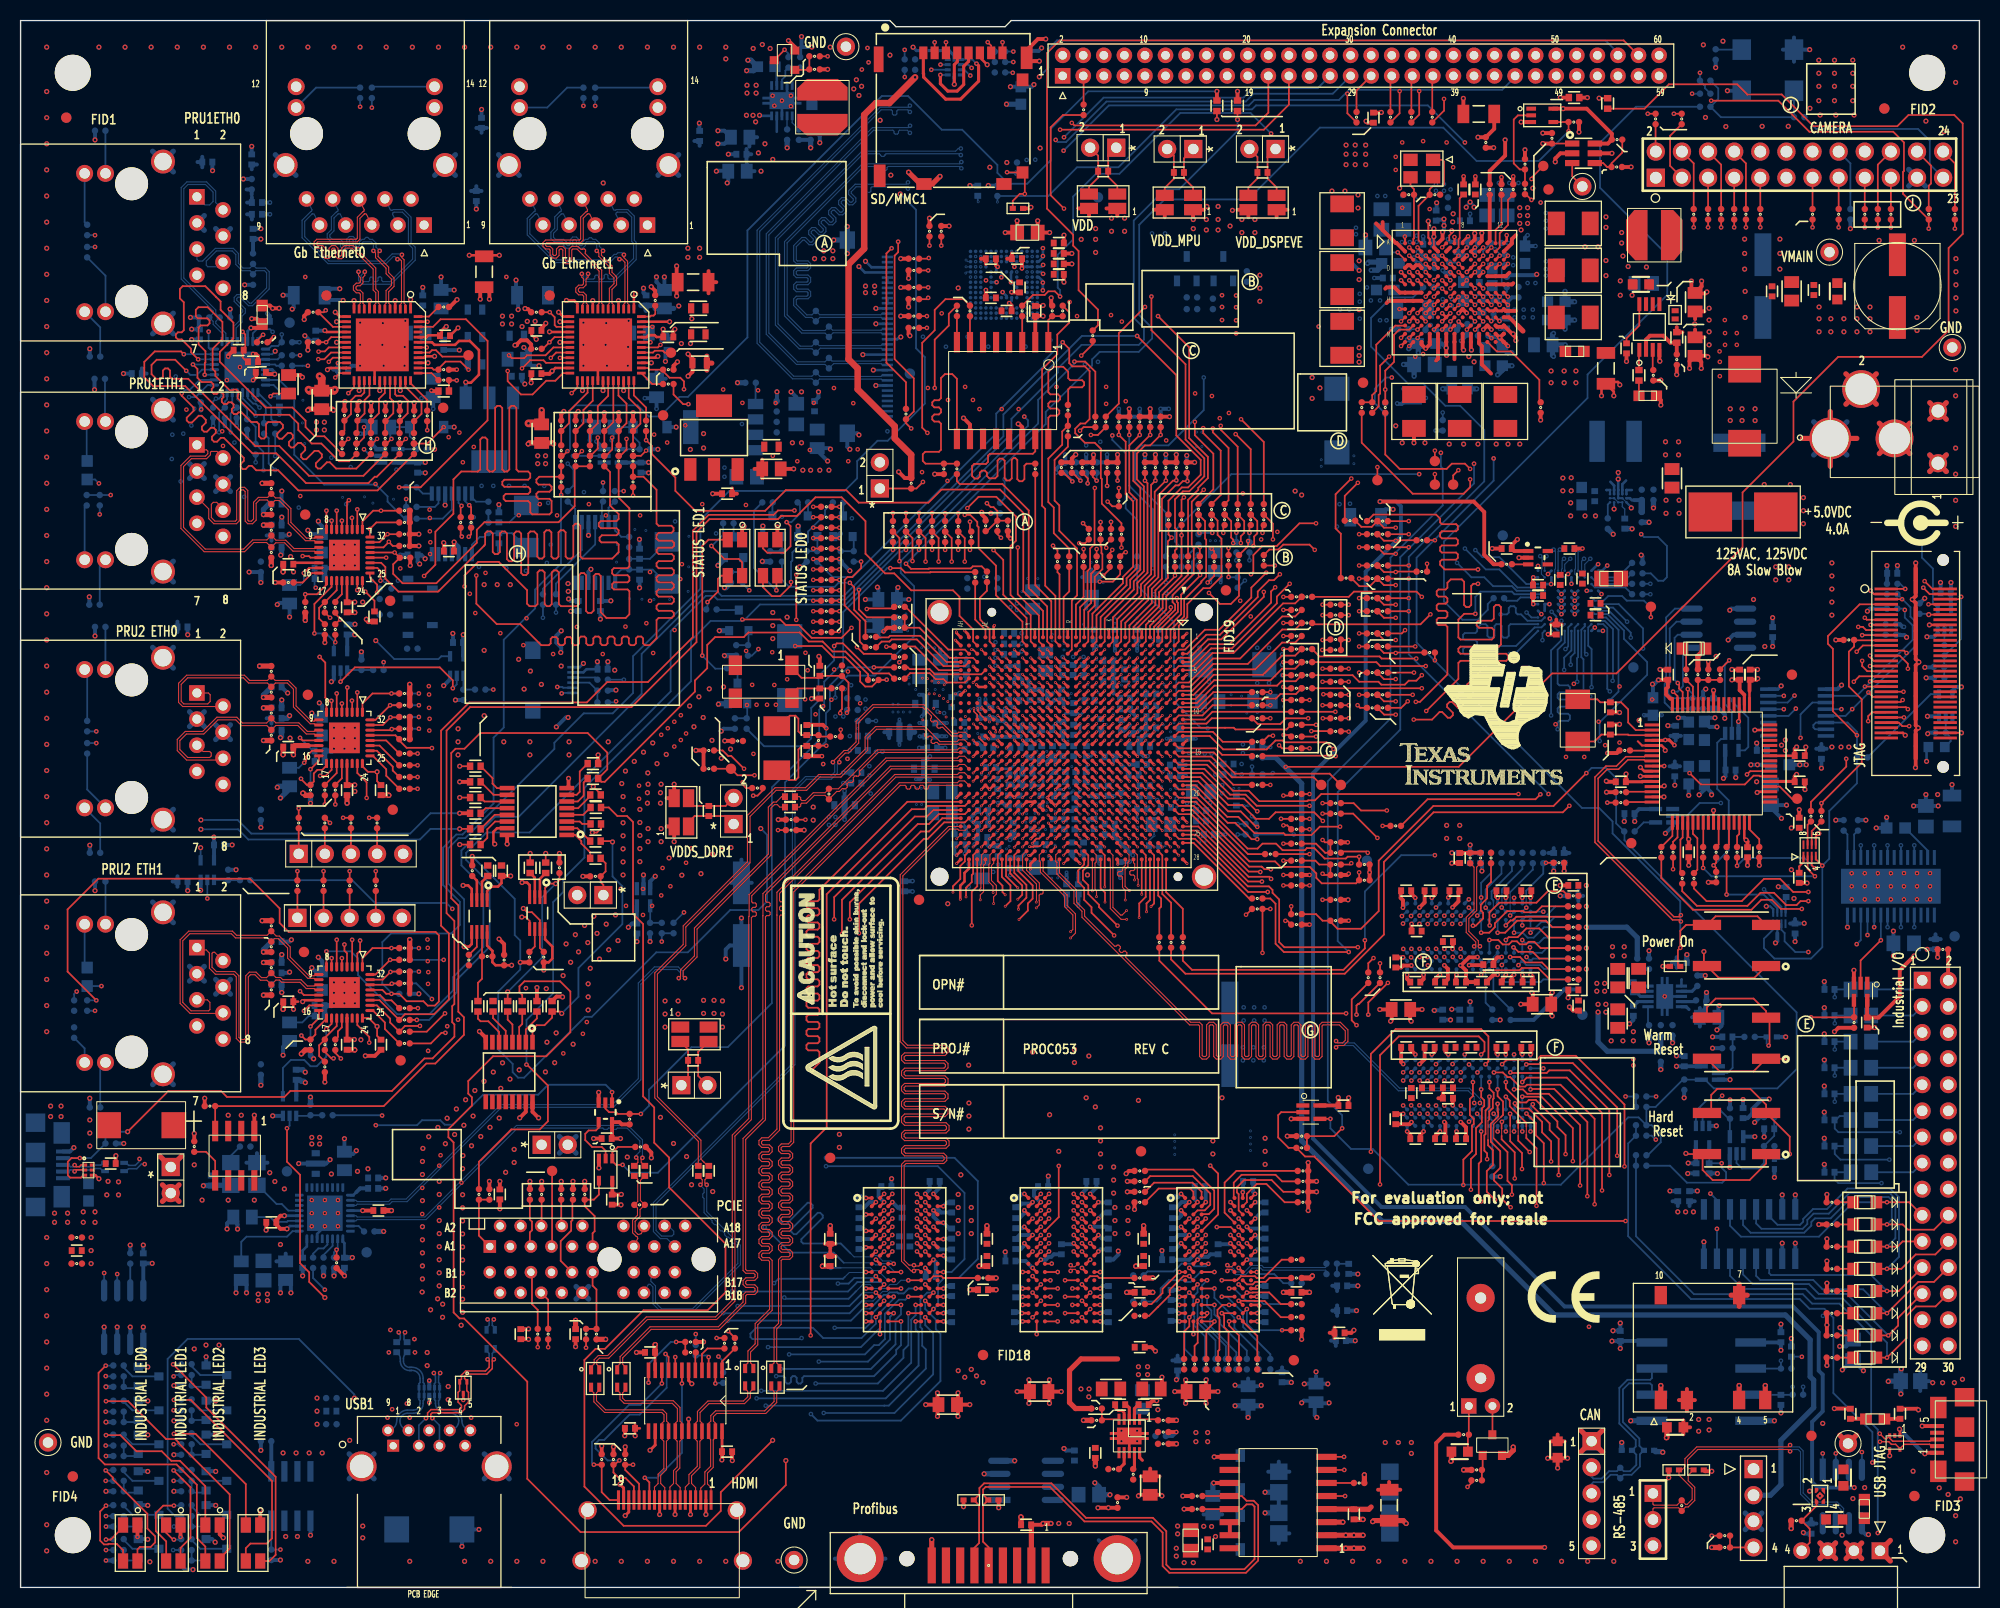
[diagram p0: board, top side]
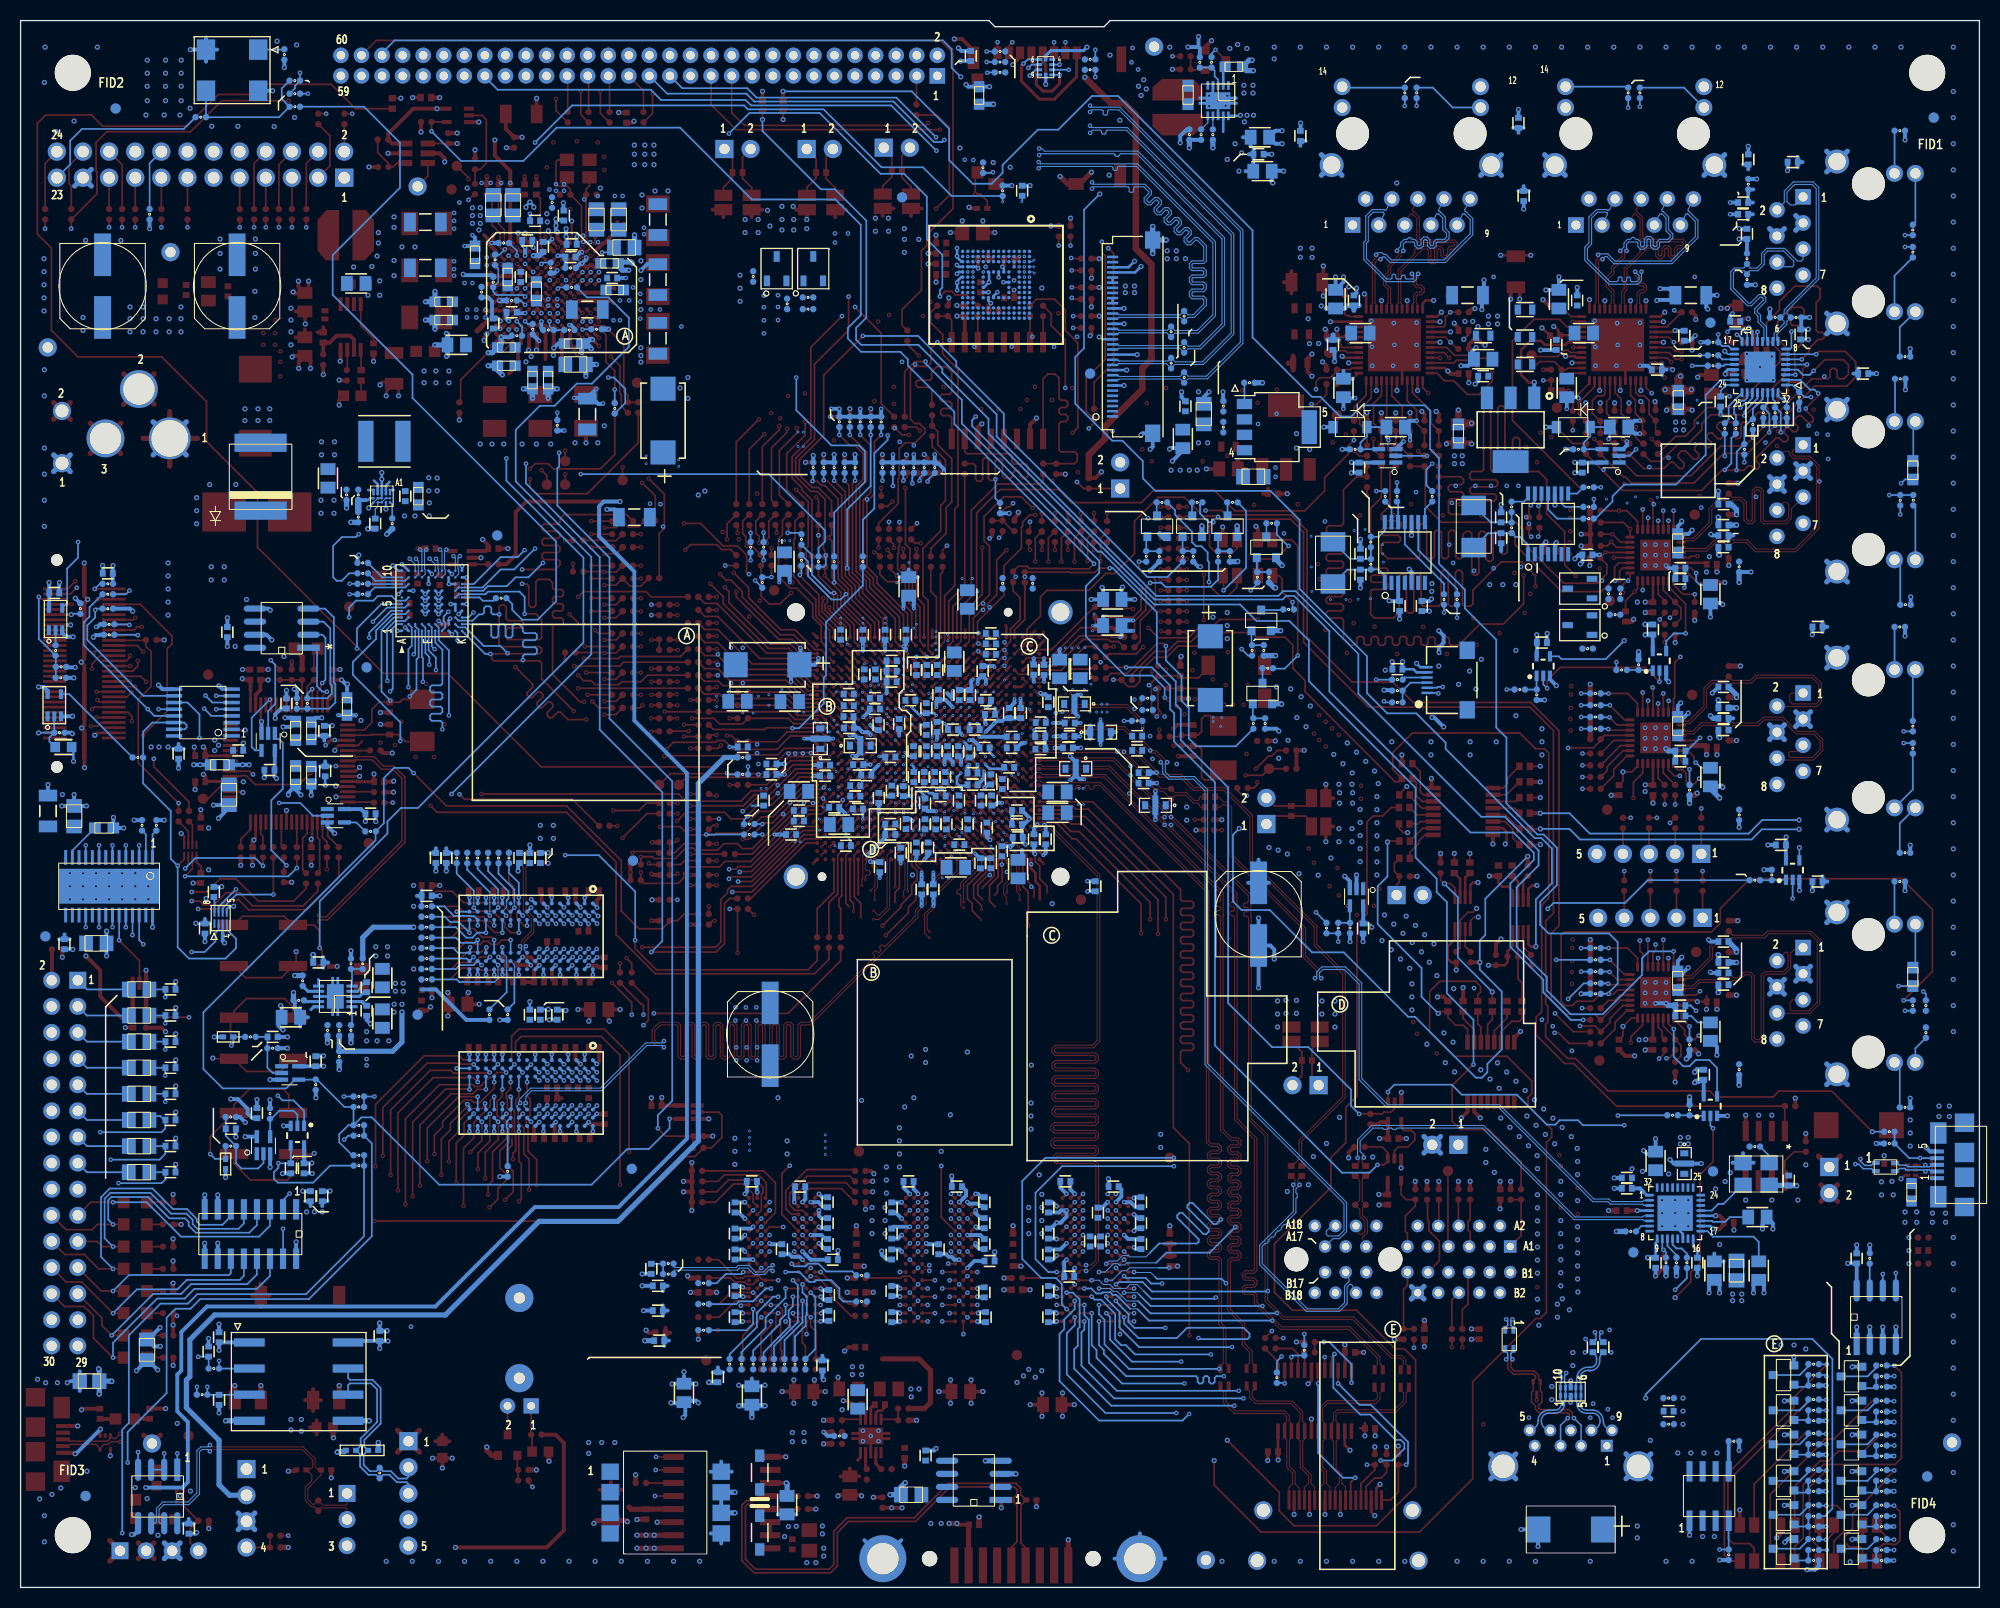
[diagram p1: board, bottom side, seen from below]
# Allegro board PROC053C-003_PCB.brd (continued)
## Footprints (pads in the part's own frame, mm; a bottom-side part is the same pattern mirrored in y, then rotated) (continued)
BGA153N50P14X14_1150X1300X140
  round 0.35 smd: A1(-3.25,3.25) A2(-2.75,3.25) A3(-2.25,3.25) A4(-1.75,3.25) A5(-1.25,3.25) A6(-0.75,3.25) A7(-0.25,3.25) A8(0.25,3.25) A9(0.75,3.25) A10(1.25,3.25) A11(1.75,3.25) A12(2.25,3.25) A13(2.75,3.25) A14(3.25,3.25) B1(-3.25,2.75) B2(-2.75,2.75) B3(-2.25,2.75) B4(-1.75,2.75) B5(-1.25,2.75) B6(-0.75,2.75) B7(-0.25,2.75) B8(0.25,2.75) B9(0.75,2.75) B10(1.25,2.75) B11(1.75,2.75) B12(2.25,2.75) B13(2.75,2.75) B14(3.25,2.75) C1(-3.25,2.25) C2(-2.75,2.25) C3(-2.25,2.25) C4(-1.75,2.25) C5(-1.25,2.25) C6(-0.75,2.25) C7(-0.25,2.25) C8(0.25,2.25) C9(0.75,2.25) C10(1.25,2.25) C11(1.75,2.25) C12(2.25,2.25) C13(2.75,2.25) C14(3.25,2.25) D1(-3.25,1.75) D2(-2.75,1.75) D3(-2.25,1.75) D4(-1.75,1.75) D12(2.25,1.75) D13(2.75,1.75) D14(3.25,1.75) E1(-3.25,1.25) E2(-2.75,1.25) E3(-2.25,1.25) E5(-1.25,1.25) E6(-0.75,1.25) E7(-0.25,1.25) E8(0.25,1.25) E9(0.75,1.25) E10(1.25,1.25) E12(2.25,1.25) E13(2.75,1.25) E14(3.25,1.25) F1(-3.25,0.75) F2(-2.75,0.75) F3(-2.25,0.75) F5(-1.25,0.75) F10(1.25,0.75) F12(2.25,0.75) F13(2.75,0.75) F14(3.25,0.75) G1(-3.25,0.25) G2(-2.75,0.25) G3(-2.25,0.25) G5(-1.25,0.25) G10(1.25,0.25) G12(2.25,0.25) G13(2.75,0.25) G14(3.25,0.25) H1(-3.25,-0.25) H2(-2.75,-0.25) H3(-2.25,-0.25) H5(-1.25,-0.25) H10(1.25,-0.25) H12(2.25,-0.25) H13(2.75,-0.25) H14(3.25,-0.25) J1(-3.25,-0.75) J2(-2.75,-0.75) J3(-2.25,-0.75) J5(-1.25,-0.75) J10(1.25,-0.75) J12(2.25,-0.75) J13(2.75,-0.75) J14(3.25,-0.75) K1(-3.25,-1.25) K2(-2.75,-1.25) K3(-2.25,-1.25) K5(-1.25,-1.25) K6(-0.75,-1.25) K7(-0.25,-1.25) K8(0.25,-1.25) K9(0.75,-1.25) K10(1.25,-1.25) K12(2.25,-1.25) K13(2.75,-1.25) K14(3.25,-1.25) L1(-3.25,-1.75) L2(-2.75,-1.75) L3(-2.25,-1.75) L12(2.25,-1.75) L13(2.75,-1.75) L14(3.25,-1.75) M1(-3.25,-2.25) M2(-2.75,-2.25) M3(-2.25,-2.25) M4(-1.75,-2.25) M5(-1.25,-2.25) M6(-0.75,-2.25) M7(-0.25,-2.25) M8(0.25,-2.25) M9(0.75,-2.25) M10(1.25,-2.25) M11(1.75,-2.25) M12(2.25,-2.25) M13(2.75,-2.25) M14(3.25,-2.25) N1(-3.25,-2.75) N2(-2.75,-2.75) N3(-2.25,-2.75) N4(-1.75,-2.75) N5(-1.25,-2.75) N6(-0.75,-2.75) N7(-0.25,-2.75) N8(0.25,-2.75) N9(0.75,-2.75) N10(1.25,-2.75) N11(1.75,-2.75) N12(2.25,-2.75) N13(2.75,-2.75) N14(3.25,-2.75) P1(-3.25,-3.25) P2(-2.75,-3.25) P3(-2.25,-3.25) P4(-1.75,-3.25) P5(-1.25,-3.25) P6(-0.75,-3.25) P7(-0.25,-3.25) P8(0.25,-3.25) P9(0.75,-3.25) P10(1.25,-3.25) P11(1.75,-3.25) P12(2.25,-3.25) P13(2.75,-3.25) P14(3.25,-3.25)
CC0402
  rect 0.58x0.66 smd: 1(-0.49,0) 2(0.49,0)
CC0603
  rect 0.95x1 smd: 1(-0.8,0) 2(0.8,0)
CC0805
  rect 1.15x1.45 smd: 1(-0.9,0) 2(0.9,0)
CC1206
  rect 1.15x1.8 smd: 1(-1.5,0) 2(1.5,0)
CN_10018783-11000TLF
  round 2.35 hole 2.35 unplated: (11.65,-1.25) (20.8,-1.25)
  rect 1.228x1.228 hole 0.72: A1(0,0)
  round 1.228 hole 0.72: A2(1,2) A3(2,0) A4(3,2) A5(4,0) A6(5,2) A7(6,0) A8(7,2) A9(8,0) A10(9,2) A11(10,0) A12(13,2) A13(14,0) A14(15,2) A15(16,0) A16(17,2) A17(18,0) A18(19,2) B1(0,-2.5) B2(1,-4.5) B3(2,-2.5) B4(3,-4.5) B5(4,-2.5) B6(5,-4.5) B7(6,-2.5) B8(7,-4.5) B9(8,-2.5) B10(9,-4.5) B11(10,-2.5) B12(13,-4.5) B13(14,-2.5) B14(15,-4.5) B15(16,-2.5) B16(17,-4.5) B17(18,-2.5) B18(19,-4.5)
CN_LPAF3102NL
  rect 1.168x1.168 hole 0.711: 1(0,0)
  round 1.168 hole 0.711: 2(2.5,0) 3(4.5,0) 4(7,0) 5(7.5,1.5) 6(5.5,1.5) 7(3.5,1.5) 8(1.5,1.5) 9(-0.5,1.5)
  round 2.921 hole 2.286: S1(-3.07,-2) S2(10.07,-2)
CNQSH030DA
  round 1.143 hole 1.143 unplated: (-10.065,2.67) (10.065,2.67)
  rect 0.279x2.286 smd: 1(-7.25,-2.865) 2(-7.25,2.865) 3(-6.75,-2.865) 4(-6.75,2.865) 5(-6.25,-2.865) 6(-6.25,2.865) 7(-5.75,-2.865) 8(-5.75,2.865) 9(-5.25,-2.865) 10(-5.25,2.865) 11(-4.75,-2.865) 12(-4.75,2.865) 13(-4.25,-2.865) 14(-4.25,2.865) 15(-3.75,-2.865) 16(-3.75,2.865) 17(-3.25,-2.865) 18(-3.25,2.865) 19(-2.75,-2.865) 20(-2.75,2.865) 21(-2.25,-2.865) 22(-2.25,2.865) 23(-1.75,-2.865) 24(-1.75,2.865) 25(-1.25,-2.865) 26(-1.25,2.865) 27(-0.75,-2.865) 28(-0.75,2.865) 29(-0.25,-2.865) 30(-0.25,2.865) 31(0.25,-2.865) 32(0.25,2.865) 33(0.75,-2.865) 34(0.75,2.865) 35(1.25,-2.865) 36(1.25,2.865) 37(1.75,-2.865) 38(1.75,2.865) 39(2.25,-2.865) 40(2.25,2.865) 41(2.75,-2.865) 42(2.75,2.865) 43(3.25,-2.865) 44(3.25,2.865) 45(3.75,-2.865) 46(3.75,2.865) 47(4.25,-2.865) 48(4.25,2.865) 49(4.75,-2.865) 50(4.75,2.865) 51(5.25,-2.865) 52(5.25,2.865) 53(5.75,-2.865) 54(5.75,2.865) 55(6.25,-2.865) 56(6.25,2.865) 57(6.75,-2.865) 58(6.75,2.865) 59(7.25,-2.865) 60(7.25,2.865)
  rect 2.54x0.432 smd: 61(-8.065,0) 64(8.065,0)
  rect 4.699x0.432 smd: 62(-3.175,0) 63(3.175,0)
CNRJ45-1X1WLED
  round 3.2 hole 3.2 unplated: (-1.27,-6.35) (10.16,-6.35)
  rect 1.525x1.525 hole 0.89: 1(0,0)
  round 1.525 hole 0.89: 2(1.27,2.54) 3(2.54,0) 4(3.81,2.54) 5(5.08,0) 6(6.35,2.54) 7(7.62,0) 8(8.89,2.54)
  round 1.655 hole 1.02: 9(11.17,-8.89) 10(11.17,-10.92) 11(-2.28,-8.89) 12(-2.28,-10.92)
  round 2.337 hole 1.702: SHLD1(-3.43,-3.3) SHLD2(12.32,-3.3)
CNRJ45-1X1WLED-598M
  round 3.2 hole 3.2 unplated: (0,-8.89) (11.43,-8.89)
  rect 1.525x1.525 hole 0.89: 1(0,0)
  round 1.525 hole 0.89: 2(1.27,-2.54) 3(2.54,0) 4(3.81,-2.54) 5(5.08,0) 6(6.35,-2.54) 7(7.62,0) 8(8.89,-2.54) 9(10.16,0) 10(11.43,-2.54)
  round 1.655 hole 1.02: 11(12.44,-11.43) 12(12.44,-13.46) 13(-1.01,-11.43) 14(-1.01,-13.46)
  round 2.337 hole 1.702: SHLD1(-2.035,-5.84) SHLD2(13.465,-5.84)
CNXF2M-3215-1A
  rect 0.254x1.092 smd: 1(-7.75,1.95) 2(-7.25,1.95) 3(-6.75,1.95) 4(-6.25,1.95) 5(-5.75,1.95) 6(-5.25,1.95) 7(-4.75,1.95) 8(-4.25,1.95) 9(-3.75,1.95) 10(-3.25,1.95) 11(-2.75,1.95) 12(-2.25,1.95) 13(-1.75,1.95) 14(-1.25,1.95) 15(-0.75,1.95) 16(-0.25,1.95) 17(0.25,1.95) 18(0.75,1.95) 19(1.25,1.95) 20(1.75,1.95) 21(2.25,1.95) 22(2.75,1.95) 23(3.25,1.95) 24(3.75,1.95) 25(4.25,1.95) 26(4.75,1.95) 27(5.25,1.95) 28(5.75,1.95) 29(6.25,1.95) 30(6.75,1.95) 31(7.25,1.95) 32(7.75,1.95)
  rect 1.7x1.5 smd: MNT1(-9.4,-1.95) MNT2(9.4,-1.95)
CONN_OSTTC02
  round 1.778 hole 1.27: 1(0,0) 2(5.08,0)
CT7343-31
  rect 2.35x2.45 smd: 1(-3.1,0) 2(3.1,0)
DA2304
  rect 1.7x1.6 smd: 1(-5.4,3) 2(-5.4,1) 3(-5.4,-1) 4(-5.4,-3) 5(5.4,-3) 6(5.4,-1) 7(5.4,1) 8(5.4,3)
DFN1006D-2
  rect 0.5x0.7 smd: 1(-0.4,0) 2(0.4,0)
DIO_SOD-123
  rect 1.22x0.91 smd: 1(-1.64,0) 2(1.64,0)
DRCPSO_10PIN
  rect 0.305x1.092 smd: 1(-1,-1.625) 2(-0.5,-1.625) 3(0,-1.625) 4(0.5,-1.625) 5(1,-1.625) 6(1,1.625) 7(0.5,1.625) 8(0,1.625) 9(-0.5,1.625) 10(-1,1.625)
  custom 0.412x0.412 smd: 11(0,0)
FB0603
  rect 0.61x0.991 smd: 1(-0.7,0) 2(0.7,0)
FILT-DLW21S
  rect 0.9x0.4 smd: 1(-0.85,-0.4) 2(0.85,-0.4) 3(0.85,0.4) 4(-0.85,0.4)
FILT-NFM21PC
  rect 0.6x0.8 smd: 1(-1,0) 3(1,0)
  rect 0.6x1.9 smd: 2(0,0)
FUSE-0154
  rect 4.242x3.81 smd: 1(-3.188,0) 2(3.188,0)
HDR1X4-330M
  rect 1.778x1.778 hole 1.143: 1(0,0)
  round 1.778 hole 1.143: 2(0,-2.54) 3(0,-5.08) 4(0,-7.62)
HDR2X12
  rect 1.785x1.785 hole 1.15: 1(0,0)
  round 1.785 hole 1.15: 2(2.54,0) 3(0,-2.54) 4(2.54,-2.54) 5(0,-5.08) 6(2.54,-5.08) 7(0,-7.62) 8(2.54,-7.62) 9(0,-10.16) 10(2.54,-10.16) 11(0,-12.7) 12(2.54,-12.7) 13(0,-15.24) 14(2.54,-15.24) 15(0,-17.78) 16(2.54,-17.78) 17(0,-20.32) 18(2.54,-20.32) 19(0,-22.86) 20(2.54,-22.86) 21(0,-25.4) 22(2.54,-25.4) 23(0,-27.94) 24(2.54,-27.94)
HDR2X15-344M
  rect 1.655x1.655 hole 1.02: 1(0,0)
  round 1.655 hole 1.02: 2(0,2.54) 3(2.54,0) 4(2.54,2.54) 5(5.08,0) 6(5.08,2.54) 7(7.62,0) 8(7.62,2.54) 9(10.16,0) 10(10.16,2.54) 11(12.7,0) 12(12.7,2.54) 13(15.24,0) 14(15.24,2.54) 15(17.78,0) 16(17.78,2.54) 17(20.32,0) 18(20.32,2.54) 19(22.86,0) 20(22.86,2.54) 21(25.4,0) 22(25.4,2.54) 23(27.94,0) 24(27.94,2.54) 25(30.48,0) 26(30.48,2.54) 27(33.02,0) 28(33.02,2.54) 29(35.56,0) 30(35.56,2.54)
HDR2X30-2MM-177M
  rect 1.524x1.524 hole 0.838: 1(0,0)
  round 1.524 hole 0.838: 2(0,2) 3(2,0) 4(2,2) 5(4,0) 6(4,2) 7(6,0) 8(6,2) 9(8,0) 10(8,2) 11(10,0) 12(10,2) 13(12,0) 14(12,2) 15(14,0) 16(14,2) 17(16,0) 18(16,2) 19(18,0) 20(18,2) 21(20,0) 22(20,2) 23(22,0) 24(22,2) 25(24,0) 26(24,2) 27(26,0) 28(26,2) 29(28,0) 30(28,2) 31(30,0) 32(30,2) 33(32,0) 34(32,2) 35(34,0) 36(34,2) 37(36,0) 38(36,2) 39(38,0) 40(38,2) 41(40,0) 42(40,2) 43(42,0) 44(42,2) 45(44,0) 46(44,2) 47(46,0) 48(46,2) 49(48,0) 50(48,2) 51(50,0) 52(50,2) 53(52,0) 54(52,2) 55(54,0) 56(54,2) 57(56,0) 58(56,2) 59(58,0) 60(58,2)
HDR4X1RA-108M
  rect 1.651x1.651 hole 1.016: 1(0,0)
  round 1.651 hole 1.016: 2(0,-2.54) 3(0,-5.08) 4(0,-7.62)
HEADER_2X1
  rect 1.778x1.778 hole 1.016: 1(0,0)
  round 1.778 hole 1.016: 2(0,2.54)
HEADER_3X1
  rect 1.651x1.651 hole 1.016: 1(0,0)
  round 1.651 hole 1.016: 2(2.54,0) 3(5.08,0)
HEADER_5X1
  rect 1.778x1.778 hole 1.016: 1(0,0)
  round 1.778 hole 1.016: 2(2.54,0) 3(5.08,0) 4(7.62,0) 5(10.16,0)
IND_IHLP1616AB
  rect 1.65x2.3 smd: 1(-1.65,0) 2(1.65,0)
IND_SRN5040
  rect 1.5x4 smd: 1(-1.8,0) 2(1.8,0)
LED-SM1210
  rect 1.5x1 smd: 1(-1.75,0.7) 2(-1.75,-0.7) 3(1.75,0.7) 4(1.75,-0.7)
LQFP64PIN
  rect 1.5x0.3 smd: 1(-5.7,3.75) 2(-5.7,3.25) 3(-5.7,2.75) 4(-5.7,2.25) 5(-5.7,1.75) 6(-5.7,1.25) 7(-5.7,0.75) 8(-5.7,0.25) 9(-5.7,-0.25) 10(-5.7,-0.75) 11(-5.7,-1.25) 12(-5.7,-1.75) 13(-5.7,-2.25) 14(-5.7,-2.75) 15(-5.7,-3.25) 16(-5.7,-3.75) 33(5.7,-3.75) 34(5.7,-3.25) 35(5.7,-2.75) 36(5.7,-2.25) 37(5.7,-1.75) 38(5.7,-1.25) 39(5.7,-0.75) 40(5.7,-0.25) 41(5.7,0.25) 42(5.7,0.75) 43(5.7,1.25) 44(5.7,1.75) 45(5.7,2.25) 46(5.7,2.75) 47(5.7,3.25) 48(5.7,3.75)
  rect 0.3x1.5 smd: 17(-3.75,-5.7) 18(-3.25,-5.7) 19(-2.75,-5.7) 20(-2.25,-5.7) 21(-1.75,-5.7) 22(-1.25,-5.7) 23(-0.75,-5.7) 24(-0.25,-5.7) 25(0.25,-5.7) 26(0.75,-5.7) 27(1.25,-5.7) 28(1.75,-5.7) 29(2.25,-5.7) 30(2.75,-5.7) 31(3.25,-5.7) 32(3.75,-5.7) 49(3.75,5.7) 50(3.25,5.7) 51(2.75,5.7) 52(2.25,5.7) 53(1.75,5.7) 54(1.25,5.7) 55(0.75,5.7) 56(0.25,5.7) 57(-0.25,5.7) 58(-0.75,5.7) 59(-1.25,5.7) 60(-1.75,5.7) 61(-2.25,5.7) 62(-2.75,5.7) 63(-3.25,5.7) 64(-3.75,5.7)
MC-306
  rect 1.3x1.9 smd: 1(-2.75,-1.6) 2(2.75,-1.6) 3(2.75,1.6) 4(-2.75,1.6)
MOLEX_5031821852
  rect 0.8x1.24 smd: 1(-2.9,5.605) 2(-1.8,5.605) 3(-0.7,5.605) 4(0.4,5.605) 5(1.5,5.605) 6(2.6,5.605) 7(3.7,5.605) 8(4.8,5.605)
  rect 1.16x1.2 smd: DT(6.75,-6.025)
  rect 0.95x2.5 smd: G1(-7.245,4.975)
  rect 1.15x2.2 smd: G2(-7.145,-6.355) G5(7.145,5.125)
  rect 1.5x1.15 smd: G3(-2.84,-7.15) G4(4.94,-7.15)
  rect 1.16x1.25 smd: SW(6.75,2.975)
MSOP3X3-8-43M
  rect 1.35x0.4 smd: 1(-2.225,0.975) 2(-2.225,0.325) 3(-2.225,-0.325) 4(-2.225,-0.975) 5(2.225,-0.975) 6(2.225,-0.325) 7(2.225,0.325) 8(2.225,0.975)
NORCOMP_DB9F_SMD
  round 1.499 hole 1.499 unplated: (-7.95,-0.66) (7.95,-0.66)
  rect 0.8x3.5 smd: 1(-5.537,0) 2(-2.769,0) 3(0,0) 4(2.769,0) 5(5.537,0) 6(-4.153,0) 7(-1.384,0) 8(1.384,0) 9(4.153,0)
  round 4.572 hole 3.048: 10(-12.497,-0.66) 11(12.497,-0.66)
OMRON_XF2M-0615-1A
  rect 0.25x1.1 smd: 1(-1.25,1.84) 2(-0.75,1.84) 3(-0.25,1.84) 4(0.25,1.84) 5(0.75,1.84) 6(1.25,1.84)
  rect 1.7x1.5 smd: G1(-2.9,-2.059) G2(2.9,-2.059)
OSC7X5-71M
  rect 1.8x2 smd: 1(-2.54,-2) 2(2.54,-2) 3(2.54,2) 4(-2.54,2)
PICO_304-100
  rect 1.5x1.5 hole 0.762: 1(0,0)
  round 1.5 hole 0.762: 2(-2.3,0)
  round 2.75 hole 1.092: M1(-1.15,-2.7) M2(-1.15,-10.5)
PW_24PIN_TSSOP
  rect 0.356x1.524 smd: 1(-3.575,-2.96) 2(-2.925,-2.96) 3(-2.275,-2.96) 4(-1.625,-2.96) 5(-0.975,-2.96) 6(-0.325,-2.96) 7(0.325,-2.96) 8(0.975,-2.96) 9(1.625,-2.96) 10(2.275,-2.96) 11(2.925,-2.96) 12(3.575,-2.96) 13(3.575,2.96) 14(2.925,2.96) 15(2.275,2.96) 16(1.625,2.96) 17(0.975,2.96) 18(0.325,2.96) 19(-0.325,2.96) 20(-0.975,2.96) 21(-1.625,2.96) 22(-2.275,2.96) 23(-2.925,2.96) 24(-3.575,2.96)
QFN5X5-32-39M
  custom 0.075x0.075 smd: 1(-2.475,1.75) 2(-2.475,1.25) 3(-2.475,0.75) 4(-2.475,0.25) 5(-2.475,-0.25) 6(-2.475,-0.75) 7(-2.475,-1.25) 8(-2.475,-1.75) 9(-1.75,-2.475) 10(-1.25,-2.475) 11(-0.75,-2.475) 12(-0.25,-2.475) 13(0.25,-2.475) 14(0.75,-2.475) 15(1.25,-2.475) 16(1.75,-2.475) 17(2.475,-1.75) 18(2.475,-1.25) 19(2.475,-0.75) 20(2.475,-0.25) 21(2.475,0.25) 22(2.475,0.75) 23(2.475,1.25) 24(2.475,1.75) 25(1.75,2.475) 26(1.25,2.475) 27(0.75,2.475) 28(0.25,2.475) 29(-0.25,2.475) 30(-0.75,2.475) 31(-1.25,2.475) 32(-1.75,2.475)
  rect 3x3 smd: TPAD(0,0)
QFN5X5-32TI-39M
  custom 0.07x0.07 smd: 1(-2.475,1.75) 2(-2.475,1.25) 3(-2.475,0.75) 4(-2.475,0.25) 5(-2.475,-0.25) 6(-2.475,-0.75) 7(-2.475,-1.25) 8(-2.475,-1.75) 9(-1.75,-2.475) 10(-1.25,-2.475) 11(-0.75,-2.475) 12(-0.25,-2.475) 13(0.25,-2.475) 14(0.75,-2.475) 15(1.25,-2.475) 16(1.75,-2.475) 17(2.475,-1.75) 18(2.475,-1.25) 19(2.475,-0.75) 20(2.475,-0.25) 21(2.475,0.25) 22(2.475,0.75) 23(2.475,1.25) 24(2.475,1.75) 25(1.75,2.475) 26(1.25,2.475) 27(0.75,2.475) 28(0.25,2.475) 29(-0.25,2.475) 30(-0.75,2.475) 31(-1.25,2.475) 32(-1.75,2.475)
  rect 3.45x3.45 smd: TPAD(0,0)
QFN7X7-48
  rect 0.85x0.28 smd: 1(-3.475,2.75) 2(-3.475,2.25) 3(-3.475,1.75) 4(-3.475,1.25) 5(-3.475,0.75) 6(-3.475,0.25) 7(-3.475,-0.25) 8(-3.475,-0.75) 9(-3.475,-1.25) 10(-3.475,-1.75) 11(-3.475,-2.25) 12(-3.475,-2.75) 25(3.475,-2.75) 26(3.475,-2.25) 27(3.475,-1.75) 28(3.475,-1.25) 29(3.475,-0.75) 30(3.475,-0.25) 31(3.475,0.25) 32(3.475,0.75) 33(3.475,1.25) 34(3.475,1.75) 35(3.475,2.25) 36(3.475,2.75)
  rect 0.28x0.85 smd: 13(-2.75,-3.475) 14(-2.25,-3.475) 15(-1.75,-3.475) 16(-1.25,-3.475) 17(-0.75,-3.475) 18(-0.25,-3.475) 19(0.25,-3.475) 20(0.75,-3.475) 21(1.25,-3.475) 22(1.75,-3.475) 23(2.25,-3.475) 24(2.75,-3.475) 37(2.75,3.475) 38(2.25,3.475) 39(1.75,3.475) 40(1.25,3.475) 41(0.75,3.475) 42(0.25,3.475) 43(-0.25,3.475) 44(-0.75,3.475) 45(-1.25,3.475) 46(-1.75,3.475) 47(-2.25,3.475) 48(-2.75,3.475)
  rect 5.15x5.15 smd: 49(0,0)
RAPC712
  round 4.064 hole 3.556: 1(0,0)
  round 3.683 hole 3.048: 2(-2.997,-4.801) 3(-6.248,0)
RC0402
  rect 0.63x0.73 smd: 1(-0.51,0) 2(0.51,0)
SC70-5-43M
  rect 0.95x0.4 smd: 1(-1.075,0.65) 2(-1.075,0) 3(-1.075,-0.65) 4(1.075,-0.65) 5(1.075,0.65)
SCK-SG-BGA-6334
  round 1.75 hole 1.75 unplated: (-12.863,12.863) (12.863,-12.863)
  round 0.85 hole 0.85 unplated: (-12.863,-7.783) (12.863,10.323)
  round 2.385 hole 1.75: MCH2(12.863,12.863) MCH4(-12.863,-12.863)
SK1545
  rect 1.778x5.08 smd: 1(-3.302,0) 2(3.302,0)
SM-7351-CAP-0402
  round 0.635 smd: 1(-0.508,0) 2(0.508,0)
SM-7351-CAP-0603
  rect 1.092x1.041 smd: 1(-0.85,0) 2(0.85,0)
SM-7351-CAP-0805
  rect 1.346x1.524 smd: 1(-1,0) 2(1,0)
SM-7351-CAP-2917
  rect 2.413x2.54 smd: 1(3.175,0) 2(-3.175,0)
SM-7351-CAP-SMDCAN
  rect 4.15x1.65 smd: 1(3.05,0) 2(-3.05,0)
SM-7351-IND-0603
  rect 1.143x1.092 smd: 1(-0.9,0) 2(0.9,0)
SM-7351-IND-0805
  rect 1.397x1.549 smd: 1(-0.95,0) 2(0.95,0)
SM-7351-RES-0402
  round 0.635 smd: 1(-0.508,0) 2(0.508,0)
SM-7351-RES-0603
  rect 1.143x1.092 smd: 1(-0.9,0) 2(0.9,0)
SM-SO-SC70-5
  rect 0.406x1.016 smd: 1(-0.65,-0.95) 2(0,-0.95) 3(0.65,-0.95) 4(0.65,0.95) 5(-0.65,0.95)
SM_LED_0805
  rect 1.15x1.194 smd: 1(1.125,0) 2(-1.125,0)
SM_OSC_ABM3
  rect 1.9x2.4 smd: 1(-2.05,0) 2(2.05,0)
SM_RES_LVK12
  rect 1.75x1.1 smd: 1(-1.375,0.7) 2(1.375,0.7) 3(-1.375,-0.7) 4(1.375,-0.7)
SMCJ26CA
  rect 2.6x3.2 smd: 1(-3.6,0) 2(3.6,0)
SMD15X11-6-374M
  rect 1.2x1.8 smd: 1(-5.08,-5.1) 2(-2.54,-5.1) 4(2.54,-5.1) 5(5.08,-5.1) 7(2.54,5.1) 10(-5.08,5.1)
SMD_HDMIA_RA
  rect 0.3x1.9 smd: 1(4.75,4.925) 2(4.25,4.925) 3(3.75,4.925) 4(3.25,4.925) 5(2.75,4.925) 6(2.25,4.925) 7(1.75,4.925) 8(1.25,4.925) 9(0.75,4.925) 10(0.25,4.925) 11(-0.25,4.925) 12(-0.75,4.925) 13(-1.25,4.925) 14(-1.75,4.925) 15(-2.25,4.925) 16(-2.75,4.925) 17(-3.25,4.925) 18(-3.75,4.925) 19(-4.25,4.925)
  round 1.778 hole 1.27: MTG1(-7.25,3.925) MTG2(7.25,3.925) MTG3(-7.85,-0.975) MTG4(7.85,-0.975)
SMDSC70-5
  rect 0.406x1.016 smd: 1(-0.65,-0.95) 2(0,-0.95) 3(0.65,-0.95) 4(0.65,0.95) 5(-0.65,0.95)
SO9X6-8-191M
  rect 0.813x2.997 smd: 1(-3.81,-4.8) 2(-1.27,-4.8) 3(1.27,-4.8) 4(3.81,-4.8) 5(3.81,4.8) 6(1.27,4.8) 7(-1.27,4.8) 8(-3.81,4.8)
SOD-123
  rect 0.914x1.219 smd: 1(1.651,0) 2(-1.651,0)
SOIC_8
  rect 0.61x2.184 smd: 1(-1.905,-2.603)
  oval 0.61x2.184 smd: 2(-0.635,-2.603) 3(0.635,-2.603) 4(1.905,-2.603) 5(1.905,2.603) 6(0.635,2.603) 7(-0.635,2.603) 8(-1.905,2.603)
SOIC_16PIN_DW
  rect 0.6x2 smd: 1(-4.445,-4.7) 2(-3.175,-4.7) 3(-1.905,-4.7) 4(-0.635,-4.7) 5(0.635,-4.7) 6(1.905,-4.7) 7(3.175,-4.7) 8(4.445,-4.7) 9(4.445,4.7) 10(3.175,4.7) 11(1.905,4.7) 12(0.635,4.7) 13(-0.635,4.7) 14(-1.905,4.7) 15(-3.175,4.7) 16(-4.445,4.7)
SON2X1-8-16M
  rect 0.85x0.2 smd: 1(-0.55,0.6) 2(-0.55,0.2) 3(-0.55,-0.2) 4(-0.55,-0.6) 5(0.55,-0.6) 6(0.55,-0.2) 7(0.55,0.2) 8(0.55,0.6)
SOP50P310X90-8
  rect 1.346x0.305 smd: 1(-1.55,0.75) 2(-1.55,0.25) 3(-1.55,-0.25) 4(-1.55,-0.75) 5(1.55,-0.75) 6(1.55,-0.25) 7(1.55,0.25) 8(1.55,0.75)
SOP65P640X120-16N
  rect 1.45x0.45 smd: 1(-2.9,2.275) 2(-2.9,1.625) 3(-2.9,0.975) 4(-2.9,0.325) 5(-2.9,-0.325) 6(-2.9,-0.975) 7(-2.9,-1.625) 8(-2.9,-2.275) 9(2.9,-2.275) 10(2.9,-1.625) 11(2.9,-0.975) 12(2.9,-0.325) 13(2.9,0.325) 14(2.9,0.975) 15(2.9,1.625) 16(2.9,2.275)
SOT1X1-3-20M
  rect 0.55x0.3 smd: 1(-0.575,0.35) 2(-0.575,-0.35) 3(0.575,0)
SOT23-3
  rect 0.787x0.889 smd: D(0,1.003) G(-0.94,-1.003) S(0.94,-1.003)
SOT23-3-44M
  rect 0.6x1.05 smd: 1(-0.95,-1.185) 2(0.95,-1.185) 3(0,1.185)
SOT223
  rect 1.194x2.21 smd: 1(-2.3,-3.1) 2(0,-3.1) 3(2.3,-3.1)
  rect 3.505x2.21 smd: 4(0,3.1)
SOT-23-6
  rect 1.4x0.6 smd: 1(-1.1,0.95) 2(-1.1,0) 3(-1.1,-0.95) 4(1.1,-0.95) 5(1.1,0) 6(1.1,0.95)
SOT-223-5
  rect 1.5x1 smd: 1(-3.15,2.25) 2(-3.15,0.75) 3(-3.15,-0.75) 4(-3.15,-2.25)
  rect 1.5x3.3 smd: 5(3.15,0)
SW_B3SL-1022P
  rect 2.75x1 smd: 1(-2.875,2) 2(2.875,2) 3(-2.875,-2) 4(2.875,-2)
TH_TP_5002
  round 1.778 hole 1.016: 1(0,0)
TP_SMD1MMCIRCLE
  round 1.016 smd: 1(0,0)
TPD1E10B06-2L
  rect 0.6x0.5 smd: 1(-0.5,0) 2(0.5,0)
TSSOP5X4-14-47M
  rect 1.4x0.4 smd: 1(-2.95,1.95) 2(-2.95,1.3) 3(-2.95,0.65) 4(-2.95,0) 5(-2.95,-0.65) 6(-2.95,-1.3) 7(-2.95,-1.95) 8(2.95,-1.95) 9(2.95,-1.3) 10(2.95,-0.65) 11(2.95,0) 12(2.95,0.65) 13(2.95,1.3) 14(2.95,1.95)
U_5_DCK
  rect 0.432x1.27 smd: 1(0.65,0.775) 2(0,0.775) 3(-0.65,0.775) 4(-0.65,-0.884) 5(0.65,-0.884)
U_5_DRL
  rect 0.3x0.45 smd: 1(-0.5,-0.675) 2(0,-0.675) 3(0.5,-0.675) 4(0.5,0.675) 5(-0.5,0.675)
U_6_DRY
  rect 0.305x0.508 smd: 1(-0.5,-0.379) 2(0,-0.379) 3(0.5,-0.379) 4(0.5,0.379) 5(0,0.379) 6(-0.5,0.379)
U_8_D
  rect 0.6x2 smd: 1(-1.905,-2.4) 2(-0.635,-2.4) 3(0.635,-2.4) 4(1.905,-2.4) 5(1.905,2.4) 6(0.635,2.4) 7(-0.635,2.4) 8(-1.905,2.4)
U_10_DRC
  rect 0.28x0.85 smd: 1(-1,-1.475) 2(-0.5,-1.475) 3(0,-1.475) 4(0.5,-1.475) 5(1,-1.475) 6(1,1.475) 7(0.5,1.475) 8(0,1.475) 9(-0.5,1.475) 10(-1,1.475)
  custom 0.412x0.412 smd: PAD(0,0)
U_10_RSE
  rect 0.3x0.58 smd: 1(-0.75,-0.635) 2(-0.25,-0.635) 3(0.25,-0.635) 4(0.75,-0.635) 6(0.75,0.635) 7(0.25,0.635) 8(-0.25,0.635) 9(-0.75,0.635)
  rect 0.63x0.35 smd: 5(0.86,0) 10(-0.86,0)
U_16_D
  rect 0.6x2 smd: 1(-4.445,-2.4) 2(-3.175,-2.4) 3(-1.905,-2.4) 4(-0.635,-2.4) 5(0.635,-2.4) 6(1.905,-2.4) 7(3.175,-2.4) 8(4.445,-2.4) 9(4.445,2.4) 10(3.175,2.4) 11(1.905,2.4) 12(0.635,2.4) 13(-0.635,2.4) 14(-1.905,2.4) 15(-3.175,2.4) 16(-4.445,2.4)
U_16_DW
  rect 0.6x2 smd: 1(-4.445,-4.7) 2(-3.175,-4.7) 3(-1.905,-4.7) 4(-0.635,-4.7) 5(0.635,-4.7) 6(1.905,-4.7) 7(3.175,-4.7) 8(4.445,-4.7) 9(4.445,4.7) 10(3.175,4.7) 11(1.905,4.7) 12(0.635,4.7) 13(-0.635,4.7) 14(-1.905,4.7) 15(-3.175,4.7) 16(-4.445,4.7)
U_16_PW
  rect 0.35x1.6 smd: 1(-2.275,-2.8) 2(-1.625,-2.8) 3(-0.975,-2.8) 4(-0.325,-2.8) 5(0.325,-2.8) 6(0.975,-2.8) 7(1.625,-2.8) 8(2.275,-2.8) 9(2.275,2.8) 10(1.625,2.8) 11(0.975,2.8) 12(0.325,2.8) 13(-0.325,2.8) 14(-0.975,2.8) 15(-1.625,2.8) 16(-2.275,2.8)
U_20_DSBGA
  round 0.254 smd: A1(0.6,-0.8) A2(0.2,-0.8) A3(-0.2,-0.8) A4(-0.6,-0.8) B1(0.6,-0.4) B2(0.2,-0.4) B3(-0.2,-0.4) B4(-0.6,-0.4) C1(0.6,0) C2(0.2,0) C3(-0.2,0) C4(-0.6,0) D1(0.6,0.4) D2(0.2,0.4) D3(-0.2,0.4) D4(-0.6,0.4) E1(0.6,0.8) E2(0.2,0.8) E3(-0.2,0.8) E4(-0.6,0.8)
U_28_PWP
  rect 0.3x1.45 smd: 1(-4.225,-2.8) 2(-3.575,-2.8) 3(-2.925,-2.8) 4(-2.275,-2.8) 5(-1.625,-2.8) 6(-0.975,-2.8) 7(-0.325,-2.8) 8(0.325,-2.8) 9(0.975,-2.8) 10(1.625,-2.8) 11(2.275,-2.8) 12(2.925,-2.8) 13(3.575,-2.8) 14(4.225,-2.8) 15(4.225,2.8) 16(3.575,2.8) 17(2.925,2.8) 18(2.275,2.8) 19(1.625,2.8) 20(0.975,2.8) 21(0.325,2.8) 22(-0.325,2.8) 23(-0.975,2.8) 24(-1.625,2.8) 25(-2.275,2.8) 26(-2.925,2.8) 27(-3.575,2.8) 28(-4.225,2.8)
  rect 9.7x3.4 smd: TH_PD(0,0)
unnamed#2
  round 1.016 smd: 1(0,0)
unnamed#3
  round 3.505 hole 3.505 unplated: (0,0)
USON2X1-10-22M
  rect 0.55x0.3 smd: 1(-0.385,1) 2(-0.385,0.5) 4(-0.385,-0.5) 5(-0.385,-1) 6(0.385,-1) 7(0.385,-0.5) 9(0.385,0.5) 10(0.385,1)
  rect 0.55x0.4 smd: 3(-0.385,0) 8(0.385,0)
VLCF5020T
  custom 0.525x0.525 smd: 1(-1.7,0) 2(1.7,0)
X2SON1X1-4-16M
  custom 0.088x0.088 smd: 1(-0.455,0.325) 2(-0.525,-0.325) 3(0.525,-0.325) 4(0.525,0.325)
  rect 0.58x0.58 smd rot 45: TPAD(0,0)
XTAL3225-39M
  rect 1.4x1.2 smd: 1(-1.1,-0.85) 2(1.1,-0.85) 3(1.1,0.85) 4(-1.1,0.85)
XTAL_ABM7
  rect 1.9x2.6 smd: 1(-2.15,0) 2(2.15,0)
ZX62-AB-5PA
  rect 1.9x1.9 smd: (-1.2,-2.675) (1.2,-2.675)
  rect 0.4x1.35 smd: 1(-1.3,0) 2(-0.65,0) 3(0,0) 4(0.65,0) 5(1.3,0)
  rect 2.1x1.6 smd: S1(-3.1,-0.125) S2(3.1,-0.125)
  rect 1.8x1.9 smd: S3(-4.1,-2.675) S4(4.1,-2.675)

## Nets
AGND_GBETH0: C166.2 C167.2 J10.SHLD1 J10.SHLD2
AGND_GBETH1: C187.2 C188.2 J12.SHLD1 J12.SHLD2
AGND_PROFI: J14.10 J14.11 R573.2(P2)
AGNDFRAME_PRU1ETH0: C106.2 J3.SHLD1 J3.SHLD2
AGNDFRAME_PRU1ETH1: C121.2 J5.SHLD1 J5.SHLD2
AGNDFRAME_PRU2ETH0: C131.2 J6.SHLD1 J6.SHLD2
AGNDFRAME_PRU2ETH1: C146.2 J8.SHLD1 J8.SHLD2
DGND: C1_1.2 C2_1.2 C3.2 C4.2 C5.2 C6.2 C7.2 C8.2 C9.2 C10.2 C11.2 C12.2 C13.2 C14.2 C15.2 C16.2 C17.2 C20.2 C21.2 C22.2 C23.2 C24.2(NEG) C25.1 C26.1 C27.1 C28.2 C29.2 C30.2 C31.2 C32.2 C33.2 C34.2 C35.2 C36.2 C37.2 C38.2 C39.2 C40.2 C41.2 C42.2 C43.2 C45.2 C46.2 C48.2 C49.2 C50.2 C51.2 C52.2 C53.2 C54.2 C55.2 C56.2 C57.2 C58.2 C59.2 C60.2 C61.2 C62.2 C63.2 C64.2 C65.2 C66.2 C67.2 C68.2 C69.2 C70.2 C71.2 C72.2 C73.2 C74.2 C75.2 C76.2 C77.2 C78.2 C79.2 C81.2 C82.2 C83.2 C84.2 C86.2 C88.2 C90.2 C91.2 C92.2 C93.2 C94.2 C95.2 C96.2 C97.2 C98.2 C99.2 C100.2 C101.2 C102.2 C103.2 C104.2 C105.2 C106.1 C107.2 C108.2 C109.2 C110.2 C111.2 C112.2 C113.2 C114.2 C115.2 C116.2 C117.2 C118.2 C119.2 C120.2 C121.1 C122.2 C123.2 C124.2 C125.2 C126.2 C127.2 C128.2 C129.2 C130.2 C131.1 C132.2 C133.2 C134.2 C135.2 C136.2 C137.2 C138.2 C139.2 C140.2 C141.2 C142.2 C143.2 C144.2 C145.2 C146.1 C147.2 C148.2 C149.2 C150.2 C151.2 C152.2 C153.2 C154.2 C155.2 C156.2 C157.2 C158.2 C159.2 C160.2 C161.2 C162.2 C163.2 C164.2 C165.2 C166.1 C167.1 C168.2 C169.2 C170.2 C171.2 C172.1 C173.1 C174.2 C175.2 C176.2 C177.2 C178.2 C179.2 C180.2 C181.2 C182.2 C183.2 C184.2 C185.2 C186.2 C187.1 C188.1 C189.2 C190.2 C191.2 C192.2 C193.1 C194.1 C195.2 C196.2 C197.2 C198.2 C199.2 C200.2 C201.2 C202.2 C203.2 C204.2 C205.2 C206.2 C207.2 C208.2 C209.2 C210.2 C211.2 C212.2 C213.2 C214.2 C215.2 C216.2 C217.2 C218.2 C219.2 C220.2 C221.2 C222.2 C223.2 C224.2 C225.2 C226.2 C227.2 C228.1 C229.2 C230.1 C231.1 C232.2 C233.2 C234.1 C235.2 C236.2 C237.1 C238.2 C239.2 C240.1 C241.2 C242.1 C243.2 C244.2 C245.2 C246.2 C247.2 C248.2 C249.2 C251.2 C253.2 C254.2 C255.2 C256.2 C257.2 C258.2 C261.2 C262.2 C263.2 C264.2 C265.2 C266.2 C267.2 C268.2 C269.2 C270.2 C271.2 C272.2 C273.2 C274.2 C275.2 C276.2 C277.2 C278.2 C279.2 C280.2 C281.2 C282.2 C283.2 C284.2 C285.2 C286.2 C287.2 C288.2 C289.2 C290.2 C291.2 C292.2 C293.2 C294.2 C295.2 C296.2 C297.2 C298.2 C299.2 C300.2 C301.2 C302.2 C303.2 C304.2 C305.2 C306.2 C307.2 C308.2 C309.2 C310.2 C311.2 C313.2 C315.2 C316.2 C317.2 C318.2 C319.2 C320.2 C321.2 C322.2 C324.2 C326.2 C327.2 C328.2 C329.2 C330.2 C331.2 C332.2 C333.2 C334.2 C335.2 C336.2 C337.2 C338.2 C339.2 C340.2 C341.2 C342.2 C343.2 C344.2 C345.2 C346.2 C347.2 C348.2 C349.2 C350.2 C351.2 C352.2 C353.2 C354.2 C355.2 C356.2 C357.2 C358.2 C359.2 C360.2 C361.2 C362.2 C363.2 C364.2 C365.2 C367.2 C368.2 C369.2 C370.2 C371.2 C372.2 C373.2 C374.2 C375.2 C376.2 C377.2 C378.2 C379.2 C380.2 C381.2 C382.2 C383.2 C384.2 C385.2 C386.2 C387.2 C388.2 C389.2 C390.2 C391.2 C392.2 C393.2 C394.2 C395.2 C396.2 C399.2 C400.2 C401.2 C402.2 C403.2 C404.2 C405.2 C406.2 C407.2 C408.2 C409.2 C410.2 C411.2(NEG) C412.2(NEG) C413.2 C414.2 C415.2 C416.2 C417.2 C418.2 C419.2 C420.2 C421.2 C422.2 C423.2 C424.2 C425.2 C426.2 C427.2 C428.2 C429.2 C432.2 C435.2 C440.2(NEG) C441.2(NEG) C442.2 C443.2 C444.2 C445.2 C446.2 C447.2 C448.2 C449.2 C450.2 C451.2 C452.2 C453.2 C458.2 C459.2 C460.2 C461.2 C462.2 C463.2 C464.2 C465.2 C466.1 C467.1 C468.2 C469.2 C470.2 C471.2 C472.2 C473.2 C474.2 C475.2 C476.2 C479.2 C480.2 C481.2 C482.2 C483.2 C484.2 C485.2 C486.2 C487.2 C488.2 C489.2 C490.2 C491.2 C492.2 C493.2 C494.2 C495.2 C496.2 C497.2 C498.2 C499.2 C500.2 C501.2 C502.2 C504.2 C505.2 C506.2 C507.2 C508.2 C509.2 C510.2 C511.2 C512.2 C513.2 C514.2 C515.2 C516.2 C517.2 C518.2 C519.2 C520.2 C522.2 C523.2 C524.2 C525.2 C527.2 C528.2 C530.2 C531.2 C532.2 C533.2 C534.2 C535.2 C536.2 C537.2 C540.2 C541.2 C542.2 C543.2 C544.2 C545.2 C546.2 C547.2 C548.2 C550.2 C551.2 C552.2 C553.2 C556.2 C557.1 C558.1 C559.1 C560.1 C562.2 C563.2 C564.2 C565.2 C566.2 C567.2 C568.2 C569.2 C570.2 C571.2 C572.2 C573.2 C574.2 C575.2 C576.2 C577.2 C578.2 C579.2 C580.2 D2.2 FB12.2 J1.2 J1.3 J1_1.1 J2.2 J3.8 J4.5 J5.8 J6.8 J7.5 J8.8 J9.11 J9.12 J9.21 J10.1 J10.12 J10.13 J12.1 J12.12 J12.13 J15.6(VSS) J15.G1 J15.G2 J15.G3 J15.G4 J15.G5 J15.SW J16.7 J16.10 J16.13 J16.16 J16.19 J16.22 J16.MNT1 J16.MNT2 J17.6 J17.G1 J17.G2 J18.16(GND#16) J18.57(GND#57) J18.61(GND#61) J18.62(GND#62) J18.63(GND#63) J18.64(GND#64) J19.5(GND) J21.22 J21.39 J21.40 J21.59 J21.60 J22.A4 J22.A12 J22.A15 J22.A18 J22.B4 J22.B7 J22.B13 J22.B16 J22.B17 J22.B18 J23.4(GND) J23.7(GND_DRAIN) J24.2(DAT2_S) J24.5(DAT1_S) J24.8(DAT0_S) J24.11(CLK_S) J24.17(DDC/CEC GND) J24.MTG1 J24.MTG2 J24.MTG3 J24.MTG4 J37.17 J37.29 J37.30 J39.3 J44.2 J45.5(GND) J46.1 J51.2 L3.2(GND) L21.2(GND) L24.2(GND) L25.2(GND) L26.2(GND) L34.2(GND) L35.2(GND) Q1.S(SOURCE) Q2.S(SOURCE) Q3.S(SOURCE) Q4.S(SOURCE) Q5.S(SOURCE) Q6.S(SOURCE) Q9.S(SOURCE) Q10.S(SOURCE) Q11.S(SOURCE) Q12.S(SOURCE) Q13.S(SOURCE) Q14.S(SOURCE) Q15.S(SOURCE) Q16.S(SOURCE) Q20.S(SOURCE) Q21.S(SOURCE) Q22.S(SOURCE) Q23.S(SOURCE) Q24.S(SOURCE) Q25.S(SOURCE) R2_1.2 R13.2(P2) R16.2(P2) R32.2 R33.2 R34.2 R35.2 R37.2 R38.2 R39.2 R40.2 R41.1(P1) R42.1(P1) R44.1(P1) R48.1 R89.2(P2) R103.1(P1) R104.1(P1) R108.1(P1) R109.1(P1) R110.1(P1) R111.1(P1) R116.1(P1) R147.1(P1) R155.1(P1) R156.1(P1) R157.1(P1) R158.1(P1) R172.2(P2) R186.1(P1) R187.1(P1) R191.1(P1) R192.1(P1) R193.1(P1) R194.1(P1) R228.1(P1) R235.1(P1) R236.1(P1) R237.1(P1) R238.1(P1) R245.1(P1) R246.1(P1) R251.1(P1) R252.1(P1) R255.1(P1) R256.1(P1) R298.2 R304.1(P1) R317.1(P1) R319.1(P1) R321.1(P1) R341.2 R348.1(P1) R361.1(P1) R363.1(P1) R380.1(P1) R381.1(P1) R382.1(P1) R414.1(P1) R415.1 R417.1 R425.2 R427.1(P1) R430.2 R431.2 R432.2 R433.1(P1) R453.1 R454.1 R455.1 R456.1 R457.1 R458.1 R459.1 R460.1 R461.1 R462.1 R463.1 R464.1 R465.1 R466.1 R467.1 R468.1 R479.2(P2) R484.1(P1) R489.1(P1) R494.1 R515.1(P1) R539.1 R542.1 R547.2(P2) R550.2(P2) R553.2 R561.1 R569.2(P2) R570.2 R571.2 R579.1(P1) R587.2(P2) R591.1(P1) R592.1(P1) R595.1(P1) R597.1(P1) R599.1(P1) R643.2(P2) R648.1(P1) R680.1 R695.1(P1) R697.1(P1) R700.1(P1) R704.1(P1) R706.1(P1) R709.1(P1) R754.1(P1) R755.1(P1) R785.1 R791.2 R793.1(P1) R798.1 R810.2 R812.2(P2) R813.2(P2) R912.1 R913.1 R923.2(P2) R924.2(P2) R925.2(P2) R927.1(P1) R928.1(P1) R934.2(P2) R955.1 SCKT1.MCH2 SCKT1.MCH4 SW1.1 SW1.2 SW2.1 SW2.2 SW3.1 SW3.2 TP1_1.1 TP8.1 TP9.1 TP10.1 TP11.1 U1.A1(VSS#A1) U1.A2(VSS#A2) U1.A6(VSS#A6) U1.A14(VSS#A14) U1.A23(VSS#A23) U1.A28(VSS#A28) U1.AA8(VSS#AA8) U1.AA9(VSS#AA9) U1.AA10(VSS#AA10) U1.AA11(VSSA_USB#AA11) U1.AA14(VSS#AA14) U1.AA15(VSS#AA15) U1.AA20(VSS#AA20) U1.AB11(VSSA_USB#AB11) U1.AB14(VSS#AB14) U1.AB20(VSS#AB20) U1.AC14(VSSA_OSC1) U1.AD1(VSS#AD1) U1.AD10(VSSA_USB3) U1.AD13(VSSA_PCIE#AD13) U1.AD19(VSSA_HDMI#AD19) U1.AD24(VSS#AD24) U1.AE10(VSSA_SATA) U1.AE13(VSSA_PCIE#AE13) U1.AE19(VSSA_HDMI#AE19) U1.AG1(VSS#AG1) U1.AH1(VSS#AH1) U1.AH2(VSS#AH2) U1.AH8(VSS#AH8) U1.AH20(VSS#AH20) U1.AH28(VSS#AH28) U1.B1(VSS#B1) U1.D13(VSS#D13) U1.D19(VSS#D19) U1.E13(VSS#E13) U1.E19(VSS#E19) U1.F1(VSS#F1) U1.F7(VSS#F7) U1.G7(VSS#G7) U1.G8(VSS#G8) U1.G9(VSS#G9) U1.H12(VSS#H12) U1.J12(VSS#J12) U1.J15(VSS#J15) U1.J28(VSS#J28) U1.K1(VSS#K1) U1.K4(VSS#K4) U1.K5(VSS#K5) U1.K15(VSS#K15) U1.K24(VSS#K24) U1.K25(VSS#K25) U1.L13(VSS#L13) U1.L14(VSS#L14) U1.M19(VSS#M19) U1.N14(VSS#N14) U1.N15(VSS#N15) U1.N19(VSS#N19) U1.N24(VSS#N24) U1.N25(VSS#N25) U1.P28(VSS#P28) U1.R1(VSS#R1) U1.R12(VSS#R12) U1.R13(VSS#R13) U1.R15(VSS#R15) U1.R21(VSS#R21) U1.T10(VSS#T10) U1.T11(VSS#T11) U1.T12(VSS#T12) U1.T14(VSS#T14) U1.T15(VSS#T15) U1.T17(VSS#T17) U1.T18(VSS#T18) U1.T21(VSS#T21) U1.U14(VSSA_VIDEO) U1.U15(VSS#U15) U1.U17(VSS#U17) U1.U20(VSS#U20) U1.U21(VSS#U21) U1.V15(VSS#V15) U1.V17(VSS#V17) U1.W1(VSS#W1) U1.W15(VSS#W15) U1.W24(VSS#W24) U1.W25(VSS#W25) U1.W28(VSS#W28) U1_1.2(GND) U1_1.TPAD U2.3(GND) U3.A1(PKG_GND_A1) U3.A4(REFGND1) U3.A7(GNDANA#A7) U3.A13(PKG_GND#A13) U3.B2(GPADC_IN0) U3.B8(SYNCDCDC) U3.B10(PKG_GND#B10) U3.B11(PKG_GND#B11) U3.C2(GPADC_IN1) U3.C3(GPADC_IN2) U3.C12(SMPS12_FBK_GND) U3.D4(SMPS7_GND#D4) U3.D5(SMPS7_GND#D5) U3.D6(PKG_GND#D6) U3.D7(PKG_GND#D7) U3.D10(SMPS1_GND#D10) U3.E4(SMPS7_GND#E4) U3.E7(GNDANA#E7) U3.E8(PKG_GND#E8) U3.E9(SMPS1_GND#E9) U3.E10(SMPS1_GND#E10) U3.F4(SMPS4_GND#F4) U3.F5(GNDANA#F5) U3.F6(PKG_GND#F6) U3.F7(PKG_GND#F7) U3.F9(SMPS2_GND#F9) U3.F10(SMPS2_GND#F10) U3.G4(SMPS4_GND#G4) U3.G5(SMPS4_GND#G5) U3.G7(PKG_GND#G7) U3.G10(SMPS2_GND#G10) U3.H4(SMPS5_GND#H4) U3.H5(SMPS5_GND#H5) U3.H6(PKG_GND#H6) U3.H7(PKG_GND#H7) U3.H10(SMPS3_GND#H10) U3.J4(SMPS5_GND#J4) U3.J6(PKG_GND#J6) U3.J9(SMPS3_GND#J9) U3.J10(SMPS3_GND#J10) U3.K3(SMPS45_FDBK_GND) U3.L5(SMPS6_GND#L5) U3.L6(SMPS6_GND#L6) U3.L7(SMPS9_GND#L7) U3.L8(SMPS9_GND#L8) U3.L9(SMPS8_GND#L9) U3.L10(SMPS8_GND#L10) U3.M1(PKG_GND#M1) U3.M2(PKG_GND#M2) U3.M12(GNDDIG) U3.M13(GNDANA#M13) U3.N1(PKG_GND#N1) U3.N2(VIO_GND) U3.N13(PKG_GND#N13) U4.10(VSS) U5.A9(VSS1) U5.B1(VSSQ#B1) U5.B3(VSS2) U5.B9(VSSQ#B9) U5.D1(VSSQ#D1) U5.D8(VSSQ#D8) U5.E1(VSS3) U5.E2(VSSQ#E2) U5.E8(VSSQ#E8) U5.F9(VSSQ#F9) U5.G1(VSSQ#G1) U5.G8(VSS4) U5.G9(VSSQ#G9) U5.J2(VSS5) U5.J8(VSS6) U5.M1(VSS7) U5.M9(VSS8) U5.P1(VSS9) U5.P9(VSS10) U5.T1(VSS11) U5.T9(VSS12) U6.A9(VSS1) U6.B1(VSSQ#B1) U6.B3(VSS2) U6.B9(VSSQ#B9) U6.C7(UDQS) U6.D1(VSSQ#D1) U6.D3(UDM) U6.D8(VSSQ#D8) U6.E1(VSS3) U6.E2(VSSQ#E2) U6.E8(VSSQ#E8) U6.F9(VSSQ#F9) U6.G1(VSSQ#G1) U6.G8(VSS4) U6.G9(VSSQ#G9) U6.J2(VSS5) U6.J8(VSS6) U6.M1(VSS7) U6.M9(VSS8) U6.P1(VSS9) U6.P9(VSS10) U6.T1(VSS11) U6.T9(VSS12) U7.A9(VSS1) U7.B1(VSSQ#B1) U7.B3(VSS2) U7.B9(VSSQ#B9) U7.D1(VSSQ#D1) U7.D8(VSSQ#D8) U7.E1(VSS3) U7.E2(VSSQ#E2) U7.E8(VSSQ#E8) U7.F9(VSSQ#F9) U7.G1(VSSQ#G1) U7.G8(VSS4) U7.G9(VSSQ#G9) U7.J2(VSS5) U7.J8(VSS6) U7.M1(VSS7) U7.M9(VSS8) U7.P1(VSS9) U7.P9(VSS10) U7.T1(VSS11) U7.T9(VSS12) U8.4(PGND) U8.8(GND) U8.11(PWRPD) U9.TPAD U13.TPAD U15.TPAD U17.TPAD U18.M1 U18.M2 U19.3(GND) U21.13(VSS_PS) U21.29(VSS) U21.49(P_GND) U22.3(GND) U23.5(GND1) U23.10(GND2) U24.13(VSS_PS) U24.29(VSS) U24.49(P_GND) U25.5(GND1) U25.10(GND2) U26.3(GND) U28.3(GND) U30.5(GND) U32.4(GND) U32.8(PGND) U32.PAD(TPAD) U33.1(A0) U33.2(A1) U33.3(A2) U33.4(VSS) U34.3(GND) U35.3(GND) U36.4(GND) U37.1(GND.1) U37.5(GND.2) U37.10(AGND) U37.11(GND.3) U37.13(TEST) U37.15(GND.4) U37.25(GND.5) U37.35(GND.6) U37.47(GND.7) U37.51(GND.8) U38.5(VSS) U38.7(NC1) U39.3(GND) U40.1(VIN-) U41.4(GND1) U43.A6(VSS1) U43.C4(VSSQ1) U43.E7(VSS2) U43.G5(VSS3) U43.H10(VSS4) U43.J5(VSS5) U43.K8(VSS6) U43.N2(VSSQ2) U43.N5(VSSQ3) U43.P4(VSSQ4) U43.P6(VSSQ5) U44.3(GND) U45.14(GND#14) U45.22(GND#22) U45.TPAD(PWRPAD) U46.6(GND#6) U46.14(GND#14) U46.19(GND#19) U47.3(GND) U48.2 U49.2 U50.2 U62.B4(SYNC) U62.C1(PGND#C1) U62.C2(PGND#C2) U62.C3(GND#C3) U62.D3(GND#D3) U62.E4(GND#E4) U63.8(GND#8) U63.9(GND#9) U64.3(GND) U65.5(GND) U66.1(GND) U68.3(GND) U69.3(GND) U70.3(GND) U71.3(GND) U72.28(GND) U72.TH_PD(THRM) U73.7(A2) U73.8(G\) U73.9(A0) U73.10(A1) U73.16(GND) U74.3(GND1) U75.5(GND) U76.2(GND) U77.5(GND) U78.3(GND) U79.4(GND) U82.2 U83.2 U84.2 U85.3(GND) U86.5(GND) U89.A1(VSS#A1) U89.A10(VSS#A10) U89.B7(VSS#B7) U89.D4(VSS#D4) U89.D5(VSS#D5) U89.D6(VSS#D6) U89.D7(VSS#D7) U89.E4(VSS#E4) U89.E5(VSS#E5) U89.E6(VSS#E6) U89.E7(VSS#E7) U89.E9(VSS#E9) U89.F4(VSS#F4) U89.F5(VSS#F5) U89.F6(VSS#F6) U89.F7(VSS#F7) U89.G4(VSS#G4) U89.G5(VSS#G5) U89.G6(VSS#G6) U89.G7(VSS#G7) U89.H2(VSS#H2) U89.H9(VSS#H9) U89.J4(VSS#J4) U89.J5(VSS#J5) U89.J8(CS) U89.K10(VSS#K10) U90.A9(VSS1) U90.B1(VSSQ#B1) U90.B3(VSS2) U90.B9(VSSQ#B9) U90.D1(VSSQ#D1) U90.D8(VSSQ#D8) U90.E1(VSS3) U90.E2(VSSQ#E2) U90.E8(VSSQ#E8) U90.F9(VSSQ#F9) U90.G1(VSSQ#G1) U90.G8(VSS4) U90.G9(VSSQ#G9) U90.J2(VSS5) U90.J8(VSS6) U90.M1(VSS7) U90.M9(VSS8) U90.P1(VSS9) U90.P9(VSS10) U90.T1(VSS11) U90.T9(VSS12) U91.A9(VSS1) U91.B1(VSSQ#B1) U91.B3(VSS2) U91.B9(VSSQ#B9) U91.D1(VSSQ#D1) U91.D8(VSSQ#D8) U91.E1(VSS3) U91.E2(VSSQ#E2) U91.E8(VSSQ#E8) U91.F9(VSSQ#F9) U91.G1(VSSQ#G1) U91.G8(VSS4) U91.G9(VSSQ#G9) U91.J2(VSS5) U91.J8(VSS6) U91.M1(VSS7) U91.M9(VSS8) U91.P1(VSS9) U91.P9(VSS10) U91.T1(VSS11) U91.T9(VSS12) U92.4(PGND) U92.8(GND) U92.11(PWRPD) U93.4(GND) U94.1(GND) U95.3(GND#3) U95.8(GND#8) U96.3(GND) U97.3(GND) U98.3(GND) U99.8(GND) U99.15(O\E\) U101.8(GND) U102.4(GND) U103.4(GND) U104.2(GND) X1.2(GND) Y7.2(GND)
GND_CAN1: C250.2 C252.2 J38.4 U40.4(VOUT-#4) U40.5(VOUT-#5) U41.5(GND2) U87.2 U88.2
GND_OSC0: C1.2 C2.2 R13.1(P1) U1.AF15(VSSA_OSC0)
GNDPROFI: C323.2(NEG) C325.2(NEG) C430.2 C431.2 C433.2 C434.2 J14.5 L2.6 L2.7 R573.1(P1) R578.1(P1) U52.3(GND) U52.4(E\N\) U74.9(GND2#9) U74.11(GND2#11) U74.14(GND2#14) U74.15(GND2#15) U80.2 U81.2
GNDUSB1: C557.2 C558.2 J23.S1 J23.S2 R812.1(P1)
GNDUSB2: C559.2 C560.2 J45.S1 J45.S2 J45.S3 J45.S4 R813.1(P1)
GNDUSBJ: FB12.1 J19.S1 J19.S2 J19.S3 J19.S4
V1_2D: C480.1 C481.1 C484.1 FB19.1 U76.5(OUT) U89.A7(VDDC#A7) U89.B1(VDDC#B1) U89.K4(VDDC#K4)
V1_2D_EN: R451.1(P1) U76.3(EN)
V1_8D: C1_1.1 C169.1 C190.1 C368.1 C372.1 C373.1 C374.1 C375.1 C376.1 C377.1 C378.1 C379.1 C405.1 C406.1 D24.3(ANODE) D25.3(ANODE) Q26.3(COLLECTOR) Q27.3(COLLECTOR) R1_1.2(P2) R451.2(P2) R658.1(P1) R897.1 R901.1 R933.1(P1) U1.AA7(VDDS_MLBP#AA7) U1.AA18(VDDS18V_DDR1#AA18) U1.AA19(VDDS18V_DDR1#AA19) U1.G18(VDDS18V#G18) U1.H17(VDDS18V#H17) U1.J21(VDDS18V_DDR2#J21) U1.J22(VDDS18V_DDR2#J22) U1.M8(VDDS18V#M8) U1.M9(VDDS18V#M9) U1.N8(VDDS18V#N8) U1.N21(VDDS18V_DDR2#N21) U1.P8(VDDS18V#P8) U1.P20(VDDS18V_DDR2#P20) U1.P21(VDDS18V_DDR2#P21) U1.R8(VDDS18V#R8) U1.T8(VDDS18V#T8) U1.V21(VDDS18V#V21) U1.V22(VDDS18V#V22) U1.W17(VDDS18V#W17) U1.W18(VDDS18V#W18) U1.W21(VDDS18V_DDR1#W21) U1.Y7(VDDS_MLBP#Y7) U1.Y21(VDDS18V_DDR1#Y21) U1_1.1(OUT) U23.3(VDD) U25.3(VDD)
V1_8D_OUT: J1_1.2 R1_1.1(P1)
V1_8FTDI: C227.1 C232.1 C235.1 C238.1 C241.1 U37.12(VCORE.1) U37.37(VCORE.2) U37.49(VREGOUT) U37.64(VCORE.3)
V1_8PHY_HDMI: C566.1 C567.1 C568.1 L35.3(OUT) U1.Y17(VDDA_HDMI)
V1_8PHY_LDO3: C392.1 L25.1(IN) L34.1(IN) U3.K11(LDO3_OUT)
V1_8PHY_LDO4: L26.1(IN) L35.1(IN) R854.1(P1)
V1_8PHY_PCIE: C393.1 C394.1 C447.1 L26.3(OUT) U1.AA16(VDDA_PCIE1) U1.AA17(VDDA_PCIE0) U1.W14(VDDA_PCIE)
V1_8PHY_SATA: C563.1 C564.1 C565.1 L34.3(OUT) U1.V13(VDDA_SATA)
V1_8PHY_USB: C390.1 C391.1 C446.1 L25.3(OUT) U1.AA13(VDDA_USB1) U1.AB12(VDDA_USB2) U1.W12(VDDA_USB3)
V1_8PLL: C382.1 L21.1(IN) L24.1(IN) U1.AD16(VDDA_OSC#AD16) U1.AE16(VDDA_OSC#AE16) U3.B5(LDOLN_OUT)
V1_8PLLA: C380.1 C381.1 C442.1 L21.3(OUT) U1.M14(VDDA_ABE_PER) U1.N16(VDDA_MPU) U1.R14(VDDA_GPU) U1.R17(VDDA_IVA)
V1_8PLLB: C388.1 C389.1 C445.1 L24.3(OUT) U1.N11(VDDA_DEBUG) U1.N12(VDDA_DSP_EVE) U1.P14(VDDA_VIDEO) U1.P15(VDDA_GMAC_CORE) U1.P16(VDDA_DDR)
V3_3ACDCM: C320.1 C321.1 C322.1 C324.1 L3.3(OUT) U45.1(VDD2_OUT1) U45.4(VDD1_OUT0)
V3_3APCIE: C307.1 C308.1 C309.1 C310.1 C326.1 FB13.1 R546.2 R548.2 R549.2 U45.9(VDD#9) U45.16(VDD#16) U45.18(VDD#18) U45.20(VDD#20) Y7.4(VCC)
V3_3AUX_PCIE: C556.1 J22.B10 J49.2 R654.2
V3_3D: C2_1.1 C3.1 C28.1 C88.1 C104.1 C105.1 C107.1 C113.1 C119.1 C120.1 C122.1 C127.1 C130.1 C132.1 C133.1 C139.1 C143.1 C144.1 C145.1 C151.1 C170.1 C191.1 C209.1 C210.1 C211.1 C212.1 C214.1 C219.1 C220.1 C221.1 C248.1 C249.1 C251.1 C255.1 C256.1 C257.1 C258.1 C261.1 C262.1 C263.1 C264.1 C319.1 C350.1 C360.1 C361.1 C362.1 C363.1 C364.1 C365.1 C367.1 C384.1 C385.1 C386.1 C408.1 C409.1 C410.1 C420.1 C426.1 C428.1 C432.1 C435.1 C444.1 C449.1 C450.1 C451.1 C469.1 C470.1 C479.1 C532.1 C569.1 C571.1 D16.1(A) D17.1(A) D18.1(A) D19.1(A) D22.1(A) D23.1(A) FB1.1 FB5.1 FB13.2 J1_1.3 J15.4(VDD) J17.5 J21.1 J22.A9 J22.A10 J22.B8 J46.3 J49.1 L2.2 L2.3 L3.1(IN) Q26.2(EMMITTER) R2.2 R8.2(P2) R10.2 R18.2 R22.2 R56.2(P2) R67.2(P2) R76.2(P2) R77.2(P2) R78.2(P2) R97.1(P1) R99.1(P1) R100.1(P1) R101.1(P1) R102.1(P1) R107.2 R120.2(P2) R121.2(P2) R122.2(P2) R131.2(P2) R134.2(P2) R141.1(P1) R143.1(P1) R144.1(P1) R145.1(P1) R146.1(P1) R149.2 R152.2(P2) R153.2 R159.2(P2) R160.2(P2) R161.2(P2) R180.1(P1) R182.1(P1) R183.1(P1) R184.1(P1) R185.1(P1) R190.2 R200.2(P2) R201.2(P2) R202.2(P2) R203.2(P2) R214.2(P2) R222.1(P1) R224.1(P1) R225.1(P1) R226.1(P1) R227.1(P1) R232.2(P2) R233.2 R259.2 R278.2(P2) R322.2(P2) R366.2 R383.2(P2) R384.2(P2) R410.2(P2) R412.2 R417.2 R419.2(P2) R420.1 R421.2 R422.2(P2) R423.2(P2) R434.2(P2) R435.2(P2) R436.2(P2) R437.2(P2) R438.2(P2) R439.2(P2) R440.2(P2) R441.2(P2) R442.2(P2) R443.2(P2) R444.2(P2) R445.2(P2) R446.2(P2) R447.2(P2) R448.2(P2) R449.2(P2) R450.2(P2) R472.2(P2) R498.2 R505.2(P2) R506.2(P2) R507.2(P2) R508.2(P2) R509.2(P2) R510.2(P2) R511.2(P2) R512.2(P2) R513.2(P2) R543.1 R544.1 R545.2 R551.2 R556.2(P2) R559.2(P2) R563.2(P2) R637.1 R649.2 R678.2(P2) R679.2(P2) R730.2(P2) R731.2(P2) R741.2 R742.1(P1) R782.2(P2) R783.2(P2) R790.2 R799.2 R800.2 R804.2 R805.2 R808.2 R811.1 R814.1 R894.2 R896.2 R902.2 R914.2 R917.2 R938.2 R939.2 R941.2 R943.2 R945.2 R948.2 R954.1 R956.2(P2) R958.2(P2) U1.AB6(VDDSHV7#AB6) U1.AB7(VDDSHV7#AB7) U1.AD5(VDDSHV6#AD5) U1.AD7(VDDSHV6#AD7) U1.AE7(VDDSHV6#AE7) U1.AF5(VDDSHV6#AF5) U1.B6(VDDSHV2#B6) U1.B23(VDDSHV3#B23) U1.C24(VDDSHV4) U1.D10(VDDSHV2#D10) U1.D16(VDDSHV3#D16) U1.D22(VDDSHV3#D22) U1.E3(VDDSHV1#E3) U1.E5(VDDSHV1#E5) U1.E10(VDDSHV2#E10) U1.E16(VDDSHV3#E16) U1.E22(VDDSHV3#E22) U1.G4(VDDSHV1#G4) U1.G5(VDDSHV1#G5) U1.G15(VDDSHV3#G15) U1.H8(VDDSHV1#H8) U1.H9(VDDSHV1#H9) U1.H10(VDDSHV2#H10) U1.H11(VDDSHV2#H11) U1.H15(VDDSHV3#H15) U1.H16(VDDSHV3#H16) U1.H18(VDDSHV3#H18) U1.H19(VDDSHV3#H19) U1.J8(VDDSHV11#J8) U1.K8(VDDSHV11#K8) U1.N4(VDDSHV10#N4) U1.N5(VDDSHV10#N5) U1.P10(VDDSHV10#P10) U1.R7(VDDSHV10#R7) U1.R10(VDDSHV10#R10) U1.T4(VDDSHV10#T4) U1.T5(VDDSHV10#T5) U1.U10(VDDSHV9#U10) U1.V12(VDDSHV5) U1.W4(VDDSHV9#W4) U1.W5(VDDSHV9#W5) U1_1.4(IN) U2.5(VCC) U3.D9(VIO_IN) U3.J8(SMPS9_FBK) U4.2(VCC) U4.14(VIO/RFU) U8.10(VIN) U9.21(VDD33_IO) U13.21(VDD33_IO) U15.21(VDD33_IO) U17.21(VDD33_IO) U19.5(VCC) U23.6(VDDOUT1) U23.7(VDDOUT2) U25.6(VDDOUT1) U25.7(VDDOUT2) U30.10(VCC) U33.8(VCC) U39.2(A) U39.5(VCC) U40.2(VIN+) U41.1(VCC1) U43.C6(VCCQ1) U43.E6(VCC1) U43.F5(VCC2) U43.J10(VCC3) U43.K9(VCC4) U43.M4(VCCQ2) U43.N4(VCCQ3) U43.P3(VCCQ4) U43.P5(VCCQ5) U44.5(VCC) U46.24(VCCA) U47.5(VCC) U63.16(VCCB) U65.8(VCCB) U68.5(VCC) U69.5(VCC) U70.5(VCC) U71.5(VCC) U73.1(VCC) U74.4(VCC1) U75.1(VCCA) U75.3(A2) U77.8(VCC) U78.5(VCC) U85.5(VCC) U89.B10(VDDIO#B10) U89.H1(VDDIO#H1) U89.K5(VDDIO#K5) U89.K9(VDDIO#K9) U92.10(VIN) U97.5(VCC) U98.5(VCC) U99.16(VCC) U101.15(2G\) U101.16(VCC) U102.8(VCC) U103.8(VCC) X1.4(VCC)
V3_3D_PROFIA: L2.4 U74.1(D1)
V3_3D_PROFIB: L2.1 U74.2(D2)
V3_3D_PRU1ETH0JCK: C102.1 C103.1 J3.3 J3.4 R77.1(P1)
V3_3D_PRU1ETH1JCK: C116.1 C117.1 J5.3 J5.4 R121.1(P1)
V3_3D_PRU2ETH0JCK: C128.1 C129.1 J6.3 J6.4 R160.1(P1)
V3_3D_PRU2ETH1JCK: C140.1 C141.1 J8.3 J8.4 R202.1(P1)
V3_3FTDI: C224.1 C228.2 C229.1 C230.2 C233.1 C236.1 C239.1 C242.2 C245.1 C425.1 C443.1 C448.1 FB10.2 FB11.2 R472.1(P1) R485.2 R496.2 U34.5(VCC) U35.5(VCC) U37.20(VCCIO.1) U37.31(VCCIO.2) U37.42(VCCIO.3) U37.50(VREGIN) U37.56(VCCIO.4) U38.6(NC2) U38.8(VCC) U63.1(VCCA) U63.2(1DIR) U63.3(2DIR) U65.1(VCCA) U75.8(VCCB)
V3_3USB: C399.1 C400.1 C401.1 U1.AA12(VDDA33V_USB1) U1.Y12(VDDA33V_USB2) U3.B9(LDOUSB_OUT)
V3_7LCD: C222.1 C315.1 C472.1 J16.3 J16.4 J16.5 R681.1 U86.3(VOUT)
V5_0D: C208.1 C418.1 C419.1 C427.1 C476.1 J21.2 J37.27 J37.28 R386.1(P1) R388.1(P1) R389.1(P1) R390.1(P1) R391.1(P1) R392.1(P1) R395.1(P1) R396.1(P1) R424.2(P2) R560.2(P2) R562.2(P2) U46.11(VCC5V) U62.E1(VOUT#E1) U62.E2(VOUT#E2) U66.2(IN#2) U66.3(IN#3) U94.2(IN#2) U94.3(IN#3)
V5_0D_EN: R419.1(P1) U62.A4(EN)
V5_0DFB: R424.1(P1) R427.2(P2) U62.E3(FB)
V5_0HDMICONN: C429.1 J24.18(+5V) U46.13(5V_OUT)
V5_0VOP: C195.1 C205.1 C207.1 U28.5(VCC) U72.15(5VOP)
V12_0D: C196.1 C303.1 C304.1 C461.1 C462.1 D20.1(CATHODE) J22.A2 J22.A3 J22.B1 J22.B2 J22.B3 J37.2 J37.4 J37.6 J37.8 J37.10 J37.12 J37.14 J37.16 R379.1 R647.2
VDD_CORE: C339.1 C340.1 C341.1 C342.1 C343.1 C344.1 C345.1 C387.1 C473.1 C572.1 C573.1 C574.1 C575.1 C576.1 C577.1 R640.2(I2) R931.1(P1) U1.H13(VDD#H13) U1.H14(VDD#H14) U1.J17(VDD#J17) U1.J18(VDD#J18) U1.L7(VDD#L7) U1.L8(VDD#L8) U1.N10(VDD#N10) U1.N13(VDD#N13) U1.P11(VDD#P11) U1.P12(VDD#P12) U1.P13(VDD#P13) U1.R11(VDD#R11) U1.R16(VDD#R16) U1.R19(VDD#R19) U1.T13(VDD#T13) U1.T16(VDD#T16) U1.T19(VDD#T19) U1.U8(VDD#U8) U1.U9(VDD#U9) U1.U13(VDD#U13) U1.U16(VDD#U16) U1.V8(VDD#V8) U1.V16(VDD#V16) U3.B1(SMPS7_FDBK)
VDD_DSPEVE: C353.1 C354.1 C355.1 C356.1 C357.1 C358.1 C359.1 C414.1 C422.1 C423.1 C475.1 R642.2(I2) U1.J13(VDD_DSPEVE#J13) U1.K10(VDD_DSPEVE#K10) U1.K11(VDD_DSPEVE#K11) U1.K12(VDD_DSPEVE#K12) U1.K13(VDD_DSPEVE#K13) U1.L10(VDD_DSPEVE#L10) U1.L11(VDD_DSPEVE#L11) U1.L12(VDD_DSPEVE#L12) U1.M10(VDD_DSPEVE#M10) U1.M11(VDD_DSPEVE#M11) U1.M12(VDD_DSPEVE#M12) U1.M13(VDD_DSPEVE#M13) U3.K2(SMPS45_FDBK)
VDD_GPU: C266.1 C267.1 C268.1 C327.1 C328.1 C329.1 C330.1 C331.1 C396.1 L17.2 U1.U11(VDD_GPU#U11) U1.U12(VDD_GPU#U12) U1.V10(VDD_GPU#V10) U1.V11(VDD_GPU#V11) U1.V14(VDD_GPU#V14) U1.W10(VDD_GPU#W10) U1.W11(VDD_GPU#W11) U1.W13(VDD_GPU#W13) U3.K6(SMPS6_FBK)
VDD_IVA: C270.1 C346.1 C347.1 C348.1 C349.1 C351.1 C413.1 L19.2 U1.U18(VDD_IVA#U18) U1.U19(VDD_IVA#U19) U1.V18(VDD_IVA#V18) U1.V19(VDD_IVA#V19) U3.L11(SMPS8_FDBK)
VDD_MPU: C332.1 C333.1 C334.1 C335.1 C336.1 C337.1 C338.1 C352.1 C369.1 C370.1 C371.1 C395.1 C474.1 R641.2(I2) U1.K17(VDD_MPU#K17) U1.K18(VDD_MPU#K18) U1.L15(VDD_MPU#L15) U1.L16(VDD_MPU#L16) U1.L17(VDD_MPU#L17) U1.L18(VDD_MPU#L18) U1.L19(VDD_MPU#L19) U1.M15(VDD_MPU#M15) U1.M16(VDD_MPU#M16) U1.M17(VDD_MPU#M17) U1.M18(VDD_MPU#M18) U1.N17(VDD_MPU#N17) U1.N18(VDD_MPU#N18) U1.P17(VDD_MPU#P17) U1.P18(VDD_MPU#P18) U1.R18(VDD_MPU#R18) U3.B13(SMPS12_FBK)
VDD_RTC: C402.1 R930.1(P1) U3.A5(LDO9_OUT)
VDDR2_VREF: C503.2 C504.1 C505.1 C521.2 C522.1 C523.1 C524.1 C531.1 U1.N22(DDR2_VREF) U90.H1(VREFDQ) U90.M8(VREFCA) U91.H1(VREFDQ) U91.M8(VREFCA) U92.6(REFOUT)
VDDR2_VTT: C525.1 C526.1 C527.1 C528.1 C530.1 C534.1 C535.1 C536.1 C537.1 C538.1 C539.1 R756.1(P1) R757.1(P1) R758.1(P1) R759.1(P1) R760.1(P1) R761.1(P1) R762.1(P1) R763.1(P1) R764.1(P1) R765.1(P1) R766.1(P1) R767.1(P1) R768.1(P1) R769.1(P1) R770.1(P1) R771.1(P1) R772.1(P1) R773.1(P1) R774.1(P1) R775.1(P1) R776.1(P1) R777.1(P1) R778.1(P1) R779.1(P1) R784.2(P2) R807.1(P1) U92.3(VO)
VDDR_VREF: C44.2 C45.1 C46.1 C47.2 C53.1 C54.1 C80.2 C81.1 C82.1 C83.1 C99.1 U1.Y18(DDR1_VREF) U5.H1(VREFDQ) U5.M8(VREFCA) U6.H1(VREFDQ) U6.M8(VREFCA) U7.H1(VREFDQ) U7.M8(VREFCA) U8.6(REFOUT)
VDDR_VTT: C87.1 C89.1 C93.1 C94.1 C95.1 C96.1 C97.1 C98.1 C100.1 C313.1 C314.1 R49.1(P1) R50.1(P1) R51.1(P1) R52.1(P1) R53.1(P1) R54.1(P1) R55.1(P1) R57.1(P1) R58.1(P1) R59.1(P1) R60.1(P1) R61.1(P1) R62.1(P1) R63.1(P1) R64.1(P1) R65.1(P1) R66.1(P1) R68.1(P1) R69.2(P2) R70.1(P1) R71.1(P1) R72.1(P1) R73.1(P1) R74.1(P1) R75.1(P1) R806.1(P1) U8.3(VO)
VDDS_DDR: C29.1 C30.1 C31.1 C32.1 C33.1 C34.1 C35.1 C36.1 C37.1 C38.1 C39.1 C40.1 C41.1 C42.1 C43.1 C44.1 C47.1 C48.1 C49.1 C50.1 C51.1 C52.1 C55.1 C56.1 C57.1 C58.1 C59.1 C60.1 C61.1 C62.1 C63.1 C64.1 C65.1 C66.1 C67.1 C68.1 C69.1 C70.1 C71.1 C72.1 C73.1 C74.1 C75.1 C76.1 C77.1 C78.1 C79.1 C80.1 C84.1 C85.2 C87.2 C89.2 C90.1 C91.1 C92.1 C314.2 C488.1 C489.1 C490.1 C491.1 C492.1 C493.1 C494.1 C495.1 C496.1 C497.1 C498.1 C499.1 C500.1 C501.1 C502.1 C503.1 C506.1 C507.1 C508.1 C509.1 C510.1 C511.1 C512.1 C513.1 C514.1 C515.1 C516.1 C517.1 C518.1 C519.1 C520.1 C521.1 C526.2 C529.2 C538.2 C539.2 C540.1 C541.1 C542.1 C543.1 R45.2 R639.1(I1) R656.1(P1) R786.2 R801.1(I1) U3.K13(SMPS3_FDBK) U5.A1(VDDQ#A1) U5.A8(VDDQ#A8) U5.B2(VDD#B2) U5.C1(VDDQ#C1) U5.C9(VDDQ#C9) U5.D2(VDDQ#D2) U5.D9(VDD#D9) U5.E9(VDDQ#E9) U5.F1(VDDQ#F1) U5.G7(VDD#G7) U5.H2(VDDQ#H2) U5.H9(VDDQ#H9) U5.K2(VDD#K2) U5.K8(VDD#K8) U5.N1(VDD#N1) U5.N9(VDD#N9) U5.R1(VDD#R1) U5.R9(VDD#R9) U6.A1(VDDQ#A1) U6.A8(VDDQ#A8) U6.B2(VDD#B2) U6.B7(\\U\D\Q\S\) U6.C1(VDDQ#C1) U6.C9(VDDQ#C9) U6.D2(VDDQ#D2) U6.D9(VDD#D9) U6.E9(VDDQ#E9) U6.F1(VDDQ#F1) U6.G7(VDD#G7) U6.H2(VDDQ#H2) U6.H9(VDDQ#H9) U6.K2(VDD#K2) U6.K8(VDD#K8) U6.N1(VDD#N1) U6.N9(VDD#N9) U6.R1(VDD#R1) U6.R9(VDD#R9) U7.A1(VDDQ#A1) U7.A8(VDDQ#A8) U7.B2(VDD#B2) U7.C1(VDDQ#C1) U7.C9(VDDQ#C9) U7.D2(VDDQ#D2) U7.D9(VDD#D9) U7.E9(VDDQ#E9) U7.F1(VDDQ#F1) U7.G7(VDD#G7) U7.H2(VDDQ#H2) U7.H9(VDDQ#H9) U7.K2(VDD#K2) U7.K8(VDD#K8) U7.N1(VDD#N1) U7.N9(VDD#N9) U7.R1(VDD#R1) U7.R9(VDD#R9) U8.2(VLDOIN) U90.A1(VDDQ#A1) U90.A8(VDDQ#A8) U90.B2(VDD#B2) U90.C1(VDDQ#C1) U90.C9(VDDQ#C9) U90.D2(VDDQ#D2) U90.D9(VDD#D9) U90.E9(VDDQ#E9) U90.F1(VDDQ#F1) U90.G7(VDD#G7) U90.H2(VDDQ#H2) U90.H9(VDDQ#H9) U90.K2(VDD#K2) U90.K8(VDD#K8) U90.N1(VDD#N1) U90.N9(VDD#N9) U90.R1(VDD#R1) U90.R9(VDD#R9) U91.A1(VDDQ#A1) U91.A8(VDDQ#A8) U91.B2(VDD#B2) U91.C1(VDDQ#C1) U91.C9(VDDQ#C9) U91.D2(VDDQ#D2) U91.D9(VDD#D9) U91.E9(VDDQ#E9) U91.F1(VDDQ#F1) U91.G7(VDD#G7) U91.H2(VDDQ#H2) U91.H9(VDDQ#H9) U91.K2(VDD#K2) U91.K8(VDD#K8) U91.N1(VDD#N1) U91.N9(VDD#N9) U91.R1(VDD#R1) U91.R9(VDD#R9) U92.2(VLDOIN)
AM57XX_CLKOUT3: R300.2(P2) R905.2(P2) R967.2 U1.C23(XREF_CLK3/CLKOUT3)
AM57XX_GPIO6_14: R685.2(P2) U1.E21(GPIO6_14)
AM57XX_GPIO6_15: R661.2(P2) U1.F20(GPIO6_15)
AM57XX_GPIO6_16: R666.2(P2) U1.F21(GPIO6_16)
AM57XX_GPIO_IND_LDN: R371.2(P2) R800.1 U1.AF4(VIN1A_D15/GPIO)
AM57XX_GPIO_RS485: R584.2(P2) U1.AA3(MCASP5_ACLKX/PR2_PRU1_R30_1)
AM57XX_GPMC_AD0: R434.1(P1) R453.2 R861.2(P2) U1.M6(GPMC_AD0/GPIO)
AM57XX_GPMC_AD1: R435.1(P1) R454.2 R862.2(P2) U1.M2(GPMC_AD1/GPIO)
AM57XX_GPMC_AD2: R436.1(P1) R455.2 R863.2(P2) U1.L5(GPMC_AD2/GPIO)
AM57XX_GPMC_AD3: R437.1(P1) R456.2 R864.2(P2) U1.M1(GPMC_AD3/GPIO)
AM57XX_GPMC_AD4: J21.51 R438.1(P1) R457.2 U1.L6(GPMC_AD4/GPIO)
AM57XX_GPMC_AD5: J21.53 R439.1(P1) R458.2 U1.L4(GPMC_AD5/GPIO)
AM57XX_GPMC_AD6: J21.55 R440.1(P1) R459.2 U1.L3(GPMC_AD6/GPIO)
AM57XX_GPMC_AD7: J21.57 R441.1(P1) R460.2 U1.L2(GPMC_AD7/GPIO)
AM57XX_GPMC_AD8: J21.32 R442.1(P1) R461.2 U1.L1(GPMC_AD8)
AM57XX_GPMC_AD9: J21.34 R443.1(P1) R462.2 U1.K2(GPMC_AD9)
AM57XX_GPMC_AD10: J21.36 R444.1(P1) R463.2 U1.J1(GPMC_AD10)
AM57XX_GPMC_AD11: J21.38 R445.1(P1) R464.2 U1.J2(GPMC_AD11)
AM57XX_GPMC_AD12: J21.42 R446.1(P1) R465.2 U1.H1(GPMC_AD12)
AM57XX_GPMC_AD13: J21.44 R447.1(P1) R466.2 U1.J3(GPMC_AD13)
AM57XX_GPMC_AD14: J21.46 R448.1(P1) R467.2 U1.H2(GPMC_AD14)
AM57XX_GPMC_AD15: J21.48 R449.1(P1) R468.2 U1.H3(GPMC_AD15)
AM57XX_HDMI_CLK+: L29.4 U1.AH16(HDMI1_CLOCKY)
AM57XX_HDMI_CLK-: L29.1 U1.AG16(HDMI1_CLOCKX)
AM57XX_HDMI_TX0+: L30.4 U1.AH17(HDMI1_DATA0Y)
AM57XX_HDMI_TX0-: L30.1 U1.AG17(HDMI1_DATA0X)
AM57XX_HDMI_TX1+: L31.4 U1.AH18(HDMI1_DATA1Y)
AM57XX_HDMI_TX1-: L31.1 U1.AG18(HDMI1_DATA1X)
AM57XX_HDMI_TX2+: L32.4 U1.AH19(HDMI1_DATA2Y)
AM57XX_HDMI_TX2-: L32.1 U1.AG19(HDMI1_DATA2X)
AM57XX_I2C1_SCL: R384.1(P1) R385.2(P2) R393.2(P2) U1.C20(I2C1_SCL)
AM57XX_I2C1_SDA: R383.1(P1) R387.2(P2) R394.2(P2) U1.C21(I2C1_SDA)
AM57XX_INDETHER_LED0_GRN: R247.1(P1) R803.2(P2)
AM57XX_INDETHER_LED0_RED: R976.1 U1.B26(XREF_CLK2)
AM57XX_INDETHER_LED0_YEL: R253.1(P1) R965.2 U1.D15(MCASP2_AXR4)
AM57XX_INDETHER_LED1_GRN: R248.1(P1) U1.B17(MCASP2_AXR6)
AM57XX_INDETHER_LED1_RED: R243.2(P2) R966.2 U1.B16(MCASP2_AXR5)
AM57XX_INDETHER_LED1_YEL: R968.1 U1.A17(MCASP2_AXR7)
AM57XX_INDETHER_LED2_GRN: R590.1(P1) U1.F16(SPI1_D1)
AM57XX_INDETHER_LED2_RED: R600.2(P2) U1.B25(SPI1_D0)
AM57XX_INDETHER_LED2_YEL: R594.1(P1) U1.A24(SPI1_CS0)
AM57XX_INDETHER_LED3_GRN: R593.1(P1) U1.AF6(VIN1A_D13)
AM57XX_INDETHER_LED3_RED: R514.2(P2) U1.A22(SPI1_CS1)
AM57XX_INDETHER_LED3_YEL: R598.1(P1) U1.AF3(VIN1A_D14)
AM57XX_LCD_DE: R634.2(P2) U1.B10(VOUT1_DE)
AM57XX_LCD_HSYNC: R636.2(P2) U1.C11(VOUT1_HSYNC)
AM57XX_LCD_PCLK: R565.2(P2) U1.D11(VOUT1_CLK)
AM57XX_LCD_VSYNC: R635.2(P2) U1.E11(VOUT1_VSYNC)
AM57XX_MCASP1_AXR4: R673.2(P2) U1.E12(MCASP1_AXR4)
AM57XX_MCASP1_AXR5: R674.2(P2) U1.F13(MCASP1_AXR5)
AM57XX_MCASP1_AXR6: R675.2(P2) U1.C12(MCASP1_AXR6)
AM57XX_MCASP1_AXR7: R676.2(P2) U1.D12(MCASP1_AXR7)
AM57XX_MMC1_CLK: R405.2(P2) U1.W6(MMC1_CLK)
AM57XX_MMC1_CMD: R404.2(P2) U1.Y6(MMC1_CMD)
AM57XX_MMC1_DAT0: R406.2(P2) U1.AA6(MMC1_DAT0)
AM57XX_MMC1_DAT1: R407.2(P2) U1.Y4(MMC1_DAT1)
AM57XX_MMC1_DAT2: R402.2(P2) U1.AA5(MMC1_DAT2)
AM57XX_MMC1_DAT3: R403.2(P2) U1.Y3(MMC1_DAT3)
AM57XX_MMC1_SDCD: R409.2(P2) U1.W7(MMC1_SDCD)
AM57XX_MMC1_SDWP: J44.1 R644.1 U1.Y9(MMC1_SDWP)
AM57XX_OSC0_IN: C2.1 R4.2(P2) U1.AE15(XI_OSC0) Y1.2
AM57XX_OSC0_OUT: R5.1(P1) U1.AD15(XO_OSC0)
AM57XX_PCIE_PERN0: J22.A17 U1.AG13(PCIE_RXN0)
AM57XX_PCIE_PERP0: J22.A16 U1.AH13(PCIE_RXP0)
AM57XX_PCIE_PETN0: C477.1 U1.AG14(PCIE_TXN0)
AM57XX_PCIE_PETP0: C478.1 U1.AH14(PCIE_TXP0)
AM57XX_PCIE_REF_CLKN: C438.2 R581.1(P1) U1.AH15(LJCB_CLKN)
AM57XX_PCIE_REF_CLKP: C439.2 R581.2(P2) U1.AG15(LJCB_CLKP)
AM57XX_PORZN: R6.1(P1) U1.F22(PORZ)
AM57XX_PR1_UART0_RXD: J21.47 R575.2(P2) U1.F2(VIN2A_D0/PR1_UART0_RXD)
AM57XX_PR1_UART0_TXD: J21.45 R199.2(P2) R574.2(P2) U1.F3(VIN2A_D1/PR1_UART0_TXD)
AM57XX_PR2_PROFI_TXEN: J21.49 U1.U3(RMII50MHZCLK/PR2_GPIO)
AM57XX_PRU1ETH0_MRCLK: R83.2(P2) U1.Y1(UART3_TXD/PR1_MII0_MR0CLK)
AM57XX_PRU1ETH0_RXDV: R86.2(P2) U1.V2(UART3_RXD/PR1_MII0_RXDV)
AM57XX_PRU1ETH1_MRCLK: R129.2(P2) R332.2 U1.C3(VIN2A_D14/RGMII1_TXD3)
AM57XX_PRU1ETH1_TXCLK: R123.2(P2) R746.2(P2) U1.C1(VIN2A_D6/PR1_MII_MT1_CLK)
AM57XX_PRU1ETH1_TXD0: R125.2(P2) R326.2 U1.C2(VIN2A_D13/RGMII1_TXCTL)
AM57XX_PRU1ETH1_TXD1: R126.2(P2) R325.2 U1.D5(VIN2A_D12/RGMII1_TXC)
AM57XX_PRU1ETH1_TXD2: R127.2(P2) U1.E6(VIN2A_D9/PR1_MII1_TXD2)
AM57XX_PRU1ETH1_TXD3: R128.2(P2) R747.2(P2) U1.F5(VIN2A_D8/PR1_MII1_TXD3)
AM57XX_PRU1ETH1_TXEN: R124.2(P2) U1.E4(VIN2A_D7/PR1_MII1_TXEN)
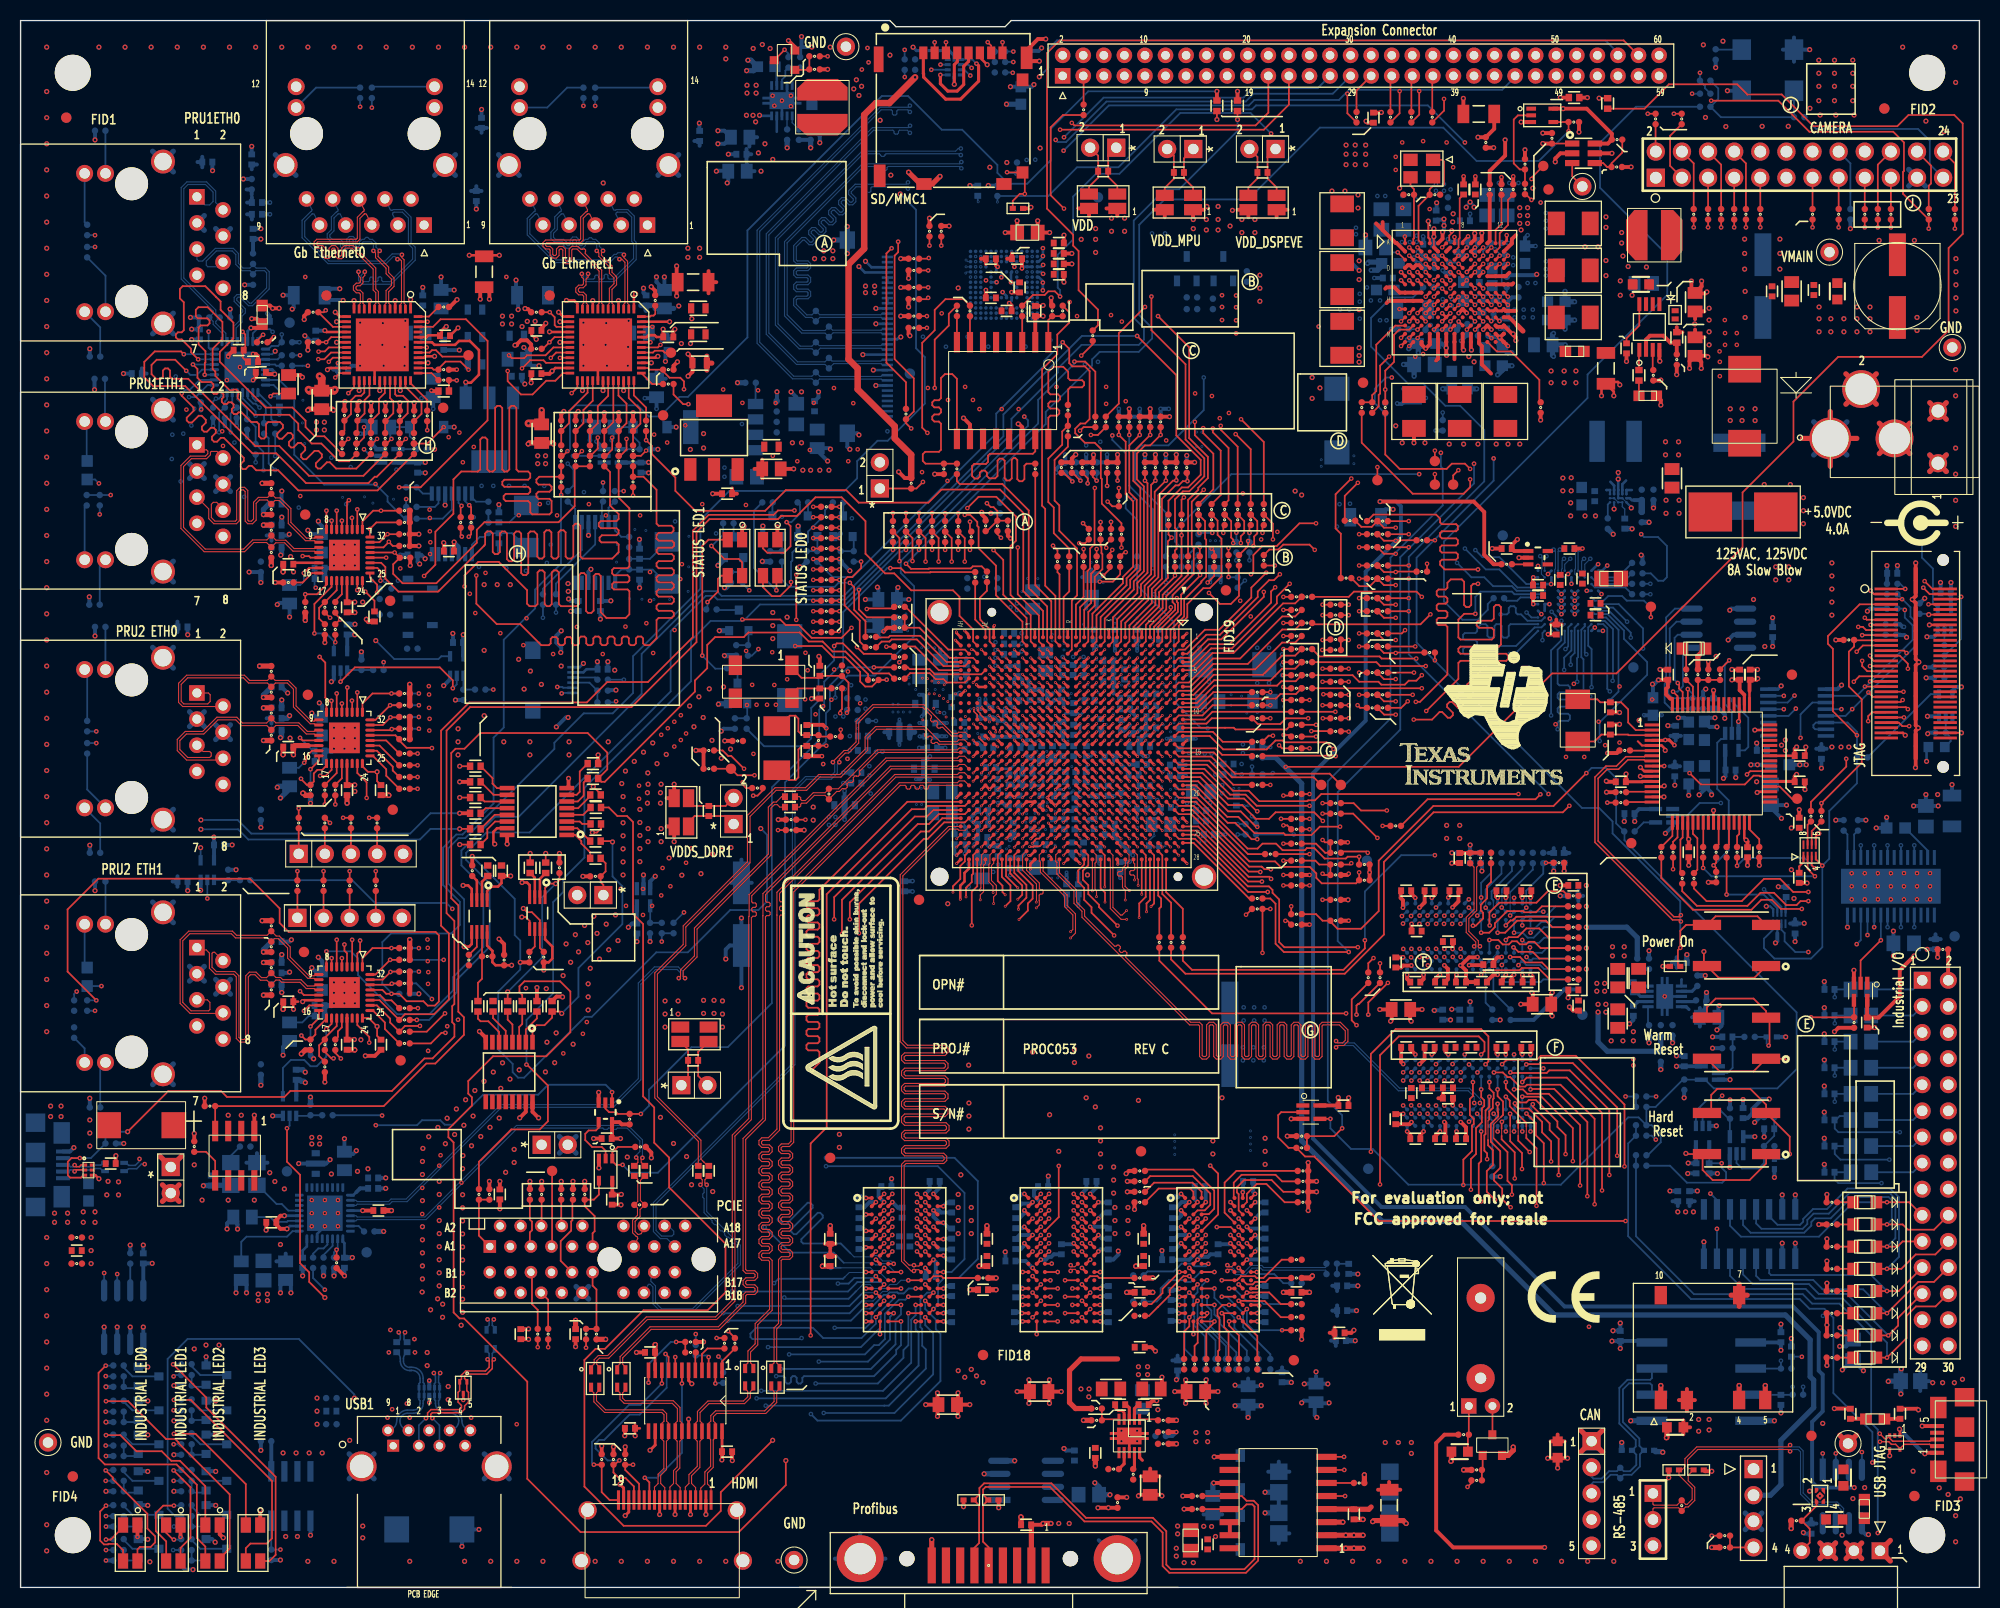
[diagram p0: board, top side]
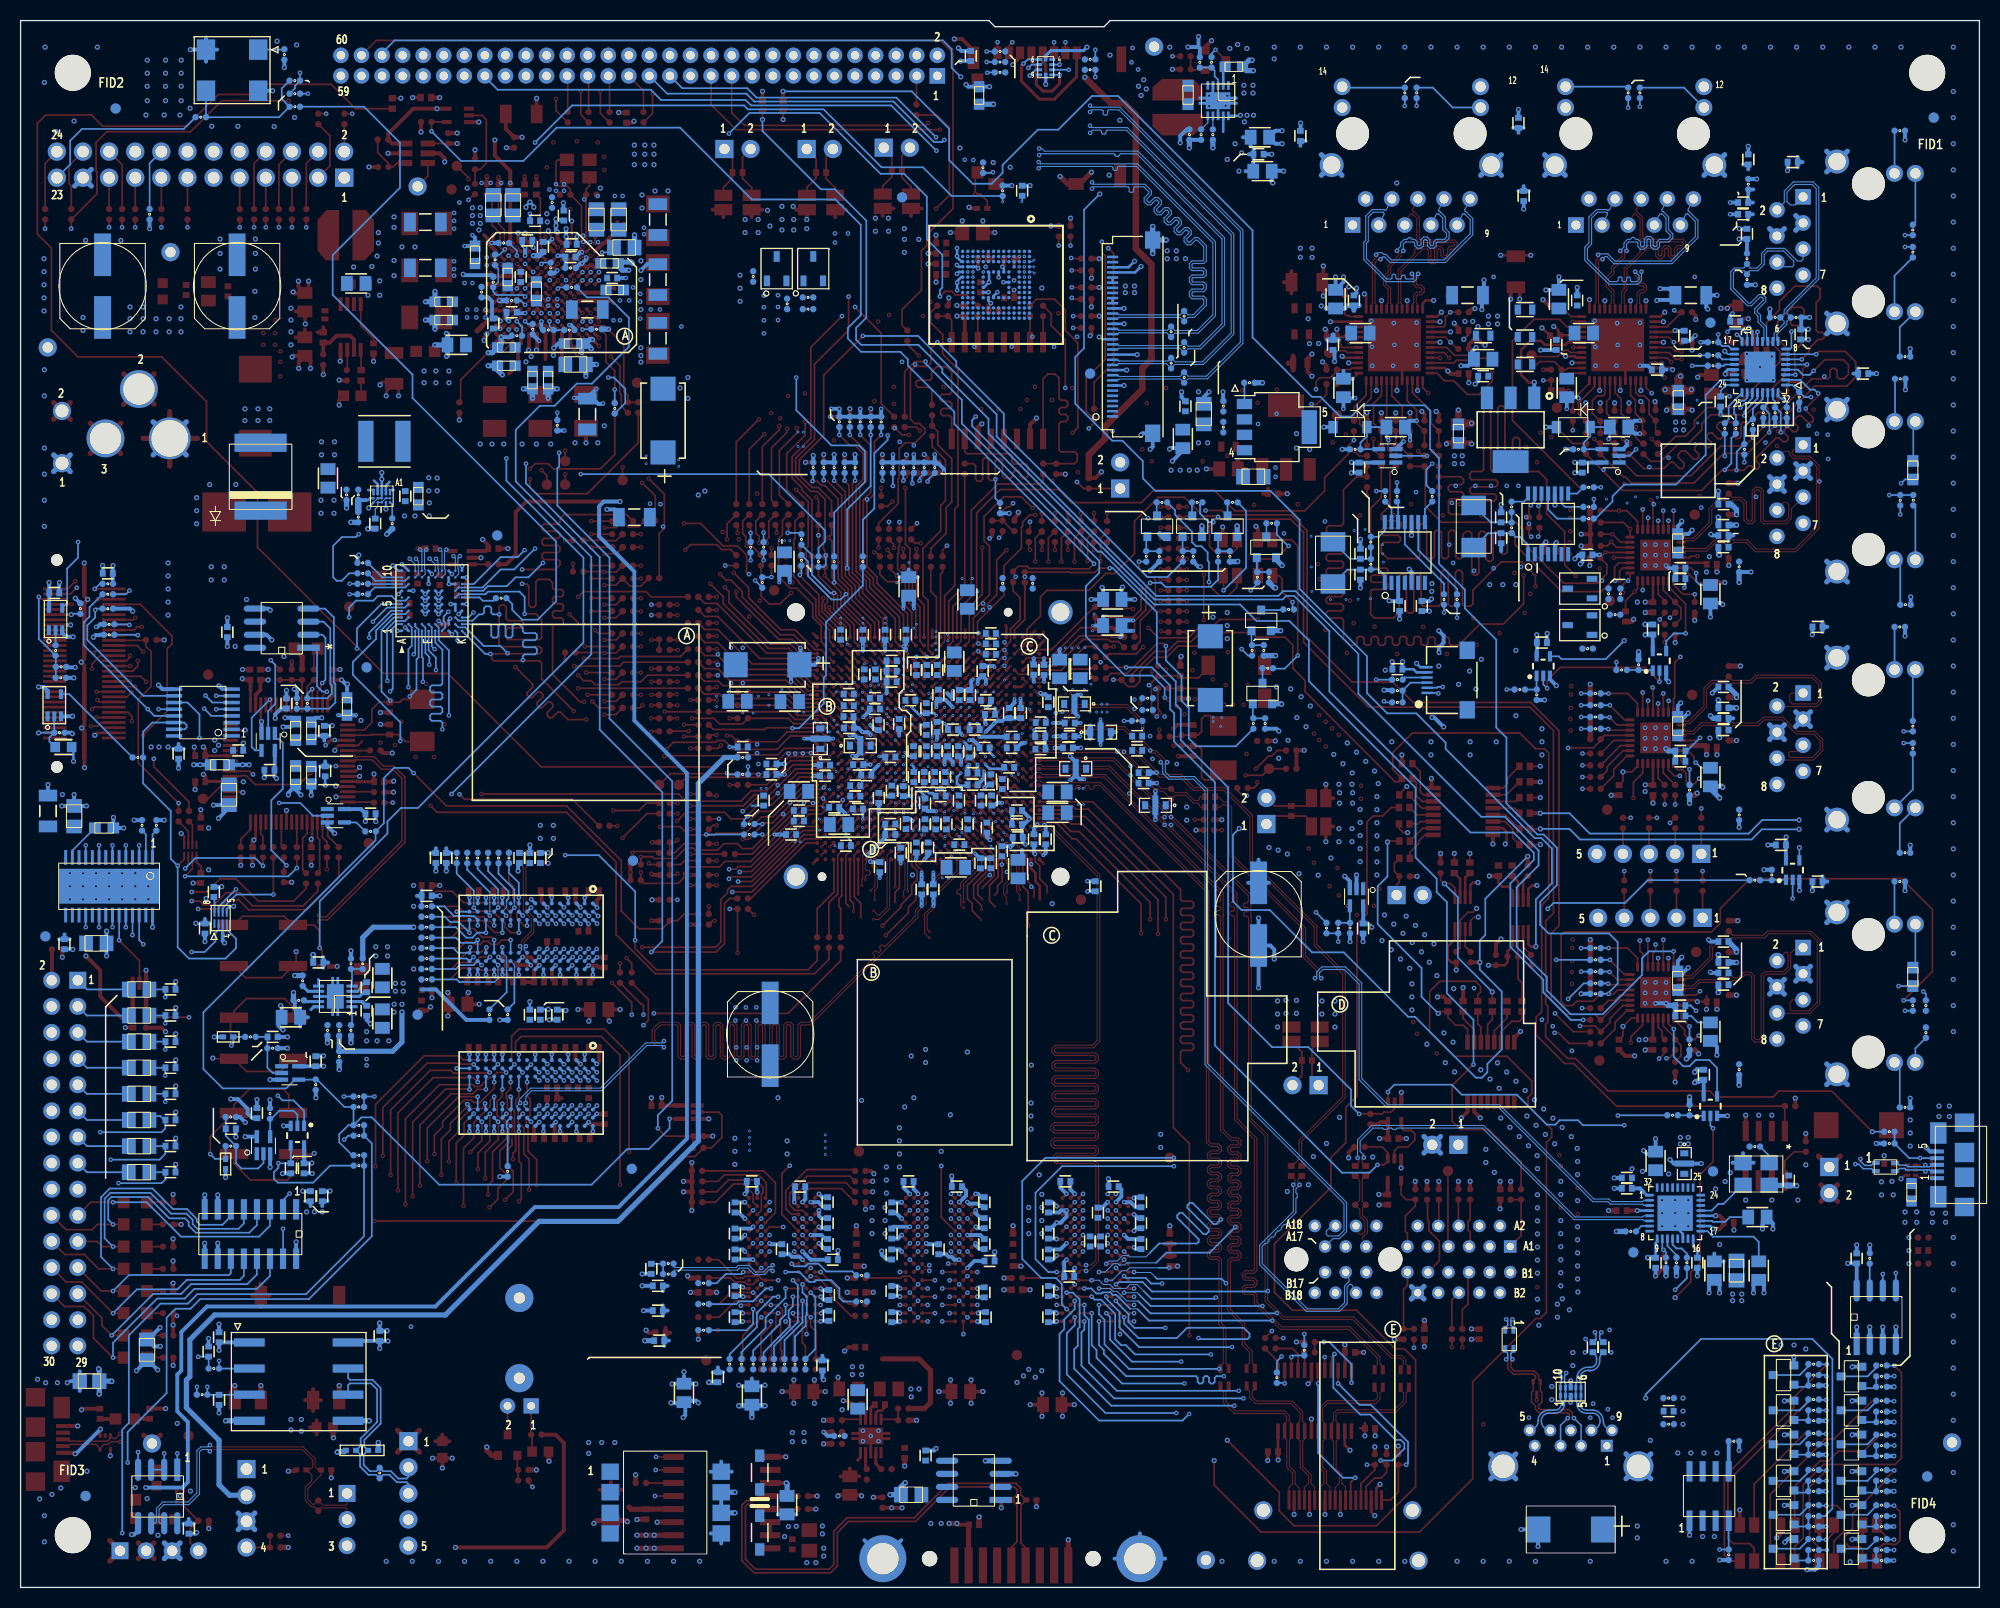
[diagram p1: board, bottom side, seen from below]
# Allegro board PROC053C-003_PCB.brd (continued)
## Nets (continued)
AM57XX_PRU1ETH_MDCLK: R96.2(P2) R140.2(P2) R748.2(P2) U1.D3(VIN2A_D10/PR1_MDIO_MDCLK)
AM57XX_PRU1ETH_MDDATA: R98.2(P2) R142.2(P2) U1.F6(VIN2A_D11/PR1_MDIO_DATA)
AM57XX_PRU2ETH0_COL: R953.1 U1.F15(MCASP3_FSX/PR2_MII0_COL)
AM57XX_PRU2ETH0_CRS: R177.2(P2) R952.1 U1.B18(MCASP3_ACLKX/PR2_MII0_CRS)
AM57XX_PRU2ETH0_MRCLK: R165.2(P2) U1.A13(MCASP1_AXR13/PR2_MII_MR0_CLK)
AM57XX_PRU2ETH0_RXD0: R171.2(P2) U1.C15(MCASP2_AXR2/PR2_MII0_RXD0)
AM57XX_PRU2ETH0_RXD1: R173.2(P2) U1.A18(MCASP2_FSX/PR2_MII0_RXD1)
AM57XX_PRU2ETH0_RXD2: R174.2(P2) U1.A19(MCASP2_ACLKX/PR2_MII0_RXD2)
AM57XX_PRU2ETH0_RXD3: R175.2(P2) U1.F14(MCASP1_AXR15/PR2_MII0_RXD3)
AM57XX_PRU2ETH0_RXDV: R166.2(P2) R197.2(P2) U1.G14(MCASP1_AXR14/PR2_MII0_RXDV)
AM57XX_PRU2ETH0_RXER: R170.2(P2) U1.G12(MCASP1_AXR0/PR2_MII0_RXER)
AM57XX_PRU2ETH0_RXLINK: R188.2(P2) U1.A16(MCASP2_AXR3/PR2_MII0_RXLINK)
AM57XX_PRU2ETH0_TXCLK: R162.2(P2) U1.F12(MCASP1_AXR1/PR2_MII_MT0_CLK)
AM57XX_PRU2ETH0_TXD0: R163.2(P2) U1.E14(MCASP1_AXR12/PR2_MII0_TXD0)
AM57XX_PRU2ETH0_TXD1: R164.2(P2) U1.A12(MCASP1_AXR11/PR2_MII0_TXD1)
AM57XX_PRU2ETH0_TXD2: R168.2(P2) U1.B13(MCASP1_AXR10/PR2_MII0_TXD2)
AM57XX_PRU2ETH0_TXD3: R169.2(P2) U1.A11(MCASP1_AXR9/PR2_MII0_TXD3)
AM57XX_PRU2ETH0_TXEN: R167.2(P2) R196.2(P2) U1.B12(MCASP1_AXR8/PR2_MII0_TXEN)
AM57XX_PRU2ETH1_COL: R220.2(P2) R950.1 U1.D18(XREF_CLK0/PR2_MII1_COL)
AM57XX_PRU2ETH1_CRS: R219.2(P2) R951.1 U1.E17(XREF_CLK1/PR2_MII1_CRS)
AM57XX_PRU2ETH1_MRCLK: R209.2(P2) U1.AC9(MMC3_DAT2/PR2_MII_MR1_CLK)
AM57XX_PRU2ETH1_RXD0: R213.2(P2) U1.AB5(MMC3_DAT7/PR2_MII1_RXD0)
AM57XX_PRU2ETH1_RXD1: R215.2(P2) U1.AB8(MMC3_DAT6/PR2_MII1_RXD1)
AM57XX_PRU2ETH1_RXD2: R216.2(P2) U1.AD6(MMC3_DAT5/PR2_MII1_RXD2)
AM57XX_PRU2ETH1_RXD3: R217.2(P2) U1.AC8(MMC3_DAT4/PR2_MII1_RXD3)
AM57XX_PRU2ETH1_RXDV: R211.2(P2) U1.AC3(MMC3_DAT3/PR2_MII1_RXDV)
AM57XX_PRU2ETH1_RXER: R212.2(P2) U1.B19(MCASP3_AXR0/PR2_MII1_RXER)
AM57XX_PRU2ETH1_TXCLK: R204.2(P2) U1.AC5(GPIO6_10/PR2_MII_MT1_CLK)
AM57XX_PRU2ETH1_TXD0: R206.2(P2) U1.AC6(MMC3_DAT1/PR2_MII1_TXD0)
AM57XX_PRU2ETH1_TXD1: R208.2(P2) U1.AC7(MMC3_DAT0/PR2_MII1_TXD1)
AM57XX_PRU2ETH1_TXD2: R210.2(P2) U1.AC4(MMC3_CMD/PR2_MII1_TXD2)
AM57XX_PRU2ETH1_TXD3: R207.2(P2) U1.AD4(MMC3_CLK/PR2_MII1_TXD3)
AM57XX_PRU2ETH1_TXEN: R205.2(P2) U1.AB4(GPIO6_11/PR2_MII1_TXEN)
AM57XX_PRU2ETH_MDCLK: R179.2(P2) R221.2(P2) U1.C14(MCASP1_ACLKX/PR2_MDIO_MDCLK)
AM57XX_PRU2ETH_MDDATA: R181.2(P2) R223.2(P2) U1.D14(MCASP1_FSX/PR2_MDIO_DATA)
AM57XX_RGMII0_RD0: R81.2(P2) R289.2 U1.W2(RGMII0_RXD0)
AM57XX_RGMII0_RD1: R84.2(P2) R290.2 U1.Y2(RGMII0_RXD1)
AM57XX_RGMII0_RD2: R80.2(P2) R291.2 U1.V3(RGMII0_RXD2)
AM57XX_RGMII0_RD3: R85.2(P2) R292.2 U1.V4(RGMII0_RXD3)
AM57XX_RGMII0_RXCLK: R79.2(P2) R288.2 U1.U5(RGMII0_RXC)
AM57XX_RGMII0_RXCTL: R82.2(P2) R285.2 U1.V5(RGMII0_RXCTL)
AM57XX_RGMII0_TD0: R88.2(P2) R282.2 U1.U6(RGMII0_TXD0)
AM57XX_RGMII0_TD1: R90.2(P2) R287.2 U1.V6(RGMII0_TXD1)
AM57XX_RGMII0_TD2: R87.2(P2) R283.2 U1.U7(RGMII0_TXD2)
AM57XX_RGMII0_TD3: R94.2(P2) R284.2 U1.V7(RGMII0_TXD3)
AM57XX_RGMII0_TXCLK: R92.2(P2) R281.2 U1.W9(RGMII0_TXC)
AM57XX_RGMII0_TXCTL: R91.2(P2) R286.2 U1.V9(RGMII0_TXCTL)
AM57XX_RGMII1_RD0: R139.2(P2) R333.2 U1.A4(VIN2A_D23/RGMII1_RXD0)
AM57XX_RGMII1_RD1: R148.2(P2) R334.2 U1.B5(VIN2A_D22/RGMII1_RXD1)
AM57XX_RGMII1_RD2: R150.2(P2) R335.2 U1.B4(VIN2A_D21/RGMII1_RXD2)
AM57XX_RGMII1_RD3: R132.2(P2) R336.2 U1.B3(VIN2A_D20/RGMII1_RXD3)
AM57XX_RGMII1_RXCLK: R135.2(P2) R328.2 U1.C5(VIN2A_D18/RGMII1_RXC)
AM57XX_RGMII1_RXCTL: R133.2(P2) R329.2 U1.A3(VIN2A_D19/RGMII1_RXCTL)
AM57XX_RGMII1_TD0: R136.2(P2) R330.2 U1.D6(VIN2A_D17/RGMII1_TXD0)
AM57XX_RGMII1_TD1: R137.2(P2) R331.2 U1.B2(VIN2A_D16/RGMII1_TXD1)
AM57XX_RGMII1_TD2: R130.2(P2) R327.2 U1.C4(VIN2A_D15/RGMII1_TXD2)
AM57XX_RSTOUTN: R36.2(P2) R922.2(P2) U1.F23(RSTOUTN) U47.2(A)
AM57XX_RTCK: R426.2 U1.E18(RTCK)
AM57XX_SPI1_CS0: R369.2(P2) U1.D17(MCASP4_AXR1/SPI3_CS0)
AM57XX_SPI1_D1: R377.2(P2) U1.A21(MCASP4_FSX/SPI3_D1)
AM57XX_SPI1_SCLK: R367.2(P2) U1.C18(MCASP4_ACLKX/SPI3_SCLK)
AM57XX_SPI2_SCLK: R684.1(P1) U1.A26(SPI2_SCLK)
AM57XX_STATUSLED0_GRN: R701.1(P1) R736.2(P2)
AM57XX_STATUSLED0_RED: R698.2(P2) R735.2(P2)
AM57XX_STATUSLED0_YEL: R694.1(P1) R737.2(P2)
AM57XX_STATUSLED1_GRN: R710.1(P1) R739.2(P2)
AM57XX_STATUSLED1_RED: R707.2(P2) R738.2(P2)
AM57XX_STATUSLED1_YEL: R703.1(P1) R740.2(P2)
AM57XX_UART2_RXD: R583.2(P2) U1.D28(UART2_RXD)
AM57XX_UART2_TXD: R582.2(P2) U1.D26(UART2_TXD)
AM57XX_UART3_RXD: R487.1(P1) U1.D27(UART2_CTSN/UART3_RXD)
AM57XX_UART3_TXD: R486.1(P1) U1.C28(UART2_RTSN/UART3_TXD)
AM57XX_VIN2A_CLK0: R669.1(P1) U1.E1(VIN2A_CLK0)
AM57XX_VIN2A_DE0: R119.2(P2) R670.1(P1) U1.G2(VIN2A_DE0)
AM57XX_VIN2A_FLD0: R671.1(P1) U1.H7(VIN2A_FLD0)
AM57XX_VIN2A_HSYNC0: R118.2(P2) R672.1(P1) U1.G1(VIN2A_HSYNC0)
AM57XX_VIN2A_VSYNC0: R198.2(P2) R735.1(P1) U1.G6(VIN2A_VSYNC0)
AM57XX_VOUT1_D0: R605.2(P2) U1.F11(VOUT1_D0)
AM57XX_VOUT1_D1: R606.2(P2) U1.G10(VOUT1_D1)
AM57XX_VOUT1_D2: R607.2(P2) R711.2(P2) U1.F10(VOUT1_D2)
AM57XX_VOUT1_D3: R608.2(P2) R714.2(P2) U1.G11(VOUT1_D3)
AM57XX_VOUT1_D4: R609.2(P2) R715.2(P2) U1.E9(VOUT1_D4)
AM57XX_VOUT1_D5: R610.2(P2) R716.2(P2) R910.2(P2) U1.F9(VOUT1_D5)
AM57XX_VOUT1_D6: R612.2(P2) R717.2(P2) R911.2(P2) U1.F8(VOUT1_D6)
AM57XX_VOUT1_D7: R611.2(P2) R718.2(P2) R908.2(P2) U1.E7(VOUT1_D7)
AM57XX_VOUT1_D8: R613.2(P2) R909.2(P2) U1.E8(VOUT1_D8)
AM57XX_VOUT1_D9: R614.2(P2) U1.D9(VOUT1_D9)
AM57XX_VOUT1_D10: R616.2(P2) R712.2(P2) U1.D7(VOUT1_D10)
AM57XX_VOUT1_D11: R615.2(P2) R719.2(P2) U1.D8(VOUT1_D11)
AM57XX_VOUT1_D12: R617.2(P2) R720.2(P2) U1.A5(VOUT1_D12)
AM57XX_VOUT1_D13: R619.2(P2) R721.2(P2) R906.2(P2) U1.C6(VOUT1_D13)
AM57XX_VOUT1_D14: R620.2(P2) R722.2(P2) R907.2(P2) U1.C8(VOUT1_D14)
AM57XX_VOUT1_D15: R618.2(P2) R723.2(P2) U1.C7(VOUT1_D15)
AM57XX_VOUT1_D16: R621.2(P2) U1.B7(VOUT1_D16)
AM57XX_VOUT1_D17: R622.2(P2) U1.B8(VOUT1_D17)
AM57XX_VOUT1_D18: R624.2(P2) R713.2(P2) U1.A7(VOUT1_D18)
AM57XX_VOUT1_D19: R623.2(P2) R724.2(P2) U1.A8(VOUT1_D19)
AM57XX_VOUT1_D20: R625.2(P2) R725.2(P2) U1.C9(VOUT1_D20)
AM57XX_VOUT1_D21: R627.2(P2) R726.2(P2) U1.A9(VOUT1_D21)
AM57XX_VOUT1_D22: R628.2(P2) R727.2(P2) U1.B9(VOUT1_D22)
AM57XX_VOUT1_D23: R626.2(P2) R728.2(P2) U1.A10(VOUT1_D23)
AM57XX_VOUT1_FLD: R564.1(P1) U1.B11(VOUT1_FLD)
AM574X_DCAN1_RX: C253.1 R502.1 U1.G19(DCAN1_RX)
AM574X_DCAN1_TX: R504.1 U1.G20(DCAN1_TX)
AM574X_HAPTICS_TRIG: R114.1(P1) U1.A25(SPI1_SCLK)
AM574X_HDMI_CEC: R683.2(P2) R805.1 U1.B20(SPI1_CS3/HDMI_CEC)
AM574X_HDMI_DDC_SCL: R358.2(P2) R556.1(P1) R795.2(P2) U1.C25(I2C2_SDA/HDMI1_DDC_SCL)
AM574X_HDMI_DDC_SDA: R356.2(P2) R563.1(P1) R796.2(P2) U1.F17(I2C2_SCL/HDMI1_DDC_SDA)
AM574X_HDMI_HPD: R682.2(P2) R804.1 U1.B21(SPI1_CS2/HDMI_HPD)
AM574X_QSPI_CLK: R24.2(P2) U1.R2(GPMC_A18/QSPI1_SCLK)
AM574X_QSPI_CSN: R30.2(P2) U1.P2(GPMC_CS2/QSPI1_CS0)
AM574X_QSPI_D0: R25.2(P2) U1.U1(GPMC_A16/QSPI1_D0)
AM574X_QSPI_D1: R26.2(P2) U1.P3(GPMC_A17/QSPI1_D1)
AM574X_QSPI_D2: R27.2(P2) U1.U2(GPMC_A15/QSPI_D2)
AM574X_QSPI_D3: R28.2(P2) U1.T2(GPMC_A14/QSPI_D3)
AM574X_QSPI_RTCLK: R23.2(P2) U1.R3(GPMC_A13/QSPI_RTCLK)
AM574X_USB1_3_0_STDA_SSTX+: C555.1 U1.AD11(USB_TXP0)
AM574X_USB1_3_0_STDA_SSTX-: C554.1 U1.AC11(USB_TXN0)
AM574X_USB1_DM: L11.1 U1.AC12(USB1_DM)
AM574X_USB1_DP: L11.2 U1.AD12(USB1_DP)
AM574X_USB1_DRVVBUS: R557.2(P2) R979.1 U1.AB10(USB1_DRVVBUS)
AM574X_USB2_DM: L33.2 U1.AF11(USB2_DM)
AM574X_USB2_DP: L33.1 U1.AE11(USB2_DP)
AM574X_USB2_DRVVBUS: R787.2(P2) R972.1 U1.AC10(USB2_DRVVBUS)
AM574X_VIN4B_DATA0: R260.2(P2) U1.R6(GPMC_A0/VIN4B_D0)
AM574X_VIN4B_DATA1: R261.2(P2) U1.T9(GPMC_A1/VIN4B_D1)
AM574X_VIN4B_DATA2: R263.2(P2) U1.T6(GPMC_A2/VIN4B_D2)
AM574X_VIN4B_DATA3: R267.2(P2) U1.T7(GPMC_A3/VIN4B_D3)
AM574X_VIN4B_DATA4: R269.2(P2) U1.P6(GPMC_A4/VIN4B_D4)
AM574X_VIN4B_DATA5: R271.2(P2) U1.R9(GPMC_A5/VIN4B_D5)
AM574X_VIN4B_DATA6: R262.1(P1) U1.R5(GPMC_A6/VIN4B_D6)
AM574X_VIN4B_DATA7: R264.1(P1) U1.P5(GPMC_A7/VIN4B_D7)
AM574X_VIN4B_DE: R273.2(P2) U1.P9(GPMC_A11/VIN4B_DE1)
AM574X_VIN4B_FLD: R274.1(P1) U1.P4(GPMC_A12/VIN4B_FLD1)
AM574X_VIN4B_HSYNC: R258.1(P1) U1.N7(GPMC_A8/VIN4B_HSYNC1)
AM574X_VIN4B_PCLK: R265.2(P2) U1.N9(GPMC_A10/VIN4B_CLK1)
AM574X_VIN4B_VSYNC: R257.1(P1) U1.R4(GPMC_A9/VIN4B_VSYNC1)
BKLT_EN: Q9.G(GATE) R412.1 R416.1(P1)
BKLT_L: L1.1 U32.1(L)
BKLT_SW: L1.2 U32.10(SW)
BUFFER_OE_S20: R945.1 R961.2 U103.7(2O\E\)
BUFFER_OE_T16: R939.1 R959.2 U102.1(1O\E\)
BUFFER_OE_T16_2: R941.1 R974.1 U102.7(2O\E\)
CAM1_DATA0: J9.3 R260.1(P1)
CAM1_DATA1: J9.5 R261.1(P1)
CAM1_DATA2: J9.7 R263.1(P1)
CAM1_DATA3: J9.13 R267.1(P1)
CAM1_DATA4: J9.15 R269.1(P1)
CAM1_DATA5: J9.17 R271.1(P1)
CAM1_DATA6: J9.6 R262.2(P2)
CAM1_DATA7: J9.8 R264.2(P2)
CAM1_FIELD: J9.20 R274.2(P2)
CAM1_GIO0: J9.16 R259.1
CAM1_HSYNC: J9.4 R258.2(P2)
CAM1_PCLK: J9.9 R265.1(P1)
CAM1_VSYNC: J9.2 R257.2(P2)
CAM1_WEN: J9.19 R273.1(P1)
CAM_ENN: J9.18 R685.1(P1)
CAN1_H: J38.2 R503.2(P2) U41.7(CANH) U88.1
CAN1_L: J38.3 R503.1(P1) U41.6(CANL) U87.1
CAN1_RXDF: J21.41 R502.2 U41.2(RXD)
CAN1_TXDF: C254.1 J21.43 R504.2 U41.3(TXD)
DDR2_A0: R761.2(P2) U1.R25(DDR2_A0) U90.N3(A0) U91.N3(A0)
DDR2_A1: R763.2(P2) U1.R26(DDR2_A1) U90.P7(A1) U91.P7(A1)
DDR2_A2: R762.2(P2) U1.R28(DDR2_A2) U90.P3(A2) U91.P3(A2)
DDR2_A3: R765.2(P2) U1.R27(DDR2_A3) U90.N2(A3) U91.N2(A3)
DDR2_A4: R764.2(P2) U1.P23(DDR2_A4) U90.P8(A4) U91.P8(A4)
DDR2_A5: R766.2(P2) U1.P22(DDR2_A5) U90.P2(A5) U91.P2(A5)
DDR2_A6: R768.2(P2) U1.P25(DDR2_A6) U90.R8(A6) U91.R8(A6)
DDR2_A7: R767.2(P2) U1.N20(DDR2_A7) U90.R2(A7) U91.R2(A7)
DDR2_A8: R770.2(P2) U1.P27(DDR2_A8) U90.T8(A8) U91.T8(A8)
DDR2_A9: R769.2(P2) U1.N27(DDR2_A9) U90.R3(A9) U91.R3(A9)
DDR2_A10: R771.2(P2) U1.N23(DDR2_A10) U90.L7(A10_AP) U91.L7(A10_AP)
DDR2_A11: R773.2(P2) U1.P26(DDR2_A11) U90.R7(A11) U91.R7(A11)
DDR2_A12: R772.2(P2) U1.N28(DDR2_A12) U90.N7(A12/\B\C\) U91.N7(A12/\B\C\)
DDR2_A13: R775.2(P2) U1.T22(DDR2_A13) U90.T3(A13) U91.T3(A13)
DDR2_A14: R774.2(P2) U1.R22(DDR2_A14) U90.T7(A14) U91.T7(A14)
DDR2_A15: R807.2(P2) U1.U22(DDR2_A15) U90.M7(NC5) U91.M7(NC5)
DDR2_BA0: R777.2(P2) U1.U23(DDR2_BA0) U90.M2(BA0) U91.M2(BA0)
DDR2_BA1: R776.2(P2) U1.U27(DDR2_BA1) U90.N8(BA1) U91.N8(BA1)
DDR2_BA2: R779.2(P2) U1.U26(DDR2_BA2) U90.M3(BA2) U91.M3(BA2)
DDR2_CASN: R759.2(P2) U1.U28(DDR2_CASN) U90.K3(\\C\A\S\) U91.K3(\\C\A\S\)
DDR2_CKE: R756.2(P2) U1.U24(DDR2_CKE) U90.K9(CKE) U91.K9(CKE)
DDR2_CLK: R780.2(P2) U1.T28(DDR2_CK) U90.J7(CK) U91.J7(CK)
DDR2_CLKN: R781.2(P2) U1.T27(DDR2_CKN) U90.K7(\\C\K\) U91.K7(\\C\K\)
DDR2_CS0N: R757.2(P2) U1.P24(DDR2_CSN0) U90.L2(\\C\S\) U91.L2(\\C\S\)
DDR2_D0: U1.E26(DDR2_D0) U90.E3(DQ0)
DDR2_D1: U1.G25(DDR2_D1) U90.F2(DQ2)
DDR2_D2: U1.F25(DDR2_D2) U90.G2(DQ6)
DDR2_D3: U1.F24(DDR2_D3) U90.H3(DQ4)
DDR2_D4: U1.F26(DDR2_D4) U90.F7(DQ1)
DDR2_D5: U1.F27(DDR2_D5) U90.H8(DQ5)
DDR2_D6: U1.E27(DDR2_D6) U90.F8(DQ3)
DDR2_D7: U1.E28(DDR2_D7) U90.H7(DQ7)
DDR2_D8: U1.H23(DDR2_D8) U90.D7(DQ8)
DDR2_D9: U1.H25(DDR2_D9) U90.A2(DQ13)
DDR2_D10: U1.H24(DDR2_D10) U90.C3(DQ9)
DDR2_D11: U1.H26(DDR2_D11) U90.A3(DQ15)
DDR2_D12: U1.G26(DDR2_D12) U90.C2(DQ11)
DDR2_D13: U1.J25(DDR2_D13) U90.B8(DQ14)
DDR2_D14: U1.J26(DDR2_D14) U90.A7(DQ12)
DDR2_D15: U1.J24(DDR2_D15) U90.C8(DQ10)
DDR2_D16: U1.L22(DDR2_D16) U91.E3(DQ0)
DDR2_D17: U1.K20(DDR2_D17) U91.H8(DQ5)
DDR2_D18: U1.K21(DDR2_D18) U91.H3(DQ4)
DDR2_D19: U1.L23(DDR2_D19) U91.F7(DQ1)
DDR2_D20: U1.L24(DDR2_D20) U91.F8(DQ3)
DDR2_D21: U1.J23(DDR2_D21) U91.F2(DQ2)
DDR2_D22: U1.K22(DDR2_D22) U91.G2(DQ6)
DDR2_D23: U1.J20(DDR2_D23) U91.H7(DQ7)
DDR2_D24: U1.L27(DDR2_D24) U91.D7(DQ8)
DDR2_D25: U1.L26(DDR2_D25) U91.A3(DQ15)
DDR2_D26: U1.L25(DDR2_D26) U91.C2(DQ11)
DDR2_D27: U1.L28(DDR2_D27) U91.A7(DQ12)
DDR2_D28: U1.M23(DDR2_D28) U91.C8(DQ10)
DDR2_D29: U1.M24(DDR2_D29) U91.A2(DQ13)
DDR2_D30: U1.M25(DDR2_D30) U91.C3(DQ9)
DDR2_D31: U1.M26(DDR2_D31) U91.B8(DQ14)
DDR2_DQM0: U1.F28(DDR2_DQM0) U90.E7(LDM)
DDR2_DQM1: U1.G24(DDR2_DQM1) U90.D3(UDM)
DDR2_DQM2: U1.K23(DDR2_DQM2) U91.E7(LDM)
DDR2_DQM3: U1.M22(DDR2_DQM3) U91.D3(UDM)
DDR2_DQS0: U1.G28(DDR2_DQS0) U90.F3(LDQS)
DDR2_DQS1: U1.H27(DDR2_DQS1) U90.C7(UDQS)
DDR2_DQS2: U1.K27(DDR2_DQS2) U91.F3(LDQS)
DDR2_DQS3: U1.M28(DDR2_DQS3) U91.C7(UDQS)
DDR2_DQSN0: U1.G27(DDR2_DQS0N) U90.G3(\\L\D\Q\S\)
DDR2_DQSN1: U1.H28(DDR2_DQS1N) U90.B7(\\U\D\Q\S\)
DDR2_DQSN2: U1.K28(DDR2_DQS2N) U91.G3(\\L\D\Q\S\)
DDR2_DQSN3: U1.M27(DDR2_DQS3N) U91.B7(\\U\D\Q\S\)
DDR2_ODT: R778.2(P2) U1.R23(DDR2_ODT0) U90.K1(ODT) U91.K1(ODT)
DDR2_RASN: R758.2(P2) U1.T23(DDR2_RASN) U90.J3(\\R\A\S\) U91.J3(\\R\A\S\)
DDR2_RESETN: R913.2 U1.R24(DDR2_RST) U90.T2(\\R\E\S\E\T\) U91.T2(\\R\E\S\E\T\)
DDR2_WEN: R760.2(P2) U1.U25(DDR2_WEN) U90.L3(\\W\E\) U91.L3(\\W\E\)
DDR_A0: R54.2(P2) U1.AD20(DDR1_A0) U5.N3(A0) U6.N3(A0) U7.N3(A0)
DDR_A1: R57.2(P2) U1.AC19(DDR1_A1) U5.P7(A1) U6.P7(A1) U7.P7(A1)
DDR_A2: R55.2(P2) U1.AC20(DDR1_A2) U5.P3(A2) U6.P3(A2) U7.P3(A2)
DDR_A3: R58.2(P2) U1.AB19(DDR1_A3) U5.N2(A3) U6.N2(A3) U7.N2(A3)
DDR_A4: R59.2(P2) U1.AF21(DDR1_A4) U5.P8(A4) U6.P8(A4) U7.P8(A4)
DDR_A5: R60.2(P2) U1.AH22(DDR1_A5) U5.P2(A5) U6.P2(A5) U7.P2(A5)
DDR_A6: R61.2(P2) U1.AG23(DDR1_A6) U5.R8(A6) U6.R8(A6) U7.R8(A6)
DDR_A7: R62.2(P2) U1.AE21(DDR1_A7) U5.R2(A7) U6.R2(A7) U7.R2(A7)
DDR_A8: R63.2(P2) U1.AF22(DDR1_A8) U5.T8(A8) U6.T8(A8) U7.T8(A8)
DDR_A9: R64.2(P2) U1.AE22(DDR1_A9) U5.R3(A9) U6.R3(A9) U7.R3(A9)
DDR_A10: R66.2(P2) U1.AD21(DDR1_A10) U5.L7(A10_AP) U6.L7(A10_AP) U7.L7(A10_AP)
DDR_A11: R65.2(P2) U1.AD22(DDR1_A11) U5.R7(A11) U6.R7(A11) U7.R7(A11)
DDR_A12: R68.2(P2) U1.AC21(DDR1_A12) U5.N7(A12/\B\C\) U6.N7(A12/\B\C\) U7.N7(A12/\B\C\)
DDR_A13: R70.2(P2) U1.AF18(DDR1_A13) U5.T3(A13) U6.T3(A13) U7.T3(A13)
DDR_A14: R71.2(P2) U1.AE17(DDR1_A14) U5.T7(A14) U6.T7(A14) U7.T7(A14)
DDR_A15: R806.2(P2) U1.AD18(DDR1_A15) U5.M7(NC5) U6.M7(NC5) U7.M7(NC5)
DDR_BA0: R72.2(P2) U1.AF17(DDR1_BA0) U5.M2(BA0) U6.M2(BA0) U7.M2(BA0)
DDR_BA1: R73.2(P2) U1.AE18(DDR1_BA1) U5.N8(BA1) U6.N8(BA1) U7.N8(BA1)
DDR_BA2: R74.2(P2) U1.AB18(DDR1_BA2) U5.M3(BA2) U6.M3(BA2) U7.M3(BA2)
DDR_CASN: R52.2(P2) U1.AC18(DDR1_CASN) U5.K3(\\C\A\S\) U6.K3(\\C\A\S\) U7.K3(\\C\A\S\)
DDR_CKE: R49.2(P2) U1.AG22(DDR1_CKE) U5.K9(CKE) U6.K9(CKE) U7.K9(CKE)
DDR_CLK: R46.2(P2) U1.AG24(DDR1_CK) U5.J7(CK) U6.J7(CK) U7.J7(CK)
DDR_CLKN: R47.2(P2) U1.AH24(DDR1_CKN) U5.K7(\\C\K\) U6.K7(\\C\K\) U7.K7(\\C\K\)
DDR_CS0N: R50.2(P2) U1.AH23(DDR1_CSN0) U5.L2(\\C\S\) U6.L2(\\C\S\) U7.L2(\\C\S\)
DDR_D0: U1.AF25(DDR1_D0) U5.E3(DQ0)
DDR_D1: U1.AF26(DDR1_D1) U5.F7(DQ1)
DDR_D2: U1.AG26(DDR1_D2) U5.F8(DQ3)
DDR_D3: U1.AH26(DDR1_D3) U5.H8(DQ5)
DDR_D4: U1.AF24(DDR1_D4) U5.F2(DQ2)
DDR_D5: U1.AE24(DDR1_D5) U5.G2(DQ6)
DDR_D6: U1.AF23(DDR1_D6) U5.H3(DQ4)
DDR_D7: U1.AE23(DDR1_D7) U5.H7(DQ7)
DDR_D8: U1.AC23(DDR1_D8) U5.D7(DQ8)
DDR_D9: U1.AF27(DDR1_D9) U5.C3(DQ9)
DDR_D10: U1.AG27(DDR1_D10) U5.A3(DQ15)
DDR_D11: U1.AF28(DDR1_D11) U5.A7(DQ12)
DDR_D12: U1.AE26(DDR1_D12) U5.A2(DQ13)
DDR_D13: U1.AC25(DDR1_D13) U5.C8(DQ10)
DDR_D14: U1.AC24(DDR1_D14) U5.B8(DQ14)
DDR_D15: U1.AD25(DDR1_D15) U5.C2(DQ11)
DDR_D16: U1.V20(DDR1_D16) U7.E3(DQ0)
DDR_D17: U1.W20(DDR1_D17) U7.H8(DQ5)
DDR_D18: U1.AB28(DDR1_D18) U7.H3(DQ4)
DDR_D19: U1.AC28(DDR1_D19) U7.G2(DQ6)
DDR_D20: U1.AC27(DDR1_D20) U7.F2(DQ2)
DDR_D21: U1.Y19(DDR1_D21) U7.F7(DQ1)
DDR_D22: U1.AB27(DDR1_D22) U7.H7(DQ7)
DDR_D23: U1.Y20(DDR1_D23) U7.F8(DQ3)
DDR_D24: U1.AA23(DDR1_D24) U7.D7(DQ8)
DDR_D25: U1.Y22(DDR1_D25) U7.C3(DQ9)
DDR_D26: U1.Y23(DDR1_D26) U7.B8(DQ14)
DDR_D27: U1.AA24(DDR1_D27) U7.A2(DQ13)
DDR_D28: U1.Y24(DDR1_D28) U7.C2(DQ11)
DDR_D29: U1.AA26(DDR1_D29) U7.A7(DQ12)
DDR_D30: U1.AA25(DDR1_D30) U7.C8(DQ10)
DDR_D31: U1.AA28(DDR1_D31) U7.A3(DQ15)
DDR_DQM0: U1.AD23(DDR1_DQM0) U5.E7(LDM)
DDR_DQM1: U1.AB23(DDR1_DQM1) U5.D3(UDM)
DDR_DQM2: U1.AC26(DDR1_DQM2) U7.E7(LDM)
DDR_DQM3: U1.AA27(DDR1_DQM3) U7.D3(UDM)
DDR_DQS0: U1.AH25(DDR1_DQS0) U5.F3(LDQS)
DDR_DQS1: U1.AE27(DDR1_DQS1) U5.C7(UDQS)
DDR_DQS2: U1.AD27(DDR1_DQS2) U7.F3(LDQS)
DDR_DQS3: U1.Y28(DDR1_DQS3) U7.C7(UDQS)
DDR_DQSN0: U1.AG25(DDR1_DQS0N) U5.G3(\\L\D\Q\S\)
DDR_DQSN1: U1.AE28(DDR1_DQS1N) U5.B7(\\U\D\Q\S\)
DDR_DQSN2: U1.AD28(DDR1_DQS2N) U7.G3(\\L\D\Q\S\)
DDR_DQSN3: U1.Y27(DDR1_DQS3N) U7.B7(\\U\D\Q\S\)
DDR_ODT: R75.2(P2) U1.AE20(DDR1_ODT0) U5.K1(ODT) U6.K1(ODT) U7.K1(ODT)
DDR_RASN: R51.2(P2) U1.AF20(DDR1_RASN) U5.J3(\\R\A\S\) U6.J3(\\R\A\S\) U7.J3(\\R\A\S\)
DDR_RESETN: R912.2 U1.AG21(DDR1_RST) U5.T2(\\R\E\S\E\T\) U6.T2(\\R\E\S\E\T\) U7.T2(\\R\E\S\E\T\)
DDR_WEN: R53.2(P2) U1.AH21(DDR1_WEN) U5.L3(\\W\E\) U6.L3(\\W\E\) U7.L3(\\W\E\)
DDRECC_D0: U1.W22(DDR1_ECC_D0) U6.E3(DQ0)
DDRECC_D1: U1.V23(DDR1_ECC_D1) U6.F7(DQ1)
DDRECC_D2: U1.W19(DDR1_ECC_D2) U6.H8(DQ5)
DDRECC_D3: U1.W23(DDR1_ECC_D3) U6.F8(DQ3)
DDRECC_D4: U1.Y25(DDR1_ECC_D4) U6.F2(DQ2)
DDRECC_D5: U1.V24(DDR1_ECC_D5) U6.H7(DQ7)
DDRECC_D6: U1.V25(DDR1_ECC_D6) U6.H3(DQ4)
DDRECC_D7: U1.Y26(DDR1_ECC_D7) U6.G2(DQ6)
DDRECC_DQM: U1.V26(DDR1_ECC_DQM) U6.E7(LDM)
DDRECC_DQS: U1.V27(DDR1_ECC_DQS) U6.F3(LDQS)
DDRECC_DQSN: U1.V28(DDR1_ECC_DQSN) U6.G3(\\L\D\Q\S\)
DECODER_1A: R965.1 U101.2(1A)
DECODER_1B: R966.1 U101.3(1B)
DECODER_1G: R938.1 R970.1 U101.1(1G\)
DRAIN0: D5.1(CATHODE) J37.19 U73.3(DRAIN0)
DRAIN1: D6.1(CATHODE) J37.20 U73.4(DRAIN1)
DRAIN2: D7.1(CATHODE) J37.21 U73.5(DRAIN2)
DRAIN3: D8.1(CATHODE) J37.22 U73.6(DRAIN3)
DRAIN4: D9.1(CATHODE) J37.23 U73.11(DRAIN4)
DRAIN5: D10.1(CATHODE) J37.24 U73.12(DRAIN5)
DRAIN6: D11.1(CATHODE) J37.25 U73.13(DRAIN6)
DRAIN7: D12.1(CATHODE) J37.26 U73.14(DRAIN7)
EECS: U37.63(EECS) U38.1(CS)
EEDATA: R495.1(P1) U37.61(EEDATA) U38.3(DI)
EESK: U37.62(EESK) U38.2(CLK)
EMMC_RSTN: R564.2(P2) R741.1 U43.K5(RST_N)
EMU2: J18.13(TR_CLK0) R711.1(P1)
EMU3: J18.17(TRD0.0) R712.1(P1)
EMU4: J18.23(TRD0.3) R713.1(P1)
EMU5: J18.25(TRD0.4) R714.1(P1)
EMU6: J18.27(TRD0.5) R715.1(P1)
EMU7: J18.29(TRD0.6) R716.1(P1)
EMU8: J18.31(TRD0.7) R717.1(P1)
EMU9: J18.33(TRD0.8) R718.1(P1)
EMU10: J18.35(TRD0.9) R719.1(P1)
EMU11: J18.37(TRD3.0) R720.1(P1)
EMU12: J18.39(TRD3.1) R721.1(P1)
EMU13: J18.41(TRD3.2) R722.1(P1)
EMU14: J18.43(TRD3.3) R723.1(P1)
EMU15: J18.45(TRD3.4) R724.1(P1)
EMU16: J18.47(TRD3.5) R725.1(P1)
EMU17: J18.49(TRD3.6) R726.1(P1)
EMU18: J18.51(TRD3.7) R727.1(P1)
EMU19: J18.53(TRD3.8) R728.1(P1)
EMU_RSTN: C223.1 J18.6(RESETN) R429.2(P2) R450.1(P1)
EMU_USB_DM: J19.2(DM) U36.5(IO2) U37.7(DM)
EMU_USB_DP: J19.3(DP) U36.3(IO1) U37.8(DP)
ETH0_LDO_O: Q7.1(G) U21.43(LDO_O)
ETH0_MDC: R294.1(P1) U21.36(MDC)
ETH0_MDIO: R295.1(P1) U21.37(MDIO)
ETH0_RXCLK: R288.1 R317.2(P2) U21.35(RX_CLK)
ETH0_RXD0: R289.1 R299.2 U21.32(RXD0)
ETH0_RXD1: R290.1 R301.2 U21.31(RXD1)
ETH0_RXD2: R291.1 R306.2 U21.28(RXD2)
ETH0_RXD3: R292.1 R309.2 U21.27(RXD3)
ETH0_RXDV: R285.1 R304.2(P2) U21.33(RX_DV)
ETH0_TXCLK: R281.1 U21.24(GTX_CLK)
ETH0_TXD0: R282.1 U21.19(TXD0)
ETH0_TXD1: R287.1 U21.20(TXD1)
ETH0_TXD2: R283.1 U21.21(TXD2)
ETH0_TXD3: R284.1 U21.22(TXD3)
ETH0_TXEN: R286.1 U21.25(TX_EN)
ETH0GB_25MHZCLK: R315.2 U21.46(XI)
ETH1_LDO_O: Q8.1(G) U24.43(LDO_O)
ETH1_MDC: R338.1(P1) U24.36(MDC)
ETH1_MDIO: R339.1(P1) U24.37(MDIO)
ETH1_RESETN: C189.1 D4.2(ANODE) R324.1(P1) U24.42(RESET_N) U26.4(Y)
ETH1_RXCLK: R328.1 R361.2(P2) U24.35(RX_CLK)
ETH1_RXD0: R333.1 R343.2 U24.32(RXD0)
ETH1_RXD1: R334.1 R345.2 U24.31(RXD1)
ETH1_RXD2: R335.1 R352.2 U24.28(RXD2)
ETH1_RXD3: R336.1 R353.2 U24.27(RXD3)
ETH1_RXDV: R329.1 R348.2(P2) U24.33(RX_DV)
ETH1_TXCLK: R325.1 U24.24(GTX_CLK)
ETH1_TXD0: R330.1 U24.19(TXD0)
ETH1_TXD1: R331.1 U24.20(TXD1)
ETH1_TXD2: R327.1 U24.21(TXD2)
ETH1_TXD3: R332.1 U24.22(TXD3)
ETH1_TXEN: R326.1 U24.25(TX_EN)
ETH1GB_25MHZCLK: R359.2 U24.46(XI)
ETH_MDIO_CLK: R95.2(P2) R294.2(P2) R338.2(P2) U1.V1(MDIO_MCLK)
ETH_MDIO_DATA: R105.2(P2) R279.1 R295.2(P2) R339.2(P2) U1.U4(MDIO_D)
ETHER0_D0N: J10.10 U21.3(TXRXM_A)
ETHER0_D0P: J10.9 U21.2(TXRXP_A)
ETHER0_D1N: J10.8 U21.6(TXRXM_B)
ETHER0_D1P: J10.7 U21.5(TXRXP_B)
ETHER0_D2N: J10.6 U21.8(TXRXM_C)
ETHER0_D2P: J10.5 U21.7(TXRXP_C)
ETHER0_D3N: J10.4 U21.11(TXRXM_D)
ETHER0_D3P: J10.3 U21.10(TXRXP_D)
ETHER1_D0N: J12.10 U24.3(TXRXM_A)
ETHER1_D0P: J12.9 U24.2(TXRXP_A)
ETHER1_D1N: J12.8 U24.6(TXRXM_B)
ETHER1_D1P: J12.7 U24.5(TXRXP_B)
ETHER1_D2N: J12.6 U24.8(TXRXM_C)
ETHER1_D2P: J12.5 U24.7(TXRXP_C)
ETHER1_D3N: J12.4 U24.11(TXRXM_D)
ETHER1_D3P: J12.3 U24.10(TXRXP_D)
F_ADBUS0: R474.2(P2) U37.16(ADBUS0)
F_ADBUS1: R475.2(P2) U37.17(ADBUS1)
F_ADBUS2: R480.2(P2) U37.18(ADBUS2)
F_ADBUS3: R481.2(P2) U37.19(ADBUS3)
F_ADBUS4: R476.2(P2) U37.21(ADBUS4)
F_ADBUS5: R478.2(P2) U37.26(ACBUS0)
F_ADBUS6: R477.2(P2) U37.23(ADBUS6)
F_ADBUS7: R483.2(P2) U37.30(ACBUS4)
FT_SRESET: R478.1(P1) R484.2(P2) U34.1(A)
FT_SRESETB: R473.2(P2) U35.4(Y)
FT_SRESETN: U34.4(Y) U35.2(A)
FT_VBUS: R492.1(P1) U34.2(B)
FTDI_REF: R479.1(P1) U37.6(REF)
FTDI_VPHY: C231.2 C234.2 FB10.1 U37.4(VPHY)
FTDI_VPLL: C237.2 C240.2 FB11.1 U37.9(VPLL)
GB_ETH0_INTN: R297.1(P1) R662.1(P1) U21.38(INT_N / PME_N2)
GB_ETH1_INTN: R342.1(P1) R663.1(P1) U24.38(INT_N / PME_N2)
GBETH0_RESETN: C168.1 D3.2(ANODE) R280.1(P1) U21.42(RESET_N) U22.4(Y)
GPIO_AM574X_USB2_ID: R788.2(P2) U1.AF2(VIN1A_D12/GPIO)
GPIO_PCIE_RSTDRVN: R659.1(P1) R955.2 U44.1(O\E\)
GPIO_PCIE_SWRSTN: R660.1(P1) R954.2 U85.2(B)
GPIO_PRU1_ETH0_RESETN: R112.2(P2) R673.1(P1)
GPIO_PRU1_ETH1_RESETN: R154.2(P2) R674.1(P1)
GPIO_PRU2_ETH0_RESETN: R195.2(P2) R675.1(P1)
GPIO_PRU2_ETH1_RESETN: R234.2(P2) R676.1(P1)
GPIO_TOUCH_RESETN: R661.1(P1) R792.2(P2)
GPIO_USB2_VBUS_DET: R809.1(P1) R811.2 U96.4(Y)
GPIO_VPP_PWR_EN: R638.2(P2) U1.AE3(VIN1A_D17)
GPMC_CLK: J21.58 R689.1(P1)
GPMC_CS0: J21.4 R686.1(P1)
GPMC_CS3: J21.6 R688.1(P1)
HAPTICS_N: Q16.D(DRAIN) U18.2(N-)
HAPTICS_P: C316.1 R113.1 U18.1(P+)
HDMI_CEC: R683.1(P1) U46.1(CEC_A)
HDMI_CLK+: J24.10(CLK+) L29.3 U46.16(TMDS_CK+)
HDMI_CLK-: J24.12(CLK-) L29.2 U46.15(TMDS_CK-)
HDMI_CT_HPD: R558.2(P2) R559.1(P1) U46.12(CT_HPD)
HDMI_DDC_SCL: R795.1(P1) U46.2(SCL_A)
HDMI_DDC_SDA: R796.1(P1) U46.3(SDA_A)
HDMI_HPLG: R682.1(P1) U46.4(HPD_A)
HDMI_LSOE: R558.1(P1) U46.5(LS_OE)
HDMI_TX0+: J24.7(DAT0+) L30.3 U46.18(TMDS_D0+)
HDMI_TX0-: J24.9(DAT0-) L30.2 U46.17(TMDS_D0-)
HDMI_TX1+: J24.4(DAT1+) L31.3 U46.21(TMDS_D1+)
HDMI_TX1-: J24.6(DAT1-) L31.2 U46.20(TMDS_D1-)
HDMI_TX2+: J24.1(DAT2+) L32.3 U46.23(TMDS_D2+)
HDMI_TX2-: J24.3(DAT2-) L32.2 U46.22(TMDS_D2-)
HDMICONN_CEC: J24.13(CEC) U46.7(CEC_B)
HDMICONN_HPLG: J24.19(HPLG) R561.2 U46.10(HPD_B)
HDMICONN_I2CSCL: J24.15(SCL) R560.1(P1) U46.8(SCL_B)
HDMICONN_I2CSDA: J24.16(SDA) R562.1(P1) U46.9(SDA_B)
HDQ: J21.50 R300.1(P1)
IND_I2C_SCL: J17.2 J21.27 R14.2(P2) R275.1(P1) R314.2(P2) R393.1(P1) R567.2(P2) R652.2(P2) U33.6(SCL)
IND_I2C_SDA: J17.1 J21.29 R15.2(P2) R277.1(P1) R312.2(P2) R394.1(P1) R585.2(P2) R653.2(P2) U33.5(SDA)
INDETHER_LED0_RED: R241.2(P2) R975.1
INDETHER_LED1_YEL: R254.1(P1) R969.1
INDUS_INPUT0: J37.1 R368.2
INDUS_INPUT1: J37.3 R370.2
INDUS_INPUT2: J37.5 R372.2
INDUS_INPUT3: J37.7 R374.2
INDUS_INPUT4: J37.9 R373.2
INDUS_INPUT5: J37.11 R375.2
INDUS_INPUT6: J37.13 R376.2
INDUS_INPUT7: J37.15 R378.2
INDUS_INPUTCLK: R367.1(P1) U72.25(CLK)
INDUS_INPUTCSN: R369.1(P1) U72.24(C\E\)
INDUS_INPUTLDN: R371.1(P1) U72.26(L\D\)
INDUS_INPUTSO: U28.2(A) U72.23(SOP)
JTAG_EMU0: J18.19(TRD0.1) R422.1(P1) R554.1(P1) U1.G21(EMU0)
JTAG_EMU1: J18.21(TRD0.2) R423.1(P1) R555.1(P1) U1.D24(EMU1)
JTAG_TCK: R3.2 U1.E20(TCK) U63.13(1B1)
JTAG_TDI: J18.5(TDI) U1.D23(TDI) U63.12(1B2)
JTAG_TDO: J18.4(TDO) U1.F19(TDO) U75.2(A1)
JTAG_TMS: J18.2(TMS) U1.F18(TMS) U63.11(2B1)
JTAG_TRSTN: J18.8(TRSTPD) R433.2(P2) U1.D20(TRSTN) U63.10(2B2)
JTAGPOD_PRES: R677.1(P1) U19.4(Y)
LCD_B0: R605.1(P1) U89.J3(PD0)
LCD_B1: R606.1(P1) U89.K3(PD1)
LCD_B2: R607.1(P1) U89.J2(PD2)
LCD_B3: R608.1(P1) U89.K2(PD3)
LCD_B4: R609.1(P1) U89.J1(PD4)
LCD_B5: R610.1(P1) U89.K1(PD5)
LCD_B6: R612.1(P1) U89.G2(PD6)
LCD_B7: R611.1(P1) U89.G1(PD7)
LCD_BACKLIGHT: R416.2(P2) U1.D1(VIN2A_D2/ECAP1_IN_PWM1)
LCD_CLKN: J16.20 R632.1(P1) U89.F10(MIPI_CN)
LCD_CLKP: J16.21 R632.2(P2) U89.F9(MIPI_CP)
LCD_DEN: R634.1(P1) U89.J7(DE)
LCD_G0: R613.1(P1) U89.F2(PD8)
LCD_G1: R614.1(P1) U89.F1(PD9)
LCD_G2: R616.1(P1) U89.E2(PD10)
LCD_G3: R615.1(P1) U89.E1(PD11)
LCD_G4: R617.1(P1) U89.D2(PD12)
LCD_G5: R619.1(P1) U89.D1(PD13)
LCD_G6: R620.1(P1) U89.C2(PD14)
LCD_G7: R618.1(P1) U89.C1(PD15)
LCD_HS: R636.1(P1) U89.K8(HSYNC)
LCD_MIPI0N: J16.17 R630.2(P2) U89.J10(MIPI_D0N)
LCD_MIPI0P: J16.18 R630.1(P1) U89.J9(MIPI_D0P)
LCD_MIPI1N: J16.14 R631.2(P2) U89.G10(MIPI_D1N)
LCD_MIPI1P: J16.15 R631.1(P1) U89.G9(MIPI_D1P)
LCD_MIPI2N: J16.11 R633.1(P1) U89.D10(MIPI_D2N)
LCD_MIPI2P: J16.12 R633.2(P2) U89.D9(MIPI_D2P)
LCD_MIPI3N: J16.8 R687.1(P1) U89.C10(MIPI_D3N)
LCD_MIPI3P: J16.9 R687.2(P2) U89.C9(MIPI_D3P)
LCD_PCLK: R565.1(P1) U89.J6(PCLK)
LCD_R0: R621.1(P1) U89.B2(PD16)
LCD_R1: R622.1(P1) U89.A2(PD17)
LCD_R2: R624.1(P1) U89.B3(PD18)
LCD_R3: R623.1(P1) U89.A3(PD19)
LCD_R4: R625.1(P1) U89.B4(PD20)
LCD_R5: R627.1(P1) U89.A4(PD21)
LCD_R6: R628.1(P1) U89.B5(PD22)
LCD_R7: R626.1(P1) U89.A5(PD23)
LCD_VS: R635.1(P1) U89.K7(VSYNC)
MMC2_CLK: U1.J7(GPMC_A23/MMC2_CLK) U43.M6(CLK)
MMC2_CMD: R513.1(P1) U1.H6(GPMC_CS1/MMC2_CMD) U43.M5(CMD)
MMC2_DAT0: R505.1(P1) U1.J4(GPMC_A24/MMC2_DAT0) U43.A3(DAT0)
MMC2_DAT1: R506.1(P1) U1.J6(GPMC_A25/MMC2_DAT1) U43.A4(DAT1)
MMC2_DAT2: R507.1(P1) U1.H4(GPMC_A26/MMC2_DAT2) U43.A5(DAT2)
MMC2_DAT3: R508.1(P1) U1.H5(GPMC_A27/MMC2_DAT3) U43.B2(DAT3)
MMC2_DAT4: R509.1(P1) U1.K7(GPMC_A19/MMC2_DAT4) U43.B3(DAT4)
MMC2_DAT5: R510.1(P1) U1.M7(GPMC_A20/MMC2_DAT5) U43.B4(DAT5)
MMC2_DAT6: R511.1(P1) U1.J5(GPMC_A21/MMC2_DAT6) U43.B5(DAT6)
MMC2_DAT7: R512.1(P1) U1.K6(GPMC_A22/MMC2_DAT7) U43.B6(DAT7)
MMC_CD: J15.DT R408.1(P1) R409.1(P1) U84.1
MMC_CLK: J15.5(CLK) R405.1(P1) U30.1(IO1)
MMC_CMD: J15.3(CMD) R398.1 R404.1(P1) U30.7(IO5)
MMC_D0: J15.7(DAT0) R399.1 R406.1(P1) U30.2(IO2)
MMC_D1: J15.8(DAT1) R400.1 R407.1(P1) U30.3(IO3)
MMC_D2: J15.1(DATA2) R401.1 R402.1(P1) U30.6(IO4)
MMC_D3: J15.2(CD/DAT3) R397.1 R403.1(P1) U30.8(IO6)
OSC0_OUT: C1.1 R4.1(P1) R5.2(P2) Y1.1
PCI_CONN_REFN: C436.1 U45.5(OUT0N)
PCI_CONN_REFP: C437.1 U45.6(OUT0P)
PCIE_CRDPRESENT: R650.1(P1) R664.1(P1)
PCIE_PERSTN: J22.A11 R545.1 U44.4(Y)
PCIE_REFCLKN: C436.2 J22.A14 R580.2(P2)
PCIE_REFCLKP: C437.2 J22.A13 R580.1(P1)
PCIE_RESETN: R568.2(P2) R919.1(P1) R920.1(P1) U85.1(A)
PCIE_SMB_CLK: J22.B5 R652.1(P1)
PCIE_SMB_DATA: J22.B6 R653.1(P1)
PCIE_TCK: J22.A5 R542.2
PCIE_TDI: J22.A6 R543.2
PCIE_TDO: J22.A7 TP20.1
PCIE_TMS: J22.A8 R544.2
PCIE_TRSTN: J22.B9 R539.2
PCIE_WAKEN: R655.1(P1) R665.1(P1)
PCIECONN_PETN0: C477.2 J22.B15
PCIECONN_PETP0: C478.2 J22.B14
PHY0_LED_ACTN: R293.1 R321.2(P2) U21.17(LED1 / PME_N1)
PHY0_LED_LINKN: R296.1 R319.2(P2) U21.15(LED2)
PHY1_LED_ACTN: R337.1 R364.2 U24.17(LED1 / PME_N1)
PHY1_LED_LINKN: R340.1 R363.2(P2) U24.15(LED2)
PHY_RESETN: R915.1(P1) R921.1(P1) U22.2(A) U26.2(A) U68.2(B) U69.2(B) U70.2(B) U71.2(B)
PMIC_EN: R645.1 R928.2(P2) R929.1(P1) U3.E5(NSLEEP)
PMIC_INT: R666.1(P1) U3.K1(INT)
PMIC_RESET_IN: R794.1(P1) R981.1 U3.K9(RESET_IN) U104.1(R\E\S\E\T\)
PMIC_RESET_OUTN: R9.1(P1) R814.2 U3.G6(RESET_OUT)
PORZN: C213.1 R6.2(P2) R499.1(P1) R920.2(P2) R921.2(P2) R926.1(P1) U98.4(Y)
PR1_EDC_LATCH0: R743.2(P2) U1.E2(VIN2A_D3)
PR1_EDC_SYNC0: R744.2(P2) U1.D2(VIN2A_D4)
PR1_EDIO_DATA_OUT1: J4.4 R119.1(P1)
PR1_EDIO_DATA_OUT3: J4.3 R118.1(P1)
PR1_EDIO_DATA_OUT4: J7.3 R198.1(P1)
PR1_EDIO_DATA_OUT6: J7.4 R199.1(P1)
PR2_EDC_LATCH0: J21.13 R748.1(P1) R910.1(P1)
PR2_EDC_LATCH1: J21.15 R749.1(P1) R911.1(P1)
PR2_EDC_SYNC0: J21.17 R750.1(P1) R908.1(P1) U103.5(2A)
PR2_EDC_SYNC1: J21.19 R751.1(P1) R909.1(P1)
PR2_MII0_RXDV: J7.2 R197.1(P1)
PR2_MII0_TXEN: J7.1 R196.1(P1)
PR2_MII1_RXDV: J4.2 R117.1(P1)
PR2_MII1_TXEN: J4.1 R115.1(P1)
PR2_UART0_RXD: J21.54 R906.1(P1) R942.1 R947.2 R952.2
PR2_UART0_TXD: J21.56 R907.1(P1) R940.1 R953.2
PROFIBUS_A: J14.3 R577.1(P1) U74.12(A) U81.1
PROFIBUS_B: J14.8 R578.2(P2) U74.13(B) U80.1
PRU1ETH0_25MHZCLK: R310.2 U9.23(XI)
PRU1ETH0_COL: R95.1(P1) R104.2(P2) R105.1(P1) R106.2(P2) U9.29(COL)
PRU1ETH0_CRS: R94.1(P1) U9.27(CRS)
PRU1ETH0_INTN: R669.2(P2) U9.8(PWRDNN/INTN)
PRU1ETH0_LINKLED: R76.1(P1) R93.2(P2) U9.17(LED_LINK)
PRU1ETH0_MDC: R96.1(P1) U9.20(MDC)
PRU1ETH0_MDIO: R98.1(P1) U9.19(MDIO)
PRU1ETH0_RESETN: U9.18(RESET_N) U68.4(Y)
PRU1ETH0_RXCLK: R83.1(P1) U9.25(RX_CLK)
PRU1ETH0_RXD0: R88.1(P1) R111.2(P2) U9.30(RXD_0)
PRU1ETH0_RXD1: R90.1(P1) R110.2(P2) U9.31(RXD_1)
PRU1ETH0_RXD2: R91.1(P1) R109.2(P2) U9.32(RXD_2)
PRU1ETH0_RXD3: R92.1(P1) R108.2(P2) U9.1(RXD_3)
PRU1ETH0_RXDV: R86.1(P1) U9.26(RX_DV)
PRU1ETH0_RXERR: R87.1(P1) U9.28(RX_ERR)
PRU1ETH0_TXCLK: R79.1(P1) U9.2(TX_CLK)
PRU1ETH0_TXD0: R81.1(P1) U9.4(TXD_0)
PRU1ETH0_TXD1: R84.1(P1) U9.5(TXD_1)
PRU1ETH0_TXD2: R85.1(P1) U9.6(TXD_2)
PRU1ETH0_TXD3: R82.1(P1) U9.7(TXD_3)
PRU1ETH0_TXEN: R80.1(P1) U9.3(TX_EN)
PRU1ETH1_25MHZCLK: R313.2 U13.23(XI)
PRU1ETH1_COL: R148.1(P1) R150.1(P1) R151.2(P2) R152.1(P1) R956.1(P1) U13.29(COL)
PRU1ETH1_CRS: R139.1(P1) U13.27(CRS)
PRU1ETH1_INTN: R670.2(P2) U13.8(PWRDNN/INTN)
PRU1ETH1_LINKLED: R131.1(P1) R138.2(P2) U13.17(LED_LINK)
PRU1ETH1_MDC: R140.1(P1) U13.20(MDC)
PRU1ETH1_MDIO: R120.1(P1) R142.1(P1) U13.19(MDIO)
PRU1ETH1_RESETN: U13.18(RESET_N) U69.4(Y)
PRU1ETH1_RXCLK: R129.1(P1) R750.2(P2) U13.25(RX_CLK)
PRU1ETH1_RXD0: R133.1(P1) R158.2(P2) U13.30(RXD_0)
PRU1ETH1_RXD1: R135.1(P1) R157.2(P2) R752.2(P2) U13.31(RXD_1)
PRU1ETH1_RXD2: R136.1(P1) R156.2(P2) U13.32(RXD_2)
PRU1ETH1_RXD3: R137.1(P1) R155.2(P2) R751.2(P2) U13.1(RXD_3)
PRU1ETH1_RXDV: R130.1(P1) U13.26(RX_DV)
PRU1ETH1_RXERR: R132.1(P1) R753.2(P2) U13.28(RX_ERR)
PRU1ETH1_TXCLK: R123.1(P1) U13.2(TX_CLK)
PRU1ETH1_TXD0: R125.1(P1) U13.4(TXD_0)
PRU1ETH1_TXD1: R126.1(P1) R749.2(P2) U13.5(TXD_1)
PRU1ETH1_TXD2: R127.1(P1) U13.6(TXD_2)
PRU1ETH1_TXD3: R128.1(P1) U13.7(TXD_3)
PRU1ETH1_TXEN: R124.1(P1) U13.3(TX_EN)
PRU1ETHER0_RDN: J3.2 R99.2(P2) U9.9(RD-)
PRU1ETHER0_RDP: J3.1 R100.2(P2) U9.10(RD+)
PRU1ETHER0_TDN: J3.6 R101.2(P2) U9.11(TD-)
PRU1ETHER0_TDP: J3.5 R102.2(P2) U9.12(TD+)
PRU1ETHER1_RDN: J5.6 R143.2(P2) U13.9(RD-)
PRU1ETHER1_RDP: J5.5 R144.2(P2) U13.10(RD+)
PRU1ETHER1_TDN: J5.2 R145.2(P2) U13.11(TD-)
PRU1ETHER1_TDP: J5.1 R146.2(P2) U13.12(TD+)
PRU2ETH0_25MHZCLK: R354.2 U15.23(XI)
PRU2ETH0_COL: R187.2(P2) R188.1(P1) R189.2(P2) U15.29(COL)
PRU2ETH0_CRS: R177.1(P1) U15.27(CRS)
PRU2ETH0_INTN: R671.2(P2) U15.8(PWRDNN/INTN)
PRU2ETH0_LINKLED: R159.1(P1) R176.2(P2) U15.17(LED_LINK)
PRU2ETH0_MDC: R179.1(P1) U15.20(MDC)
PRU2ETH0_MDIO: R181.1(P1) U15.19(MDIO)
PRU2ETH0_RESETN: U15.18(RESET_N) U70.4(Y)
PRU2ETH0_RXCLK: R165.1(P1) U15.25(RX_CLK)
PRU2ETH0_RXD0: R171.1(P1) R194.2(P2) U15.30(RXD_0)
PRU2ETH0_RXD1: R173.1(P1) R193.2(P2) U15.31(RXD_1)
PRU2ETH0_RXD2: R174.1(P1) R192.2(P2) U15.32(RXD_2)
PRU2ETH0_RXD3: R175.1(P1) R191.2(P2) U15.1(RXD_3)
PRU2ETH0_RXDV: R166.1(P1) U15.26(RX_DV)
PRU2ETH0_RXERR: R170.1(P1) U15.28(RX_ERR)
PRU2ETH0_TXCLK: R162.1(P1) U15.2(TX_CLK)
PRU2ETH0_TXD0: R163.1(P1) U15.4(TXD_0)
PRU2ETH0_TXD1: R164.1(P1) U15.5(TXD_1)
PRU2ETH0_TXD2: R168.1(P1) U15.6(TXD_2)
PRU2ETH0_TXD3: R169.1(P1) U15.7(TXD_3)
PRU2ETH0_TXEN: R167.1(P1) U15.3(TX_EN)
PRU2ETH1_25MHZCLK: R357.2 U17.23(XI)
PRU2ETH1_COL: J21.18 R220.1(P1) R231.1(P1) R232.1(P1) R950.2 U17.29(COL)
PRU2ETH1_CRS: J21.20 R219.1(P1) R951.2 U17.27(CRS)
PRU2ETH1_INTN: R672.2(P2) U17.8(PWRDNN/INTN)
PRU2ETH1_LINKLED: R200.1(P1) R218.2(P2) U17.17(LED_LINK)
PRU2ETH1_MDC: R221.1(P1) U17.20(MDC)
PRU2ETH1_MDIO: R201.1(P1) R223.1(P1) U17.19(MDIO)
PRU2ETH1_RESETN: U17.18(RESET_N) U71.4(Y)
PRU2ETH1_RXCLK: R209.1(P1) U17.25(RX_CLK)
PRU2ETH1_RXD0: R213.1(P1) R238.2(P2) U17.30(RXD_0)
PRU2ETH1_RXD1: R215.1(P1) R237.2(P2) U17.31(RXD_1)
PRU2ETH1_RXD2: R216.1(P1) R236.2(P2) U17.32(RXD_2)
PRU2ETH1_RXD3: R217.1(P1) R235.2(P2) U17.1(RXD_3)
PRU2ETH1_RXDV: R117.2(P2) R211.1(P1) U17.26(RX_DV)
PRU2ETH1_RXERR: R212.1(P1) U17.28(RX_ERR)
PRU2ETH1_TXCLK: R204.1(P1) U17.2(TX_CLK)
PRU2ETH1_TXD0: R206.1(P1) U17.4(TXD_0)
PRU2ETH1_TXD1: R208.1(P1) U17.5(TXD_1)
PRU2ETH1_TXD2: R210.1(P1) U17.6(TXD_2)
PRU2ETH1_TXD3: R207.1(P1) U17.7(TXD_3)
PRU2ETH1_TXEN: R115.2(P2) R205.1(P1) U17.3(TX_EN)
PRU2ETHER0_RDN: J6.2 R182.2(P2) U15.9(RD-)
PRU2ETHER0_RDP: J6.1 R183.2(P2) U15.10(RD+)
PRU2ETHER0_TDN: J6.6 R184.2(P2) U15.11(TD-)
PRU2ETHER0_TDP: J6.5 R185.2(P2) U15.12(TD+)
PRU2ETHER1_RDN: J8.6 R224.2(P2) U17.9(RD-)
PRU2ETHER1_RDP: J8.5 R225.2(P2) U17.10(RD+)
PRU2ETHER1_TDN: J8.2 R226.2(P2) U17.11(TD-)
PRU2ETHER1_TDP: J8.1 R227.2(P2) U17.12(TD+)
PTP_PPS_OE: J51.1 R948.1 R973.1
QSPI_CLK: R23.1(P1) R24.1(P1) R31.2(P2)
RS485_A: J39.1 R729.2(P2) U77.6(A) U82.1
RS485_B: J39.2 R729.1(P1) U77.7(B) U83.1
RSTOUTTOPMIC: R36.1(P1) R793.2(P2) U3.E6(NRESWARM)
RTCK: J18.7(RTCK) R426.1
SERDES_REF_CLKN: C438.1 U45.2(OUT1N)
SERDES_REF_CLKP: C439.1 U45.3(OUT1P)
SPI2_CS0N: J21.30 U1.B24(SPI2_CS0)
SPI2_DIN: J21.26 U1.G17(SPI2_D0)
SPI2_DOUT: J21.28 U1.B22(SPI2_D1)
SPI2_SCLK: J21.24 R684.2(P2)
SPIMEM_CLK: R31.1(P1) U4.16(SCK)
SPIMEM_CSN: R30.1(P1) U4.7(C\S\)
SPIMEM_D0: R25.1(P1) U4.15(SI/IO0)
SPIMEM_D1: R26.1(P1) U4.8(SO/IO1)
SPIMEM_D2: R22.1 R27.1(P1) U4.9(W\P\/IO2)
SPIMEM_D3: R28.1(P1) R799.1 U4.1(H\O\L\D\/IO3)
SRCCLK: R276.1 R586.2(P2)
SYS_RESETN: J21.25 R29.2(P2) R566.2(P2) R918.1(P1) R922.1(P1)
SYS_WARMRESETN: C570.1 R2.1 R7.2(P2) R473.1(P1) R915.2(P2) R918.2(P2) R919.2(P2) U47.4(Y) U78.4(Y) U97.4(Y)
TCK: J18.3(TCK) R3.1
TIMER15: J21.7 R935.1
TIMER16: R967.1 U102.2(1A)
TIMER16_2: R977.1 U102.5(2A)
TOUCH_INT: R418.2(P2) R802.2(P2)
TSC_INT: J17.4 R418.1(P1)
TSC_RESETN: J17.3 R420.2 R792.1(P1)
UARTX_RXD: R487.2(P2) U37.38(BDBUS0)
UARTX_TXD: R486.2(P2) U37.39(BDBUS1)
USB1_3_0_STDA_SSRX+: J23.6(STDA_SSRX+) U1.AE12(USB_RXP0) U95.2(D1-)
USB1_3_0_STDA_SSRX-: J23.5(STDA_SSRX-) U1.AF12(USB_RXN0) U95.1(D1+)
USB1_3_0_STDA_SSTX+: C555.2 J23.9(STDA_SSTX+) U95.5(D2-)
USB1_3_0_STDA_SSTX-: C554.2 J23.8(STDA_SSTX-) U95.4(D2+)
USB1_CONN_DM: J23.2(DM) L11.4 U64.2(D-)
USB1_CONN_DP: J23.3(DP) L11.3 U64.1(D+)
USB1_OVRCURN: R551.1 U66.5(O\C\)
USB1_VBUS_EN: R553.1 R557.1(P1) R978.1 U66.4(EN)
USB2_CONN_DM: J45.2(DM) L33.3 U93.2(D-)
USB2_CONN_DP: J45.3(DP) L33.4 U93.1(D+)
USB2_ID: J45.4(ID) R788.1(P1) R808.1 U93.3(ID)
USB2_OVRCURN: R790.1 U94.5(O\C\)
USB2_VBUS_EN: R787.1(P1) R791.1 R971.1 U94.4(EN)
USBJTAG_ENN: R677.2(P2) U63.14(2O\E\) U63.15(1O\E\) U65.4(O\E\) U75.4(O\E\)
VADD33_PRU1ETH0: C112.1 R97.2(P2) U9.14(AVDD33)
VADD33_PRU1ETH1: C118.1 R141.2(P2) U13.14(AVDD33)
VADD33_PRU2ETH0: C137.1 R180.2(P2) U15.14(AVDD33)
VADD33_PRU2ETH1: C142.1 R222.2(P2) U17.14(AVDD33)
VAM574X_DDR1: C6.1 C7.1 C8.1 C9.1 C10.1 C11.1 C12.1 C114.1 C115.1 C441.1(POS) R639.2(I2) U1.AA21(VDDS_DDR1#AA21) U1.AA22(VDDS_DDR1#AA22) U1.AB21(VDDS_DDR1#AB21) U1.AB22(VDDS_DDR1#AB22) U1.AB24(VDDS_DDR1#AB24) U1.AB25(VDDS_DDR1#AB25) U1.AC22(VDDS_DDR1#AC22) U1.AD26(VDDS_DDR1#AD26) U1.AG20(VDDS_DDR1#AG20) U1.AG28(VDDS_DDR1#AG28) U1.AH27(VDDS_DDR1#AH27) U1.W16(VDDS_DDR1#W16) U1.W27(VDDS_DDR1#W27)
VAM574X_DDR2: C13.1 C14.1 C15.1 C16.1 C17.1 C440.1(POS) C550.1 C551.1 C552.1 C553.1 R801.2(I2) U1.E24(VDDS_DDR2#E24) U1.G22(VDDS_DDR2#G22) U1.G23(VDDS_DDR2#G23) U1.H20(VDDS_DDR2#H20) U1.H21(VDDS_DDR2#H21) U1.H22(VDDS_DDR2#H22) U1.J27(VDDS_DDR2#J27) U1.L20(VDDS_DDR2#L20) U1.L21(VDDS_DDR2#L21) U1.M20(VDDS_DDR2#M20) U1.M21(VDDS_DDR2#M21) U1.T24(VDDS_DDR2#T24) U1.T25(VDDS_DDR2#T25)
VANA_OUT: C302.1 U3.C8(LDOVANA_OUT)
VCAN1: C250.1 C252.1 J38.1 U40.7(VOUT+) U41.8(VCC2)
VETH0_AVDDH: C153.1 C154.1 C157.1 FB1.2 Q7.3(S) U21.1(AVDDH#1) U21.12(AVDDH#12) U21.47(AVDDH#47)
VETH0_AVDDL: C161.1 C162.1 FB4.2 U21.4(AVDDL#4) U21.9(AVDDL#9)
VETH0_AVDDL_PLL: C163.1 C164.1 C165.1 FB2.2 U21.44(AVDDL_PLL)
VETH0_AVDDL_PMOS: C158.1 FB2.1 FB3.1 FB4.1 Q7.2(D1) Q7.4(D2)
VETH0_DVDDH: C155.1 C156.1 C171.1 D3.1(CATHODE) R278.1(P1) R279.2 R280.2(P2) R297.2(P2) R299.1 R301.1 R306.1 R309.1 U21.16(DVDDH#16) U21.34(DVDDH#34) U21.40(DVDDH#40) U22.5(VCC)
VETH0_DVDDL: C159.1 C160.1 FB3.2 U21.14(DVDDL#14) U21.18(DVDDL#18) U21.23(DVDDL#23) U21.26(DVDDL#26) U21.30(DVDDL#30) U21.39(DVDDL#39)
VETH1_AVDDH: C176.1 C177.1 C178.1 FB5.2 Q8.3(S) U24.1(AVDDH#1) U24.12(AVDDH#12) U24.47(AVDDH#47)
VETH1_AVDDL: C182.1 C183.1 FB8.2 U24.4(AVDDL#4) U24.9(AVDDL#9)
VETH1_AVDDL_PLL: C184.1 C185.1 C186.1 FB6.2 U24.44(AVDDL_PLL)
VETH1_AVDDL_PMOS: C179.1 FB6.1 FB7.1 FB8.1 Q8.2(D1) Q8.4(D2)
VETH1_DVDDH: C174.1 C175.1 C192.1 D4.1(CATHODE) R322.1(P1) R324.2(P2) R342.2(P2) R343.1 R345.1 R352.1 R353.1 R364.1 U24.16(DVDDH#16) U24.34(DVDDH#34) U24.40(DVDDH#40) U26.5(VCC)
VETH1_DVDDL: C180.1 C181.1 FB7.2 U24.14(DVDDL#14) U24.18(DVDDL#18) U24.23(DVDDL#23) U24.26(DVDDL#26) U24.30(DVDDL#30) U24.39(DVDDL#39)
VLDO1_OUT: C383.1 R657.2(P2) U3.C6(LDO1_OUT)
VLDO2_OUT: C318.1 R658.2(P2) U3.B6(LDO2_OUT)
VLED+: C215.1 C216.1 C218.1 J16.29 J16.30 U32.9(OUT)
VLED-: J16.23 J16.24 J16.25 J16.26 J16.27 J16.28 R415.2 U32.5(FB)
VMAIN: C20.1 C21.1 C22.1 C23.1 C24.1(POS) C152.1 C217.1 C272.1 C273.1 C274.1 C275.1 C281.1 C282.1 C283.1 C284.1 C285.1 C317.1 C407.1 C411.1(POS) C412.1(POS) C415.1 C416.1 C452.1 C453.1 C458.1 C459.1 C464.1 C465.1 C466.2 C467.2 C468.1 C471.1 C579.1 D2.1 F1.2 J9.1 L28.1 R19.2(P2) R20.2(P2) R113.2 R411.2(P2) R982.1(P1) TP1.1 U3.A6(LDO12_IN) U3.A9(LDOUSB_IN2) U3.A10(LDO7_LDOUSB_IN) U3.C4(LDO9_IN) U3.C5(LDOLN_IN) U3.C7(VCC1) U3.D11(SMPS1_IN_1) U3.D12(SMPS1_IN_2) U3.D13(SMPS1_IN_3) U3.E1(SMPS7_IN_B1_1) U3.E2(SMPS7_IN_B1_2) U3.E3(SMPS7_IN_B1_3) U3.F1(SMPS4_IN1) U3.F2(SMPS4_IN2) U3.F3(SMPS4_IN3) U3.G11(SMPS2_IN_1) U3.G12(SMPS2_IN_2) U3.G13(SMPS2_IN_3) U3.H11(SMPS3_IN1) U3.H12(SMPS3_IN2) U3.H13(SMPS3_IN3) U3.J1(SMPS5_IN1) U3.J2(SMPS5_IN2) U3.J3(SMPS5_IN3) U3.L12(LDO34_IN) U3.L13(LDO34_IN1) U3.M4(LDO58_IN#M4) U3.M6(SMPS6_IN#M6) U3.M8(SMPS9_IN#M8) U3.M9(SMPS8_IN#M9) U3.N3(LDO6_IN) U3.N4(LDO58_IN#N4) U3.N6(SMPS6_IN#N6) U3.N8(SMPS9_IN#N8) U3.N9(SMPS8_IN#N9) U32.2(VIN) U62.A1(VIN#A1) U62.A2(VIN#A2) U76.1(IN) U79.6(IN) U79.7(FREQ) U86.4(VIN) U96.5(VCC) U104.6(VDD)
VPP_CONN: J46.2 R797.1(P1)
VPP_EN: J1_1.4 R2_1.1 U1_1.3(EN)
VPROFI: C323.1(POS) C325.1(POS) C430.1 C431.1 J14.6 R577.2(P2) U52.7(OUT#7) U52.8(OUT#8) U74.16(VCC2)
VPROFI_SRC: C433.1 C434.1 D14.1(K) D15.1(K) U52.5(IN#5) U52.6(IN#6)
VPROFI_TRANSA: D15.2(A) L2.8
VPROFI_TRANSB: D14.2(A) L2.5
VPWRIN_JCK: D1.2(ANODE) J1.1 J2.1 U104.5(SENSE)
VPWRIN_PREFUSE: D1.1(CATHODE) F1.1
VRTC_OUT: C301.1 R17.2(P2) R645.2 R794.2(P2) R932.1(P1) R981.2 R983.2 U3.A8(LDOVRTC_OUT)
VSDMMC: C483.1 C485.1 C486.1 C487.1 Q27.2(EMMITTER) R397.2 R398.2 R399.2 R400.2 R401.2 R408.2(P2) R644.2 R657.1(P1) R898.2 R900.2 U1.W8(VDDSHV8#W8) U1.Y8(VDDSHV8#Y8)
VSMPS1_2: C276.1 C277.1 L12.2 L13.2 R641.1(I1)
VSMPS1_SW: L12.1 U3.E11(SMPS1_SW_1) U3.E12(SMPS1_SW_2) U3.E13(SMPS1_SW_3)
VSMPS2_SW: L13.1 U3.F11(SMPS2_SW1) U3.F12(SMPS2_SW2) U3.F13(SMPS2_SW3)
VSMPS3: C278.1 L14.2 R656.2(P2)
VSMPS3_SW: L14.1 U3.J11(SMPS3_SW1) U3.J12(SMPS3_SW2) U3.J13(SMPS3_SW3)
VSMPS4_5: C279.1 C280.1 L15.2 L16.2 R642.1(I1)
VSMPS4_SW: L15.1 U3.G1(SMPS4_SW1) U3.G2(SMPS4_SW2) U3.G3(SMPS4_SW3)
VSMPS5_SW: L16.1 U3.H1(SMPS5_SW1) U3.H2(SMPS5_SW2) U3.H3(SMPS5_SW3)
VSMPS6_SW: L17.1 U3.M5(SMPS6_SW#M5) U3.N5(SMPS6_SW#N5)
VSMPS7: C269.1 L18.2 R640.1(I1)
VSMPS7_SW: L18.1 U3.D1(SMPS7_SW1) U3.D2(SMPS7_SW2) U3.D3(SMPS7_SW3)
VSMPS8_SW: L19.1 U3.M10(SMPS8_SW#M10) U3.N10(SMPS8_SW#N10)
VSMPS9: C271.1 L20.2 R742.2(P2)
VSMPS9_SW: L20.1 U3.M7(SMPS9_SW#M7) U3.N7(SMPS9_SW#N7)
VUSB_FTDI: C226.1 D13.2(ANODE) FB9.2 R491.2(P2)
VUSB_JTAG: C225.1 FB9.1 J19.1(VBUS) U36.1(VCC)
VUSB_VBUS1: C311.1 J23.1(VBUS) U66.6(OUT#6) U66.7(OUT#7) U66.8(OUT#8)
VUSB_VBUS2: C546.1 C547.1 J45.1(VBUS) J50.2 R21.2(P2) U93.6(VBUS) U94.6(OUT#6) U94.7(OUT#7) U94.8(OUT#8)
XTIN: C243.1 U37.2(XTIN) Y5.1
XTOUT: C244.1 U37.3(XTOUT) Y5.2
N10692191: R11.2(P2) SW2.3 SW2.4 U48.1
N10692247: C5.1 R11.1(P1) R914.1 U97.2(A)
N11217419: C85.1 R46.1(P1) R47.1(P1)
N11219802: R67.1(P1) U8.7(EN)
N11219922: R56.1(P1) U8.9(PGOOD)
N11219986: C101.1 R69.1(P1) U8.5(VOSNS)
N11220684: C86.1 R45.1 R48.2 U8.1(REFIN)
N12123192: J10.11 R293.2
N12123204: J10.14 R296.2
N12138943: R298.1 U21.48(ISET)
N12139138: TP16.1 U21.41(CLK125_NDO)
N12220066: C108.1 C109.1 C110.1 C111.1 U9.13(PFBIN1) U9.15(PFBOUT) U9.24(PFBIN2)
N12225140: J5.11 R122.1(P1)
N12225158: C123.1 C124.1 C125.1 C126.1 U13.13(PFBIN1) U13.15(PFBOUT) U13.24(PFBIN2)
N12225278: J5.10 R151.1(P1)
N12226470: J5.9 R134.1(P1)
N12226568: R153.1 R154.1(P1) U69.1(A)
N12957779: R482.2(P2) U37.28(ACBUS2)
N12957783: R482.1(P1) U75.6(B2)
N12957791: R489.2(P2) U37.32(ACBUS5)
N12957851: R491.1(P1) R492.2(P2) R494.2 U37.59(BCBUS7)
N12958009: R485.1 U37.14(RESET#)
N12958129: D13.1(CATHODE) R493.2
N12958219: R495.2(P2) R496.1 U38.4(DO)
N12958339: TP18.1 U37.36(SUSPEND#)
N12958347: R493.1 U37.60(PWREN#)
N12958879: R474.1(P1) U63.4(1A1)
N12958935: R476.1(P1) U63.7(2A2)
N12958939: R481.1(P1) U63.6(2A1)
N12958943: R480.1(P1) U75.7(B1)
N12958955: R475.1(P1) U63.5(1A2)
N15911835: R147.2(P2) U13.16(RBIAS)
N16251668: R385.1(P1) U73.15(SCL)
N16251678: R387.1(P1) U73.2(SDA)
N16700927: J5.12 R138.1(P1)
N16818719: R107.1 R112.1(P1) U68.1(A)
N16819128: R103.2(P2) U9.16(RBIAS)
N16839102: C206.1 R379.2 U72.14(VCC)
N16839202: R382.2(P2) U72.13(RLIM)
N16839209: R381.2(P2) U72.2(DB1)
N16839216: R380.2(P2) U72.1(DB0)
N16844891: D6.2(ANODE) R388.2(P2)
N16844892: D11.2(ANODE) R395.2(P2)
N16844893: D12.2(ANODE) R396.2(P2)
N16844894: D9.2(ANODE) R391.2(P2)
N16844899: D10.2(ANODE) R392.2(P2)
N16844909: D5.2(ANODE) R386.2(P2)
N16844924: D8.2(ANODE) R390.2(P2)
N16844930: D7.2(ANODE) R389.2(P2)
N17007255: R366.1 R377.1(P1) U28.4(Y)
N17074741: J3.9 R106.1(P1)
N17120040: J21.3 R743.1(P1)
N17120055: J21.5 R744.1(P1)
N17120061: J21.9 R746.1(P1)
N17120072: J21.11 R747.1(P1)
N17120087: J21.21 R752.1(P1)
N17120090: J21.23 R753.1(P1)
N17144335: R29.1(P1) U4.3(R\E\S\E\T\)
N17156111: C172.2 R305.2(P2) U23.1(XIN/CLK) Y3.2
N17156113: C173.2 R305.1(P1) R308.2(P2) Y3.1
N17156222: R308.1(P1) U23.14(XOUT)
N17156522: R310.1 U23.11(Y1)
N17156525: R313.1 U23.9(Y2)
N17156528: R315.1 U23.8(Y3)
N17156983: R314.1(P1) U23.12(S2/SCL)
N17156986: R312.1(P1) U23.13(S1/SDA)
N17569906: J12.11 R337.2
N17569909: J12.14 R340.2
N17569918: R341.1 U24.48(ISET)
N17569921: TP17.1 U24.41(CLK125_NDO)
N17570093: C193.2 R349.2(P2) U25.1(XIN/CLK) Y4.2
N17570094: C194.2 R349.1(P1) R351.2(P2) Y4.1
N17570107: R351.1(P1) U25.14(XOUT)
N17570112: R354.1 U25.11(Y1)
N17570113: R357.1 U25.9(Y2)
N17570114: R359.1 U25.8(Y3)
N17570122: R358.1(P1) U25.12(S2/SCL)
N17570123: R356.1(P1) U25.13(S1/SDA)
N17594977: C134.1 C135.1 C136.1 C138.1 U15.13(PFBIN1) U15.15(PFBOUT) U15.24(PFBIN2)
N17595032: R190.1 R195.1(P1) U70.1(A)
N17595048: R186.2(P2) U15.16(RBIAS)
N17595072: J6.9 R189.1(P1)
N17595076: J6.11 R161.1(P1)
N17595078: J6.12 R176.1(P1)
N17596821: J8.11 R203.1(P1)
N17596823: C147.1 C148.1 C149.1 C150.1 U17.13(PFBIN1) U17.15(PFBOUT) U17.24(PFBIN2)
N17596838: J8.10 R957.1(P1)
N17596847: R230.2(P2) U1.C17(MCASP3_AXR1/PR2_MII1_RXLINK)
N17596886: J8.9 R214.1(P1)
N17596899: R233.1 R234.1(P1) U71.1(A)
N17596976: R228.2(P2) U17.16(RBIAS)
N17596979: J8.12 R218.1(P1)
N17597002: R230.1(P1) R231.2(P2) R957.2(P2) R958.1(P1)
N17731118: Q1.G(GATE) R241.1(P1) R245.2(P2)
N17731139: Q5.G(GATE) R253.2(P2) R255.2(P2)
N17732522: R410.1(P1) U32.6(EN)
N17732526: R413.2(P2) R414.2(P2) U32.3(SS)
N17732536: Q9.D(DRAIN) R413.1(P1)
N17732560: R411.1(P1) U32.7(FSW)
N17745676: J9.22 R275.2(P2)
N17745678: J9.24 R277.2(P2)
N17745710: J9.23 R903.1
N17863265: J3.11 R78.1(P1)
N17863276: J3.12 R93.1(P1)
N18733248: R497.1(P1) U1.AD14(RTC_OSC_XO)
N18733249: C247.1 R497.2(P2) Y6.4
N18733252: C246.1 R927.2(P2) U1.AE14(RTC_OSC_XI) Y6.1
N18733262: R499.2(P2) U1.AF14(RTC_ISO)
N18733263: R498.1 R500.1(P1) U39.4(Y)
N18733273: R500.2(P2) R926.2(P2) U1.AB17(RTC_PORZ)
N18733274: R929.2(P2) U1.Y11(ON_OFF)
N18733276: R923.1(P1) TP19.1 U1.AD17(WAKEUP0)
N18868530: R14.1(P1) R572.2(P2) U3.L1(I2C1_SCL_SCK)
N18868533: R15.1(P1) R588.2(P2) U3.L2(I2C1_SDA_SDI)
N18913166: TP7.1 U3.J5(ENABLE1)
N18913202: R17.1(P1) R934.1(P1) U3.K7(BOOT1)
N18913205: R16.1(P1) U3.L3(BOOT0)
N18913322: R18.1 R983.1 U3.G9(GPIO_7)
N18913403: C26.2 U3.A3(OSC16MIN) Y2.1
N18913412: C25.2 U3.A2(OSC16MOUT) Y2.3
N18913758: C27.2 U3.B7(VBG)
N18914093: C578.1 U3.C1(OSC16MCAP)
N18914190: TP2.1 U3.M11(CLK32KGO)
N18914214: TP3.1 U3.J7(POWERGOOD)
N18914339: SW3.3 SW3.4 U3.G8(PWRON) U50.1
N18914524: TP6.1 U3.C11(RPWRON)
N18915671: R19.1(P1) U3.B3(VCC_SENSE)
N18915723: R20.1(P1) U3.A11(VCC_SENSE2)
N18915943: R21.1(P1) U3.D8(VBUS)
N19120663: R41.2(P2) U5.L8(ZQ)
N19139994: R32.1 U6.D7(DQ8)
N19139997: R33.1 U6.C3(DQ9)
N19140025: R34.1 U6.C8(DQ10)
N19140027: R35.1 U6.C2(DQ11)
N19140065: R37.1 U6.A7(DQ12)
N19140067: R38.1 U6.A2(DQ13)
N19140105: R39.1 U6.B8(DQ14)
N19140107: R40.1 U6.A3(DQ15)
N19258097: R546.1 U45.7(OE)
N19258128: U45.21(XIN) Y7.3(CLK)
N19258198: R547.1(P1) Y7.1(OE)
N19258383: R548.1 U45.11(OS0)
N19258403: R549.1 R550.1(P1) U45.10(OS1)
N19258622: C305.1 U45.17(REG_CAP2)
N19258627: C306.1 U45.19(REG_CAP1)
N19290398: R421.1 U33.7(WP)
N19388440: R566.1(P1) U89.B9(RESXN)
N19415733: R568.1(P1) U45.12(RSTN)
N19425975: R7.1(P1) U1.E23(RESETN)
N19426030: R8.1(P1) U1.D21(NMI_DSP)
N19426454: R569.1(P1) U1.AC15(XI_OSC1)
N19438966: R582.1(P1) U1.AB9(MCASP5_FSX/PR2_PRU1_R31_2) U77.4(D)
N19438972: R583.1(P1) U77.1(R)
N19438984: R584.1(P1) U77.2(R\E\) U77.3(DE)
N19634423: R579.2(P2) U74.6(R\E\)
N19634430: R574.1(P1) U74.8(D)
N19634431: R575.1(P1) U74.5(R)
N19634433: R576.1(P1) U74.7(DE)
N19700674: J18.1(VREF_DBG) R730.1(P1)
N19700725: J18.12(VREF_TR) R731.1(P1)
N19707292: J18.15(TGT_DETECT) R587.1(P1)
N19708748: R429.1(P1) U78.2(A)
N19795587: R425.1 U3.B12(GPIO_0)
N19795594: R428.1(P1) U3.C13(GPIO_1)
N19795604: R430.1 U3.A12(GPIO_2)
N19795606: R431.1 U3.H9(GPIO_3)
N19795618: R570.1 U3.C10(GPIO_5)
N19795620: R571.1 U3.N11(GPIO_6)
N19795629: R432.1 U3.K10(GPIO_4)
N19796448: R572.1(P1) U3.M3(I2C2_SCL_SCE)
N19796451: R588.1(P1) U3.H8(I2C2_SDA_SDO)
N19923823: C286.1 U1.J10(CAP_VDDRAM_DSPEVE1)
N19923824: C287.1 U1.J9(CAP_VDDRAM_DSPEVE2)
N19923825: C288.1 U1.J16(CAP_VBBLDO_MPU)
N19923831: C292.1 U1.K19(CAP_VDDRAM_MPU2)
N19923832: C291.1 U1.K16(CAP_VDDRAM_MPU1)
N19923833: C290.1 U1.K9(CAP_VBBLDO_DSPEVE)
N19923834: C289.1 U1.J19(CAP_VDDRAM_CORE2)
N19923844: C293.1 U1.L9(CAP_VDDRAM_CORE1)
N19923845: C294.1 U1.P19(CAP_VDDRAM_CORE4)
N19923846: C295.1 U1.R20(CAP_VBBLDO_IVA)
N19923850: C299.1 U1.Y15(CAP_VDDRAM_CORE3)
N19923851: C298.1 U1.Y14(CAP_VBBLDO_GPU)
N19923852: C297.1 U1.Y13(CAP_VDDRAM_GPU)
N19923853: C296.1 U1.T20(CAP_VDDRAM_IVA)
N19923865: C300.1 U1.Y16(CAP_VDDRAM_CORE5)
N20127658: C403.1 R930.2(P2) R931.2(P2) U1.AB15(VDD_RTC)
N20128389: C404.1 R932.2(P2) R933.2(P2) U1.AB13(VDDA_RTC)
N20144297: R637.2 U89.A9(MSEL)
N20190363: C454.2 J40.2 R639.4(SENS2)
N20190375: C454.1 J40.1 R639.3(SENS1)
N20190748: C455.2 J41.1 R640.3(SENS1)
N20190772: C455.1 J41.2 R640.4(SENS2)
N20190931: C456.2 J42.1 R641.3(SENS1)
N20190955: C456.1 J42.2 R641.4(SENS2)
N20191205: C457.2 J43.1 R642.3(SENS1)
N20191229: C457.1 J43.2 R642.4(SENS2)
N20202943: TP21.1 U3.F8(REGEN1)
N20204523: R643.1(P1) U1.AC17(WAKEUP1)
N20275163: C460.1 U79.8(SS)
N20287248: R647.1 R648.2(P2) U79.2(FB)
N20287275: R646.2 U79.1(COMP)
N20287568: C463.1 R646.1
N20287584: D20.2(ANODE) L28.2 U79.5(SW)
N20301491: J22.A1 R649.1 R650.2(P2)
N20338433: J22.B11 R654.1 R655.2(P2)
N20537306: U44.2(A) U85.4(Y)
N20594970: R678.1(P1) U86.1(VEN)
N20595300: R679.1(P1) U79.3(EN)
N20619479: R680.2 R681.2 U86.2(ADJ)
N20631200: Q16.G(GATE) R114.2(P2) R116.2(P2)
N20664562: L22.1 U62.B1(L1#B1) U62.B2(L1#B2)
N20664572: C417.1 U62.A3(VINA) U62.B3(VINA1) U62.C4(P\S\) U62.D4(VSEL)
N20665027: L22.2 U62.D1(L2#D1) U62.D2(L2#D2)
N20706534: R554.2(P2) U65.7(B1)
N20706536: R555.2(P2) U65.6(B2)
N20706626: R477.1(P1) U65.2(A1)
N20706635: R483.1(P1) U65.3(A2)
N20721609: Q3.G(GATE) R247.2(P2) R251.2(P2)
N20721766: Q3.D(DRAIN) R242.1(P1)
N20721850: Q1.D(DRAIN) R239.1(P1)
N20722196: D16.3(G) R242.2(P2)
N20722199: Q5.D(DRAIN) R249.1(P1)
N20722204: D16.4(B) R249.2(P2)
N20722213: D16.2(R) R239.2(P2)
N20722605: Q2.G(GATE) R243.1(P1) R246.2(P2)
N20722618: Q6.G(GATE) R254.2(P2) R256.2(P2)
N20722739: Q4.G(GATE) R248.2(P2) R252.2(P2)
N20722773: Q4.D(DRAIN) R244.1(P1)
N20722790: Q2.D(DRAIN) R240.1(P1)
N20722809: D17.3(G) R244.2(P2)
N20722811: Q6.D(DRAIN) R250.1(P1)
N20722815: D17.4(B) R250.2(P2)
N20722821: D17.2(R) R240.2(P2)
N20723137: Q11.G(GATE) R599.2(P2) R600.1(P1)
N20723150: Q10.G(GATE) R594.2(P2) R595.2(P2)
N20723271: Q15.G(GATE) R590.2(P2) R591.2(P2)
N20723305: Q15.D(DRAIN) R589.1(P1)
N20723322: Q11.D(DRAIN) R596.1(P1)
N20723341: D18.3(G) R589.2(P2)
N20723343: Q10.D(DRAIN) R601.1(P1)
N20723347: D18.4(B) R601.2(P2)
N20723353: D18.2(R) R596.2(P2)
N20723697: Q13.G(GATE) R514.1(P1) R597.2(P2)
N20723710: Q12.G(GATE) R515.2(P2) R598.2(P2)
N20723831: Q14.G(GATE) R592.2(P2) R593.2(P2)
N20723865: Q14.D(DRAIN) R603.1(P1)
N20723882: Q13.D(DRAIN) R604.1(P1)
N20723901: D19.3(G) R603.2(P2)
N20723903: Q12.D(DRAIN) R602.1(P1)
N20723907: D19.4(B) R602.2(P2)
N20723913: D19.2(R) R604.2(P2)
N20729664: Q20.D(DRAIN) R699.1(P1)
N20729666: D22.4(B) R699.2(P2)
N20729672: D22.2(R) R696.2(P2)
N20729903: Q21.G(GATE) R697.2(P2) R698.1(P1)
N20729915: Q20.G(GATE) R694.2(P2) R695.2(P2)
N20730029: Q22.G(GATE) R700.2(P2) R701.2(P2)
N20730054: Q22.D(DRAIN) R693.1(P1)
N20730079: Q21.D(DRAIN) R696.1(P1)
N20730095: D22.3(G) R693.2(P2)
N20730773: Q23.D(DRAIN) R708.1(P1)
N20730775: D23.4(B) R708.2(P2)
N20730781: D23.2(R) R705.2(P2)
N20730789: Q24.G(GATE) R706.2(P2) R707.1(P1)
N20730805: Q23.G(GATE) R703.2(P2) R704.2(P2)
N20730910: Q25.G(GATE) R709.2(P2) R710.2(P2)
N20730936: Q25.D(DRAIN) R702.1(P1)
N20730961: Q24.D(DRAIN) R705.1(P1)
N20730985: D23.3(G) R702.2(P2)
N20825141: R690.2(P2) U1.N1(GPMC_ADVN_ALE)
N20825143: R691.2(P2) U1.M5(GPMC_OEN_REN)
N20825145: R692.2(P2) U1.M3(GPMC_WEN)
N20825147: R732.2(P2) U1.N6(GPMC_BEN0)
N20825149: R733.2(P2) U1.M4(GPMC_BEN1)
N20825151: R734.2(P2) U1.N2(GPMC_WAIT0)
N20962931: C421.1 J18.58(GND#58) R149.1 U19.2(A)
N21013400: R662.2(P2) U1.B14(MCASP1_ACLKR)
N21013403: R663.2(P2) U1.J14(MCASP1_FSR)
N21013406: R664.2(P2) U1.G13(MCASP1_AXR2)
N21013409: R665.2(P2) U1.J11(MCASP1_AXR3)
N21036279: J21.8 R690.1(P1)
N21036281: J21.10 R691.1(P1)
N21036293: J21.12 R692.1(P1)
N21036295: J21.14 R732.1(P1)
N21036304: J21.16 R733.1(P1)
N21036390: R686.2(P2) U1.T1(GPMC_CS0)
N21036392: R688.2(P2) U1.P1(GPMC_CS3/GPIO)
N21036394: R689.2(P2) U1.P7(GPMC_CLK)
N21036619: J21.52 R734.1(P1)
N21099488: C265.1 U43.C2(VDDIM)
N21180149: TP22.1 U1.B15(MCASP2_AXR0)
N21180152: TP23.1 U1.A15(MCASP2_AXR1)
N21306186: TP24.1 U89.B6(GPIO1)
N21306311: R567.1(P1) U89.A8(I2C_SCL)
N21306314: R585.1(P1) U89.B8(I2C_SDA)
N21306347: C424.1 C482.1 FB19.2 U89.E10(VDD_MIPI#E10) U89.H10(VDD_MIPI#H10)
N21307911: R586.1(P1) U89.K6(REFCLK)
N21519094: R754.2(P2) U90.L8(ZQ)
N21519152: R755.2(P2) U91.L8(ZQ)
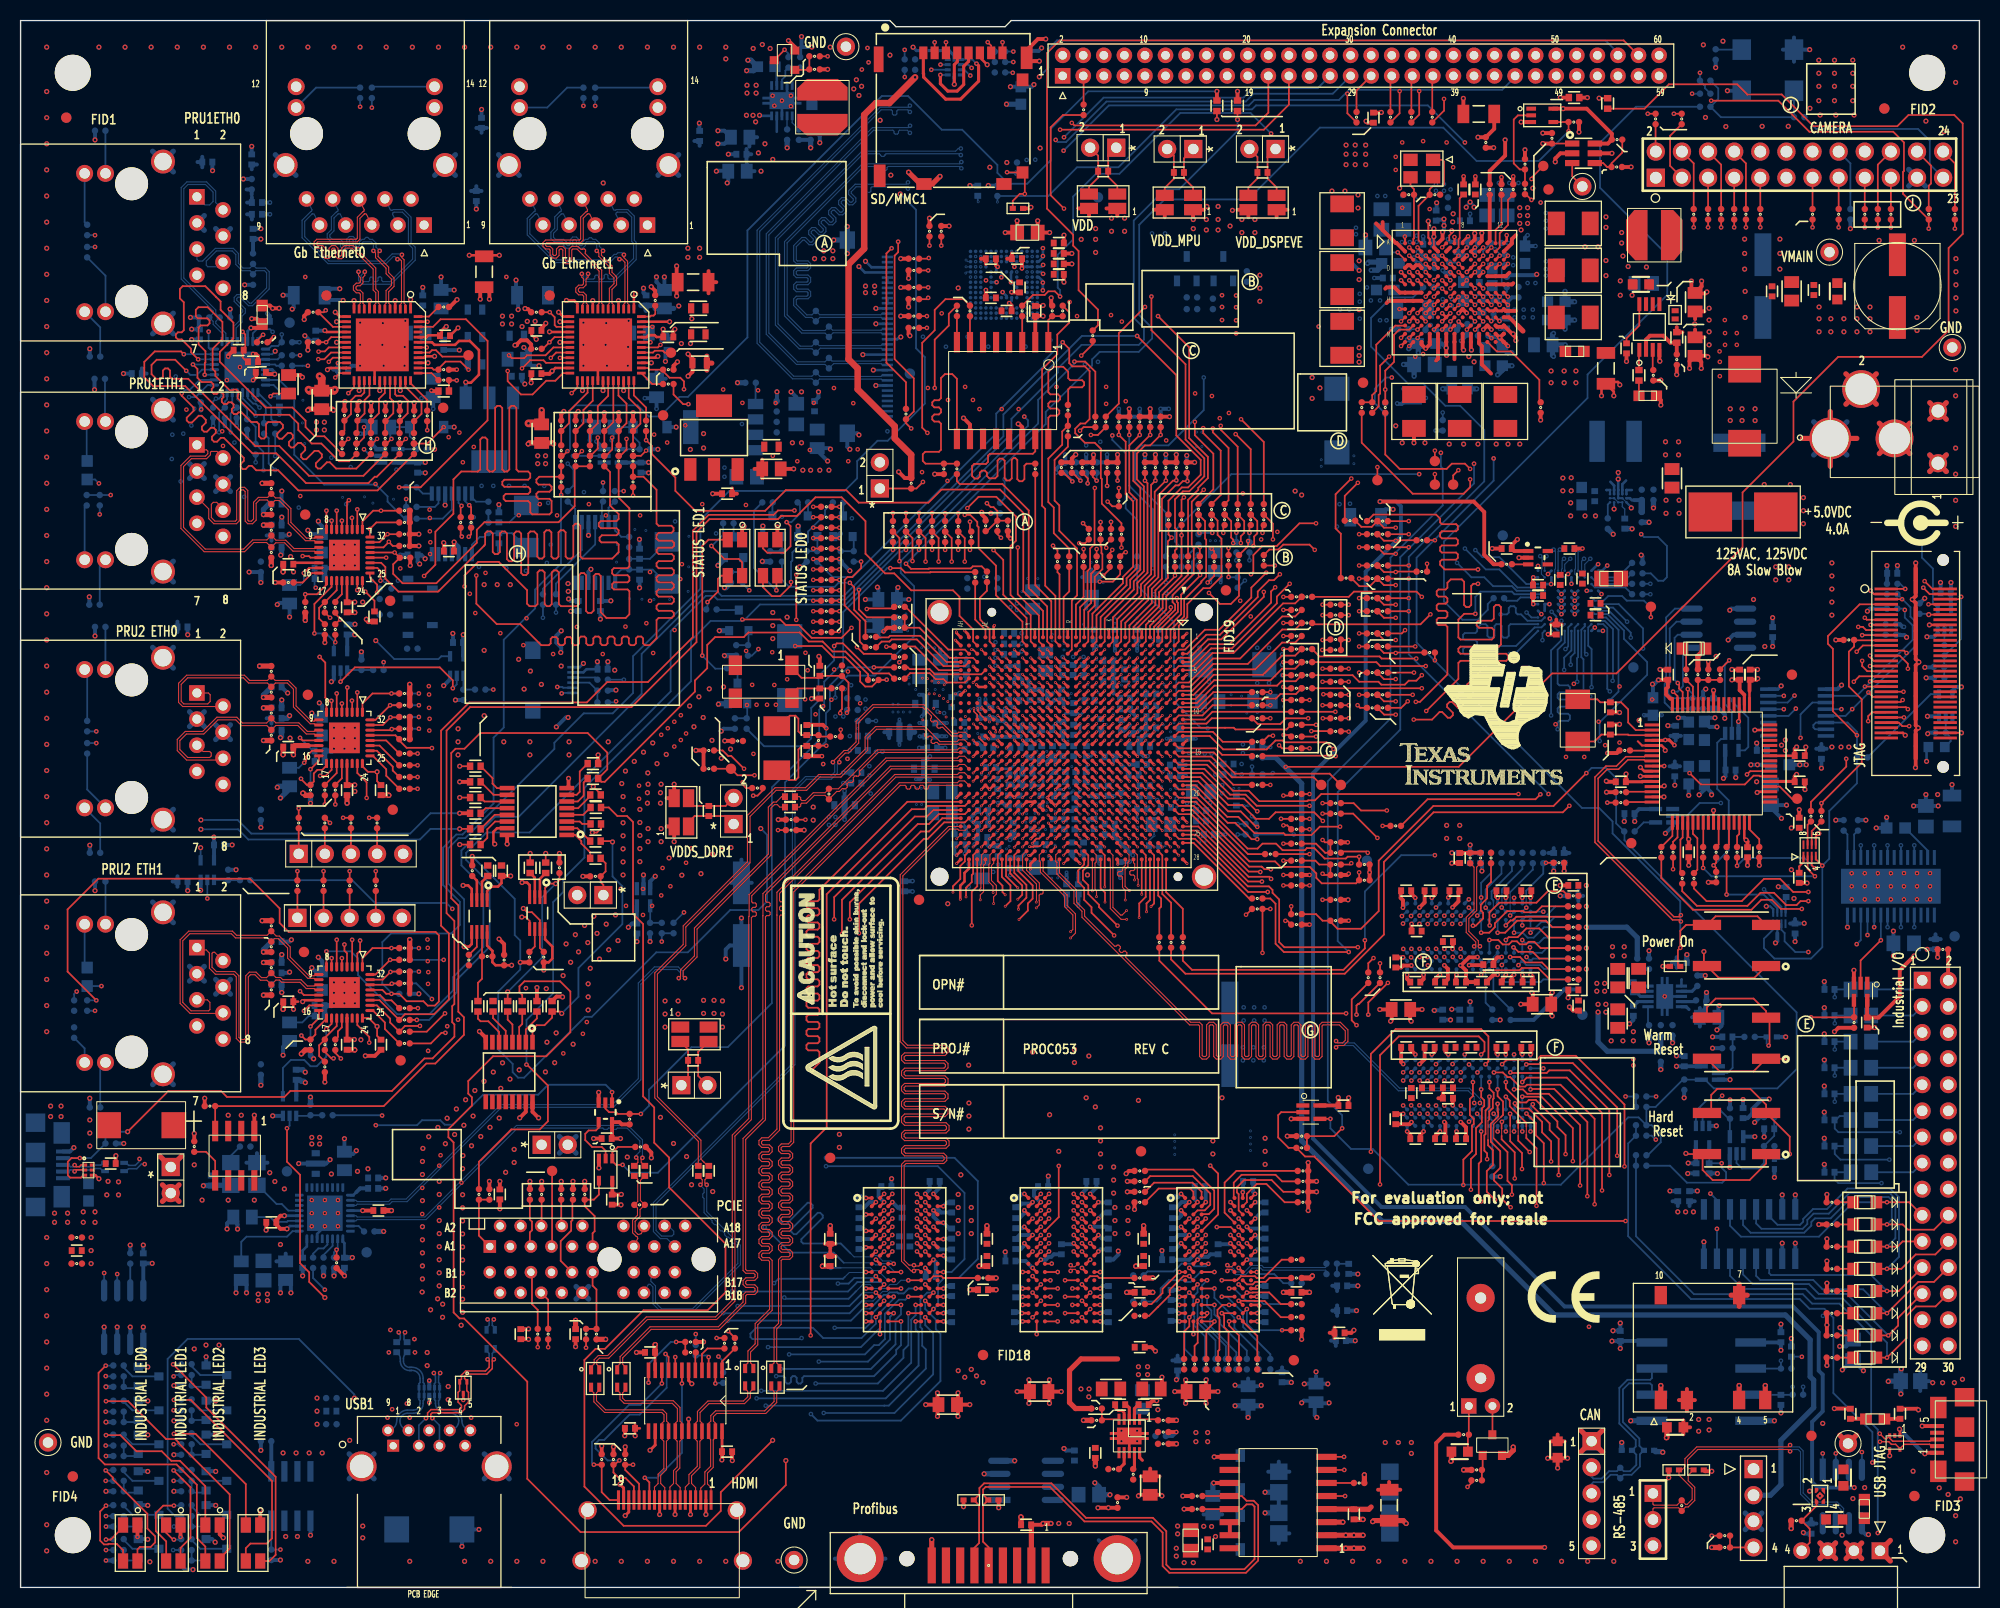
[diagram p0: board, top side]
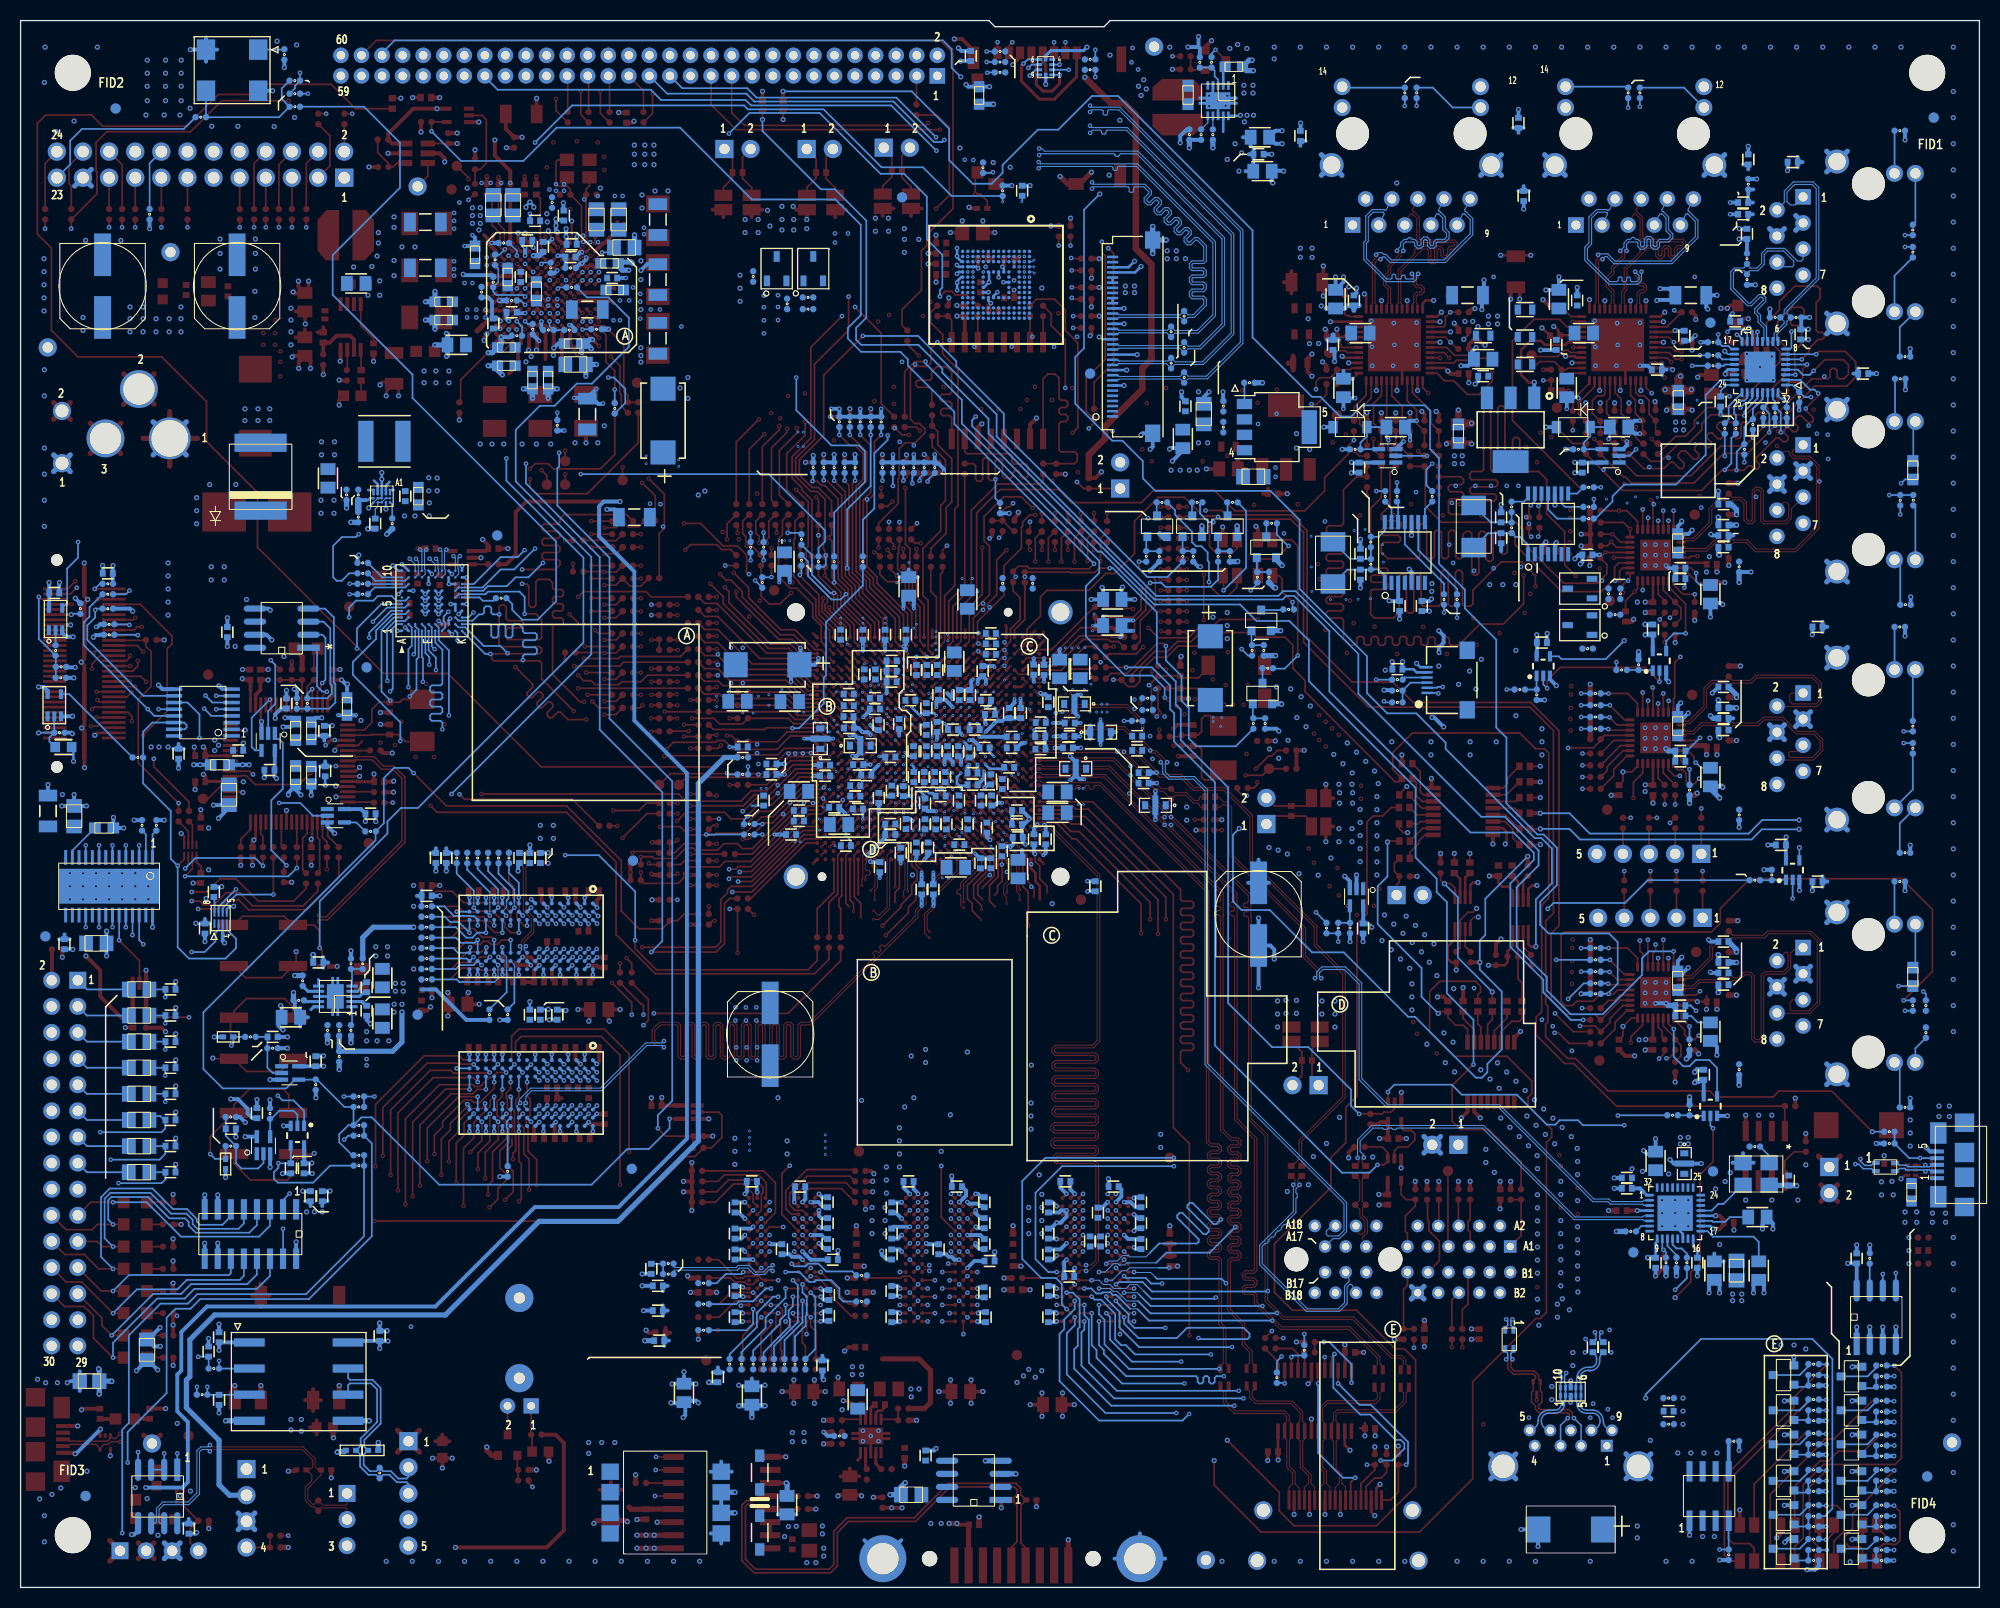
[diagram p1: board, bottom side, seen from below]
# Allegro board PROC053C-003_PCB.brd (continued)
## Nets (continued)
N21552786: C544.1 R785.2 R786.1 U92.1(REFIN)
N21553219: C529.1 R780.1(P1) R781.1(P1)
N21553307: R783.1(P1) U92.7(EN)
N21553371: R782.1(P1) U92.9(PGOOD)
N21553379: C533.1 R784.1(P1) U92.5(VOSNS)
N21605448: C545.1 J50.1
N21620210: C197.1 R368.1 U72.3(IP0)
N21620213: C198.1 R370.1 U72.5(IP1)
N21620216: C199.1 R372.1 U72.7(IP2)
N21620219: C200.1 R374.1 U72.9(IP3)
N21620222: C201.1 R373.1 U72.11(IP4)
N21620225: C202.1 R375.1 U72.18(IP5)
N21620228: C203.1 R376.1 U72.20(IP6)
N21620231: C204.1 R378.1 U72.22(IP7)
N21685968: C548.1 R797.2(P2) U1.K14(RSVK14)
N21685998: J46.4 R638.1(P1) R798.2
N21823186: C549.2 J47.2 R801.4(SENS2)
N21823194: C549.1 J47.1 R801.3(SENS1)
N21877717: R659.2(P2) U1.AE5(VIN1A_D18)
N21877759: R660.2(P2) U1.AE1(VIN1A_D19)
N21905162: R802.1(P1) U1.AG3(VIN1A_D10)
N21905296: R803.1(P1) U1.AH5(VIN1A_D5)
N22373548: R809.2(P2) U1.AD2(VIN1A_D22)
N22373612: R428.2(P2) R810.1 U96.2(A)
N22427447: R739.1(P1) U1.C26(UART1_TXD/GPIO)
N22427459: R740.1(P1) U1.B27(UART1_RXD/GPIO)
N22641301: D24.2(CATHODE) Q26.1(BASE) R894.1 R895.1
N22641309: D24.1(REF) R895.2 R896.1 R897.2
N22641383: D25.2(CATHODE) Q27.1(BASE) R898.1 R899.1
N22641391: D25.1(REF) R899.2 R900.1 R901.2
N22642197: R276.2 R903.2 R905.1(P1) X1.3(OUT)
N22644059: C562.1 R854.2(P2) U3.K12(LDO4_OUT)
N22691021: R576.2(P2) U1.F4(VIN2A_D5/PR1_PRU1_R30_2)
N22729003: J21.31 R861.1(P1)
N22729012: J21.33 R862.1(P1)
N22729021: J21.35 R863.1(P1)
N22729030: J21.37 R864.1(P1)
N22729576: R738.1(P1) U1.AG6(VIN1A_D6)
N22730116: R737.1(P1) U1.AG4(VIN1A_D8)
N22730128: R736.1(P1) U1.AH4(VIN1A_D7)
N22734288: R917.1 U2.4(Y) U98.2(B)
N22734327: C4.1 R10.1 R916.1(P1) U2.2(A)
N22734777: R916.2(P2) SW1.3 SW1.4 U49.1
N22735118: R9.2(P2) U98.1(A)
N22762383: R925.1(P1) U1.AC16(WAKEUP3)
N22762388: R924.1(P1) U1.AB16(WAKEUP2)
N24440306: R902.1 X1.1(EN)
N24733277: R974.2 U99.14(4B1)
N24733350: R975.2 U99.13(4B2)
N24733388: R976.2 U99.12(4A)
N24733458: R977.2 U99.11(3B1)
N24733465: R978.2 U99.10(3B2)
N24733472: R979.2 U99.9(3A)
N24733813: R935.2 U99.5(2B1)
N24736796: R940.2 U102.3(2Y)
N24737086: R942.2 U102.6(1Y)
N24737397: R943.1 R980.1 U103.1(1O\E\)
N24737443: R947.1 U103.3(2Y)
N24737493: R946.2 U103.6(1Y)
N24756266: J3.10 R89.1(P1)
N24757165: J6.10 R172.1(P1)
N24911250: R44.2(P2) U7.L8(ZQ)
N24924145: R42.2(P2) U6.L8(ZQ)
N25402841: R959.1 U101.4(1Y0)
N25402875: R960.1 U101.5(1Y1)
N25402909: R961.1 U101.6(1Y2)
N25403534: R964.1 U103.2(1A)
N25403747: R968.2 U99.4(1A)
N25403773: R969.2 U99.3(1B2)
N25403799: R970.2 U99.2(1B1)
N25403922: R971.2 U99.6(2B2)
N25403942: R972.2 U99.7(2A)
N25404009: R973.2 U99.1(S)
N25485278: C580.1 R982.2(P2) U104.4(CT)
N25485584: TP25.1 U104.3(M\R\)

Pads without a net: J3 7; J5 7; J6 7; J8 7; J9 10 14; J10 2; J12 2; J14 1 2 4 7 9; J16 1 2 6 31 32; J18 9 10 11 14 18 20 22 24 26 28 30 32 34 36 38 40 42 44 46 48 50 52 54 55 56 59 60; J19 4; J22 B12; J24 14; J37 18; J38 5; NOREF#29 1; NOREF#79 1; NOREF#93 1; NOREF#163 1; NOREF#174 1; NOREF#214 1; NOREF#256 1; NOREF#288 1; NOREF#376 1; NOREF#412 1; NOREF#463 1; NOREF#473 1; NOREF#523 1; NOREF#529 1; NOREF#558 1; NOREF#598 1; NOREF#599 1; NOREF#639 1; NOREF#648 1; NOREF#707 1; NOREF#812 1; NOREF#842 1; NOREF#870 1; NOREF#873 1; NOREF#902 1; NOREF#906 1; NOREF#907 1; NOREF#908 1; NOREF#909 1; NOREF#910 1; NOREF#911 1; NOREF#912 1; NOREF#913 1; NOREF#914 1; NOREF#915 1; NOREF#916 1; NOREF#917 1; NOREF#918 1; NOREF#919 1; NOREF#920 1; R946 1; R960 2; R964 2; R980 2; U1 A20 A27 AA1 AA2 AA4 AB1 AB2 AB3 AC1 AC2 AC13 AD3 AD8 AD9 AE2 AE6 AE8 AE9 AF1 AF8 AF9 AG2 AG5 AG7 AG8 AG9 AG10 AG11 AG12 AH3 AH6 AH7 AH9 AH10 AH11 AH12 B28 C27 E15 E25 G16 Y5 Y10; U2 1; U3 B4 C9 K4 K5 K8 L4 N12; U4 4 5 6 11 12 13; U5 J1 J9 L1 L9; U6 J1 J9 L1 L9; U7 J1 J9 L1 L9; U9 22; U13 22; U15 22; U17 22; U19 1; U21 45; U22 1; U23 2 4; U24 45; U25 2 4; U26 1; U28 1; U30 4 9; U35 1; U36 2; U37 22 24 27 29 33 34 40 41 43 44 45 46 48 52 53 54 55 57 58; U39 1; U40 10; U43 A1 A2 A7 A8 A9 A10 A11 A12 A13 A14 B1 B7 B8 B9 B10 B11 B12 B13 B14 C1 C3 C5 C7 C8 C9 C10 C11 C12 C13 C14 D1 D2 D3 D4 D12 D13 D14 E1 E2 E3 E5 E8 E9 E10 E12 E13 E14 F1 F2 F3 F10 F12 F13 F14 G1 G2 G3 G10 G12 G13 G14 H1 H2 H3 H5 H12 H13 H14 J1 J2 J3 J12 J13 J14 K1 K2 K3 K6 K7 K10 K12 K13 K14 L1 L2 L3 L12 L13 L14 M1 M2 M3 M7 M8 M9 M10 M11 M12 M13 M14 N1 N3 N6 N7 N8 N9 N10 N11 N12 N13 N14 P1 P2 P7 P8 P9 P10 P11 P12 P13 P14; U45 8 13 15 23 24 25 26 27 28 29 30 31 32; U47 1; U52 1 2; U72 4 6 8 10 12 16 17 19 21 27; U74 10; U76 4; U78 1; U89 A6; U90 J1 J9 L1 L9; U91 J1 J9 L1 L9; U93 5; U95 6 7 9 10; U96 1; U97 1; U101 7 9 10 11 12 13 14; Y2 2 4; Y6 2 3

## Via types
v1: diameter 0.508, hole 0.254, TOP to BOTTOM, 1677 vias
v2: diameter 0.457, hole 0.203, TOP to BOTTOM, 1102 vias
v3: diameter 0.279, hole 0.127, TOP to L2_GND1, 620 vias
v4: diameter 0.279, hole 0.127, L2_GND1 to L3_SIG1, 621 vias
v5: diameter 0.457, hole 0.203, L3_SIG1 to L10_SIG4, 918 vias
v6: diameter 0.457, hole 0.203, TOP to L2_GND1, 642 vias
v7: diameter 0.457, hole 0.203, L2_GND1 to L3_SIG1, 643 vias
v8: diameter 0.457, hole 0.203, L10_SIG4 to L11_GND4, 421 vias
v9: diameter 0.457, hole 0.203, L11_GND4 to BOTTOM, 423 vias
v10: diameter 0.279, hole 0.127, L10_SIG4 to L11_GND4, 389 vias
v11: diameter 0.279, hole 0.127, L11_GND4 to BOTTOM, 389 vias

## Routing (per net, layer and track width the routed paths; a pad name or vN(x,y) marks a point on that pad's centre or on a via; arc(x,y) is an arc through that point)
AGND_GBETH0: length 11
  BOTTOM w0.381: C167.2 44.32,136.29 ; C167.2 44.83,135.83 ; C167.2 43.81,135.83 ; 22.48,137.93 C166.2 22.99,138.4
  BOTTOM w0.508: J10.SHLD2 26.78,137.35 ; J10.SHLD2 24.77,137.35 ; J10.SHLD2 24.77,139.35 ; J10.SHLD1 42.28,137.35 ; J10.SHLD1 42.28,139.35 ; J10.SHLD1 40.28,137.35
AGND_GBETH1: length 11
  BOTTOM w0.381: 66.04,140.22 C188.2 65.53,140.69 ; C187.2 45.34,141.96 ; C187.2 44.32,141.96 ; C187.2 44.83,141.49
  BOTTOM w0.508: 61.99,137.35 J12.SHLD1 ; J12.SHLD1 64,139.35 ; J12.SHLD1 64,137.35 ; J12.SHLD2 48.5,137.35 ; J12.SHLD2 46.49,139.35 ; J12.SHLD2 46.49,137.35
AGND_PROFI: length 14.4
  TOP w0.381: R573.2 v1(105.79,7.75) v1(104.77,7.75)
  BOTTOM w0.381: J14.11 81.65,5.26 ; J14.11 79.19,2.8 ; J14.11 84.12,2.8 ; 108.44,4.59 J14.10 104.85,4.59
AGNDFRAME_PRU1ETH0: length 10
  BOTTOM w0.381: 17.2,138.64 C106.2 ; C106.2 17.67,139.15 ; C106.2 17.67,138.13
  BOTTOM w0.508: J3.SHLD1 14.85,137.68 ; J3.SHLD1 12.85,139.69 ; J3.SHLD1 14.85,139.69 ; J3.SHLD2 14.85,123.94 ; J3.SHLD2 14.85,121.93 ; J3.SHLD2 12.85,121.93
AGNDFRAME_PRU1ETH1: length 10
  BOTTOM w0.381: 11.79,117.56 C121.2 ; C121.2 11.79,118.57 ; C121.2 12.26,118.06
  BOTTOM w0.508: J5.SHLD2 14.85,97.8 ; J5.SHLD2 12.85,97.8 ; J5.SHLD2 14.85,99.81 ; 12.85,115.56 J5.SHLD1 ; J5.SHLD1 14.85,115.56 ; J5.SHLD1 14.85,113.55
AGNDFRAME_PRU2ETH0: length 10
  BOTTOM w0.381: C131.2 15.26,93.93 ; C131.2 14.79,93.43 ; C131.2 15.26,92.92
  BOTTOM w0.508: 12.85,73.67 J6.SHLD2 ; J6.SHLD2 14.85,75.68 ; J6.SHLD2 14.85,73.67 ; J6.SHLD1 14.85,91.43 ; J6.SHLD1 14.85,89.42 ; J6.SHLD1 12.85,91.43
AGNDFRAME_PRU2ETH1: length 10
  BOTTOM w0.381: C146.2 15.26,69.17 ; C146.2 14.79,68.66 ; C146.2 15.26,68.15
  BOTTOM w0.508: J8.SHLD2 14.85,48.91 ; J8.SHLD2 14.85,50.91 ; J8.SHLD2 12.85,48.91 ; J8.SHLD1 14.85,64.66 ; J8.SHLD1 14.85,66.66 ; J8.SHLD1 12.85,66.66
DGND: length 2714.4
  TOP w0.127: v1(155.5,85.09) 155.48,85.11 ; v1(155.5,83.95) 155.48,83.93 ; v1(76.92,86.44) 76.94,86.46
  TOP w0.173: v1(171.81,51.49) 171.74,51.42 SW2.1 168.52,50.19 165.23,50.19 SW2.2 ; SW1.1 169.75,41.23 168.15,39.62 164.56,39.62 163.58,40.6 163.58,41.72 SW1.2 162.02,42.15 v1(161.95,42.21) ; v1(163.7,61.85) 163.7,60.74 SW3.2 165.13,59.31 168.62,59.31 SW3.1
  TOP w0.203: 157.28,82.3 157.69,81.89 U37.5 ; U3.A4 137.05,131.14 136.91,131.28 136.91,132.77 136.9,132.78 v1(136.9,132.89) ; v1(174.88,73.33) 174.59,73.05 U65.5 ; U3.A1 134.65,131.14 134.62,131.17 v7(134.62,131.4) ; U3.A7 v7(139.45,131.34)
  TOP w0.254: U7.M9 v2(104.98,29.08) ; U3.G10 v7(142.24,125.54) ; v4(94.24,83.21) 94.33,83.12 94.33,83.08 94.55,82.87 94.58,82.87 U1.AD13 ; U7.M1 v2(97.45,29.08) ; U6.P9 120.38,27.48 v2(120.45,27.41) ; U7.E1 97.62,35.08 v2(97.61,35.08) ; U7.P1 v2(97.45,27.48) ; U1.R15 v4(101.44,80.82) ; U1.AA20 v4(96.64,76.82) 96.63,76.82 U1.AB20 v4(95.84,76.82) ; U99.15 46.34,73.84 45.98,73.49 45.98,72.43 v1(46.11,72.31) ; U1.A14 v4(113.43,82.41) ; v1(48.77,68.57) 49.25,68.57 49.51,68.31 U102.4 ; U24.13 52.75,123.61 v1(52.32,124.03) ; U1.B1 v4(112.23,92.98) ; U6.M1 v2(112.69,29.08) ; U3.N2 v7(135.05,120.74) ; U6.D3 v2(115.26,35.88) ; U1.T17 v4(100.64,79.22) ; U37.47 v1(168.66,83.39) ; U5.D1 v2(83.18,35.88) ; U3.D6 v7(138.25,128.73) ; U1.G8 v4(108.63,87.21) ; U6.E1 v2(112.86,35.08) ; U1.T18 v4(100.64,78.42) ; v1(157.53,79.76) 157.9,79.39 U37.10 ; U3.M2 v7(135.05,121.54) ; v2(35.18,120.86) 34.43,120.11 U21.29 ; U1.K4 v4(106.23,90.41) ; U1.U14 v4(99.84,82.41) ; U1.W25 v4(98.24,72.82) ; U1.A6 v4(113.43,88.81) ; U3.G5 v7(137.45,125.54) ; v7(144.53,131.53) 144.53,131.02 U3.A13 ; U1.AH28 v4(91.04,70.42) ; U1.T14 v4(100.64,82.41) ; U1.N24 v4(103.83,73.62) ; U3.E8 v7(139.85,127.93) ; U1.V17 v11(99.04,79.22) ; U1.AH1 91.01,92.84 v4(91.01,92.94) ; U37.11 v1(157.53,78.89) ; U1.AA9 v4(96.64,86.41) ; U5.J2 v2(83.18,31.88) ; U6.G9 v2(119.26,33.48) ; v1(153.75,115.91) 153.75,116.64 C278.2 ; U6.G8 v2(118.46,33.48) ; U5.G9 v2(88.78,33.48) ; U1.K24 v4(106.23,73.62) ; U3.H10 v7(142.24,124.74) ; U1.W1 v4(98.64,93.15) ; U1.U20 v4(99.84,76.82) U1.U21 v4(100.64,76.02) U1.T21 ; U1.G7 v4(108.63,88.01) ; U7.J8 v2(104.02,31.88) ; U6.A9 v2(120.06,38.28) ; U3.H6 v7(138.25,124.74) ; v1(50.15,121.4) 49.68,121.87 C174.2 ; U37.5 159.59,81.89 159.94,81.54 v1(159.94,81.41) ; v1(43.64,129.57) 44.99,129.57 C158.2 45.18,129.57 v1(46.56,129.57) ; U7.G8 v2(103.22,33.48) ; U6.J2 v2(114.46,31.88) ; U7.E8 v2(103.22,35.08) ; J15.6 93.47,149.08 93.47,148.64 v1(94.01,148.11) ; U7.T1 v2(97.45,25.88) ; U1.J28 106.71,70.74 v4(106.71,70.34) ; U3.G4 v7(136.65,125.54) ; U3.B11 v7(143.04,130.33) ; C165.2 42.53,122.51 v1(42.55,122.51) ; U36.4 v1(181.77,12.81) ; U3.D4 v7(136.65,128.73) ; U1.R1 v4(101.83,93.15) ; v4(105.79,93.17) 105.83,93.13 U1.K1 ; U3.G7 v7(139.05,125.54) ; U6.B1 v2(113.66,37.48) ; v4(91.89,87.22) 91.84,87.22 U1.AH8 ; U1.E19 v4(110.23,77.62) ; 106.43,17.78 106.43,17.53 106.76,17.2 107.11,17.2 107.32,16.98 U8.4 ; U3.D10 v7(142.24,128.73) ; U1.J12 v4(107.03,84.01) ; U1.T12 v4(100.64,84.01) ; U6.D8 v2(118.46,35.88) ; U3.F4 v7(136.65,127.13) ; v1(43.03,68.28) 43.53,68.28 43.87,67.94 U103.4 ; U5.F9 v2(89.74,33.88) ; U3.J4 v7(136.65,123.94) ; U1.AE10 93.49,85.56 v4(93.48,85.56) ; U6.P1 v2(112.69,27.48) ; U6.F9 v2(120.06,34.28) ; U3.C12 v7(143.84,129.53) ; v1(183.29,82.89) 183.05,83.12 J18.57 ; U7.P9 v2(104.98,27.48) ; U7.G9 v2(104.02,33.48) ; U3.E4 v7(136.65,127.93) ; U1.D19 v4(111.03,77.62) ; U1.AG1 92.24,92.49 92.15,92.58 92.15,92.71 92.04,92.82 92.04,92.83 v4(91.82,93.05) ; C278.2 154.94,116.31 v1(154.94,115.91) ; C278.2 154.35,117.25 155.35,117.25 155.52,117.07 v1(155.52,116.97) ; U5.G8 v2(87.98,33.48) ; U6.T1 v2(112.69,25.88) ; U1.H12 v4(107.83,84.01) ; v1(7.62,39.75) 7.28,40.09 U93.4 ; U3.H7 v7(139.84,125.53) ; v1(167.07,84.22) 167.14,84.29 U37.51 ; U3.L7 v7(139.05,122.34) ; U3.L6 v7(138.25,122.34) ; U1.U15 v4(99.84,80.82) ; U1.L14 v4(105.43,82.41) ; U1.D13 v4(111.03,83.21) ; v1(168.88,77.32) 168.95,77.39 U37.35 ; U1.A1 v4(113.43,92.81) ; U3.D7 v7(139.05,128.73) ; U3.E10 v7(142.24,127.93) ; U1.V15 v4(99.04,80.82) ; U1.AA10 v4(96.64,85.61) ; U6.M9 120.14,29.08 v2(120.27,29.21) ; U6.T9 v2(120.27,25.88) ; U6.B9 v2(120.06,37.48) ; U1.U17 v11(99.84,79.22) ; U1.N15 v4(103.83,80.82) ; U1.N19 v11(103.83,77.62) ; U3.J10 v7(142.24,123.94) ; U1.T15 v4(100.64,80.82) ; U1.R13 v4(101.44,83.21) ; U7.A9 v2(104.02,38.28) ; v1(159.84,77.96) 159.78,77.89 U37.13 ; U5.B9 v2(89.74,37.08) ; U5.M9 v2(89.74,29.08) ; U1.AA8 v4(96.64,87.21) ; U3.E9 v7(141.44,127.93) ; U6.B3 v2(115.26,37.48) ; v4(94.16,82.51) 94.08,82.59 94.06,82.59 U1.AE13 ; U64.3 v7(43.05,18.24) ; U1.AD24 v4(94.24,73.62) ; U7.B9 v2(104.82,37.48) ; U3.L8 v2(139.85,123.13) ; U1.AH20 v4(91.04,76.82) ; U7.G1 v2(97.62,33.48) ; v4(94.7,93.58) 94.7,93.55 94.64,93.49 U1.AD1 ; U3.E7 v7(139.05,127.93) ; U1.T10 v4(100.64,85.61) ; U3.H4 v7(136.65,124.74) ; U5.P1 v2(82.21,27.48) ; U5.D8 v2(87.98,35.88) ; U1.K5 v4(106.23,89.61) ; U6.E8 v2(118.46,35.08) ; U1.AA14 v4(96.64,82.41) ; U3.H5 v7(137.45,124.74) ; U3.C3 v7(135.85,129.53) ; U1.F1 v4(109.04,93.15) ; U5.J8 v2(88.78,31.88) ; v1(173.61,81.74) 173.61,81 C233.2 ; U5.E2 v2(83.98,35.08) ; U5.B3 v2(84.78,37.48) ; U1.A2 v4(113.43,92.01) ; U1.K25 v4(106.23,72.82) ; U1.AD19 v4(94.24,77.62) 94.23,77.62 U1.AE19 v4(93.44,77.62) ; U3.B10 v7(142.24,130.33) ; U7.D8 v2(103.22,35.88) ; U1.AC14 v4(95.04,82.41) ; U6.D1 v2(113.66,35.88) ; U7.E2 v2(99.22,35.08) ; U7.J2 v2(99.22,31.88) ; U1.A23 v4(113.43,74.42) ; U1.A28 v4(113.43,70.42) ; v4(98.2,69.87) 98.2,70.38 U1.W28 ; U3.F6 v7(138.25,127.13) ; U5.T1 v2(82.21,25.88) ; U5.E1 v2(82.21,34.68) ; U1.F7 v4(109.43,88.01) ; U24.29 56.15,120.11 v2(56.9,120.86) ; U37.15 v1(159.82,76.89) ; U6.E2 v2(114.46,35.08) ; U21.13 31.03,123.61 v1(30.61,124.03) ; U5.G1 v2(82.21,33.08) ; U1.P28 v4(103.03,70.42) ; U3.F10 v2(142.24,126.34) ; U7.F9 v2(104.82,34.28) ; U3.D5 v7(137.45,128.73) ; U1.N14 v4(103.83,82.41) ; U1.L13 v4(105.43,83.21) ; U1.W24 v4(98.24,73.62) ; U1.R12 v4(101.44,84.01) ; U1.T11 v4(100.64,84.81) ; U1.N25 v4(103.83,72.82) ; J18.16 v1(185.63,93.62) ; U37.25 v1(164.64,75.57) ; U3.C2 v7(135.05,129.53) ; U1.AA15 v4(96.64,80.82) ; U5.P9 v2(89.74,27.48) ; U1.W15 v4(98.24,80.82) ; U3.F5 v7(137.45,126.34) ; U3.L10 v7(141.45,122.34) ; U7.D1 v2(98.42,35.88) ; U7.B3 v2(100.02,37.48) ; v2(107.82,14.73) U8.8 ; U1.K15 v4(106.23,80.82) ; U6.C7 v2(117.66,36.68) ; U5.B1 v2(83.18,37.48) ; U1.AB11 v4(95.84,84.81) ; U3.B8 v2(140.64,130.33) ; U1.G9 v4(108.63,86.41) ; U3.L9 v7(140.65,122.34) ; U1.AD10 v4(94.24,85.61) ; U1.E13 v4(110.23,83.21) ; U5.T9 v2(89.74,25.88) ; U3.M1 v7(134.25,121.54) ; U3.B2 v7(135.05,130.33) ; U3.J6 v7(139.04,124.73) ; U7.B1 v2(98.42,37.48) ; U3.F9 v2(141.44,126.34) ; U1.AB14 v4(95.86,81.64) ; U3.F7 v7(139.05,126.34) ; U5.M1 v2(82.21,29.08) ; U6.J8 v2(119.26,31.88) ; U3.K3 v7(136.64,123.14) ; U1.M19 v4(104.63,77.62) ; U1.J15 v11(107.03,80.82) ; U6.G1 v2(112.86,33.48) ; U1.AH2 v4(90.91,92.14) ; U3.J9 v2(141.44,123.94) ; U1.R21 v4(101.44,76.02) ; U1.AA11 v4(96.64,84.81) ; U5.E8 v2(87.98,35.08) ; U5.A9 v2(88.78,38.28) ; U3.N1 v7(134.25,120.74) ; U7.T9 v2(104.98,25.88) ; U3.L5 v7(137.45,122.34)
  TOP w0.279: v1(58.8,6.99) 59.15,7.33 J24.17 ; J24.11 v1(62.15,7.09) ; U46.14 61.72,13.85 v1(61.21,13.34) ; J24.5 v1(65.15,7.09) ; J24.2 v1(66.65,7.09) ; v1(65.28,19.81) 64.97,20.12 U46.6 ; J24.8 v1(63.65,7.09) ; U46.19 v1(64.97,16.37)
  TOP w0.381: R361.1 v1(59.56,114.25) ; v7(140.34,137.24) C27.1 ; v1(41.15,101.61) 41.17,101.6 C169.2 ; v1(163.48,127.06) 163.48,126.54 C462.2 ; v1(159.51,115) 159.51,115.48 C463.2 ; v1(156.18,119.25) C460.2 ; v1(108.71,8.91) 108.81,9.01 C88.2 110.9,9.01 v1(111,8.91) ; C580.2 v1(156.62,138.16) ; 95.94,129.24 C350.2 96.41,129.75 ; v7(141.48,137.24) C301.2 ; U83.2 163.82,11.3 v1(164.47,11.3) ; v1(99.44,124.69) 99.4,124.65 C28.2 ; v1(161.06,117.96) 161.07,117.97 R648.1 ; v1(99.69,150.6) 98.94,150.6 97.84,149.5 J15.G5 98.17,148.45 v1(99.08,148.45) ; C105.2 22.88,117.7 v2(22.61,117.43) ; R157.1 v1(38.73,102.44) ; R157.1 R156.1 ; R157.1 R158.1 v1(38.73,101.3) ; C461.2 162.31,119.25 v1(162.31,118.57) ; C461.2 163.98,119.79 v1(164.08,119.69) ; C461.2 163.45,119.19 v1(163.45,118.57) ; v1(61.34,41.78) 61.34,42.3 R955.1 ; U104.2 149.75,139.49 149.25,138.99 v1(149.25,138.66) ; C502.2 135.07,45.06 135.26,45.24 v2(135.26,45.26) ; v1(159.42,119.27) 159.42,119.32 159.38,119.36 U79.4 ; C513.2 146.92,67.18 146.84,67.11 v2(146.84,67.08) ; v2(143.66,67.08) 143.61,67.08 143.49,67.21 143.49,67.73 C512.2 ; C579.2 v1(140.31,144.83) ; C514.2 134.84,59.19 v2(134.84,59.59) ; R40.2 v1(107.63,38.48) ; v1(111,20.45) 111,19.42 C91.2 ; C425.2 173.72,68.53 v1(173.74,68.51) ; v1(149.73,68.28) C525.2 ; v1(91.17,18.92) 91.17,17.88 C33.2 ; U50.2 v1(159.72,60.41) ; v1(92.31,17.78) C33.2 ; C33.2 91.17,17.68 v1(91.17,16.64) ; C501.2 135.15,44.05 v2(134.84,44.35) ; U96.3 v1(145.93,142.53) ; v1(100.06,20.19) 100.06,19.15 C52.2 ; 76.94,86.46 C247.2 ; R479.2 155.24,81.16 154.36,81.16 154.36,81.15 v1(154.35,81.15) ; v1(168.92,89.29) 168.22,89.29 C232.2 ; C493.2 137.52,52.12 v2(137.24,51.84) ; C90.2 110.09,18.16 v1(110.49,18.16) ; R147.1 v1(24.77,97.74) ; C410.2 149.86,93.66 ; C410.2 149.35,94.13 ; C410.2 148.84,93.66 ; v1(129.16,47.62) 129.14,47.61 C214.2 ; v1(55.73,43.66) C470.2 ; C508.2 139.59,59.54 v2(139.64,59.59) ; C64.2 115.3,18.95 v1(115.3,17.91) ; C64.2 v1(116.44,19.05) ; C64.2 115.3,19.15 v1(115.3,20.19) ; v1(162.49,127.06) 162.49,126.27 C462.2 ; R430.2 v7(144.02,137.16) ; v1(49.4,24.13) 49.38,24.15 C303.2 ; R35.2 v1(107.63,39.5) ; 77.72,89.62 C246.2 77.72,90.47 v1(77.64,90.56) ; R34.2 R39.2 v1(125.22,36.66) ; R34.2 R37.2 ; R34.2 v1(126.03,38.48) ; v1(148.95,55.58) 148.85,55.68 C492.2 148.85,57.77 v1(148.95,57.87) ; v1(27.41,117.71) 27.19,117.92 C110.2 ; v1(23.88,34.75) 23.89,34.77 C308.2 ; v7(24.64,121.62) 24.13,121.11 R103.1 ; v1(167.94,70.24) C229.2 ; R298.2 41.73,124.54 v1(42.44,125.25) ; C511.2 135.24,67.47 v2(135.63,67.08) ; 93.87,128.73 C257.2 93.4,129.24 ; R928.1 96.01,102.29 v2(96.27,102.03) ; C152.2 132.32,143.45 v1(132.33,143.46) ; v2(20.19,119.72) 20.19,119.82 C111.2 ; U85.3 v1(56.22,48.15) ; v1(133.24,55.07) 133.34,55.17 C510.2 v1(132.18,56.22) ; U94.1 v1(22.73,45.93) ; v1(49.06,124.39) 49.15,124.39 49.15,124.33 49.36,124.33 R363.1 ; v1(184.57,17.27) 184.56,17.27 184.45,17.38 C225.2 ; J19.5 v1(184.94,15.7) ; v1(172.97,75.65) C420.2 ; v1(46.61,39.5) C304.2 ; C506.2 134.26,60.3 134.45,60.49 135.24,60.49 v2(135.26,60.5) ; 92.33,111.71 92.33,113.11 v1(91.7,113.74) ; v1(150.63,56.46) 150.98,56.11 C528.2 ; C499.2 139.64,43.69 v2(139.64,44.35) ; v7(143.84,121.54) U3.N13 v7(144.64,120.74) ; v7(143.84,121.54) 144.23,121.94 U3.M13 ; v7(143.84,121.54) U3.M12 ; U99.8 53.29,77.92 v1(53.29,78.69) ; v1(58.76,14.75) 58.77,14.77 C429.2 ; v1(162.23,70.24) C239.2 ; R924.2 v1(73.69,74.68) ; v2(135.64,51.84) 135.24,52.25 C494.2 ; v2(146.84,59.59) 146.87,59.59 147.05,59.41 C517.2 ; v1(101.47,126.95) 101.45,126.97 C264.2 ; v1(126.03,39.5) R37.2 ; R37.2 R32.2 v1(125.22,41.32) ; v1(33.53,51.71) 34.46,51.71 C147.2 ; C462.2 162.9,125.86 163.84,125.86 v1(163.99,126.01) ; C181.2 49.66,118.05 v1(49.66,117.18) ; R810.2 v1(146.3,139.83) ; C263.2 101.45,131.51 v1(101.47,131.53) ; v1(69.22,12.34) 69.2,12.36 C428.2 ; R425.2 v7(145.16,137.24) ; v1(98.92,132.92) C479.2 v1(100.08,131.78) ; R494.1 v7(164.13,90.05) ; C242.1 166.44,89.27 v1(166.42,89.29) ; v2(138.46,45.27) 138.56,45.17 138.56,43.67 C500.2 ; C226.2 177.93,17.4 v1(176.39,17.4) ; R913.1 v1(150.11,69.68) ; R38.2 v1(108.33,36.77) ; v1(65.67,81.42) 66.41,81.42 R925.2 R923.2 ; v1(98.26,134.24) 98.15,134.13 U84.2 ; C196.2 v1(186.44,61.3) ; v1(154.22,78.43) 154.28,78.36 C238.2 ; v2(145.24,59.59) 145.21,59.59 145.02,59.39 C509.2 ; C519.2 142.6,58.96 143.23,59.59 v2(143.64,59.59) ; R321.1 v1(27.94,120.35) ; C52.2 100.06,18.95 v1(100.06,17.91) ; C52.2 v1(101.2,19.05) ; v1(44.63,54.08) 45.24,53.47 U101.8 ; v1(159.44,89.29) 159.45,89.27 C235.2 ; U28.3 v1(178.29,60.03) ; v1(61.33,126.51) 61.34,126.51 61.34,126.49 61.72,126.11 R341.2 ; C469.2 58.38,37.23 v1(58.39,37.21) ; v2(146.84,51.84) 146.92,51.92 C488.2 ; C186.2 63.48,122.23 v1(63.63,122.38) ; v2(139.26,66.15) 139.84,66.72 139.84,67.67 C515.2 ; v1(173.53,77.6) 173.51,77.62 C227.2 ; R304.1 v1(36.88,115.22) ; C523.2 142.21,60.53 v2(140.87,60.53) ; R571.2 v1(147.83,113.54) ; C490.2 143.53,51.96 v2(143.64,51.84) ; v1(53.98,23.42) C556.2 ; C516.2 137.54,67.75 137.54,67.38 v2(137.24,67.08) ; 124.59,25.02 v1(124.59,24.13) ; U82.2 v1(160.28,10.67) ; v1(107.52,40.25) 107.79,40.51 R33.2 ; R484.1 v1(164.13,68.58) ; v1(74.68,150.45) 75.3,149.83 Q9.S ; v1(31.5,30.31) R550.2 ; R489.1 v1(169.09,70.24) ; v1(9.27,41.99) 9.25,41.97 C547.2 ; v1(75.18,108.79) C177.2 ; v1(110.36,22.99) 109.98,23.37 C93.2 ; 155.48,85.11 C243.2 ; R793.1 v1(123.19,43.9) ; R643.2 v1(76.2,73.66) ; 138.32,48.06 C496.2 137.88,47.58 ; v1(59.89,22.86) C427.2 ; R542.1 v1(49.53,39.5) ; R791.2 v1(17.91,47.58) ; v2(22.61,119.97) 22.88,119.97 23.1,119.75 C109.2 ; v1(63.81,128.53) 63.81,127.64 63.9,127.54 C179.2 63.9,126.39 63.81,126.29 v1(63.81,125.61) ; v2(135.27,64.54) C518.2 ; v1(67.31,106.38) C176.2 ; R561.1 v1(56.52,13.76) ; v7(151.89,101.05) C484.2 ; v1(27.58,123.32) 27.58,123.68 R319.1 ; R348.1 v1(58.17,114.25) ; R13.2 69.22,82.34 v1(68.48,82.34) ; v2(138.46,60.51) 138.81,60.16 138.81,59.15 C507.2 ; U44.3 v1(56.25,40.8) ; C195.2 v1(180.31,54.46) ; U47.3 v1(123.57,45.58) ; v1(184.3,99.65) J18.61 184.3,96.42 v1(183.97,96.09) 184.3,95.76 J18.62 184.3,90.3 v1(184.61,90) 184.3,89.69 J18.63 184.3,83.85 v1(184.56,83.6) 184.3,83.34 J18.64 184.3,79.76 v1(184.28,79.74) ; 155.48,83.93 C244.2 ; v1(102.23,128.73) C261.2 ; U76.2 v1(145.72,100.16) ; v1(102.23,129.75) C262.2 ; R317.1 v1(38.28,115.22) ; R539.1 v1(53.72,39.5) ; v1(143.11,101.05) C407.2
  TOP w0.508: v1(139.1,12.27) 139.15,12.32 C316.2 ; C82.2 93.24,31.26 v1(93.22,31.24) ; v1(49.37,111.22) 49.47,111.32 C175.2 51.74,111.32 v1(51.84,111.22) ; v1(35.81,77.04) 35.8,77.06 C135.2 ; R237.1 R238.1 37.85,57.74 ; C142.2 25.55,56.25 v1(25.53,56.23) ; v1(145.16,13.65) 145.16,13.34 144.67,12.84 Q16.S ; v1(134.75,6.22) 134.47,6.5 C435.2 131.6,6.5 v1(131.5,6.4) ; v1(104.52,11.81) C99.2 ; v1(160.06,14.56) 160.11,14.61 C249.2 ; 176.92,14.81 TP1_1.1 178.53,14.81 ; v1(30.43,114.5) 30.33,114.6 C156.2 28.04,114.6 v1(27.94,114.5) ; v1(25.53,80.99) 25.55,81.01 C137.2 ; R236.1 R235.1 v1(37.85,63.01) ; v1(37.85,87.84) R191.1 R192.1 ; R48.1 v1(112.41,13.97) ; v1(94.87,28.96) C46.2 ; C120.2 32.48,94.84 v1(32.5,94.82) ; R579.1 v1(130.68,10.95) ; v1(108.46,31.24) 108.48,31.26 C53.2 ; v1(125.63,30.3) 125.43,30.1 124.59,30.1 ; U74.3 v1(128.6,6.35) ; C432.2 130.54,6.62 v1(130.56,6.6) ; 177.51,115.08 J1.2 ; J1.2 180.47,118.04 ; J1.2 180.47,115.08 ; J1.2 177.51,118.04 ; J1.3 183.72,110.28 ; J1.3 180.76,113.24 ; J1.3 180.76,110.28 ; J1.3 183.72,113.24 ; v1(31.75,76.28) C130.2 ; C45.2 78,31.26 v1(77.98,31.24) ; 185.67,113.62 J2.2 ; J2.2 187.28,113.62 ; J2.2 187.28,115.23 ; J2.2 185.67,115.23 ; v1(33.63,94.16) 33.84,93.95 C123.2 ; v1(125.35,28.7) C54.2 ; C101.2 v1(103.37,16.26) ; v1(25.53,98.77) 25.55,98.79 C118.2 ; R187.1 R194.1 R193.1 ; v1(89.41,137.24) 88.67,136.5 J15.G3 87.5,136.5 v1(86.36,137.65) ; 181.83,4.57 J1_1.1 181.83,2.57 ; R2_1.2 v1(172.19,5.73) ; R116.1 v1(140.34,11.43) ; v1(32.5,52.28) 32.48,52.3 C144.2 ; R41.1 v1(94.87,30.1) ; R156.1 R155.1 ; U40.1 v1(159.51,19.64) ; R798.1 v1(164.47,3.89) ; v1(110.11,28.7) C83.2 ; R44.1 v1(110.11,30.1) ; C86.2 v1(112.41,16.26) ; v1(36.07,36.66) C321.2
  L2_GND1 w0.127: 39.43,15.28 J23.7 40.06,15.28
  L2_GND1 w0.381: 40.06,15.28 40.88,16.1 40.88,16.85 v2(39.75,17.98) 38.6,16.83 38.6,16.11 39.43,15.28 ; 4.21,43.18 4.22,43.18
  L2_GND1 w0.508: J9.21 185.24,137.92 ; J9.21 183.62,136.31 ; J9.21 185.24,136.31 ; J9.21 183.62,137.92 ; 51.02,31.27 J22.B7 ; J22.B7 52.24,31.27 ; J22.B7 52.24,30.05 ; J22.B7 51.02,30.05 ; J22.A4 49.24,35.77 ; J22.A4 48.02,35.77 ; J22.A4 48.02,34.55 ; J22.A4 49.24,34.55 ; J4.5 38.02,72.15 ; J4.5 36.41,70.54 ; J4.5 36.41,72.15 ; J4.5 38.02,70.54 ; 61.02,32.55 J22.A15 ; J22.A15 62.24,32.55 ; J22.A15 61.02,33.77 ; J22.A15 62.24,33.77 ; J39.3 159.51,4.82 ; J39.3 157.99,3.3 ; J39.3 157.99,4.82 ; J39.3 159.51,3.3 ; J5.8 20.41,102.95 ; J5.8 18.97,102.95 ; J5.8 18.97,101.52 ; J5.8 20.41,101.52 ; TP11.1 3.47,14.9 ; TP11.1 3.47,13.29 ; TP11.1 1.86,14.9 ; TP11.1 1.86,13.29 ; 38.53,133.23 J10.1 ; J10.1 39.96,131.79 ; J10.1 38.53,131.79 ; J10.1 39.96,133.23 ; 170.92,136.31 J9.11 ; J9.11 170.92,137.92 ; J9.11 172.54,136.31 ; J9.11 172.54,137.92 ; J23.4 43.83,13.19 ; J23.4 42.65,14.37 ; J23.4 42.65,13.19 ; J21.22 122.06,149.74 ; J21.22 120.63,149.74 ; J21.22 122.06,148.3 ; J21.22 120.63,148.3 ; J22.A18 65.24,35.77 ; J22.A18 64.02,35.77 ; J22.A18 64.02,34.55 ; J22.A18 65.24,34.55 ; 63.02,30.05 J22.B17 ; J22.B17 64.24,30.05 ; J22.B17 64.24,31.27 ; J22.B17 63.02,31.27 ; TP10.1 76.03,1.86 ; TP10.1 74.42,3.47 ; TP10.1 76.03,3.47 ; TP10.1 74.42,1.86 ; 18.97,125.65 19.69,126.36 ; 19.69,126.36 20.41,125.65 ; 19.69,126.36 20.41,127.08 ; 19.69,126.36 18.97,127.08 ; 68.84,8.31 J24.MTG2 ; J24.MTG2 68.84,6.69 ; J24.MTG2 70.45,6.69 ; J24.MTG2 70.45,8.31 ; 36.28,64.32 J7.5 ; J7.5 36.28,65.93 ; J7.5 37.89,65.93 ; J7.5 37.89,64.32 ; 186.72,22.73 J37.30 ; J37.30 188.24,22.73 ; J37.30 188.24,24.26 ; J37.30 186.72,24.26 ; 177.72,12.93 TP1_1.1 ; TP1_1.1 176.65,14 ; TP1_1.1 178.79,14 ; TP1_1.1 177.72,15.07 ; TP9.1 188.66,119.8 ; TP9.1 187.05,121.41 ; TP9.1 188.66,121.41 ; TP9.1 187.05,119.8 ; 48.02,28.05 J22.B4 ; J22.B4 49.24,29.27 ; J22.B4 49.24,28.05 ; J22.B4 48.02,29.27 ; 62.02,28.05 J22.B16 ; J22.B16 63.24,29.27 ; J22.B16 63.24,28.05 ; J22.B16 62.02,29.27 ; J12.13 62.73,143.18 ; J12.13 61.21,144.7 ; J12.13 62.73,144.7 ; J1.3 183.72,113.24 ; J1.3 180.76,110.28 ; J1.3 183.72,110.28 ; J1.3 180.76,113.24 ; J1.2 180.47,118.04 ; J1.2 177.51,118.04 ; J1.2 180.47,115.08 ; J1.2 177.51,115.08 ; 79.46,149.05 TP8.1 ; TP8.1 81.07,150.67 ; TP8.1 81.07,149.05 ; TP8.1 79.46,150.67 ; J10.12 27.57,146.73 ; J10.12 27.57,145.21 ; J10.12 26.04,145.21 ; J10.12 26.04,146.73 ; 39.74,14.52 J23.7 40.5,15.61 ; J22.B18 65.24,28.05 ; J22.B18 64.02,28.05 ; J22.B18 65.24,29.27 ; J22.B18 64.02,29.27 ; J21.40 140.06,149.74 ; J21.40 138.63,148.3 ; J21.40 138.63,149.74 ; J21.40 140.06,148.3 ; J8.8 20.41,54.06 ; J8.8 18.97,52.63 ; J8.8 18.97,54.06 ; J8.8 20.41,52.63 ; 184.18,37.97 J37.17 ; J37.17 185.7,39.5 ; J37.17 185.7,37.97 ; J37.17 184.18,39.5 ; J6.8 20.41,78.82 ; J6.8 18.97,77.39 ; J6.8 18.97,78.82 ; J6.8 20.41,77.39 ; 47.76,145.21 J12.12 ; J12.12 47.76,146.73 ; J12.12 49.28,146.73 ; J12.12 49.28,145.21 ; 113.95,67.98 SCKT1.MCH2 ; SCKT1.MCH2 113.95,70.27 ; SCKT1.MCH2 116.24,67.98 ; SCKT1.MCH2 116.24,70.27 ; 184.18,22.73 J37.29 ; J37.29 185.7,22.73 ; J37.29 184.18,24.26 ; J37.29 185.7,24.26 ; J21.60 160.06,148.3 ; J21.60 158.63,149.74 ; J21.60 158.63,148.3 ; J21.60 160.06,149.74 ; 53.33,66.54 J51.2 ; J51.2 53.33,68.15 ; J51.2 54.94,68.15 ; J51.2 54.94,66.54 ; J10.13 41.01,143.18 ; J10.13 39.49,144.7 ; J10.13 41.01,144.7 ; J46.1 169.33,12.32 ; J46.1 169.33,10.71 ; J46.1 167.72,10.71 ; J46.1 167.72,12.32 ; J24.MTG1 55.95,8.31 ; J24.MTG1 54.34,6.69 ; J24.MTG1 55.95,6.69 ; J24.MTG1 54.34,8.31 ; J24.MTG3 55.35,1.79 ; J24.MTG3 53.74,3.41 ; J24.MTG3 53.74,1.79 ; J24.MTG3 55.35,3.41 ; 69.44,3.41 J24.MTG4 ; J24.MTG4 71.05,1.79 ; J24.MTG4 71.05,3.41 ; J24.MTG4 69.44,1.79 ; J9.12 172.54,140.46 ; J9.12 170.92,140.46 ; J9.12 170.92,138.85 ; J9.12 172.54,138.85 ; 140.84,29.3 U18.M2 ; U18.M2 140.84,27 ; U18.M2 143.14,27 ; U18.M2 143.14,29.3 ; 158.63,146.3 J21.59 ; J21.59 160.06,147.74 ; J21.59 160.06,146.3 ; J21.59 158.63,147.74 ; J12.1 61.68,133.23 ; J12.1 60.24,131.79 ; J12.1 60.24,133.23 ; J12.1 61.68,131.79 ; 58.02,34.55 J22.A12 ; J22.A12 59.24,34.55 ; J22.A12 59.24,35.77 ; J22.A12 58.02,35.77 ; 88.23,93.71 SCKT1.MCH4 ; SCKT1.MCH4 88.23,96 ; SCKT1.MCH4 90.52,96 ; SCKT1.MCH4 90.52,93.71 ; 138.63,146.3 J21.39 ; J21.39 140.06,147.74 ; J21.39 138.63,147.74 ; J21.39 140.06,146.3 ; 140.84,21.5 U18.M1 ; U18.M1 143.14,19.2 ; U18.M1 143.14,21.5 ; U18.M1 140.84,19.2 ; J44.2 84.37,108.62 ; J44.2 82.76,108.62 ; J44.2 84.37,110.23 ; J44.2 82.76,110.23 ; 185.67,115.23 J2.2 ; J2.2 187.28,115.23 ; J2.2 185.67,113.62 ; J2.2 187.28,113.62 ; J22.B13 60.24,31.27 ; J22.B13 60.24,30.05 ; J22.B13 59.02,30.05 ; 180.07,2.81 J1_1.1 ; J1_1.1 181.59,4.33 ; J1_1.1 180.07,4.33 ; J1_1.1 181.59,2.81
  L3_SIG1 w0.203: v4(94.24,73.62) v5(93.84,73.37)
  L3_SIG1 w0.254: v5(111.43,83.46) v4(111.03,83.21) ; v4(98.2,69.87) v5(97.84,70.17) ; v4(109.04,93.15) v5(109.04,93.62) ; v7(90.14,107.62) 88.52,107.62 v7(87.67,108.48) 86.85,108.48 84.25,111.08 82.11,111.08 81.72,110.7 v7(81.41,110.7) v1(80.64,110.7) 78.78,110.7 v1(78.76,110.71) 78.67,110.63 v7(76.76,110.63) 73.72,110.63 v7(73.15,110.06) 72.47,110.06 68.13,105.72 66.69,105.72 66.34,105.36 v7(66.29,105.36) v7(55.27,105.36) v7(50.5,105.36) 49.64,105.36 v7(44.07,110.93) v7(42.68,112.32) ; v4(93.44,77.62) v5(93.04,77.37) ; v5(104.23,82.66) 104.23,82.66 v4(103.83,82.41) ; v4(100.64,78.42) v5(100.24,78.17) ; v11(99.04,79.22) v5(98.64,78.97) ; v4(113.43,74.42) 113.68,74.17 v5(113.84,74.17) ; v11(103.83,77.62) v5(104.23,77.37) ; v4(95.04,82.41) 94.92,82.41 v5(94.51,82.83) 94.24,83.1 v4(94.24,83.21) ; v4(101.44,80.82) v5(101.04,80.57) ; v4(103.83,80.82) v5(104.23,80.57) ; v4(100.64,80.82) v5(100.24,80.57) ; v4(99.84,76.82) 100.14,76.51 100.23,76.51 100.23,76.52 100.24,76.54 v5(100.24,76.56) ; v4(96.64,84.81) 96.24,85.06 v5(96.24,85.06) ; v4(96.64,76.82) v5(96.24,76.57) ; v4(95.84,76.82) v5(95.44,76.57) ; v4(98.64,93.15) v5(98.64,93.62) ; v4(103.83,73.62) 104.19,73.26 v5(104.2,73.26) ; v5(99.44,82.66) v4(99.84,82.41) ; 83.46,109.54 v7(80.49,109.54) 78.5,109.54 v1(78.49,109.56) 78.47,109.54 v7(75.54,109.54) 74.79,109.54 v7(70.54,105.28) 69.44,105.28 68.43,104.27 v7(60.25,104.27) v7(56.92,104.27) v7(52.17,104.27) 48.47,104.27 v7(48.45,104.29) 46.82,105.92 46.53,105.92 v7(43.01,109.44) 41.63,110.81 v7(41.63,111.88) ; v4(101.44,84.01) v5(101.04,84.26) ; v5(96.24,86.66) 96.24,86.66 v4(96.64,86.41) ; v5(113.83,92.26) v4(113.43,92.01) ; v4(101.44,76.02) 101.68,75.77 v5(101.85,75.77) ; v4(98.24,80.82) v5(97.84,80.57) ; v4(94.24,85.61) v5(93.84,85.93) ; v4(99.84,80.82) v5(99.44,80.57) ; v5(100.24,84.26) 100.24,84.26 v4(100.64,84.01) ; v4(101.44,83.21) v5(101.04,83.46) ; v5(107.43,84.26) v4(107.03,84.01) ; v4(110.23,77.62) v5(110.63,77.37) ; v4(111.03,77.62) v5(111.43,77.37) ; v4(94.24,77.62) v5(93.84,77.37) ; v4(95.84,84.81) v5(95.44,85.06) ; v4(93.48,85.56) 93.48,85.64 93.26,85.86 v5(93.26,85.97) ; v4(113.43,70.42) v5(112.96,70.42) ; v5(100.24,82.66) 100.24,82.66 v4(100.64,82.41) ; v5(112.63,93.23) v4(112.23,92.98) ; v4(101.83,93.15) v5(101.83,93.62) ; v4(99.04,80.82) v5(98.64,80.57) ; v4(91.01,92.94) 90.61,93.19 v5(90.51,93.19) ; v4(107.83,84.01) 108.23,84.26 v5(108.23,84.26) ; v4(100.64,84.81) 100.24,85.06 v5(100.24,85.06) ; v4(98.24,73.62) v5(97.84,73.37) ; v5(105.83,82.66) v4(105.43,82.41) ; v5(109.03,86.66) v4(108.63,86.41) ; v4(100.64,85.61) 100.24,85.86 v5(100.24,85.86) ; v5(101.02,75.72) 100.99,75.75 100.9,75.75 v4(100.64,76.02) ; v4(104.63,77.62) v5(105.03,77.37) ; v4(96.64,80.82) v5(96.24,80.57) ; v5(91.03,69.95) 91.04,69.95 v4(91.04,70.42) ; v11(107.03,80.82) v5(107.43,80.57) ; v4(106.23,80.82) v5(106.63,80.57) ; v5(105.87,83.52) 105.87,83.5 105.83,83.46 v4(105.43,83.21) ; v5(99.44,78.97) v11(99.84,79.22) v4(100.64,79.22) ; v5(94.24,93.4) 94.53,93.4 v4(94.7,93.58) ; v4(96.64,85.61) 96.24,85.86 v5(96.24,85.86) ; v5(109.03,88.26) v4(108.63,88.01) ; v5(113.83,82.66) v4(113.43,82.41) ; v5(113.83,89.06) v4(113.43,88.81) ; v5(96.24,87.46) 96.24,87.46 v4(96.64,87.21) ; v4(91.04,76.82) v5(90.64,76.57) ; v4(98.24,72.82) v5(97.84,72.57) ; v5(91.42,93.29) v4(91.82,93.05) ; v5(113.83,93.06) v4(113.43,92.81) ; v5(109.83,88.26) v4(109.43,88.01) ; v4(94.16,82.51) 94.14,82.51 93.96,82.7 93.95,82.7 v5(93.77,82.88) ; v5(104.2,72.46) 104.19,72.46 v4(103.83,72.82) ; v5(110.63,83.46) v4(110.23,83.21) ; v5(109.03,87.46) v4(108.63,87.21) ; v5(90.51,92.39) v4(90.91,92.14)
  L3_SIG1 w0.381: v5(36.93,99.7) v7(36.93,99.12) ; J44.2 83.46,109.54
  L3_SIG1 w0.508: J37.30 188.24,24.26 ; J37.30 188.24,22.73 ; J37.30 186.72,22.73 ; J37.30 186.72,24.26 ; J37.17 185.7,39.5 ; J37.17 184.18,37.97 ; J37.17 185.7,37.97 ; J37.17 184.18,39.5 ; 180.07,2.81 J1_1.1 ; J1_1.1 180.07,4.33 ; J1_1.1 181.59,4.33 ; J1_1.1 181.59,2.81 ; 18.97,54.06 J8.8 ; J8.8 20.41,52.63 ; J8.8 20.41,54.06 ; J8.8 18.97,52.63 ; 47.76,145.21 J12.12 ; J12.12 49.28,145.21 ; J12.12 47.76,146.73 ; J12.12 49.28,146.73 ; J7.5 37.89,64.32 ; J7.5 37.89,65.93 ; J7.5 36.28,64.32 ; J7.5 36.28,65.93 ; 18.97,77.39 J6.8 ; J6.8 18.97,78.82 ; J6.8 20.41,77.39 ; J6.8 20.41,78.82 ; J37.29 185.7,22.73 ; J37.29 184.18,24.26 ; J37.29 185.7,24.26 ; J37.29 184.18,22.73 ; J10.1 39.96,131.79 ; J10.1 39.96,133.23 ; J10.1 38.53,131.79 ; J10.1 38.53,133.23 ; TP8.1 81.07,149.05 ; TP8.1 81.07,150.67 ; TP8.1 79.46,150.67 ; TP8.1 79.46,149.05 ; J10.12 27.57,145.21 ; J10.12 27.57,146.73 ; J10.12 26.04,145.21 ; J10.12 26.04,146.73 ; 177.72,12.93 TP1_1.1 176.65,14 ; J4.5 38.02,72.15 ; J4.5 36.41,70.54 ; J4.5 36.41,72.15 ; J4.5 38.02,70.54 ; 61.21,144.7 J12.13 ; J12.13 62.73,143.18 ; J12.13 62.73,144.7 ; J9.11 172.54,136.31 ; J9.11 170.92,137.92 ; J9.11 172.54,137.92 ; J9.11 170.92,136.31 ; J10.13 41.01,144.7 ; J10.13 41.01,143.18 ; J10.13 39.49,144.7 ; 170.92,140.46 J9.12 ; J9.12 172.54,138.85 ; J9.12 170.92,138.85 ; J9.12 172.54,140.46
  L4_SIG2 w0.508: 64.02,29.27 J22.B18 ; J22.B18 64.02,28.05 ; J22.B18 65.24,29.27 ; J22.B18 65.24,28.05 ; 62.02,28.05 J22.B16 ; J22.B16 63.24,28.05 ; J22.B16 63.24,29.27 ; J22.B16 62.02,29.27 ; J12.1 61.68,133.23 ; J12.1 60.24,133.23 ; J12.1 60.24,131.79 ; J12.1 61.68,131.79 ; 18.97,101.52 J5.8 ; J5.8 20.41,102.95 ; J5.8 18.97,102.95 ; J5.8 20.41,101.52 ; 185.67,115.23 J2.2 ; J2.2 187.28,115.23 ; J2.2 185.67,113.62 ; J2.2 187.28,113.62 ; J22.B13 60.24,30.05 ; J22.B13 59.02,30.05 ; J22.B13 60.24,31.27 ; J12.13 62.73,144.7 ; J12.13 62.73,143.18 ; J12.13 61.21,144.7 ; 51.02,31.27 J22.B7 ; J22.B7 52.24,31.27 ; J22.B7 52.24,30.05 ; J22.B7 51.02,30.05 ; 64.02,35.77 J22.A18 ; J22.A18 65.24,35.77 ; J22.A18 64.02,34.55 ; J22.A18 65.24,34.55 ; 39.49,144.7 J10.13 ; J10.13 41.01,144.7 ; J10.13 41.01,143.18 ; J1.3 183.72,110.28 ; J1.3 183.72,113.24 ; J1.3 180.76,110.28 ; J1.3 180.76,113.24 ; 47.76,146.73 J12.12 ; J12.12 49.28,145.21 ; J12.12 47.76,145.21 ; J12.12 49.28,146.73 ; 61.02,32.55 J22.A15 ; J22.A15 62.24,32.55 ; J22.A15 62.24,33.77 ; J22.A15 61.02,33.77 ; 58.02,34.55 J22.A12 ; J22.A12 59.24,34.55 ; J22.A12 59.24,35.77 ; J22.A12 58.02,35.77 ; 48.02,35.77 J22.A4 ; J22.A4 48.02,34.55 ; J22.A4 49.24,35.77 ; J22.A4 49.24,34.55 ; 18.97,127.08 19.69,126.36 ; 19.69,126.36 18.97,125.65 ; 19.69,126.36 20.41,127.08 ; 19.69,126.36 20.41,125.65 ; TP8.1 81.07,150.67 ; TP8.1 79.46,150.67 ; TP8.1 79.46,149.05 ; TP8.1 81.07,149.05 ; J10.12 27.57,145.21 ; J10.12 26.04,145.21 ; J10.12 27.57,146.73 ; J10.12 26.04,146.73 ; J10.1 39.96,133.23 ; J10.1 38.53,131.79 ; J10.1 38.53,133.23 ; J10.1 39.96,131.79 ; 63.02,31.27 J22.B17 ; J22.B17 63.02,30.05 ; J22.B17 64.24,30.05 ; J22.B17 64.24,31.27 ; J1.2 180.47,115.08 ; J1.2 177.51,115.08 ; J1.2 180.47,118.04 ; 48.02,28.05 J22.B4 ; J22.B4 49.24,28.05 ; J22.B4 48.02,29.27 ; J22.B4 49.24,29.27
  L5_GND2 w0.508: 177.51,115.08 J1.2 ; J1.2 180.47,115.08 ; J1.2 177.51,118.04 ; J1.2 180.47,118.04 ; J9.12 172.54,140.46 ; J9.12 170.92,140.46 ; J9.12 172.54,138.85 ; J9.12 170.92,138.85 ; TP9.1 188.66,119.8 ; TP9.1 187.05,121.41 ; TP9.1 188.66,121.41 ; TP9.1 187.05,119.8 ; TP1_1.1 177.72,15.07 ; TP1_1.1 176.65,14 ; TP1_1.1 177.72,12.93 ; TP1_1.1 178.79,14 ; J21.39 140.06,146.3 ; J21.39 138.63,146.3 ; J21.39 140.06,147.74 ; J21.39 138.63,147.74 ; J24.MTG4 71.05,3.41 ; J24.MTG4 69.44,3.41 ; J24.MTG4 69.44,1.79 ; J24.MTG4 71.05,1.79 ; 186.72,22.73 J37.30 ; J37.30 186.72,24.26 ; J37.30 188.24,24.26 ; J37.30 188.24,22.73 ; J7.5 37.89,64.32 ; J7.5 36.28,64.32 ; J7.5 37.89,65.93 ; J7.5 36.28,65.93 ; 58.02,35.77 J22.A12 ; J22.A12 58.02,34.55 ; J22.A12 59.24,34.55 ; J22.A12 59.24,35.77 ; 48.02,29.27 J22.B4 ; J22.B4 49.24,28.05 ; J22.B4 49.24,29.27 ; J22.B4 48.02,28.05 ; 157.99,4.82 J39.3 ; J39.3 159.51,4.82 ; J39.3 157.99,3.3 ; J39.3 159.51,3.3 ; J21.40 140.06,149.74 ; J21.40 140.06,148.3 ; J21.40 138.63,149.74 ; J21.40 138.63,148.3 ; 61.02,32.55 J22.A15 ; J22.A15 61.02,33.77 ; J22.A15 62.24,32.55 ; J22.A15 62.24,33.77 ; 79.46,149.05 TP8.1 ; TP8.1 81.07,150.67 ; TP8.1 79.46,150.67 ; TP8.1 81.07,149.05 ; 140.84,19.2 U18.M1 ; U18.M1 143.14,21.5 ; U18.M1 143.14,19.2 ; U18.M1 140.84,21.5 ; J22.A18 65.24,34.55 ; J22.A18 64.02,34.55 ; J22.A18 64.02,35.77 ; J22.A18 65.24,35.77 ; J10.13 41.01,144.7 ; J10.13 39.49,144.7 ; J10.13 41.01,143.18 ; J22.B16 63.24,28.05 ; J22.B16 62.02,28.05 ; J22.B16 63.24,29.27 ; J22.B16 62.02,29.27 ; 36.41,70.54 J4.5 ; J4.5 36.41,72.15 ; J4.5 38.02,72.15 ; J4.5 38.02,70.54 ; TP11.1 3.47,13.29 ; TP11.1 3.47,14.9 ; TP11.1 1.86,13.29 ; TP11.1 1.86,14.9 ; 140.84,29.3 U18.M2 ; U18.M2 143.14,29.3 ; U18.M2 143.14,27 ; U18.M2 140.84,27 ; 59.02,30.05 J22.B13 ; J22.B13 60.24,30.05 ; J22.B13 60.24,31.27 ; 54.34,8.31 J24.MTG1 ; J24.MTG1 55.95,6.69 ; J24.MTG1 55.95,8.31 ; J24.MTG1 54.34,6.69 ; J9.11 172.54,136.31 ; J9.11 170.92,137.92 ; J9.11 172.54,137.92 ; J9.11 170.92,136.31 ; 48.02,35.77 J22.A4 ; J22.A4 49.24,34.55 ; J22.A4 48.02,34.55 ; J22.A4 49.24,35.77 ; J24.MTG3 55.35,3.41 ; J24.MTG3 53.74,1.79 ; J24.MTG3 53.74,3.41 ; J24.MTG3 55.35,1.79 ; J22.B18 65.24,29.27 ; J22.B18 64.02,29.27 ; J22.B18 65.24,28.05 ; J22.B18 64.02,28.05 ; 39.74,14.52 J23.7 38.97,15.28 ; 180.07,2.81 J1_1.1 ; J1_1.1 181.59,2.81 ; J1_1.1 181.59,4.33 ; J1_1.1 180.07,4.33 ; J1.3 183.72,110.28 ; J1.3 183.72,113.24 ; J1.3 180.76,113.24 ; J1.3 180.76,110.28 ; 18.97,101.52 J5.8 ; J5.8 18.97,102.95 ; J5.8 20.41,102.95 ; J5.8 20.41,101.52 ; 19.69,126.36 20.41,127.08 ; 19.69,126.36 18.97,125.65 ; 19.69,126.36 20.41,125.65 ; 19.69,126.36 18.97,127.08 ; 53.33,66.54 J51.2 ; J51.2 54.94,66.54 ; J51.2 53.33,68.15 ; J51.2 54.94,68.15 ; J12.13 62.73,143.18 ; J12.13 61.21,144.7 ; J12.13 62.73,144.7 ; J12.1 61.68,133.23 ; J12.1 61.68,131.79 ; J12.1 60.24,131.79 ; J12.1 60.24,133.23 ; J24.MTG2 70.45,8.31 ; J24.MTG2 68.84,6.69 ; J24.MTG2 68.84,8.31 ; J24.MTG2 70.45,6.69 ; 51.02,31.27 J22.B7 ; J22.B7 51.02,30.05 ; J22.B7 52.24,31.27 ; J22.B7 52.24,30.05 ; J12.12 49.28,146.73 ; J12.12 47.76,145.21 ; J12.12 49.28,145.21 ; J12.12 47.76,146.73 ; 185.67,115.23 J2.2 ; J2.2 187.28,115.23 ; J2.2 185.67,113.62 ; J2.2 187.28,113.62 ; 63.02,30.05 J22.B17 ; J22.B17 64.24,31.27 ; J22.B17 63.02,31.27 ; J22.B17 64.24,30.05 ; J10.1 39.96,133.23 ; J10.1 38.53,133.23 ; J10.1 39.96,131.79 ; J10.1 38.53,131.79 ; J37.17 185.7,39.5 ; J37.17 185.7,37.97 ; J37.17 184.18,39.5 ; J37.17 184.18,37.97 ; 18.97,78.82 J6.8 ; J6.8 20.41,77.39 ; J6.8 20.41,78.82 ; J6.8 18.97,77.39 ; J44.2 84.37,110.23 ; J44.2 82.76,108.62 ; J44.2 82.76,110.23 ; J44.2 84.37,108.62 ; 74.42,1.86 TP10.1 ; TP10.1 74.42,3.47 ; TP10.1 76.03,1.86 ; TP10.1 76.03,3.47 ; J21.60 160.06,148.3 ; J21.60 158.63,149.74 ; J21.60 158.63,148.3 ; J21.60 160.06,149.74 ; SCKT1.MCH2 116.24,67.98 ; SCKT1.MCH2 116.24,70.27 ; SCKT1.MCH2 113.95,70.27 ; SCKT1.MCH2 113.95,67.98 ; 158.63,147.74 J21.59 ; J21.59 160.06,146.3 ; J21.59 158.63,146.3 ; J21.59 160.06,147.74 ; J23.4 43.83,13.19 ; J23.4 42.65,14.37 ; J23.4 42.65,13.19 ; 167.72,12.32 J46.1 ; J46.1 169.33,12.32 ; J46.1 167.72,10.71 ; J46.1 169.33,10.71 ; J10.12 27.57,146.73 ; J10.12 27.57,145.21 ; J10.12 26.04,146.73 ; J10.12 26.04,145.21 ; 88.23,96 SCKT1.MCH4 ; SCKT1.MCH4 90.52,96 ; SCKT1.MCH4 90.52,93.71 ; 184.18,22.73 J37.29 ; J37.29 184.18,24.26 ; J37.29 185.7,22.73 ; J37.29 185.7,24.26 ; J8.8 20.41,54.06 ; J8.8 18.97,52.63 ; J8.8 20.41,52.63 ; J8.8 18.97,54.06 ; J9.21 185.24,137.92 ; J9.21 183.62,137.92 ; J9.21 185.24,136.31 ; J9.21 183.62,136.31 ; J21.22 122.06,148.3 ; J21.22 120.63,149.74 ; J21.22 120.63,148.3 ; J21.22 122.06,149.74
  L6_PWR1 w0.508: 26.04,145.21 J10.12 ; J10.12 27.57,145.21 ; J10.12 26.04,146.73 ; J10.12 27.57,146.73 ; 18.97,125.65 19.69,126.36 ; 19.69,126.36 18.97,127.08 ; 19.69,126.36 20.41,127.08 ; 19.69,126.36 20.41,125.65 ; 47.76,146.73 J12.12 ; J12.12 49.28,146.73 ; J12.12 47.76,145.21 ; J12.12 49.28,145.21 ; 36.28,64.32 J7.5 ; J7.5 37.89,64.32 ; J7.5 36.28,65.93 ; J7.5 37.89,65.93 ; J12.1 61.68,131.79 ; J12.1 60.24,133.23 ; J12.1 61.68,133.23 ; J12.1 60.24,131.79 ; J4.5 38.02,72.15 ; J4.5 36.41,70.54 ; J4.5 36.41,72.15 ; J4.5 38.02,70.54 ; 18.97,78.82 J6.8 ; J6.8 20.41,78.82 ; J6.8 18.97,77.39 ; J6.8 20.41,77.39 ; 61.21,144.7 J12.13 ; J12.13 62.73,144.7 ; J12.13 62.73,143.18 ; J10.1 39.96,131.79 ; J10.1 38.53,131.79 ; J10.1 39.96,133.23 ; J10.1 38.53,133.23 ; 18.97,102.95 J5.8 ; J5.8 18.97,101.52 ; J5.8 20.41,102.95 ; J5.8 20.41,101.52 ; J10.13 41.01,143.18 ; J10.13 41.01,144.7 ; J10.13 39.49,144.7 ; 90.52,96 SCKT1.MCH4 88.23,96 ; J8.8 20.41,54.06 ; J8.8 18.97,54.06 ; J8.8 20.41,52.63 ; J8.8 18.97,52.63 ; 82.76,110.23 J44.2 ; J44.2 84.37,108.62 ; J44.2 82.76,108.62 ; J44.2 84.37,110.23
  L8_GND3 w0.508: J21.39 140.06,146.3 ; J21.39 138.63,146.3 ; J21.39 140.06,147.74 ; J21.39 138.63,147.74 ; J8.8 20.41,54.06 ; J8.8 18.97,54.06 ; J8.8 18.97,52.63 ; J8.8 20.41,52.63 ; 18.97,77.39 J6.8 ; J6.8 18.97,78.82 ; J6.8 20.41,78.82 ; J6.8 20.41,77.39 ; 47.76,145.21 J12.12 ; J12.12 49.28,145.21 ; J12.12 49.28,146.73 ; J12.12 47.76,146.73 ; TP10.1 76.03,3.47 ; TP10.1 76.03,1.86 ; TP10.1 74.42,1.86 ; TP10.1 74.42,3.47 ; 68.84,6.69 J24.MTG2 ; J24.MTG2 70.45,6.69 ; J24.MTG2 68.84,8.31 ; J24.MTG2 70.45,8.31 ; 177.51,115.08 J1.2 ; J1.2 177.51,118.04 ; J1.2 180.47,118.04 ; J1.2 180.47,115.08 ; J21.59 160.06,147.74 ; J21.59 158.63,146.3 ; J21.59 160.06,146.3 ; J21.59 158.63,147.74 ; J21.22 122.06,149.74 ; J21.22 120.63,149.74 ; J21.22 122.06,148.3 ; J21.22 120.63,148.3 ; TP9.1 188.66,121.41 ; TP9.1 187.05,119.8 ; TP9.1 187.05,121.41 ; TP9.1 188.66,119.8 ; 157.99,3.3 J39.3 ; J39.3 159.51,4.82 ; J39.3 159.51,3.3 ; J39.3 157.99,4.82 ; 59.02,30.05 J22.B13 ; J22.B13 60.24,30.05 ; J22.B13 60.24,31.27 ; J5.8 20.41,102.95 ; J5.8 18.97,102.95 ; J5.8 20.41,101.52 ; J5.8 18.97,101.52 ; 170.92,140.46 J9.12 ; J9.12 172.54,140.46 ; J9.12 170.92,138.85 ; J9.12 172.54,138.85 ; J22.B4 49.24,28.05 ; J22.B4 48.02,28.05 ; J22.B4 48.02,29.27 ; J22.B4 49.24,29.27 ; 42.65,13.19 J23.4 ; J23.4 43.83,13.19 ; J23.4 42.65,14.37 ; 39.74,14.52 J23.7 38.97,15.28 ; 69.44,1.79 J24.MTG4 ; J24.MTG4 71.05,1.79 ; J24.MTG4 71.05,3.41 ; J24.MTG4 69.44,3.41 ; J21.60 160.06,149.74 ; J21.60 160.06,148.3 ; J21.60 158.63,148.3 ; J21.60 158.63,149.74 ; J4.5 38.02,70.54 ; J4.5 36.41,70.54 ; J4.5 38.02,72.15 ; J4.5 36.41,72.15 ; 36.28,64.32 J7.5 ; J7.5 36.28,65.93 ; J7.5 37.89,64.32 ; J7.5 37.89,65.93 ; J24.MTG1 55.95,8.31 ; J24.MTG1 54.34,8.31 ; J24.MTG1 55.95,6.69 ; J24.MTG1 54.34,6.69 ; 64.02,35.77 J22.A18 ; J22.A18 64.02,34.55 ; J22.A18 65.24,34.55 ; J22.A18 65.24,35.77 ; J37.30 188.24,24.26 ; J37.30 188.24,22.73 ; J37.30 186.72,24.26 ; J37.30 186.72,22.73 ; 185.67,115.23 J2.2 ; J2.2 185.67,113.62 ; J2.2 187.28,115.23 ; J2.2 187.28,113.62 ; 140.84,29.3 U18.M2 ; U18.M2 143.14,29.3 ; U18.M2 143.14,27 ; U18.M2 140.84,27 ; 18.97,125.65 19.69,126.36 ; 19.69,126.36 18.97,127.08 ; 19.69,126.36 20.41,127.08 ; 19.69,126.36 20.41,125.65 ; 138.63,148.3 J21.40 ; J21.40 138.63,149.74 ; J21.40 140.06,148.3 ; J21.40 140.06,149.74 ; J1.3 183.72,113.24 ; J1.3 180.76,110.28 ; J1.3 183.72,110.28 ; J1.3 180.76,113.24 ; J12.1 61.68,131.79 ; J12.1 60.24,133.23 ; J12.1 61.68,133.23 ; J12.1 60.24,131.79 ; J1_1.1 181.59,2.81 ; J1_1.1 180.07,4.33 ; J1_1.1 181.59,4.33 ; J1_1.1 180.07,2.81 ; J10.12 27.57,145.21 ; J10.12 26.04,145.21 ; J10.12 27.57,146.73 ; J10.12 26.04,146.73 ; 140.84,21.5 U18.M1 ; U18.M1 143.14,21.5 ; U18.M1 140.84,19.2 ; U18.M1 143.14,19.2 ; J24.MTG3 55.35,3.41 ; J24.MTG3 53.74,1.79 ; J24.MTG3 55.35,1.79 ; J24.MTG3 53.74,3.41 ; 184.18,24.26 J37.29 ; J37.29 185.7,22.73 ; J37.29 185.7,24.26 ; J37.29 184.18,22.73 ; J46.1 169.33,10.71 ; J46.1 167.72,12.32 ; J46.1 169.33,12.32 ; J46.1 167.72,10.71 ; J9.21 185.24,137.92 ; J9.21 183.62,136.31 ; J9.21 185.24,136.31 ; J9.21 183.62,137.92 ; 61.02,32.55 J22.A15 ; J22.A15 61.02,33.77 ; J22.A15 62.24,33.77 ; J22.A15 62.24,32.55 ; J37.17 185.7,39.5 ; J37.17 184.18,37.97 ; J37.17 184.18,39.5 ; J37.17 185.7,37.97 ; 53.33,66.54 J51.2 ; J51.2 54.94,66.54 ; J51.2 54.94,68.15 ; J51.2 53.33,68.15 ; J22.A12 59.24,34.55 ; J22.A12 58.02,34.55 ; J22.A12 58.02,35.77 ; J22.A12 59.24,35.77 ; 38.53,133.23 J10.1 ; J10.1 39.96,133.23 ; J10.1 39.96,131.79 ; J10.1 38.53,131.79 ; J22.B16 63.24,28.05 ; J22.B16 62.02,29.27 ; J22.B16 62.02,28.05 ; J22.B16 63.24,29.27 ; 51.02,31.27 J22.B7 ; J22.B7 51.02,30.05 ; J22.B7 52.24,31.27 ; J22.B7 52.24,30.05 ; J12.13 62.73,143.18 ; J12.13 62.73,144.7 ; J12.13 61.21,144.7 ; J22.B17 64.24,31.27 ; J22.B17 63.02,31.27 ; J22.B17 63.02,30.05 ; J22.B17 64.24,30.05 ; 113.95,67.98 SCKT1.MCH2 ; SCKT1.MCH2 113.95,70.27 ; SCKT1.MCH2 116.24,70.27 ; SCKT1.MCH2 116.24,67.98 ; TP1_1.1 178.79,14 ; TP1_1.1 176.65,14 ; TP1_1.1 177.72,15.07 ; TP1_1.1 177.72,12.93 ; 1.86,13.29 TP11.1 ; TP11.1 3.47,13.29 ; TP11.1 1.86,14.9 ; TP11.1 3.47,14.9 ; 64.02,28.05 J22.B18 ; J22.B18 64.02,29.27 ; J22.B18 65.24,29.27 ; J22.B18 65.24,28.05 ; J10.13 41.01,144.7 ; J10.13 41.01,143.18 ; J10.13 39.49,144.7 ; 48.02,35.77 J22.A4 ; J22.A4 49.24,34.55 ; J22.A4 48.02,34.55 ; J22.A4 49.24,35.77 ; 79.46,149.05 TP8.1 ; TP8.1 81.07,150.67 ; TP8.1 81.07,149.05 ; TP8.1 79.46,150.67 ; 170.92,137.92 J9.11 ; J9.11 172.54,136.31 ; J9.11 170.92,136.31 ; J9.11 172.54,137.92
  L9_SIG3 w0.508: 58.02,35.77 J22.A12 ; J22.A12 58.02,34.55 ; J22.A12 59.24,35.77 ; J22.A12 59.24,34.55 ; 26.04,145.21 J10.12 ; J10.12 26.04,146.73 ; J10.12 27.57,146.73 ; J10.12 27.57,145.21 ; 18.97,78.82 J6.8 ; J6.8 18.97,77.39 ; J6.8 20.41,77.39 ; J6.8 20.41,78.82 ; 47.76,146.73 J12.12 ; J12.12 49.28,145.21 ; J12.12 49.28,146.73 ; J12.12 47.76,145.21 ; J7.5 37.89,65.93 ; J7.5 37.89,64.32 ; J7.5 36.28,65.93 ; J7.5 36.28,64.32 ; TP10.1 76.03,1.86 ; TP10.1 74.42,3.47 ; TP10.1 76.03,3.47 ; TP10.1 74.42,1.86 ; J24.MTG4 71.05,3.41 ; J24.MTG4 69.44,3.41 ; J24.MTG4 71.05,1.79 ; J24.MTG4 69.44,1.79 ; 54.34,6.69 J24.MTG1 ; J24.MTG1 55.95,6.69 ; J24.MTG1 55.95,8.31 ; J24.MTG1 54.34,8.31 ; J4.5 38.02,72.15 ; J4.5 36.41,72.15 ; J4.5 36.41,70.54 ; J4.5 38.02,70.54 ; 18.97,54.06 J8.8 ; J8.8 18.97,52.63 ; J8.8 20.41,54.06 ; J8.8 20.41,52.63 ; J24.MTG2 70.45,6.69 ; J24.MTG2 70.45,8.31 ; J24.MTG2 68.84,6.69 ; J24.MTG2 68.84,8.31 ; U18.M2 143.14,27 ; U18.M2 140.84,27 ; U18.M2 143.14,29.3 ; U18.M2 140.84,29.3 ; 1.86,14.9 TP11.1 ; TP11.1 3.47,13.29 ; TP11.1 3.47,14.9 ; TP11.1 1.86,13.29 ; 140.84,21.5 U18.M1 ; U18.M1 143.14,21.5 ; U18.M1 140.84,19.2 ; U18.M1 143.14,19.2 ; 177.72,12.93 TP1_1.1 ; TP1_1.1 176.65,14 ; TP1_1.1 177.72,15.07 ; 159.51,4.82 J39.3 157.99,4.82 ; J10.1 39.96,131.79 ; J10.1 38.53,131.79 ; J10.1 39.96,133.23 ; J10.1 38.53,133.23 ; 59.02,30.05 J22.B13 ; J22.B13 60.24,31.27 ; J22.B13 60.24,30.05 ; 51.02,31.27 J22.B7 ; J22.B7 52.24,30.05 ; J22.B7 52.24,31.27 ; J22.B7 51.02,30.05 ; J22.B17 64.24,30.05 ; J22.B17 63.02,31.27 ; J22.B17 63.02,30.05 ; J22.B17 64.24,31.27 ; 167.72,12.32 J46.1 ; J46.1 169.33,10.71 ; J46.1 169.33,12.32 ; J46.1 167.72,10.71 ; 38.97,15.28 J23.7 39.74,14.52 ; 62.02,29.27 J22.B16 ; J22.B16 62.02,28.05 ; J22.B16 63.24,29.27 ; J22.B16 63.24,28.05 ; J22.A4 49.24,35.77 ; J22.A4 49.24,34.55 ; J22.A4 48.02,35.77 ; J22.A4 48.02,34.55 ; J10.13 41.01,144.7 ; J10.13 41.01,143.18 ; J10.13 39.49,144.7 ; 42.65,14.37 J23.4 ; J23.4 42.65,13.19 ; J23.4 43.83,13.19 ; J22.A15 62.24,32.55 ; J22.A15 62.24,33.77 ; J22.A15 61.02,33.77 ; J22.A15 61.02,32.55 ; J22.B4 49.24,28.05 ; J22.B4 49.24,29.27 ; J22.B4 48.02,29.27 ; J22.B4 48.02,28.05 ; J24.MTG3 55.35,3.41 ; J24.MTG3 53.74,3.41 ; J24.MTG3 53.74,1.79 ; J24.MTG3 55.35,1.79 ; 53.33,68.15 J51.2 ; J51.2 53.33,66.54 ; J51.2 54.94,68.15 ; 64.02,28.05 J22.B18 ; J22.B18 64.02,29.27 ; J22.B18 65.24,29.27 ; J22.B18 65.24,28.05 ; J12.1 61.68,133.23 ; J12.1 60.24,131.79 ; J12.1 61.68,131.79 ; J12.1 60.24,133.23 ; 18.97,101.52 J5.8 ; J5.8 20.41,102.95 ; J5.8 20.41,101.52 ; J5.8 18.97,102.95 ; J12.13 62.73,144.7 ; J12.13 61.21,144.7 ; J12.13 62.73,143.18 ; 64.02,34.55 J22.A18 ; J22.A18 65.24,34.55 ; J22.A18 64.02,35.77 ; J22.A18 65.24,35.77
  L10_SIG4 w0.254: v5(110.63,77.37) 110.63,77.33 v11(111,76.97) ; v11(98.84,81.34) 98.64,81.14 v5(98.64,80.57) ; v11(111.03,83.22) v5(110.63,83.46) ; v5(99.44,80.57) 99.44,80.96 v11(99.8,81.32) ; v5(101.85,75.77) 101.6,75.52 v11(101.45,75.52) ; v11(96.65,80.8) 96.47,80.61 96.35,80.54 v5(96.24,80.57) ; v5(113.83,82.66) 114.19,82.66 v11(114.3,82.55) ; v5(101.02,75.72) 100.76,75.47 100.65,75.47 100.64,75.45 v11(100.63,75.45) ; v11(100.84,81.32) 100.24,80.72 v5(100.24,80.57) ; v11(93.84,86.41) v5(93.84,85.93) ; v5(100.24,76.56) 100,76.32 v11(99.84,76.32) ; v11(105.05,82.88) 105.21,82.85 105.8,83.21 v5(105.87,83.52) ; v11(110.23,88.02) v5(109.83,88.26) ; v5(104.23,80.57) 104.23,80.97 v11(104.5,81.23) ; v5(100.24,84.26) 100.39,84.26 v11(100.64,84.02) ; v11(109.43,88.02) v5(109.03,88.26) ; v11(107.87,83.9) 107.85,84 v5(107.43,84.26) ; v11(107.03,80.82) v5(107.43,80.57) ; v5(106.63,80.57) 106.61,80.46 106.43,80.35 106.41,80.29 106.32,80.23 v11(106.3,80.14) ; v11(101.85,82.3) 101.85,82.27 101.96,82.27 101.96,82.55 101.85,82.65 101.85,82.68 v11(101.84,82.68) ; v11(101.99,77.78) 102.3,77.47 v11(102.36,77.47) ; v11(95.85,87.08) v5(96.24,87.46) ; v11(99.84,82.42) v5(99.44,82.66) ; 101.1,80.57 v11(101.85,81.32) ; v11(100.64,84.82) v5(100.24,85.06) ; v11(100.64,85.62) v5(100.24,85.86) ; v11(111.83,83.22) v5(111.43,83.46) ; v5(97.84,80.57) 97.84,80.9 v11(97.7,81.03) ; v11(99.84,79.22) v5(99.44,78.97) ; v11(111.83,77.62) v5(111.43,77.37) ; v11(107.88,84.62) v5(108.23,84.26) ; v11(99.04,79.22) v5(98.64,78.97) ; v11(105.43,82.42) v5(105.83,82.66) ; v11(95.04,76.32) v5(95.44,76.57) ; v11(103.83,77.62) v5(104.23,77.37) ; v5(93.26,85.97) v11(93.26,86.46) ; v11(100.64,82.42) v5(100.24,82.66) ; v11(96.64,85.62) v5(96.24,85.86)
  L10_SIG4 w0.381: v9(87.4,81.66) v5(88.14,81.66) ; v9(36.93,100.44) v5(36.93,99.7) ; v9(86.74,67.69) v5(86.16,67.69) ; v5(101.04,80.57) 101.1,80.57 ; v9(103.63,110.19) v9(103.63,111.08)
  L10_SIG4 w0.508: J37.17 185.7,39.5 ; J37.17 184.18,37.97 ; J37.17 185.7,37.97 ; J37.17 184.18,39.5 ; J44.2 84.37,110.23 ; J44.2 84.37,108.62 ; J44.2 82.76,110.23 ; J44.2 82.76,108.62 ; 51.02,31.27 J22.B7 ; J22.B7 52.24,31.27 ; J22.B7 51.02,30.05 ; J22.B7 52.24,30.05 ; J22.A18 65.24,35.77 ; J22.A18 64.02,35.77 ; J22.A18 65.24,34.55 ; J22.A18 64.02,34.55 ; J46.1 169.33,12.32 ; J46.1 167.72,10.71 ; J46.1 167.72,12.32 ; J46.1 169.33,10.71 ; J10.1 39.96,133.23 ; J10.1 39.96,131.79 ; J10.1 38.53,133.23 ; J10.1 38.53,131.79 ; TP11.1 3.47,13.29 ; TP11.1 1.86,14.9 ; TP11.1 1.86,13.29 ; TP11.1 3.47,14.9 ; J37.29 185.7,22.73 ; J37.29 184.18,22.73 ; J37.29 184.18,24.26 ; J37.29 185.7,24.26 ; J22.B17 64.24,31.27 ; J22.B17 64.24,30.05 ; J22.B17 63.02,31.27 ; J22.B17 63.02,30.05 ; 187.05,119.8 TP9.1 ; TP9.1 187.05,121.41 ; TP9.1 188.66,121.41 ; TP9.1 188.66,119.8 ; 64.02,29.27 J22.B18 ; J22.B18 65.24,28.05 ; J22.B18 65.24,29.27 ; J22.B18 64.02,28.05 ; J24.MTG3 55.35,1.79 ; J24.MTG3 55.35,3.41 ; J24.MTG3 53.74,3.41 ; J24.MTG3 53.74,1.79 ; 180.76,110.28 J1.3 ; J1.3 183.72,110.28 ; J1.3 180.76,113.24 ; J1.3 183.72,113.24 ; 26.04,145.21 J10.12 ; J10.12 27.57,146.73 ; J10.12 26.04,146.73 ; J10.12 27.57,145.21 ; J2.2 187.28,113.62 ; J2.2 185.67,115.23 ; J2.2 185.67,113.62 ; J2.2 187.28,115.23 ; J22.A4 49.24,34.55 ; J22.A4 49.24,35.77 ; J22.A4 48.02,35.77 ; J22.A4 48.02,34.55 ; J10.13 41.01,143.18 ; J10.13 41.01,144.7 ; J10.13 39.49,144.7 ; 60.24,131.79 J12.1 ; J12.1 60.24,133.23 ; J12.1 61.68,133.23 ; J12.1 61.68,131.79 ; J1_1.1 181.59,4.33 ; J1_1.1 180.07,4.33 ; J1_1.1 181.59,2.81 ; J1_1.1 180.07,2.81 ; J22.B16 63.24,28.05 ; J22.B16 62.02,29.27 ; J22.B16 62.02,28.05 ; J22.B16 63.24,29.27 ; 18.97,127.08 19.69,126.36 20.41,127.08 ; 177.51,118.04 J1.2 ; J1.2 177.51,115.08 ; J1.2 180.47,115.08 ; J1.2 180.47,118.04 ; J22.B13 60.24,31.27 ; J22.B13 60.24,30.05 ; J22.B13 59.02,30.05 ; 48.02,29.27 J22.B4 ; J22.B4 48.02,28.05 ; J22.B4 49.24,29.27 ; J22.B4 49.24,28.05 ; J37.30 188.24,22.73 ; J37.30 186.72,22.73 ; J37.30 186.72,24.26 ; J37.30 188.24,24.26 ; TP1_1.1 177.72,15.07 ; TP1_1.1 178.79,14 ; TP1_1.1 177.72,12.93 ; 18.97,54.06 J8.8 18.97,52.63 ; J22.A12 59.24,35.77 ; J22.A12 59.24,34.55 ; J22.A12 58.02,35.77 ; J22.A12 58.02,34.55 ; 18.97,78.82 J6.8 ; J6.8 20.41,78.82 ; J6.8 18.97,77.39 ; J6.8 20.41,77.39 ; 69.44,1.79 J24.MTG4 ; J24.MTG4 71.05,3.41 ; J24.MTG4 71.05,1.79 ; J24.MTG4 69.44,3.41 ; J39.3 159.51,4.82 ; J39.3 159.51,3.3 ; J39.3 157.99,4.82 ; J39.3 157.99,3.3 ; J22.A15 62.24,33.77 ; J22.A15 61.02,33.77 ; J22.A15 62.24,32.55 ; J22.A15 61.02,32.55 ; 54.34,6.69 J24.MTG1 ; J24.MTG1 54.34,8.31 ; J24.MTG1 55.95,6.69 ; TP10.1 76.03,3.47 ; TP10.1 74.42,3.47 ; TP10.1 76.03,1.86 ; TP10.1 74.42,1.86 ; J12.13 62.73,143.18 ; J12.13 61.21,144.7 ; J12.13 62.73,144.7 ; 70.45,6.69 J24.MTG2 68.84,6.69 ; 47.76,145.21 J12.12 ; J12.12 49.28,145.21 ; J12.12 47.76,146.73 ; J12.12 49.28,146.73
  L11_GND4 w0.508: 138.63,148.3 J21.40 ; J21.40 138.63,149.74 ; J21.40 140.06,148.3 ; J21.40 140.06,149.74 ; 170.92,138.85 J9.12 ; J9.12 170.92,140.46 ; J9.12 172.54,140.46 ; J9.12 172.54,138.85 ; J10.12 27.57,145.21 ; J10.12 27.57,146.73 ; J10.12 26.04,146.73 ; J10.12 26.04,145.21 ; 38.53,133.23 J10.1 ; J10.1 39.96,131.79 ; J10.1 39.96,133.23 ; J10.1 38.53,131.79 ; 177.51,118.04 J1.2 ; J1.2 180.47,115.08 ; J1.2 180.47,118.04 ; J1.2 177.51,115.08 ; J5.8 20.41,102.95 ; J5.8 20.41,101.52 ; J5.8 18.97,101.52 ; J5.8 18.97,102.95 ; 68.84,8.31 J24.MTG2 ; J24.MTG2 70.45,8.31 ; J24.MTG2 70.45,6.69 ; J24.MTG2 68.84,6.69 ; J22.B4 49.24,28.05 ; J22.B4 49.24,29.27 ; J22.B4 48.02,28.05 ; J22.B4 48.02,29.27 ; J37.29 185.7,24.26 ; J37.29 185.7,22.73 ; J37.29 184.18,24.26 ; J37.29 184.18,22.73 ; J44.2 84.37,108.62 ; J44.2 82.76,110.23 ; J44.2 82.76,108.62 ; J44.2 84.37,110.23 ; 19.69,126.36 20.41,127.08 ; 19.69,126.36 18.97,127.08 ; 19.69,126.36 18.97,125.65 ; 19.69,126.36 20.41,125.65 ; 63.02,30.05 J22.B17 ; J22.B17 63.02,31.27 ; J22.B17 64.24,31.27 ; J22.B17 64.24,30.05 ; J8.8 20.41,54.06 ; J8.8 18.97,54.06 ; J8.8 20.41,52.63 ; J8.8 18.97,52.63 ; U18.M1 143.14,19.2 ; U18.M1 140.84,19.2 ; U18.M1 140.84,21.5 ; U18.M1 143.14,21.5 ; 157.99,4.82 J39.3 ; J39.3 159.51,3.3 ; J39.3 157.99,3.3 ; J39.3 159.51,4.82 ; 53.33,68.15 J51.2 ; J51.2 53.33,66.54 ; J51.2 54.94,68.15 ; J51.2 54.94,66.54 ; 180.07,4.33 J1_1.1 ; J1_1.1 181.59,2.81 ; J1_1.1 180.07,2.81 ; J1_1.1 181.59,4.33 ; J22.A18 65.24,34.55 ; J22.A18 65.24,35.77 ; J22.A18 64.02,34.55 ; J22.A18 64.02,35.77 ; J6.8 20.41,78.82 ; J6.8 20.41,77.39 ; J6.8 18.97,78.82 ; J6.8 18.97,77.39 ; 120.63,149.74 J21.22 ; J21.22 122.06,149.74 ; J21.22 122.06,148.3 ; J21.22 120.63,148.3 ; 88.23,96 SCKT1.MCH4 ; SCKT1.MCH4 88.23,93.71 ; SCKT1.MCH4 90.52,96 ; SCKT1.MCH4 90.52,93.71 ; J22.A15 62.24,32.55 ; J22.A15 61.02,32.55 ; J22.A15 62.24,33.77 ; J22.A15 61.02,33.77 ; 42.65,14.37 J23.4 ; J23.4 42.65,13.19 ; J23.4 43.83,13.19 ; TP11.1 3.47,14.9 ; TP11.1 1.86,14.9 ; TP11.1 3.47,13.29 ; TP11.1 1.86,13.29 ; J37.17 185.7,39.5 ; J37.17 184.18,37.97 ; J37.17 185.7,37.97 ; J37.17 184.18,39.5 ; 183.62,136.31 J9.21 ; J9.21 185.24,136.31 ; J9.21 183.62,137.92 ; J9.21 185.24,137.92 ; 59.02,30.05 J22.B13 ; J22.B13 60.24,31.27 ; J22.B13 60.24,30.05 ; J22.A12 59.24,35.77 ; J22.A12 58.02,34.55 ; J22.A12 58.02,35.77 ; J22.A12 59.24,34.55 ; 185.67,115.23 J2.2 ; J2.2 187.28,113.62 ; J2.2 187.28,115.23 ; J2.2 185.67,113.62 ; 140.84,29.3 U18.M2 ; U18.M2 140.84,27 ; U18.M2 143.14,27 ; U18.M2 143.14,29.3 ; 69.44,1.79 J24.MTG4 ; J24.MTG4 71.05,3.41 ; J24.MTG4 71.05,1.79 ; J24.MTG4 69.44,3.41 ; J12.12 49.28,146.73 ; J12.12 49.28,145.21 ; J12.12 47.76,145.21 ; J12.12 47.76,146.73 ; TP8.1 81.07,149.05 ; TP8.1 79.46,150.67 ; TP8.1 81.07,150.67 ; TP8.1 79.46,149.05 ; 158.63,146.3 J21.59 ; J21.59 158.63,147.74 ; J21.59 160.06,147.74 ; J21.59 160.06,146.3 ; 167.72,10.71 J46.1 ; J46.1 169.33,10.71 ; J46.1 167.72,12.32 ; J46.1 169.33,12.32 ; 54.34,6.69 J24.MTG1 ; J24.MTG1 54.34,8.31 ; J24.MTG1 55.95,6.69 ; J24.MTG1 55.95,8.31 ; J22.A4 49.24,35.77 ; J22.A4 49.24,34.55 ; J22.A4 48.02,35.77 ; J22.A4 48.02,34.55 ; 180.76,110.28 J1.3 ; J1.3 183.72,113.24 ; J1.3 180.76,113.24 ; J1.3 183.72,110.28 ; J4.5 38.02,70.54 ; J4.5 38.02,72.15 ; J4.5 36.41,72.15 ; J4.5 36.41,70.54 ; 51.02,31.27 J22.B7 ; J22.B7 51.02,30.05 ; J22.B7 52.24,31.27 ; J22.B7 52.24,30.05 ; J37.30 188.24,22.73 ; J37.30 186.72,24.26 ; J37.30 186.72,22.73 ; J37.30 188.24,24.26 ; 39.74,14.52 J23.7 38.97,15.28 ; 62.02,28.05 J22.B16 ; J22.B16 62.02,29.27 ; J22.B16 63.24,28.05 ; J22.B16 63.24,29.27 ; J12.13 62.73,143.18 ; J12.13 61.21,144.7 ; J12.13 62.73,144.7 ; 113.95,67.98 SCKT1.MCH2 ; SCKT1.MCH2 116.24,67.98 ; SCKT1.MCH2 113.95,70.27 ; SCKT1.MCH2 116.24,70.27 ; J22.B18 65.24,29.27 ; J22.B18 64.02,28.05 ; J22.B18 65.24,28.05 ; J22.B18 64.02,29.27 ; J21.39 140.06,147.74 ; J21.39 140.06,146.3 ; J21.39 138.63,147.74 ; J21.39 138.63,146.3 ; J7.5 37.89,65.93 ; J7.5 36.28,65.93 ; J7.5 36.28,64.32 ; J7.5 37.89,64.32 ; 74.42,3.47 TP10.1 ; TP10.1 76.03,3.47 ; TP10.1 76.03,1.86 ; TP10.1 74.42,1.86 ; 39.49,144.7 J10.13 ; J10.13 41.01,143.18 ; J10.13 41.01,144.7 ; 176.65,14 TP1_1.1 ; TP1_1.1 177.72,15.07 ; TP1_1.1 178.79,14 ; TP1_1.1 177.72,12.93 ; J21.60 160.06,149.74 ; J21.60 158.63,148.3 ; J21.60 160.06,148.3 ; J21.60 158.63,149.74 ; 53.74,3.41 J24.MTG3 ; J24.MTG3 55.35,3.41 ; J24.MTG3 55.35,1.79 ; J24.MTG3 53.74,1.79 ; 60.24,133.23 J12.1 ; J12.1 61.68,131.79 ; J12.1 61.68,133.23 ; J12.1 60.24,131.79 ; TP9.1 188.66,119.8 ; TP9.1 187.05,121.41 ; TP9.1 188.66,121.41 ; TP9.1 187.05,119.8 ; J9.11 172.54,137.92 ; J9.11 172.54,136.31 ; J9.11 170.92,137.92 ; J9.11 170.92,136.31
  BOTTOM w0.102: U62.D3 U62.E4
  BOTTOM w0.173: C292.2 118.98,76.05 v11(119,76.03) v11(119.39,76.03) ; v11(109.04,79.57) 108.74,79.28 C291.2
  BOTTOM w0.203: U62.C2 U62.C3 U62.D3 ; U62.E4 156.64,105.07 v1(156.64,105) ; U62.B4 v1(154.97,104.89) ; U75.5 170.44,65.96 170.15,66.25 v1(169.77,66.25)
  BOTTOM w0.254: v2(135.27,64.54) 135.27,64.56 U91.B3 ; v1(155.37,108.44) v1(155.37,107.8) U62.C1 U62.C2 ; U91.J8 140.87,60.55 v2(140.87,60.53) ; C564.2 100.31,83.69 100.62,84 100.64,84 100.66,84.02 ; U32.8 v2(74.04,144.61) ; U90.E1 v2(137.65,50.89) ; U90.G8 v2(139.25,46.08) ; U91.G8 139.32,61.25 139.32,61.29 v2(139.28,61.33) ; U90.A9 v2(134.84,44.35) ; v2(135.26,45.26) 135.27,45.26 U90.B9 ; 100.66,84.02 100.69,84.02 100.69,84.05 100.83,84.19 C380.2 ; 100.66,84.02 v11(100.64,84.02) ; U90.M1 v2(143.64,51.84) ; U91.E2 v2(137.66,65.34) ; J16.22 v1(83.18,124.4) ; U89.G4 149.52,94.99 v2(149.85,94.67) U89.F4 ; U43.J5 96.32,127.89 v2(96.32,126.95) 96.82,126.45 U43.K8 ; U89.H9 148.87,97.62 v2(148.84,97.59) U89.J8 ; C537.2 157.04,58.86 157.4,58.5 157.4,58.31 157.72,57.99 U92.4 ; U91.D1 v2(137.24,67.08) ; U91.T9 v2(146.84,59.59) ; U91.E1 v2(137.65,66.13) ; U89.H2 148.87,94.08 v2(148.72,94.23) ; v11(106.3,80.14) 106.3,80.67 C338.2 106.45,80.82 v11(107.03,80.82) ; U90.P9 v2(145.24,44.35) ; v2(29.59,35.13) 28.84,34.38 U45.14 ; v2(136.8,61.32) 136.85,61.32 U91.D8 ; U91.G9 v2(139.64,59.59) ; U91.M9 v2(143.64,59.59) ; U89.F7 150.17,96.94 v2(149.85,96.62) U89.G7 ; C421.2 185.36,81.57 v1(185.36,80.35) ; U90.J2 v2(140.86,50.87) ; U91.P1 v2(145.24,67.08) ; v1(54.74,89.87) 54.37,89.51 J17.6 ; v2(159.89,57.49) U92.8 ; v2(135.26,60.5) 135.27,60.5 U91.B9 ; U89.E4 v2(151.15,94.67) U89.D4 ; v2(135.63,67.08) 135.63,66.99 135.64,66.97 U91.B1 ; U90.D1 v2(137.24,51.84) ; U91.F9 v2(138.46,60.51) ; U90.T1 v2(146.84,51.84) ; v1(160.87,78.02) C240.1 ; v2(143.66,67.08) 143.64,67.06 U91.M1 ; U89.E7 v2(151.15,96.62) 151.47,96.94 U89.D7 ; U91.E8 v2(137.65,61.32) ; J16.19 v1(83.18,122.9) ; v2(99.44,128.63) 99.26,128.45 U43.P4 ; v2(140.86,45.3) U90.J8 ; U90.D8 137.22,45.69 v2(136.83,46.08) ; U90.B1 v2(135.64,51.84) ; v11(104.5,81.23) 104.11,80.85 C388.2 ; C566.2 98.5,77.98 99.19,77.98 99.44,78.24 99.44,78.81 v11(99.04,79.22) ; U89.J4 U89.J5 v2(148.68,95.64) ; U32.4 74.54,145.46 v2(74.91,145.09) ; U43.G5 v2(95.38,127.43) ; C318.2 140.95,133.59 v9(140.97,133.61) ; C339.2 101.8,77.26 102.15,77.26 v11(102.36,77.47) ; C394.2 96.26,81.25 v11(95.83,80.82) ; v1(140.97,56.98) C504.2 ; U89.K10 v2(147.57,99.35) ; v1(85.6,121.62) 85.47,121.62 85.26,121.4 J16.16 ; v2(154.31,99.4) 153.8,98.89 U89.A10 ; U90.P1 v2(145.24,51.84) ; U89.E6 v2(151.15,95.97) 151.47,96.29 U89.D6 ; U89.E9 v2(150.82,97.62) ; U91.P9 v2(145.24,59.59) ; U43.H10 95.88,125.61 v2(95.5,125.98) ; U72.28 v1(177.66,64.22) ; v1(82.93,118.4) J16.10 ; U89.B7 v2(152.31,96.94) ; v9(121.54,81.74) C548.2 ; U91.A9 v2(134.84,59.59) ; U90.E8 v2(137.66,46.07) ; U89.E5 v2(151.15,95.32) U89.D5 ; U89.G5 149.52,95.64 v2(149.85,95.32) U89.F5 ; J16.7 v1(83.18,116.9) ; U91.G1 v2(139.26,66.15) ; U91.J2 v2(140.85,66.12) ; U90.F9 v2(138.46,45.27) ; v1(81.91,119.9) J16.13 ; U43.P6 99.02,127.45 99.42,127.05 v2(99.42,126.92) v2(99.42,126.16) ; U90.M9 v2(143.64,44.35) ; U43.E7 v2(94.92,126.95) ; U90.B3 v2(135.26,49.3) ; U90.G9 v2(139.64,44.35) ; U89.F6 150.17,96.29 v2(149.85,95.97) U89.G6 ; U89.A1 v2(153.88,93.04) ; U90.T9 v2(146.84,44.35) ; U90.E2 v2(137.66,50.1) ; U90.G1 v2(139.26,50.91) ; U91.T1 v2(146.84,67.08)
  BOTTOM w0.305: U63.8 170.9,87.37 v1(171.22,87.69) ; U30.5 90.8,148.97 90.3,149.48 87.12,149.48 86.87,149.73 86.87,149.81 v1(86.79,149.81)
  BOTTOM w0.381: v1(20.95,28.66) 20.95,29.41 C305.2 21.97,29.41 v1(21.97,28.66) ; v1(18.97,18.14) 18.95,18.17 Q12.S ; U34.3 v1(167.07,84.22) ; 98.18,87.29 C267.2 ; 98.18,87.29 C327.2 ; 98.18,87.29 98.04,87.43 98.04,88.17 v11(97.9,88.31) ; C185.2 62.71,120.22 v1(62.71,119.24) ; v1(175.41,56.39) 175.43,56.37 C198.2 ; v1(68.72,136.61) 68.82,136.71 C215.2 68.78,137.8 67.71,137.8 v1(67.67,137.75) ; v1(31.37,125.18) 31.32,125.22 30.03,125.22 C157.2 30.2,126.32 v1(31.04,126.32) ; U71.3 v1(24.52,45.87) ; U73.9 v1(172.59,33.48) ; v1(68.14,83.29) 68.37,83.52 R706.1 ; C213.2 165,40.28 v1(165.02,40.26) ; v9(147.32,130.47) C281.2 146.3,131.27 v9(146.56,131.53) ; v11(92.8,82.14) 93.13,82.14 C447.2 ; C361.2 83.43,92.55 v11(83.57,92.41) ; C361.2 82.92,93.05 v11(82.3,93.05) ; C361.2 82.92,94.06 v11(82.3,94.06) ; C331.2 96.13,86 96.51,85.62 v11(96.64,85.62) ; v2(33.02,118.83) 32.24,118.83 C160.2 ; v1(48.18,127.16) 48.18,125.78 C178.2 48.39,125.58 v1(48.39,124.29) ; v11(157.86,84.87) 157.91,84.82 157.93,84.83 C241.2 159.59,84.83 v11(159.63,84.87) ; v1(84.71,39.75) 84.69,39.73 C30.2 ; v1(165.21,56.6) 165.11,56.5 C532.2 165.41,55.15 165.41,54.61 165.03,54.23 v1(164.97,54.23) ; C95.2 125.86,17.9 125.86,16.74 v1(126.06,16.54) ; C95.2 126.1,17.91 127.2,17.91 v1(127.25,17.96) ; C95.2 125.85,18.16 124.79,18.16 v1(124.59,17.96) ; C48.2 104.85,37.45 v2(104.82,37.48) ; U38.7 166.58,92.66 v1(166.07,92.16) ; R587.2 182.78,93.68 183.03,93.43 v9(183.16,93.43) ; U73.16 v1(163.7,33.61) ; v11(93.26,86.46) 93.26,85.57 C391.2 ; v1(42.04,92.79) 42.06,92.77 C113.2 ; C133.2 25.39,87.58 v1(25.98,87) ; C441.2 v1(70.1,65.11) ; C441.2 68.96,62.44 68.58,62.05 v1(68.58,61.12) ; C441.2 v1(70.1,58.33) ; U66.1 v1(28.19,5.08) ; R466.1 R455.1 R458.1 ; R466.1 v9(105.66,110.19) ; R466.1 R468.1 ; C399.2 140.73,130.43 v2(140.64,130.33) ; v5(88.14,81.66) v9(87.4,81.66) ; R414.1 75.82,149.7 75.95,149.82 ; v1(5.18,42.78) 4.81,42.4 J45.5 ; v1(175.41,46.23) 175.43,46.21 C202.2 ; R454.1 R461.1 R460.1 v9(110.87,114.64) v9(111.66,114.64) ; R454.1 R457.1 R456.1 v9(106.81,114.64) ; R454.1 v9(108.84,114.64) ; v1(44.83,143.76) 44.83,142.94 C187.1 ; v2(82.21,34.68) 81.95,34.94 C29.2 ; v1(171.2,16.97) C254.2 ; C74.2 112.41,36.98 112.91,37.48 v2(113.66,37.48) ; v1(22.48,140.16) C166.1 ; v11(117.2,73.23) v11(116.71,73.23) C289.2 ; R465.1 R464.1 v1(111.38,110.19) ; C192.2 61.06,108.43 v1(61.07,108.41) ; v1(20.08,34.86) 20.08,35.41 C306.2 21.07,35.64 21.07,35.32 21.1,35.29 v1(21.1,34.86) ; R381.1 v1(179.45,74.63) ; R433.1 179.86,95.2 v1(179.6,94.95) ; v9(80.14,74.68) L35.2 v9(80.14,77.47) ; v1(53.5,94.95) 53.52,94.97 C191.2 ; v1(41.15,101.61) 41.29,101.47 U23.5 ; v2(120.06,38.28) 119.87,38.47 C63.2 ; R754.1 v1(143.89,39.96) ; C67.2 97.48,34.94 v2(97.61,35.08) ; v11(101.45,75.52) 102.29,75.52 C294.2 ; v2(30.48,99.4) 30.23,99.14 C124.2 ; 9.02,9.35 v1(8.31,9.35) ; U25.5 55.23,98.79 v1(55.46,99.03) ; v1(25.27,28.66) 25.27,29.41 C307.2 26.29,29.41 v1(26.29,28.66) ; C319.2 186.73,97.73 v1(186.72,97.74) ; U33.4 v1(8.13,25.32) ; v1(56.39,94.19) C190.2 ; v1(77.72,140.52) 77.72,141.18 77.09,141.81 R417.1 ; v1(177.09,87.76) 176.7,87.37 U63.9 ; C330.2 v11(90.97,90.38) ; 9.02,2.62 v2(8.31,2.62) ; C572.2 86.72,67.71 v9(86.74,67.69) ; v1(92.33,136.35) 92.35,136.33 C265.2 ; C395.2 104.14,99.02 ; C395.2 103.24,98.26 ; C395.2 105.04,98.26 ; 87.88,78.99 88.33,78.55 v11(88.46,78.55) ; 87.88,78.99 L26.2 87.88,80.29 v9(88.43,80.84) ; 87.88,78.99 87.5,78.61 v11(87.07,78.61) ; v1(170.94,68.15) 170.96,68.13 C448.2 ; v1(12.37,11.28) 12.34,11.31 Q3.S ; v1(175.41,41.15) 175.43,41.13 C204.2 ; v11(113.33,78.94) C364.2 ; U95.8 v2(39.75,20.12) ; v1(42.93,3.99) C311.2 v1(44.58,5.64) ; v11(106.38,76.96) 105.81,76.96 C337.2 ; v1(156.46,54.82) 156.84,55.2 156.84,55.58 ; U73.10 v1(171.32,33.48) ; v9(24.26,133.56) C103.2 ; R463.1 R462.1 v1(109.35,110.19) ; v1(30.1,41.61) 29.72,41.23 L3.2 v1(27.05,41.23) ; Q13.S 18.95,14.86 v1(18.97,14.84) ; 49.2,119.5 C154.2 ; 49.2,119.5 49.2,119.33 49.7,118.83 v1(50.42,118.83) ; 49.2,119.5 49.35,119.66 49.35,120.19 v1(48.94,120.6) ; R592.1 v1(14.91,19.64) ; 46.51,104.59 46.52,104.59 v1(46.52,105.32) ; v1(66.01,142.42) 66.01,141.69 C188.1 ; v2(97.62,33.48) 97.62,33.27 97.26,32.91 C59.2 ; C209.2 160.42,38.54 v1(160.4,38.56) ; R104.1 v9(22.03,111.84) ; v2(97.45,29.08) 97.34,29.19 C57.2 ; C72.2 112.64,25.93 v2(112.69,25.88) ; v2(89.74,33.88) 89.79,33.93 C38.2 ; U19.3 v1(185.45,84.73) ; C69.2 99.93,39.99 v1(99.95,40) ; v9(143.87,122.43) 143.88,122.45 C562.2 ; 106.93,69.55 v11(106.93,68.99) ; v1(18.67,137.8) 18.65,137.82 C106.1 ; Q2.S 18.62,4.7 v1(18.92,4.4) ; U49.2 v1(170.56,39.88) ; R755.1 v1(143.89,55.2) ; v1(137.49,56.12) 137.41,56.12 137.41,56.13 138.24,56.13 C505.2 ; 75.95,149.82 v1(76.96,149.82) ; 75.95,149.82 v1(75.95,150.84) ; C11.2 92.41,74.87 v9(92.41,74.73) 92.91,74.22 C8.2 93.11,73.03 C7.2 93.03,72.51 v9(92.79,72.27) ; U69.3 30.47,88.33 v1(30.23,88.09) ; C443.2 168.85,82.1 v1(168.83,82.12) ; C76.2 120.09,37.45 v2(120.06,37.48) ; v2(97.45,25.88) 97.38,25.8 C51.2 ; v1(175.41,48.77) 175.43,48.75 C201.2 ; v1(40.89,127.46) C161.2 42.15,126.2 v1(42.16,126.19) ; v9(24,123.91) 24.24,123.67 C112.2 ; X1.2 v1(173.99,149.57) ; X1.2 171.39,149.57 ; X1.2 172.47,148.4 ; X1.2 172.47,150.75 ; v11(87.38,86.82) 87.76,86.82 88.01,86.57 L25.2 88.01,85.09 v11(87.63,84.71) ; v1(52.1,83.7) 53.02,84.62 v1(53.25,84.62) ; v1(27.43,30.31) C309.2 ; v11(107.87,83.9) 107.36,83.39 C353.2 ; v1(67.82,140.42) 68.44,140.42 C218.2 68.44,141.69 v1(67.82,141.69) ; C360.2 113.31,79.99 v11(113.33,80.02) ; 21.96,41.31 Y7.2 ; Y7.2 24.02,41.31 ; Y7.2 22.99,42.24 ; v1(99.08,148.45) 99.06,148.47 C211.2 ; C140.2 26.09,59.77 v1(26.16,59.85) ; v1(173.38,5.34) 173.48,5.23 C449.2 ; U2.3 v1(166.23,40.86) ; v2(89.74,25.88) 89.82,25.8 C35.2 ; v1(26.34,62.99) 26.17,62.82 C145.2 ; Q5.S 12.34,8.01 v1(12.37,7.98) ; C116.2 26.01,102.32 v1(26.12,102.43) ; v1(155.96,74.5) 155.97,74.52 C230.1 ; C50.2 104.63,38.89 v2(104.02,38.28) ; v11(114.3,82.55) L21.2 v11(111.46,82.55) ; U33.1 v1(11.94,25.32) ; R597.1 v1(14.91,12.91) ; v11(103.98,76.96) 103.98,76.96 C335.2 ; R256.1 v9(14.91,5.92) ; U73.7 v1(171.32,38.18) ; C60.2 111.02,32.75 v1(111,32.77) ; v2(89.74,29.08) 89.99,29.32 C37.2 ; v1(12.37,21.44) 12.34,21.47 Q10.S ; v1(60.58,126.37) 60.58,125.92 C183.2 ; 9.02,16.08 v1(8.31,16.08) ; R515.1 v1(14.91,16.21) ; v9(96.22,72.7) 96.53,73.01 C376.2 ; C79.2 112.55,28.94 v2(112.69,29.08) ; v9(143.76,121.62) 142.88,121.62 R432.2 ; v9(133.87,115.16) 133.92,115.11 134.32,115.11 134.83,115.63 C268.2 ; U73.8 v1(172.59,38.18) ; v1(140.97,72.22) C522.2 ; C34.2 89.39,38.89 v2(88.78,38.28) ; U38.5 166.37,95.2 v1(166.22,95.05) ; v1(81.53,112.1) 81.37,112.25 J16.MNT1 80.4,110.94 v1(80.64,110.7) ; v11(102.62,70.79) 102.23,71.17 C17.2 ; v1(171.2,25.61) C251.2 ; v9(38.99,115.67) 39.09,115.77 C159.2 v9(40.13,114.64) ; U33.2 v1(10.67,25.32) ; v1(150.11,69.68) C527.2 ; v1(49.04,117.04) 49.06,117.04 48.75,117.36 C153.2 ; C146.1 16.24,67.79 v1(16.26,67.77) ; C328.2 91.97,90.35 v11(91.95,90.38) ; C392.2 142.17,123.94 v2(141.44,123.94) ; C234.1 160.22,83.81 v1(160.2,83.82) ; U95.3 v2(39.75,17.98) ; 90.85,83.24 C298.2 90.85,82.28 ; v2(139.85,123.13) 139.85,122.48 R934.2 ; C32.2 90.11,37.45 v2(89.74,37.08) ; v1(42.67,120.35) 41.17,120.35 C164.2 ; C200.2 175.43,51.29 v1(175.41,51.31) ; v11(95.04,76.32) 95.51,76.32 95.8,76.03 96.06,76.03 ; v2(120.27,25.88) 120.35,25.8 C70.2 ; v11(87.4,84.08) C299.2 ; v1(41.29,105.27) 41.29,105.28 U23.10 ; v1(25.53,51.77) 25.53,52.58 26.11,53.16 C149.2 ; C78.2 112.29,32.91 v2(112.86,33.48) ; v11(102.87,66.27) v11(102.87,66.76) 102.87,67.39 ; C104.2 16.66,121.38 v1(16.64,121.37) ; v1(52.54,90.93) 52.58,90.98 52.58,91.42 52.1,91.9 52.1,92.57 v1(52.58,93.05) ; v1(161.04,51.7) 161.76,51.7 C569.2 ; C390.2 93.84,86.06 v11(93.84,86.41) ; v1(172.57,62.82) C444.2 ; C56.2 95.78,32.62 v1(95.76,32.64) ; U48.2 v1(171.66,53.55) ; v2(120.06,34.28) 120.41,33.93 C73.2 ; v1(12.37,18.14) 12.34,18.17 Q15.S ; C315.2 77.6,115.76 v1(77.6,116.29) ; C221.2 182.51,99.38 v1(182.52,99.4) ; v1(106.76,32.72) 106.76,32.38 106.28,31.9 C65.2 ; C356.2 107.91,85.29 v11(108.56,84.64) ; C66.2 105.23,29.32 v2(104.98,29.08) ; v1(10.01,118.06) C121.1 ; C62.2 115.72,32.4 115.48,32.16 114.74,32.16 v2(114.46,31.88) ; R246.1 15.62,2.08 15.97,1.73 v1(16.76,1.73) ; C31.2 82.06,36.98 82.56,37.48 v2(83.18,37.48) ; v1(61.84,127.46) 61.84,126.97 C182.2 v1(62.61,127.46) ; R570.2 v9(144.69,130.76) ; C573.2 91.95,73.84 v9(91.62,74.17) ; 46.51,100.81 46.51,100.81 46.51,101.54 ; C231.1 161.81,84.59 v1(161.21,84.59) ; v1(161.78,47.62) 161.78,48.37 161.8,48.39 ; v1(163.07,38.56) 163.05,38.54 C210.2 ; v1(175.41,43.69) 175.43,43.67 C203.2 ; v1(6.73,120.48) 6.73,119.72 ; v1(39.12,126.45) C162.2 ; v1(181.47,74.89) R382.1 v1(180.47,73.87) ; C266.2 89.46,91.22 v11(89.41,91.27) ; v11(85.47,81.94) L34.2 v11(85.47,84.43) ; C206.2 v1(187.83,78.08) ; v2(82.21,33.08) 82.05,32.91 C42.2 ; C393.2 90.82,81.93 91.03,82.14 ; U22.3 34.66,110.71 34.29,111.08 v9(34.29,111.46) ; v9(90.93,74.17) 90.8,74.04 C12.2 ; v1(27.65,121.75) 28.14,121.26 C155.2 ; v11(101.73,66.27) v11(101.73,66.76) 101.73,67.39 ; 9.02,5.92 v2(8.31,5.92) ; C236.2 165.16,85.49 165.74,84.92 v1(165.74,84.54) ; v2(84.78,37.48) 85.32,36.94 C41.2 ; R697.1 75.95,99.27 v1(75.77,99.27) ; C453.2 v9(131.65,127.36) ; v1(159.96,73.34) 160.67,74.05 U35.3 ; C383.2 136.04,129.88 v9(135.89,129.88) ; C107.2 23.35,132.14 v1(23.37,132.16) ; v1(182.13,61.42) C205.2 v1(182.13,63.84) ; C14.2 103.38,70.95 v11(103.45,70.87) ; v1(61.72,69.17) 61.23,68.68 U39.3 ; U26.3 v9(56.01,111.46) ; Q4.S 18.95,11.31 v1(18.97,11.28) ; v1(25.27,2.67) 24.38,2.67 ; v1(83.33,97.29) 83.43,97.19 C483.2 v1(82.16,96.09) ; v1(57.11,90.05) 57.1,90.03 C219.2 ; v1(176.91,23.45) 177.54,23.45 C208.2 178.1,24.11 v1(176.94,25.27) ; v2(88.78,31.88) 89.01,31.65 C39.2 ; C355.2 v11(105.05,82.88) ; C371.2 v9(107.04,75.37) ; v11(95.78,89.51) 95.89,89.62 C406.2 ; 9.02,12.78 v2(8.31,12.78) ; v1(31.5,30.31) C310.2 ; 6.73,71.46 v1(6.73,72.19) ; v9(55.37,111.59) 55.37,112.14 55.87,112.64 C189.2 55.87,113.01 55.4,113.48 v9(54.74,113.48) ; v1(25.4,106.63) 25.38,106.62 C119.2 ; R458.1 R459.1 R453.1 ; R458.1 v9(103.63,110.19) ; C446.2 90.82,86.87 91.19,86.87 v9(91.31,87) ; C94.2 112.52,20.32 v1(112.41,20.21) ; v1(35.51,38.82) C322.2 ; C228.1 166.78,78.79 v1(166.8,78.77) ; v9(109.86,82.89) 109.35,82.89 108.84,82.38 L24.2 108.84,81.23 109.22,80.85 v9(109.6,80.85) ; C404.2 90.78,84.15 v11(90.78,84.45) ; v9(136.66,115.7) 135.45,115.7 C268.2 ; U78.3 186.45,92.83 186.08,92.46 v1(185.39,92.46) ; v9(17.53,114.51) R108.1 ; C49.2 96.87,37.07 97.12,37.07 97.38,37.34 98.28,37.34 v2(98.42,37.48) ; C400.2 v11(95.73,85.49) ; C402.2 137.71,133.97 v1(137.71,134.67) ; v1(32.66,42.48) 32.34,42.16 31.71,42.16 C320.2 v1(31.5,43.64) ; v11(97.7,81.03) 98.02,80.72 C329.2 ; v9(61.85,114.64) C180.2 61.75,115.67 v9(60.71,115.67) ; C207.2 185.44,62.08 v1(185.42,62.06) ; 104.9,70.95 v11(104.9,70.39) ; v1(44.32,134.07) C167.1 ; C223.2 186.01,89.49 v1(185.19,89.49) ; C77.2 112.73,34.94 v2(112.86,35.08) ; C533.2 v1(158.37,61.93) ; R110.1 v9(19.87,112.98) ; v11(87.43,82.78) 87.44,82.77 87.98,82.77 87.99,82.78 ; v1(175.41,58.93) 175.43,58.91 C197.2 ; R380.1 v1(176.53,74.63) ; C472.2 75.44,115.78 v1(74.93,116.29) ; v1(68.83,139.4) C216.2 ; 60.2,98 v1(60.2,97.22) ; R453.1 101.6,109.3 101.23,109.3 100.71,108.78 v9(100.71,108.44) ; R453.1 v9(101.6,110.19) ; U97.3 v1(166.24,49.39) ; C268.2 135.38,115.7 v9(134.49,116.59) ; v1(171.74,76.09) C224.2 170.23,75.82 v1(171.25,74.81) ; U33.3 v1(9.4,25.32) ; C199.2 175.43,53.83 v1(175.41,53.85) ; U70.3 v1(17.51,67.81) ; C61.2 119.28,31.9 v2(119.26,31.88) ; v2(88.78,33.48) 89.38,32.87 C36.2 ; v1(55.23,102.33) U25.10 ; C302.2 139.08,130.87 v9(138.81,131.15) ; v1(11.94,33.3) C220.2 ; v1(24.97,95.6) 25.13,95.76 26.11,95.76 C125.2 v1(26.16,94.39) ; R467.1 v1(113.41,110.1) ; v1(149.73,67.26) C530.2 ; Q1.S 12.34,4.7 v1(12.37,4.68) ; v1(172.21,24.21) C253.2 ; v1(78.76,110.71) 78.66,110.81 C222.2 77.47,110.57 v1(78.49,109.56) ; C382.2 136.42,131.38 v9(136.4,131.4) ; v1(12.37,14.84) 12.34,14.86 Q11.S ; C571.2 162.15,40.28 v1(162.13,40.26) ; R109.1 v9(18.73,112.98) ; v1(16.26,92.66) 16.24,92.68 C131.1 ; v1(73.56,116.29) 73.56,115.42 R680.1 ; v1(35.51,39.83) C324.2 ; 80.77,78.23 v9(80.01,78.23) ; U98.3 v1(164.91,44.89) ; v1(167.51,47.45) C3.2 ; 60.2,101.05 60.2,101.93 v1(60.18,101.94) ; v9(36.93,100.44) C170.2 ; C71.2 115.26,38.9 v2(115.26,37.48) ; Q6.S 18.95,8.01 v1(18.97,7.98) ; C75.2 120.47,29.32 120.36,29.21 v2(120.27,29.21) ; v9(25.17,114.08) C108.2 ; v2(104.98,25.88) 105.06,25.8 C55.2 ; C139.2 v1(20.57,72.22) ; v11(98.2,84.02) C401.2 ; R252.1 v1(14.91,9.35) ; v1(175.13,79.68) C426.2 ; C237.1 v1(162.23,77.04) ; 38.61,108.41 v1(39.36,108.41) ; v2(104.82,34.28) 105.17,33.93 C68.2 ; U77.5 179.07,5.53 179.45,5.14 v1(179.7,5.14) ; C114.2 97.43,79.21 v11(97.43,80.04) ; R111.1 v9(21.02,112.98) ; C58.2 100.48,32.4 100.24,32.16 99.97,32.16 99.69,31.88 v2(99.22,31.88) ; U68.3 41.77,88.33 v1(41.15,87.71) ; C4.2 v1(169.56,43.81) ; v1(18.05,22.43) Q14.S ; v1(59.94,62.82) C248.2 ; 80.77,79.25 v9(80.01,79.25) ; v1(80.64,98.89) R695.1 ; v1(170.39,94.32) C245.2 ; 9.02,19.51 v1(8.31,19.51) ; v2(31.5,56.82) v2(30.48,56.82) ; v9(24.26,134.7) C102.2 ; v9(33.02,113.48) 33.53,113.48 C168.2 33.52,112.22 v9(33.02,112.22) ; v1(164.55,53.55) C5.2
  BOTTOM w0.508: v1(162.05,61.55) 162.03,61.53 C531.2 ; v9(145.03,120.1) 144.61,120.1 C274.2 143.76,120.95 v9(143.76,121.62) ; FB12.2 181.66,20.07 v1(181.64,20.04) ; FB12.2 182.84,21.2 v1(182.91,21.26) ; FB12.2 182.84,18.83 v1(182.85,18.82) ; C127.2 32.49,93.66 v1(32.51,93.68) ; v9(130.99,128.78) 131.11,128.91 132.25,128.91 C284.2 132.37,128.51 131.98,128.12 v9(131.34,128.12) ; Q20.S 79.45,102.21 v11(79.73,102.49) ; C96.2 119.48,17.67 v1(120.65,17.67) ; C96.2 v1(119.38,16.54) ; C96.2 119.28,17.67 v1(118.11,17.67) ; v9(140.72,115.65) C285.2 v9(141.61,116.58) ; v9(149.08,119.74) 148.98,119.84 C317.2 ; J9.21 185.24,136.31 ; J9.21 183.62,137.92 ; J9.21 183.62,136.31 ; v1(25.27,76.79) 25.27,76.79 26.16,77.68 C136.2 25.07,77.92 v1(24.97,77.82) ; C141.2 25.38,57.88 v1(25.4,57.87) ; C128.2 25.91,84.54 v1(26.16,84.79) ; C151.2 27.45,50.35 v1(27.69,50.12) ; U41.4 v1(170.56,16.21) ; Q25.S 68.4,99.98 v1(67.82,99.4) ; v1(75.62,103.23) 75.61,103.22 Q21.S ; v1(25.4,104.09) 25.38,104.08 C122.2 ; R709.1 68.58,97.24 v1(68.45,97.24) ; R785.1 v1(160.66,52.98) ; R431.2 143.92,125.18 v9(143.94,125.19) ; Q23.S v1(67.96,93.06) ; C143.2 25.38,61.53 v1(25.4,61.55) ; C543.2 v1(159.51,50.37) ; C317.2 148.98,121.88 v9(149.08,121.98) ; C317.2 v9(150.22,120.86) ; Q24.S 67.91,85.95 v1(67.87,85.91) ; R16.2 v9(133.31,122.38) ; v9(151.13,125.05) C283.2 v9(150.2,126.07) ; v9(150.2,122.38) C282.2 v9(151.13,123.27) ; v2(30.48,81.58) 30.26,81.36 C138.2 C134.2 ; C132.2 25.38,86.3 v1(25.4,86.31) ; 135.51,120.99 v9(135,120.48) ; 135.51,120.99 C272.2 v9(135.93,120.1) ; 135.51,120.99 135.13,121.37 v9(134.87,121.37) ; C417.2 156.7,102.98 v1(156.72,102.96) ; v1(25.3,100.41) 25.38,100.49 C117.2 ; v9(135.53,117.81) C468.2 v9(134.49,118.95) ; v1(72.14,99.8) 72.16,99.78 R700.1 ; v1(70.74,148.54) 71.03,148.54 C217.2 71.29,147.53 v1(70.61,147.53) ; v1(72.19,103.23) 72.18,103.22 Q22.S ; v1(25.27,82.66) 25.38,82.77 C129.2 ; v9(138.3,116.58) C452.2 v9(139.19,115.65) ; R704.1 v1(68.45,90.63) ; C212.2 v1(95.89,144.27) ; v1(28.19,76.28) R186.1 ; v9(145.03,118.83) C275.2 144.11,118.41 v9(143.64,117.94) ; v1(123.57,19.94) 123.55,19.96 C313.2 ; C544.2 v1(158.37,52.98) ; C126.2 C124.2 ; v1(28.5,51.41) 28.19,51.72 R228.1 ; J16.MNT2 v1(79.08,131.05) ; J16.MNT2 v1(80.4,132.37) ; J16.MNT2 v1(80.4,129.74) ; C578.2 v1(130.79,131.55) ; v1(129.79,24) C98.2 ; C476.2 v1(158.8,105) ; C150.2 C148.2 30.26,56.6 v2(30.48,56.82) ; R427.1 v1(158.37,103.6)
  vias: v1(2.54,149.81) v1(2.54,145.5) v1(2.54,142.96) v1(2.54,140.42) v1(2.54,137.88) v1(2.54,135.34) v1(2.54,132.8) v1(2.54,130.26) v1(2.54,127.72) v1(2.54,125.18) v1(2.54,122.64) v1(2.54,120.1) v1(2.54,117.56) v1(2.54,115.02) v1(2.54,112.48) v1(2.54,109.94) v1(2.54,107.4) v1(2.54,104.86) v1(2.54,102.32) v1(2.54,99.78) v1(2.54,97.24) v1(2.54,94.7) v1(2.54,92.16) v1(2.54,89.62) v1(2.54,87.08) v1(2.54,84.54) v1(2.54,82) v1(2.54,79.46) v1(2.54,76.92) v1(2.54,74.38) v1(2.54,71.84) v1(2.54,69.3) v1(2.54,66.76) v1(2.54,64.22) v1(2.54,61.68) v1(2.54,59.14) v1(2.54,56.6) v1(2.54,54.06) v1(2.54,34.04) v1(2.54,31.5) v1(2.54,28.96) v1(2.54,26.42) v1(2.54,23.88) v1(2.54,21.34) v1(2.54,18.8) v1(2.54,16.26) v1(2.54,11.18) v1(2.54,6.1) v1(2.54,3.56) v1(6.1,36.53) v1(6.1,35.51) v1(6.73,45.47) v1(6.73,44.2) v1(6.73,42.93) v1(6.86,34.04) v1(6.86,32.77) v1(6.86,31.5) v1(7.24,36.53) v1(7.24,35.51) v1(7.62,149.81) v1(10.16,149.81) v1(12.57,2.49) v1(12.7,149.81) v1(15.24,149.81) v1(16.89,41.1) v1(16.89,23.2) v1(17.65,37.67) v1(17.78,149.81) v1(18.03,23.58) v1(19.3,23.58) v1(20.19,37.67) v1(20.32,149.81) v1(22.73,37.67) v1(22.86,149.81) v1(24.23,40.34) v1(24.73,39.48) v1(25.4,149.81) v1(27.94,149.81) v1(27.94,2.54) v1(28.83,18.41) v1(28.83,17.14) v1(28.83,15.88) v1(30.48,149.81) v1(30.48,2.54) v1(32,14.31) v1(33.02,149.81) v1(35.56,149.81) v1(38.1,149.81) v1(39.12,42.7) v1(39.08,41.43) v1(39.08,40.16) v1(39.08,37.62) v1(39.08,35.08) v1(39.08,33.81) v1(39.08,32.54) v1(39.08,31.27) v1(39.08,30) v1(39.05,28.73) v1(39.54,22.85) v1(39.54,21.58) v1(39.69,43.84) v1(39.88,27) v1(40.59,44.74) v1(40.56,28.07) v1(40.64,149.81) v1(40.71,39.49) v1(40.71,38.22) v1(40.71,35.68) v1(40.71,34.41) v1(40.71,33.14) v1(40.71,31.87) v1(40.71,30.6) v1(40.71,29.33) v1(41.05,27.55) v1(41.04,26.28) v1(41.31,43.16) v1(41.48,45.64) v1(41.59,19.54) v1(41.59,18.27) v1(42.21,44.05) v1(42.38,46.53) v1(42.55,83.52) v1(42.55,82.25) v1(42.55,80.98) v1(42.85,25.5) v1(43.02,42) v1(42.99,40.73) v1(42.99,38.19) v1(42.99,36.92) v1(42.99,35.65) v1(42.99,34.38) v1(42.99,33.11) v1(42.99,31.84) v1(42.99,30.57) v1(42.99,28.03) v1(42.99,26.76) v1(43.11,44.95) v1(43.18,149.81) v1(43.18,2.54) v1(43.28,47.43) v1(43.86,42.96) v1(44.01,45.85) v1(44.18,48.33) v1(44.76,43.85) v1(45.09,91.14) v1(45.09,84.79) v1(45.08,49.23) v1(45.72,149.81) v1(45.65,44.75) v1(45.72,2.54) v1(45.97,50.13) v1(46.55,45.65) v1(46.7,48.54) v1(46.87,51.02) v1(46.99,82.25) v1(47.17,40.38) v1(47.6,49.44) v1(48,42.61) v1(48,41.34) v1(48.26,149.81) v1(48.26,2.54) v1(48.44,90.27) v1(48.5,50.34) v1(48.97,87.38) v1(49.58,89.13) v1(49.53,82.25) v1(49.53,80.98) v1(50.65,87.83) v1(50.8,149.81) v1(50.8,2.54) v1(51.13,58.24) v1(51.04,50.14) v1(51.19,53.03) v1(51.94,51.04) v1(52.09,53.93) v1(52.58,89.62) v1(52.76,59.51) v1(53.05,62.59) v1(53.34,149.81) v1(53.34,82.25) v1(53.34,80.98) v1(53.49,60.81) v1(53.74,52.84) v1(53.95,63.49) v1(54.26,61.82) v1(54.85,64.39) v1(55.16,62.72) v1(55.2,58.71) v1(55.2,57.44) v1(55.2,56.17) v1(55.41,60.22) v1(55.75,65.28) v1(55.88,149.81) v1(55.88,2.54) v1(56.06,63.62) v1(56.3,61.12) v1(56.96,64.51) v1(57.15,82.25) v1(57.2,62.03) v1(57.78,89.21) v1(57.86,65.41) v1(58.1,62.91) v1(58.42,149.81) v1(58.42,2.54) v1(58.47,78.19) v1(58.59,76.92) v1(58.59,75.65) v1(58.59,74.38) v1(58.59,73.11) v1(58.59,71.84) v1(58.59,70.57) v1(58.59,69.3) v1(58.83,79.41) v1(59,41.86) v1(59.68,80.34) v1(60.23,75.67) v1(60.23,74.4) v1(60.23,73.13) v1(60.23,71.86) v1(60.23,70.59) v1(60.58,81.24) v1(60.96,149.81) v1(61,79.22) v1(60.96,2.54) v1(61.48,82.14) v1(61.9,80.12) v1(62.23,45.72) v1(62.79,81.02) v1(63.07,70.95) v1(63.5,149.81) v1(63.5,43.18) v1(63.5,2.54) v1(64.31,69.27) v1(64.77,41.91) v1(65.07,85.73) v1(65.25,39.17) v1(65.49,83.71) v1(65.97,86.63) v1(66.04,149.81) v1(66.04,2.54) v1(66.42,112.22) v1(66.42,110.83) v1(66.39,84.61) v1(66.98,87.4) v1(67.24,82.39) v1(67.31,38.51) v1(68.15,80.65) v1(68.36,87.58) v1(68.58,149.81) v1(68.58,148.67) v1(68.58,2.54) v1(69.04,81.55) v1(73.66,2.54) v1(75.95,116.29) v1(77.09,75.9) v1(77.09,74.63) v1(78.74,149.81) v1(79.63,44.07) v1(79.63,42.8) v1(83.59,142.7) v1(84.55,149.04) v1(84.63,137.36) v1(90.17,66.5) v1(91.19,126.39) v1(91.19,38.23) v1(91.19,36.96) v1(91.19,35.69) v1(91.19,34.42) v1(91.44,40.13) v1(92.2,50.8) v1(92.23,47.12) v1(92.23,45.85) v1(92.23,44.58) v1(92.46,36.96) v1(92.46,35.69) v1(92.46,34.42) v1(94.26,138.13) v1(98.42,52.07) v1(99.15,140) v1(100.08,45.97) v1(100.97,42.42) v1(102.49,52.32) v1(102.49,51.05) v1(103.12,19.3) v1(103.63,47.62) v1(103.76,69.3) v1(103.89,51.69) v1(103.91,19.3) v1(103.89,18.54) v1(104.52,46.74) v1(105.03,44.7) v1(105.03,43.43) v1(105.03,42.16) v1(105.03,40.89) v1(106.3,40.89) v1(106.3,39.62) v1(106.3,38.35) v1(106.43,36.96) v1(106.43,35.69) v1(106.43,34.42) v1(107.7,36.96) v1(107.7,35.69) v1(107.7,34.42) v1(108.71,47.37) v1(110.6,17.29) v1(115.95,43.43) v1(115.95,42.16) v1(116.84,47.62) v1(121.03,43.69) v1(121.03,42.42) v1(121.03,41.15) v1(124.46,2.54) v1(125.6,117.68) v1(125.6,115.65) v1(126.36,116.67) v1(127,2.54) v1(129.54,2.54) v1(130.18,124.29) v1(132.08,2.54) v1(134.11,136.1) v1(134.62,2.54) v1(137.16,2.54) v1(139.7,2.54) v1(142.24,2.54) v1(144.78,2.54) v1(147.07,136.1) v1(147.32,2.54) v1(149.86,2.54) v1(150.75,105.49) v1(150.75,104.22) v1(152.15,104.22) v1(152.4,2.54) v1(153.16,104.22) v1(154.69,53.17) v1(154.81,62.31) v1(154.81,61.42) v1(154.94,2.54) v1(155.58,127.08) v1(155.58,125.68) v1(155.83,53.17) v1(155.96,62.31) v1(155.96,61.42) v1(156.72,125.68) v1(156.84,54.06) v1(156.84,53.17) v1(157.4,84.33) v1(159.97,111.43) v1(159.97,110.16) v1(161.24,111.43) v1(161.24,110.16) v1(163.65,150.04) v1(163.86,142.98) v1(165.56,150.39) v1(165.84,142.09) v1(167.67,131.15) v1(167.67,129.75) v1(167.67,128.22) v1(167.71,126.06) v1(167.71,123.52) v1(169.37,142.11) v1(171.09,131.15) v1(171.09,129.75) v1(171.09,128.22) v1(171.91,142.11) v1(174.02,143.87) v1(173.99,9.37) v1(177.14,5.08) v1(180.75,131.02) v1(183.03,149.81) v1(184.05,11.3) v1(184.18,131.02) v1(185.29,142.62) v1(186.44,77.12) v1(187.07,141.61) v1(188.11,149.81) v1(188.18,146.38) v1(188.18,118.44) v1(188.18,115.9) v1(188.18,110.82) v1(188.18,108.28) v1(188.18,105.74) v1(188.18,103.2) v1(188.18,6.98) v1(188.18,4.44) v2(20.07,117.43) v2(21.34,118.7) v2(28.32,37.67) v2(28.32,36.4) v2(28.32,35.13) v2(29.59,37.67) v2(29.59,36.4) v2(30.48,101.43) v2(30.48,100.41) v2(30.48,83.61) v2(30.48,82.6) v2(30.48,58.85) v2(30.48,57.83) v2(30.86,37.67) v2(30.86,36.4) v2(30.86,35.13) v2(31.5,101.43) v2(31.5,100.41) v2(31.5,99.4) v2(31.5,83.61) v2(31.5,82.6) v2(31.5,81.58) v2(31.5,58.85) v2(31.5,57.83) v2(32.51,101.43) v2(32.51,100.41) v2(32.51,99.4) v2(32.51,83.61) v2(32.51,82.6) v2(32.51,81.58) v2(32.51,58.85) v2(32.51,57.83) v2(32.51,56.82) v2(33.02,123.02) v2(33.02,120.86) v2(35.23,122.97) v2(35.31,118.83) v2(35.69,16.51) v2(35.81,22.86) v2(35.97,25.04) v2(36.14,17.33) v2(37.41,123.19) v2(37.36,120.65) v2(37.34,118.83) v2(37.57,17.88) v2(37.85,16.51) v2(38.3,24.16) v2(38.35,22.86) v2(39.63,52.19) v2(41.49,54.58) v2(42.55,55.22) v2(43.81,16.51) v2(49.15,58.29) v2(54.74,123.02) v2(54.74,120.86) v2(54.74,118.83) v2(56.95,122.97) v2(57.02,118.83) v2(59.08,120.65) v2(59.05,118.83) v2(59.13,123.19) v2(73.13,145.09) v2(73.3,144.12) v2(74.91,144.07) v2(78.05,80.09) v2(80.42,80.59) v2(81.82,147.64) v2(82.36,149.74) v2(82.47,148.34) v2(107.06,15.24) v2(107.06,14.22) v2(108.58,15.24) v2(108.58,14.22) v2(126.24,122.64) v2(152.53,25.35) v2(174.99,8.9) v2(178.08,69.47) v2(178.08,68.2) v2(178.08,66.93) v2(179.35,69.47) v2(179.35,68.2) v2(179.35,66.93) v2(180.62,69.47) v2(180.62,68.2) v2(180.62,66.93) v2(181.89,69.47) v2(181.89,68.2) v2(181.89,66.93) v2(183.16,69.47) v2(183.16,68.2) v2(183.16,66.93) v2(184.43,69.47) v2(184.43,68.2) v2(184.43,66.93) v2(185.7,69.47) v2(185.7,68.2) v2(185.7,66.93) v3(87.7,88.44) v3(87.74,84.39) v3(88.21,88.4) v3(88.36,86.91) v3(88.63,88.16) v3(88.8,85.51) v3(88.86,86.92) v3(89.27,88.02) v3(89.36,86.74) v3(89.41,85.11) v3(89.76,86.46) v3(89.83,87.8) v3(90.01,84.66) v3(90.18,86.16) v3(90.57,85.83) v3(90.66,84.55) v3(90.93,86.9) v3(91.88,84.71) v3(94.23,84.18) v3(94.97,83.98) v4(87.7,88.44) v4(87.74,84.39) v4(88.21,88.4) v4(88.36,86.91) v4(88.63,88.16) v4(88.8,85.51) v4(88.86,86.92) v4(89.27,88.02) v4(89.36,86.74) v4(89.41,85.11) v4(89.76,86.46) v4(89.83,87.8) v4(90.01,84.66) v4(90.18,86.16) v4(90.57,85.83) v4(90.66,84.55) v4(90.93,86.9) v4(91.88,84.71) v4(94.23,84.18) v4(94.97,83.98) v4(107.83,76.82) v5(115.32,53.17) v5(116.33,53.17) v5(116.33,52.28) v5(117.47,52.28) v5(117.47,51.26) v5(126.87,36.02) v6(16.13,114.56) v6(17.58,114.58) v6(19.61,112.45) v6(19.69,111.03) v6(27.2,106.15) v6(34.52,107.32) v6(39.07,38.86) v6(39.07,36.32) v6(39.57,63.02) v6(39.6,62.21) v6(39.6,60.91) v6(39.62,58.7) v6(39.7,87.66) v6(39.73,86.85) v6(39.73,85.55) v6(39.65,59.85) v6(39.78,104.83) v6(39.8,104.02) v6(39.8,102.72) v6(39.83,100.51) v6(39.78,84.49) v6(39.75,83.34) v6(39.85,101.66) v6(40.72,41.02) v6(40.72,36.96) v6(40.84,42.04) v6(42.88,39.37) v6(43,29.21) v6(43.69,96.65) v6(44.22,94.77) v6(45.21,98.68) v6(46.66,92.82) v6(48.25,15.87) v6(48.89,91.65) v6(49.2,94.26) v6(51.79,90.78) v6(52.78,51.94) v6(54.1,93.43) v6(54.69,53.85) v6(55.07,54.99) v6(56.62,90.78) v6(58.37,67.95) v6(58.83,93.45) v6(58.88,66.29) v6(60.15,77.98) v6(60.15,76.71) v6(60.53,67.95) v6(60.53,65.41) v6(60.86,93.78) v6(61.21,98.76) v6(61.21,95.97) v6(61.42,66.29) v6(61.52,90.89) v6(61.61,112.13) v6(62.31,82.93) v6(62.31,67.31) v6(62.43,69.98) v6(62.88,111.36) v6(62.94,83.57) v6(63.2,68.2) v6(63.6,93.12) v6(63.58,84.2) v6(63.58,81.79) v6(64.16,98.07) v6(64.21,84.84) v6(64.21,82.42) v6(64.31,99.52) v6(64.64,113.04) v6(64.72,83.06) v6(64.72,70.48) v6(65.23,71.88) v6(68.33,116.52) v6(70.2,115.22) v6(70.56,91.09) v6(70.64,85.83) v6(71.15,87.79) v6(71.58,85.85) v6(71.72,116.44) v6(72.59,85.85) v6(73.1,90.96) v6(73.3,87.77) v6(73.43,115.2) v6(73.46,85.85) v6(74.55,88.33) v6(76.3,86.39) v6(76.33,90.91) v6(76.54,89.2) v6(77.14,115.22) v6(77.31,84.92) v6(78.05,85.71) v6(78.86,86.34) v6(79.1,116.66) v6(79.12,89.28) v6(80.46,89.09) v6(80.98,115.18) v6(81.65,85.99) v6(88.23,116.67) v6(89.58,123.92) v6(90.2,115.5) v6(91.86,116.77) v6(92.62,115.5) v6(93.25,114.61) v6(95.41,114.61) v6(97.06,114.61) v6(100.75,116.77) v6(102.02,125.03) v6(102.74,123.65) v6(105.57,116.77) v6(105.57,115.12) v6(106.05,123.75) v6(107.1,123.12) v6(107.48,115.37) v6(111.41,111.56) v6(114.22,116.13) v6(115.86,115.88) v6(116.62,113.72) v6(117.51,114.23) v6(118.61,95.97) v6(118.87,106.41) v6(119.63,94.44) v6(120.65,101.94) v6(122.22,102.67) v6(133.73,139.15) v6(133.73,137.88) v6(134.37,140.54) v6(134.37,134.19) v6(136.4,140.67) v6(137.03,134.07) v6(138.68,140.54) v6(139.32,138.13) v6(149.28,83.95) v6(150.29,80.78) v6(151.05,87.89) v6(152.07,80.78) v6(153.47,84.21) v6(154.1,81.92) v6(155.5,87.63) v6(155.5,82.17) v6(158.67,86.36) v6(165.23,120.22) v6(165.25,119.21) v6(165.25,117.81) v6(165.74,123.27) v6(165.76,122) v6(165.76,120.86) v6(166.9,122) v6(166.9,120.86) v7(16.13,114.56) v7(17.58,114.58) v7(19.61,112.45) v7(19.69,111.03) v7(27.2,106.15) v7(34.52,107.32) v7(39.07,38.86) v7(39.07,36.32) v7(39.57,63.02) v7(39.6,62.21) v7(39.6,60.91) v7(39.62,58.7) v7(39.7,87.66) v7(39.73,86.85) v7(39.73,85.55) v7(39.65,59.85) v7(39.78,104.83) v7(39.8,104.02) v7(39.8,102.72) v7(39.83,100.51) v7(39.78,84.49) v7(39.75,83.34) v7(39.85,101.66) v7(40.72,41.02) v7(40.72,36.96) v7(40.84,42.04) v7(42.88,39.37) v7(43,29.21) v7(43.69,96.65) v7(44.22,94.77) v7(45.21,98.68) v7(46.66,92.82) v7(48.25,15.87) v7(48.89,91.65) v7(49.2,94.26) v7(51.79,90.78) v7(52.78,51.94) v7(54.1,93.43) v7(54.69,53.85) v7(55.07,54.99) v7(56.62,90.78) v7(58.37,67.95) v7(58.83,93.45) v7(58.88,66.29) v7(60.15,77.98) v7(60.15,76.71) v7(60.53,67.95) v7(60.53,65.41) v7(60.86,93.78) v7(61.21,98.76) v7(61.21,95.97) v7(61.42,66.29) v7(61.52,90.89) v7(61.61,112.13) v7(62.31,82.93) v7(62.31,67.31) v7(62.43,69.98) v7(62.88,111.36) v7(62.94,83.57) v7(63.2,68.2) v7(63.6,93.12) v7(63.58,84.2) v7(63.58,81.79) v7(64.16,98.07) v7(64.21,84.84) v7(64.21,82.42) v7(64.31,99.52) v7(64.64,113.04) v7(64.72,83.06) v7(64.72,70.48) v7(65.23,71.88) v7(68.33,116.52) v7(70.2,115.22) v7(70.56,91.09) v7(70.64,85.83) v7(71.15,87.79) v7(71.58,85.85) v7(71.72,116.44) v7(72.59,85.85) v7(73.1,90.96) v7(73.3,87.77) v7(73.43,115.2) v7(73.46,85.85) v7(74.55,88.33) v7(76.3,86.39) v7(76.33,90.91) v7(76.54,89.2) v7(77.14,115.22) v7(77.31,84.92) v7(78.05,85.71) v7(78.86,86.34) v7(79.1,116.66) v7(79.12,89.28) v7(80.46,89.09) v7(80.98,115.18) v7(81.65,85.99) v7(88.23,116.67) v7(89.58,123.92) v7(90.2,115.5) v7(91.86,116.77) v7(92.62,115.5) v7(93.25,114.61) v7(95.41,114.61) v7(97.06,114.61) v7(100.75,116.77) v7(102.02,125.03) v7(102.74,123.65) v7(105.57,116.77) v7(105.57,115.12) v7(106.05,123.75) v7(107.1,123.12) v7(107.48,115.37) v7(111.41,111.56) v7(114.22,116.13) v7(115.86,115.88) v7(116.62,113.72) v7(117.51,114.23) v7(118.61,95.97) v7(118.87,106.41) v7(119.63,94.44) v7(120.65,101.94) v7(122.22,102.67) v7(133.73,139.15) v7(133.73,137.88) v7(134.37,140.54) v7(134.37,134.19) v7(136.4,140.67) v7(136.65,129.53) v7(137.03,134.07) v7(138.68,140.54) v7(139.32,138.13) v7(149.28,83.95) v7(150.29,80.78) v7(151.05,87.89) v7(152.07,80.78) v7(153.47,84.21) v7(154.1,81.92) v7(155.5,87.63) v7(155.5,82.17) v7(158.67,86.36) v7(165.23,120.22) v7(165.25,119.21) v7(165.25,117.81) v7(165.74,123.27) v7(165.76,122) v7(165.76,120.86) v7(166.9,122) v7(166.9,120.86) v8(14.71,109.76) v8(14.76,112.12) v8(15.09,117.78) v8(15.57,107.57) v8(15.82,112.22) v8(16.61,113.01) v8(16.89,114.66) v8(20.8,111.36) v8(21.74,106.08) v8(27.05,105.03) v8(30.23,109.89) v8(31.67,105.36) v8(32.11,108.97) v8(36.55,108.72) v8(43.81,103.46) v8(44.07,104.09) v8(44.58,99.27) v8(44.83,107.14) v8(45.97,107.14) v8(47.24,99.14) v8(47.5,107.14) v8(49.02,107.14) v8(49.15,98.89) v8(50.93,107.14) v8(51.18,99.65) v8(51.31,105.49) v8(51.56,101.43) v8(54.79,106.53) v8(63.65,103.69) v8(67.64,102.52) v8(68.35,114.15) v8(68.45,108.92) v8(68.45,108.03) v8(70.15,113.16) v8(74.04,104.14) v8(80.64,82.8) v8(80.64,81.41) v8(80.85,103.99) v8(82.17,86.36) v8(82.68,77.22) v8(84.3,112.45) v8(87.76,121.65) v8(89.99,120.68) v8(92.1,121.65) v8(92.21,70.34) v8(92.2,68.15) v8(94.11,120.68) v8(94.59,69.6) v8(95.07,70.31) v8(96.24,69.29) v8(97.35,92.83) v8(97.35,91.81) v8(97.35,91.05) v8(97.74,120.68) v8(100.15,121.32) v8(101.35,90.51) v8(102.36,90.51) v8(103.38,90.51) v8(103.5,118.95) v8(104.77,119.21) v8(105,111.43) v8(105.49,112.76) v8(108.18,105.82) v8(110.54,76.59) v8(115.7,76.33) v8(116.33,75.21) v8(116.87,78.03) v8(116.87,77.24) v8(118.75,80.09) v8(118.75,79.08) v8(118.87,52.53) v8(118.87,51.26) v8(119.89,52.53) v8(119.89,51.26) v8(120.27,91.39) v8(120.27,87.97) v8(120.9,52.53) v8(120.9,51.26) v8(121.41,91.39) v8(121.41,87.97) v8(122.68,90.76) v8(122.68,89.74) v8(122.68,88.73) v8(128.02,103.18) v8(128.27,105.36) v8(128.33,124.3) v8(129.22,124.3) v8(129.29,105.41) v8(129.87,132.25) v8(129.87,131.62) v8(130.24,125.82) v8(130.24,125.06) v8(130.24,123.41) v8(130.94,126.45) v8(131.32,125.18) v8(131.95,135.34) v8(132.21,125.18) v8(132.21,123.25) v8(132.72,135.34) v8(132.84,123.25) v8(134.1,115.73) v8(134.37,135.34) v8(135.38,114.64) v8(135.69,135) v8(142.88,136.61) v8(143.76,136.61) v8(144.78,136.61) v8(145.67,136.61) v8(148.34,133.69) v8(148.34,132.92) v8(148.34,132.16) v8(148.34,128.99) v8(148.34,128.22) v8(148.34,127.59) v8(175.29,26.42) v9(14.71,109.76) v9(14.76,112.12) v9(15.09,117.78) v9(15.57,107.57) v9(15.82,112.22) v9(16.61,113.01) v9(16.89,114.66) v9(20.8,111.36) v9(21.74,106.08) v9(27.05,105.03) v9(30.23,109.89) v9(31.67,105.36) v9(32.11,108.97) v9(36.55,108.72) v9(43.81,103.46) v9(44.07,104.09) v9(44.58,99.27) v9(44.83,107.14) v9(45.97,107.14) v9(47.24,99.14) v9(47.5,107.14) v9(49.02,107.14) v9(49.15,98.89) v9(50.93,107.14) v9(51.18,99.65) v9(51.31,105.49) v9(51.56,101.43) v9(54.79,106.53) v9(63.65,103.69) v9(67.64,102.52) v9(68.35,114.15) v9(68.45,108.92) v9(68.45,108.03) v9(70.15,113.16) v9(74.04,104.14) v9(80.64,82.8) v9(80.64,81.41) v9(80.85,103.99) v9(82.17,86.36) v9(82.68,77.22) v9(84.3,112.45) v9(87.76,121.65) v9(89.99,120.68) v9(92.1,121.65) v9(92.21,70.34) v9(92.2,68.15) v9(94.11,120.68) v9(94.59,69.6) v9(95.07,70.31) v9(96.24,69.29) v9(97.35,92.83) v9(97.35,91.81) v9(97.35,91.05) v9(97.74,120.68) v9(100.15,121.32) v9(101.35,90.51) v9(102.36,90.51) v9(103.38,90.51) v9(103.5,118.95) v9(104.77,119.21) v9(105,111.43) v9(105.49,112.76) v9(108.18,105.82) v9(110.54,76.59) v9(115.7,76.33) v9(116.33,75.21) v9(116.87,78.03) v9(116.87,77.24) v9(118.75,80.09) v9(118.75,79.08) v9(118.87,52.53) v9(118.87,51.26) v9(119.89,52.53) v9(119.89,51.26) v9(120.27,91.39) v9(120.27,87.97) v9(120.9,52.53) v9(120.9,51.26) v9(121.41,91.39) v9(121.41,87.97) v9(122.68,90.76) v9(122.68,89.74) v9(122.68,88.73) v9(128.02,103.18) v9(128.27,105.36) v9(128.33,124.3) v9(129.22,124.3) v9(129.29,105.41) v9(129.87,132.25) v9(129.87,131.62) v9(130.24,125.82) v9(130.24,125.06) v9(130.24,123.41) v9(130.94,126.45) v9(131.32,125.18) v9(131.95,135.34) v9(132.21,125.18) v9(132.21,123.25) v9(132.72,135.34) v9(132.84,123.25) v9(134.37,135.34) v9(135.69,135) v9(142.88,136.61) v9(143.76,136.61) v9(144.78,136.61) v9(145.67,136.61) v9(148.34,133.69) v9(148.34,132.92) v9(148.34,132.16) v9(148.34,128.99) v9(148.34,128.22) v9(148.34,127.59) v9(175.29,26.42) v10(27.41,113.26) v10(27.46,115.47) v10(27.64,111.26) v10(31.32,106.02) v10(33.45,106.08) v10(34.26,105.47) v10(36.27,105.85) v10(57.96,99.73) v10(58.04,101.43) v10(58.04,100.54) v10(59.23,96.17) v10(59.74,102.9) v10(60.43,96.12) v10(60.81,102.8) v10(61.59,96.09) v10(63.12,96.09) v10(64.92,96.88) v10(65,102.24) v10(64.97,99.27) v10(73.68,84.61) v10(73.78,83.74) v10(74.51,84.64) v10(74.52,84.23) v10(81.41,83.57) v10(84.84,85.91) v10(87,91.39) v10(87.12,76.15) v10(87.16,77.73) v10(87.63,91.39) v10(87.59,77.73) v10(87.63,76.15) v10(88.27,91.39) v10(88.9,91.39) v10(91.06,82.17) v10(92.38,127.45) v10(92.38,85.43) v10(93.09,83.06) v10(93.38,128.45) v10(93.47,79.08) v10(94.11,78.99) v10(94.82,88.24) v10(97.38,96.86) v10(97.92,98.13) v10(98.38,129.45) v10(98.38,127.95) v10(98.93,98.13) v10(98.95,73.41) v10(99.06,73.79) v10(99.19,73.06) v10(99.67,73.72) v10(99.69,71.58) v10(99.75,75.56) v10(99.95,71.07) v10(100.33,92.71) v10(100.33,92.08) v10(100.28,68.99) v10(100.6,76.19) v10(100.86,69.02) v10(101.47,92.96) v10(101.47,92.46) v10(101.47,91.82) v10(101.47,91.19) v10(101.81,87) v10(101.98,86.53) v10(102.18,86.95) v10(102.87,73.2) v10(103.12,73.66) v10(103.38,93.68) v10(103.63,93.3) v10(103.68,73.64) v10(104.11,99.69) v10(104.46,84.66) v10(104.65,90.25) v10(104.65,89.62) v10(104.65,88.73) v10(105.18,98.57) v10(105.28,97.72) v10(106.43,94.29) v10(106.43,93.78) v10(107.37,89.84) v10(108.43,89.84) v10(108.58,94.29) v10(108.58,93.78) v10(109.42,76.3) v10(110.05,79.63) v10(110.74,94.29) v10(110.74,93.78) v10(110.97,77.88) v10(111.12,83.9) v10(111.2,87.84) v10(111.2,87.08) v10(111.3,72.14) v10(111.38,84.33) v10(112.24,44.02) v10(112.24,43.38) v10(112.24,42.75) v10(112.24,42.11) v10(112.45,75.9) v10(112.81,74.73) v10(112.81,73.66) v10(114.38,112.37) v10(114.38,110.98) v10(114.88,112.37) v10(114.88,110.98) v10(115.7,101.81) v10(116.2,101.81) v10(116.46,87.33) v10(116.71,101.81) v10(117.73,86.82) v10(117.73,85.81) v10(119.61,44.4) v10(119.61,43.76) v10(119.61,43.13) v10(119.61,42.49) v10(121.54,87.33) v10(122.81,86.7) v10(122.81,85.68) v11(27.41,113.26) v11(27.46,115.47) v11(27.64,111.26) v11(31.32,106.02) v11(33.45,106.08) v11(34.26,105.47) v11(36.27,105.85) v11(57.96,99.73) v11(58.04,101.43) v11(58.04,100.54) v11(59.23,96.17) v11(59.74,102.9) v11(60.43,96.12) v11(60.81,102.8) v11(61.59,96.09) v11(63.12,96.09) v11(64.92,96.88) v11(65,102.24) v11(64.97,99.27) v11(73.68,84.61) v11(73.78,83.74) v11(74.51,84.64) v11(74.52,84.23) v11(81.41,83.57) v11(84.84,85.91) v11(87,91.39) v11(87.12,76.15) v11(87.16,77.73) v11(87.63,91.39) v11(87.59,77.73) v11(87.63,76.15) v11(88.27,91.39) v11(88.9,91.39) v11(91.06,82.17) v11(92.38,127.45) v11(92.38,85.43) v11(93.09,83.06) v11(93.38,128.45) v11(93.47,79.08) v11(94.11,78.99) v11(94.82,88.24) v11(97.38,96.86) v11(97.92,98.13) v11(98.38,129.45) v11(98.38,127.95) v11(98.93,98.13) v11(98.95,73.41) v11(99.06,73.79) v11(99.19,73.06) v11(99.67,73.72) v11(99.69,71.58) v11(99.75,75.56) v11(99.95,71.07) v11(100.33,92.71) v11(100.33,92.08) v11(100.28,68.99) v11(100.6,76.19) v11(100.86,69.02) v11(101.47,92.96) v11(101.47,92.46) v11(101.47,91.82) v11(101.47,91.19) v11(101.81,87) v11(101.98,86.53) v11(102.18,86.95) v11(102.87,73.2) v11(103.12,73.66) v11(103.38,93.68) v11(103.63,93.3) v11(103.68,73.64) v11(104.11,99.69) v11(104.46,84.66) v11(104.65,90.25) v11(104.65,89.62) v11(104.65,88.73) v11(105.18,98.57) v11(105.28,97.72) v11(106.43,94.29) v11(106.43,93.78) v11(107.37,89.84) v11(108.43,89.84) v11(108.58,94.29) v11(108.58,93.78) v11(109.42,76.3) v11(110.05,79.63) v11(110.74,94.29) v11(110.74,93.78) v11(110.97,77.88) v11(111.12,83.9) v11(111.2,87.84) v11(111.2,87.08) v11(111.3,72.14) v11(111.38,84.33) v11(112.24,44.02) v11(112.24,43.38) v11(112.24,42.75) v11(112.24,42.11) v11(112.45,75.9) v11(112.81,74.73) v11(112.81,73.66) v11(114.38,112.37) v11(114.38,110.98) v11(114.88,112.37) v11(114.88,110.98) v11(115.7,101.81) v11(116.2,101.81) v11(116.46,87.33) v11(116.71,101.81) v11(117.73,86.82) v11(117.73,85.81) v11(119.61,44.4) v11(119.61,43.76) v11(119.61,43.13) v11(119.61,42.49) v11(121.54,87.33) v11(122.81,86.7) v11(122.81,85.68)
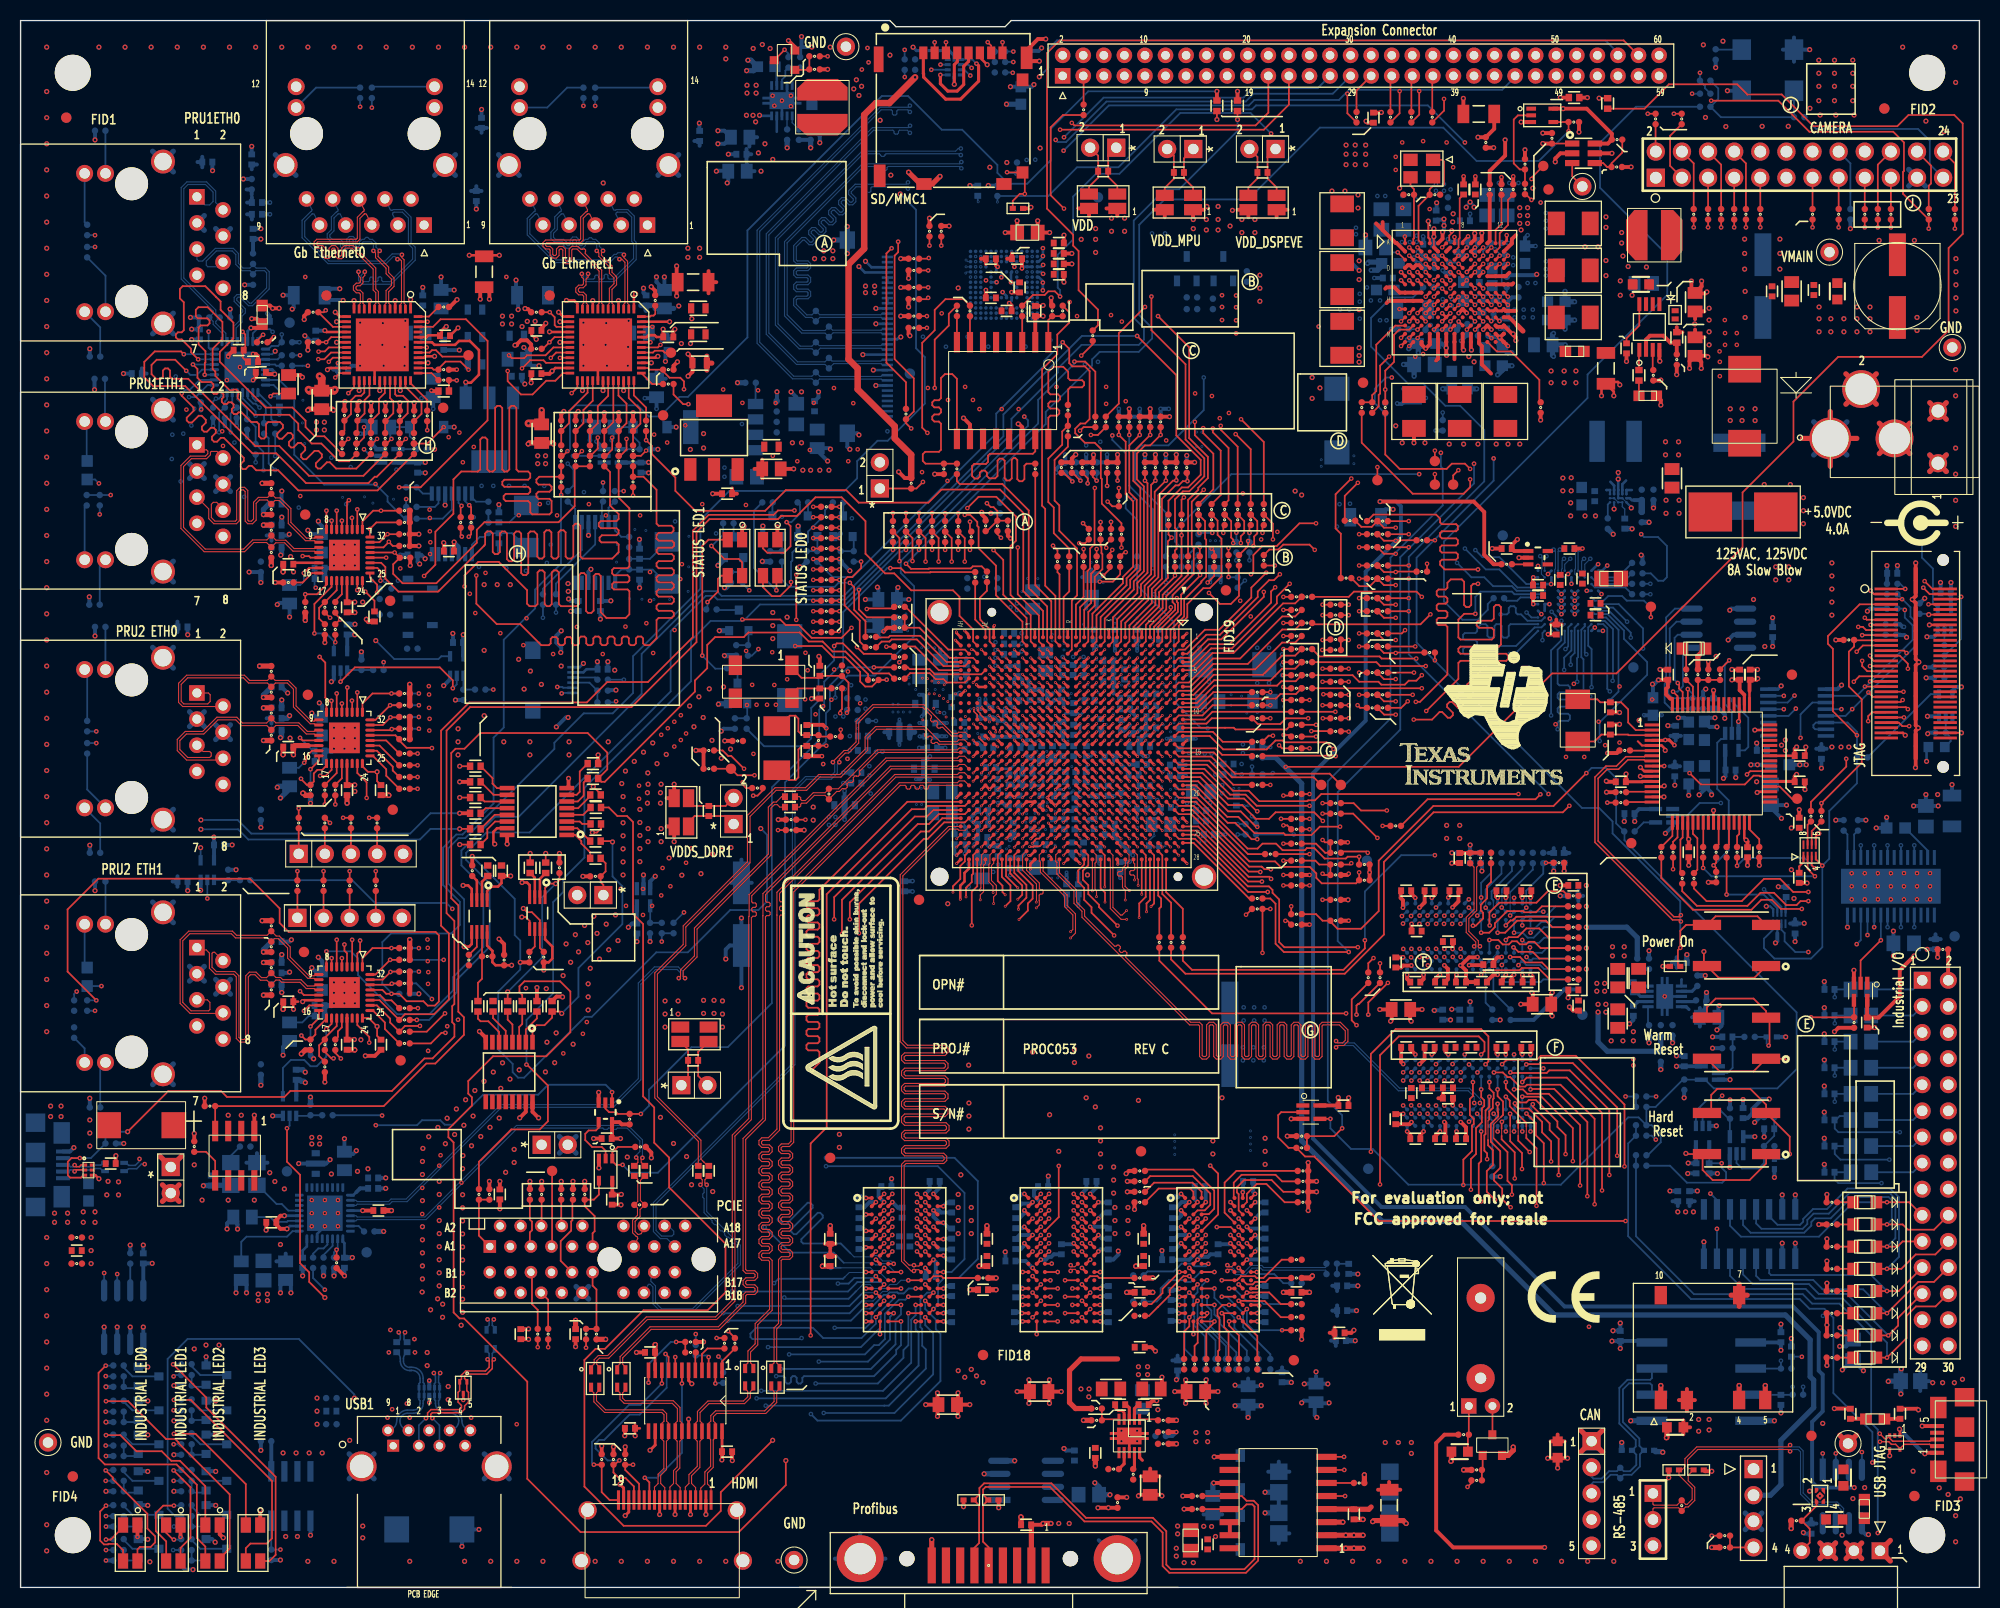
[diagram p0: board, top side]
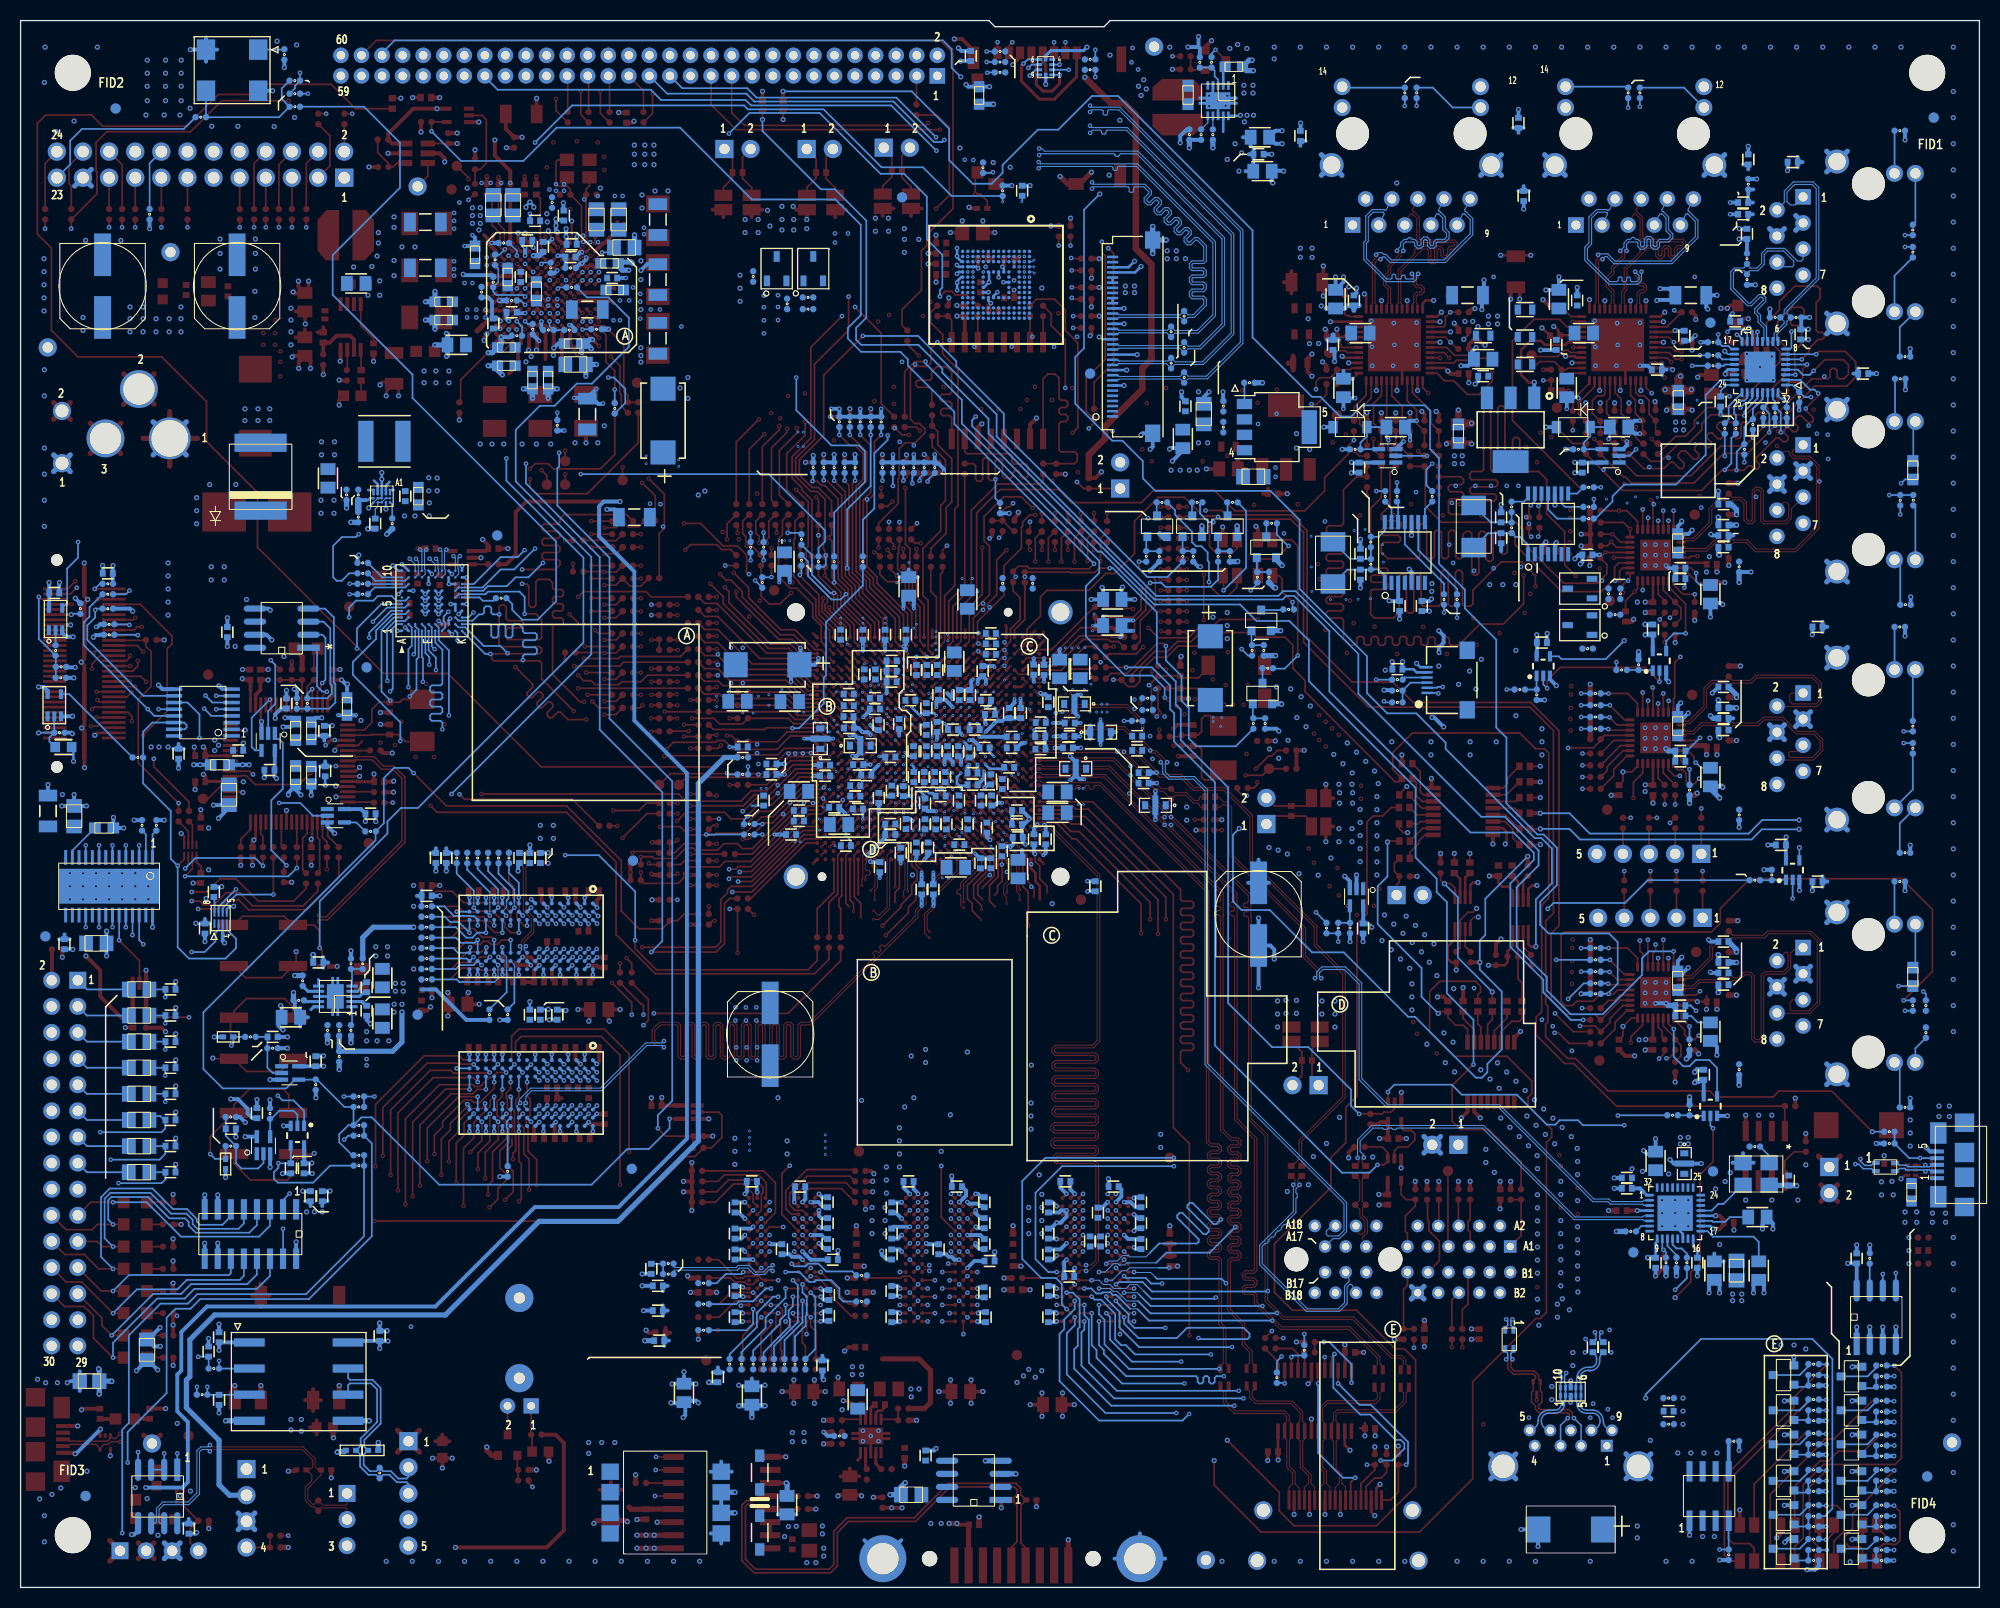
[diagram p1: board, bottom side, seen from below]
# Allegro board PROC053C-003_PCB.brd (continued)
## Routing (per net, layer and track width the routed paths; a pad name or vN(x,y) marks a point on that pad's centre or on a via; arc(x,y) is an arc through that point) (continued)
GND_CAN1: length 15.6
  TOP w0.381: C250.2 149.53,12.57 v1(150.44,12.57) ; C250.2 v1(149.48,11.61) ; C250.2 149.43,12.57 v1(148.51,12.57)
  TOP w0.508: U40.5 v1(169.67,19.64) ; U40.4 v1(167.13,19.64)
  L3_SIG1 w0.508: 151.98,7.41 J38.4 ; J38.4 153.59,5.8 ; J38.4 153.59,7.41 ; J38.4 151.98,5.8
  BOTTOM w0.381: 155.58,25.63 C252.2 155.56,24.97 v1(154.86,24.97)
  BOTTOM w0.508: 155.58,25.63 v1(155.58,25.71) ; U88.2 v1(155.71,14.1) ; U87.2 159,13.21 159.64,13.21 v1(159.7,13.14) ; v1(156.59,16.21) U41.5
GND_OSC0: length 12.4
  TOP w0.254: U1.AF15 v4(92.64,80.82)
  TOP w0.381: C1.2 76.47,83.9 78.02,83.9 v7(78.36,83.57) ; 77.92,80.87 v7(77.93,80.85) 76.47,80.85 C2.2
  L3_SIG1 w0.381: 84.57,80.93 87.24,80.93 87.58,80.59 91.84,80.59 92.06,80.82 v4(92.64,80.82)
  vias: v6(71.27,81.08) v7(71.27,81.08)
GNDPROFI: length 23.1
  TOP w0.381: R578.1 v1(113.16,7.62) ; U74.15 U74.14 ; U81.2 95.12,7.88 95.12,7.87 v1(95.12,7.75) ; R573.1 v1(107.57,8.76) ; U74.11 v1(116.03,10.16) ; U80.2 v1(91.7,7.85) ; U74.9 v1(116.08,12.7)
  TOP w0.508: C430.2 97.3,6.84 v1(97.28,6.86) ; J14.5 v1(88.61,4.64)
  BOTTOM w0.381: C434.2 101.67,13.32 v1(101.47,13.51) ; L2.6 L2.7
  BOTTOM w0.508: U52.3 v1(93.71,11.05) ; C433.2 115.95,10.08 v1(116.03,10.16) ; L2.7 v1(121.03,9.25) ; U52.4 v1(96.67,12.32) ; v1(121.03,7.26) L2.6 ; v1(105.94,9.02) C325.2 104.89,9.77 v1(104.47,10.19)
  vias: v1(112.52,5.97) v1(112.52,5.21) v1(115.06,5.94) v1(115.82,5.92) v1(116.2,4.95)
GNDUSB1: length 13.7
  BOTTOM w0.508: J23.S2 47.52,12.99 ; J23.S2 47.52,10.57 ; J23.S2 45.1,12.99 ; J23.S2 45.1,10.57 ; 31.96,12.99 J23.S1 ; J23.S1 31.96,10.57 ; J23.S1 34.38,10.57 ; J23.S1 34.38,12.99
GNDUSB2:
  vias: v1(2.92,46.82) v1(2.92,45.8) v1(3.3,36.4) v1(3.3,35.51) v1(3.94,46.82) v1(3.94,45.8) v1(4.57,36.4) v1(4.57,35.51)
GNDUSBJ: length 2.8
  BOTTOM w0.381: FB12.1 184.74,21.02 ; FB12.1 184.74,19.11 ; FB12.1 185.62,20.07
  vias: v1(185.95,19.91) v1(186.59,9.68) v1(186.92,19.91) v1(187.45,9.04) v1(188.06,19.91) v1(188.65,8.61) v1(188.85,20.24)
V1_2D: length 1.4
  BOTTOM w0.254: U89.A7 v2(153.75,96.62) ; U89.B1 v2(153.1,93.37) ; U89.K4 v2(147.9,94.67)
V1_2D_EN: length 1.6
  TOP w0.173: U76.3 145.05,99.51 R451.1
V1_8D: length 201.2
  TOP w0.254: U1.M8 v4(104.63,87.21) ; U1.T8 v4(100.64,87.21) ; v4(97.44,76.02) U1.Y21 U1.W21 v4(98.24,76.02) ; U1.J22 v4(107.03,75.22) ; U1.V21 v4(99.04,76.02) U1.V22 ; U1.N8 v4(103.83,87.21) ; U1.N21 v11(103.83,76.02) ; U1.AA18 v4(96.64,78.42) ; U1.R8 v4(101.44,87.21) ; U1.AA7 v4(96.64,88.01) ; U1.Y7 v4(97.44,88.01) ; U1.G18 v4(108.63,78.42) ; U1.W17 v4(98.24,79.22) ; U1.H17 v4(107.83,79.22) ; U1.J21 v4(107.03,76.02) ; U1.P8 v4(103.03,87.21) ; U1.AA19 v4(96.64,77.62) ; U1.W18 v4(98.24,78.42) ; U1.M9 v4(104.63,86.41) ; U1.P20 v4(103.03,76.82) ; U1.P21 v4(103.03,76.02)
  TOP w0.381: C169.1 42.15,101.66 v1(42.16,101.68) ; R451.2 143.26,99.52 142.34,100.44 142.34,104.6 141.32,105.62 v1(132.21,105.62)
  L3_SIG1 w0.254: v4(103.03,76.02) v5(103.43,75.77) ; v4(97.44,76.02) v5(97.04,75.77) ; v4(97.44,88.01) v5(97.04,88.26) ; v5(103.52,76.57) 103.46,76.55 v4(103.03,76.82) ; v4(96.64,77.62) v5(96.24,77.37) ; v4(103.03,87.21) v5(103.43,87.46) ; v4(96.64,78.42) v5(96.24,78.17) ; v4(108.63,78.42) v5(109.03,78.17) ; v11(103.83,76.02) v5(104.23,75.77) ; v4(107.83,79.22) v5(108.23,78.97) ; v4(104.63,87.21) v5(105.03,87.46) ; v4(107.03,75.22) v5(107.43,74.97) ; v4(100.64,87.21) 100.24,87.46 v5(100.24,87.46) ; v4(101.44,87.21) v5(101.04,87.46) ; v4(96.64,88.01) 96.24,88.26 v5(96.24,88.26) ; v5(104.23,87.46) 104.23,87.46 v4(103.83,87.21) ; v4(104.63,86.41) v5(105.03,86.66) ; v4(98.24,79.22) v5(97.84,78.97) ; v4(107.03,76.02) v5(107.43,75.77) ; v4(98.24,78.42) v5(97.84,78.17) ; v4(99.04,76.02) v5(98.64,75.77) ; v5(97.84,75.77) v4(98.24,76.02)
  L4_SIG2 w0.381: v5(107.43,75.77) v5(107.43,74.97)
  L10_SIG4 w0.254: v11(103.11,76.11) 103.12,76.11 103.12,76.07 103.15,75.94 v5(103.43,75.77) ; v11(96.62,87.88) v5(96.24,88.26) ; v5(105.03,87.46) 105.02,87.46 104.66,87.83 v11(104.54,87.83) ; v11(103.83,76.02) v5(104.23,75.77) ; v5(98.64,75.77) 98.65,75.75 v11(98.65,75.3) ; v11(104.78,87.06) v5(105.03,86.66) ; v5(97.04,75.77) 97.04,75.41 v11(97.15,75.3) ; v11(103.83,87.22) v5(104.23,87.46) ; v11(97.76,74.43) v11(97.76,74.81) 97.85,74.89 v11(97.85,75.25) 97.85,75.76 v5(97.84,75.77) ; v11(97.42,87.88) v5(97.04,88.26) ; v11(103.77,87.8) v5(103.43,87.46)
  L10_SIG4 w0.381: v11(103.15,76.86) 103.44,76.57 v5(103.52,76.57) ; v5(97.84,78.97) v5(97.84,78.17) ; v5(96.24,77.37) v5(96.24,78.17)
  BOTTOM w0.381: U23.3 42.59,101.25 v1(42.16,101.68) ; v11(96.62,87.88) 96.62,88.32 C406.1 97.04,88.64 97.42,88.26 v11(97.42,87.88) ; v1(57.4,95.97) 57.39,95.95 C190.1 56.37,95.95 56.53,96.11 U25.3 ; v1(178.32,9.71) 174.76,9.71 174.23,10.25 174.23,16.1 175.26,17.13 175.26,20.7 174.87,21.09 174.87,24.84 172.38,27.33 150.15,27.33 140.48,37 132.35,37 125.69,43.65 125.69,79.2 130.81,84.32 130.81,98.81 134.24,102.23 134.24,105.16 133.78,105.62 v1(132.21,105.62)
  vias: v1(45.09,97.54) v1(46.35,97.54) v1(47.62,97.54) v1(120.52,127.64) v1(120.52,126.36) v1(120.52,125.09) v1(178.19,8.64) v1(179.34,9.71) v5(92.61,97.66) v5(93.62,97.33) v5(136.53,135.72) v5(137.03,136.23) v5(138.05,135.34) v5(138.84,135.13) v5(139.57,135.08) v8(92.84,98.3) v8(93.73,98.3) v8(137.64,136.48) v8(137.64,135.84) v8(138.43,136.48) v8(138.43,135.84) v8(139.07,135.97) v9(92.84,98.3) v9(93.73,98.3) v9(137.64,136.48) v9(137.64,135.84) v9(138.43,136.48) v9(138.43,135.84) v9(139.07,135.97)
V1_8D_OUT: length 4.3
  TOP w0.508: 177.53,2.81 J1_1.2 ; J1_1.2 177.53,4.33 ; J1_1.2 179.05,2.81 ; J1_1.2 179.05,4.33
V1_8FTDI: length 15.7
  TOP w0.203: 160.49,86.45 160.64,86.3 U37.64
  TOP w0.254: 168.14,87.21 U37.49
  TOP w0.305: U37.37 172.49,78.39 172.53,78.35 ; U37.12 157.75,78.39 157.72,78.36 C238.1
  TOP w0.381: C238.1 156.13,78.38 v1(156.13,79.12) ; v1(168.94,88.4) 168.83,88.29 C232.1 168.14,88.23 168.14,87.21 ; 160.49,86.45 160.43,86.45 160.03,86.85 160.03,87.41 160.2,87.57 C235.1 160.18,88.27 v1(159.28,88.27) ; v1(172.72,79.08) 172.53,78.89 C227.1 172.53,78.35
  BOTTOM w0.381: C241.1 158.75,87.81 v1(158.71,87.85) 158.87,87.85 v1(159.28,88.27)
V1_8PHY_HDMI: length 3.1
  TOP w0.254: U1.Y17 v4(97.44,79.22)
  L3_SIG1 w0.254: v4(97.44,79.22) v5(97.04,78.97)
  L10_SIG4 w0.254: v11(96.79,79.37) v5(97.04,78.97)
  BOTTOM w0.381: C566.1 96.79,78.72 v11(96.79,79.37)
  vias: v5(81.15,78.49) v5(81.53,79.38) v8(82.55,79.88) v8(82.55,78.99) v9(82.55,79.88) v9(82.55,78.99)
V1_8PHY_LDO3: length 4.5
  TOP w0.254: U3.K11 143.01,123.17 v2(143.03,123.17)
  L10_SIG4 w0.381: v5(85.09,82.58) 85.1,82.57 v5(85.83,82.57) 85.84,82.58 v5(86.45,82.58)
  BOTTOM w0.381: v2(143.03,123.17) 143.24,123.38 C392.1
  BOTTOM w0.508: L34.1 86.47,83.76 ; L34.1 86.95,83.19 ; L34.1 86.47,82.61
  vias: v5(86.01,84.29) v5(86.89,84.23) v10(84.84,85.15) v10(85.34,85.91) v10(85.34,85.15) v10(85.85,85.15) v10(86.49,85.15) v11(84.84,85.15) v11(85.34,85.91) v11(85.34,85.15) v11(85.85,85.15) v11(86.49,85.15)
V1_8PHY_LDO4:
  vias: v5(78.61,78.61) v5(78.61,77.6) v5(79.38,78.11) v5(87.35,85.78) v5(88.16,85.78) v5(145.03,126.87) v5(145.8,127.38) v8(78.61,74.93) v8(78.61,74.17) v8(79.25,74.93) v8(79.25,74.17) v8(146.56,126.87) v8(147.32,126.87) v9(78.61,74.93) v9(78.61,74.17) v9(79.25,74.93) v9(79.25,74.17) v9(146.56,126.87) v9(147.32,126.87)
V1_8PHY_PCIE: length 6.2
  TOP w0.254: U1.AA17 v4(96.64,79.22) ; U1.AA16 v4(96.64,80.02) ; U1.W14 v4(98.24,82.41)
  L3_SIG1 w0.254: v4(98.24,82.41) v5(97.84,82.66) ; v4(96.64,79.22) v5(96.24,78.97) ; v4(96.64,80.02) v5(96.24,79.77)
  L4_SIG2 w0.381: v5(96.24,78.97) v5(96.24,79.77)
  L10_SIG4 w0.254: v11(98.24,82.42) v5(97.84,82.66) ; v5(96.24,79.77) 96.22,79.77 v11(95.89,80.1)
  BOTTOM w0.381: v11(98.24,82.42) 97.87,82.42 97.24,81.79 C394.1
V1_8PHY_SATA: length 16.4
  TOP w0.254: U1.V13 v4(99.04,83.21)
  L3_SIG1 w0.254: v4(99.04,83.21) v5(98.64,83.46)
  L10_SIG4 w0.254: v11(98.91,82.91) 98.91,83.19 v5(98.64,83.46)
  L10_SIG4 w0.381: v9(83.19,81.28) v9(83.82,81.28) 84.07,81.28 84.84,80.52
  L10_SIG4 w0.508: 92.4,80.41 94.79,80.41 v5(94.82,80.44)
  L10_SIG4 w0.635: 92.4,80.41 91.26,79.27 88.35,79.27 87.54,80.08 86.73,80.08 86.29,80.52 84.84,80.52
  BOTTOM w0.381: 83.99,83.19 L34.3 84.47,82.61 ; C564.1 99.33,83.33 v11(98.91,82.91)
V1_8PHY_USB: length 8.1
  TOP w0.254: U1.W12 v4(98.24,84.01) ; U1.AA13 v4(96.64,83.21) ; U1.AB12 v4(95.84,84.01)
  L3_SIG1 w0.254: v5(96.24,83.46) 96.24,83.46 v4(96.64,83.21) ; v5(97.84,84.33) 97.84,84.26 v4(98.24,84.01) ; v4(95.84,84.01) v5(95.44,84.26)
  L10_SIG4 w0.254: v11(95.84,84.02) v5(95.44,84.26) ; v11(96.64,83.22) v5(96.24,83.46)
  BOTTOM w0.381: v11(96.64,83.22) v11(95.84,84.02) 95.57,84.28 95.02,84.28 94.75,84.55 C390.1 C391.1
  vias: v8(89.18,85.19) v8(89.81,85.04) v9(89.18,85.19) v9(89.81,85.04)
V1_8PLL: length 6
  TOP w0.152: 137.45,130.34 v1(137.45,131.39)
  TOP w0.254: U1.AD16 v4(94.24,80.02) ; U1.AE16 v4(93.44,80.02)
  TOP w0.381: v1(137.45,131.39) v1(137.45,132.15) ; U3.B5 137.45,130.34
  L3_SIG1 w0.254: v4(93.44,80.02) v5(93.04,79.77) ; v4(94.24,80.02) v5(93.84,79.77)
  BOTTOM w0.381: C382.1 137.4,131.32 137.45,131.37 v1(137.45,131.39) v1(137.45,132.15)
  vias: v1(123.95,106.63) v1(124.59,106.25) v5(112.73,81.79) v5(113.61,81.79) v5(114.5,81.79) v5(115.39,81.79) v8(113.64,81.16) v8(114.43,81.13) v8(115.16,81.11) v8(115.82,81.11) v9(113.64,81.16) v9(114.43,81.13) v9(115.16,81.11) v9(115.82,81.11)
V1_8PLLA: length 8
  TOP w0.254: U1.N16 v11(103.83,80.02) ; U1.R14 v4(101.44,82.41) ; U1.M14 v4(104.63,82.41) ; U1.R17 v4(101.44,79.22)
  L3_SIG1 w0.254: v4(101.44,79.22) v5(101.04,78.97) ; v4(101.44,82.41) v5(101.04,82.66) ; v11(103.83,80.02) v5(104.23,79.77)
  L10_SIG4 w0.254: v11(103.83,80.02) v5(104.23,79.77) ; v11(100.1,78.84) 100.1,78.87 100.12,78.87 100.22,78.97 v5(101.04,78.97) ; v11(101.44,82.42) v5(101.04,82.66)
  BOTTOM w0.173: C381.1 100.39,79.31 100.1,79.02 v11(100.1,78.84)
  BOTTOM w0.254: C442.1 103.63,79.81 v11(103.83,80.02) ; 101.37,82.48 v11(101.44,82.42)
  BOTTOM w0.381: C380.1 101.37,82.48
  vias: v5(106.43,81.49) v5(107.31,81.49) v5(108.2,81.49) v5(109.09,81.49) v10(112.17,84.1) v10(112.73,84.11) v10(113.26,84.16) v11(112.17,84.1) v11(112.73,84.11) v11(113.26,84.16)
V1_8PLLB: length 7.7
  TOP w0.254: v4(103.81,83.95) 103.48,83.62 U1.N12 ; U1.P14 v4(103.03,82.41) ; U1.P15 v11(103.03,80.82) ; U1.P16 v11(103.03,80.02) ; U1.N11 103.53,84.42 v4(103.85,84.74)
  L3_SIG1 w0.254: v5(104.21,84.26) 104.2,84.21 103.81,83.97 v4(103.81,83.95) ; v11(103.03,80.02) v5(103.43,79.77) ; v5(103.43,82.66) v4(103.03,82.41) ; v5(104.21,85.06) 104.19,84.95 v4(103.85,84.74) ; v11(103.03,80.82) v5(103.43,80.57)
  L10_SIG4 w0.254: v11(103.03,82.42) v5(103.43,82.66) ; v11(103.84,83.95) 104.15,84.26 v5(104.21,84.26) ; v5(104.21,85.06) 104.2,85 v11(103.81,84.76) ; v11(103.03,80.82) v5(103.43,80.57) ; v11(103.03,80.02) v5(103.43,79.77)
V3_3ACDCM: length 4.3
  TOP w0.381: v1(33.27,36.65) 33.28,36.66 C321.1
  BOTTOM w0.254: 32.65,38.44 32.36,38.15 U45.1 ; U45.4 v1(33.27,36.65)
  BOTTOM w0.381: C322.1 33.02,38.82 32.65,38.44
  vias: v1(30.23,40.21) v1(32.77,40.47) v1(33.78,40.72)
V3_3APCIE: length 16.9
  TOP w0.381: C308.1 24.89,35.51 ; 24.89,35.51 24.89,35.77 25.27,36.15 v1(25.65,36.15) ; 24.89,35.51 24.89,35.26 25.27,34.88 v1(25.91,34.88)
  BOTTOM w0.254: v1(25.91,34.88) 26.18,35.15 U45.18 ; 27.43,32.09 27.43,32.77 27.84,33.17 U45.16 ; C310.1 31.5,33.48 31.34,33.64 U45.9 ; U45.20 v1(25.65,36.15)
  BOTTOM w0.381: 25.78,32.47 C307.1 24.88,31.71
  BOTTOM w0.508: v1(17.78,39.07) 17.8,39.09 C326.1 18.56,39.09 18.58,39.11 Y7.4 ; R548.2 v1(29.46,30.31) ; R546.2 v1(35.31,34.63) ; R549.2 v1(30.48,30.31) ; v1(32.26,32.09) 32.24,32.07 C310.1
  vias: v1(25.27,33.36)
V3_3AUX_PCIE: length 9.8
  TOP w0.508: v1(53.98,25.98) C556.1 ; R654.2 v1(56.9,24.13)
  BOTTOM w0.508: 52.41,42.25 J49.2 ; J49.2 54.02,43.86 ; J49.2 52.41,43.86 ; J49.2 54.02,42.25 ; J22.B10 55.24,28.05 ; J22.B10 55.24,29.27 ; J22.B10 54.02,29.27 ; J22.B10 54.02,28.05
V3_3D: length 368.1
  TOP w0.254: U1.T4 v4(100.64,90.41) ; U1.T5 v4(100.64,89.61) ; U1.J8 106.98,87.16 107.03,87.16 v4(107.04,87.17) ; U1.H8 v4(107.83,87.21) ; U1.W4 v4(98.24,90.41) ; U1.D10 v4(111.03,85.61) ; U1.G4 v4(108.63,90.41) ; U1.H9 v4(107.83,86.41) ; U1.H11 v4(107.83,84.81) ; U1.AB7 v4(95.84,88.01) ; v4(92.95,87.8) 92.96,87.8 93.18,87.58 93.8,87.58 U1.AE7 ; U1.H10 v4(107.83,85.61) ; U1.AB6 v4(95.84,88.81) ; U1.K8 v4(106.23,87.21) ; U1.H16 v4(107.83,80.02) ; U1.C24 v4(111.83,73.62) ; U1.N5 v4(103.83,89.61) ; U1.G15 v4(108.63,80.82) ; v1(47.75,60.51) R943.2 46.19,60.51 45.89,60.82 R945.2 45.89,61.91 45.37,62.42 U103.8 ; U1.AD7 v4(94.24,88.01) ; U1.V12 v4(99.04,84.01) ; U1.B6 v4(112.63,88.81) ; U1.AD5 v4(94.24,89.61) ; U1.N4 v4(103.83,90.41) ; 31.75,78.06 31.75,78.06 U15.21 ; U102.8 51.01,63.04 51.71,62.33 51.71,61.16 51.35,60.8 R941.2 ; U1.R10 v4(101.44,85.61) ; U1.E3 v4(110.23,91.21) ; U1.H15 v4(107.83,80.82) ; U1.H18 v4(107.83,78.42) ; U1.R7 v4(101.44,88.01) ; U1.AF5 v4(92.64,89.61) ; U1.W5 v4(98.24,89.61) ; U1.G5 v4(108.63,89.61) ; U1.H19 v4(107.83,77.62) ; U1.E5 v4(110.23,89.61) ; U1.E16 v4(110.23,80.02) ; U1.D22 v11(111.03,75.22) ; U1.P10 v4(103.03,85.61) ; U1.B23 v4(112.63,74.42) ; v2(140.65,127.94) U3.D9 v2(141.44,128.73) ; U1.E22 v4(110.23,75.22) ; U13.21 31.75,95.84 31.77,95.82 ; U1.D16 v4(111.03,80.02) ; U1.E10 v4(110.23,85.61) ; U1.U10 v4(99.84,85.61)
  TOP w0.279: 68.22,13.23 68.22,13.23 U46.24
  TOP w0.305: 31.75,53.29 31.75,53.3 31.75,53.3 31.75,55.39 U17.21 ; J15.4 91.09,148.4 90.81,148.11 v1(90.81,146.2) ; 109.09,12.37 108.82,12.64 U8.10
  TOP w0.381: v1(52.7,57.43) 52.66,57.47 52.12,57.47 R938.2 ; C408.1 147.08,95.67 v2(147.11,95.64) ; v1(102.62,110.19) 102.23,109.81 R440.2 R434.2 ; U47.5 128.13,46.88 128.16,46.84 C214.1 128.16,47.64 v1(128.14,47.66) ; 132.02,9.5 C435.1 ; C435.1 133.1,10.25 ; C435.1 134.17,9.5 ; 97.41,111.71 97.41,112.85 97.09,113.17 v1(97.02,113.17) ; v1(86.49,121.75) 86.36,121.87 R512.2 ; R510.2 v1(86.36,127.34) ; R545.2 v1(54.86,39.5) ; 161.71,14.9 C249.1 ; C249.1 162.36,15.58 ; C249.1 161.71,16.25 ; D16.1 v7(11.37,4.91) ; R506.2 v1(85.6,126.45) ; R679.2 159.47,117.39 v1(159.51,117.43) ; C410.1 148.58,92.68 v2(148.54,92.72) ; R954.1 58.47,45.04 58.25,45.25 U85.5 57.52,43.7 C470.1 v1(58.34,43.66) ; R507.2 v1(86.36,124.54) ; v7(129.16,69.42) 129.03,69.3 R383.2 ; R22.2 v1(88.9,108.29) ; R559.2 v1(66.42,23.88) ; 108.95,10.81 C88.1 ; C88.1 109.86,11.56 ; C88.1 110.76,10.81 ; 68.22,13.23 C428.1 68.22,12.42 v1(68.2,12.4) ; C105.1 24.04,118.01 v1(24.71,118.01) ; U101.16 49.79,46.27 v1(50.38,45.67) ; v1(104.34,110.16) 104.34,109.5 R436.2 R439.2 ; R412.2 v1(78.49,147.66) ; R800.2 84.28,93.34 v7(83.92,92.99) ; v1(70.36,103.21) 70.17,103.02 D23.1 ; R152.2 v1(37.9,99.4) ; v1(58.42,38.23) 58.4,38.21 C469.1 57.51,38.21 57.55,38.24 U44.5 ; R441.2 v1(111.73,113.87) ; v1(19.71,4.83) 19.37,5.17 D18.1 ; R201.2 v1(29.59,49.15) ; R447.2 R449.2 v1(106.68,110.19) ; C256.1 96.37,124.68 v2(96.14,124.92) ; U99.16 v1(47.32,72.31) ; v1(32.5,95.84) 32.48,95.82 31.77,95.82 ; 161.27,18.22 U40.2 ; U40.2 162.05,19.3 ; U40.2 162.05,17.14 ; U40.2 162.83,18.22 ; C409.1 147.08,98.21 v2(147.11,98.24) ; v1(95.76,131.78) C479.1 v1(96.92,132.92) ; v5(128.4,72.47) v7(129.07,72.47) ; v1(48.54,45.67) 49.14,46.27 U101.15 ; U4.2 C28.1 99.42,123.67 v1(99.44,123.65) ; v1(100.23,125.43) 100.23,124.77 R799.2 ; R941.2 v1(50.88,60.05) ; v1(32.5,78.06) 31.75,78.06 ; R948.2 v1(54.69,69.16) ; v1(110.36,110.19) R444.2 R443.2 ; v1(107.82,114.64) R438.2 R437.2 ; C258.1 96.4,125.96 v2(96.37,125.98) ; R505.2 v1(85.6,129.24) ; D17.1 v7(15.56,4.91) ; v5(128.4,64.85) v7(129.16,64.85) ; v5(124.59,69.3) v7(125.35,69.3) ; v2(140.64,123.96) 140.26,124.34 U3.J8 v2(139.85,123.94) ; 131.19,70.31 v7(131.19,69.55) 131.19,68.79 ; R97.1 24.25,124.68 v1(24.51,124.41) v1(25.15,124.41) ; R511.2 v1(85.6,123.65) ; R811.1 v1(151.56,141.55) ; v1(112.39,110.19) R446.2 R445.2 ; C350.1 97.39,128.3 v2(97.38,128.3) ; R435.2 R442.2 v1(109.86,114.64) ; v2(95.02,128.45) 94.88,128.59 94.88,129.21 C257.1 ; R423.2 v1(176.53,92.16) ; v2(93.88,126.19) 93.87,126.18 C255.1 ; v5(124.59,64.47) v7(125.35,64.47) ; R543.1 v1(50.67,39.5) ; R544.1 v1(52.58,39.5) ; R563.2 v1(129.1,66.88) ; R120.2 v1(29.59,91.9) ; v1(176.4,54.06) 176.78,54.44 R366.2 ; R508.2 v1(90.3,132.42) ; R649.2 v1(45.59,39.5) ; D19.1 v1(23.31,7.54) ; R790.2 v1(16.89,44.15) ; R509.2 v1(88.39,133.18) ; C432.1 129.65,7.62 ; R939.2 v1(52.41,71.39) ; R448.2 v1(114.17,109.43) ; D22.1 v1(73.6,103.14) ; v1(32.46,53.29) 31.75,53.29
  TOP w0.508: J1_1.3 176.51,4.33 ; J1_1.3 174.99,2.81 ; J1_1.3 176.51,2.81 ; J1_1.3 174.99,4.33 ; R131.2 v1(27.69,94.06) ; R144.1 v1(23.62,104.35) ; v1(23.49,64.85) R224.1 ; v1(27.45,77.26) 27.49,77.26 27.7,77.04 R159.2 ; R185.1 v1(23.62,82.38) ; v1(27.3,51.9) 27.69,52.28 R200.2 ; R183.1 v1(23.62,86.57) ; v1(24.38,99.4) 24.38,99.41 R146.1 ; 131.34,7.82 131.12,7.6 C432.1 ; R184.1 v1(23.62,85.55) ; v1(23.49,107.4) R143.1 ; 129.65,7.62 U74.4 ; R226.1 v1(23.62,60.79) ; v1(23.24,89.62) R182.1 ; R225.1 v1(23.62,61.8) ; R145.1 v1(23.62,103.33) ; R227.1 v1(23.62,57.61)
  L3_SIG1 w0.254: v5(108.23,86.66) 108.23,86.66 v4(107.83,86.41) ; v5(98.64,84.26) v4(99.04,84.01) ; v4(110.23,85.61) v5(110.63,85.86) ; v4(110.23,75.22) 110.63,74.97 v5(110.64,74.91) ; v4(110.23,80.02) v5(110.63,79.77) ; v5(97.84,89.86) v4(98.24,89.61) ; v4(107.83,80.02) v5(108.23,79.77) ; v5(100.24,89.86) 100.24,89.86 v4(100.64,89.61) ; v4(107.83,78.42) v5(108.23,78.17) ; v4(107.04,87.17) 107.06,87.17 107.43,87.4 v5(107.43,87.46) ; v4(101.44,88.01) v5(101.04,88.26) ; v4(94.24,89.61) v5(93.84,89.86) ; v5(92.24,89.86) 92.24,89.86 v4(92.64,89.61) ; v4(107.83,87.21) 108.23,87.46 v5(108.23,87.46) ; v5(108.23,85.86) 108.23,85.86 v4(107.83,85.61) ; v4(111.83,73.62) v5(112.23,73.37) ; v11(111.03,75.22) v5(111.43,74.97) ; v5(93.04,88.26) 93.04,87.95 92.96,87.84 92.96,87.82 92.96,87.82 92.96,87.81 v4(92.95,87.8) ; v5(104.23,89.86) 104.23,89.86 v4(103.83,89.61) ; v4(106.23,87.21) v5(106.63,87.46) ; v5(101.04,85.86) v4(101.44,85.61) ; v5(100.24,90.66) 100.24,90.66 v4(100.64,90.41) ; v4(110.23,91.21) v5(110.63,91.46) ; v4(94.24,88.01) v5(93.84,88.26) ; v4(107.83,84.81) 108.23,85.06 v5(108.23,85.06) ; v4(107.83,80.82) v5(108.23,80.57) ; v4(112.63,88.81) v5(113.03,89.06) ; v5(97.84,90.66) v4(98.24,90.41) ; v5(104.23,90.66) 104.23,90.66 v4(103.83,90.41) ; v4(111.03,80.02) v5(111.43,79.77) ; v5(103.43,85.86) v4(103.03,85.61) ; v4(108.63,80.82) v5(109.03,80.57) ; v4(108.63,89.61) v5(109.03,89.86) ; v4(95.84,88.81) v5(95.44,89.06) ; v4(111.03,85.61) v5(111.43,85.86) ; v4(107.83,77.62) v5(108.23,77.37) ; v4(110.23,89.61) v5(110.63,89.86) ; v5(99.44,85.86) v4(99.84,85.61) ; v4(108.63,90.41) v5(109.03,90.66) ; v4(112.63,74.42) v5(113.03,74.17) ; v4(95.84,88.01) v5(95.44,88.26)
  L3_SIG1 w0.381: v7(11.37,4.91) v5(11.37,4.15) ; v5(131.95,69.77) 131.73,69.55 v7(131.19,69.55) ; v5(84.66,92.99) 84.61,92.94 83.97,92.94 v7(83.92,92.99) ; v7(129.16,69.42) v5(128.4,69.42) ; v7(129.07,72.47) v5(128.4,72.47) ; v7(125.35,69.3) v5(124.59,69.3) ; v7(129.16,64.85) v5(128.4,64.85) ; v7(15.56,4.91) v5(15.56,4.15) ; v7(125.35,64.47) v5(124.59,64.47)
  L7_PWR2 w0.381: v5(108.23,79.77) v5(108.23,80.57) ; v5(108.23,77.37) v5(108.23,78.17)
  L7_PWR2 w0.508: J22.A10 55.24,35.77 ; J22.A10 54.02,34.55 ; J22.A10 55.24,34.55 ; J22.A10 54.02,35.77 ; 52.02,29.27 J22.B8 ; J22.B8 53.24,29.27 ; J22.B8 53.24,28.05 ; J22.B8 52.02,28.05 ; J21.1 102.06,146.3 ; J21.1 100.63,147.74 ; J21.1 100.63,146.3 ; J21.1 102.06,147.74 ; J22.A9 54.24,32.55 ; J22.A9 53.02,32.55 ; J22.A9 53.02,33.77 ; J22.A9 54.24,33.77 ; J49.1 51.48,42.25 ; J49.1 49.87,43.86 ; J49.1 49.87,42.25 ; J49.1 51.48,43.86
  L10_SIG4 w0.254: v11(107.84,87.72) 107.69,87.72 v5(107.43,87.46) ; v11(107.82,87.2) 108.03,87.2 108.23,87.41 v5(108.23,87.46) ; v11(108.63,87.06) v5(108.23,86.66) ; v11(111.18,79.37) v5(111.43,79.77) ; v11(111.03,75.22) 111.16,75.14 v5(111.43,74.97) ; v11(110.99,80.12) v5(110.63,79.77) ; v5(106.63,87.46) 106.74,87.46 v11(107.05,87.77) ; v11(99.84,85.62) v5(99.44,85.86) ; v5(110.64,74.91) 110.64,74.96 110.31,75.23 v11(110.31,75.26) ; v11(108.63,86.27) v5(108.23,85.86) ; v11(101.44,85.62) v5(101.04,85.86) ; v11(108.64,85.47) v5(108.23,85.06)
  L10_SIG4 w0.381: v9(137.62,112.52) v5(138.3,112.52) ; v9(27.11,121.11) v5(26.42,121.11)
  BOTTOM w0.173: v2(7.7,104.37) R956.2 ; R958.2 5.21,57.71 v2(5.46,57.96)
  BOTTOM w0.203: U75.3 170.84,63.64
  BOTTOM w0.254: U89.H1 v2(148.54,92.72) ; U43.F5 94.88,128.31 v2(95.02,128.45) ; v2(153.42,99.52) 153.4,99.52 U89.B10 ; v2(96.37,125.98) 96.4,125.95 U43.K9 ; v2(96.14,124.92) 96.38,125.16 U43.J10 ; U89.K9 v2(147.11,98.24) ; U43.N4 U43.M4 97.54,128.45 v2(97.38,128.3) ; U43.P3 99,128.95 99.42,129.37 v2(99.42,129.49) v2(99.42,130.26) ; C219.1 55.04,89.31 54.74,89.01 J17.5 ; U43.P5 99.26,127.95 v2(99.44,127.77) ; U89.K5 v2(147.11,95.64)
  BOTTOM w0.305: v1(90.81,146.2) 90.81,147 U30.10 ; 162.26,56.22 161.99,56.49 U92.10 ; v1(24.71,118.01) 24.71,118.19 24.46,118.45 U9.21
  BOTTOM w0.381: v1(23.37,131.15) 23.35,131.16 C107.1 R102.1 ; R18.2 144.7,127.64 147.37,127.64 v1(147.45,127.72) ; v1(53.29,96.14) 53.49,95.95 54.21,95.95 54.23,95.97 ; 170.84,63.64 170.84,62.87 v1(170.66,62.69) ; R134.2 v1(6.69,96.35) ; v1(28.32,60.28) 28.69,59.91 R222.1 29.34,60.91 v1(28.96,61.3) ; v11(99.84,85.62) 100.55,86.33 C363.1 101.44,86.14 v11(101.44,85.62) ; v1(185.47,83.04) 185.57,83.14 R149.2 ; 163.31,54.55 C532.1 ; C532.1 163.7,55.84 163.7,56.16 163.83,56.29 163.83,56.98 R782.2 ; C532.1 162.56,55.45 ; C532.1 163.31,56.36 ; R421.2 v1(10.67,33.3) ; v1(12.8,31.52) 11.95,31.52 C220.1 U33.8 ; U39.5 59.93,64.61 59.96,64.58 C248.1 59.47,64.58 v1(59.11,64.21) ; R160.2 v1(23.37,73.92) ; v1(171.2,23.07) C251.1 171.18,23.83 U41.1 ; U71.5 26.81,49.36 ; v5(138.3,112.52) v9(137.62,112.52) ; R637.1 157.73,100.28 v1(157.61,100.41) ; v1(39.34,100.06) 38.96,100.44 C170.1 38.62,99.74 v1(38.81,99.55) ; v1(96.27,145.96) C212.1 98.34,145.96 v1(98.55,146.18) ; 161.16,37.1 C209.1 160.65,37.56 ; v1(168.64,45.23) 169.16,45.76 R10.2 ; R161.2 v1(7.24,92.54) ; 174.62,81.57 C426.1 ; C426.1 175.13,82.04 ; C426.1 175.64,81.57 ; v1(16.64,122.38) 16.66,122.36 C104.1 17.42,122.36 17.33,122.45 R99.1 v1(16.52,123.53) ; v1(183.41,92.41) 183.2,92.63 182.83,92.63 182.79,92.66 R422.2 ; 172.09,64.58 C444.1 ; C444.1 172.57,65.02 ; C444.1 173.05,64.58 ; 173.63,6.21 C449.1 ; C449.1 174.14,6.68 ; C449.1 174.65,6.21 ; R917.2 v1(166.24,47.42) ; U69.5 31.76,92.49 31.75,92.5 C127.1 ; 85.23,94.46 C361.1 85.98,93.55 ; U70.5 18.81,70.72 C139.1 18.81,72.96 v1(18.8,72.98) ; U2.5 v1(168.66,43.84) ; R232.2 v1(38.73,57.74) ; v1(162.18,41.27) 162.2,41.26 C571.1 162.96,41.26 162.93,41.29 U98.5 ; R420.1 57.16,87.28 v1(57.9,87.28) ; R808.2 v1(10.03,43.18) ; R77.2 v1(21.67,136.99) ; v1(56.1,90.05) 56.12,90.03 C219.1 ; v11(110.31,75.26) 110.31,75.3 C385.1 110.89,75.36 v11(111.03,75.22) ; U68.5 43.03,90.6 C113.1 43.03,92.65 v1(43.05,92.66) ; U39.2 v1(60.58,69.3) ; R100.1 v1(20.38,124.34) ; v1(161.04,50.69) 161.8,50.69 C569.1 163.45,50.69 U97.5 ; R498.2 v1(61.21,62.82) ; 6.73,46.69 v1(6.73,47.58) ; v1(29.05,86.04) 29.34,85.75 R180.1 28.69,84.67 v1(28.32,85.04) ; U19.5 187.87,87.22 188.24,87.58 v1(188.75,87.58) ; R190.2 v1(20.95,69.8) ; R410.2 R417.2 ; R513.2 v1(94.36,104.48) ; v1(22.23,98.76) R121.2 ; R203.2 v1(7.24,67.77) ; C211.1 99.01,149.45 v1(99.29,149.74) ; X1.4 v1(165.99,145.57) ; R914.2 v1(164.55,52.45) ; R259.2 v1(177.95,132.16) ; 162.31,37.1 C210.1 162.81,37.56 ; R450.2 v1(185.32,88.47) ; v1(181.51,99.4) 181.53,99.38 C221.1 181.53,97.64 R730.2 ; R122.2 v1(7.19,116.49) ; R741.2 v1(94.11,136.35) ; R472.2 v1(173.02,80.01) v1(173.66,80.01) ; v1(28.96,103.71) 28.96,103.59 29.34,103.21 R141.1 28.31,102.45 v1(27.94,102.82) ; v1(185.18,96.21) R731.2 ; C3.1 167.96,45.65 168.41,46.1 168.41,46.55 169.36,47.5 v1(170.05,47.5) ; R107.2 v1(42.29,86.31) ; R78.2 v1(7.24,140.8) ; R902.2 v1(164.85,147.83) ; v5(26.42,121.11) v9(27.11,121.11) ; R551.2 v1(23.37,13.34) ; R101.1 v1(21.79,126.7) ; v1(187.73,97.74) 187.73,96.75 C319.1 187.71,95.3 U78.5
  BOTTOM w0.508: v1(23.62,60.79) C143.1 ; R783.2 v1(163.83,59.52) ; R153.2 v1(33.15,91) ; v1(163.96,57.87) R782.2 ; R419.2 v1(154.88,102.44) ; C145.1 23.62,62.04 v1(23.62,61.8) ; R121.2 v1(23.37,97.74) ; R202.2 v1(23.37,48.85) ; J1_1.3 176.51,4.33 ; J1_1.3 174.99,4.33 ; J1_1.3 176.51,2.81 ; J1_1.3 174.99,2.81 ; v1(32.5,92.66) 32.48,92.68 C127.1 ; C133.1 23.62,86.8 v1(23.62,86.57) ; J46.3 169.33,5.63 ; J46.3 167.72,5.63 ; J46.3 169.33,7.24 ; J46.3 167.72,7.24 ; C119.1 24.13,105.36 23.62,104.86 v1(23.62,104.35) ; C151.1 26.81,49.36 27.19,49.36 27.32,49.23 27.56,49.23 v1(27.69,49.1) ; R417.2 v1(76.83,140.03) ; v1(23.62,85.55) C132.1 ; R233.2 v1(28.19,47.69) ; R678.2 v1(69.72,117.18) ; v1(23.62,103.33) C122.1
  vias: v1(23.11,28.53) v1(23.11,27.89) v1(24,28.53) v1(24,27.89) v1(28.32,43.77) v1(28.32,43.13) v1(28.78,113.34) v1(28.78,112.58) v1(29.08,43.77) v1(29.08,43.13) v1(29.54,113.34) v1(29.54,112.58) v1(32.51,77.42) v1(33.1,53.27) v1(33.27,95.84) v1(48.77,122.64) v1(49.28,123.14) v1(50.04,123.14) v1(50.29,110.06) v1(50.29,109.3) v1(51.05,110.06) v1(51.05,109.3) v1(53.24,97.64) v1(53.26,96.88) v1(75.06,111.33) v1(75.95,111.33) v1(114.3,15.07) v1(114.3,14.18) v1(115.44,15.07) v1(115.44,14.18) v1(132.72,14.1) v1(133.99,14.1) v1(135.26,14.1) v1(135.26,13.04) v1(161.16,36.53) v1(161.93,36.53) v1(162.69,36.53) v1(163.2,16.34) v1(163.2,15.19) v1(164.21,16.34) v1(164.21,15.32) v1(172.21,73.87) v1(173.46,64.6) v1(176.15,99.65) v1(176.15,98.38) v1(176.15,97.11) v1(176.15,95.84) v1(176.15,94.57) v1(176.15,81.74) v1(177.04,81.74) v1(177.8,81.74) v2(93.89,127.13) v2(96.65,128.45) v5(34.04,97.28) v5(35.18,97.28) v5(37.08,97.28) v5(86.73,94.91) v5(87.31,94.34) v5(87.81,93.7) v5(118.87,86.06) v5(119.63,86.06) v5(120.4,86.06) v8(34.16,97.92) v8(35.43,97.92) v8(36.7,97.92) v9(34.16,97.92) v9(35.43,97.92) v9(36.7,97.92) v10(86.11,94.68) v10(86.27,93.55) v10(86.27,93.05) v10(118.75,86.7) v10(119.25,85.04) v10(120.27,85.09) v11(86.11,94.68) v11(86.27,93.55) v11(86.27,93.05) v11(118.75,86.7) v11(119.25,85.04) v11(120.27,85.09)
V3_3D_PROFIA: length 3.6
  TOP w0.508: U74.1 v1(128.87,3.81) v1(129.67,3.81) v1(130.56,3.81)
V3_3D_PROFIB: length 3.6
  TOP w0.508: U74.2 v1(128.87,5.08) v1(129.67,5.08) v1(130.56,5.08)
V3_3D_PRU1ETH0JCK: length 7
  BOTTOM w0.381: 22.5,135.21 C102.1 22.03,134.7 ; 22.5,133.05 C103.1 22.03,133.56 ; 22.48,135.48 R77.1 21.98,135.97
  BOTTOM w0.508: 17.87,133.43 J3.3 17.87,132 ; 20.41,132.16 19.69,131.44 18.97,132.16
V3_3D_PRU1ETH1JCK: length 9.1
  BOTTOM w0.381: 24.4,101.81 C116.1 23.93,102.32
  BOTTOM w0.508: 18.97,108.03 J5.4 ; J5.4 20.41,106.6 ; J5.4 18.97,106.6 ; J5.4 20.41,108.03 ; 16.43,107.87 J5.3 ; J5.3 17.87,109.3 ; J5.3 16.43,109.3 ; J5.3 17.87,107.87
V3_3D_PRU2ETH0JCK: length 9.1
  BOTTOM w0.381: 24.4,84.03 C128.1 23.93,84.54
  BOTTOM w0.508: 18.97,83.9 J6.4 ; J6.4 20.41,82.47 ; J6.4 18.97,82.47 ; J6.4 20.41,83.9 ; J6.3 17.87,85.17 ; J6.3 16.43,83.74 ; J6.3 17.87,83.74 ; J6.3 16.43,85.17
V3_3D_PRU2ETH1JCK: length 8.1
  BOTTOM w0.508: 18.97,59.14 J8.4 ; J8.4 20.41,59.14 ; J8.4 18.97,57.71 ; J8.4 20.41,57.71 ; 16.43,58.98 J8.3 ; J8.3 17.87,58.98 ; J8.3 16.43,60.41 ; J8.3 17.87,60.41
V3_3FTDI: length 32.9
  TOP w0.203: U65.1 173.39,70.55 172.97,70.13 172.97,69.52
  TOP w0.254: U37.31 167.64,72.87 v1(167.81,72.7) ; v1(162.23,72.78) 162.14,72.87 U37.20 ; U37.42 172.52,80.89 C233.1
  TOP w0.305: 164.64,87.13 U37.56 ; 167.64,86.82 U37.50
  TOP w0.381: v1(164.64,87.25) 164.64,87.25 164.64,87.13 ; R485.2 v1(154.23,77.35) ; 167.64,86.82 167.18,87.27 C242.2 166.44,88.29 v1(166.42,88.27) ; v1(172.72,81.74) 172.53,81.56 C233.1 ; C229.1 167.94,72.56 v1(167.81,72.7) ; v1(162.23,72.78) C239.1
  BOTTOM w0.203: 171.7,67.14 171.64,67.08 U75.8
  BOTTOM w0.381: v1(163.88,87.38) 163.63,87.13 R496.2 ; U35.5 157.4,75.71 C230.2 156.95,74.52 v1(156.97,74.5) ; v1(164.97,83.7) 164.26,83.7 163.75,84.21 FB10.2 164.12,84.59 v1(164.78,84.59) ; v1(165.61,78.69) 165.8,78.89 C228.2 165.77,79.54 U34.5 ; 170.39,92.41 v1(170.39,91.52) ; v1(164.45,77.09) 164.45,77.28 163.75,77.98 ; FB11.2 163.75,77.98 ; 163.75,77.98 163.75,77.6 v1(163.25,77.09) ; v1(168.28,80.01) v1(168.91,80.01) R472.1 ; v1(164.64,87.25) C236.1
  vias: v1(168.83,78.36) v1(169.63,91.52) v1(171.25,81.92) v1(171.63,82.43) v1(171.63,81.4) v1(172.21,69.8) v1(172.47,67.01)
V3_3USB: length 7.5
  TOP w0.254: v2(141.44,130.33) U3.B9 v2(141.44,129.54) ; U1.Y12 97.79,83.62 v4(97.43,83.97) ; U1.AA12 96.98,83.62 v11(96.62,83.97)
  L3_SIG1 w0.254: v5(97.04,84.24) 97.04,84.22 v4(97.43,83.97) ; v11(96.62,83.97) 96.24,84.21 96.24,84.26 v5(96.24,84.26)
  L10_SIG4 w0.254: v11(97.46,84.02) 97.09,84.25 v5(97.04,84.24) ; v5(96.24,84.26) 96.25,84.2 v11(96.62,83.97)
  BOTTOM w0.381: C399.1 141.71,130.61 v2(141.44,130.33) v2(141.44,129.54) ; C401.1 97.31,83.51 97.31,83.86 v11(97.46,84.02) ; v11(96.62,83.97) 96.62,84 96.71,84.08 C400.1
  vias: v5(82.66,93.53) v5(83.39,93.55) v5(84.3,93.57) v5(85.33,93.57) v5(85.67,91.86)
V5_0D: length 27.2
  TOP w0.279: 61.7,22.88 C427.1 61.7,21.14 U46.11
  TOP w0.381: R560.2 v1(58.8,13.68) ; R562.2 v1(57.66,13.68) ; R390.1 175.67,31.01 v1(175.67,31.75) ; R389.1 175.67,33.17 v1(175.67,33.91) ; v1(175.67,21.59) 175.67,22.33 R396.1 ; R395.1 175.67,24.54 v1(175.67,25.53) 175.67,26.64 R392.1 ; v1(175.67,29.59) 175.67,28.85 R391.1 ; R388.1 v1(174.88,35.31) ; R386.1 175.67,37.49 v1(175.67,38.23)
  TOP w0.508: v1(61.72,23.62) 61.7,23.6 61.7,22.88
  L6_PWR1 w0.508: 186.72,26.8 J37.28 ; J37.28 188.24,26.8 ; J37.28 188.24,25.27 ; J37.28 186.72,25.27 ; J37.27 185.7,26.8 ; J37.27 184.18,26.8 ; J37.27 185.7,25.27 ; J37.27 184.18,25.27
  L9_SIG3 w0.508: J21.2 102.06,148.3 ; J21.2 102.06,149.74 ; J21.2 100.63,149.74 ; J21.2 100.63,148.3
  BOTTOM w0.254: 156.69,106.74 U62.E1 U62.E2
  BOTTOM w0.381: v1(177.17,21.16) 178.12,22.11 C208.1 178.21,22.1 v1(179.22,21.08)
  vias: v1(20.19,45.93) v1(21.46,45.93) v1(25.78,4.95) v1(26.92,4.95) v1(160.02,105.75) v1(160.02,104.48) v1(161.29,105.75) v1(161.29,104.48) v1(170.69,99.27) v1(170.69,98) v1(171.96,99.27) v1(171.96,98) v1(174.88,148.54) v1(174.88,147.27) v1(174.88,146) v1(174.88,144.61) v1(175.01,143.21) v1(176.4,148.54) v1(176.4,147.27) v1(176.4,146) v1(176.4,144.61) v1(176.53,143.21) v1(178.18,148.54) v1(178.18,147.27) v1(178.18,146) v1(178.18,144.61) v1(178.31,143.21)
V5_0D_EN: length 1.6
  BOTTOM w0.173: U62.A4 154.36,105.32 R419.1
V5_0DFB: length 2.7
  BOTTOM w0.254: U62.E3 156.51,105.94 156.7,105.76 156.91,105.76
  BOTTOM w0.381: 156.91,105.76 R424.1
  BOTTOM w0.635: R427.2 R424.1
V5_0HDMICONN: length 3.2
  TOP w0.254: C429.1 60.22,15.47 ; C429.1 59.75,15.98 ; C429.1 59.75,14.97
  TOP w0.279: J24.18 58.65,9.68 v1(58.29,10.03)
  TOP w0.381: 59.75,14.77 v1(59.77,14.75)
V5_0VOP: length 11.7
  TOP w0.381: U28.5 179.58,57.09 C195.1 180.7,55.43 182.75,57.49 182.75,60.03 v1(184.15,61.42)
  BOTTOM w0.381: C207.1 186.23,63.52 ; C207.1 186.74,63.05 ; C207.1 185.72,63.05
V12_0D: length 64.3
  TOP w0.381: J37.2 187.45,59.08 C196.1 ; 162.85,122.34 C461.1 163.75,121.59 ; 161.61,122.09 R647.2 161.07,122.58 ; C303.1 49.38,25.13 v1(49.4,25.15) ; 163.75,124.11 C462.1 162.85,123.35 ; v1(46.61,36.83) C304.1
  L7_PWR2 w0.508: J37.2 188.24,58.29 ; J37.2 186.72,58.29 ; J37.2 186.72,59.82 ; J37.2 188.24,59.82 ; 186.72,43.05 J37.14 ; J37.14 186.72,44.58 ; J37.14 188.24,43.05 ; J37.14 188.24,44.58 ; J22.B1 46.24,31.27 ; J22.B1 45.02,30.05 ; J22.B1 46.24,30.05 ; J22.B1 45.02,31.27 ; 186.72,45.59 J37.12 ; J37.12 188.24,47.12 ; J37.12 186.72,47.12 ; J37.12 188.24,45.59 ; J22.B2 47.24,28.05 ; J22.B2 46.02,29.27 ; J22.B2 47.24,29.27 ; J22.B2 46.02,28.05 ; 47.02,31.27 J22.B3 ; J22.B3 48.24,30.05 ; J22.B3 48.24,31.27 ; J22.B3 47.02,30.05 ; 186.72,52.2 J37.8 ; J37.8 186.72,50.67 ; J37.8 188.24,50.67 ; J37.8 188.24,52.2 ; 47.02,33.77 J22.A3 ; J22.A3 47.02,32.55 ; J22.A3 48.24,33.77 ; J22.A3 48.24,32.55 ; J37.16 188.24,40.51 ; J37.16 186.72,42.04 ; J37.16 188.24,42.04 ; J37.16 186.72,40.51 ; J37.10 188.24,49.66 ; J37.10 188.24,48.13 ; J37.10 186.72,49.66 ; J37.10 186.72,48.13 ; 186.72,57.28 J37.4 ; J37.4 188.24,55.75 ; J37.4 188.24,57.28 ; J37.4 186.72,55.75 ; 46.02,35.77 J22.A2 ; J22.A2 46.02,34.55 ; J22.A2 47.24,35.77 ; J22.A2 47.24,34.55 ; 186.72,53.21 J37.6 ; J37.6 188.24,53.21 ; J37.6 186.72,54.74 ; J37.6 188.24,54.74
  BOTTOM w0.381: v1(185.29,77.12) R379.1 ; R379.1 v1(186.49,76.01) ; R379.1 v1(184.1,76.01)
  vias: v1(162.81,122.89) v1(164.21,124.41) v1(164.21,123.27) v1(164.21,122.13) v1(164.21,120.86) v1(188.21,129.24) v1(188.21,127.97) v1(188.21,126.7) v1(188.21,125.43) v1(188.21,124.16)
VDD_CORE: length 54.7
  TOP w0.254: U1.U8 v4(99.84,87.21) ; U1.N13 v4(103.83,83.21) ; U1.J17 v4(107.03,79.22) ; U1.U16 v11(99.84,80.02) ; U1.L7 v4(105.43,88.01) ; U1.J18 v4(107.03,78.42) ; U1.R19 v11(101.44,77.62) ; U1.P12 v4(103.03,84.01) ; U1.T16 v11(100.64,80.02) ; U1.V8 v4(99.04,87.21) ; U1.N10 v4(103.83,85.61) ; U1.R16 v4(101.44,80.02) ; U1.T13 v4(100.64,83.21) ; U1.P13 v4(103.03,83.21) ; U1.T19 v11(100.64,77.62) ; U1.L8 v4(105.43,87.21) ; U1.R11 v4(101.44,84.81) ; U1.P11 v4(103.03,84.81) ; U1.V16 v11(99.04,80.02) ; U1.H14 v4(107.83,82.41) ; U1.H13 v4(107.83,83.21) ; U1.U9 v4(99.84,86.41) ; U1.U13 v4(99.84,83.21)
  TOP w0.381: 132.46,132.03 133.73,130.76 133.82,130.76 U3.B1 ; 132.46,132.03 131.83,132.67 ; 132.46,132.03 132.46,132.8 ; 102.85,134.13 R640.2 103.91,133.4
  L3_SIG1 w0.203: v11(101.44,77.62) v5(101.04,77.37) ; v11(100.64,77.62) v5(100.24,77.37)
  L3_SIG1 w0.254: v11(99.04,80.02) v5(98.64,79.77) ; v4(99.84,86.41) v5(99.44,86.66) ; v5(100.24,83.46) 100.24,83.46 v4(100.64,83.21) ; v4(103.83,83.21) 104.23,83.46 v5(104.23,83.46) ; v5(101.04,85.06) v4(101.44,84.81) ; v11(99.84,80.02) v5(99.44,79.77) ; v11(100.64,80.02) v5(100.24,79.77) ; v4(103.83,85.61) 104.23,85.86 v5(104.23,85.86) ; v4(101.44,80.02) v5(101.04,79.77) ; v4(99.84,83.21) v5(99.44,83.46) ; v4(105.43,87.21) v5(105.83,87.46) ; v4(99.04,87.21) v5(98.64,87.46) ; v4(99.84,87.21) v5(99.44,87.46) ; v4(105.43,88.01) v5(105.83,88.26) ; v5(108.23,82.66) 108.23,82.66 v4(107.83,82.41) ; v4(107.03,79.22) v5(107.43,78.97) ; v4(107.83,83.21) 108.23,83.46 v5(108.23,83.46) ; v4(103.03,84.01) v5(103.43,84.26) ; v5(103.43,85.06) v4(103.03,84.81) ; v4(107.03,78.42) v5(107.43,78.17) ; v4(103.03,83.21) v5(103.43,83.46)
  L10_SIG4 w0.254: v11(100.64,77.62) v5(100.24,77.37) ; v11(99.84,87.22) v5(99.44,87.46) ; v5(103.43,84.26) 103.08,83.91 v11(103,83.91) ; v11(107.83,82.91) v5(108.23,82.66) ; v11(101.44,84.82) v5(101.04,85.06) ; v11(108.63,83.22) v5(108.23,83.46) ; v11(103.03,83.22) v5(103.43,83.46) ; v11(99.04,80.02) v5(98.64,79.77) ; v11(103.03,84.82) v5(103.43,85.06) ; v11(101.44,77.62) 101.4,77.6 101.19,77.39 101.07,77.39 v5(101.04,77.37) ; v11(103.83,85.62) v5(104.23,85.86) ; v11(100.64,80.02) v5(100.24,79.77) ; v11(99.84,86.42) v5(99.44,86.66) ; v11(99.84,80.02) v5(99.44,79.77)
  L10_SIG4 w0.381: v9(86.74,68.71) v5(86.16,68.71) ; v9(89.92,81.66) v5(89.15,81.66) ; v9(91.85,71.35) v5(91.85,70.76)
  BOTTOM w0.254: C343.1 v11(103,83.91) 103.03,83.87 v11(103.03,83.22) ; v11(103.83,85.62) v11(103.03,84.82) 102.81,85.04 C341.1 101.66,85.04 v11(101.44,84.82) ; C339.1 100.64,77.08 v11(100.64,77.62) v11(101.44,77.62)
  BOTTOM w0.381: 100.38,86.97 99.84,86.42 ; 99.84,86.42 v11(99.84,87.22) ; 99.84,86.42 v11(99.84,86.42) ; v11(107.83,82.91) 107.83,82.94 108.08,83.19 108.6,83.19 v11(108.63,83.22) 109.01,83.6 C342.1 109.44,84.66 C574.1 ; v11(100.64,80.02) 100.64,80.57 C344.1 99.84,80.33 v11(99.84,80.02) ; v11(99.04,80.02) 99.04,80.57 C345.1 ; v9(89.92,81.66) C576.1 ; C572.1 86.72,68.69 v9(86.74,68.71) ; C573.1 91.95,71.45 v9(91.85,71.35)
  vias: v1(73.15,94.82) v1(73.15,93.55) v1(73.15,92.28) v1(74.55,94.37) v1(103.15,131.12) v1(104.55,132.16) v1(104.55,131.12) v1(104.55,129.85) v1(128.91,140.29) v1(128.91,139.4) v1(128.91,138.38) v1(129.79,140.29) v1(129.79,139.4) v1(129.79,138.38) v1(130.81,140.29) v1(130.81,139.4) v1(130.81,138.38) v5(79.25,84.07) v5(80.01,84.07) v5(112.14,77.22) v5(112.75,77.25) v5(113.46,77.24) v8(79.25,84.71) v8(80.01,84.71) v8(112.39,77.81) v8(112.45,76.73) v8(113.44,76.3) v8(114.3,76.33) v9(79.25,84.71) v9(80.01,84.71) v9(112.39,77.81) v9(112.45,76.73) v9(113.44,76.3) v9(114.3,76.33)
VDD_DSPEVE: length 26.2
  TOP w0.254: v4(105.44,83.95) 105.37,83.95 105.37,83.93 105.05,83.62 U1.L12 ; U1.K11 v4(106.23,84.81) ; U1.L10 v4(105.43,85.61) ; U1.M11 v4(104.63,84.81) ; v2(135.05,123.14) U3.K2 v2(135.84,123.14) ; U1.K10 v4(106.23,85.61) ; U1.M13 v4(104.63,83.21) ; U1.K13 v4(106.23,83.21) ; U1.K12 v4(106.23,84.01) ; U1.M12 v4(104.63,84.01) ; U1.M10 v4(104.63,85.61) ; U1.L11 v4(105.43,84.81) ; U1.J13 v4(107.03,83.21)
  TOP w0.381: 119.4,133.27 R642.2 118.35,134
  L3_SIG1 w0.254: v5(105.03,83.46) v4(104.63,83.21) ; v4(106.23,84.81) 106.67,85.09 v5(106.77,85.06) ; v4(105.44,83.95) 105.71,84.23 v5(105.71,84.4) ; v5(105.83,85.86) v4(105.43,85.61) ; v5(105.83,85.06) v4(105.43,84.81) ; v5(106.63,84.26) v4(106.23,84.01) ; v5(105.03,85.86) v4(104.63,85.61) ; v5(105.03,84.26) v4(104.63,84.01) ; v4(107.03,83.21) v5(107.43,83.46) ; v5(106.63,85.86) v4(106.23,85.61) ; v5(106.63,83.46) v4(106.23,83.21) ; v5(105.03,85.06) v4(104.63,84.81)
  L10_SIG4 w0.254: v11(126.49,109.05) v5(127.3,109.05) ; v11(104.63,85.62) v5(105.03,85.86) ; v11(126.49,109.68) 126.87,109.68 v5(127,109.81) ; v11(129.67,109.3) v5(129.03,109.3) ; v11(106.23,83.22) v5(106.63,83.46) ; v5(105.03,84.26) 104.65,83.88 v11(104.5,83.88) 104.5,83.88 ; v11(129.67,110.06) v5(129.03,110.06) ; v11(106.23,84.02) v5(106.63,84.26)
  BOTTOM w0.381: C422.1 C423.1 C358.1 106.28,86.97 106.3,86.95 ; v11(116.71,97.74) 116.71,98.37 C354.1 115.7,98.37 v11(115.7,97.74)
  vias: v1(117.62,132.42) v1(117.86,133.94) v1(118.77,133.05) v1(118.77,131.78) v1(120.04,133.05) v1(120.04,131.78) v5(113.41,86.06) v5(114.17,86.06) v5(114.94,86.06) v5(115.44,98.63) v5(116.03,105.59) v5(116.03,104.83) v5(116.03,98.63) v5(116.2,97.87) v5(116.79,105.59) v5(116.79,104.83) v5(116.79,104.07) v5(117.55,104.83) v10(105.41,85.45) v10(105.59,83.95) v10(106.12,84.66) v10(106.22,85.48) v10(106.3,84.96) v10(113.66,86.82) v10(114.34,85.14) v10(114.97,85.16) v11(105.41,85.45) v11(105.59,83.95) v11(106.12,84.66) v11(106.22,85.48) v11(106.3,84.96) v11(113.66,86.82) v11(114.34,85.14) v11(114.97,85.16)
VDD_GPU: length 17
  TOP w0.254: U3.K6 v2(138.25,123.14) ; U3.K6 v2(139.04,123.93) ; U3.K6 v2(138.25,123.93) ; U1.U12 v4(99.84,84.01) ; U1.V10 v4(99.04,85.61) ; U1.U11 v4(99.84,84.81) ; U1.W10 v4(98.24,85.61) ; U1.W11 v4(98.24,84.81) ; U1.V11 v4(99.04,84.81) ; U1.W13 v4(98.24,83.21) ; U1.V14 v4(99.04,82.41)
  TOP w0.381: L17.2 v1(135.51,111.33)
  L3_SIG1 w0.254: v5(98.64,85.06) v4(99.04,84.81) ; v5(99.44,85.06) v4(99.84,84.81) ; v5(98.64,85.86) v4(99.04,85.61) ; v5(97.84,85.86) v4(98.24,85.61) ; v5(99.09,81.81) 99.04,81.86 v4(99.04,82.41) ; v5(97.84,83.46) v4(98.24,83.21) ; v5(97.84,85.06) v4(98.24,84.81) ; v5(99.44,84.26) v4(99.84,84.01)
  L10_SIG4 w0.254: v11(99.04,84.82) v5(98.64,85.06) ; v11(98.76,82.25) 99.09,81.91 v5(99.09,81.81) ; v11(99.84,84.82) v5(99.44,85.06) ; v11(98.24,84.82) v5(97.84,85.06) ; v11(99.04,85.62) v5(98.64,85.86) ; v5(99.44,84.26) 99.8,84.04 99.81,84.04 99.85,84 v11(99.84,84) ; v11(98.24,85.62) v5(97.84,85.86)
  BOTTOM w0.254: v11(98.76,82.25) 98.27,81.76 C329.1
  BOTTOM w0.381: C328.1 91.97,88.12 v11(91.95,88.09) ; C330.1 v11(90.97,88.09)
  vias: v1(133.73,112.98) v1(134.37,111.33) v1(136.58,111.33) v5(89.04,88.45) v5(89.61,88.35) v5(90.17,88.34) v5(90.42,87.76) v5(90.86,87.41) v10(86.41,88.5) v10(86.41,87.87) v10(87.05,87.33) v10(88.19,87.33) v10(88.95,87.33) v10(89.71,87.33) v11(86.41,88.5) v11(86.41,87.87) v11(87.05,87.33) v11(88.19,87.33) v11(88.95,87.33) v11(89.71,87.33)
VDD_IVA: length 8.4
  TOP w0.254: U1.V18 v4(99.04,78.42) ; U1.V19 v11(99.04,77.62) ; U1.U18 v4(99.84,78.42) ; U1.U19 v11(99.84,77.62)
  TOP w0.381: v2(142.25,122.34) U3.L11 v2(143.04,122.34)
  L3_SIG1 w0.203: v11(99.84,77.62) v5(99.44,77.37) ; v11(99.04,77.62) v5(98.64,77.37)
  L3_SIG1 w0.254: v4(99.04,78.42) v5(98.64,78.17) ; v4(99.84,78.42) v5(99.44,78.17)
  L10_SIG4 w0.254: v5(99.44,78.17) 99.86,78.43 99.86,78.43 v11(99.85,78.43) ; v11(99.84,77.62) v5(99.44,77.37) ; v11(99.04,77.62) v5(98.64,77.37)
  BOTTOM w0.381: v1(133.48,104.86) 132.75,104.86 132.31,104.42 C270.1
  vias: v1(143.51,111.21) v1(144.65,111.21) v1(145.8,111.21)
VDD_MPU: length 41.7
  TOP w0.254: U1.M16 v11(104.63,80.02) ; U1.M17 v11(104.63,79.22) ; U1.L16 v11(105.43,80.02) ; v4(102.84,79.22) 102.84,79.41 U1.P17 ; U1.M18 v4(104.63,78.42) ; U1.N17 v4(103.83,79.22) ; U1.M15 v11(104.63,80.82) ; U1.L17 v11(105.43,79.22) ; U1.P18 v4(103.03,78.42) ; U1.R18 v4(101.44,78.42) ; U1.L15 v4(105.43,80.82) ; U1.N18 v4(103.83,78.42) ; U1.L19 v4(105.43,77.62) ; U1.L18 v4(105.43,78.42) ; U1.K18 v4(106.23,78.42) ; U1.K17 v11(106.23,79.22)
  TOP w0.381: 111.27,133.27 R641.2 110.22,134 ; U3.B13 145.03,130.73 145.03,131.15 145.42,131.53
  L3_SIG1 w0.254: v4(103.03,78.42) v5(103.43,78.17) ; v11(104.63,80.02) v5(105.03,79.77) ; v4(105.43,78.42) v5(105.83,78.17) ; v4(104.63,78.42) v5(105.03,78.17) ; v4(103.83,78.42) v5(104.23,78.17) ; v4(102.84,79.22) 102.97,79.25 v5(103.43,78.97) ; v4(105.43,77.62) v5(105.83,77.37) ; v4(101.44,78.42) v5(101.04,78.17) ; v11(105.43,80.02) v5(105.83,79.77) ; v4(106.23,78.42) v5(106.63,78.17) ; v11(104.63,80.82) v5(105.03,80.57) ; v4(105.43,80.82) v5(105.83,80.57) ; v11(105.43,79.22) v5(105.83,78.97) ; v4(103.83,79.22) v5(104.23,78.97) ; v11(106.23,79.22) v5(106.63,78.97) ; v11(104.63,79.22) v5(105.03,78.97)
  L10_SIG4 w0.254: v11(104.63,80.82) v5(105.03,80.57) ; v11(105.43,79.22) v5(105.83,78.97) ; v11(105.43,80.02) v5(105.83,79.77) ; v5(105.83,78.17) 105.81,78.27 105.42,78.51 v11(105.42,78.52) ; v5(106.63,78.17) 106.33,78.36 106.3,78.49 106.3,78.49 v11(106.29,78.49) ; v11(104.63,80.02) v5(105.03,79.77) ; v5(104.23,78.97) v11(104.63,79.22) v5(105.03,78.97) ; v5(104.23,78.17) 104.28,78.17 v11(104.6,78.49) 104.65,78.49 104.92,78.21 104.92,78.17 v5(105.03,78.17) ; v11(106.23,79.22) v5(106.63,78.97)
  L10_SIG4 w0.381: v9(114.66,91.39) 114.66,91.5 v5(115.06,91.9) ; v9(112.9,90.38) 113.16,90.38 v5(113.44,90.66) ; v11(104.65,95.2) v5(104.65,94.44) ; v9(115.57,88.09) v5(116.46,88.09) ; v9(116.2,80.09) v5(115.57,80.09) ; v9(116.2,79.08) v5(115.57,79.08) ; v11(103.63,95.2) v5(103.63,94.47)
  BOTTOM w0.381: v9(115.57,88.09) 115.57,89.41 115.23,89.74 C474.1 114.66,89.74 ; 114.66,89.74 v9(114.66,91.39) ; 114.66,89.74 113.25,89.74 112.9,90.09 v9(112.9,90.38) ; v11(104.65,95.2) 104.65,95.96 C395.1 103.63,95.96 v11(103.63,95.2) ; v9(116.2,80.09) C370.1 ; 116.97,79.08 v9(116.2,79.08)
  vias: v1(145.8,134.19) v1(145.8,133.43) v1(145.8,132.67) v1(145.92,132.03) v1(146.56,134.19) v1(146.56,133.43) v1(146.56,132.67) v2(116.84,125.68) v2(116.84,124.54) v2(116.84,123.27) v2(118.21,125.66) v2(118.21,124.52) v2(118.21,123.25) v2(118.21,121.98) v5(97.26,94.62) v5(97.26,94.06) v5(97.26,93.5) v8(96.27,95.33) v8(96.9,95.71) v8(96.9,95.08) v9(96.27,95.33) v9(96.9,95.71) v9(96.9,95.08) v10(102.23,79.84) v11(102.23,79.84)
VDD_RTC: length 3.4
  TOP w0.381: v1(138.29,131.83) 138.29,131.18 U3.A5
  BOTTOM w0.381: C402.1 137.76,133.03 138.37,133.03 v1(138.43,133.1) v1(138.43,132.46) 138.43,131.97 v1(138.29,131.83)
  vias: v5(79.91,86.44) v5(80.67,86.44) v8(80.14,87.38) v8(80.77,87.76) v9(80.14,87.38) v9(80.77,87.76)
VDDR2_VREF: length 8.8
  TOP w0.173: U1.N22 v4(103.83,75.22)
  TOP w0.381: v2(144.04,61.32) 144,61.29 143.62,61.29 143.24,60.9 C523.1
  L3_SIG1 w0.254: v4(103.83,75.22) 104.19,74.86 v5(104.2,74.86)
  L10_SIG4 w0.254: v5(104.2,74.86) 103.8,74.6 103.76,74.57 v11(103.76,74.55)
  BOTTOM w0.254: U91.M8 v2(144.04,61.32) ; U90.H1 v2(140.44,51.84) ; U92.6 161.52,59.11 161.54,59.14 ; U91.H1 v2(140.84,66.93) ; U90.M8 v2(143.26,46.07)
  BOTTOM w0.381: v1(139.07,55.2) 139.05,55.22 C505.1 ; C531.1 161.05,61.3 ; C531.1 160.59,60.79 ; C531.1 161.05,60.28 ; C524.1 103.94,74.74 103.77,74.57 103.77,74.56 v11(103.76,74.55)
  vias: v1(138.68,74.12) v1(138.68,72.85) v1(139.95,74.12) v1(139.95,72.85)
VDDR2_VTT: length 20.3
  BOTTOM w0.305: U92.3 157.53,57.49 157.14,57.87 156.84,57.87
  BOTTOM w0.381: 150.62,71.44 C527.1 150.11,71.91 ; R807.1 147.15,55.2 150.11,58.17 151.51,58.17 ; 148.59,71.44 C526.1 149.1,71.91 ; C530.1 151.96,67.26 ; C530.1 151.49,67.77 ; C530.1 151.49,66.76
  BOTTOM w0.508: R784.2 157.23,63.2 156.21,64.22 v1(152.27,64.22)
  vias: v1(152.27,68.28) v1(152.27,66.25) v1(152.27,62.18) v1(152.27,60.15) v1(153.29,58.76) v1(153.29,57.99) v1(154.05,58.76) v1(154.05,57.99)
VDDR_VREF: length 11
  TOP w0.254: U5.M8 v2(87.98,29.48) ; U5.H1 v2(83.18,32.68) ; U6.M8 v2(118.46,29.48) ; U1.Y18 v4(97.44,78.42) ; U7.H1 v2(98.42,32.68) ; U7.M8 v2(103.22,29.48) ; U6.H1 v2(113.66,32.68)
  TOP w0.381: 78.74,32.95 C44.2 ; C44.2 78.23,33.42 ; C44.2 79.25,33.42 ; 78.23,32.24 C45.1 ; C45.1 79.25,32.24 ; C45.1 78.74,32.71
  TOP w0.508: v1(107.57,28.7) C83.1 ; v1(92.33,28.96) C46.1 ; v1(122.81,28.7) C54.1
  L3_SIG1 w0.254: v4(97.44,78.42) v5(97.04,78.17)
  L10_SIG4 w0.254: v5(97.04,78.17) 97.03,78.17 96.77,77.91 96.77,77.79 v11(96.76,77.79)
  BOTTOM w0.381: v11(96.76,77.79) 96.44,78.1 C81.1
  vias: v1(91.19,21.08) v1(91.82,20.45) v1(92.46,21.21) v1(92.96,20.57) v1(93.6,19.94)
VDDR_VTT: length 25.8
  TOP w0.305: U8.3 107.82,17.48 107.52,17.78 107.44,17.78
  TOP w0.381: 127.31,24.77 C89.1 ; C89.1 127.78,25.27 ; C89.1 127.78,24.26
  TOP w0.508: R69.2 102.6,17.4 102.01,17.98 102.01,21.11 103.13,22.23 106.68,22.23
  BOTTOM w0.381: 127.57,29.34 C87.1 128.03,28.83 ; 127.57,26.92 C314.1 ; C314.1 128.03,27.43 ; C314.1 128.03,26.42 ; 112.01,22.08 C94.1 ; C94.1 113.03,22.08 ; C94.1 112.52,22.55 ; 127.91,23.49 C98.1 ; C98.1 127.44,24 ; C98.1 127.91,24.51 ; C96.1 119.38,20.32 ; C96.1 118.48,19.57 ; C96.1 120.28,19.57 ; 125.08,19.82 C95.1 ; C95.1 125.98,20.58 ; C95.1 126.89,19.82 ; C313.1 123.19,20.94 ; C313.1 122.17,20.94 ; C313.1 122.68,21.41
  vias: v1(118.11,19.67) v1(120.65,19.67) v1(124.84,19.8) v1(125.98,20.98) v1(127.13,19.8)
VDDS_DDR: length 183.3
  TOP w0.254: U7.B2 v2(99.22,37.48) ; U7.A1 v2(97.62,38.28) ; U5.K2 v2(83.98,31.08) ; U5.D9 v2(89.74,35.48) ; U7.K2 v2(98.42,31.08) ; U5.G7 v2(87.18,33.48) ; v2(97.38,26.68) U7.R1 ; U7.N9 v2(104.98,28.28) ; U5.N1 v2(82.21,28.28) ; U5.R1 v2(82.21,26.68) ; U6.C9 v2(119.26,36.68) ; U7.D2 v2(99.22,35.88) ; U5.F1 v2(83.18,34.28) ; U7.N1 v2(97.45,28.28) ; U5.H2 v2(83.98,32.68) ; U6.N1 v2(112.69,28.28) ; U7.F1 v2(98.42,34.28) ; U6.C1 v2(112.86,36.68) ; U7.A8 v2(103.22,38.28) ; U6.R9 v2(120.27,26.68) ; U6.A8 v2(118.86,38.44) ; U7.E9 v2(104.02,35.08) ; U6.E9 v2(119.26,35.08) ; U6.B7 v2(117.66,37.48) ; U6.N9 v2(120.22,28.28) ; U6.B2 v2(114.46,37.48) ; U6.G7 v2(117.66,33.48) ; U6.H9 v2(120.06,32.68) ; U5.C9 v2(88.78,36.68) ; U7.G7 v2(102.42,33.48) ; U7.H2 v2(99.22,32.68) ; U5.C1 v2(82.21,36.28) ; U7.D9 v2(104.82,35.88) ; U5.A1 v2(82.21,37.88) ; U6.K8 v2(118.46,31.08) ; U5.A8 v2(87.98,38.28) ; U6.K2 v2(113.66,31.08) ; U5.K8 v2(87.98,31.08) ; U5.D2 v2(83.98,35.88) ; U5.N9 v2(89.74,28.28) ; U6.D2 v2(114.46,35.88) ; U7.R9 v2(104.98,26.68) ; U6.D9 v2(120.06,35.88) ; U5.E9 v2(88.78,35.08) ; U6.H2 v2(114.46,32.68) ; U6.F1 v2(113.66,34.28) ; U6.A1 v2(112.86,38.28) ; U5.B2 v2(83.98,37.48) ; U7.H9 v2(104.82,32.68) ; U5.R9 v2(89.74,26.68) ; U7.C1 v2(97.62,36.68) ; v2(112.64,26.66) 112.65,26.68 U6.R1 ; U7.K8 v2(103.22,31.08) ; U5.H9 v2(89.74,32.28) ; U7.C9 v2(104.02,36.68)
  TOP w0.305: C90.1 108.71,17.78 108.32,17.39 U8.2
  TOP w0.381: C514.1 136.15,58.88 136.44,59.18 v2(136.44,59.59) ; C52.1 98.06,18.95 v1(98.06,17.91) ; C52.1 v1(96.92,19.05) ; C52.1 98.06,19.15 v1(98.06,20.19) ; C502.1 134.42,46.04 v2(134.46,46.07) ; C491.1 138.58,52.11 v2(138.84,51.84) ; C493.1 136.54,51.39 136.06,50.9 v2(136.04,50.9) ; C520.1 139.28,62.8 139.28,62.12 v2(139.27,62.1) ; C33.1 89.17,17.88 v1(89.17,18.92) ; C33.1 v1(88.03,17.78) ; C33.1 89.17,17.68 v1(89.17,16.64) ; C89.2 129.41,24.77 v1(129.67,25.02) ; v1(136.29,56.22) C510.1 135.14,55.17 v1(135.24,55.07) ; 62.83,74.02 R639.1 63.56,72.96 ; C507.1 137.56,59.15 138,59.59 v2(138.04,59.59) ; C529.2 139.21,70.46 v1(139.19,70.44) ; C500.1 137.56,43.88 138.03,44.35 v2(138.04,44.35) ; C512.1 144.51,67.15 v2(144.44,67.08) ; v1(150.5,57.36) 150.51,57.38 C539.2 ; R45.2 v2(112.39,15.11) ; C496.1 139.28,47.56 v2(139.28,46.89) ; v2(140.06,45.26) 140.07,45.26 140.57,44.76 C499.1 ; C494.1 134.26,51.11 v2(134.46,50.91) ; C501.1 136.13,44.04 v2(136.44,44.35) ; v2(134.44,66.12) 134.44,66.84 134.21,67.07 134.21,67.73 C511.1 ; C488.1 145.94,51.94 v2(146.04,51.84) ; C513.1 145.94,67.18 v2(146.04,67.08) ; 140.07,60.5 140.08,60.5 140.87,61.29 141.65,61.29 v2(141.68,61.32) ; 140.07,60.5 140.57,60 C508.1 C519.1 ; 140.07,60.5 v2(140.03,60.5) ; C517.1 146.07,59.56 v2(146.04,59.59) ; C64.1 113.3,19.15 v1(113.3,20.19) ; C64.1 v1(112.24,19.05) ; C64.1 113.3,18.95 v1(113.3,17.91) ; v2(134.44,61.29) 134.43,61.28 C506.1 ; U3.K13 144.77,123.54 145.54,122.76 ; v2(138.84,67.11) 138.96,67.22 C515.1 ; v1(146.96,57.87) 147.06,57.77 C492.1 v1(145.9,56.72) ; C516.1 136.54,66.63 136.06,66.14 v2(136.04,66.14) ; v2(144.44,51.84) 144.44,52.47 C490.1 ; v2(144.44,59.59) 144.44,59.53 144.14,59.22 144.14,58.98 C509.1
  TOP w0.508: v1(78.74,35.18) C44.1 ; v1(93.98,35.18) C80.1 ; v1(109.22,35.18) C47.1 ; 146.1,122.2 145.54,122.76
  L3_SIG1 w0.381: v1(109.6,20.7) 108.97,20.07 108.97,17.1 110.95,15.11 v2(112.39,15.11)
  BOTTOM w0.254: v2(140.03,60.5) 140.07,60.5 U91.H9 ; C503.1 139.92,56.24 v1(139.18,56.24) ; v2(141.68,50.09) 141.68,50.13 U90.K2 ; v2(136.04,50.9) 136.06,50.9 U90.C1 ; U91.N1 v2(144.44,67.08) ; U91.C9 v2(136.44,59.59) ; U91.A8 134.48,61.29 v2(134.44,61.29) ; U90.H9 140.07,45.26 v2(140.06,45.26) ; U91.E9 v2(138.04,59.59) ; U91.D9 v2(136.86,60.51) ; v2(136.83,65.35) 136.87,65.35 U91.D2 ; U90.A1 v2(134.46,50.91) ; U91.K8 142.04,60.95 v2(141.68,61.32) ; U90.B2 v2(135.26,50.1) ; U90.D9 v2(136.86,45.27) ; U91.C1 136.06,66.14 v2(136.04,66.14) ; U91.N9 v2(144.44,59.59) ; U91.K2 v2(141.66,65.35) ; U91.R1 v2(146.04,67.08) ; U91.B2 v2(135.22,65.31) ; U91.F1 v2(138.84,67.11) ; U91.G7 v2(139.27,62.1) ; U90.C9 v2(136.44,44.35) ; U90.D2 v2(136.86,50.1) ; U90.K8 v2(141.66,46.07) ; U90.A8 v2(134.46,46.07) ; U91.H2 v2(140.05,65.33) ; U90.R1 v2(146.04,51.84) ; U90.E9 v2(138.04,44.35) ; U90.N9 v2(144.44,44.35) ; U90.F1 v2(138.84,51.84) ; v2(134.44,66.12) U91.A1 ; v2(139.28,46.89) 139.28,46.85 U90.G7 ; U90.N1 v2(144.44,51.84) ; U91.R9 v2(146.04,59.59) ; U90.H2 v2(140.06,50.11) ; U90.R9 v2(146.04,44.35)
  BOTTOM w0.305: 156.84,56.6 156.93,56.6 157.23,56.9 157.23,56.98 U92.2
  BOTTOM w0.381: v2(102.42,33.48) 102.33,33.38 C58.1 ; 111.38,14.73 112.01,14.73 v2(112.39,15.11) ; C71.1 114.19,37.74 v2(114.46,37.48) ; v2(99.22,37.48) 99.18,37.48 98.55,38.1 98.55,38.59 C69.1 ; v2(120.06,35.88) 120.65,36.47 C76.1 ; v2(97.45,28.28) 97.39,28.21 C57.1 ; v2(114.46,32.68) 113.66,31.88 C60.1 ; C72.1 112.39,26.91 v2(112.64,26.66) ; C79.1 112.37,27.96 v2(112.69,28.28) ; C56.1 97.75,31.75 v2(98.42,31.08) ; C35.1 89.85,26.78 v2(89.74,26.68) ; v1(130.05,30.48) 130.03,30.5 C85.2 ; C38.1 90.31,34.91 v2(89.74,35.48) 89.36,35.48 88.78,36.06 v2(88.78,36.68) 89.31,36.68 89.52,36.47 C32.1 ; C77.1 112.63,35.92 112.86,36.15 v2(112.86,36.68) ; v1(142.11,69.68) 142.11,70.33 C538.2 ; C50.1 103.65,38.75 103.22,38.32 v2(103.22,38.28) ; v2(119.26,35.08) 119.43,34.91 C73.1 ; C65.1 105.02,32.87 v2(104.82,32.68) ; v2(97.62,36.68) 97.62,36.41 97.14,35.92 C67.1 ; C61.1 120.26,32.87 v2(120.06,32.68) ; C30.1 83.45,38.72 83.45,38.01 v2(83.98,37.48) ; C31.1 82.14,37.95 v2(82.21,37.88) ; v2(87.98,31.08) 88.03,31.03 C39.1 ; C49.1 97.07,37.95 97.4,38.28 v2(97.62,38.28) ; C51.1 97.28,26.78 v2(97.38,26.68) ; v2(89.74,32.28) 90.13,31.9 C36.1 ; C62.1 117.57,33.38 v2(117.66,33.48) ; C75.1 120.29,28.34 v2(120.22,28.28) ; v2(98.42,34.28) 97.16,34.28 C59.1 ; v2(118.86,38.44) 118.89,38.47 C63.1 ; v2(83.18,34.28) 82.79,33.89 C42.1 ; v1(139.19,71.46) 139.94,71.46 C521.1 ; v1(129.92,26.92) C314.2 ; v2(104.98,26.68) 105.09,26.78 C55.1 ; v2(104.98,28.28) 105.05,28.34 C66.1 ; v2(113.66,34.28) 112.62,34.28 112.24,33.89 C78.1 ; v2(89.74,28.28) 89.81,28.34 C37.1 ; v2(82.21,36.28) 81.86,35.92 C29.1 ; C74.1 112.54,37.95 v2(112.86,38.28) ; v2(104.02,35.08) 105.62,35.08 C68.1 ; C70.1 120.37,26.78 v2(120.27,26.68) ; v2(104.82,35.88) 105.41,36.47 C48.1 ; v1(149.1,69.68) C526.2 ; v2(87.98,38.28) 88.41,38.71 C34.1 ; v1(130.05,29.34) C87.2
  BOTTOM w0.508: R786.2 C543.1 154.31,52.15 153.41,53.05 v1(153.41,55.96)
  vias: v1(61.02,73.81) v1(61.02,72.54) v1(62.29,73.81) v1(62.29,72.54) v1(62.68,57.04) v1(62.68,55.77) v1(62.68,54.5) v1(63.56,72.54) v1(63.95,57.04) v1(63.95,55.77) v1(108.71,21.46) v1(108.71,20.7) v1(109.6,21.46) v1(148.84,118.32) v1(148.84,117.18) v1(150.11,118.32) v1(150.11,117.18) v1(151.26,118.32) v1(151.26,117.18) v1(153.41,56.72) v1(154.17,56.72) v1(154.17,55.96)
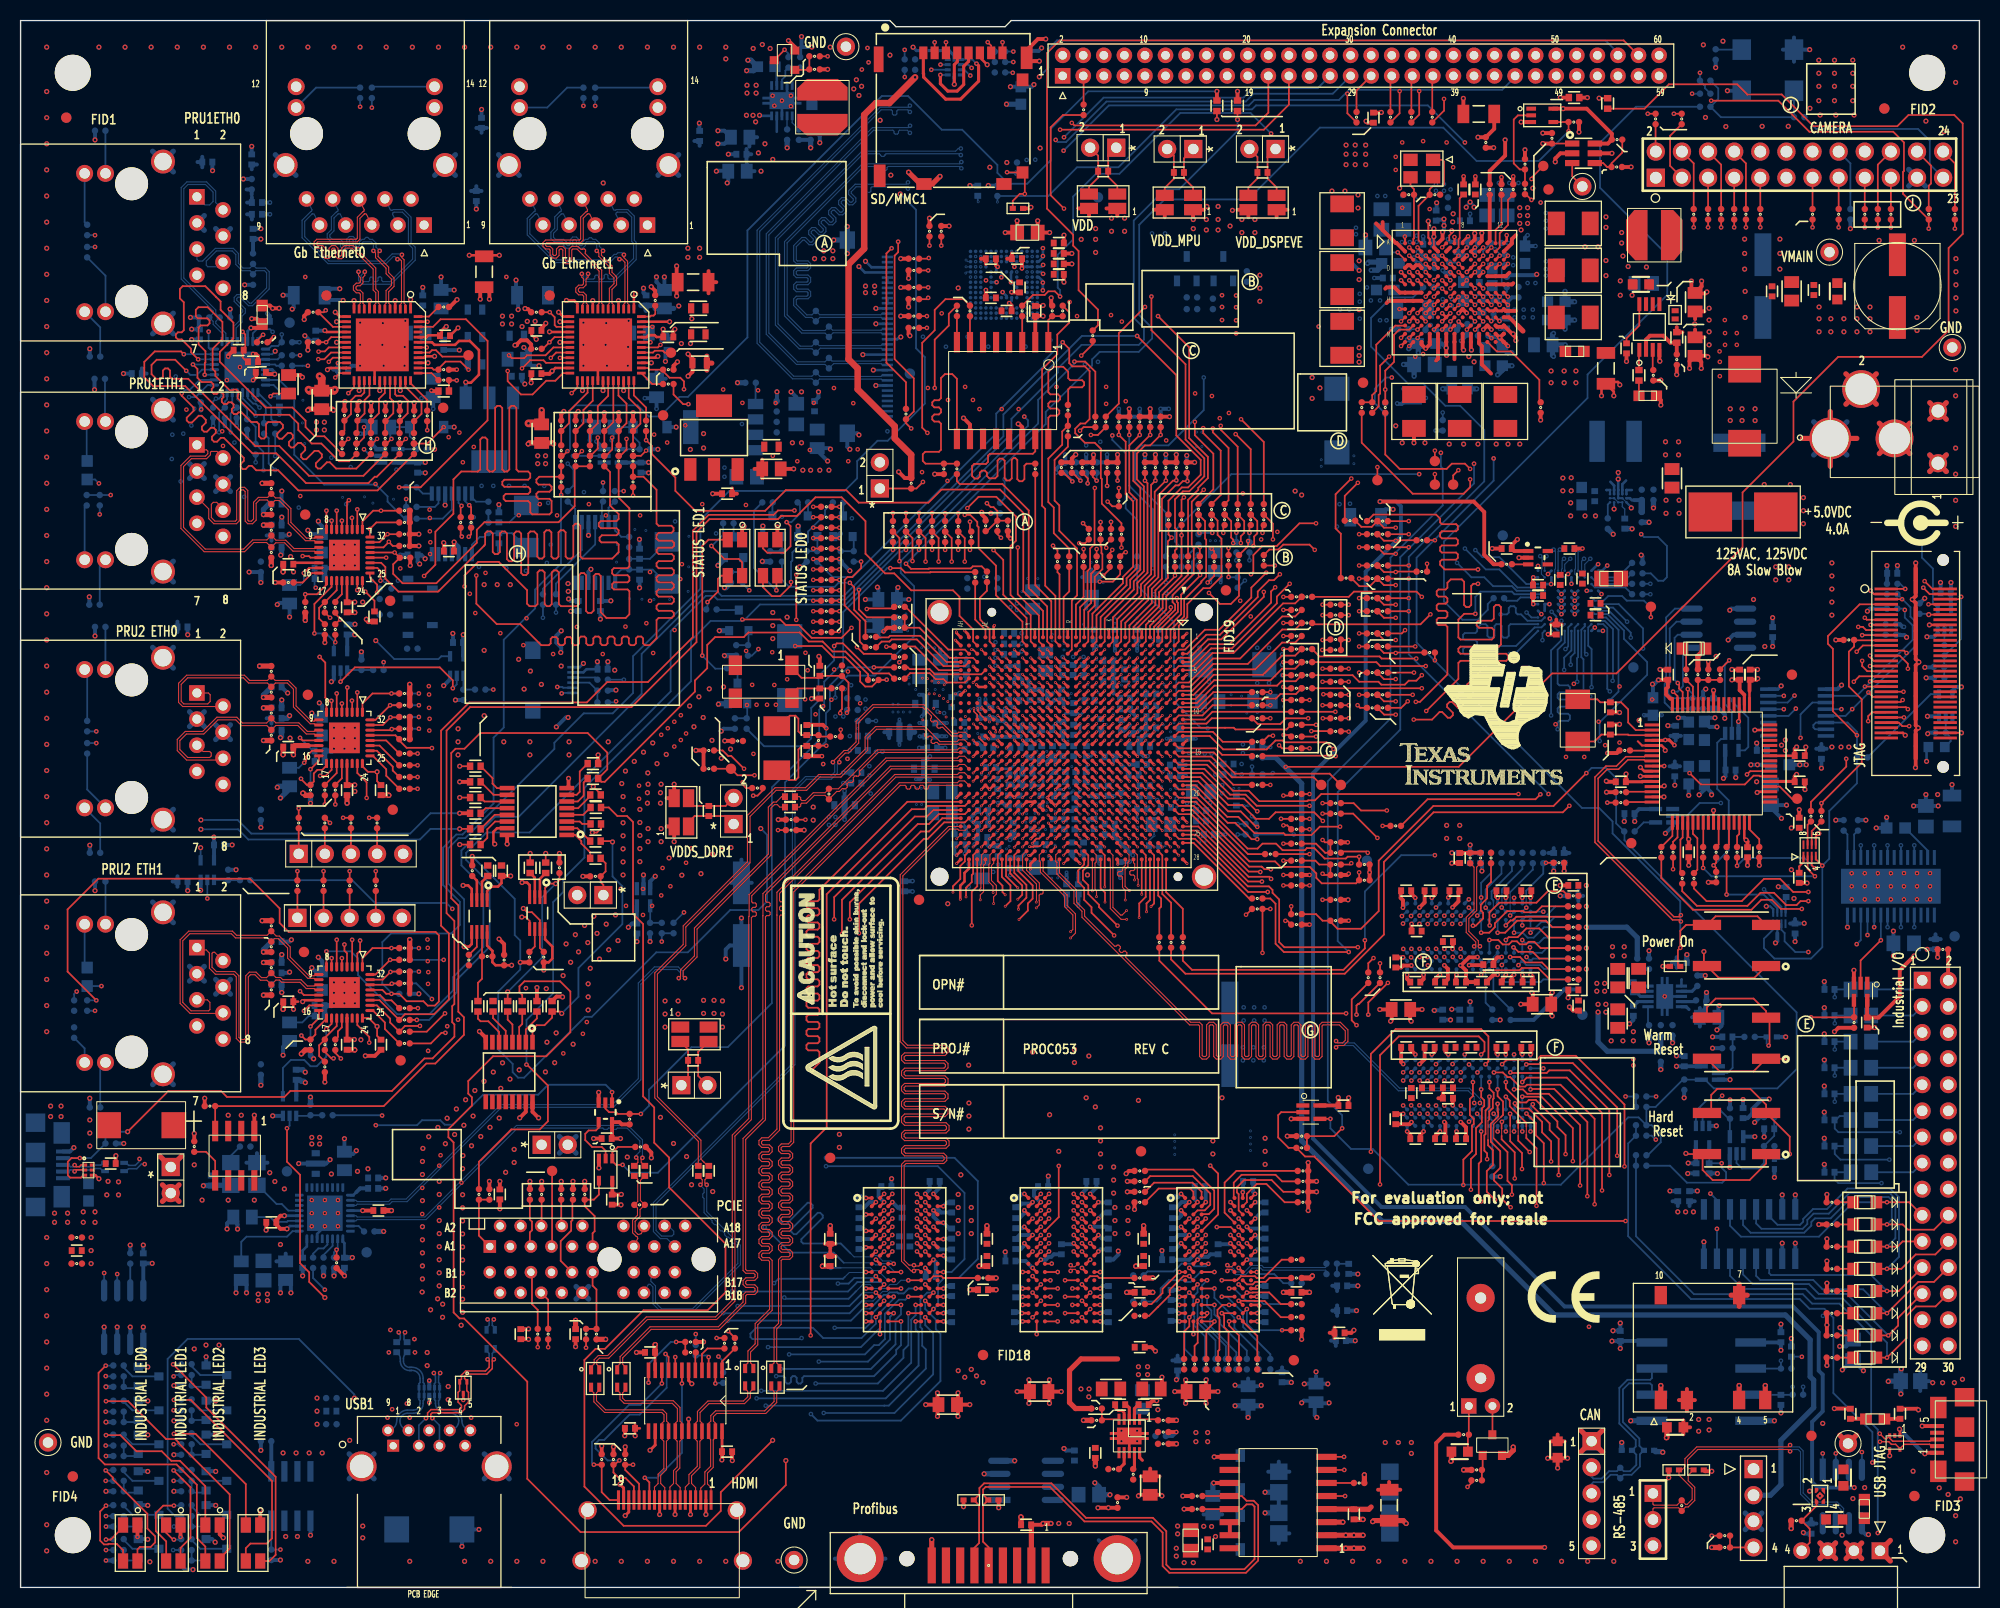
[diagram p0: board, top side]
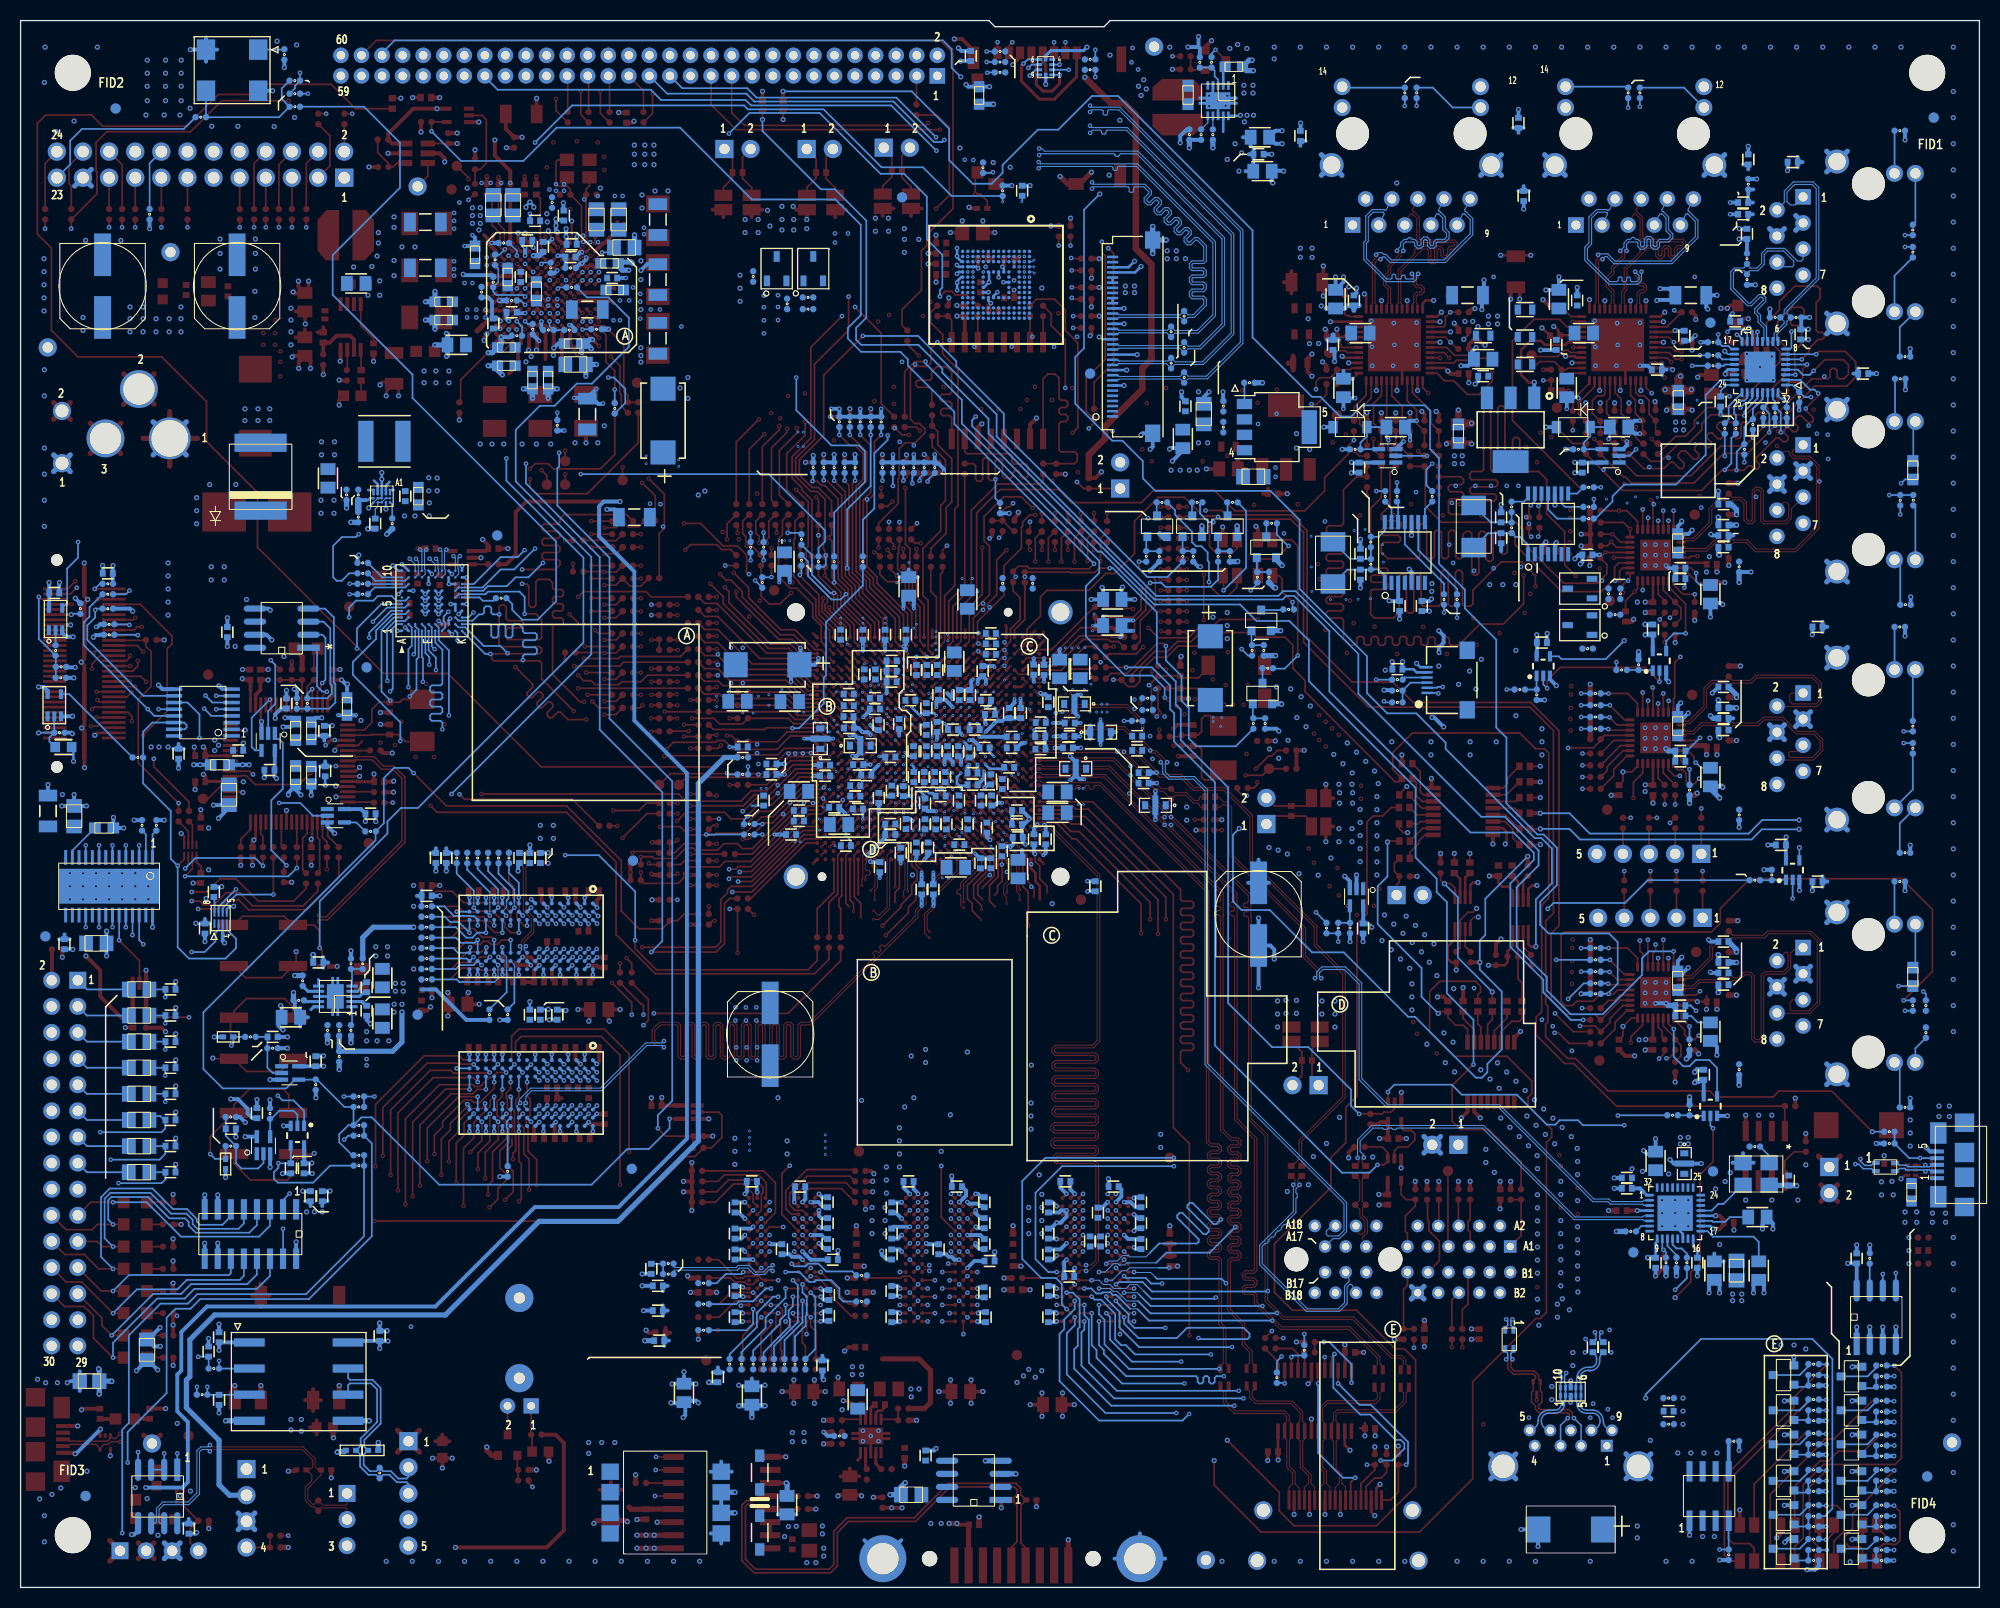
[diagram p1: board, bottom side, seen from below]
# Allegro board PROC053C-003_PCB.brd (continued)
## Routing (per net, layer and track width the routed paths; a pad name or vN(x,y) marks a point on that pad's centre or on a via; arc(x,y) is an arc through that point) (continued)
AM57XX_PRU1ETH_MDDATA: length 232.9
  TOP w0.173: U1.F6 v4(109.43,88.81) ; v2(30.1,94.32) R142.2
  L3_SIG1 w0.109: v2(30.1,94.32) 28.73,94.32 27.89,93.48 25.03,93.48 24.96,93.55 24.95,93.55 15.49,103 15.49,113.24 17.19,114.93 17.19,118.25 17.99,119.05 17.99,120.49 17.44,121.05 17.44,125.81 19.19,127.56 22.66,127.56 25.63,130.54 43.15,130.54 43.16,130.54 46.62,130.54 50.17,134.09 51.66,134.09 51.67,134.08 62.38,134.08 63.45,135.15 76.86,135.15 79.91,138.2 92.33,138.2 93.47,137.06 103.28,137.06 106.73,133.61 106.73,131.27 112.75,125.25 112.75,123.27 124.03,111.99 124.03,108 127.25,104.77 v5(127.25,102.7) ; v5(109.83,89.06) 109.43,88.82 v4(109.43,88.81)
  L9_SIG3 w0.114: v2(30.1,94.32) 30.1,98.3 29.46,98.93 29.46,102.44 26.69,105.21 26.69,107.12 25.91,107.9 25.91,118.57 v2(27.18,119.84)
  L10_SIG4 w0.109: v5(127.25,102.7) 126.64,102.09 126.29,102.09 125.07,100.87 125.07,99.45 122.63,97.01 121.29,97.01 114.15,89.87 112.12,89.87 111.31,89.06 v5(109.83,89.06)
  BOTTOM w0.173: R98.2 v2(27.18,119.84)
AM57XX_PRU2ETH0_COL: length 161.1
  TOP w0.173: v7(123.04,79.81) 139.86,79.81 148.95,88.9 155.19,88.9 167.46,101.17 167.46,106.5 172.42,111.46 172.42,115.34 176.76,119.68 184.91,119.68 187.5,122.28 187.5,130.28 188.87,131.65 188.87,142.39 188.05,143.22 183.6,143.22 182.51,142.13 174.36,142.13 171.27,145.21 167.92,145.21 166.93,146.2 160.3,146.2 157.93,143.83 R953.1 ; U1.F15 v4(109.43,80.82)
  L3_SIG1 w0.109: v7(123.04,79.81) 121.79,79.81 120.55,81.05 119.69,81.05 119.58,81.16 112.21,81.16 112.04,81.32 110.82,81.32 110.81,81.31 110.28,81.31 109.79,80.82 v4(109.43,80.82)
AM57XX_PRU2ETH0_CRS: length 437.3
  TOP w0.173: U1.B18 112.23,78.81 112.63,78.42 114.51,78.42 117.44,75.48 118.65,75.48 120.14,74 120.25,74 v7(120.27,73.98) ; R177.2 v2(38.61,79.96)
  TOP w0.381: R952.1 v1(149.74,144.91)
  L3_SIG1 w0.109: v7(120.27,73.98) v5(119.68,73.98)
  L4_SIG2 w0.114: v5(119.68,73.98) 122.89,77.18 129.77,77.18 130.49,77.9 149.33,77.9 160.16,67.08 161.38,67.08 168.61,59.86 168.61,46.99 167.23,45.61 167.23,35.74 158.34,26.85 155,26.85 144.21,16.05 139,16.05 132.82,9.87 117.52,9.87 116.71,9.06 114.83,9.06 113.61,10.28 105.48,10.28 104.85,9.65 98.63,9.65 98.04,10.24 95.77,10.24 94.45,11.56 68.79,11.56 68.46,11.89 64.03,11.89 63.54,12.38 58.88,12.38 58.42,11.91 56.76,11.91 56.06,11.21 55.18,11.21 50.46,6.49 28.97,6.49 23.9,11.56 23.9,25.04 26.8,27.94 26.8,38.47 26.54,38.74 26.54,43.97 34.53,51.96 34.53,53.32 33.94,53.91 33.94,63.4 33.2,64.14 33.2,65.96 32.78,66.38 26.61,66.38 25.12,67.87 25.12,72.36 29.01,76.25 29.01,77.17 31.81,79.96 v2(38.61,79.96)
  L9_SIG3 w0.114: v1(149.74,144.91) 148.65,143.81 148.65,142.31 150.24,140.72 150.24,138.51 148.87,137.13 147.3,137.13 143.38,133.22 143.38,132.26 144.37,131.27 144.37,125.25 145.59,124.03 146.96,124.03 149.48,121.51 149.48,112.83 140.49,103.84 140.49,101.09 132.56,93.17 132.56,90.27 121.59,79.3 121.59,75.88 v5(119.68,73.98)
AM57XX_PRU2ETH0_MRCLK: length 313.1
  TOP w0.173: U1.A13 115.65,82.81 116.95,81.51 121.18,81.51 122.05,82.38 122.73,82.38 122.91,82.2 127.02,82.2 v7(127.69,81.54) ; R165.2 v2(38.61,77.68)
  L3_SIG1 w0.109: v7(127.69,81.54) v5(127.27,81.12)
  L10_SIG4 w0.109: v5(127.27,81.12) 128.52,82.38 128.52,84.09 128.34,84.28 124.91,84.28 124.71,84.08 124.71,80.12 123.11,78.52 123.11,73.16 122.4,72.45 122.4,70.95 123.5,69.85 125.2,69.85 126.85,68.2 128.98,68.2 129.26,68.48 131.47,68.48 131.55,68.56 148.42,68.56 148.95,69.09 152.98,69.09 156.79,65.28 156.79,56.72 153.54,53.47 153.54,41.08 154.28,40.34 154.28,38.23 150.85,34.8 148.95,34.8 148.84,34.91 148.84,35.73 148.74,35.84 148.52,35.84 148.41,35.73 148.41,34.86 148.3,34.75 148.08,34.75 147.97,34.86 147.97,35.73 147.86,35.84 147.64,35.84 147.53,35.73 147.53,34.86 147.42,34.75 147.21,34.75 147.1,34.86 147.1,35.73 146.99,35.84 146.77,35.84 146.66,35.73 146.66,34.86 146.55,34.75 146.33,34.75 146.22,34.86 146.22,35.73 146.11,35.84 145.9,35.84 145.79,35.73 145.79,34.86 145.68,34.75 145.46,34.75 145.35,34.86 145.35,35.73 145.24,35.84 145.02,35.84 144.91,35.73 144.91,34.86 144.8,34.75 144.58,34.75 144.48,34.86 144.48,35.73 144.37,35.84 144.15,35.84 144.04,35.73 144.04,34.86 143.93,34.75 143.71,34.75 143.6,34.86 143.6,35.73 143.49,35.84 143.27,35.84 143.17,35.73 143.17,34.86 143.06,34.75 142.84,34.75 142.73,34.86 142.73,35.73 142.62,35.84 142.4,35.84 142.29,35.73 142.29,34.86 142.18,34.75 141.96,34.75 141.85,34.86 141.85,35.73 141.75,35.84 141.53,35.84 141.42,35.73 141.42,34.86 141.31,34.75 140.08,34.75 130.91,25.58 125.3,25.58 117.15,17.43 111.69,17.43 111.02,16.76 105.63,16.76 104.6,15.73 92.2,15.73 91.69,15.21 71.33,15.21 67.95,18.6 64.92,18.6 62.2,21.32 54.68,21.32 50.39,25.61 47.51,25.61 45.99,27.13 45.7,27.13 42.27,30.56 42.27,32.33 40.72,33.88 40.23,33.88 39.67,34.44 38.94,34.44 38.07,35.31 38.07,42.27 29.08,51.26 29.08,60.32 27.94,61.47 27.94,62.69 26.87,63.75 26.49,63.75 25.43,64.82 25.43,67.16 28.42,70.15 32.74,70.15 33.43,70.84 33.43,72.57 38.54,77.68 v2(38.61,77.68)
AM57XX_PRU2ETH0_RXD0: length 314.4
  TOP w0.173: U1.C15 v4(111.83,80.82)
  L3_SIG1 w0.109: v4(111.83,80.82) 111.96,80.69 116.88,80.69 117.53,80.04 120.62,80.04 121.28,79.38 126.92,79.38 v5(127.13,79.58)
  L10_SIG4 w0.109: v2(38.73,83.52) 39.34,82.91 39.34,80.85 39.04,80.55 37.02,80.55 35.03,78.55 35.03,76.78 31.11,72.86 26.15,72.86 24.97,71.68 24.97,69.09 23.6,67.72 23.6,66.12 24.05,65.66 24.05,64.39 24.05,62.92 24.47,62.5 24.47,51.22 26.82,48.87 26.82,47.48 31.22,43.08 33.15,43.08 36.7,39.53 36.7,32.66 38.8,30.57 39.89,30.57 40.61,29.84 41.12,29.84 42.21,28.75 42.21,25.38 43.69,23.9 47.22,23.9 48,23.11 51.04,23.11 54.44,19.72 58.9,19.72 63.35,15.27 68.63,15.27 70.59,13.31 92.12,13.31 93.19,14.38 105.9,14.38 106.54,13.74 109.66,13.74 110.36,13.04 115.32,13.04 116.46,14.18 119.73,14.18 121.67,16.12 121.67,18.76 125.06,22.15 131.16,22.15 139.85,30.84 142.23,30.84 142.34,30.94 142.34,31.72 142.45,31.83 142.66,31.83 142.77,31.72 142.77,30.92 142.88,30.82 143.1,30.82 143.21,30.92 143.21,31.72 143.32,31.83 143.54,31.83 143.65,31.72 143.65,30.92 143.76,30.82 143.97,30.82 144.08,30.92 144.08,31.72 144.19,31.83 144.41,31.83 144.52,31.72 144.52,30.92 144.63,30.82 144.85,30.82 144.96,30.92 144.96,31.72 145.07,31.83 145.29,31.83 145.39,31.72 145.39,30.92 145.5,30.82 145.72,30.82 145.83,30.92 145.83,31.72 145.94,31.83 146.16,31.83 146.27,31.72 146.27,30.92 146.38,30.82 146.6,30.82 146.71,30.92 146.71,31.72 146.81,31.83 147.03,31.83 147.14,31.72 147.14,30.92 147.25,30.82 147.47,30.82 147.58,30.92 147.58,31.72 147.69,31.83 147.91,31.83 148.02,31.72 148.02,30.92 148.13,30.82 148.34,30.82 148.45,30.92 148.45,31.72 148.56,31.83 148.78,31.83 148.89,31.72 148.89,31.02 149,30.91 149.86,30.91 156.44,37.5 156.44,46.99 156.97,47.52 156.97,50.29 157.89,51.2 157.89,66.27 153.01,71.15 147.29,71.15 146.53,70.39 141.78,70.39 141.33,69.93 133.48,69.93 132.72,70.69 127.41,70.69 126.92,71.18 126.91,71.18 126.8,71.29 126.8,77.35 127.56,78.11 127.56,79.15 v5(127.13,79.58)
  BOTTOM w0.173: R171.2 v2(38.73,83.52)
AM57XX_PRU2ETH0_RXD1: length 314.8
  TOP w0.173: U1.A18 114.73,78.81 117.45,76.1 118.8,76.1 120.14,74.76 121.41,74.76 122.05,75.39 125.81,75.39 v7(126.64,74.55)
  L3_SIG1 w0.109: v7(126.64,74.55) 126.42,74.55 v5(126.06,74.2)
  L10_SIG4 w0.109: v5(126.06,74.2) 126.06,73.77 125.68,73.38 125.68,71.59 125.54,71.45 125.23,71.45 125.09,71.31 125.09,71.11 125.23,70.97 125.54,70.97 125.68,70.83 125.68,70.47 125.94,70.21 126.34,70.21 127.64,68.92 128.57,68.92 129.84,70.19 132.28,70.19 133.3,69.17 146.48,69.17 148.03,70.72 152.93,70.72 157.51,66.15 157.51,53.14 155.32,50.96 155.32,47.24 155.8,46.76 155.8,37.65 150.62,32.47 150.3,32.47 150.19,32.58 150.19,33.24 150.08,33.35 149.86,33.35 149.75,33.24 149.75,32.58 149.64,32.47 149.42,32.47 149.31,32.58 149.31,33.24 149.2,33.35 148.99,33.35 148.88,33.24 148.88,32.58 148.77,32.47 148.55,32.47 148.44,32.58 148.44,33.24 148.33,33.35 148.11,33.35 148,33.24 148,32.58 147.89,32.47 147.67,32.47 147.57,32.58 147.57,33.24 147.46,33.35 147.24,33.35 147.13,33.24 147.13,32.58 147.02,32.47 146.8,32.47 146.69,32.58 146.69,33.24 146.58,33.35 146.36,33.35 146.25,33.24 146.25,32.58 146.15,32.47 145.93,32.47 145.82,32.58 145.82,33.24 145.71,33.35 145.49,33.35 145.38,33.24 145.38,32.58 145.27,32.47 145.05,32.47 144.94,32.58 144.94,33.24 144.83,33.35 144.62,33.35 144.51,33.24 144.51,32.58 144.4,32.47 144.18,32.47 144.07,32.58 144.07,33.24 143.96,33.35 143.74,33.35 143.63,33.24 143.63,32.58 143.52,32.47 143.31,32.47 143.2,32.58 143.2,33.24 143.09,33.35 142.87,33.35 142.76,33.24 142.76,32.58 142.65,32.47 142.43,32.47 142.32,32.58 142.32,33.24 142.21,33.35 142,33.35 141.89,33.24 141.89,32.58 141.78,32.47 141.56,32.47 141.45,32.58 141.45,33.24 141.34,33.35 141.12,33.35 141.01,33.24 141.01,32.58 140.62,32.18 140.13,32.18 130.63,22.68 125.06,22.68 121.3,18.92 121.3,16.28 120.71,15.7 114.18,15.7 113.16,16.72 112.17,16.72 111.23,15.78 106.33,15.78 105.28,14.73 93.04,14.73 91.95,13.65 70.76,13.65 68.61,15.8 64.39,15.8 59.92,20.27 54.55,20.27 51.37,23.45 48.29,23.45 47.49,24.26 44.96,24.26 43.89,25.32 43.89,27.81 41.4,30.3 41.4,30.71 40.72,31.39 39.73,31.39 39.17,31.95 38.63,31.95 37.26,33.32 37.26,40.54 32.49,45.32 29.77,45.32 27.2,47.88 27.2,49.02 24.82,51.41 24.82,62.69 24.39,63.11 24.39,67.98 25.35,68.94 25.35,71.45 26.43,72.53 32.62,72.53 37.64,77.55 37.64,78.49 38.53,79.38 39.07,79.38 40.56,80.88 40.56,82.83 v2(38.73,84.66)
  BOTTOM w0.173: R173.2 v2(38.73,84.66)
AM57XX_PRU2ETH0_RXD2: length 314.6
  TOP w0.173: U1.A19 114.29,78.02 117.35,74.95 118.43,74.95 120.02,73.36 122.82,73.36 123,73.18 125.54,73.18 126.35,74 v7(128.32,74)
  L3_SIG1 w0.109: v7(128.32,74) v5(129.03,74)
  L10_SIG4 w0.109: v2(38.73,85.81) 38.3,85.37 35.23,85.37 34.49,84.63 34.49,79.81 33.43,78.74 33.43,76.3 30.67,73.54 25.67,73.54 23.97,71.84 23.97,69.46 22.46,67.95 22.46,62.99 23.14,62.31 23.14,51.53 26.09,48.59 26.09,45.95 27.81,44.23 27.81,42.55 29.52,40.85 31.39,40.85 33.68,38.56 33.68,37.44 35.77,35.36 35.77,31.04 38.81,27.99 39.57,27.99 40.46,27.1 40.46,26.11 47.02,19.56 53.16,19.56 53.95,18.78 58.47,18.78 62.94,14.31 68.5,14.31 70.57,12.24 73.13,12.24 73.81,11.56 75.64,11.56 76.63,12.55 92.88,12.55 93.37,13.04 105.87,13.04 106.15,12.75 108.36,12.75 109.35,11.77 119.08,11.77 126.65,19.33 131.39,19.33 138.1,26.04 142.85,26.04 145.31,28.5 148.95,28.5 149.41,28.04 149.62,28.04 149.75,28.17 149.75,28.32 149.27,28.8 149.27,28.95 149.42,29.11 149.58,29.11 150.06,28.63 150.21,28.63 150.37,28.78 150.37,28.94 149.89,29.42 149.89,29.57 150.04,29.73 150.2,29.73 150.68,29.25 150.83,29.25 150.99,29.4 150.99,29.56 150.51,30.04 150.51,30.19 150.66,30.35 150.81,30.35 151.3,29.87 151.45,29.87 151.6,30.02 151.6,30.17 151.12,30.65 151.12,30.81 151.28,30.96 151.43,30.96 151.91,30.48 152.07,30.48 152.22,30.64 152.22,30.79 151.74,31.27 151.74,31.43 151.9,31.58 152.05,31.58 152.53,31.1 152.69,31.1 152.84,31.26 152.84,31.41 152.36,31.89 152.36,32.05 152.51,32.2 152.67,32.2 153.15,31.72 153.3,31.72 153.46,31.87 153.46,32.03 152.98,32.51 152.98,32.66 153.13,32.82 153.29,32.82 153.77,32.34 153.92,32.34 154.08,32.49 154.08,32.65 153.6,33.13 153.6,33.28 153.75,33.44 153.91,33.44 154.39,32.96 154.54,32.96 154.7,33.11 154.7,33.27 154.21,33.75 154.21,33.9 154.37,34.05 154.52,34.05 155,33.57 155.16,33.57 155.31,33.73 155.31,33.88 154.83,34.36 154.83,34.52 154.99,34.67 155.14,34.67 155.62,34.19 155.78,34.19 155.93,34.35 155.93,34.5 155.45,34.98 155.45,35.14 157.18,36.86 157.18,45.97 158.15,46.95 158.15,50.13 159.23,51.21 159.23,65.89 152.83,72.29 142.19,72.29 141.48,71.58 140.59,71.58 140.23,71.94 132.66,71.94 131.5,73.11 129.92,73.11 v5(129.03,74)
  BOTTOM w0.173: R174.2 v2(38.73,85.81)
AM57XX_PRU2ETH0_RXD3: length 313.3
  TOP w0.173: U1.F14 v4(109.43,82.41)
  L3_SIG1 w0.109: v5(129.29,79.08) 128.24,79.08 127.59,79.73 127.59,79.86 127.28,80.17 125.03,80.17 124.41,80.78 121.79,80.78 120.45,82.12 119.75,82.12 119.42,82.45 117.3,82.45 116.7,83.05 113.22,83.05 112.27,82.1 109.75,82.1 v4(109.43,82.41)
  L10_SIG4 w0.109: v2(38.73,86.95) 38.17,86.39 35.56,86.39 34.04,84.86 34.04,79.83 33.05,78.84 33.05,76.92 31.61,75.49 31.24,75.49 30.84,75.08 30.84,74.19 30.53,73.89 25.35,73.89 23.63,72.17 23.63,69.6 22.12,68.09 22.12,64.42 22.12,64.15 22.12,64.14 22.12,62.79 22.8,62.11 22.8,51.39 25.73,48.46 25.73,45.6 27.13,44.2 27.13,42.55 30.1,39.57 31.5,39.57 32.69,38.38 32.69,36.52 35.02,34.2 35.02,31.07 47.04,19.05 53.19,19.05 53.87,18.37 57.12,18.37 62.25,13.25 69.03,13.25 70.41,11.86 72.82,11.86 73.58,11.1 86.08,11.1 86.54,11.56 102.13,11.56 103.25,12.68 105.61,12.68 106.1,12.2 108.23,12.2 109.09,11.33 119.26,11.33 124.92,17 124.92,17.01 125.59,17.67 125.6,17.67 126.72,18.79 131.66,18.79 138.35,25.48 143.52,25.48 145.26,27.23 150.08,27.23 150.65,27.8 150.65,27.95 150.44,28.16 150.44,28.32 150.59,28.47 150.75,28.47 150.96,28.26 151.11,28.26 151.27,28.41 151.27,28.57 151.06,28.78 151.06,28.94 151.21,29.09 151.36,29.09 151.58,28.88 151.73,28.88 151.89,29.03 151.89,29.19 151.67,29.4 151.67,29.56 151.83,29.71 151.98,29.71 152.2,29.5 152.35,29.5 152.51,29.65 152.51,29.81 152.29,30.02 152.29,30.17 157.53,35.41 157.53,45.52 161.54,49.53 161.54,59.62 160.02,61.14 160.02,65.89 153.19,72.73 140.82,72.73 140.47,72.37 132.82,72.37 129.32,75.87 129.32,79.05 v5(129.29,79.08)
  BOTTOM w0.173: R175.2 v2(38.73,86.95)
AM57XX_PRU2ETH0_RXDV: length 315.5
  TOP w0.173: R197.2 v2(29.46,69.67) ; R166.2 v2(38.61,78.82) ; U1.G14 v4(108.63,82.41)
  L3_SIG1 w0.109: v5(124.23,80.35) 121.75,80.35 120.68,81.41 119.92,81.41 119.81,81.51 117.22,81.51 117.08,81.37 112.57,81.37 112.24,81.7 109.72,81.7 109,82.41 v4(108.63,82.41)
  L10_SIG4 w0.109: v2(38.61,78.82) 39.04,78.39 39.04,76.74 35.79,73.48 35.79,69.7 35.14,69.05 31.1,69.05 30.48,69.67 v2(29.46,69.67) 28.17,68.37 28.17,63.75 29.26,62.66 29.26,61.68 29.69,61.24 29.69,55.94 31.7,53.93 31.7,51.01 38.46,44.25 38.46,36.93 40.46,34.92 41.33,34.92 42.57,33.68 43.1,33.68 43.59,33.2 43.59,29.88 45.88,27.58 46.08,27.58 47.57,26.09 50.53,26.09 54.82,21.8 64.23,21.8 66.85,19.18 67.87,19.18 71.45,15.6 91.26,15.6 92.46,16.79 104.24,16.79 106.32,18.88 111.22,18.88 111.58,18.52 117.63,18.52 125.27,26.16 130.35,26.16 140.58,36.39 144.84,36.39 145.14,36.69 145.14,39.37 145.25,39.48 145.46,39.48 145.57,39.37 145.57,36.69 145.68,36.58 145.9,36.58 146.01,36.69 146.01,39.37 146.12,39.48 146.34,39.48 146.45,39.37 146.45,36.69 146.56,36.58 146.78,36.58 146.88,36.69 146.88,39.37 146.99,39.48 147.21,39.48 147.32,39.37 147.32,36.69 147.43,36.58 147.65,36.58 147.76,36.69 147.76,39.37 147.87,39.48 148.09,39.48 148.2,39.37 148.2,36.69 148.3,36.58 148.52,36.58 148.63,36.69 148.63,39.37 148.74,39.48 148.96,39.48 149.07,39.37 149.07,36.69 149.18,36.58 149.4,36.58 149.51,36.69 149.51,39.37 149.62,39.48 149.83,39.48 149.94,39.37 149.94,38.01 150.43,37.52 151.67,37.52 153.14,38.99 153.14,53.9 156.44,57.21 156.44,64.37 153.52,67.29 150.9,67.29 150.37,67.82 149.16,67.82 148.78,68.2 131.72,68.2 131.65,68.13 129.44,68.13 129.16,67.85 126.54,67.85 125.63,68.76 124.08,68.76 122.03,70.82 122.03,78.14 v5(124.23,80.35)
AM57XX_PRU2ETH0_RXER: length 314.9
  TOP w0.173: R170.2 v2(38.61,81.11) ; U1.G12 v4(108.63,84.01)
  L3_SIG1 w0.109: v4(108.63,84.01) 108.63,84.02 109.03,84.26 v5(109.03,84.26)
  L10_SIG4 w0.109: v5(109.03,84.26) 110.02,84.26 110.41,84.66 113.5,84.66 114.09,84.08 123.04,84.08 123.61,84.65 129.86,84.65 130.2,84.31 130.2,83.77 129.39,82.96 129.39,80.57 128.6,79.79 128.6,75.67 127.61,74.68 127.61,74.02 129.21,72.42 131.55,72.42 133.65,70.31 137.69,70.31 138.33,70.95 142.01,70.95 142.88,71.81 152.83,71.81 158.88,65.77 158.88,51.64 157.57,50.33 157.57,47.23 156.82,46.48 156.82,37.29 149.58,30.05 147.81,30.05 147.7,29.94 147.7,29.19 147.59,29.08 147.37,29.08 147.26,29.19 147.26,29.94 147.15,30.05 146.93,30.05 146.83,29.94 146.83,29.19 146.72,29.08 146.5,29.08 146.39,29.19 146.39,29.94 146.28,30.05 146.06,30.05 145.95,29.94 145.95,29.19 145.84,29.08 145.62,29.08 145.51,29.19 145.51,29.94 145.41,30.05 145.19,30.05 145.08,29.94 145.08,29.19 144.97,29.08 144.75,29.08 144.64,29.19 144.64,29.94 144.51,30.07 140.97,30.07 131.19,20.3 126.28,20.3 124.4,18.42 124.4,18.42 124.13,18.15 124.13,18.14 122.01,16.03 122.01,15.98 118.18,12.15 109.6,12.15 108.53,13.21 106.32,13.21 105.54,14 93.5,14 92.47,12.97 70.37,12.97 68.61,14.74 63.17,14.74 58.65,19.26 54.34,19.26 50.86,22.73 47.67,22.73 46.86,23.55 43.57,23.55 41.83,25.28 41.83,27.51 40.08,29.26 39.12,29.26 38.29,30.09 38.29,30.49 36.17,32.62 36.17,35.63 34.87,36.92 34.87,40.43 33.95,41.35 32.22,41.35 26.47,47.1 26.47,48.75 24.33,50.89 24.13,51.08 24.13,62.15 22.79,63.49 22.79,67.52 24.43,69.16 24.43,71.75 25.88,73.2 30.81,73.2 33.76,76.16 33.76,77.81 34.82,78.87 34.86,78.87 35.18,79.19 35.18,79.98 36.3,81.11 v2(38.61,81.11)
AM57XX_PRU2ETH0_RXLINK: length 7.7
  TOP w0.173: U1.A16 115.6,80.42 117.94,78.07 119.75,78.07 R188.2
AM57XX_PRU2ETH0_TXCLK: length 15.6
  TOP w0.173: U1.F12 v4(109.43,84.01) ; v7(122.83,82.91) 123.42,82.91 R162.2
  L3_SIG1 w0.099: 111.96,83.72 111.71,83.72 111.59,83.84 111.28,83.84 111.16,83.72 110.91,83.72 110.79,83.84 110.48,83.84 110.36,83.72 110.11,83.72 109.82,84.01 v4(109.43,84.01)
  L3_SIG1 w0.109: v7(122.83,82.91) 122.31,83.44 120.27,83.44 119.9,83.81 117.21,83.81 117.13,83.89 112.81,83.89 112.64,83.72 111.96,83.72
AM57XX_PRU2ETH0_TXD0: length 15.3
  TOP w0.173: v7(122.39,81.91) 122.68,81.62 R163.2 ; U1.E14 v4(110.23,82.41)
  L3_SIG1 w0.109: v7(122.39,81.91) 121.92,82.38 121.61,82.38 120.9,83.08 120.15,83.08 119.76,83.47 117.22,83.47 117.01,83.68 112.89,83.68 112.13,82.92 111.62,82.92 111.41,82.71 110.53,82.71 v4(110.23,82.41)
AM57XX_PRU2ETH0_TXD1: length 10.8
  TOP w0.173: U1.A12 117.13,83.62 117.13,83.62 117.98,83.62 118.15,83.45 123.12,83.45 R164.2
AM57XX_PRU2ETH0_TXD2: length 8.1
  TOP w0.173: U1.B13 112.64,83.22 115.95,83.22 116.91,82.25 R168.2
AM57XX_PRU2ETH0_TXD3: length 10.8
  TOP w0.173: R169.2 115.91,85.17 115.15,84.42 U1.A11
AM57XX_PRU2ETH0_TXEN: length 280.9
  TOP w0.173: U1.B12 112.63,84.01 115.32,84.01 115.84,84.54 R167.2 120.32,83.98 122.51,83.98 123.06,84.54 v7(125.22,84.54) ; R196.2 v2(26.92,69.67)
  L3_SIG1 w0.109: v5(129.72,84.1) 129.69,84.08 126.47,84.08 126.01,84.54 v7(125.22,84.54)
  L10_SIG4 w0.109: v5(129.72,84.1) 129.72,84.05 128.99,83.33 128.99,80.69 128.52,80.21 127.12,80.21 126.62,79.71 126.62,78.9 125.09,77.38 125.09,72.99 124.66,72.56 124.66,70.97 127.08,68.56 128.73,68.56 129.9,69.73 131.27,69.73 132.13,68.87 147.2,68.87 148.64,70.31 152.86,70.31 157.15,66.02 157.15,56.51 155.24,54.6 155.24,52.43 154,51.19 154,41.28 154.71,40.57 154.71,37.67 151.16,34.12 140.87,34.12 130.08,23.32 125.23,23.32 118.98,17.07 111.86,17.07 110.99,16.21 106.15,16.21 105.21,15.27 92.71,15.27 92.27,14.83 70.08,14.83 67.28,17.63 65.23,17.63 62.08,20.78 54.61,20.78 51.61,23.79 51.6,23.79 50.72,24.66 45.2,24.66 44.5,25.36 44.5,27.85 41.83,30.51 41.83,31.62 40.94,32.51 40.28,32.51 39.69,33.11 39.1,33.11 37.64,34.57 37.64,41.08 33.72,45 33.72,45.71 29.54,49.89 29.16,49.89 28.02,51.03 28.02,53.85 27.48,54.38 27.48,55.07 28.24,55.83 28.24,58.42 27.64,59.03 27.64,60.93 25.01,63.56 25.01,67.75 v2(26.92,69.67)
AM57XX_PRU2ETH1_COL: length 147.2
  TOP w0.173: U1.D18 v4(111.03,78.42) ; v2(122.58,74.76) R220.2 ; R950.1 v1(116.35,142.77)
  L3_SIG1 w0.109: v4(111.03,78.42) 111.38,78.42 111.91,77.88 113.84,77.88 114.17,77.55 116.08,77.55 116.22,77.69 119.44,77.69 122.18,74.96 122.38,74.96 v2(122.58,74.76)
  L9_SIG3 w0.114: v1(116.35,142.77) 116.35,139.63 117.86,138.13 123.72,138.13 126.7,141.1 139.36,141.1 142.15,143.88 146.62,143.88 149.1,141.4 149.1,139.42 143,133.32 143,132 143.99,131 143.99,125.09 145.35,123.74 146.84,123.74 148.26,122.32 148.26,115.72 148.56,115.42 148.56,112.37 140.18,103.99 140.18,101.55 132.18,93.55 132.18,91.19 129.29,88.29 127.15,88.29 118.54,79.68 118.54,73.89 119.08,73.36 120.6,73.36 122,74.76 v2(122.58,74.76)
AM57XX_PRU2ETH1_CRS: length 432.5
  TOP w0.173: R219.2 v2(38.53,55.2) ; R951.1 v1(118.35,142.77) ; U1.E17 v4(110.23,79.22)
  L3_SIG1 w0.099: 112.04,78.71 110.74,78.71 v4(110.23,79.22)
  L3_SIG1 w0.109: 112.04,78.71 113.75,78.71 114.37,78.08 115.87,78.08 116.05,78.26 119.73,78.26 121.97,76.03 123.96,76.03 124.18,75.82 v5(124.26,75.82)
  L4_SIG2 w0.114: v5(124.26,75.82) 124.51,76.06 130.97,76.06 131.88,76.97 144.76,76.97 146.27,75.46 149.29,75.46 164.95,59.81 164.95,57.2 163.74,55.99 163.74,49.06 163.06,48.37 163.06,39.52 163.74,38.84 163.74,36.29 156.58,29.13 150.95,29.13 145.9,24.08 139.95,24.08 129.01,13.14 117.66,13.14 116.42,11.89 106.41,11.89 105.1,13.2 102.17,13.2 101.96,12.99 100.61,12.99 99.75,13.84 70.61,13.84 69.93,14.53 60.4,14.53 60.06,14.19 57.43,14.19 57.17,14.45 56.44,14.45 49.35,7.37 30.83,7.37 26.16,12.04 26.16,22.86 32.13,28.83 32.13,30.4 31.45,31.08 31.45,42.7 32.09,43.34 32.09,48.26 37.92,54.1 37.92,54.59 v2(38.53,55.2)
  BOTTOM w0.173: v1(118.35,142.77) 118.35,141.66 112.67,135.99 111.3,135.99 108.25,132.94 108.25,123.49 109.25,122.5 109.25,121.36 108.74,120.86 103.18,120.86 100.86,118.54 100.86,118.16 96.37,113.67 96.37,112.23 80.23,96.09 67.76,96.09 67.41,96.44 66.65,96.44 63.22,93.01 63.22,87.15 49.5,73.43 45.31,73.43 43.33,71.45 43.33,70.76 45.62,68.48 45.62,62.31 42.42,59.11 42.42,57.89 39.73,55.2 v2(38.53,55.2)
AM57XX_PRU2ETH1_MRCLK: length 120.5
  TOP w0.173: U1.AC9 v4(95.04,86.41) ; v2(41.31,53.95) 40.93,53.95 39.9,52.91 R209.2
  L3_SIG1 w0.109: v5(94.64,86.66) 95.03,86.42 v4(95.04,86.41)
  L10_SIG4 w0.109: v2(41.31,53.95) 42.36,53.95 43.08,54.66 45.11,54.66 46.15,53.62 46.84,53.62 47.1,53.88 47.1,57.19 47.26,57.35 47.48,57.35 47.64,57.19 47.64,53.78 47.8,53.62 48.03,53.62 48.19,53.78 48.19,57.19 48.35,57.35 48.57,57.35 48.73,57.19 48.73,53.78 48.89,53.62 49.12,53.62 49.28,53.78 49.28,57.19 49.44,57.35 49.67,57.35 49.83,57.19 49.83,53.78 49.99,53.62 50.21,53.62 50.37,53.78 50.37,57.19 50.53,57.35 50.76,57.35 50.92,57.19 50.92,53.78 51.08,53.62 51.31,53.62 51.47,53.78 51.47,57.19 51.63,57.35 51.85,57.35 52.01,57.19 52.01,54.97 53.21,53.77 54.41,53.77 54.57,53.93 54.57,55.11 54.73,55.27 54.96,55.27 55.12,55.11 55.12,53.93 55.33,53.72 57.48,53.72 60.78,57.02 60.78,58.14 63.78,61.14 64.82,61.14 77.72,74.04 77.72,78.23 77.55,78.41 77.55,85.62 80.19,88.27 83.57,88.27 84.22,88.92 85.18,88.92 85.43,89.16 93.55,89.16 94.26,88.45 94.26,87.04 v5(94.64,86.66)
AM57XX_PRU2ETH1_RXD0: length 121.2
  TOP w0.173: U1.AB5 v4(95.84,89.61)
  L3_SIG1 w0.102: 95.33,91.62 95.33,90.5 95.84,90 v4(95.84,89.61)
  L3_SIG1 w0.109: 95.33,91.62 93.73,93.22 93.73,93.86 93.22,94.37 93.22,95.78 v5(92.79,96.21)
  L10_SIG4 w0.109: v5(92.79,96.21) 92.3,95.72 92.3,92.34 90.54,90.58 85.43,90.58 84.46,89.61 83.92,89.61 83.25,88.94 78.57,88.94 76.15,86.52 76.15,75.79 75.69,75.33 75.69,73.15 64.77,62.23 61.09,62.23 60.63,62.69 60.63,63.83 58.55,65.91 54.53,65.91 54.05,65.43 52.02,65.43 51.87,65.58 51.87,67.08 51.74,67.21 51.46,67.21 51.33,67.08 51.33,65.51 51.17,65.35 50.95,65.35 50.79,65.51 50.79,67.16 50.66,67.28 50.44,67.28 50.31,67.16 50.31,65.51 50.15,65.35 49.93,65.35 49.77,65.51 49.77,66.72 49.35,67.13 48.54,67.13 48.13,66.72 48.13,65.67 47.97,65.51 47.74,65.51 47.58,65.67 47.58,67.94 47.42,68.1 47.2,68.1 47.04,67.94 47.04,65.59 46.88,65.43 46.65,65.43 46.49,65.59 46.49,67.94 46.33,68.1 45.97,68.1 45.72,67.84 45.72,65.3 43.79,63.37 43.79,61.09 42.28,59.58 42.28,58.68 42.14,58.54 41.77,58.54 41.63,58.4 41.63,58.2 41.77,58.06 42.14,58.06 42.28,57.92 42.28,57.72 42.14,57.58 41.77,57.58 41.63,57.44 41.63,57.24 41.77,57.1 42.14,57.1 42.28,56.96 42.28,56.2 41.48,55.4 40.87,55.4 39.42,56.85 39.42,57.26 39.53,57.37 39.87,57.37 v2(40,57.23)
  BOTTOM w0.173: v2(40,57.23) 38.48,58.76 R213.2
AM57XX_PRU2ETH1_RXD1: length 120.8
  TOP w0.173: U1.AB8 v4(95.84,87.21)
  L3_SIG1 w0.109: v5(95.44,87.46) 95.83,87.22 v4(95.84,87.21)
  L10_SIG4 w0.109: v2(38.73,59.9) 38.25,59.42 38.25,57.46 40.65,55.06 41.62,55.06 42.72,56.16 42.72,57.33 45.75,60.35 45.75,63.86 46.02,64.14 46.65,64.14 47.04,63.75 47.04,61.48 47.2,61.32 47.42,61.32 47.58,61.48 47.58,64.51 47.74,64.67 47.97,64.67 48.13,64.51 48.13,61.48 48.29,61.32 48.52,61.32 48.68,61.48 48.68,64.51 48.84,64.67 49.06,64.67 49.22,64.51 49.22,61.48 49.38,61.32 49.61,61.32 49.77,61.48 49.77,64.51 49.93,64.67 50.16,64.67 50.32,64.51 50.32,61.4 50.48,61.24 50.7,61.24 50.86,61.4 50.86,64.51 51.02,64.67 51.25,64.67 51.41,64.51 51.41,61.78 51.57,61.62 51.79,61.62 51.95,61.78 51.95,64.2 52.62,64.87 55.24,64.87 55.7,64.41 56.01,64.41 56.95,63.47 58.62,63.47 60.32,61.77 64.98,61.77 76.78,73.58 76.78,74.19 76.5,74.47 76.5,85.2 79.91,88.6 83.43,88.6 84.08,89.25 84.99,89.25 85.24,89.51 91.54,89.51 91.64,89.41 93.65,89.41 94.51,88.55 94.51,88.09 94.69,87.91 94.99,87.91 v5(95.44,87.46)
  BOTTOM w0.173: R215.2 v2(38.73,59.9)
AM57XX_PRU2ETH1_RXD2: length 120.1
  TOP w0.173: U1.AD6 v4(94.24,88.81)
  L3_SIG1 w0.109: v5(84.77,91.13) 89.4,91.13 89.93,90.6 90.84,90.6 92.63,88.81 v4(94.24,88.81)
  L10_SIG4 w0.109: v2(41.15,61.04) 41.5,61.4 41.5,63.14 44.32,65.96 44.32,68.55 44.86,69.09 44.86,71.83 47.98,74.96 51.18,74.96 51.34,75.12 51.34,76.4 51.5,76.56 51.72,76.56 51.88,76.4 51.88,75.12 52.04,74.96 52.33,74.96 52.49,75.12 52.49,76.4 52.65,76.56 52.93,76.56 53.16,76.33 53.16,74.63 57.76,70.03 58.85,70.03 60.19,68.69 62.1,68.69 62.76,68.02 62.76,66.73 62.92,66.57 63.15,66.57 63.31,66.73 63.31,68.53 63.47,68.69 63.7,68.69 63.86,68.53 63.86,66.73 64.02,66.57 64.24,66.57 64.4,66.73 64.4,68.53 64.56,68.69 64.79,68.69 64.95,68.53 64.95,66.73 65.11,66.57 65.34,66.57 65.5,66.73 65.5,68.53 65.66,68.69 65.88,68.69 66.04,68.53 66.04,66.73 66.2,66.57 66.43,66.57 66.59,66.73 66.59,68.53 66.75,68.69 66.97,68.69 67.13,68.53 67.13,66.73 67.29,66.57 67.52,66.57 73.86,72.92 73.86,73.99 74.3,74.42 74.3,76.07 74.55,76.32 74.55,83.24 74.88,83.57 74.88,89.2 77.85,92.18 79.89,92.18 80.05,92.02 80.05,90.97 80.21,90.8 80.44,90.8 80.6,90.97 80.6,92.02 80.76,92.18 80.99,92.18 81.15,92.02 81.15,90.97 81.31,90.8 81.53,90.8 81.69,90.97 81.69,92.02 81.85,92.18 82.08,92.18 82.24,92.02 82.24,90.97 82.4,90.8 82.62,90.8 82.78,90.97 82.78,91.79 82.94,91.95 83.84,91.95 84.66,91.13 v5(84.77,91.13)
  BOTTOM w0.173: R216.2 v2(41.15,61.04)
AM57XX_PRU2ETH1_RXD3: length 119.6
  TOP w0.173: U1.AC8 v4(95.04,87.21)
  L3_SIG1 w0.109: v4(95.04,87.21) 94.74,87.51 93.08,87.51 93.07,87.51 92.71,87.51 90.53,89.69 89.68,89.69 88.92,90.45 85.25,90.45 85.07,90.27 84.31,90.27 v5(84.12,90.47)
  L10_SIG4 w0.109: v5(84.12,90.47) 83.97,90.32 78.89,90.32 75.44,86.87 75.44,77.59 74.89,77.04 74.89,73.32 67.78,66.21 64.11,66.21 63.97,66.07 63.97,64.23 63.83,64.09 63.63,64.09 63.49,64.23 63.49,66.05 63.35,66.19 63.15,66.19 63.01,66.05 63.01,64.23 62.87,64.09 62.67,64.09 62.53,64.23 62.53,65.66 62.23,65.96 62.23,67.84 61.98,68.1 61.11,68.1 59.52,66.51 59.3,66.51 59.14,66.67 59.14,66.9 60.15,67.91 60.15,68.14 59.99,68.3 59.77,68.3 59,67.53 58.78,67.53 58.68,67.63 58.68,68.32 57.61,69.39 56.84,69.39 54.32,71.91 52.63,71.91 52.47,72.07 52.47,74.19 52.31,74.35 52.09,74.35 51.93,74.19 51.93,72.07 51.77,71.91 51.54,71.91 51.38,72.07 51.38,74.19 51.22,74.35 51,74.35 50.84,74.19 50.84,72.07 50.68,71.91 50.45,71.91 50.29,72.07 50.29,74.19 50.13,74.35 49.9,74.35 49.74,74.19 49.74,72.07 49.58,71.91 49.36,71.91 49.2,72.07 49.2,74.19 49.04,74.35 48.81,74.35 48.65,74.19 48.65,72.6 47.8,71.75 46.58,71.75 46,71.17 46,69.62 44.86,68.48 44.86,65.81 42.02,62.97 42.02,60.75 41.57,60.3 40.62,60.3 v2(38.73,62.18)
  BOTTOM w0.173: R217.2 v2(38.73,62.18)
AM57XX_PRU2ETH1_RXDV: length 121.9
  TOP w0.173: R211.2 39.5,54.06 v2(41.27,55.83) ; U1.AC3 v4(95.04,91.21)
  L3_SIG1 w0.109: v4(95.04,91.21) 95.04,91.53 93.47,93.1 93.47,93.71 92.41,94.77 92.41,96.6 v5(92.48,96.68)
  L10_SIG4 w0.109: v2(41.27,55.83) 41.27,57.69 41.17,57.8 40.69,57.8 40.58,57.91 40.58,58.12 40.69,58.23 41.17,58.23 41.27,58.34 41.27,59.33 42.56,60.62 42.56,62.83 45.31,65.58 45.31,68.15 47.57,70.41 48.03,70.41 48.17,70.27 48.17,69.25 48.33,69.09 48.55,69.09 48.71,69.25 48.71,70.68 48.87,70.84 49.09,70.84 49.25,70.68 49.25,69.25 49.41,69.09 49.64,69.09 49.8,69.25 49.8,70.68 49.96,70.84 50.18,70.84 50.34,70.68 50.34,69.25 50.5,69.09 50.73,69.09 50.89,69.25 50.89,70.68 51.05,70.84 51.28,70.84 51.44,70.68 51.44,69.25 51.6,69.09 51.82,69.09 51.98,69.25 51.98,70.68 52.14,70.84 52.37,70.84 52.53,70.68 52.53,69.25 52.69,69.09 52.92,69.09 53.08,69.25 53.08,70.68 53.24,70.84 53.38,70.84 53.54,70.68 53.54,69.01 53.97,68.58 57.2,68.58 58.19,67.59 58.19,66.88 59.56,65.51 59.92,65.51 60.85,66.44 61.07,66.44 61.23,66.28 61.23,66.05 60.24,65.06 60.24,64.83 60.4,64.67 60.63,64.67 61.36,65.41 61.77,65.41 62,65.17 62,64.08 62.71,63.37 65.43,63.37 75.26,73.2 75.26,75.38 75.79,75.91 75.79,86.67 79.07,89.95 84.32,89.95 85.31,90.94 90.19,90.94 92.02,92.77 92.02,96.22 v5(92.48,96.68)
AM57XX_PRU2ETH1_RXER: length 122.3
  TOP w0.173: U1.B19 112.23,78.01 112.63,77.62 114.15,77.62 117.39,74.37 118.13,74.37 119.72,72.78 v7(120.27,72.78) ; R212.2 v2(38.64,56.34)
  L3_SIG1 w0.109: v5(121.06,72.78) v7(120.27,72.78)
  L9_SIG3 w0.114: v5(62.99,58.42) 62.99,59.06 65.93,62 66.17,62 67.03,61.14 67.27,61.14 67.43,61.31 67.43,61.55 66.58,62.41 66.58,62.64 66.74,62.81 66.98,62.81 67.84,61.95 68.07,61.95 68.24,62.12 68.24,62.36 67.38,63.21 67.38,63.45 67.55,63.62 67.79,63.62 68.65,62.76 68.88,62.76 69.05,62.93 69.05,63.16 68.19,64.02 68.19,64.26 68.36,64.43 68.6,64.43 69.45,63.57 69.69,63.57 69.86,63.74 69.86,63.97 69,64.83 69,65.07 75.46,71.53 77.77,71.53 80.01,73.77 98.48,73.77 99.95,75.25 105.19,75.25 105.42,75.47 105.42,76.7 105.67,76.95 110.22,76.95 111.76,75.41 115.82,75.41 118.46,72.78 v5(121.06,72.78)
  L10_SIG4 w0.109: v5(62.99,58.42) 61.85,57.28 61.85,53.77 60.93,52.86 59.13,52.86 58.53,52.26 41.97,52.26 39.87,54.35 39.87,55.11 v2(38.64,56.34)
AM57XX_PRU2ETH1_TXCLK: length 22.6
  TOP w0.173: U1.AC5 v4(95.04,89.61) ; 78.87,95.97 v7(79.63,95.97)
  L3_SIG1 w0.102: 94.44,91.47 94.54,91.38 94.54,90.96 94.74,90.76 94.74,89.91 v4(95.04,89.61)
  L3_SIG1 w0.109: v7(79.63,95.97) 80.98,95.97 81.59,96.58 82.52,96.58 82.96,96.14 85.72,96.14 86.23,96.65 87.5,96.65 87.83,96.98 91.08,96.98 91.64,96.42 91.64,94.64 92.86,93.42 92.86,93.05 94.44,91.47
AM57XX_PRU2ETH1_TXD0: length 22.9
  TOP w0.173: U1.AC6 v4(95.04,88.81) ; 78.87,94.95 v7(79.63,94.95)
  L3_SIG1 w0.099: 93.94,91.56 93.94,91 94.24,90.71
  L3_SIG1 w0.102: v4(95.04,88.81) 95.04,89.2 94.53,89.71 94.53,90.54 94.36,90.71 94.24,90.71
  L3_SIG1 w0.109: 93.94,91.56 92.46,93.05 92.46,93.26 91.39,94.33 91.39,95.94 90.73,96.6 87.96,96.6 86.97,95.61 86.08,95.61 85.9,95.79 83.29,95.79 83.11,95.61 80.29,95.61 v7(79.63,94.95)
AM57XX_PRU2ETH1_TXD1: length 19.6
  TOP w0.173: U1.AC7 v4(95.04,88.01) ; v7(79.58,93.02) 79.49,93.02 79.39,92.92 78.87,92.92
  L3_SIG1 w0.099: v4(95.04,88.01) 94.74,88.31 94.74,89.05 94.47,89.32 93.84,89.32 93.68,89.48 93.46,89.71 93.46,89.71 93.44,89.72
  L3_SIG1 w0.109: 93.44,89.72 92.61,90.55 91.97,90.55 91.34,91.18 90.18,91.18 89.51,91.84 87.15,91.84 86.29,92.71 85.12,92.71 84.71,92.3 82.85,92.3 82.26,92.9 80.35,92.9 80.23,93.02 v7(79.58,93.02)
AM57XX_PRU2ETH1_TXD2: length 22.5
  TOP w0.173: 78.87,96.98 v7(79.63,96.98) ; U1.AC4 v4(95.04,90.41)
  L3_SIG1 w0.102: v4(95.04,90.41) 95.04,90.8 94.74,91.09 94.74,91.49
  L3_SIG1 w0.109: 94.74,91.49 93.22,93.02 93.22,93.53 91.95,94.8 91.95,96.83 91.34,97.44 86.44,97.44 85.65,96.65 83.26,96.65 82.4,97.52 81.39,97.52 80.85,96.98 v7(79.63,96.98)
AM57XX_PRU2ETH1_TXD3: length 18.3
  TOP w0.173: 78.87,93.93 v7(79.63,93.93) ; U1.AD4 v4(94.24,90.41)
  L3_SIG1 w0.099: 93.73,91.39 93.73,90.92 94.23,90.41
  L3_SIG1 w0.109: 93.73,91.39 92.48,92.64 90.8,92.64 90.64,92.8 88.16,92.8 86.24,94.72 80.49,94.72 79.71,93.93 v7(79.63,93.93) ; v4(94.24,90.41) 94.23,90.41
AM57XX_PRU2ETH1_TXEN: length 23.7
  TOP w0.173: U1.AB4 v4(95.84,90.41) ; 78.87,98 v7(79.63,98)
  L3_SIG1 w0.102: 95.58,91.37 95.54,91.34 95.54,90.71 v4(95.84,90.41)
  L3_SIG1 w0.109: v7(79.63,98) 79.93,98.3 81.41,98.3 81.81,97.9 91.74,97.9 92.53,97.11 92.91,97.11 93.44,96.59 94.3,96.59 95.58,95.31 95.58,91.37
AM57XX_PRU2ETH_MDCLK: length 372.5
  TOP w0.173: U1.C14 v4(111.83,82.41) ; R221.2 30.61,51.99 v2(31.15,51.45) ; R179.2 v2(30.61,76.15)
  L3_SIG1 w0.109: v5(14.06,34.21) 10.29,37.98 10.29,42.67 15.62,48.01 16.89,48.01 22.03,53.14 22.03,68.81 28.85,75.64 30.09,75.64 v2(30.61,76.15) ; v4(111.83,82.41) 112.23,82.41 113.07,83.26 116.8,83.26 117.25,82.81 119.54,82.81 119.89,82.46 120.62,82.46 121.96,81.12 124.55,81.12 125.17,80.51 127.55,80.51 127.84,80.21 131.03,80.21 131.17,80.35 v5(135.64,80.35)
  L4_SIG2 w0.114: v5(14.06,34.21) 14.58,34.72 15.67,34.72 16.97,33.43 16.97,28.79 21.16,24.6 21.16,10.57 26.03,5.69 27.1,5.69 27.58,5.21 27.58,4.8 28.74,3.64 41.74,3.64 42.67,4.57 50.29,4.57 56.05,10.33 56.42,10.33 56.64,10.55 58.51,10.55 58.95,10.1 68.18,10.1 69.12,9.17 92.39,9.17 92.77,8.78 97.42,8.78 98.62,7.57 103.81,7.57 104.44,6.94 111.94,6.94 112.07,7.07 112.98,7.07 113.3,6.75 118.68,6.75 118.98,6.45 127.97,6.45 128.64,7.12 140.77,7.12 152.27,18.62 152.81,18.62 170.02,35.83 170.02,40.48 171.04,41.5 171.04,59.72 162.22,68.54 161.19,68.54 153.42,76.31 153.42,76.79 149.87,80.35 v5(135.64,80.35)
  L9_SIG3 w0.114: v2(30.61,76.15) 30.84,75.93 30.84,64.29 30.15,63.6 30.15,62.46 30.76,61.85 30.76,60.4 30.99,60.17 30.99,52.56 31.15,52.4 v2(31.15,51.45)
AM57XX_PRU2ETH_MDDATA: length 310.1
  TOP w0.173: R181.2 v2(29.59,76.15) ; v2(30.43,51.46) 30.22,51.46 29.59,52.09 R223.2 ; U1.D14 v4(111.03,82.41)
  L3_SIG1 w0.109: v5(135,81.18) 128.85,81.18 128.04,82 127.23,82 126.22,80.98 125.1,80.98 124.67,81.41 122.1,81.41 120.76,82.75 120.01,82.75 119.64,83.11 117.25,83.11 116.89,83.47 112.98,83.47 112.22,82.71 111.71,82.71 111.42,82.41 v4(111.03,82.41)
  L4_SIG2 w0.114: v5(135,81.18) 150.96,81.18 153.09,79.06 153.09,78.83 154.05,77.86 154.75,77.86 157.78,74.84 157.78,73.44 171.7,59.51 171.7,54.74 172.59,53.85 172.59,41.15 170.47,39.02 170.47,34.62 152.82,16.97 151.26,16.97 139.99,5.71 119.21,5.71 118.47,6.46 113.18,6.46 112.86,6.78 112.19,6.78 111.81,6.39 104.57,6.39 103.78,7.19 98.59,7.19 97.29,8.49 92.65,8.49 92.27,8.88 69,8.88 68.97,8.9 68.35,9.52 v5(56.48,9.52)
  L9_SIG3 w0.114: v5(56.48,9.52) 56.34,9.52 45.34,20.52 43.51,20.52 37.43,26.61 37.43,44.47 v2(30.43,51.46) 30.43,55.97 27.71,58.7 27.71,62.69 28.32,63.3 28.32,72.14 29.59,73.41 v2(29.59,76.15)
AM57XX_RGMII0_RD0: length 101.7
  TOP w0.173: v7(36.07,111.71) 35.61,111.26 R289.2 ; v7(92.08,104.98) 93.17,106.08 94.89,106.08 96.8,104.17 96.8,101.8 96.27,101.27 96.27,96.54 98.24,94.58 98.24,92.01 U1.W2
  L3_SIG1 w0.109: v7(36.07,111.71) 36.07,110.15 39.94,106.28 41.58,106.28 42.44,105.41 42.44,104.78 45.5,101.72 50.35,101.72 51.43,100.64 61.43,100.64 61.54,100.75 61.54,101.72 61.65,101.83 61.87,101.83 61.98,101.72 61.98,100.75 62.09,100.64 62.31,100.64 62.42,100.75 62.42,101.72 62.53,101.83 62.75,101.83 62.85,101.72 62.85,100.75 62.96,100.64 63.18,100.64 63.29,100.75 63.29,101.72 63.4,101.83 63.62,101.83 63.73,101.72 63.73,100.75 63.84,100.64 64.06,100.64 64.17,100.75 64.17,101.72 64.27,101.83 64.49,101.83 64.6,101.72 64.6,100.75 64.71,100.64 64.93,100.64 65.04,100.75 65.04,101.72 65.15,101.83 65.37,101.83 65.48,101.72 65.48,100.75 65.59,100.64 65.8,100.64 65.91,100.75 65.91,101.72 66.02,101.83 66.24,101.83 66.35,101.72 66.35,100.75 66.46,100.64 68.08,100.64 68.19,100.75 68.19,101.24 68.3,101.35 68.52,101.35 68.63,101.24 68.63,100.75 68.73,100.64 71.42,100.64 72.95,102.16 72.95,103.2 76.13,106.38 80.42,106.38 82.76,104.04 90.26,104.04 90.55,104.32 90.55,105.24 90.85,105.54 91.52,105.54 v7(92.08,104.98)
AM57XX_RGMII0_RD1: length 101.6
  TOP w0.173: v7(91.82,104.32) 92.35,104.32 93.04,103.63 93.04,103.25 93.17,103.12 93.17,101.07 94.86,99.38 94.86,96.5 97.43,93.93 97.43,92.02 U1.Y2 ; R84.2 34.21,111.26 v7(34.67,111.71)
  L3_SIG1 w0.109: v7(34.67,111.71) 34.67,110.8 39.65,105.82 41.4,105.82 41.88,105.34 41.88,104.69 45.31,101.27 50.02,101.27 51.71,99.57 52.46,99.57 52.56,99.68 52.56,100.07 52.67,100.18 52.89,100.18 53,100.07 53,99.68 53.11,99.57 53.33,99.57 53.44,99.68 53.44,100.07 53.55,100.18 53.77,100.18 53.87,100.07 53.87,99.68 53.98,99.57 54.2,99.57 54.31,99.68 54.31,100.07 54.42,100.18 54.64,100.18 54.75,100.07 54.75,99.68 54.86,99.57 55.08,99.57 55.19,99.68 55.19,100.07 55.29,100.18 55.51,100.18 55.62,100.07 55.62,99.68 55.73,99.57 55.95,99.57 56.06,99.68 56.06,100.07 56.17,100.18 56.39,100.18 56.5,100.07 56.5,99.68 56.61,99.57 56.82,99.57 56.93,99.68 56.93,100.07 57.04,100.18 57.26,100.18 57.37,100.07 57.37,99.68 57.48,99.57 57.7,99.57 57.81,99.68 57.81,100.07 57.92,100.18 58.13,100.18 58.24,100.07 58.24,99.68 58.35,99.57 58.57,99.57 58.68,99.68 58.68,100.07 58.79,100.18 59.01,100.18 59.12,100.07 59.12,99.68 59.23,99.57 59.45,99.57 59.55,99.68 59.55,100.07 59.66,100.18 59.88,100.18 59.99,100.07 59.99,99.68 60.1,99.57 60.32,99.57 60.43,99.68 60.43,100.07 60.54,100.18 60.76,100.18 60.87,100.07 60.87,99.68 60.97,99.57 61.19,99.57 61.3,99.68 61.3,100.07 61.41,100.18 61.63,100.18 61.74,100.07 61.74,99.68 61.85,99.57 62.74,99.57 63.5,98.81 64.92,98.81 65.03,98.92 65.03,99.72 65.14,99.83 65.36,99.83 65.47,99.72 65.47,98.92 65.58,98.81 65.8,98.81 65.91,98.92 65.91,99.72 66.02,99.83 66.23,99.83 66.34,99.72 66.34,98.92 66.45,98.81 66.67,98.81 66.78,98.92 66.78,99.72 66.89,99.83 67.11,99.83 67.22,99.72 67.22,98.92 67.33,98.81 68.54,98.81 68.65,98.92 68.65,99.49 68.76,99.6 68.98,99.6 69.09,99.49 69.09,98.92 69.2,98.81 70.41,98.81 75.79,104.2 75.79,105.21 76.36,105.77 79.98,105.77 82.17,103.59 91.06,103.59 91.79,104.32 v7(91.82,104.32)
AM57XX_RGMII0_RD2: length 101.9
  TOP w0.173: v7(33.4,112.86) 33.4,111.84 32.82,111.26 R291.2 ; U1.V3 v4(99.04,91.21)
  L3_SIG1 w0.109: v7(33.4,112.86) 33.83,113.29 37.94,113.29 39.93,111.3 40.41,111.3 41,110.71 41,109.85 41.27,109.58 41.42,109.58 41.7,109.86 41.86,109.86 42.01,109.71 42.01,109.55 41.73,109.27 41.73,109.12 41.89,108.97 42.04,108.97 42.32,109.24 42.47,109.24 42.63,109.09 42.63,108.94 42.35,108.66 42.35,108.5 42.5,108.35 42.66,108.35 42.94,108.63 43.09,108.63 43.25,108.47 43.25,108.32 42.97,108.04 42.97,107.88 43.12,107.73 43.28,107.73 43.56,108.01 43.71,108.01 43.87,107.85 43.87,107.7 43.59,107.42 43.59,107.27 43.74,107.11 43.89,107.11 44.17,107.39 44.33,107.39 44.48,107.24 44.48,107.08 44.2,106.8 44.2,106.65 44.36,106.49 44.51,106.49 44.79,106.77 44.95,106.77 45.1,106.62 45.1,106.46 44.82,106.18 44.82,106.03 44.98,105.87 45.13,105.87 45.41,106.15 45.57,106.15 45.72,106 45.72,105.84 45.44,105.56 45.44,105.41 46.45,104.4 46.6,104.4 46.87,104.67 47.03,104.67 47.18,104.51 47.18,104.36 46.91,104.09 46.91,103.94 47.19,103.66 68.83,103.66 69.8,104.63 72.09,104.63 73.19,105.73 73.19,105.9 72.67,106.42 72.67,106.58 72.78,106.7 72.95,106.7 73.47,106.18 73.63,106.18 73.75,106.29 73.75,106.46 73.23,106.98 73.23,107.14 73.34,107.26 73.51,107.26 74.03,106.74 74.2,106.74 75.56,108.11 79.54,108.11 79.65,108.22 79.65,108.56 79.76,108.67 79.98,108.67 80.09,108.56 80.09,108.22 80.2,108.11 80.42,108.11 80.53,108.22 80.53,108.56 80.64,108.67 80.85,108.67 80.96,108.56 80.96,108.22 81.07,108.11 81.29,108.11 81.4,108.22 81.4,108.56 81.51,108.67 81.73,108.67 81.84,108.56 81.84,108.22 81.95,108.11 85.07,108.11 86.61,106.56 92.09,106.56 93.74,104.91 95,104.91 97.05,102.85 97.82,102.85 99.39,101.27 99.39,96.6 99.29,96.5 99.29,92.74 98.83,92.28 98.83,91.42 v4(99.04,91.21)
AM57XX_RGMII0_RD3: length 100.8
  TOP w0.173: R85.2 31.42,111.26 v7(31.88,111.71) ; U1.V4 v4(99.04,90.41)
  L3_SIG1 w0.099: v4(99.04,90.41) 99.04,90.75 98.55,91.23 98.55,91.5
  L3_SIG1 w0.109: v7(31.88,111.71) 33.08,111.71 33.21,111.84 33.21,112.23 33.32,112.35 33.49,112.35 33.6,112.23 33.6,111.7 33.72,111.59 34.06,111.59 34.2,111.72 34.2,112.38 34.59,112.78 35.05,112.78 35.17,112.66 35.17,112.22 35.28,112.1 35.45,112.1 35.56,112.22 35.56,112.66 35.71,112.81 37.03,112.81 37.31,112.53 37.47,112.53 37.68,112.74 37.85,112.74 37.96,112.63 37.96,112.46 37.75,112.25 37.75,112.09 37.87,111.97 38.03,111.97 38.24,112.18 38.41,112.18 38.53,112.06 38.53,111.9 38.31,111.69 38.31,111.52 38.43,111.41 38.59,111.41 38.81,111.62 38.97,111.62 39.09,111.5 39.09,111.34 38.87,111.13 38.87,110.96 38.99,110.85 39.15,110.85 39.37,111.06 39.53,111.06 39.65,110.94 39.65,110.78 39.44,110.57 39.44,110.4 40.52,109.32 40.87,109.32 40.99,109.2 40.99,109.04 40.53,108.59 40.53,108.42 40.65,108.31 40.82,108.31 41.27,108.77 41.44,108.77 41.56,108.65 41.56,108.49 41.1,108.03 41.1,107.86 41.21,107.75 41.38,107.75 41.54,107.91 41.54,107.92 41.81,108.18 41.99,108.18 46.96,103.21 50.6,103.21 52.17,101.63 52.74,101.63 52.85,101.74 52.85,102.31 52.96,102.42 53.17,102.42 53.28,102.31 53.28,101.74 53.39,101.63 55.24,101.63 56.72,103.1 69.06,103.1 70.13,104.17 72.44,104.17 75.82,107.55 81.25,107.55 83.03,105.77 84.12,105.77 84.43,106.08 90.25,106.08 90.4,106.23 91.97,106.23 92.86,105.34 92.86,104.37 93.34,103.89 95.38,103.89 96.88,102.39 97.56,102.39 98.93,101.02 98.93,96.7 98.86,96.63 98.86,94.42 99.03,94.24 99.03,92.99 98.55,92.51 98.55,91.5
AM57XX_RGMII0_RXCLK: length 101.7
  TOP w0.173: R79.2 39.55,111.26 v7(41.15,112.86) ; U1.U5 v4(99.84,89.61)
  L3_SIG1 w0.099: v4(99.84,89.61) 99.33,90.12 99.33,91.34 99.11,91.56 99.11,91.7
  L3_SIG1 w0.109: v7(41.15,112.86) 41.65,112.36 41.83,112.36 42.92,111.27 42.92,111.1 42.64,110.83 42.64,110.66 42.76,110.55 42.92,110.55 43.2,110.82 43.37,110.82 43.48,110.71 43.48,110.54 43.2,110.27 43.2,110.1 43.32,109.98 43.49,109.98 43.76,110.26 43.93,110.26 44.04,110.15 44.04,109.98 43.77,109.7 43.77,109.54 43.88,109.42 44.05,109.42 44.32,109.7 44.49,109.7 44.6,109.59 44.6,109.42 44.33,109.14 44.33,108.98 44.44,108.86 44.61,108.86 44.89,109.14 45.05,109.14 45.17,109.02 45.17,108.86 44.89,108.58 44.89,108.42 45,108.3 45.17,108.3 45.45,108.58 45.61,108.58 45.73,108.46 45.73,108.3 45.45,108.02 45.45,107.86 45.56,107.74 45.73,107.74 46.01,108.02 46.17,108.02 46.29,107.9 46.29,107.74 46.01,107.46 46.01,107.3 46.13,107.18 46.29,107.18 46.57,107.46 46.73,107.46 46.85,107.34 46.85,107.18 46.57,106.9 46.57,106.74 46.68,106.63 46.86,106.63 47.13,106.9 47.29,106.9 47.47,106.72 47.47,106.57 47.27,106.36 47.27,106.21 47.42,106.05 47.57,106.05 47.78,106.26 47.93,106.26 48.09,106.1 48.09,105.95 47.88,105.74 47.88,105.59 48.04,105.43 48.19,105.43 48.4,105.64 48.55,105.64 48.71,105.48 48.71,105.33 48.5,105.12 48.5,104.97 48.66,104.82 48.81,104.82 49.02,105.02 49.17,105.02 49.38,104.81 68.09,104.81 69.7,106.43 69.86,106.43 70.31,105.98 70.5,105.98 70.63,106.1 70.63,106.26 70.13,106.76 70.13,106.91 70.28,107.07 70.44,107.07 70.94,106.57 71.09,106.57 71.25,106.72 71.25,106.88 70.75,107.38 70.75,107.53 70.9,107.68 71.05,107.68 71.55,107.18 71.71,107.18 71.86,107.34 71.86,107.49 71.36,107.99 71.36,108.15 71.52,108.3 71.67,108.3 72.17,107.8 72.33,107.8 72.48,107.96 72.48,108.11 71.98,108.61 71.98,108.77 72.14,108.92 72.29,108.92 72.79,108.42 72.95,108.42 74.59,110.06 81.88,110.06 82.37,110.55 84.05,110.55 87.53,107.07 90.82,107.07 91,106.89 92.33,106.89 93.19,106.02 93.95,106.02 94.61,105.36 95.17,105.36 97.23,103.31 98.15,103.31 99.85,101.6 99.85,96.68 99.54,96.37 99.54,92.66 99.11,92.23 99.11,91.7
AM57XX_RGMII0_RXCTL: length 100.3
  TOP w0.173: R82.2 37.01,111.26 v7(37.46,111.71) ; U1.V5 v4(99.04,89.61)
  L3_SIG1 w0.099: v4(99.04,89.61) 98.74,89.91 98.74,90.67 98.09,91.32 98.09,91.48
  L3_SIG1 w0.109: v7(37.46,111.71) 37.46,109.4 40.12,106.74 42.77,106.74 44.47,105.04 44.47,104.88 43.84,104.25 43.84,104.09 43.96,103.97 44.12,103.97 44.72,104.57 44.89,104.57 45,104.46 45,104.29 44.38,103.67 44.38,103.5 44.49,103.38 44.66,103.38 45.26,103.99 45.45,103.99 45.56,103.88 45.56,103.73 44.92,103.08 44.92,102.93 45.03,102.82 45.22,102.82 45.82,103.43 45.98,103.43 46.1,103.31 46.1,103.14 45.57,102.62 45.57,102.46 45.81,102.23 46.41,102.23 46.52,102.34 46.52,102.59 46.63,102.7 46.85,102.7 46.96,102.59 46.96,102.34 47.07,102.23 47.28,102.23 47.39,102.34 47.39,102.59 47.5,102.7 47.72,102.7 47.83,102.59 47.83,102.34 47.94,102.23 48.16,102.23 48.27,102.34 48.27,102.59 48.38,102.7 48.6,102.7 48.7,102.59 48.7,102.34 48.81,102.23 49.03,102.23 49.14,102.34 49.14,102.59 49.25,102.7 49.47,102.7 49.58,102.59 49.58,102.34 49.69,102.23 49.91,102.23 50.01,102.34 50.01,102.59 50.12,102.7 50.34,102.7 50.45,102.59 50.45,102.34 50.56,102.23 50.71,102.23 51.82,101.12 56.23,101.12 56.34,101.23 56.34,101.75 56.45,101.86 56.66,101.86 56.77,101.75 56.77,101.23 56.88,101.12 57.1,101.12 57.21,101.23 57.21,101.75 57.32,101.86 57.54,101.86 57.65,101.75 57.65,101.23 57.76,101.12 57.97,101.12 58.08,101.23 58.08,101.75 58.19,101.86 58.41,101.86 58.52,101.75 58.52,101.23 58.63,101.12 58.85,101.12 58.96,101.23 58.96,101.55 59.07,101.66 59.28,101.66 59.39,101.55 59.39,101.23 59.5,101.12 60.25,101.12 61.52,102.39 70.64,102.39 71.96,103.71 72.72,103.71 75.97,106.96 81.14,106.96 82.82,105.29 84.3,105.29 84.6,105.58 90.33,105.58 90.64,105.9 91.77,105.9 92.51,105.16 92.51,104.15 93.23,103.43 94.87,103.43 95.78,102.52 95.78,101.71 98.48,99.01 98.48,94.52 98.25,94.29 98.25,92.61 98.09,92.46 98.09,91.48
AM57XX_RGMII0_TD0: length 30.3
  TOP w0.173: R88.2 86.74,102.06 v7(86.74,99.82) ; U1.U6 v4(99.84,88.81)
  L3_SIG1 w0.109: v5(99.44,89.06) 99.84,88.82 v4(99.84,88.81) ; v7(86.74,99.82) v5(86.74,99.14)
  L10_SIG4 w0.109: v5(86.74,99.14) 87.2,98.68 88.19,98.68 89.1,99.6 90.25,99.6 90.71,100.06 94.71,100.06 95.25,100.61 98.57,100.61 99.7,99.47 100,99.17 100,93.32 99.11,92.44 99.11,91.5 99.44,91.17 99.44,89.07 v5(99.44,89.06)
AM57XX_RGMII0_TD1: length 21
  TOP w0.173: U1.V6 v4(99.04,88.81) ; v7(91.82,99.78) 91.82,102.06 R287.2
  L3_SIG1 w0.099: 97.84,91.42 97.84,91.29 98.54,90.59 98.54,89.31 v4(99.04,88.81)
  L3_SIG1 w0.109: v5(95.89,99.62) 98.02,97.49 98.02,96.6 98.17,96.45 98.17,94.57 98.02,94.42 98.02,92.84 97.84,92.66 97.84,91.42 ; v7(91.82,99.78) v5(91.82,99.14)
  L10_SIG4 w0.109: v5(91.82,99.14) 92.14,99.46 95.01,99.46 95.17,99.62 v5(95.89,99.62)
AM57XX_RGMII0_TD2: length 30.3
  TOP w0.173: R283.2 88.01,102.06 v7(88.01,99.78) ; U1.U7 v4(99.84,88.01)
  L3_SIG1 w0.109: v7(88.01,99.78) v5(88.01,99.14) ; v5(99.44,88.26) v4(99.84,88.01)
  L10_SIG4 w0.109: v5(88.01,99.14) 88.93,100.06 90.07,100.06 90.38,100.37 94.58,100.37 95.13,100.91 98.69,100.91 100.3,99.29 100.3,93.32 99.69,92.71 99.69,92.16 99.97,91.88 99.97,91.17 99.74,90.93 99.74,89.83 99.89,89.68 99.89,88.71 v5(99.44,88.26)
AM57XX_RGMII0_TD3: length 27.2
  TOP w0.173: v7(89.28,99.78) 89.28,102.06 R284.2 ; U1.V7 v4(99.04,88.01)
  L3_SIG1 w0.109: v7(89.28,99.78) v5(89.28,99.14) ; v5(98.64,88.26) v4(99.04,88.01)
  L10_SIG4 w0.109: v5(89.28,99.14) 89.71,98.71 91.98,98.71 92.38,99.11 96.01,99.11 96.9,100 97.99,100 99.49,98.5 99.49,93.48 98.48,92.46 98.48,91.37 98.78,91.06 98.78,88.41 v5(98.64,88.26)
AM57XX_RGMII0_TXCLK: length 32.8
  TOP w0.173: R281.2 85.47,102.06 v7(85.47,99.82) ; U1.W9 v4(98.24,86.41)
  L3_SIG1 w0.109: v7(85.47,99.82) v5(85.47,99.14) ; v5(97.84,86.66) v4(98.24,86.41)
  L10_SIG4 w0.109: v5(97.84,86.66) 98.22,87.05 98.22,88.93 98.5,89.21 98.5,90.96 98.06,91.4 98.06,92.4 99.06,93.4 99.06,97.57 98.6,98.02 98.6,98.71 97.66,99.65 96.93,99.65 95.7,98.42 94.67,98.42 94.28,98.81 92.71,98.81 92.13,98.22 86.39,98.22 v5(85.47,99.14)
AM57XX_RGMII0_TXCTL: length 28.1
  TOP w0.173: U1.V9 v4(99.04,86.41) ; R91.2 90.55,102.06 v7(90.55,99.78)
  L3_SIG1 w0.109: v5(98.64,86.66) v4(99.04,86.41) ; v7(90.55,99.78) v5(90.55,99.14)
  L10_SIG4 w0.109: v5(90.55,99.14) 91.17,99.76 94.83,99.76 95.38,100.3 98.44,100.3 99.77,98.97 99.77,93.43 98.78,92.44 98.78,91.39 99.03,91.14 99.03,87.06 v5(98.64,86.66)
AM57XX_RGMII1_RD0: length 115.8
  TOP w0.173: R139.2 56.92,110.06 57.53,110.67 v7(57.53,111.84) ; U1.A4 113.88,90.02 115.61,91.75 117.57,91.75 121.61,95.78 121.61,96.88 v7(122.01,97.27)
  L3_SIG1 w0.109: v7(122.01,97.27) 124.49,99.75 124.49,104.07 116.87,111.69 114.2,111.69 113.23,112.65 113.23,113.19 107.7,118.72 102.1,118.72 101.44,119.38 79.43,119.38 78,120.81 76.78,120.81 76.67,120.7 76.67,120.33 76.56,120.22 76.34,120.22 76.23,120.33 76.23,120.7 76.12,120.81 75.9,120.81 75.79,120.7 75.79,120.33 75.68,120.22 75.46,120.22 75.36,120.33 75.36,120.7 75.25,120.81 67.09,120.81 66.52,120.24 66.52,120.05 66.73,119.84 66.73,119.67 66.62,119.56 66.45,119.56 66.24,119.77 66.08,119.77 65.96,119.65 65.96,119.49 66.07,119.38 66.07,119.21 65.96,119.1 65.79,119.1 65.67,119.22 65.52,119.22 64.55,118.24 63.93,118.24 63.09,117.4 60.48,117.4 60.32,117.24 60.32,117.08 60.75,116.64 60.75,116.48 60.63,116.36 60.47,116.36 60.03,116.8 59.87,116.8 59.75,116.68 59.75,116.52 60.19,116.08 60.19,115.92 60.07,115.8 59.91,115.8 59.47,116.24 59.31,116.24 59.19,116.12 59.19,115.96 59.63,115.52 59.63,115.36 59.51,115.24 59.35,115.24 59.12,115.47 56.47,115.47 56.35,115.35 56.35,114.98 56.24,114.86 56.07,114.86 55.96,114.98 55.96,115.35 55.84,115.47 54.96,115.47 54.74,115.25 54.74,112.7 54.98,112.47 56.91,112.47 v7(57.53,111.84)
AM57XX_RGMII1_RD1: length 114.7
  TOP w0.173: U1.B5 112.64,89.62 113.2,89.62 113.2,89.62 114.08,89.62 115.79,91.33 117.8,91.33 122.17,95.71 122.17,96.37 v7(123.42,97.62) ; v7(56.13,111.84) 56.13,110.77 55.43,110.06 R334.2
  L3_SIG1 w0.109: v7(123.42,97.62) 125.4,99.6 125.4,103.79 117.02,112.17 114.73,112.17 113.74,113.16 113.74,113.37 107.9,119.21 105.49,119.21 104.09,120.6 102.03,120.6 101.25,119.82 82.67,119.82 81.97,120.53 81.11,120.53 81,120.42 81,120 80.9,119.89 80.68,119.89 80.57,120 80.57,120.42 80.46,120.53 80.24,120.53 80.13,120.42 80.13,120 80.02,119.89 79.8,119.89 79.69,120 79.69,120.42 79.59,120.53 79.15,120.53 78.34,121.34 67,121.34 64.36,118.7 63.75,118.7 62.92,117.86 59.31,117.86 57.37,115.92 54.12,115.92 53.43,115.23 53.43,112.01 53.6,111.84 v7(56.13,111.84)
AM57XX_RGMII1_RD2: length 114.4
  TOP w0.173: U1.B4 112.63,90.41 113.68,90.41 115.47,92.21 116.77,92.21 120.9,96.35 v7(120.9,96.83) ; v7(54.58,110.52) 54.13,110.06 R335.2
  L3_SIG1 w0.109: v7(54.58,110.52) 55.19,111.13 59,111.13 59.54,111.66 59.54,112.51 60.13,113.1 60.28,113.1 60.55,112.83 60.71,112.83 60.86,112.99 60.86,113.14 60.59,113.41 60.59,113.56 60.75,113.72 60.9,113.72 61.27,113.35 61.43,113.35 61.58,113.5 61.58,113.66 61.21,114.03 61.21,114.18 61.36,114.34 61.52,114.34 61.89,113.97 62.04,113.97 62.2,114.12 62.2,114.27 61.83,114.65 61.83,114.8 61.98,114.95 62.14,114.95 62.51,114.58 62.66,114.58 62.82,114.74 62.82,114.89 62.45,115.26 62.45,115.42 63.11,116.08 64.87,116.08 68.1,119.31 68.76,119.31 68.87,119.2 68.87,118.33 68.98,118.22 69.19,118.22 69.3,118.33 69.3,119.2 69.41,119.31 69.63,119.31 69.74,119.2 69.74,118.33 69.85,118.22 70.07,118.22 70.18,118.33 70.18,119.2 70.29,119.31 75.89,119.31 76,119.2 76,118.33 76.11,118.22 76.33,118.22 76.44,118.33 76.44,119.2 76.55,119.31 76.77,119.31 76.88,119.2 76.88,118.33 76.99,118.22 77.2,118.22 77.31,118.33 77.31,119.2 77.42,119.31 78.07,119.31 78.53,118.86 78.53,118.7 78.09,118.26 78.09,118.11 78.24,117.95 78.4,117.95 78.84,118.39 79,118.39 79.44,117.94 83.12,117.94 83.42,118.24 101.17,118.24 101.6,117.81 106.76,117.81 109.32,115.24 109.32,114.41 109.6,114.13 110.2,114.13 113.96,110.37 116.56,110.37 123.44,103.48 123.44,100.23 120.9,97.69 v7(120.9,96.83)
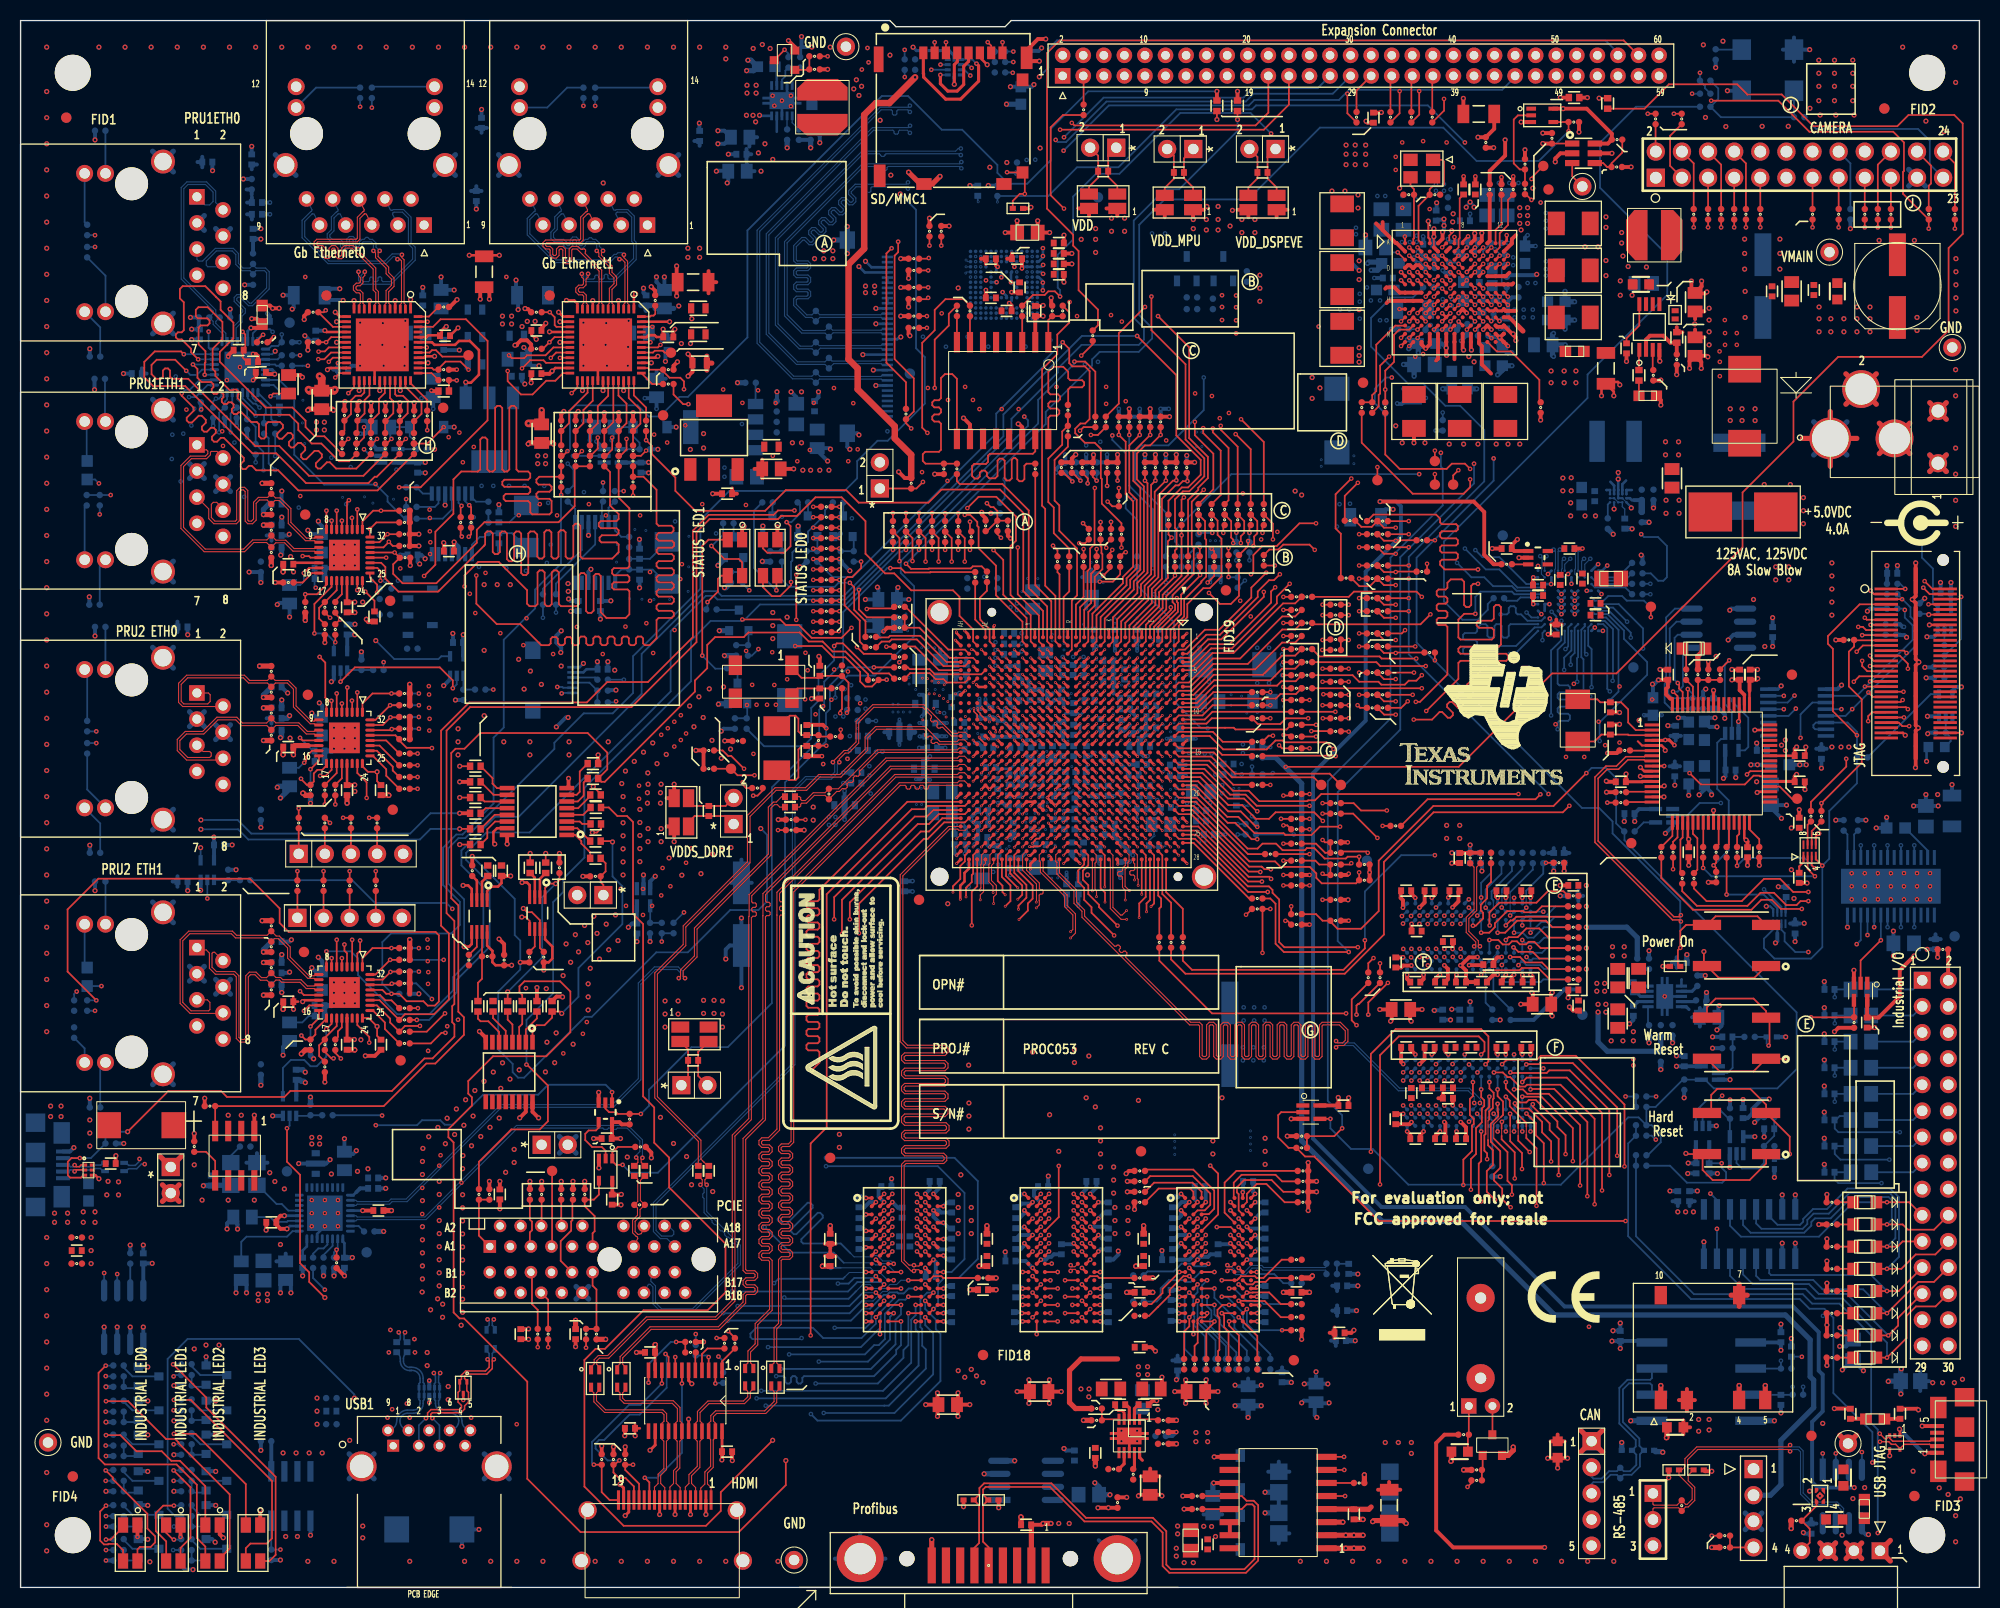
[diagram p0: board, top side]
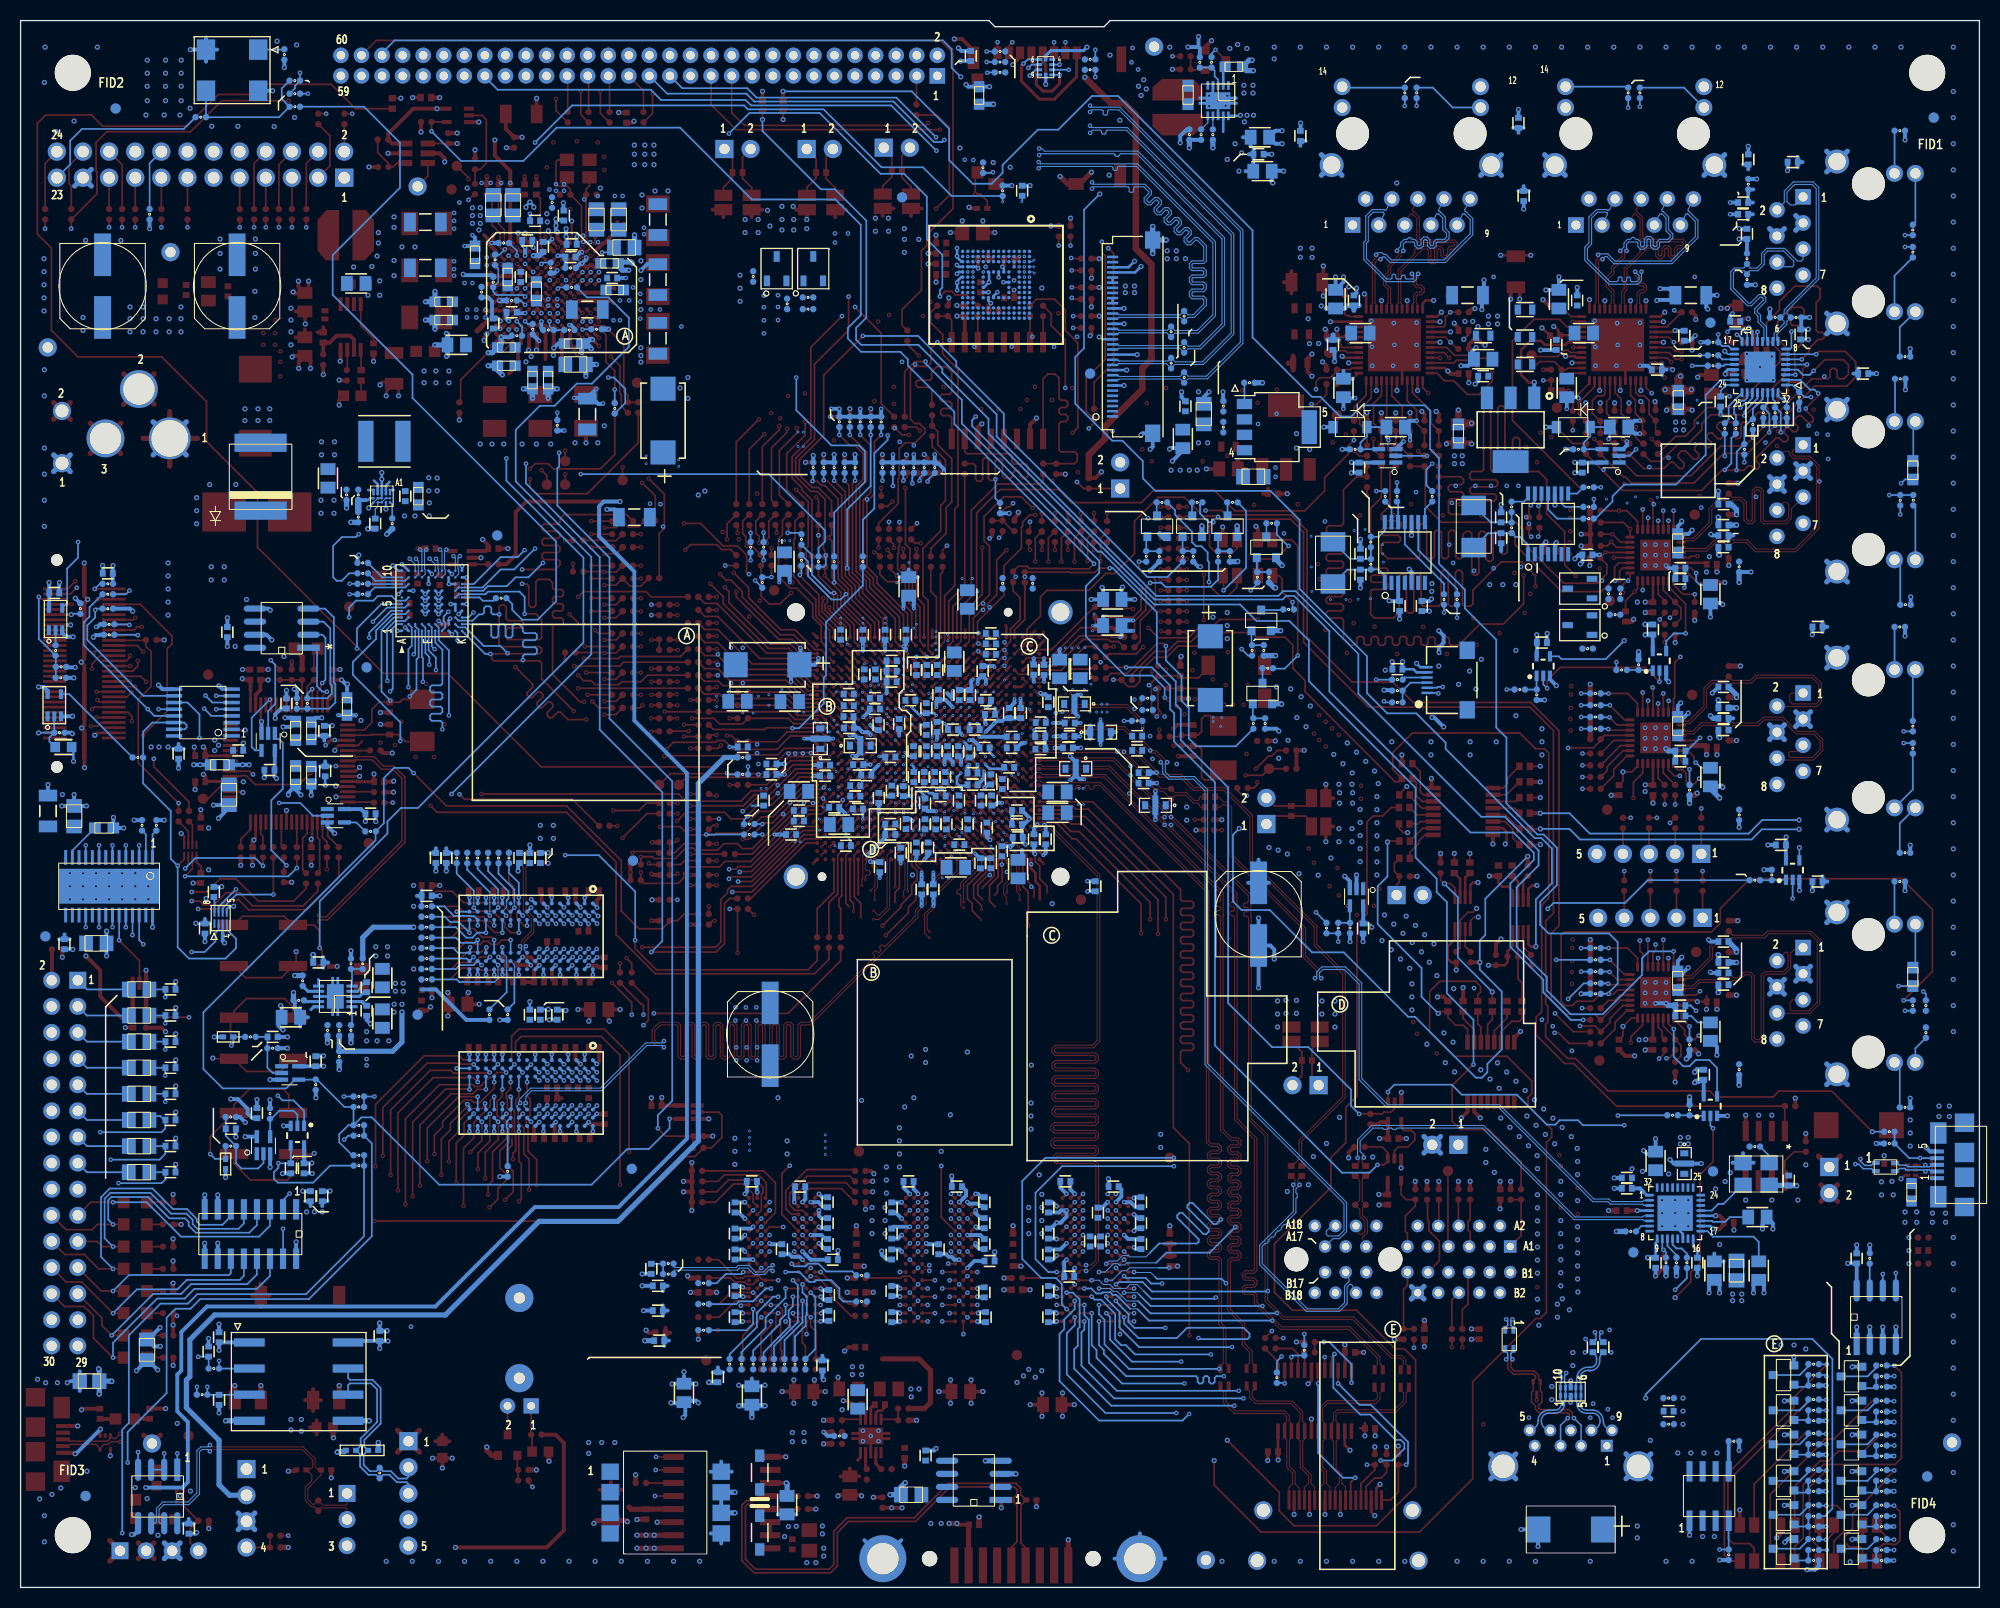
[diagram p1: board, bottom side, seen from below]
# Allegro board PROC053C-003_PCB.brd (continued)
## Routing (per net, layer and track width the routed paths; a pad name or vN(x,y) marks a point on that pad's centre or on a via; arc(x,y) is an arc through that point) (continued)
AM57XX_RGMII1_RD3: length 114.2
  TOP w0.173: v7(53.19,110.52) 52.73,110.06 R336.2 ; U1.B3 112.64,91.22 113.25,91.22 115.18,93.15 116.56,93.15 119.69,96.28 119.69,97.24 v7(121.15,98.7)
  L3_SIG1 w0.109: v7(53.19,110.52) 53.67,110.04 55.56,110.04 55.67,110.15 55.67,110.51 55.78,110.62 56,110.62 56.11,110.51 56.11,110.15 56.21,110.04 56.43,110.04 56.54,110.15 56.54,110.51 56.65,110.62 56.87,110.62 56.98,110.51 56.98,110.15 57.09,110.04 57.31,110.04 57.42,110.15 57.42,110.51 57.53,110.62 57.74,110.62 57.85,110.51 57.85,110.15 57.96,110.04 58.55,110.04 61.26,112.75 61.74,112.75 62.35,113.36 62.51,113.36 62.71,113.16 62.86,113.16 62.97,113.27 62.97,113.43 62.77,113.64 62.77,113.8 64.59,115.63 65.09,115.63 67.22,117.76 70.71,117.76 70.82,117.87 70.82,118.68 70.94,118.8 71.1,118.8 71.21,118.69 71.21,117.82 71.33,117.71 71.49,117.71 71.61,117.82 71.61,118.69 71.73,118.8 71.89,118.8 72.01,118.69 72.01,117.82 72.12,117.71 72.29,117.71 72.4,117.82 72.4,118.69 72.52,118.8 72.68,118.8 72.8,118.69 72.8,117.82 72.92,117.71 73.08,117.71 73.2,117.82 73.2,118.69 73.31,118.8 73.48,118.8 73.59,118.69 73.59,117.82 73.71,117.71 73.87,117.71 73.99,117.82 73.99,118.69 74.1,118.8 74.27,118.8 74.38,118.69 74.38,117.82 74.5,117.71 74.66,117.71 74.78,117.82 74.78,118.69 74.9,118.8 75.06,118.8 75.18,118.69 75.18,117.82 75.5,117.5 83.3,117.5 83.56,117.76 100.99,117.76 101.4,117.35 106.48,117.35 108.58,115.24 108.58,114.51 109.47,113.62 110.09,113.62 113,110.7 113,109.89 113.24,109.65 113.58,109.65 113.82,109.89 116.25,109.89 122.89,103.26 122.89,100.94 121.15,99.2 v7(121.15,98.7)
AM57XX_RGMII1_RXCLK: length 115.4
  TOP w0.173: v7(60.83,110.57) 60.32,110.06 R328.2 ; U1.C5 v4(111.83,89.61)
  L3_SIG1 w0.109: v4(111.83,89.61) 112.14,89.61 112.78,90.25 116.08,90.25 119,93.17 119,94.98 119.2,95.18 119.2,99.06 121.22,101.09 121.22,103.41 115.66,108.97 113.99,108.97 113.65,109.31 112.63,109.31 111.93,110.01 111.93,110.5 111.61,110.83 110.87,110.83 110.34,111.36 110.34,112.27 109.98,112.63 109.04,112.63 108.88,112.79 105.67,116.01 104.52,116.01 104.41,115.9 104.41,114.74 104.3,114.64 104.08,114.64 103.97,114.74 103.97,115.9 103.87,116.01 103.65,116.01 103.54,115.9 103.54,114.74 103.43,114.64 103.21,114.64 103.1,114.74 103.1,115.9 102.99,116.01 102.77,116.01 102.66,115.9 102.66,114.74 102.55,114.64 102.34,114.64 102.23,114.74 102.23,115.9 102.12,116.01 101.9,116.01 101.79,115.9 101.79,114.74 101.68,114.64 101.46,114.64 101.35,114.74 101.35,115.9 101.24,116.01 101.03,116.01 100.92,115.9 100.92,114.74 100.81,114.64 100.59,114.64 100.48,114.74 100.48,115.9 100.37,116.01 100.15,116.01 100.04,115.9 100.04,114.74 99.93,114.64 99.71,114.64 99.61,114.74 99.61,115.9 99.5,116.01 99.28,116.01 99.17,115.9 99.17,114.74 99.06,114.64 98.84,114.64 98.73,114.74 98.73,115.9 98.62,116.01 98.4,116.01 98.29,115.9 98.29,114.74 98.19,114.64 97.97,114.64 97.86,114.74 97.86,115.9 97.75,116.01 80.86,116.01 80.58,115.73 75.61,115.73 75.44,115.55 74.3,115.55 74.12,115.73 68.12,115.73 67.78,115.39 67.78,115.23 68.26,114.75 68.26,114.6 68.11,114.44 67.95,114.44 67.44,114.95 67.26,114.95 67.12,114.81 67.12,114.65 67.64,114.13 67.64,113.98 67.49,113.82 67.33,113.82 66.83,114.33 66.67,114.33 66.52,114.18 66.52,114.02 67.02,113.51 67.02,113.36 66.87,113.2 66.72,113.2 66.23,113.69 66.08,113.69 64.24,111.85 62.11,111.85 v7(60.83,110.57)
AM57XX_RGMII1_RXCTL: length 114.7
  TOP w0.173: v7(122.47,98.54) 121.89,97.97 121.42,97.97 120.32,96.87 120.32,96.34 116.64,92.66 115.32,92.66 113.47,90.81 U1.A3 ; v7(58.93,111.71) 58.93,110.67 58.32,110.06 R133.2
  L3_SIG1 w0.109: v7(122.47,98.54) 123.95,100.03 123.95,103.76 116.83,110.88 114.07,110.88 111.23,113.72 111.23,114.36 107.32,118.27 101.83,118.27 101.15,118.94 79.16,118.94 78.35,119.75 74.66,119.75 74.06,120.35 73.69,120.35 73.59,120.24 73.59,119.9 73.48,119.79 73.26,119.79 73.15,119.9 73.15,120.24 73.04,120.35 72.82,120.35 72.71,120.24 72.71,119.9 72.6,119.79 72.38,119.79 72.27,119.9 72.27,120.24 72.17,120.35 71.95,120.35 71.84,120.24 71.84,119.9 71.73,119.79 71.51,119.79 71.4,119.9 71.4,120.24 71.29,120.35 71.07,120.35 70.96,120.24 70.96,119.9 70.85,119.79 70.64,119.79 70.53,119.9 70.53,120.24 70.42,120.35 70.2,120.35 70.09,120.24 70.09,119.9 69.98,119.79 69.76,119.79 69.65,119.9 69.65,120.24 69.54,120.35 69.33,120.35 69.22,120.24 69.22,119.9 69.11,119.79 68.89,119.79 68.78,119.9 68.78,120.24 68.67,120.35 68.18,120.35 64.82,117 63.31,117 63.15,116.84 62.99,116.84 62.88,116.96 62.69,116.96 62.58,116.85 62.58,116.69 62.71,116.56 62.71,116.4 62.59,116.28 62.42,116.28 61.95,116.75 61.78,116.75 61.67,116.64 61.67,116.47 62.14,116 62.14,115.83 62.03,115.72 61.86,115.72 61.41,116.17 61.25,116.17 61.13,116.05 61.13,115.89 61.58,115.44 61.58,115.27 61.47,115.15 61.3,115.15 60.85,115.61 60.69,115.61 60.57,115.49 60.57,115.33 61.02,114.87 61.02,114.71 60.9,114.59 60.74,114.59 60.26,115.07 60.1,115.07 59.98,114.95 59.98,114.79 60.46,114.31 60.46,114.15 60.08,113.77 57.87,113.77 57.76,113.66 57.76,113.51 57.87,113.4 59.19,113.4 59.31,113.28 59.31,113.12 59.19,113 57.81,113 57.7,112.9 57.7,112.73 57.83,112.61 58.81,112.61 58.93,112.49 v7(58.93,111.71)
AM57XX_RGMII1_TD0: length 23.6
  TOP w0.173: R330.2 121.79,103.46 v7(121.79,101.94) ; U1.D6 v4(111.03,88.81)
  L3_SIG1 w0.109: v4(111.03,88.81) 111.34,89.12 112.04,89.12 112.94,90.02 116.87,90.02 120.4,93.55 120.4,99.62 121.79,101.02 v7(121.79,101.94)
AM57XX_RGMII1_TD1: length 15.4
  TOP w0.173: U1.B2 112.63,92.01 112.63,93.53 113.46,94.36 113.46,95.64 115.02,97.19 115.65,97.19 116.79,98.33 116.79,102 116.41,102.38 116.41,103.76 R137.2
AM57XX_RGMII1_TD2: length 18.6
  TOP w0.173: R327.2 117.73,103.71 117.73,102.11 117.93,101.91 v7(117.93,101.58) ; U1.C4 v4(111.83,90.41)
  L3_SIG1 w0.109: v7(117.93,101.58) 117.93,97.92 117.22,97.21 117.22,93.63 116.26,92.66 114.78,92.66 113.83,91.72 113.14,91.72 v4(111.83,90.41)
AM57XX_RSTOUTN: length 134.7
  TOP w0.173: U47.2 122.6,46.23 122.3,45.93 122.3,43.77 123.32,42.75 R36.2 124.92,41.92 125.81,41.92 132.08,35.64 v7(156.08,35.64) ; U1.F23 v4(109.43,74.42)
  L3_SIG1 w0.109: v7(156.08,35.64) v5(156.84,35.64) 158.07,36.87 158.07,38.97 159.03,39.93 v2(159.03,43.56) ; v4(109.43,74.42) v5(109.83,74.17)
  L4_SIG2 w0.114: v5(156.84,35.64) 156.84,39.27 157.1,39.52 157.1,48.74 158.17,49.81 158.17,51.99 158.88,52.71 158.88,53.92 158.04,54.77 158.04,56.8 154.05,60.78 154.05,63.37 152.4,65.02 151.39,65.02 148.21,68.2 134.2,68.2 131.84,65.84 125.41,65.84 124.42,66.83 121.39,66.83 115.36,72.85 112.06,72.85 110.74,74.17 v5(109.83,74.17)
  BOTTOM w0.173: R922.2 158.62,43.94 159,43.56 v2(159.03,43.56)
AM57XX_RTCK: length 15.9
  TOP w0.173: v7(122.81,74.12) 123.19,74.12 R426.2 ; U1.E18 v4(110.23,78.42)
  L3_SIG1 w0.109: v7(122.81,74.12) 122.5,74.12 120.67,75.95 119.63,75.95 118.18,77.4 116.26,77.4 116.13,77.27 114.07,77.27 113.69,77.65 111.81,77.65 111.39,78.07 110.58,78.07 v4(110.23,78.42)
AM57XX_SPI1_CS0: length 18.2
  TOP w0.173: U1.D17 v4(111.03,79.22) ; R369.2 v7(126.62,76.28)
  L3_SIG1 w0.099: v4(111.03,79.22) 111.33,78.92 111.96,78.92
  L3_SIG1 w0.109: 111.96,78.92 113.84,78.92 114.35,78.41 115.82,78.41 115.96,78.55 119.85,78.55 121.92,76.48 125.78,76.48 125.98,76.28 v7(126.62,76.28)
AM57XX_SPI1_D1: length 10.1
  TOP w0.173: R377.2 119.36,71.33 114.27,76.42 U1.A21
AM57XX_SPI1_SCLK: length 17.6
  TOP w0.173: U1.C18 v4(111.83,78.42) ; R367.2 v7(126.62,75.27)
  L3_SIG1 w0.109: v4(111.83,78.42) 113.66,78.42 114.3,77.78 116,77.78 116.2,77.98 119.61,77.98 122.33,75.27 v7(126.62,75.27)
AM57XX_SPI2_SCLK: length 9
  TOP w0.173: R684.1 119.48,67.01 114.08,72.42 U1.A26
AM57XX_STATUSLED0_GRN: length 14.7
  TOP w0.173: R736.2 82.17,93.98 81.07,95.08 81.07,97.29 v2(80.64,97.71)
  BOTTOM w0.173: R701.1 74.04,98.02 74.74,97.32 79.16,97.32 79.55,97.71 v2(80.64,97.71)
AM57XX_STATUSLED0_RED: length 58.6
  TOP w0.173: R735.2 107.06,103.5 105.16,105.41 105.16,107.8 105.05,107.9 105.05,110.75 104.47,111.33 103.5,111.33 102.56,112.28 102.56,112.7 103.07,113.21 103.53,113.21 103.96,113.64 103.96,118.3 103.5,118.77 102.3,118.77 101.98,119.08 101.98,120.48 v2(101.35,121.11)
  BOTTOM w0.173: R698.2 78.97,98.27 80.92,98.27 94.88,112.23 94.88,114.17 99.51,118.8 99.51,119.28 v2(101.35,121.11)
AM57XX_STATUSLED0_YEL: length 10.8
  TOP w0.173: R737.2 81.61,92 81.61,94.04 80.14,95.52 80.14,98 80.41,98.27 80.87,98.27 81.74,99.14 v2(81.74,99.78)
  BOTTOM w0.173: R694.1 v2(81.74,99.78)
AM57XX_STATUSLED1_GRN: length 304.4
  TOP w0.173: v2(129.92,54.69) 129.45,55.16 129.45,57.19 R739.2
  L4_SIG2 w0.114: v2(156.84,50.78) 154.81,48.75 154.81,43.18 155.79,42.2 155.79,39.99 150.81,35.01 144.67,35.01 143.58,33.92 135.43,33.92 124.56,23.05 110.89,23.05 110.53,23.4 110.19,23.4 109.84,23.05 69.52,23.05 67.19,25.37 62.41,25.37 60.71,23.67 60.71,22.91 46.91,9.12 32.86,9.12 31.03,10.95 31.03,23.2 37.14,29.31 37.14,49.79 38.76,51.41 40.67,51.41 43.12,53.87 43.12,60.24 44.49,61.61 44.49,65.8 42.11,68.17 42.11,77.01 42.49,77.39 50.5,77.39 57.12,84.02 59.04,84.02 66.56,91.54 69.75,91.54 70.6,90.69 71.87,90.69 72.19,91.01 72.19,95.65 v2(70.87,96.98)
  L9_SIG3 w0.114: v2(129.92,54.69) 131.48,53.13 148.88,53.13 151.23,50.78 v2(156.84,50.78)
  BOTTOM w0.173: R710.1 70.23,97.62 v2(70.87,96.98)
AM57XX_STATUSLED1_RED: length 24.6
  TOP w0.173: R738.2 84.45,88.9 82.89,88.9 79.97,91.82 79.38,91.82 v2(79.12,91.57)
  BOTTOM w0.173: R707.2 72.31,81.82 76.12,81.82 76.89,82.59 76.89,85.53 77.6,86.24 77.6,88.65 79.12,90.17 v2(79.12,91.57)
AM57XX_STATUSLED1_YEL: length 297.6
  TOP w0.173: v2(129.92,55.71) 129.92,56.6 130.09,56.77 130.18,56.77 R740.2
  L4_SIG2 w0.114: v2(71.75,91.27) 70.72,92.3 66.86,92.3 58.96,84.4 54.64,84.4 48.01,77.77 42.42,77.77 41.66,77.01 41.66,68.02 43.74,65.94 43.74,61.52 42.71,60.49 42.71,58.2 40.67,56.15 40.67,54.35 36.81,50.49 36.81,29.82 30.73,23.74 30.73,10.83 32.73,8.83 47.23,8.83 59.26,20.85 61.49,20.85 65.22,24.59 65.22,24.82 65.48,25.08 65.94,25.08 68.45,22.57 124.82,22.57 135.73,33.48 143.72,33.48 144.94,34.7 150.92,34.7 156.09,39.87 156.09,42.52 155.12,43.48 155.12,48.25 157.28,50.42 157.28,50.96 156.86,51.39 v2(156.84,51.39)
  L9_SIG3 w0.114: v2(156.84,51.39) 151.77,51.39 149.48,53.67 131.96,53.67 v2(129.92,55.71)
  BOTTOM w0.173: v2(71.75,91.27) 71.12,90.63 R703.1
AM57XX_UART2_RXD: length 7.8
  TOP w0.173: U1.D28 110.64,67.29 110.92,67.01 110.92,66.21 110.74,66.04 R583.2
AM57XX_UART2_TXD: length 13.6
  TOP w0.173: R582.2 119.2,65.44 v7(119.18,65.44) ; U1.D26 v4(111.03,72.02)
  L3_SIG1 w0.099: v4(111.03,72.02) 111.54,71.51 112.76,71.51 112.88,71.39 113.19,71.39 113.31,71.51 114.49,71.51
  L3_SIG1 w0.109: 114.49,71.51 115.24,71.51 117.02,69.73 117.02,67.59 v7(119.18,65.44)
AM57XX_UART3_RXD: length 8.9
  TOP w0.173: R487.1 111.89,66.6 111.03,67.45 111.03,71.22 U1.D27
AM57XX_UART3_TXD: length 8.3
  TOP w0.173: R486.1 113.03,66.01 111.4,67.63 111.4,70.78 U1.C28
AM57XX_VIN2A_CLK0: length 8.4
  TOP w0.173: U1.E1 109.83,93.53 111.42,95.12 111.42,96.4 113.54,98.52 R669.1
AM57XX_VIN2A_DE0: length 158.2
  TOP w0.173: R119.2 v2(33.91,74.86) ; U1.G2 108.24,91.62 108.63,92.01 108.63,93.34 110.72,95.43 110.72,96.79 112.27,98.34 v7(112.27,98.43) R670.1
  L3_SIG1 w0.109: v5(112.52,120.48) 108.31,124.69 108.31,125.15 106.63,126.83 102.87,126.83 100.66,129.04 98.12,129.04 97.36,129.8 86.89,129.8 85.67,128.57 84.58,128.57 83.66,129.5 81.37,129.5 80.44,128.57 v5(76.54,128.57) ; v7(112.27,98.43) v5(112.27,97.69)
  L4_SIG2 w0.114: v5(76.54,128.57) 70.42,122.46 70.42,107.45 62.54,99.57 62.54,89.58 58.35,85.39 48.06,85.39 43.03,80.37 42.49,80.37 40.28,78.16 40.28,76.86 38.28,74.86 v2(33.91,74.86) ; v5(112.27,97.69) 112.09,97.69 111.23,98.55 111.23,102.01 112.95,103.74 112.95,107.79 114.18,109.01 114.34,109.01 114.59,109.26 114.59,114.09 112.52,116.15 v5(112.52,120.48)
AM57XX_VIN2A_FLD0: length 18.7
  TOP w0.173: v4(107.8,88.06) 107.8,87.98 U1.H7
  L3_SIG1 w0.109: v4(107.8,88.06) 107.87,88.11 107.96,88.09 108.23,88.26 v5(108.23,88.26)
  L4_SIG2 w0.114: v5(113.33,98.4) 113.15,98.22 113.15,96.72 112.52,96.09 110.43,96.09 107.82,93.48 107.82,88.67 v5(108.23,88.26)
  L10_SIG4 w0.109: v5(113.33,98.4) 113.08,98.15 111.79,98.15 v9(111.38,97.74)
  BOTTOM w0.173: v9(111.38,97.74) R671.1
AM57XX_VIN2A_HSYNC0: length 158.4
  TOP w0.173: U1.G1 108.23,93.42 110.36,95.55 110.36,96.98 111.58,98.2 111.58,101.75 v7(111.94,102.11) 111.63,102.41 R672.1 ; R118.2 v2(31.37,74.86)
  L3_SIG1 w0.109: v5(74.87,128.54) 75.34,128.07 78.36,128.07 78.46,127.97 81.75,127.97 81.85,128.07 85.58,128.07 86.31,128.8 88.47,128.8 89.03,129.36 97.13,129.36 98.27,128.22 101.07,128.22 102.97,126.32 106.5,126.32 v5(107.26,125.56) ; v7(111.94,102.11) 111.94,102.41 v5(110.06,104.28)
  L4_SIG2 w0.114: v2(31.37,74.86) 31.92,75.41 38.15,75.41 39.87,77.13 39.87,78.31 41.96,80.41 41.96,84.63 43.03,85.7 58.2,85.7 60.76,88.26 60.76,98.73 69.09,107.06 69.09,122.76 v5(74.87,128.54) ; v5(107.26,125.56) 107.26,114.88 107.26,114.87 107.26,114.4 107.26,114.39 107.26,113.77 108.38,112.65 108.38,111.64 108,111.26 108,107.93 110.44,105.49 110.44,104.65 v5(110.06,104.28)
AM57XX_VIN2A_VSYNC0: length 174.5
  TOP w0.173: R735.1 v7(107.06,101.14) ; U1.G6 v4(108.63,88.81) ; R198.2 v2(32,69.67)
  L3_SIG1 w0.099: v5(104.26,93.58) 104.36,93.68 104.47,93.68 105.03,94.24 105.03,95.08 104.66,95.45 104.66,96.13 106.35,97.82
  L3_SIG1 w0.109: v5(104.04,125.53) 103.35,125.53 102.44,126.44 101.26,126.44 100.37,127.34 96.85,127.34 95.22,128.97 94.02,128.97 92.41,127.36 87.99,127.36 87.43,127.92 86.16,127.92 85.83,127.59 v5(77.8,127.59) ; v5(109.03,89.06) 108.64,88.82 v4(108.63,88.81) ; 106.35,97.82 106.35,99.25 106.91,99.81 106.91,100.99 v7(107.06,101.14)
  L4_SIG2 w0.114: v2(32,69.67) 33.02,69.67 33.5,70.15 33.5,72.52 35.41,74.42 38.84,74.42 40.78,76.37 40.78,78.07 41.94,79.22 42.88,79.22 47.86,84.21 52.44,84.21 52.7,83.95 53.31,83.95 54.46,85.09 58.58,85.09 64.62,91.13 64.62,100.94 70.72,107.04 70.72,120.5 v5(77.8,127.59) ; v5(104.26,93.58) 104.26,97.1 105.75,98.58 107.55,98.58 108.41,99.44 108.41,101.14 107.21,102.34 107.21,104.27 106.5,104.98 105.53,104.98 104.31,106.2 102.7,106.2 101.85,107.05 101.85,108.28 103.42,109.86 103.42,117.93 104.31,118.82 104.31,122.57 103.53,123.35 103.53,125.03 v5(104.04,125.53)
  L10_SIG4 w0.109: v5(109.03,89.06) 107.61,89.06 105.92,90.76 105.92,92.03 104.37,93.58 v5(104.26,93.58)
AM57XX_VOUT1_D0: length 25.5
  TOP w0.173: R605.2 v7(126.62,94.57) ; U1.F11 v4(109.43,84.81)
  L3_SIG1 w0.109: v7(126.62,94.57) 125.61,95.58 122.55,95.58 v5(121.79,94.82) ; v4(109.43,84.81) v5(109.83,85.06)
  L10_SIG4 w0.109: v5(121.79,94.82) 121.79,93.93 117.37,89.51 117.37,87.69 116.71,87.03 115.09,87.03 114.78,87.33 113.44,87.33 112.32,86.21 112.32,85.68 111.79,85.15 109.91,85.15 v5(109.83,85.06)
AM57XX_VOUT1_D1: length 27.5
  TOP w0.173: U1.G10 v4(108.63,85.61) ; R606.2 v7(126.62,95.59)
  L3_SIG1 w0.109: v4(108.63,85.61) v5(109.03,85.86) ; v5(121.28,94.44) 121.28,95.46 122.63,96.8 126.21,96.8 126.62,96.4 v7(126.62,95.59)
  L10_SIG4 w0.109: v5(109.03,85.86) 109.45,85.45 111.58,85.45 112.04,85.91 112.04,86.34 113.41,87.71 114.94,87.71 115.01,87.63 116.79,87.63 116.99,87.84 116.99,89.77 121.28,94.06 v5(121.28,94.44)
AM57XX_VOUT1_D2: length 34
  TOP w0.173: v7(133.73,100.54) 132.59,100.54 R607.2 ; U1.F10 v4(109.43,85.61)
  L3_SIG1 w0.109: v7(133.73,100.54) v5(127,100.54) ; v4(109.43,85.61) v5(109.83,85.86)
  L10_SIG4 w0.109: v5(109.83,85.86) 110.26,86.29 111.38,86.29 113.04,87.95 114.64,87.95 120.75,94.06 120.75,94.54 121.68,95.48 123.03,95.48 127,99.45 v5(127,100.54)
AM57XX_VOUT1_D3: length 30.5
  TOP w0.173: v7(133.73,84.89) 132.61,84.89 R608.2 ; U1.G11 v4(108.63,84.81)
  L3_SIG1 w0.109: v7(133.73,84.89) v5(134.47,84.89) ; v4(108.63,84.81) v5(109.03,85.06)
  L10_SIG4 w0.109: v5(134.47,84.89) 134.11,84.53 130.92,84.53 130.24,85.22 123.36,85.22 122.61,84.46 114.14,84.46 113.72,84.89 110.26,84.89 110.01,84.64 109.46,84.64 v5(109.03,85.06)
AM57XX_VOUT1_D4: length 28.6
  TOP w0.173: v7(133.73,88.35) 132.59,88.35 R609.2 ; U1.E9 v4(110.23,86.41)
  L3_SIG1 w0.099: 111.97,86.92 110.74,86.92 v4(110.23,86.41)
  L3_SIG1 w0.109: v7(133.73,88.35) 131.9,90.18 125.98,90.18 125.7,90.45 122.58,90.45 119.64,87.51 118.27,87.51 117.82,87.05 117.54,87.05 117.21,87.05 117.08,86.92 111.97,86.92
AM57XX_VOUT1_D5: length 36.4
  TOP w0.173: R910.2 133.78,101.85 v7(133.73,101.81) 132.59,101.81 R716.2 ; U1.F9 v4(109.43,86.41)
  L3_SIG1 w0.109: v5(128.65,101.3) 129.16,101.81 v7(133.73,101.81) ; v5(109.83,86.66) 109.83,86.67 109.44,86.42 v4(109.43,86.41)
  L10_SIG4 w0.109: v5(109.83,86.66) 111.35,86.66 112.9,88.22 114.4,88.22 120.32,94.14 120.32,94.59 121.59,95.86 122.94,95.86 126.44,99.37 126.44,100.74 126.68,100.98 128.33,100.98 v5(128.65,101.3)
AM57XX_VOUT1_D6: length 37.2
  TOP w0.173: R911.2 130.4,103.16 131.4,103.16 R612.2 132.59,103.08 v7(133.73,103.08) ; U1.F8 v4(109.43,87.21)
  L3_SIG1 w0.109: v4(109.43,87.21) 109.43,87.22 v5(109.83,87.46) ; v5(128.91,102.32) 129.67,103.08 v7(133.73,103.08)
  L10_SIG4 w0.109: v5(128.91,102.32) 127.94,101.35 126.57,101.35 126.03,100.82 126.03,99.45 122.88,96.3 121.54,96.3 119.96,94.72 119.96,94.26 114.3,88.6 112.78,88.6 111.64,87.46 v5(109.83,87.46)
AM57XX_VOUT1_D7: length 33.6
  TOP w0.173: v7(133.73,97.49) 132.59,97.49 R611.2 131.21,97.38 130.2,97.38 R908.2 ; U1.E7 v4(110.23,88.01)
  L3_SIG1 w0.109: v4(110.23,88.01) 110.74,88.52 111.62,88.52 111.62,88.52 114.22,88.52 115.1,89.4 117.3,89.4 117.43,89.54 117.49,89.54 117.88,89.54 122.61,94.26 124.89,94.26 125.4,93.76 127.46,93.76 128.78,95.08 129.46,95.08 129.84,95.46 131.7,95.46 v7(133.73,97.49)
AM57XX_VOUT1_D8: length 24
  TOP w0.173: U1.E8 v4(110.23,87.21) ; v7(129.16,92.16) 128.44,92.16 R613.2 R909.2
  L3_SIG1 w0.109: v7(129.16,92.16) 128.7,92.61 126.19,92.61 125.65,92.08 122.5,92.08 118.95,88.52 117.85,88.52 117.47,88.14 116.97,88.14 116.64,88.47 116.62,88.47 116.62,88.48 115.49,88.48 114.73,87.72 110.74,87.72 v4(110.23,87.21)
AM57XX_VOUT1_D9: length 21.2
  TOP w0.173: R614.2 v7(129.16,89.36) ; U1.D9 v4(111.03,86.41)
  L3_SIG1 w0.099: 112.05,86.71 111.33,86.71 v4(111.03,86.41)
  L3_SIG1 w0.109: 112.05,86.71 117.95,86.71 118.41,87.17 120.02,87.17 122.37,89.52 122.41,89.52 122.43,89.54 125.43,89.54 126.06,88.9 128.7,88.9 v7(129.16,89.36)
AM57XX_VOUT1_D10: length 28.4
  TOP w0.173: R712.2 132.59,95.59 v7(133.73,95.59) ; U1.D7 v4(111.03,88.01)
  L3_SIG1 w0.099: 112.04,88.31 111.71,88.31 111.42,88.01 v4(111.03,88.01)
  L3_SIG1 w0.109: v7(133.73,95.59) 132.13,93.98 128.73,93.98 128.1,93.35 122.48,93.35 118.33,89.2 117.63,89.2 117.57,89.2 117.44,89.06 115.22,89.06 114.46,88.31 112.04,88.31
AM57XX_VOUT1_D11: length 27.7
  TOP w0.173: v7(133.73,92.16) 132.59,92.16 R719.2 ; U1.D8 v4(111.03,87.21)
  L3_SIG1 w0.099: v4(111.03,87.21) 111.33,87.51 111.83,87.51 111.96,87.51
  L3_SIG1 w0.109: 111.96,87.51 111.96,87.51 116.69,87.51 116.91,87.73 117.54,87.73 117.99,88.18 119.09,88.18 122.63,91.72 125.45,91.72 125.48,91.69 127.56,91.69 127.93,91.32 129.08,91.32 129.92,92.16 v7(133.73,92.16)
AM57XX_VOUT1_D12: length 14.5
  TOP w0.173: R720.2 123.95,95.71 122.78,95.71 117.95,90.88 115.93,90.88 114.26,89.21 U1.A5
AM57XX_VOUT1_D13: length 31.3
  TOP w0.173: R721.2 132.59,98.76 v7(133.73,98.76) 133.78,98.81 R906.2 ; U1.C6 v4(111.83,88.81)
  L3_SIG1 w0.109: v4(111.83,88.81) 112.1,88.81 113.01,89.72 117.06,89.72 117.39,90.05 117.63,90.05 122.2,94.62 125.3,94.62 125.81,94.11 127.13,94.11 128.3,95.28 128.3,95.66 129.69,97.06 132.03,97.06 v7(133.73,98.76)
AM57XX_VOUT1_D14: length 29
  TOP w0.173: R722.2 132.59,90.89 v7(133.73,90.89) 133.78,90.93 R907.2 ; U1.C8 v4(111.83,87.21)
  L3_SIG1 w0.109: v4(111.83,87.21) 116.88,87.21 117.06,87.39 117.68,87.39 118.13,87.85 119.49,87.85 122.45,90.81 125.95,90.81 126.19,90.58 133.42,90.58 v7(133.73,90.89)
AM57XX_VOUT1_D15: length 27.1
  TOP w0.173: U1.C7 v4(111.83,88.01) ; R618.2 132.59,94.32 v7(133.73,94.32)
  L3_SIG1 w0.109: v4(111.83,88.01) 114.6,88.01 115.31,88.73 117.58,88.73 117.71,88.86 118.5,88.86 122.63,92.99 128.68,92.99 129.11,93.43 132.84,93.43 v7(133.73,94.32)
AM57XX_VOUT1_D16: length 15.4
  TOP w0.173: U1.B7 112.64,88.02 113.63,88.02 115.97,90.35 118.61,90.35 122.7,94.44 123.95,94.44 124.59,95.08
AM57XX_VOUT1_D17: length 14.7
  TOP w0.173: 124.59,92.54 123.95,91.9 122.68,91.9 120.08,89.3 116.03,89.3 113.94,87.21 112.63,87.21 U1.B8
AM57XX_VOUT1_D18: length 14.1
  TOP w0.173: U1.A7 113.78,87.62 115.98,89.82 119.35,89.82 122.7,93.17 123.95,93.17 R713.2
AM57XX_VOUT1_D19: length 13.4
  TOP w0.173: U1.A8 114.08,86.81 116.03,88.77 120.82,88.77 122.68,90.63 123.95,90.63 R724.2
AM57XX_VOUT1_D20: length 28.7
  TOP w0.173: v7(133.73,86.19) 132.59,86.19 R625.2 ; U1.C9 v4(111.83,86.41)
  L3_SIG1 w0.109: v7(133.73,86.19) 133.73,87.33 131.52,89.54 130.02,89.54 129.03,88.55 125.68,88.55 125.04,89.18 122.51,89.18 120.16,86.83 118.55,86.83 118.01,86.3 115.24,86.3 115.09,86.44 113.25,86.44 113.02,86.21 112.04,86.21 v4(111.83,86.41)
AM57XX_VOUT1_D21: length 12.7
  TOP w0.173: U1.A9 114.4,86.02 116.1,87.71 122.19,87.71 122.62,88.14 124,88.14 R726.2
AM57XX_VOUT1_D22: length 14
  TOP w0.173: U1.B9 112.63,86.41 114.25,86.41 116.07,88.24 121.56,88.24 122.68,89.36 123.95,89.36 R727.2
AM57XX_VOUT1_D23: length 12.5
  TOP w0.173: R728.2 124.03,86.9 122.52,86.9 122.08,86.46 115.96,86.46 114.72,85.21 U1.A10
AM57XX_VOUT1_FLD: length 8.1
  TOP w0.173: R564.1 115.93,85.81 114.94,84.81 112.63,84.81 U1.B11
AM574X_DCAN1_RX: length 127.8
  TOP w0.173: U1.G19 v4(108.63,77.62)
  L3_SIG1 w0.109: v4(108.63,77.62) v5(109.03,77.37)
  L4_SIG2 w0.114: v5(109.03,77.37) 109.42,77.75 116.15,77.75 118.24,79.84 118.24,81 119.85,82.61 122.11,82.61 122.48,82.25 125.62,82.25 129.69,86.32 129.69,86.97 130.39,87.67 133.57,87.67 138.11,83.14 155.58,83.14 160.36,78.35 160.36,77.81 166.59,71.58 168.78,71.58 171.78,68.58 171.78,62.36 174.75,59.39 174.75,36.58 174.12,35.94 174.12,23.32 v2(173.23,22.43)
  BOTTOM w0.173: R502.1 C253.1 173.21,22.45 v2(173.23,22.43)
AM574X_DCAN1_TX: length 128.5
  TOP w0.173: U1.G20 v4(108.63,76.82)
  L3_SIG1 w0.109: v4(108.63,76.82) v5(109.03,76.57)
  L4_SIG2 w0.114: v5(109.03,76.57) 109.42,76.95 111.27,76.95 111.56,76.66 113.63,76.66 113.99,77.01 115.92,77.01 118.62,79.71 118.62,80.97 119.91,82.25 121.5,82.25 121.82,81.94 125.73,81.94 129.98,86.19 129.98,86.44 129.98,86.64 130.61,87.26 133.29,87.26 138.05,82.5 153.8,82.5 157.02,79.28 157.02,78.68 157.32,78.38 157.61,78.38 168.34,67.65 169.1,67.65 171.2,65.55 171.2,62.18 173.23,60.15 173.23,55.24 173.71,54.76 173.71,33.87 172.79,32.95 172.79,19.32 v5(173.36,18.75)
  L10_SIG4 w0.109: v9(173.36,19.51) v5(173.36,18.75)
  BOTTOM w0.173: v5(173.36,18.75) v9(173.36,19.51)
AM574X_HAPTICS_TRIG: length 135.8
  TOP w0.173: v2(140.72,9.78) 141.1,10.16 R114.1 ; v7(130.05,62.27) 122.9,62.27 122.4,62.77 122.4,66.91 121.75,67.56 121.75,67.84 121.4,68.19 119.36,68.19 114.33,73.21 U1.A25
  L3_SIG1 w0.109: v7(130.05,62.27) 130.29,62.03 131.05,62.03 133.6,64.58 133.6,66.25 135.51,68.15 142.88,68.15 145.71,70.99 153.8,70.99 170.69,54.1 170.69,42.39 159.24,30.94 156.27,30.94 144.65,19.33 144.65,13.72 v2(140.72,9.78)
AM574X_HDMI_CEC: length 203.1
  TOP w0.173: v2(68.81,24.93) 69.47,24.27 R683.2 ; U1.B20 112.64,76.81 113.2,76.81 113.2,76.81 114.37,76.81 119.33,71.86 120.29,71.86 120.78,72.34 122.1,72.34 122.73,71.71 124.89,71.71 125.09,71.91 125.81,71.91 126.82,70.9 128.88,70.9 129.06,71.07 v7(130.18,71.07) R805.1
  L3_SIG1 w0.109: v7(130.18,71.07) v5(130.18,71.66)
  L4_SIG2 w0.114: v5(64.01,17.18) 65.3,17.18 65.89,16.59 87.52,16.59 87.99,16.12 102.5,16.12 103.15,16.77 103.79,16.77 104.37,16.19 111.06,16.19 111.64,16.77 115.71,16.77 116.52,15.96 127.16,15.96 141.48,30.28 146.23,30.28 147.72,31.77 155.86,31.77 158.97,34.88 158.97,42.32 159.86,43.21 159.86,48.23 161.95,50.32 161.95,56.85 159,59.79 159,62.78 149.09,72.7 144.51,72.7 142.29,74.93 135.02,74.93 134.35,74.26 132.77,74.26 v5(130.18,71.66)
  L9_SIG3 w0.114: v2(68.81,24.93) 68.81,21.98 v5(64.01,17.18)
AM574X_HDMI_DDC_SCL: length 303.5
  TOP w0.173: v7(123.01,64.84) 123.2,64.84 R556.1 ; v4(111.83,72.82) U1.C25
  L3_SIG1 w0.099: v4(111.83,72.82) 111.88,72.77 113.05,72.77 113.06,72.79
  L3_SIG1 w0.109: v5(132.59,65.23) 132.59,64.06 131.04,62.51 130.45,62.51 130.03,62.93 129.65,62.93 129.41,62.69 125.15,62.69 v7(123.01,64.84) 121.25,64.84 117.7,68.38 117.7,70.29 115.2,72.79 113.06,72.79
  L4_SIG2 w0.114: v2(67.87,22.46) 69.38,20.95 88.05,20.95 89.09,21.99 128.59,21.99 139.26,32.66 144.08,32.66 145.45,34.03 151.19,34.03 156.79,39.63 156.79,48.89 157.87,49.96 157.87,51.2 157.65,51.42 157.65,56.59 153.27,60.97 153.27,62.37 147.66,67.98 134.58,67.98 132.59,65.99 v5(132.59,65.23)
  L9_SIG3 w0.114: v2(56.64,107.47) 56.64,100.84 59.18,98.3 59.18,94.87 60.02,94.03 60.02,86.61 54.71,81.3 54.71,72.62 49.57,67.49 48.66,67.49 44.72,63.55 44.72,62.48 42.26,60.03 42.26,58.06 39.67,55.47 39.67,54.69 37.85,52.86 37.85,27.15 40.59,24.41 46.89,24.41 48.26,25.78 49.53,25.78 50.29,25.02 61.39,25.02 63.32,23.09 67.23,23.09 v2(67.87,22.46)
  BOTTOM w0.173: v2(67.87,22.46) 68.33,22 R795.2 ; R358.2 v2(56.64,107.47)
AM574X_HDMI_DDC_SDA: length 345.7
  TOP w0.173: U1.F17 v4(109.43,79.22) ; R563.1 v2(126.62,66.88)
  L3_SIG1 w0.109: v4(109.43,79.22) v5(109.83,78.97)
  L4_SIG2 w0.114: v2(126.62,66.88) 127.23,66.27 131.5,66.27 134.9,69.68 140.72,69.68 141.92,68.48 148.39,68.48 149.08,67.79 150.01,67.79 150.39,67.41 150.39,66.6 151.64,65.36 153.65,65.36 156.49,62.52 156.49,59.03 158.43,57.09 158.43,55.14 159.18,54.39 159.18,52.52 158.46,51.8 158.46,49.66 157.48,48.68 157.48,35.46 155.69,33.67 145.7,33.67 144.34,32.3 139.67,32.3 127.83,20.46 125.17,20.46 124.67,20.96 110.78,20.96 110.01,20.19 108.5,20.19 107.98,20.71 95.09,20.71 93.81,19.42 92.12,19.42 90.89,20.66 67.56,20.66 65.66,22.56 v2(65.66,24.64) ; v5(109.83,78.97) 110.21,78.59 116.23,78.59 117.84,80.2 117.84,81.01 119.73,82.91 122.43,82.91 122.67,82.66 125.51,82.66 125.75,82.91 125.78,82.91 129.4,86.53 129.4,87.33 130.07,88 134.83,88 v5(136.35,86.48)
  L9_SIG3 w0.114: v2(58.65,106.63) 58.65,99.73 59.64,98.74 59.64,95.43 60.4,94.67 60.4,86.36 55.11,81.07 55.11,72.49 49.73,67.11 48.82,67.11 45.1,63.39 45.1,62.32 42.65,59.87 42.65,57.9 40.06,55.31 40.06,54.53 38.25,52.73 38.25,27.64 41.05,24.84 46.69,24.84 48.41,26.57 49.89,26.57 51.05,25.4 63.3,25.4 64.05,24.64 v2(65.66,24.64) ; v5(136.35,86.48) 136.35,85.37 134.38,83.41 134.38,80.62 126.62,72.85 v2(126.62,66.88)
  BOTTOM w0.173: v2(65.66,24.64) R796.2 ; R356.2 v2(58.65,106.63)
AM574X_HDMI_HPD: length 203.7
  TOP w0.173: v7(130.18,69.55) R804.1 129.87,68.48 126.54,68.48 126.01,69.02 126.01,69.45 125.37,70.08 122.53,70.08 122,70.62 119.49,70.62 114.1,76.02 112.63,76.02 U1.B21 ; R682.2 v2(67.69,24.26)
  L3_SIG1 w0.109: v7(130.18,69.55) v5(130.18,68.94)
  L4_SIG2 w0.114: v5(63.5,18.1) 64.79,18.1 65.96,16.93 88.48,16.93 89.03,17.48 91.31,17.48 92.2,16.59 102.23,16.59 102.71,17.06 104.8,17.06 105.38,16.48 110.94,16.48 111.52,17.06 116.37,17.06 116.57,16.86 118.64,16.86 118.83,17.05 119.93,17.05 120.12,16.86 124.63,16.86 124.92,17.15 127.8,17.15 141.41,30.76 145.96,30.76 147.39,32.18 155.86,32.18 158.67,35 158.67,42.59 159.57,43.48 159.57,48.44 161.65,50.51 161.65,56.54 157.78,60.4 157.78,63.59 149.06,72.31 144.11,72.31 141.78,74.64 136.14,74.64 131.66,70.16 130.86,70.16 130.18,69.47 v5(130.18,68.94)
  L9_SIG3 w0.114: v2(67.69,24.26) 68.38,23.57 68.38,22.1 64.38,18.1 v5(63.5,18.1)
AM574X_QSPI_CLK: length 8
  TOP w0.173: R24.2 101.98,96.88 101.44,96.33 101.44,92.01 U1.R2
AM574X_QSPI_CSN: length 51.6
  TOP w0.173: R30.2 91.69,125.3 89.95,125.3 88.9,124.26 88.9,122.28 87.68,121.06 87.68,112.81 v7(88.19,112.3) ; U1.P2 103.03,92.01 103.03,95.33 103.76,96.05 103.76,98.86 104.01,99.12 104.01,101.05 104.44,101.48 104.44,106.91 v7(104.47,106.94)
  L3_SIG1 w0.109: v7(88.19,112.3) 89.26,112.3 90.4,111.16 95.55,111.16 98.32,108.39 103.4,108.39 104.22,107.57 104.22,107.19 v7(104.47,106.94)
AM574X_QSPI_D0: length 16.5
  TOP w0.173: R25.2 98.68,97.49 100.24,95.93 U1.U1
AM574X_QSPI_D1: length 44
  TOP w0.173: R26.2 90.27,123.88 90.27,122.73 88.9,121.36 v2(88.9,116.67) ; U1.P3 v4(103.03,91.21)
  L3_SIG1 w0.099: 102.9,91.35 102.9,94.1 102.85,94.14 102.85,94.88 103.22,95.25 103.22,97.08 103.89,97.75
  L3_SIG1 w0.109: v4(103.03,91.21) 102.9,91.35 ; 103.89,97.75 103.89,98.88 102.46,100.31 102.46,101.25 102.08,101.63 100.73,101.63 98.27,104.09 97.1,104.09 95.35,105.85 94.77,105.85 93.98,106.63 v5(93.22,106.63)
  L4_SIG2 w0.114: v5(93.22,106.63) 92.59,107.26 92.32,107.26 91.51,108.07 91.51,112.3 89.66,114.15 89.66,115.91 v2(88.9,116.67)
AM574X_QSPI_D2: length 22.9
  TOP w0.173: U1.U2 99.83,92.02 99.83,95.41 98.04,97.21 98.04,104.75 95.48,107.32 91.34,107.32 91.06,107.6 R27.2
AM574X_QSPI_D3: length 35.1
  TOP w0.173: U1.T2 100.64,92.01 100.64,96.44 99.64,97.43 99.64,104.91 99.34,105.21 99.34,118.47 100.82,119.95 100.82,121.85 101.98,123.02 101.98,124.03 R28.2
AM574X_QSPI_RTCLK: length 23
  TOP w0.173: U1.R3 102.23,91.21 102.23,95.98 102.74,96.49 102.74,101.05 101.02,102.77 101.02,105.25 100.56,105.7 100.56,109.66 101.85,110.96 R23.2
AM574X_USB1_3_0_STDA_SSTX+: length 105.2
  TOP w0.15: U1.AD11 v4(94.24,84.81)
  L3_SIG1 w0.109: v4(94.24,84.81) 94.23,84.81 93.67,84.81 arc(92.62,85.02) 91.73,85.61 90.26,87.08 arc(89.45,87.62) 88.5,87.81 87.9,87.81 arc(87.78,87.86) 87.73,87.99 arc(87.68,88.11) 87.55,88.16 87.47,88.16 arc(87.34,88.11) 87.29,87.99 arc(87.24,87.86) 87.12,87.81 83.33,87.81 arc(83.07,87.86) 82.84,88.01 arc(82.5,88.24) 82.09,88.32 77.54,88.32 arc(76.8,88.18) 76.18,87.76 75.99,87.57 arc(75.44,87.2) 74.78,87.07 68.02,87.07 arc(67.32,86.93) 66.72,86.54 59.64,79.45 arc(59.25,78.86) 59.11,78.16 59.11,68.42 arc(58.99,67.86) 58.68,67.39 52.19,60.9 arc(51.78,60.29) 51.64,59.57 51.64,55.7 arc(51.5,55) 51.1,54.4 40.04,43.34 arc(39.71,42.85) 39.59,42.26 39.59,28.79 arc(39.31,27.92) 38.57,27.38 38.39,27.33 arc(37.34,26.55) 36.93,25.31 arc(36.89,25.05) v2(36.78,24.81)
  BOTTOM w0.15: v2(36.78,24.81) 36.87,24.69 arc(36.92,24.6) 36.93,24.51 36.93,24.21 arc(36.83,23.96) C555.1
AM574X_USB1_3_0_STDA_SSTX-: length 105.1
  TOP w0.15: U1.AC11 v4(95.04,84.81)
  L3_SIG1 w0.109: v2(37.39,24.81) arc(37.28,25.05) 37.24,25.31 arc(37.58,26.38) 38.49,27.04 38.67,27.09 arc(39.56,27.74) 39.9,28.79 39.9,42.26 arc(39.99,42.73) 40.25,43.13 51.32,54.19 arc(51.78,54.88) 51.94,55.7 51.94,59.57 arc(52.06,60.17) 52.41,60.69 58.89,67.17 arc(59.28,67.75) 59.41,68.42 59.41,78.16 arc(59.53,78.74) 59.86,79.24 66.94,86.32 arc(67.43,86.65) 68.02,86.77 74.78,86.77 arc(75.55,86.92) 76.2,87.35 76.39,87.54 arc(76.92,87.9) 77.54,88.02 82.09,88.02 arc(82.38,87.96) 82.63,87.8 arc(82.95,87.58) 83.33,87.51 88.5,87.51 arc(89.34,87.34) 90.04,86.87 91.51,85.4 arc(92.5,84.74) 93.67,84.51 94.29,84.51 arc(94.69,84.59) v4(95.04,84.81)
  BOTTOM w0.15: v2(37.39,24.81) arc(37.32,24.67) 37.29,24.52 37.29,24.16 arc(37.38,23.95) C554.1
AM574X_USB1_DM: length 97.1
  TOP w0.15: U1.AC12 95.22,83.4 95.22,83.2 v4(95.22,83.2)
  L3_SIG1 w0.109: v2(45.42,26.07) 45.57,26.23 45.57,26.67 43.76,28.48 43.76,40.08 49.43,45.74 49.43,47.57 56.18,54.33 56.18,60.27 65.38,69.47 65.38,70.64 66.14,71.4 66.14,77.49 71.28,82.63 76.01,82.63 79.28,85.9 81.01,85.9 81.67,85.24 84.58,85.24 84.72,85.1 88.92,85.1 89.97,84.05 91.08,84.05 91.55,83.59 93.62,83.59 93.87,83.84 94.64,83.84 95.22,83.25 v4(95.22,83.2)
  BOTTOM w0.15: L11.1 45.32,25.25 45.57,25.5 45.57,25.92 v2(45.42,26.07)
AM574X_USB1_DP: length 96.5
  TOP w0.15: v4(94.83,83.21) 94.83,83.42 U1.AD12
  L3_SIG1 w0.109: v2(46.02,26.07) 45.87,26.23 45.87,26.8 44.07,28.6 44.07,39.95 49.73,45.62 49.73,47.45 56.49,54.2 56.49,60.15 65.68,69.34 65.68,70.43 66.5,71.25 66.5,77.41 71.4,82.32 76.14,82.32 79.41,85.6 80.88,85.6 81.54,84.94 82.37,84.94 82.5,84.81 82.83,84.81 82.95,84.94 83.28,84.94 83.41,84.81 83.73,84.81 83.86,84.94 84.46,84.94 84.6,84.79 86.28,84.79 86.39,84.68 86.72,84.68 86.83,84.79 87.15,84.79 87.27,84.68 87.59,84.68 87.7,84.79 88.03,84.79 88.14,84.68 88.47,84.68 88.58,84.79 88.8,84.79 89.84,83.75 90.96,83.75 91.42,83.28 93.75,83.28 94,83.53 94.51,83.53 v4(94.83,83.21)
  BOTTOM w0.15: L11.2 46.12,25.25 45.87,25.5 45.87,25.92 v2(46.02,26.07)
AM574X_USB1_DRVVBUS: length 50.8
  TOP w0.102: 85.98,90.51 v2(85.46,89.99)
  TOP w0.173: R979.1 v1(42.7,79.87) ; U1.AB10 v4(95.84,85.61) ; R557.2 85.98,90.51
  L3_SIG1 w0.109: v4(95.84,85.61) v5(95.44,85.86) ; v2(85.46,89.99) 85.46,89.99 85.24,89.77 84.18,89.77 83.37,90.58 78.69,90.58 78.2,91.07 77.35,91.07 76.7,90.41 74.33,90.41 73.36,89.43 63.7,89.43 58.67,84.4 54.38,84.4 49.85,79.87 v1(42.7,79.87)
AM574X_USB2_DM: length 114.1
  TOP w0.15: v4(92.71,85.49) 92.71,85.2 93.04,84.88 U1.AF11
  L3_SIG1 w0.109: v2(12.07,41.17) 12.07,41.49 13.51,42.93 17.82,42.93 18.86,43.96 24.14,43.96 26.49,46.31 31.83,46.31 36.09,50.57 40.34,50.57 46.53,56.77 46.53,60.02 52.81,66.29 52.81,68.02 56.46,71.68 56.46,78.83 66.23,88.6 73.73,88.6 74.85,89.71 78.11,89.71 78.33,89.94 83.19,89.94 84.24,88.88 87.56,88.88 87.73,89.05 90.01,89.05 91.29,87.77 91.29,86.94 92.71,85.51 v4(92.71,85.49)
  BOTTOM w0.15: v2(12.07,41.17) 11.74,41.17 11.3,40.73 10.5,40.73 10.27,40.49 L33.2
AM574X_USB2_DP: length 114.7
  TOP w0.15: v4(93.1,85.49) 93.1,85.25 93.34,85.01 93.34,84.91 U1.AE11
  L3_SIG1 w0.109: v4(93.1,85.49) 93.1,85.56 91.59,87.07 91.59,87.9 90.13,89.35 87.6,89.35 87.43,89.19 84.35,89.19 83.29,90.24 78.21,90.24 77.98,90.02 74.72,90.02 73.61,88.9 66.11,88.9 56.16,78.95 56.16,71.8 52.5,68.15 52.5,66.42 46.23,60.15 46.23,56.9 40.21,50.88 35.97,50.88 31.71,46.62 26.36,46.62 24.01,44.27 18.73,44.27 17.7,43.23 13.39,43.23 11.83,41.68 v2(11.56,41.68)
  BOTTOM w0.15: L33.1 10.27,41.29 10.51,41.05 11.16,41.05 11.56,41.46 v2(11.56,41.68)
AM574X_USB2_DRVVBUS: length 48.8
  TOP w0.173: v2(84.23,88.29) 84.2,88.27 R787.2 82.8,87.63 82.14,87.63 81.65,88.12 81.65,89.04 80.22,90.47 79.03,90.47 77.94,91.56 v7(75.33,91.56) ; U1.AC10 v4(95.04,85.61)
  TOP w0.381: R972.1 v1(56.17,80.98)
  L3_SIG1 w0.109: v4(95.04,85.61) 95.03,85.61 v5(94.64,85.86) ; v7(75.33,91.56) v5(74.7,91.56)
  L4_SIG2 w0.114: v5(74.7,91.56) 72.62,89.48 65.91,89.48 57.41,80.98 v1(56.17,80.98)
  L10_SIG4 w0.109: v5(94.64,85.86) 94.23,86.27 94.23,86.51 93.8,86.95 92.16,86.95 91.6,86.39 86.13,86.39 v2(84.23,88.29)
AM574X_VIN4B_DATA0: length 110.1
  TOP w0.173: U1.R6 v4(101.44,88.81) ; R260.2 v2(160.78,143.34)
  L3_SIG1 w0.099: 101.94,91.48 101.94,89.32 v4(101.44,88.81)
  L3_SIG1 w0.109: v5(101.65,95.18) 100.91,94.44 100.91,92.82 101.94,91.79 101.94,91.48
  L4_SIG2 w0.114: v2(160.78,143.34) 159.46,142.02 155.96,142.02 155.65,141.71 155.65,138.73 155.48,138.56 154.14,138.56 153.97,138.39 153.97,138.16 154.14,137.99 155.48,137.99 155.65,137.82 155.65,137.58 155.48,137.42 154.14,137.42 153.97,137.25 153.97,137.01 154.14,136.84 155.48,136.84 155.65,136.68 155.65,136.14 153.16,133.65 v5(153.16,131.4)
  L10_SIG4 w0.109: v5(153.16,131.4) 154.74,129.82 154.74,120.12 153.92,119.3 153.92,117.18 145.38,108.63 145.08,108.63 142.24,105.8 133.22,105.8 131.85,104.42 126.36,104.42 123.62,101.68 123.62,99.43 122.16,97.97 120.7,97.97 119.48,96.75 119.48,96.75 118.91,96.19 116.5,96.19 116.25,96.44 113.63,96.44 112.46,95.27 105.11,95.27 104.83,95.55 102.02,95.55 v5(101.65,95.18)
AM574X_VIN4B_DATA1: length 113.4
  TOP w0.173: U1.T9 v4(100.64,86.41) ; R261.2 v2(164.11,132.29)
  L3_SIG1 w0.109: v4(100.64,86.41) 100.24,86.66 v5(100.24,86.66)
  L4_SIG2 w0.114: v5(149.1,126.7) 149.73,126.7 152.27,129.24 153.42,129.24 154.31,130.13 156.64,130.13 156.88,130.37 156.88,131.18 157,131.3 157.23,131.3 157.34,131.18 157.34,130.37 157.45,130.26 157.68,130.26 157.8,130.37 157.8,131.18 157.91,131.3 158.14,131.3 158.25,131.18 158.25,130.37 158.37,130.26 158.6,130.26 158.71,130.37 158.71,131.18 158.83,131.3 159.05,131.3 159.17,131.18 159.17,130.37 159.28,130.26 159.51,130.26 159.63,130.37 159.63,131.18 159.74,131.3 159.97,131.3 160.08,131.18 160.08,130.37 160.2,130.26 160.43,130.26 160.54,130.37 160.54,131.18 160.65,131.3 160.88,131.3 161,131.18 161,130.37 161.11,130.26 161.34,130.26 161.45,130.37 161.45,131.18 161.57,131.3 161.8,131.3 161.91,131.18 161.91,130.37 162.03,130.26 162.25,130.26 162.37,130.37 162.37,131.18 162.48,131.3 162.71,131.3 162.83,131.18 162.83,130.37 162.94,130.26 163.86,130.26 164.11,130.51 v2(164.11,132.29)
  L10_SIG4 w0.109: v5(100.24,86.66) 100.63,87.06 100.63,100.59 102.18,102.14 112.42,102.14 112.65,101.91 113.08,101.91 114.22,103.05 114.22,106.38 120.83,112.99 131.01,112.99 133.83,110.17 137.07,110.17 148.41,121.51 148.41,126.01 v5(149.1,126.7)
AM574X_VIN4B_DATA2: length 113.5
  TOP w0.173: U1.T6 v4(100.64,88.81) ; R263.2 v2(166.65,132.29)
  L3_SIG1 w0.099: 100.93,91.24 100.93,89.11 v4(100.64,88.81)
  L3_SIG1 w0.109: v5(101.6,98.76) 100.74,97.9 100.74,96.7 100,95.97 100,92.38 100.93,91.46 100.93,91.24
  L4_SIG2 w0.114: v2(166.65,132.29) 166.65,129.06 165.25,127.67 164.86,127.67 164.75,127.78 164.75,128.24 164.63,128.35 164.4,128.35 164.29,128.24 164.29,127.78 164.17,127.67 163.95,127.67 163.83,127.78 163.83,128.24 163.72,128.35 163.49,128.35 163.37,128.24 163.37,127.78 163.26,127.67 163.03,127.67 162.92,127.78 162.92,128.24 162.8,128.35 162.57,128.35 162.46,128.24 162.46,127.78 162.35,127.67 161.71,127.67 161.6,127.55 161.6,126.99 161.49,126.88 161.26,126.88 161.14,126.99 161.14,127.55 161.03,127.67 160.8,127.67 160.69,127.55 160.69,126.99 160.57,126.88 160.34,126.88 160.23,126.99 160.23,127.55 160.11,127.67 159.89,127.67 159.77,127.55 159.77,126.99 159.66,126.88 159.43,126.88 159.31,126.99 159.31,127.55 159.2,127.67 158.97,127.67 158.86,127.55 158.86,126.99 158.74,126.88 158.51,126.88 158.4,126.99 158.4,127.55 158.28,127.67 158.06,127.67 157.94,127.55 157.94,126.99 157.83,126.88 157.6,126.88 157.48,126.99 157.48,127.55 157.37,127.67 157.14,127.67 157.03,127.55 157.03,126.99 156.91,126.88 156.68,126.88 156.57,126.99 156.57,127.55 156.46,127.67 155.24,127.67 154.36,126.78 153.16,126.78 152.81,126.42 151.92,126.42 v5(151.38,126.96)
  L10_SIG4 w0.109: v5(101.6,98.76) 101.6,99.6 103.12,101.12 111.97,101.12 112.2,100.89 113.56,100.89 115.71,103.04 118.46,103.04 119.48,104.07 119.48,106 125.46,111.98 130.52,111.98 133.35,109.15 139.17,109.15 141.1,111.07 141.1,111.68 148.56,119.15 149.21,119.15 151.62,121.56 151.62,123.8 150.62,124.79 150.62,125.48 151.38,126.23 v5(151.38,126.96)
AM574X_VIN4B_DATA3: length 113.4
  TOP w0.173: R267.2 v2(174.27,132.29) ; U1.T7 v4(100.64,88.01)
  L3_SIG1 w0.099: 101.14,91.4 101.14,88.91 100.64,88.4 v4(100.64,88.01)
  L3_SIG1 w0.109: 101.14,91.4 101.14,91.57 100.23,92.49 100.23,95.79 101.14,96.7 101.14,97.54 v5(101.6,98)
  L4_SIG2 w0.114: v2(174.27,132.29) 173.36,131.37 173.36,127.84 171.39,125.88 171.23,125.88 170.69,126.42 170.53,126.42 170.37,126.25 170.37,126.09 170.91,125.56 170.91,125.39 170.74,125.23 170.58,125.23 170.05,125.77 169.88,125.77 169.72,125.61 169.72,125.45 170.26,124.91 170.26,124.75 169.75,124.24 165.99,124.24 165.61,123.86 152.83,123.86 v5(152.02,124.67)
  L10_SIG4 w0.109: v5(101.6,98) 102.03,98.43 102.03,99.55 103.2,100.72 108.94,100.72 109.57,100.08 111.87,100.08 112.07,99.87 112.56,99.87 113.15,100.46 113.61,100.46 114.45,101.3 116.84,101.3 117.68,102.14 118.4,102.14 119.89,103.63 119.89,105.92 125.6,111.64 130.25,111.64 133.07,108.81 140.06,108.81 142.39,111.14 142.39,112.1 148,117.7 148.95,117.7 149.36,118.11 149.36,118.69 151.92,121.26 151.92,122.89 152.02,122.99 v5(152.02,124.67)
AM574X_VIN4B_DATA4: length 112.2
  TOP w0.173: U1.P6 v4(103.03,88.81) ; R269.2 v2(176.81,132.29)
  L3_SIG1 w0.099: v4(103.03,88.81) 102.15,89.7 102.15,91.54
  L3_SIG1 w0.109: 102.15,91.54 102.15,91.94 101.14,92.94 101.14,94.12 102.13,95.11 102.13,98.91 v5(102.49,99.27)
  L4_SIG2 w0.114: v2(176.81,132.29) 176.02,132.29 174.24,130.51 174.24,126.98 169.98,122.71 163.65,122.71 163.04,122.1 152.97,122.1 v5(152.36,122.71)
  L10_SIG4 w0.109: v5(102.49,99.27) 108.43,99.27 109.05,98.65 110.64,98.65 111.15,99.17 112.42,99.17 113.03,99.78 113.41,99.78 114.58,100.94 116.97,100.94 117.8,101.78 119.34,101.78 120.42,102.87 120.42,105.98 125.74,111.3 130.08,111.3 133.53,107.85 140.52,107.85 142.85,110.18 142.85,111.61 146.51,115.27 149.1,115.27 150.7,116.87 150.7,119.55 152.36,121.21 v5(152.36,122.71)
AM574X_VIN4B_DATA5: length 115.4
  TOP w0.173: R271.2 v2(179.35,132.29) ; U1.R9 v4(101.44,86.41)
  L3_SIG1 w0.109: v4(101.44,86.41) v5(101.04,86.66)
  L4_SIG2 w0.114: v2(179.35,132.29) 179.35,131.2 169.67,121.52 151.5,121.52 v5(149.89,123.13)
  L10_SIG4 w0.109: v5(101.04,86.66) 101.42,87.05 101.42,89.1 100.96,89.56 100.96,91.45 101,91.49 101,100.66 102.14,101.8 112.27,101.8 112.5,101.57 113.22,101.57 114.58,102.92 114.58,106.29 120.94,112.65 130.84,112.65 133.66,109.83 138.48,109.83 139.5,110.85 139.5,112.07 148.67,121.24 149.05,121.24 149.58,121.77 149.58,122.82 v5(149.89,123.13)
AM574X_VIN4B_DATA6: length 109.6
  TOP w0.173: U1.R5 v4(101.44,89.61) ; R262.1 v2(165.38,132.29)
  L3_SIG1 w0.099: 101.73,91.43 101.73,89.91 v4(101.44,89.61)
  L3_SIG1 w0.109: 101.73,91.43 101.73,91.65 100.69,92.69 100.69,95.18 v5(101.73,96.22)
  L4_SIG2 w0.114: v5(153.65,127.24) 153.65,128.09 153.9,128.35 155.47,128.35 156.15,129.03 158.17,129.03 158.29,129.14 158.29,129.74 158.4,129.85 158.63,129.85 158.75,129.74 158.75,129.14 158.86,129.03 159.09,129.03 159.2,129.14 159.2,129.74 159.32,129.85 159.55,129.85 159.66,129.74 159.66,129.14 159.77,129.03 160,129.03 160.12,129.14 160.12,129.74 160.23,129.85 160.46,129.85 160.57,129.74 160.57,129.14 160.69,129.03 160.92,129.03 161.03,129.14 161.03,129.74 161.15,129.85 161.37,129.85 161.49,129.74 161.49,129.14 161.6,129.03 161.83,129.03 161.95,129.14 161.95,129.74 162.06,129.85 162.29,129.85 162.4,129.74 162.4,129.14 162.52,129.03 162.75,129.03 162.86,129.14 162.86,129.74 162.97,129.85 163.2,129.85 163.32,129.74 163.32,129.14 163.43,129.03 163.66,129.03 163.77,129.14 163.77,129.74 163.89,129.85 164.12,129.85 164.23,129.74 164.23,129.28 164.49,129.03 165.13,129.03 165.38,129.28 165.38,129.93 165.49,130.04 165.95,130.04 166.07,130.16 166.07,130.39 165.95,130.5 165.49,130.5 165.38,130.62 165.38,130.84 165.49,130.96 165.95,130.96 166.07,131.07 166.07,131.3 165.95,131.42 165.49,131.42 165.38,131.53 v2(165.38,132.29)
  L10_SIG4 w0.109: v5(153.65,127.24) 154.1,126.78 154.1,119.99 153.54,119.43 153.54,117.27 145.24,108.97 144.94,108.97 142.17,106.2 131.73,106.2 130.4,104.88 126.34,104.88 123.22,101.75 123.22,99.5 122.04,98.33 120.57,98.33 118.97,96.72 113.4,96.72 112.17,95.48 105.27,95.48 104.54,96.22 v5(101.73,96.22)
AM574X_VIN4B_DATA7: length 110.5
  TOP w0.173: R264.1 v2(167.79,132.29) ; U1.P5 v4(103.03,89.61)
  L3_SIG1 w0.099: v4(103.03,89.61) 102.37,90.28 102.37,91.56
  L3_SIG1 w0.109: 102.37,91.56 102.37,92.07 101.4,93.05 101.4,94.07 102.49,95.17 102.49,97.96 v5(102.65,98.13)
  L4_SIG2 w0.114: v5(153.22,126.01) 153.6,126.4 157.63,126.4 157.74,126.28 157.74,125.75 157.86,125.63 158.09,125.63 158.2,125.75 158.2,126.28 158.32,126.4 158.54,126.4 158.66,126.28 158.66,125.75 158.77,125.63 159,125.63 159.12,125.75 159.12,126.28 159.23,126.4 159.46,126.4 159.57,126.28 159.57,125.75 159.69,125.63 159.92,125.63 160.03,125.75 160.03,126.28 160.14,126.4 160.37,126.4 160.49,126.28 160.49,125.75 160.6,125.63 160.83,125.63 160.95,125.75 160.95,126.28 161.06,126.4 161.29,126.4 161.4,126.28 161.4,125.75 161.52,125.63 161.75,125.63 161.86,125.75 161.86,126.28 161.97,126.4 162.2,126.4 162.32,126.28 162.32,125.75 162.43,125.63 162.66,125.63 162.77,125.75 162.77,126.28 162.89,126.4 163.58,126.4 164.01,126.83 165.53,126.83 168.45,129.75 168.45,131.63 v2(167.79,132.29)
  L10_SIG4 w0.109: v5(153.22,126.01) 153.22,124.47 152.79,124.04 152.79,120.66 152.13,119.99 152.13,117.3 149.08,114.25 147.71,114.25 145.16,111.71 145.16,110.8 141.88,107.51 133.31,107.51 129.86,110.96 125.88,110.96 120.93,106.01 120.93,102.9 119.46,101.43 117.98,101.43 117.14,100.59 114.71,100.59 113.41,99.29 113.08,99.29 112.6,98.81 111.3,98.81 110.86,98.37 108.77,98.37 108.16,98.98 103.51,98.98 v5(102.65,98.13)
AM574X_VIN4B_DE: length 112.4
  TOP w0.173: U1.P9 v4(103.03,86.41) ; R273.2 v2(181.89,132.29)
  L3_SIG1 w0.109: v4(103.03,86.41) v5(103.43,86.66)
  L9_SIG3 w0.114: v2(181.89,132.29) 180.75,133.43 164.34,133.43 163.32,132.42 163.32,130.7 v5(155.18,122.56)
  L10_SIG4 w0.109: v5(103.43,86.66) 103.05,86.66 102.74,86.97 102.74,88.48 102.95,88.68 102.95,93.67 103.32,94.04 105.33,94.04 106.12,94.82 112.78,94.82 114.41,93.19 116.4,93.19 120.83,97.62 122.29,97.62 124,99.33 124,101.59 126.49,104.07 133.48,104.07 134.47,105.06 141.99,105.06 145.22,108.3 145.52,108.3 152.29,115.06 153.63,115.06 154.31,115.74 154.31,119.07 155.18,119.95 v5(155.18,122.56)
AM574X_VIN4B_FLD: length 108
  TOP w0.173: R274.1 v2(180.62,132.29) ; U1.P4 v4(103.03,90.41)
  L3_SIG1 w0.099: v4(103.03,90.41) 102.65,90.8 102.65,95.02 102.89,95.26 102.89,97.64
  L3_SIG1 w0.109: v5(103.38,98.13) 102.89,97.64
  L9_SIG3 w0.114: v5(152.65,119.08) 164.72,131.15 164.72,132.42 165.35,133.05 179.86,133.05 v2(180.62,132.29)
  L10_SIG4 w0.109: v5(152.65,119.08) 152.65,117.34 144.96,109.65 144.66,109.65 142.19,107.17 133.17,107.17 129.71,110.63 126.02,110.63 121.31,105.91 121.31,102.8 119.58,101.07 118.19,101.07 117.35,100.23 114.86,100.23 113.56,98.94 113.23,98.94 112.75,98.46 111.35,98.46 110.98,98.08 105.48,98.08 105.44,98.13 v5(103.38,98.13)
AM574X_VIN4B_HSYNC: length 110.5
  TOP w0.173: R258.1 v2(162.71,132.29) ; U1.N7 v4(103.83,88.01)
  L3_SIG1 w0.109: v5(104.23,88.26) 104.23,88.26 v4(103.83,88.01)
  L4_SIG2 w0.114: v2(162.71,132.29) 162.71,133.51 162.43,133.79 162.06,133.79 161.95,133.67 161.95,132.53 161.83,132.42 161.6,132.42 161.49,132.53 161.49,133.67 161.37,133.79 161.15,133.79 161.03,133.67 161.03,132.53 160.92,132.42 160.69,132.42 160.57,132.53 160.57,133.67 160.46,133.79 160.23,133.79 160.12,133.67 160.12,132.53 160,132.42 159.77,132.42 159.66,132.53 159.66,133.67 159.55,133.79 159.32,133.79 159.2,133.67 159.2,132.53 159.09,132.42 158.86,132.42 158.74,132.53 158.74,133.67 158.63,133.79 158.4,133.79 158.29,133.67 158.29,132.53 158.17,132.42 157.94,132.42 157.83,132.53 157.83,133.67 157.72,133.79 157.49,133.79 157.37,133.67 157.37,132.53 157.26,132.42 157.03,132.42 156.92,132.53 156.92,133.67 156.8,133.79 156.57,133.79 156.46,133.67 156.46,132.53 156.34,132.42 156.12,132.42 156,132.53 156,133.67 155.89,133.79 155.35,133.79 155.04,133.48 v5(155.04,131.15)
  L10_SIG4 w0.109: v5(104.23,88.26) 104.79,88.26 105.2,88.68 111.86,88.68 112.7,89.51 114.27,89.51 121.41,96.65 122.75,96.65 125.53,99.42 125.53,100.79 126.45,101.71 127.48,101.71 129.41,103.63 133.73,103.63 134.78,104.68 142.08,104.68 145.36,107.96 145.66,107.96 152.21,114.51 154.59,114.51 155.5,115.42 155.5,116.24 154.81,116.92 154.81,119 155.62,119.81 155.62,124.48 155.04,125.05 v5(155.04,131.15)
AM574X_VIN4B_PCLK: length 114.9
  TOP w0.173: U1.N9 v4(103.83,86.41) ; R265.2 v2(169.19,132.29)
  L3_SIG1 w0.109: v5(104.23,86.66) 104.23,86.66 v4(103.83,86.41)
  L4_SIG2 w0.114: v2(169.19,132.29) 169.19,131.53 169.3,131.42 170.37,131.42 170.48,131.3 170.48,131.07 170.37,130.96 169.3,130.96 169.19,130.84 169.19,130.62 169.3,130.5 170.4,130.5 170.51,130.39 170.51,130.16 170.4,130.04 169.3,130.04 169.19,129.93 169.19,129.7 169.3,129.59 169.79,129.59 169.9,129.47 169.9,129.24 169.79,129.13 169.3,129.13 169.19,129.01 169.19,128.55 165.61,124.97 155.04,124.97 154.46,125.56 149.98,125.56 v5(149.73,125.31)
  L10_SIG4 w0.109: v5(149.73,125.31) 149.73,124.37 150.64,123.46 150.64,122.87 150.85,122.66 150.85,122.28 149.05,120.48 148.54,120.48 139.82,111.76 139.82,110.64 138.67,109.49 133.52,109.49 130.69,112.31 125.32,112.31 119.07,106.07 119.07,104.14 118.27,103.33 115.52,103.33 113.42,101.23 112.35,101.23 112.12,101.46 102.98,101.46 101.22,99.69 101.22,93.65 101.87,93 101.87,87.78 102.49,87.16 102.49,86.93 103.13,86.28 103.85,86.28 v5(104.23,86.66)
AM574X_VIN4B_VSYNC: length 113.7
  TOP w0.173: R257.1 v2(158.24,143.34) ; U1.R4 v4(101.44,90.41)
  L3_SIG1 w0.109: v5(101.6,97.21) 101.6,96.65 100.46,95.51 100.46,92.59 101.44,91.61 v4(101.44,90.41)
  L4_SIG2 w0.114: v2(158.24,143.34) 157.89,143.69 154.15,143.69 153.29,142.83 153.29,140.93 153.12,140.76 151.93,140.76 151.77,140.59 151.77,140.35 151.93,140.19 153.12,140.19 153.29,140.02 153.29,139.78 153.12,139.62 151.93,139.62 151.77,139.45 151.77,139.21 151.93,139.04 153.12,139.04 153.29,138.88 153.29,138.64 153.12,138.47 151.93,138.47 151.77,138.3 151.77,138.07 151.93,137.9 153.12,137.9 153.29,137.73 153.29,134.7 152.27,133.68 v5(152.27,132.29)
  L10_SIG4 w0.109: v5(152.27,132.29) 152.27,131.29 152.68,130.89 152.68,127.16 153.72,126.12 153.72,120.83 153.16,120.27 153.16,117.37 145.1,109.31 144.8,109.31 142.33,106.84 131.75,106.84 130.29,108.29 124.16,108.29 121.69,105.82 121.69,102.7 119.7,100.72 118.31,100.72 117.47,99.88 114.99,99.88 113.79,98.68 113.79,98.25 113.44,97.89 113.28,97.89 112.83,97.43 112.83,97.08 111.79,96.04 109.29,96.04 108.92,96.42 108.07,96.42 107.87,96.21 105.87,96.21 104.88,97.21 v5(101.6,97.21)
BKLT_EN: length 2.7
  TOP w0.173: Q9.G 76.66,147.6 R412.1 R416.1
BKLT_L:
  vias: v1(70.64,146.11) v1(70.64,145.34) v1(71.53,146.11) v1(71.53,145.34)
BKLT_SW: length 1.2
  BOTTOM w0.254: v1(71.86,143.18) 71.92,143.13 U32.10
  vias: v1(70.59,143.18) v1(71.23,143.18) v1(71.48,142.55)
BUFFER_OE_S20: length 6.9
  TOP w0.173: R961.2 44.48,58.81 44.87,59.2 R945.1 U103.7
BUFFER_OE_T16: length 16.6
  TOP w0.173: R939.1 52.41,68.79 52.07,68.45 v1(52.04,68.45) 51.43,68.45 51.01,68.03 U102.1 ; R959.2 v1(47.37,57.92)
  BOTTOM w0.173: v1(47.37,57.92) 50.72,61.27 50.72,67.14 v1(52.04,68.45)
BUFFER_OE_T16_2: length 15.7
  TOP w0.173: R974.1 v1(42.7,72.25) ; R941.1 50.51,62.19 U102.7 50.51,64.89 49.72,65.68 49.25,65.68 v1(48.89,66.04)
  L4_SIG2 w0.114: v1(48.89,66.04) 47.83,66.04 42.7,71.16 v1(42.7,72.25)
CAM1_DATA0: length 6.2
  TOP w0.173: R260.1 160.42,141.19 160.42,138.27 J9.3
CAM1_DATA1: length 3
  TOP w0.173: R261.1 J9.5
CAM1_DATA2: length 3
  TOP w0.173: R263.1 J9.7
CAM1_DATA3: length 3
  TOP w0.173: R267.1 J9.13
CAM1_DATA4: length 3
  TOP w0.173: R269.1 J9.15
CAM1_DATA5: length 3
  TOP w0.173: J9.17 R271.1
CAM1_DATA6: length 6.1
  TOP w0.173: J9.6 165.38,138.38 R262.2
CAM1_DATA7: length 6.1
  TOP w0.173: J9.8 167.79,138.51 R264.2
CAM1_FIELD: length 6.1
  TOP w0.173: J9.20 180.62,138.38 R274.2
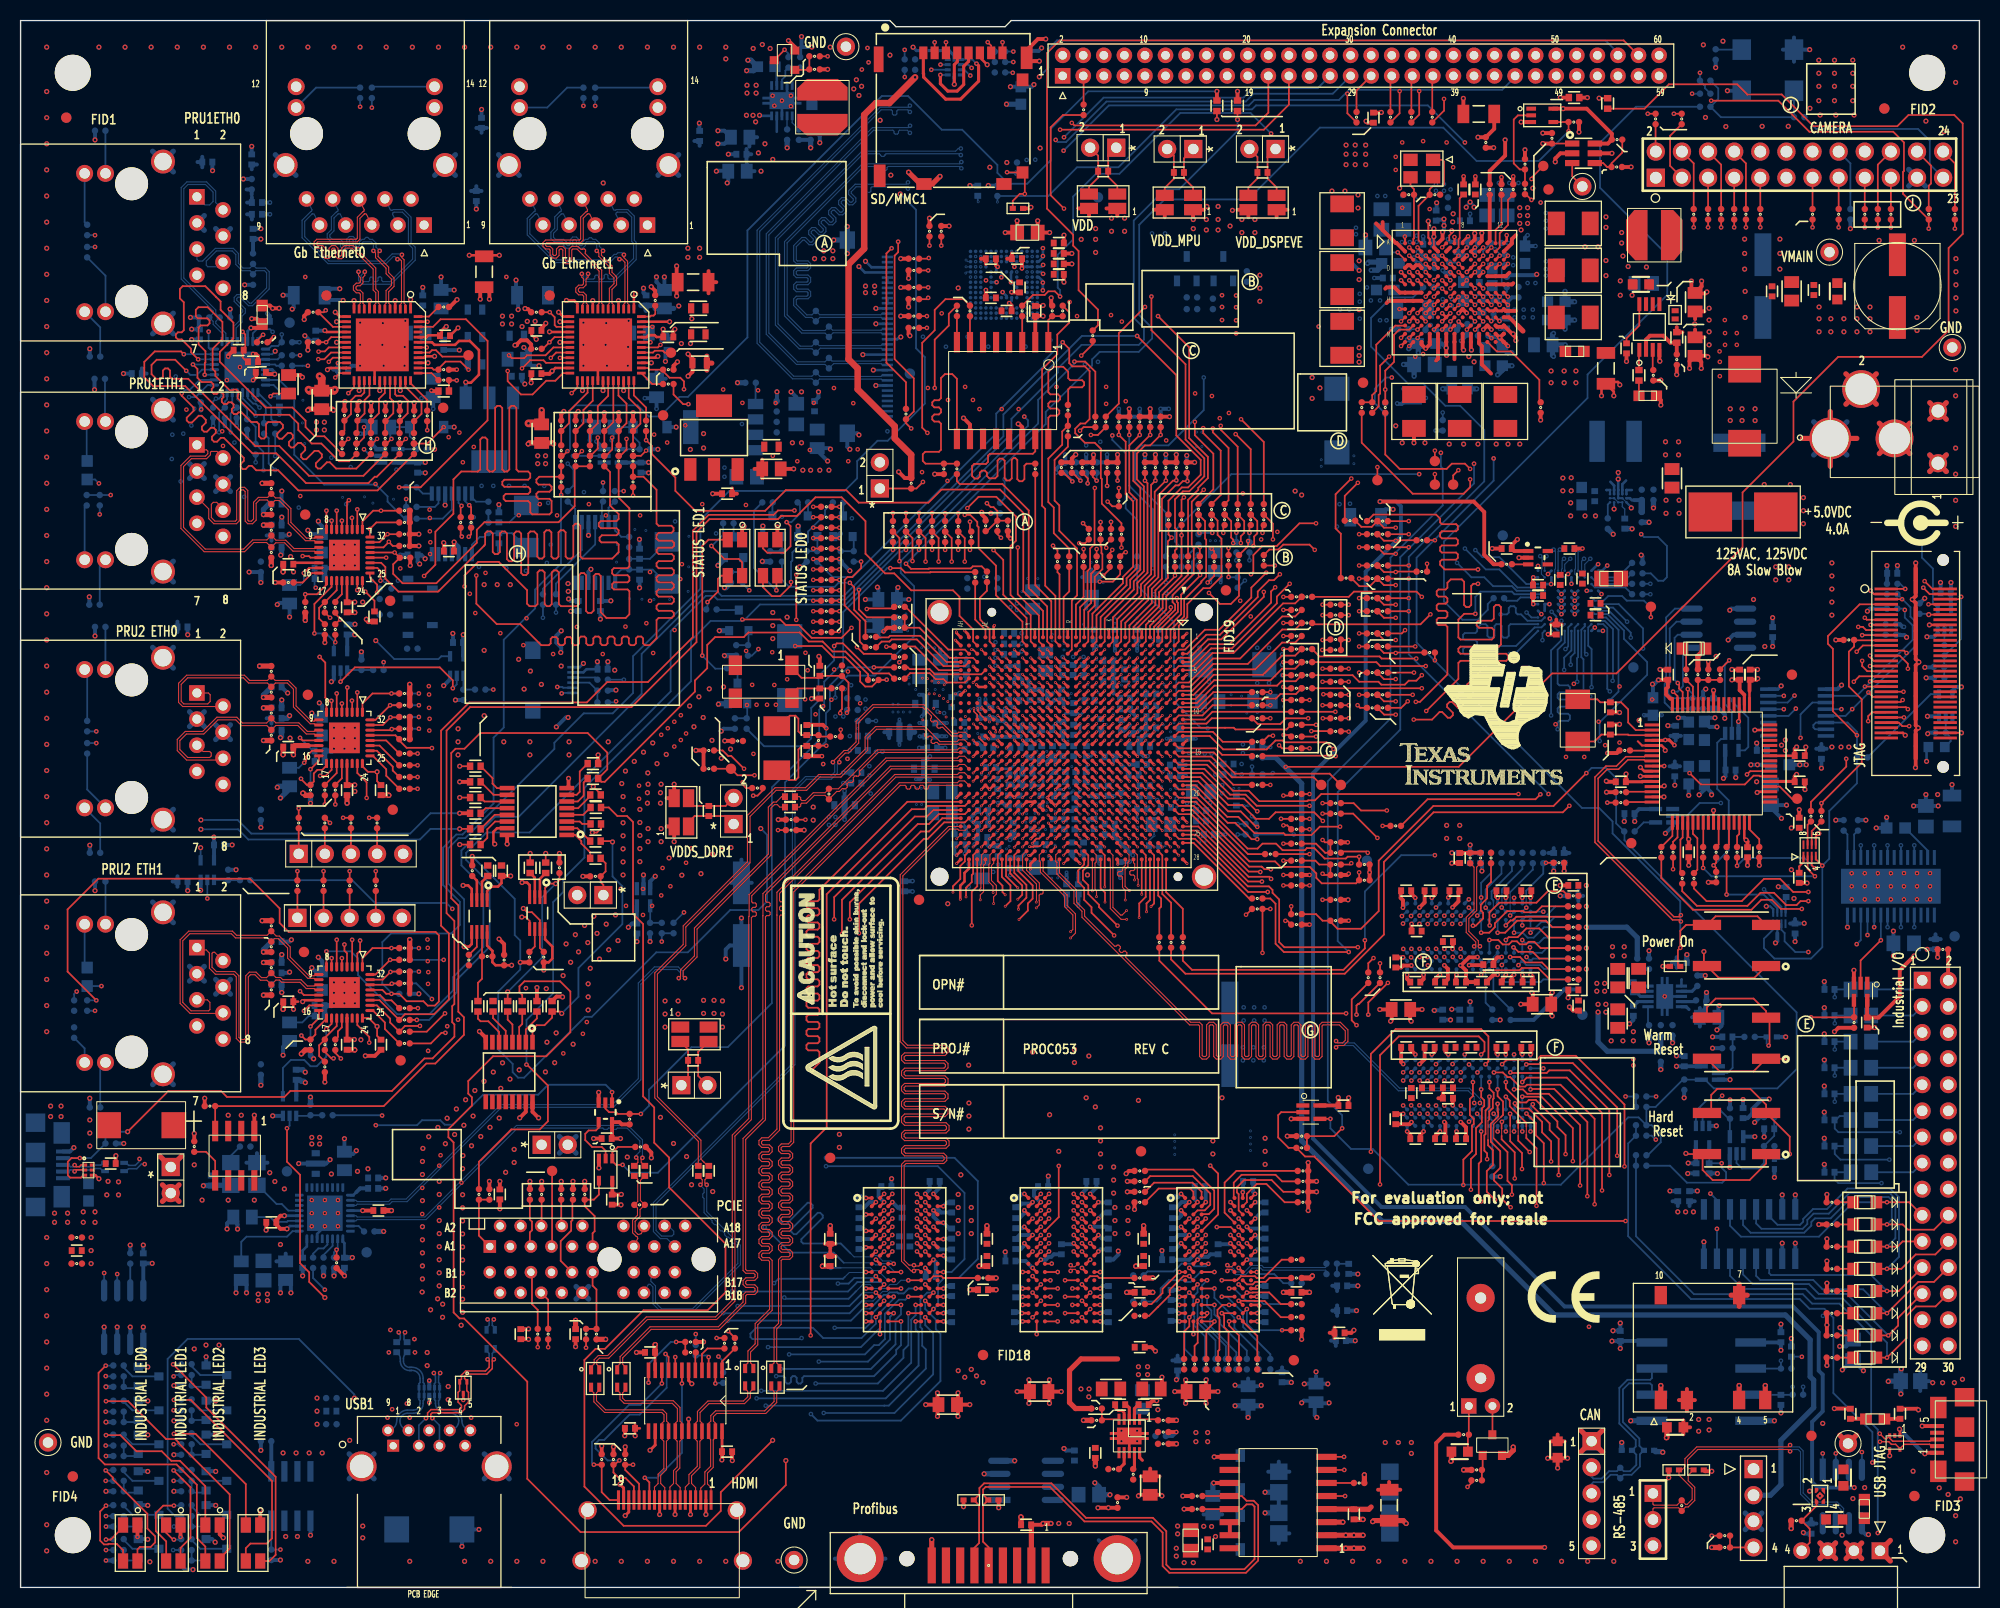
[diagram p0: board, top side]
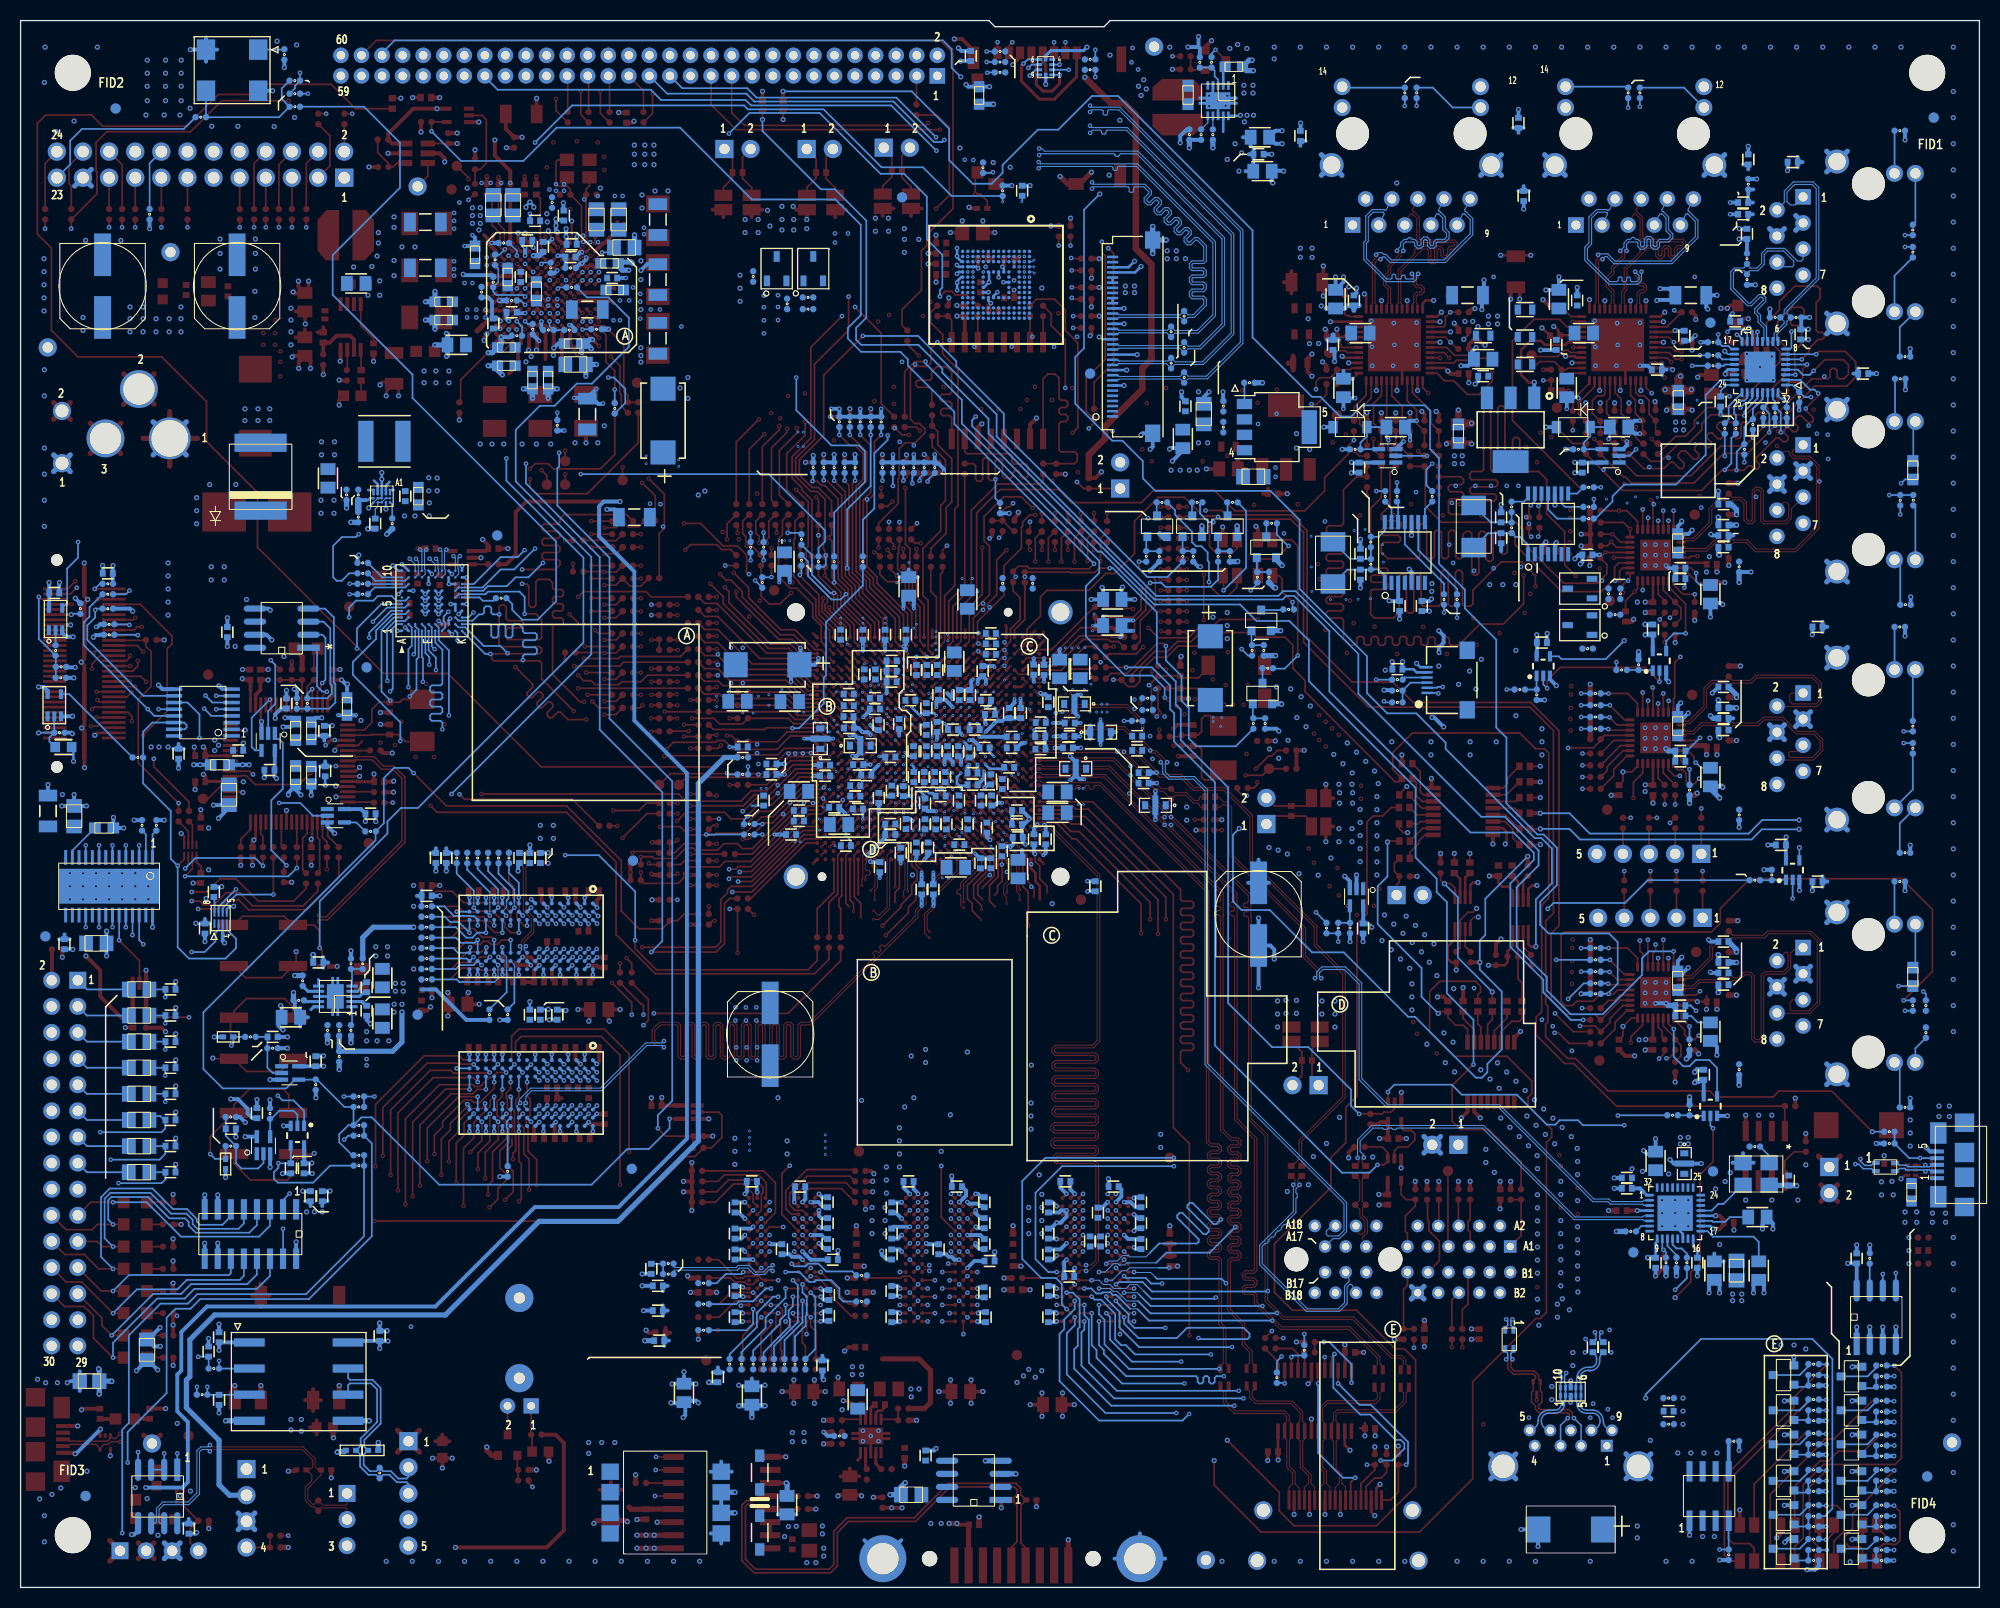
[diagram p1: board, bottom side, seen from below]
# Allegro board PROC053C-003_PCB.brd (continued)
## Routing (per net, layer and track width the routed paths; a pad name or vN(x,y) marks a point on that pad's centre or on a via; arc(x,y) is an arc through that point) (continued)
DDR2_CLK: length 140.7
  TOP w0.108: R780.2 141.35,70.06 141.35,65.94 140.59,65.18 140.59,63.71 141.52,62.78 141.52,62.51 v2(141.36,62.36) ; v2(127.93,52.53) 128.11,52.71 128.68,52.71 129.08,53.11 129.08,54.24 128.35,54.97 126.57,54.97 126.32,54.71 126.32,51.75 126.21,51.64 125.99,51.64 125.88,51.75 125.88,54.71 125.63,54.97 125.2,54.97 124.94,54.71 124.94,51.75 124.84,51.64 124.62,51.64 124.51,51.75 124.51,54.71 124.26,54.97 123.83,54.97 123.57,54.71 123.57,51.75 123.46,51.64 123.25,51.64 123.14,51.75 123.14,54.71 122.88,54.97 122.46,54.97 122.2,54.71 122.2,51.75 122.09,51.64 121.88,51.64 121.77,51.75 121.77,54.71 121.51,54.97 121.09,54.97 120.83,54.71 120.83,51.75 120.72,51.64 120.51,51.64 120.4,51.75 120.4,54.71 120.14,54.97 119.71,54.97 119.46,54.71 119.46,51.75 119.35,51.64 119.13,51.64 119.03,51.75 119.03,54.71 118.77,54.97 118.34,54.97 118.09,54.71 118.09,51.75 117.98,51.64 117.76,51.64 117.65,51.75 117.65,54.71 117.4,54.97 116.97,54.97 116.71,54.71 116.71,51.75 116.61,51.64 116.39,51.64 116.28,51.75 116.28,54.71 116.03,54.97 115.6,54.97 115.34,54.71 115.34,51.75 115.23,51.64 115.02,51.64 114.91,51.75 114.91,54.71 114.65,54.97 113.79,54.97 107.46,61.3 107.46,61.45 107.59,61.58 107.59,61.73 107.44,61.89 107.28,61.89 107.16,61.76 107,61.76 106.85,61.91 106.85,62.07 106.95,62.17 106.95,62.32 106.8,62.47 106.65,62.47 106.54,62.37 106.39,62.37 103.48,65.29 103.48,65.87 102.69,66.65 102.69,67.84 101.04,69.5 U1.T28
  L10_SIG4 w0.083: v2(141.36,47.12) 141.49,47.24 141.49,47.53 140.52,48.49 140.52,49.96 141.29,50.73 141.29,51.72 139.88,53.14 139.88,58.87 141.31,60.31 141.31,60.68 140.96,61.04 140.96,61.58 141.49,62.11 141.49,62.24 v2(141.36,62.36)
  BOTTOM w0.108: U90.J7 141.54,46.79 141.54,46.94 v2(141.36,47.12) 141.36,47.73 140.79,48.31 133.99,48.31 129.59,52.71 128.11,52.71 v2(127.93,52.53) ; v2(141.36,62.36) 141.52,62.21 141.52,62 U91.J7
DDR2_CLKN: length 140.9
  TOP w0.108: v2(141.92,62.36) 141.77,62.51 141.77,62.89 140.84,63.81 140.84,65.07 141.61,65.83 141.61,70.06 R781.2 ; v2(127.93,53.14) 128.11,52.96 128.57,52.96 128.83,53.22 128.83,54.13 128.24,54.72 126.68,54.72 126.57,54.61 126.57,51.65 126.31,51.39 125.89,51.39 125.63,51.65 125.63,54.61 125.52,54.72 125.31,54.72 125.2,54.61 125.2,51.65 124.94,51.39 124.51,51.39 124.26,51.65 124.26,54.61 124.15,54.72 123.93,54.72 123.83,54.61 123.83,51.65 123.57,51.39 123.14,51.39 122.89,51.65 122.89,54.61 122.78,54.72 122.56,54.72 122.45,54.61 122.45,51.65 122.2,51.39 121.77,51.39 121.52,51.65 121.52,54.61 121.41,54.72 121.19,54.72 121.08,54.61 121.08,51.65 120.83,51.39 120.4,51.39 120.14,51.65 120.14,54.61 120.04,54.72 119.82,54.72 119.71,54.61 119.71,51.65 119.46,51.39 119.03,51.39 118.77,51.65 118.77,54.61 118.66,54.72 118.45,54.72 118.34,54.61 118.34,51.65 118.08,51.39 117.66,51.39 117.4,51.65 117.4,54.61 117.29,54.72 117.08,54.72 116.97,54.61 116.97,51.65 116.71,51.39 116.29,51.39 116.03,51.65 116.03,54.61 115.92,54.72 115.7,54.72 115.6,54.61 115.6,51.65 115.34,51.39 114.91,51.39 114.66,51.65 114.66,54.61 114.55,54.72 113.69,54.72 103.22,65.18 103.22,65.76 102.44,66.55 102.44,67.73 100.78,69.39 100.78,70.5 100.67,70.61 100.67,71.25 U1.T27
  L10_SIG4 w0.083: v2(141.92,47.12) 141.79,47.25 141.79,47.65 140.83,48.62 140.83,49.83 141.6,50.6 141.6,51.85 140.18,53.26 140.18,58.75 141.62,60.18 141.62,60.81 141.26,61.17 141.26,61.45 141.79,61.98 141.79,62.23 v2(141.92,62.36)
  BOTTOM w0.108: U91.K7 141.77,62 141.77,62.21 v2(141.92,62.36) ; v2(127.93,53.14) 128.11,52.96 129.7,52.96 134.1,48.56 140.89,48.56 141.99,47.47 141.99,47.18 v2(141.92,47.12) 142.22,46.82 142.22,46.67 U90.K7
DDR2_CS0N: length 125.6
  TOP w0.173: v2(142.47,50.88) 142.75,51.16 142.75,53.6 142.04,54.31 133.73,54.31 131.32,51.9 v7(131.32,42.37) ; U1.P24 v4(103.03,73.62)
  L3_SIG1 w0.109: v2(142.48,66.12) 142.48,64.15 142.67,63.96 142.67,63.35 142.44,63.12 142.44,62.82 142.59,62.67 142.59,61.8 142.44,61.65 142.44,60.9 142.09,60.54 142.09,60.25 142.47,59.87 142.47,58.81 142.36,58.7 142.07,58.7 141.96,58.59 141.96,58.37 142.07,58.26 142.36,58.26 142.47,58.15 142.47,57.94 142.36,57.83 142.07,57.83 141.96,57.72 141.96,57.5 142.07,57.39 142.36,57.39 142.47,57.28 142.47,56.77 141.5,55.81 141.5,53.42 142.47,52.45 v2(142.47,50.88) ; v5(103.4,73.26) 103.05,73.62 v4(103.03,73.62) ; v7(131.32,42.37) v5(130.56,42.37)
  L9_SIG3 w0.114: v5(130.56,42.37) 130.56,43.45 123.34,50.66 115.79,50.66 115.46,50.99 115.46,51.15 115.82,51.51 115.82,51.67 115.67,51.82 115.48,51.82 115.13,51.48 114.97,51.48 114.81,51.64 114.81,51.8 115.28,52.27 115.28,52.44 115.12,52.6 114.96,52.6 114.49,52.12 114.33,52.12 114.16,52.29 114.16,52.45 114.64,52.92 114.64,53.08 114.48,53.24 114.31,53.24 113.84,52.77 113.68,52.77 113.52,52.93 113.52,53.09 113.99,53.57 113.99,53.73 113.83,53.89 113.67,53.89 113.19,53.42 113.03,53.42 112.87,53.58 112.87,53.74 113.34,54.21 113.34,54.38 113.18,54.54 113.02,54.54 112.55,54.06 112.39,54.06 112.22,54.23 112.22,54.39 112.7,54.86 112.7,55.02 112.54,55.18 112.37,55.18 111.9,54.71 111.74,54.71 111.58,54.87 111.58,55.03 112.05,55.51 112.05,55.67 111.89,55.83 111.73,55.83 111.25,55.36 111.09,55.36 110.93,55.52 110.93,55.68 111.4,56.15 111.4,56.32 111.24,56.48 111.08,56.48 110.61,56 110.45,56 110.28,56.17 110.28,56.33 110.76,56.8 110.76,56.96 110.6,57.12 110.43,57.12 109.96,56.65 109.8,56.65 109.64,56.81 109.64,56.97 110.11,57.45 110.11,57.61 109.95,57.77 109.79,57.77 109.31,57.3 109.15,57.3 108.99,57.46 108.99,57.62 109.46,58.09 109.46,58.26 109.3,58.42 109.14,58.42 108.67,57.94 108.51,57.94 108.34,58.11 108.34,58.27 108.82,58.74 108.82,58.9 108.66,59.06 108.49,59.06 108.02,58.59 107.86,58.59 107.7,58.75 107.7,58.91 108.17,59.39 108.17,59.55 108.01,59.71 107.85,59.71 107.37,59.24 107.21,59.24 107.05,59.4 107.05,59.56 107.52,60.03 107.52,60.2 107.36,60.36 107.2,60.36 106.73,59.88 106.57,59.88 106.4,60.05 106.4,60.21 106.88,60.68 106.88,60.84 106.72,61 106.55,61 106.08,60.53 105.92,60.53 105.76,60.69 105.76,60.85 106.23,61.33 106.23,61.49 106.07,61.65 105.91,61.65 105.43,61.18 105.27,61.18 105.11,61.34 105.11,61.5 105.58,61.97 105.58,62.14 105.42,62.3 105.26,62.3 104.79,61.82 104.63,61.82 104.46,61.99 104.46,62.15 104.94,62.62 104.94,62.78 104.78,62.94 104.61,62.94 104.14,62.47 103.98,62.47 103.74,62.71 103.74,66.29 103.74,66.3 103.74,68.69 104.27,69.22 104.27,70.08 103.01,71.33 103.01,72.87 v5(103.4,73.26)
  BOTTOM w0.102: 142.48,66.7 v2(142.48,66.12)
  BOTTOM w0.173: v2(142.48,66.12) 142.48,66.09 U91.L2 ; R757.2 144.02,69.42 142.48,67.89 142.48,66.7 ; v2(142.47,50.88) 142.84,50.51 U90.L2
DDR2_D0: length 50.4
  TOP w0.173: U1.E26 v4(110.23,72.02)
  L3_SIG1 w0.109: v4(110.23,72.02) 110.23,69.22 112.06,67.39 112.72,67.39 121.11,59.01 124.38,59.01 124.64,58.75 124.64,58.6 123.92,57.87 123.92,57.72 124.07,57.57 124.23,57.57 124.95,58.29 125.11,58.29 125.26,58.13 125.26,57.98 124.54,57.26 124.54,57.1 124.69,56.95 124.85,56.95 125.57,57.67 125.72,57.67 125.88,57.51 125.88,57.36 125.16,56.64 125.16,56.48 125.31,56.33 125.47,56.33 126.19,57.05 126.34,57.05 126.5,56.9 126.5,56.74 125.77,56.02 125.77,55.87 125.93,55.71 126.08,55.71 126.81,56.43 126.98,56.43 128.15,55.26 131.48,55.26 131.88,55.66 134.06,55.66 134.44,55.28 134.44,54 137.26,51.18 137.26,49.75 137.66,49.35 v2(137.66,49.3)
  BOTTOM w0.173: U90.E3 v2(137.66,49.3)
DDR2_D1: length 50.5
  TOP w0.173: U1.G25 v4(108.63,72.82)
  L3_SIG1 w0.109: v2(138.46,50.11) 138.07,49.72 138.07,49.1 137.85,48.87 134.16,48.87 133.48,49.56 133.48,49.79 133.37,49.9 132.85,49.9 132.74,50.01 132.74,50.23 132.85,50.34 133.37,50.34 133.48,50.45 133.48,50.66 133.37,50.77 132.85,50.77 132.74,50.88 132.74,51.1 132.85,51.21 133.37,51.21 133.48,51.32 133.48,51.54 133.37,51.65 132.85,51.65 132.74,51.76 132.74,51.97 132.85,52.08 133.37,52.08 133.48,52.19 133.48,52.41 133.37,52.52 132.85,52.52 132.74,52.63 132.74,52.85 132.85,52.96 133.37,52.96 133.48,53.07 133.48,53.5 133.01,53.97 128.71,53.97 127.43,55.25 125.76,55.25 122.48,58.53 120.96,58.53 112.42,67.06 112.09,67.06 109.91,69.24 109.91,71.96 109.52,72.34 109.11,72.34 v4(108.63,72.82)
  BOTTOM w0.173: U90.F2 v2(138.46,50.11)
DDR2_D2: length 50.5
  TOP w0.173: U1.F25 v4(109.43,72.82)
  L3_SIG1 w0.099: v4(109.43,72.82) 109.94,72.31 110.35,72.31 110.53,72.13 110.53,71.52
  L3_SIG1 w0.109: 110.53,71.52 110.53,69.24 112.1,67.67 113.31,67.67 121.49,59.49 124.71,59.49 126.8,57.41 127.49,57.41 127.6,57.3 127.6,56.65 127.7,56.55 127.92,56.55 128.03,56.65 128.03,57.3 128.14,57.41 128.36,57.41 128.47,57.3 128.47,56.65 128.58,56.55 128.8,56.55 128.91,56.65 128.91,57.3 129.01,57.41 129.23,57.41 129.34,57.3 129.34,56.65 129.45,56.55 129.67,56.55 129.78,56.65 129.78,57.3 129.89,57.41 130.11,57.41 130.22,57.3 130.22,56.65 130.33,56.55 130.54,56.55 130.65,56.65 130.65,57.3 130.76,57.41 130.98,57.41 131.09,57.3 131.09,56.65 131.2,56.55 131.42,56.55 131.53,56.65 131.53,57.3 131.64,57.41 133.81,57.41 136.12,55.1 136.12,53.83 138.68,51.26 138.68,50.67 v2(139.26,50.1)
  BOTTOM w0.173: U90.G2 v2(139.26,50.1)
DDR2_D3: length 50.4
  TOP w0.173: U1.F24 v4(109.43,73.62)
  L3_SIG1 w0.099: 110.74,71.56 110.74,72.22 110.44,72.52 110.11,72.52 109.77,72.86 109.77,73.28 v4(109.43,73.62)
  L3_SIG1 w0.109: v2(140.06,49.3) 140.46,49.71 140.46,51.11 136.98,54.59 136.98,56.29 135.41,57.87 131.4,57.87 131.29,57.98 131.29,58.39 131.16,58.52 130.98,58.52 130.85,58.39 130.85,57.98 130.75,57.87 130.53,57.87 130.42,57.98 130.42,58.39 130.31,58.5 130.09,58.5 129.98,58.39 129.98,57.98 129.87,57.87 129.65,57.87 129.54,57.98 129.54,58.39 129.44,58.5 129.22,58.5 129.11,58.39 129.11,57.98 129,57.87 128.78,57.87 128.67,57.98 128.67,58.39 128.56,58.5 128.34,58.5 128.23,58.39 128.23,57.98 128.12,57.87 127.03,57.87 124.94,59.95 121.81,59.95 113.75,68 112.09,68 110.74,69.35 110.74,71.56
  BOTTOM w0.173: U90.H3 v2(140.06,49.3)
DDR2_D4: length 50.4
  TOP w0.173: U1.F26 v4(109.43,72.02)
  L3_SIG1 w0.109: v2(138.46,46.87) 137.88,47.45 133.02,47.45 130.71,49.76 130.71,50.83 130.35,51.19 129.85,51.19 129.75,51.3 129.75,51.81 129.64,51.92 129.42,51.92 129.31,51.81 129.31,51.3 129.2,51.19 126.33,51.19 125.97,51.55 125.97,51.7 126.21,51.95 126.21,52.1 126.06,52.26 125.9,52.26 125.66,52.01 125.5,52.01 124.54,52.98 124.54,54.29 121.82,57.01 120.33,57.01 109.47,67.87 108.66,67.87 107.99,68.54 107.99,69.08 108.2,69.3 108.2,69.45 107.86,69.79 107.86,69.95 108.02,70.1 108.17,70.1 108.51,69.76 108.67,69.76 108.82,69.91 108.82,70.07 108.48,70.41 108.48,70.56 108.64,70.72 108.79,70.72 109.13,70.38 109.29,70.38 109.43,70.53 v4(109.43,72.02)
  BOTTOM w0.173: U90.F7 v2(138.46,46.87)
DDR2_D5: length 50.9
  TOP w0.173: v4(108.79,65.16) 108.79,66.53 109.42,67.16 109.42,70.64 109.43,70.65 109.43,70.98 109.42,70.99 109.42,71.23 U1.F27
  L3_SIG1 w0.109: v4(108.79,65.16) 131.02,42.93 139.14,42.93 140.46,44.25 140.46,45.67 v2(140.06,46.07)
  BOTTOM w0.173: U90.H8 v2(140.06,46.07)
DDR2_D6: length 50.8
  TOP w0.173: v4(109.93,66.22) 110.23,66.53 110.23,71.22 U1.E27
  L3_SIG1 w0.109: v2(138.46,46.07) 138.46,46.01 137.26,44.81 133.91,44.81 131.75,46.97 131.6,46.97 131.21,46.58 131.05,46.58 130.9,46.73 130.9,46.88 131.29,47.28 131.29,47.43 131.13,47.59 130.98,47.59 130.59,47.19 130.43,47.19 130.28,47.35 130.28,47.5 130.67,47.89 130.67,48.05 130.52,48.2 130.36,48.2 129.97,47.81 129.82,47.81 129.66,47.97 129.66,48.12 130.05,48.51 130.05,48.67 129.9,48.82 129.74,48.82 129.35,48.43 129.2,48.43 129.04,48.58 129.04,48.74 129.43,49.13 129.43,49.29 129.28,49.44 129.12,49.44 128.73,49.05 128.58,49.05 128.42,49.2 128.42,49.36 128.82,49.75 128.82,49.9 128.52,50.2 125.64,50.2 109.93,65.9 v4(109.93,66.22)
  BOTTOM w0.173: U90.F8 v2(138.46,46.07)
DDR2_D7: length 50.8
  TOP w0.173: U1.E28 109.83,66.86 109.5,66.53 v4(109.5,65.71)
  L3_SIG1 w0.109: v2(140.06,46.87) 139.65,46.46 139.65,45.12 138.15,43.62 131.27,43.62 130.38,44.5 130.38,44.66 130.67,44.95 130.67,45.1 130.52,45.26 130.36,45.26 130.07,44.97 129.92,44.97 129.77,45.12 129.77,45.28 130.05,45.57 130.05,45.72 129.9,45.87 129.74,45.87 129.46,45.59 129.3,45.59 129.15,45.74 129.15,45.9 129.43,46.18 129.43,46.34 129.28,46.49 129.13,46.49 128.84,46.2 128.68,46.2 109.5,65.38 v4(109.5,65.71)
  BOTTOM w0.173: U90.H7 v2(140.06,46.87)
DDR2_D8: length 48.8
  TOP w0.173: U1.H23 v4(107.83,74.42)
  L3_SIG1 w0.109: v4(107.83,74.42) v5(108.23,74.17)
  L4_SIG2 w0.114: v5(108.23,74.17) 108.63,73.77 109.47,73.77 111.44,71.8 111.44,68.5 113.51,66.43 118.87,66.43 126.85,58.45 132.68,58.45 138.07,53.06 138.07,48.08 v2(136.88,46.89)
  BOTTOM w0.173: v2(136.88,46.89) 136.88,46.85 U90.D7
DDR2_D9: length 48.8
  TOP w0.173: U1.H25 v4(107.83,72.82)
  L3_SIG1 w0.109: v4(107.83,72.82) v5(108.23,72.57)
  L4_SIG2 w0.114: v5(108.23,72.57) 108.64,72.15 108.64,69.24 110.29,67.59 110.29,66.73 112.9,64.11 116.46,64.11 118.55,62.03 118.55,61.87 118.28,61.6 118.28,61.43 118.44,61.27 118.6,61.27 118.87,61.54 119.03,61.54 119.19,61.38 119.19,61.22 118.92,60.95 118.92,60.79 119.08,60.63 119.25,60.63 119.52,60.9 119.68,60.9 119.84,60.73 119.84,60.57 119.57,60.3 119.57,60.14 119.73,59.98 119.89,59.98 120.16,60.25 120.32,60.25 120.49,60.09 120.49,59.93 120.22,59.66 120.22,59.49 120.38,59.33 120.54,59.33 120.81,59.6 120.97,59.6 121.13,59.44 121.13,59.28 120.86,59.01 120.86,58.85 121.02,58.69 121.19,58.69 121.46,58.96 121.62,58.96 121.78,58.79 121.78,58.63 121.51,58.36 121.51,58.2 121.67,58.04 121.83,58.04 122.1,58.31 122.26,58.31 122.43,58.15 122.43,57.99 122.16,57.72 122.16,57.55 122.32,57.39 122.48,57.39 122.75,57.66 122.91,57.66 123.07,57.5 123.07,57.34 122.8,57.07 122.8,56.91 122.96,56.75 123.13,56.75 123.4,57.02 123.56,57.02 123.72,56.85 123.72,56.69 123.45,56.42 123.45,56.26 123.61,56.1 123.77,56.1 124.04,56.37 124.2,56.37 124.37,56.21 124.37,56.05 124.12,55.8 124.12,55.64 124.28,55.48 124.44,55.48 124.69,55.72 124.85,55.72 125.26,55.32 127.77,55.32 129.93,53.16 131.45,53.16 134.46,50.15 v2(134.46,50.1)
  BOTTOM w0.173: U90.A2 v2(134.46,50.1)
DDR2_D10: length 48.8
  TOP w0.173: U1.H24 v4(107.83,73.62)
  L3_SIG1 w0.109: v4(107.83,73.62) v5(108.23,73.37)
  L4_SIG2 w0.114: v5(108.23,73.37) 109.58,72.02 109.58,69.34 110.87,68.05 110.87,67.54 113.11,65.31 117.58,65.31 121.39,61.5 121.55,61.5 121.88,61.83 122.05,61.83 122.21,61.67 122.21,61.51 121.87,61.17 121.87,61.01 122.04,60.85 122.2,60.85 122.53,61.18 122.69,61.18 122.85,61.02 122.85,60.86 122.52,60.53 122.52,60.36 122.68,60.2 122.84,60.2 123.18,60.54 123.34,60.54 123.5,60.37 123.5,60.21 123.17,59.88 123.17,59.72 123.33,59.56 123.49,59.56 123.82,59.89 123.99,59.89 124.15,59.73 124.15,59.57 123.81,59.23 123.81,59.07 123.98,58.91 124.14,58.91 124.47,59.24 124.63,59.24 124.79,59.08 124.79,58.92 124.46,58.59 124.46,58.42 126.04,56.85 129.77,56.85 130.49,56.13 130.49,55.59 131.27,54.82 132,54.82 135.43,51.39 136.17,51.39 136.45,51.11 136.45,49.69 v2(136.06,49.3)
  BOTTOM w0.173: U90.C3 v2(136.06,49.3)
DDR2_D11: length 48.8
  TOP w0.173: U1.H26 v4(107.83,72.02)
  L3_SIG1 w0.109: v4(107.83,72.02) v5(108.23,71.77)
  L4_SIG2 w0.114: v2(134.46,49.3) 134.46,49.35 131.21,52.6 129.6,52.6 127.91,54.28 124.79,54.28 124.21,54.86 124.05,54.86 123.64,54.45 123.48,54.45 123.32,54.62 123.32,54.78 123.73,55.19 123.73,55.35 123.56,55.51 123.4,55.51 122.99,55.1 122.83,55.1 122.67,55.26 122.67,55.42 123.08,55.83 123.08,56 122.92,56.16 122.76,56.16 122.35,55.75 122.18,55.75 122.02,55.91 122.02,56.07 122.43,56.48 122.43,56.64 122.27,56.8 122.11,56.8 121.7,56.39 121.54,56.39 121.38,56.56 121.38,56.72 121.79,57.13 121.79,57.29 121.62,57.45 121.46,57.45 121.05,57.04 120.89,57.04 120.73,57.2 120.73,57.36 121.14,57.77 121.14,57.94 120.98,58.1 120.82,58.1 120.41,57.69 120.24,57.69 120.08,57.85 120.08,58.01 120.49,58.42 120.49,58.58 120.33,58.74 120.17,58.74 119.76,58.33 119.6,58.33 119.44,58.5 119.44,58.66 119.85,59.07 119.85,59.23 115.47,63.61 112.6,63.61 109.93,66.27 109.93,67.21 108.23,68.91 v5(108.23,71.77)
  BOTTOM w0.173: U90.A3 v2(134.46,49.3)
DDR2_D12: length 48.7
  TOP w0.173: U1.G26 v4(108.63,72.02)
  L3_SIG1 w0.109: v4(108.63,72.02) v5(109.03,71.77)
  L4_SIG2 w0.114: v2(136.04,50.09) 132.36,53.77 130.15,53.77 127.84,56.09 126.14,56.09 125.74,56.49 125.58,56.49 125.23,56.14 125.07,56.14 124.91,56.3 124.91,56.46 125.25,56.81 125.25,56.97 125.09,57.13 124.93,57.13 124.58,56.79 124.42,56.79 124.26,56.95 124.26,57.11 124.61,57.46 124.61,57.62 124.45,57.78 124.28,57.78 123.94,57.43 123.78,57.43 123.61,57.59 123.61,57.76 123.96,58.1 123.96,58.26 123.8,58.43 123.64,58.43 123.29,58.08 123.13,58.08 122.97,58.24 122.97,58.4 123.31,58.75 123.31,58.91 123.15,59.07 122.99,59.07 122.64,58.73 122.48,58.73 122.32,58.89 122.32,59.05 122.67,59.4 122.67,59.56 122.51,59.72 122.34,59.72 122,59.37 121.84,59.37 121.67,59.53 121.67,59.7 122.02,60.04 122.02,60.2 121.86,60.37 121.7,60.37 121.35,60.02 121.19,60.02 121.03,60.18 121.03,60.34 121.37,60.69 121.37,60.85 121.21,61.01 121.05,61.01 120.7,60.67 120.54,60.67 120.38,60.83 120.38,60.99 120.73,61.34 120.73,61.5 117.45,64.77 112.98,64.77 110.57,67.19 110.57,67.85 109.03,69.38 v5(109.03,71.77)
  BOTTOM w0.173: U90.C2 v2(136.04,50.09)
DDR2_D13: length 48.8
  TOP w0.173: U1.J25 v4(107.03,72.82)
  L3_SIG1 w0.109: v4(107.03,72.82) v5(107.43,72.57)
  L4_SIG2 w0.114: v2(135.26,46.07) 134.87,46.46 132.59,46.46 129.6,49.45 124.06,49.45 120.82,52.69 120.66,52.69 120.44,52.48 120.27,52.48 120.11,52.64 120.11,52.8 120.33,53.02 120.33,53.18 120.17,53.34 120.01,53.34 119.79,53.12 119.63,53.12 119.47,53.28 119.47,53.45 119.69,53.66 119.69,53.83 119.25,54.26 116.94,54.26 105.99,65.21 105.99,66.61 105.41,67.19 105.41,68.21 106.22,69.02 106.22,71.3 107.43,72.51 v5(107.43,72.57)
  BOTTOM w0.173: U90.B8 v2(135.26,46.07)
DDR2_D14: length 48.7
  TOP w0.173: U1.J26 v4(107.03,72.02)
  L3_SIG1 w0.109: v4(107.03,72.02) v5(107.43,71.77)
  L4_SIG2 w0.114: v2(134.45,46.88) 133.34,46.88 130.08,50.14 124.15,50.14 118.69,55.61 116.26,55.61 111.22,60.64 111.22,60.8 111.48,61.06 111.48,61.22 111.32,61.38 111.16,61.38 110.9,61.12 110.74,61.12 110.58,61.28 110.58,61.45 110.83,61.7 110.83,61.87 110.67,62.03 110.51,62.03 110.25,61.77 110.09,61.77 109.93,61.93 109.93,62.09 110.19,62.35 110.19,62.51 110.03,62.67 109.86,62.67 109.61,62.42 109.45,62.42 109.28,62.58 109.28,62.74 109.54,63 109.54,63.16 109.38,63.32 109.22,63.32 108.96,63.06 108.8,63.06 108.64,63.22 108.64,63.39 108.89,63.64 108.89,63.81 108.73,63.97 108.57,63.97 108.31,63.71 108.15,63.71 106.73,65.13 106.73,67.06 107.09,67.42 107.09,67.84 106.73,68.19 106.73,71.05 107.43,71.75 v5(107.43,71.77)
  BOTTOM w0.173: U90.A7 v2(134.45,46.88)
DDR2_D15: length 48.7
  TOP w0.173: U1.J24 v4(107.03,73.62)
  L3_SIG1 w0.109: v4(107.03,73.62) v5(107.43,73.37)
  L4_SIG2 w0.114: v2(136.06,46.07) 136.11,46.07 136.47,46.44 136.47,47.73 135.74,48.47 134.26,48.47 130.87,51.87 125.3,51.87 117.13,60.04 117.13,60.2 117.35,60.42 117.35,60.58 117.19,60.74 117.03,60.74 116.81,60.52 116.65,60.52 116.49,60.68 116.49,60.85 116.71,61.06 116.71,61.23 116.54,61.39 116.38,61.39 116.16,61.17 116,61.17 115.84,61.33 115.84,61.49 116.06,61.71 116.06,61.87 115.9,62.03 115.74,62.03 115.52,61.82 115.35,61.82 114.17,63 112.37,63 109.48,65.88 109.48,67.08 107.82,68.74 107.82,72.73 107.82,72.73 107.82,72.98 v5(107.43,73.37)
  BOTTOM w0.173: U90.C8 v2(136.06,46.07)
DDR2_D16: length 55.4
  TOP w0.173: U1.L22 v4(105.43,75.22)
  L3_SIG1 w0.109: v5(105.8,74.86) 105.79,74.86 v4(105.43,75.22)
  L9_SIG3 w0.114: v2(137.66,64.55) 137.05,63.94 134.05,63.94 133.94,63.82 133.94,63.49 133.82,63.38 133.6,63.38 133.48,63.49 133.48,63.82 133.37,63.94 133.14,63.94 133.02,63.82 133.02,63.09 132.91,62.97 132.68,62.97 132.57,63.09 132.57,63.82 132.45,63.94 132.22,63.94 132.11,63.82 132.11,63.09 132,62.97 131.77,62.97 131.65,63.09 131.65,63.82 131.54,63.94 131.31,63.94 131.2,63.82 131.2,63.49 131.08,63.38 130.85,63.38 130.74,63.49 130.74,63.82 130.62,63.94 130.4,63.94 130.28,63.82 130.28,63.49 130.17,63.38 129.94,63.38 129.82,63.49 129.82,63.82 129.71,63.94 129.41,63.94 128.93,63.45 117.78,63.45 117.66,63.57 117.66,64.15 117.55,64.27 117.32,64.27 117.21,64.15 117.21,63.57 117.09,63.45 116.86,63.45 116.75,63.57 116.75,64.33 116.64,64.44 116.41,64.44 116.29,64.33 116.29,63.57 116.18,63.45 115.95,63.45 115.84,63.57 115.84,64.33 115.72,64.44 115.49,64.44 115.38,64.33 115.38,63.57 115.26,63.45 115.04,63.45 114.92,63.57 114.92,64.33 114.81,64.44 114.58,64.44 114.46,64.33 114.46,63.57 114.35,63.45 114.12,63.45 114.01,63.57 114.01,64.33 113.89,64.44 113.66,64.44 113.55,64.33 113.55,63.57 113.44,63.45 113.21,63.45 107.01,69.65 107.01,74.2 106.76,74.45 106.27,74.45 105.86,74.86 v5(105.8,74.86)
  BOTTOM w0.173: U91.E3 v2(137.66,64.55)
DDR2_D17: length 55.5
  TOP w0.173: U1.K20 v4(106.23,76.82)
  L3_SIG1 w0.109: v4(106.23,76.82) v5(106.63,76.57)
  L9_SIG3 w0.114: v2(140.04,61.33) 139.22,60.5 139.22,58.12 138.51,57.41 112.77,57.41 105.02,65.16 105.02,66.25 104.6,66.68 104.6,68.23 105.41,69.04 105.41,75.03 105.64,75.26 105.97,75.26 106.22,75.51 106.22,76.16 v5(106.63,76.57)
  BOTTOM w0.173: U91.H8 v2(140.04,61.33)
DDR2_D18: length 55.5
  TOP w0.173: U1.K21 v4(106.23,76.02)
  L3_SIG1 w0.109: v4(106.23,76.02) v5(106.63,75.77)
  L9_SIG3 w0.114: v2(140.03,64.54) 139.65,64.92 139.65,65.48 139.9,65.74 139.9,68.08 139.42,68.56 136.51,68.56 136.4,68.45 136.4,68.09 136.28,67.98 136.06,67.98 135.94,68.09 135.94,68.45 135.83,68.56 135.6,68.56 135.48,68.45 135.48,68.09 135.37,67.98 135.14,67.98 135.03,68.09 135.03,68.45 134.91,68.56 134.68,68.56 134.57,68.45 134.57,68.09 134.45,67.98 134.23,67.98 134.11,68.09 134.11,68.45 134,68.56 133.77,68.56 133.65,68.45 133.65,68.09 133.54,67.98 133.31,67.98 133.2,68.09 133.2,68.45 133.08,68.56 132.46,68.56 129.79,65.89 125.93,65.89 125.12,66.71 124.62,66.71 124.51,66.59 124.51,65.93 124.4,65.82 124.17,65.82 124.05,65.93 124.05,66.59 123.94,66.71 123.71,66.71 123.6,66.59 123.6,65.93 123.48,65.82 123.25,65.82 123.14,65.93 123.14,66.59 123.02,66.71 122.8,66.71 122.68,66.59 122.68,65.93 122.57,65.82 122.34,65.82 122.22,65.93 122.22,66.59 122.11,66.71 112.29,66.71 109.6,69.4 109.6,73.85 109.45,74.01 109.45,75.17 109.26,75.35 107.04,75.35 v5(106.63,75.77)
  BOTTOM w0.173: U91.H3 140.06,64.54 v2(140.03,64.54)
DDR2_D19: length 55.5
  TOP w0.173: U1.L23 v4(105.43,74.42)
  L3_SIG1 w0.109: v5(105.8,74.06) 105.8,74.06 105.44,74.42 v4(105.43,74.42)
  L9_SIG3 w0.114: v5(105.8,74.06) 106.48,73.38 106.48,65.31 112.5,59.29 125.73,59.29 126.32,58.7 127.94,58.7 128.06,58.81 128.06,59.28 128.17,59.39 128.4,59.39 128.52,59.28 128.52,58.81 128.63,58.7 128.86,58.7 128.97,58.81 128.97,59.28 129.09,59.39 129.32,59.39 129.43,59.28 129.43,58.81 129.54,58.7 129.77,58.7 129.89,58.81 129.89,59.28 130,59.39 130.23,59.39 130.34,59.28 130.34,58.81 130.46,58.7 130.69,58.7 130.8,58.81 130.8,59.28 130.92,59.39 131.14,59.39 131.26,59.28 131.26,58.81 131.37,58.7 131.6,58.7 131.72,58.81 131.72,59.28 131.83,59.39 132.06,59.39 132.17,59.28 132.17,58.81 132.29,58.7 132.52,58.7 132.63,58.81 132.63,59.28 132.74,59.39 132.97,59.39 133.09,59.28 133.09,58.81 133.2,58.7 133.43,58.7 133.55,58.81 133.55,59.28 133.66,59.39 133.89,59.39 134,59.28 134,58.81 134.12,58.7 136.57,58.7 137.57,59.69 137.57,60.62 138.05,61.1 138.05,61.7 v2(138.46,62.11)
  BOTTOM w0.173: U91.F7 v2(138.46,62.11)
DDR2_D20: length 55.6
  TOP w0.173: U1.L24 v4(105.43,73.62)
  L3_SIG1 w0.109: v5(105.8,73.26) 105.45,73.62 v4(105.43,73.62)
  L9_SIG3 w0.114: v5(105.8,73.26) 106.2,72.86 106.2,68.94 105.41,68.15 105.41,67.26 105.99,66.68 105.99,65.02 113,58.02 121.36,58.02 121.48,58.13 121.48,58.72 121.59,58.83 121.82,58.83 121.93,58.72 121.93,58.13 122.05,58.02 122.28,58.02 122.39,58.13 122.39,58.72 122.51,58.83 122.73,58.83 122.85,58.72 122.85,58.13 122.96,58.02 123.19,58.02 123.31,58.13 123.31,58.72 123.42,58.83 123.65,58.83 123.76,58.72 123.76,58.13 123.88,58.02 124.11,58.02 124.22,58.13 124.22,58.72 124.33,58.83 124.56,58.83 124.68,58.72 124.68,58.13 124.79,58.02 125.02,58.02 125.13,58.13 125.13,58.72 125.25,58.83 125.48,58.83 125.59,58.72 125.59,58.13 125.71,58.02 137.11,58.02 138.87,59.78 138.87,60.9 v2(138.45,61.32)
  BOTTOM w0.173: U91.F8 v2(138.45,61.32)
DDR2_D21: length 55.5
  TOP w0.173: U1.J23 v4(107.03,74.42)
  L3_SIG1 w0.109: v4(107.03,74.42) 107.04,74.42 107.4,74.06 v5(107.4,74.06)
  L9_SIG3 w0.114: v2(138.46,65.33) 138.46,66.07 137.95,66.57 133.93,66.57 133.45,66.1 133.45,65.31 132.77,64.62 129.26,64.62 128.57,63.94 127.97,63.94 127.85,64.05 127.85,64.74 127.74,64.85 127.51,64.85 127.39,64.74 127.39,64.05 127.28,63.94 127.05,63.94 126.94,64.05 126.94,64.74 126.82,64.85 126.59,64.85 126.48,64.74 126.48,64.05 126.37,63.94 126.14,63.94 126.02,64.05 126.02,64.74 125.91,64.85 125.68,64.85 125.57,64.74 125.57,64.05 125.45,63.94 123.96,63.94 123.84,64.05 123.84,64.71 123.73,64.83 123.5,64.83 123.39,64.71 123.39,64.05 123.27,63.94 123.04,63.94 122.93,64.05 122.93,64.71 122.82,64.83 122.59,64.83 122.47,64.71 122.47,64.05 122.36,63.94 122.13,63.94 122.02,64.05 122.02,64.71 121.9,64.83 121.67,64.83 121.56,64.71 121.56,64.05 121.44,63.94 121.22,63.94 121.1,64.05 121.1,64.71 120.99,64.83 120.76,64.83 120.64,64.71 120.64,64.05 120.53,63.94 120.3,63.94 120.19,64.05 120.19,64.71 120.07,64.83 119.84,64.83 119.73,64.71 119.73,64.05 119.62,63.94 119.39,63.94 119.27,64.05 119.27,64.71 119.16,64.83 118.93,64.83 118.82,64.71 118.82,64.05 118.7,63.94 118.52,63.94 117.55,64.9 112.47,64.9 107.84,69.53 107.84,73.62 v5(107.4,74.06)
  BOTTOM w0.173: U91.F2 138.46,65.34 v2(138.46,65.33)
DDR2_D22: length 55.4
  TOP w0.173: U1.K22 v4(106.23,75.22)
  L3_SIG1 w0.109: v5(106.6,74.86) 106.58,74.86 106.23,75.21 v4(106.23,75.22)
  L9_SIG3 w0.114: v2(139.24,65.35) 138.86,65.74 138.86,66.47 137.77,67.56 133.47,67.56 132.69,66.78 132.69,66.35 131.7,65.36 120.77,65.36 120.66,65.47 120.66,66.13 120.54,66.25 120.31,66.25 120.2,66.13 120.2,65.47 120.08,65.36 119.86,65.36 119.74,65.47 119.74,66.13 119.63,66.25 119.4,66.25 119.28,66.13 119.28,65.47 119.17,65.36 118.94,65.36 118.83,65.47 118.83,66.13 118.71,66.25 118.48,66.25 118.37,66.13 118.37,65.47 118.26,65.36 118.03,65.36 117.91,65.47 117.91,66.13 117.8,66.25 117.57,66.25 117.46,66.13 117.46,65.47 117.34,65.36 117.11,65.36 117,65.47 117,66.13 116.88,66.25 116.66,66.25 116.54,66.13 116.54,65.47 116.43,65.36 116.2,65.36 116.08,65.47 116.08,66.13 115.97,66.25 115.74,66.25 115.63,66.13 115.63,65.47 115.51,65.36 115.28,65.36 115.17,65.47 115.17,66.13 115.06,66.25 114.83,66.25 114.71,66.13 114.71,65.47 114.6,65.36 114.37,65.36 114.26,65.47 114.26,66.13 114.14,66.25 113.91,66.25 113.8,66.13 113.8,65.47 113.68,65.36 113.11,65.36 108.64,69.82 108.64,74.3 108.39,74.55 107.26,74.55 106.96,74.86 v5(106.6,74.86)
  BOTTOM w0.173: v2(139.24,65.35) 139.62,65.73 U91.G2
DDR2_D23: length 55.4
  TOP w0.173: U1.J20 v4(107.03,76.82)
  L3_SIG1 w0.109: v4(107.03,76.82) v5(107.43,76.57)
  L9_SIG3 w0.114: v2(140.05,62.12) 140.05,62.15 140.85,62.95 140.85,65.45 141.27,65.86 141.27,68.03 140.28,69.02 136.17,69.02 136.06,69.13 136.06,69.56 135.94,69.68 135.72,69.68 135.6,69.56 135.6,69.13 135.49,69.02 135.26,69.02 135.14,69.13 135.14,69.56 135.03,69.68 134.8,69.68 134.69,69.56 134.69,69.13 134.57,69.02 134.34,69.02 134.23,69.13 134.23,69.56 134.12,69.68 133.89,69.68 133.77,69.56 133.77,69.13 133.66,69.02 133.43,69.02 133.32,69.13 133.32,69.56 133.2,69.68 132.97,69.68 132.86,69.56 132.86,69.13 132.74,69.02 132.26,69.02 129.59,66.35 126.14,66.35 125.32,67.16 112.88,67.16 110.24,69.8 110.24,75.9 109.99,76.16 107.84,76.16 v5(107.43,76.57)
  BOTTOM w0.173: U91.H7 v2(140.05,62.12)
DDR2_D24: length 49.9
  TOP w0.173: v4(105.43,68.13) 105.43,71.22 U1.L27
  L3_SIG1 w0.109: v4(105.43,68.13) 105.43,68.13 105.79,67.77 v5(105.8,67.77)
  L10_SIG4 w0.109: v2(136.86,62.11) 135.49,63.48 132.36,63.48 130.1,61.22 114.35,61.22 113.71,61.86 113.56,61.86 113.04,61.34 112.88,61.34 112.73,61.5 112.73,61.65 113.25,62.17 113.25,62.32 113.09,62.48 112.94,62.48 112.42,61.96 112.27,61.96 112.11,62.11 112.11,62.27 112.63,62.79 112.63,62.94 112.47,63.1 112.32,63.1 111.8,62.58 111.65,62.58 111.49,62.73 111.49,62.89 112.01,63.4 112.01,63.56 111.86,63.71 111.7,63.71 111.18,63.2 111.03,63.2 110.87,63.35 110.87,63.5 111.39,64.02 111.39,64.18 111.24,64.33 111.08,64.33 110.56,63.81 110.41,63.81 110.26,63.97 110.26,64.12 110.77,64.64 110.77,64.8 110.62,64.95 110.47,64.95 109.95,64.43 109.79,64.43 109.64,64.59 109.64,64.74 110.16,65.26 110.16,65.41 108.56,67.01 106.56,67.01 v5(105.8,67.77)
  BOTTOM w0.173: U91.D7 v2(136.86,62.11)
DDR2_D25: length 49.8
  TOP w0.173: U1.L26 v4(105.43,72.02)
  L3_SIG1 w0.109: v5(105.8,71.66) 105.79,71.66 v4(105.43,72.02)
  L10_SIG4 w0.109: v5(105.8,71.66) 105.8,71.27 113.03,64.04 115.81,64.04 115.92,63.93 115.92,63.59 116.03,63.48 116.25,63.48 116.36,63.59 116.36,63.93 116.47,64.04 116.81,64.04 117.26,63.59 117.26,62.73 117.37,62.62 117.59,62.62 117.7,62.73 117.7,63.19 117.81,63.3 118.03,63.3 118.14,63.19 118.14,62.73 118.25,62.62 118.47,62.62 118.58,62.73 118.58,63.19 118.68,63.3 118.9,63.3 119.01,63.19 119.01,62.73 119.12,62.62 119.34,62.62 119.45,62.73 119.45,63.19 119.56,63.3 119.78,63.3 119.89,63.19 119.89,62.73 120,62.62 120.21,62.62 120.32,62.73 120.32,63.19 120.43,63.3 120.65,63.3 120.76,63.19 120.76,62.73 120.87,62.62 121.09,62.62 121.2,62.73 121.2,63.19 121.31,63.3 121.52,63.3 121.63,63.19 121.63,62.73 121.74,62.62 121.96,62.62 122.07,62.73 122.07,63.19 122.18,63.3 122.4,63.3 122.51,63.19 122.51,62.73 122.62,62.62 122.84,62.62 122.94,62.73 122.94,63.19 123.05,63.3 123.27,63.3 123.38,63.19 123.38,62.73 123.49,62.62 123.71,62.62 123.82,62.73 123.82,63.19 123.93,63.3 124.15,63.3 124.26,63.19 124.26,62.73 124.36,62.62 124.58,62.62 124.69,62.73 124.69,63.19 124.8,63.3 125.02,63.3 125.13,63.19 125.13,62.73 125.24,62.62 125.46,62.62 125.57,62.73 125.57,63.19 125.67,63.3 125.89,63.3 126,63.19 126,62.73 126.11,62.62 126.33,62.62 126.44,62.73 126.44,63.19 126.55,63.3 126.77,63.3 126.88,63.19 126.88,62.73 126.99,62.62 127.2,62.62 127.31,62.73 127.31,63.19 127.42,63.3 127.64,63.3 127.75,63.19 127.75,62.73 127.86,62.62 128.35,62.62 130.05,64.32 133.5,64.32 133.75,64.57 134.44,64.57 v2(134.44,64.57)
  BOTTOM w0.173: v2(134.44,64.57) 134.8,64.93 U91.A3
DDR2_D26: length 49.7
  TOP w0.173: U1.L25 v4(105.43,72.82)
  L3_SIG1 w0.109: v4(105.43,72.82) 105.79,72.46 v5(105.8,72.46)
  L10_SIG4 w0.109: v5(105.8,72.46) 106.64,72.46 106.93,72.17 108.46,72.17 108.64,71.99 108.64,71.23 109.3,70.57 109.3,69.42 113.61,65.11 113.98,65.11 114.09,65.21 114.09,65.68 114.2,65.79 114.42,65.79 114.53,65.68 114.53,65.21 114.64,65.11 114.86,65.11 114.96,65.21 114.96,65.68 115.07,65.79 115.29,65.79 115.4,65.68 115.4,65.21 115.51,65.11 115.73,65.11 115.84,65.21 115.84,65.68 115.95,65.79 116.17,65.79 116.28,65.68 116.28,65.21 116.38,65.11 116.6,65.11 116.71,65.21 116.71,65.68 116.82,65.79 117.04,65.79 117.15,65.68 117.15,65.21 117.26,65.11 117.48,65.11 117.59,65.21 117.59,65.68 117.7,65.79 117.91,65.79 118.02,65.68 118.02,65.21 118.13,65.11 118.35,65.11 118.46,65.21 118.46,65.68 118.57,65.79 118.79,65.79 118.9,65.68 118.9,65.21 119.01,65.11 119.22,65.11 119.33,65.21 119.33,65.68 119.44,65.79 119.66,65.79 119.77,65.68 119.77,65.21 119.88,65.11 120.1,65.11 120.21,65.21 120.21,65.68 120.32,65.79 120.54,65.79 120.64,65.68 120.64,65.21 120.75,65.11 122.07,65.11 122.18,65.21 122.18,65.73 122.29,65.84 122.51,65.84 122.62,65.73 122.62,65.21 122.73,65.11 122.95,65.11 123.06,65.21 123.06,65.73 123.17,65.84 123.38,65.84 123.49,65.73 123.49,65.21 123.6,65.11 123.82,65.11 123.93,65.21 123.93,65.73 124.04,65.84 124.26,65.84 124.37,65.73 124.37,65.21 124.48,65.11 126.9,65.11 127.69,64.32 128.63,64.32 129.54,65.23 131.93,65.23 132.41,65.71 135.69,65.71 v2(136.06,65.34)
  BOTTOM w0.173: U91.C2 v2(136.06,65.34)
DDR2_D27: length 49.9
  TOP w0.173: v4(105.46,66.65) 105.46,67.59 105.04,68.02 U1.L28
  L3_SIG1 w0.109: v5(105.46,66.07) v4(105.46,66.65)
  L10_SIG4 w0.109: v2(134.47,62.1) 133.52,62.1 132.41,60.99 132.41,60.69 130.3,58.58 126.67,58.58 126.56,58.69 126.56,58.93 126.45,59.03 126.23,59.03 126.13,58.93 126.13,58.69 126.02,58.58 125.8,58.58 125.69,58.69 125.69,58.93 125.58,59.03 125.36,59.03 125.25,58.93 125.25,58.69 125.14,58.58 124.92,58.58 124.82,58.69 124.82,58.93 124.71,59.03 124.49,59.03 124.38,58.93 124.38,58.69 124.27,58.58 124.05,58.58 123.94,58.69 123.94,58.93 123.83,59.03 123.61,59.03 123.5,58.93 123.5,58.69 123.4,58.58 123.18,58.58 123.07,58.69 123.07,58.93 122.96,59.03 122.74,59.03 122.63,58.93 122.63,58.69 122.52,58.58 122.3,58.58 122.19,58.69 122.19,58.93 122.08,59.03 121.87,59.03 121.76,58.93 121.76,58.69 121.65,58.58 121.43,58.58 121.32,58.69 121.32,58.93 121.21,59.03 120.99,59.03 120.88,58.93 120.88,58.69 120.77,58.58 120.56,58.58 120.45,58.69 120.45,58.93 120.34,59.03 120.12,59.03 120.01,58.93 120.01,58.69 119.9,58.58 119.68,58.58 119.57,58.69 119.57,58.93 119.46,59.03 119.24,59.03 119.14,58.93 119.14,58.69 119.03,58.58 118.81,58.58 118.7,58.69 118.7,58.93 118.59,59.03 118.37,59.03 118.26,58.93 118.26,58.69 118.15,58.58 117.93,58.58 117.83,58.69 117.83,58.93 117.72,59.03 117.5,59.03 117.39,58.93 117.39,58.69 117.28,58.58 117.06,58.58 116.95,58.69 116.95,58.93 116.84,59.03 116.62,59.03 116.51,58.93 116.51,58.69 116.41,58.58 116.19,58.58 116.08,58.69 116.08,58.93 115.97,59.03 115.75,59.03 115.64,58.93 115.64,58.69 115.53,58.58 115.31,58.58 115.2,58.69 115.2,58.93 115.09,59.03 114.88,59.03 114.77,58.93 114.77,58.69 114.66,58.58 114.44,58.58 114.33,58.69 114.33,58.93 114.22,59.03 114,59.03 113.89,58.93 113.89,58.69 113.78,58.58 111.53,58.58 105.46,64.65 v5(105.46,66.07)
  BOTTOM w0.173: U91.A7 v2(134.47,62.1)
DDR2_D28: length 49.7
  TOP w0.173: U1.M23 v4(104.63,74.42)
  L3_SIG1 w0.109: v5(105,74.06) 105,74.06 104.64,74.42 v4(104.63,74.42)
  L10_SIG4 w0.109: v5(105,74.06) 104.6,73.65 104.6,72.01 104.24,71.66 104.24,69.02 103.45,68.23 103.45,65.05 111.4,57.1 133.23,57.1 136.06,59.94 v2(136.06,61.31)
  BOTTOM w0.173: U91.C8 v2(136.06,61.31)
DDR2_D29: length 49.8
  TOP w0.173: U1.M24 v4(104.63,73.62)
  L3_SIG1 w0.109: v4(104.63,73.62) 104.65,73.62 v5(105,73.26)
  L10_SIG4 w0.109: v5(105,73.26) 105.41,72.85 105.41,72.29 105.64,72.06 105.97,72.06 106.2,71.84 106.2,71.35 107.67,69.88 108,69.88 113.23,64.65 116.92,64.65 117.81,63.76 118.18,63.76 118.29,63.87 118.29,64.54 118.4,64.65 118.62,64.65 118.72,64.54 118.72,63.87 118.83,63.76 119.05,63.76 119.16,63.87 119.16,64.54 119.27,64.65 119.49,64.65 119.6,64.54 119.6,63.87 119.71,63.76 119.93,63.76 120.04,63.87 120.04,64.54 120.14,64.65 120.36,64.65 120.47,64.54 120.47,63.87 120.58,63.76 120.8,63.76 120.91,63.87 120.91,64.54 121.02,64.65 121.24,64.65 121.35,64.54 121.35,63.87 121.46,63.76 121.67,63.76 121.78,63.87 121.78,64.54 121.89,64.65 122.11,64.65 122.22,64.54 122.22,63.87 122.33,63.76 122.55,63.76 122.66,63.87 122.66,64.54 122.77,64.65 122.98,64.65 123.09,64.54 123.09,63.87 123.2,63.76 123.42,63.76 123.53,63.87 123.53,64.54 123.64,64.65 123.86,64.65 123.97,64.54 123.97,63.87 124.08,63.76 125.08,63.76 125.19,63.87 125.19,64.49 125.3,64.6 125.51,64.6 125.62,64.49 125.62,63.87 125.73,63.76 125.95,63.76 126.06,63.87 126.06,64.49 126.17,64.6 126.39,64.6 126.5,64.49 126.5,63.87 126.61,63.76 128.75,63.76 129.77,64.77 133.3,64.77 133.83,65.3 v2(134.34,65.3)
  BOTTOM w0.173: v2(134.34,65.3) 134.76,65.73 U91.A2
DDR2_D30: length 49.7
  TOP w0.173: U1.M25 v4(104.63,72.82)
  L3_SIG1 w0.109: v5(105,72.46) 105,72.46 104.64,72.82 v4(104.63,72.82)
  L10_SIG4 w0.109: v5(105,72.46) 105,72.22 105.41,71.81 105.41,70.95 114.68,61.68 115.5,61.68 115.61,61.79 115.61,62.25 115.72,62.36 115.93,62.36 116.04,62.25 116.04,61.79 116.15,61.68 116.37,61.68 116.48,61.79 116.48,62.25 116.59,62.36 116.81,62.36 116.92,62.25 116.92,61.79 117.03,61.68 117.24,61.68 117.35,61.79 117.35,62.05 117.46,62.16 117.68,62.16 117.79,62.05 117.79,61.79 117.9,61.68 118.12,61.68 118.23,61.79 118.23,62.05 118.34,62.16 118.56,62.16 118.66,62.05 118.66,61.79 118.77,61.68 118.99,61.68 119.1,61.79 119.1,62.05 119.21,62.16 119.43,62.16 119.54,62.05 119.54,61.79 119.65,61.68 119.87,61.68 119.98,61.79 119.98,62.05 120.08,62.16 120.3,62.16 120.41,62.05 120.41,61.79 120.52,61.68 120.74,61.68 120.85,61.79 120.85,62.05 120.96,62.16 121.18,62.16 121.29,62.05 121.29,61.79 121.4,61.68 121.61,61.68 121.72,61.79 121.72,62.05 121.83,62.16 122.05,62.16 122.16,62.05 122.16,61.79 122.27,61.68 122.49,61.68 122.6,61.79 122.6,62.05 122.71,62.16 122.92,62.16 123.03,62.05 123.03,61.79 123.14,61.68 123.36,61.68 123.47,61.79 123.47,62.05 123.58,62.16 123.8,62.16 123.91,62.05 123.91,61.79 124.02,61.68 124.23,61.68 124.34,61.79 124.34,62.05 124.45,62.16 124.67,62.16 124.78,62.05 124.78,61.79 124.89,61.68 125.11,61.68 125.22,61.79 125.22,62.05 125.33,62.16 125.55,62.16 125.65,62.05 125.65,61.79 125.76,61.68 125.98,61.68 126.09,61.79 126.09,62.05 126.2,62.16 126.42,62.16 126.53,62.05 126.53,61.79 126.64,61.68 126.86,61.68 126.97,61.79 126.97,62.05 127.07,62.16 127.29,62.16 127.4,62.05 127.4,61.79 127.51,61.68 128.12,61.68 130.25,63.81 135.33,63.81 136.04,64.53 v2(136.04,64.54)
  BOTTOM w0.173: v2(136.04,64.54) 136.06,64.54 U91.C3
DDR2_D31: length 49.7
  TOP w0.173: U1.M26 v4(104.63,72.02)
  L3_SIG1 w0.109: v5(105,71.66) 104.99,71.66 104.64,72.02 v4(104.63,72.02)
  L10_SIG4 w0.109: v2(135.23,61.29) 131.5,57.56 130.1,57.56 129.99,57.67 129.99,58.01 129.88,58.12 129.66,58.12 129.55,58.01 129.55,57.67 129.44,57.56 129.23,57.56 129.12,57.67 129.12,58.01 129.01,58.12 128.79,58.12 128.68,58.01 128.68,57.67 128.57,57.56 128.35,57.56 128.24,57.67 128.24,58.01 128.13,58.12 127.91,58.12 127.81,58.01 127.81,57.67 127.7,57.56 127.48,57.56 127.37,57.67 127.37,58.01 127.26,58.12 127.04,58.12 126.93,58.01 126.93,57.67 126.82,57.56 126.6,57.56 126.49,57.67 126.49,58.04 126.39,58.15 126.17,58.15 126.06,58.04 126.06,57.67 125.95,57.56 125.73,57.56 125.62,57.67 125.62,58.04 125.51,58.15 125.29,58.15 125.18,58.04 125.18,57.67 125.07,57.56 111.62,57.56 104.01,65.17 104.01,68.1 104.6,68.69 104.6,71.25 v5(105,71.66)
  BOTTOM w0.173: U91.B8 135.28,61.29 v2(135.23,61.29)
DDR2_DQM0: length 50.6
  TOP w0.173: v4(109.04,67.42) U1.F28
  L3_SIG1 w0.109: v4(109.04,67.42) 109.83,66.63 110.06,66.63 120.89,55.8 121.05,55.8 121.64,56.39 121.8,56.39 121.95,56.24 121.95,56.08 121.36,55.49 121.36,55.33 121.51,55.18 121.66,55.18 122.26,55.77 122.41,55.77 122.57,55.62 122.57,55.46 121.97,54.87 121.97,54.71 122.13,54.56 122.28,54.56 122.88,55.15 123.03,55.15 123.19,55 123.19,54.84 122.59,54.25 122.59,54.1 122.75,53.94 122.9,53.94 123.5,54.54 123.65,54.54 123.8,54.38 123.8,54.23 123.21,53.63 123.21,53.48 126.01,50.68 128.7,50.68 129.16,50.22 129.31,50.22 129.51,50.42 129.67,50.42 129.82,50.27 129.82,50.11 129.62,49.91 129.62,49.76 133.71,45.67 137.08,45.67 137.26,45.85 137.26,46.48 v2(137.65,46.88)
  BOTTOM w0.173: U90.E7 v2(137.65,46.88)
DDR2_DQM1: length 48.8
  TOP w0.173: U1.G24 v4(108.63,73.62)
  L3_SIG1 w0.109: v4(108.63,73.62) v5(109.03,73.37)
  L4_SIG2 w0.114: v2(136.83,49.27) 137.26,49.71 137.26,51.21 136.21,52.26 136.21,53.28 131.57,57.92 126.75,57.92 121.92,62.74 121.76,62.74 121.36,62.34 121.2,62.34 121.04,62.5 121.04,62.67 121.44,63.06 121.44,63.22 121.28,63.39 121.11,63.39 120.72,62.99 120.56,62.99 120.39,63.15 120.39,63.31 120.79,63.71 120.79,63.87 120.63,64.03 120.47,64.03 120.07,63.64 119.91,63.64 119.75,63.8 119.75,63.96 120.14,64.36 120.14,64.52 119.98,64.68 119.82,64.68 119.42,64.28 119.26,64.28 119.1,64.44 119.1,64.61 119.5,65 119.5,65.16 118.8,65.87 113.44,65.87 111.12,68.18 111.12,71.27 v5(109.03,73.37)
  BOTTOM w0.173: U90.D3 v2(136.83,49.27)
DDR2_DQM2: length 55.5
  TOP w0.173: U1.K23 v4(106.23,74.42)
  L3_SIG1 w0.109: v4(106.23,74.42) 106.24,74.42 106.6,74.06 v5(106.6,74.06)
  L9_SIG3 w0.114: v5(106.6,74.06) 106.6,73.64 106.8,73.45 106.8,66.96 107.2,66.56 107.2,65.22 111.02,61.41 111.18,61.41 111.43,61.66 111.6,61.66 111.76,61.5 111.76,61.34 111.5,61.08 111.5,60.92 112.01,60.41 122.63,60.41 123.22,59.82 123.49,59.82 123.61,59.94 123.61,60.29 123.72,60.41 123.95,60.41 124.06,60.29 124.06,59.94 124.18,59.82 124.41,59.82 124.52,59.94 124.52,60.29 124.63,60.41 124.86,60.41 124.98,60.29 124.98,59.94 125.09,59.82 125.32,59.82 125.43,59.94 125.43,60.29 125.55,60.41 125.78,60.41 125.89,60.29 125.89,59.94 126.01,59.82 126.23,59.82 126.35,59.94 126.35,60.29 126.46,60.41 126.69,60.41 126.81,60.29 126.81,59.94 126.92,59.82 127.15,59.82 127.26,59.94 127.26,60.29 127.38,60.41 127.61,60.41 127.72,60.29 127.72,59.94 127.83,59.82 128.06,59.82 128.18,59.94 128.18,60.29 128.29,60.41 128.52,60.41 128.63,60.29 128.63,59.94 128.75,59.82 128.98,59.82 129.09,59.94 129.09,60.29 129.21,60.41 129.43,60.41 129.55,60.29 129.55,59.94 129.66,59.82 129.89,59.82 130.01,59.94 130.01,60.29 130.12,60.41 130.35,60.41 130.46,60.29 130.46,59.94 130.58,59.82 130.81,59.82 130.92,59.94 130.92,60.29 131.03,60.41 131.26,60.41 131.38,60.29 131.38,59.94 131.49,59.82 131.72,59.82 131.83,59.94 131.83,60.29 131.95,60.41 132.18,60.41 132.29,60.29 132.29,59.94 132.41,59.82 132.63,59.82 132.75,59.94 132.75,60.29 132.86,60.41 133.09,60.41 133.21,60.29 133.21,59.94 133.32,59.82 134.02,59.82 135.09,60.9 137.05,60.9 137.24,61.08 137.24,61.64 137.66,62.06 v2(137.66,62.11)
  BOTTOM w0.173: U91.E7 v2(137.66,62.11)
DDR2_DQM3: length 49.9
  TOP w0.173: U1.M22 v4(104.63,75.22)
  L3_SIG1 w0.109: v4(104.63,75.22) 104.65,75.22 v5(105,74.86)
  L10_SIG4 w0.109: v5(105,74.86) 105,74.85 105.4,74.45 105.97,74.45 106.22,74.2 106.22,73.57 106.81,72.97 108.49,72.97 109.83,71.63 109.83,69.85 112.83,66.86 113.46,66.86 113.57,66.75 113.57,66.36 113.67,66.25 113.89,66.25 114,66.36 114,66.75 114.11,66.86 114.33,66.86 114.44,66.75 114.44,66.36 114.55,66.25 114.77,66.25 114.88,66.36 114.88,66.75 114.99,66.86 115.2,66.86 115.31,66.75 115.31,66.36 115.42,66.25 115.64,66.25 115.75,66.36 115.75,66.75 115.86,66.86 116.08,66.86 116.19,66.75 116.19,66.36 116.3,66.25 116.51,66.25 116.62,66.36 116.62,66.75 116.73,66.86 116.95,66.86 117.06,66.75 117.06,66.36 117.17,66.25 117.39,66.25 117.5,66.36 117.5,66.75 117.61,66.86 117.82,66.86 117.93,66.75 117.93,66.36 118.04,66.25 118.26,66.25 118.37,66.36 118.37,66.75 118.48,66.86 118.7,66.86 118.81,66.75 118.81,66.36 118.92,66.25 119.14,66.25 119.24,66.36 119.24,66.75 119.35,66.86 119.57,66.86 119.68,66.75 119.68,66.36 119.79,66.25 120.01,66.25 120.12,66.36 120.12,66.75 120.23,66.86 120.45,66.86 120.56,66.75 120.56,66.43 120.66,66.32 120.88,66.32 120.99,66.43 120.99,66.75 121.1,66.86 123.88,66.86 124.97,65.77 131.8,65.77 132.58,66.55 136.89,66.55 137.24,66.2 137.24,64.92 v2(136.84,64.53)
  BOTTOM w0.173: U91.D3 v2(136.84,64.53)
DDR2_DQS0: length 50.7
  TOP w0.108: v4(108.33,68.81) 108.35,68.83 108.35,69.18 108.24,69.29 107.98,69.29 107.87,69.4 107.87,69.61 107.98,69.72 108.24,69.72 108.35,69.83 108.35,70.37 108.23,70.48 U1.G28
  L3_SIG1 w0.083: v4(108.33,68.81) 108.56,68.59 108.95,68.59 109.04,68.67 109.04,69.01 109.12,69.09 109.28,69.09 109.37,69.01 109.37,68.67 109.45,68.59 110.04,68.59 120.7,57.92 122.21,57.92 125.85,54.28 125.85,53.87 125.45,53.47 125.45,53.35 125.57,53.23 125.68,53.23 126.9,54.45 127.29,54.45 127.58,54.17 127.58,53.8 127.08,53.31 127.08,52.48 127.46,52.11 128.3,52.11 128.55,52.36 128.55,52.89 128.93,53.27 131.22,53.27 131.62,52.87 131.62,50.16 133.62,48.16 138.25,48.16 138.71,48.62 138.71,49.06 v2(138.46,49.31)
  BOTTOM w0.108: U90.F3 v2(138.46,49.31)
DDR2_DQS1: length 49.3
  TOP w0.108: U1.H27 107.8,71.25 107.8,70.63 107.69,70.52 107.69,70.13 107.42,69.86 107.42,68.19 v4(107.83,67.77)
  L3_SIG1 w0.083: v4(107.83,67.77) 107.79,67.77 v5(107.48,67.46)
  L4_SIG2 w0.099: v2(136.04,46.89) 135.84,47.09 135.84,47.51 135.33,48.01 133.55,48.01 130.46,51.1 124.49,51.1 118.04,57.55 117.65,57.55 117.26,57.16 117.12,57.16 116.98,57.3 116.98,57.44 117.37,57.83 117.37,58.22 117.05,58.54 116.66,58.54 116.26,58.15 116.12,58.15 115.98,58.29 115.98,58.43 116.38,58.82 116.38,59.22 116.06,59.54 115.67,59.54 115.27,59.14 115.13,59.14 114.99,59.28 114.99,59.42 115.39,59.82 115.39,60.21 115.07,60.53 114.67,60.53 114.28,60.13 114.04,60.13 113.31,60.86 113.31,61 113.57,61.25 113.57,61.65 113.25,61.97 112.86,61.97 112.6,61.71 112.46,61.71 108.87,65.3 108.87,66.85 108.48,67.24 107.69,67.24 v5(107.48,67.46)
  BOTTOM w0.108: U90.C7 v2(136.04,46.89)
DDR2_DQS2: length 56.3
  TOP w0.108: U1.K27 106.23,71.22 106.23,66.14 106.97,65.4 107.13,65.4 v4(107.56,65.83)
  L3_SIG1 w0.083: v4(107.56,65.83) 108.09,65.83 v5(108.1,65.84)
  L9_SIG3 w0.099: v5(108.1,65.84) 108.38,65.56 109.6,65.56 113.83,61.34 114.68,61.34 114.78,61.44 114.78,61.96 115.06,62.23 115.51,62.23 115.79,61.96 115.79,61.44 115.89,61.34 116.08,61.34 116.18,61.44 116.18,61.96 116.46,62.23 116.91,62.23 117.19,61.96 117.19,61.44 117.29,61.34 117.49,61.34 117.58,61.44 117.58,61.96 117.86,62.23 118.31,62.23 118.59,61.96 118.59,61.44 118.69,61.34 118.89,61.34 118.99,61.44 118.99,61.96 119.26,62.23 119.72,62.23 119.99,61.96 119.99,61.44 120.09,61.34 120.29,61.34 120.39,61.44 120.39,61.96 120.67,62.23 121.12,62.23 121.39,61.96 121.39,61.44 121.49,61.34 121.69,61.34 121.79,61.44 121.79,61.96 122.07,62.23 122.52,62.23 122.8,61.96 122.8,61.44 122.9,61.34 123.09,61.34 123.19,61.44 123.19,61.96 123.47,62.23 123.92,62.23 124.2,61.96 124.2,61.44 124.3,61.34 124.5,61.34 124.6,61.44 124.6,61.96 124.87,62.23 125.32,62.23 125.6,61.96 125.6,61.44 125.7,61.34 125.9,61.34 126,61.44 126,61.96 126.27,62.23 126.73,62.23 127,61.96 127,61.44 127.1,61.34 127.3,61.34 127.4,61.44 127.4,61.96 127.68,62.23 128.13,62.23 128.41,61.96 128.41,61.44 128.5,61.34 129.51,61.34 130.45,62.27 133.36,62.27 134.42,63.33 137.95,63.33 138.71,64.09 138.71,64.31 138.48,64.54 v2(138.43,64.54)
  BOTTOM w0.108: U91.F3 138.46,64.54 v2(138.43,64.54)
DDR2_DQS3: length 50
  TOP w0.108: U1.M28 v4(104.23,67.75)
  L3_SIG1 w0.083: v4(104.23,67.75) 104.98,67.75 v5(105,67.72)
  L10_SIG4 w0.083: v2(136.06,62.11) 135.83,62.34 135.83,62.68 135.53,62.97 133.06,62.97 130.15,60.06 126.85,60.06 126.35,60.56 125.93,60.56 125.67,60.3 125.67,60.04 125.59,59.96 125.42,59.96 125.34,60.04 125.34,60.3 125.08,60.56 124.66,60.56 124.4,60.3 124.4,60.04 124.32,59.96 124.15,59.96 124.07,60.04 124.07,60.3 123.81,60.56 123.39,60.56 123.13,60.3 123.13,60.04 123.05,59.96 122.88,59.96 122.8,60.04 122.8,60.3 122.54,60.56 122.12,60.56 121.86,60.3 121.86,60.04 121.78,59.96 121.61,59.96 121.53,60.04 121.53,60.3 121.27,60.56 120.85,60.56 120.59,60.3 120.59,60.04 120.51,59.96 120.34,59.96 120.26,60.04 120.26,60.3 120,60.56 119.58,60.56 119.32,60.3 119.32,60.04 119.24,59.96 119.07,59.96 118.99,60.04 118.99,60.3 118.73,60.56 118.31,60.56 118.05,60.3 118.05,60.04 117.97,59.96 117.8,59.96 117.72,60.04 117.72,60.3 117.46,60.56 117.04,60.56 116.78,60.3 116.78,60.04 116.7,59.96 116.53,59.96 116.45,60.04 116.45,60.3 116.19,60.56 115.77,60.56 115.51,60.3 115.51,60.04 115.43,59.96 115.26,59.96 115.18,60.04 115.18,60.3 114.92,60.56 114.5,60.56 114.24,60.3 114.24,60.04 114.16,59.96 113.99,59.96 113.91,60.04 113.91,60.3 113.65,60.56 113.23,60.56 112.97,60.3 112.97,60.04 112.89,59.96 112.06,59.96 107.37,64.65 107.37,65.36 106.79,65.94 106.79,66.05 106.9,66.17 106.9,66.31 106.79,66.41 106.68,66.41 106.55,66.29 106.44,66.29 v5(105,67.72)
  BOTTOM w0.108: U91.C7 v2(136.06,62.11)
DDR2_DQSN0: length 50.7
  TOP w0.108: v4(108.69,68.28) 108.69,68.88 108.6,68.96 108.6,71.25 U1.G27
  L3_SIG1 w0.083: v4(108.69,68.28) 108.69,68.28 109.91,68.28 120.58,57.62 122.09,57.62 125.55,54.16 125.55,54 125.14,53.59 125.14,53.23 125.44,52.93 125.81,52.93 127.02,54.14 127.17,54.14 127.27,54.04 127.27,53.92 126.78,53.43 126.78,52.35 127.33,51.8 128.42,51.8 128.85,52.23 128.85,52.76 129.06,52.96 131.09,52.96 131.31,52.74 131.31,50.04 133.49,47.85 138.37,47.85 139.01,48.49 139.01,49.06 v2(139.26,49.31)
  BOTTOM w0.108: U90.G3 v2(139.26,49.31)
DDR2_DQSN1: length 49.3
  TOP w0.108: v4(107.43,66.86) 107.43,67.81 107.16,68.08 107.16,69.09 107.05,69.2 106.79,69.2 106.68,69.31 106.68,69.52 106.79,69.63 107.05,69.63 107.16,69.74 107.16,69.96 107.43,70.23 U1.H28
  L3_SIG1 w0.083: v4(107.43,66.86) 107.5,66.86 v5(107.8,66.55)
  L4_SIG2 w0.099: v5(107.8,66.55) 107.8,66.83 107.9,66.93 108.36,66.93 108.56,66.73 108.56,65.18 112.33,61.41 112.73,61.41 112.98,61.66 113.12,61.66 113.26,61.52 113.26,61.38 113.01,61.13 113.01,60.73 113.91,59.83 114.41,59.83 114.8,60.22 114.94,60.22 115.08,60.08 115.08,59.94 114.69,59.55 114.69,59.16 115.01,58.84 115.4,58.84 115.79,59.23 115.93,59.23 116.07,59.09 116.07,58.95 115.68,58.56 115.68,58.16 116,57.84 116.39,57.84 116.79,58.24 116.92,58.24 117.07,58.1 117.07,57.96 116.67,57.56 116.67,57.17 116.99,56.85 117.38,56.85 117.78,57.25 117.92,57.25 124.36,50.8 130.33,50.8 133.43,47.71 135.2,47.71 135.53,47.38 135.53,47.19 v2(135.24,46.89)
  BOTTOM w0.108: U90.B7 v2(135.24,46.89)
DDR2_DQSN2: length 56.2
  TOP w0.108: U1.K28 105.98,70.67 105.98,66.03 107.04,64.98 v4(107.57,64.98)
  L3_SIG1 w0.083: v5(108.07,64.98) v4(107.57,64.98)
  L9_SIG3 w0.099: v5(108.07,64.98) 108.35,65.26 109.47,65.26 113.7,61.03 114.81,61.03 115.09,61.31 115.09,61.83 115.18,61.93 115.38,61.93 115.48,61.83 115.48,61.31 115.76,61.03 116.21,61.03 116.49,61.31 116.49,61.83 116.59,61.93 116.78,61.93 116.88,61.83 116.88,61.31 117.16,61.03 117.61,61.03 117.89,61.31 117.89,61.83 117.99,61.93 118.19,61.93 118.29,61.83 118.29,61.31 118.56,61.03 119.01,61.03 119.29,61.31 119.29,61.83 119.39,61.93 119.59,61.93 119.69,61.83 119.69,61.31 119.97,61.03 120.42,61.03 120.69,61.31 120.69,61.83 120.79,61.93 120.99,61.93 121.09,61.83 121.09,61.31 121.37,61.03 121.82,61.03 122.1,61.31 122.1,61.83 122.19,61.93 122.39,61.93 122.49,61.83 122.49,61.31 122.77,61.03 123.22,61.03 123.5,61.31 123.5,61.83 123.6,61.93 123.8,61.93 123.89,61.83 123.89,61.31 124.17,61.03 124.62,61.03 124.9,61.31 124.9,61.83 125,61.93 125.2,61.93 125.3,61.83 125.3,61.31 125.57,61.03 126.02,61.03 126.3,61.31 126.3,61.83 126.4,61.93 126.6,61.93 126.7,61.83 126.7,61.31 126.98,61.03 127.43,61.03 127.7,61.31 127.7,61.83 127.8,61.93 128,61.93 128.1,61.83 128.1,61.31 128.38,61.03 129.64,61.03 130.58,61.97 133.49,61.97 134.54,63.02 138.07,63.02 139.01,63.96 139.01,64.33 v2(139.23,64.54)
  BOTTOM w0.108: v2(139.23,64.54) 139.26,64.54 U91.G3
DDR2_DQSN3: length 50.1
  TOP w0.108: v4(104.63,67.19) 104.63,67.76 104.49,67.91 104.49,70.44 104.6,70.56 104.6,71.25 U1.M27
  L3_SIG1 w0.083: v5(104.98,66.84) v4(104.63,67.19)
  L10_SIG4 w0.083: v5(104.98,66.84) 105.46,66.84 107.06,65.23 107.06,64.52 111.93,59.65 113.01,59.65 113.28,59.91 113.28,60.17 113.36,60.25 113.52,60.25 113.61,60.17 113.61,59.91 113.87,59.65 114.28,59.65 114.55,59.91 114.55,60.17 114.63,60.25 114.79,60.25 114.88,60.17 114.88,59.91 115.14,59.65 115.55,59.65 115.82,59.91 115.82,60.17 115.9,60.25 116.06,60.25 116.15,60.17 116.15,59.91 116.41,59.65 116.82,59.65 117.09,59.91 117.09,60.17 117.17,60.25 117.33,60.25 117.42,60.17 117.42,59.91 117.68,59.65 118.09,59.65 118.36,59.91 118.36,60.17 118.44,60.25 118.6,60.25 118.69,60.17 118.69,59.91 118.95,59.65 119.36,59.65 119.63,59.91 119.63,60.17 119.71,60.25 119.87,60.25 119.96,60.17 119.96,59.91 120.22,59.65 120.63,59.65 120.9,59.91 120.9,60.17 120.98,60.25 121.14,60.25 121.23,60.17 121.23,59.91 121.49,59.65 121.9,59.65 122.17,59.91 122.17,60.17 122.25,60.25 122.41,60.25 122.5,60.17 122.5,59.91 122.76,59.65 123.17,59.65 123.44,59.91 123.44,60.17 123.52,60.25 123.68,60.25 123.77,60.17 123.77,59.91 124.03,59.65 124.44,59.65 124.71,59.91 124.71,60.17 124.79,60.25 124.95,60.25 125.04,60.17 125.04,59.91 125.3,59.65 125.71,59.65 125.98,59.91 125.98,60.17 126.06,60.25 126.22,60.25 126.72,59.75 130.28,59.75 133.19,62.67 135.41,62.67 135.53,62.55 135.53,62.33 135.31,62.11 v2(135.26,62.11)
  BOTTOM w0.108: v2(135.26,62.11) U91.B7
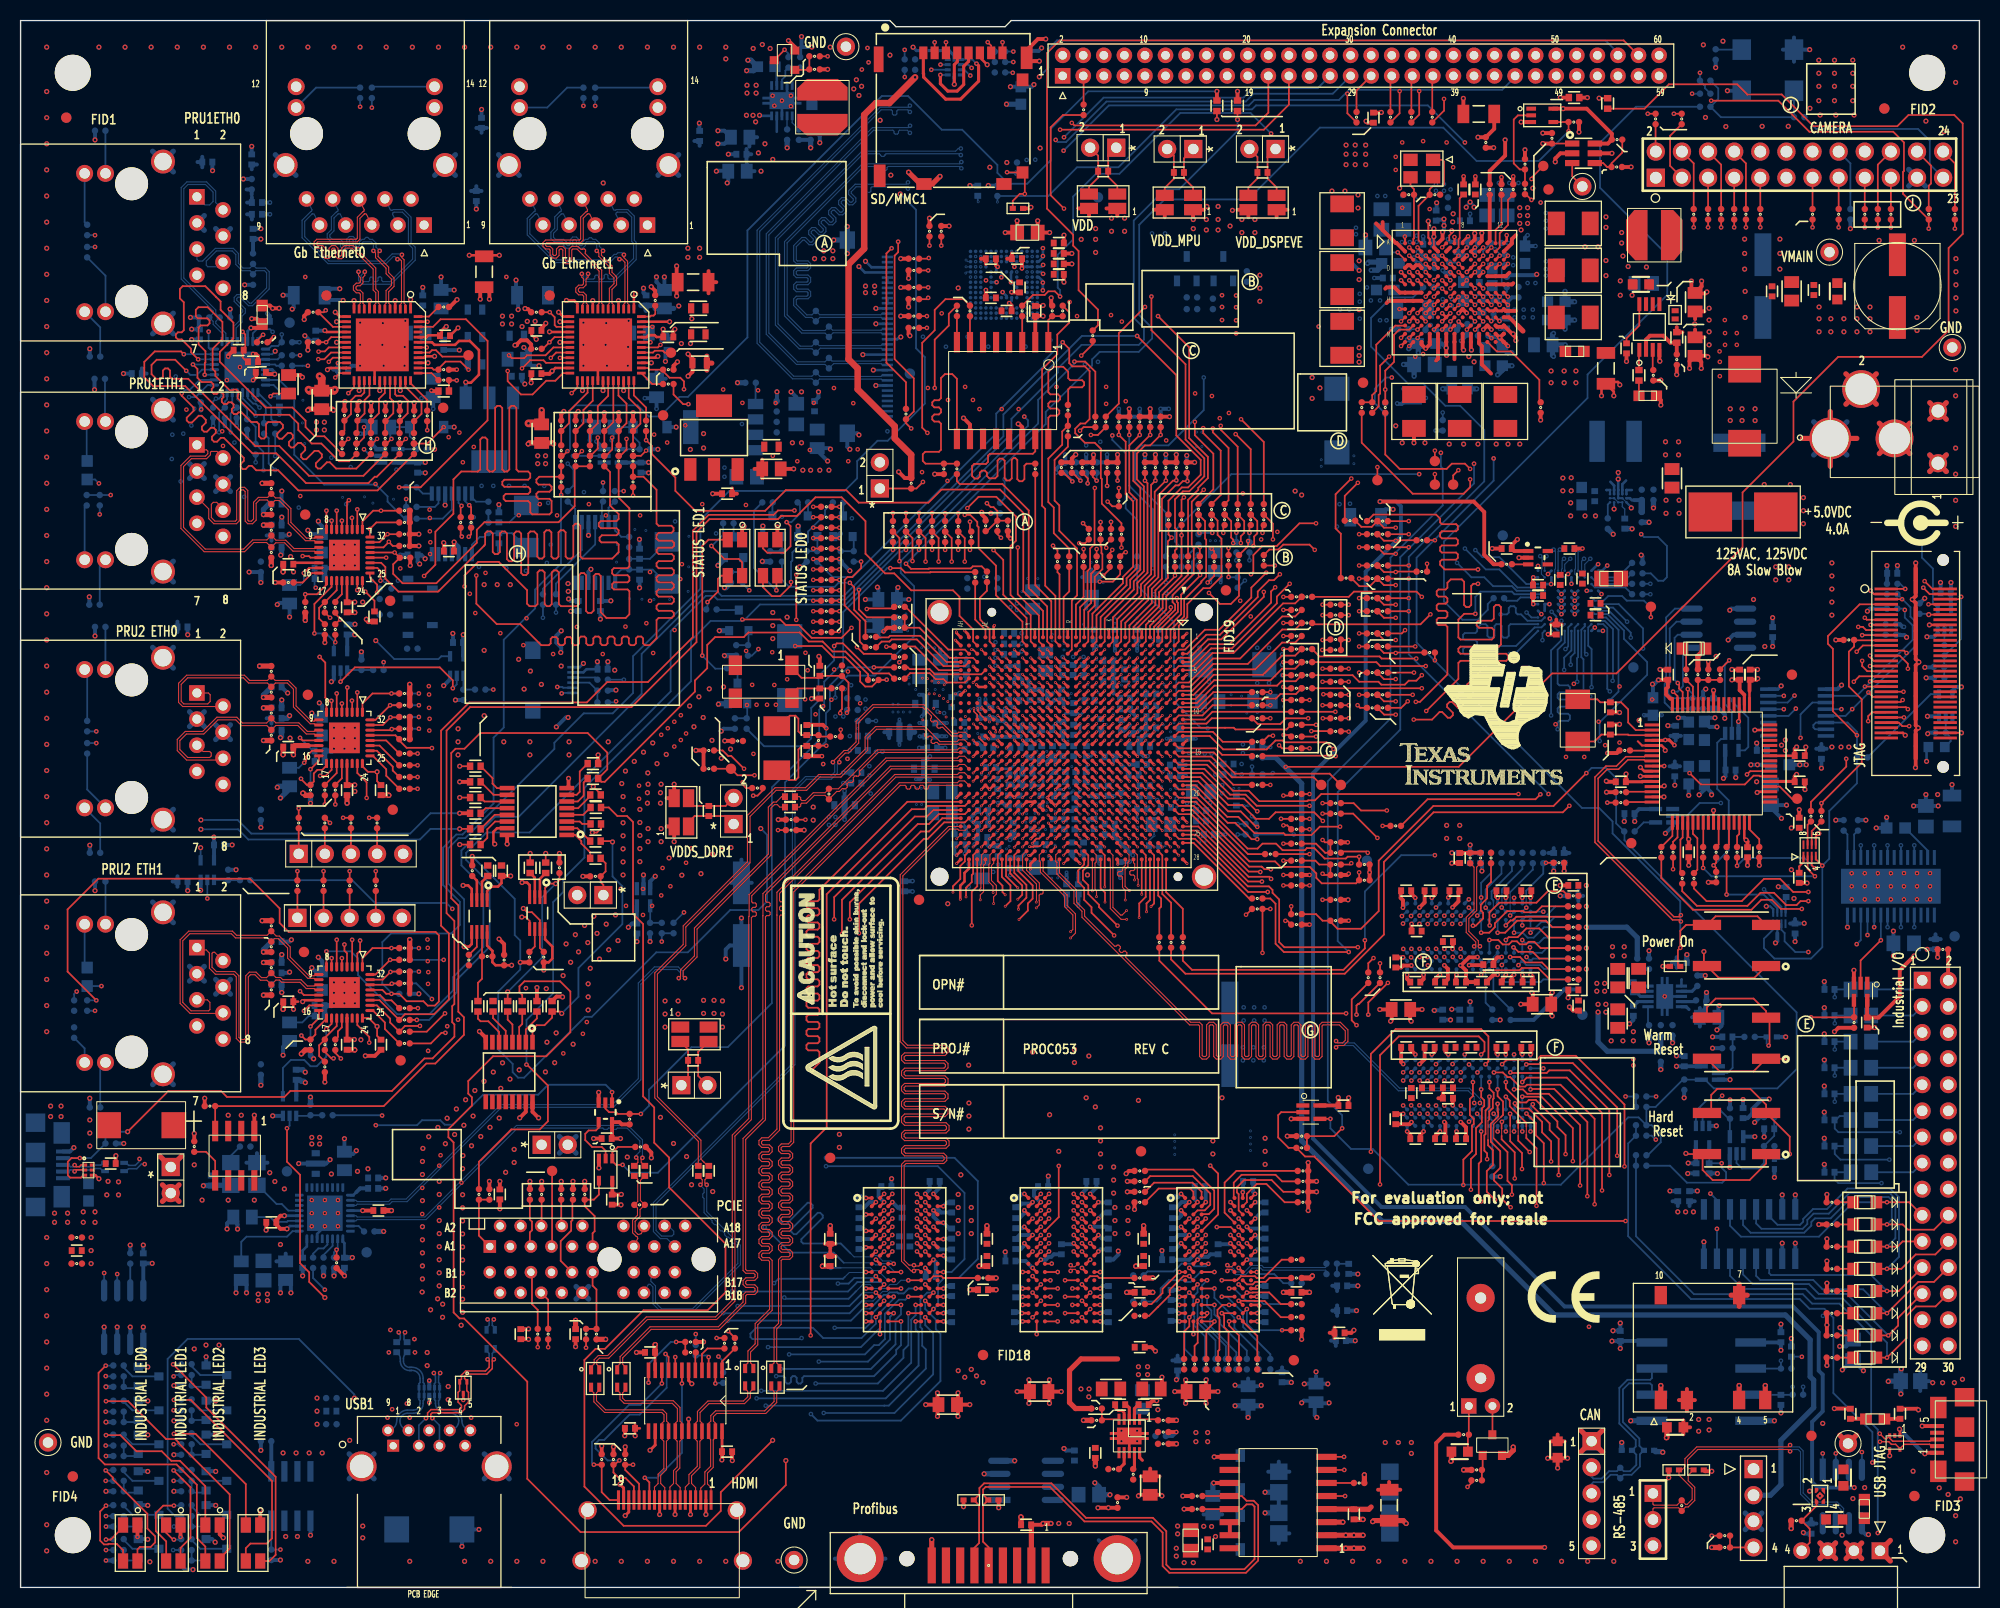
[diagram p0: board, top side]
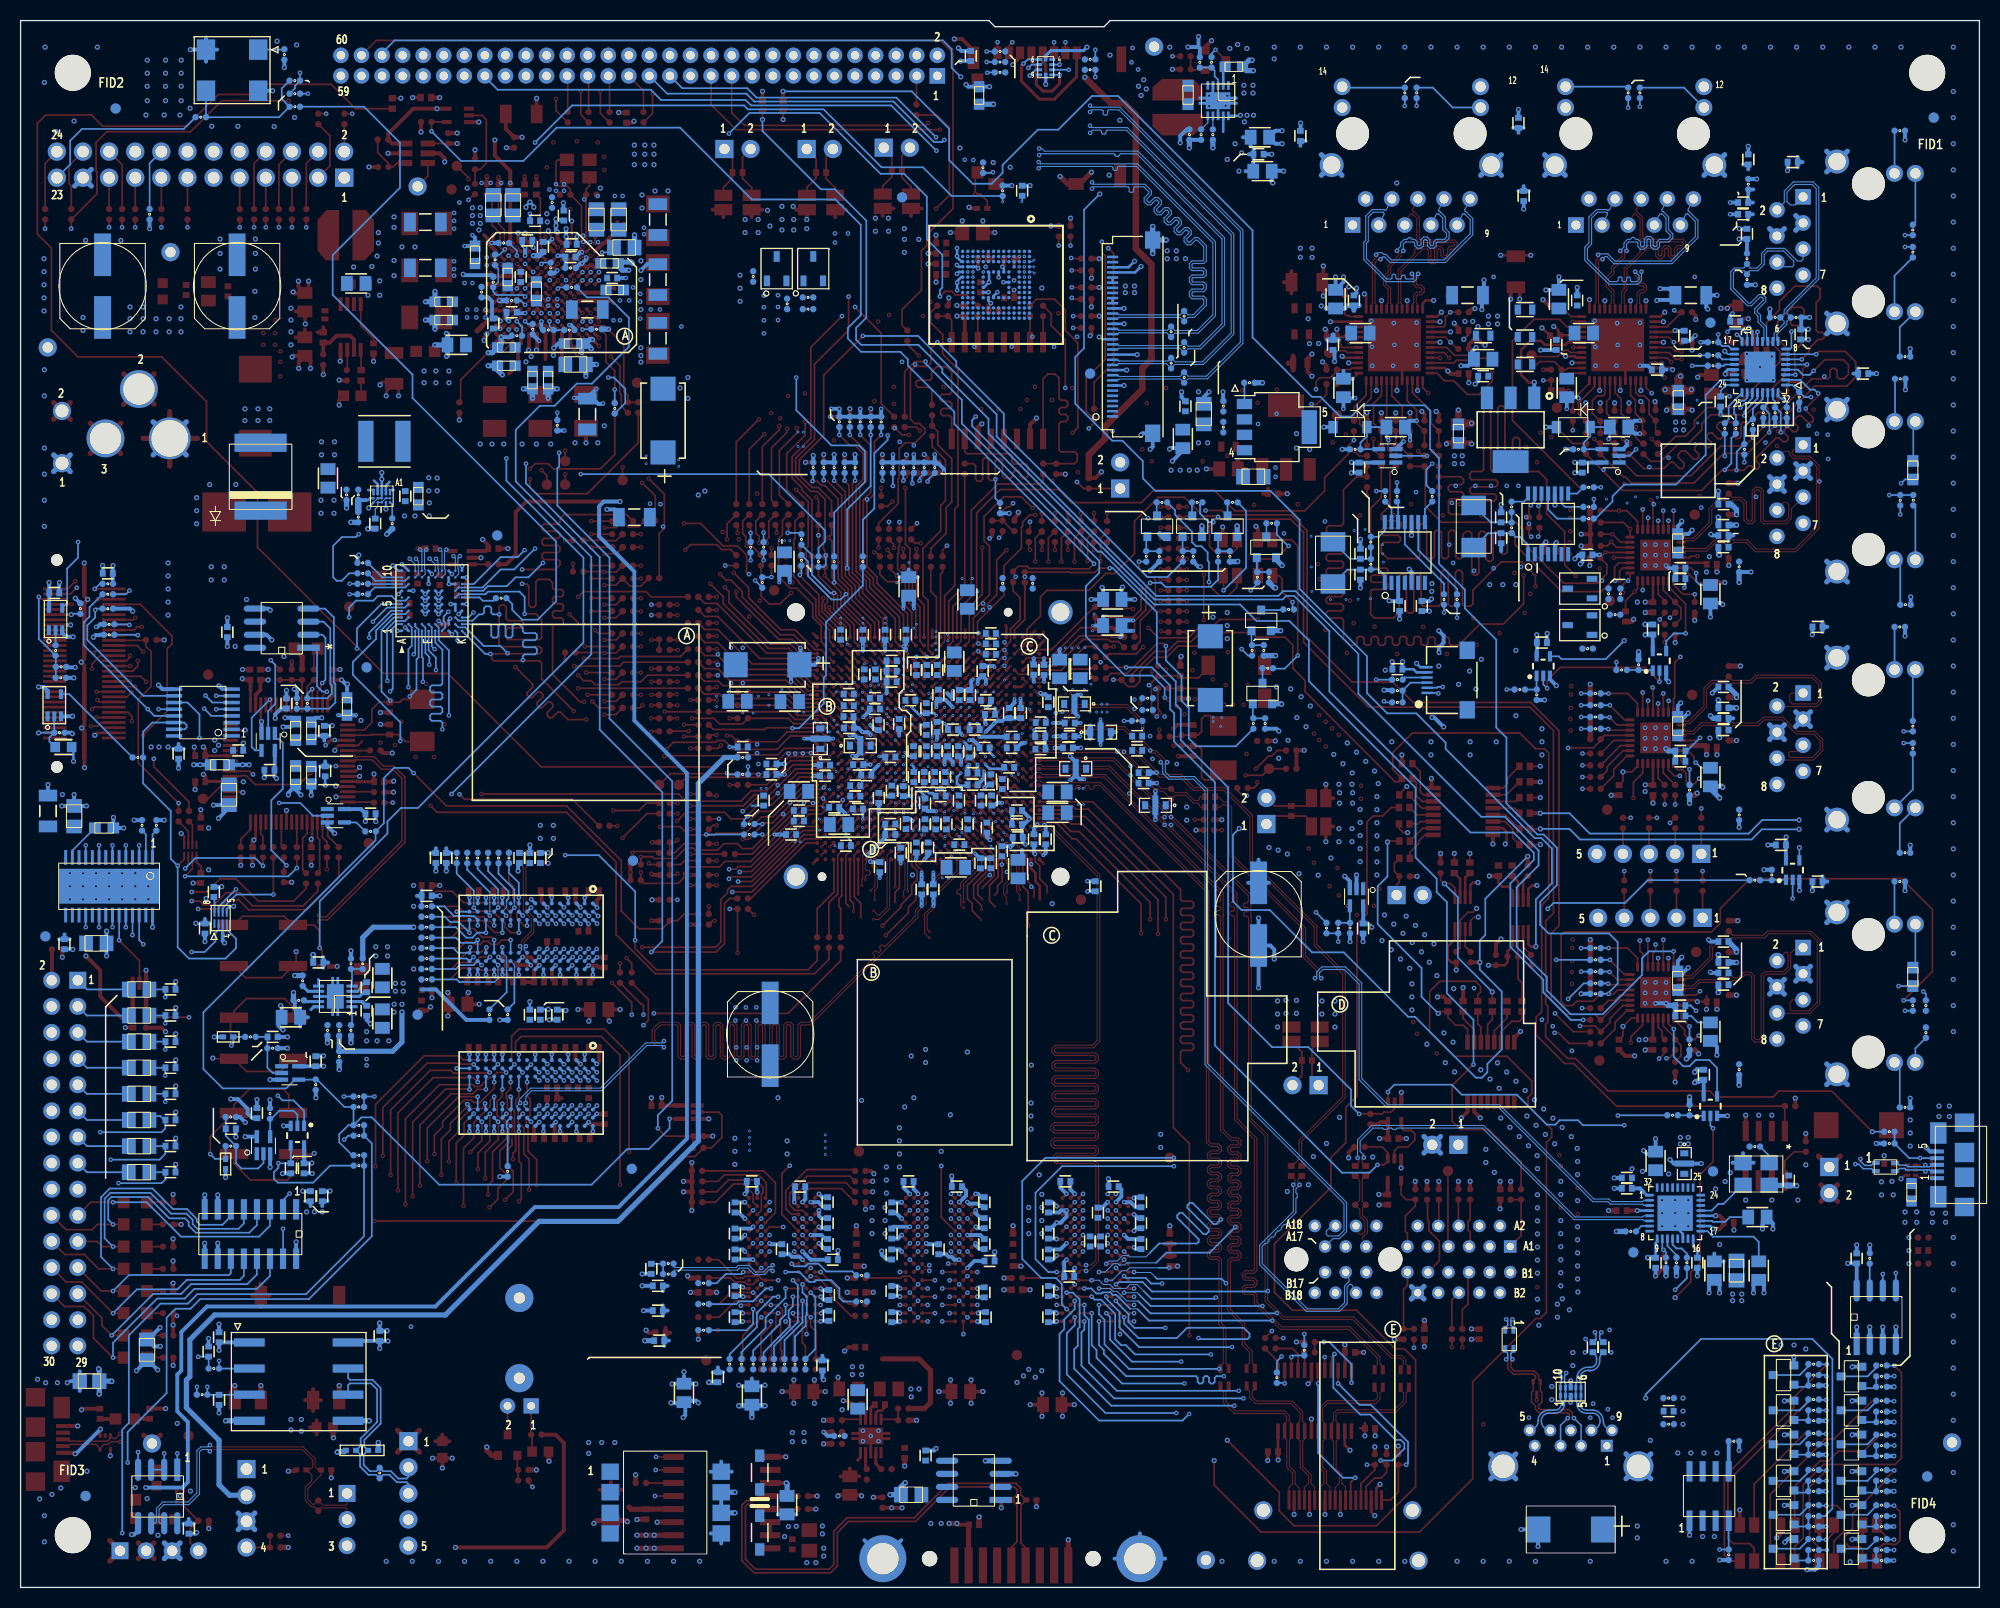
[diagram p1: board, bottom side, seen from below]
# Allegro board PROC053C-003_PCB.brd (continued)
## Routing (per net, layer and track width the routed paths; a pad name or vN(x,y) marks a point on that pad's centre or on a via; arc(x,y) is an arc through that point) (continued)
DDR2_ODT: length 125.7
  TOP w0.173: v7(132.21,39.2) 132.21,51.77 134.04,53.6 141.81,53.6 142.37,53.04 142.37,52.17 v2(142.04,51.84) ; U1.R23 v4(101.44,74.42)
  L3_SIG1 w0.109: v4(101.44,74.42) 101.79,74.06 v5(101.8,74.06) ; v7(132.21,39.2) 132.18,39.17 v5(131.44,39.17) ; v2(142.04,51.84) 142.04,52.2 141.05,53.19 141.05,56.16 141.43,56.55 141.43,57.61 141.32,57.72 141,57.72 140.89,57.83 140.89,58.05 141,58.16 141.32,58.16 141.43,58.27 141.43,58.49 141.32,58.6 141,58.6 140.89,58.71 140.89,58.92 141,59.03 141.32,59.03 141.43,59.14 141.43,60.43 142.09,61.09 142.09,61.75 142.32,61.98 142.32,62.54 142.06,62.79 142.06,63.12 142.44,63.51 142.44,63.84 142.09,64.19 142.09,66.99 142.04,67.04 v2(142.04,67.11)
  L4_SIG2 w0.114: v5(131.44,39.17) 128.93,39.17 125.73,42.37 122.83,42.37 122.15,43.06 120.93,43.06 120.12,43.87 120.12,44.2 119.3,45.01 115.11,45.01 110.16,49.97 110.16,50.42 110.05,50.53 109.51,50.53 109.4,50.65 109.4,50.88 109.51,50.99 110.05,50.99 110.16,51.11 110.16,51.33 110.05,51.45 109.51,51.45 109.4,51.56 109.4,51.79 109.51,51.91 110.05,51.91 110.16,52.02 110.16,52.25 110.05,52.36 109.51,52.36 109.4,52.48 109.4,52.71 109.51,52.82 110.05,52.82 110.16,52.93 110.16,53.16 110.05,53.28 109.51,53.28 109.4,53.39 109.4,53.62 109.51,53.73 110.05,53.73 110.16,53.85 110.16,54.32 109.68,54.79 109.52,54.79 109.09,54.37 108.93,54.37 108.77,54.53 108.77,54.69 109.2,55.12 109.2,55.28 109.04,55.44 108.87,55.44 108.45,55.01 108.29,55.01 108.12,55.18 108.12,55.34 108.55,55.76 108.55,55.93 108.39,56.09 108.23,56.09 107.8,55.66 107.64,55.66 107.48,55.82 107.48,55.98 107.9,56.41 107.9,56.57 107.74,56.73 107.58,56.73 107.15,56.31 106.99,56.31 106.83,56.47 106.83,56.63 107.26,57.06 107.26,57.22 107.1,57.38 106.93,57.38 106.51,56.95 106.35,56.95 106.18,57.12 106.18,57.28 106.61,57.7 106.61,57.87 106.45,58.03 106.29,58.03 105.86,57.6 105.7,57.6 105.54,57.76 105.54,57.92 105.96,58.35 105.96,58.51 105.8,58.67 105.64,58.67 105.21,58.25 105.05,58.25 104.89,58.41 104.89,58.57 105.32,59 105.32,59.16 105.16,59.32 104.99,59.32 104.57,58.89 104.41,58.89 104.24,59.06 104.24,59.22 104.67,59.64 104.67,59.81 104.51,59.97 104.35,59.97 103.92,59.54 103.76,59.54 103.6,59.7 103.6,59.86 104.02,60.29 104.02,60.45 103.86,60.61 103.7,60.61 103.27,60.19 103.11,60.19 102.95,60.35 102.95,60.51 103.38,60.94 103.38,61.1 103.22,61.26 103.05,61.26 102.63,60.83 102.47,60.83 102.3,61 102.3,61.16 102.73,61.58 102.73,61.75 102.57,61.91 102.41,61.91 101.98,61.48 101.82,61.48 101.66,61.64 101.66,61.8 102.08,62.23 102.08,62.39 101.73,62.75 101.73,68.64 102.19,69.1 102.19,73.67 v5(101.8,74.06)
  BOTTOM w0.173: U91.K1 v2(142.04,67.11) 142.04,68.53 143,69.49 R778.2 ; U90.K1 v2(142.04,51.84)
DDR2_RASN: length 126.5
  TOP w0.173: U1.T23 v4(100.64,74.42) ; R758.2 143,68.61 142.62,68.23 142.62,67.02 142.01,66.41 142.01,65.84 142.23,65.62 142.23,65.07 141.52,64.36 v2(141.24,64.36) ; v2(141.24,49.15) 141.24,47.8 140.95,47.51 140.95,45.95 141.33,45.57 141.33,45.09 141.15,44.91 141.15,42.45 140.31,41.61 v7(140.31,39.15)
  L3_SIG1 w0.109: v7(140.31,39.15) v5(139.73,39.15) ; v2(141.24,64.36) 140.89,64.36 138.86,62.33 138.86,58.95 138.73,58.83 138.44,58.83 138.33,58.72 138.33,58.5 138.44,58.39 138.79,58.39 138.9,58.28 138.9,57.42 139.75,56.57 139.75,53.37 141,52.13 141,51.57 141.3,51.26 141.3,50.42 141.24,50.37 v2(141.24,49.15) ; v5(101,74.06) 100.99,74.06 v4(100.64,74.42)
  L9_SIG3 w0.114: v5(101,74.06) 100.61,73.67 100.61,71.54 100.77,71.38 100.77,70.63 100.59,70.44 100.59,58.35 111.83,47.11 115.47,47.11 115.58,47.22 115.58,47.62 115.7,47.73 115.93,47.73 116.04,47.62 116.04,47.22 116.15,47.11 117.33,47.11 117.45,47.22 117.45,47.72 117.56,47.83 117.79,47.83 117.9,47.72 117.9,47.22 118.02,47.11 118.25,47.11 118.36,47.22 118.36,47.72 118.47,47.83 118.7,47.83 118.82,47.72 118.82,47.22 118.93,47.11 119.16,47.11 119.27,47.22 119.27,47.72 119.39,47.83 119.62,47.83 119.73,47.72 119.73,47.22 119.85,47.11 120.07,47.11 120.19,47.22 120.19,47.72 120.3,47.83 120.53,47.83 120.65,47.72 120.65,47.22 120.76,47.11 120.99,47.11 121.1,47.22 121.1,47.72 121.22,47.83 121.45,47.83 121.56,47.72 121.56,47.22 121.67,47.11 121.9,47.11 122.02,47.22 122.02,47.72 122.13,47.83 122.36,47.83 122.47,47.72 122.47,47.22 122.59,47.11 122.77,47.11 124.59,45.29 124.59,42.7 126.01,41.28 126.01,41.12 125.56,40.67 125.56,40.51 125.72,40.35 125.89,40.35 126.33,40.79 126.49,40.79 127.26,40.03 127.26,39.87 126.83,39.43 126.83,39.27 126.99,39.11 127.15,39.11 127.59,39.54 127.75,39.54 127.91,39.38 127.91,39.22 127.47,38.78 127.47,38.62 127.64,38.46 127.8,38.46 128.23,38.9 128.39,38.9 128.88,38.41 129.29,38.41 129.41,38.52 129.41,39.06 129.52,39.17 129.75,39.17 129.86,39.06 129.86,38.52 129.98,38.41 130.21,38.41 130.32,38.52 130.32,39.06 130.44,39.17 130.66,39.17 130.78,39.06 130.78,38.52 130.89,38.41 132.14,38.41 132.25,38.52 132.25,39.06 132.36,39.17 132.59,39.17 132.71,39.06 132.71,38.52 132.82,38.41 133.05,38.41 133.16,38.52 133.16,39.06 133.28,39.17 133.51,39.17 133.62,39.06 133.62,38.52 133.74,38.41 133.96,38.41 134.08,38.52 134.08,39.06 134.19,39.17 134.42,39.17 134.54,39.06 134.54,38.52 134.65,38.41 134.88,38.41 134.99,38.52 134.99,39.06 135.11,39.17 135.34,39.17 135.45,39.06 135.45,38.52 135.57,38.41 135.79,38.41 135.91,38.52 135.91,39.06 136.02,39.17 136.25,39.17 136.37,39.06 136.37,38.52 136.48,38.41 136.71,38.41 136.82,38.52 136.82,39.06 136.94,39.17 137.17,39.17 137.28,39.06 137.28,38.52 137.39,38.41 137.97,38.41 138.71,39.15 v5(139.73,39.15)
  BOTTOM w0.173: U90.J3 v2(141.24,49.15) ; U91.J3 v2(141.24,64.36)
DDR2_RESETN: length 105.9
  TOP w0.173: R913.2 v7(148.34,70.48) ; U1.R24 v4(101.44,73.62)
  L3_SIG1 w0.109: v7(148.34,70.48) 148.34,65.97 v2(148.09,65.73) 149.99,63.83 149.99,52.39 v2(148.09,50.49) 148.09,42.56 146.91,41.38 v5(146.91,40.47) ; v4(101.44,73.62) 101.79,73.26 v5(101.8,73.26)
  L9_SIG3 w0.114: v5(146.91,40.47) 146.5,40.06 145.19,40.06 144.77,40.47 143.68,40.47 143.3,40.1 128.45,40.1 125.61,42.94 125.61,45.88 122.71,48.77 112.8,48.77 101.72,59.86 101.72,69.1 101.3,69.52 101.3,70.82 101.41,70.94 101.41,72.87 v5(101.8,73.26)
  BOTTOM w0.173: U91.T2 v2(148.09,65.73) ; U90.T2 v2(148.09,50.49)
DDR2_WEN: length 129.4
  TOP w0.102: 142.71,43.5 142.71,43.51 142.71,45.4 142.83,45.52
  TOP w0.173: v2(142.87,64.39) 142.84,64.42 142.84,65.65 143.79,66.6 147.42,66.6 148.54,67.72 150.04,67.72 R760.2 ; 142.83,45.52 142.83,46.28 143.18,46.63 143.18,47.48 143.26,47.56 143.26,48.11 142.84,48.53 v2(142.84,49.15) ; U1.U25 v4(99.84,72.82) ; v7(143.38,37.7) 142.59,38.49 142.59,40.5 143.19,41.1 143.19,42.53 142.71,43 142.71,43.5
  L3_SIG1 w0.109: v2(142.87,64.39) 142.9,64.36 142.9,63.48 143.23,63.15 143.23,62.74 142.88,62.38 142.88,60.94 142.98,60.84 142.98,56.55 142.44,56.01 142.44,55.78 142.33,55.67 142.07,55.67 141.96,55.56 141.96,55.34 142.07,55.23 142.33,55.23 142.44,55.12 142.44,54.91 142.33,54.8 142.07,54.8 141.96,54.69 141.96,54.47 142.07,54.36 142.33,54.36 142.44,54.25 142.44,54.03 142.33,53.92 142.07,53.92 141.96,53.81 141.96,53.59 142.07,53.49 142.33,53.49 142.44,53.38 142.44,53.24 142.72,52.96 142.72,51.24 142.94,51.02 142.94,50.77 142.84,50.67 v2(142.84,49.15) ; v7(143.38,37.7) v5(142.72,37.7) ; v4(99.84,72.82) 99.84,72.82 100.2,72.46 v5(100.2,72.46)
  L9_SIG3 w0.114: v5(100.2,72.46) 99.17,71.43 99.17,57.88 111.36,45.69 120.15,45.69 121.92,43.92 121.92,39.1 125.96,35.06 126.48,35.06 126.82,34.71 126.82,34.54 126.94,34.42 127.17,34.42 127.28,34.54 127.28,34.94 127.39,35.06 127.62,35.06 127.74,34.94 127.74,34.54 127.85,34.42 128.08,34.42 128.19,34.54 128.19,34.94 128.31,35.06 128.54,35.06 128.65,34.94 128.65,34.54 128.77,34.42 128.99,34.42 129.11,34.54 129.11,34.94 129.22,35.06 129.45,35.06 129.57,34.94 129.57,34.54 129.68,34.42 129.91,34.42 130.02,34.54 130.02,34.94 130.14,35.06 130.37,35.06 130.48,34.94 130.48,34.54 130.59,34.42 130.82,34.42 130.94,34.54 130.94,34.94 131.05,35.06 131.28,35.06 131.39,34.94 131.39,34.54 131.51,34.42 131.74,34.42 131.85,34.54 131.85,34.94 131.97,35.06 132.19,35.06 132.31,34.94 132.31,34.54 132.42,34.42 132.65,34.42 132.77,34.54 132.77,34.94 132.88,35.06 133.11,35.06 133.22,34.94 133.22,34.54 133.34,34.42 133.57,34.42 133.68,34.54 133.68,34.94 133.79,35.06 134.02,35.06 134.14,34.94 134.14,34.54 134.25,34.42 134.48,34.42 134.59,34.54 134.59,34.94 134.71,35.06 134.94,35.06 135.05,34.94 135.05,34.54 135.17,34.42 135.39,34.42 135.51,34.54 135.51,34.94 135.62,35.06 135.85,35.06 135.97,34.94 135.97,34.54 136.08,34.42 136.31,34.42 136.42,34.54 136.42,34.94 136.54,35.06 136.77,35.06 136.88,34.94 136.88,34.54 136.99,34.42 137.22,34.42 137.34,34.54 137.34,34.94 137.45,35.06 137.68,35.06 137.8,34.94 137.8,34.54 137.91,34.42 138.14,34.42 138.25,34.54 138.25,34.94 138.37,35.06 138.6,35.06 138.71,34.94 138.71,34.54 138.82,34.42 139.05,34.42 139.17,34.54 139.17,34.94 139.28,35.06 140.08,35.06 v5(142.72,37.7)
  BOTTOM w0.173: v2(142.87,64.39) 142.84,64.42 U91.L3 ; U90.L3 v2(142.84,49.15)
DDR_A0: length 146.4
  TOP w0.173: U7.N3 v2(100.15,28.28) ; U1.AD20 v4(94.24,76.82) ; U6.N3 v2(115.39,28.28) ; U5.N3 v2(84.91,28.28)
  L3_SIG1 w0.109: v2(115.39,28.28) 114.23,28.28 113.03,27.08 112.32,27.08 111.84,26.6 108.97,26.6 108.82,26.45 108.57,26.45 108.42,26.6 108.16,26.6 108.01,26.45 107.76,26.45 107.61,26.6 107.35,26.6 107.21,26.45 106.95,26.45 106.8,26.6 105.74,26.6 105.26,27.08 104.72,27.08 104.32,27.49 103.89,27.49 103.83,27.43 103.03,27.43 102.59,27.87 101.4,27.87 100.99,28.28 v2(100.15,28.28) 98.88,28.28 97.69,27.08 97.08,27.08 96.6,26.6 96.15,26.6 96,26.45 95.75,26.45 95.6,26.6 95.34,26.6 95.2,26.45 94.94,26.45 94.79,26.6 94.54,26.6 94.39,26.45 94.13,26.45 93.98,26.6 93.73,26.6 93.58,26.45 93.33,26.45 93.18,26.6 92.92,26.6 92.77,26.45 92.52,26.45 92.37,26.6 92.11,26.6 91.97,26.45 91.71,26.45 91.56,26.6 91.31,26.6 91.12,26.42 90.66,26.42 89.99,27.08 89.48,27.08 89.1,27.46 87.7,27.46 87.27,27.89 86.14,27.89 85.75,28.28 v2(84.91,28.28) ; v4(94.24,76.82) v5(93.84,76.57)
  L10_SIG4 w0.109: v5(93.84,76.57) 92.17,76.57 91.69,77.04 90.35,77.04 89.15,75.85 85.27,75.85 74.41,64.99 74.41,57.24 74.3,57.13 73.72,57.13 73.61,57.02 73.61,56.8 73.72,56.69 74.3,56.69 74.41,56.58 74.41,56.37 74.3,56.26 73.72,56.26 73.61,56.15 73.61,55.93 73.72,55.82 74.3,55.82 74.41,55.71 74.41,55.49 74.3,55.38 73.72,55.38 73.61,55.27 73.61,55.05 73.72,54.95 74.3,54.95 74.41,54.84 74.41,54.62 74.3,54.51 73.72,54.51 73.61,54.4 73.61,54.18 73.72,54.07 74.3,54.07 74.41,53.96 74.41,53.74 74.3,53.63 73.72,53.63 73.61,53.53 73.61,53.31 73.72,53.2 74.3,53.2 74.41,53.09 74.41,52.87 74.3,52.76 73.72,52.76 73.61,52.65 73.61,52.43 73.72,52.32 74.3,52.32 74.41,52.22 74.41,52 74.3,51.89 73.72,51.89 73.61,51.78 73.61,51.56 73.72,51.45 74.3,51.45 74.41,51.34 74.41,51.12 74.3,51.01 73.72,51.01 73.61,50.9 73.61,50.69 73.72,50.58 74.3,50.58 74.41,50.47 74.41,50.25 74.3,50.14 73.72,50.14 73.61,50.03 73.61,49.81 73.72,49.7 74.3,49.7 74.41,49.59 74.41,49.38 74.3,49.27 73.72,49.27 73.61,49.16 73.61,48.94 73.72,48.83 74.3,48.83 74.41,48.72 74.41,48.5 74.3,48.39 73.72,48.39 73.61,48.28 73.61,48.06 73.72,47.96 74.3,47.96 74.41,47.85 74.41,47.63 74.3,47.52 73.72,47.52 73.61,47.41 73.61,47.19 73.72,47.08 74.3,47.08 74.41,46.97 74.41,46.75 74.3,46.64 73.72,46.64 73.61,46.54 73.61,46.32 73.72,46.21 74.3,46.21 74.41,46.1 74.41,45.88 74.3,45.77 73.95,45.77 73.84,45.66 73.84,45.44 73.95,45.33 74.3,45.33 74.41,45.22 74.41,43.01 70.99,39.6 70.99,34.5 71.01,34.48 71.01,34.48 71.49,33.99 71.49,25.03 72.69,23.84 v9(72.69,23.37)
  BOTTOM w0.173: v2(115.39,28.28) 115.39,27.35 115.81,26.94 115.81,26.2 115.68,26.08 115.68,25.42 117.5,23.61 117.5,23.6 118.24,22.86 R54.2 ; v9(72.69,23.37) 81.72,23.37 83.63,25.29 83.63,26.81 84.91,28.08 v2(84.91,28.28)
DDR_A1: length 145.9
  TOP w0.173: U1.AC19 v4(95.04,77.62) ; U6.P7 v2(117.53,27.48) 116.88,27.48 116.4,26.99 116.4,26.42 116.59,26.24 116.59,23.11 116.46,22.99 R57.2 ; U5.P7 v2(87.05,27.48) ; U7.P7 v2(102.29,27.48)
  L3_SIG1 w0.109: v4(95.04,77.62) v5(94.64,77.37)
  L10_SIG4 w0.109: v2(117.53,27.48) 116.67,27.48 116.26,27.89 115.95,27.89 115.44,27.39 114.1,27.39 112.98,26.27 108,26.27 107.87,26.14 107.58,26.14 107.46,26.26 107.14,26.26 107.03,26.14 107.03,26 106.91,25.88 106.74,25.88 106.62,26 106.62,26.14 106.5,26.26 106.1,26.26 105.28,27.08 104.7,27.08 104.3,27.48 v2(102.29,27.48) 101.41,27.48 101.02,27.87 100.69,27.87 100.23,27.41 99.75,27.41 99.15,26.82 98.29,26.82 97.74,26.27 93.61,26.27 93.39,26.05 93.15,26.05 92.94,26.26 92.71,26.26 92.59,26.14 92.59,26 92.48,25.88 92.31,25.88 92.19,26 92.19,26.14 92.07,26.26 91.9,26.26 91.79,26.14 91.79,26 91.67,25.88 91.5,25.88 91.38,26 91.38,26.14 91.26,26.26 90.86,26.26 90.04,27.08 89.53,27.08 89.14,27.48 v2(87.05,27.48) ; v9(72.03,19.13) 71.22,19.94 71.22,23.75 70.61,24.36 70.61,33.63 70.13,34.11 70.13,34.12 70.11,34.13 70.11,34.14 70.08,34.17 70.08,39.47 72.62,42.01 72.62,58.79 72.73,58.9 73.25,58.9 73.36,59 73.36,59.22 73.25,59.33 72.73,59.33 72.62,59.44 72.62,59.66 72.73,59.77 73.25,59.77 73.36,59.88 73.36,60.1 73.25,60.21 72.73,60.21 72.62,60.32 72.62,60.53 72.73,60.64 73.25,60.64 73.36,60.75 73.36,60.97 73.25,61.08 72.73,61.08 72.62,61.19 72.62,61.41 72.73,61.52 73.25,61.52 73.36,61.63 73.36,61.84 73.25,61.95 72.73,61.95 72.62,62.06 72.62,62.28 72.73,62.39 73.25,62.39 73.36,62.5 73.36,62.72 73.25,62.83 72.73,62.83 72.62,62.94 72.62,63.84 85.23,76.45 89.27,76.45 90.27,77.45 92.23,77.45 92.71,76.97 94.24,76.97 v5(94.64,77.37)
  BOTTOM w0.173: v9(72.03,19.13) 83.88,19.13 86.61,21.86 86.61,26.04 87.05,26.48 v2(87.05,27.48)
DDR_A2: length 147.3
  TOP w0.173: U6.P3 v2(116.1,27.48) ; U7.P3 v2(100.86,27.48) ; U1.AC20 v4(95.04,76.82) ; U5.P3 v2(85.62,27.48)
  L3_SIG1 w0.109: v4(95.04,76.82) v5(94.64,76.57) ; v2(116.1,27.48) 114.76,27.48 113.96,26.67 113.49,26.67 113.26,26.45 113.26,25.89 112.85,25.49 104.66,25.49 103.47,26.67 102.16,26.67 101.75,27.08 101.26,27.08 v2(100.86,27.48) 99.52,27.48 98.82,26.78 98.35,26.78 97.99,26.42 97.99,25.87 97.45,25.32 96.79,25.32 96.56,25.55 95.84,25.55 95.61,25.32 89.59,25.32 88.23,26.67 86.89,26.67 86.49,27.08 86.02,27.08 v2(85.62,27.48)
  L10_SIG4 w0.109: v5(94.64,76.57) 94.24,76.17 91.79,76.17 91.56,75.95 90.3,75.95 89.74,75.39 85.45,75.39 75.57,65.51 75.57,55.3 75.56,55.3 75.56,55.22 75.67,55.11 76.14,55.11 76.25,55 76.25,54.79 76.14,54.68 75.67,54.68 75.56,54.57 75.56,54.35 75.67,54.24 76.14,54.24 76.25,54.13 76.25,53.91 76.14,53.8 75.67,53.8 75.56,53.69 75.56,53.47 75.67,53.37 76.17,53.37 76.28,53.26 76.28,53.04 76.17,52.93 75.67,52.93 75.56,52.82 75.56,52.6 75.67,52.49 76.22,52.49 76.33,52.38 76.33,52.16 76.22,52.05 75.67,52.05 75.56,51.95 75.56,51.73 75.67,51.62 76.22,51.62 76.33,51.51 76.33,51.29 76.22,51.18 75.67,51.18 75.56,51.07 75.56,50.85 75.67,50.74 76.22,50.74 76.33,50.63 76.33,50.42 76.22,50.31 75.67,50.31 75.56,50.2 75.56,49.98 75.67,49.87 76.22,49.87 76.33,49.76 76.33,49.54 76.22,49.43 75.67,49.43 75.56,49.32 75.56,49.11 75.67,49 76.22,49 76.33,48.89 76.33,48.67 76.22,48.56 75.67,48.56 75.56,48.45 75.56,48.23 75.67,48.12 76.22,48.12 76.33,48.01 76.33,47.8 76.22,47.69 75.67,47.69 75.56,47.58 75.56,47.36 75.67,47.25 76.22,47.25 76.33,47.14 76.33,46.92 76.22,46.81 75.67,46.81 75.56,46.7 75.56,46.48 75.67,46.38 76.22,46.38 76.33,46.27 76.33,46.05 76.22,45.94 75.67,45.94 75.56,45.83 75.56,45.61 75.67,45.5 76.22,45.5 76.33,45.39 76.33,45.17 76.22,45.06 75.67,45.06 75.56,44.96 75.56,43.33 71.91,39.67 71.91,34.87 72.38,34.39 72.38,25.79 73.94,24.24 v9(73.94,21.25)
  BOTTOM w0.173: v9(73.94,21.25) 82.7,21.25 85.09,23.65 85.09,26.03 85.62,26.57 v2(85.62,27.48) ; v2(116.1,27.48) 116.1,26.54 116.67,25.97 116.67,25.62 119.25,23.04 R55.2
DDR_A3: length 146.1
  TOP w0.173: U6.N2 v2(113.66,28.68) ; U5.N2 v2(83.18,28.68) ; U1.AB19 v4(95.84,77.62) ; U7.N2 v2(98.42,28.68)
  L3_SIG1 w0.109: v2(83.18,28.68) 86.52,28.68 86.92,28.28 88.14,28.28 88.54,27.87 90.1,27.87 90.94,27.03 91.34,27.03 91.55,27.24 91.74,27.24 91.95,27.03 92.15,27.03 92.36,27.24 92.55,27.24 92.74,27.06 92.98,27.06 93.16,27.24 93.36,27.24 93.54,27.06 93.79,27.06 93.97,27.24 94.17,27.24 94.35,27.06 94.59,27.06 94.78,27.24 94.98,27.24 95.18,27.03 96.3,27.03 97.13,27.87 97.61,27.87 v2(98.42,28.68) 101.76,28.68 102.25,28.19 102.99,28.19 103.08,28.28 103.45,28.28 103.86,27.87 105.34,27.87 106.18,27.03 107.39,27.03 107.6,27.24 107.79,27.24 107.98,27.06 108.22,27.06 108.4,27.24 108.6,27.24 108.78,27.06 109.09,27.06 109.24,27.21 109.48,27.21 109.63,27.06 111.56,27.06 112.37,27.87 112.85,27.87 v2(113.66,28.68) ; v4(95.84,77.62) v5(95.44,77.37)
  L10_SIG4 w0.109: v9(69.73,27.37) 69.73,27.42 69.73,27.42 69.73,33.25 69.16,33.82 69.16,39.32 70.73,40.89 70.73,42.26 70.87,42.4 71.83,42.4 72.04,42.61 72.04,43.13 71.93,43.24 70.98,43.24 70.87,43.35 70.87,43.57 70.98,43.68 71.93,43.68 72.04,43.79 72.04,44 71.93,44.11 70.98,44.11 70.87,44.22 70.87,44.44 70.98,44.55 71.93,44.55 72.04,44.66 72.04,44.88 71.93,44.99 70.98,44.99 70.87,45.1 70.87,45.32 70.98,45.42 71.93,45.42 72.04,45.53 72.04,45.75 71.93,45.86 70.98,45.86 70.87,45.97 70.87,46.19 70.98,46.3 71.93,46.3 72.04,46.41 72.04,46.63 71.93,46.73 70.98,46.73 70.87,46.84 70.87,47.06 70.98,47.17 71.93,47.17 72.04,47.28 72.04,47.5 71.93,47.61 70.98,47.61 70.87,47.72 70.87,47.94 70.98,48.05 71.93,48.05 72.04,48.15 72.04,48.37 71.93,48.48 70.98,48.48 70.87,48.59 70.87,48.81 70.98,48.92 71.93,48.92 72.04,49.03 72.04,49.25 71.93,49.36 70.98,49.36 70.87,49.47 70.87,49.68 70.98,49.79 71.93,49.79 72.04,49.9 72.04,50.12 71.93,50.23 70.9,50.23 70.79,50.34 70.79,50.56 70.9,50.67 71.93,50.67 72.04,50.78 72.04,51.07 71.93,51.18 71.48,51.18 71.37,51.29 71.37,51.51 71.48,51.62 71.93,51.62 72.04,51.73 72.04,63.92 85.01,76.89 89.24,76.89 90.1,77.75 95.05,77.75 v5(95.44,77.37)
  BOTTOM w0.102: 81.72,28.48 81.9,28.66 83.17,28.66 v2(83.18,28.68)
  BOTTOM w0.173: R58.2 113.21,23.19 113.21,28.23 v2(113.66,28.68) ; 81.72,28.48 80.61,27.37 v9(69.73,27.37)
DDR_A4: length 145.2
  TOP w0.173: R59.2 122.55,26.29 120.98,27.86 120.05,27.86 120.04,27.88 v2(118.46,27.88) U6.P8 ; U1.AF21 v4(92.64,76.02) ; U7.P8 v2(103.22,27.88) ; U5.P8 v2(87.98,27.88)
  L3_SIG1 w0.099: 92.23,76.02 92.03,75.82
  L3_SIG1 w0.109: v4(92.64,76.02) 92.23,76.02 ; v5(75.13,38.21) 75.13,48.39 74.55,48.98 74.55,52.91 75.95,54.31 75.95,64.65 78.69,67.39 81.53,67.39 89.97,75.82 92.03,75.82
  L10_SIG4 w0.109: v2(118.46,27.88) 116.58,27.88 116.26,28.2 115.9,28.2 115.54,27.84 115.11,27.84 114.68,28.28 114.25,28.28 113.06,27.08 112.22,27.08 111.96,26.82 111.31,26.82 111.15,26.66 110.83,26.66 110.64,26.85 110.08,26.85 109.96,26.73 109.45,26.73 109.35,26.82 106.3,26.82 105.24,27.88 v2(103.22,27.88) 101.36,27.88 101.02,28.22 100.66,28.22 100.3,27.87 99.75,27.87 99.32,27.44 98.11,27.44 97.76,27.08 96.88,27.08 96.78,26.98 96.78,26.75 96.67,26.63 96.21,26.63 96.1,26.74 96.1,27.07 95.99,27.18 95.61,27.18 95.5,27.07 95.5,26.94 95.38,26.82 90.89,26.82 90.45,27.26 90.45,27.62 90.19,27.88 v2(87.98,27.88) ; v5(75.13,38.21) 75.13,29.62 76.86,27.9 76.86,24.06 76.41,23.61 75.6,23.61 75.2,23.22 75.2,19.45 75.06,19.31 73.57,19.31 73.43,19.17 73.43,18.97 73.57,18.83 75.06,18.83 75.2,18.69 75.2,18.49 75.06,18.35 73.36,18.35 73.23,18.22 73.23,18.02 73.37,17.87 74.51,17.87 75.52,16.87 v9(76.86,16.87)
  BOTTOM w0.173: v9(76.86,16.87) 77.5,16.23 85.62,16.23 89.46,20.07 89.46,24.66 89.01,25.12 89.01,26.06 87.98,27.08 v2(87.98,27.88)
DDR_A5: length 146
  TOP w0.173: U7.P2 v2(99.22,27.88) ; U1.AH22 88.78,75.62 88.15,74.98 86.97,74.98 79.12,67.14 v7(79.12,64.98) ; U6.P2 v2(114.46,27.88) ; U5.P2 v2(83.98,27.88)
  L3_SIG1 w0.109: v5(77.42,39.75) 77.42,52.84 78.71,54.13 78.71,64.57 v7(79.12,64.98) ; v2(83.98,27.88) 85.77,27.88 86.33,27.31 86.64,27.31 86.9,27.05 88.24,27.05 88.62,26.67 89.07,26.67 89.48,26.27 89.94,26.27 90.47,25.74 90.89,25.74 91.07,25.92 91.5,25.92 91.65,25.76 92.02,25.76 92.17,25.92 92.62,25.92 92.75,25.79 93.19,25.79 93.34,25.94 93.69,25.94 93.86,25.76 94.35,25.76 94.57,25.98 96.92,25.98 97.21,26.27 97.54,26.27 98.3,27.03 98.61,27.03 98.83,27.25 98.83,27.49 v2(99.22,27.88) 101.01,27.88 101.55,27.34 101.88,27.34 102.14,27.08 103.45,27.08 103.91,26.62 104.36,26.62 104.72,26.27 105.33,26.27 105.64,25.96 106.65,25.96 106.77,25.84 107.2,25.84 107.32,25.96 112.12,25.96 112.42,26.27 112.85,26.27 113.03,26.45 113.03,26.65 113.28,26.9 113.72,26.9 114.07,27.25 114.07,27.49 v2(114.46,27.88)
  L10_SIG4 w0.109: v5(77.42,39.75) 77.47,39.75 79.76,37.46 79.76,32.71 80.23,32.24 80.23,27.16 78.67,25.6 78.67,24.21 78.75,24.13 79.37,24.13 79.5,23.99 79.5,23.8 79.35,23.65 78.77,23.65 78.67,23.55 78.67,23.21 78.77,23.11 80.13,23.11 80.27,22.97 80.27,22.77 80.13,22.63 78.77,22.63 78.67,22.53 78.67,22.25 78.77,22.15 80.13,22.15 80.27,22.01 80.27,21.81 80.13,21.67 78.77,21.67 78.63,21.53 78.63,21.33 78.77,21.19 80.13,21.19 80.27,21.05 80.27,20.85 80.13,20.71 78.77,20.71 78.63,20.57 78.63,20.37 78.77,20.23 80.13,20.23 80.27,20.09 80.27,19.89 80.13,19.75 78.77,19.75 78.63,19.61 78.63,19.41 78.77,19.27 80.12,19.27 80.27,19.12 80.27,18.92 80.14,18.79 78.77,18.79 78.63,18.65 78.63,17.67 78.92,17.38 79.13,17.38 79.27,17.52 79.27,18.22 79.41,18.37 79.61,18.37 79.75,18.23 79.75,17.52 79.89,17.38 80.26,17.38 80.98,18.1 80.98,24.44 80.16,25.25 v9(79.17,25.25)
  BOTTOM w0.173: v2(83.98,27.88) 83.98,27.82 82.75,26.59 82.75,25.83 82.17,25.25 79.2,25.25 79.2,25.25 v9(79.17,25.25) ; v2(114.46,27.88) 114.46,25.78 116.2,24.03 R60.2
DDR_A6: length 146.9
  TOP w0.173: U1.AG23 91.83,74.41 89.83,74.41 88.22,72.81 87.84,72.81 81.53,66.5 v7(81.53,63.63) ; U7.R8 v2(104.02,27.08) ; U5.R8 v2(88.78,27.08) ; U6.R8 v2(119.26,27.08)
  L3_SIG1 w0.109: v7(81.53,63.63) 81.53,62.83 81.64,62.72 82.01,62.72 82.12,62.61 82.12,62.39 82.01,62.28 81.64,62.28 81.53,62.17 81.53,61.95 81.64,61.84 82.01,61.84 82.12,61.73 82.12,61.51 82.01,61.41 81.64,61.41 81.53,61.3 81.53,61.08 81.64,60.97 82.01,60.97 82.12,60.86 82.12,60.64 82.01,60.53 81.64,60.53 81.53,60.42 81.53,51.38 79,48.85 79,48.35 79.11,48.23 79.83,48.23 79.95,48.11 79.95,47.95 79.84,47.83 79.11,47.83 79,47.72 79,47.55 79.11,47.44 79.84,47.44 79.96,47.32 79.96,47.16 79.84,47.04 79.11,47.04 79,46.93 79,46.76 79.11,46.65 79.77,46.65 79.88,46.53 79.88,46.37 79.77,46.25 79.11,46.25 79,46.13 79,45.97 79.11,45.85 79.77,45.85 79.88,45.74 79.88,45.57 79.77,45.46 79.11,45.46 79,45.34 79,45.18 79.11,45.06 79.89,45.06 80.01,44.94 80.01,44.78 79.89,44.66 79.11,44.66 79,44.55 79,43.81 79.38,43.43 79.76,43.43 80.52,42.67 80.52,38.1 80.06,37.65 78.81,37.65 78.33,38.13 78.33,39.28 78.47,39.42 79.96,39.42 80.1,39.57 80.1,39.76 79.96,39.9 78.47,39.9 78.33,40.05 78.33,40.24 78.47,40.38 79.96,40.38 80.1,40.53 80.1,40.72 79.96,40.86 78.47,40.86 78.33,41.01 78.33,41.2 78.47,41.34 79.96,41.34 80.1,41.49 80.1,41.68 79.96,41.82 78.47,41.82 78.33,41.97 v5(78.33,43.13)
  L10_SIG4 w0.109: v5(78.33,43.13) v9(78.33,41.78) ; v2(88.78,27.08) 89.59,26.27 90.07,26.27 90.84,25.5 94.41,25.5 94.53,25.61 94.53,25.69 94.64,25.8 94.8,25.8 94.92,25.68 94.92,25.61 95.04,25.5 95.36,25.5 95.48,25.62 95.48,25.7 95.6,25.81 95.76,25.81 95.88,25.7 95.88,25.62 96,25.5 96.17,25.5 96.29,25.62 96.29,25.7 96.4,25.82 96.57,25.82 96.69,25.7 96.69,25.62 96.82,25.48 97.97,25.48 98.32,25.84 98.73,25.84 99.97,27.08 v2(104.02,27.08) 104.83,26.27 105.31,26.27 106.08,25.5 108.23,25.5 108.39,25.65 108.71,25.65 108.87,25.5 109.19,25.5 109.35,25.65 109.67,25.65 109.83,25.5 110.15,25.5 110.31,25.65 110.63,25.65 110.79,25.5 111.11,25.5 111.27,25.65 111.59,25.65 111.76,25.48 113.21,25.48 113.59,25.86 113.97,25.86 115.18,27.08 v2(119.26,27.08)
  BOTTOM w0.173: v9(78.33,41.78) 90.83,41.78 93.09,39.52 93.09,31.96 91.23,30.1 89.81,30.1 89.23,29.51 89.23,27.53 v2(88.78,27.08) ; v2(119.26,27.08) 119.26,25.65 119.89,25.02 R61.2
DDR_A7: length 143.8
  TOP w0.173: U5.R2 v2(83.18,26.28) ; U1.AE21 v4(93.44,76.02) ; U6.R2 v2(113.66,26.28) 113.66,25.39 113.16,24.89 R62.2 ; U7.R2 v2(98.42,26.28)
  L3_SIG1 w0.099: 91.98,76.15 92.13,76.31 92.76,76.31 93.05,76.02 v4(93.44,76.02)
  L3_SIG1 w0.109: 91.98,76.15 89.66,76.15 81.36,67.85 78.41,67.85 75.44,64.88 75.44,54.44 74.05,53.05 74.05,48.77 74.68,48.14 74.68,47.58 74.57,47.47 74.33,47.47 74.22,47.36 74.22,47.14 74.33,47.03 74.57,47.03 74.68,46.92 74.68,46.57 74.57,46.46 73.64,46.46 73.53,46.35 73.53,46.13 73.64,46.02 74.57,46.02 74.68,45.91 74.68,45.69 74.57,45.58 73.64,45.58 73.53,45.48 73.53,45.26 73.64,45.15 74.57,45.15 74.68,45.04 74.68,44.82 74.57,44.71 73.64,44.71 73.53,44.6 73.53,44.38 73.64,44.27 74.57,44.27 74.68,44.16 74.68,43.95 74.57,43.84 73.64,43.84 73.53,43.73 73.53,43.51 73.64,43.4 74.57,43.4 74.68,43.29 74.68,43.07 74.57,42.96 73.64,42.96 73.53,42.85 73.53,42.64 73.64,42.53 74.57,42.53 74.68,42.42 74.68,42.2 74.57,42.09 73.64,42.09 73.53,41.98 73.53,41.76 73.64,41.65 74.57,41.65 74.68,41.54 v5(74.68,39.75) ; v2(83.18,26.28) 84.01,27.11 85.34,27.11 86.16,26.29 87.34,26.29 88.84,24.79 97.65,24.79 98.42,25.56 v2(98.42,26.28) 99.1,26.28 99.9,27.08 100.61,27.08 101.4,26.29 102.49,26.29 103.88,24.9 112.68,24.9 113.66,25.88 v2(113.66,26.28)
  L10_SIG4 w0.109: v9(75.95,24.26) 76.35,24.65 76.35,25.29 76.24,25.4 75.12,25.4 75.01,25.5 75.01,25.7 75.14,25.83 76.26,25.83 76.35,25.92 76.35,26.18 76.26,26.27 75.12,26.27 75.01,26.38 75.01,26.58 75.14,26.71 76.26,26.71 76.4,26.85 76.4,27.73 74.68,29.46 v5(74.68,39.75)
  BOTTOM w0.173: v9(75.95,24.26) 75.85,24.15 71.18,24.15 70.98,24.35 70.98,24.69 71.55,25.25 77.05,25.25 78.05,24.26 81.79,24.26 83.18,25.65 v2(83.18,26.28)
DDR_A8: length 143.7
  TOP w0.173: U1.AF22 v4(92.64,75.22) ; U7.T8 v2(103.22,26.28) ; R63.2 120.27,24.47 U6.T8 118.86,25.92 118.5,26.28 v2(118.46,26.28) ; U5.T8 v2(87.98,26.28)
  L3_SIG1 w0.109: v4(92.64,75.22) 92.43,75.01 91.06,75.01 82.07,66.02 79.5,66.02 77.37,63.89 77.37,63.44 77.48,63.34 78.15,63.34 78.26,63.23 78.26,63.01 78.15,62.9 77.48,62.9 77.37,62.79 77.37,62.57 77.48,62.46 78.15,62.46 78.26,62.35 78.26,62.13 78.15,62.02 77.48,62.02 77.37,61.92 77.37,61.7 77.48,61.59 78.15,61.59 78.26,61.48 78.26,61.26 78.15,61.15 77.48,61.15 77.37,61.04 77.37,60.82 77.48,60.71 78.15,60.71 78.26,60.6 78.26,60.39 78.15,60.28 77.48,60.28 77.37,60.17 77.37,59.95 77.48,59.84 78.15,59.84 78.26,59.73 78.26,59.51 78.15,59.4 77.48,59.4 77.37,59.29 77.37,59.08 77.48,58.97 78.15,58.97 78.26,58.86 78.26,58.64 78.15,58.53 77.48,58.53 77.37,58.42 77.37,58.2 77.48,58.09 78.15,58.09 78.26,57.98 78.26,57.77 78.15,57.66 77.48,57.66 77.37,57.55 77.37,57.33 77.48,57.22 78.15,57.22 78.26,57.11 78.26,56.89 78.15,56.78 77.48,56.78 77.37,56.67 77.37,56.45 77.48,56.35 78.15,56.35 78.26,56.24 78.26,56.02 78.15,55.91 77.48,55.91 77.37,55.8 77.37,55.58 77.48,55.47 78.15,55.47 78.26,55.36 78.26,55.14 78.15,55.03 77.48,55.03 77.37,54.93 77.37,54.71 77.48,54.6 77.97,54.6 78.08,54.49 78.08,54.27 77.97,54.16 77.48,54.16 77.37,54.05 77.37,53.75 76.5,52.89 v5(76.5,39.75)
  L10_SIG4 w0.109: v5(76.5,39.75) 76.5,37.55 76.76,37.29 76.76,29.86 78.23,28.39 78.23,21.95 78.11,21.82 v9(78.11,16.97) ; v2(87.98,26.28) 90.3,23.96 92.61,23.96 92.75,24.1 92.75,24.18 92.89,24.32 93.09,24.32 93.23,24.18 93.23,24.1 93.37,23.96 97.18,23.96 98.55,25.33 100.9,25.33 101.85,26.28 v2(103.22,26.28) 103.22,25.86 104.79,24.28 112.74,24.28 113.84,25.38 116.19,25.38 117.09,26.28 v2(118.46,26.28)
  BOTTOM w0.173: v9(78.11,16.97) 84.99,16.97 88.75,20.73 88.75,24.74 87.98,25.51 v2(87.98,26.28)
DDR_A9: length 144.2
  TOP w0.173: U5.R3 v2(84.91,26.68) ; U1.AE22 v4(93.44,75.22) ; U7.R3 v2(100.15,26.68) ; R64.2 114.17,23.49 114.48,23.8 114.48,24.81 114.45,24.83 114.45,25.71 114.46,25.71 114.46,26 114.46,26 114.46,26.04 114.69,26.28 115.18,26.28 115.39,26.49 v2(115.39,26.68) U6.R3
  L3_SIG1 w0.099: v4(93.44,75.22) 93.12,75.22 92.82,75.51 92.44,75.51 92.2,75.27
  L3_SIG1 w0.109: v2(84.91,26.68) 85.32,26.27 85.83,26.27 87.86,24.23 97.7,24.23 98.66,25.19 98.95,25.19 99.9,26.14 99.9,26.43 v2(100.15,26.68) 100.51,26.32 101.02,26.32 103.1,24.23 112.94,24.23 114.91,26.2 114.91,26.2 v2(115.39,26.68) ; 92.2,75.27 90.68,75.27 81.89,66.48 79.3,66.48 76.91,64.09 76.91,53.98 76.05,53.12 76.05,37.78 76.79,37.04 76.79,29.68 76.39,29.28 75.45,29.28 75.03,29.7 75.03,30.28 75.17,30.42 75.71,30.42 75.86,30.57 75.86,30.77 75.72,30.9 75.17,30.9 75.03,31.04 75.03,31.35 75.17,31.49 75.82,31.49 75.96,31.63 75.96,31.83 75.82,31.97 75.17,31.97 75.03,32.11 75.03,32.31 75.17,32.45 75.82,32.45 75.96,32.59 75.96,32.79 75.82,32.93 75.17,32.93 75.03,33.07 75.03,33.27 75.17,33.41 75.82,33.41 75.96,33.55 75.96,33.75 75.82,33.89 75.17,33.89 75.03,34.03 75.03,34.23 75.17,34.37 75.82,34.37 75.96,34.51 75.96,34.71 75.82,34.85 75.17,34.85 75.03,34.99 75.03,35.19 75.17,35.33 75.82,35.33 75.96,35.47 75.96,35.67 75.82,35.81 75.17,35.81 75.03,35.95 75.03,36.67 75.34,36.98 v5(76.17,36.98)
  L10_SIG4 w0.109: v9(77.63,21.97) 77.77,22.11 77.77,28.23 76.15,29.85 76.15,36.96 v5(76.17,36.98)
  BOTTOM w0.173: v2(84.91,26.68) 84.55,26.32 84.55,24.11 82.41,21.96 77.64,21.96 v9(77.63,21.97)
DDR_A10: length 146.8
  TOP w0.173: R66.2 122.65,31.88 120.87,30.1 120.21,30.1 120.03,30.28 118.69,30.28 118.69,30.28 118.29,29.88 U6.L7 v2(116.82,29.88) ; U5.L7 v2(86.34,29.88) ; U7.L7 v2(101.58,29.88) ; U1.AD21 v4(94.24,76.02)
  L3_SIG1 w0.099: v4(94.24,76.02) 93.85,76.02 93.35,76.51 92.53,76.51 92.13,76.91 92.13,76.94 91.84,77.22
  L3_SIG1 w0.109: v5(74.22,36.96) 74.45,36.73 74.45,30.34 74.21,30.1 73.64,30.1 73.42,30.31 73.42,32.55 73.28,32.69 72.1,32.69 71.96,32.83 71.96,33.03 72.1,33.17 73.28,33.17 73.42,33.31 73.42,33.51 73.28,33.65 72.1,33.65 71.96,33.79 71.96,33.99 72.1,34.13 73.28,34.13 73.42,34.27 73.42,34.47 73.28,34.61 72.1,34.61 71.96,34.75 71.96,34.95 72.1,35.09 73.28,35.09 73.42,35.23 73.42,35.43 73.28,35.57 72.1,35.57 71.96,35.71 71.96,35.91 72.1,36.05 73.28,36.05 73.42,36.19 73.42,37.39 74.17,38.13 74.17,40.31 73.05,41.43 73.05,47.25 73.61,47.81 73.61,53.32 74.98,54.69 74.98,65.13 78.21,68.36 81.05,68.36 89.92,77.22 91.84,77.22
  L10_SIG4 w0.109: v5(74.22,36.96) 74.22,28.25 v9(74.27,28.2) ; v2(86.34,29.88) 86.91,29.88 87.62,30.58 89.2,30.58 89.55,30.24 93.84,30.24 94.58,29.5 95.15,29.5 95.35,29.7 95.35,30.09 95.46,30.2 95.74,30.2 95.85,30.09 95.85,29.64 95.98,29.51 96.14,29.51 96.43,29.81 98.05,29.81 98.19,29.66 98.77,29.66 99.04,29.93 99.44,29.93 99.8,30.28 101.17,30.28 v2(101.58,29.88) 103.64,29.88 103.97,30.21 107.8,30.21 108.01,30 108.64,30 108.85,30.21 109.28,30.21 109.46,30.03 109.46,29.76 109.6,29.62 110.71,29.62 110.82,29.51 110.82,29.38 110.94,29.26 111.11,29.26 111.23,29.38 111.23,29.57 111.34,29.68 114.06,29.68 114.66,30.28 116.41,30.28 v2(116.82,29.88)
  BOTTOM w0.102: 81.27,28.83 81.9,29.46 82.61,29.46 82.99,29.08 84.16,29.08 84.54,29.46 85.2,29.46 85.62,29.88 v2(86.34,29.88)
  BOTTOM w0.173: 81.27,28.83 80.52,28.08 74.39,28.08 v9(74.27,28.2)
DDR_A11: length 145.3
  TOP w0.173: U1.AD22 v4(94.24,75.22) ; U7.R7 v2(101.58,26.68) ; U6.R7 v2(116.82,26.68) 117.04,26.45 117.04,25.32 117.47,24.89 R65.2 ; U5.R7 v2(86.34,26.68)
  L3_SIG1 w0.099: v4(94.24,75.22) 93.93,75.22 93.43,75.71 92.3,75.71 92.11,75.52
  L3_SIG1 w0.109: 92.11,75.52 90.3,75.52 81.71,66.93 78.99,66.93 76.45,64.39 76.45,54.16 74.99,52.69 74.99,52.18 75.1,52.08 75.43,52.08 75.54,51.97 75.54,51.75 75.43,51.64 75.1,51.64 74.99,51.53 74.99,51.31 75.1,51.2 75.43,51.2 75.54,51.09 75.54,50.87 75.43,50.76 75.1,50.76 74.99,50.66 74.99,49.18 75.59,48.58 v5(75.59,39.75)
  L10_SIG4 w0.109: v9(77.32,19.84) 77.32,18.02 76.99,17.69 76.07,17.69 75.66,18.1 75.66,18.96 75.8,19.1 76.7,19.1 76.84,19.25 76.84,19.44 76.7,19.58 75.8,19.58 75.66,19.73 75.66,19.92 75.8,20.06 76.8,20.06 76.94,20.21 76.94,20.4 76.8,20.55 75.8,20.55 75.66,20.69 75.66,20.88 75.8,21.03 77.3,21.03 77.44,21.16 77.44,21.36 77.29,21.51 75.8,21.51 75.66,21.65 75.66,21.84 75.8,21.99 76.96,21.99 77.1,22.13 77.1,22.32 76.96,22.47 75.8,22.47 75.66,22.61 75.66,22.83 75.96,23.13 77.1,23.13 77.23,23.26 77.23,23.81 77.32,23.9 77.32,28.06 77.28,28.1 75.59,29.79 v5(75.59,39.75) ; v2(116.82,26.68) 116.51,26.37 115.9,26.37 115.16,25.63 113.74,25.63 112.88,24.77 107.53,24.77 107.35,24.95 107.12,24.95 106.94,24.77 106.72,24.77 106.54,24.95 106.31,24.95 106.14,24.77 105.44,24.77 103.53,26.68 v2(101.58,26.68) 100.99,26.68 99.9,25.58 98.45,25.58 97.64,24.77 92.22,24.77 92.1,24.65 92.1,24.53 91.98,24.41 91.81,24.41 91.7,24.53 91.7,24.65 91.58,24.77 91.41,24.77 91.29,24.65 91.29,24.53 91.17,24.41 91.01,24.41 90.89,24.53 90.89,24.65 90.77,24.77 90.15,24.77 88.24,26.68 v2(86.34,26.68)
  BOTTOM w0.173: v9(77.32,19.84) 83.37,19.84 85.86,22.33 85.86,23.09 86.34,23.57 v2(86.34,26.68)
DDR_A12: length 149.1
  TOP w0.173: U7.N7 v2(101.58,28.28) ; U6.N7 v2(116.82,28.28) ; U5.N7 v2(86.34,28.28) ; U1.AC21 v4(95.04,76.02)
  L3_SIG1 w0.109: v4(95.04,76.02) v5(94.64,75.77)
  L10_SIG4 w0.109: v2(116.82,28.28) 116.41,28.68 115.17,28.68 115.06,28.58 114.14,28.58 113.44,27.87 112.29,27.87 111.96,27.53 109.59,27.53 109.35,27.29 109.11,27.29 108.87,27.53 108.63,27.53 108.39,27.29 108.18,27.29 107.94,27.53 107.71,27.53 107.59,27.42 107.59,27.34 107.48,27.23 107.31,27.23 107.19,27.34 107.19,27.42 107.07,27.53 106.55,27.53 105.41,28.68 104.72,28.68 104.32,28.28 v2(101.58,28.28) 101.17,28.68 99.94,28.68 99.56,28.3 98.6,28.3 98.17,27.87 96.93,27.87 96.59,27.53 95.31,27.53 95.07,27.29 94.83,27.29 94.59,27.53 94.35,27.53 94.11,27.29 93.87,27.29 93.63,27.53 93.39,27.53 93.15,27.29 92.94,27.29 92.7,27.53 92.47,27.53 92.35,27.42 92.35,27.34 92.24,27.23 92.07,27.23 91.95,27.34 91.95,27.42 91.83,27.53 91.31,27.53 90.17,28.68 89.53,28.68 89.13,28.28 v2(86.34,28.28) ; v9(74.74,22.67) 74.74,24.27 72.82,26.19 72.82,39.6 77.25,44.03 77.25,45.15 77.38,45.28 78.06,45.28 78.17,45.39 78.17,45.6 78.05,45.71 77.37,45.71 77.25,45.83 77.25,46.05 77.36,46.16 77.94,46.16 78.05,46.27 78.05,46.49 77.94,46.6 77.36,46.6 77.25,46.71 77.25,46.92 77.36,47.03 77.97,47.03 78.08,47.14 78.08,47.36 77.97,47.47 77.36,47.47 77.25,47.58 77.25,47.8 77.36,47.91 77.97,47.91 78.08,48.02 78.08,48.24 77.97,48.34 77.36,48.34 77.25,48.45 77.25,48.67 77.36,48.78 77.97,48.78 78.08,48.89 78.08,49.11 77.97,49.22 77.36,49.22 77.25,49.33 77.25,49.55 77.36,49.66 77.97,49.66 78.08,49.76 78.08,49.98 77.97,50.09 77.36,50.09 77.25,50.2 77.25,50.42 77.36,50.53 77.97,50.53 78.08,50.64 78.08,50.86 77.97,50.97 77.36,50.97 77.25,51.08 77.25,51.29 77.36,51.4 77.97,51.4 78.08,51.51 78.08,51.73 77.97,51.84 77.36,51.84 77.25,51.95 77.25,52.17 77.36,52.28 77.97,52.28 78.08,52.39 78.08,52.6 77.97,52.71 77.36,52.71 77.25,52.82 77.25,53.04 77.36,53.15 77.97,53.15 78.08,53.26 78.08,53.48 77.97,53.59 77.36,53.59 77.25,53.7 77.25,53.92 77.36,54.02 77.97,54.02 78.08,54.13 78.08,54.35 77.97,54.46 77.36,54.46 77.25,54.57 77.25,54.79 77.36,54.9 77.97,54.9 78.08,55.01 78.08,55.23 77.97,55.33 77.36,55.33 77.25,55.44 77.25,55.66 77.36,55.77 77.97,55.77 78.08,55.88 78.08,56.1 77.97,56.21 77.36,56.21 77.09,56.48 77.09,66.22 85.8,74.93 89.92,74.93 90.49,75.5 94.37,75.5 v5(94.64,75.77)
  BOTTOM w0.173: v2(86.34,28.28) 86.05,27.99 85.42,27.99 84.05,26.62 84.05,24.16 83.46,23.57 83.01,23.57 82.11,22.67 v9(74.74,22.67) ; v2(116.82,28.28) 117.32,28.28 118.9,26.7 118.9,25.32 121.54,22.68 R68.2
DDR_A13: length 144.7
  TOP w0.173: R70.2 115.32,24.99 116.1,25.78 v2(116.1,25.88) U6.T3 ; U5.T3 v2(85.62,25.88) ; U7.T3 v2(100.86,25.88) ; U1.AF18 v4(92.64,78.42)
  L3_SIG1 w0.109: v2(85.62,25.88) 85.73,25.88 87.92,23.68 98.67,23.68 99.84,24.85 99.84,25.28 100.43,25.88 v2(100.86,25.88) 100.97,25.88 103.16,23.68 114.07,23.68 116.1,25.72 v2(116.1,25.88) ; v5(71.45,38.23) 70.99,38.69 70.99,53.73 71.65,54.39 71.65,66.25 72.44,67.04 72.59,67.04 72.95,66.68 73.1,66.68 73.26,66.84 73.26,66.99 72.9,67.34 72.9,67.5 73.06,67.65 73.21,67.65 73.57,67.3 73.72,67.3 73.88,67.46 73.88,67.61 73.52,67.96 73.52,68.12 73.68,68.27 73.83,68.27 74.19,67.92 74.34,67.92 74.49,68.07 74.49,68.23 74.14,68.58 74.14,68.74 74.3,68.89 74.45,68.89 74.8,68.54 74.96,68.54 75.11,68.69 75.11,68.85 74.76,69.2 74.76,69.35 74.91,69.51 75.07,69.51 75.42,69.16 75.58,69.16 75.73,69.31 75.73,69.46 75.38,69.82 75.38,69.97 75.53,70.13 75.69,70.13 76.04,69.77 76.19,69.77 76.35,69.93 76.35,70.08 76,70.44 76,70.59 82.73,77.32 86.13,77.32 86.66,77.86 88.21,77.86 88.77,78.42 v4(92.64,78.42)
  L10_SIG4 w0.109: v9(73.48,20.55) 73.48,21.22 73.34,21.36 72.4,21.36 72.25,21.5 72.25,21.7 72.4,21.84 73.19,21.84 73.33,21.98 73.33,22.18 73.19,22.32 72.4,22.32 72.25,22.46 72.25,22.66 72.4,22.8 73.18,22.8 73.43,23.06 73.43,23.93 71.93,25.43 71.93,34.18 71.45,34.66 v5(71.45,38.23)
  BOTTOM w0.173: v2(85.62,25.88) 85.62,23.57 85.15,23.1 85.15,22.71 82.99,20.55 76.19,20.55 76.03,20.39 76.03,19.99 75.87,19.83 75.64,19.83 75.48,19.99 75.48,20.39 75.31,20.55 75.08,20.55 74.92,20.39 74.92,19.99 74.76,19.83 74.53,19.83 74.37,19.99 74.37,20.39 74.21,20.55 v9(73.48,20.55)
DDR_A14: length 143.3
  TOP w0.173: U7.T7 v2(102.29,25.88) ; U1.AE17 v4(93.44,79.22) ; U6.T7 v2(117.53,25.88) 117.53,25.47 118.49,24.51 R71.2 ; U5.T7 v2(87.05,25.88)
  L3_SIG1 w0.099: v4(93.44,79.22) 93.14,78.92 92.51,78.92 92.32,79.11 91.8,79.11
  L3_SIG1 w0.109: v5(69.62,38.21) 69.62,53.83 70.74,54.95 70.74,59.49 70.63,59.6 70.14,59.6 70.03,59.71 70.03,59.93 70.14,60.04 70.63,60.04 70.74,60.15 70.74,60.37 70.63,60.48 70.11,60.48 70,60.58 70,60.8 70.11,60.91 70.63,60.91 70.74,61.02 70.74,61.24 70.63,61.35 70.11,61.35 70,61.46 70,61.68 70.11,61.79 70.63,61.79 70.74,61.9 70.74,66.63 82.45,78.34 85.88,78.34 86.37,78.83 88.07,78.83 88.35,79.11 91.8,79.11
  L10_SIG4 w0.109: v2(87.05,25.88) 89.44,23.49 97.1,23.49 98.7,25.09 99.34,25.09 99.46,24.97 99.46,24.91 99.58,24.79 99.74,24.79 99.86,24.91 99.86,24.97 99.98,25.09 101.5,25.09 v2(102.29,25.88) 104.32,23.84 112.69,23.84 113.97,25.13 116.78,25.13 v2(117.53,25.88) ; v5(69.62,38.21) 69.62,34 69.69,33.93 69.69,33.93 70.17,33.45 70.17,24.54 70.17,23.99 70.78,23.38 70.78,19.18 v9(71.58,18.39)
  BOTTOM w0.173: v9(71.58,18.39) 84.14,18.39 87.33,21.58 87.33,24.81 87.05,25.09 v2(87.05,25.88)
DDR_A15: length 145.9
  TOP w0.173: v2(117.53,29.08) U6.M7 ; U5.M7 v2(87.05,29.08) ; U7.M7 v2(102.29,29.08) ; U1.AD18 v4(94.24,78.42)
  L3_SIG1 w0.109: v5(93.84,78.17) v4(94.24,78.42)
  L10_SIG4 w0.109: v5(93.84,78.17) 89.85,78.17 89.01,77.33 84.83,77.33 70.95,63.45 70.95,56.35 70.23,55.63 70.23,48.14 70.06,47.98 69.11,47.98 69.01,47.87 69.01,47.65 69.11,47.54 70.06,47.54 70.17,47.43 70.17,47.21 70.06,47.1 69.11,47.1 69.01,46.99 69.01,46.77 69.11,46.66 70.06,46.66 70.17,46.56 70.17,46.34 70.06,46.23 69.11,46.23 69.01,46.12 69.01,45.9 69.11,45.79 70.06,45.79 70.17,45.68 70.17,45.46 70.06,45.35 69.11,45.35 69.01,45.25 69.01,45.03 69.11,44.92 70.06,44.92 70.17,44.81 70.17,44.59 70.06,44.48 69.11,44.48 69.01,44.37 69.01,44.15 69.11,44.04 70.06,44.04 70.17,43.93 70.17,43.72 70.06,43.61 69.11,43.61 69.01,43.5 69.01,43.28 69.11,43.17 70.06,43.17 70.17,43.06 70.17,42.84 70.06,42.73 69.11,42.73 69.01,42.62 69.01,42.41 69.11,42.3 70.06,42.3 70.17,42.19 70.17,41.51 68.27,39.6 68.27,33.4 68.77,32.9 v9(68.77,25.94) ; v2(87.05,29.08) 87.05,29.09 87.89,29.93 89.56,29.93 89.64,29.85 90.38,29.85 91.69,28.55 92.55,28.55 93,28.99 94.26,28.99 94.7,28.55 95.67,28.55 96.59,29.46 97.97,29.46 98.04,29.38 98.73,29.38 99.03,29.09 99.4,29.09 99.66,29.35 100.19,29.35 100.56,29.72 101.17,29.72 101.41,29.48 101.89,29.48 v2(102.29,29.08) 103.59,29.08 104.32,29.81 106.46,29.81 107.13,29.14 110.25,29.14 110.62,28.77 111.73,28.77 112.42,29.46 113.92,29.46 114.29,29.09 114.64,29.09 115.01,29.46 115.54,29.46 115.8,29.72 116.42,29.72 117.06,29.08 v2(117.53,29.08)
  BOTTOM w0.102: 82.62,27.11 82.61,27.1 81.9,27.1 81.82,27.02
  BOTTOM w0.173: 82.62,27.11 82.62,27.12 83.95,28.45 84.26,28.45 84.51,28.7 85.26,28.7 85.36,28.6 85.89,28.6 86.37,29.08 v2(87.05,29.08) ; v2(117.53,29.08) 118.02,29.08 119.27,27.82 120.62,27.82 120.88,27.56 R806.2 ; 81.82,27.02 80.76,25.96 68.79,25.96 v9(68.77,25.94)
DDR_BA0: length 147.3
  TOP w0.173: U6.M2 v2(114.46,29.48) ; U7.M2 v2(99.22,29.48) ; U5.M2 v2(83.98,29.48) ; U1.AF17 v4(92.64,79.22)
  L3_SIG1 w0.109: v5(68.71,37.67) 68.71,39.39 68.6,39.5 67.75,39.5 67.64,39.61 67.64,39.81 67.77,39.94 68.6,39.94 68.71,40.04 68.71,40.26 68.6,40.37 67.93,40.37 67.82,40.48 67.82,40.7 67.93,40.81 68.6,40.81 68.71,40.92 68.71,41.14 68.6,41.25 67.93,41.25 67.82,41.36 67.82,41.57 67.93,41.68 68.6,41.68 68.71,41.79 68.71,42.01 68.6,42.12 67.93,42.12 67.82,42.23 67.82,42.45 67.93,42.56 68.6,42.56 68.71,42.67 68.71,42.88 68.6,42.99 67.93,42.99 67.82,43.1 67.82,43.32 67.93,43.43 68.6,43.43 68.71,43.54 68.71,43.76 68.6,43.87 67.93,43.87 67.82,43.98 67.82,44.19 67.93,44.3 68.6,44.3 68.71,44.41 68.71,44.63 68.6,44.74 67.93,44.74 67.82,44.85 67.82,45.07 67.93,45.18 68.6,45.18 68.71,45.29 68.71,45.51 68.6,45.61 67.93,45.61 67.82,45.72 67.82,45.94 67.93,46.05 68.6,46.05 68.71,46.16 68.71,46.38 68.6,46.49 67.93,46.49 67.82,46.6 67.82,46.82 67.93,46.93 68.6,46.93 68.71,47.03 68.71,53.88 69.24,54.41 69.24,62.2 69.13,62.31 68.44,62.31 68.33,62.42 68.33,62.64 68.44,62.75 69.13,62.75 69.24,62.85 69.24,63.07 69.13,63.18 68.44,63.18 68.33,63.29 68.33,63.51 68.44,63.62 69.13,63.62 69.24,63.73 69.24,63.95 69.13,64.06 68.44,64.06 68.33,64.17 68.33,64.38 68.44,64.49 69.13,64.49 69.24,64.6 69.24,64.82 69.13,64.93 68.44,64.93 68.33,65.04 68.33,65.26 68.44,65.37 69.13,65.37 69.24,65.48 69.24,65.85 82.4,79.01 85.81,79.01 86.08,79.28 88.01,79.28 88.25,79.52 92.33,79.52 v4(92.64,79.22) ; v2(114.46,29.48) 114.3,29.32 113.09,29.32 112.93,29.48 112.48,29.48 112.06,29.06 111.49,29.06 110.62,28.19 109.53,28.19 109.25,28.47 108.23,28.47 107.97,28.21 107.46,28.21 107.2,28.47 106.25,28.47 105.25,29.47 104.77,29.47 104.42,29.11 103.89,29.11 103.65,28.88 103.21,28.88 102.63,29.46 102.45,29.46 102.45,29.46 102.13,29.46 101.89,29.22 101.34,29.22 101.08,29.48 100.69,29.48 100.69,29.48 v2(99.22,29.48) 99.16,29.42 97.94,29.42 97.84,29.52 97.31,29.52 96.85,29.06 96.25,29.06 95.66,28.47 93.55,28.47 93.41,28.61 93.41,28.86 93.27,29 93.07,29 92.93,28.86 92.93,28.61 92.79,28.47 91.01,28.47 90.01,29.47 89.59,29.47 89.2,29.09 88.6,29.09 88.41,28.91 87.99,28.91 87.43,29.46 86.87,29.46 86.64,29.24 86.03,29.24 85.79,29.48 83.98,29.48 v2(83.98,29.48)
  L10_SIG4 w0.109: v5(68.71,37.67) 68.71,33.58 69.21,33.08 v9(69.21,28.83)
  BOTTOM w0.173: R72.2 115.19,24.42 114.15,25.46 114.15,26.38 114.04,26.48 114.04,28.29 114.46,28.7 v2(114.46,29.48) ; v2(83.98,29.48) 83.92,29.48 83.7,29.7 81.38,29.7 80.46,28.78 69.25,28.78 v9(69.21,28.83)
DDR_BA1: length 144.6
  TOP w0.173: U6.N8 v2(119.26,28.68) 119.28,28.69 119.48,28.69 119.49,28.68 119.82,28.68 119.84,28.69 121.42,28.69 122.55,27.56 R73.2 ; U1.AE18 v4(93.44,78.42) ; U7.N8 v2(104.02,28.68) ; U5.N8 v2(88.78,28.68)
  L3_SIG1 w0.099: 91.83,78.71 93.14,78.71 v4(93.44,78.42)
  L3_SIG1 w0.109: 91.83,78.71 88.54,78.71 88.15,78.31 86.49,78.31 85.95,77.78 82.55,77.78 71.2,66.43 71.2,54.69 70.54,54.03 v5(70.54,37.01)
  L10_SIG4 w0.109: v2(119.26,28.68) 117.06,28.68 116.24,29.49 115.94,29.49 115.53,29.08 115.11,29.08 114.91,28.88 114.04,28.88 113.83,29.09 113.43,29.09 113.02,28.68 112.24,28.68 111.68,28.12 106.78,28.12 105.43,29.47 104.73,29.47 104.41,29.15 104.41,29.06 v2(104.02,28.68) 101.83,28.68 101.04,29.47 100.69,29.47 100.19,28.97 99.78,28.97 99.47,28.66 99.02,28.66 98.62,29.06 98.16,29.06 97.78,28.68 96.85,28.68 96.22,28.06 91.49,28.06 90.07,29.47 89.49,29.47 89.17,29.15 89.17,29.06 v2(88.78,28.68) ; v9(72.47,17.68) 72.52,17.73 72.52,19.56 71.75,20.32 71.75,23.98 71.05,24.69 71.05,33.81 70.57,34.29 70.57,34.3 70.55,34.32 70.55,34.32 70.54,34.34 v5(70.54,37.01)
  BOTTOM w0.173: v2(88.78,28.68) 88.17,28.68 87.5,28.01 87.5,25.32 87.68,25.14 87.68,23.5 88.04,23.15 88.04,21.29 84.43,17.68 83.99,17.68 83.99,17.68 v9(72.47,17.68)
DDR_BA2: length 149.4
  TOP w0.173: U6.M3 v2(116.1,29.08) ; U1.AB18 v4(95.84,78.42) ; U5.M3 v2(85.62,29.08) ; U7.M3 v2(100.86,29.08)
  L3_SIG1 w0.109: v2(85.62,29.08) 85.69,29.01 86.56,29.01 87.05,28.52 88.24,28.52 88.67,28.1 88.9,28.1 89.48,28.68 90.03,28.68 90.82,27.89 91.1,27.89 91.33,27.66 91.5,27.66 91.74,27.89 91.91,27.89 92.14,27.66 92.31,27.66 92.55,27.89 92.71,27.89 92.92,27.69 93.15,27.69 93.35,27.89 93.52,27.89 93.72,27.69 93.96,27.69 94.16,27.89 94.33,27.89 94.57,27.66 94.73,27.66 94.97,27.89 96.08,27.89 96.87,28.68 97.76,28.68 98.16,29.08 v2(100.86,29.08) 100.98,28.96 101.86,28.96 102.29,28.53 103.58,28.53 104.01,28.1 104.24,28.1 104.83,28.68 105.27,28.68 106.06,27.89 107.15,27.89 107.35,27.69 108.39,27.69 108.59,27.89 109.12,27.89 109.36,27.66 111.09,27.66 112.11,28.68 112.9,28.68 113.3,29.08 v2(116.1,29.08) ; v4(95.84,78.42) v5(95.44,78.17)
  L10_SIG4 w0.109: v9(68.33,26.69) 68.33,32.72 67.83,33.22 67.83,40.3 67.72,40.4 66.94,40.4 66.83,40.51 66.83,40.73 66.94,40.84 67.72,40.84 67.83,40.95 67.83,41.16 67.72,41.27 66.96,41.27 66.85,41.38 66.85,41.6 66.96,41.71 67.71,41.71 67.83,41.82 67.83,42.04 67.72,42.15 66.97,42.15 66.86,42.26 66.86,42.48 66.97,42.59 67.72,42.59 67.83,42.7 67.83,42.92 67.72,43.03 66.97,43.03 66.86,43.14 66.86,43.35 66.97,43.46 67.72,43.46 67.83,43.57 67.83,43.79 67.72,43.9 66.97,43.9 66.86,44.01 66.86,44.23 66.97,44.34 67.72,44.34 67.83,44.45 67.83,44.66 67.72,44.77 66.97,44.77 66.86,44.88 66.86,45.1 66.97,45.21 67.72,45.21 67.83,45.32 67.83,45.54 67.72,45.65 66.97,45.65 66.86,45.76 66.86,45.97 66.97,46.08 67.72,46.08 67.83,46.19 67.83,46.41 67.72,46.52 66.97,46.52 66.86,46.63 66.86,46.85 66.97,46.96 67.72,46.96 67.83,47.07 67.83,47.86 69.55,49.58 69.55,62.71 84.86,78.02 89.07,78.02 89.62,78.57 94.03,78.57 94.43,78.17 v5(95.44,78.17)
  BOTTOM w0.102: v2(85.62,29.08) 84.55,29.08 84.27,28.79 83.84,28.79 82.91,27.86 81.82,27.86
  BOTTOM w0.173: v9(68.33,26.69) 68.36,26.69 68.38,26.66 80.62,26.66 81.82,27.86 ; v2(116.1,29.08) 116.1,28.17 118.04,26.23 118.04,25.24 120.4,22.89 R74.2
DDR_CASN: length 149.1
  TOP w0.173: U6.K3 v2(116.1,30.68) ; U1.AC18 v4(95.04,78.42) ; U5.K3 v2(85.62,30.68) ; U7.K3 v2(100.86,30.68)
  L3_SIG1 w0.099: 92.96,78 93.47,78 93.68,77.79 93.98,77.79 94.01,77.8 94.3,78.09 94.71,78.09 v4(95.04,78.42)
  L3_SIG1 w0.109: v2(85.62,30.68) 85.91,30.38 86.39,30.38 86.69,30.08 88.04,30.08 88.55,30.59 89.26,30.59 89.63,30.21 91.4,30.21 91.52,30.33 91.52,30.64 91.64,30.75 91.81,30.75 91.92,30.64 91.92,30.33 92.04,30.21 93.91,30.21 94.39,30.69 95.55,30.69 95.96,30.28 97.82,30.28 98.22,29.88 98.65,29.88 99.03,30.25 99.77,30.25 100.2,30.68 v2(100.86,30.68) 101.26,30.28 101.73,30.28 101.9,30.1 103.31,30.1 103.79,30.59 104.47,30.59 104.85,30.21 106.33,30.21 106.66,30.54 107.06,30.54 107.39,30.21 109.17,30.21 109.65,30.69 110.79,30.69 111.2,30.28 113.06,30.28 113.46,29.88 113.84,29.88 114.22,30.25 115.01,30.25 115.44,30.68 v2(116.1,30.68) ; 92.96,78 88.9,78 88.3,77.4 86.84,77.4 86.22,76.78 84.21,76.78 83.82,76.39 83.62,76.39 83.13,76.88 82.93,76.88 82.79,76.73 82.79,76.54 83.28,76.05 83.28,75.85 83.14,75.71 82.94,75.71 82.45,76.2 82.25,76.2 82.11,76.06 82.11,75.86 82.6,75.37 82.6,75.17 82.46,75.03 82.26,75.03 81.77,75.52 81.57,75.52 81.43,75.38 81.43,75.18 81.92,74.69 81.92,74.49 81.78,74.35 81.58,74.35 81.09,74.84 80.89,74.84 80.75,74.7 80.75,74.5 81.24,74.01 81.24,73.81 81.1,73.67 80.9,73.67 80.41,74.16 80.21,74.16 80.07,74.02 80.07,73.82 80.56,73.33 80.56,73.13 80.42,72.99 80.22,72.99 79.73,73.48 79.53,73.48 79.39,73.34 79.39,73.14 79.88,72.65 79.88,72.45 79.74,72.31 79.54,72.31 79.05,72.8 78.86,72.8 78.72,72.66 78.72,72.46 79.2,71.97 79.2,71.77 79.06,71.63 78.86,71.63 78.38,72.12 78.18,72.12 78.04,71.98 78.04,71.78 78.52,71.29 78.52,71.09 78.38,70.95 78.18,70.95 77.7,71.44 77.5,71.44 77.36,71.3 77.36,71.1 77.84,70.61 77.84,70.41 72.16,64.73 72.16,64.19 72.27,64.08 72.79,64.08 72.9,63.97 72.9,63.75 72.79,63.64 72.27,63.64 72.16,63.53 72.16,63.32 72.27,63.21 72.79,63.21 72.9,63.1 72.9,62.88 72.79,62.77 72.27,62.77 72.16,62.66 72.16,62.44 72.27,62.33 72.79,62.33 72.9,62.22 72.9,62.01 72.79,61.9 72.27,61.9 72.16,61.79 72.16,61.57 72.27,61.46 72.79,61.46 72.9,61.35 72.9,61.13 72.79,61.02 72.27,61.02 72.16,60.91 72.16,60.7 72.27,60.59 72.79,60.59 72.9,60.48 72.9,60.26 72.79,60.15 72.27,60.15 72.16,60.04 72.16,59.82 72.27,59.71 72.79,59.71 72.9,59.6 72.9,59.38 72.79,59.28 72.27,59.28 72.16,59.17 72.16,58.95 72.27,58.84 72.79,58.84 72.9,58.73 72.9,58.51 72.79,58.4 72.27,58.4 72.16,58.29 72.16,58.07 72.27,57.96 72.79,57.96 72.9,57.86 72.9,57.64 72.79,57.53 72.27,57.53 72.16,57.42 72.16,57.2 72.27,57.09 72.79,57.09 72.9,56.98 72.9,56.76 72.79,56.65 72.27,56.65 72.16,56.54 72.16,56.33 72.27,56.22 72.79,56.22 72.9,56.11 72.9,55.89 72.79,55.78 72.27,55.78 72.16,55.67 72.16,55.45 72.27,55.34 72.56,55.34 72.67,55.23 72.67,55.02 72.56,54.91 72.27,54.91 72.16,54.8 72.16,54.18 71.58,53.6 71.58,38.97 72.36,38.18 v5(72.36,36.98)
  L10_SIG4 w0.109: v5(72.36,36.98) v9(72.36,35.05)
  BOTTOM w0.102: 80.06,31.58 82.93,31.58 83.13,31.37 83.69,31.37 83.82,31.5 84.2,31.5 85.02,30.68 v2(85.62,30.68)
  BOTTOM w0.173: R52.2 110.49,27.81 110.87,28.19 110.87,29.09 111.67,29.89 113.11,29.89 113.28,29.72 113.79,29.72 114.75,30.68 v2(116.1,30.68) ; 80.06,31.58 79.07,32.56 74.85,32.56 v9(72.36,35.05)
DDR_CKE: length 105.2
  TOP w0.173: U1.AG22 91.83,75.21 89.3,75.21 88.34,74.25 87.25,74.25 79.88,66.88 v7(79.88,63.56) ; U5.K9 v2(89.74,30.68) ; U6.K9 v2(120.22,30.68) ; U7.K9 v2(104.98,30.68)
  L3_SIG1 w0.109: v7(79.88,63.56) 79.88,50.85 78.33,49.3 v5(78.33,44.09)
  L10_SIG4 w0.109: v2(89.74,30.68) 95.99,30.68 96.63,30.03 98.12,30.03 98.26,29.89 98.62,29.89 99.4,30.68 100.17,30.68 100.61,31.12 101.04,31.12 101.8,30.36 103.53,30.36 103.87,30.7 104.97,30.7 v2(104.98,30.68) 111.23,30.68 111.84,30.07 113.26,30.07 113.44,29.89 113.86,29.89 114.64,30.68 115.43,30.68 115.85,31.09 116.38,31.09 117.09,30.38 119.93,30.38 v2(120.22,30.68) ; v9(78.33,40.97) 77.55,41.76 77.55,43.31 v5(78.33,44.09)
  BOTTOM w0.173: v2(89.74,30.68) 90.54,30.68 91.8,31.93 91.8,38.38 89.2,40.97 v9(78.33,40.97) ; R49.2 122.81,29.59 121.92,30.48 120.42,30.48 v2(120.22,30.68)
DDR_CLK: length 158.5
  TOP w0.108: v2(102.12,31.34) 102.27,31.19 102.53,31.19 U7.J7 ; U6.J7 117.77,31.19 117.51,31.19 v2(117.36,31.34) ; U1.AG24 91.86,73.64 91.25,73.64 91.14,73.76 90.35,73.76 85.8,69.21 85.8,53.19 86.26,52.73 89.9,52.73 90.2,52.44 90.2,52.03 89.9,51.74 86.07,51.74 85.93,51.59 85.93,51.39 86.07,51.25 89.9,51.25 90.2,50.96 90.2,50.54 89.9,50.25 86.07,50.25 85.93,50.11 85.93,49.91 86.07,49.76 89.9,49.76 90.2,49.47 90.2,49.06 89.9,48.77 86.07,48.77 85.93,48.62 85.93,48.42 86.07,48.28 89.9,48.28 90.2,47.99 90.2,47.57 89.9,47.28 86.07,47.28 85.93,47.14 85.93,46.93 86.07,46.79 89.9,46.79 90.2,46.5 90.2,46.09 89.9,45.79 86.07,45.79 85.93,45.65 85.93,45.34 86.07,45.2 90.01,45.2 90.3,44.91 90.3,44.5 90.01,44.2 86.07,44.2 85.93,44.06 85.93,43.86 86.07,43.71 90.01,43.71 90.3,43.42 90.3,43.01 90.01,42.72 86.07,42.72 85.93,42.57 85.93,42.37 86.07,42.23 89.78,42.23 90.07,41.94 90.07,41.53 89.78,41.23 86.11,41.23 85.93,41.05 85.93,31.83 86.41,31.34 v2(86.88,31.34) 86.97,31.26 87.36,31.26 U5.J7
  L3_SIG1 w0.083: v2(117.36,31.34) 117.18,31.16 117,31.16 115.99,32.17 115.22,32.17 114.84,31.8 114.84,31.71 114.64,31.51 114.3,31.51 113.6,32.21 106.85,32.21 106.54,31.91 104.65,31.91 104.25,31.51 103.86,31.51 103.62,31.75 102.94,31.75 102.4,31.22 102.25,31.22 v2(102.12,31.34) 102,31.22 101.7,31.22 100.75,32.17 99.98,32.17 99.6,31.8 99.6,31.71 99.4,31.51 99.06,31.51 98.36,32.21 91.61,32.21 91.3,31.91 89.41,31.91 89.01,31.51 88.62,31.51 88.38,31.75 87.7,31.75 87.16,31.22 87.01,31.22 v2(86.88,31.34)
  BOTTOM w0.108: v2(117.36,31.34) 117.51,31.19 117.76,31.19 118.27,30.68 119.02,30.68 119.66,31.32 120.7,31.32 120.9,31.12 126.89,31.12 127,31.22 R46.2
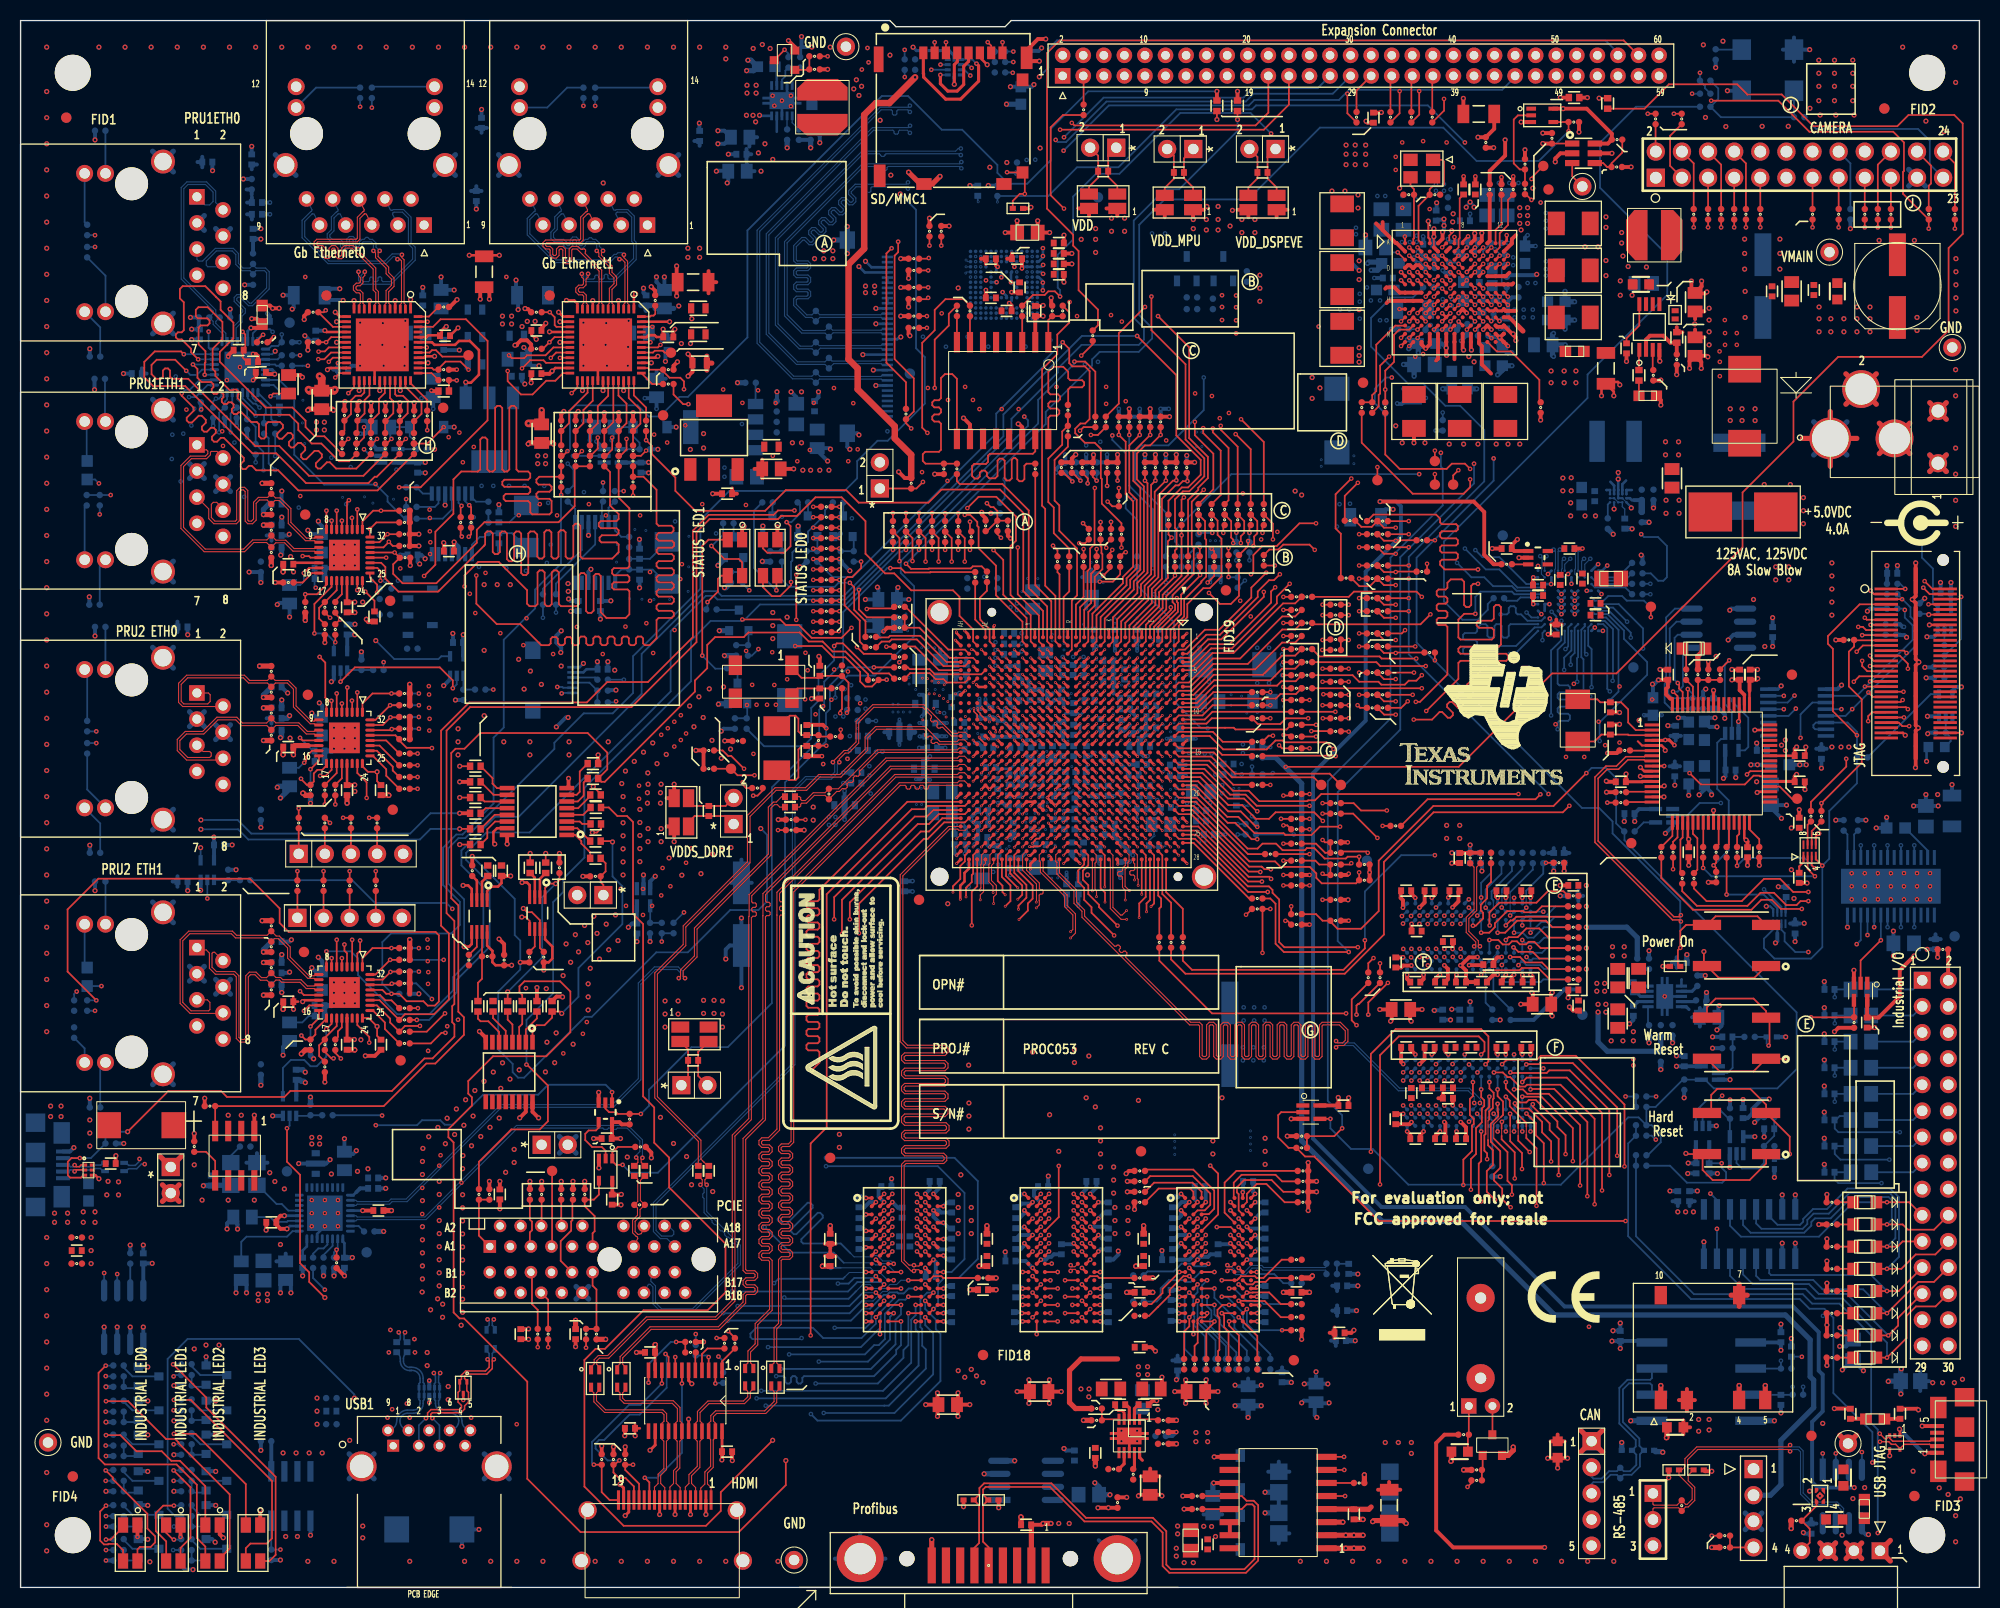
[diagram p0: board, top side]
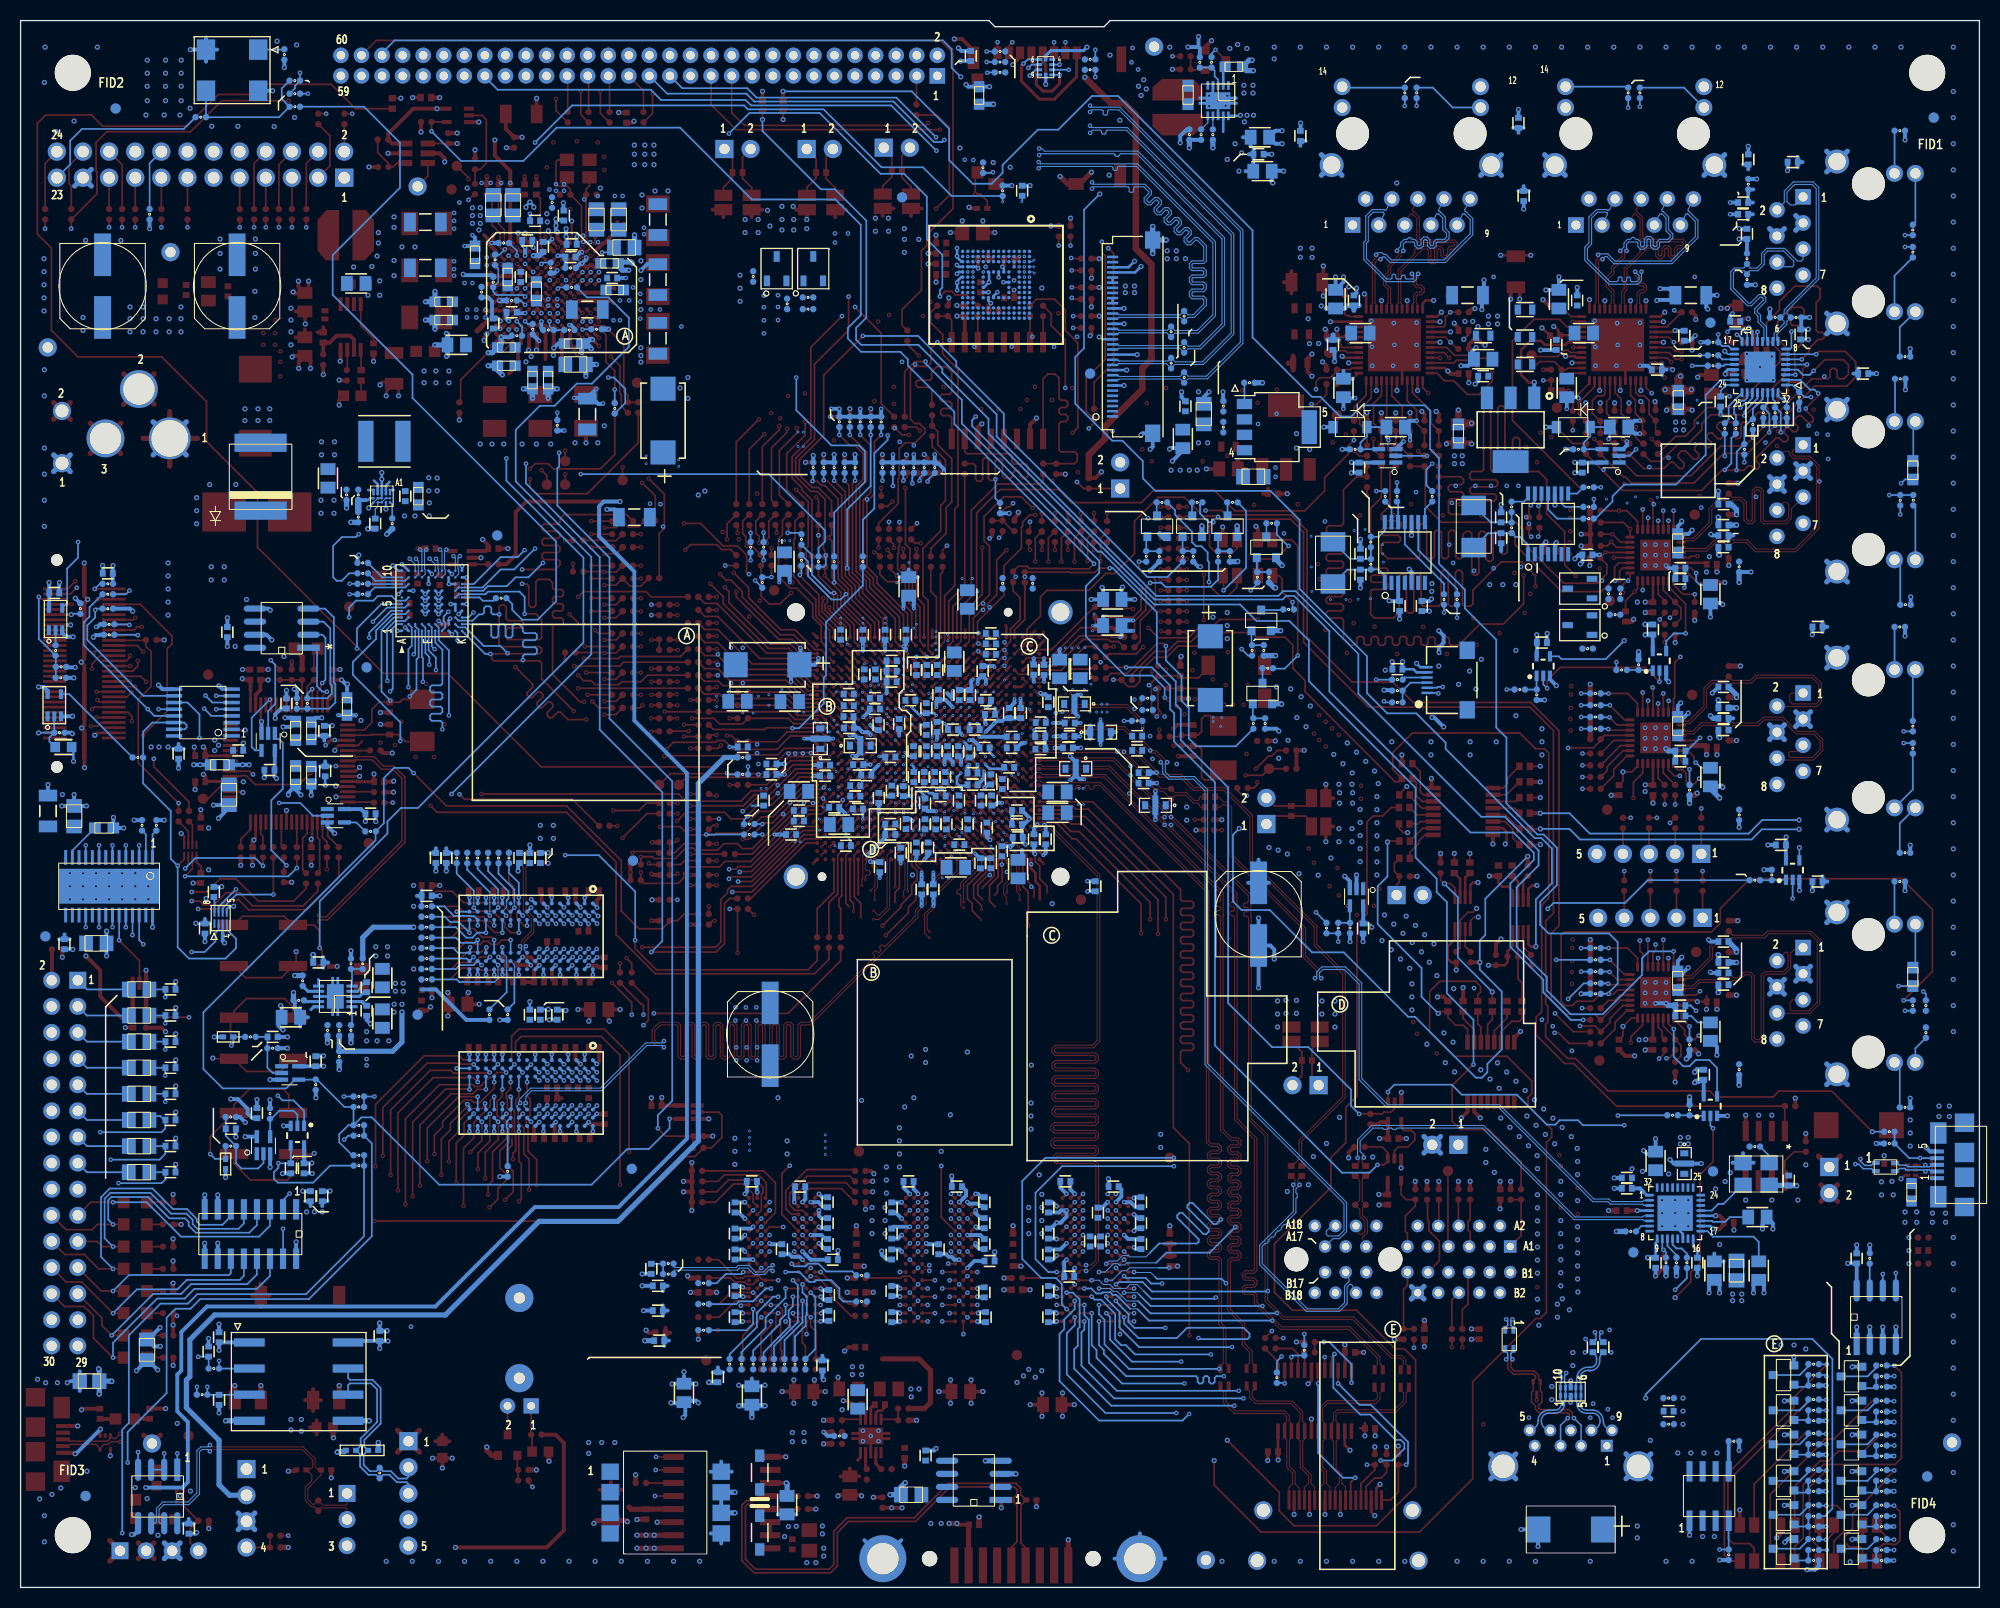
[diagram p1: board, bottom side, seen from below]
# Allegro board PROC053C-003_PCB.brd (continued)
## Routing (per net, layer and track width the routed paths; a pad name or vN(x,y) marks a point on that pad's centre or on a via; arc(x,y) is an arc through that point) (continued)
DDR_CLKN: length 158.4
  TOP w0.108: v2(102.12,30.78) 102.27,30.94 102.56,30.94 U7.K7 ; U1.AH24 90.25,74.02 85.55,69.32 85.55,53.09 86.15,52.48 89.8,52.48 89.94,52.34 89.94,52.14 89.8,51.99 85.97,51.99 85.67,51.7 85.67,51.29 85.97,50.99 89.8,50.99 89.94,50.85 89.94,50.65 89.8,50.51 85.97,50.51 85.67,50.21 85.67,49.8 85.97,49.51 89.8,49.51 89.94,49.37 89.94,49.16 89.8,49.02 85.97,49.02 85.67,48.73 85.67,48.31 85.97,48.02 89.8,48.02 89.94,47.88 89.94,47.68 89.8,47.53 85.97,47.53 85.67,47.24 85.67,46.83 85.97,46.54 89.8,46.54 89.94,46.39 89.94,46.19 89.8,46.05 85.97,46.05 85.67,45.76 85.67,45.24 85.97,44.95 89.9,44.95 90.04,44.8 90.04,44.6 89.9,44.46 85.97,44.46 85.67,44.17 85.67,43.75 85.97,43.46 89.9,43.46 90.04,43.32 90.04,43.12 89.9,42.97 85.97,42.97 85.67,42.68 85.67,42.27 85.97,41.98 89.68,41.98 89.82,41.83 89.82,41.63 89.67,41.49 86.01,41.49 85.67,41.15 85.67,31.72 86.61,30.78 v2(86.88,30.78) 87,30.9 87.35,30.9 U5.K7 ; U6.K7 117.8,30.94 117.51,30.94 v2(117.36,30.78)
  L3_SIG1 w0.083: v2(86.88,30.78) 87.01,30.91 87.29,30.91 87.83,31.45 88.25,31.45 88.5,31.2 89.14,31.2 89.54,31.6 91.43,31.6 91.73,31.9 98.24,31.9 98.94,31.2 99.53,31.2 99.91,31.58 99.91,31.67 100.11,31.87 100.62,31.87 101.57,30.92 101.99,30.92 v2(102.12,30.78) 102.25,30.91 102.53,30.91 103.07,31.45 103.49,31.45 103.74,31.2 104.38,31.2 104.78,31.6 106.67,31.6 106.97,31.9 113.48,31.9 114.18,31.2 114.77,31.2 115.15,31.58 115.15,31.67 115.35,31.87 115.86,31.87 116.94,30.78 v2(117.36,30.78)
  BOTTOM w0.108: R47.2 127,30.75 126.89,30.86 120.8,30.86 120.6,31.06 119.76,31.06 119.13,30.43 118.16,30.43 117.65,30.94 117.51,30.94 v2(117.36,30.78)
DDR_CS0N: length 145.6
  TOP w0.173: U1.AH23 89.64,74.81 88.35,73.53 87.54,73.53 80.64,66.63 v7(80.64,64.98) ; R50.2 109.74,26.42 110.59,27.27 111.76,28.44 111.76,28.95 113.09,30.28 v2(113.66,30.28) U6.L2 ; U5.L2 v2(83.18,30.28) ; U7.L2 v2(98.42,30.28)
  L3_SIG1 w0.109: v5(77.9,37.01) 77.54,37.01 77.29,36.75 77.29,34.48 77.43,34.34 78.99,34.34 79.14,34.2 79.14,34 78.99,33.86 77.43,33.86 77.29,33.72 77.29,33.52 77.43,33.38 78.99,33.38 79.14,33.24 79.14,33.04 78.99,32.9 77.43,32.9 77.29,32.76 77.29,32.56 77.43,32.42 78.93,32.42 79.07,32.28 79.07,32.08 78.93,31.94 77.43,31.94 77.29,31.8 77.29,29.91 77.63,29.57 77.91,29.57 78.02,29.46 78.02,29.1 78.13,28.99 78.35,28.99 78.46,29.1 78.46,29.46 78.57,29.57 78.79,29.57 78.9,29.46 78.9,29.1 79,28.99 79.22,28.99 79.33,29.1 79.33,29.46 79.44,29.57 79.78,29.57 80.41,30.2 80.86,30.2 80.98,30.32 80.98,30.49 80.87,30.6 79.89,30.6 79.78,30.72 79.78,31.01 79.89,31.13 80.87,31.13 80.99,31.25 80.99,31.42 80.87,31.54 79.89,31.54 79.78,31.65 79.78,31.82 79.89,31.94 80.87,31.94 80.99,32.06 80.99,32.22 80.87,32.34 79.89,32.34 79.78,32.46 79.78,32.63 79.89,32.75 80.87,32.75 80.99,32.87 80.99,33.03 80.87,33.15 79.89,33.15 79.78,33.27 79.78,33.44 79.89,33.55 80.87,33.55 80.99,33.67 80.99,33.84 80.87,33.96 79.89,33.96 79.78,34.08 79.78,34.24 79.89,34.36 80.87,34.36 80.99,34.48 80.99,34.65 80.87,34.77 79.89,34.77 79.78,34.88 79.78,35.05 79.89,35.17 80.87,35.17 80.99,35.29 80.99,35.46 80.87,35.57 79.89,35.57 79.36,36.11 79.36,36.46 77.88,37.94 77.88,50.44 78.66,51.23 78.82,51.23 78.98,51.07 79.15,51.07 79.26,51.18 79.26,51.35 79.1,51.51 79.1,51.67 79.38,51.94 79.38,63.71 v7(80.64,64.98)
  L10_SIG4 w0.109: v2(113.66,30.28) 112.12,30.28 110.64,31.75 107.57,31.75 106.93,31.12 103.8,31.12 103.46,31.46 103.38,31.46 103.38,31.46 103.06,31.46 103.06,31.46 102.93,31.46 102.64,31.75 100.57,31.75 100.44,31.88 100.02,31.88 v2(98.42,30.28) 97.26,30.28 95.84,31.7 94.79,31.7 94.65,31.56 94.65,31.41 94.51,31.27 94.31,31.27 94.17,31.42 94.17,31.58 93.99,31.75 92.33,31.75 91.69,31.12 88.56,31.12 88.18,31.5 87.65,31.5 87.42,31.73 85.77,31.73 84.66,30.62 83.52,30.62 v2(83.18,30.28) ; v5(77.9,37.01) 79.5,35.41 79.5,32.52 80.02,32 80.02,30.09 v9(79.48,29.56)
  BOTTOM w0.173: v2(83.18,30.28) 83.01,30.1 81.08,30.1 80.53,29.56 v9(79.48,29.56)
DDR_D0: length 59.5
  TOP w0.173: U1.AF25 v4(92.64,72.82) ; U5.E3 v2(84.78,35.08)
  L3_SIG1 w0.109: v4(92.64,72.82) v5(92.24,72.57)
  L10_SIG4 w0.109: v5(92.24,72.57) 91.8,73 88.29,73 83.57,68.28 83.57,53.28 83.68,53.16 83.99,53.16 84.1,53.05 84.1,52.88 83.99,52.77 83.68,52.77 83.57,52.65 83.57,52.49 83.68,52.37 83.99,52.37 84.1,52.25 84.1,52.09 83.99,51.97 83.68,51.97 83.57,51.86 83.57,51.69 83.68,51.58 83.99,51.58 84.1,51.46 84.1,51.3 83.99,51.18 83.68,51.18 83.57,51.07 83.57,50.9 83.68,50.79 83.99,50.79 84.1,50.67 84.1,50.51 83.99,50.39 83.68,50.39 83.57,50.27 83.57,50.11 83.68,49.99 83.99,49.99 84.1,49.88 84.1,49.71 83.99,49.6 83.68,49.6 83.57,49.48 83.57,49.32 83.68,49.2 83.99,49.2 84.1,49.08 84.1,48.92 83.99,48.8 83.68,48.8 83.57,48.69 83.57,48.52 83.68,48.41 83.99,48.41 84.1,48.29 84.1,48.13 83.99,48.01 83.68,48.01 83.57,47.9 83.57,47.73 83.68,47.62 83.99,47.62 84.1,47.5 84.1,47.34 83.99,47.22 83.68,47.22 83.57,47.1 83.57,46.94 83.68,46.82 83.99,46.82 84.1,46.71 84.1,46.54 83.99,46.43 83.68,46.43 83.57,46.31 83.57,46.15 83.68,46.03 83.96,46.03 84.08,45.91 84.08,45.75 83.96,45.63 83.68,45.63 83.57,45.52 83.57,45.35 83.68,45.24 83.96,45.24 84.08,45.12 84.08,44.96 83.96,44.84 83.68,44.84 83.57,44.73 83.57,44.56 83.68,44.45 83.96,44.45 84.08,44.33 84.08,44.17 83.96,44.05 83.68,44.05 83.57,43.93 83.57,43.77 83.68,43.65 83.96,43.65 84.08,43.54 84.08,43.37 83.96,43.26 83.68,43.26 83.57,43.14 83.57,42.98 83.68,42.86 83.96,42.86 84.08,42.74 84.08,42.58 83.96,42.46 83.68,42.46 83.57,42.35 83.57,42.18 83.68,42.07 83.96,42.07 84.08,41.95 84.08,41.79 83.96,41.67 83.62,41.67 83.5,41.56 83.5,41.39 83.62,41.28 83.91,41.28 84.03,41.16 84.03,40.88 83.91,40.76 83.71,40.76 83.59,40.64 83.59,40.47 83.71,40.36 83.91,40.36 84.03,40.24 84.03,39.88 83.57,39.42 83.57,35.74 83.82,35.48 84.37,35.48 v2(84.78,35.08)
DDR_D1: length 59.8
  TOP w0.173: U1.AF26 v4(92.64,72.02) ; U5.F7 v2(87.18,34.28)
  L3_SIG1 w0.109: v4(92.64,72.02) v5(92.24,71.77)
  L10_SIG4 w0.109: v5(92.24,71.77) 92.63,71.37 92.63,69.6 89.64,66.6 89.64,64.95 89.39,64.71 89.39,52.49 89.51,52.38 90.11,52.38 90.24,52.25 90.24,52.09 90.13,51.98 89.51,51.98 89.39,51.87 89.39,51.7 89.51,51.59 90.17,51.59 90.29,51.47 90.29,51.31 90.17,51.19 89.51,51.19 89.39,51.07 89.39,50.91 89.51,50.79 90.17,50.79 90.29,50.68 90.29,50.51 90.17,50.4 89.51,50.4 89.39,50.28 89.39,50.12 89.51,50 90.17,50 90.29,49.88 90.29,49.72 90.17,49.6 89.51,49.6 89.39,49.49 89.39,49.32 89.51,49.21 90.17,49.21 90.29,49.09 90.29,48.93 90.17,48.81 89.51,48.81 89.39,48.7 89.39,48.53 89.51,48.42 90.17,48.42 90.29,48.3 90.29,48.14 90.17,48.02 89.51,48.02 89.39,47.9 89.39,47.74 89.51,47.62 90.22,47.62 90.34,47.51 90.34,47.34 90.22,47.23 89.51,47.23 89.39,47.11 89.39,46.95 89.51,46.83 90.22,46.83 90.34,46.71 90.34,46.55 90.22,46.43 89.51,46.43 89.39,46.32 89.39,46.15 89.51,46.04 90.22,46.04 90.34,45.92 90.34,45.76 90.22,45.64 89.51,45.64 89.39,45.53 89.39,45.36 89.51,45.25 90.4,45.25 90.52,45.13 90.52,44.97 90.4,44.85 89.51,44.85 89.39,44.73 89.39,44.57 89.51,44.45 90.37,44.45 90.5,44.33 90.5,44.16 90.39,44.06 89.51,44.06 89.39,43.94 89.39,42.78 86.56,39.95 86.56,35.82 86.72,35.66 86.72,34.74 v2(87.18,34.28)
DDR_D2: length 59.5
  TOP w0.173: U5.F8 v2(87.98,34.28) ; U1.AG26 v4(91.84,72.02)
  L3_SIG1 w0.109: v4(91.84,72.02) v5(91.44,71.77)
  L10_SIG4 w0.109: v2(87.98,34.28) 87.59,33.88 87.02,33.88 86.46,34.44 86.46,35.61 86.33,35.74 86.33,40.4 87.91,41.98 87.91,44.06 88.02,44.18 88.74,44.18 88.85,44.3 88.85,44.46 88.74,44.58 88.02,44.58 87.91,44.69 87.91,44.86 88.02,44.97 88.74,44.97 88.85,45.09 88.85,45.25 88.74,45.37 88.02,45.37 87.91,45.48 87.91,45.65 88.02,45.76 88.74,45.76 88.85,45.88 88.85,46.04 88.74,46.16 88.02,46.16 87.91,46.28 87.91,46.44 88.02,46.56 88.74,46.56 88.85,46.67 88.85,46.84 88.74,46.95 88.02,46.95 87.91,47.07 87.91,47.23 88.02,47.35 88.74,47.35 88.85,47.47 88.85,47.63 88.74,47.75 88.02,47.75 87.91,47.86 87.91,48.03 88.02,48.14 88.76,48.14 88.87,48.25 88.87,48.42 88.75,48.54 88.02,48.54 87.91,48.65 87.91,48.82 88.02,48.93 88.78,48.93 88.89,49.05 88.89,49.21 88.77,49.33 88.02,49.33 87.91,49.45 87.91,49.61 88.02,49.73 88.79,49.73 88.89,49.83 88.89,50 88.77,50.12 88.02,50.12 87.91,50.24 87.91,50.4 88.02,50.52 88.79,50.52 88.89,50.62 88.89,50.79 88.77,50.92 88.02,50.92 87.91,51.03 87.91,51.2 88.02,51.31 88.75,51.31 88.88,51.44 88.88,51.6 88.77,51.71 88.02,51.71 87.91,51.82 87.91,65.43 91.44,68.96 v5(91.44,71.77)
DDR_D3: length 59.4
  TOP w0.173: U1.AH26 v4(91.04,72.02) ; U5.H8 v2(87.98,32.68)
  L3_SIG1 w0.109: v4(91.04,72.02) v5(90.64,71.77)
  L10_SIG4 w0.109: v2(87.98,32.68) 87.59,33.07 87.02,33.07 86.79,33.3 86.79,33.48 86.23,34.04 86.23,35.33 86.06,35.51 86.06,40.52 86.23,40.69 86.23,40.98 87.37,42.12 87.37,42.77 87.26,42.89 85.75,42.89 85.64,43.01 85.64,43.17 85.75,43.29 87.26,43.29 87.37,43.4 87.37,43.57 87.26,43.68 85.75,43.68 85.64,43.8 85.64,43.96 85.75,44.08 87.26,44.08 87.37,44.19 87.37,44.36 87.26,44.47 85.75,44.47 85.64,44.59 85.64,44.75 85.75,44.87 87.26,44.87 87.37,44.99 87.37,45.21 87.26,45.33 86.42,45.33 86.3,45.44 86.3,45.61 86.42,45.73 87.26,45.73 87.37,45.84 87.37,53.12 87.26,53.23 86.52,53.23 86.41,53.34 86.41,53.51 86.53,53.63 87.26,53.63 87.37,53.75 87.37,53.91 87.26,54.03 86.42,54.03 86.31,54.14 86.31,54.31 86.42,54.42 87.26,54.42 87.37,54.54 87.37,69.81 89.33,71.77 v5(90.64,71.77)
DDR_D4: length 59.5
  TOP w0.173: U1.AF24 v4(92.64,73.62) ; U5.F2 v2(83.98,34.28)
  L3_SIG1 w0.109: v4(92.64,73.62) v5(92.24,73.37)
  L10_SIG4 w0.109: v5(92.24,73.37) 87.97,73.37 83,68.4 83,55.22 82.89,55.1 82.33,55.1 82.22,54.99 82.22,54.82 82.33,54.71 82.89,54.71 83,54.59 83,54.43 82.89,54.31 82.33,54.31 82.22,54.19 82.22,54.03 82.33,53.91 82.89,53.91 83,53.8 83,53.63 82.89,53.52 82.33,53.52 82.22,53.4 82.22,53.24 82.33,53.12 82.89,53.12 83,53.01 83,52.84 82.89,52.73 82.33,52.73 82.22,52.61 82.22,52.45 82.33,52.33 82.89,52.33 83,52.21 83,52.05 82.89,51.93 82.33,51.93 82.22,51.82 82.22,51.65 82.33,51.54 82.89,51.54 83,51.42 83,51.26 82.89,51.14 82.33,51.14 82.22,51.02 82.22,50.86 82.33,50.74 82.89,50.74 83,50.63 83,50.46 82.89,50.35 82.33,50.35 82.22,50.23 82.22,50.07 82.33,49.95 82.89,49.95 83,49.84 83,49.67 82.89,49.56 82.45,49.56 82.33,49.43 82.33,49.27 82.44,49.16 82.89,49.16 83,49.04 83,48.88 82.89,48.76 82.52,48.76 82.41,48.65 82.41,48.49 82.53,48.37 82.89,48.37 83,48.25 83,48.01 82.87,47.87 82.87,40.54 81.81,39.48 81.81,37.57 82.68,36.7 82.68,35.58 v2(83.98,34.28)
DDR_D5: length 59.5
  TOP w0.173: U1.AE24 v4(93.44,73.62) ; U5.G2 v2(83.98,33.48)
  L3_SIG1 w0.109: v5(93.04,73.37) 93.04,73.39 93.42,73.62 v4(93.44,73.62)
  L10_SIG4 w0.109: v5(93.04,73.37) 92.64,73.77 87.69,73.77 81.39,67.46 81.39,48.31 82.4,47.3 82.4,43.76 82.28,43.64 81.47,43.64 81.35,43.53 81.35,43.36 81.47,43.25 82.29,43.25 82.41,43.13 82.41,42.96 82.3,42.85 81.47,42.85 81.35,42.74 81.35,42.57 81.47,42.46 82.31,42.46 82.42,42.35 82.42,42.18 82.3,42.06 81.47,42.06 81.35,41.94 81.35,41.78 81.47,41.66 82.28,41.66 82.4,41.55 82.4,40.72 82.25,40.57 82.08,40.57 81.65,41 81.5,41 81.38,40.88 81.38,40.71 81.8,40.29 81.8,40.13 81.39,39.72 81.39,35.71 81.91,35.18 82.4,35.18 82.68,34.9 82.68,34.16 83.36,33.48 v2(83.98,33.48)
DDR_D6: length 59.5
  TOP w0.173: U5.H3 v2(84.78,32.68) ; U1.AF23 v4(92.64,74.42)
  L3_SIG1 w0.109: v4(92.64,74.42) v5(92.24,74.17)
  L10_SIG4 w0.109: v2(84.78,32.68) 84.38,33.08 83.04,33.08 81.59,34.53 81.43,34.53 81.24,34.34 81.08,34.34 80.97,34.45 80.97,34.64 81.14,34.81 81.14,34.98 80.9,35.22 80.9,44.49 81.04,44.63 81.8,44.63 81.94,44.77 81.94,44.97 81.8,45.11 81.04,45.11 80.9,45.25 80.9,45.45 81.04,45.59 81.8,45.59 81.94,45.73 81.94,45.93 81.8,46.07 81.04,46.07 80.9,46.21 80.9,46.41 81.04,46.55 81.8,46.55 81.94,46.69 81.94,46.89 81.8,47.03 81.04,47.03 80.9,47.17 80.9,67.86 87.06,74.02 90.02,74.02 90.61,74.6 91.8,74.6 v5(92.24,74.17)
DDR_D7: length 59.6
  TOP w0.173: U5.H7 v2(87.18,32.68) ; U1.AE23 v4(93.44,74.42)
  L3_SIG1 w0.109: v4(93.44,74.42) v5(93.04,74.17)
  L10_SIG4 w0.109: v2(87.18,32.68) 85.74,32.68 85.35,32.29 82.44,32.29 80.39,34.34 80.39,68.33 86.54,74.48 90.1,74.48 90.51,74.88 91.87,74.88 92.13,75.14 92.63,75.14 93.04,74.74 93.04,74.17 v5(93.04,74.17)
DDR_D8: length 52.8
  TOP w0.173: U1.AC23 v4(95.04,74.42) ; U5.D7 v2(87.18,35.88)
  L3_SIG1 w0.099: 90.43,73.11 91.96,73.11 92.08,72.99 92.39,72.99 92.51,73.11 92.76,73.11 92.88,72.99 93.99,72.99 94.11,73.11 94.32,73.11 94.74,73.53 94.74,74.12 v4(95.04,74.42)
  L3_SIG1 w0.109: 90.43,73.11 86.96,69.63 86.96,67.5 85.35,65.89 85.35,51.03 82.9,48.58 82.58,48.58 82.46,48.7 82.3,48.7 82.19,48.59 82.19,48.41 82.3,48.3 82.3,48.14 81.79,47.63 81.79,37.29 82.8,36.28 86.78,36.28 v2(87.18,35.88)
DDR_D9: length 53
  TOP w0.173: U5.C3 v2(84.78,36.68) ; U1.AF27 93.03,71.62 92.63,71.22 92.63,69.42 92.51,69.29 92.51,68.61 91.95,68.05 v4(91.95,67.16)
  L3_SIG1 w0.109: v4(91.95,67.16) 91.95,66.93 88.87,63.85 88.87,60.41 88.76,60.3 88.45,60.3 88.34,60.19 88.34,59.97 88.45,59.86 88.76,59.86 88.87,59.76 88.87,59.54 88.76,59.43 88.45,59.43 88.34,59.32 88.34,59.1 88.45,58.99 88.76,58.99 88.87,58.88 88.87,58.66 88.76,58.55 88.45,58.55 88.34,58.44 88.34,58.23 88.45,58.12 88.76,58.12 88.87,58.01 88.87,57.79 88.76,57.68 88.45,57.68 88.34,57.57 88.34,57.35 88.45,57.24 88.76,57.24 88.87,57.13 88.87,56.92 88.76,56.81 88.45,56.81 88.34,56.7 88.34,56.48 88.45,56.37 88.76,56.37 88.87,56.26 88.87,56.04 88.76,55.93 88.45,55.93 88.34,55.82 88.34,55.61 88.45,55.5 88.76,55.5 88.87,55.39 88.87,55.17 88.76,55.06 88.45,55.06 88.34,54.95 88.34,54.73 88.45,54.62 88.76,54.62 88.87,54.51 88.87,54.29 88.76,54.19 88.45,54.19 88.34,54.08 88.34,53.86 88.45,53.75 88.76,53.75 88.87,53.64 88.87,53.42 88.76,53.31 88.45,53.31 88.34,53.2 88.34,52.98 88.45,52.87 88.76,52.87 88.87,52.77 88.87,52.32 87.93,51.38 87.93,50.23 88.04,50.12 88.64,50.12 88.75,50.01 88.75,49.79 88.64,49.68 88.04,49.68 87.93,49.57 87.93,49.35 88.04,49.24 88.64,49.24 88.75,49.13 88.75,48.92 88.64,48.81 88.04,48.81 87.93,48.7 87.93,48.48 88.04,48.37 88.64,48.37 88.75,48.26 88.75,48.04 88.64,47.93 88.04,47.93 87.93,47.82 87.93,47.61 88.04,47.5 88.64,47.5 88.75,47.39 88.75,47.17 88.64,47.06 88.04,47.06 87.93,46.95 87.93,46.73 88.04,46.62 88.64,46.62 88.75,46.51 88.75,46.29 88.64,46.19 88.04,46.19 87.93,46.08 87.93,42.23 85.36,39.66 85.36,37.26 v2(84.78,36.68)
DDR_D10: length 53
  TOP w0.173: v4(90.68,67.62) 90.68,68.2 91.39,68.91 91.39,70.17 91.83,70.62 91.83,71.21 U1.AG27 ; U5.A3 v2(84.78,38.28)
  L3_SIG1 w0.109: v4(90.68,67.62) 90.14,67.09 89.89,67.09 87.86,65.05 87.86,59.8 87.75,59.69 87.41,59.69 87.3,59.58 87.3,59.36 87.41,59.25 87.75,59.25 87.86,59.15 87.86,58.93 87.75,58.82 87.41,58.82 87.3,58.71 87.3,58.49 87.41,58.38 87.75,58.38 87.86,58.27 87.86,58.05 87.75,57.94 87.41,57.94 87.3,57.84 87.3,57.62 87.41,57.51 87.75,57.51 87.86,57.4 87.86,57.18 87.75,57.07 87.41,57.07 87.3,56.96 87.3,56.74 87.41,56.63 87.75,56.63 87.86,56.52 87.86,56.31 87.75,56.2 87.41,56.2 87.3,56.09 87.3,55.87 87.41,55.76 87.75,55.76 87.86,55.65 87.86,55.43 87.75,55.32 87.41,55.32 87.3,55.21 87.3,55 87.41,54.89 87.75,54.89 87.86,54.78 87.86,54.56 87.75,54.45 87.41,54.45 87.3,54.34 87.3,54.12 87.41,54.01 87.75,54.01 87.86,53.9 87.86,53.68 87.75,53.58 87.41,53.58 87.3,53.47 87.3,53.25 87.41,53.14 87.75,53.14 87.86,53.03 87.86,52.35 87.38,51.88 87.38,43.93 86.6,43.15 86.6,42.99 87.18,42.41 87.18,42.24 87.06,42.13 86.9,42.13 86.2,42.83 86.02,42.83 85.9,42.71 85.9,42.56 86.62,41.85 86.62,41.68 86.5,41.57 86.34,41.57 85.62,42.29 85.45,42.29 85.34,42.17 85.34,42.01 86.06,41.29 86.06,41.12 85.94,41.01 85.78,41.01 85.03,41.75 84.86,41.75 84.74,41.63 84.74,41.48 85.5,40.73 85.5,40.56 85.38,40.45 85.21,40.45 84.64,41.03 84.47,41.03 84.28,40.83 84.28,38.78 v2(84.78,38.28)
DDR_D11: length 53.1
  TOP w0.173: U5.A7 v2(87.18,38.28) ; U1.AF28 93.04,68.2 92.51,67.67 v7(92.51,64.39)
  L3_SIG1 w0.109: v7(92.51,64.39) 92.51,54.33 93.03,53.81 93.03,52.93 92.92,52.82 92.46,52.82 92.35,52.71 92.35,52.49 92.46,52.39 92.92,52.39 93.03,52.28 93.03,50.32 92.91,50.21 92.37,50.21 92.25,50.09 92.25,49.93 92.37,49.81 92.91,49.81 93.03,49.69 93.03,49.53 92.91,49.41 92.37,49.41 92.25,49.3 92.25,49.13 92.37,49.02 92.91,49.02 93.03,48.9 93.03,48.74 92.91,48.62 92.34,48.62 92.23,48.51 92.23,48.34 92.34,48.23 92.91,48.23 93.03,48.11 93.03,44.64 92.15,43.76 92.15,43.6 93.03,42.71 93.03,42.55 92.92,42.43 92.75,42.43 91.87,43.32 91.7,43.32 91.59,43.2 91.59,43.04 92.7,41.92 92.7,41.76 92.59,41.64 92.42,41.64 91.31,42.75 91.14,42.75 91.03,42.64 91.03,42.47 92.09,41.41 92.09,41.26 91.98,41.15 91.79,41.15 90.75,42.19 90.58,42.19 90.46,42.08 90.46,41.91 91.45,40.93 91.45,40.76 91.33,40.65 91.17,40.65 90.18,41.63 90.02,41.63 87.18,38.79 v2(87.18,38.28)
DDR_D12: length 52.7
  TOP w0.173: U5.A2 v2(83.98,38.28) ; U1.AE26 v4(93.44,72.02)
  L3_SIG1 w0.109: v2(83.98,38.28) 83.74,38.51 83.74,42.09 83.86,42.2 84.49,42.2 84.6,42.31 84.6,42.48 84.48,42.6 83.86,42.6 83.74,42.71 83.74,42.88 83.86,42.99 85.56,42.99 85.67,43.1 85.67,43.27 85.55,43.39 83.86,43.39 83.74,43.51 83.74,43.67 83.86,43.79 86.18,43.79 86.3,43.91 86.3,44.07 86.19,44.18 83.9,44.18 83.7,44.39 83.7,44.55 83.9,44.76 86.31,44.76 86.61,45.05 86.61,45.28 86.72,45.4 86.82,45.4 86.94,45.51 86.94,45.68 86.82,45.79 86.72,45.79 86.61,45.91 86.61,46.07 86.72,46.19 86.82,46.19 86.94,46.3 86.94,46.47 86.82,46.58 86.72,46.58 86.61,46.7 86.61,46.87 86.72,46.98 86.82,46.98 86.94,47.1 86.94,47.26 86.82,47.38 86.72,47.38 86.61,47.49 86.61,47.66 86.72,47.77 86.82,47.77 86.94,47.89 86.94,48.05 86.82,48.17 86.72,48.17 86.61,48.29 86.61,48.45 86.72,48.57 86.82,48.57 86.94,48.68 86.94,50.7 86.46,51.18 86.46,64.51 89.5,67.55 90.19,67.55 92.96,70.33 92.96,71.53 93.35,71.91 93.35,71.93 v4(93.44,72.02)
DDR_D13: length 52.7
  TOP w0.173: U1.AC25 v4(95.04,72.82) ; U5.C8 v2(87.98,36.68)
  L3_SIG1 w0.099: 94.17,71.24 94.74,71.81 94.74,72.52 v4(95.04,72.82)
  L3_SIG1 w0.109: v2(87.98,36.68) 88.37,36.28 93.58,36.28 93.96,36.67 93.96,37.56 93.82,37.7 92.51,37.7 92.39,37.82 92.39,37.98 92.51,38.1 93.85,38.1 93.96,38.22 93.96,38.38 93.85,38.5 92.48,38.5 92.37,38.61 92.37,38.78 92.48,38.89 93.85,38.89 93.96,39.01 93.96,39.17 93.85,39.29 92.49,39.29 92.38,39.4 92.38,39.56 92.5,39.68 93.85,39.68 93.96,39.8 93.96,66.48 94.17,66.69 94.17,71.24
DDR_D14: length 52.9
  TOP w0.173: U1.AC24 v4(95.04,73.62) ; U5.B8 v2(87.98,37.48)
  L3_SIG1 w0.099: v4(95.04,73.62) 95.04,73.32 94.53,72.82 94.53,71.9 93.73,71.09
  L3_SIG1 w0.109: v2(87.98,37.48) 89.32,37.48 89.44,37.59 89.44,40.12 89.55,40.24 89.72,40.24 89.83,40.12 89.83,37.59 89.95,37.48 90.11,37.48 90.23,37.59 90.23,40.15 90.35,40.28 90.52,40.28 90.63,40.17 90.63,37.59 90.74,37.48 91.6,37.48 91.95,37.82 91.95,39.88 93.48,41.41 93.48,66.58 93.73,66.82 93.73,71.09
DDR_D15: length 52.6
  TOP w0.173: U5.C2 v2(83.98,36.68) ; U1.AD25 v4(94.24,72.82)
  L3_SIG1 w0.099: 90.19,72.19 90.79,72.19 90.91,72.31 91.16,72.31 91.28,72.19 91.59,72.19 91.71,72.31 91.96,72.31 92.08,72.19 92.4,72.19 92.73,72.52 93.94,72.52 v4(94.24,72.82)
  L3_SIG1 w0.109: 90.19,72.19 87.49,69.48 87.49,67.27 85.95,65.74 85.95,50.9 85.57,50.52 85.57,50.13 85.96,49.74 85.96,49.58 85.84,49.46 85.68,49.46 85.29,49.85 85.13,49.85 85.01,49.73 85.01,49.57 85.48,49.11 85.48,48.94 85.36,48.83 85.2,48.83 84.73,49.29 84.57,49.29 84.45,49.17 84.45,49.01 84.91,48.55 84.91,48.38 84.8,48.26 84.63,48.26 84.17,48.73 84.01,48.73 83.89,48.61 83.89,48.45 84.35,47.98 84.35,47.82 84.24,47.7 84.07,47.7 83.61,48.17 83.45,48.17 83.33,48.05 83.33,47.89 83.82,47.4 83.82,47.25 83.7,47.13 83.53,47.13 83.05,47.61 82.89,47.61 82.63,47.35 82.63,37.26 83.21,36.68 v2(83.98,36.68)
DDR_D16: length 52.1
  TOP w0.173: U1.V20 v4(99.04,76.82) ; v2(100.97,41) 100.97,36.02 U7.E3
  L3_SIG1 w0.109: v4(99.04,76.82) v5(98.64,76.57)
  L10_SIG4 w0.109: v2(100.97,41) 101.86,41.89 101.86,52.32 101.75,52.43 101.43,52.43 101.32,52.54 101.32,52.76 101.43,52.87 101.75,52.87 101.86,52.98 101.86,53.2 101.75,53.31 101.43,53.31 101.32,53.41 101.32,53.63 101.43,53.74 101.75,53.74 101.86,53.85 101.86,54.07 101.75,54.18 101.43,54.18 101.32,54.29 101.32,54.51 101.43,54.62 101.75,54.62 101.86,54.73 101.86,54.94 101.75,55.05 101.43,55.05 101.32,55.16 101.32,55.38 101.43,55.49 101.75,55.49 101.86,55.6 101.86,55.82 101.75,55.93 101.43,55.93 101.32,56.04 101.32,56.25 101.43,56.36 101.75,56.36 101.86,56.47 101.86,56.69 101.75,56.8 101.43,56.8 101.32,56.91 101.32,57.13 101.43,57.24 101.75,57.24 101.86,57.35 101.86,57.57 101.75,57.67 101.43,57.67 101.32,57.78 101.32,58 101.43,58.11 101.75,58.11 101.86,58.22 101.86,58.44 101.75,58.55 101.43,58.55 101.32,58.66 101.32,58.88 101.43,58.98 101.75,58.98 101.86,59.09 101.86,62.17 100.81,63.23 100.81,66.53 98.25,69.09 98.25,76.18 v5(98.64,76.57)
DDR_D17: length 51.8
  TOP w0.173: U1.W20 v4(98.24,76.82) ; U7.H8 v2(103.22,32.68)
  L3_SIG1 w0.109: v4(98.24,76.82) v5(97.84,76.57)
  L10_SIG4 w0.109: v5(97.84,76.57) 98.24,76.97 98.78,76.97 99.06,76.69 99.06,75.03 98.58,74.54 98.58,69.72 101.3,67.01 101.3,63.45 103.02,61.73 103.02,50.61 103.58,50.04 103.58,48.54 103.02,47.98 103.02,41.38 105.28,39.12 105.28,34.08 103.88,32.68 v2(103.22,32.68)
DDR_D18: length 52.1
  TOP w0.173: U7.H3 v2(100.02,32.68) ; U1.AB28 96.24,69.45 97.41,68.28 97.41,67.37 v4(96.98,66.93)
  L3_SIG1 w0.109: v5(96.63,66.59) 96.98,66.93 v4(96.98,66.93)
  L10_SIG4 w0.109: v2(100.02,32.68) 101.08,33.73 101.08,35.02 100.53,35.56 100.53,37.57 100.23,37.88 99.85,37.88 99.62,38.1 99.62,38.44 99.37,38.68 95.68,38.68 94.8,39.57 94.8,40.38 94.91,40.49 95.62,40.49 95.73,40.6 95.73,40.82 95.62,40.93 94.91,40.93 94.8,41.04 94.8,41.26 94.91,41.37 95.57,41.37 95.68,41.48 95.68,41.69 95.57,41.8 94.91,41.8 94.8,41.91 94.8,42.13 94.91,42.24 95.57,42.24 95.68,42.35 95.68,42.57 95.57,42.68 94.91,42.68 94.8,42.79 94.8,43.01 94.91,43.11 95.57,43.11 95.68,43.22 95.68,43.44 95.57,43.55 94.91,43.55 94.8,43.66 94.8,48.32 96.96,50.47 96.96,66.29 96.66,66.59 v5(96.63,66.59)
DDR_D19: length 52.1
  TOP w0.173: U1.AC28 95.43,69.11 96.27,68.28 96.27,66.76 v4(95.76,66.25) ; U7.G2 v2(99.22,33.48)
  L3_SIG1 w0.109: v4(95.76,66.25) 95.76,66.13 v5(95.46,65.83)
  L10_SIG4 w0.109: v2(99.22,33.48) 98.4,33.48 97.94,33.02 97.13,33.02 92.78,37.37 92.78,67.72 94.21,69.14 95.37,69.14 96.1,68.42 96.1,66.48 v5(95.46,65.83)
DDR_D20: length 52
  TOP w0.173: U1.AC27 95.04,71.22 95.04,68.71 95.49,68.25 95.49,67.63 v4(95.76,67.37) ; U7.F2 v2(99.22,34.28)
  L3_SIG1 w0.109: v4(95.76,67.37) 95.5,67.11 v5(95.5,66.96)
  L10_SIG4 w0.109: v2(99.22,34.28) 98.83,33.89 97,33.89 96.72,34.17 96.72,34.42 96.52,34.63 96.27,34.63 95.95,34.94 95.95,35.1 96.21,35.36 96.21,35.52 96.06,35.67 95.91,35.67 95.64,35.41 95.49,35.41 95.33,35.56 95.33,35.71 95.62,36 95.62,36.16 95.47,36.31 95.31,36.31 95.02,36.02 94.87,36.02 94.71,36.18 94.71,36.33 95,36.62 95,36.78 94.85,36.93 94.69,36.93 94.4,36.64 94.25,36.64 94.09,36.8 94.09,36.95 94.38,37.24 94.38,37.4 94.23,37.55 94.08,37.55 93.79,37.26 93.63,37.26 93.26,37.63 93.26,67.68 94.49,68.9 95.09,68.9 95.5,68.49 v5(95.5,66.96)
DDR_D21: length 51.8
  TOP w0.173: U1.Y19 v4(97.44,77.62) ; U7.F7 v2(102.42,34.28)
  L3_SIG1 w0.109: v4(97.44,77.62) v5(97.04,77.37)
  L10_SIG4 w0.109: v2(102.42,34.28) 102.82,34.68 102.82,39.04 101.8,40.06 100.61,40.06 99.53,41.14 99.53,45.03 99.42,45.14 98.94,45.14 98.83,45.25 98.83,45.47 98.94,45.57 99.42,45.57 99.53,45.68 99.53,45.9 99.42,46.01 98.92,46.01 98.81,46.12 98.81,46.34 98.92,46.45 99.42,46.45 99.53,46.56 99.53,46.78 99.42,46.89 98.92,46.89 98.81,46.99 98.81,47.21 98.92,47.32 99.42,47.32 99.53,47.43 99.53,66.08 96.65,68.97 96.65,76.98 v5(97.04,77.37)
DDR_D22: length 52
  TOP w0.173: U7.H7 v2(102.42,32.68) ; v4(96.98,68.05) 95.84,69.19 95.84,71.22 U1.AB27
  L3_SIG1 w0.109: v4(96.98,68.05) v5(96.64,67.71)
  L10_SIG4 w0.109: v2(102.42,32.68) 101.48,33.62 101.48,35.57 101.05,35.99 101.05,38 100.08,38.98 97.45,38.98 96.74,39.68 96.74,44.9 96.63,45.01 95.82,45.01 95.71,45.11 95.71,45.33 95.82,45.44 96.63,45.44 96.74,45.55 96.74,45.77 96.63,45.88 95.84,45.88 95.73,45.99 95.73,46.21 95.84,46.32 96.63,46.32 96.74,46.43 96.74,46.64 96.63,46.75 95.84,46.75 95.73,46.86 95.73,47.08 95.84,47.19 96.63,47.19 96.74,47.3 96.74,47.52 96.63,47.63 95.84,47.63 95.73,47.74 95.73,47.95 95.84,48.06 96.63,48.06 96.74,48.17 96.74,49.62 97.56,50.45 97.56,66.8 96.65,67.71 v5(96.64,67.71)
DDR_D23: length 51.8
  TOP w0.173: U7.F8 v2(103.22,34.28) ; U1.Y20 v4(97.44,76.82)
  L3_SIG1 w0.109: v4(97.44,76.82) v5(97.04,76.57)
  L10_SIG4 w0.109: v2(103.22,34.28) 103.63,34.69 103.63,39.07 102.17,40.53 100.8,40.53 100.38,40.95 100.38,44.75 100.84,45.21 100.84,47.29 100.73,47.4 100.57,47.4 100.46,47.51 100.46,47.73 100.57,47.84 100.73,47.84 100.84,47.95 100.84,48.17 100.73,48.28 100.44,48.28 100.33,48.39 100.33,48.61 100.44,48.71 100.73,48.71 100.84,48.82 100.84,49.04 100.73,49.15 100.44,49.15 100.33,49.26 100.33,49.48 100.44,49.59 100.73,49.59 100.84,49.7 100.84,49.92 100.73,50.03 100.44,50.03 100.33,50.13 100.33,50.35 100.44,50.46 100.73,50.46 100.84,50.57 100.84,50.79 100.73,50.9 100.44,50.9 100.33,51.01 100.33,51.23 100.44,51.34 100.73,51.34 100.84,51.45 100.84,61.88 100.32,62.39 100.32,65.93 97.18,69.07 97.18,72.7 97.43,72.96 97.43,74.91 97.54,75.01 97.54,75.47 97.43,75.57 97.43,76.17 v5(97.04,76.57)
DDR_D24: length 48.4
  TOP w0.173: U1.AA23 v4(96.64,74.42) ; U7.D7 v2(102.42,35.88)
  L3_SIG1 w0.099: 95.98,69.47 95.98,71.91 96.14,72.06 96.14,72.19 96.34,72.39 96.34,72.94 96.51,73.11 96.65,73.11 96.94,73.4 96.94,73.75 96.64,74.06 v4(96.64,74.42)
  L3_SIG1 w0.109: 95.98,69.47 97.59,67.87 97.59,64.68 96.55,63.63 96.55,57.82 97.12,57.24 97.12,43.54 97.6,43.07 97.6,42.9 97.15,42.46 97.15,42.27 97.26,42.16 97.41,42.16 97.88,42.62 98.04,42.62 98.16,42.51 98.16,42.34 97.72,41.91 97.72,41.74 97.84,41.63 98,41.63 98.44,42.06 98.6,42.06 98.72,41.95 98.72,41.78 98.37,41.44 98.37,41.26 98.49,41.15 98.64,41.15 99,41.5 99.16,41.5 100.74,39.93 100.74,36.73 101.59,35.88 v2(102.42,35.88)
DDR_D25: length 48.4
  TOP w0.173: U7.C3 v2(100.02,36.68) ; U1.Y22 v4(97.44,75.22)
  L3_SIG1 w0.099: v4(97.44,75.22) 96.95,74.73 96.54,74.73 96.14,74.33 96.14,73.41 95.83,73.11 95.71,73.11 95.48,72.87 95.48,72.84 95.2,72.57 95.2,72.27 95.44,72.02
  L3_SIG1 w0.109: 95.44,72.02 95.44,68.32 95.11,67.99 95.11,66.39 94.56,65.84 94.56,38.79 94.81,38.55 94.81,38.08 94.45,37.72 94.45,37.56 94.57,37.44 94.73,37.44 95.23,37.94 95.42,37.94 95.52,37.83 95.52,37.67 95.07,37.22 95.07,37.07 95.18,36.96 95.37,36.96 95.65,37.23 95.81,37.23 95.98,37.06 99.63,37.06 v2(100.02,36.68)
DDR_D26: length 48.4
  TOP w0.173: U1.Y23 v4(97.44,74.42) ; U7.B8 v2(103.22,37.48)
  L3_SIG1 w0.099: 97.44,74.03 97.14,73.74 97.14,73.22 96.93,73 96.93,71.84 96.63,71.54 96.63,69.79
  L3_SIG1 w0.109: v2(103.22,37.48) 103.63,37.89 103.63,39.4 103.52,39.51 103,39.51 102.88,39.63 102.88,39.79 103,39.91 103.64,39.91 103.77,40.04 103.77,40.2 103.66,40.31 103.02,40.31 102.91,40.42 102.91,40.58 103.03,40.7 103.6,40.7 103.71,40.82 103.71,40.98 103.6,41.1 103.02,41.1 102.91,41.21 102.91,41.37 103.03,41.5 103.52,41.5 103.64,41.61 103.64,45.1 103.52,45.22 102.99,45.22 102.87,45.34 102.87,45.5 102.99,45.62 103.52,45.62 103.64,45.73 103.64,46.12 102.7,47.06 102.54,47.06 102.44,46.97 102.28,46.97 102.16,47.08 102.16,47.25 102.26,47.34 102.26,47.51 102.14,47.62 101.98,47.62 101.88,47.53 101.72,47.53 101.6,47.64 101.6,47.81 101.69,47.9 101.69,48.07 101.58,48.18 101.41,48.18 101.32,48.09 101.16,48.09 101.04,48.2 101.04,48.37 101.13,48.46 101.13,48.63 100.53,49.23 100.53,54.31 100.18,54.67 100.18,66.65 98.65,68.18 98.24,68.18 96.63,69.79 ; 97.44,74.03 v4(97.44,74.42)
DDR_D27: length 48.4
  TOP w0.173: U7.A2 v2(99.22,38.28) ; U1.AA24 v4(96.64,73.62)
  L3_SIG1 w0.099: v4(96.64,73.62) 96.13,73.11 96.13,72.46 95.94,72.27 95.94,72.23 95.65,71.94
  L3_SIG1 w0.109: v2(99.22,38.28) 98.82,37.87 96.22,37.87 95,39.09 95,39.55 95.11,39.66 95.5,39.66 95.61,39.77 95.61,39.99 95.5,40.09 95.11,40.09 95,40.2 95,40.42 95.11,40.53 95.5,40.53 95.61,40.64 95.61,40.86 95.5,40.97 95.11,40.97 95,41.08 95,41.3 95.11,41.41 95.5,41.41 95.61,41.51 95.61,41.73 95.5,41.84 95.11,41.84 95,41.95 95,42.17 95.11,42.28 95.5,42.28 95.61,42.39 95.61,42.61 95.5,42.72 95.11,42.72 95,42.83 95,43.04 95.11,43.15 95.5,43.15 95.61,43.26 95.61,43.48 95.5,43.59 95.11,43.59 95,43.7 95,43.92 95.11,44.03 95.5,44.03 95.61,44.14 95.61,44.35 95.5,44.46 95.11,44.46 95,44.57 95,44.79 95.11,44.9 95.5,44.9 95.61,45.01 95.61,45.23 95.5,45.34 95.11,45.34 95,45.45 95,64.73 96.2,65.93 96.2,67.95 95.65,68.51 95.65,71.94
DDR_D28: length 48.4
  TOP w0.173: U7.C2 v2(99.22,36.68) ; U1.Y24 v4(97.44,73.62)
  L3_SIG1 w0.099: 96.84,69.97 96.84,71.37 97.14,71.68 97.14,72.94 97.44,73.23 v4(97.44,73.62)
  L3_SIG1 w0.109: 96.84,69.97 98.22,68.58 98.83,68.58 100.62,66.8 100.62,55.04 100.99,54.67 100.99,49.54 104.42,46.11 104.42,36.52 103.38,35.49 99.85,35.49 99.62,35.72 99.62,36.28 v2(99.22,36.68)
DDR_D29: length 48.3
  TOP w0.173: U1.AA26 96.64,72.02 v4(96.64,71.98) ; U7.A7 v2(102.42,38.28)
  L3_SIG1 w0.099: 96.64,71.97 96.42,71.76 96.42,69.69
  L3_SIG1 w0.109: 96.64,71.97 v4(96.64,71.98) ; v2(102.42,38.28) 102.44,38.3 102.44,41.97 102.56,42.09 102.95,42.09 103.05,42.19 103.05,42.36 102.92,42.49 102.56,42.49 102.44,42.6 102.44,42.77 102.56,42.88 103,42.88 103.11,43 103.11,43.16 102.99,43.28 102.53,43.28 102.42,43.39 102.42,43.56 102.53,43.67 102.94,43.67 103.06,43.79 103.06,43.95 102.94,44.07 102.53,44.07 102.42,44.19 102.42,44.51 102.3,44.63 101.33,44.63 101.22,44.74 101.22,44.91 101.33,45.02 102.3,45.02 102.42,45.14 102.42,46.14 102.16,46.4 101.99,46.4 100.88,45.29 100.72,45.29 100.6,45.4 100.6,45.57 101.71,46.68 101.71,46.85 101.39,47.17 101.23,47.17 100.69,46.62 100.52,46.62 100.4,46.74 100.4,46.9 100.95,47.45 100.95,47.61 100.83,47.73 100.67,47.73 100.57,47.63 100.4,47.63 100.29,47.74 100.29,47.91 100.39,48.01 100.39,48.17 100.08,48.49 100.08,54.06 99.73,54.4 99.73,66.66 98.47,67.92 98.19,67.92 96.42,69.69
DDR_D30: length 48.3
  TOP w0.173: U1.AA25 v4(96.64,72.82) ; U7.C8 v2(103.22,36.68)
  L3_SIG1 w0.099: 96.2,69.59 96.2,71.82 96.34,71.96 96.34,72.11 96.64,72.4 v4(96.64,72.82)
  L3_SIG1 w0.109: v2(103.22,36.68) 102.82,36.28 101.8,36.28 100.96,37.11 100.96,40.33 99.92,41.37 99.92,41.61 100.46,42.15 100.46,42.3 100.35,42.42 100.18,42.42 99.64,41.89 99.48,41.89 99.36,42.01 99.36,42.17 99.65,42.46 99.65,42.61 99.54,42.73 99.36,42.73 99.08,42.45 98.92,42.45 98.8,42.57 98.8,42.73 99.12,43.05 99.12,43.21 99,43.33 98.84,43.33 98.52,43.01 98.36,43.01 98.24,43.13 98.24,43.29 98.54,43.59 98.54,43.74 98.42,43.86 98.25,43.86 97.96,43.57 97.8,43.57 97.6,43.77 97.6,44.42 97.72,44.53 98.08,44.53 98.19,44.65 98.19,44.81 98.08,44.93 97.72,44.93 97.6,45.05 97.6,57.65 97,58.25 97,62.84 98.04,63.88 98.04,67.76 96.2,69.59
DDR_D31: length 48.6
  TOP w0.173: v4(97.1,64.97) 97.96,65.83 97.96,66.53 98.42,66.99 98.42,68.28 97.04,69.67 U1.AA28 ; U7.A3 v2(100.02,38.28)
  L3_SIG1 w0.109: v2(100.02,38.28) 100.02,38.9 99.78,39.14 99.61,39.14 99.49,39.02 99.32,39.02 99.21,39.13 99.21,39.3 99.33,39.42 99.33,39.59 99.22,39.7 99.05,39.7 98.4,39.05 98.23,39.05 98.12,39.16 98.12,39.33 99.25,40.46 99.25,40.6 99.1,40.75 98.92,40.75 97.25,39.08 97.08,39.08 96.97,39.2 96.97,39.36 98.18,40.58 98.18,40.74 98.07,40.86 97.9,40.86 96.94,39.9 96.77,39.9 96.65,40.01 96.65,54.28 96.54,54.39 96.2,54.39 96.09,54.5 96.09,54.72 96.2,54.83 96.54,54.83 96.65,54.94 96.65,55.16 96.54,55.26 96.2,55.26 96.09,55.37 96.09,55.59 96.2,55.7 96.54,55.7 96.65,55.81 96.65,56.03 96.54,56.14 96.17,56.14 96.06,56.25 96.06,56.47 96.17,56.57 96.54,56.57 96.65,56.68 96.65,57.05 96.09,57.61 96.09,63.96 v4(97.1,64.97)
DDR_DQM0: length 59.8
  TOP w0.173: U5.E7 v2(87.18,35.08) ; U1.AD23 v4(94.24,74.42)
  L3_SIG1 w0.099: v4(94.24,74.42) v5(93.84,74.17)
  L10_SIG4 w0.109: v2(87.18,35.08) 87.59,35.48 88.13,35.48 88.39,35.74 88.39,40.44 91.71,43.76 91.71,45.7 91.6,45.81 91.05,45.81 90.93,45.94 90.93,46.1 91.04,46.21 91.6,46.21 91.71,46.33 91.71,46.49 91.6,46.61 91.02,46.61 90.91,46.72 90.91,46.88 91.03,47 91.6,47 91.71,47.12 91.71,47.28 91.6,47.4 91.05,47.4 90.94,47.51 90.94,47.67 91.06,47.8 91.6,47.8 91.71,47.91 91.71,48.08 91.6,48.19 90.88,48.19 90.78,48.3 90.78,48.46 90.9,48.59 91.6,48.59 91.71,48.7 91.71,48.87 91.6,48.98 90.86,48.98 90.74,49.1 90.74,49.26 90.86,49.38 91.6,49.38 91.71,49.5 91.71,49.66 91.6,49.78 90.86,49.78 90.74,49.89 90.74,50.06 90.86,50.17 91.6,50.17 91.71,50.29 91.71,50.45 91.6,50.57 90.86,50.57 90.74,50.69 90.74,50.85 90.86,50.97 91.6,50.97 91.71,51.08 91.71,51.25 91.6,51.36 90.86,51.36 90.74,51.48 90.74,51.64 90.86,51.76 91.6,51.76 91.71,51.87 91.71,52.04 91.6,52.15 90.86,52.15 90.74,52.27 90.74,52.43 90.86,52.55 91.6,52.55 91.71,52.67 91.71,52.83 91.6,52.95 90.9,52.95 90.79,53.06 90.79,53.22 90.92,53.34 91.6,53.34 91.71,53.46 91.71,67.01 94.2,69.5 94.2,71.42 94.54,71.75 94.54,73.46 v5(93.84,74.17)
DDR_DQM1: length 52.6
  TOP w0.173: U5.D3 v2(84.78,35.88) ; U1.AB23 v4(95.84,74.42)
  L3_SIG1 w0.099: 90.47,73.79 92.39,73.79 92.51,73.91 92.76,73.91 92.88,73.79 93.19,73.79 93.31,73.91 93.56,73.91 93.68,73.79 93.99,73.79 94.18,73.97 94.31,73.97 94.74,74.41 94.74,74.54 94.91,74.71 95.16,74.71 95.45,74.42 v4(95.84,74.42)
  L3_SIG1 w0.109: v2(84.78,35.88) 84.39,35.49 81.95,35.49 81.28,36.16 81.28,48.95 84.74,52.41 84.74,68.06 90.47,73.79
DDR_DQM2: length 51.9
  TOP w0.173: U7.E7 v2(102.42,35.08) ; U1.AC26 v4(95.04,72.02)
  L3_SIG1 w0.109: v4(95.04,72.02) 95.03,72.02 v5(95.03,71.45)
  L10_SIG4 w0.109: v2(102.42,35.08) 101.88,35.61 101.88,38.75 101.28,39.35 97.99,39.35 97.55,39.79 97.55,40.34 97.66,40.45 98.42,40.45 98.53,40.56 98.53,40.75 98.39,40.89 97.66,40.89 97.55,41 97.55,41.21 97.66,41.32 98.32,41.32 98.42,41.43 98.42,41.65 98.32,41.76 97.66,41.76 97.55,41.87 97.55,42.09 97.66,42.2 98.32,42.2 98.42,42.31 98.42,42.52 98.32,42.63 97.66,42.63 97.55,42.74 97.55,42.96 97.66,43.07 98.32,43.07 98.42,43.18 98.42,43.4 98.32,43.51 97.66,43.51 97.55,43.62 97.55,43.84 97.66,43.94 98.32,43.94 98.42,44.05 98.42,44.27 98.32,44.38 97.66,44.38 97.55,44.49 97.55,49.66 98.98,51.09 98.98,65.99 95.81,69.16 95.81,70.13 95.03,70.91 v5(95.03,71.45)
DDR_DQM3: length 48.7
  TOP w0.173: U1.AA27 96.64,71.22 96.64,69.51 97.82,68.33 97.82,67.09 97.05,66.32 v4(97.05,65.95) ; U7.D3 v2(100.02,35.88)
  L3_SIG1 w0.109: v2(100.02,35.88) 100.46,36.31 100.46,37.6 100.18,37.88 99.86,37.88 99.62,38.12 99.62,38.44 99.39,38.66 96.67,38.66 96.09,39.25 96.09,47.49 95.98,47.6 95.64,47.6 95.53,47.71 95.53,47.92 95.64,48.03 95.98,48.03 96.09,48.14 96.09,48.36 95.98,48.47 95.56,48.47 95.45,48.58 95.45,48.8 95.56,48.91 95.98,48.91 96.09,49.02 96.09,49.23 95.98,49.34 95.56,49.34 95.45,49.45 95.45,49.67 95.56,49.78 95.98,49.78 96.09,49.89 96.09,50.11 95.98,50.22 95.56,50.22 95.45,50.33 95.45,50.54 95.56,50.65 95.98,50.65 96.09,50.76 96.09,50.98 95.98,51.09 95.56,51.09 95.45,51.2 95.45,51.42 95.56,51.53 95.98,51.53 96.09,51.64 96.09,51.86 95.98,51.96 95.59,51.96 95.48,52.07 95.48,52.29 95.59,52.4 95.98,52.4 96.09,52.51 96.09,52.73 95.98,52.84 95.59,52.84 95.48,52.95 95.48,53.17 95.59,53.28 95.98,53.28 96.09,53.38 96.09,53.83 95.55,54.36 95.55,64.46 v4(97.05,65.95)
DDR_DQS0: length 59.6
  TOP w0.108: U5.F3 v2(84.78,34.28) ; U1.AH25 v4(91.04,72.82)
  L3_SIG1 w0.083: v4(91.04,72.82) v5(90.64,72.57)
  L10_SIG4 w0.083: v5(90.64,72.57) 88.79,72.57 85.37,69.14 85.37,68.13 85.29,68.04 84.92,68.04 84.84,67.96 84.84,67.8 84.92,67.71 85.29,67.71 85.37,67.63 85.37,66.37 85.09,66.09 84.63,66.09 84.24,65.71 84.24,64.05 84.5,63.79 85.34,63.79 85.42,63.71 85.42,63.54 85.34,63.46 84.5,63.46 84.24,63.2 84.24,62.78 84.5,62.52 85.34,62.52 85.42,62.44 85.42,62.27 85.34,62.19 84.5,62.19 84.24,61.93 84.24,61.51 84.5,61.25 85.34,61.25 85.42,61.17 85.42,61 85.34,60.92 84.5,60.92 84.24,60.66 84.24,60.24 84.5,59.98 85.34,59.98 85.42,59.9 85.42,59.73 85.34,59.65 84.5,59.65 84.24,59.39 84.24,58.97 84.5,58.71 85.34,58.71 85.42,58.63 85.42,58.46 85.34,58.38 84.5,58.38 84.24,58.12 84.24,57.7 84.5,57.44 85.34,57.44 85.42,57.36 85.42,57.19 85.34,57.11 84.5,57.11 84.24,56.85 84.24,56.43 84.5,56.17 85.34,56.17 85.42,56.09 85.42,55.92 85.34,55.84 84.68,55.84 84.24,55.41 84.24,54.03 84.73,53.55 84.73,41.95 85.32,41.36 85.32,34.16 85.14,33.98 85.03,33.98 84.78,34.24 v2(84.78,34.28)
DDR_DQS1: length 53.1
  TOP w0.108: U1.AE27 93.46,71.24 93.46,70.41 93.4,70.34 93.4,68.05 93.33,67.99 v4(93.33,67.82) ; U5.C7 v2(87.18,36.68)
  L3_SIG1 w0.083: v4(93.33,67.82) 93.33,67.82 92.32,66.81 92.32,66.2 91.34,65.23 91.34,50.38 91.26,50.3 89.72,50.3 89.46,50.04 89.46,49.62 89.72,49.36 91.26,49.36 91.34,49.28 91.34,49.11 91.26,49.03 89.72,49.03 89.46,48.77 89.46,48.35 89.72,48.09 91.26,48.09 91.34,48.01 91.34,47.84 91.26,47.76 89.72,47.76 89.46,47.5 89.46,47.08 89.72,46.82 91.26,46.82 91.34,46.74 91.34,46.57 91.26,46.49 89.72,46.49 89.46,46.23 89.46,45.81 89.72,45.55 91.26,45.55 91.34,45.47 91.34,44.54 85.95,39.14 85.95,37.41 86.43,36.92 86.93,36.92 v2(87.18,36.68)
DDR_DQS2: length 52.1
  TOP w0.108: U1.AD27 94.27,71.25 94.27,70.43 94.17,70.32 94.17,68.63 94.57,68.22 94.57,67.6 v4(94.58,67.59) ; U7.F3 v2(100.02,34.28)
  L3_SIG1 w0.083: v5(94.67,68.1) 94.58,68.02 v4(94.58,67.59)
  L10_SIG4 w0.083: v5(94.67,68.1) 94.67,67.57 94.26,67.16 94.26,67.06 93.89,66.69 93.89,55.61 94.15,55.35 95.12,55.35 95.2,55.27 95.2,55.1 95.12,55.02 94.15,55.02 93.89,54.76 93.89,54.34 94.15,54.08 95.12,54.08 95.2,54 95.2,53.83 95.12,53.75 94.15,53.75 93.89,53.49 93.89,53.07 94.15,52.81 95.12,52.81 95.2,52.73 95.2,52.56 95.12,52.48 94.15,52.48 93.89,52.22 93.89,51.8 94.15,51.54 95.12,51.54 95.2,51.46 95.2,51.29 95.12,51.21 94.15,51.21 93.89,50.95 93.89,38.77 97,35.65 97.61,35.65 98.55,34.71 99.59,34.71 v2(100.02,34.28)
DDR_DQS3: length 48.7
  TOP w0.108: U7.C7 v2(102.42,36.68) ; v4(98.78,66.1) 99.08,66.39 99.08,66.78 99.06,66.79 99.06,67.33 99.17,67.44 99.33,67.44 99.44,67.55 99.44,67.76 99.33,67.87 99.19,67.87 99.08,67.98 99.08,68.51 97.83,69.75 U1.Y28
  L3_SIG1 w0.083: v2(102.42,36.68) 102.17,36.92 101.93,36.92 101.54,37.32 101.54,42.95 100.99,43.49 100.87,43.49 100.52,43.14 100.15,43.14 99.85,43.43 99.85,43.8 100.21,44.16 100.21,44.27 100.09,44.39 99.97,44.39 99.54,43.96 99.17,43.96 98.88,44.26 98.88,44.63 99.31,45.06 99.31,45.17 99.02,45.47 99.02,46.63 98.93,46.71 98.48,46.71 98.22,46.97 98.22,47.39 98.48,47.65 98.93,47.65 99.02,47.73 99.02,47.9 98.93,47.98 98.48,47.98 98.22,48.24 98.22,48.66 98.48,48.92 98.93,48.92 99.02,49 99.02,49.17 98.93,49.25 98.48,49.25 98.22,49.51 98.22,49.93 98.48,50.19 98.93,50.19 99.02,50.27 99.02,50.44 98.93,50.52 98.48,50.52 98.22,50.78 98.22,51.2 98.48,51.46 98.93,51.46 99.02,51.54 99.02,53.68 98.43,54.26 98.43,57.68 97.61,58.5 97.61,59.56 97.87,59.82 98.42,59.82 98.5,59.91 98.5,60.07 98.42,60.15 97.89,60.15 97.63,60.41 97.63,60.83 97.89,61.09 98.42,61.09 98.5,61.18 98.5,61.34 98.42,61.42 97.87,61.42 97.61,61.68 97.61,62.53 98.78,63.71 v4(98.78,66.1)
DDR_DQSN0: length 59.7
  TOP w0.108: U5.G3 v2(84.78,33.48) ; U1.AG25 v4(91.84,72.82)
  L3_SIG1 w0.083: v4(91.84,72.82) v5(91.44,72.57)
  L10_SIG4 w0.083: v2(84.78,33.48) 85.06,33.48 85.62,34.04 85.62,41.49 85.03,42.08 85.03,53.68 84.55,54.16 84.55,55.28 84.8,55.53 85.46,55.53 85.72,55.8 85.72,56.21 85.46,56.47 84.63,56.47 84.55,56.56 84.55,56.72 84.63,56.8 85.46,56.8 85.72,57.07 85.72,57.48 85.46,57.74 84.63,57.74 84.55,57.83 84.55,57.99 84.63,58.07 85.46,58.07 85.72,58.34 85.72,58.75 85.46,59.01 84.63,59.01 84.55,59.1 84.55,59.26 84.63,59.34 85.46,59.34 85.72,59.61 85.72,60.02 85.46,60.28 84.63,60.28 84.55,60.37 84.55,60.53 84.63,60.61 85.46,60.61 85.72,60.88 85.72,61.29 85.46,61.55 84.63,61.55 84.55,61.64 84.55,61.8 84.63,61.88 85.46,61.88 85.72,62.15 85.72,62.56 85.46,62.82 84.63,62.82 84.55,62.91 84.55,63.07 84.63,63.15 85.46,63.15 85.72,63.42 85.72,63.83 85.46,64.09 84.63,64.09 84.55,64.18 84.55,65.58 84.75,65.79 85.21,65.79 85.67,66.25 85.67,69.02 88.92,72.26 90.4,72.26 90.47,72.19 91.06,72.19 v5(91.44,72.57)
DDR_DQSN1: length 52.9
  TOP w0.108: U5.B7 v2(87.18,37.48) ; U1.AE28 93.83,70.42 93.65,70.24 93.65,67.67 93.33,67.35 v4(93.33,66.88)
  L3_SIG1 w0.083: v2(87.18,37.48) 86.93,37.23 86.55,37.23 86.25,37.53 86.25,39.01 91.65,44.41 91.65,45.59 91.39,45.86 89.85,45.86 89.76,45.94 89.76,46.1 89.85,46.19 91.39,46.19 91.65,46.45 91.65,46.86 91.39,47.13 89.85,47.13 89.76,47.21 89.76,47.37 89.85,47.46 91.39,47.46 91.65,47.72 91.65,48.13 91.39,48.4 89.85,48.4 89.76,48.48 89.76,48.64 89.85,48.73 91.39,48.73 91.65,48.99 91.65,49.4 91.39,49.67 89.85,49.67 89.76,49.75 89.76,49.91 89.85,50 91.39,50 91.65,50.26 91.65,65.1 92.01,65.46 92.12,65.46 92.28,65.3 92.4,65.3 92.52,65.42 92.52,65.54 92.36,65.69 92.36,65.81 92.62,66.08 92.62,66.69 93.13,67.2 93.25,67.2 93.33,67.12 v4(93.33,66.88)
DDR_DQSN2: length 52.1
  TOP w0.108: U1.AD28 94.64,70.43 94.42,70.22 94.42,68.75 94.89,68.28 94.89,67.44 94.63,67.18 v4(94.63,66.51) ; U7.G3 v2(100.02,33.48)
  L3_SIG1 w0.083: v4(94.63,66.51) v5(94.63,67)
  L10_SIG4 w0.083: v5(94.63,67) 94.19,66.56 94.19,55.74 94.27,55.65 95.24,55.65 95.5,55.39 95.5,54.97 95.24,54.71 94.27,54.71 94.19,54.63 94.19,54.47 94.27,54.38 95.24,54.38 95.5,54.12 95.5,53.7 95.24,53.44 94.27,53.44 94.19,53.36 94.19,53.2 94.27,53.11 95.24,53.11 95.5,52.85 95.5,52.43 95.24,52.17 94.27,52.17 94.19,52.09 94.19,51.93 94.27,51.84 95.24,51.84 95.5,51.58 95.5,51.16 95.24,50.9 94.27,50.9 94.19,50.82 94.19,38.89 97.12,35.96 97.73,35.96 98.24,35.45 99.37,35.45 100.39,34.43 100.39,33.85 v2(100.02,33.48)
DDR_DQSN3: length 48.8
  TOP w0.108: U7.B7 v2(102.42,37.48) ; v4(98.78,66.65) 98.8,66.67 98.8,68.41 97.45,69.76 97.45,71.23 97.83,71.62 U1.Y27
  L3_SIG1 w0.083: v4(98.78,66.65) 99.11,66.32 99.11,65.97 99.08,65.95 99.08,63.58 97.91,62.41 97.91,61.81 97.99,61.73 98.55,61.73 98.81,61.47 98.81,61.05 98.55,60.79 98.02,60.79 97.94,60.71 97.94,60.54 98.02,60.46 98.55,60.46 98.81,60.2 98.81,59.78 98.55,59.52 97.99,59.52 97.91,59.44 97.91,58.63 98.73,57.81 98.73,54.39 99.32,53.8 99.32,51.42 99.06,51.16 98.61,51.16 98.53,51.07 98.53,50.91 98.61,50.83 99.06,50.83 99.32,50.57 99.32,50.15 99.06,49.89 98.61,49.89 98.53,49.8 98.53,49.64 98.61,49.56 99.06,49.56 99.32,49.3 99.32,48.88 99.06,48.62 98.61,48.62 98.53,48.53 98.53,48.37 98.61,48.29 99.06,48.29 99.32,48.03 99.32,47.61 99.06,47.35 98.61,47.35 98.53,47.26 98.53,47.1 98.61,47.02 99.06,47.02 99.32,46.76 99.32,45.59 99.61,45.3 99.61,44.93 99.18,44.5 99.18,44.38 99.3,44.27 99.42,44.27 99.85,44.7 100.22,44.7 100.51,44.4 100.51,44.03 100.16,43.68 100.16,43.56 100.28,43.44 100.39,43.44 100.75,43.8 101.12,43.8 101.84,43.07 101.84,37.44 102.05,37.23 102.17,37.23 v2(102.42,37.48)
DDR_ODT: length 143.9
  TOP w0.173: R75.2 109.98,27.56 111.05,28.63 111.05,29.04 v2(112.69,30.68) U6.K1 ; U7.K1 v2(97.45,30.68) ; U1.AE20 v4(93.44,76.82) ; U5.K1 v2(82.21,30.68)
  L3_SIG1 w0.099: v4(93.44,76.82) 93.05,76.82 92.16,77.7 91.93,77.7
  L3_SIG1 w0.109: v5(73.28,38.21) 72.06,39.43 72.06,53.14 73.36,54.44 73.36,55.26 73.46,55.37 73.7,55.37 73.81,55.48 73.81,55.69 73.7,55.8 73.46,55.8 73.36,55.91 73.36,56.13 73.46,56.24 73.96,56.24 74.07,56.35 74.07,56.57 73.96,56.68 73.46,56.68 73.36,56.79 73.36,57.01 73.46,57.11 73.96,57.11 74.07,57.22 74.07,57.44 73.96,57.55 73.46,57.55 73.36,57.66 73.36,57.88 73.46,57.99 73.96,57.99 74.07,58.1 74.07,58.32 73.96,58.43 73.46,58.43 73.36,58.53 73.36,58.75 73.46,58.86 73.96,58.86 74.07,58.97 74.07,59.19 73.96,59.3 73.46,59.3 73.36,59.41 73.36,59.63 73.46,59.74 73.96,59.74 74.07,59.84 74.07,60.06 73.96,60.17 73.46,60.17 73.36,60.28 73.36,60.5 73.46,60.61 73.96,60.61 74.07,60.72 74.07,60.94 73.96,61.05 73.46,61.05 73.36,61.16 73.36,61.37 73.46,61.48 73.96,61.48 74.07,61.59 74.07,61.81 73.96,61.92 73.46,61.92 73.36,62.03 73.36,62.25 73.46,62.36 73.96,62.36 74.07,62.47 74.07,62.68 73.96,62.79 73.46,62.79 73.36,62.9 73.36,63.12 73.46,63.23 73.96,63.23 74.07,63.34 74.07,63.56 73.96,63.67 73.46,63.67 73.36,63.78 73.36,64 73.46,64.1 73.96,64.1 74.07,64.21 74.07,64.43 73.96,64.54 73.46,64.54 73.36,64.65 73.36,65.3 78.19,70.14 78.39,70.14 79.02,69.52 79.22,69.52 79.36,69.66 79.36,69.86 78.73,70.48 78.73,70.68 78.87,70.82 79.07,70.82 79.7,70.2 79.9,70.2 80.04,70.34 80.04,70.53 79.41,71.16 79.41,71.36 79.55,71.5 79.75,71.5 80.38,70.87 80.58,70.87 80.72,71.01 80.72,71.21 80.09,71.84 80.09,72.04 80.23,72.18 80.43,72.18 81.06,71.55 81.26,71.55 81.4,71.69 81.4,71.89 80.77,72.52 80.77,72.72 80.91,72.86 81.11,72.86 81.74,72.23 81.94,72.23 82.08,72.37 82.08,72.57 81.45,73.2 81.45,73.4 81.59,73.54 81.79,73.54 82.42,72.91 82.62,72.91 82.76,73.05 82.76,73.25 82.13,73.88 82.13,74.08 82.27,74.22 82.47,74.22 83.1,73.59 83.29,73.59 83.44,73.73 83.44,73.93 82.81,74.56 82.81,74.76 82.95,74.9 83.15,74.9 83.78,74.27 83.97,74.27 84.11,74.41 84.11,74.61 83.49,75.24 83.49,75.44 83.63,75.58 83.83,75.58 84.45,74.95 84.65,74.95 84.79,75.09 84.79,75.29 84.17,75.92 84.17,76.11 84.38,76.33 86.41,76.33 87.02,76.94 88.39,76.94 89.15,77.7 91.93,77.7
  L10_SIG4 w0.109: v2(82.21,30.68) 82.82,30.68 84.05,31.91 85.37,31.91 85.49,32.03 87.6,32.03 87.9,31.73 88.34,31.73 88.68,31.39 91.21,31.39 92.03,32.21 96.65,32.21 96.98,31.88 96.98,31.15 v2(97.45,30.68) 99.06,32.29 101.61,32.29 101.77,32.13 103.18,32.13 103.83,31.49 106.54,31.49 107.27,32.22 111.16,32.22 v2(112.69,30.68) ; v9(73.28,29.59) v5(73.28,38.21)
  BOTTOM w0.102: 80.16,30.2 80.59,30.63 82.17,30.63 v2(82.21,30.68)
  BOTTOM w0.173: 80.16,30.2 79.98,30.02 73.71,30.02 v9(73.28,29.59)
DDR_RASN: length 146.9
  TOP w0.173: U7.J3 100.26,31.48 v2(100.28,31.5) ; U6.J3 v2(115.51,31.48) ; U5.J3 v2(84.91,31.48) ; U1.AF20 v4(92.64,76.82)
  L3_SIG1 w0.109: v4(92.64,76.82) 91.98,77.47 89.36,77.47 88.47,76.59 87.3,76.59 87.04,76.33 87.04,75.99 87.48,75.55 87.48,75.36 87.34,75.21 87.14,75.21 86.54,75.82 86.34,75.82 86.2,75.68 86.2,75.48 86.77,74.9 86.77,74.7 86.63,74.56 86.43,74.56 85.86,75.14 85.66,75.14 85.52,75 85.52,74.8 86.09,74.22 86.09,74.02 85.95,73.88 85.75,73.88 85.18,74.46 84.98,74.46 84.84,74.32 84.84,74.12 85.41,73.54 85.41,73.34 85.27,73.2 85.08,73.2 84.5,73.78 84.3,73.78 84.16,73.64 84.16,73.44 84.74,72.86 84.74,72.66 84.59,72.52 84.4,72.52 83.82,73.1 83.62,73.1 83.48,72.96 83.48,72.76 84.06,72.18 84.06,71.99 83.92,71.84 83.72,71.84 83.14,72.42 82.94,72.42 82.8,72.28 82.8,72.08 83.38,71.5 83.38,71.31 83.24,71.16 83.04,71.16 82.46,71.74 82.26,71.74 82.12,71.6 82.12,71.4 82.7,70.83 82.7,70.63 82.56,70.49 82.36,70.49 81.78,71.06 81.58,71.06 81.44,70.92 81.44,70.72 82.02,70.15 82.02,69.97 81.88,69.83 81.65,69.83 81.1,70.38 80.9,70.38 80.76,70.24 80.76,70.04 81.34,69.47 81.34,69.27 81.2,69.13 81,69.13 80.42,69.7 80.22,69.7 79.54,69.02 77.94,69.02 74.52,65.61 74.52,54.87 72.57,52.91 72.57,52.32 72.68,52.21 73.04,52.21 73.15,52.1 73.15,51.88 73.04,51.77 72.68,51.77 72.57,51.66 72.57,51.45 72.68,51.34 73.04,51.34 73.15,51.23 73.15,51.01 73.04,50.9 72.68,50.9 72.57,50.79 72.57,50.57 72.68,50.46 73.04,50.46 73.15,50.35 73.15,50.13 73.04,50.03 72.68,50.03 72.57,49.92 72.57,49.7 72.68,49.59 73.04,49.59 73.15,49.48 73.15,49.26 73.04,49.15 72.68,49.15 72.57,49.04 72.57,48.82 72.68,48.71 73.04,48.71 73.15,48.61 73.15,48.39 73.04,48.28 72.68,48.28 72.57,48.17 72.57,40.9 v5(73.71,39.76) ; v2(84.91,31.48) 85.45,31.48 86.21,30.71 86.38,30.71 86.72,30.38 87.83,30.38 88.29,30.84 89.18,30.84 89.41,31.07 90.3,31.07 90.43,30.94 90.43,30.74 90.55,30.62 90.72,30.62 90.84,30.74 90.84,30.94 90.95,31.06 92.58,31.06 92.96,30.68 93.64,30.68 94.1,31.14 97.77,31.14 98.22,30.69 99.47,30.69 v2(100.28,31.5) 100.63,31.15 100.99,31.15 101.5,30.64 101.7,30.64 101.96,30.38 103.1,30.38 103.53,30.82 104.39,30.82 104.65,31.07 105.33,31.07 105.66,30.74 106.07,30.74 106.39,31.06 107.82,31.06 108.2,30.68 109,30.68 109.45,31.14 112.94,31.14 113.39,30.69 114.72,30.69 v2(115.51,31.48)
  L10_SIG4 w0.109: v5(73.71,39.76) 73.76,39.71 v9(73.76,35.79)
  BOTTOM w0.102: 80.71,32.51 81.06,32.16 82.63,32.16 82.75,32.28 83.31,32.28 83.85,31.75 84.64,31.75 v2(84.91,31.48)
  BOTTOM w0.173: 80.71,32.51 79.76,33.45 76.1,33.45 75.93,33.62 75.93,33.87 78.01,35.95 78.01,36.19 77.77,36.44 77.52,36.44 75.44,34.36 75.2,34.36 74.95,34.6 74.95,34.85 77.03,36.93 77.03,37.17 76.79,37.41 76.54,37.41 74.46,35.34 74.22,35.34 v9(73.76,35.79) ; R51.2 109.6,30.73 112.15,30.73 112.9,31.49 113.9,31.49 114.15,31.24 115.28,31.24 v2(115.51,31.48)
DDR_RESETN: length 116.6
  TOP w0.173: v7(76.83,24.51) 76.83,43.18 78.39,44.74 78.39,67.43 86.66,75.7 87.89,75.7 88.21,76.02 91.83,76.02 U1.AG21 ; U7.T2 v2(98.82,24.64) ; U5.T2 v2(83.58,24.64) ; U6.T2 v2(114.06,24.64) ; R912.2 v7(122.68,25.02)
  L3_SIG1 w0.109: v2(83.58,24.64) 83.45,24.51 v7(76.83,24.51) ; v2(114.06,24.64) 115.71,26.29 116.46,26.29 117.73,25.02 v7(122.68,25.02)
  L10_SIG4 w0.109: v2(83.58,24.64) 85.81,22.4 96.59,22.4 v2(98.82,24.64) 98.82,24.6 101.02,22.4 111.83,22.4 v2(114.06,24.64)
DDR_WEN: length 150.8
  TOP w0.173: U5.L3 v2(84.91,29.88) ; U7.L3 v2(100.15,29.88) ; U6.L3 v2(115.39,29.88) ; U1.AH21 86.24,76.42 77.69,67.86 77.69,66.92 77.52,66.75 76.6,66.75 76.43,66.57 76.43,66.23 76.6,66.06 77.52,66.06 77.69,65.88 77.69,65.54 77.52,65.37 76.6,65.37 76.43,65.19 76.43,64.85 76.6,64.67 77.52,64.67 77.69,64.5 77.69,64.16 77.52,63.98 76.6,63.98 76.43,63.81 76.43,63.47 76.6,63.29 77.52,63.29 77.69,63.12 77.69,62.77 77.52,62.6 76.6,62.6 76.43,62.43 76.43,62.08 76.6,61.91 77.52,61.91 77.69,61.74 77.69,61.39 77.52,61.22 76.6,61.22 76.43,61.05 76.43,60.7 76.6,60.53 77.52,60.53 77.69,60.36 77.69,60.01 77.52,59.84 76.6,59.84 76.43,59.67 76.43,59.32 76.6,59.15 77.52,59.15 77.69,58.97 77.69,58.63 77.52,58.46 76.6,58.46 76.43,58.28 76.43,57.94 76.6,57.77 77.52,57.77 77.69,57.59 77.69,57.25 77.52,57.07 76.6,57.07 76.43,56.9 76.43,56.56 76.6,56.38 77.52,56.38 77.69,56.21 77.69,55.87 77.52,55.69 76.6,55.69 76.43,55.52 76.43,55.17 76.6,55 77.52,55 77.69,54.83 77.69,54.48 77.52,54.31 76.6,54.31 76.43,54.14 76.43,53.79 76.6,53.62 77.52,53.62 77.69,53.45 77.69,53.1 77.52,52.93 76.6,52.93 76.43,52.76 76.43,52.41 76.6,52.24 77.52,52.24 77.69,52.07 77.69,51.05 v7(76.96,50.32)
  L3_SIG1 w0.109: v2(115.39,29.88) 114.63,29.88 114.63,29.88 114.23,29.88 114,29.65 113.36,29.65 113.13,29.88 112.39,29.88 112.05,29.54 107.97,29.54 107.65,29.86 107.22,29.86 107.1,29.74 107.1,29.22 106.99,29.11 106.83,29.11 106.7,29.24 106.7,29.74 106.58,29.86 102.12,29.86 101.72,29.46 101.43,29.46 101.01,29.88 v2(100.15,29.88) 99.39,29.88 99.39,29.88 99.01,29.88 98.78,29.65 98.02,29.65 97.78,29.88 96.98,29.88 96.64,29.54 92.66,29.54 92.34,29.86 91.98,29.86 91.86,29.74 91.86,29.35 91.75,29.24 91.58,29.24 91.46,29.37 91.46,29.74 91.34,29.86 91,29.86 90.89,29.74 90.89,29.61 90.77,29.49 90.6,29.49 90.48,29.61 90.48,29.74 90.36,29.86 86.88,29.86 86.49,29.47 86.18,29.47 85.77,29.88 v2(84.91,29.88) ; v7(76.96,50.32) 76.96,38.31 77.09,38.18 v5(77.22,38.18)
  L10_SIG4 w0.109: v9(78.79,31.09) 79.13,31.09 79.39,30.84 79.39,30.27 79.02,29.9 79.02,29.29 79.49,28.82 79.49,27.12 79.24,26.87 78.87,26.87 78.69,27.06 78.69,28.63 77.24,30.07 77.24,32.16 77.38,32.3 79.06,32.3 79.2,32.44 79.2,32.64 79.07,32.78 77.36,32.78 77.22,32.92 77.22,33.12 77.36,33.26 78.82,33.26 78.96,33.4 78.96,33.6 78.82,33.74 77.36,33.74 77.22,33.88 77.22,34.08 77.36,34.22 78.4,34.22 78.54,34.36 78.54,34.56 78.4,34.7 77.36,34.7 77.22,34.84 77.22,35.1 77.36,35.24 78.09,35.24 78.23,35.38 78.23,35.58 78.09,35.72 77.33,35.72 77.22,35.83 v5(77.22,38.18)
  BOTTOM w0.102: v2(84.91,29.88) 84.32,29.88 83.39,30.81 82.93,30.81 82.65,31.09 79.76,31.09
  BOTTOM w0.173: R53.2 117.22,23.49 114.91,25.81 114.91,29.4 v2(115.39,29.88) ; 79.76,31.09 v9(78.79,31.09)
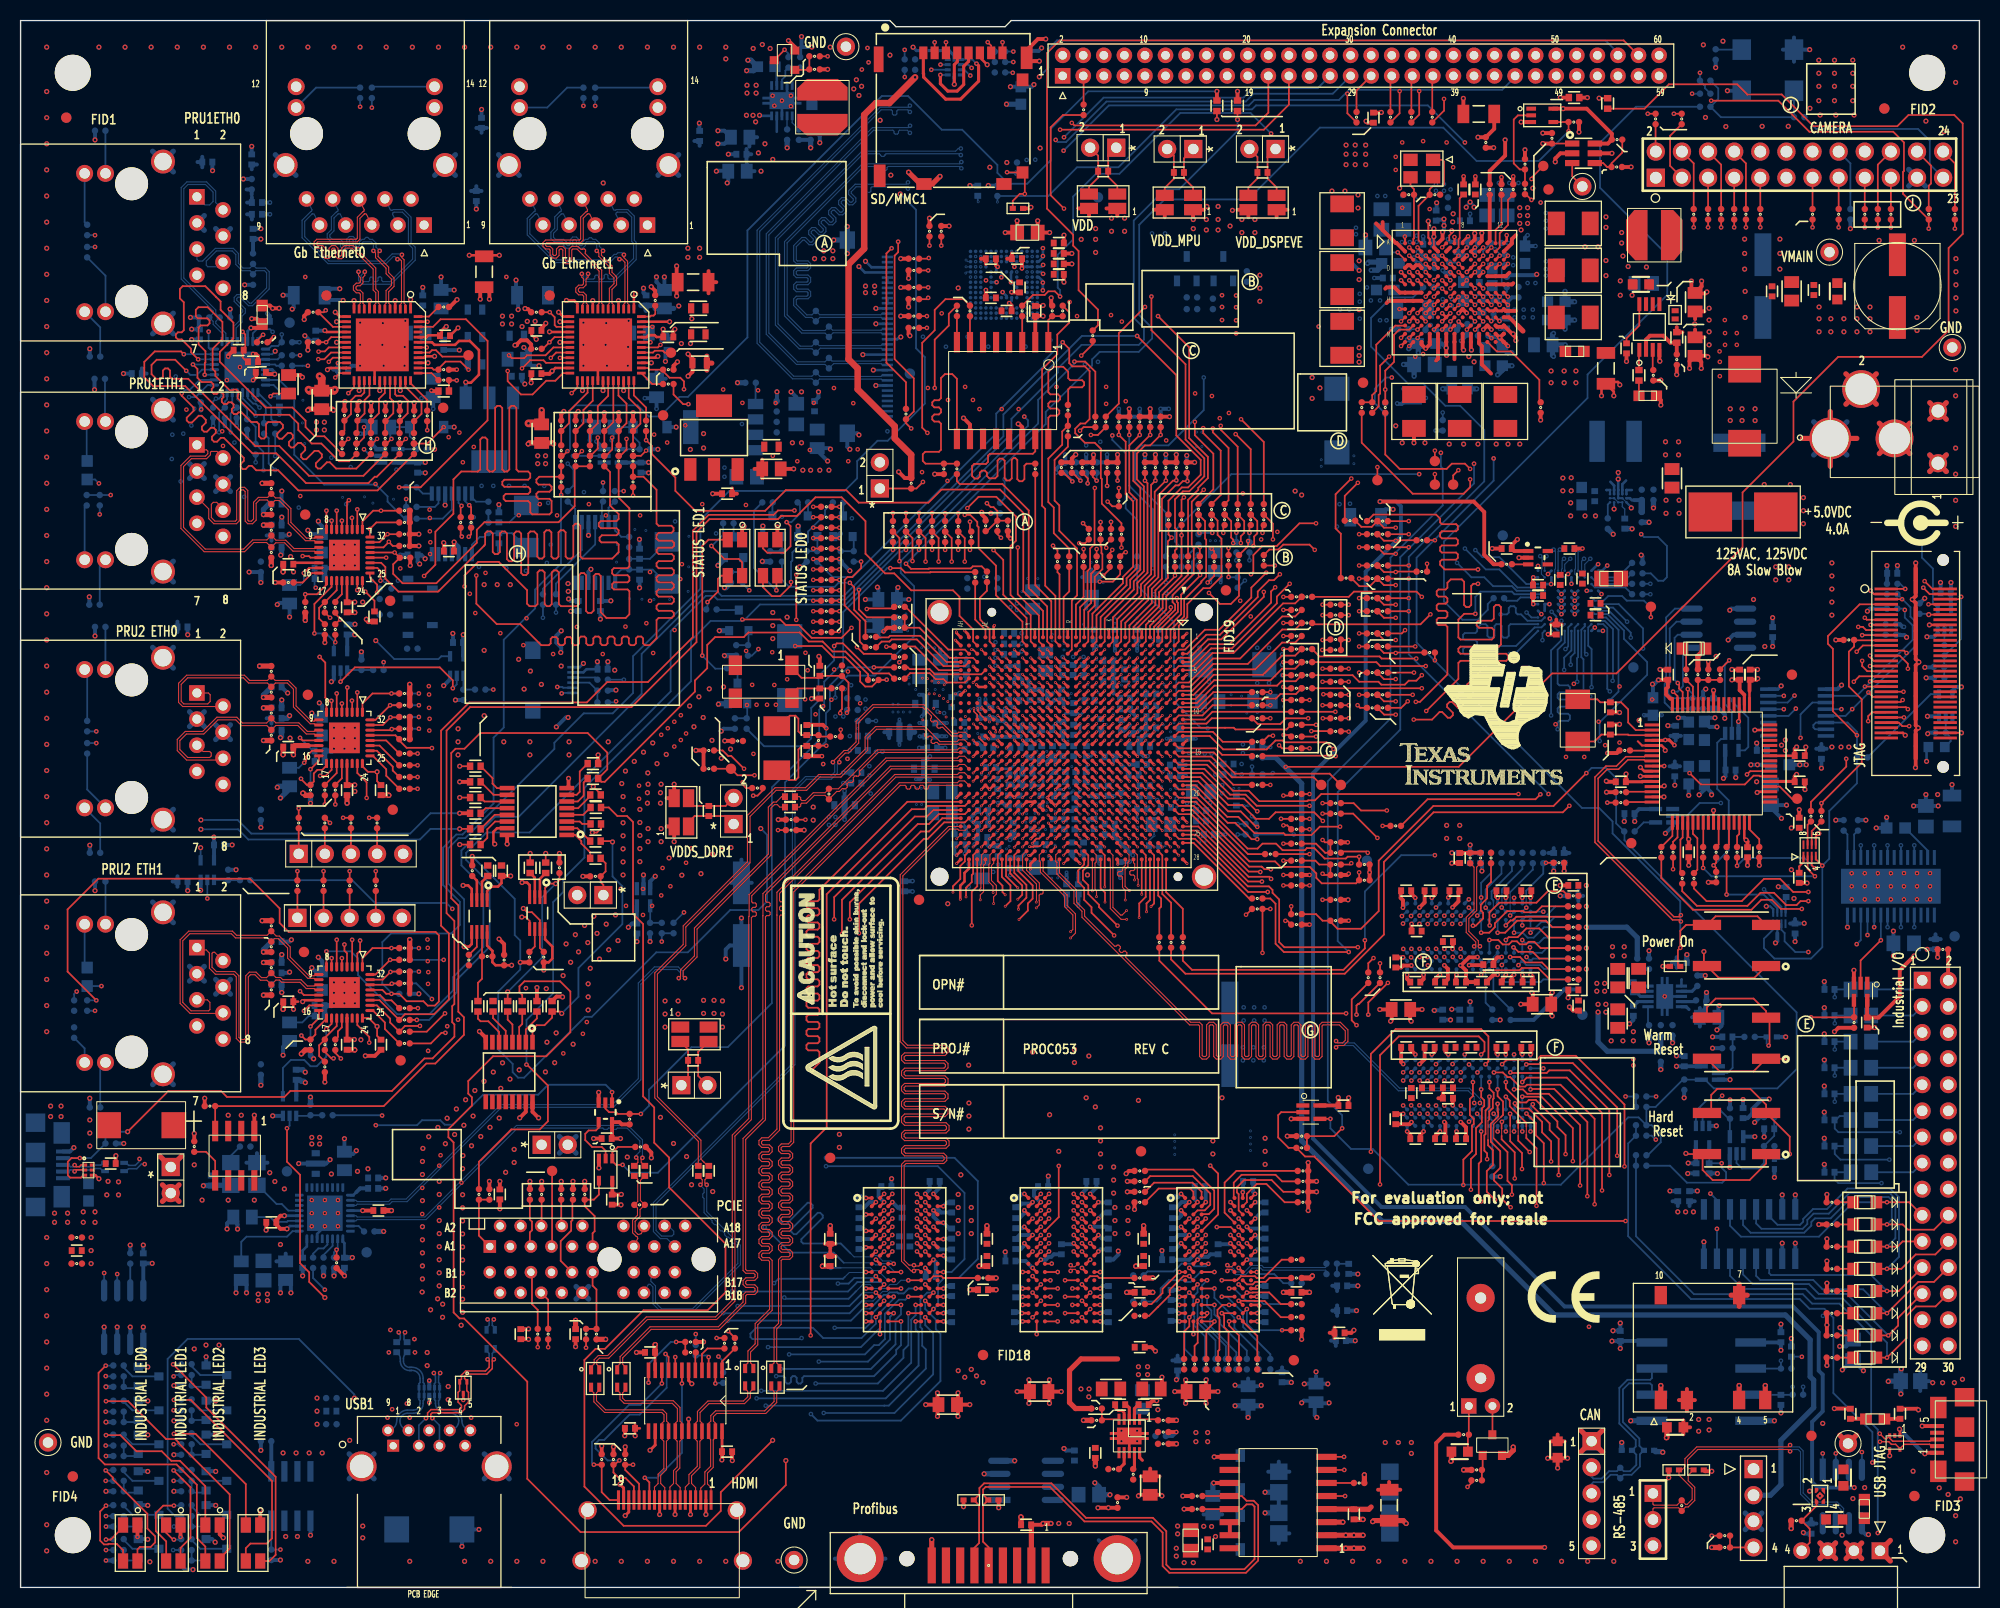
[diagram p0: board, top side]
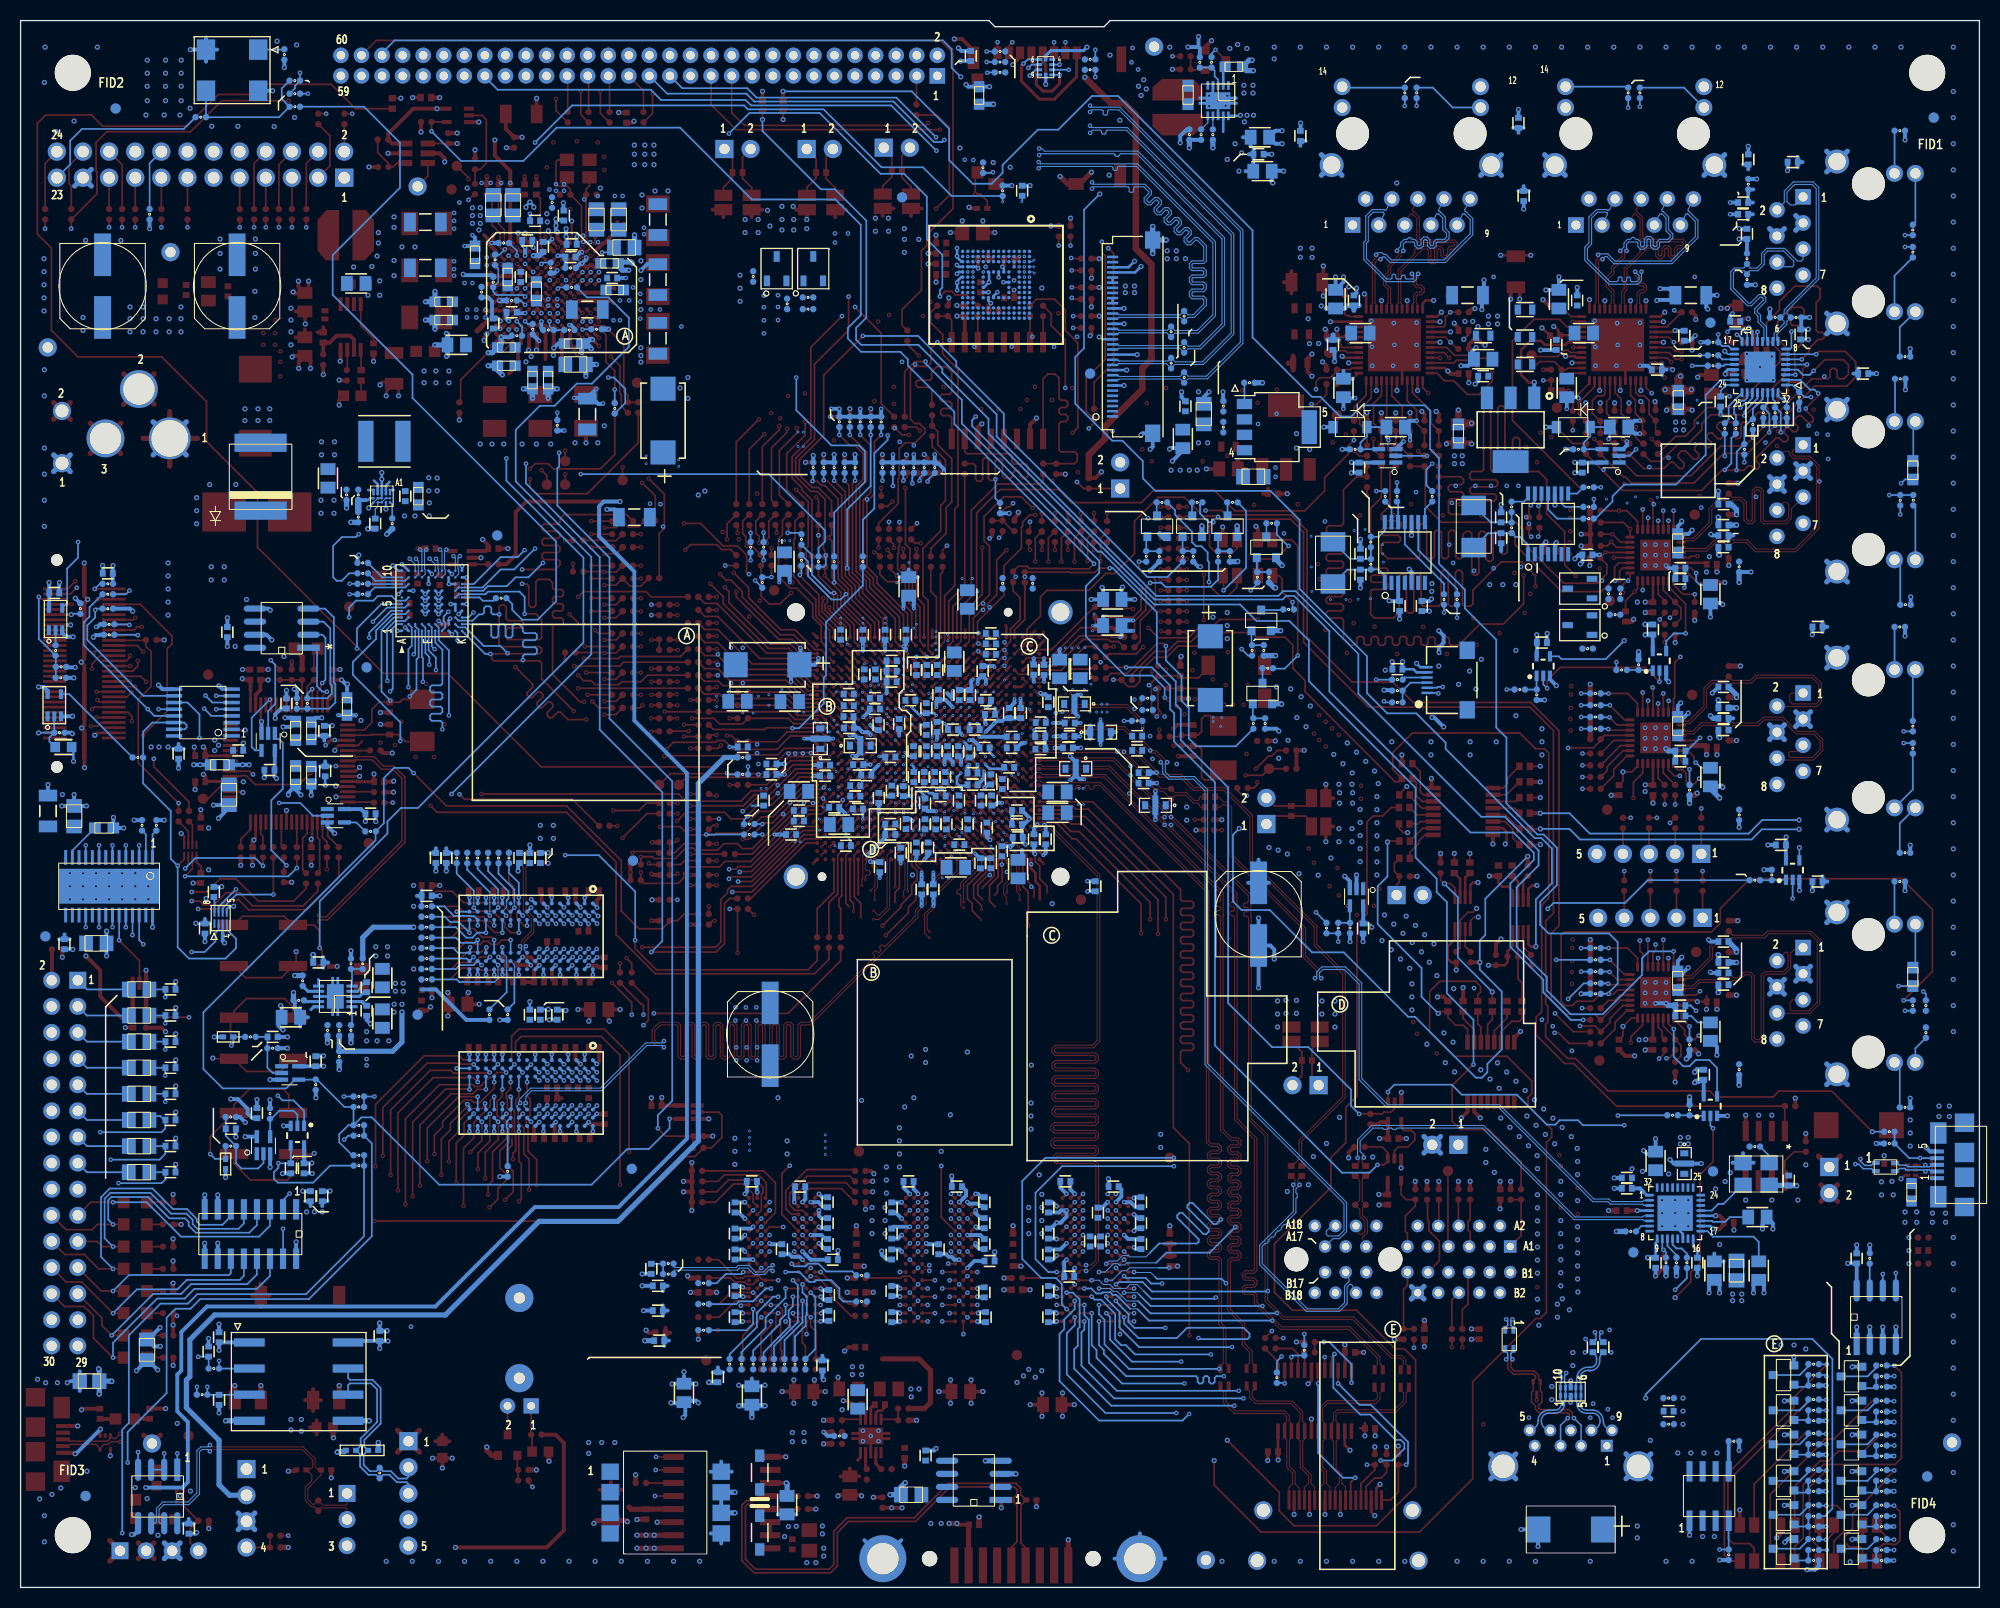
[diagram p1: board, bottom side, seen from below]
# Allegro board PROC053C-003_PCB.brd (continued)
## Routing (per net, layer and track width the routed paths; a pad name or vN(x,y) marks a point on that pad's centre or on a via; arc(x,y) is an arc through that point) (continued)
DDRECC_D0: length 58.2
  TOP w0.173: v2(115.7,41.02) 116.46,40.26 116.46,36.28 U6.E3 ; U1.W22 v4(99.02,75.23)
  L3_SIG1 w0.099: 99.58,70.78 99.34,71.02 99.34,73.02 99.56,73.23 99.56,74.04 99.46,74.14 99.46,74.79 v4(99.02,75.23)
  L3_SIG1 w0.109: v2(115.7,41.02) 117.22,41.02 117.8,41.6 117.8,42.03 117.91,42.14 118.94,42.14 119.05,42.25 119.05,42.47 118.94,42.58 117.91,42.58 117.8,42.69 117.8,42.91 117.91,43.02 118.94,43.02 119.05,43.12 119.05,43.34 118.94,43.45 117.91,43.45 117.8,43.56 117.8,43.78 117.91,43.89 118.64,43.89 118.75,44 118.75,44.22 118.64,44.33 117.91,44.33 117.2,45.04 117.2,45.56 105.99,56.76 105.99,62.18 105.44,62.74 105.44,64.83 104.26,66 104.26,66.64 101,69.91 100.46,69.91 99.58,70.78
DDRECC_D1: length 57.8
  TOP w0.173: U6.F7 v2(117.66,34.28) ; U1.V23 v4(98.96,74.34)
  L3_SIG1 w0.099: v4(98.96,74.34) 98.96,74.02 99.12,73.86 99.12,73.37 98.94,73.19 98.94,70.79 99.19,70.55
  L3_SIG1 w0.109: 99.19,70.55 100.47,69.27 100.78,69.27 103.38,66.67 103.38,65.44 104.42,64.4 104.42,62.41 105.08,61.76 105.08,56.26 113.55,47.79 113.55,47.62 113.25,47.32 113.25,47.13 113.36,47.02 113.51,47.02 113.83,47.34 113.99,47.34 114.17,47.16 114.17,46.64 114.29,46.52 114.68,46.52 114.81,46.39 114.81,46.23 114.71,46.12 114.29,46.12 114.17,46.01 114.17,45.84 114.29,45.73 114.67,45.73 114.78,45.61 114.78,45.45 114.67,45.33 114.29,45.33 114.17,45.21 114.17,45.05 114.29,44.93 114.67,44.93 114.78,44.82 114.78,44.65 114.67,44.54 114.29,44.54 114.17,44.42 114.17,44.26 114.29,44.14 114.67,44.14 114.78,44.03 114.78,43.86 114.67,43.75 114.29,43.75 114.17,43.63 114.17,43.47 114.29,43.35 114.67,43.35 114.78,43.23 114.78,43.07 114.67,42.95 114.29,42.95 114.17,42.84 114.17,42.67 114.29,42.56 114.67,42.56 114.78,42.44 114.78,42.28 114.67,42.16 114.29,42.16 114.17,42.04 114.17,41.06 115.23,40 117.35,40 118.06,39.29 118.06,34.68 v2(117.66,34.28)
DDRECC_D2: length 57.8
  TOP w0.173: U1.W19 v4(98.24,77.62) ; U6.H8 v2(118.46,32.68)
  L3_SIG1 w0.099: 99.83,70.83 99.54,71.12 99.54,72.94 99.77,73.16 99.77,74.11 99.66,74.23 99.66,74.98 99.47,75.17 99.47,76.79 99.16,77.11 98.91,77.11 98.75,76.95 98.52,76.95 98.24,77.23 v4(98.24,77.62)
  L3_SIG1 w0.109: v2(118.46,32.68) 119.3,32.68 120.57,33.95 120.57,39.5 119.92,40.15 119.92,43.79 106.45,57.26 106.45,62.36 105.89,62.92 105.89,65 104.95,65.94 104.95,66.26 101,70.21 100.45,70.21 99.83,70.83
DDRECC_D3: length 57.9
  TOP w0.173: U1.W23 v4(98.24,74.42) ; U6.F8 v2(118.46,34.28)
  L3_SIG1 w0.099: v4(98.24,74.42) 98.46,74.64 99.09,74.64 99.26,74.47 99.26,74.06 99.32,73.99 99.32,73.28 99.14,73.1 99.14,70.9 99.41,70.63
  L3_SIG1 w0.109: 99.41,70.63 100.47,69.58 101.02,69.58 103.82,66.77 103.82,65.7 104.93,64.59 104.93,62.55 105.54,61.94 105.54,56.45 115.26,46.73 115.26,45.34 115.38,45.23 116.55,45.23 116.66,45.11 116.66,44.95 116.55,44.83 115.38,44.83 115.26,44.72 115.26,44.55 115.38,44.44 116.55,44.44 116.66,44.32 116.66,44.16 116.55,44.04 115.35,44.04 115.24,43.92 115.24,40.72 115.65,40.31 117.66,40.31 119.28,38.69 119.28,37.49 118.85,37.06 118.85,34.66 v2(118.46,34.28)
DDRECC_D4: length 57.8
  TOP w0.173: U6.F2 v2(114.46,34.28) ; U1.Y25 v4(97.44,72.82)
  L3_SIG1 w0.099: 97.25,70.2 97.25,71.04 97.73,71.51 97.73,72.14 97.44,72.43 v4(97.44,72.82)
  L3_SIG1 w0.109: 97.25,70.2 98.29,69.16 98.96,69.16 101.51,66.62 101.51,55.44 101.96,55 101.96,50.75 107.95,44.76 107.95,43.96 108.07,43.84 108.66,43.84 108.78,43.72 108.78,43.56 108.66,43.44 108.07,43.44 107.95,43.33 107.95,42.44 108.52,41.87 108.69,41.87 109.36,42.54 109.54,42.54 109.65,42.43 109.65,42.28 108.97,41.59 108.97,41.43 109.08,41.31 109.25,41.31 109.62,41.68 109.77,41.68 109.89,41.57 109.89,41.4 109.53,41.03 109.53,40.87 110.24,40.16 110.24,38.85 110.35,38.74 110.92,38.74 111.03,38.62 111.03,38.46 110.92,38.34 110.35,38.34 110.24,38.22 110.24,38.06 110.35,37.94 110.92,37.94 111.03,37.83 111.03,37.66 110.92,37.55 110.35,37.55 110.24,37.43 110.24,37.27 110.35,37.15 110.92,37.15 111.03,37.03 111.03,36.87 110.92,36.75 110.35,36.75 110.24,36.64 110.24,36.28 112.07,34.45 113.06,34.45 113.41,34.8 113.9,34.8 114.42,34.28 v2(114.46,34.28)
DDRECC_D5: length 57.9
  TOP w0.173: U6.H7 v2(117.66,32.68) ; U1.V24 99.03,73.61 v4(98.83,73.61)
  L3_SIG1 w0.099: 98.95,70.46 98.74,70.67 98.74,73.29 98.83,73.38 v4(98.83,73.61)
  L3_SIG1 w0.109: 98.95,70.46 100.45,68.97 100.68,68.97 102.94,66.71 102.94,65.12 103.95,64.11 103.95,62.26 104.62,61.59 104.62,56.09 105.67,55.04 105.67,54.85 105.2,54.38 105.2,54.21 105.31,54.1 105.48,54.1 105.85,54.47 106.01,54.47 106.13,54.35 106.13,54.19 105.76,53.81 105.76,53.65 105.88,53.53 106.04,53.53 106.41,53.91 106.57,53.91 106.69,53.79 106.69,53.62 106.32,53.25 106.32,53.09 106.44,52.97 106.6,52.97 106.97,53.34 107.13,53.34 107.25,53.23 107.25,53.06 106.88,52.69 106.88,52.53 107,52.41 107.16,52.41 107.53,52.78 107.7,52.78 107.81,52.67 107.81,52.5 107.44,52.13 107.44,51.97 107.56,51.85 107.72,51.85 108.09,52.22 108.26,52.22 108.37,52.11 108.37,51.94 108.23,51.8 108.23,51.64 108.35,51.52 108.51,51.52 108.65,51.66 108.82,51.66 112.53,47.95 112.53,47.07 113.66,45.93 113.66,40.96 115,39.62 116.2,39.62 117.22,38.61 117.22,33.11 v2(117.66,32.68)
DDRECC_D6: length 58
  TOP w0.173: U6.H3 v2(115.26,32.68) ; v4(98.39,72.38) 98.62,72.61 98.62,72.67 98.78,72.83 99.05,72.83 U1.V25
  L3_SIG1 w0.099: 98.7,70.36 98.54,70.52 98.54,72.22 v4(98.39,72.38)
  L3_SIG1 w0.109: 98.7,70.36 102.49,66.57 102.49,64.93 103.51,63.91 103.51,62.07 104.17,61.41 104.17,55.91 104.72,55.35 104.72,53.97 108.92,49.77 109.09,49.77 109.41,50.1 109.58,50.1 109.69,49.98 109.69,49.82 109.37,49.49 109.37,49.33 109.48,49.21 109.65,49.21 109.97,49.54 110.14,49.54 110.25,49.42 110.25,49.26 109.93,48.93 109.93,48.77 110.04,48.65 110.21,48.65 110.53,48.98 110.7,48.98 110.81,48.86 110.81,48.7 110.49,48.37 110.49,48.21 112.52,46.17 112.52,45.34 112.64,45.22 113.08,45.22 113.2,45.1 113.2,44.94 113.08,44.82 112.64,44.82 112.52,44.71 112.52,44.54 112.64,44.43 113.08,44.43 113.2,44.31 113.2,44.15 113.08,44.03 112.64,44.03 112.52,43.92 112.52,43.75 112.64,43.64 113.08,43.64 113.2,43.52 113.2,43.36 113.08,43.24 112.64,43.24 112.52,43.12 112.52,42.96 112.64,42.84 112.86,42.84 112.97,42.73 112.97,42.56 112.86,42.45 112.64,42.45 112.52,42.33 112.52,41.41 114.58,39.35 115.71,39.35 116.97,38.1 116.97,34.38 v2(115.26,32.68)
DDRECC_D7: length 57.8
  TOP w0.173: U1.Y26 v4(97.44,72.02) ; U6.G2 v2(114.46,33.48)
  L3_SIG1 w0.099: v4(97.44,72.02) 97.44,71.6 97.05,71.21 97.05,70.09
  L3_SIG1 w0.109: 97.05,70.09 98.23,68.91 98.89,68.91 101.07,66.73 101.07,55.26 101.52,54.81 101.52,50.5 106.37,45.65 106.37,45.49 105.87,44.99 105.87,44.8 105.98,44.69 106.14,44.69 106.65,45.21 106.81,45.21 107.23,44.79 107.23,44.09 107.11,43.98 105.96,43.98 105.85,43.86 105.85,43.7 105.96,43.58 107.11,43.58 107.23,43.47 107.23,43.3 107.11,43.19 105.96,43.19 105.85,43.07 105.85,42.91 105.96,42.79 107.11,42.79 107.23,42.67 107.23,42.51 107.11,42.39 105.96,42.39 105.85,42.28 105.85,42.11 105.96,42 107.11,42 107.23,41.88 107.23,41.39 109.47,39.14 109.47,36.32 111.76,34.04 113.16,34.04 113.72,33.48 v2(114.46,33.48)
DDRECC_DQM: length 57.9
  TOP w0.173: v2(116.33,35.05) 117.68,35.05 U6.E7 ; U1.V26 99.11,72.09 98.57,72.09 98.53,72.05 98.25,72.05 98.25,72.06 v4(98.12,72.06)
  L3_SIG1 w0.099: 98.56,70.07 98.34,70.29 98.34,71.84 v4(98.12,72.06)
  L3_SIG1 w0.109: v2(116.33,35.05) 116.33,37.83 115.3,38.86 113.66,38.86 113.28,39.25 113.28,39.4 113.48,39.6 113.48,39.76 113.33,39.91 113.18,39.91 112.97,39.71 112.82,39.71 112.66,39.86 112.66,40.02 112.87,40.22 112.87,40.38 112.71,40.53 112.56,40.53 112.35,40.33 112.2,40.33 111.74,40.79 111.74,46.13 111.16,46.71 111,46.71 110.81,46.52 110.66,46.52 110.5,46.68 110.5,46.83 110.69,47.02 110.69,47.18 110.54,47.33 110.38,47.33 110.19,47.14 110.04,47.14 109.88,47.3 109.88,47.45 110.08,47.64 110.08,47.8 109.92,47.95 109.77,47.95 109.45,47.63 109.29,47.63 109.14,47.79 109.14,47.94 109.46,48.26 109.46,48.41 109.3,48.57 109.15,48.57 108.96,48.38 108.8,48.38 108.65,48.53 108.65,48.69 108.84,48.88 108.84,49.03 108.68,49.19 108.53,49.19 108.34,49 108.18,49 108.03,49.15 108.03,49.31 108.22,49.5 108.22,49.65 108.07,49.81 107.91,49.81 107.72,49.61 107.57,49.61 107.41,49.77 107.41,49.92 107.6,50.11 107.6,50.27 107.45,50.42 107.29,50.42 107.1,50.23 106.95,50.23 106.79,50.39 106.79,50.54 106.98,50.73 106.98,50.89 106.83,51.04 106.67,51.04 106.36,50.72 106.2,50.72 106.05,50.88 106.05,51.03 106.37,51.35 106.37,51.51 106.21,51.66 106.06,51.66 105.74,51.34 105.58,51.34 105.43,51.5 105.43,51.65 105.75,51.97 105.75,52.12 103.91,53.96 103.91,55.43 103.64,55.69 103.06,56.28 103.06,63.73 101.99,64.8 101.99,66.64 98.56,70.07
DDRECC_DQS: length 58.4
  TOP w0.108: U1.V27 99.07,71.25 99.07,70.66 99.18,70.55 99.18,69.58 101.52,67.23 101.52,66.22 102.34,65.41 102.34,64.01 v4(102.12,63.79) ; U6.F3 v2(115.26,34.28)
  L3_SIG1 w0.083: v2(115.26,34.28) 115.26,34.82 115.99,35.55 115.99,36.35 115.5,36.84 113.69,36.84 112.02,38.52 112.02,39.38 111.14,40.26 111.14,42.96 110.61,43.49 110.61,43.61 111.08,44.08 111.08,44.45 110.78,44.75 110.41,44.75 109.94,44.27 109.82,44.27 109.71,44.39 109.71,44.5 110.46,45.26 110.46,45.65 110.18,45.94 109.81,45.94 109.04,45.17 108.92,45.17 108.81,45.29 108.81,45.4 109.66,46.26 109.66,46.63 109.37,46.92 109,46.92 108.14,46.07 108.03,46.07 106.75,47.35 106.75,47.46 107.54,48.26 107.54,48.62 107.24,48.92 106.87,48.92 106.08,48.13 105.96,48.13 105.85,48.25 105.85,48.36 106.64,49.16 106.64,49.52 106.34,49.82 105.97,49.82 105.18,49.03 105.07,49.03 104.81,49.29 104.81,52.21 103.3,53.71 103.3,54.93 102.42,55.82 102.42,63.02 102.45,63.05 102.45,63.45 v4(102.12,63.79)
DDRECC_DQSN: length 58.4
  TOP w0.108: v4(102.11,63.17) 102.59,63.65 102.59,65.51 101.78,66.32 101.78,67.34 99.43,69.68 U1.V28 ; U6.G3 v2(115.26,33.48)
  L3_SIG1 w0.083: v2(115.26,33.48) 114.89,33.85 114.89,34.44 114.95,34.5 114.95,34.94 115.69,35.68 115.69,36.22 115.37,36.54 113.57,36.54 111.71,38.39 111.71,39.25 110.83,40.14 110.83,42.83 110.3,43.36 110.3,43.73 110.78,44.21 110.78,44.32 110.66,44.44 110.54,44.44 110.07,43.97 109.7,43.97 109.4,44.26 109.4,44.63 110.16,45.38 110.16,45.53 110.05,45.63 109.93,45.63 109.17,44.87 108.8,44.87 108.5,45.16 108.5,45.53 109.36,46.39 109.36,46.5 109.24,46.62 109.12,46.62 108.27,45.76 107.9,45.76 106.44,47.22 106.44,47.59 107.23,48.38 107.23,48.5 107.12,48.62 107,48.62 106.21,47.83 105.84,47.83 105.54,48.12 105.54,48.49 106.33,49.28 106.33,49.4 106.22,49.52 106.1,49.52 105.31,48.72 104.94,48.72 104.5,49.16 104.5,52.08 103,53.59 103,54.81 102.11,55.69 v4(102.11,63.17)
DECODER_1A: length 3.4
  TOP w0.173: U101.2 49.14,54.27 50.22,55.35 R965.1
DECODER_1B: length 3.1
  TOP w0.173: R966.1 48.79,54.81 48.49,54.51 U101.3
DECODER_1G: length 25.9
  TOP w0.173: v1(57.57,72.51) 57.48,72.59 R970.1 ; U101.1 49.79,54.28 50.19,54.69 50.95,54.69 51.69,55.42 R938.1 52.44,56.01 v1(52.63,55.83)
  BOTTOM w0.173: v1(57.57,72.51) 57.57,69.15 58.52,68.2 58.52,64.52 54.25,60.25 54.25,57.45 v1(52.63,55.83)
DRAIN0: length 23.7
  TOP w0.173: D5.1 v2(181.51,37.46) 183.67,37.46 J37.19
  BOTTOM w0.173: v2(181.51,37.46) 178.23,37.46 174.89,34.12 167.31,34.12 166.24,35.18 U73.3
DRAIN1: length 28.4
  TOP w0.173: J37.20 186.08,34.8 183.54,34.8 183.03,35.31 v2(181.51,35.31) D6.1
  BOTTOM w0.173: 167.51,36.77 167.51,35.24 168.25,34.5 173.46,34.5 174.15,35.2 174.15,35.55 174.51,35.9 176.03,35.9 178.1,37.97 181.66,37.97 181.98,37.66 181.98,35.77 v2(181.51,35.31)
DRAIN2: length 26.7
  TOP w0.173: D7.1 v2(181.51,33.15) 182.52,33.15 183.03,33.66 J37.21
  BOTTOM w0.173: U73.5 168.78,35.4 169.31,34.88 173.3,34.88 173.76,35.34 173.76,35.75 174.37,36.36 175.85,36.36 177.87,38.37 181.76,38.37 182.33,37.8 182.33,33.96 v2(181.51,33.15)
DRAIN3: length 31.2
  TOP w0.173: D8.1 v2(181.51,30.99) 182.91,30.99 184.3,32.38 186.21,32.38 J37.22
  BOTTOM w0.173: U73.6 170.05,36.08 170.86,35.27 173.05,35.27 173.36,35.58 173.36,35.84 174.32,36.81 175.68,36.81 177.67,38.8 181.82,38.8 182.68,37.95 182.68,32.16 v2(181.51,30.99)
DRAIN4: length 19
  TOP w0.173: J37.23 182.65,28.83 v2(181.51,28.83) D9.1
  BOTTOM w0.173: v2(181.51,28.83) 179.95,30.38 170.23,30.38 170.05,30.56 U73.11
DRAIN5: length 24.7
  TOP w0.173: J37.24 186.08,29.72 184.56,29.72 v2(181.51,26.67) D10.1
  BOTTOM w0.173: v2(181.51,26.67) 179.18,29 175.24,29 174.33,29.91 169.18,29.91 168.78,30.31 U73.12
DRAIN6: length 24.7
  TOP w0.173: D11.1 v2(181.64,24.51) 182.59,25.46 182.59,26.23 J37.25
  BOTTOM w0.173: 167.51,31.97 167.51,30.43 168.44,29.5 173.92,29.5 174.87,28.55 177.59,28.55 v2(181.64,24.51)
DRAIN7: length 31.9
  TOP w0.173: D12.1 v2(181.51,22.35) 183.41,24.26 183.41,26.42 184.33,27.33 186.23,27.33 J37.26
  BOTTOM w0.173: v2(181.51,22.35) 181.51,23.8 177.22,28.09 174.54,28.09 173.6,29.04 167.51,29.04 166.24,30.31 U73.14
EECS: length 7.2
  TOP w0.173: v2(160.71,87.13) 161.14,86.69 U37.63
  BOTTOM w0.173: U38.1 161.7,91.39 161.67,91.36 161.67,87.65 161.15,87.13 v2(160.71,87.13)
EEDATA: length 14
  TOP w0.173: U37.61 v2(162.14,87.38)
  BOTTOM w0.173: v2(162.14,87.38) 162.61,86.91 R495.1 160.68,86.49 160.24,86.93 160.24,87.74 160.38,87.88 160.38,93.27 161.04,93.93 U38.3
EESK: length 8.6
  TOP w0.173: v2(161.16,87.97) 161.29,87.84 161.29,87.43 161.64,87.08 U37.62
  BOTTOM w0.173: v2(161.16,87.97) 160.85,88.28 160.85,92.36 161.16,92.66 U38.2
EMMC_RSTN: length 130.1
  TOP w0.173: R564.2 v7(121.54,85.81)
  L3_SIG1 w0.109: v7(121.54,85.81) 122.5,86.77 123.19,86.77 123.52,86.44 124.84,86.44 125.17,86.77 126.16,86.77 126.54,86.39 v5(127.64,86.39)
  L4_SIG2 w0.114: v5(127.64,86.39) 129.01,87.76 129.01,92 140,103 140,104.98 144.12,109.1 144.12,121.77 144.65,122.3 144.65,123.8 144.12,124.33 144.12,130.03 143.31,130.84 143.31,137.7 v2(140.46,140.54)
  L10_SIG4 w0.109: v11(96.88,127.95) 96.41,127.95 96.14,128.22 96.14,129.03 96.63,129.53 96.63,132.07 95,133.71 v11(95,134.75)
  BOTTOM w0.173: v2(140.46,140.54) 136.86,144.15 120.14,144.15 119.76,143.76 112.4,143.76 106.76,138.13 102.74,138.13 99.95,135.34 R741.1 v11(95,134.75)
EMU2: length 71.6
  TOP w0.173: R711.1 v7(135,101.17) ; v7(179.35,94.32) 179.54,94.12 J18.13
  L3_SIG1 w0.109: v7(135,101.17) 138.36,101.17 138.47,101.29 138.47,101.82 138.59,101.94 138.75,101.94 138.87,101.82 138.87,101.29 138.98,101.17 139.15,101.17 139.27,101.29 139.27,101.82 139.38,101.94 139.55,101.94 139.66,101.82 139.66,101.29 139.78,101.17 139.94,101.17 140.06,101.29 140.06,101.82 140.17,101.94 140.34,101.94 140.45,101.82 140.45,101.29 140.57,101.17 140.73,101.17 140.85,101.29 140.85,101.82 140.97,101.94 141.13,101.94 141.25,101.82 141.25,101.29 141.36,101.17 141.53,101.17 141.64,101.29 141.64,101.82 141.76,101.94 141.92,101.94 142.04,101.82 142.04,101.29 142.15,101.17 142.6,101.17 142.71,101.29 142.71,101.82 142.83,101.94 143.89,101.94 144.65,101.17 146.27,101.17 146.38,101.28 146.38,101.95 146.49,102.06 146.71,102.06 146.82,101.95 146.82,101.28 146.93,101.17 147.15,101.17 147.26,101.28 147.26,101.95 147.37,102.06 147.59,102.06 147.69,101.95 147.69,101.28 147.8,101.17 148.02,101.17 148.13,101.28 148.13,101.95 148.24,102.06 148.46,102.06 148.57,101.95 148.57,101.28 148.68,101.17 148.9,101.17 149.01,101.28 149.01,101.95 149.11,102.06 149.33,102.06 149.44,101.95 149.44,101.28 149.55,101.17 150.11,101.17 150.7,100.59 152.53,100.59 152.64,100.7 152.64,101.19 152.74,101.3 152.96,101.3 153.07,101.19 153.07,100.7 153.18,100.59 154,100.59 155.96,98.63 166.7,98.63 166.81,98.74 166.81,99.26 166.92,99.36 167.14,99.36 167.25,99.26 167.25,98.74 167.35,98.63 167.57,98.63 167.68,98.74 167.68,99.26 167.79,99.36 168.01,99.36 168.12,99.26 168.12,98.74 168.23,98.63 168.45,98.63 168.56,98.74 168.56,99.26 168.67,99.36 168.88,99.36 168.99,99.26 168.99,98.74 169.1,98.63 169.32,98.63 169.43,98.74 169.43,99.26 169.54,99.36 169.76,99.36 169.87,99.26 169.87,98.74 169.98,98.63 175.01,98.63 175.89,97.74 177.42,97.74 178.82,96.35 178.82,94.85 v7(179.35,94.32)
EMU3: length 79.1
  TOP w0.173: J18.17 179.48,93.12 179.17,93.43 v7(178.71,93.43) ; R712.1 v7(135,96.22)
  L3_SIG1 w0.109: v7(135,96.22) 135,96.82 136.61,98.43 137.33,98.43 137.44,98.54 137.44,99 137.55,99.11 137.77,99.11 137.88,99 137.88,98.54 137.99,98.43 138.21,98.43 138.31,98.54 138.31,99 138.42,99.11 138.64,99.11 138.75,99 138.75,98.54 138.86,98.43 139.08,98.43 139.19,98.54 139.19,99 139.3,99.11 139.52,99.11 139.63,99 139.63,98.54 139.73,98.43 140.13,98.43 140.61,98.91 141.07,98.91 142.08,97.9 142.28,97.9 142.42,98.04 142.42,98.77 142.56,98.91 142.76,98.91 142.9,98.77 142.9,98.04 143.04,97.9 143.24,97.9 143.38,98.04 143.38,98.77 143.52,98.91 143.72,98.91 143.86,98.77 143.86,98.04 144,97.9 144.2,97.9 144.34,98.04 144.34,98.77 144.48,98.91 144.68,98.91 144.82,98.77 144.82,98.04 144.96,97.9 145.16,97.9 145.3,98.04 145.3,98.77 145.44,98.91 145.64,98.91 145.78,98.77 145.78,98.04 145.92,97.9 146.12,97.9 146.26,98.04 146.26,98.77 146.4,98.91 147.43,98.91 147.58,98.77 147.58,98.14 147.68,98.03 147.97,98.03 148.08,98.14 148.08,98.75 148.41,99.09 150.16,99.09 150.34,99.27 151.43,99.27 153.22,97.49 153.5,97.49 153.62,97.6 153.62,98.21 153.73,98.33 153.9,98.33 154.01,98.21 154.01,97.6 154.13,97.49 154.36,97.49 154.74,97.11 158.76,97.11 158.87,97.22 158.87,97.51 158.98,97.62 159.2,97.62 159.3,97.51 159.3,97.22 159.41,97.11 159.63,97.11 159.74,97.22 159.74,97.51 159.85,97.62 160.07,97.62 160.18,97.51 160.18,97.22 160.29,97.11 160.51,97.11 160.62,97.22 160.62,97.51 160.72,97.62 160.94,97.62 161.05,97.51 161.05,97.22 161.16,97.11 161.38,97.11 161.49,97.22 161.49,97.51 161.6,97.62 161.82,97.62 161.93,97.51 161.93,97.22 162.04,97.11 162.25,97.11 162.36,97.22 162.36,97.51 162.47,97.62 162.69,97.62 162.8,97.51 162.8,97.22 162.91,97.11 163.13,97.11 163.24,97.22 163.24,97.51 163.35,97.62 163.56,97.62 163.67,97.51 163.67,97.22 163.78,97.11 164,97.11 164.11,97.22 164.11,97.51 164.22,97.62 164.44,97.62 164.55,97.51 164.55,97.22 164.66,97.11 164.88,97.11 164.98,97.22 164.98,97.51 165.09,97.62 165.31,97.62 165.42,97.51 165.42,97.22 165.53,97.11 165.75,97.11 165.86,97.22 165.86,97.51 165.97,97.62 166.19,97.62 166.3,97.51 166.3,97.22 166.4,97.11 166.62,97.11 166.73,97.22 166.73,97.51 166.84,97.62 167.06,97.62 167.17,97.51 167.17,97.22 167.28,97.11 167.5,97.11 167.61,97.22 167.61,97.51 167.71,97.62 167.93,97.62 168.04,97.51 168.04,97.22 168.15,97.11 168.37,97.11 168.48,97.22 168.48,97.51 168.59,97.62 168.81,97.62 168.92,97.51 168.92,97.22 169.03,97.11 169.8,97.11 170.69,96.22 171.17,96.22 171.28,96.33 171.28,96.62 171.39,96.73 171.61,96.73 171.72,96.62 171.72,96.33 171.83,96.22 172.05,96.22 172.16,96.33 172.16,96.62 172.27,96.73 172.48,96.73 172.59,96.62 172.59,96.33 172.7,96.22 172.92,96.22 173.03,96.33 173.03,96.62 173.14,96.73 173.36,96.73 173.47,96.62 173.47,96.33 173.58,96.22 173.79,96.22 173.9,96.33 173.9,96.62 174.01,96.73 174.23,96.73 174.34,96.62 174.34,96.33 174.45,96.22 175.01,96.22 176.02,95.2 176.94,95.2 v7(178.71,93.43)
EMU4: length 95.3
  TOP w0.173: J18.23 179.17,91.62 v7(178.56,91.01) ; v7(137.11,94.65) 136.14,93.68 125.73,93.68 R713.1
  L3_SIG1 w0.109: v7(178.56,91.01) 178.56,92.66 177.24,93.99 175.96,93.99 174.36,95.59 167.91,95.59 167.8,95.69 167.8,96.49 167.69,96.6 167.47,96.6 167.36,96.49 167.36,95.69 167.26,95.59 167.04,95.59 166.93,95.69 166.93,96.49 166.82,96.6 166.6,96.6 166.49,96.49 166.49,95.69 166.38,95.59 166.16,95.59 166.05,95.69 166.05,96.49 165.94,96.6 165.73,96.6 165.62,96.49 165.62,95.69 165.51,95.59 165.29,95.59 165.18,95.69 165.18,96.49 165.07,96.6 164.85,96.6 164.74,96.49 164.74,95.69 164.63,95.59 164.42,95.59 164.31,95.69 164.31,96.49 164.2,96.6 163.98,96.6 163.87,96.49 163.87,95.69 163.76,95.59 163.54,95.59 163.43,95.69 163.43,96.49 163.32,96.6 163.1,96.6 163,96.49 163,95.69 162.89,95.59 162.67,95.59 162.56,95.69 162.56,96.49 162.45,96.6 162.23,96.6 162.12,96.49 162.12,95.69 162.01,95.59 161.79,95.59 161.68,95.69 161.68,96.49 161.58,96.6 161.36,96.6 161.25,96.49 161.25,95.69 161.14,95.59 160.92,95.59 160.81,95.69 160.81,96.49 160.7,96.6 160.48,96.6 160.37,96.49 160.37,95.69 160.27,95.59 160.05,95.59 159.94,95.69 159.94,96.49 159.83,96.6 159.61,96.6 159.5,96.49 159.5,95.69 159.39,95.59 159.17,95.59 159.06,95.69 159.06,96.49 158.95,96.6 158.74,96.6 158.63,96.49 158.63,95.69 158.52,95.59 157.73,95.59 156.74,96.58 154.79,96.58 154.23,97.13 153.06,97.13 152.07,98.13 148.69,98.13 147.47,96.91 147.27,96.91 147.16,97.02 147.16,97.38 147.05,97.49 146.83,97.49 146.72,97.38 146.72,97.02 146.61,96.91 146.39,96.91 146.28,97.02 146.28,97.38 146.17,97.49 145.96,97.49 145.85,97.38 145.85,97.02 145.74,96.91 145.52,96.91 145.41,97.02 145.41,97.38 145.3,97.49 145.08,97.49 144.97,97.38 144.97,97.02 144.86,96.91 144.64,96.91 144.54,97.02 144.54,97.38 144.43,97.49 144.21,97.49 144.1,97.38 144.1,97.02 143.99,96.91 143.77,96.91 143.66,97.02 143.66,97.38 143.55,97.49 143.33,97.49 143.22,97.38 143.22,97.02 143.12,96.91 142.9,96.91 142.79,97.02 142.79,97.38 142.68,97.49 142.46,97.49 142.35,97.38 142.35,97.02 142.24,96.91 140.43,96.91 140.25,97.09 140.25,97.93 140.11,98.07 139.91,98.07 139.77,97.93 139.77,97.55 139.63,97.41 139.4,97.41 139.26,97.55 139.26,97.91 139.12,98.05 138.92,98.05 138.78,97.91 138.78,97.55 138.64,97.41 138.44,97.41 138.3,97.55 138.3,97.93 138.16,98.07 137.96,98.07 137.82,97.93 137.82,97.55 137.68,97.41 137.34,97.41 137.11,97.19 137.11,96.85 137.22,96.74 137.94,96.74 138.05,96.63 138.05,96.41 137.94,96.3 137.22,96.3 137.11,96.19 137.11,95.97 137.22,95.86 137.94,95.86 138.05,95.75 138.05,95.54 137.94,95.43 137.22,95.43 137.11,95.32 v7(137.11,94.65)
EMU5: length 75
  TOP w0.173: v7(183.41,90.89) 183.18,91.12 J18.25 ; v7(134.9,86.19) 134.26,85.55 R714.1
  L3_SIG1 w0.109: v7(134.9,86.19) 134.9,91.42 135.56,92.08 138.63,92.08 139.4,91.32 148.97,91.32 149.43,91.78 164.85,91.78 165.61,91.01 167.49,91.01 167.6,91.12 167.6,91.92 167.71,92.03 167.93,92.03 168.04,91.92 168.04,91.12 168.15,91.01 168.37,91.01 168.48,91.12 168.48,91.92 168.59,92.03 168.81,92.03 168.91,91.92 168.91,91.12 169.02,91.01 171.31,91.01 171.42,91.12 171.42,91.79 171.53,91.9 171.75,91.9 171.86,91.79 171.86,91.12 171.96,91.01 172.18,91.01 172.29,91.12 172.29,91.79 172.4,91.9 172.62,91.9 172.73,91.79 172.73,91.12 172.84,91.01 173.06,91.01 173.17,91.12 173.17,91.79 173.28,91.9 173.49,91.9 173.6,91.79 173.6,91.12 173.71,91.01 174.5,91.01 175.08,90.43 175.08,90.27 174.73,89.92 174.73,89.76 174.89,89.61 175.04,89.61 175.39,89.96 175.55,89.96 175.7,89.81 175.7,89.65 175.35,89.3 175.35,89.15 175.5,88.99 175.66,88.99 176.01,89.34 176.17,89.34 176.32,89.19 176.32,89.04 175.97,88.68 175.97,88.53 176.12,88.37 176.28,88.37 176.63,88.73 176.79,88.73 178.92,86.59 180.24,86.59 181.36,87.71 181.36,88.83 v7(183.41,90.89)
EMU6: length 79
  TOP w0.173: R715.1 v7(135.51,88.98) ; v7(183.54,89.36) 183.54,89.84 182.76,90.62 J18.27
  L3_SIG1 w0.109: v7(135.51,88.98) 135.51,89.49 136.14,90.12 136.91,90.12 137.58,89.45 138.6,89.45 139.65,88.4 140.08,88.4 140.19,88.51 140.19,88.87 140.3,88.98 140.52,88.98 140.63,88.87 140.63,88.51 140.73,88.4 140.95,88.4 141.06,88.51 141.06,88.87 141.17,88.98 141.39,88.98 141.5,88.87 141.5,88.51 141.61,88.4 141.83,88.4 141.94,88.51 141.94,88.87 142.04,88.98 142.26,88.98 142.37,88.87 142.37,88.51 142.48,88.4 142.7,88.4 142.81,88.51 142.81,88.87 142.92,88.98 143.14,88.98 143.25,88.87 143.25,88.51 143.36,88.4 143.57,88.4 143.68,88.51 143.68,88.87 143.79,88.98 144.01,88.98 144.12,88.87 144.12,88.51 144.23,88.4 144.45,88.4 144.56,88.51 144.56,88.87 144.67,88.98 144.88,88.98 144.99,88.87 144.99,88.51 145.1,88.4 145.32,88.4 145.43,88.51 145.43,88.87 145.54,88.98 145.76,88.98 145.87,88.87 145.87,88.51 145.98,88.4 146.2,88.4 146.3,88.51 146.3,88.87 146.41,88.98 146.63,88.98 146.74,88.87 146.74,88.51 146.85,88.4 147.07,88.4 147.18,88.51 147.18,88.87 147.29,88.98 147.51,88.98 147.62,88.87 147.62,88.51 147.72,88.4 154.7,88.4 154.8,88.51 154.8,88.87 154.91,88.98 155.13,88.98 155.24,88.87 155.24,88.51 155.35,88.4 155.57,88.4 155.68,88.51 155.68,88.87 155.79,88.98 156.01,88.98 156.12,88.87 156.12,88.51 156.22,88.4 156.44,88.4 156.55,88.51 156.55,88.87 156.66,88.98 156.88,88.98 156.99,88.87 156.99,88.51 157.1,88.4 157.32,88.4 157.43,88.51 157.43,88.87 157.54,88.98 157.75,88.98 157.86,88.87 157.86,88.51 157.97,88.4 158.3,88.4 158.63,88.73 159.47,88.73 159.78,88.42 165.28,88.42 165.99,87.71 166.94,87.71 167.05,87.82 167.05,88.49 167.16,88.6 167.38,88.6 167.49,88.49 167.49,87.82 167.6,87.71 167.82,87.71 167.93,87.82 167.93,88.49 168.03,88.6 168.25,88.6 168.36,88.49 168.36,87.82 168.47,87.71 169.31,87.71 170.3,88.71 170.3,89.13 170.41,89.24 170.63,89.24 170.74,89.13 170.74,88.71 170.85,88.6 171.07,88.6 171.18,88.71 171.18,89.13 171.29,89.24 171.51,89.24 171.61,89.13 171.61,88.71 171.72,88.6 171.94,88.6 172.05,88.71 172.05,89 172.16,89.11 172.38,89.11 172.49,89 172.49,88.71 172.6,88.6 172.83,88.6 176.46,84.97 178.59,84.97 179.04,85.43 182.88,85.43 183.87,86.42 183.87,87.84 183.54,88.17 v7(183.54,89.36)
EMU7: length 71.4
  TOP w0.173: R716.1 v7(135,102.44) ; J18.29 180.22,90.12 179.86,90.48 v7(179.86,90.63)
  L3_SIG1 w0.109: v7(135,102.44) 136.03,102.44 136.14,102.56 136.14,102.96 136.26,103.08 136.42,103.08 136.54,102.96 136.54,102.56 136.66,102.44 136.82,102.44 136.94,102.56 136.94,102.96 137.05,103.08 137.22,103.08 137.33,102.96 137.33,102.56 137.45,102.44 152.53,102.44 153.95,101.02 155.35,101.02 156.97,99.4 159.26,99.4 159.89,100.03 175.01,100.03 176.02,99.01 178.69,99.01 179.96,97.74 180.98,97.74 181.74,96.98 181.74,96.29 181.63,96.18 180.58,96.18 180.47,96.07 180.47,95.85 180.58,95.74 181.63,95.74 181.74,95.63 181.74,95.41 181.63,95.3 180.58,95.3 180.47,95.19 180.47,94.97 180.58,94.87 181.63,94.87 181.74,94.76 181.74,94.54 181.63,94.43 180.58,94.43 180.47,94.32 180.47,94.1 180.58,93.99 181.63,93.99 181.74,93.88 181.74,93.66 181.63,93.56 180.7,93.56 180.59,93.45 180.59,93.23 180.7,93.12 181.63,93.12 181.74,93.01 181.74,92.51 v7(179.86,90.63)
EMU8: length 71
  TOP w0.173: J18.31 181.13,89.62 181.12,89.62 v7(179.86,89.62) ; R717.1 v7(135,103.71)
  L3_SIG1 w0.109: v7(135,103.71) 137.75,103.71 137.86,103.6 137.86,103.12 137.98,103 138.14,103 138.26,103.12 138.26,103.6 138.37,103.71 138.58,103.71 139.47,102.82 152.78,102.82 154.15,101.45 155.55,101.45 157.15,99.85 158.95,99.85 159.77,100.67 176.9,100.67 177.01,100.56 177.01,99.63 177.12,99.52 177.34,99.52 177.45,99.63 177.45,100.56 177.56,100.67 177.78,100.67 177.89,100.56 177.89,99.63 177.99,99.52 178.21,99.52 178.32,99.63 178.32,100.56 178.43,100.67 178.65,100.67 178.76,100.56 178.76,99.63 178.87,99.52 179.09,99.52 179.2,99.63 179.2,100.56 179.31,100.67 180.21,100.67 180.91,99.97 180.91,99.2 182.37,97.74 182.37,92.13 v7(179.86,89.62)
EMU9: length 77.3
  TOP w0.173: J18.33 179.59,89.12 179.1,89.62 v7(179.1,90.12) ; R718.1 v7(135,98.13)
  L3_SIG1 w0.109: v7(179.1,90.12) 179.1,91.04 179.83,91.78 179.83,92.97 177.4,95.4 177.4,95.56 178.05,96.2 178.05,96.35 177.89,96.51 177.74,96.51 177.09,95.86 176.94,95.86 176.33,96.47 175.9,96.47 175.13,97.24 174.29,97.24 174.18,97.35 174.18,98.02 174.07,98.13 173.85,98.13 173.75,98.02 173.75,97.35 173.64,97.24 173.42,97.24 173.31,97.35 173.31,98.02 173.2,98.13 172.98,98.13 172.87,98.02 172.87,97.35 172.76,97.24 170.56,97.24 169.74,98.05 155.88,98.05 155.24,98.68 153.49,98.68 152.15,100.03 149.98,100.03 149.58,100.44 149.12,100.44 149.01,100.33 149.01,99.89 148.9,99.78 148.69,99.78 148.58,99.89 148.58,100.33 148.47,100.44 148.25,100.44 148.14,100.33 148.14,99.89 148.03,99.78 147.81,99.78 147.7,99.89 147.7,100.33 147.59,100.44 147.13,100.44 146.99,100.3 146.99,99.87 146.85,99.73 146.65,99.73 146.51,99.87 146.51,100.46 146.3,100.67 145.44,100.67 145.07,100.3 145.07,99.87 144.93,99.73 144.73,99.73 144.59,99.87 144.59,100.3 144.45,100.44 144.25,100.44 144.11,100.3 144.11,99.87 143.97,99.73 143.77,99.73 143.63,99.87 143.63,100.3 143.49,100.44 143.17,100.44 143.06,100.33 143.06,99.76 142.95,99.65 142.73,99.65 142.62,99.76 142.62,100.33 142.51,100.44 142.29,100.44 142.19,100.33 142.19,99.76 142.08,99.65 141.86,99.65 141.75,99.76 141.75,100.33 141.64,100.44 141.42,100.44 141.31,100.33 141.31,99.76 141.2,99.65 140.98,99.65 140.87,99.76 140.87,100.33 140.77,100.44 140.55,100.44 140.44,100.33 140.44,99.76 140.33,99.65 140.11,99.65 140,99.76 140,100.33 139.89,100.44 139.67,100.44 139.56,100.33 139.56,99.76 139.45,99.65 139.24,99.65 139.13,99.76 139.13,100.33 139.02,100.44 138.8,100.44 138.69,100.33 138.69,99.76 138.58,99.65 138.36,99.65 138.25,99.76 138.25,100.33 138.14,100.44 137.93,100.44 137.82,100.33 137.82,99.76 137.71,99.65 137.49,99.65 137.38,99.76 137.38,100.33 137.27,100.44 136.89,100.44 135,98.55 v7(135,98.13)
EMU10: length 80
  TOP w0.173: v7(134.64,93.11) 134.32,92.79 R719.1 ; v7(178.28,88.09) 178.81,88.62 J18.35
  L3_SIG1 w0.109: v7(134.64,93.11) 134.64,93.95 134.84,94.15 135.21,94.15 135.82,93.54 135.82,93.11 136.04,92.89 136.04,92.65 136.15,92.54 136.37,92.54 136.48,92.65 136.48,92.89 136.59,93 136.81,93 136.92,92.89 136.92,92.65 137.03,92.54 137.24,92.54 137.35,92.65 137.35,92.89 137.46,93 137.68,93 137.79,92.89 137.79,92.65 137.9,92.54 138.12,92.54 138.23,92.65 138.23,92.89 138.34,93 138.56,93 139.25,92.31 139.48,92.31 139.59,92.2 139.59,91.88 139.7,91.78 139.92,91.78 140.02,91.88 140.02,92.2 140.13,92.31 140.35,92.31 140.46,92.2 140.46,91.88 140.57,91.78 140.79,91.78 140.9,91.88 140.9,92.2 141.01,92.31 141.23,92.31 141.34,92.2 141.34,91.88 141.44,91.78 141.66,91.78 141.77,91.88 141.77,92.2 141.88,92.31 142.23,92.31 142.37,92.17 142.37,91.81 142.51,91.67 142.71,91.67 142.85,91.81 142.85,92.29 142.99,92.44 143.19,92.44 143.33,92.29 143.33,91.81 143.47,91.67 143.67,91.67 143.81,91.81 143.81,92.29 143.95,92.44 144.15,92.44 144.29,92.29 144.29,91.81 144.43,91.67 144.63,91.67 144.77,91.81 144.77,92.42 144.91,92.56 145.11,92.56 145.25,92.42 145.25,91.81 145.39,91.67 145.59,91.67 145.73,91.81 145.73,92.4 145.87,92.54 146.07,92.54 146.21,92.4 146.21,91.81 146.35,91.67 146.55,91.67 146.69,91.81 146.69,92.47 146.83,92.61 147.03,92.61 147.17,92.47 147.17,91.81 147.31,91.67 147.51,91.67 147.65,91.81 147.65,92.45 147.79,92.59 147.99,92.59 148.13,92.45 148.13,91.81 148.27,91.67 148.47,91.67 148.61,91.81 148.61,92.17 148.75,92.31 149.08,92.31 149.19,92.42 149.19,92.81 149.3,92.92 149.52,92.92 149.63,92.81 149.63,92.42 149.74,92.31 149.96,92.31 150.07,92.42 150.07,92.81 150.18,92.92 150.39,92.92 150.5,92.81 150.5,92.42 150.61,92.31 150.83,92.31 150.94,92.42 150.94,92.81 151.05,92.92 151.27,92.92 151.38,92.81 151.38,92.42 151.49,92.31 151.7,92.31 151.81,92.42 151.81,92.81 151.92,92.92 152.14,92.92 152.25,92.81 152.25,92.42 152.36,92.31 152.58,92.31 152.69,92.42 152.69,92.81 152.8,92.92 153.01,92.92 153.12,92.81 153.12,92.42 153.23,92.31 154.58,92.31 154.69,92.42 154.69,93.93 154.8,94.04 155.02,94.04 155.13,93.93 155.13,92.42 155.24,92.31 155.46,92.31 155.57,92.42 155.57,93.93 155.68,94.04 155.89,94.04 156,93.93 156,92.42 156.11,92.31 156.33,92.31 156.44,92.42 156.44,93.32 156.55,93.43 156.77,93.43 156.88,93.32 156.88,92.42 156.99,92.31 165.07,92.31 165.74,91.65 166.37,91.65 167.13,92.41 173.96,92.41 v7(178.28,88.09)
EMU11: length 95
  TOP w0.173: v7(136.27,96.35) 135.76,96.86 129.67,96.86 129.16,96.35 R720.1 ; J18.37 v7(179.86,88.12)
  L3_SIG1 w0.109: v7(136.27,96.35) 136.27,94.8 137.01,94.06 138.29,94.06 138.56,94.32 138.56,96.14 138.92,96.5 139.28,96.5 139.39,96.39 139.39,95.69 139.5,95.59 139.71,95.59 139.82,95.69 139.82,96.39 139.93,96.5 140.15,96.5 140.26,96.39 140.26,95.69 140.37,95.59 140.59,95.59 140.7,95.69 140.7,96.39 140.81,96.5 141.02,96.5 141.13,96.39 141.13,95.69 141.24,95.59 141.46,95.59 141.57,95.69 141.57,96.39 141.68,96.5 141.92,96.5 142.03,96.38 142.03,95.7 142.15,95.59 142.85,95.59 142.97,95.7 142.97,96.38 143.08,96.5 143.25,96.5 143.36,96.38 143.36,95.7 143.48,95.59 143.64,95.59 143.76,95.7 143.76,96.38 143.88,96.5 144.04,96.5 144.16,96.38 144.16,95.7 144.27,95.59 144.44,95.59 144.55,95.7 144.55,96.38 144.67,96.5 144.83,96.5 144.95,96.38 144.95,95.7 145.06,95.59 145.23,95.59 145.34,95.7 145.34,96.38 145.46,96.5 145.62,96.5 145.74,96.38 145.74,95.7 145.86,95.59 146.02,95.59 146.14,95.7 146.14,96.38 146.25,96.5 146.52,96.5 146.64,96.38 146.64,96.18 146.75,96.07 146.92,96.07 147.03,96.18 147.03,96.38 147.15,96.5 147.31,96.5 147.43,96.38 147.43,96.18 147.55,96.07 147.71,96.07 147.83,96.18 147.83,96.38 147.94,96.5 148.59,96.5 149.2,97.11 151.29,97.11 152.81,95.59 154.4,95.59 154.51,95.69 154.51,96.11 154.62,96.22 154.84,96.22 154.95,96.11 154.95,95.69 155.06,95.59 155.28,95.59 155.39,95.69 155.39,96.11 155.5,96.22 155.71,96.22 155.82,96.11 155.82,95.69 155.93,95.59 156.15,95.59 156.26,95.69 156.26,96.11 156.37,96.22 156.59,96.22 156.7,96.11 156.7,95.69 157.32,95.08 158.75,95.08 159.64,94.19 159.97,94.19 160.08,94.3 160.08,95.09 160.19,95.2 160.4,95.2 160.51,95.09 160.51,94.3 160.62,94.19 160.84,94.19 160.95,94.3 160.95,95.09 161.06,95.2 161.28,95.2 161.39,95.09 161.39,94.3 161.5,94.19 161.71,94.19 161.82,94.3 161.82,95.09 161.93,95.2 162.15,95.2 162.26,95.09 162.26,94.3 162.37,94.19 162.59,94.19 162.7,94.3 162.7,95.09 162.81,95.2 163.03,95.2 163.13,95.09 163.13,94.3 163.24,94.19 163.46,94.19 163.57,94.3 163.57,95.09 163.68,95.2 163.9,95.2 164.01,95.09 164.01,94.3 164.12,94.19 164.34,94.19 164.45,94.3 164.45,95.09 164.55,95.2 164.77,95.2 164.88,95.09 164.88,94.3 164.99,94.19 165.21,94.19 165.32,94.3 165.32,95.09 165.43,95.2 165.65,95.2 165.76,95.09 165.76,94.3 165.87,94.19 166.37,94.19 167.39,95.2 174.24,95.2 177.67,91.78 177.67,90.51 179.86,88.32 v7(179.86,88.12)
EMU12: length 78.1
  TOP w0.173: R721.1 v7(135,99.4) ; v7(179.36,87.62) J18.39
  L3_SIG1 w0.109: v7(135,99.4) 134.32,98.71 134.32,95.76 134.62,95.46 135.13,95.46 136.88,93.71 138.46,93.71 138.99,94.24 139.38,94.24 139.49,94.35 139.49,95.09 139.6,95.2 139.82,95.2 139.93,95.09 139.93,94.35 140.03,94.24 140.25,94.24 140.36,94.35 140.36,95.09 140.47,95.2 140.69,95.2 140.8,95.09 140.8,94.35 140.91,94.24 143.57,94.24 143.89,94.56 143.89,95.07 144,95.18 144.17,95.18 144.28,95.07 144.28,94.56 144.4,94.44 144.56,94.44 144.68,94.56 144.68,95.07 144.79,95.18 144.96,95.18 145.07,95.07 145.07,94.56 145.19,94.44 145.35,94.44 145.47,94.56 145.47,95.07 145.59,95.18 145.75,95.18 145.87,95.07 145.87,94.56 145.98,94.44 146.15,94.44 146.26,94.56 146.26,95.07 146.38,95.18 146.54,95.18 146.66,95.07 146.66,94.56 146.78,94.44 146.94,94.44 147.06,94.56 147.06,94.94 147.32,95.2 148.21,95.2 148.48,94.93 148.92,94.93 149.66,94.19 151.28,94.19 152.17,95.08 156.59,95.08 157.86,93.81 167.33,93.81 167.44,93.92 167.44,94.71 167.54,94.82 167.76,94.82 167.87,94.71 167.87,93.92 167.98,93.81 168.2,93.81 168.31,93.92 168.31,94.71 168.42,94.82 168.64,94.82 168.75,94.71 168.75,93.92 168.86,93.81 169.07,93.81 169.18,93.92 169.18,94.71 169.29,94.82 169.51,94.82 169.62,94.71 169.62,93.92 169.73,93.81 170.83,93.81 170.99,93.97 170.99,94.68 171.15,94.84 171.38,94.84 171.54,94.68 171.54,93.97 171.7,93.81 171.92,93.81 172.08,93.97 172.08,94.68 172.24,94.84 172.47,94.84 172.63,94.68 172.63,93.97 172.79,93.81 173.01,93.81 173.17,93.97 173.17,94.68 173.33,94.84 173.56,94.84 173.72,94.68 173.72,93.97 173.88,93.81 174.67,93.81 175.8,92.68 175.8,91.75 179.36,88.18 v7(179.36,87.62)
EMU13: length 81.4
  TOP w0.173: R722.1 v7(135.64,91.52) ; J18.41 v7(183.12,87.12)
  L3_SIG1 w0.109: v7(183.12,87.12) 182.23,86.24 176.86,86.24 176.35,86.75 176.35,86.9 176.61,87.16 176.61,87.32 176.46,87.47 176.3,87.47 176.04,87.21 175.89,87.21 175.73,87.37 175.73,87.52 175.99,87.78 175.99,87.94 175.84,88.09 175.69,88.09 175.42,87.83 175.27,87.83 173.45,89.65 173.45,89.81 173.86,90.22 173.86,90.38 173.71,90.53 173.55,90.53 173.14,90.12 172.98,90.12 172.49,90.61 165.82,90.61 164.82,89.61 163.83,89.61 162.94,90.51 162.32,90.51 162.21,90.61 162.21,91.28 162.11,91.39 161.89,91.39 161.78,91.28 161.78,90.61 161.67,90.51 161.45,90.51 161.34,90.61 161.34,91.28 161.23,91.39 161.01,91.39 160.9,91.28 160.9,90.61 160.79,90.51 160.58,90.51 160.47,90.61 160.47,91.28 160.36,91.39 160.14,91.39 160.03,91.28 160.03,90.61 159.92,90.51 159.7,90.51 159.59,90.61 159.59,91.28 159.48,91.39 159.27,91.39 159.16,91.28 159.16,90.61 159.05,90.51 158.83,90.51 158.72,90.61 158.72,91.28 158.61,91.39 158.39,91.39 158.28,91.28 158.28,90.61 158.17,90.51 157.96,90.51 157.85,90.61 157.85,91.28 157.74,91.39 157.52,91.39 157.41,91.28 157.41,90.61 157.3,90.51 157.08,90.51 156.97,90.61 156.97,91.28 156.86,91.39 156.64,91.39 156.54,91.28 156.54,90.61 156.43,90.51 156.21,90.51 156.1,90.61 156.1,91.28 155.99,91.39 155.77,91.39 155.66,91.28 155.66,90.61 155.55,90.51 155.33,90.51 155.22,90.61 155.22,91.28 155.12,91.39 154.9,91.39 154.79,91.28 154.79,90.61 154.68,90.51 154.46,90.51 154.35,90.61 154.35,91.28 154.24,91.39 154.02,91.39 153.91,91.28 153.91,90.61 153.8,90.51 153.59,90.51 153.48,90.61 153.48,91.28 153.37,91.39 153.15,91.39 153.04,91.28 153.04,90.61 152.93,90.51 152.71,90.51 152.6,90.61 152.6,91.28 152.49,91.39 152.28,91.39 152.17,91.28 152.17,90.61 152.06,90.51 151.84,90.51 151.73,90.61 151.73,91.28 151.62,91.39 151.4,91.39 151.29,91.28 151.29,90.61 151.18,90.51 150.97,90.51 150.86,90.61 150.86,91.28 150.75,91.39 150.53,91.39 150.42,91.28 150.42,90.61 150.31,90.51 150.09,90.51 149.98,90.61 149.98,91.28 149.87,91.39 149.65,91.39 149.55,91.28 149.55,90.61 149.28,90.35 139.47,90.35 138.3,91.52 v7(135.64,91.52)
EMU14: length 80.7
  TOP w0.173: J18.43 180.14,86.62 v7(179.71,87.05) ; R723.1 v7(135,94.95)
  L3_SIG1 w0.109: v7(179.71,87.05) 179.22,87.05 178.77,87.51 178.77,88.27 174.12,92.92 173.1,92.92 172.99,93.03 172.99,93.32 172.88,93.43 172.66,93.43 172.55,93.32 172.55,93.03 172.44,92.92 172.22,92.92 172.11,93.03 172.11,93.32 172,93.43 171.79,93.43 171.68,93.32 171.68,93.03 171.57,92.92 171.35,92.92 171.24,93.03 171.24,93.32 171.13,93.43 170.91,93.43 170.8,93.32 170.8,93.03 170.69,92.92 170.48,92.92 170.37,93.03 170.37,93.32 170.26,93.43 170.04,93.43 169.93,93.32 169.93,93.03 169.82,92.92 169.6,92.92 169.49,93.03 169.49,93.32 169.38,93.43 169.17,93.43 169.06,93.32 169.06,93.03 168.95,92.92 168.73,92.92 168.62,93.03 168.62,93.32 168.51,93.43 168.29,93.43 168.18,93.32 168.18,93.03 168.07,92.92 167.85,92.92 167.75,93.03 167.75,93.32 167.64,93.43 167.42,93.43 167.31,93.32 167.31,93.03 167.2,92.92 166.98,92.92 166.87,93.03 166.87,93.32 166.76,93.43 166.54,93.43 166.43,93.32 166.43,93.03 166.33,92.92 166.11,92.92 166,93.03 166,93.32 165.89,93.43 165.67,93.43 165.56,93.32 165.56,93.03 165.45,92.92 165.23,92.92 165.12,93.03 165.12,93.32 165.01,93.43 164.8,93.43 164.69,93.32 164.69,93.03 164.58,92.92 164.36,92.92 164.25,93.03 164.25,93.32 164.14,93.43 163.92,93.43 163.81,93.32 163.81,93.03 163.7,92.92 163.49,92.92 163.38,93.03 163.38,93.32 163.27,93.43 163.05,93.43 162.94,93.32 162.94,93.03 162.83,92.92 162.61,92.92 162.5,93.03 162.5,93.32 162.39,93.43 162.18,93.43 162.07,93.32 162.07,93.03 161.96,92.92 161.74,92.92 161.63,93.03 161.63,93.32 161.52,93.43 161.3,93.43 161.19,93.32 161.19,93.03 161.08,92.92 160.86,92.92 160.76,93.03 160.76,93.32 160.65,93.43 160.43,93.43 160.32,93.32 160.32,93.03 160.21,92.92 159.99,92.92 159.88,93.03 159.88,93.32 159.77,93.43 159.55,93.43 159.44,93.32 159.44,93.03 159.34,92.92 159.12,92.92 159.01,93.03 159.01,93.32 158.9,93.43 158.68,93.43 158.57,93.32 158.57,93.03 158.46,92.92 157.86,92.92 156.21,94.57 152.53,94.57 151.51,93.55 148.77,93.55 148.44,93.88 148.03,93.88 147.89,93.74 147.89,93.13 147.75,92.99 147.55,92.99 147.41,93.13 147.41,93.74 147.27,93.88 147.07,93.88 146.93,93.74 146.93,93.13 146.79,92.99 146.59,92.99 146.45,93.13 146.45,93.74 146.31,93.88 146.11,93.88 145.97,93.74 145.97,93.13 145.83,92.99 145.63,92.99 145.49,93.13 145.49,93.74 145.35,93.88 145.15,93.88 145.01,93.74 145.01,93.13 144.87,92.99 144.67,92.99 144.53,93.13 144.53,93.74 144.39,93.88 144.19,93.88 144.05,93.74 144.05,92.96 143.91,92.82 143.71,92.82 143.57,92.96 143.57,93.74 143.43,93.88 143.23,93.88 143.09,93.74 143.09,92.93 142.95,92.79 142.75,92.79 142.61,92.93 142.61,93.74 142.47,93.88 142.27,93.88 142.13,93.74 142.13,93.13 141.76,92.77 141.33,92.77 141.22,92.87 141.22,93.7 141.11,93.81 140.89,93.81 140.78,93.7 140.78,92.87 140.68,92.77 140.46,92.77 140.35,92.87 140.35,93.7 140.24,93.81 140.02,93.81 139.91,93.7 139.91,92.87 139.8,92.77 139.47,92.77 139.33,92.91 139.33,93.21 139.19,93.35 136.6,93.35 v7(135,94.95)
EMU15: length 96.1
  TOP w0.173: v7(183.03,86.31) 182.84,86.12 J18.45 ; v7(135.73,90.35) 132.36,90.35 132.16,90.55 126.32,90.55 R724.1
  L3_SIG1 w0.109: v7(183.03,86.31) 182.6,85.88 176.5,85.88 172.64,89.75 172,89.75 171.89,89.86 171.89,90.14 171.78,90.25 171.57,90.25 171.46,90.14 171.46,89.86 171.35,89.75 171.13,89.75 171.02,89.86 171.02,90.14 170.91,90.25 170.69,90.25 170.58,90.14 170.58,89.86 170.47,89.75 170.26,89.75 170.15,89.86 170.15,90.14 170.04,90.25 169.82,90.25 169.71,90.14 169.71,89.86 169.6,89.75 169.38,89.75 169.27,89.86 169.27,90.14 169.16,90.25 168.95,90.25 168.84,90.14 168.84,89.86 168.73,89.75 168.51,89.75 168.4,89.86 168.4,90.14 168.29,90.25 168.07,90.25 167.96,90.14 167.96,89.86 167.85,89.75 167.62,89.75 166.7,88.82 165.76,88.82 165.48,89.11 163.7,89.11 162.81,90 162.46,90 162.35,89.89 162.35,88.89 162.24,88.78 162.02,88.78 161.91,88.89 161.91,89.89 161.8,90 161.59,90 161.48,89.89 161.48,88.89 161.37,88.78 161.15,88.78 161.04,88.89 161.04,89.89 160.93,90 160.71,90 160.6,89.89 160.6,88.89 160.49,88.78 160.27,88.78 160.17,88.89 160.17,89.89 160.06,90 159.26,90 158.68,89.42 158.13,89.42 158.02,89.53 158.02,90.01 157.91,90.12 157.69,90.12 157.58,90.01 157.58,89.53 157.47,89.42 157.25,89.42 157.14,89.53 157.14,90.01 157.03,90.12 156.82,90.12 156.71,90.01 156.71,89.53 156.6,89.42 156.38,89.42 156.27,89.53 156.27,90.01 156.16,90.12 155.94,90.12 155.83,90.01 155.83,89.53 155.72,89.42 155.5,89.42 155.4,89.53 155.4,90.01 155.29,90.12 155.07,90.12 154.96,90.01 154.96,89.53 154.85,89.42 154.63,89.42 154.52,89.53 154.52,90.01 154.41,90.12 154.19,90.12 154.08,90.01 154.08,89.32 153.98,89.21 153.76,89.21 153.65,89.32 153.65,90.01 153.54,90.12 153.32,90.12 153.21,90.01 153.21,89.32 153.1,89.21 152.88,89.21 152.77,89.32 152.77,90.01 152.66,90.12 152.45,90.12 152.34,90.01 152.34,89.32 152.23,89.21 152.01,89.21 151.9,89.32 151.9,90.01 151.79,90.12 151.57,90.12 151.46,90.01 151.46,89.32 151.35,89.21 151.14,89.21 151.03,89.32 151.03,90.01 150.92,90.12 150.7,90.12 150.59,90.01 150.59,89.32 150.48,89.21 150.26,89.21 150.15,89.32 150.15,90.01 150.04,90.12 149.82,90.12 149.72,90.01 149.72,89.32 149.61,89.21 149.39,89.21 149.28,89.32 149.28,89.89 149.17,90 148.95,90 148.84,89.89 148.84,89.32 148.73,89.21 148.51,89.21 148.41,89.32 148.41,89.89 148.3,90 148.08,90 147.97,89.89 147.97,89.53 147.86,89.42 147.64,89.42 147.53,89.53 147.53,89.89 147.42,90 147.2,90 147.09,89.89 147.09,89.53 146.99,89.42 146.77,89.42 146.66,89.53 146.66,89.89 146.55,90 146.33,90 146.22,89.89 146.22,89.53 146.11,89.42 145.89,89.42 145.78,89.53 145.78,89.89 145.67,90 145.46,90 145.35,89.89 145.35,89.53 145.24,89.42 145.02,89.42 144.91,89.53 144.91,89.89 144.8,90 144.58,90 144.47,89.89 144.47,89.53 144.36,89.42 144.15,89.42 144.04,89.53 144.04,89.89 143.93,90 143.71,90 143.6,89.89 143.6,89.53 143.49,89.42 143.27,89.42 143.16,89.53 143.16,89.89 143.05,90 141.11,90 140.98,89.86 140.98,89.53 140.87,89.42 140.65,89.42 140.54,89.53 140.54,89.86 140.41,90 140.21,90 140.1,89.89 140.1,89.53 140,89.42 139.69,89.42 138.22,90.89 136.27,90.89 v7(135.73,90.35)
EMU16: length 79
  TOP w0.173: R725.1 v7(135.38,86.82) ; J18.47 183.35,85.62 v7(183.54,85.43)
  L3_SIG1 w0.109: v7(135.38,86.82) 135.38,87.46 135.84,87.91 136.8,87.91 137.59,87.13 137.59,83.3 137.92,82.97 138.4,82.97 138.51,83.08 138.51,83.79 138.62,83.9 138.83,83.9 138.94,83.79 138.94,83.08 139.05,82.97 139.27,82.97 139.38,83.08 139.38,83.79 139.49,83.9 139.71,83.9 139.82,83.79 139.82,83.08 139.93,82.97 140.14,82.97 140.25,83.08 140.25,83.79 140.36,83.9 140.58,83.9 140.69,83.79 140.69,83.08 140.8,82.97 141.02,82.97 141.13,83.08 141.13,83.79 141.24,83.9 141.46,83.9 141.56,83.79 141.56,83.08 141.67,82.97 141.89,82.97 142,83.08 142,83.79 142.11,83.9 142.33,83.9 142.44,83.79 142.44,83.08 142.55,82.97 142.77,82.97 142.88,83.08 142.88,83.79 142.98,83.9 143.2,83.9 143.31,83.79 143.31,83.08 143.42,82.97 143.64,82.97 143.75,83.08 143.75,83.79 143.86,83.9 144.08,83.9 144.19,83.79 144.19,83.08 144.29,82.97 144.51,82.97 144.62,83.08 144.62,83.79 144.73,83.9 144.95,83.9 145.06,83.79 145.06,83.08 145.17,82.97 145.39,82.97 145.5,83.08 145.5,83.79 145.61,83.9 145.82,83.9 145.93,83.79 145.93,83.08 146.04,82.97 146.26,82.97 146.37,83.08 146.37,83.79 146.48,83.9 146.7,83.9 146.81,83.79 146.81,83.08 146.92,82.97 147.13,82.97 147.24,83.08 147.24,83.79 147.35,83.9 147.57,83.9 147.68,83.79 147.68,83.08 147.79,82.97 155.28,82.97 157.58,85.27 159.84,85.27 160.38,85.81 170.43,85.81 171.45,84.79 173.74,84.79 174.73,83.8 182.96,83.8 183.72,84.56 183.72,85.25 v7(183.54,85.43)
EMU17: length 96.9
  TOP w0.173: R726.1 129.54,88.73 130.18,88.09 132.05,88.09 132.33,87.81 134.61,87.81 135,88.19 135.74,88.19 v7(136.27,88.73) ; J18.49 180.06,85.12 179.68,84.74 v7(179.68,84.26)
  L3_SIG1 w0.109: v7(179.68,84.26) 175.41,84.26 173.61,86.06 170.82,86.06 170.56,86.31 160.1,86.31 159.48,85.7 156.48,85.7 156.26,85.92 156.26,86.2 156.15,86.31 155.94,86.31 155.83,86.2 155.83,85.92 155.72,85.81 155.19,85.81 154.43,85.04 153.94,85.04 153.83,85.15 153.83,86.08 153.72,86.19 153.51,86.19 153.4,86.08 153.4,85.15 153.29,85.04 153.07,85.04 152.96,85.15 152.96,86.08 152.85,86.19 152.63,86.19 152.52,86.08 152.52,85.15 152.41,85.04 152.2,85.04 152.09,85.15 152.09,86.08 151.98,86.19 151.76,86.19 151.65,86.08 151.65,85.15 151.54,85.04 151.32,85.04 151.21,85.15 151.21,86.08 151.1,86.19 150.88,86.19 150.78,86.08 150.78,85.15 150.67,85.04 150.45,85.04 150.34,85.15 150.34,86.08 150.23,86.19 150.01,86.19 149.9,86.08 149.9,85.15 149.79,85.04 149.57,85.04 149.47,85.15 149.47,86.08 149.36,86.19 149.14,86.19 149.03,86.08 149.03,85.15 148.92,85.04 148.7,85.04 148.59,85.15 148.59,86.08 148.48,86.19 148.26,86.19 148.15,86.08 148.15,85.15 148.05,85.04 147.83,85.04 147.72,85.15 147.72,86.08 147.61,86.19 147.39,86.19 147.28,86.08 147.28,85.15 147.17,85.04 146.95,85.04 146.84,85.15 146.84,86.08 146.73,86.19 146.52,86.19 146.41,86.08 146.41,85.15 146.3,85.04 146.08,85.04 145.97,85.15 145.97,86.08 145.86,86.19 145.64,86.19 145.53,86.08 145.53,85.15 145.42,85.04 145.21,85.04 145.1,85.15 145.1,86.08 144.99,86.19 144.77,86.19 144.66,86.08 144.66,85.15 144.55,85.04 144.33,85.04 144.22,85.15 144.22,86.08 144.11,86.19 143.89,86.19 143.79,86.08 143.79,85.15 143.68,85.04 143.46,85.04 143.35,85.15 143.35,86.08 143.24,86.19 143.02,86.19 142.91,86.08 142.91,85.15 142.8,85.04 142.58,85.04 142.47,85.15 142.47,86.08 142.37,86.19 142.15,86.19 142.04,86.08 142.04,85.15 141.93,85.04 141.71,85.04 141.6,85.15 141.6,86.08 141.49,86.19 141.27,86.19 141.16,86.08 141.16,85.15 141.06,85.04 140.84,85.04 140.73,85.15 140.73,86.08 140.62,86.19 140.4,86.19 140.29,86.08 140.29,85.15 140.18,85.04 139.96,85.04 139.85,85.15 139.85,86.08 139.74,86.19 139.53,86.19 139.42,86.08 139.42,85.15 139.31,85.04 138.81,85.04 137.95,85.91 137.95,88.32 137.54,88.73 v7(136.27,88.73)
EMU18: length 95.2
  TOP w0.173: R727.1 131.85,90 132.23,89.62 v7(136.65,89.62) ; J18.51 v7(183.16,84.62)
  L3_SIG1 w0.109: v7(136.65,89.62) 137.19,89.08 137.9,89.08 138.39,88.59 138.39,86.86 138.56,86.7 138.9,86.7 139.01,86.8 139.01,87.73 139.12,87.84 139.34,87.84 139.44,87.73 139.44,86.8 139.55,86.7 139.77,86.7 139.88,86.8 139.88,87.73 139.99,87.84 140.21,87.84 140.32,87.73 140.32,86.8 140.43,86.7 140.65,86.7 140.76,86.8 140.76,87.73 140.86,87.84 141.08,87.84 141.19,87.73 141.19,86.8 141.3,86.7 141.52,86.7 141.63,86.8 141.63,87.73 141.74,87.84 141.96,87.84 142.07,87.73 142.07,86.8 142.18,86.7 142.39,86.7 142.5,86.8 142.5,87.73 142.61,87.84 142.83,87.84 142.94,87.73 142.94,86.8 143.05,86.7 143.27,86.7 143.38,86.8 143.38,87.73 143.49,87.84 143.7,87.84 143.81,87.73 143.81,86.8 143.92,86.7 144.14,86.7 144.25,86.8 144.25,87.73 144.36,87.84 144.58,87.84 144.69,87.73 144.69,86.8 144.8,86.7 145.01,86.7 145.12,86.8 145.12,87.73 145.23,87.84 145.45,87.84 145.56,87.73 145.56,86.8 145.67,86.7 146.56,86.7 146.76,86.89 146.76,87.86 146.87,87.97 147.09,87.97 147.19,87.86 147.19,87.19 147.3,87.08 147.52,87.08 147.63,87.19 147.63,87.86 147.74,87.97 147.96,87.97 148.07,87.86 148.07,87.19 148.18,87.08 148.4,87.08 148.5,87.19 148.5,87.86 148.61,87.97 148.83,87.97 148.94,87.86 148.94,87.19 149.05,87.08 149.27,87.08 149.38,87.19 149.38,87.86 149.49,87.97 149.71,87.97 149.82,87.86 149.82,87.19 149.92,87.08 150.14,87.08 150.25,87.19 150.25,87.6 150.36,87.71 150.58,87.71 150.69,87.6 150.69,87.19 150.8,87.08 151.48,87.08 151.58,87.19 151.58,87.86 151.69,87.97 151.91,87.97 152.02,87.86 152.02,87.19 152.13,87.08 152.35,87.08 152.46,87.19 152.46,87.86 152.57,87.97 152.79,87.97 152.9,87.86 152.9,87.19 153,87.08 153.98,87.08 154.09,87.19 154.09,87.86 154.2,87.97 154.42,87.97 154.53,87.86 154.53,87.19 154.64,87.08 156.17,87.08 156.28,87.19 156.28,87.86 156.39,87.97 156.61,87.97 156.72,87.86 156.72,87.19 156.83,87.08 157.05,87.08 157.16,87.19 157.16,87.86 157.26,87.97 157.48,87.97 157.59,87.86 157.59,87.19 157.7,87.08 159.26,87.08 159.89,87.71 160.74,87.71 160.99,87.46 161.54,87.46 161.95,87.86 164.83,87.86 165.48,87.2 173.61,87.2 176.2,84.61 178.79,84.61 179.22,85.04 182.74,85.04 v7(183.16,84.62)
EMU19: length 96.7
  TOP w0.173: v7(183.67,83.77) 183,83.77 182.65,84.12 J18.53 ; R728.1 v7(136.27,87.46)
  L3_SIG1 w0.109: v7(183.67,83.77) 183.34,83.44 174.57,83.44 173.74,84.28 171.2,84.28 170.05,85.43 160.5,85.43 159.91,84.84 158.8,84.84 156.59,82.63 154.18,82.63 153.29,81.74 149.61,81.74 148.34,80.47 148.14,80.47 148.03,80.58 148.03,81.25 147.92,81.36 147.7,81.36 147.59,81.25 147.59,80.58 147.48,80.47 147.27,80.47 147.16,80.58 147.16,81.25 147.05,81.36 146.83,81.36 146.72,81.25 146.72,80.58 146.61,80.47 146.39,80.47 146.28,80.58 146.28,81.25 146.17,81.36 145.96,81.36 145.85,81.25 145.85,80.58 145.74,80.47 145.52,80.47 145.41,80.58 145.41,81.25 145.3,81.36 145.08,81.36 144.97,81.25 144.97,80.58 144.86,80.47 144.64,80.47 144.54,80.58 144.54,81.25 144.43,81.36 144.21,81.36 144.1,81.25 144.1,80.58 143.99,80.47 143.77,80.47 143.66,80.58 143.66,81.25 143.55,81.36 143.33,81.36 143.22,81.25 143.22,80.58 143.12,80.47 142.9,80.47 142.79,80.58 142.79,81.25 142.68,81.36 142.46,81.36 142.35,81.25 142.35,80.58 142.24,80.47 142.02,80.47 141.91,80.58 141.91,81.25 141.8,81.36 141.59,81.36 141.48,81.25 141.48,80.58 141.37,80.47 141.15,80.47 141.04,80.58 141.04,81.25 140.93,81.36 140.71,81.36 140.6,81.25 140.6,80.58 140.49,80.47 140.28,80.47 140.17,80.58 140.17,81.25 140.06,81.36 139.84,81.36 139.73,81.25 139.73,80.58 139.62,80.47 139.4,80.47 139.29,80.58 139.29,81.25 139.18,81.36 138.96,81.36 138.86,81.25 138.86,80.58 138.75,80.47 138.53,80.47 138.42,80.58 138.42,81.25 138.31,81.36 138.09,81.36 137.98,81.25 137.98,80.58 137.87,80.47 137.54,80.47 137.21,80.8 137.21,81.03 137.1,81.13 136.13,81.13 136.02,81.24 136.02,81.46 136.13,81.57 137.1,81.57 137.21,81.68 137.21,81.9 137.1,82.01 136,82.01 135.89,82.12 135.89,82.34 136,82.45 137.1,82.45 137.21,82.55 137.21,82.77 137.1,82.88 136.13,82.88 136.02,82.99 136.02,83.21 136.13,83.32 137.1,83.32 137.21,83.43 137.21,83.65 137.1,83.76 136.13,83.76 136.02,83.86 136.02,84.08 136.13,84.19 137.1,84.19 137.21,84.3 137.21,86.52 v7(136.27,87.46)
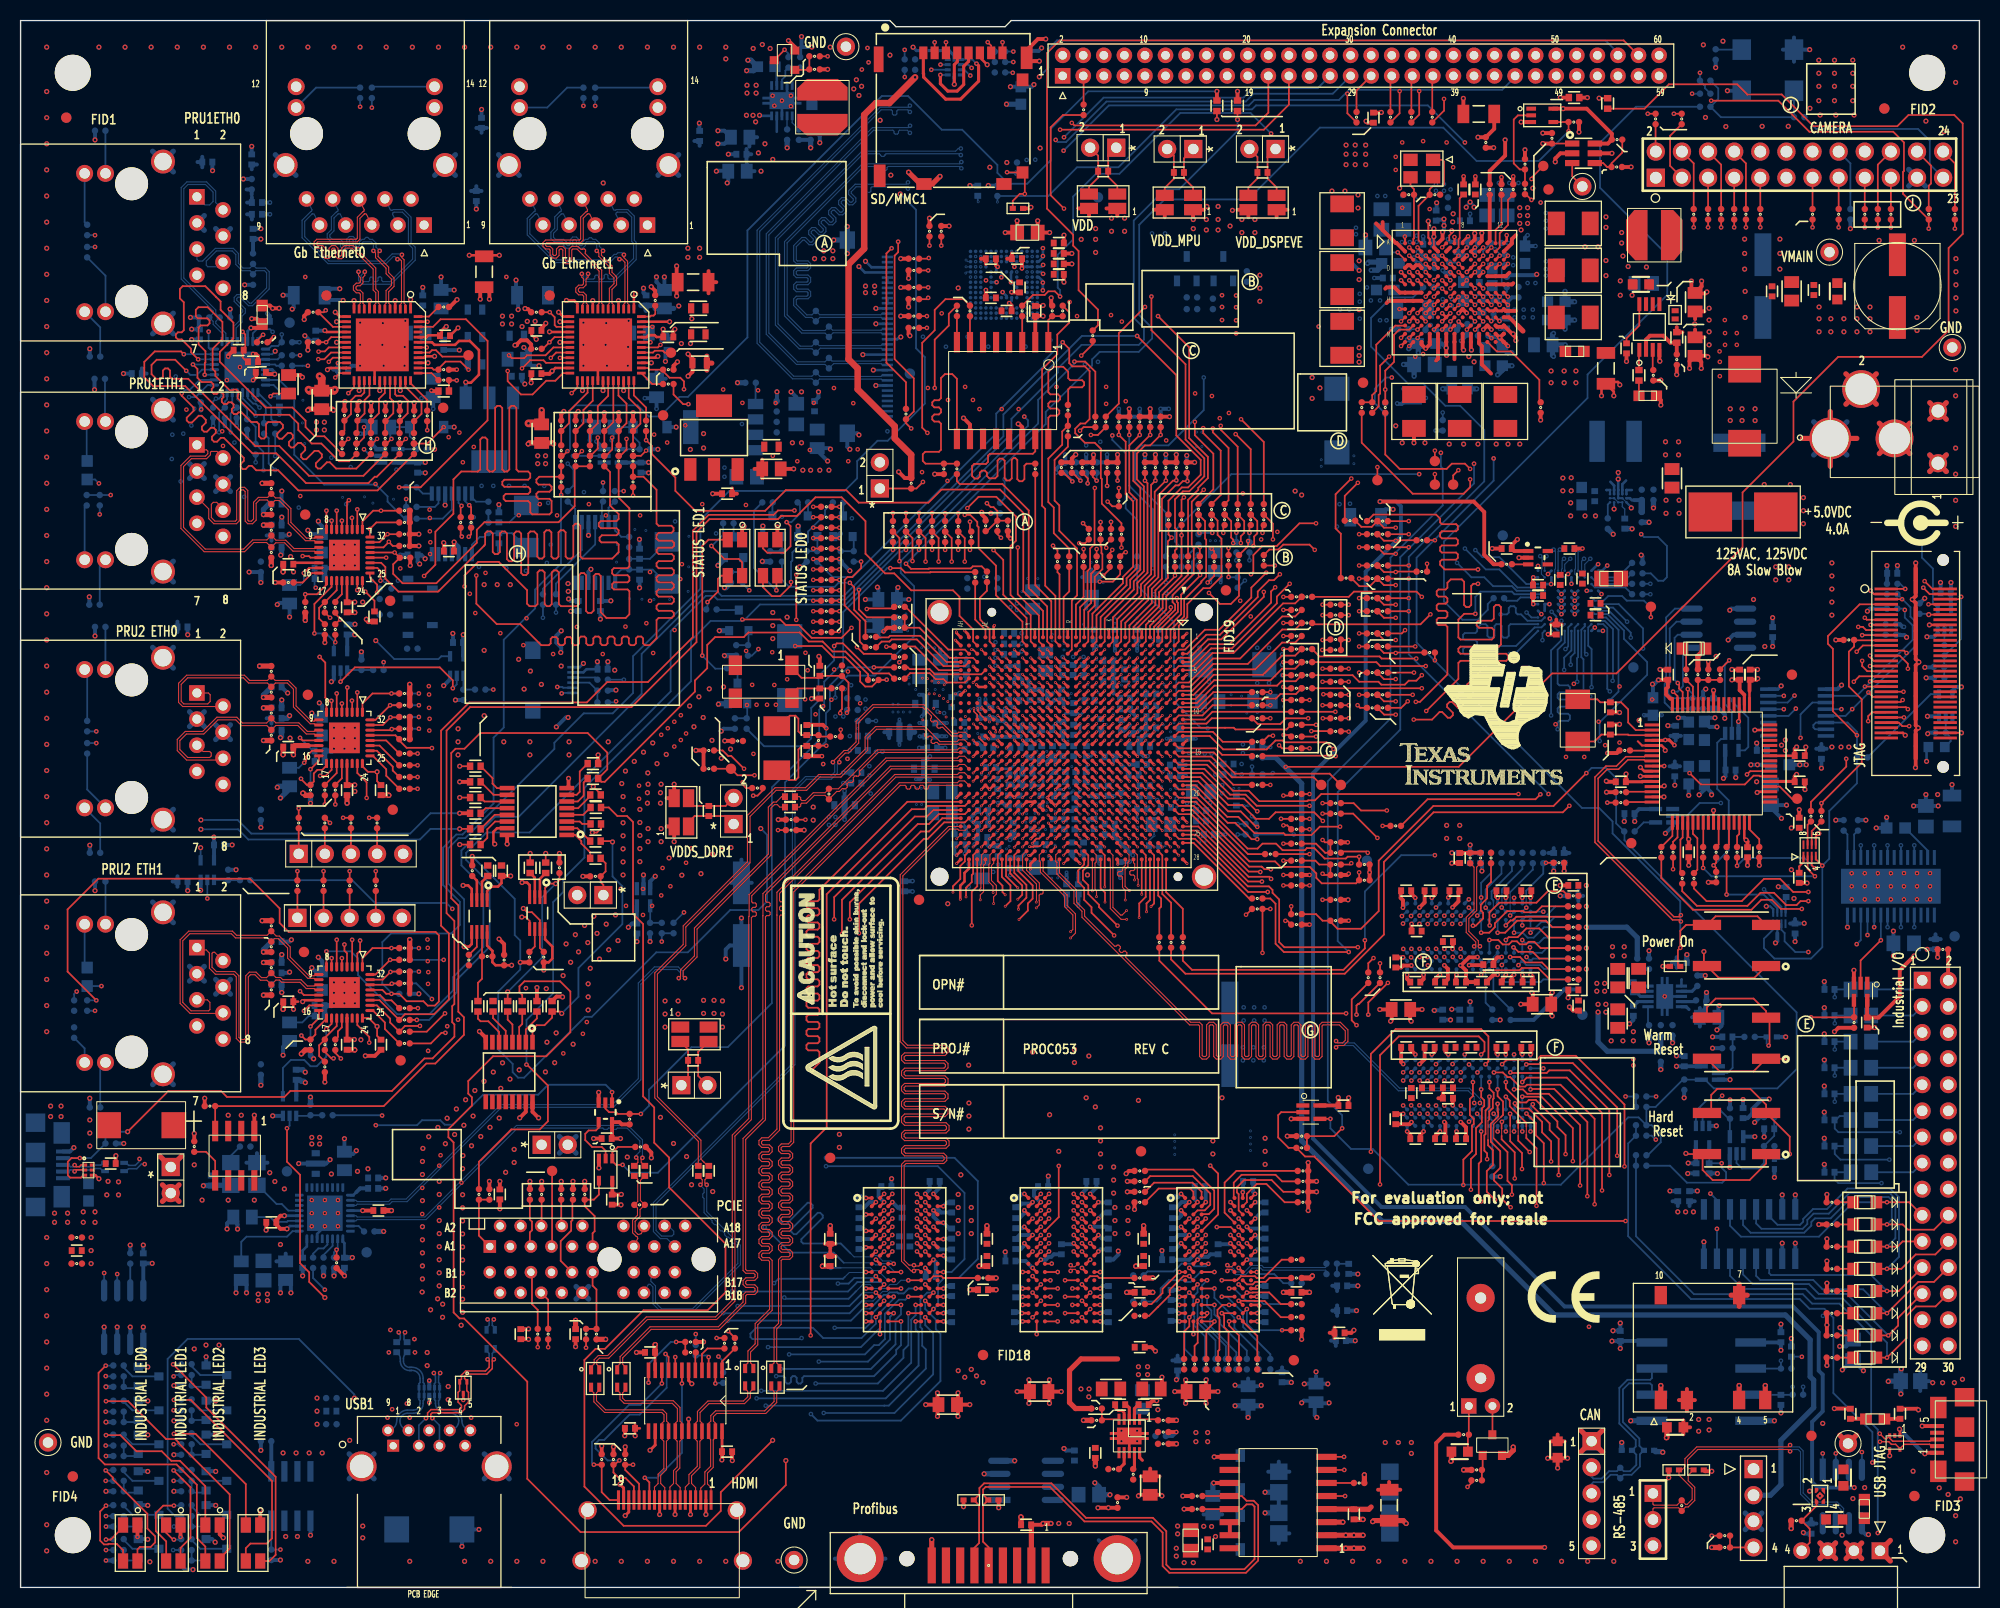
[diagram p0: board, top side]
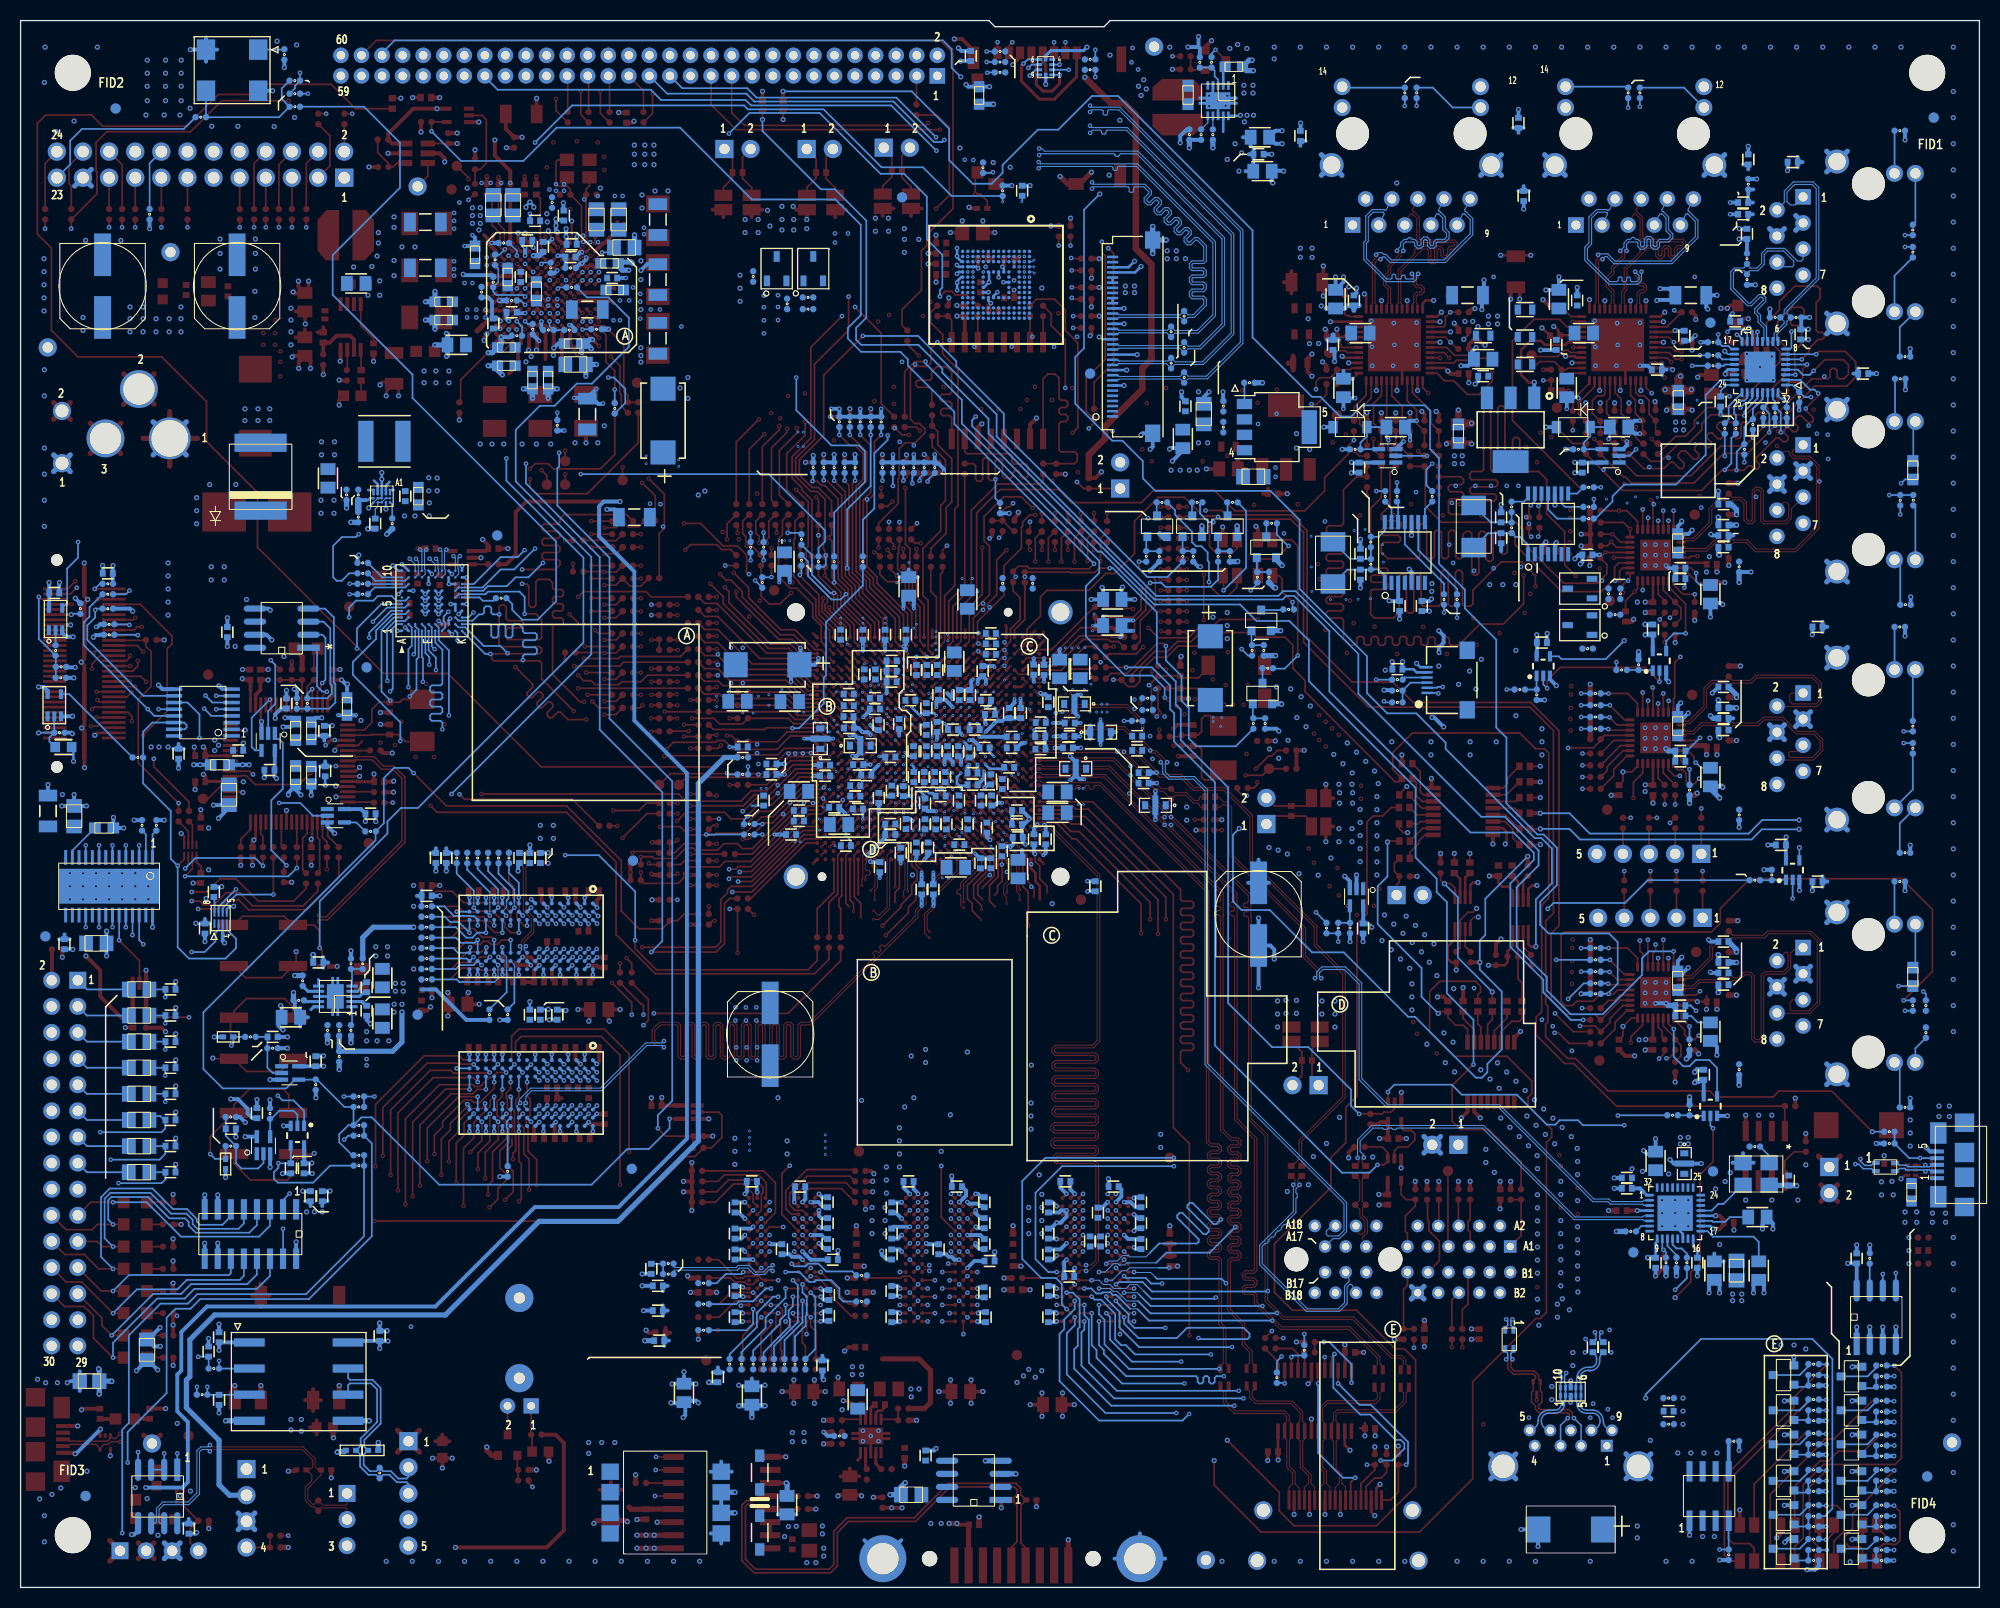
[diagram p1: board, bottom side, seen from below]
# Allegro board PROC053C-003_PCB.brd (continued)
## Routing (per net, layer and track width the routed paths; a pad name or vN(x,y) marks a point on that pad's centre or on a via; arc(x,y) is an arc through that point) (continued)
EMU_RSTN: length 10.2
  TOP w0.173: v2(188.72,96.35) 188.49,96.12 J18.6
  BOTTOM w0.173: R450.1 187.07,88.5 C223.1 187.07,90.61 R429.2 188.72,92.26 v2(188.72,96.35)
EMU_USB_DM: length 96.2
  TOP w0.15: 182.77,13.5 183.19,13.92 185.65,13.92 185.83,13.75 J19.2 ; 182.77,13.5 182.35,13.92 181.94,13.92 181.69,14.17 v7(180.82,14.17) ; 182.77,13.5 U36.5 ; v7(161.46,64.77) 161.31,64.93 160.66,64.93 153.11,72.47 153.11,78.82 154.18,79.89 155.2,79.89 156.11,80.8 157.91,80.8 158,80.89 U37.7
  L3_SIG1 w0.109: v7(161.46,64.77) 161.62,64.93 162.51,64.93 164.29,63.15 169.75,63.15 170.46,63.86 172.59,63.86 178.05,58.4 178.05,16.18 179.82,14.41 180.56,14.41 180.8,14.17 v7(180.82,14.17)
EMU_USB_DP: length 95.4
  TOP w0.15: U37.8 157.99,80.39 157.89,80.49 156.31,80.49 155.4,79.58 154.3,79.58 153.42,78.69 153.42,72.6 160.78,65.23 161.31,65.23 v7(161.46,65.38) ; J19.3 185.84,14.4 185.67,14.23 182.06,14.23 181.77,14.52 U36.3 181.48,14.48 181.28,14.48 v7(180.8,14.96)
  L3_SIG1 w0.109: v7(161.46,65.38) 161.62,65.23 162.64,65.23 164.41,63.45 169.62,63.45 170.33,64.17 172.72,64.17 178.36,58.53 178.36,16.31 179.95,14.72 180.56,14.72 v7(180.8,14.96)
ETH0_LDO_O: length 12.1
  TOP w0.254: U21.43 40.01,121.11 40.26,120.86 42.26,120.86 42.64,121.24 43.69,121.24 44.58,120.35 44.58,117.95 43.8,117.18 43.34,117.18 v1(43.29,117.22)
  BOTTOM w0.381: v1(43.29,117.22) Q7.1
ETH0_MDC: length 3.6
  TOP w0.173: R294.1 39.55,115.5 37.93,117.12 U21.36
ETH0_MDIO: length 2.3
  TOP w0.173: U21.37 39.96,118.11 R295.1
ETH0_RXCLK: length 6.1
  TOP w0.173: U21.35 37.43,116.78 38.99,115.22 38.99,114.15 R317.2 38.25,113.42 R288.1
ETH0_RXD0: length 5.6
  TOP w0.173: R289.1 35.46,113.42 R299.2 36.25,114.21 36.25,115.37 35.93,115.69 U21.32
ETH0_RXD1: length 5.7
  TOP w0.173: U21.31 35.43,116.18 34.85,115.6 34.85,114.2 R301.2 34.06,113.42 R290.1
ETH0_RXD2: length 5.6
  TOP w0.173: U21.28 33.93,115.96 33.45,115.48 33.45,114.18 R306.2 32.77,112.37 R291.1
ETH0_RXD3: length 6.3
  TOP w0.173: U21.27 33.43,116.21 33.12,115.91 32.58,115.91 32.13,115.45 32.13,114.13 R309.2 31.5,112.5 R292.1
ETH0_RXDV: length 6.3
  TOP w0.173: R285.1 36.86,113.42 R304.2 37.65,114.21 37.65,115.45 37.19,115.91 36.58,115.91 36.43,116.05 U21.33
ETH0_TXCLK: length 70.3
  TOP w0.173: U21.24 31.03,118.11 v7(30.61,117.68) ; R281.1 v7(84.84,104.5)
  L3_SIG1 w0.109: v5(84.84,105.11) v7(84.84,104.5) ; v7(30.61,117.68) v5(29.97,117.68)
  L10_SIG4 w0.109: v5(29.97,117.68) 30.23,117.43 40.64,117.43 42.42,115.65 59.98,115.65 61.95,113.68 78.9,113.68 79.01,113.57 79.01,113.02 79.12,112.91 79.33,112.91 79.44,113.02 79.44,113.57 79.55,113.68 79.77,113.68 79.88,113.57 79.88,113.02 79.99,112.91 80.21,112.91 80.32,113.02 80.32,113.57 80.43,113.68 82.24,113.68 85.9,110.01 85.9,106.18 v5(84.84,105.11)
ETH0_TXD0: length 72.7
  TOP w0.173: U21.19 29.98,120.61 29.59,120.22 29.01,120.22 v7(28.98,120.2) ; R282.1 v7(86.11,104.5)
  L3_SIG1 w0.109: v5(86.11,105.11) v7(86.11,104.5) ; v7(28.98,120.2) v5(29.59,120.2)
  L10_SIG4 w0.109: v5(86.11,105.11) 86.82,105.82 86.82,110.77 82.95,114.64 62.6,114.64 60.32,116.92 52.07,116.92 51.71,116.56 44.68,116.56 43.28,117.96 41.5,117.96 41.3,118.17 33.04,118.17 33.01,118.14 31.04,118.14 29.59,119.59 v5(29.59,120.2)
ETH0_TXD1: length 81.2
  TOP w0.173: U21.20 30.19,120.11 29.54,119.46 v7(28.96,119.46) ; v7(91.19,104.48) R287.1
  L3_SIG1 w0.109: v7(28.96,119.46) v5(28.32,119.46) ; v5(91.19,105.11) v7(91.19,104.48)
  L10_SIG4 w0.109: v5(28.32,119.46) 28.32,119.78 29.2,120.65 30.43,120.65 30.81,120.27 35.66,120.27 36.53,121.14 38.15,121.14 38.51,120.78 41.25,120.78 42.16,119.87 45.31,119.87 45.89,119.29 51.96,119.29 52.91,118.34 62.89,118.34 64.03,117.2 65.39,117.2 66.02,117.83 66.69,117.83 66.8,117.94 66.8,118.26 66.91,118.37 67.13,118.37 67.24,118.26 67.24,117.94 67.35,117.83 67.57,117.83 67.68,117.94 67.68,118.26 67.79,118.37 68,118.37 68.11,118.26 68.11,117.94 68.22,117.83 84.13,117.83 89.71,112.25 89.71,106.59 v5(91.19,105.11)
ETH0_TXD2: length 71.6
  TOP w0.173: R283.1 v7(87.38,104.5) ; U21.21 30.37,119.61 v7(29.97,119.21)
  L3_SIG1 w0.109: v7(29.97,119.21) v5(30.48,119.72) ; v5(87.38,105.11) v7(87.38,104.5)
  L10_SIG4 w0.109: v5(87.38,105.11) 87.3,105.19 87.3,111.25 83.43,115.12 67.69,115.12 67.18,115.63 62.28,115.63 60.53,117.38 50.22,117.38 49.68,117.91 45.24,117.91 44.23,118.92 41.39,118.92 41.1,118.62 39.01,118.62 38.29,119.34 32.76,119.34 32.01,118.6 31.27,118.6 30.48,119.39 v5(30.48,119.72)
ETH0_TXD3: length 74.8
  TOP w0.173: U21.22 30.89,119.11 v7(30.86,119.08) ; R284.1 v7(88.65,104.5)
  L3_SIG1 w0.109: v5(88.65,105.11) v7(88.65,104.5) ; v7(30.86,119.08) v5(31.5,119.08)
  L10_SIG4 w0.109: v5(31.5,119.08) 32.23,119.82 38.46,119.82 38.67,119.6 39.37,119.6 40.04,120.27 40.87,120.27 41.76,119.38 45.03,119.38 46.02,118.39 49.89,118.39 50.44,117.84 61.85,117.84 63.62,116.07 66.44,116.07 66.55,116.17 66.55,116.81 66.66,116.92 66.87,116.92 66.98,116.81 66.98,116.17 67.09,116.07 67.31,116.07 67.42,116.17 67.42,116.81 67.53,116.92 67.75,116.92 67.86,116.81 67.86,116.17 67.97,116.07 72.54,116.07 73.03,115.57 80.24,115.57 81.11,116.44 84.37,116.44 87.88,112.93 87.88,111.03 88.39,110.52 88.39,107.5 88.65,107.24 v5(88.65,105.11)
ETH0_TXEN: length 73.9
  TOP w0.173: v2(31.88,116.16) 32.43,116.71 U21.25 ; R286.1 v7(89.92,104.48)
  L3_SIG1 w0.109: v5(89.92,105.11) v7(89.92,104.48)
  L10_SIG4 w0.109: v5(89.92,105.11) 89.13,104.32 84.38,104.32 81.46,107.24 81.46,109.16 78.43,112.19 77.94,112.19 77.82,112.08 77.82,110.76 77.71,110.65 77.54,110.65 77.43,110.76 77.43,112.08 77.31,112.19 77.14,112.19 77.03,112.08 77.03,110.76 76.91,110.65 76.75,110.65 76.63,110.76 76.63,112.08 76.52,112.19 74.43,112.19 73.91,112.7 73.26,112.7 72.72,112.16 67.56,112.16 67.12,111.71 66.28,111.71 65.83,112.16 61.54,112.16 60.71,112.99 54.2,112.99 53.31,113.87 50.47,113.87 49.94,114.41 40.79,114.41 40.51,114.13 38.71,114.13 37.01,115.83 32.77,115.83 32.44,116.16 v2(31.88,116.16)
ETH0GB_25MHZCLK: length 27.6
  TOP w0.173: v2(36.82,107) 38.9,107 45.42,113.52 45.42,121.24 43.31,123.35 40.84,123.35 40.1,122.61 U21.46
  BOTTOM w0.173: R315.2 v2(36.82,107)
ETH1_LDO_O: length 14.3
  TOP w0.254: U24.43 v7(61.26,121.11)
  L3_SIG1 w0.381: v7(61.26,121.11) v5(60.66,121.11)
  L9_SIG3 w0.381: v5(60.66,121.11) 60.52,120.97 60.52,120.29
  L9_SIG3 w0.635: 60.52,120.29 60.52,114.54 64.38,110.68 v1(65.14,110.68)
ETH1_MDC: length 4.4
  TOP w0.173: U24.36 59.65,115.94 60.83,114.76 R338.1
ETH1_MDIO: length 2.6
  TOP w0.173: U24.37 61.43,117.05 R339.1
ETH1_RESETN: length 26
  TOP w0.173: v7(62.23,120.86) 61.98,120.61 U24.42
  L3_SIG1 w0.109: v7(62.23,120.86) v5(62.81,120.86)
  L9_SIG3 w0.114: v5(62.81,120.86) 61.82,120.86 61.01,121.67 59,121.67 58.08,120.75 58.08,115.89 58.98,114.99 58.98,113.31 58.22,112.55 v5(58.22,111.59)
  L10_SIG4 w0.109: v9(57.47,111.59) v5(58.22,111.59)
  BOTTOM w0.173: U26.4 59.65,110.71 59.67,110.7 R324.1 60.2,111.33 59.56,111.97 D4.2 C189.1 57.67,111.78 v9(57.47,111.59)
ETH1_RXCLK: length 7.1
  TOP w0.173: U24.35 59.15,115.69 60.28,114.56 60.28,113.19 R361.2 R328.1
ETH1_RXD0: length 6.7
  TOP w0.173: R333.1 R343.2 57.65,113.35 U24.32
ETH1_RXD1: length 7
  TOP w0.173: R334.1 R345.2 56.13,113.24 56.13,114.89 57.15,115.9 U24.31
ETH1_RXD2: length 7
  TOP w0.173: U24.28 55.65,115.42 54.74,114.52 54.74,113.24 R352.2 R335.1
ETH1_RXD3: length 7.4
  TOP w0.173: R336.1 R353.2 53.34,113.24 53.34,114.41 55.15,116.22 U24.27
ETH1_RXDV: length 6.9
  TOP w0.173: R329.1 R348.2 58.93,113.24 58.93,115.14 58.15,115.93 U24.33
ETH1_TXCLK: length 100.3
  TOP w0.173: U24.24 52.75,118.11 52.01,117.37 51.12,117.37 49.78,116.03 48.67,116.03 47.37,117.33 v7(47.37,118.32) ; R325.1 119.63,110.71 v7(118.17,112.17)
  L3_SIG1 w0.109: v7(118.17,112.17) 118.17,112.91 106.86,124.21 90.18,124.21 89.74,124.65 87.7,124.65 87.23,125.13 83.15,125.13 83.12,125.1 68.43,125.1 68.3,125.23 68.3,125.75 68.19,125.86 68.02,125.86 67.91,125.75 67.91,125.23 67.77,125.1 67.58,125.1 67.47,125.21 67.47,125.75 67.36,125.86 67.14,125.86 67.04,125.75 67.04,125.23 66.9,125.1 66.71,125.1 66.6,125.21 66.6,125.75 66.49,125.86 66.27,125.86 66.16,125.75 66.16,125.23 66.03,125.1 65.83,125.1 65.73,125.21 65.73,125.75 65.62,125.86 65.4,125.86 65.29,125.75 65.29,125.24 65.15,125.1 60.84,125.1 60.05,124.31 59.08,124.31 58.45,123.68 54.21,123.68 52.2,121.67 51.18,121.67 49.89,120.38 49.43,120.38 v7(47.37,118.32)
ETH1_TXD0: length 98.7
  TOP w0.173: v7(47.5,119.84) 47.78,119.56 48.97,119.56 49.25,119.84 51.05,119.84 51.82,120.61 U24.19 ; R330.1 120.9,111.41 v7(118.69,113.62)
  L3_SIG1 w0.109: 98.93,125.68 99.67,125.68 99.98,125.99 102.15,125.99 103.1,125.05 107.31,125.05 118.69,113.67 v7(118.69,113.62) ; 98.2,126.42 98.07,126.54 96.82,126.54 96.7,126.42 94.97,126.42 94.23,125.68 92.96,125.68 91.77,126.88 87.48,126.88 87.3,126.7 86.11,126.7 85.76,127.05 64.47,127.05 63.42,128.1 61.16,128.1 58.75,125.68 51.43,125.68 49.63,123.88 49.36,123.88 48.21,122.73 48.21,122.17 47.5,121.46 v7(47.5,119.84)
  L3_SIG1 w0.114: 98.2,126.42 98.93,125.68
ETH1_TXD1: length 106.1
  TOP w0.173: U24.20 52.08,120.11 v7(51.56,119.59) ; R331.1 116.71,106.25 116.71,110.57 115.01,112.27 v7(115.01,112.76)
  L3_SIG1 w0.109: v7(51.56,119.59) 51.56,119.24 50.77,118.45 50.77,117.71 50.89,117.59 51.8,117.59 51.91,117.48 51.91,117.32 51.78,117.2 50.85,117.2 50.73,117.08 50.73,116.92 50.85,116.8 52.04,116.8 52.16,116.68 52.16,116.52 52.04,116.4 50.85,116.4 50.73,116.29 50.73,115.84 51.02,115.55 52.26,115.55 53.24,116.52 53.24,116.69 52.14,117.79 52.14,117.95 52.26,118.07 52.42,118.07 53.52,116.97 53.68,116.97 53.8,117.08 53.8,117.25 52.7,118.35 52.7,118.51 52.82,118.63 52.98,118.63 54.08,117.53 54.24,117.53 54.36,117.64 54.36,117.81 53.29,118.88 53.29,119.07 53.39,119.18 53.55,119.18 54.64,118.09 54.81,118.09 56.18,119.46 57.68,119.46 57.79,119.34 57.79,118.94 57.91,118.83 58.07,118.83 58.19,118.94 58.19,119.34 58.31,119.46 59.2,119.46 59.31,119.58 59.31,120.01 59.43,120.12 59.59,120.12 59.71,120.01 59.71,119.58 59.82,119.46 59.99,119.46 60.11,119.58 60.11,120.46 60.22,120.58 60.39,120.58 60.5,120.46 60.5,119.58 60.62,119.46 60.93,119.46 61.88,120.4 62.99,120.4 64.11,121.52 64.74,121.52 66.07,122.84 72.16,122.84 72.78,122.22 78.71,122.22 79.04,121.89 79.49,121.44 82.42,121.44 83.11,120.75 89.78,120.75 90.55,121.52 100.28,121.52 100.79,122.03 104.72,122.03 106.31,120.44 107.96,120.44 115.01,113.39 v7(115.01,112.76)
ETH1_TXD2: length 102.2
  TOP w0.173: R327.1 117.47,105.75 117.47,110.83 115.95,112.35 v7(115.95,112.72) ; U24.21 52.47,119.61 v7(52.45,119.59)
  L3_SIG1 w0.109: v7(52.45,119.59) 53.22,119.59 53.33,119.7 53.33,119.85 53.45,119.97 53.61,119.97 53.73,119.85 53.73,119.7 53.85,119.58 54.27,119.58 54.89,120.2 55.35,120.2 55.46,120.31 55.46,120.87 55.58,120.99 55.74,120.99 55.86,120.87 55.86,120.31 55.97,120.2 57.96,120.2 58.12,120.36 58.12,120.52 57.94,120.7 57.94,120.89 58.05,121 58.2,121 58.4,120.8 58.57,120.8 58.9,121.14 59.26,121.14 59.43,120.97 59.59,120.97 59.7,121.08 59.7,121.26 59.54,121.41 59.54,121.68 59.69,121.82 62.17,121.82 62.28,121.7 62.28,121.53 62.4,121.42 62.56,121.42 62.68,121.53 62.68,121.7 62.79,121.82 62.96,121.82 63.07,121.7 63.07,121.56 63.18,121.45 63.34,121.45 63.47,121.58 63.47,121.76 63.59,121.87 63.8,121.87 64.74,122.81 65.4,122.81 66.02,123.43 73.18,123.43 73.29,123.32 73.29,122.87 73.4,122.76 73.62,122.76 73.73,122.87 73.73,123.32 73.84,123.43 74.06,123.43 74.17,123.32 74.17,122.87 74.28,122.76 74.49,122.76 74.6,122.87 74.6,123.32 74.71,123.43 74.93,123.43 75.04,123.32 75.04,122.87 75.15,122.76 75.37,122.76 75.48,122.87 75.48,123.32 75.59,123.43 75.81,123.43 75.91,123.32 75.91,122.87 76.02,122.76 76.24,122.76 76.35,122.87 76.35,123.32 76.46,123.43 76.68,123.43 76.79,123.32 76.79,122.87 76.9,122.76 77.12,122.76 77.22,122.87 77.22,123.32 77.33,123.43 77.55,123.43 77.66,123.32 77.66,122.87 77.77,122.76 77.99,122.76 78.1,122.87 78.1,123.32 78.21,123.43 78.43,123.43 78.54,123.32 78.54,122.87 78.64,122.76 78.86,122.76 78.97,122.87 78.97,123.32 79.08,123.43 79.3,123.43 79.41,123.32 79.41,122.87 79.52,122.76 79.74,122.76 79.85,122.87 79.85,123.32 79.96,123.43 80.17,123.43 80.28,123.32 80.28,122.87 80.39,122.76 80.61,122.76 80.72,122.87 80.72,123.32 80.83,123.43 81.05,123.43 81.16,123.32 81.16,122.87 81.27,122.76 81.48,122.76 81.59,122.87 81.59,123.32 81.7,123.43 81.92,123.43 82.03,123.32 82.03,122.87 82.14,122.76 82.36,122.76 82.47,122.87 82.47,123.32 82.58,123.43 84.17,123.43 84.91,122.69 87.48,122.69 87.77,122.97 88.66,122.97 88.78,122.86 88.78,122.59 88.9,122.47 89.06,122.47 89.18,122.59 89.18,122.81 89.29,122.92 89.46,122.92 89.57,122.81 89.57,122.59 89.69,122.47 89.85,122.47 89.97,122.59 89.97,122.81 90.08,122.92 90.25,122.92 90.36,122.81 90.36,122.59 90.48,122.47 90.64,122.47 90.76,122.59 90.76,122.81 90.88,122.92 91.04,122.92 91.16,122.81 91.16,122.59 91.27,122.47 91.44,122.47 91.55,122.59 91.55,122.81 91.67,122.92 91.83,122.92 91.95,122.81 91.95,122.59 92.07,122.47 92.23,122.47 92.35,122.59 92.35,122.81 92.46,122.92 92.63,122.92 92.74,122.81 92.74,122.59 92.86,122.47 93.02,122.47 93.14,122.59 93.14,122.81 93.25,122.92 93.42,122.92 93.53,122.81 93.53,122.59 93.65,122.47 93.81,122.47 93.93,122.59 93.93,122.81 94.05,122.92 94.21,122.92 94.33,122.81 94.33,122.59 94.44,122.47 94.61,122.47 94.72,122.59 94.72,122.81 94.84,122.92 95,122.92 95.12,122.81 95.12,122.59 95.24,122.47 95.4,122.47 95.52,122.59 95.52,122.81 95.63,122.92 95.8,122.92 95.91,122.81 95.91,122.54 96.03,122.42 96.25,122.42 96.37,122.31 96.37,122.09 96.49,121.98 96.65,121.98 96.77,122.09 96.77,122.31 96.88,122.42 97.14,122.42 97.59,121.98 100.08,121.98 100.58,122.48 105.03,122.48 106.41,121.11 107.93,121.11 115.95,113.09 v7(115.95,112.72)
ETH1_TXD3: length 99.9
  TOP w0.173: R332.1 118.36,110.95 116.71,112.6 v7(116.71,112.98) ; v7(48.77,118.57) 49.56,119.36 50.85,119.36 51.1,119.11 53.42,119.11 U24.22
  L3_SIG1 w0.109: v7(116.71,112.98) 116.33,113.37 116.31,113.37 107.94,121.73 106.51,121.73 105.31,122.94 100.33,122.94 99.85,122.46 97.74,122.46 96.82,123.38 89.15,123.38 88.42,124.11 87.78,124.11 86.84,123.17 85.22,123.17 84.47,123.92 82.88,123.92 82.68,124.12 65.15,124.12 64.88,123.86 64.35,123.86 64.24,123.74 64.24,123.03 64.12,122.92 63.96,122.92 63.84,123.03 63.84,123.74 63.71,123.88 62.4,123.88 62.26,123.74 62.26,122.98 62.14,122.86 61.98,122.86 61.86,122.98 61.86,123.74 61.75,123.86 61.58,123.86 61.47,123.74 61.47,123.16 61.35,123.04 61.19,123.04 61.07,123.16 61.07,123.74 60.96,123.86 60.58,123.86 58.94,122.22 58.43,122.22 58.04,121.82 57.65,121.82 57.53,121.94 57.53,122.39 57.42,122.51 57.25,122.51 57.14,122.39 57.14,121.91 57.02,121.8 56.86,121.8 56.74,121.91 56.74,122.39 56.62,122.51 56.46,122.51 56.34,122.39 56.34,121.91 56.23,121.8 56.06,121.8 55.95,121.91 55.95,122.39 55.83,122.51 55.67,122.51 55.55,122.39 55.55,121.91 55.44,121.8 55.27,121.8 55.16,121.91 55.16,122.39 55.04,122.51 54.88,122.51 54.76,122.39 54.76,121.91 54.64,121.8 54.48,121.8 54.36,121.91 54.36,122.39 54.25,122.51 54.08,122.51 53.97,122.39 53.97,121.86 52.61,120.5 50.7,120.5 v7(48.77,118.57)
ETH1_TXEN: length 106.7
  TOP w0.173: v7(114.2,113.37) 114.2,112.07 116,110.27 116,106.81 R326.1 ; v7(53.59,116.16) 54.15,116.71 U24.25
  L3_SIG1 w0.109: v7(114.2,113.37) 114.2,113.54 107.91,119.83 106.13,119.83 104.39,121.57 100.99,121.57 99.72,120.3 99.26,120.3 99.15,120.41 99.15,120.9 99.04,121.01 98.82,121.01 98.71,120.9 98.71,120.41 98.6,120.3 98.38,120.3 98.28,120.41 98.28,120.9 98.17,121.01 97.95,121.01 97.84,120.9 97.84,120.41 97.73,120.3 97.51,120.3 97.4,120.41 97.4,120.9 97.29,121.01 97.07,121.01 96.96,120.9 96.96,120.41 96.86,120.3 96.64,120.3 96.53,120.41 96.53,120.9 96.42,121.01 96.2,121.01 96.09,120.9 96.09,120.41 95.98,120.3 95.76,120.3 95.65,120.41 95.65,120.9 95.54,121.01 95.33,121.01 95.22,120.9 95.22,120.41 95.11,120.3 94.89,120.3 94.78,120.41 94.78,120.9 94.67,121.01 94.45,121.01 94.34,120.9 94.34,120.41 94.23,120.3 94.02,120.3 93.91,120.41 93.91,120.9 93.8,121.01 93.58,121.01 93.47,120.9 93.47,120.41 93.36,120.3 93.14,120.3 93.03,120.41 93.03,120.9 92.92,121.01 92.7,121.01 92.6,120.9 92.6,120.41 92.49,120.3 92.27,120.3 92.16,120.41 92.16,120.9 92.05,121.01 91.83,121.01 91.72,120.9 91.72,120.41 91.61,120.3 91.39,120.3 91.29,120.41 91.29,120.9 91.18,121.01 90.96,121.01 90.85,120.9 90.85,120.56 90.59,120.29 82.91,120.29 82.22,120.99 79.32,120.99 78.53,121.78 71.74,121.78 71.63,121.89 71.63,122.25 71.52,122.37 71.35,122.37 71.24,122.25 71.24,121.9 71.12,121.78 70.96,121.78 70.84,121.9 70.84,122.25 70.72,122.37 70.56,122.37 70.44,122.25 70.44,121.9 70.33,121.78 70.16,121.78 70.05,121.9 70.05,122.25 69.93,122.37 69.77,122.37 69.65,122.25 69.65,121.9 69.53,121.78 69.37,121.78 69.25,121.9 69.25,122.25 69.14,122.37 68.97,122.37 68.86,122.25 68.86,121.9 68.74,121.78 68.58,121.78 68.46,121.9 68.46,122.25 68.35,122.37 68.18,122.37 68.07,122.25 68.07,121.9 67.95,121.78 67.79,121.78 67.67,121.9 67.67,122.25 67.55,122.37 67.26,122.37 66.98,122.08 66.81,122.08 66.51,122.38 66.35,122.38 66.23,122.26 66.23,122.1 66.53,121.8 66.53,121.64 66.41,121.52 66.25,121.52 65.95,121.82 65.79,121.82 65.67,121.7 65.67,121.54 65.97,121.24 65.97,121.07 65.37,120.48 64.49,120.48 63.32,119.31 63.32,118.95 62.69,118.32 60.99,118.32 60.87,118.43 60.87,118.81 60.76,118.92 60.59,118.92 60.48,118.81 60.48,118.43 60.36,118.32 60.2,118.32 60.08,118.43 60.08,118.81 59.97,118.92 59.8,118.92 59.68,118.81 59.68,118.43 59.57,118.32 58.31,118.32 58.2,118.2 58.2,117.4 58.08,117.29 57.92,117.29 57.8,117.4 57.8,118.2 57.68,118.32 57.52,118.32 57.4,118.2 57.4,116.87 57.29,116.75 57.12,116.75 57.01,116.87 57.01,118.2 56.89,118.32 56.73,118.32 56.61,118.2 56.61,117.35 56.5,117.23 56.33,117.23 56.22,117.35 56.22,118.2 56.1,118.32 55.75,118.32 55.38,117.94 55.38,117.78 55.62,117.53 55.62,117.37 55.5,117.25 55.34,117.25 55.09,117.5 54.93,117.5 v7(53.59,116.16)
ETH1GB_25MHZCLK: length 29.3
  TOP w0.173: U24.46 v7(61.44,122.61)
  L3_SIG1 w0.109: v7(61.44,122.61) 59.81,122.61 59.05,121.85 58.67,121.85 58.27,121.44 54.18,121.44 52.78,120.05 50.85,120.05 49.86,119.06 49.86,118.36 50.24,117.98 50.24,115.52 50,115.29 50,111.24 v5(50.16,111.08)
  L10_SIG4 w0.109: v9(53.21,109.3) 51.89,110.62 50.62,110.62 v5(50.16,111.08)
  BOTTOM w0.173: v9(53.21,109.3) 53.77,108.74 53.77,107.19 R359.2
ETH_MDIO_CLK: length 101
  TOP w0.173: R294.2 v2(39.55,112.55) ; U1.V1 99.43,94.98 97.52,96.9 97.52,104.52 95.25,106.78 89.56,106.78 88.29,105.51 81.51,105.51 80.29,106.73 74.42,106.73 72.41,104.71 65.62,104.71 63.68,106.65 63.68,107.95 61.39,110.24 61.39,111.03 v2(60.83,111.59) R338.2
  L4_SIG2 w0.114: v5(22.23,109.43) 36.42,109.43 v2(39.55,112.55)
  L10_SIG4 w0.109: v9(22.86,109.43) v5(22.23,109.43) ; v2(39.55,112.55) 40.59,112.55 41.91,113.87 49.68,113.87 50.24,113.31 53.06,113.31 53.82,112.55 59.87,112.55 v2(60.83,111.59)
  BOTTOM w0.173: R95.2 v9(22.86,109.43)
ETH_MDIO_DATA: length 140.1
  TOP w0.173: v2(42.42,117.4) 41.68,117.4 41.66,117.43 ; v2(85.34,130.89) 85.34,129.88 85,129.53 85,119.47 86.87,117.6 86.87,114.38 R105.2 86.11,113.24 v2(86.61,112.73) ; U1.U4 v4(99.84,90.41) ; 41.66,117.43 R295.2 ; 41.66,117.43 R279.1 ; v2(64.95,115.09) 64.44,115.09 63.5,116.03 R339.2
  L3_SIG1 w0.099: v4(99.84,90.41) 99.54,90.71 99.54,91.7 v5(99.57,91.72)
  L3_SIG1 w0.109: v2(47.24,127.46) 47.6,127.82 52.91,127.82 53.44,127.28 59.09,127.28 63.23,131.43 63.23,132.02 63.82,132.62 79.43,132.62 80.19,131.86 84.38,131.86 v2(85.34,130.89)
  L4_SIG2 w0.114: v5(99.57,91.72) 99.16,92.13 99.16,100.41 95.94,103.63 93.32,103.63 92.82,104.13 90.25,104.13 87.08,107.3 87.08,110.59 86.61,111.05 v2(86.61,112.73)
  L9_SIG3 w0.114: v2(47.24,127.46) 46.16,126.38 46.16,125.07 43.7,122.61 43.7,119.8 42.03,118.13 42.03,117.79 v2(42.42,117.4) 44.6,119.59 52.45,119.59 54.91,122.05 61.47,122.05 62.08,121.44 63.22,121.44 63.6,121.06 63.6,119.91 63.37,119.68 63.37,116.67 v2(64.95,115.09)
ETHER0_D0N: length 20.2
  TOP w0.108: v2(36.65,129.19) 36.88,129.19 37.04,129.03 37.04,124.9 36.93,124.78 U21.3
  BOTTOM w0.108: v2(36.65,129.19) 36.39,129.45 36.24,129.45 35.55,128.76 29.89,128.76 27.38,131.27 27.38,132.98 28.2,133.8 28.29,133.84 28.3,133.85 28.34,133.99 J10.10
ETHER0_D0P: length 20.1
  TOP w0.108: U21.2 37.43,124.78 37.3,124.91 37.3,129.13 37.08,129.35 v2(37.08,129.62)
  BOTTOM w0.108: 29.08,132.51 28.55,133.57 28.41,133.62 28.35,133.59 27.63,132.87 27.63,131.38 30,129.01 35.44,129.01 36.14,129.71 37,129.71 v2(37.08,129.62)
ETHER0_D1N: length 19
  TOP w0.108: v2(34.32,130) 34.52,129.8 34.52,129.34 35.54,128.31 35.54,127.78 36.07,127.26 36.07,126.65 35.54,126.13 35.54,124.91 35.43,124.79 U21.6
  BOTTOM w0.108: v2(34.32,130) 34.32,130.66 34.11,130.87 33.32,130.87 33.21,130.76 33.21,130.41 32.96,130.15 32.59,130.15 32.34,130.41 32.34,131.04 32.23,131.15 32.08,131.15 31.98,131.04 31.98,130.41 31.72,130.15 31.36,130.15 31.11,130.41 31.11,130.76 31,130.87 30.2,130.87 29.82,131.25 29.82,131.65 30.23,132.06 30.23,133.3 30.7,133.78 30.74,133.8 30.83,133.84 30.84,133.85 30.88,133.99 J10.8
ETHER0_D1P: length 19
  TOP w0.108: U21.5 35.93,124.78 35.8,124.91 35.8,126.02 36.32,126.55 36.32,127.36 35.8,127.88 35.8,128.42 34.77,129.44 34.77,129.85 v2(34.92,130)
  BOTTOM w0.108: 31.62,132.51 31.09,133.57 30.95,133.62 30.86,133.57 30.85,133.57 30.48,133.2 30.48,131.95 30.07,131.55 30.07,131.35 30.31,131.12 31.11,131.12 31.36,130.87 31.36,130.51 31.47,130.41 31.62,130.41 31.72,130.51 31.72,131.14 31.98,131.4 32.34,131.4 32.59,131.14 32.59,130.51 32.7,130.41 32.85,130.41 32.96,130.51 32.96,130.87 33.21,131.12 33.41,131.12 33.6,131.31 33.77,131.31 33.96,131.12 34.22,131.12 34.57,130.77 34.57,130.36 34.92,130.01 v2(34.92,130)
ETHER0_D2N: length 22.9
  TOP w0.108: U21.8 34.43,124.78 34.54,124.9 34.54,125.94 34.29,126.19 34.29,128.22 32.25,130.26 31.59,130.26 31.48,130.15 31.48,129.49 31.23,129.24 30.87,129.24 30.61,129.49 30.61,130.15 30.51,130.26 30.36,130.26 30.25,130.15 30.25,129.52 29.99,129.26 29.63,129.26 29.38,129.51 29.38,130.15 29.28,130.26 28.8,130.26 28.55,130.51 28.55,130.88 28.8,131.13 32.64,131.13 32.75,131.24 32.75,133.27 33.28,133.8 33.37,133.84 33.38,133.85 33.42,133.99 J10.6
ETHER0_D2P: length 22.8
  TOP w0.108: U21.7 34.93,124.79 34.8,124.92 34.8,126.04 34.54,126.3 34.54,128.33 33,129.87 33,130.02 33.04,130.06 33.04,130.21 32.93,130.31 32.78,130.31 32.75,130.28 32.6,130.28 32.36,130.51 31.48,130.51 31.23,130.26 31.23,129.6 31.12,129.49 30.97,129.49 30.87,129.6 30.87,130.26 30.61,130.51 30.25,130.51 30,130.26 30,129.63 29.88,129.52 29.73,129.52 29.64,129.61 29.64,130.26 29.38,130.51 28.91,130.51 28.8,130.62 28.8,130.77 28.91,130.88 32.75,130.88 33,131.13 33,133.16 33.43,133.59 33.49,133.62 33.63,133.57 J10.5
ETHER0_D3N: length 20
  TOP w0.108: U21.11 32.93,124.78 33.04,124.9 33.04,125.79 32.92,125.92 32.64,125.92 32.37,126.19 32.37,126.58 32.64,126.86 32.92,126.86 33.04,126.99 33.04,127.42 32.87,127.6 v2(32.87,127.97)
  BOTTOM w0.108: v2(32.87,127.97) 32.87,127.11 33.22,126.75 36.04,126.75 38.38,129.09 38.38,130.36 37.97,130.76 37.97,133.28 37.24,134.02 36.26,134.02 36.11,133.94 35.96,133.99 J10.4
ETHER0_D3P: length 20.1
  TOP w0.108: v2(33.48,127.97) 33.48,127.6 33.3,127.42 33.3,126.88 33.02,126.61 32.75,126.61 32.62,126.48 32.62,126.3 32.75,126.17 33.02,126.17 33.3,125.9 33.3,124.9 33.43,124.77 U21.10
  BOTTOM w0.108: 36.7,132.51 36.17,133.57 36.22,133.71 36.22,133.72 36.32,133.76 37.13,133.76 37.72,133.18 37.72,130.66 38.13,130.25 38.13,129.2 35.94,127.01 35.23,127.01 35.12,127.11 35.12,127.36 35.02,127.47 34.87,127.47 34.76,127.36 34.76,127.11 34.65,127.01 34.42,127.01 34.31,127.11 34.31,127.34 34.21,127.45 34.06,127.45 33.95,127.34 33.95,127.11 33.85,127.01 33.33,127.01 33.12,127.21 33.12,127.61 v2(33.48,127.97)
ETHER1_D0N: length 19.6
  TOP w0.108: v2(58.24,129.19) 58.47,129.19 58.78,128.88 58.78,124.92 58.65,124.79 U24.3
  BOTTOM w0.108: v2(58.24,129.19) 58.03,129.41 57.84,129.41 57.3,128.87 51.96,128.87 49.27,131.55 49.27,133.15 49.92,133.8 50.01,133.84 50.01,133.85 50.06,133.99 J12.10
ETHER1_D0P: length 19.6
  TOP w0.108: U24.2 59.15,124.78 59.03,124.9 59.03,128.99 58.67,129.35 v2(58.67,129.62)
  BOTTOM w0.108: v2(58.67,129.62) 58.48,129.82 58.09,129.82 57.94,129.66 57.73,129.66 57.19,129.12 52.06,129.12 49.53,131.66 49.53,133.05 50.07,133.59 50.12,133.62 50.27,133.57 J12.9
ETHER1_D1N: length 18.4
  TOP w0.108: U24.6 57.15,124.79 57.26,124.91 57.26,126.36 57.71,126.8 57.71,127.37 57.26,127.82 57.26,128.44 56.24,129.46 56.24,129.8 v2(56.03,130)
  BOTTOM w0.108: J12.8 52.6,133.99 52.55,133.85 52.55,133.84 52.46,133.8 52.42,133.78 52.39,133.75 51.94,133.3 51.94,132.19 51.57,131.82 51.57,131.21 51.92,130.87 52.72,130.87 52.83,130.76 52.83,130.51 53.08,130.26 53.44,130.26 53.7,130.51 53.7,130.99 53.8,131.09 53.95,131.09 54.06,130.99 54.06,130.51 54.31,130.26 54.67,130.26 54.93,130.51 54.93,130.76 55.03,130.87 55.83,130.87 56.03,130.66 v2(56.03,130)
ETHER1_D1P: length 18.4
  TOP w0.108: v2(56.64,130) 56.49,129.85 56.49,129.57 57.51,128.54 57.51,127.92 57.96,127.47 57.96,126.7 57.51,126.25 57.51,124.91 57.65,124.78 U24.5
  BOTTOM w0.108: v2(56.64,130) 56.64,130.09 56.29,130.44 56.29,130.77 55.94,131.12 55.67,131.12 55.52,131.27 55.31,131.27 55.16,131.12 54.93,131.12 54.67,130.87 54.67,130.62 54.57,130.51 54.42,130.51 54.31,130.62 54.31,131.09 54.06,131.35 53.7,131.35 53.44,131.09 53.44,130.62 53.34,130.51 53.19,130.51 53.08,130.62 53.08,130.87 52.82,131.12 52.02,131.12 51.83,131.31 51.83,131.71 52.2,132.08 52.2,133.2 52.57,133.57 52.57,133.57 52.66,133.62 52.81,133.57 J12.7
ETHER1_D2N: length 22.5
  TOP w0.108: J12.6 55.14,133.99 55.09,133.85 55.09,133.84 55,133.8 54.96,133.78 54.47,133.29 54.47,131.16 54.36,131.05 51.05,131.05 50.8,130.8 50.8,130.44 51.05,130.18 51.4,130.18 51.5,130.08 51.5,129.55 51.76,129.3 52.12,129.3 52.37,129.55 52.37,130.08 52.48,130.18 52.63,130.18 52.73,130.08 52.73,129 52.97,128.75 53.34,128.75 53.6,129.02 53.6,130.08 53.71,130.18 54.11,130.18 56.26,128.03 56.26,124.9 56.15,124.78 U24.8
ETHER1_D2P: length 22.5
  TOP w0.108: J12.5 55.35,133.57 55.2,133.62 55.11,133.57 55.11,133.57 54.72,133.18 54.72,131.05 54.47,130.8 51.16,130.8 51.05,130.69 51.05,130.54 51.16,130.44 51.5,130.44 51.76,130.18 51.76,129.66 51.86,129.55 52.01,129.55 52.12,129.66 52.12,130.18 52.37,130.44 52.73,130.44 52.99,130.18 52.99,129.1 53.08,129.01 53.23,129.01 53.35,129.13 53.35,130.18 53.6,130.44 54.22,130.44 54.5,130.15 54.65,130.15 54.69,130.19 54.84,130.19 54.95,130.08 54.95,129.93 54.91,129.89 54.91,129.74 56.51,128.14 56.51,124.9 56.65,124.77 U24.7
ETHER1_D3N: length 19.1
  TOP w0.108: U24.11 54.65,124.81 54.76,124.92 54.76,125.6 54.63,125.72 54.27,125.72 53.99,126 53.99,126.39 54.27,126.66 54.61,126.66 54.74,126.79 54.74,127.29 54.58,127.45 v2(54.58,127.77)
  BOTTOM w0.108: J12.4 57.68,133.99 57.83,133.94 57.89,133.97 57.93,134.02 59.05,134.02 59.69,133.38 59.69,131.02 59.87,130.84 59.87,129.15 57.73,127.01 54.98,127.01 54.76,127.23 54.76,127.59 v2(54.58,127.77)
ETHER1_D3P: length 18.9
  TOP w0.108: U24.10 55.15,124.79 55.01,124.92 55.01,125.7 54.74,125.98 54.38,125.98 54.25,126.1 54.25,126.28 54.38,126.41 54.72,126.41 54.99,126.68 54.99,127.24 55.19,127.45 v2(55.19,127.77)
  BOTTOM w0.108: v2(55.19,127.77) 55.01,127.59 55.01,127.34 55.09,127.26 55.73,127.26 55.84,127.37 55.84,127.53 55.95,127.63 56.1,127.63 56.2,127.53 56.2,127.37 56.31,127.26 56.66,127.26 56.76,127.37 56.76,127.62 56.87,127.72 57.02,127.72 57.12,127.62 57.12,127.37 57.23,127.26 57.62,127.26 59.61,129.25 59.61,130.73 59.44,130.91 59.44,133.27 58.95,133.76 58.04,133.76 57.94,133.71 57.89,133.57 J12.3
F_ADBUS0: length 2.6
  TOP w0.173: R474.2 156.19,76.39 U37.16
F_ADBUS1: length 2.9
  TOP w0.173: R475.2 160.64,73.09 U37.17
F_ADBUS2: length 2.6
  TOP w0.173: R480.2 160.71,72.52 161.14,72.95 U37.18
F_ADBUS3: length 5.1
  TOP w0.173: U37.19 161.64,72.95 161.42,72.72 161.42,69.65 R481.2
F_ADBUS4: length 5.3
  TOP w0.173: U37.21 162.64,73.3 163.07,72.87 163.07,69.8 R476.2
F_ADBUS5: length 2.5
  TOP w0.173: U37.26 165.14,72.26 R478.2
F_ADBUS6: length 2.4
  TOP w0.173: R477.2 163.64,72.03 U37.23
F_ADBUS7: length 2.5
  TOP w0.173: R483.2 166.93,73.07 167.14,73.28 U37.30
FT_SRESET: length 16
  TOP w0.173: R484.2 164.9,69.98 v2(164.64,70.24) 164.9,70.49 R478.1
  BOTTOM w0.173: v2(164.64,70.24) 166.12,71.71 166.12,76.55 165,77.67 165,82.16 165.36,82.52 165.62,82.52 165.77,82.67 U34.1
FT_SRESETB: length 2.4
  BOTTOM w0.173: U35.4 157.85,74.41 R473.2
FT_SRESETN: length 23.2
  L10_SIG4 w0.109: v9(165.35,76.3) 165.35,77.1 164.27,78.19 164.27,84.8 165.83,86.36 v9(166.24,86.36)
  BOTTOM w0.173: v9(166.24,86.36) 168.02,84.59 168.02,81.74 167.7,81.42 U34.4 ; v9(165.35,76.3) 163.29,76.3 162.05,75.06 U35.2
FT_VBUS: length 8.8
  TOP w0.173: v2(166.17,90.17) R492.1
  BOTTOM w0.173: U34.2 166.42,85.25 165.74,85.93 165.74,89.74 v2(166.17,90.17)
FTDI_REF: length 2.2
  TOP w0.173: U37.6 156.53,81.39 R479.1
FTDI_VPHY: length 3.9
  TOP w0.305: U37.4 159.91,82.39 v2(159.94,82.43) 160.32,82.43 v2(160.83,81.92)
  BOTTOM w0.381: C234.2 161.47,82.83 ; C234.2 160.45,82.83 ; C234.2 160.96,82.36
FTDI_VPLL: length 2.6
  TOP w0.254: U37.9 v2(159.84,79.89)
  BOTTOM w0.381: C240.2 161.38,79.87 ; C240.2 160.37,79.87 ; C240.2 160.87,80.34
GB_ETH0_INTN: length 400
  TOP w0.173: v7(127.89,80.85) 127.84,80.9 120.83,80.9 R662.1 ; U21.38 40,118.61 40.17,118.45 R297.1 40.64,118.54 41.33,119.23 42.78,119.23 v7(43.56,118.45)
  L3_SIG1 w0.109: v5(128.52,80.85) v7(127.89,80.85) ; v7(43.56,118.45) v5(44.07,117.94)
  L4_SIG2 w0.114: v5(128.52,80.85) 127.62,80.85 127.45,80.68 126.36,80.68 125.34,79.66 123.97,79.66 123.57,80.06 121.83,80.06 120.98,80.91 120.21,80.91 119.96,80.65 119.96,77.16 118.92,76.12 118.92,73.66 119.42,73.16 120.26,73.16 120.63,73.54 126.02,73.54 127.81,75.33 131.38,75.33 132.35,76.3 143.95,76.3 145.75,74.5 149.43,74.5 160.68,63.25 160.68,61.85 163.15,59.38 163.15,49.54 162.3,48.68 162.3,47.41 161.29,46.4 161.29,38.07 160.46,37.25 160.46,34.37 156.07,29.97 150.12,29.97 145.01,24.86 139.33,24.86 128.2,13.72 117.31,13.72 116.95,13.37 113.53,13.37 113.03,12.87 106.38,12.87 104.65,14.6 86.89,14.6 86.23,15.27 56.42,15.27 48.81,7.66 31.46,7.66 27.43,11.68 27.43,23.52 32.51,28.6 32.51,30.84 31.74,31.61 31.74,40.84 33.17,42.27 33.17,48.1 39.52,54.45 39.52,65.89 37.69,67.72 29.77,67.72 28.32,69.16 28.32,71.82 30.53,74.03 30.53,75.25 31.22,75.93 31.22,76.56 31.52,76.86 33.43,76.86 34.8,78.23 38.84,78.23 41.26,80.66 41.26,84.29 v5(40.51,85.04)
  L9_SIG3 w0.114: v5(44.07,117.94) 44.07,117.15 43.53,116.61 42.24,116.61 37.39,111.76 33.57,111.76 32.64,110.83 32.64,109.27 39.91,101.99 39.91,88.31 40.51,87.71 v5(40.51,85.04)
GB_ETH1_INTN: length 84.1
  TOP w0.173: v2(64.52,116.54) 64.52,117.3 64.16,117.66 63.12,117.66 62.48,118.29 R342.1 61.16,118.45 61,118.61 U24.38 ; R663.1 106.81,115.14 106.81,122 v2(109.35,124.54)
  L3_SIG1 w0.109: v5(64.01,131.78) 64.63,131.16 78.47,131.16 78.87,131.57 79.63,131.57 80.8,130.4 83.71,130.4 84.3,129.8 84.96,129.8 85.37,130.21 87.15,130.21 88.01,131.07 89.72,131.07 89.82,130.97 99.26,130.97 102.9,127.34 106.55,127.34 v2(109.35,124.54)
  L4_SIG2 w0.114: v2(64.52,116.54) 64.59,116.54 65.84,117.8 65.84,127.53 64.01,129.37 v5(64.01,131.78)
GBETH0_RESETN: length 19.3
  TOP w0.173: U21.42 v7(39.49,120.61)
  L3_SIG1 w0.109: v5(38.99,120.1) 39.49,120.6 v7(39.49,120.61)
  L9_SIG3 w0.114: v5(36.07,112.35) 36.07,118.7 37.46,120.1 v5(38.99,120.1)
  L10_SIG4 w0.109: v9(36.07,111.71) v5(36.07,112.35)
  BOTTOM w0.173: v9(36.07,111.71) 35.95,111.83 C168.1 D3.2 37.85,111.97 38.48,111.33 R280.1 37.95,110.7 37.93,110.71 U22.4
GPIO_AM574X_USB2_ID: length 144.3
  TOP w0.173: v1(10.41,44.32) 14.37,48.28 19.5,48.28 20.07,47.71 25.65,47.71 26.24,48.29 36.12,48.29 39.28,51.45 40.07,51.45 42.19,53.57 42.19,54.76 41.98,54.98 41.98,56.54 42.18,56.74 42.18,64.83 41.43,65.58 41.43,83.34 43.71,85.62 59.41,85.62 65.74,91.95 65.74,102.65 67,103.91 73.66,103.91 73.96,104.22 75.49,104.22 77.3,106.03 79.85,106.03 82.17,103.71 82.17,100.54 84.07,98.63 84.96,98.63 86.61,96.98 90.68,96.98 91.31,96.35 91.31,94.49 92.64,93.17 92.64,92.01 U1.AF2
  BOTTOM w0.173: v1(10.41,44.32) R788.2
GPIO_PCIE_RSTDRVN: length 69.5
  TOP w0.173: v2(82.98,89.49) R659.1 ; R955.2 58.08,42.84 57.55,42.31 U44.1 57.55,41.47 57.91,41.1 v2(58.55,41.1)
  BOTTOM w0.173: v2(82.98,89.49) 80.47,89.49 78.71,87.73 78.71,85.43 78.32,85.04 78.32,82.28 74.35,78.31 74.35,52.71 61.98,40.34 59.31,40.34 v2(58.55,41.1)
GPIO_PCIE_SWRSTN: length 78.1
  TOP w0.173: v2(84.58,99.14) 85.6,99.14 86.02,98.72 88.45,98.72 88.49,98.76 R660.1 ; U85.2 56.87,46.59 57.23,46.23 57.92,46.23 58.09,46.06 R954.2 v2(60.32,46.06)
  BOTTOM w0.173: v2(60.32,46.06) 61.11,46.84 61.11,48.41 65.25,52.55 68.78,52.55 73.07,56.84 73.07,77.81 77.67,82.42 77.67,85.37 78.16,85.86 78.16,88.11 80,89.95 80,94.86 84.28,99.14 v2(84.58,99.14)
GPIO_PRU1_ETH0_RESETN: length 349.6
  TOP w0.173: R673.1 v7(129.16,85.81)
  L3_SIG1 w0.109: v5(130.43,86.26) 129.62,86.26 v7(129.16,85.81)
  L4_SIG2 w0.114: v5(130.43,86.26) 130.43,86.23 125.79,81.58 121.72,81.58 121.39,81.92 119.98,81.92 119,80.93 119,79.23 118.03,78.26 118.03,73.13 119.25,71.91 129.44,71.91 132.37,74.84 134.5,74.84 134.89,75.22 142.71,75.22 144.76,73.17 149.03,73.17 159.31,62.89 159.31,61.77 162.26,58.83 162.26,50.04 160.15,47.94 160.15,43.03 159.35,42.23 159.35,34.84 155.84,31.34 148.37,31.34 143.37,26.34 138.79,26.34 128.11,15.66 115.99,15.66 115.78,15.87 113.97,15.87 112.72,14.62 110.88,14.62 109.75,15.75 106.85,15.75 106.84,15.74 87.48,15.74 87.01,16.21 65.86,16.21 65.18,16.89 64.67,16.89 64.02,16.23 55.32,16.23 47.63,8.54 32.61,8.54 30.35,10.79 30.35,24.1 33.94,27.68 33.94,35.16 34.99,36.21 34.99,41.67 36.37,43.04 36.37,50.47 40.32,54.42 40.32,56.23 42.37,58.28 42.37,63.02 42.8,63.45 42.8,66.34 40.97,68.17 31.75,68.17 30.91,69.01 30.91,75.03 31.6,75.72 37.69,75.72 39.41,77.43 39.41,78.27 41.66,80.52 41.66,84.79 42.95,86.08 44.72,86.08 v2(45.97,87.33)
  BOTTOM w0.173: R112.2 v2(45.97,87.33)
GPIO_PRU1_ETH1_RESETN: length 370.6
  L3_SIG1 w0.109: v2(35.31,90) 39.75,90 40.58,89.17 40.58,85.87 41.27,85.17 41.27,82.12 39.75,80.6 38.23,80.6 35.07,77.44 33.25,77.44 32.87,77.06 32.87,76.68 31.53,75.34 29.16,75.34 22.48,68.66 22.48,51.31 16.51,45.34 13.84,45.34 10.79,42.29 10.79,38.37 v5(15.29,33.87)
  L4_SIG2 w0.114: v5(15.29,33.87) 15.29,28.78 20.45,23.62 20.45,9.4 26.67,3.17 51.48,3.17 53.83,5.52 91.58,5.52 92.08,5.03 104.67,5.03 105.41,5.78 110.63,5.78 112.09,4.32 113.61,4.32 114.64,3.3 138.72,3.3 139.07,3.64 140.31,3.64 149.03,12.35 149.03,12.97 151.61,15.55 152.66,15.55 173.36,36.24 173.36,54.36 172.72,54.99 172.72,59.91 168.85,63.78 168.85,65.42 165.18,69.09 164.36,69.09 164.35,69.1 163.92,69.1 163.91,69.09 163.9,69.09 163.19,69.8 163.19,70 160.98,72.21 160.32,72.21 159.23,73.31 159.23,74.81 152.12,81.91 132.76,81.91 131.21,80.36 126.46,80.36 125.32,79.22 121.65,79.22 v5(120.4,80.47)
  L10_SIG4 w0.109: v9(119.76,79.84) v5(120.4,80.47)
  BOTTOM w0.173: R674.1 v9(119.76,79.84) ; R154.2 v2(35.31,90)
GPIO_PRU2_ETH0_RESETN: length 328.9
  TOP w0.173: R675.1 129.13,83.27 v7(129.16,83.24)
  L3_SIG1 w0.109: v7(129.16,83.24) 129.44,82.96 v5(130.15,82.96)
  L4_SIG2 w0.114: v2(41.99,66) 41.99,58.52 39.98,56.51 39.98,54.5 33.53,48.05 33.53,42.04 32.25,40.77 32.25,33.01 32.88,32.37 32.88,28.11 27.81,23.04 27.81,14.48 28.7,13.59 28.7,11.25 32,7.95 48.41,7.95 56.02,15.56 86.47,15.56 87.07,14.96 104.82,14.96 106.62,13.16 112.9,13.16 113.4,13.66 116.83,13.66 117.86,14.69 128.45,14.69 139.09,25.33 144.53,25.33 149.63,30.43 156.02,30.43 160.09,34.51 160.09,37.34 160.99,38.23 160.99,47.9 162.86,49.78 162.86,59.21 160.22,61.85 160.22,62.99 149.1,74.12 145.34,74.12 143.45,76.01 132.67,76.01 131.69,75.04 127.93,75.04 126.14,73.25 120.76,73.25 120.37,72.86 119.24,72.86 118.61,73.49 118.61,77.62 119.67,78.68 119.67,80.77 120.09,81.2 121.16,81.2 121.79,80.57 123.84,80.57 124.09,80.82 126.09,80.82 126.24,80.97 126.26,80.97 128.25,82.96 v5(130.15,82.96)
  BOTTOM w0.173: v2(41.99,66) 41.42,66.57 34.47,66.57 32.26,68.79 R195.2
GPIO_PRU2_ETH1_RESETN: length 289.1
  TOP w0.173: R676.1 v7(129.16,84.54)
  L3_SIG1 w0.109: v5(130.86,84.08) 130.3,84.64 129.26,84.64 v7(129.16,84.54)
  L4_SIG2 w0.114: v2(35.16,45.9) 35.16,44.43 34.57,43.84 34.57,36.58 33.52,35.53 33.52,28 29.97,24.46 29.97,10.76 32.49,8.24 48.02,8.24 55.63,15.85 86.76,15.85 87.26,15.35 105,15.35 106.9,13.46 112.62,13.46 113.66,14.5 113.66,15.16 114.09,15.58 115.66,15.58 115.87,15.37 128.43,15.37 138.89,25.83 143.76,25.83 148.97,31.04 155.72,31.04 155.96,31.04 159.64,34.72 159.64,41.83 160.45,42.64 160.45,47.82 162.57,49.94 162.57,58.97 159.77,61.77 159.77,62.92 148.95,73.74 144.94,73.74 143.17,75.51 134.67,75.51 134.29,75.13 132.2,75.13 131.76,74.69 128.36,74.69 126.62,72.95 122.91,72.95 122.29,72.34 119.24,72.34 118.32,73.25 118.32,77.92 119.37,78.97 119.37,80.9 120.01,81.53 121.29,81.53 121.56,81.25 125.96,81.25 127.97,83.27 129.5,83.27 130.31,84.08 v5(130.86,84.08)
  BOTTOM w0.173: R234.2 35.13,45.93 v2(35.16,45.9)
GPIO_TOUCH_RESETN: length 367.1
  L4_SIG2 w0.114: v5(120.04,76.41) 119.21,75.58 119.21,73.83 119.53,73.51 120.04,73.51 123.35,76.81 130.23,76.81 130.98,77.56 145.14,77.56 146.56,76.14 149.44,76.14 159.67,65.91 160.9,65.91 167.31,59.5 167.31,52.55 164.49,49.73 164.49,48.82 163.73,48.06 163.73,47.35 165.52,45.55 165.52,43.73 164.67,42.88 164.67,41.35 165.56,40.46 165.56,36.22 157.13,27.79 152.52,27.79 147.55,22.81 141.06,22.81 133.23,14.99 133.23,13.88 132.13,12.78 130.93,12.78 129.14,10.99 106.07,10.99 105.89,11.17 98.96,11.17 97.22,12.91 64.16,12.91 64.07,12.83 57.26,12.83 55.93,11.5 54.78,11.5 50.06,6.78 29.59,6.78 24.43,11.94 24.43,24.43 27.95,27.94 27.95,30.52 27.81,30.66 27.81,41.13 30.41,43.73 30.41,47.41 35.24,52.25 35.24,55.3 34.49,56.05 34.49,62.53 35.71,63.75 35.71,65.66 34.57,66.8 26.87,66.8 25.5,68.17 25.5,72.29 28.7,75.49 29.77,75.49 30.15,75.87 30.15,77.39 31.6,78.84 36.63,78.84 37.16,79.38 39.45,79.38 40.97,80.9 40.97,82.94 39.83,84.08 39.83,85.55 41.12,86.84 43.33,86.84 44.72,88.23 47.11,88.23 49.15,86.19 v2(57.91,86.19)
  L10_SIG4 w0.109: v5(120.04,76.41) 119.79,76.15 119.79,75.04 v9(119.76,75.01)
  BOTTOM w0.173: v9(119.76,75.01) 120.14,74.63 R661.1 ; v2(57.91,86.19) 57.81,86.08 R792.2
GPIO_USB2_VBUS_DET: length 104.6
  TOP w0.173: v2(86.11,99.57) 86.6,99.07 88.3,99.07 88.34,99.11 92.4,99.11 92.61,99.32 93.47,99.32 R809.1 ; U96.4 R811.2 v2(150.54,141.63)
  BOTTOM w0.173: v2(150.54,141.63) 147.66,138.75 141.6,138.75 138.36,141.99 126.36,141.99 119.38,135 111.25,135 108.79,132.54 108.79,123.75 110.05,122.49 110.05,121.48 108.75,120.18 104.94,120.18 104.21,119.44 104.21,118.85 99.69,114.34 99.69,113.16 v2(86.11,99.57)
GPIO_VPP_PWR_EN: length 362
  TOP w0.173: v7(70.19,94.15) 73.87,94.15 74.42,93.6 75.69,93.6 76.93,92.36 79.83,92.36 v7(80.81,93.33) ; U1.AE3 v4(93.44,91.21) ; R638.2 v2(164.47,5.03)
  L3_SIG1 w0.109: v2(164.47,5.03) 161.29,1.86 146.69,1.86 136.91,11.64 136.91,13.54 128.76,21.69 110.57,21.69 110.14,22.12 107.89,22.12 107.47,21.69 97.56,21.69 91.28,15.42 85.06,15.42 73.63,3.99 50.9,3.99 48.6,1.69 23.66,1.69 22.73,2.62 15.37,2.62 14.61,1.86 8.38,1.86 7.52,2.72 7.52,6.4 5.46,8.46 5.46,29.8 2.03,33.23 2.03,33.82 2.03,33.82 2.03,34.25 2.03,34.25 2.03,47.71 3.3,48.98 3.3,83.27 5.86,85.82 12.21,85.82 16.89,90.51 24.89,90.51 25.37,90.02 29.22,90.02 29.72,90.53 31.14,90.53 35.29,94.68 37.3,94.68 38.08,95.46 53.85,95.46 54.99,96.6 59.05,96.6 60.51,95.14 69.2,95.14 v7(70.19,94.15) ; v7(80.81,93.33) 81.53,94.06 85.72,94.06 87.61,92.17 89.61,92.17 90.3,91.48 91.56,91.48 92.2,90.84 93.08,90.84 93.44,91.19 v4(93.44,91.21)
GPMC_CLK: length 87.9
  TOP w0.173: R689.1 104.77,122.76 104.77,124.29 102.89,126.17 102.89,129.98 102.36,130.51 102.36,131.57 99.82,134.11 99.82,149.23 101.06,150.47 155.9,150.47 J21.58
GPMC_CS0: length 61.6
  TOP w0.173: R686.1 100.84,100.89 v2(100.41,101.33)
  L4_SIG2 w0.114: J21.4 103.35,149.21 102.31,150.24 100.87,150.24 100.15,149.52 100.15,146.16 102.84,143.46 102.84,137.59 97.47,132.22 97.47,130.07 96.11,128.71 96.11,128.04 96.88,127.28 96.88,124.64 94.01,121.77 94.01,112.52 94.56,111.96 94.56,107.54 100.41,101.7 v2(100.41,101.33)
GPMC_CS3: length 58.7
  TOP w0.173: v5(103.38,100.28) v7(103.38,101)
  L3_SIG1 w0.109: v7(103.38,101) v5(103.38,100.28)
  L4_SIG2 w0.114: v5(103.38,100.28) 101.99,100.28 101.49,100.79 101.49,102.15 98.42,105.21 98.42,109.93 100.38,111.89 100.38,119.18 99.44,120.12 99.44,122.25 98.63,123.06 98.63,127.86 98.02,128.47 98.02,129.37 97.84,129.55 97.84,130.81 105.14,138.11 105.14,145.2 104.35,146 104.35,148.02 J21.6
HAPTICS_N: length 2.8
  TOP w0.173: U18.2 143.14,14.86 Q16.D
HAPTICS_P: length 4.5
  TOP w0.173: C316.1 140.75,14.77 R113.1 U18.1
HDMI_CEC: length 2.6
  TOP w0.173: U46.1 68.22,21.99 R683.1
HDMI_CLK+: length 17.7
  TOP w0.108: J24.10 62.65,9.72 62.25,10.11 62.25,10.9 62.81,11.46 62.81,14.23 63.02,14.43 U46.16 63.02,15.99 62.83,16.18 62.83,16.91 62.46,17.27 56.9,17.27 56.01,18.16 56.01,18.92 56.28,19.2 L29.3
HDMI_CLK-: length 17.7
  TOP w0.108: J24.12 61.65,9.76 62,10.11 62,11.01 62.56,11.57 62.56,14.23 62.37,14.42 U46.15 62.37,15.97 62.57,16.18 62.57,16.8 62.36,17.02 56.79,17.02 55.75,18.06 55.75,18.92 55.48,19.2 L29.2
HDMI_CT_HPD: length 8.5
  TOP w0.173: 64.64,22.86 64.64,23.88 v2(63.75,23.88) ; U46.12 v2(61.07,19.92)
  BOTTOM w0.173: v2(63.75,23.88) 63.23,23.88 61.07,21.71 v2(61.07,19.92)
HDMI_DDC_SCL: length 2.1
  TOP w0.173: U46.2 v2(67.57,19.84)
  BOTTOM w0.173: R795.1 67.62,19.89 v2(67.57,19.84)
HDMI_DDC_SDA: length 2.6
  TOP w0.173: U46.3 v2(66.92,22.4)
  BOTTOM w0.173: R796.1 66.76,22.56 v2(66.92,22.4)
HDMI_HPLG: length 4
  TOP w0.173: U46.4 66.27,22.71 66.8,23.24 R682.1
HDMI_LSOE: length 1.8
  TOP w0.173: U46.5 65.62,22.82 R558.1
HDMI_TX0+: length 16.6
  TOP w0.108: L30.3 58.82,19.2 58.55,18.92 58.55,18.41 58.8,18.16 63.48,18.16 64.13,17.51 64.13,16.18 64.32,15.99 U46.18 64.32,14.43 64.11,14.23 64.11,11.61 63.75,11.25 63.75,10.11 64.15,9.72 J24.7
HDMI_TX0-: length 16.6
  TOP w0.108: J24.9 63.15,9.76 63.5,10.11 63.5,11.36 63.86,11.71 63.86,14.23 63.67,14.42 U46.17 63.67,15.97 63.87,16.18 63.87,17.41 63.37,17.91 58.7,17.91 58.29,18.31 58.29,18.92 58.02,19.2 L30.2
HDMI_TX1+: length 15.9
  TOP w0.108: J24.4 65.65,9.72 65.25,10.11 65.25,10.87 66.06,11.68 66.06,14.23 66.27,14.43 U46.21 66.27,15.99 66.08,16.18 66.08,17.01 66.94,17.88 70.41,17.88 70.97,18.44 70.97,19.05 71.27,19.35 L31.3
HDMI_TX1-: length 15.9
  TOP w0.108: J24.6 64.65,9.76 65,10.11 65,10.97 65.81,11.78 65.81,14.23 65.62,14.42 U46.20 65.62,15.97 65.83,16.18 65.83,17.12 66.84,18.13 70.3,18.13 70.71,18.54 70.71,19.08 70.47,19.32 L31.2
HDMI_TX2+: length 17.1
  TOP w0.108: J24.1 67.15,9.71 66.8,10.06 66.8,11.12 67.36,11.68 67.36,14.35 67.57,14.56 U46.23 67.57,15.99 67.38,16.18 67.38,16.61 67.69,16.92 72.47,16.92 73.53,17.98 73.53,19.05 73.81,19.32 L32.3
HDMI_TX2-: length 17.1
  TOP w0.108: L32.2 73.01,19.32 73.28,19.05 73.28,18.09 72.37,17.18 67.59,17.18 67.13,16.72 67.13,16.18 66.92,15.97 U46.22 66.92,14.57 67.11,14.38 67.11,11.79 66.55,11.23 66.55,10.06 66.15,9.66 J24.3
HDMICONN_CEC: length 15
  TOP w0.173: v2(60.71,10.67) 61.15,10.23 J24.13 ; U46.7 v2(64.32,19.84)
  BOTTOM w0.173: v2(64.32,19.84) 64.32,13.09 61.89,10.67 v2(60.71,10.67)
HDMICONN_HPLG: length 18.1
  TOP w0.173: U46.10 v2(62.37,19.84) ; J24.19 57.29,8.5 56.52,9.27 R561.2 v2(55.75,11.94)
  BOTTOM w0.173: v2(62.37,19.84) 60.29,17.75 59.18,17.75 55.57,14.15 55.57,12.12 v2(55.75,11.94)
HDMICONN_I2CSCL: length 22.1
  TOP w0.173: U46.8 v2(63.67,22.4) ; J24.15 60.15,10.08 58.8,11.43 R560.1 v2(59.56,11.94)
  L3_SIG1 w0.109: v2(59.56,11.94) 59.61,11.89 62.48,11.89 66.17,15.58 66.17,19.91 v2(63.67,22.4)
HDMICONN_I2CSDA: length 22.9
  TOP w0.173: U46.9 63.02,22.41 v2(62.72,22.71) ; J24.16 59.65,9.82 58.83,10.64 58.19,10.64 57.66,11.18 R562.1 57.78,11.94 58.2,12.35 v2(58.24,12.35)
  BOTTOM w0.173: v2(58.24,12.35) 57.08,12.35 55.92,13.51 55.92,14 56.27,14.35 56.76,14.35 59.23,16.81 60.22,16.81 62.84,19.43 62.84,22.59 v2(62.72,22.71)
HDQ: length 16.3
  L3_SIG1 w0.109: J21.50 150.33,148.04 155.93,148.04 156.36,147.6 156.36,146.36 156.9,145.82 162.03,145.82 v2(162.56,145.29)
  BOTTOM w0.173: R300.1 v2(162.56,145.29)
IND_I2C_SCL: length 543.3
  TOP w0.173: R314.2 42.8,102.32 v2(42.91,102.21) ; R652.2 v7(50.29,23.37) ; v7(140.97,107.78) 140.97,107.02 140.34,106.38 135.38,106.38 130.43,111.33 R14.2 ; R393.1 v7(122.81,72.34) ; v2(185.57,132.16) R275.1 183.07,135.55 183.07,137.68 183.16,137.77 183.16,140.54 182.11,141.59 173.96,141.59 170.94,144.61 v7(164.41,144.61)
  L3_SIG1 w0.109: J21.27 128.35,148.02 128.35,149.76 128.98,150.39 160.53,150.39 162.35,148.57 162.35,147.67 164.41,145.61 v7(164.41,144.61) ; v2(185.57,132.16) 185.57,126.47 168,108.9 157.14,108.9 156.46,109.58 149.25,109.58 146.48,106.81 146,106.81 v5(145.54,107.27) 145.03,107.78 v7(140.97,107.78) ; v7(50.29,23.37) 50.29,21.23 51.92,19.6 51.92,11.2 50.43,9.72 26.2,9.72 18.05,17.87 18.05,19.57 14.85,22.77 10.66,22.77 10.03,23.39 10.03,29.84 v2(9.4,30.48) 9.4,32.61 6.63,35.38 6.63,41.99 6.22,42.4 6.22,47.37 4.95,48.63 4.95,82.28 6.45,83.77 14,83.77 15.88,85.65 17.78,85.65 19.83,87.7 29.11,87.7 30.01,88.6 33.16,88.6 35.41,90.85 40.73,90.85 42.99,88.6 51.68,88.6 52.2,88.08 v2(52.2,87.58) ; v7(122.81,72.34) v5(123.44,72.34)
  L4_SIG2 w0.114: v2(52.2,87.58) 42.91,96.87 v2(42.91,102.21) 44.16,103.45 52.62,103.45 54.17,105 63.07,105 67.78,109.71 67.78,130.76 72.65,135.63 76.75,135.63 81.75,140.63 81.75,144.03 87.42,149.71 95.61,149.71 96.22,150.32 97.07,150.32 97.83,149.56 97.83,144.7 101.47,141.06 v2(101.47,141.05)
  L9_SIG3 w0.114: v5(123.44,72.34) 124.84,72.34 133.55,81.06 133.55,85.88 136.28,88.61 136.28,94.22 142.16,100.1 142.16,103.89 v5(145.54,107.27) 146.94,108.67 151.51,108.67 152.65,107.52 152.65,106.38 156.18,102.85 156.18,99.29 v5(157.86,97.62)
  L10_SIG4 w0.109: v9(158.5,97.62) v5(157.86,97.62)
  BOTTOM w0.173: R567.2 v9(158.5,97.62) ; J21.27 126.15,145.82 119.84,145.82 118.92,144.91 105.33,144.91 v2(101.47,141.05) ; v2(52.2,87.58) 52.69,87.58 52.77,87.51 J17.2 ; U33.6 v2(9.4,30.48)
IND_I2C_SDA: length 553.7
  TOP w0.173: R394.1 v7(122.81,70.69) ; R15.2 132.72,110.19 134.11,108.79 138.68,108.79 139.19,109.3 140.46,109.3 v7(140.97,108.79) ; R277.1 v2(188.11,132.16) ; v2(43.59,102.2) 43.81,102.42 R312.2 ; R653.2 v7(51.31,23.37)
  L3_SIG1 w0.109: v7(51.31,23.37) 51.31,20.62 52.2,19.72 52.2,11.08 52.2,11.07 52.2,11.05 50.58,9.43 50.55,9.43 50.32,9.43 50.31,9.43 26.03,9.43 17.53,17.93 17.53,19.69 14.73,22.48 10.54,22.48 8.76,24.26 8.76,29.95 v2(8.13,30.58) 8.13,32.36 7.11,33.38 6.77,33.38 6.3,33.85 6.3,34.19 5.41,35.08 5.41,39.55 6.25,40.39 6.25,41.97 5.9,42.31 5.9,47.18 4.49,48.6 4.49,82.42 6.32,84.25 12.86,84.25 16.6,87.99 28.99,87.99 29.89,88.89 33.01,88.89 35.26,91.14 41.27,91.14 42.67,89.74 50.95,89.74 52.75,87.94 52.75,87.09 v2(52.62,86.96) ; v7(122.81,70.69) v5(123.44,70.69) ; v7(140.97,108.79) 141.35,108.41 145.18,108.41 v5(146.25,107.34) 146.25,107.73 148.62,110.09 156.74,110.09 157.64,109.19 167.78,109.19 183.64,125.05 183.64,131.65 184.91,132.92 187.35,132.92 v2(188.11,132.16)
  L4_SIG2 w0.114: v2(100.66,140.79) 97.36,144.1 97.36,149.33 96.82,149.86 96.22,149.86 95.68,149.33 87.5,149.33 82.04,143.87 82.04,140.42 76.65,135.03 72.46,135.03 68.07,130.64 68.07,109.17 62.76,103.86 54.81,103.86 53.92,102.97 44.36,102.97 v2(43.59,102.2) 43.59,97.34 52.96,87.97 52.96,87.3 v2(52.62,86.96)
  L9_SIG3 w0.114: v5(157.86,96.6) 155.78,98.68 155.78,102.6 151,107.37 149.5,107.37 148.97,107.9 146.82,107.9 v5(146.25,107.34) 146.25,107.09 142.54,103.38 142.54,96.6 136.58,90.63 136.58,88.45 133.93,85.81 133.93,80.68 123.95,70.69 v5(123.44,70.69)
  L10_SIG4 w0.109: v2(188.11,132.16) 187.5,132.16 183.1,136.56 183.1,137.46 182.34,138.21 181.77,138.21 180.79,139.2 180.79,139.77 179,141.56 173.27,141.56 163.88,150.96 127.91,150.96 126.38,149.42 126.38,148.62 126.94,148.05 128.31,148.05 J21.29 ; v9(158.5,96.6) v5(157.86,96.6)
  BOTTOM w0.173: U33.5 v2(8.13,30.58) ; J21.29 127.61,145.29 119.91,145.29 119.15,144.53 105.61,144.53 101.67,140.58 100.87,140.58 v2(100.66,140.79) ; R585.2 v9(158.5,96.6) ; v2(52.62,86.96) 52.67,86.96 52.71,87.01 J17.1
INDETHER_LED0_RED: length 110.2
  TOP w0.173: R975.1 v1(42.7,73.78)
  L4_SIG2 w0.114: v2(8.31,3.64) 9.04,4.37 9.04,21.84 5.31,25.58 5.31,37.31 4.32,38.3 4.32,43.48 4.78,43.94 4.78,48.44 3.86,49.35 3.86,66.65 7.06,69.85 13.65,69.85 17.53,73.74 v1(17.54,73.74)
  BOTTOM w0.173: v1(17.54,73.74) 21.16,73.74 22.15,72.75 38.84,72.75 39.87,73.78 v1(42.7,73.78) ; v2(8.31,3.64) 9.02,3.64
INDETHER_LED1_YEL: length 104.8
  TOP w0.173: v1(55.61,73.42) 56.05,73.42 56.45,73.82 R969.1
  L4_SIG2 w0.114: v1(55.61,73.42) 50.39,68.21 50.39,65.35 43.51,58.46 43.51,53.72 40.79,51 39.04,51 37.54,49.5 37.54,28.95 32.46,23.87 v1(32.46,18.41)
  BOTTOM w0.173: R254.1 15.03,6.94 14.3,7.67 14.3,22.23 16.25,24.17 27.06,24.17 32.46,18.77 v1(32.46,18.41)
INDUS_INPUT0: length 5.3
  BOTTOM w0.173: J37.1 184.05,58.17 R368.2
INDUS_INPUT1: length 5.3
  BOTTOM w0.173: J37.3 184.05,55.63 R370.2
INDUS_INPUT2: length 5.3
  BOTTOM w0.173: R372.2 184.05,53.09 J37.5
INDUS_INPUT3: length 5.3
  BOTTOM w0.173: R374.2 184.05,50.55 J37.7
INDUS_INPUT4: length 5.3
  BOTTOM w0.173: J37.9 184.05,48.01 R373.2
INDUS_INPUT5: length 5.3
  BOTTOM w0.173: J37.11 184.05,45.47 R375.2
INDUS_INPUT6: length 5.3
  BOTTOM w0.173: R376.2 184.05,42.93 J37.13
INDUS_INPUT7: length 5.3
  BOTTOM w0.173: R378.2 184.05,40.39 J37.15
INDUS_INPUTCLK: length 61.6
  TOP w0.173: v7(131.95,72.9) 129.59,75.27 R367.1
  L3_SIG1 w0.109: v7(131.95,72.9) v5(133.78,72.9)
  L9_SIG3 w0.114: v2(179.61,63.45) 176.14,66.93 176.14,69.95 174.68,71.4 156.18,71.4 152.5,75.08 135.96,75.08 v5(133.78,72.9)
  BOTTOM w0.173: U72.25 v2(179.61,63.45)
INDUS_INPUTCSN: length 61.4
  TOP w0.173: R369.1 129.64,76.28 130.35,75.57 v7(132.87,75.57)
  L3_SIG1 w0.109: v7(132.87,75.57) v5(133.53,75.57)
  L9_SIG3 w0.114: v2(180.26,64.22) 179.89,64.59 179.89,70.39 178.34,71.93 156.67,71.93 153.03,75.57 v5(133.53,75.57)
  BOTTOM w0.173: U72.24 v2(180.26,64.22)
INDUS_INPUTLDN: length 274.5
  TOP w0.173: R371.1 82.3,94.36 81.53,95.12 v7(81.53,97.03)
  L3_SIG1 w0.109: v5(75.82,97.03) 75.82,96.9 76.2,96.52 81.03,96.52 v7(81.53,97.03)
  L9_SIG3 w0.114: v5(75.82,97.03) 75.82,91.14 70.76,86.09 70.76,83.9 71.07,83.59 71.07,82.68 70.76,82.37 70.76,68.96 62.1,60.3 62.1,47.75 68.22,41.63 68.22,37.01 70.36,34.88 70.36,21.79 81.62,10.53 96.18,10.53 97.97,12.33 112.26,12.33 116.63,7.96 131.19,7.96 133.87,5.28 154.19,5.28 157.15,2.32 169.52,2.32 180.21,13.01 180.21,38.18 181.36,39.32 181.36,59.77 v2(178.56,62.57)
  BOTTOM w0.173: U72.26 178.96,62.97 v2(178.56,62.57)
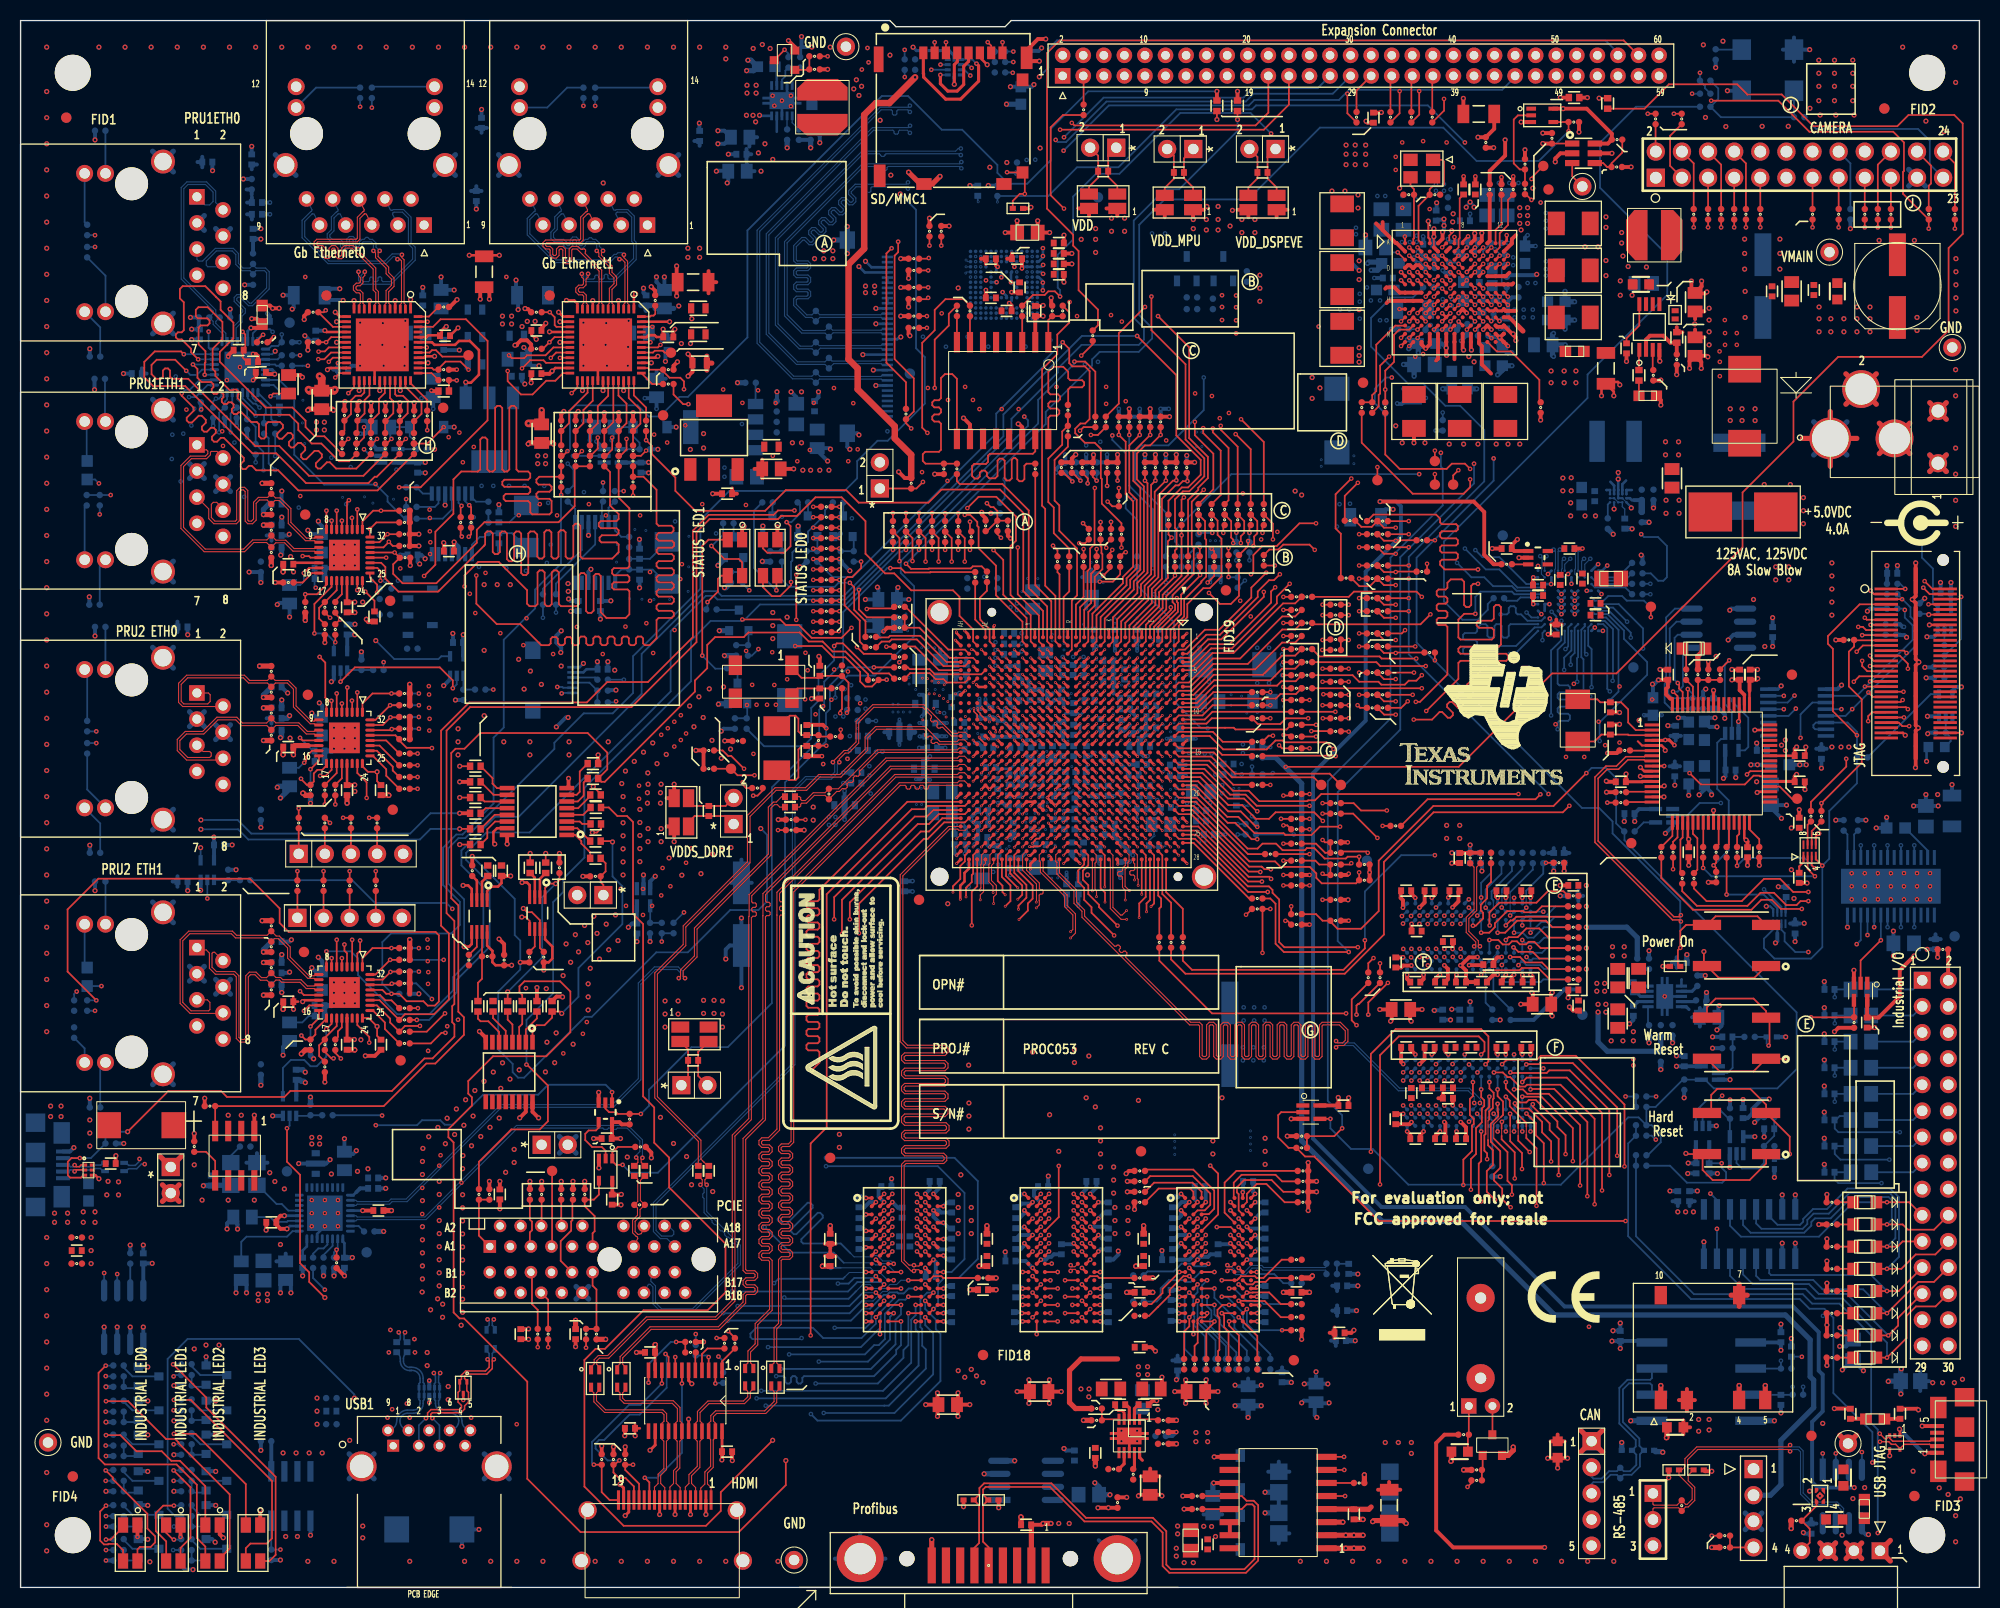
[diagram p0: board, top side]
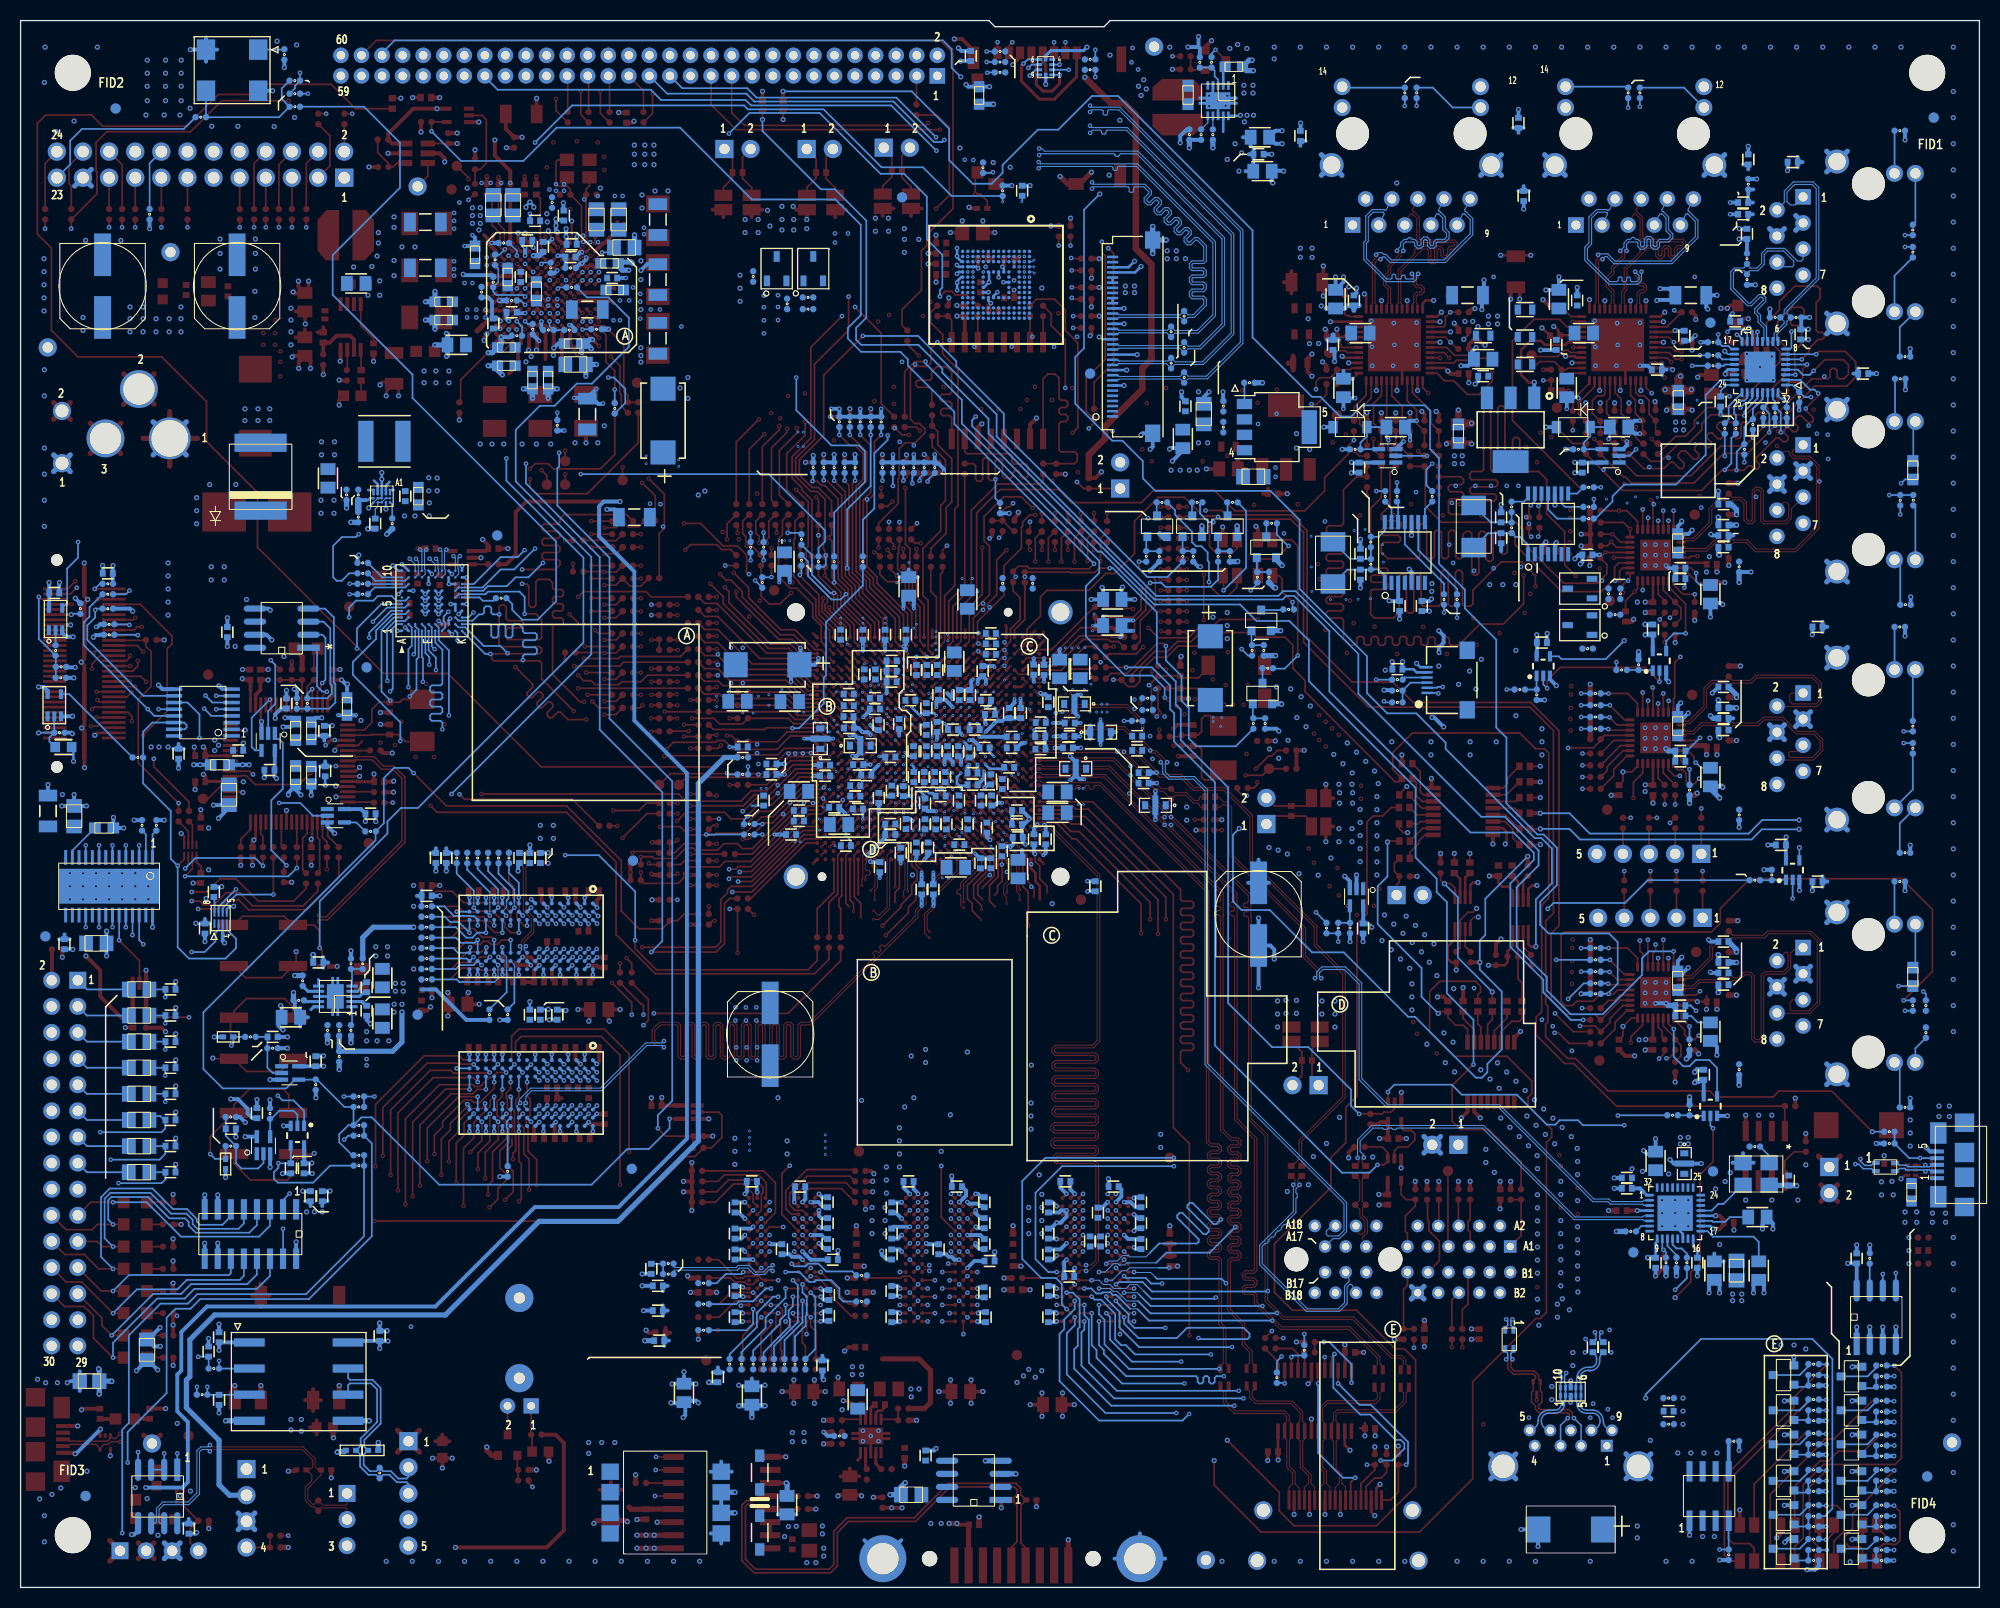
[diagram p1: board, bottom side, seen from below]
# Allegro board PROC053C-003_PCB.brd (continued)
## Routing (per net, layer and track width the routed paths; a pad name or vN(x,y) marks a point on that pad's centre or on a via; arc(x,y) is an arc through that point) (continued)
INDUS_INPUTSO: length 7.4
  TOP w0.173: v2(180.91,62.95) 178.94,60.97 U28.2
  BOTTOM w0.173: U72.23 v2(180.91,62.95)
JTAG_EMU0: length 112.9
  TOP w0.173: U1.G21 v4(108.63,76.02) ; J18.19 v2(179.1,92.62) ; R554.1 174.12,76.41 177.55,79.84 v2(177.55,80.6)
  L3_SIG1 w0.109: v2(177.55,80.6) 172.59,80.6 172.21,80.22 170.82,80.22 170.31,80.73 164.52,80.73 160.17,76.38 155.37,76.38 154.22,75.23 146.24,75.23 146.13,75.34 146.13,75.74 146.02,75.84 145.8,75.84 145.69,75.74 145.69,75.34 145.58,75.23 145.36,75.23 145.25,75.34 145.25,75.74 145.15,75.84 144.93,75.84 144.82,75.74 144.82,75.34 144.71,75.23 144.49,75.23 144.38,75.34 144.38,75.74 144.27,75.84 144.05,75.84 143.94,75.74 143.94,75.34 143.83,75.23 143.62,75.23 143.51,75.34 143.51,75.74 143.4,75.84 143.18,75.84 143.07,75.74 143.07,75.34 142.96,75.23 142.74,75.23 142.63,75.34 142.63,75.74 142.52,75.84 142.31,75.84 142.2,75.74 142.2,75.34 142.09,75.23 141.87,75.23 141.76,75.34 141.76,75.74 141.65,75.84 141.43,75.84 141.32,75.74 141.32,75.34 141.21,75.23 140.99,75.23 140.89,75.34 140.89,75.74 140.78,75.84 140.56,75.84 140.45,75.74 140.45,75.34 140.34,75.23 140.12,75.23 140.01,75.34 140.01,75.74 139.9,75.84 139.68,75.84 139.58,75.74 139.58,75.34 139.47,75.23 139.25,75.23 139.14,75.34 139.14,75.74 139.03,75.84 138.81,75.84 138.7,75.74 138.7,75.34 138.59,75.23 137.63,75.23 134.98,72.57 134.98,71.65 131.52,68.2 126.21,68.2 125.73,67.72 122.5,67.72 122.05,68.18 122.05,69.12 121.81,69.35 121.46,69.35 120.68,70.13 119.84,70.13 119.53,70.44 119.53,71.02 115.98,74.57 v5(115.85,74.57) ; v4(108.63,76.02) v5(109.03,75.77)
  L10_SIG4 w0.109: v5(115.85,74.57) 115.31,75.11 111.99,75.11 111.52,75.58 110.2,75.58 109.98,75.37 109.43,75.37 v5(109.03,75.77) ; v2(177.55,80.6) 179.1,82.15 v2(179.1,92.62)
  BOTTOM w0.173: R422.1 179.39,92.66 179.35,92.62 v2(179.1,92.62)
JTAG_EMU1: length 109.9
  TOP w0.173: J18.21 178.34,92.12 R423.1 178.31,91.52 177.8,91.02 177.8,87.63 179.05,86.38 179.05,80.2 v2(175.13,76.28) R555.1 ; U1.D24 v4(111.03,73.62)
  L3_SIG1 w0.099: v4(111.03,73.62) 111.37,73.28 111.78,73.28 112.08,72.99 112.79,72.99 112.96,73.16
  L3_SIG1 w0.109: v2(175.13,76.28) 174.75,76.66 169.29,76.66 168.1,75.48 167.95,75.48 167.65,75.78 167.49,75.78 167.34,75.62 167.34,75.47 167.64,75.17 167.64,75.01 167.49,74.86 167.33,74.86 167.03,75.16 166.87,75.16 166.72,75.01 166.72,74.85 167.02,74.55 167.02,74.39 166.87,74.24 166.71,74.24 166.41,74.54 166.26,74.54 166.1,74.39 166.1,74.23 166.4,73.93 166.4,73.78 165.94,73.31 165.34,73.31 165.24,73.42 165.24,74.27 165.13,74.38 164.91,74.38 164.8,74.27 164.8,73.42 164.69,73.31 164.47,73.31 164.36,73.42 164.36,74.27 164.25,74.38 164.03,74.38 163.92,74.27 163.92,73.42 163.82,73.31 163.6,73.31 163.49,73.42 163.49,74.27 163.38,74.38 163.16,74.38 163.05,74.27 163.05,73.42 162.94,73.31 162.72,73.31 162.61,73.42 162.61,74.27 162.5,74.38 162.29,74.38 162.18,74.27 162.18,73.42 162.07,73.31 161.85,73.31 161.74,73.42 161.74,74.27 161.63,74.38 161.41,74.38 161.3,74.27 161.3,73.42 161.19,73.31 160.81,73.31 160.02,72.52 143.56,72.52 140.28,69.23 135.63,69.23 130.42,64.03 127.83,64.03 126.57,65.28 121.21,65.28 118.01,68.48 118.01,70.39 115.24,73.16 112.96,73.16
JTAG_TCK: length 105.2
  TOP w0.173: U1.E20 v4(110.23,76.82)
  L3_SIG1 w0.109: v5(168.53,84.16) 166.78,82.41 160.63,82.41 160.17,81.94 157.98,81.94 155.85,79.81 151.1,79.81 150.14,78.85 142.8,78.85 142.69,78.74 142.69,78.04 142.58,77.93 142.36,77.93 142.25,78.04 142.25,78.74 142.14,78.85 141.93,78.85 141.82,78.74 141.82,78.04 141.71,77.93 141.49,77.93 141.38,78.04 141.38,78.74 141.27,78.85 141.05,78.85 140.94,78.74 140.94,78.04 140.83,77.93 140.61,77.93 140.51,78.04 140.51,78.74 140.4,78.85 140.18,78.85 140.07,78.74 140.07,78.04 139.96,77.93 139.74,77.93 139.63,78.04 139.63,78.74 139.52,78.85 139.3,78.85 139.19,78.74 139.19,78.04 139.09,77.93 138.87,77.93 138.76,78.04 138.76,78.74 138.65,78.85 138.43,78.85 138.32,78.74 138.32,78.04 138.21,77.93 137.99,77.93 137.88,78.04 137.88,78.74 137.77,78.85 137.56,78.85 137.45,78.74 137.45,78.04 137.34,77.93 137.12,77.93 137.01,78.04 137.01,78.74 136.9,78.85 135.28,78.85 132.08,75.65 132.08,74.76 129.05,71.73 126.49,71.73 125.6,72.62 124.93,72.62 124.46,73.09 122.21,73.09 120.88,74.43 119.53,74.43 117.53,76.43 116.64,76.43 116.51,76.31 110.74,76.31 v4(110.23,76.82)
  L9_SIG3 w0.114: v2(178.13,85.43) 176.86,84.16 v5(168.53,84.16)
  BOTTOM w0.173: R3.2 183.79,95.33 183.79,94.42 184.36,93.85 184.36,91.65 v2(178.13,85.43) 177.47,84.77 U63.13
JTAG_TDI: length 119.6
  TOP w0.173: v7(182.98,96.12) 182.98,96.12 J18.5 ; U1.D23 v4(111.03,74.42)
  L3_SIG1 w0.099: 112.5,74.12 111.33,74.12 v4(111.03,74.42)
  L3_SIG1 w0.109: 112.5,74.12 112.88,73.74 115.49,73.74 118.62,70.62 118.62,69.04 120.6,67.06 121.8,67.06 122.15,66.71 125.75,66.71 126.16,66.29 131.17,66.29 136.25,71.37 136.25,72.52 137.34,73.61 140.59,73.61 141.02,74.04 154.36,74.04 155.71,75.39 160.66,75.39 161.54,76.28 163.2,76.28 163.91,76.99 163.91,77.75 165.74,79.58 167.99,79.58 168.11,79.46 170.82,79.46 171.71,78.56 v5(177.8,78.56) 182.24,78.56 186.59,82.91 186.59,97.08 185.29,98.38 184.66,98.38 184.06,97.78 184.06,97.2 v7(182.98,96.12)
  L4_SIG2 w0.114: v5(177.8,78.56) 178.44,79.2 178.44,84.06 v2(177.08,85.42)
  BOTTOM w0.173: U63.12 v2(177.08,85.42)
JTAG_TDO: length 123.7
  TOP w0.173: J18.4 185.65,96.62 v2(185.04,97.24) ; U1.F19 v4(109.43,77.62)
  L3_SIG1 w0.109: v4(109.43,77.62) v5(109.83,77.37) ; v5(116.84,76.03) 116.84,75.47 119.08,73.23 121.23,73.23 122.17,72.29 122.17,71.89 122.58,71.48 124.59,71.48 124.89,71.79 125.53,71.79 126.36,70.95 129.57,70.95 129.97,70.54 132.04,70.54 138.33,76.83 142.77,76.83 143.71,77.77 153.93,77.77 154.02,77.86 154.44,77.86 154.53,77.77 157.15,77.77 158.34,78.97 158.34,79.48 159.39,80.52 162.06,80.52 163.03,81.49 170.56,81.49 171.2,80.85 172.09,80.85 172.34,81.11 v5(174.75,81.11)
  L4_SIG2 w0.114: v2(173.86,61.8) 176.02,63.96 176.02,74.84 176.02,74.85 176.02,79.84 v5(174.75,81.11)
  L9_SIG3 w0.114: v5(174.75,81.11) 184.53,90.89 184.53,96.73 v2(185.04,97.24)
  L10_SIG4 w0.109: v5(116.84,76.03) 114.58,78.29 110.75,78.29 v5(109.83,77.37)
  BOTTOM w0.173: U75.2 171.24,63.96 171.55,63.65 171.55,62.84 172.59,61.8 v2(173.86,61.8)
JTAG_TMS: length 111.5
  TOP w0.173: U1.F18 v4(109.43,78.42) ; J18.2 185.92,97.12 v7(185.17,97.87)
  L3_SIG1 w0.109: v4(109.43,78.42) v5(109.83,78.17) ; v7(185.17,97.87) 186.21,96.83 186.21,83.01 184.3,81.11 175.64,81.11 174.75,82 174.24,82 173.61,82.63 v2(173.1,82.63) 172.77,82.96 168.95,82.96 167.97,81.98 162.32,81.98 161.23,80.9 157.63,80.9 156.95,80.21 156.95,79.15 156.34,78.54 155.4,78.54 154.86,79.07 153.92,79.07 153.21,78.36 143.66,78.36 142.72,77.42 136.05,77.42 133.6,74.97 132.7,74.97 129.08,71.35 126.44,71.35 125.48,72.32 124.81,72.32 124.33,72.8 122.07,72.8 121.34,73.54 119.23,73.54 117.47,75.29 v5(117.47,75.77)
  L10_SIG4 w0.109: v5(117.47,75.77) 117.47,76.35 116.99,76.83 116.61,76.83 114.8,78.64 110.31,78.64 v5(109.83,78.17)
  BOTTOM w0.173: v2(173.1,82.63) 173.1,84.92 174.25,86.07 U63.11
JTAG_TRSTN: length 115.7
  TOP w0.173: U1.D20 v4(111.03,76.82) ; J18.8 v7(185.55,95.62)
  L3_SIG1 w0.099: v4(111.03,76.82) 111.33,76.52 112.22,76.52
  L3_SIG1 w0.109: v2(183.24,95.08) 183.87,95.08 184.41,95.62 v7(185.55,95.62) 184.1,94.17 184.1,88.97 184.56,88.51 184.56,84.66 185.09,84.13 185.09,83.39 183.95,82.25 178.12,82.25 177.94,82.43 174.44,82.43 173.48,83.39 170.43,83.39 169.16,84.66 168.28,84.66 166.45,82.83 161.11,82.83 160.81,83.14 158.52,83.14 155.65,80.27 150.93,80.27 150.09,79.43 135.33,79.43 129.03,73.13 128.13,73.13 127.11,72.12 126.57,72.12 125.76,72.93 125.03,72.93 124.58,73.38 122.33,73.38 120.98,74.73 119.81,74.73 117.81,76.74 116.38,76.74 116.17,76.52 112.22,76.52
  BOTTOM w0.173: R433.2 183.12,95.2 v2(183.24,95.08) 183.24,94.33 184.01,93.57 184.01,92.16 178.56,86.72 U63.10
JTAGPOD_PRES: length 9.5
  BOTTOM w0.173: R677.1 185.76,86.88 U19.4
LCD_B0: length 44.6
  TOP w0.173: R605.1 v2(129.16,94.57)
  L10_SIG4 w0.109: v9(143.94,94.65) 143.18,95.41 140.77,95.41 140.66,95.3 140.66,94.3 140.55,94.19 140.33,94.19 140.22,94.3 140.22,95.3 140.11,95.41 139.89,95.41 139.78,95.3 139.78,94.3 139.67,94.19 139.46,94.19 139.35,94.3 139.35,95.3 139.24,95.41 139.02,95.41 138.91,95.3 138.91,94.3 138.8,94.19 138.58,94.19 138.47,94.3 138.47,95.3 138.36,95.41 138.15,95.41 138.04,95.3 138.04,94.3 137.93,94.19 137.71,94.19 137.6,94.3 137.6,95.3 137.49,95.41 137.27,95.41 137.16,95.3 137.16,94.3 137.05,94.19 136.83,94.19 136.73,94.3 136.73,95.3 136.62,95.41 136.4,95.41 136.29,95.3 136.29,94.3 136.18,94.19 135.96,94.19 135.85,94.3 135.85,95.3 135.74,95.41 135.52,95.41 135.42,95.3 135.42,94.3 135.31,94.19 135.09,94.19 134.98,94.3 134.98,95.3 134.87,95.41 134.65,95.41 134.54,95.3 134.54,94.3 134.43,94.19 134.21,94.19 134.1,94.3 134.1,95.3 134,95.41 133.78,95.41 133.67,95.3 133.67,94.3 133.56,94.19 133.34,94.19 133.23,94.3 133.23,95.3 133.12,95.41 132.9,95.41 132.79,95.3 132.79,94.3 132.68,94.19 132.47,94.19 132.36,94.3 132.36,95.3 132.25,95.41 132.03,95.41 131.12,94.49 130.41,94.49 130.21,94.69 130.21,94.91 130.1,95.03 129.93,95.03 129.82,94.91 129.82,94.69 129.7,94.57 v2(129.16,94.57)
  BOTTOM w0.173: v9(143.94,94.65) 144.55,94.65 144.72,94.82 144.72,95.26 144.9,95.43 145.24,95.43 145.41,95.26 145.41,94.82 145.59,94.65 145.92,94.65 146.54,94.03 147.91,94.03 U89.J3
LCD_B1: length 42.3
  TOP w0.173: R606.1 v2(129.16,95.59)
  L10_SIG4 w0.109: v9(146.46,94.82) 146.38,94.82 144.04,97.16 141.07,97.16 140.82,97.41 140.82,97.58 141.54,98.3 141.54,98.45 141.43,98.56 141.24,98.56 140.54,97.86 140.37,97.86 140.26,97.97 140.26,98.14 140.68,98.56 140.68,98.72 140.56,98.84 140.4,98.84 139.98,98.42 139.81,98.42 138.86,99.37 138.6,99.37 138.49,99.26 138.49,98.41 138.38,98.3 138.16,98.3 138.05,98.41 138.05,99.26 137.94,99.37 137.72,99.37 137.61,99.26 137.61,98.41 137.51,98.3 136.41,98.3 136.3,98.41 136.3,99.39 136.19,99.5 135.98,99.5 135.87,99.39 135.87,98.41 135.76,98.3 135.54,98.3 135.43,98.41 135.43,99.39 135.32,99.5 135.1,99.5 134.99,99.39 134.99,98.41 134.88,98.3 134.67,98.3 134.56,98.41 134.56,99.39 134.45,99.5 134.23,99.5 134.12,99.39 134.12,98.41 134.01,98.3 133.79,98.3 133.68,98.41 133.68,99.39 133.57,99.5 133.32,99.5 132.94,99.11 132.94,98.96 133.27,98.63 133.27,98.47 133.12,98.32 132.96,98.32 132.66,98.62 132.5,98.62 131.17,97.29 130.25,97.29 130.14,97.17 130.14,95.5 130.02,95.38 129.86,95.38 129.74,95.5 129.74,97.2 129.65,97.29 129.26,97.29 129.16,97.19 v2(129.16,95.59)
  BOTTOM w0.173: v9(146.46,94.82) 146.94,94.34 U89.K3
LCD_B2: length 34.9
  TOP w0.173: R607.1 v7(130.18,101.17)
  L3_SIG1 w0.109: v7(130.18,101.17) v5(131.32,101.17)
  L9_SIG3 w0.114: v5(142.44,90.86) 143.89,92.31 143.89,102.57 v5(143.18,103.28)
  L10_SIG4 w0.109: v5(131.32,101.17) 132.23,102.09 134.49,102.09 134.92,102.52 142.42,102.52 v5(143.18,103.28) ; v9(143.13,90.86) v5(142.44,90.86)
  BOTTOM w0.173: v9(143.13,90.86) 143.84,91.57 145.44,91.57 147.25,93.38 147.91,93.38 U89.J2
LCD_B3: length 41.3
  TOP w0.173: R608.1 130.28,85.55 v7(130.02,85.81) ; v7(142.37,89.51) 140.69,87.83 140.69,87.59 141.24,87.03 141.24,86.79 141,86.55 140.75,86.55 140.2,87.1 139.95,87.1 139.71,86.86 139.71,86.61 140.26,86.06 140.26,85.81 140.02,85.57 139.78,85.57 139.22,86.12 138.98,86.12 138.73,85.88 138.73,85.63 139.29,85.08 139.29,84.83 139.04,84.59 138.8,84.59 138.24,85.15 138,85.15 137.26,84.41 v7(135.48,84.41)
  L3_SIG1 w0.109: v5(141.66,89.51) v7(142.37,89.51) ; v7(135.48,84.41) 133.2,84.41 131.8,85.81 v7(130.02,85.81)
  L10_SIG4 w0.109: v9(141.66,90.2) v5(141.66,89.51)
  BOTTOM w0.173: v9(141.66,90.2) 141.66,90.58 141.48,90.75 140.46,90.75 140.28,90.93 140.28,91.27 140.46,91.45 141.48,91.45 141.66,91.62 141.66,91.96 141.48,92.14 140.46,92.14 140.28,92.31 140.28,92.65 140.46,92.83 141.48,92.83 141.66,93 141.66,93.32 142.02,93.69 142.48,93.69 142.65,93.52 142.65,92.56 142.82,92.38 143.17,92.38 143.34,92.56 143.34,93.52 143.52,93.69 143.86,93.69 144.03,93.52 144.03,92.56 144.21,92.38 144.55,92.38 144.72,92.56 144.72,93.52 144.9,93.69 U89.K2
LCD_B4: length 44.2
  TOP w0.173: v2(141.73,97.62) 141.28,97.62 141.07,97.41 141.07,95.56 140.87,95.36 140.59,95.36 140.38,95.56 140.38,97.82 140.16,98.05 139.09,98.05 138.76,97.72 138.76,97.24 138.59,97.06 137.89,97.06 137.72,96.89 137.72,96.54 137.89,96.37 138.59,96.37 138.76,96.2 138.76,95.85 138.59,95.68 137.89,95.68 137.72,95.51 137.72,95.16 137.89,94.99 138.59,94.99 138.76,94.82 138.76,94.47 138.59,94.3 137.89,94.3 137.72,94.13 137.72,93.78 137.89,93.61 138.59,93.61 138.76,93.44 138.76,88.8 136.09,86.14 v7(135.69,86.14) ; R609.1 v7(130.18,88.98)
  L3_SIG1 w0.109: v7(135.69,86.14) 135.26,85.7 133.45,85.7 v7(130.18,88.98)
  L10_SIG4 w0.109: v9(148.01,92.13) 147.68,92.46 147.68,93.44 147.12,94.01 147.12,94.92 146.43,95.61 146.08,95.61 144.07,97.62 v2(141.73,97.62)
  BOTTOM w0.173: U89.J1 148.01,92.83 v9(148.01,92.13)
LCD_B5: length 34.2
  TOP w0.173: R610.1 v7(130.18,102.44)
  L3_SIG1 w0.109: v7(130.18,102.44) v5(131.19,102.44)
  L9_SIG3 w0.114: v5(144.22,90.79) 144.83,91.4 v5(144.83,104.27)
  L10_SIG4 w0.109: v9(144.81,90.79) v5(144.22,90.79) ; v5(144.83,104.27) 135.69,104.27 133.86,102.44 v5(131.19,102.44)
  BOTTOM w0.173: U89.K1 145.32,90.79 v9(144.81,90.79)
LCD_B6: length 37.6
  TOP w0.173: v2(141.73,99.01) 138.5,99.01 138.05,99.47 138.05,99.79 138.22,99.97 139.6,99.97 139.78,100.14 139.78,100.48 139.6,100.66 138.22,100.66 138.05,100.83 138.05,101.17 138.22,101.35 139.6,101.35 139.78,101.52 139.78,101.86 139.6,102.04 138.22,102.04 138.05,102.21 138.05,102.56 138.22,102.73 139.6,102.73 139.78,102.9 139.78,103.25 139.6,103.42 138.22,103.42 138.05,103.59 138.05,103.96 137.66,104.35 131.57,104.35 R612.1
  L10_SIG4 w0.109: v9(149.85,94.02) 149.3,93.47 148.18,93.47 147.46,94.2 147.46,95.19 147.8,95.53 147.8,95.76 147.42,96.14 146.02,96.14 144.09,98.07 142.67,98.07 v2(141.73,99.01)
  BOTTOM w0.173: v9(149.85,94.02) U89.G2
LCD_B7: length 41.3
  TOP w0.173: R611.1 v7(130.18,98.13)
  L3_SIG1 w0.109: v7(130.18,98.13) v5(130.81,98.13)
  L10_SIG4 w0.109: v9(148.89,94.9) 149.3,95.31 149.3,96.27 149.05,96.52 148.38,96.52 148.27,96.63 148.27,97.51 148.16,97.62 147.95,97.62 147.84,97.51 147.84,96.63 147.73,96.52 147.51,96.52 147.4,96.63 147.4,97.51 147.29,97.62 147.07,97.62 146.96,97.51 146.96,96.63 146.85,96.52 146.13,96.52 145.89,96.76 145.89,96.91 146.74,97.76 146.74,97.92 146.6,98.06 146.42,98.06 145.58,97.22 145.43,97.22 145.27,97.38 145.27,97.53 146.31,98.57 146.31,98.72 146.18,98.85 145.98,98.85 144.97,97.84 144.81,97.84 144.66,97.99 144.66,98.15 145.51,99 145.51,99.15 145.36,99.29 145.18,99.29 144.35,98.46 144.19,98.46 144.04,98.61 144.04,98.77 144.65,99.37 144.65,99.53 144.49,99.68 144.34,99.68 143.73,99.08 143.57,99.08 143.18,99.47 142.91,99.47 142.8,99.36 142.8,98.87 142.69,98.76 142.47,98.76 142.36,98.87 142.36,99.36 142.25,99.47 140.79,99.47 140.51,99.19 139.52,99.19 138.81,99.9 133.1,99.9 131.32,98.13 v5(130.81,98.13)
  BOTTOM w0.173: U89.G1 149.2,93.36 149.2,93.81 149.35,93.97 149.35,94.44 v9(148.89,94.9)
LCD_BACKLIGHT: length 93.4
  TOP w0.173: R416.2 v2(78.49,148.93) ; v7(115.06,106.76) 113.9,105.6 113.9,101.3 114.09,101.1 114.09,98.58 112.03,96.51 112.03,95.84 112.28,95.59 112.28,95.09 110.64,93.45 U1.D1
  L3_SIG1 w0.109: v7(115.06,106.76) v5(115.06,106.13)
  L4_SIG2 w0.114: v5(113.92,130.26) 113.92,116 115.92,114 115.92,108 115.06,107.14 v5(115.06,106.13)
  L10_SIG4 w0.109: v5(113.92,130.26) 113.49,130.68 112.14,130.68 111.71,130.26 110.16,130.26 108.71,131.7 108.71,133.35 107.03,135.03 100.86,135.03 98.98,136.91 92.02,136.91 90.15,135.03 85.36,135.03 79.5,140.89 79.5,147.91 v2(78.49,148.93)
LCD_CLKN: length 165.2
  L10_SIG4 w0.083: v9(86.3,136.66) 86.46,136.5 89.56,136.5 90.2,137.13 90.2,141.15 91.74,142.7 98.05,142.7 99.17,143.81 114.66,143.81 116.31,142.16 122.44,142.16 123.5,141.1 132.56,141.1 134.34,139.33 147.01,139.33 147.37,138.96 148.11,138.96 149.17,137.9 152.3,137.9 154.13,136.07 155.24,136.07 159.81,131.5 159.81,123.32 158.83,122.33 158.83,113.51 151.64,106.32 151.64,103.63 150.6,102.59 150.6,100.16 v9(150.71,100.05)
  BOTTOM w0.108: J16.20 83.82,123.4 83.69,123.53 77.73,123.53 R632.1 76.96,123.53 76.35,123.53 75.18,124.69 75.18,125.34 75.44,125.59 76.47,125.59 76.58,125.7 76.58,125.92 76.47,126.03 75.44,126.03 75.18,126.28 75.18,126.71 75.44,126.97 76.47,126.97 76.58,127.07 76.58,127.29 76.47,127.4 75.44,127.4 75.18,127.65 75.18,128.08 75.44,128.34 76.47,128.34 76.58,128.44 76.58,128.66 76.47,128.77 75.44,128.77 75.18,129.03 75.18,130.51 75.97,131.3 76.34,131.3 76.79,130.85 76.94,130.85 77.09,131 77.09,131.15 76.64,131.6 76.64,131.97 76.94,132.27 77.31,132.27 77.76,131.82 77.91,131.82 78.06,131.97 78.06,132.12 77.61,132.58 77.61,132.94 77.91,133.24 78.28,133.24 78.73,132.79 78.88,132.79 79.04,132.94 79.04,133.1 78.58,133.55 78.58,133.91 78.89,134.21 79.25,134.21 79.7,133.76 79.85,133.76 80.01,133.91 80.01,134.07 79.56,134.52 79.56,134.88 79.86,135.18 80.22,135.18 80.67,134.73 80.82,134.73 80.98,134.89 80.98,135.04 80.53,135.49 80.53,135.85 81.16,136.48 86.12,136.48 v9(86.3,136.66) ; v9(150.71,100.05) 150.17,99.51 U89.F10
LCD_CLKP: length 165.4
  L10_SIG4 w0.083: v9(86.3,136.05) 86.45,136.2 89.69,136.2 90.5,137.01 90.5,141.02 91.87,142.39 98.18,142.39 99.29,143.51 114.54,143.51 116.18,141.86 122.31,141.86 123.37,140.8 132.44,140.8 134.21,139.02 146.88,139.02 147.25,138.66 147.98,138.66 149.05,137.59 152.17,137.59 154,135.76 155.12,135.76 159.51,131.37 159.51,123.45 158.52,122.46 158.52,113.64 151.33,106.45 151.33,103.76 150.29,102.72 150.29,100.25 v9(150.1,100.05)
  BOTTOM w0.108: J16.21 83.79,123.9 83.67,123.78 77.72,123.78 R632.2 76.96,123.78 76.45,123.78 75.44,124.8 75.44,125.23 75.55,125.34 76.58,125.34 76.83,125.6 76.83,126.02 76.58,126.28 75.55,126.28 75.44,126.39 75.44,126.6 75.55,126.71 76.58,126.71 76.83,126.97 76.83,127.39 76.58,127.65 75.55,127.65 75.44,127.76 75.44,127.97 75.55,128.08 76.58,128.08 76.83,128.34 76.83,128.77 76.58,129.02 75.55,129.02 75.44,129.13 75.44,130.4 76.08,131.04 76.23,131.04 76.68,130.59 77.04,130.59 77.35,130.9 77.35,131.26 76.9,131.71 76.9,131.86 77.05,132.02 77.2,132.02 77.65,131.56 78.02,131.56 78.32,131.87 78.32,132.23 77.87,132.68 77.87,132.83 78.02,132.99 78.17,132.99 78.62,132.53 78.99,132.53 79.29,132.84 79.29,133.2 78.84,133.65 78.84,133.81 78.99,133.96 79.14,133.96 79.6,133.51 79.96,133.51 80.26,133.81 80.26,134.17 79.81,134.62 79.81,134.78 79.96,134.93 80.12,134.93 80.57,134.48 80.93,134.48 81.23,134.78 81.23,135.14 80.78,135.59 80.78,135.75 81.26,136.23 82.15,136.23 82.26,136.12 82.26,135.8 82.37,135.69 82.58,135.69 82.69,135.8 82.69,136.12 82.8,136.23 86.12,136.23 v9(86.3,136.05) ; U89.F9 149.85,98.56 149.85,99.01 149.92,99.08 149.92,99.87 v9(150.1,100.05)
LCD_DEN: length 64.7
  TOP w0.173: R634.1 v7(121.54,87.08)
  L3_SIG1 w0.109: v7(121.54,87.08) v5(122.05,87.58)
  L10_SIG4 w0.109: v5(122.05,87.58) 122.1,87.63 122.1,88.5 121.99,88.61 120.63,88.61 120.52,88.72 120.52,88.94 120.63,89.05 121.99,89.05 122.1,89.16 122.1,89.38 121.99,89.49 120.63,89.49 120.52,89.6 120.52,89.81 120.63,89.92 121.99,89.92 122.1,90.03 122.1,90.25 121.99,90.36 120.63,90.36 120.52,90.47 120.52,90.69 120.63,90.8 121.99,90.8 122.1,90.91 122.1,91.87 121.99,91.98 121.39,91.98 121.28,92.09 121.28,92.31 121.39,92.42 121.99,92.42 122.1,92.53 122.1,93.53 122.17,93.61 122.17,94.14 126.9,98.86 127.05,98.86 127.53,98.39 127.69,98.39 127.81,98.5 127.81,98.67 127.33,99.15 127.33,99.31 127.44,99.43 127.61,99.43 128.65,98.39 128.81,98.39 128.93,98.51 128.93,98.67 127.89,99.71 127.89,99.88 128.08,100.07 128.24,100.07 128.66,99.65 128.83,99.65 128.94,99.76 128.94,99.93 128.52,100.35 128.52,100.51 128.75,100.74 129.16,100.74 129.28,100.63 129.28,99.26 129.39,99.14 129.56,99.14 129.67,99.26 129.67,99.8 129.79,99.91 130.34,99.91 130.45,100.03 130.45,100.19 130.34,100.31 129.79,100.31 129.67,100.42 129.67,100.63 129.79,100.74 130.37,100.74 130.49,100.86 130.49,101.31 130.37,101.43 129.94,101.43 129.82,101.54 129.82,101.93 130.07,102.18 130.75,102.18 130.86,102.07 130.86,100.88 131.03,100.72 131.65,100.72 132.66,101.73 140.84,101.73 141.02,101.55 141.02,101.17 140.89,101.05 v9(140.46,101.05)
  BOTTOM w0.173: U89.J7 147.91,97.25 145.57,97.25 143.81,99.01 142.49,99.01 v9(140.46,101.05)
LCD_G0: length 49.2
  TOP w0.173: v7(126.62,92.16) 127.34,92.16 R613.1
  L3_SIG1 w0.109: v7(126.62,92.16) v5(127.38,92.16)
  L10_SIG4 w0.109: v9(148.84,84.82) 148.34,85.32 145.57,85.32 143.26,87.63 142.53,87.63 142.42,87.74 142.42,87.98 142.31,88.09 142.1,88.09 141.99,87.98 141.99,87.74 141.88,87.63 141.66,87.63 141.55,87.74 141.55,87.98 141.44,88.09 141.22,88.09 141.11,87.98 141.11,87.74 141,87.63 140.79,87.63 140.68,87.74 140.68,87.98 140.57,88.09 140.35,88.09 140.24,87.98 140.24,87.74 140.13,87.63 139.91,87.63 139.8,87.74 139.8,87.98 139.69,88.09 139.48,88.09 139.37,87.98 139.37,87.74 139.26,87.63 139.04,87.63 138.93,87.74 138.93,87.98 138.82,88.09 138.6,88.09 138.49,87.98 138.49,87.74 138.38,87.63 138.16,87.63 138.06,87.74 138.06,87.98 137.95,88.09 137.73,88.09 137.62,87.98 137.62,87.74 137.51,87.63 136.9,87.63 136.55,87.99 134.4,87.99 132.03,90.35 131.75,90.35 131.63,90.24 131.63,89.76 131.52,89.64 131.35,89.64 131.24,89.76 131.24,90.24 131.12,90.35 130.96,90.35 130.84,90.24 130.84,89.76 130.73,89.64 130.56,89.64 130.45,89.76 130.45,90.24 130.33,90.35 130.17,90.35 130.05,90.24 130.05,89.76 129.93,89.64 129.77,89.64 129.65,89.76 129.65,90.24 129.54,90.35 129.29,90.35 128.36,91.28 128.06,91.28 127.95,91.39 127.95,91.61 127.84,91.72 126.88,91.72 126.77,91.61 126.77,91.4 126.65,91.28 126.49,91.28 126.37,91.4 126.37,91.61 126.25,91.72 126.09,91.72 125.97,91.61 125.97,91.4 125.86,91.28 125.19,91.28 124.94,91.53 124.94,91.95 125.15,92.16 v5(127.38,92.16)
  BOTTOM w0.173: v9(148.84,84.82) 148.84,91.14 149.83,92.13 149.83,93.35 U89.F2
LCD_G1: length 51.3
  TOP w0.173: R614.1 v7(126.62,89.36)
  L3_SIG1 w0.109: v5(127.51,89.74) 127.51,89.71 127.16,89.36 v7(126.62,89.36)
  L10_SIG4 w0.109: v9(149.48,83.47) 145.16,83.47 144.64,83.99 144.29,83.99 144.18,84.09 144.18,84.66 144.07,84.76 143.85,84.76 143.74,84.66 143.74,84.09 143.63,83.99 143.41,83.99 143.3,84.09 143.3,84.66 143.19,84.76 142.98,84.76 142.87,84.66 142.87,84.09 142.76,83.99 142.54,83.99 142.43,84.09 142.43,84.66 142.32,84.76 142.1,84.76 141.99,84.66 141.99,84.09 141.88,83.99 141.67,83.99 141.56,84.09 141.56,84.66 141.45,84.76 141.23,84.76 141.12,84.66 141.12,84.09 141.01,83.99 140.79,83.99 140.68,84.09 140.68,84.66 140.57,84.76 140.35,84.76 140.25,84.66 140.25,84.09 140.14,83.99 139.92,83.99 139.81,84.09 139.81,84.66 139.7,84.76 139.48,84.76 139.37,84.66 139.37,84.09 139.26,83.99 139.04,83.99 138.93,84.09 138.93,84.66 138.83,84.76 138.61,84.76 138.5,84.66 138.5,84.09 138.39,83.99 138.09,83.99 135.5,86.57 133.2,86.57 131.78,87.99 129.26,87.99 v5(127.51,89.74)
  BOTTOM w0.173: U89.F1 150.17,91.9 149.48,91.21 149.48,87.91 149.65,87.74 150.5,87.74 150.67,87.57 150.67,87.22 150.5,87.05 149.65,87.05 149.48,86.88 149.48,86.53 149.65,86.36 150.5,86.36 150.67,86.19 150.67,85.84 150.5,85.67 149.65,85.67 149.48,85.5 149.48,85.15 149.65,84.98 150.5,84.98 150.67,84.81 150.67,84.46 150.5,84.29 149.65,84.29 149.48,84.11 v9(149.48,83.47)
LCD_G2: length 43.4
  TOP w0.173: R616.1 v7(130.18,96.22)
  L3_SIG1 w0.109: v7(130.18,96.22) v5(130.81,96.22)
  L10_SIG4 w0.109: v9(150.24,91.27) 150.24,91.92 150.53,92.21 152.76,92.21 152.87,92.1 152.87,91.76 152.98,91.65 154.13,91.65 154.69,92.21 154.69,93.5 154.13,94.06 153.53,94.06 153.42,94.17 153.42,94.84 153.31,94.95 153.09,94.95 152.98,94.84 152.98,94.17 152.87,94.06 152.65,94.06 152.54,94.17 152.54,94.84 152.43,94.95 152.22,94.95 152.11,94.84 152.11,94.17 152,94.06 151.56,94.06 150.11,92.61 149.19,92.61 148.29,91.7 147.65,91.7 147.35,92 147.35,93.3 143.92,96.73 140.92,96.73 139.7,97.95 132.54,97.95 v5(130.81,96.22)
  BOTTOM w0.173: v9(150.24,91.27) 150.51,91.53 150.51,93.38 U89.E2
LCD_G3: length 44.5
  TOP w0.173: R615.1 v7(130.18,92.79)
  L3_SIG1 w0.109: v7(130.18,92.79) v5(130.81,92.79)
  L10_SIG4 w0.109: v9(150.11,89.24) 150.9,89.24 151.89,90.23 152.96,90.23 153.24,90.5 153.24,91.06 153.42,91.24 154.1,91.24 154.38,90.96 154.38,90.09 153.01,88.73 152.43,88.73 152.33,88.84 152.33,89.43 152.22,89.54 152,89.54 151.89,89.43 151.89,88.84 151.78,88.73 149.96,88.73 149.22,89.47 149.06,89.47 148.68,89.09 148.53,89.09 148.37,89.25 148.37,89.4 148.75,89.78 148.75,89.94 148.23,90.46 147.96,90.46 147.86,90.35 147.86,89.6 147.75,89.49 147.53,89.49 147.42,89.6 147.42,90.35 147.31,90.46 147.09,90.46 146.98,90.35 146.98,89.6 146.87,89.49 146.65,89.49 146.54,89.6 146.54,90.35 146.44,90.46 145.77,90.46 144.56,91.66 144.41,91.66 144.21,91.46 144.05,91.46 143.9,91.61 143.9,91.77 144.1,91.97 144.1,92.12 143.87,92.36 131.24,92.36 v5(130.81,92.79)
  BOTTOM w0.173: v9(150.11,89.24) 150.11,90.44 150.82,91.15 U89.E1
LCD_G4: length 58.8
  TOP w0.173: R617.1 v7(122.81,96.35)
  L3_SIG1 w0.109: v7(122.81,96.35) 126.03,96.35 v5(126.06,96.32)
  L10_SIG4 w0.109: v5(126.06,96.32) 126.16,96.22 126.84,96.22 126.95,96.33 126.95,96.48 126.58,96.85 126.58,97.02 126.7,97.13 126.86,97.13 127.24,96.75 127.41,96.75 127.94,97.29 128.13,97.29 128.24,97.18 128.24,97.02 127.1,95.88 127.1,95.72 127.21,95.6 127.38,95.6 128.52,96.74 128.69,96.74 128.8,96.63 128.8,96.46 127.66,95.32 127.66,95.16 127.91,94.9 128.06,94.9 128.3,95.14 128.46,95.14 128.61,94.99 128.61,94.83 128.37,94.6 128.37,94.44 128.7,94.11 129.18,94.11 129.92,93.38 131.17,93.38 131.78,92.77 132.21,92.77 132.32,92.87 132.32,93.24 132.42,93.35 132.64,93.35 132.75,93.24 132.75,92.87 132.86,92.77 133.08,92.77 133.19,92.87 133.19,93.24 133.3,93.35 133.52,93.35 133.63,93.24 133.63,92.87 133.74,92.77 133.95,92.77 134.06,92.87 134.06,93.24 134.17,93.35 134.39,93.35 134.5,93.24 134.5,92.87 134.61,92.77 134.83,92.77 134.94,92.87 134.94,93.24 135.05,93.35 135.26,93.35 135.37,93.24 135.37,92.87 135.48,92.77 135.7,92.77 135.81,92.87 135.81,93.24 135.92,93.35 136.14,93.35 136.25,93.24 136.25,92.87 136.36,92.77 136.57,92.77 136.68,92.87 136.68,93.24 136.79,93.35 137.01,93.35 137.12,93.24 137.12,92.87 137.23,92.77 137.45,92.77 137.56,92.87 137.56,93.24 137.67,93.35 137.89,93.35 137.99,93.24 137.99,92.87 138.1,92.77 138.32,92.77 138.43,92.87 138.43,93.24 138.54,93.35 138.76,93.35 138.87,93.24 138.87,92.87 138.98,92.77 139.2,92.77 139.31,92.87 139.31,93.24 139.41,93.35 139.63,93.35 139.74,93.24 139.74,92.87 139.85,92.77 140.07,92.77 140.18,92.87 140.18,93.24 140.29,93.35 140.51,93.35 140.62,93.24 140.62,92.87 140.73,92.77 140.94,92.77 141.05,92.87 141.05,93.24 141.16,93.35 141.38,93.35 141.49,93.24 141.49,92.87 141.6,92.77 141.82,92.77 141.93,92.87 141.93,93.24 142.04,93.35 142.25,93.35 142.36,93.24 142.36,92.87 142.47,92.77 142.69,92.77 142.8,92.87 142.8,93.24 142.91,93.35 143.13,93.35 143.24,93.24 143.24,92.87 143.35,92.77 144.04,92.77 144.56,92.25 144.72,92.25 145.07,92.6 145.23,92.6 145.38,92.44 145.38,92.29 145.03,91.94 145.03,91.78 145.18,91.63 145.34,91.63 145.69,91.98 145.84,91.98 146,91.83 146,91.67 145.65,91.32 145.65,91.16 146,90.81 148.79,90.81 149.86,89.74 v9(150.75,89.74)
  BOTTOM w0.173: v9(150.75,89.74) 150.75,90.51 151.13,90.89 151.13,93.35 U89.D2
LCD_G5: length 43.9
  TOP w0.173: v5(130.94,99.4) v7(130.18,99.4)
  L3_SIG1 w0.109: v7(130.18,99.4) v5(130.94,99.4)
  L10_SIG4 w0.109: v9(151.38,88.09) 153.09,88.09 155.19,90.2 155.19,95.79 151.84,99.14 148.54,99.14 147.85,99.83 146.51,99.83 146.24,99.56 145.63,99.56 145.16,100.03 140.08,100.03 139.32,100.79 132.97,100.79 132.01,99.83 131.37,99.83 v5(130.94,99.4)
  BOTTOM w0.173: v9(151.38,88.09) 151.36,88.11 151.36,90.38 151.47,90.48 U89.D1
LCD_G6: length 45.8
  TOP w0.173: R620.1 v7(130.18,91.52)
  L3_SIG1 w0.109: v7(130.18,91.52) v5(130.81,91.52)
  L10_SIG4 w0.109: v9(152.65,86.66) 152.21,87.1 151.93,87.1 151.82,86.99 151.82,86.55 151.71,86.44 151.49,86.44 151.38,86.55 151.38,86.99 151.27,87.1 151.06,87.1 150.95,86.99 150.95,86.55 150.84,86.44 150.62,86.44 150.51,86.55 150.51,86.99 150.4,87.1 150.18,87.1 150.07,86.99 150.07,86.55 149.96,86.44 149.75,86.44 149.64,86.55 149.64,86.99 149.53,87.1 149.31,87.1 149.2,86.99 149.2,86.55 149.09,86.44 148.87,86.44 148.76,86.55 148.76,86.99 148.65,87.1 148.43,87.1 148.33,86.99 148.33,86.55 148.22,86.44 148,86.44 147.89,86.55 147.89,86.99 147.78,87.1 147.56,87.1 147.45,86.99 147.45,86.55 147.34,86.44 147.12,86.44 147.01,86.55 147.01,86.99 146.91,87.1 146.69,87.1 146.58,86.99 146.58,86.55 146.47,86.44 146.25,86.44 146.14,86.55 146.14,86.99 146.03,87.1 145.49,87.1 145.02,87.58 145.02,87.73 145.45,88.16 145.45,88.31 145.29,88.47 145.14,88.47 144.71,88.04 144.55,88.04 144.4,88.19 144.4,88.35 144.83,88.78 144.83,88.93 144.67,89.09 144.52,89.09 144.09,88.66 143.94,88.66 143.78,88.81 143.78,88.97 144.21,89.4 144.21,89.55 144.06,89.71 143.9,89.71 143.47,89.28 143.32,89.28 143.16,89.43 143.16,89.58 143.59,90.01 143.59,90.17 143.44,90.32 143.28,90.32 142.85,89.89 142.7,89.89 141.94,90.66 138.99,90.66 138.13,91.52 v5(130.81,91.52)
  BOTTOM w0.173: U89.C2 152.12,93.48 151.78,93.15 151.78,90.49 151.99,90.28 151.99,87.32 v9(152.65,86.66)
LCD_G7: length 45.5
  TOP w0.173: R618.1 v7(130.18,94.95)
  L3_SIG1 w0.109: v7(130.18,94.95) v5(130.81,94.95)
  L10_SIG4 w0.109: v5(130.81,94.95) 131.22,95.36 131.22,95.76 131.72,96.27 132.68,96.27 132.79,96.38 132.79,96.72 132.9,96.83 133.12,96.83 133.23,96.72 133.23,96.38 133.34,96.27 133.56,96.27 133.67,96.38 133.67,96.72 133.77,96.83 133.99,96.83 134.1,96.72 134.1,96.38 134.21,96.27 134.43,96.27 134.54,96.38 134.54,96.72 134.65,96.83 134.87,96.83 134.98,96.72 134.98,96.38 135.09,96.27 135.3,96.27 135.41,96.38 135.41,96.72 135.52,96.83 135.74,96.83 135.85,96.72 135.85,96.38 135.96,96.27 136.18,96.27 136.29,96.38 136.29,96.72 136.4,96.83 136.61,96.83 136.72,96.72 136.72,96.38 136.83,96.27 137.05,96.27 137.16,96.38 137.16,96.72 137.27,96.83 137.49,96.83 137.6,96.72 137.6,96.38 137.71,96.27 137.93,96.27 138.03,96.38 138.03,96.72 138.14,96.83 138.36,96.83 138.47,96.72 138.47,96.38 138.58,96.27 138.8,96.27 138.91,96.38 138.91,96.72 139.02,96.83 139.24,96.83 139.34,96.72 139.34,96.38 139.45,96.27 140.89,96.27 141.4,95.76 143.46,95.76 143.67,95.55 143.82,95.55 144.14,95.87 144.29,95.87 144.45,95.71 144.45,95.56 144.13,95.25 144.13,95.09 144.29,94.94 144.44,94.94 144.76,95.25 144.91,95.25 145.06,95.1 145.06,94.94 144.75,94.63 144.75,94.47 144.9,94.32 145.06,94.32 145.37,94.63 145.53,94.63 145.68,94.48 145.68,94.32 145.37,94.01 145.37,93.85 145.52,93.7 145.68,93.7 145.99,94.01 146.15,94.01 146.3,93.86 146.3,93.71 145.99,93.39 145.99,93.24 146.14,93.08 146.3,93.08 146.61,93.4 146.76,93.4 146.92,93.24 146.92,93.09 146.6,92.77 146.6,92.62 146.95,92.27 146.95,91.84 147.64,91.15 148.74,91.15 148.85,91.26 148.85,91.77 148.96,91.88 149.17,91.88 149.28,91.77 149.28,91.26 149.39,91.15 149.6,91.15 149.99,90.76 150.66,90.76 150.78,90.88 150.78,91.71 150.89,91.83 151.15,91.83 151.25,91.72 151.25,91 151.36,90.89 151.58,90.89 151.69,91 151.69,91.72 151.8,91.83 152.16,91.83 152.27,91.72 v9(152.27,90.76)
  BOTTOM w0.173: v9(152.27,90.76) 152.12,90.91 U89.C1
LCD_HS: length 59
  TOP w0.173: 124.59,86.31 v7(125.35,86.31)
  L3_SIG1 w0.109: v7(125.35,86.31) v5(125.98,86.31)
  L10_SIG4 w0.109: v9(141.48,100.89) 141.48,101.81 141.68,102.01 142.07,102.01 142.18,101.9 142.18,101.16 142.29,101.05 142.5,101.05 142.61,101.16 142.61,101.9 142.72,102.01 143.68,102.01 143.79,101.9 143.79,101.16 143.9,101.05 144.12,101.05 144.23,101.16 144.23,101.9 144.34,102.01 144.75,102.01 145.03,101.73 145.03,100.79 144.63,100.39 140.36,100.39 139.37,101.38 132.79,101.38 131.7,100.28 131.19,100.28 128.96,98.05 126.57,98.05 123.43,94.91 123.43,94.28 123.06,93.9 122.65,93.9 122.53,93.79 122.53,93.62 122.65,93.51 123.05,93.51 123.17,93.39 123.17,93.23 123.05,93.11 122.57,93.11 122.45,92.99 122.45,92.83 122.57,92.71 123.05,92.71 123.17,92.6 123.17,92.43 123.05,92.32 122.57,92.32 122.45,92.2 122.45,92.04 122.57,91.92 123.05,91.92 123.17,91.8 123.17,88.39 123.05,88.27 122.8,88.27 122.68,88.16 122.68,87.99 122.8,87.88 123.05,87.88 123.17,87.76 123.17,87.6 123.05,87.48 122.8,87.48 122.68,87.36 122.68,87.2 122.8,87.08 123.1,87.08 123.22,86.97 123.22,86.67 123.93,85.96 125.63,85.96 v5(125.98,86.31)
  BOTTOM w0.173: U89.K8 146.43,97.59 143.81,100.21 142.16,100.21 v9(141.48,100.89)
LCD_MIPI0N: length 164.4
  L10_SIG4 w0.083: v9(148.4,100.31) 148.26,100.44 148.26,108.89 151.67,112.3 153.75,112.3 157.04,115.58 157.04,123.97 157.61,124.54 157.61,131.11 154.48,134.24 150.17,134.24 147.35,137.06 146.75,137.06 146.29,137.52 133.85,137.52 133.04,136.71 124.46,136.71 124.19,136.45 124.19,135.77 124.11,135.69 123.95,135.69 123.86,135.77 123.86,136.45 123.6,136.71 123.19,136.71 122.92,136.45 122.92,135.77 122.84,135.69 122.68,135.69 122.59,135.77 122.59,136.45 122.33,136.71 121.92,136.71 121.65,136.45 121.65,135.77 121.57,135.69 121.41,135.69 121.32,135.77 121.32,136.45 121.06,136.71 120.65,136.71 120.38,136.45 120.38,135.77 120.3,135.69 120.14,135.69 120.05,135.77 120.05,136.45 119.79,136.71 118.1,136.71 118.01,136.79 118.01,137.77 117.75,138.03 117.34,138.03 117.07,137.77 117.07,136.79 116.99,136.71 116.83,136.71 116.74,136.79 116.74,137.77 116.48,138.03 116.07,138.03 115.8,137.77 115.8,136.79 115.72,136.71 115.56,136.71 115.47,136.79 115.47,137.77 115.21,138.03 114.8,138.03 114.53,137.77 114.53,136.79 114.45,136.71 114.29,136.71 114.2,136.79 114.2,137.77 113.94,138.03 113.53,138.03 113.26,137.77 113.26,136.79 113.18,136.71 112.41,136.71 107.14,141.98 99.89,141.98 98.06,140.16 94.95,140.16 93.29,138.51 91.62,138.51 v9(91.49,138.64)
  BOTTOM w0.108: U89.J10 148.22,100.13 v9(148.4,100.31) ; v9(91.49,138.64) 91.31,138.46 81.87,138.46 74.3,130.89 74.3,123.67 75.97,122 78.23,122 R630.2 79.02,122.03 83.69,122.03 83.81,121.9 J16.17
LCD_MIPI0P: length 164.4
  L10_SIG4 w0.083: v9(91.49,138.03) 91.67,138.21 93.42,138.21 95.07,139.86 98.19,139.86 100.01,141.68 107.01,141.68 112.29,136.4 113.31,136.4 113.57,136.66 113.57,137.64 113.65,137.72 113.82,137.72 113.9,137.64 113.9,136.66 114.16,136.4 114.58,136.4 114.84,136.66 114.84,137.64 114.92,137.72 115.09,137.72 115.17,137.64 115.17,136.66 115.43,136.4 115.85,136.4 116.11,136.66 116.11,137.64 116.19,137.72 116.36,137.72 116.44,137.64 116.44,136.66 116.7,136.4 117.12,136.4 117.38,136.66 117.38,137.64 117.46,137.72 117.63,137.72 117.71,137.64 117.71,136.66 117.97,136.4 119.67,136.4 119.75,136.32 119.75,135.65 120.01,135.39 120.43,135.39 120.69,135.65 120.69,136.32 120.77,136.4 120.94,136.4 121.02,136.32 121.02,135.65 121.28,135.39 121.7,135.39 121.96,135.65 121.96,136.32 122.04,136.4 122.21,136.4 122.29,136.32 122.29,135.65 122.55,135.39 122.97,135.39 123.23,135.65 123.23,136.32 123.31,136.4 123.48,136.4 123.56,136.32 123.56,135.65 123.82,135.39 124.24,135.39 124.5,135.65 124.5,136.32 124.58,136.4 133.17,136.4 133.98,137.21 146.16,137.21 146.62,136.75 147.22,136.75 150.04,133.93 154.36,133.93 157.3,130.99 157.3,124.67 156.73,124.1 156.73,115.71 153.62,112.6 151.54,112.6 147.96,109.02 147.96,100.47 v9(147.79,100.31)
  BOTTOM w0.108: v9(91.49,138.03) 91.31,138.21 84.37,138.21 84.26,138.1 84.26,137.93 84.16,137.83 83.94,137.83 83.83,137.93 83.83,138.1 83.73,138.21 81.97,138.21 74.55,130.79 74.55,123.78 76.07,122.26 78.23,122.26 R630.1 78.96,122.28 83.7,122.28 83.82,122.4 J16.18 ; v9(147.79,100.31) 147.97,100.13 147.97,99.08 147.9,99.01 147.9,98.56 U89.J9
LCD_MIPI1N: length 165.6
  L10_SIG4 w0.083: v9(149.7,100.94) 149.7,102.17 149.33,102.54 149.33,108.08 152.27,111.03 154.13,111.03 157.93,114.83 157.93,122.7 158.92,123.69 158.92,131.1 154.88,135.13 150.54,135.13 147.62,138.05 147.02,138.05 146.64,138.43 133.5,138.43 132.77,137.7 128.3,137.7 128.22,137.78 128.22,139.06 127.95,139.32 127.54,139.32 127.28,139.06 127.28,137.78 127.19,137.7 127.03,137.7 126.95,137.78 126.95,139.06 126.68,139.32 126.27,139.32 126.01,139.06 126.01,137.78 125.92,137.7 125.76,137.7 125.68,137.78 125.68,139.06 125.41,139.32 125,139.32 124.74,139.06 124.74,137.78 124.65,137.7 124.49,137.7 124.41,137.78 124.41,139.06 124.14,139.32 123.73,139.32 123.47,139.06 123.47,137.78 123.38,137.7 119.41,137.7 114.22,142.89 99.52,142.89 98.18,141.55 94.34,141.55 92.58,139.8 91.59,139.8 v9(91.44,139.95)
  BOTTOM w0.108: v9(149.7,100.94) 149.52,100.77 U89.G10 ; v9(91.44,139.95) 91.19,139.95 90.93,139.7 81.83,139.7 73.41,131.27 73.41,122.78 75.71,120.48 76.96,120.48 R631.2 77.78,120.53 83.69,120.53 83.82,120.4 J16.14
LCD_MIPI1P: length 165.3
  L10_SIG4 w0.083: v9(91.44,139.32) 91.62,139.5 92.71,139.5 94.46,141.25 98.31,141.25 99.64,142.58 114.09,142.58 119.28,137.39 123.51,137.39 123.77,137.65 123.77,138.94 123.85,139.02 124.02,139.02 124.1,138.94 124.1,137.65 124.36,137.39 124.78,137.39 125.04,137.65 125.04,138.94 125.12,139.02 125.29,139.02 125.37,138.94 125.37,137.65 125.63,137.39 126.05,137.39 126.31,137.65 126.31,138.94 126.39,139.02 126.56,139.02 126.64,138.94 126.64,137.65 126.9,137.39 127.32,137.39 127.58,137.65 127.58,138.94 127.66,139.02 127.83,139.02 127.91,138.94 127.91,137.65 128.17,137.39 132.64,137.39 132.89,137.39 133.63,138.13 146.51,138.13 146.9,137.74 147.5,137.74 150.41,134.83 154.76,134.83 158.61,130.97 158.61,123.82 157.63,122.83 157.63,114.95 154.01,111.33 152.15,111.33 149.02,108.21 149.02,102.41 149.39,102.04 149.39,101.25 v9(149.09,100.94)
  BOTTOM w0.108: J16.15 83.79,120.9 83.67,120.78 77.67,120.78 R631.1 76.96,120.73 75.82,120.73 73.66,122.89 73.66,131.17 81.94,139.45 83.52,139.45 83.63,139.34 83.63,139.3 83.74,139.19 83.95,139.19 84.06,139.3 84.06,139.34 84.17,139.45 91.31,139.45 v9(91.44,139.32) ; U89.G9 149.2,98.56 149.2,99.01 149.27,99.08 149.27,100.77 v9(149.09,100.94)
LCD_MIPI2N: length 164.6
  L10_SIG4 w0.083: v9(86.5,142.17) 86.49,142.17 86.49,142.11 87.97,142.11 88.04,142.03 88.77,142.03 90.43,143.69 97.71,143.69 98.74,144.72 115.12,144.72 116,143.84 122.12,143.84 122.67,143.29 125.91,143.29 127.18,142.02 145.66,142.02 147.73,139.95 149.38,139.95 150.44,138.89 152.81,138.89 154.71,136.98 155.65,136.98 160.71,131.92 160.71,119.18 160.28,118.75 160.28,117.83 161.44,116.67 161.44,113.9 158.62,111.07 158.62,109.79 159.02,109.38 159.02,109.01 158.73,108.72 158.36,108.72 157.95,109.12 157.83,109.12 157.72,109.01 157.72,108.89 158.12,108.48 158.12,108.11 157.83,107.82 157.46,107.82 157.05,108.22 156.74,108.22 156.49,107.97 156.49,107.29 156.18,106.98 154.33,106.98 154.18,106.84 154.18,106.55 154.6,106.13 154.6,105.58 154.05,105.03 154.05,103.97 151.51,101.43 151.51,101.08 v9(151.65,100.94)
  BOTTOM w0.108: v9(151.65,100.94) 151.47,100.77 U89.D10 ; J16.11 84.07,118.9 84.07,118.91 83.82,118.91 83.69,119.03 79.07,119.03 R633.1 78.23,118.95 75.46,118.95 72.52,121.9 72.52,131.65 82.85,141.99 86.36,141.99 86.49,142.11 86.49,142.17 v9(86.5,142.17)
LCD_MIPI2P: length 164.5
  L10_SIG4 w0.083: v9(151.04,100.94) 151.21,101.11 151.21,101.55 153.75,104.09 153.75,105.16 154.29,105.7 154.29,106.01 153.88,106.42 153.88,106.97 154.2,107.29 156.06,107.29 156.18,107.42 156.18,108.1 156.62,108.53 157.18,108.53 157.58,108.12 157.7,108.12 157.82,108.24 157.82,108.36 157.41,108.76 157.41,109.13 157.71,109.43 158.08,109.43 158.48,109.02 158.6,109.02 158.72,109.14 158.72,109.26 158.31,109.66 158.31,111.2 161.14,114.02 161.14,116.54 159.98,117.7 159.98,118.88 160.4,119.3 160.4,131.8 155.52,136.68 154.58,136.68 152.68,138.58 150.32,138.58 149.25,139.65 147.6,139.65 145.54,141.71 127.05,141.71 125.78,142.98 122.54,142.98 121.99,143.54 115.87,143.54 114.99,144.42 98.87,144.42 97.84,143.39 90.56,143.39 88.9,141.73 88.08,141.73 87.83,141.48 v9(86.49,141.48)
  BOTTOM w0.108: U89.D9 151.15,98.56 151.15,99.01 151.22,99.08 151.22,100.77 v9(151.04,100.94) ; J16.12 83.79,119.4 83.67,119.28 78.92,119.28 R633.2 78.23,119.21 75.56,119.21 72.77,122 72.77,131.55 82.96,141.74 84.84,141.74 84.95,141.63 84.95,141.46 85.05,141.36 85.27,141.36 85.38,141.46 85.38,141.63 85.48,141.74 86.23,141.74 v9(86.49,141.48)
LCD_MIPI3N: length 166
  L10_SIG4 w0.083: v9(86.49,144.12) 86.64,143.97 88.88,143.97 90.04,145.14 97.64,145.14 98.14,145.63 115.6,145.63 116.41,144.82 123.33,144.82 123.87,144.28 130.51,144.28 131.82,142.97 135.52,142.97 135.89,143.33 147.44,143.33 150.9,139.88 153.26,139.88 155.24,137.9 156.11,137.9 161.77,132.23 161.77,118.38 162.43,117.72 162.43,110.16 158.98,106.71 157.63,106.71 155.89,104.96 155.89,104.17 152.51,100.79 152.51,100.21 v9(152.66,100.05)
  BOTTOM w0.108: v9(86.49,144.12) 86.33,143.97 83.59,143.97 71.63,132.01 71.63,121.01 75.08,117.56 76.96,117.56 R687.1 77.7,117.53 83.69,117.53 83.82,117.4 J16.8 ; U89.C10 152.12,99.51 v9(152.66,100.05)
LCD_MIPI3P: length 166.1
  L10_SIG4 w0.083: v9(86.49,143.51) 86.64,143.67 89.01,143.67 90.17,144.83 97.76,144.83 98.26,145.33 115.47,145.33 116.28,144.52 123.2,144.52 123.74,143.97 130.38,143.97 131.7,142.66 135.65,142.66 136.02,143.03 147.32,143.03 150.77,139.57 153.14,139.57 155.12,137.59 155.98,137.59 161.47,132.11 161.47,118.26 162.13,117.6 162.13,110.29 158.85,107.01 157.51,107.01 155.58,105.09 155.58,104.3 152.2,100.92 152.2,100.21 v9(152.05,100.05)
  BOTTOM w0.108: U89.C9 151.82,98.55 151.82,99.82 v9(152.05,100.05) ; J16.9 83.79,117.9 83.67,117.78 77.75,117.78 R687.2 76.96,117.81 75.18,117.81 71.88,121.11 71.88,131.91 83.69,143.72 84.68,143.72 84.79,143.61 84.79,143.32 84.89,143.21 85.11,143.21 85.22,143.32 85.22,143.61 85.32,143.72 86.28,143.72 v9(86.49,143.51)
LCD_PCLK: length 56.6
  TOP w0.173: v7(136.7,85.25) 139.83,88.37 139.83,89.92 140.03,90.12 144.48,90.12 144.68,90.33 144.68,90.61 144.48,90.82 140.03,90.82 139.83,91.02 139.83,91.3 140.03,91.51 143.76,91.51 143.97,91.71 143.97,95.36 143.76,95.56 143.48,95.56 143.28,95.36 143.28,94.23 143.07,94.03 141.78,94.03 141.61,93.85 141.61,93.56 141.83,93.34 143.07,93.34 143.28,93.13 143.28,92.4 143.07,92.2 140.03,92.2 139.83,92.4 139.83,94.14 140.39,94.7 v2(141.48,94.7) ; R565.1 v7(129.16,86.82)
  L3_SIG1 w0.109: v7(136.7,85.25) 136.6,85.35 133.2,85.35 131.27,87.28 129.62,87.28 v7(129.16,86.82)
  BOTTOM w0.173: U89.J6 147.91,96.6 145.28,96.6 145.03,96.86 141.99,96.86 141.48,96.35 v2(141.48,94.7)
LCD_R0: length 57.9
  TOP w0.173: R621.1 v7(122.81,95.08)
  L3_SIG1 w0.109: v7(122.81,95.08) v5(124.71,95.08)
  L10_SIG4 w0.109: v9(152.78,87.56) 150.44,87.56 150.33,87.67 150.33,88.19 150.22,88.3 150,88.3 149.89,88.19 149.89,87.67 149.78,87.56 149.56,87.56 149.45,87.67 149.45,88.36 149.34,88.47 149.13,88.47 149.02,88.36 149.02,87.67 148.91,87.56 148.69,87.56 148.58,87.67 148.58,88.54 148.47,88.65 148.25,88.65 148.14,88.54 148.14,87.67 148.03,87.56 147.82,87.56 147.71,87.67 147.71,88.54 147.6,88.65 147.38,88.65 147.27,88.54 147.27,87.67 147.16,87.56 146.81,87.56 146.36,88.01 146.36,88.16 146.77,88.56 146.77,88.72 146.61,88.87 146.46,88.87 146.06,88.47 145.9,88.47 145.75,88.62 145.75,88.78 146.24,89.27 146.24,89.43 146.1,89.57 145.92,89.57 145.44,89.09 145.28,89.09 145.13,89.24 145.13,89.4 145.53,89.8 145.53,89.96 145.38,90.11 145.22,90.11 144.82,89.71 144.66,89.71 143.63,90.74 143.63,91.35 143.05,91.93 141.51,91.93 141.4,91.82 141.4,91.12 141.29,91.01 141.07,91.01 140.96,91.12 140.96,91.82 140.85,91.93 140.63,91.93 140.52,91.82 140.52,91.12 140.41,91.01 140.2,91.01 140.09,91.12 140.09,91.82 139.98,91.93 139.76,91.93 139.65,91.82 139.65,91.12 139.54,91.01 139.32,91.01 139.21,91.12 139.21,91.82 139.1,91.93 131.04,91.93 130.63,92.33 129.62,92.33 128.91,93.04 128.91,93.2 129.03,93.32 129.03,93.48 128.91,93.6 128.75,93.6 128.63,93.48 128.47,93.48 128.27,93.68 128.27,93.98 128.07,94.19 127.76,94.19 127.51,94.44 127.51,94.75 127.3,94.95 127,94.95 126.75,95.2 126.75,95.46 126.49,95.71 126.24,95.71 126.09,95.86 125.5,95.86 v5(124.71,95.08)
  BOTTOM w0.173: v9(152.78,87.56) 152.78,91.27 152.45,91.59 152.45,93.38 U89.B2
LCD_R1: length 59.5
  TOP w0.173: R622.1 v7(122.81,92.54)
  L3_SIG1 w0.109: v7(122.81,92.54) v5(124.59,92.54)
  L10_SIG4 w0.109: v5(124.59,92.54) 124.54,92.49 124,92.49 123.88,92.61 123.88,93.2 124.03,93.35 125.02,93.35 125.16,93.49 125.43,93.49 125.54,93.38 125.54,92.63 125.66,92.51 125.82,92.51 125.94,92.63 125.94,93.39 126.05,93.5 126.22,93.5 126.33,93.39 126.33,92.6 126.43,92.51 126.64,92.51 126.73,92.6 126.73,93.41 126.85,93.53 127.01,93.53 127.13,93.41 127.13,92.73 127.24,92.61 127.59,92.61 127.77,92.42 127.93,92.42 128.11,92.61 128.28,92.61 128.39,92.49 128.39,92.33 128.19,92.12 128.19,91.96 128.31,91.84 128.47,91.84 128.67,92.05 128.84,92.05 128.95,91.93 128.95,91.76 128.75,91.56 128.75,91.4 128.87,91.28 129.03,91.28 129.23,91.48 129.4,91.48 129.52,91.37 129.52,91.2 129.31,91 129.31,90.89 129.49,90.71 132.49,90.71 134.54,88.66 134.9,88.66 135.01,88.77 135.01,89.43 135.12,89.54 135.34,89.54 135.44,89.43 135.44,88.77 135.55,88.66 135.77,88.66 135.88,88.77 135.88,89.43 135.99,89.54 136.21,89.54 136.32,89.43 136.32,88.77 136.43,88.66 136.65,88.66 136.76,88.77 136.76,89.43 136.86,89.54 137.08,89.54 137.19,89.43 137.19,88.77 137.3,88.66 137.52,88.66 137.63,88.77 137.63,89.43 137.74,89.54 137.96,89.54 138.07,89.43 138.07,88.77 138.18,88.66 138.39,88.66 138.5,88.77 138.5,89.43 138.61,89.54 138.83,89.54 138.94,89.43 138.94,88.77 139.05,88.66 142.71,88.66 145.61,85.76 145.69,85.76 145.7,85.75 152.87,85.75 152.88,85.76 153.16,85.76 v9(154.56,87.15)
  BOTTOM w0.173: U89.A2 153.91,93.69 154.31,93.3 154.31,87.41 v9(154.56,87.15)
LCD_R2: length 59.1
  TOP w0.173: R624.1 v7(122.81,93.81)
  L3_SIG1 w0.109: v7(122.81,93.81) v5(124.59,93.81)
  L10_SIG4 w0.109: v5(124.59,93.81) 124.97,93.81 125.09,93.92 125.09,94.5 125.2,94.62 125.37,94.62 125.48,94.5 125.48,93.92 125.6,93.81 125.78,93.81 125.89,93.92 125.89,95.16 126.01,95.28 126.17,95.28 126.29,95.16 126.29,93.92 126.41,93.81 126.59,93.81 126.71,93.92 126.71,94.38 126.82,94.49 126.99,94.49 127.1,94.38 127.1,93.92 127.22,93.81 127.55,93.81 127.75,93.61 127.75,93.45 127.53,93.24 127.53,93.07 127.65,92.96 127.81,92.96 128.03,93.17 128.19,93.17 129.59,91.77 129.75,91.77 129.96,91.98 130.15,91.98 130.24,91.89 130.24,91.7 130.03,91.49 130.03,91.33 130.3,91.06 131.5,91.06 132.56,91.06 132.77,91.06 133.93,89.9 134.26,89.9 134.37,90 134.37,90.73 134.48,90.84 134.69,90.84 134.8,90.73 134.8,90 134.91,89.9 135.13,89.9 135.24,90 135.24,90.73 135.35,90.84 135.57,90.84 135.68,90.73 135.68,90 135.79,89.9 136,89.9 136.11,90 136.11,90.73 136.22,90.84 136.44,90.84 136.55,90.73 136.55,90 136.66,89.9 136.88,89.9 136.99,90 136.99,90.73 137.1,90.84 138.15,90.84 139.98,89 140.26,89 140.37,89.11 140.37,89.93 140.48,90.04 140.7,90.04 140.8,89.93 140.8,89.11 140.91,89 142.93,89 145.84,86.09 152.73,86.09 v9(154.83,88.18)
  BOTTOM w0.173: v9(154.83,88.18) 154.86,88.22 154.86,93.21 154.06,94 153.11,94 U89.B3
LCD_R3: length 59.9
  TOP w0.173: R623.1 v7(122.81,91.27)
  L3_SIG1 w0.109: v7(122.81,91.27) v5(124.59,91.27)
  L10_SIG4 w0.109: v5(124.59,91.27) 125.13,90.73 128.43,90.73 129.16,90 129.16,89.57 129.46,89.27 132.13,89.27 133.92,87.48 136.58,87.48 137.67,86.39 137.93,86.39 138.04,86.5 138.04,86.97 138.15,87.08 138.37,87.08 138.48,86.97 138.48,86.5 138.59,86.39 138.81,86.39 138.92,86.5 138.92,86.97 139.03,87.08 139.24,87.08 139.35,86.97 139.35,86.5 139.46,86.39 139.68,86.39 139.79,86.5 139.79,86.97 139.9,87.08 140.12,87.08 140.23,86.97 140.23,86.5 140.34,86.39 140.55,86.39 140.66,86.5 140.66,86.97 140.77,87.08 140.99,87.08 141.1,86.97 141.1,86.5 141.21,86.39 141.43,86.39 141.54,86.5 141.54,86.97 141.65,87.08 141.86,87.08 141.97,86.97 141.97,86.5 142.08,86.39 142.3,86.39 142.41,86.5 142.41,86.97 142.52,87.08 142.74,87.08 142.85,86.97 142.85,86.5 142.96,86.39 143.56,86.39 145.59,84.36 145.85,84.36 145.95,84.47 145.95,84.83 146.06,84.94 146.28,84.94 146.39,84.83 146.39,84.47 146.5,84.36 146.72,84.36 146.83,84.47 146.83,84.83 146.94,84.94 147.16,84.94 147.27,84.83 147.27,84.47 147.37,84.36 147.59,84.36 147.7,84.47 147.7,84.83 147.81,84.94 148.03,84.94 148.14,84.83 148.14,84.47 148.25,84.36 149.67,84.36 149.78,84.47 149.78,85.11 149.89,85.22 150.1,85.22 150.21,85.11 150.21,84.47 150.32,84.36 150.54,84.36 150.65,84.47 150.65,85.11 150.76,85.22 150.98,85.22 151.09,85.11 151.09,84.47 151.2,84.36 151.41,84.36 151.52,84.47 151.52,85.11 151.63,85.22 151.85,85.22 151.96,85.11 151.96,84.47 152.07,84.36 152.63,84.36 v9(154.53,86.26)
  BOTTOM w0.173: U89.A3 154.2,94.34 155.4,93.15 155.4,87.13 v9(154.53,86.26)
LCD_R4: length 44.4
  TOP w0.173: R625.1 v7(130.18,86.82)
  L3_SIG1 w0.109: v7(130.18,86.82) v5(131.06,86.82)
  L10_SIG4 w0.109: v9(153.57,82.33) 153.26,82.02 137.06,82.02 134.94,84.14 134.94,85.08 134.52,85.5 132.38,85.5 v5(131.06,86.82)
  BOTTOM w0.173: v9(153.57,82.33) 153.57,84.15 158.19,88.77 158.19,90 155.93,92.26 155.93,93.07 154.33,94.67 153.09,94.67 U89.B4
LCD_R5: length 61.5
  TOP w0.173: R627.1 v7(122.81,88.73)
  L3_SIG1 w0.109: v7(122.81,88.73) v5(124.61,88.73)
  L10_SIG4 w0.109: v9(156.59,92.38) 156.59,86.49 156.06,85.95 156.06,85 155.62,84.56 154.48,84.56 152.66,82.73 144.96,82.73 144.17,83.52 143.91,83.52 143.8,83.41 143.8,82.82 143.69,82.71 143.47,82.71 143.36,82.82 143.36,83.41 143.25,83.52 143.04,83.52 142.93,83.41 142.93,82.82 142.82,82.71 142.6,82.71 142.49,82.82 142.49,83.41 142.38,83.52 142.16,83.52 142.05,83.41 142.05,82.82 141.94,82.71 141.72,82.71 141.62,82.82 141.62,83.41 141.51,83.52 141.29,83.52 141.18,83.41 141.18,82.82 141.07,82.71 140.85,82.71 140.74,82.82 140.74,83.41 140.63,83.52 140.41,83.52 140.3,83.41 140.3,82.82 140.2,82.71 139.98,82.71 139.87,82.82 139.87,83.41 139.76,83.52 139.54,83.52 139.43,83.41 139.43,82.82 139.32,82.71 139.1,82.71 138.99,82.82 138.99,83.41 138.88,83.52 138.67,83.52 138.56,83.41 138.56,82.82 138.45,82.71 138.23,82.71 138.12,82.82 138.12,83.41 138.01,83.52 136.58,83.52 136.13,83.97 136.13,84.13 136.56,84.56 136.56,84.73 136.45,84.84 136.28,84.84 135.9,84.46 135.74,84.46 135.62,84.58 135.62,84.74 136,85.12 136,85.29 135.08,86.21 132.99,86.21 131.57,87.63 129.11,87.63 128.35,88.39 124.95,88.39 v5(124.61,88.73)
  BOTTOM w0.173: v9(156.59,92.38) 156.59,92.87 154.47,94.99 U89.A4
LCD_R6: length 59
  TOP w0.173: R628.1 v7(122.81,90)
  L3_SIG1 w0.109: v7(122.81,90) v5(124.59,90)
  L10_SIG4 w0.109: v9(156.24,93.93) 155.8,93.5 155.8,86.64 153.17,84 145.33,84 144.13,85.2 142.88,85.2 142.77,85.31 142.77,85.85 142.66,85.96 142.44,85.96 142.33,85.85 142.33,85.31 142.23,85.2 142.01,85.2 141.9,85.31 141.9,85.85 141.79,85.96 141.57,85.96 141.46,85.85 141.46,85.31 141.35,85.2 141.13,85.2 141.02,85.31 141.02,85.85 140.91,85.96 140.7,85.96 140.59,85.85 140.59,85.31 140.48,85.2 140.26,85.2 140.15,85.31 140.15,85.85 140.04,85.96 139.82,85.96 139.71,85.85 139.71,85.31 139.6,85.2 139.39,85.2 139.28,85.31 139.28,85.85 139.17,85.96 138.95,85.96 138.84,85.85 138.84,85.31 138.73,85.2 138.25,85.2 136.53,86.92 133.43,86.92 132.08,88.27 132.08,88.8 131.95,88.93 131.78,88.93 131.66,88.81 131.66,88.46 131.54,88.35 131.38,88.35 131.26,88.46 131.26,88.81 131.15,88.93 130.98,88.93 130.87,88.81 130.87,88.46 130.75,88.35 130.59,88.35 130.47,88.46 130.47,88.81 130.36,88.93 130.19,88.93 130.07,88.81 130.07,88.46 129.96,88.35 129.79,88.35 129.68,88.46 129.68,88.81 129.56,88.93 129.16,88.93 128.78,89.31 128.78,89.9 128.3,90.37 124.99,90.37 124.61,90 v5(124.59,90)
  BOTTOM w0.173: U89.B5 153.11,95.31 154.86,95.31 v9(156.24,93.93)
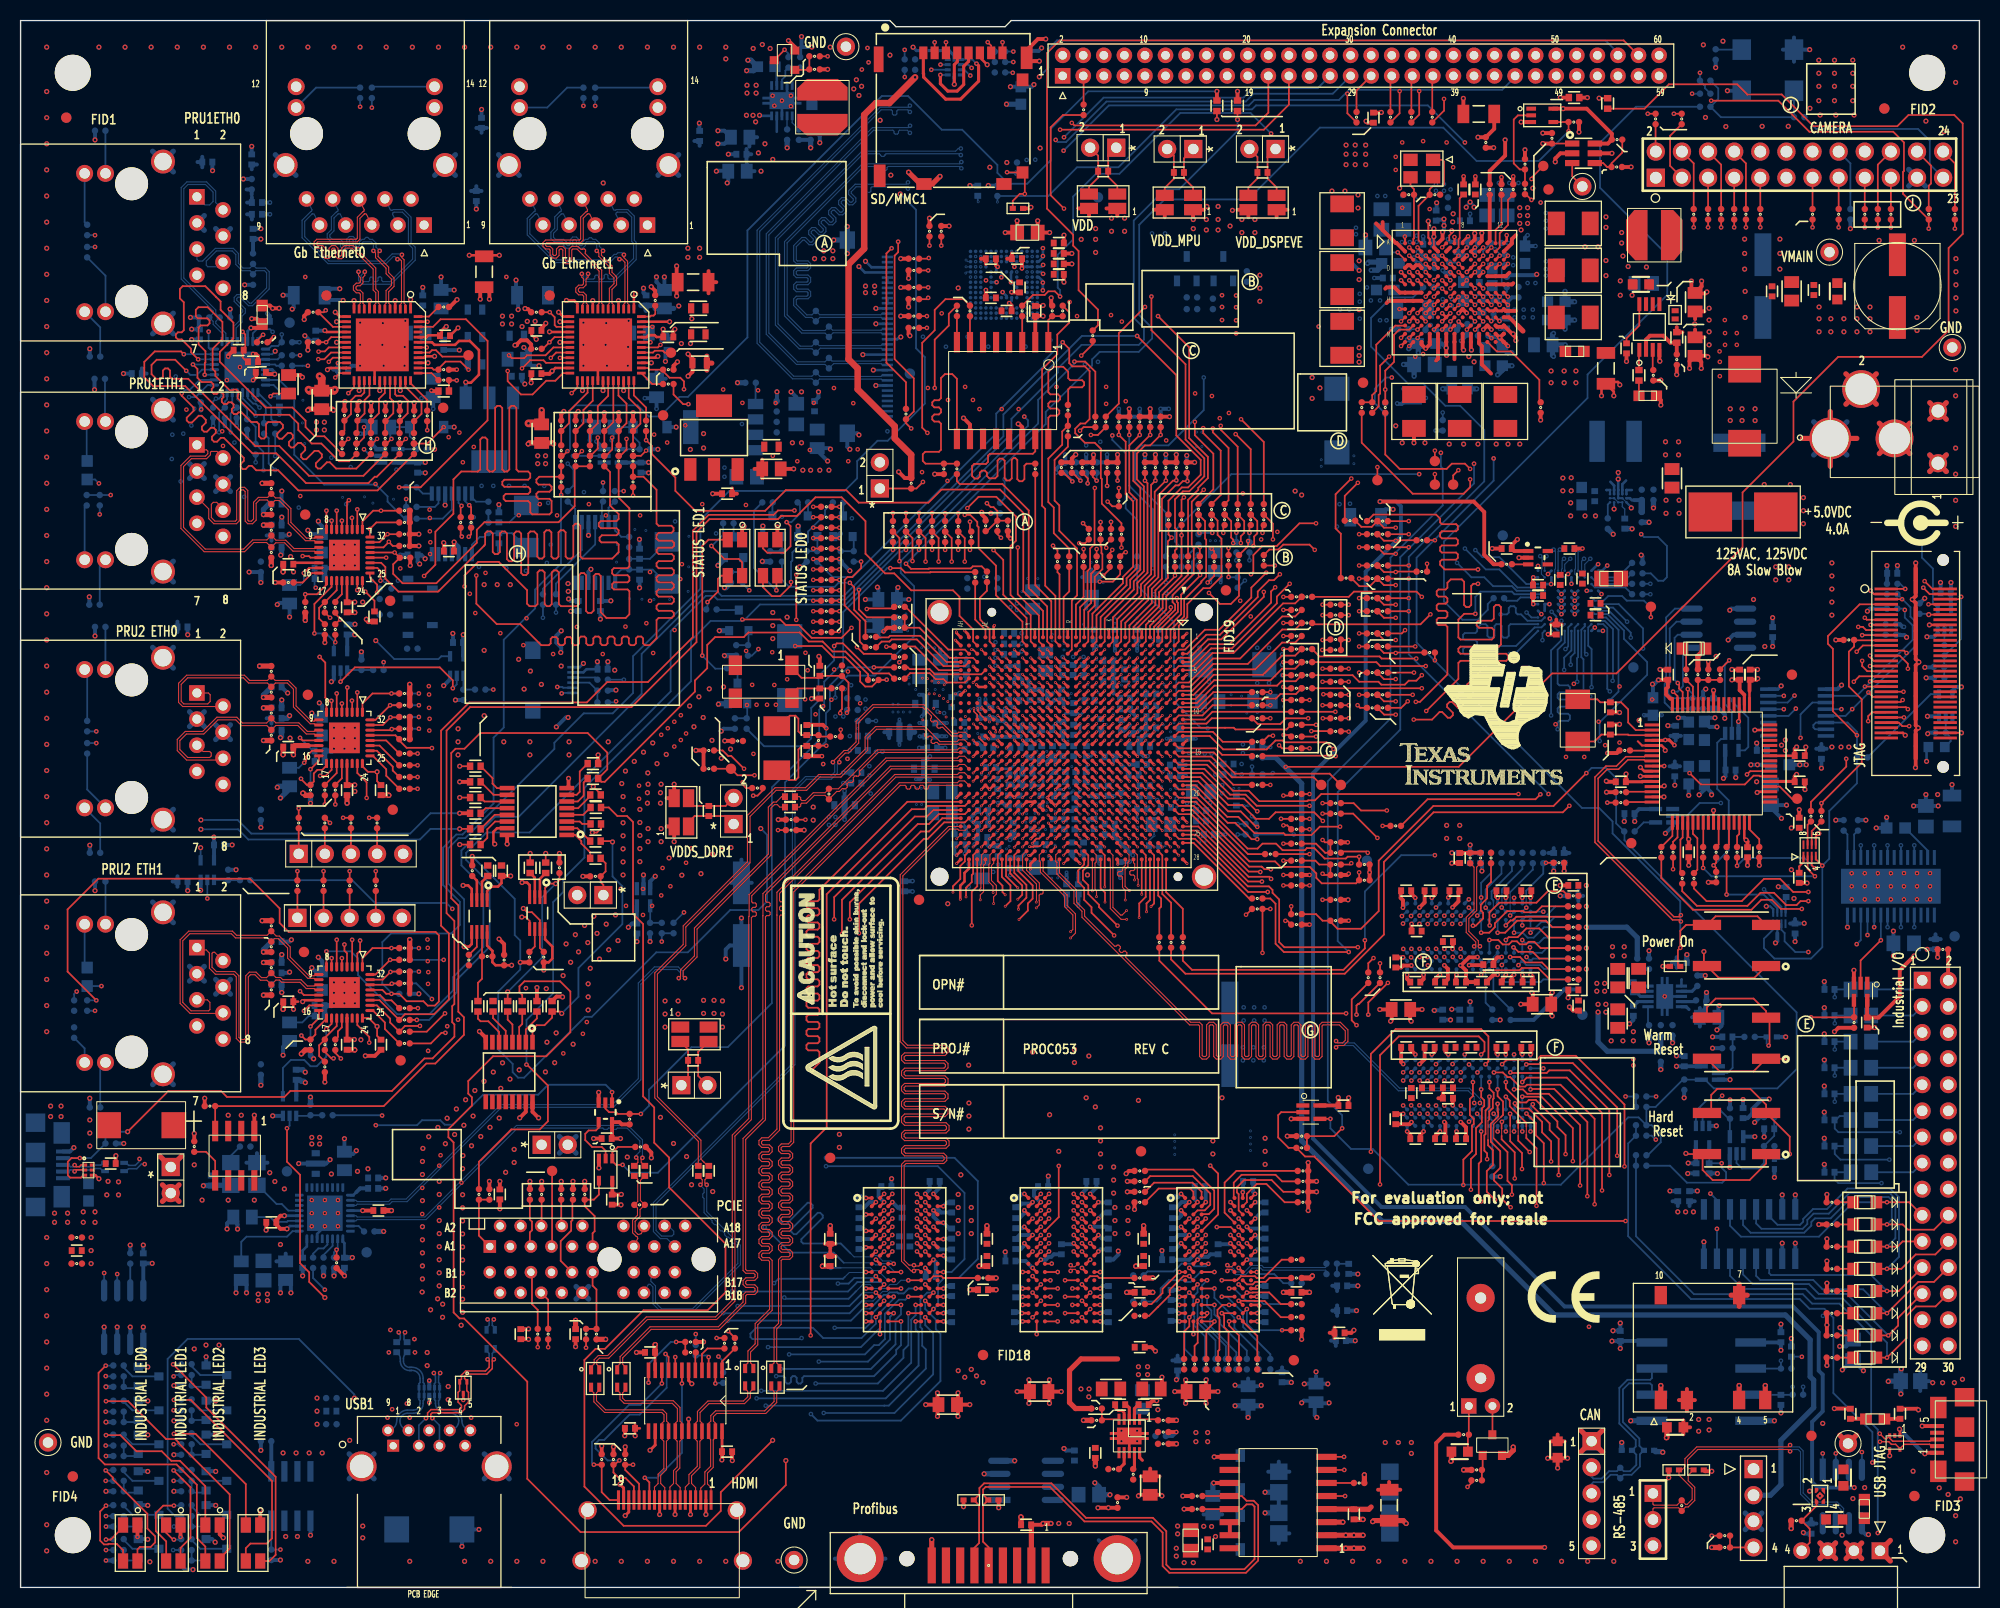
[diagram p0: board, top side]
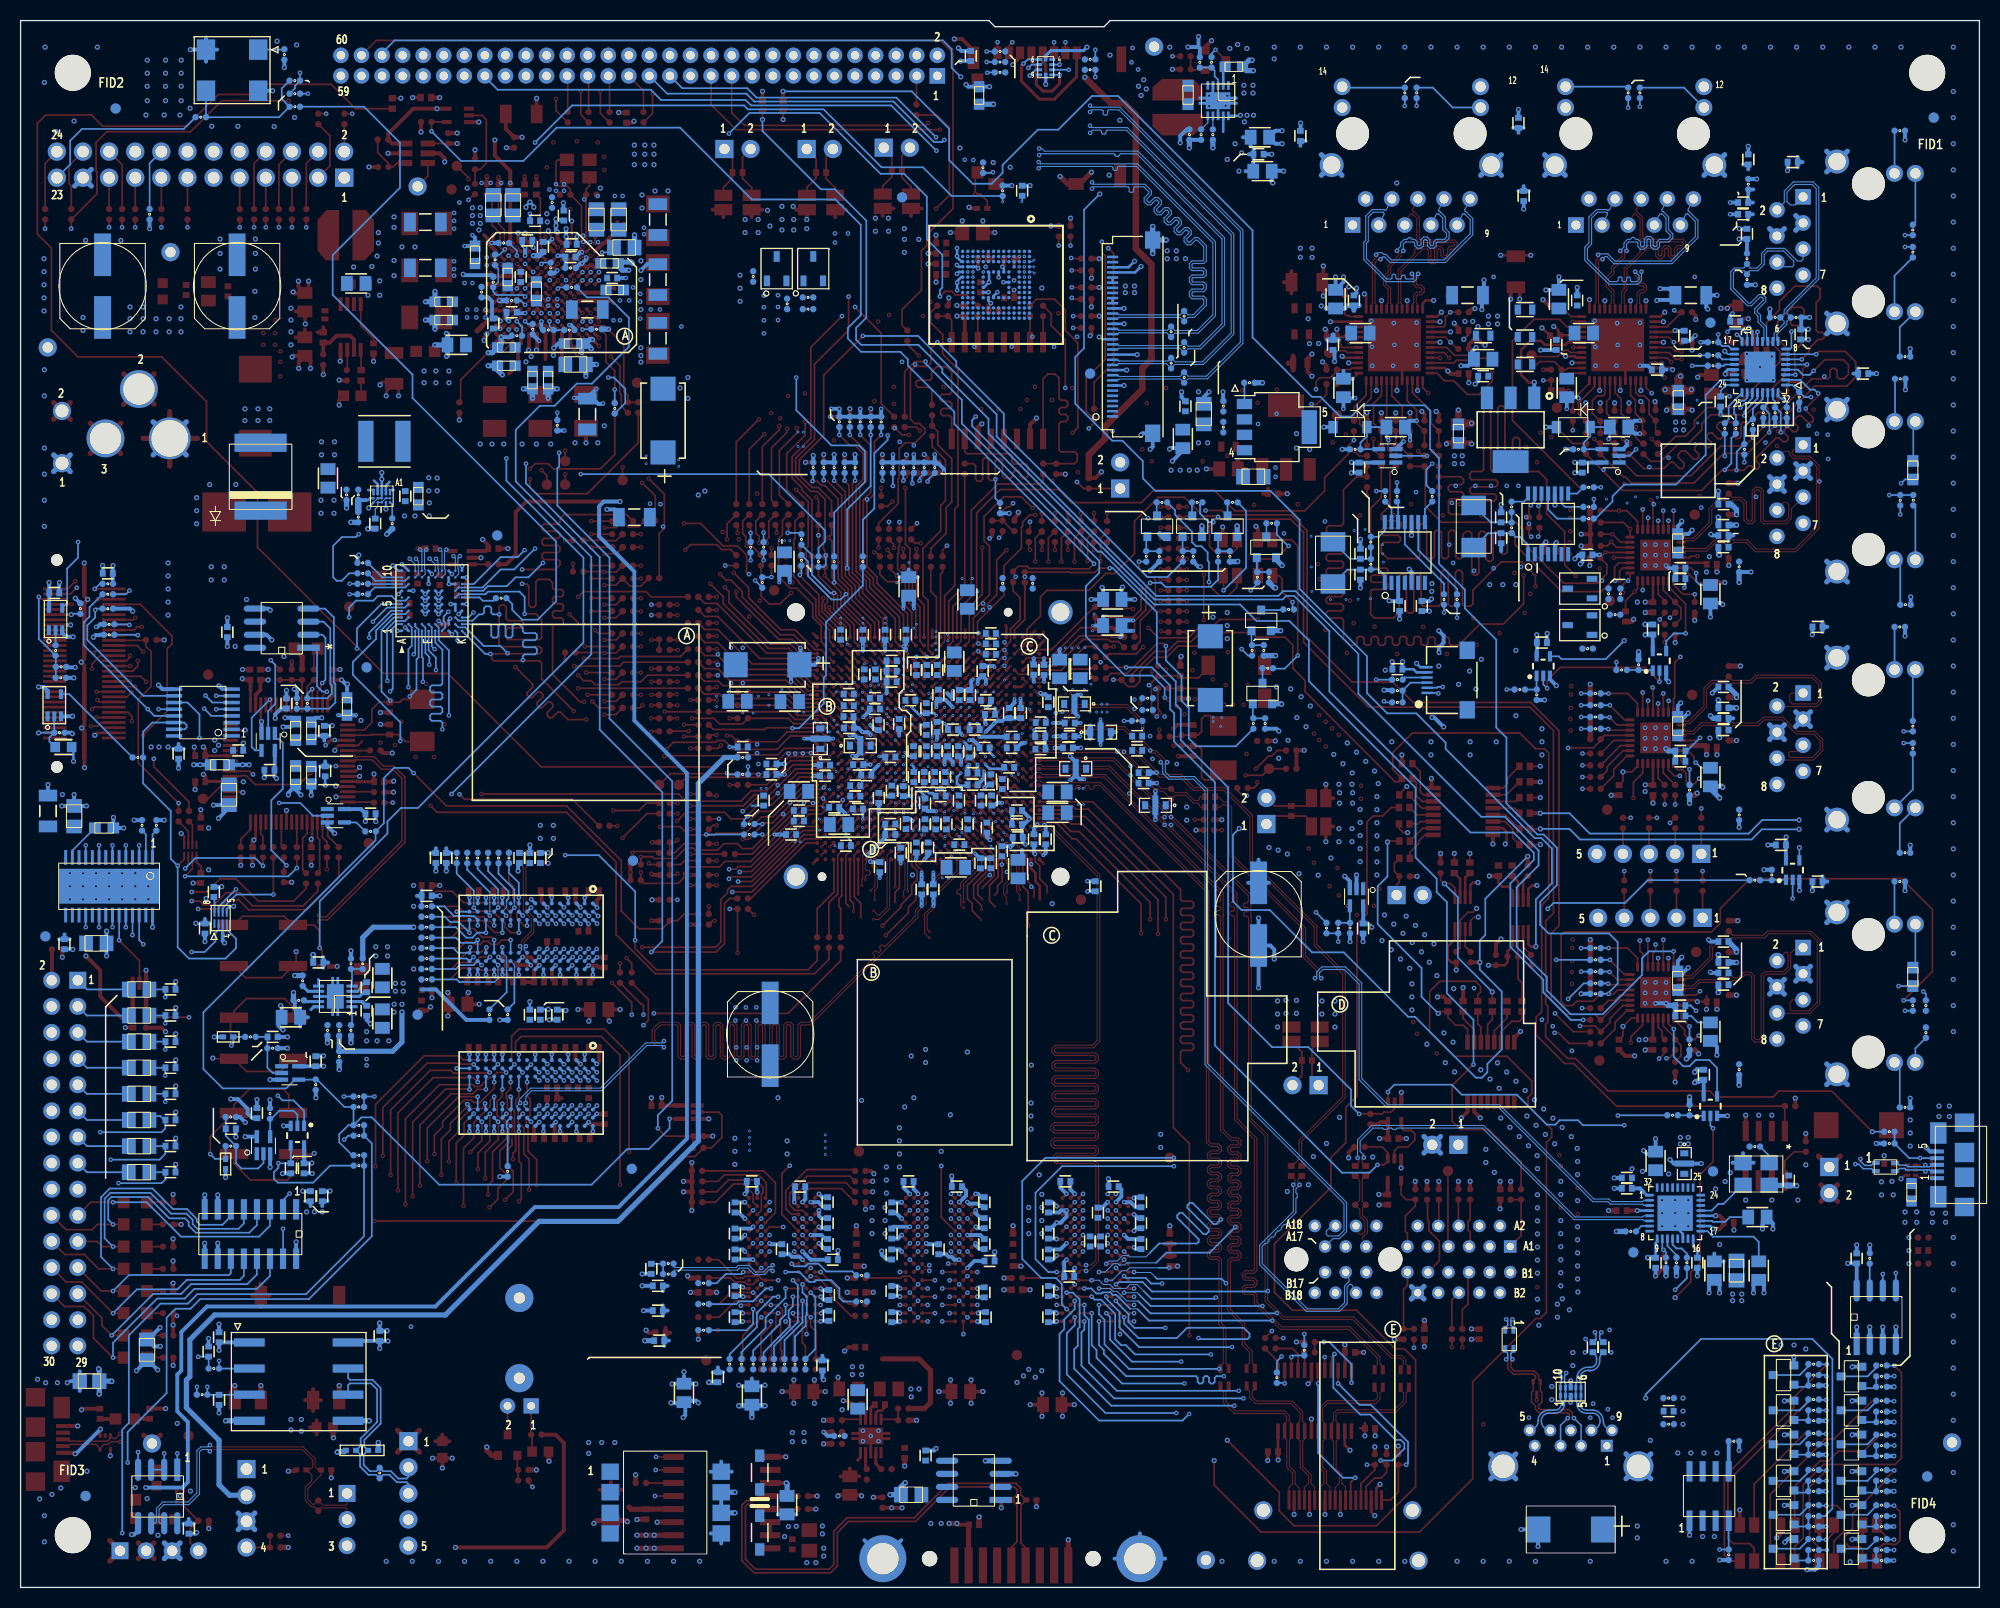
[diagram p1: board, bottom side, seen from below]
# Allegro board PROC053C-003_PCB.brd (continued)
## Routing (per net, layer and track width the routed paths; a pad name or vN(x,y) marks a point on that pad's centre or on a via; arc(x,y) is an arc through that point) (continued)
LCD_R7: length 60.8
  TOP w0.173: v7(122.81,87.58) 122.94,87.46 R626.1
  L3_SIG1 w0.109: v7(122.81,87.58) 124.46,87.58 v5(124.59,87.46)
  L10_SIG4 w0.109: v9(157.78,91.32) 157.78,90.51 157.68,90.4 157.31,90.4 157.2,90.3 157.2,90.08 157.31,89.97 157.68,89.97 157.78,89.86 157.78,89.64 157.68,89.53 157.31,89.53 157.2,89.42 157.2,89.2 157.31,89.09 157.68,89.09 157.78,88.99 157.78,88.77 157.68,88.66 157.31,88.66 157.2,88.55 157.2,88.33 157.31,88.22 157.68,88.22 157.78,88.11 157.78,87.89 157.68,87.78 157.31,87.78 157.2,87.67 157.2,87.46 157.31,87.35 157.68,87.35 157.78,87.24 157.78,87.02 157.68,86.91 157.31,86.91 157.2,86.8 157.2,86.58 157.31,86.47 157.68,86.47 157.78,86.36 157.78,85.59 157.48,85.29 157.33,85.29 156.79,85.82 156.64,85.82 156.48,85.67 156.48,85.52 157.02,84.98 157.02,84.82 156.39,84.19 156.39,84.03 156.75,83.67 156.75,83.52 156.59,83.36 156.44,83.36 156.08,83.72 155.92,83.72 155.56,83.36 153.77,83.36 152.76,82.36 137.2,82.36 135.28,84.28 135.28,85.22 134.65,85.86 132.66,85.86 131.24,87.28 128.96,87.28 128.19,88.04 125.17,88.04 v5(124.59,87.46)
  BOTTOM w0.173: v9(157.78,91.32) 157.78,93.27 155.42,95.64 U89.A5
LCD_VS: length 52.9
  TOP w0.173: R635.1 v7(129.16,88.09)
  L3_SIG1 w0.109: v7(129.16,88.09) 128.65,87.58 v5(128.02,87.58)
  L10_SIG4 w0.109: v9(139.7,99.65) 138.94,100.41 133.1,100.41 131.57,98.88 130.89,98.88 130.56,98.55 130.39,98.55 130.27,98.67 130.08,98.67 129.98,98.56 129.98,98.41 130.15,98.24 130.15,98.07 129.72,97.64 126.64,97.64 123.84,94.84 123.84,93.97 123.52,93.65 123.52,89.96 123.64,89.85 123.99,89.85 124.1,89.73 124.1,89.57 123.99,89.45 123.64,89.45 123.52,89.34 123.52,89.13 123.64,89.01 124.04,89.01 124.16,88.9 124.16,88.73 124.04,88.62 123.64,88.62 123.52,88.5 123.52,88.33 123.64,88.22 124.27,88.22 124.38,88.1 124.38,87.94 124.27,87.82 123.64,87.82 123.52,87.71 123.52,87.25 123.77,87 124.11,87 124.23,86.88 124.23,86.48 124.35,86.36 124.51,86.36 124.63,86.48 124.63,86.88 124.74,87 124.91,87 125.02,86.88 125.02,86.48 125.14,86.36 125.3,86.36 125.42,86.48 125.42,86.63 125.51,86.72 125.73,86.72 125.87,86.86 125.87,87.52 125.99,87.63 126.4,87.63 126.51,87.52 126.51,85.77 126.63,85.65 126.79,85.65 126.91,85.77 126.91,86.62 127.02,86.74 127.37,86.74 127.48,86.85 127.48,87.02 127.37,87.13 127.02,87.13 126.91,87.25 126.91,87.47 127.02,87.58 v5(128.02,87.58)
  BOTTOM w0.173: U89.K7 145.49,96.94 145.05,97.39 143.21,97.39 142.34,98.25 141.1,98.25 v9(139.7,99.65)
MMC2_CLK: length 59.9
  TOP w0.173: U1.J7 106.64,87.81 v4(106.83,88.01)
  L3_SIG1 w0.099: v4(106.83,88.01) 107.29,88.47 107.9,88.47 108.34,88.91 ; 108.34,88.91 108.34,90.54 ; 110.8,95.97 108.57,93.75 108.57,90.77
  L3_SIG1 w0.102: 108.34,90.54 108.57,90.77
  L3_SIG1 w0.109: 108.34,88.91 108.34,88.91 ; v5(93.6,110.62) 95.6,110.62 98.48,107.74 101.42,107.74 102.12,107.05 103.06,107.05 103.69,106.43 106.77,106.43 111.14,102.06 111.14,96.99 110.8,96.65 110.8,95.97
  L4_SIG2 w0.114: v5(98.13,125.38) 98.04,125.29 98.04,121.39 95.2,118.54 v5(95.2,115.48)
  L10_SIG4 w0.109: v5(95.2,115.48) 93.6,113.87 93.6,112.68 93.76,112.52 95.29,112.52 95.45,112.36 95.45,112.13 95.29,111.97 93.76,111.97 93.6,111.81 v5(93.6,110.62) ; v5(98.13,125.38) 98.13,127.2 v11(97.88,127.45)
MMC2_CMD: length 63.9
  TOP w0.173: U1.H6 v4(107.83,88.81)
  L3_SIG1 w0.099: 107.72,94.3 107.72,91.55 107.54,91.37 107.54,89.49 107.83,89.2 v4(107.83,88.81)
  L3_SIG1 w0.109: 107.72,94.3 109.14,95.73 109.14,97.4 110.11,98.37 110.11,101.63 106.93,104.81 102.29,104.81 100.36,106.73 98.06,106.73 96.34,108.45 v5(95.7,108.45)
  L4_SIG2 w0.114: v5(95.7,108.45) 95.07,109.08 95.07,110.92 95.24,111.09 96.38,111.09 96.55,111.26 96.55,111.49 96.38,111.66 95.24,111.66 95.07,111.83 95.07,112.06 95.24,112.23 96.38,112.23 96.55,112.4 96.55,112.64 96.38,112.8 95.24,112.8 95.07,112.97 95.07,113.21 95.24,113.37 96.38,113.37 96.55,113.54 96.55,113.78 96.38,113.95 95.24,113.95 94.74,114.44 94.74,118.59 97.63,121.48 v5(97.63,125.99)
  L10_SIG4 w0.109: v5(95.7,108.45) v9(95.7,107.78) ; v5(97.63,125.99) 97.63,127.16 97.51,127.28 97.51,127.58 v11(97.88,127.95)
  BOTTOM w0.173: v9(95.7,107.78) 95.7,105.94 R513.1
MMC2_DAT0: length 62.8
  TOP w0.173: R505.1 88.27,129.24 v2(88.33,129.3) ; U1.J4 v4(107.03,90.41)
  L3_SIG1 w0.099: v4(107.03,90.41) 107.03,90.8 106.74,91.09 106.74,91.61 107.07,91.93 107.07,95.26
  L3_SIG1 w0.109: v5(90.8,110.32) 92.48,108.64 94.39,108.64 95.38,107.65 96.09,107.65 97.74,106 100.13,106 102.03,104.09 106.68,104.09 109.4,101.38 109.4,98.62 108.46,97.68 108.46,96.65 107.07,95.26
  L4_SIG2 w0.114: v2(88.33,129.3) 86.89,127.87 86.89,124.28 86.69,124.08 86.69,122.5 87.25,121.95 87.25,115.78 87.66,115.37 87.66,111.43 88.77,110.32 v5(90.8,110.32)
  L10_SIG4 w0.109: v11(91.95,129.11) 91.75,129.3 v2(88.33,129.3)
  BOTTOM w0.083: v11(91.95,129.11) 92.11,128.95 U43.A3
MMC2_DAT1: length 62.6
  TOP w0.173: R506.1 v2(88.27,126.45) ; U1.J6 v4(107.03,88.81)
  L3_SIG1 w0.099: 106.8,95.37 106.8,93.47 106.27,92.95 106.27,92 106.54,91.73 106.54,91.01 106.74,90.81 106.74,89.49 107.03,89.2 v4(107.03,88.81)
  L3_SIG1 w0.109: 106.8,95.37 108.12,96.69 108.12,97.88 109,98.76 109,101.29 107.23,103.06 102.56,103.06 99.97,105.64 97.61,105.64 95.96,107.29 95.25,107.29 94.26,108.29 v5(92.1,108.29)
  L4_SIG2 w0.114: v5(92.1,108.29) 93.16,109.34 93.16,115.2 92.33,116.03 92.33,116.75 92.19,116.88 91.83,116.88 91.69,117.02 91.69,117.21 91.83,117.35 92.19,117.35 92.33,117.49 92.33,117.68 92.19,117.82 91.83,117.82 91.69,117.96 91.69,118.15 91.83,118.29 92.19,118.29 92.33,118.42 92.33,121.76 90.04,124.05 90.04,124.67 v2(88.27,126.45)
  L10_SIG4 w0.109: v11(91.95,128.45) 91.62,128.12 89.94,128.12 v2(88.27,126.45)
  BOTTOM w0.083: U43.A4 v11(91.95,128.45)
MMC2_DAT2: length 62.2
  TOP w0.173: R507.1 88.14,125.3 v2(88.27,125.43) ; U1.H4 v4(107.83,90.41)
  L3_SIG1 w0.099: 107.83,90.73 108.15,91.05 108.15,93.97 110.01,95.83
  L3_SIG1 w0.109: v4(107.83,90.41) 107.83,90.73 ; v5(92.71,110.32) 92.71,109.71 93.07,109.35 95.92,109.35 98.2,107.07 100.51,107.07 102.41,105.16 107.07,105.16 110.46,101.77 110.46,98.23 109.84,97.61 109.84,97.25 110.01,97.08 110.01,95.83
  L4_SIG2 w0.114: v5(92.71,110.32) 92.71,114.51 91.06,116.16 91.06,118.77 91.2,118.91 91.81,118.91 91.95,119.05 91.95,119.24 91.81,119.38 91.2,119.38 91.06,119.51 91.06,119.71 91.2,119.84 91.81,119.84 91.95,119.98 91.95,120.17 91.81,120.31 91.2,120.31 91.06,120.45 91.06,120.64 91.2,120.78 91.81,120.78 91.95,120.92 91.95,121.11 91.81,121.25 91.2,121.25 91.06,121.38 91.06,122.51 88.27,125.3 v2(88.27,125.43)
  L10_SIG4 w0.109: v2(88.27,125.43) 90.42,127.58 91.67,127.58 v11(91.92,127.84)
  BOTTOM w0.083: v11(91.92,127.84) 92.03,127.95 U43.A5
MMC2_DAT3: length 63.3
  TOP w0.173: R508.1 v2(89.53,130.51) ; U1.H5 v4(107.83,89.61)
  L3_SIG1 w0.099: 108.36,93.83 108.36,90.84 108.13,90.62 ; 108.36,93.83 110.31,95.79
  L3_SIG1 w0.102: 108.13,89.91 108.13,90.62
  L3_SIG1 w0.109: v4(107.83,89.61) 108.13,89.91 ; v5(93.62,109.83) 95.91,109.83 98.34,107.41 101.29,107.41 101.98,106.71 102.92,106.71 103.57,106.07 106.64,106.07 110.8,101.91 110.8,97.13 110.54,96.87 110.54,96.02 110.31,95.79 ; 108.36,93.83 108.36,93.83
  L4_SIG2 w0.114: v2(89.53,130.51) 91.87,130.51 93.12,129.26 93.12,122.48 93.52,122.08 93.52,112.39 94.08,111.84 94.08,110.29 v5(93.62,109.83)
  L10_SIG4 w0.109: v11(92.88,129.45) 91.82,130.51 v2(89.53,130.51)
MMC2_DAT4: length 69.2
  TOP w0.173: U1.K7 v4(106.23,88.01) ; R509.1 v2(88.39,130.51)
  L3_SIG1 w0.099: v4(106.23,88.01) 106.53,88.31 106.53,90.74 106.22,91.05 106.22,91.77 106.07,91.92 106.07,93.03 106.58,93.53 106.58,95.58
  L3_SIG1 w0.109: 106.58,95.58 107.78,96.78 107.78,98.03 108.64,98.88 108.64,101.15 107.06,102.72 101.7,102.72 100.61,103.81 100.61,104.45 99.8,105.26 97.51,105.26 95.86,106.91 95.15,106.91 94.28,107.78 91.97,107.78 90.8,108.95 v5(90.8,109.43)
  L4_SIG2 w0.114: v5(90.8,109.43) 89.03,109.43 87.22,111.23 87.22,113.39 85.09,115.52 85.09,123.98 86.21,125.09 86.21,126.62 85.78,127.05 85.78,127.89 v2(88.39,130.51)
  L10_SIG4 w0.109: v11(92.88,128.95) 92,129.83 89.07,129.83 v2(88.39,130.51)
MMC2_DAT5: length 64.3
  TOP w0.173: R510.1 v2(88.27,128.1) ; U1.M7 v4(104.63,88.01)
  L3_SIG1 w0.099: v4(104.63,88.01) 104.63,88.4 104.34,88.69 104.34,88.94 104.51,89.11 104.54,89.11 104.88,89.44 105.19,89.44 105.31,89.32 105.56,89.32 105.73,89.49 105.73,91.63 105.64,91.72 105.64,92.37 105.3,92.71 105.3,93.38 106.09,94.17 106.09,96.05
  L3_SIG1 w0.109: v2(88.27,128.1) 88.78,128.1 89.36,128.68 v5(92.43,128.68) ; v5(88.39,111.59) 89.94,110.04 89.94,108.74 91.51,107.17 93.92,107.17 94.89,106.2 95.5,106.2 97.18,104.53 99.34,104.53 99.87,103.99 99.87,103.56 101.42,102.01 106.81,102.01 107.92,100.9 107.92,99.23 107.06,98.36 107.06,97.02 106.09,96.05
  L4_SIG2 w0.114: v5(88.39,111.59) 88.39,115.51 87.68,116.22 87.68,122.1 87.17,122.61 87.17,123.95 87.27,124.05 87.27,127.11 v2(88.27,128.1)
  L10_SIG4 w0.109: v11(92.88,128.45) 92.63,128.45 92.43,128.65 v5(92.43,128.68)
MMC2_DAT6: length 63.9
  TOP w0.173: U1.J5 v4(107.03,89.61) ; R511.1 v2(88.14,123.65)
  L3_SIG1 w0.099: v4(107.03,89.61) 107.03,90 107.34,90.31 107.34,91.46 107.49,91.61 107.49,94.57
  L3_SIG1 w0.109: v5(92.27,109.56) 92.83,109 94.51,109 95.5,108.01 96.31,108.01 97.96,106.35 100.25,106.35 102.16,104.45 106.81,104.45 109.75,101.5 109.75,98.49 108.8,97.54 108.8,95.87 107.49,94.57
  L4_SIG2 w0.114: v5(92.27,109.56) 92.27,114.1 89.85,116.52 89.85,118.93 89.99,119.06 90.54,119.06 90.68,119.2 90.68,119.39 90.54,119.53 89.99,119.53 89.85,119.67 89.85,119.86 89.99,120 90.54,120 90.68,120.14 90.68,120.33 90.54,120.47 89.99,120.47 89.85,120.6 89.85,120.8 89.99,120.93 90.54,120.93 90.68,121.07 90.68,121.26 90.54,121.4 89.99,121.4 89.85,121.54 89.85,121.94 v2(88.14,123.65) 87.73,124.06 87.73,126.67 89.13,128.07 v5(92.4,128.07)
  L10_SIG4 w0.109: v5(92.4,128.07) 92.76,128.07 v11(92.88,127.95)
MMC2_DAT7: length 61.6
  TOP w0.173: v2(88.14,122.51) R512.1 ; U1.K6 v4(106.23,88.81)
  L3_SIG1 w0.099: v4(106.23,88.81) 106.23,89.2 105.94,89.49 105.94,91.76 105.87,91.83 105.87,92.42 105.5,92.79 105.5,93.29 106.33,94.12 106.33,95.8
  L3_SIG1 w0.109: v5(89.03,111.84) 90.28,110.58 90.28,108.93 91.74,107.48 94.1,107.48 95.02,106.56 95.73,106.56 97.38,104.91 99.59,104.91 100.25,104.25 100.25,103.66 101.54,102.37 106.93,102.37 106.95,102.35 106.96,102.35 108.24,101.06 108.24,101.06 108.28,101.02 108.28,99.03 107.43,98.18 107.43,96.91 106.33,95.8
  L4_SIG2 w0.114: v2(88.14,122.51) 88.14,121.11 88.27,120.97 88.76,120.97 88.9,120.83 88.9,120.64 88.76,120.5 88.27,120.5 88.14,120.36 88.14,120.17 88.27,120.03 88.76,120.03 88.9,119.9 88.9,119.7 88.76,119.57 88.27,119.57 88.14,119.43 88.14,119.24 88.27,119.1 88.76,119.1 88.9,118.96 88.9,118.77 88.76,118.63 88.27,118.63 88.14,118.49 88.14,116.29 89.03,115.4 v5(89.03,111.84)
  L10_SIG4 w0.109: v2(88.14,122.51) 92.88,127.25 v11(92.88,127.45)
MMC_CD: length 59
  TOP w0.173: U84.1 96.49,134.86 97.17,135.54 v7(97.66,135.54) 97.66,137.41 J15.DT 95.95,137.63 v2(95.93,137.65) ; R409.1 v7(77.09,99.01)
  L3_SIG1 w0.109: v7(77.09,99.01) v5(76.45,99.01)
  L3_SIG1 w0.114: v7(97.66,135.54) 95.51,135.54
  L3_SIG1 w0.203: 95.51,135.54 v5(95.5,135.54)
  L4_SIG2 w0.114: v5(76.45,99.01) 76.56,99.01 79.3,101.76 79.3,121.45 83.82,125.97 83.82,130.76 88.6,135.54 v5(95.5,135.54)
  BOTTOM w0.173: v2(95.93,137.65) 96.01,137.58 R408.1
MMC_CLK: length 63
  TOP w0.173: R405.1 v7(77.09,105.11)
  TOP w0.305: v2(89.45,147.11) 89.45,146.26 90.17,145.54 91.08,145.54 91.72,146.18 91.72,147.96 92.19,148.43 J15.5
  L3_SIG1 w0.109: v7(77.09,105.11) v5(76.45,105.11)
  L4_SIG2 w0.114: v5(76.45,105.11) 76.13,105.44 72.85,105.44 72.2,106.08 72.2,119.34 80.72,127.86 81.94,127.86 82.68,128.61 82.68,138.42 89.89,145.63 89.89,146.67 v2(89.45,147.11)
  BOTTOM w0.173: U30.1 v2(89.45,147.11)
MMC_CMD: length 70.1
  TOP w0.173: J15.3 v2(89.99,150.29) ; R404.1 v7(77.09,104.09)
  L3_SIG1 w0.109: v7(77.09,104.09) v5(76.45,104.09)
  L4_SIG2 w0.114: v5(76.45,104.09) 76.86,104.09 77.54,104.77 77.54,105.29 76.91,105.92 74.48,105.92 72.57,107.83 72.57,118.26 81.82,127.51 82.09,127.51 83.07,128.49 83.07,138.28 90.34,145.56 90.34,146.74 91.4,147.8 v2(92.49,147.8)
  L10_SIG4 w0.109: v2(96.55,149.39) 96.1,148.95 93.93,148.95 93.47,148.49 93.47,147.83 93.22,147.57 92.71,147.57 v2(92.49,147.8) 92.49,147.8 v2(89.99,150.29)
  BOTTOM w0.173: v2(92.49,147.8) 92.17,148.11 U30.7 ; R398.1 v2(96.55,149.39)
MMC_D0: length 72
  TOP w0.173: R406.1 v7(77.09,101.05) ; v2(94.06,150.29) 94.39,149.95 J15.7
  L3_SIG1 w0.109: v7(77.09,101.05) v5(76.45,101.05)
  L4_SIG2 w0.114: v5(76.45,101.05) 74.98,101.05 73.08,102.95 73.08,103.73 71.46,105.35 71.46,119.93 80.9,129.37 80.9,137.69 88.57,145.36 v2(88.57,147.61)
  L9_SIG3 w0.114: v2(94.06,150.29) 93.62,149.86 92.94,149.86 91.87,148.79 89.2,148.79 88.57,148.16 v2(88.57,147.61)
  L10_SIG4 w0.109: v2(88.57,147.61) 87.23,148.95 86.58,148.95 v2(85.98,149.55)
  BOTTOM w0.173: U30.2 v2(88.57,147.61) ; R399.1 v2(85.98,149.55)
MMC_D1: length 72.7
  TOP w0.173: J15.8 v2(95.49,150.29) ; R407.1 v7(77.09,102.06)
  L3_SIG1 w0.109: v7(77.09,102.06) v5(76.45,102.06)
  L4_SIG2 w0.114: v2(89.46,148.11) 89.01,147.66 89.01,145.28 81.28,137.54 81.28,129.17 71.83,119.72 71.83,105.57 75.33,102.06 v5(76.45,102.06)
  L9_SIG3 w0.114: v2(95.49,150.29) 94.38,149.17 92.94,149.17 91.88,148.11 v2(89.46,148.11)
  L10_SIG4 w0.109: v2(89.46,148.11) 89.97,147.61 89.97,146.84 89.36,146.23 86.66,146.23 v2(85.99,146.9)
  BOTTOM w0.173: v2(85.99,146.9) 85.98,146.91 R400.1 ; U30.3 v2(89.46,148.11)
MMC_D2: length 86.3
  TOP w0.173: R402.1 v7(77.09,100.03)
  TOP w0.305: J15.1 87.79,147.25 87.82,147.22 87.82,146.9 89.97,144.75 91.41,144.75 93.17,146.51 93.17,148 v2(92.96,148.21)
  L3_SIG1 w0.109: v7(77.09,100.03) v5(76.45,100.03)
  L4_SIG2 w0.114: v5(76.45,100.03) 75.28,100.03 72.73,102.58 72.73,103.42 71.09,105.06 71.09,120.09 79.6,128.61 79.6,136.92 87.99,145.3 87.99,147.84 88.71,148.56 92.61,148.56 v2(92.96,148.21)
  L10_SIG4 w0.109: v2(92.96,148.21) 92.96,148.74 93.7,149.48 95.76,149.48 96.22,149.94 96.9,149.94 97.36,149.48 97.36,148.19 v2(96.49,147.33)
  BOTTOM w0.173: R401.1 96.49,147.36 96.52,147.33 v2(96.49,147.33) ; U30.6 92.56,148.61 v2(92.96,148.21)
MMC_D3: length 77.1
  TOP w0.173: J15.2 v2(88.89,150.29) ; R403.1 v7(77.09,103.08)
  L3_SIG1 w0.109: v7(77.09,103.08) v5(76.45,103.08)
  L4_SIG2 w0.114: v2(92.36,147.05) 92.35,147.05 92.35,147.04 83.44,138.13 83.44,128.22 82.37,127.15 81.99,127.15 74.19,119.36 74.19,115.42 74.31,115.31 74.99,115.31 75.11,115.19 75.11,114.96 74.99,114.85 74.14,114.85 74.02,114.74 74.02,114.51 74.14,114.39 74.99,114.39 75.11,114.28 75.11,114.05 74.99,113.94 74.14,113.94 74.02,113.82 74.02,113.59 74.14,113.48 74.99,113.48 75.11,113.36 75.11,113.14 74.99,113.02 74.14,113.02 74.02,112.91 74.02,112.68 74.14,112.56 74.99,112.56 75.11,112.45 75.11,112.22 74.99,112.11 74.14,112.11 74.02,111.99 74.02,106.91 74.64,106.29 77.23,106.29 77.95,105.57 77.95,104.58 v5(76.45,103.08)
  L10_SIG4 w0.109: v2(96.55,148.37) 94.91,146.74 92.68,146.74 v2(92.36,147.05) 92.13,147.05 v2(88.89,150.29)
  BOTTOM w0.173: R397.1 v2(96.55,148.37) ; v2(92.36,147.05) 92.35,147.05 91.79,147.61 U30.8
OSC0_OUT: length 7.2
  TOP w0.173: Y1.1 73.8,83.79 74.81,84.79 75.35,84.79 75.64,84.5 75.64,83.26 76,82.9 C1.1 77.58,82.9 R4.1 77.72,82.76 R5.2
PCI_CONN_REFN: length 35.5
  TOP w0.108: v2(60.48,41.79) 60.35,41.66 60.35,41.36 C436.1
  BOTTOM w0.108: U45.5 32.62,36.15 32.74,36.03 39.32,36.03 48.23,44.93 59.08,44.93 60.48,43.54 v2(60.48,41.79)
PCI_CONN_REFP: length 35.4
  TOP w0.108: C437.1 60.03,41.35 60.03,41.65 v2(59.87,41.82)
  BOTTOM w0.108: U45.6 32.62,35.65 32.74,35.78 39.43,35.78 48.33,44.68 56.62,44.68 56.75,44.56 57.06,44.56 57.18,44.68 57.49,44.68 57.61,44.56 57.92,44.56 58.04,44.68 58.98,44.68 60.22,43.43 60.22,42.39 59.87,42.03 v2(59.87,41.82)
PCIE_CRDPRESENT: length 129.8
  TOP w0.173: R650.1 44.58,41.4 47.73,44.55 50.5,44.55 51.28,45.34 51.28,48.82 49.25,50.85 v2(49.2,50.85)
  L3_SIG1 w0.109: v2(97.61,113.88) 98.15,113.34 103.66,113.34 104.95,112.04 v2(106.17,112.04)
  BOTTOM w0.173: v2(106.17,112.04) 106.17,111.61 107.47,110.31 107.47,104.95 108.58,103.84 R664.1 ; v2(97.61,113.88) 97.97,113.52 97.97,112.98 85.74,100.75 85.39,100.75 80.25,95.61 71.91,95.61 70.31,94.01 67.11,94.01 65.2,92.1 65.2,88.14 54.84,77.77 54.84,70.99 52.78,68.94 52.78,67.64 51.79,66.65 51.79,57.78 49.2,55.19 v2(49.2,50.85)
PCIE_PERSTN: length 8
  TOP w0.173: U44.4 56.25,38.21 55.75,37.72 54.86,37.72 54.86,37.08 55.83,36.12 55.83,34.65 55.63,34.45 J22.A11
PCIE_REFCLKN: length 7.7
  TOP w0.108: C436.2 60.27,39.59 60.27,37.64 R580.2 60.25,36.75 60.25,36.09 59.77,35.61 59.77,34.6 60.01,34.36 60.09,34.32 60.36,34.41 60.67,35.04 J22.A14
PCIE_REFCLKP: length 7.8
  TOP w0.108: J22.A13 60.03,33.95 59.98,34.1 59.86,34.16 59.52,34.5 59.52,35.72 59.99,36.2 59.99,36.91 R580.1 60.02,37.54 60.02,39.69 C437.2
PCIE_RESETN: length 236.7
  TOP w0.173: U85.1 v2(57.52,48.17)
  L3_SIG1 w0.109: v2(156.08,47.75) 157.23,48.89 159.26,48.89 161.16,46.99 163.2,46.99 v5(164.59,45.59) ; v2(57.52,48.17) 61.05,48.17 62.99,46.23 62.99,43.4 62.99,43.39 62.99,42.97 62.99,42.96 62.99,39.62 68.91,33.71 68.91,27.76 66.75,25.6 63.42,25.6 62.26,24.44 62.26,21.28 64.46,19.08 64.46,15.39 62.75,13.68 v5(62.74,13.68)
  L4_SIG2 w0.114: v5(164.59,45.59) 164.34,45.34 164.34,39.7 165.23,38.81 165.23,36.55 156.88,28.21 152.27,28.21 147.29,23.24 140.6,23.24 129.3,11.94 117.29,11.94 116.66,11.31 106.16,11.31 105.06,12.42 103.24,12.42 102.77,11.95 99.73,11.95 98.45,13.23 69.89,13.23 69.41,13.71 62.77,13.71 v5(62.74,13.68)
  L9_SIG3 w0.114: v2(29.59,28.96) 35.94,28.96 37.08,30.1 37.08,42.42 v2(34.54,44.96)
  BOTTOM w0.173: v2(57.52,48.17) 57.52,48.27 56.9,48.89 51.31,48.89 50.34,47.93 44.98,47.93 42.06,45.01 41.25,45.01 40.82,45.44 39.04,45.44 38.56,44.96 v2(34.54,44.96) ; R568.2 28.45,30.1 v2(29.59,28.96) ; v2(156.08,47.75) 157.1,47.75 157.1,46.74
PCIE_SMB_CLK: length 5.8
  TOP w0.173: R652.1 50.29,27 49.73,27.56 49.73,30.56 J22.B5
PCIE_SMB_DATA: length 3.8
  TOP w0.173: R653.1 51.31,27.98 J22.B6
PCIE_TCK: length 4.8
  TOP w0.173: 49.53,37.72 49.53,35.79 49.73,35.58 49.73,34.74 49.53,34.54 49.53,33.26 J22.A5
PCIE_TDI: length 2.6
  TOP w0.173: J22.A6 50.67,35.2 50.67,37.72
PCIE_TDO: length 7.4
  TOP w0.173: TP20.1 51.69,33.22 J22.A7
PCIE_TMS: length 2.6
  TOP w0.173: 52.58,37.72 52.58,35.21 J22.A8
PCIE_TRSTN: length 8
  TOP w0.173: 53.72,37.72 53.66,37.66 53.66,35.72 53.54,35.6 53.54,34.7 52.53,33.68 52.53,31.77 J22.B9
PCIE_WAKEN: length 142.5
  TOP w0.173: R665.1 104.52,118.24 103.53,119.23 v2(102.49,119.23) ; R655.1 v2(54.99,23.32)
  L3_SIG1 w0.109: v5(59.36,52.07) 56.95,49.66 56.95,47.37 59.08,45.24 60.71,45.24 62.61,43.33 62.61,39.6 68.4,33.81 68.4,28.17 66.29,26.06 57.73,26.06 v2(54.99,23.32)
  L10_SIG4 w0.109: v5(59.36,52.07) 61.37,52.07 64.77,55.48 64.77,58.12 65.66,59.01 65.66,61.42 78.11,73.87 78.11,79.3 78.56,79.76 78.56,85.88 v9(79.23,86.55)
  BOTTOM w0.173: v2(102.49,119.23) 102.49,119.04 98.96,115.51 98.96,113.21 85.6,99.85 85.6,98.68 86.9,97.38 86.9,92.5 83.09,88.69 80.44,88.69 79.23,87.49 v9(79.23,86.55)
PCIECONN_PETN0: length 24
  TOP w0.108: v2(66.12,39.16) 66.29,39.34 66.29,39.64 C477.2
  BOTTOM w0.108: v2(66.12,39.16) 66.12,39.12 66.47,38.76 66.47,38.4 66.34,38.27 66.34,37.95 66.47,37.82 66.47,36.45 67.25,35.68 67.25,35.52 67.47,35.29 67.63,35.29 67.86,35.06 67.86,34.91 68.09,34.68 68.24,34.68 68.47,34.45 68.47,34.3 68.7,34.07 68.85,34.07 69.08,33.84 69.08,33.69 69.31,33.46 69.46,33.46 69.75,33.17 69.75,31.5 65.35,27.1 62.33,27.1 61.75,27.69 61.75,29.33 61.4,29.67 61.3,29.78 61.3,29.99 J22.B15
PCIECONN_PETP0: length 24
  TOP w0.108: v2(66.73,39.16) 66.55,39.34 66.55,39.64 C478.2
  BOTTOM w0.108: J22.B14 61,29.39 61.09,29.48 61.23,29.48 61.49,29.23 61.49,27.58 62.23,26.85 65.46,26.85 70,31.39 70,33.28 66.73,36.56 v2(66.73,39.16)
PHY0_LED_ACTN: length 29.8
  TOP w0.173: U21.17 30.21,121.61 v2(29.72,121.11) R321.2
  L9_SIG3 w0.114: v2(33.02,144.02) 33.87,143.17 33.87,134.65 33.02,133.8 33.02,131.65 28.45,127.08 28.45,122.38 v2(29.72,121.11)
  BOTTOM w0.173: R293.1 v2(33.02,144.02)
PHY0_LED_LINKN: length 28.7
  TOP w0.173: U21.15 30.38,122.61 R319.2 29.49,124.03 v2(29.68,124.22)
  L9_SIG3 w0.114: v2(34.16,143.93) 34.17,143.93 34.17,133.88 35.43,132.62 35.43,128.22 34.03,126.82 32.28,126.82 v2(29.68,124.22)
  BOTTOM w0.173: R296.1 v2(34.16,143.93)
PHY1_LED_ACTN: length 29.1
  TOP w0.173: U24.17 51.93,121.61 v2(51.43,121.11) 50.8,120.48 R364.2
  L9_SIG3 w0.114: v2(54.74,144.1) 54.74,137.19 53.16,135.61 53.16,134.7 51.87,133.4 51.87,130.56 51.02,129.72 51.02,123.81 52,122.83 52,121.68 v2(51.43,121.11)
  BOTTOM w0.173: R337.1 v2(54.74,144.1)
PHY1_LED_LINKN: length 26.4
  TOP w0.173: U24.15 52.12,122.61 51.94,122.78 51.94,123.55 v2(51.46,124.03) R363.2
  L9_SIG3 w0.114: v2(55.88,144.1) 55.88,137.82 53.58,135.52 53.58,134.51 52.32,133.25 52.32,130.12 51.46,129.25 v2(51.46,124.03)
  BOTTOM w0.173: R340.1 v2(55.88,144.1)
PHY_RESETN: length 362.3
  TOP w0.173: v2(31.12,88.09) 32.51,89.49 40.77,89.49 42.04,88.22 v2(42.04,87.46) ; v2(25.91,44.66) 25.91,41.4 27.18,40.13 27.18,31.54 28.07,30.65 28.07,29.72 v1(29.59,28.19)
  L9_SIG3 w0.114: v2(25.91,44.66) 25.91,48.04 22.86,51.09 22.86,62.31 v2(18.16,67.01) 18.16,67.84 26.34,76.02 26.34,79.89 29.91,83.46 29.91,84.24 30.81,85.14 30.81,86.36 31.19,86.74 31.19,88.02 v2(31.12,88.09) ; v1(29.59,28.19) 31.62,28.19 34.21,25.6 37.9,25.6 43.51,19.99 45.36,19.99 56.49,8.86 59.41,8.86 59.94,9.4 71.63,9.4 71.86,9.17 96.21,9.17 98.19,11.15 112.58,11.15 121.71,2.03 178.51,2.03 179.51,3.02 179.51,4.19 v2(180.61,5.29) ; v2(42.04,87.46) 42.04,89.36 40.39,91.01 40.39,102.06 33.4,109.05 v2(33.4,110.7) 33.93,111.23 38.99,111.23 39.67,111.91 51.87,111.91 52.58,111.21 v5(52.58,110.7)
  L10_SIG4 w0.109: v5(52.58,110.7) 53.21,110.06 v9(53.72,110.06)
  BOTTOM w0.173: U22.2 34.04,110.06 v2(33.4,110.7) ; v2(42.04,87.46) 42.42,87.84 U68.2 ; U26.2 v9(53.72,110.06) ; v2(25.91,44.66) 26.16,44.91 U71.2 ; v2(180.61,5.29) 180.61,15.35 179.97,15.99 179.97,24.52 176.89,27.6 174.23,27.6 173.31,28.52 162.74,28.52 157.1,34.16 157.1,42.04 ; U69.2 v2(31.12,88.09) ; U70.2 v2(18.16,67.01)
PMIC_EN: length 67.7
  TOP w0.173: U3.E5 v2(137.45,127.14) ; v2(93.98,105.45) 94.35,105.08 94.61,105.08 95,104.7 R929.1 ; R929.1 93.98,102.74 R645.1 ; R929.1 R928.2
  L10_SIG4 w0.109: v2(137.45,127.14) 136.22,125.91 136.22,125.35 134.65,123.77 134.65,121.82 133.96,121.13 130.81,121.13 130.66,121.28 130.05,121.9 122.53,121.9 111.91,111.28 111.91,106.51 112.57,105.85 112.57,103.86 112.29,103.59 109.04,103.59 106.04,106.58 100.48,106.58 99.35,105.45 v2(93.98,105.45)
PMIC_INT: length 71.9
  TOP w0.173: U3.K1 v7(134.25,123.14)
  L3_SIG1 w0.109: v7(134.25,123.14) 131.57,123.14 129.54,121.11 129.54,110.74 133.3,106.98 136.83,106.98 140.51,103.3 v5(141.02,103.3)
  L9_SIG3 w0.114: v5(141.02,103.3) 141.02,100.99 132.97,92.94 132.97,90.1 125.86,82.99 125.86,76.79 v5(123.83,74.76)
  L10_SIG4 w0.109: v9(123.83,73.23) v5(123.83,74.76)
  BOTTOM w0.173: R666.1 v9(123.83,73.23)
PMIC_RESET_IN: length 25.1
  TOP w0.173: U3.K9 v2(141.44,123.14) ; R981.1 U104.1
  TOP w0.381: v1(148.04,140.44) R981.1
  L9_SIG3 w0.114: v2(141.44,123.14) 143.54,125.24 143.54,130.81 142.62,131.73 142.62,133.63 148.04,139.05 v1(148.04,140.44)
  BOTTOM w0.173: v2(141.44,123.14) 141.18,122.89 R794.1
PMIC_RESET_OUTN: length 21.7
  TOP w0.173: U3.G6 v2(138.25,126.33)
  L10_SIG4 w0.109: v9(138.3,114.27) 139.01,114.99 139.29,114.99 140.84,116.54 140.84,117.2 143.26,119.61 143.26,121.66 143.43,121.83 143.43,125.7 142.4,126.73 138.67,126.73 138.27,126.33 v2(138.25,126.33)
  BOTTOM w0.173: R814.2 v9(138.3,114.27) ; R9.1 138.14,126.45 v2(138.25,126.33)
PORZN: length 257.9
  TOP w0.173: v2(147.8,77.14) 147.32,76.66 136.83,76.66 134.24,74.07 ; R499.1 70.56,77.75 70.23,78.08 v7(70.23,78.31)
  L3_SIG1 w0.109: v2(159.05,47.75) 159.05,46.18 162.31,42.93 163.76,42.93 v2(165.43,41.26) 164.7,41.26 146.43,22.99 141.73,22.99 140.87,22.12 110.77,22.12 110.46,22.43 107.59,22.43 107.29,22.12 73.28,22.12 69.37,26.03 69.37,33.66 64.14,38.89 64.14,46.44 61.74,48.83 61.74,61.35 64.02,63.62 64.02,65.16 v2(64.52,65.66) 67.18,65.66 73.02,71.5 73.02,76.2 70.92,78.31 v7(70.23,78.31)
  L4_SIG2 w0.114: v2(147.8,77.14) 148.29,76.66 149.34,76.66 159.79,66.2 161.02,66.2 167.61,59.61 167.61,51.56 164.93,48.88 164.93,46.55 165.81,45.68 165.81,41.64 v2(165.43,41.26)
  BOTTOM w0.173: R926.1 v2(64.52,65.66) ; U98.4 164.23,41.27 C213.1 165.43,41.26 v2(165.43,41.26) 165.43,40.82 165.86,40.39 165.86,39.75 165.48,39.37 162.05,39.37 160.4,41.02 R921.2 ; R920.2 v2(159.05,47.75)
PR1_EDC_LATCH0: length 77.8
  TOP w0.173: v7(101.47,134.11) 100.17,135.41 100.17,142.01 101.37,143.21 R743.2 ; v7(125.98,103.5) 124.37,103.5 122.17,101.3 120.78,101.3 119.89,100.41 119.89,98.79 v2(119.66,98.56) ; v7(111.86,95.33) 111.86,95.06 110.24,93.44 110.24,92.02 U1.E2
  L3_SIG1 w0.109: v5(113.59,97.46) 113.59,96.68 112.24,95.33 v7(111.86,95.33) ; v7(101.47,134.11) 103.32,134.11 105.11,132.33 105.11,131.77 111.05,125.82 111.05,123.8 123.32,111.54 123.32,106.55 125.98,103.88 v7(125.98,103.5)
  L10_SIG4 w0.109: v5(113.59,97.46) 114.04,97.01 117.28,97.01 118.82,98.56 v2(119.66,98.56)
PR1_EDC_SYNC0: length 18.6
  TOP w0.173: v7(112.45,96.22) 112.45,95.87 112.55,95.76 112.55,94.9 111.03,93.39 111.03,92.01 U1.D2 ; v2(121.97,99.4) R744.2
  L3_SIG1 w0.109: v5(114.35,97.92) 113.41,97.92 113.14,97.65 113.14,96.87 112.49,96.22 v7(112.45,96.22)
  L10_SIG4 w0.109: v2(121.97,99.4) 117.86,99.4 117.73,99.52 115.11,99.52 114.15,98.56 114.15,98.13 v5(114.35,97.92)
PR1_EDIO_DATA_OUT1: length 2.5
  TOP w0.173: R119.1 J4.4
PR1_EDIO_DATA_OUT3: length 2.5
  TOP w0.173: R118.1 J4.3
PR1_EDIO_DATA_OUT4: length 2.6
  TOP w0.173: R198.1 J7.3
PR1_EDIO_DATA_OUT6: length 2.6
  TOP w0.173: R199.1 J7.4
PR2_EDC_LATCH0: length 216.1
  TOP w0.173: R910.1 v7(137.54,101.85) ; R748.1 v7(30.61,91.93)
  L3_SIG1 w0.109: v7(137.54,101.85) 134.87,101.85 134.49,102.23 134.49,103.12 133.48,104.14 132.46,104.14 129.67,106.93 127.67,106.93 126.1,108.5 126.1,111.79 115.19,122.71 115.19,125.73 110.24,130.68 110.24,135.13 112.65,137.54 112.65,141.22 113.35,141.92 J21.13 112.36,148.01 104.9,148.01 104.37,147.48 104.37,146.46 97.91,140.01 77.67,140.01 75.96,138.29 71.77,138.29 68.94,135.46 61.54,135.46 60.93,136.07 49.05,136.07 48.21,135.23 48.21,132.54 46.51,130.84 25.33,130.84 22.36,127.87 19.09,127.87 16,124.78 16,121.28 15.44,120.71 15.44,118.39 16.19,117.65 16.19,115.3 15.93,115.05 15.93,115.05 15.45,114.57 15.45,113.89 14.99,113.42 14.99,102.47 25.2,92.26 28.66,92.26 28.81,92.41 30.12,92.41 v7(30.61,91.93)
PR2_EDC_LATCH1: length 69.6
  TOP w0.173: R911.1 128.78,106.17 v7(130.05,107.44)
  L3_SIG1 w0.109: v7(130.05,107.44) 129.98,107.37 v5(128.6,107.37) 127.64,107.37 126.39,108.62 126.39,112.2 115.72,122.86 115.72,125.7 111.12,130.3 111.12,134.72 115.35,138.94 J21.15
  L10_SIG4 w0.109: v9(119.51,99.9) 121.41,99.9 122.48,100.97 122.48,103.92 124.28,105.72 125.63,105.72 127.28,107.37 v5(128.6,107.37)
  BOTTOM w0.173: R749.1 v9(119.51,99.9)
PR2_EDC_SYNC0: length 228.8
  TOP w0.173: R908.1 128.4,102.49 127.89,103 127.89,106.33 v7(129.41,107.85)
  TOP w0.254: U103.5 43.87,62.58 43.62,62.33 v1(43.13,62.33)
  L3_SIG1 w0.109: v7(129.41,107.85) v5(127.79,107.85) 128.37,108.44 128.37,110.74 116.1,123.01 116.1,125.83 111.66,130.28 111.66,134.04 117.35,139.72 J21.17
  L10_SIG4 w0.109: v9(118.24,99.9) 118.87,99.9 119.33,100.36 121.21,100.36 122.12,101.27 122.12,105.77 123.65,107.29 125.65,107.29 126.21,107.85 v5(127.79,107.85) ; J21.17 116.33,148.03 116.33,149.78 115.9,150.22 100.85,150.22 100.1,149.47 100.1,148.64 98.35,146.89 95.54,146.89 94.7,146.05 92.15,146.05 91.44,146.76 90.55,146.76 89.38,145.59 86.77,145.59 85.55,144.37 v1(85.55,135.53)
  BOTTOM w0.173: R750.1 v9(118.24,99.9) ; v1(85.55,135.53) 87.08,134 87.08,120.53 87.94,119.67 87.94,115.14 84.33,111.53 83.34,111.53 81.36,109.55 81.36,107.87 80.14,106.65 68.94,106.65 66.12,103.84 66.12,97.13 59.56,90.58 59.56,87 57.58,85.01 54.76,85.01 51.91,82.16 51.91,81.55 43.24,72.88 42.59,72.88 41.58,71.87 41.58,68.48 43.13,66.92 v1(43.13,62.33)
PR2_EDC_SYNC1: length 122.6
  TOP w0.173: v5(127.38,91.19) v7(126.59,91.19)
  L3_SIG1 w0.109: v7(126.59,91.19) v5(127.38,91.19) ; v5(139.17,103.84) 136.47,106.53 133.35,106.53 119.43,120.45 119.43,125.27 115.85,128.85 113.72,128.85 v5(112.39,130.18) 112.39,133.93 118.16,139.7 118.16,141.55 119.35,142.74 J21.19
  L4_SIG2 w0.114: v5(127.38,91.19) 127.79,91.19 128.71,92.11 128.71,92.12 139.17,102.58 v5(139.17,103.84) ; v5(112.22,97.08) 110.92,98.38 110.92,103.35 111.66,104.08 111.66,105.31 111.02,105.94 111.02,106.53 111.89,107.4 111.89,108.29 112.9,109.3 112.9,114.53 111.6,115.83 111.6,122.57 112.39,123.36 v5(112.39,130.18)
  L10_SIG4 w0.109: v5(112.22,97.08) 111.86,96.73 v9(111.38,96.73)
  BOTTOM w0.173: v9(111.38,96.73) 111.76,96.73 113.54,98.51 113.54,100.41 R751.1
PR2_MII0_RXDV: length 2.6
  TOP w0.173: R197.1 J7.2
PR2_MII0_TXEN: length 2.6
  TOP w0.173: R196.1 J7.1
PR2_MII1_RXDV: length 2.5
  TOP w0.173: R117.1 J4.2
PR2_MII1_TXEN: length 2.5
  TOP w0.173: R115.1 J4.1
PR2_UART0_RXD: length 204
  TOP w0.173: R906.1 v7(136.78,99.57)
  TOP w0.381: R947.2 v1(43.92,71.11) ; R942.1 v1(48.6,60.8) ; R952.2 v1(152.37,144.91)
  L3_SIG1 w0.109: v7(136.78,99.57) v5(136.78,98.93)
  L4_SIG2 w0.114: v5(136.78,98.93) 138.33,98.93 141.63,102.23 141.63,104.93 146.62,109.93 146.62,122.02 148.03,123.43 148.03,133.74 149.94,135.64 149.94,142.01 152.37,144.45 v1(152.37,144.91) 152.37,144.95 152.37,148.05 J21.54
  L9_SIG3 w0.114: v1(71.98,73.81) 73.13,72.67 78.08,72.67 79.53,74.12 90.35,74.12 90.8,74.57 98.27,74.57 99.86,76.16 104.39,76.16 104.62,76.39 104.62,77.5 104.89,77.77 110.54,77.77 111.07,78.31 116.64,78.31 126.91,88.58 129.16,88.58 131.4,90.82 131.4,93.46 136.78,98.83 v5(136.78,98.93)
  BOTTOM w0.173: v1(43.92,71.11) 48.06,66.97 48.06,63.45 48.6,62.91 v1(48.6,60.8) 48.6,60.1 46.46,57.96 46.46,52.32 47.85,50.93 47.85,50.11 48.39,49.58 48.97,49.58 54.89,55.5 55.55,55.5 61.82,61.77 64.9,61.77 69.01,65.89 71.75,65.89 72.59,66.73 72.59,73.2 v1(71.98,73.81)
PR2_UART0_TXD: length 237.2
  TOP w0.173: R940.1 v1(49.56,71.39) ; R953.2 v1(153.52,144.85) ; R907.1 v7(137.54,90.17)
  L3_SIG1 w0.109: v7(137.54,90.17) v5(138.18,90.17)
  L4_SIG2 w0.114: v1(99.07,146.93) 99.07,144.26 102.01,141.33 102.01,139.57 94.08,131.65 87.28,131.65 84.56,128.93 84.56,124.54 83.91,123.89 83.91,113.24 80.67,110 80.67,100.79 78.16,98.27 78.16,93.93 76.65,92.43 74.3,92.43 71.97,90.11 65.55,90.11 59.01,83.57 57.28,83.57 49.56,75.85 v1(49.56,71.39) ; J21.56 154.32,147.99 154.32,145.65 v1(153.52,144.85) 153.52,144.3 151,141.78 151,138.35 150.47,137.82 150.47,133.63 148.59,131.75 148.59,122.53 147.19,121.13 147.19,109.63 142.16,104.6 142.16,101.4 138.18,97.41 v5(138.18,90.17)
  BOTTOM w0.173: J21.56 155.35,149.25 154.13,150.47 100.79,150.47 99.95,149.63 99.95,147.81 v1(99.07,146.93)
PROFIBUS_A: length 51.9
  TOP w0.173: J14.3 94.15,3.9 93.6,4.45 93.6,7.99 U81.1 93.6,9.02 93.6,9.53 93.85,9.78 100.1,9.78 103.46,6.42 109.98,6.42 111.07,5.33 111.07,2.07 111.72,1.42 119.17,1.42 120.36,2.61 120.36,8 119.93,8.43 119.22,8.43 118.76,8.89 U74.12 114.94,8.89
PROFIBUS_B: length 51.3
  TOP w0.173: J14.8 92.76,3.86 93.22,4.32 93.22,7.99 U80.1 93.25,9.06 93.25,9.67 93.71,10.13 100.25,10.13 103.61,6.77 110.12,6.77 111.42,5.47 111.42,2.22 111.86,1.77 119.02,1.77 120,2.76 120,7.86 119.78,8.08 119.22,8.08 118.76,7.62 U74.13 114.94,7.62
PRU1ETH0_25MHZCLK: length 23
  BOTTOM w0.173: R310.2 37.35,103.95 35.69,105.62 35.69,106.13 34.54,107.27 29.51,107.27 26.62,110.16 26.62,115.98 25.15,117.45 U9.23
PRU1ETH0_COL: length 143.9
  TOP w0.173: v2(84.71,130.26) 84.2,129.75 84.2,119.13 86.11,117.22 R105.1
  L3_SIG1 w0.109: v5(22.1,108.41) 21.46,108.41 20.95,108.92 20.95,110.32 20.22,111.05 20.22,116.06 20.7,116.54 20.7,122.4 24.54,126.23 29.52,126.23 31.16,124.6 39.02,124.6 41.55,127.13 45.34,127.13 45.87,126.6 58.93,126.6 63.53,131.19 63.53,131.91 63.94,132.33 79.31,132.33 80.43,131.21 83.76,131.21 v2(84.71,130.26)
  L9_SIG3 w0.114: v2(7.24,130.38) 8.89,130.38 15.75,123.53 15.75,121.49 14.99,120.73 14.99,116.18 21.21,109.96 21.21,109.3 v5(22.1,108.41)
  L10_SIG4 w0.109: v9(23.62,108.67) 22.35,108.67 v5(22.1,108.41)
  BOTTOM w0.173: R106.2 v2(7.24,130.38) ; v9(23.62,108.67) 23.6,108.69 23.6,110.46 R95.1 22.86,112.89 22.13,113.62 R104.2 22.03,114.61 21.09,115.56 U9.29
PRU1ETH0_CRS: length 109.5
  TOP w0.173: R94.1 v7(88.65,100.92)
  L3_SIG1 w0.109: v7(88.65,100.92) v5(88.65,101.55)
  L10_SIG4 w0.109: v5(88.65,101.55) 88.65,101.58 87.3,102.93 83.85,102.93 80.01,106.76 78.75,106.76 78.64,106.87 78.64,107.29 78.53,107.4 78.31,107.4 78.21,107.29 78.21,106.87 78.1,106.76 77.88,106.76 77.77,106.87 77.77,107.29 77.66,107.4 77.44,107.4 77.33,107.29 77.33,106.87 77.22,106.76 77,106.76 76.89,106.87 76.89,107.29 76.79,107.4 76.57,107.4 76.46,107.29 76.46,106.87 76.35,106.76 76.13,106.76 76.02,106.87 76.02,107.29 75.91,107.4 75.69,107.4 75.58,107.29 75.58,106.87 75.48,106.76 75.26,106.76 75.15,106.87 75.15,107.29 75.04,107.4 74.82,107.4 74.71,107.29 74.71,106.87 74.6,106.76 74.23,106.76 74.09,106.9 74.09,107.99 73.95,108.13 73.75,108.13 73.61,107.99 73.61,106.9 73.47,106.76 73.27,106.76 73.13,106.9 73.13,107.99 72.99,108.13 72.74,108.13 72.52,107.91 72.52,106.98 72.38,106.84 72.18,106.84 72.04,106.98 72.04,107.84 71.9,107.98 71.7,107.98 71.56,107.84 71.56,106.98 71.42,106.84 71.22,106.84 71.08,106.98 71.08,107.84 70.94,107.98 70.74,107.98 70.6,107.84 70.6,106.98 70.46,106.84 70.26,106.84 70.12,106.98 70.12,107.84 69.98,107.98 69.78,107.98 69.64,107.84 69.64,106.98 69.5,106.84 69.3,106.84 69.16,106.98 69.16,107.46 69.02,107.6 68.82,107.6 68.68,107.46 68.68,106.98 68.54,106.84 68.34,106.84 68.2,106.98 68.2,107.46 68.05,107.6 67.86,107.6 67.72,107.46 67.72,107.03 67.57,106.89 67.38,106.89 67.24,107.03 67.24,107.84 67.09,107.98 66.9,107.98 66.76,107.84 66.76,106.98 66.61,106.84 66.42,106.84 66.28,106.98 66.28,107.84 66.13,107.98 65.94,107.98 65.8,107.84 65.8,106.98 65.65,106.84 65.46,106.84 65.32,106.98 65.32,107.84 65.17,107.98 64.98,107.98 64.84,107.84 64.84,106.98 64.69,106.84 64.5,106.84 64.36,106.98 64.36,107.84 64.21,107.98 64.02,107.98 63.88,107.84 63.88,106.86 63.73,106.72 63.54,106.72 63.4,106.86 63.4,107.84 63.25,107.98 63.06,107.98 62.92,107.84 62.92,106.87 62.79,106.74 62.59,106.74 62.43,106.9 62.43,107.84 62.29,107.98 61.98,107.98 61.57,108.39 61.57,108.64 61.34,108.87 58.86,108.87 57.8,109.93 54.84,109.93 53.73,111.03 52.95,111.03 52.27,111.71 48.77,111.71 48.23,111.18 44.27,111.18 44.17,111.07 44.17,110.78 44.06,110.67 43.84,110.67 43.73,110.78 43.73,111.07 43.62,111.18 43.4,111.18 43.29,111.07 43.29,110.78 43.18,110.67 42.96,110.67 42.86,110.78 42.86,111.07 42.75,111.18 42.53,111.18 42.42,111.07 42.42,110.78 42.31,110.67 42.09,110.67 41.98,110.78 41.98,111.07 41.87,111.18 41.65,111.18 41.54,111.07 41.54,110.78 41.44,110.67 41.22,110.67 41.11,110.78 41.11,111.07 41,111.18 39.6,111.18 39.42,111 35.64,111 33.88,112.76 32.68,112.76 32.57,112.86 32.57,113.41 32.46,113.52 32.24,113.52 32.13,113.41 32.13,112.86 32.02,112.76 31.8,112.76 31.69,112.86 31.69,113.41 31.59,113.52 31.37,113.52 31.26,113.41 31.26,112.86 31.15,112.76 30.86,112.76 29.74,113.87 27.3,113.87 27.05,113.62 24.38,113.62 v9(23.24,114.76)
  BOTTOM w0.173: U9.27 22.09,115.68 22.62,115.14 22.86,115.14 v9(23.24,114.76)
PRU1ETH0_INTN: length 131.6
  TOP w0.173: R669.2 113.54,105.77 114.53,106.76 114.53,106.96 115.47,107.9 115.47,109.96 113.64,111.79 113.64,120.62 v2(110.62,123.65)
  L3_SIG1 w0.109: v2(110.62,123.65) 110.62,125.71 105.26,131.07 105.26,131.13 104.76,131.63 104.33,131.63 102.36,133.61 97.33,133.61 97.21,133.73 87.45,133.73 87.44,133.74 63.56,133.74 62.31,132.49 62.31,131.95 60.86,130.51 58.57,130.51 57.08,129.01 47.07,129.01 46.73,128.68 39.19,128.68 37.95,127.44 32.66,127.44 32.21,127.89 27.87,127.89 27.87,127.9 27.51,127.9 27.5,127.89 25.2,127.89 19.45,122.14 v2(18.29,122.14)
  BOTTOM w0.173: U9.8 18.42,120.45 18.29,120.58 18.29,122.14 v2(18.29,122.14)
PRU1ETH0_LINKLED: length 27.1
  L9_SIG3 w0.114: v5(25.4,121.11) 25.4,122 22.55,124.85 15.44,124.85 8.76,131.53 v2(7.24,131.53)
  L10_SIG4 w0.109: v9(25.4,121.87) v5(25.4,121.11)
  BOTTOM w0.173: R93.2 v2(7.24,131.53) ; v9(25.4,121.87) v5(25.4,121.11) 25.04,120.75 24.41,120.75 24.11,120.45 U9.17
PRU1ETH0_MDC: length 1.6
  BOTTOM w0.173: R96.1 24.87,118.83 24.75,118.95 U9.20
PRU1ETH0_MDIO: length 1.8
  BOTTOM w0.173: R98.1 25.01,119.45 U9.19
PRU1ETH0_RESETN: length 43
  L9_SIG3 w0.114: v1(24.77,120.24) 24.77,118.87 25.61,118.02 25.61,107.78 26.4,107 26.4,103.4 29.16,100.64 29.16,94.61 31.68,92.1 32.13,92.1 32.14,92.09 v1(34.54,92.09)
  BOTTOM w0.173: U68.4 40.91,90.57 40.64,90.3 36.34,90.3 v1(34.54,92.09) ; v1(24.77,120.24) 24.47,119.95 U9.18
PRU1ETH0_RXCLK: length 3.7
  BOTTOM w0.173: R83.1 24.38,113.62 24.38,114.89 23.09,116.19 U9.25
PRU1ETH0_RXD0: length 106.4
  TOP w0.173: R88.1 v7(86.11,100.92)
  L3_SIG1 w0.109: v7(86.11,100.92) v5(86.11,101.55)
  L10_SIG4 w0.109: v5(86.11,101.55) 85.65,102.01 83.49,102.01 80.54,104.96 80.16,104.96 80.06,104.86 80.06,104.43 79.91,104.28 79.64,104.28 79.51,104.4 79.51,105.69 79.37,105.84 79.17,105.84 79.03,105.69 79.03,104.42 78.88,104.27 78.68,104.27 78.55,104.41 78.55,105.69 78.41,105.84 78.21,105.84 78.07,105.69 78.07,104.41 77.94,104.28 77.74,104.28 77.59,104.43 77.59,105.69 77.45,105.84 74.84,105.84 74.67,105.66 74.67,104.64 74.53,104.5 74.33,104.5 74.19,104.64 74.19,105.69 74.05,105.83 73.85,105.83 73.71,105.69 73.71,104.71 73.54,104.55 73.34,104.55 73.23,104.66 73.23,105.69 73.09,105.83 72.89,105.83 72.75,105.69 72.75,104.74 72.61,104.6 72.41,104.6 72.27,104.74 72.27,105.69 72.13,105.83 71.93,105.83 71.79,105.69 71.79,104.79 71.29,104.29 61.65,104.29 60.93,105.01 60.37,105.01 59.19,106.19 59.19,106.75 57.58,108.36 55.6,108.36 55.48,108.48 55.48,108.8 55.37,108.92 55.2,108.92 55.09,108.8 55.09,108.48 54.97,108.36 48.26,108.36 47.65,108.97 46.72,108.97 46.61,109.09 46.61,109.64 46.49,109.76 46.33,109.76 46.21,109.64 46.21,109.09 46.09,108.97 45.83,108.97 45.72,109.09 45.72,109.62 45.58,109.76 45.41,109.76 45.32,109.67 45.32,109.09 45.2,108.97 45.04,108.97 44.92,109.09 44.92,109.64 44.81,109.76 44.64,109.76 44.53,109.64 44.53,109.09 44.41,108.97 44.25,108.97 44.13,109.09 44.13,109.64 44.02,109.76 43.85,109.76 43.74,109.64 43.74,109.09 43.62,108.97 43.46,108.97 43.34,109.09 43.34,109.64 43.22,109.76 43.06,109.76 42.94,109.64 42.94,109.09 42.83,108.97 42.35,108.97 42.23,109.09 42.23,109.64 42.12,109.76 41.95,109.76 41.84,109.64 41.84,109.09 41.72,108.97 41.56,108.97 41.44,109.09 41.44,109.64 41.32,109.76 41.16,109.76 41.04,109.64 41.04,109.09 40.93,108.97 40.76,108.97 40.65,109.09 40.65,109.64 40.53,109.76 40.37,109.76 40.25,109.64 40.25,109.09 40.11,108.95 39.04,108.95 37.91,110.07 33.4,110.07 31.82,111.65 31.23,111.65 31.12,111.54 31.12,111.06 31.01,110.95 30.79,110.95 30.68,111.06 30.68,111.54 30.57,111.65 30.36,111.65 30.25,111.54 30.25,111.06 30.14,110.95 29.92,110.95 29.81,111.06 29.81,111.54 29.7,111.65 29.48,111.65 29.37,111.54 29.37,111.06 29.26,110.95 29.04,110.95 28.94,111.06 28.94,111.54 28.83,111.65 23.25,111.65 22.56,112.35 v9(20.45,112.35)
  BOTTOM w0.173: U9.30 20.59,115.19 R111.2 21.02,114.76 20.43,114.17 20.43,112.37 v9(20.45,112.35)
PRU1ETH0_RXD1: length 115.9
  TOP w0.173: R90.1 v7(91.19,100.92)
  L3_SIG1 w0.109: v7(91.19,100.92) v5(91.19,101.55)
  L10_SIG4 w0.109: v9(19.3,112.35) 19.3,114.36 18.54,115.12 18.54,115.98 19.06,116.5 25.02,116.5 25.14,116.38 25.14,115.94 25.25,115.83 25.42,115.83 25.53,115.94 25.53,116.38 25.65,116.5 27.35,116.5 28.04,115.8 30.43,115.8 31.5,114.74 33.33,114.74 34.23,113.83 37.6,113.83 39.34,112.1 43.27,112.1 43.39,112.21 43.39,112.9 43.5,113.01 43.67,113.01 43.78,112.9 43.78,112.2 43.89,112.09 44.15,112.09 44.29,112.23 44.29,112.87 44.41,112.98 44.57,112.98 44.69,112.87 44.69,112.23 44.82,112.1 44.97,112.1 45.08,112.21 45.08,112.87 45.2,112.98 45.36,112.98 45.48,112.87 45.48,112.23 45.61,112.1 45.76,112.1 45.87,112.21 45.87,112.87 45.99,112.98 46.15,112.98 46.27,112.87 46.27,112.23 46.4,112.1 46.56,112.1 46.67,112.21 46.67,112.87 46.78,112.98 46.95,112.98 47.06,112.87 47.06,112.2 47.17,112.09 47.65,112.09 48.26,112.7 52.81,112.7 53.44,112.07 54.25,112.07 55.43,110.9 60.93,110.9 61.24,111.21 62.23,111.21 63.24,110.2 67.34,110.2 67.44,110.31 67.44,111.27 67.55,111.38 67.77,111.38 67.88,111.27 67.88,110.31 67.99,110.2 68.21,110.2 68.32,110.31 68.32,111.27 68.43,111.38 68.65,111.38 68.76,111.27 68.76,110.31 68.86,110.2 69.08,110.2 69.19,110.31 69.19,111.27 69.3,111.38 69.52,111.38 69.63,111.27 69.63,110.31 69.74,110.2 69.96,110.2 70.07,110.31 70.07,111.27 70.18,111.38 70.39,111.38 70.5,111.27 70.5,110.31 70.61,110.2 70.83,110.2 70.94,110.31 70.94,111.27 71.05,111.38 71.27,111.38 71.38,111.27 71.38,110.31 71.49,110.2 71.7,110.2 71.81,110.31 71.81,111.27 71.92,111.38 72.14,111.38 72.25,111.27 72.25,110.31 72.36,110.2 72.58,110.2 72.69,110.31 72.69,111.27 72.8,111.38 73.01,111.38 73.12,111.27 73.12,110.31 73.23,110.2 73.45,110.2 73.56,110.31 73.56,111.27 73.67,111.38 73.89,111.38 74,111.27 74,110.31 74.11,110.2 79.52,110.2 80.77,108.95 80.77,107.29 84.23,103.84 88.9,103.84 v5(91.19,101.55)
  BOTTOM w0.173: v9(19.3,112.35) 19.32,112.36 19.32,114.27 19.81,114.76 R110.2 19.87,115.35 20.09,115.56 U9.31
PRU1ETH0_RXD2: length 109.6
  TOP w0.173: R91.1 v7(89.92,100.92)
  L3_SIG1 w0.109: v7(89.92,100.92) v5(89.92,101.55)
  L10_SIG4 w0.109: v9(19,115.63) 20,115.63 20.11,115.52 20.11,115.1 20.22,114.99 20.44,114.99 20.55,115.1 20.55,115.52 20.66,115.63 20.87,115.63 20.98,115.52 20.98,115.1 21.09,114.99 21.31,114.99 21.42,115.1 21.42,115.52 21.53,115.63 21.75,115.63 21.86,115.52 21.86,115.1 21.97,114.99 22.19,114.99 22.29,115.1 22.29,115.52 22.4,115.63 23.57,115.63 24.07,115.12 30.47,115.12 31.55,114.04 33.21,114.04 33.87,113.38 34.75,113.38 34.87,113.26 34.87,112.49 34.98,112.37 35.15,112.37 35.26,112.49 35.26,113.26 35.38,113.38 35.8,113.38 36.26,112.91 36.42,112.91 36.87,113.37 37.03,113.37 37.18,113.22 37.18,113.06 36.73,112.61 36.73,112.45 36.88,112.3 37.04,112.3 37.49,112.75 37.65,112.75 37.8,112.6 37.8,112.44 37.35,111.99 37.35,111.83 37.54,111.64 48.01,111.64 48.59,112.22 52.57,112.22 53.28,111.51 54.03,111.51 55.08,110.46 58.13,110.46 58.62,109.96 61.68,109.96 62.03,109.61 62.03,108.6 62.18,108.46 62.37,108.46 62.51,108.6 62.51,109.61 62.66,109.75 62.85,109.75 63,109.61 63,108.6 63.14,108.46 63.33,108.46 63.48,108.6 63.48,109.61 63.62,109.75 63.81,109.75 63.96,109.61 63.96,108.6 64.1,108.46 64.29,108.46 64.44,108.6 64.44,109.61 64.58,109.75 64.77,109.75 64.92,109.61 64.92,108.6 65.06,108.46 65.25,108.46 65.4,108.6 65.4,109.61 65.54,109.75 65.73,109.75 65.88,109.61 65.88,108.6 66.02,108.46 66.21,108.46 66.36,108.6 66.36,109.61 66.5,109.75 66.69,109.75 66.84,109.61 66.84,108.6 66.98,108.46 67.17,108.46 67.32,108.6 67.32,109.61 67.46,109.75 67.65,109.75 67.8,109.61 67.8,109.37 67.94,109.23 68.13,109.23 68.28,109.37 68.28,109.61 68.42,109.75 68.62,109.75 68.76,109.61 68.76,109.37 68.9,109.23 69.1,109.23 69.24,109.37 69.24,109.61 69.38,109.75 69.58,109.75 69.72,109.61 69.72,108.6 69.86,108.46 70.06,108.46 70.2,108.6 70.2,109.61 70.34,109.75 70.54,109.75 70.68,109.61 70.68,108.6 70.82,108.46 71.02,108.46 71.16,108.6 71.16,109.6 71.3,109.74 71.5,109.74 71.64,109.6 71.64,108.6 71.78,108.46 71.98,108.46 72.12,108.6 72.12,109.4 72.27,109.55 73.66,109.55 75.31,107.9 79.5,107.9 84.02,103.38 88.04,103.38 89.87,101.55 v5(89.92,101.55)
  BOTTOM w0.173: R109.2 18.73,115.36 v9(19,115.63) 19,115.62 19.28,115.62 19.59,115.92 U9.32
PRU1ETH0_RXD3: length 104.8
  TOP w0.173: R92.1 v7(84.84,100.92)
  L3_SIG1 w0.109: v7(84.84,100.92) v5(84.84,101.55)
  L10_SIG4 w0.109: v9(16.38,115.78) 16.38,114.28 19.84,110.82 27.17,110.82 28.57,109.43 36.58,109.43 38.1,107.9 39.53,107.9 39.64,107.79 39.64,106.55 39.76,106.43 39.92,106.43 40.04,106.55 40.04,107.79 40.16,107.9 40.32,107.9 40.44,107.79 40.44,106.55 40.55,106.43 40.72,106.43 40.83,106.55 40.83,107.79 40.95,107.9 41.11,107.9 41.23,107.79 41.23,106.52 41.35,106.41 41.51,106.41 41.63,106.52 41.63,107.79 41.74,107.9 41.91,107.9 42.02,107.79 42.02,106.52 42.14,106.41 42.3,106.41 42.42,106.52 42.42,107.79 42.53,107.9 42.7,107.9 42.81,107.79 42.81,106.5 42.93,106.38 43.09,106.38 43.21,106.5 43.21,107.79 43.33,107.9 43.49,107.9 43.61,107.79 43.61,106.5 43.72,106.38 43.89,106.38 44,106.5 44,107.28 44.35,107.62 54.74,107.62 56.07,106.29 56.27,106.29 56.89,106.92 57.09,106.92 57.23,106.78 57.23,106.58 56.61,105.95 56.61,105.75 56.75,105.61 56.95,105.61 57.57,106.24 57.77,106.24 57.91,106.1 57.91,105.9 57.29,105.27 57.29,105.07 57.58,104.78 57.78,104.78 58.42,105.42 58.62,105.42 58.76,105.28 58.76,105.08 58.12,104.44 58.12,104.24 58.37,103.99 58.77,103.99 58.88,104.1 58.88,104.37 58.99,104.48 59.21,104.48 59.32,104.37 59.32,104.1 59.43,103.99 60.05,103.99 60.9,103.13 69.34,103.13 69.89,103.69 71.45,103.69 71.62,103.86 73.54,103.86 74.24,103.15 74.73,103.15 75.43,103.86 75.85,103.86 76.17,103.54 81.15,103.54 82.28,102.4 82.28,102.25 81.82,101.78 81.82,101.63 81.97,101.47 82.12,101.47 82.59,101.94 82.75,101.94 83.13,101.55 v5(84.84,101.55)
  BOTTOM w0.173: v9(16.38,115.78) 17.02,115.78 R108.2 18.19,116.95 U9.1
PRU1ETH0_RXDV: length 3.8
  BOTTOM w0.173: R86.1 23.68,114.04 23.85,114.2 23.85,114.89 23.32,115.42 22.87,115.42 22.59,115.7 U9.26
PRU1ETH0_RXERR: length 106.4
  TOP w0.173: R87.1 v7(87.38,100.92)
  L3_SIG1 w0.109: v7(87.38,100.92) v5(87.38,101.55)
  L10_SIG4 w0.109: v5(87.38,101.55) 86.46,102.47 83.67,102.47 79.85,106.29 71.54,106.29 71.23,105.98 71.23,105.01 71,104.78 70.64,104.78 70.53,104.9 70.53,106.1 70.41,106.21 70.25,106.21 70.13,106.1 70.13,104.9 70.02,104.78 69.85,104.78 69.73,104.9 69.73,106.1 69.62,106.21 69.45,106.21 69.34,106.1 69.34,104.9 69.22,104.78 69.06,104.78 68.94,104.9 68.94,105.95 68.83,106.06 68.66,106.06 68.55,105.95 68.55,104.9 68.43,104.78 68.27,104.78 68.15,104.9 68.15,105.95 68.03,106.06 67.87,106.06 67.75,105.95 67.75,104.9 67.64,104.78 66.65,104.78 66.51,104.92 66.51,106.15 66.37,106.29 66.17,106.29 66.03,106.15 66.03,104.92 65.89,104.78 65.69,104.78 65.55,104.92 65.55,106.15 65.41,106.29 65.21,106.29 65.07,106.15 65.07,104.92 64.93,104.78 64.73,104.78 64.59,104.92 64.59,106.15 64.45,106.29 64.25,106.29 64.11,106.15 64.11,104.92 63.97,104.78 63.7,104.78 63.58,104.9 63.58,106.13 63.46,106.25 63.3,106.25 63.18,106.13 63.18,104.9 63.07,104.78 62.9,104.78 62.79,104.9 62.79,106.18 62.67,106.3 62.51,106.3 62.39,106.18 62.39,105.14 62.23,104.98 61.72,104.98 60.98,105.72 60.98,106.05 61.62,106.68 61.62,106.88 61.48,107.02 61.28,107.02 60.58,106.32 60.38,106.32 60.24,106.46 60.24,106.66 60.94,107.36 60.94,107.56 60.83,107.67 60.66,107.67 59.87,106.88 59.72,106.88 57.17,109.43 54.23,109.43 53.62,108.82 48.49,108.82 47.09,110.22 39.8,110.22 39.5,110.52 34.26,110.52 33.19,111.59 32.72,111.59 32.21,112.1 28.27,112.1 28.16,112.2 28.16,112.6 28.06,112.7 27.84,112.7 27.73,112.6 27.73,112.2 27.62,112.1 27.4,112.1 27.29,112.2 27.29,112.6 27.18,112.7 26.96,112.7 26.85,112.6 26.85,112.21 26.74,112.1 26.57,112.1 26.46,112.21 26.46,112.6 26.35,112.71 26.14,112.71 26.03,112.6 26.03,112.21 25.92,112.1 24.73,112.1 v9(22.86,113.97)
  BOTTOM w0.173: U9.28 21.59,115.66 22.86,114.38 v9(22.86,113.97)
PRU1ETH0_TXCLK: length 38
  TOP w0.173: v2(15.67,116.13) 15.67,115.9 16.84,114.74 16.84,114.45 16.16,113.77 16.16,113.51 16.36,113.3 16.67,113.3 17.33,113.96 17.61,113.96 18.01,113.56 18.01,113.28 17.64,112.9 17.64,112.62 17.84,112.42 18.13,112.42 18.5,112.79 18.79,112.79 18.99,112.59 18.99,112.3 18.62,111.93 18.62,111.64 18.82,111.44 19.1,111.44 19.48,111.81 19.76,111.81 21.71,109.86 21.71,109.58 21.4,109.27 21.4,108.98 21.61,108.78 21.89,108.78 22.2,109.09 22.49,109.09 22.92,108.66 25.05,108.66 27.01,106.7 34.71,106.7 R79.1
  BOTTOM w0.173: v2(15.67,116.13) 16.03,116.49 16.46,116.49 17.42,117.45 U9.2
PRU1ETH0_TXD0: length 37.3
  TOP w0.173: v2(16.11,118.33) 15.04,119.41 13.24,119.41 12.74,118.91 12.74,118.01 13.19,117.56 13.64,117.56 13.85,117.76 13.85,118.36 14.05,118.56 14.33,118.56 14.54,118.36 14.54,117.76 14.74,117.56 16.3,117.56 22.84,111.01 25.16,111.01 28.05,108.12 33.34,108.12 R81.1
  BOTTOM w0.173: v2(16.11,118.33) 16.51,117.94 17.14,117.94 17.66,118.45 U9.4
PRU1ETH0_TXD1: length 37
  TOP w0.173: v2(16.76,118.95) 17.2,118.51 17.2,117.66 17.61,117.24 18.54,117.24 18.76,117.03 18.76,116.74 18.59,116.57 18.59,116.29 18.79,116.09 19.08,116.09 19.24,116.25 19.53,116.25 19.73,116.05 19.73,115.76 19.57,115.6 19.57,115.31 19.77,115.11 20.06,115.11 20.22,115.27 20.51,115.27 20.71,115.07 20.71,114.78 20.55,114.62 20.55,114.33 20.75,114.13 21.03,114.13 21.2,114.3 21.49,114.3 22.43,113.35 22.98,113.35 23.18,113.15 23.18,111.96 23.4,111.75 23.68,111.75 23.87,111.94 23.87,113.15 24.07,113.35 25.23,113.35 25.51,113.07 25.51,112.78 24.96,112.23 24.96,111.93 25.16,111.73 25.44,111.73 25.99,112.28 26.28,112.28 26.48,112.08 26.48,111.79 26.1,111.42 26.1,111.08 26.3,110.88 26.54,110.88 26.98,111.32 27.26,111.32 27.68,110.9 27.68,110.61 27.29,110.22 27.29,109.94 27.49,109.73 27.78,109.73 28.59,110.54 28.97,110.54 29.3,110.21 29.3,109.92 28.72,109.34 28.72,109.03 28.92,108.83 29.18,108.83 29.79,109.44 30.07,109.44 30.68,108.83 32.65,108.83 R84.1
  BOTTOM w0.173: U9.5 v2(16.76,118.95)
PRU1ETH0_TXD2: length 37.8
  TOP w0.173: v2(17.27,119.45) 16.58,120.14 16.58,120.48 15.67,121.39 15.3,121.39 15.1,121.59 15.1,121.87 15.3,122.08 15.67,122.08 15.88,122.28 15.88,125 15.49,125.38 15.49,126.29 15.77,126.57 17.97,126.57 19.02,125.51 19.45,125.08 19.45,124.26 20.7,123.02 20.7,121.5 19.38,120.18 19.38,119.21 23.83,114.76 26.44,114.76 27.71,113.49 27.71,112.86 28.61,111.97 29.54,111.97 R85.1
  BOTTOM w0.173: U9.6 v2(17.27,119.45)
PRU1ETH0_TXD3: length 39.1
  TOP w0.173: v2(15.88,119.95) 15.61,120.22 13.05,120.22 12.03,119.2 12.03,118.62 12.03,117.72 12.9,116.85 16.01,116.85 22.55,110.31 24.87,110.31 27.76,107.42 33.83,107.42 34.44,108.03 34.65,108.03 R82.1
  BOTTOM w0.173: U9.7 v2(15.88,119.95)
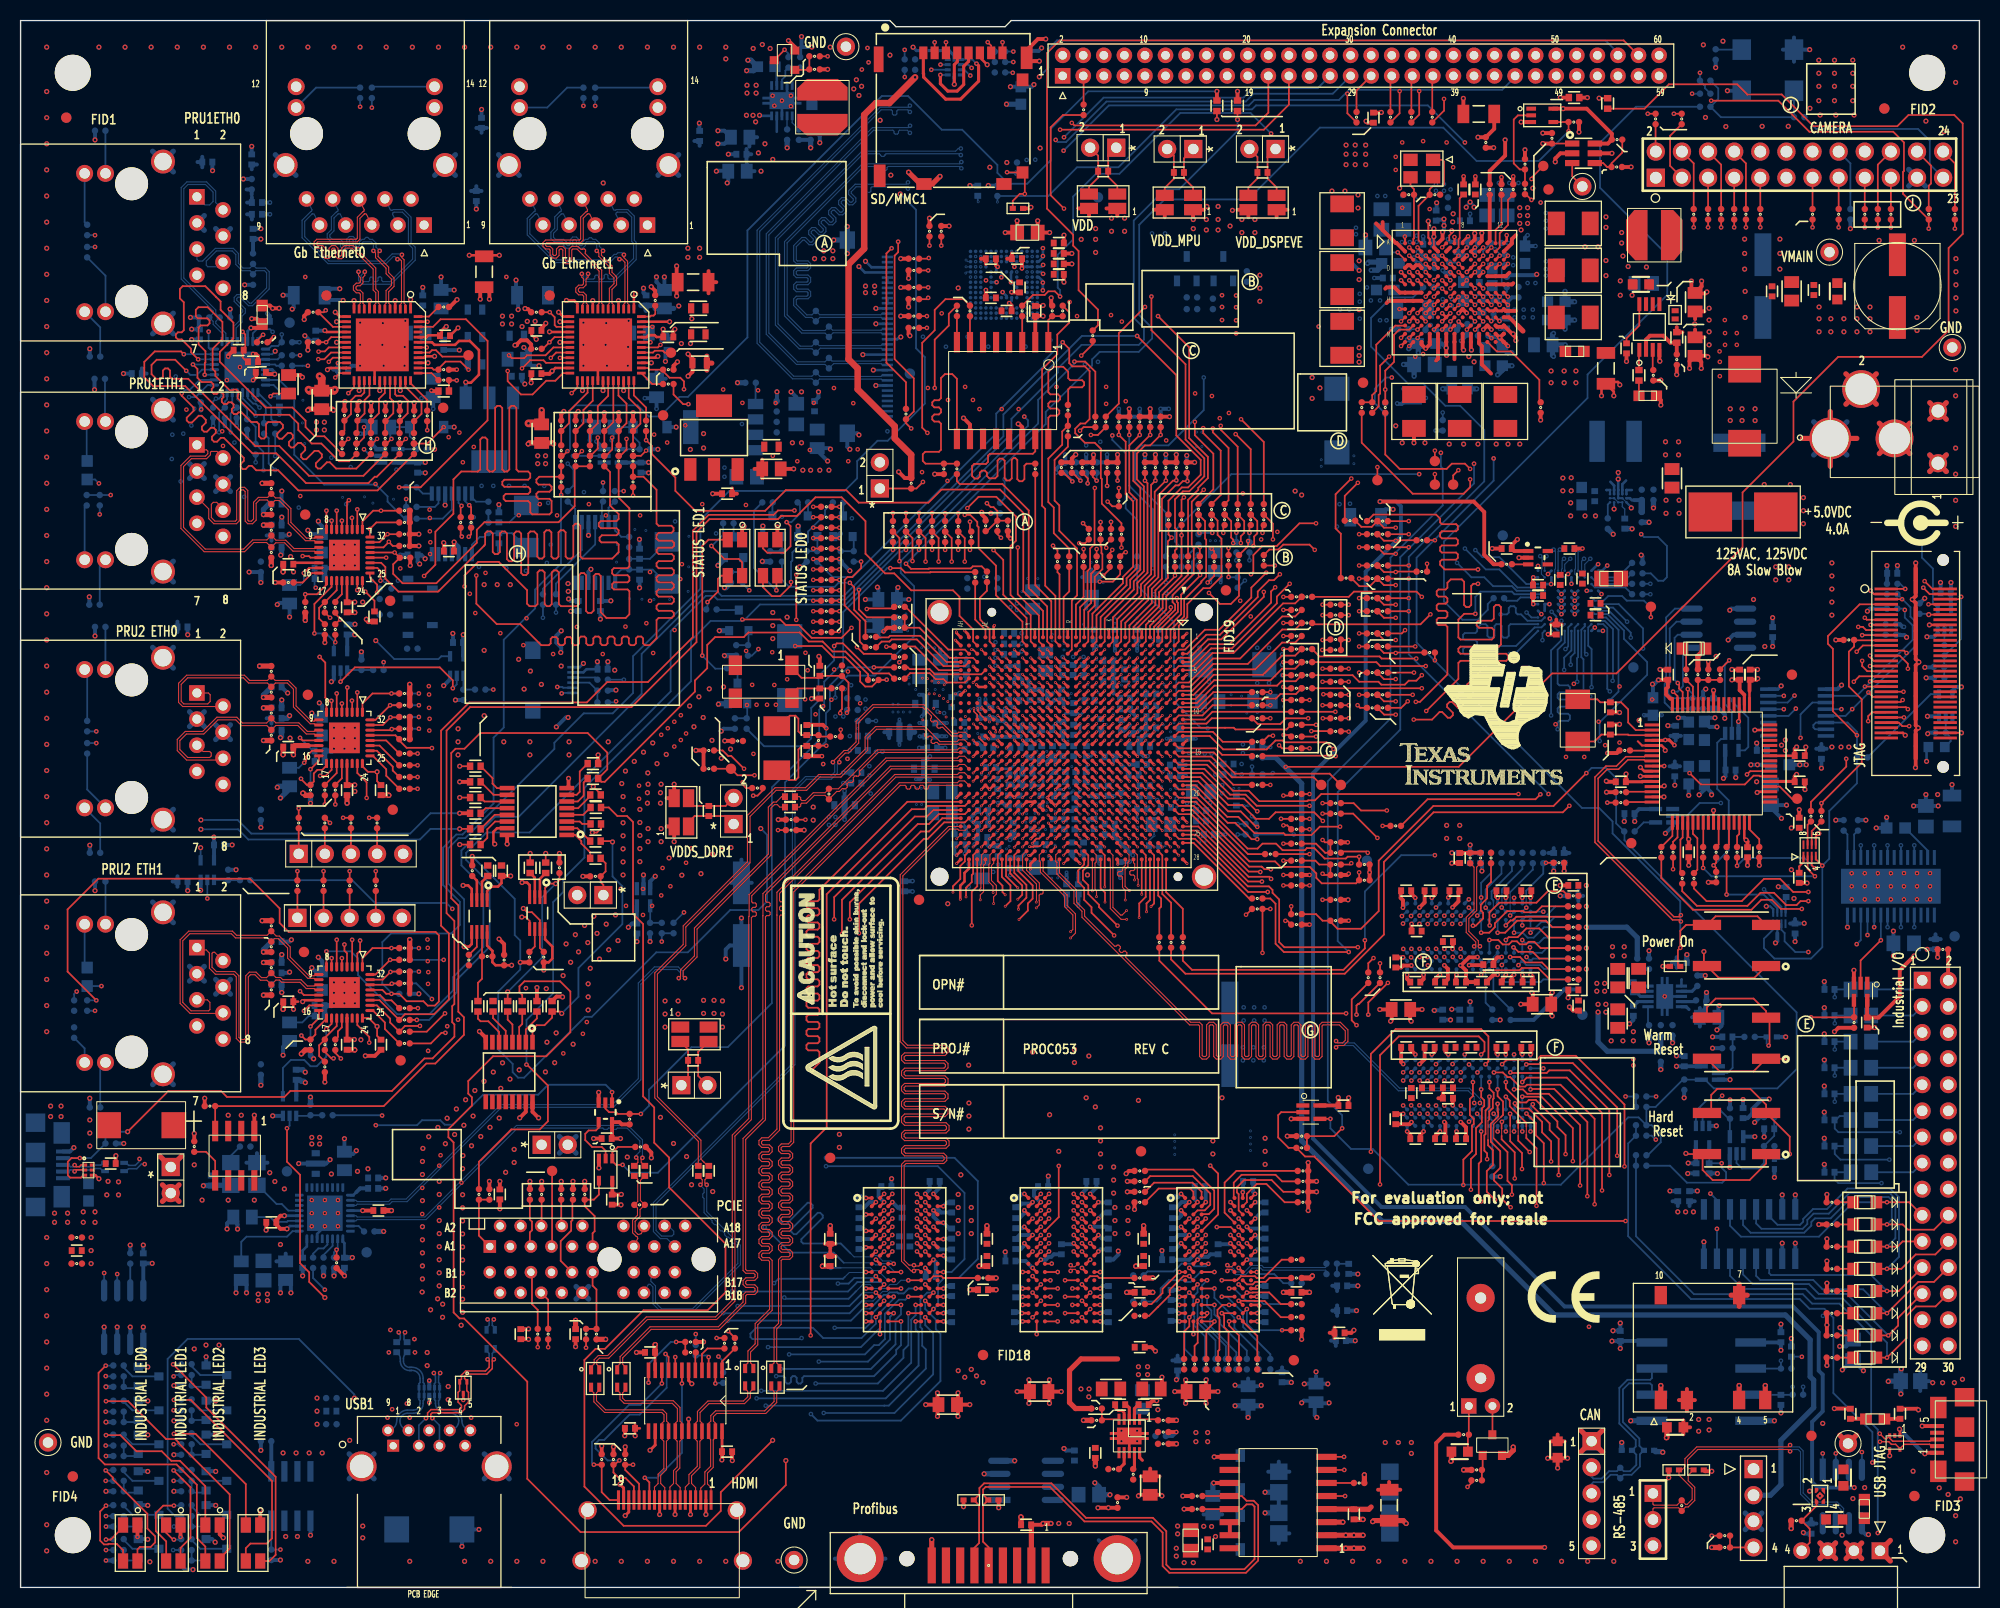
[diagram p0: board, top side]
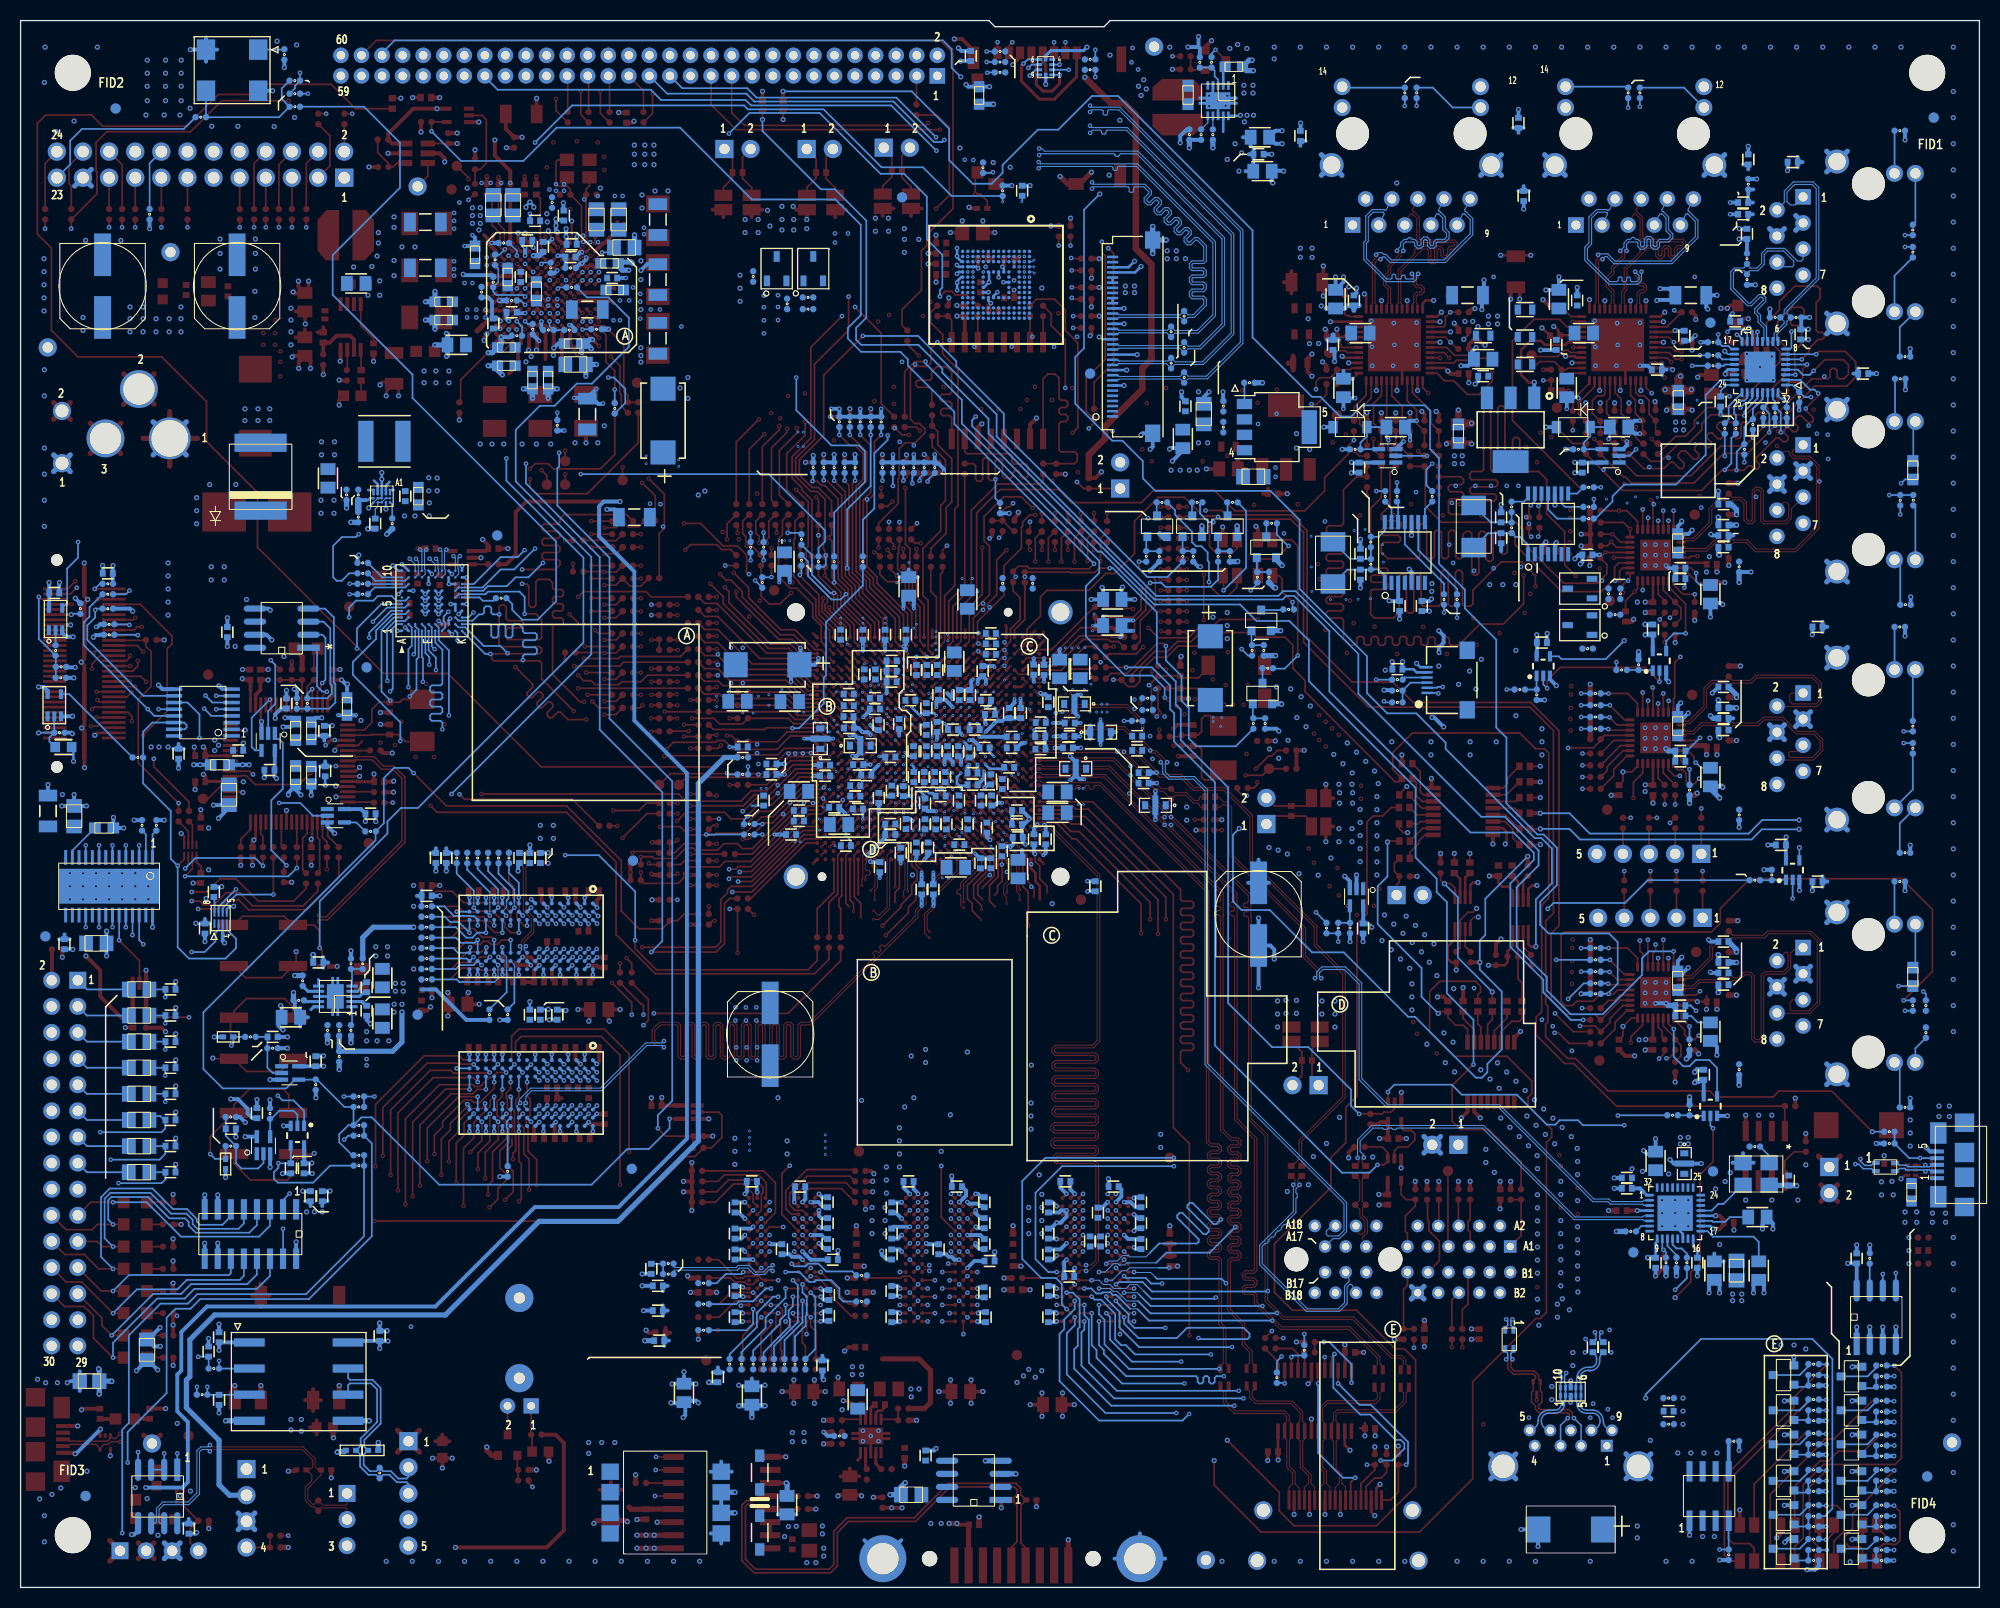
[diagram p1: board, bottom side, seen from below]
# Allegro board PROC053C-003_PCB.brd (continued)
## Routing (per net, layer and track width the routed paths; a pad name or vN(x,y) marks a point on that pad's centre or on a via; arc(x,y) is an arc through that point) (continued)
PRU1ETH0_TXEN: length 36.9
  TOP w0.173: v2(17.91,117.95) 17.92,117.96 17.92,119.09 17.98,119.16 17.98,120.24 17.31,120.91 17.31,122.54 17.51,122.75 18.18,122.75 18.38,122.95 18.38,123.23 18.18,123.44 17.25,123.44 17.04,123.64 17.04,124.27 17.3,124.52 18.2,124.52 19.63,123.09 19.63,121.42 18.68,120.47 18.68,118.52 18.95,118.25 18.95,117.83 20.34,116.44 20.62,116.44 20.69,116.51 20.98,116.51 21.18,116.31 21.18,116.02 21.11,115.95 21.11,115.67 22.72,114.06 26.15,114.06 27.01,113.2 27.01,112.57 28.32,111.26 29.25,111.26 30.98,109.53 31.96,109.53 R80.1
  BOTTOM w0.173: U9.3 v2(17.91,117.95)
PRU1ETH1_25MHZCLK: length 12.5
  TOP w0.173: U13.23 v2(32.75,97)
  L4_SIG2 w0.114: v2(37.5,105.86) 37.5,101.75 v2(32.75,97)
  BOTTOM w0.173: R313.2 v2(37.5,105.86)
PRU1ETH1_COL: length 68.5
  TOP w0.173: R148.1 R150.1 53.89,108.96 53.89,105.18 52.32,103.61 45.11,103.61 44.37,102.87 44.37,101.61 40.43,97.67 37.15,97.67 36.24,98.59 36.24,99.51 R152.1 v7(36.38,100.66) U13.29
  L3_SIG1 w0.109: v7(36.38,100.66) v5(35.94,101.1)
  L4_SIG2 w0.114: v2(8.76,106.25) 10.67,106.25 20.8,96.12 30.04,96.12 35.01,101.1 v5(35.94,101.1)
  BOTTOM w0.173: R151.2 R956.1 v2(8.76,106.25)
PRU1ETH1_CRS: length 80.8
  TOP w0.173: R139.1 57.33,108.49 57.33,105.24 58.16,104.4 58.16,103.92 57.96,103.72 56.43,103.72 56.23,103.52 56.23,103.23 56.43,103.03 57.96,103.03 58.16,102.83 58.16,102.54 57.96,102.34 56.54,102.34 56.31,102.11 56.31,101.82 56.48,101.65 57.96,101.65 58.16,101.44 58.16,100.69 57.54,100.07 54.65,100.07 54.44,100.27 54.44,103.26 54.24,103.46 53.96,103.46 53.75,103.26 53.75,100.27 53.55,100.07 53.21,100.07 53.01,100.27 53.01,102.62 52.8,102.82 52.52,102.82 52.32,102.62 52.32,100.27 52.11,100.07 51.83,100.07 51.62,100.27 51.62,102.62 51.42,102.82 51.14,102.82 50.93,102.62 50.93,100.27 50.73,100.07 50.45,100.07 50.24,100.27 50.24,102.41 49.95,102.71 49.58,102.71 49.37,102.5 49.37,98.68 49.17,98.47 48.88,98.47 48.68,98.67 48.68,102.5 48.48,102.71 48.2,102.71 47.99,102.5 47.99,100.02 47.79,99.81 47.5,99.81 47.3,100.01 47.3,102.5 47.1,102.71 46.81,102.71 46.61,102.5 46.61,100.72 46.41,100.51 46.12,100.51 45.92,100.72 45.92,102.5 45.72,102.71 45.38,102.71 45.18,102.5 45.18,101.44 45.08,101.34 45.08,101.32 40.72,96.97 40.71,96.97 40.59,96.86 36.75,96.86 35.48,98.13 35.48,99.25 35.07,99.66 U13.27
PRU1ETH1_INTN: length 157
  TOP w0.173: v2(109.98,125.56) 109.98,122.29 113.29,118.97 113.29,111.64 115.12,109.82 115.12,108.07 113.65,106.61 113.04,106.61 112.27,105.83 112.27,103.05 112.42,102.9 112.42,101.02 112.27,100.86 R670.2 ; U13.8 v2(29.75,104.73)
  L3_SIG1 w0.109: v2(27.69,127.46) 28.22,126.93 38.13,126.93 39.51,128.31 46.9,128.31 47.22,128.63 59.52,128.63 62.65,131.76 62.65,132.3 63.81,133.46 87.32,133.46 88.16,132.62 88.62,132.62 89.16,133.15 95.9,133.15 96.69,132.37 99.15,132.37 99.4,132.61 102.49,132.61 103.91,131.2 103.91,129.76 104.97,128.71 106.83,128.71 v2(109.98,125.56)
  L4_SIG2 w0.114: v2(27.69,127.46) 24.57,127.46 18.72,121.62 18.72,114.08 21.18,111.61 21.18,108.18 24.64,104.73 v2(29.75,104.73)
PRU1ETH1_LINKLED: length 29.5
  TOP w0.173: R131.1 v2(27.69,96.6) 28.83,96.6 29.75,97.52 U13.17
  L4_SIG2 w0.114: v2(27.69,96.6) 21.46,96.6 10.68,107.38 v2(7.62,107.38)
  BOTTOM w0.173: R138.2 7.24,107.77 v2(7.62,107.38)
PRU1ETH1_MDC: length 2.4
  TOP w0.173: R140.1 30.61,95.97 31.25,96.61 U13.20
PRU1ETH1_MDIO: length 5.2
  TOP w0.173: R120.1 29.03,94.24 29.03,95.28 29.59,95.83 R142.1 30.75,96.99 U13.19
PRU1ETH1_RESETN: length 9
  TOP w0.173: U13.18 30.25,97.33 28.58,95.66 v2(28.58,92.79)
  BOTTOM w0.173: U69.4 30.47,92.04 29.72,92.79 v2(28.58,92.79)
PRU1ETH1_RXCLK: length 176.6
  TOP w0.173: U13.25 33.97,98.24 34.67,97.54 v7(34.67,96.77) ; v2(118.24,102.6) 118.24,103.21 R129.1
  L3_SIG1 w0.109: v2(118.24,102.6) 117.25,103.58 116.64,103.58 114.16,106.06 114.16,106.29 113.01,107.44 113.01,107.72 112.61,108.13 109.4,108.13 106.86,110.67 98.37,110.67 96.16,112.88 91.26,112.88 89.99,114.15 84.66,114.15 84.18,113.67 70.13,113.67 64.38,107.92 60.89,107.92 60.01,108.8 51.79,108.8 51.45,108.46 49.86,108.46 47.42,110.9 47.42,111.92 47.08,112.26 47.08,112.41 47.26,112.59 47.26,112.74 47.1,112.9 46.95,112.9 46.77,112.72 46.62,112.72 46.46,112.88 46.46,113.03 46.64,113.21 46.64,113.36 46.48,113.52 46.33,113.52 46.15,113.34 46,113.34 45.84,113.5 45.84,113.65 46.02,113.83 46.02,113.98 45.86,114.13 45.71,114.13 45.53,113.96 45.38,113.96 45.23,114.11 45.23,114.27 45.4,114.44 45.4,114.6 45.25,114.75 45.09,114.75 44.92,114.58 44.76,114.58 44.61,114.73 44.61,114.89 44.78,115.06 44.78,115.22 44.63,115.37 44.47,115.37 44.3,115.2 44.14,115.2 43.99,115.35 43.99,115.5 44.16,115.68 44.16,115.83 44.01,115.99 43.86,115.99 43.68,115.81 43.53,115.81 43.25,116.09 41.38,116.09 40.2,117.27 39.54,117.27 39.42,117.15 39.42,117 39.31,116.89 39.14,116.89 39.03,117 39.03,117.15 38.91,117.27 38.75,117.27 38.63,117.15 38.63,117 38.51,116.89 38.35,116.89 38.23,117 38.23,117.15 38.12,117.27 37.95,117.27 37.84,117.15 37.84,117 37.72,116.89 37.56,116.89 37.44,117 37.44,117.15 37.33,117.27 37.16,117.27 37.05,117.15 37.05,117 36.93,116.89 36.76,116.89 36.65,117 36.65,117.15 36.53,117.27 36.37,117.27 36.25,117.15 36.25,116.6 36.14,116.48 35.97,116.48 35.86,116.6 35.86,117.15 35.74,117.27 35.58,117.27 35.46,117.15 35.46,117 35.34,116.89 35.18,116.89 35.06,117 35.06,117.15 34.95,117.27 34.78,117.27 34.67,117.15 34.67,117 34.55,116.89 34.39,116.89 34.27,117 34.27,117.15 34.16,117.27 33.99,117.27 33.88,117.15 33.88,116.62 33.76,116.51 33.6,116.51 33.48,116.62 33.48,117.15 33.36,117.27 33.2,117.27 33.08,117.15 33.08,117 32.97,116.89 32.8,116.89 32.69,117 32.69,117.15 32.57,117.27 32.17,117.27 31.42,116.52 31.42,116.11 30.99,115.68 30.47,115.68 30.36,115.57 30.36,115.14 30.24,115.03 30.08,115.03 29.96,115.14 29.96,115.56 29.85,115.68 29.68,115.68 29.57,115.56 29.57,114.94 29.45,114.82 29.29,114.82 29.17,114.94 29.17,115.56 29.06,115.68 28.89,115.68 28.78,115.56 28.78,114.94 28.66,114.82 28.49,114.82 28.38,114.94 28.38,115.56 28.26,115.68 28.1,115.68 27.98,115.56 27.98,115.14 27.87,115.03 27.7,115.03 27.59,115.14 27.59,115.54 27.44,115.68 27.12,115.68 26.79,115.35 26.79,115.11 26.68,114.99 26.32,114.99 26.2,114.88 26.2,114.71 26.32,114.6 26.68,114.6 26.79,114.48 26.79,113.95 26.68,113.83 25.25,113.83 25.14,113.72 25.14,113.55 25.25,113.44 26.75,113.44 26.87,113.31 26.87,113.15 26.77,113.04 25.25,113.04 25.14,112.92 25.14,112.76 25.25,112.64 26.68,112.64 26.79,112.53 26.79,112.36 26.68,112.25 25.25,112.25 25.14,112.13 25.14,111.97 25.25,111.85 26.55,111.85 26.67,111.73 26.67,111.57 26.55,111.45 25.25,111.45 25.14,111.34 25.14,111.17 25.25,111.06 26.55,111.06 26.67,110.94 26.67,110.78 26.55,110.66 25.25,110.66 25.14,110.55 25.14,110.38 25.25,110.27 26.55,110.27 26.67,110.15 26.67,109.99 26.55,109.87 25.25,109.87 25.14,109.75 25.14,109.59 25.25,109.47 26.55,109.47 26.67,109.36 26.67,109.19 26.55,109.08 25.25,109.08 25.14,108.96 25.14,108.8 25.25,108.68 26.55,108.68 26.67,108.56 26.67,108.4 26.55,108.28 25.25,108.28 25.14,108.17 25.14,108 25.25,107.89 26.55,107.89 26.67,107.77 26.67,107.42 26.55,107.3 26.08,107.3 25.96,107.19 25.96,107.02 26.08,106.91 26.65,106.91 26.77,106.79 26.77,106.63 26.65,106.51 26.08,106.51 25.96,106.39 25.96,106.23 26.08,106.11 26.68,106.11 26.79,106 26.79,105.65 27.28,105.16 27.7,105.16 27.81,105.05 27.81,104.69 27.93,104.58 28.09,104.58 28.21,104.69 28.21,105.05 28.32,105.16 28.49,105.16 28.6,105.05 28.6,104.69 28.72,104.58 29.16,104.58 29.49,104.25 31.39,104.25 32.05,103.59 34.08,103.59 34.54,103.12 34.54,101.67 34.25,101.38 34.25,97.96 34.67,97.54 v7(34.67,96.77)
  BOTTOM w0.173: R750.2 v2(118.24,102.6)
PRU1ETH1_RXD0: length 82.8
  TOP w0.173: v7(43.18,97.36) 43.18,98.42 44.5,99.75 46.51,99.75 49.25,97 49.25,95.68 49.49,95.44 50.07,95.44 50.27,95.65 50.27,98.72 50.48,98.92 50.76,98.92 50.97,98.72 50.97,95.65 51.17,95.44 51.45,95.44 51.66,95.65 51.66,98.72 51.86,98.92 52.14,98.92 52.35,98.72 52.35,95.65 52.55,95.44 54.1,95.44 54.31,95.65 54.31,98.45 54.51,98.66 54.79,98.66 55,98.45 55,94.98 55.19,94.78 55.51,94.78 55.73,95.01 55.73,98.38 55.93,98.58 56.22,98.58 56.42,98.38 56.42,94.85 56.98,94.29 58.84,94.29 59.21,94.66 59.21,96.9 59.03,97.07 57.7,97.07 57.53,97.24 57.53,97.59 57.7,97.76 59.03,97.76 59.21,97.93 59.21,98.28 59.03,98.45 57.7,98.45 57.53,98.62 57.53,98.97 57.7,99.14 59.03,99.14 59.21,99.31 59.21,104.96 58.17,106 R133.1 ; U13.30 35.29,101.16 35.81,101.68 ; 35.81,101.68 36.2,101.3 R158.2 ; 35.81,101.68 v7(35.81,101.71)
  L3_SIG1 w0.109: v7(43.18,97.36) 41.91,97.36 40.3,98.98 38.95,98.98 38.53,98.56 36.87,98.56 36.35,99.08 36.35,99.85 36.81,100.32 36.81,101.34 36.45,101.71 v7(35.81,101.71)
PRU1ETH1_RXD1: length 83
  TOP w0.173: R135.1 R752.2 60.58,108.03 61.85,106.76 61.85,103.47 62.05,103.27 63.29,103.27 63.5,103.06 63.5,102.77 63.31,102.57 62.05,102.57 61.85,102.37 61.85,102.02 62.05,101.82 63.34,101.82 63.56,101.6 63.56,101.32 63.37,101.13 62.05,101.13 61.85,100.92 61.85,100.72 62.05,100.51 63.33,100.51 63.53,100.31 63.53,100.03 63.33,99.82 62.05,99.82 61.85,99.62 61.85,99.34 62.05,99.13 63.33,99.13 63.53,98.93 63.53,98.64 63.33,98.44 62.05,98.44 61.85,98.24 61.85,97.95 62.05,97.75 63.33,97.75 63.53,97.55 63.53,97.26 63.33,97.06 62.05,97.06 61.85,96.86 61.85,96.57 62.05,96.37 63.33,96.37 63.53,96.17 63.53,95.88 63.33,95.68 62.05,95.68 61.85,95.48 61.85,95.19 62.05,94.99 63.33,94.99 63.53,94.79 63.53,94.5 63.33,94.3 62.05,94.3 61.85,94.09 61.85,92.32 61.18,91.65 60.71,91.65 60.54,91.82 60.54,92.31 60.36,92.49 60.02,92.49 59.85,92.31 59.85,91.82 59.67,91.65 59.33,91.65 59.16,91.82 59.16,92.31 58.98,92.49 58.64,92.49 58.46,92.31 58.46,91.82 58.29,91.65 57.95,91.65 57.77,91.82 57.77,92.31 57.6,92.49 57.26,92.49 57.08,92.31 57.08,91.82 56.91,91.65 56.56,91.65 56.39,91.82 56.39,92.31 56.22,92.49 55.87,92.49 55.7,92.31 55.7,91.82 55.53,91.65 55.18,91.65 55.01,91.82 55.01,92.31 54.84,92.49 54.49,92.49 54.32,92.31 54.32,91.82 54.15,91.65 53.8,91.65 53.63,91.82 53.63,92.26 53.46,92.44 53.11,92.44 52.94,92.26 52.94,91.82 52.76,91.65 52.42,91.65 52.25,91.82 52.25,92.26 52.07,92.44 51.73,92.44 51.56,92.26 51.56,91.82 51.38,91.65 50.64,91.65 48.58,93.7 46.3,93.7 44.32,95.68 v7(44.32,98.42) ; U13.31 34.9,101.66 v7(35.69,102.44) R157.2
  L3_SIG1 w0.109: v7(44.32,98.42) 43.25,99.5 41.62,99.5 40.12,101 39.42,101 39.24,100.82 38.05,100.82 36.42,102.44 v7(35.69,102.44)
PRU1ETH1_RXD2: length 176
  TOP w0.173: R136.1 120.78,103.21 v7(120.78,102.57) ; U13.32 v7(33.97,102.95) 34.61,103.59 R156.2
  L3_SIG1 w0.109: v7(33.97,102.95) 32.91,101.89 29.86,101.89 29.7,101.73 24.74,101.73 24.62,101.84 24.62,102.24 24.5,102.36 24.34,102.36 24.22,102.24 24.22,101.84 24.11,101.73 23.94,101.73 23.83,101.84 23.83,102.32 23.71,102.43 23.55,102.43 23.43,102.32 23.43,101.84 23.32,101.73 22.83,101.73 22.37,102.18 22.37,102.83 22.26,102.94 20.99,102.94 20.87,103.06 20.87,103.22 20.99,103.34 22.26,103.34 22.37,103.46 22.37,103.62 22.26,103.74 20.99,103.74 20.87,103.85 20.87,104.02 20.99,104.13 22.26,104.13 22.37,104.25 22.37,104.41 22.26,104.53 20.99,104.53 20.87,104.64 20.87,104.81 20.99,104.92 22.26,104.92 22.37,105.04 22.37,105.21 22.26,105.32 20.99,105.32 20.87,105.44 20.87,105.6 20.99,105.72 22.26,105.72 22.37,105.83 22.37,106 22.26,106.11 20.99,106.11 20.87,106.23 20.87,106.39 20.99,106.51 22.26,106.51 22.37,106.63 22.37,106.79 22.26,106.91 20.99,106.91 20.87,107.02 20.87,107.19 20.99,107.3 22.26,107.3 22.37,107.42 22.37,107.85 22.88,108.36 22.88,110.74 22.77,110.85 21.52,110.85 21.41,110.96 21.41,111.18 21.52,111.29 22.77,111.29 22.88,111.4 22.88,111.61 22.77,111.72 21.52,111.72 21.41,111.83 21.41,112.05 21.52,112.16 22.77,112.16 22.88,112.27 22.88,112.49 22.77,112.6 21.52,112.6 21.41,112.71 21.41,112.92 21.52,113.03 22.77,113.03 22.88,113.14 22.88,113.36 22.77,113.47 21.52,113.47 21.41,113.58 21.41,113.8 21.52,113.91 22.77,113.91 22.88,114.02 22.88,114.23 22.77,114.34 21.52,114.34 21.41,114.45 21.41,114.67 21.52,114.78 22.77,114.78 22.88,114.89 22.88,115.11 22.77,115.22 21.67,115.22 21.56,115.33 21.56,115.55 21.67,115.65 22.77,115.65 24.29,117.18 30.76,117.18 31.65,118.06 40.82,118.06 41.02,117.86 43.48,117.86 48.77,112.58 48.77,111.1 49.33,110.55 51.66,110.55 52.63,109.58 60.48,109.58 60.83,109.94 63.63,109.94 65.45,111.76 66.91,111.76 69.89,114.74 83.65,114.74 83.86,114.95 91.83,114.95 93.04,113.75 97.1,113.75 99.31,111.54 107.14,111.54 109.73,108.95 113.26,108.95 113.69,108.51 115.34,108.51 120.78,103.08 v7(120.78,102.57)
PRU1ETH1_RXD3: length 184.6
  TOP w0.173: R137.1 115.82,102.64 v2(115.89,102.57) ; R155.2 v7(35.05,104.73) 34.29,104.73 33.25,103.69 U13.1
  L3_SIG1 w0.109: v7(35.05,104.73) 37.9,101.88 39.22,101.88 39.45,102.11 41.35,102.11 41.68,101.79 41.68,100.73 42.03,100.37 42.31,100.37 42.56,100.62 42.56,101.23 42.67,101.35 42.84,101.35 42.95,101.23 42.95,100.08 43.09,99.94 43.24,99.94 43.35,100.05 43.35,101.23 43.47,101.35 43.63,101.35 43.75,101.23 43.75,100.05 43.88,99.92 44.03,99.92 44.14,100.03 44.14,100.92 44.26,101.03 44.42,101.03 44.54,100.92 44.54,99.94 44.65,99.83 44.85,99.83 44.98,99.95 44.98,100.29 45.09,100.41 45.26,100.41 45.37,100.29 45.37,99.94 45.48,99.83 45.65,99.83 45.77,99.95 45.77,100.29 45.88,100.41 46.05,100.41 46.17,100.29 46.17,99.94 46.27,99.83 46.44,99.83 46.56,99.95 46.56,100.29 46.68,100.41 46.84,100.41 46.96,100.29 46.96,99.94 47.07,99.83 47.25,99.83 47.37,99.95 47.37,100.31 47.49,100.43 47.65,100.43 47.77,100.31 47.77,99.94 47.88,99.83 48.04,99.83 48.16,99.95 48.16,100.31 48.28,100.43 48.44,100.43 48.56,100.31 48.56,99.94 48.67,99.83 48.79,99.83 48.92,99.95 48.92,100.2 49.03,100.32 49.2,100.32 49.31,100.2 49.31,100.02 49.43,99.9 49.57,99.9 49.79,100.12 49.79,100.6 49.62,100.77 45.09,100.77 44.12,101.73 42.77,101.73 42.43,102.07 42.43,102.68 42.31,102.8 41.86,102.8 41.74,102.91 41.74,103.08 41.86,103.19 42.31,103.19 42.43,103.31 42.43,103.48 42.33,103.59 41.58,103.59 41.47,103.47 41.47,102.54 41.35,102.42 41.19,102.42 41.07,102.54 41.07,104.73 40.95,104.85 40.79,104.85 40.68,104.74 40.68,102.54 40.56,102.42 40.4,102.42 40.28,102.54 40.28,103.45 40.16,103.56 39.75,103.56 39.64,103.45 39.64,103.19 39.52,103.08 39.36,103.08 39.24,103.19 39.24,103.97 39.12,104.1 38.95,104.1 38.84,103.99 38.84,103.19 38.73,103.08 38.56,103.08 38.45,103.19 38.45,103.47 38.33,103.59 38.04,103.59 35.78,105.85 34.95,105.85 34.83,105.96 34.83,106.75 34.72,106.87 34.55,106.87 34.44,106.75 34.44,105.66 34.32,105.54 33.96,105.54 33.85,105.66 33.85,107.69 33.73,107.81 33.57,107.81 33.45,107.69 33.45,105.64 33.34,105.53 33.05,105.53 32.93,105.65 32.93,108.15 32.81,108.27 32.65,108.27 32.53,108.15 32.53,105.7 32.09,105.26 31.65,105.26 30.86,106.05 30.86,112.5 32.91,114.54 42.51,114.54 45.57,111.48 45.57,111.28 49.3,107.55 53.09,107.55 53.67,106.96 54.2,106.96 54.31,107.07 54.31,107.39 54.42,107.5 54.63,107.5 54.74,107.39 54.74,107.07 54.85,106.96 58.16,106.96 58.31,107.11 60.28,107.11 60.73,106.66 64.41,106.66 70.46,112.7 84.58,112.7 85.12,113.24 89.59,113.24 90.86,111.97 95.84,111.97 98.6,109.2 106.4,109.2 109.15,106.45 112.02,106.45 v2(115.89,102.57)
  BOTTOM w0.173: R751.2 114.68,102.57 v2(115.89,102.57)
PRU1ETH1_RXDV: length 177.5
  TOP w0.173: R130.1 116.97,103.21 v7(116.97,102.57) ; v7(35,97.92) 35,98.86 34.7,99.16 U13.26
  L3_SIG1 w0.109: v7(35,97.92) 35.02,97.93 35.02,104.07 34.79,104.3 33.83,104.3 33.72,104.41 33.72,104.8 33.6,104.92 33.44,104.92 33.32,104.8 33.32,104.41 33.18,104.27 32.61,104.27 32.11,104.78 31.42,104.78 30.37,105.83 30.37,106.68 30.25,106.79 29.74,106.79 29.62,106.68 29.62,105.72 29.51,105.61 29.34,105.61 29.23,105.72 29.23,106.68 29.11,106.79 28.95,106.79 28.83,106.68 28.83,105.72 28.71,105.61 28.55,105.61 28.43,105.72 28.43,106.68 28.32,106.79 28.15,106.79 28.04,106.68 28.04,105.72 27.92,105.61 27.76,105.61 27.64,105.72 27.64,106.68 27.53,106.79 27.32,106.79 27.21,106.91 27.21,107.07 27.32,107.19 30.25,107.19 30.37,107.3 30.37,107.47 30.25,107.58 27.32,107.58 27.21,107.7 27.21,107.86 27.32,107.98 30.25,107.98 30.37,108.1 30.37,108.26 30.25,108.38 27.32,108.38 27.21,108.49 27.21,108.66 27.32,108.77 30.25,108.77 30.37,108.89 30.37,109.05 30.25,109.17 27.32,109.17 27.21,109.29 27.21,109.45 27.32,109.57 30.25,109.57 30.37,109.68 30.37,109.85 30.25,109.96 27.32,109.96 27.21,110.08 27.21,110.24 27.32,110.36 30.25,110.36 30.37,110.47 30.37,110.64 30.25,110.75 27.32,110.75 27.21,110.87 27.21,111.03 27.32,111.15 30.25,111.15 30.37,111.27 30.37,111.43 30.25,111.55 27.32,111.55 27.21,111.66 27.21,111.83 27.32,111.94 30.25,111.94 30.37,112.06 30.37,113.45 32.83,115.92 38.8,115.92 39.22,115.5 39.51,115.5 39.63,115.39 39.63,115.11 39.75,115 39.91,115 40.03,115.11 40.03,115.41 40.14,115.53 40.31,115.53 40.42,115.41 40.42,115.11 40.54,115 40.7,115 40.82,115.11 40.82,115.41 40.94,115.53 41.1,115.53 41.22,115.41 41.22,115.11 41.33,115 41.5,115 41.61,115.11 41.61,115.39 41.73,115.5 42.31,115.5 42.52,115.3 42.67,115.3 42.85,115.47 43,115.47 43.16,115.32 43.16,115.17 42.98,114.99 42.98,114.84 43.13,114.68 43.29,114.68 43.46,114.86 43.62,114.86 43.77,114.7 43.77,114.55 43.6,114.37 43.6,114.22 43.75,114.06 43.91,114.06 44.08,114.24 44.24,114.24 44.39,114.08 44.39,113.93 44.22,113.75 44.22,113.6 44.37,113.44 44.53,113.44 44.7,113.62 44.86,113.62 45.01,113.46 45.01,113.31 44.83,113.13 44.83,112.98 44.99,112.83 45.14,112.83 45.32,113 45.47,113 45.63,112.85 45.63,112.69 45.45,112.52 45.45,112.36 45.61,112.21 45.76,112.21 45.94,112.38 46.09,112.38 46.25,112.23 46.25,112.07 46.07,111.9 46.07,111.74 46.23,111.59 46.38,111.59 46.56,111.76 46.71,111.76 46.86,111.61 46.86,111.46 46.69,111.28 46.69,111.13 46.85,110.97 46.85,110.69 49.53,108.01 60.02,108.01 60.63,107.4 64.52,107.4 70.28,113.16 84.3,113.16 84.84,113.7 89.79,113.7 91.06,112.43 96,112.43 98.74,109.68 106.55,109.68 109.02,107.21 112.6,107.21 113.71,106.11 113.71,105.83 v7(116.97,102.57)
PRU1ETH1_RXERR: length 82.1
  TOP w0.173: U13.28 v7(35.56,100.16) ; v7(39.24,98.38) 40.34,99.47 40.34,102.68 42.09,104.43 42.09,107.77 42.86,108.54 44.5,108.54 44.7,108.74 44.7,111.65 44.91,111.85 45.19,111.85 45.39,111.65 45.39,108.74 45.6,108.54 45.95,108.54 46.15,108.74 46.15,114.72 46.35,114.92 46.64,114.92 46.84,114.72 46.84,108.74 47.04,108.54 47.33,108.54 47.53,108.74 47.53,114.72 47.73,114.92 48.02,114.92 48.22,114.72 48.22,108.74 48.42,108.54 49.36,108.54 49.57,108.34 49.57,107.94 49.36,107.74 47.05,107.74 46.85,107.54 46.85,107.25 47.05,107.05 49.36,107.05 49.57,106.85 49.57,106.56 49.36,106.36 47.18,106.36 46.98,106.16 46.98,105.87 47.18,105.67 49.36,105.67 49.57,105.47 49.57,104.57 49.77,104.37 51.44,104.37 51.64,104.57 51.64,105.68 51.44,105.88 50.37,105.88 50.16,106.09 50.16,106.37 50.37,106.58 51.44,106.58 51.64,106.78 51.64,107.06 51.44,107.27 50.37,107.27 50.16,107.47 50.16,107.75 50.44,108.03 R753.2 R132.1
  L3_SIG1 w0.109: v7(35.56,100.16) 35.56,99.13 36.58,98.1 38.96,98.1 v7(39.24,98.38)
PRU1ETH1_TXCLK: length 187.6
  TOP w0.173: U13.2 v2(32.75,104.86) ; R123.1 v7(114.68,101.17)
  L3_SIG1 w0.109: v5(109.47,105.49) 111.09,105.49 114.68,101.9 v7(114.68,101.17)
  L10_SIG4 w0.109: v2(32.75,104.86) 31.37,104.86 30.67,105.55 23.32,105.55 20.31,108.56 19.11,108.56 17.87,107.32 16.56,107.32 15.26,108.62 15.26,115.41 15.19,115.48 15.19,116.8 16.12,117.73 17.06,117.73 19.89,120.55 23.57,120.55 24.97,121.95 24.97,122.13 28.55,125.71 36.86,125.71 37.01,125.86 38.58,125.86 38.73,125.71 42.34,125.71 42.54,125.91 58.54,125.91 60.57,123.88 65.98,123.88 66.12,123.74 66.12,122.09 66.24,121.97 66.4,121.97 66.52,122.09 66.52,123.74 66.63,123.85 66.8,123.85 66.91,123.74 66.91,122.09 67.03,121.97 67.19,121.97 67.31,122.09 67.31,123.74 67.43,123.85 67.59,123.85 67.71,123.74 67.71,122.09 67.82,121.97 67.99,121.97 68.1,122.09 68.1,123.74 68.22,123.85 68.38,123.85 68.5,123.74 68.5,122.09 68.61,121.97 68.78,121.97 68.89,122.09 68.89,123.74 69.01,123.85 69.17,123.85 69.29,123.74 69.29,122.09 69.41,121.97 69.57,121.97 69.69,122.09 69.69,123.74 69.8,123.85 69.97,123.85 70.08,123.74 70.08,122.09 70.2,121.97 70.36,121.97 70.48,122.09 70.48,123.74 70.6,123.85 70.76,123.85 70.88,123.74 70.88,122.09 70.99,121.97 71.16,121.97 71.27,122.09 71.27,123.74 71.39,123.85 71.55,123.85 71.67,123.74 71.67,122.09 71.78,121.97 71.95,121.97 72.06,122.09 72.06,123.74 72.18,123.85 73.84,123.85 74,123.69 74,121.78 74.16,121.62 74.38,121.62 74.54,121.78 74.54,123.69 74.7,123.85 74.93,123.85 75.09,123.69 75.09,121.78 75.25,121.62 75.48,121.62 75.64,121.78 75.64,123.69 75.8,123.85 76.02,123.85 76.18,123.69 76.18,121.78 76.34,121.62 76.57,121.62 76.73,121.78 76.73,123.69 76.89,123.85 79.73,123.85 85.32,118.26 100.28,118.26 104.65,113.89 104.65,112.57 106.14,111.07 106.14,109.59 108.23,107.5 108.23,106.73 v5(109.47,105.49)
PRU1ETH1_TXD0: length 182.4
  TOP w0.173: R125.1 114.55,102.65 v7(114.64,102.56) ; U13.4 31.75,105.56 v7(31.93,105.75)
  L3_SIG1 w0.109: v7(114.64,102.56) 114.58,102.56 111.13,106.01 108.96,106.01 106.22,108.74 98.44,108.74 95.67,111.51 90.68,111.51 89.41,112.78 87.3,112.78 86.81,112.28 86.81,111.95 86.92,111.84 87.7,111.84 87.82,111.72 87.82,111.56 87.7,111.44 86.92,111.44 86.81,111.33 86.81,111.01 86.92,110.9 87.74,110.9 87.85,110.78 87.85,110.62 87.74,110.5 86.92,110.5 86.81,110.39 86.81,109.79 86.69,109.67 86.52,109.67 86.41,109.78 86.41,112.04 86.29,112.15 86.13,112.15 86.01,112.04 86.01,110.52 85.9,110.41 85.73,110.41 85.62,110.52 85.62,112.04 85.5,112.15 84.99,112.15 84.87,112.04 84.87,111.56 84.75,111.45 84.59,111.45 84.47,111.56 84.47,112.04 84.36,112.15 84.19,112.15 84.08,112.04 84.08,111.62 83.96,111.5 83.8,111.5 83.68,111.62 83.68,112.04 83.56,112.15 83.4,112.15 83.28,112.04 83.28,111.76 83.13,111.61 80.04,111.61 79.76,111.33 79.59,111.33 79.48,111.44 79.48,112.03 79.36,112.15 79.2,112.15 79.08,112.03 79.08,111.44 78.97,111.33 78.8,111.33 78.69,111.44 78.69,112.03 78.57,112.15 78.41,112.15 78.29,112.03 78.29,111.44 78.17,111.33 78.01,111.33 77.89,111.44 77.89,112.03 77.78,112.15 77.61,112.15 77.5,112.03 77.5,111.44 77.38,111.33 77.22,111.33 77.1,111.44 77.1,112.03 76.99,112.15 74.36,112.15 73.85,111.64 72.78,111.64 72.67,111.52 72.67,110.89 72.55,110.78 72.39,110.78 72.27,110.89 72.27,111.65 72.15,111.77 71.99,111.77 71.87,111.65 71.87,110.89 71.76,110.78 71.59,110.78 71.48,110.89 71.48,111.65 71.36,111.77 71.2,111.77 71.08,111.65 71.08,110.89 70.96,110.78 70.8,110.78 70.68,110.89 70.68,111.65 70.57,111.77 70.2,111.77 69.65,111.22 69.65,111.06 71.11,109.6 71.11,109.44 70.99,109.32 70.82,109.32 69.37,110.78 69.21,110.78 69.09,110.66 69.09,110.5 70.54,109.04 70.54,108.88 70.43,108.76 70.26,108.76 68.81,110.21 68.64,110.21 68.53,110.1 68.53,109.93 69.98,108.48 69.98,108.31 69.87,108.2 69.7,108.2 68.25,109.65 68.08,109.65 67.97,109.54 67.97,109.37 69.42,107.92 69.42,107.75 69.31,107.64 69.14,107.64 67.69,109.09 67.52,109.09 67.41,108.98 67.41,108.81 68.86,107.36 68.86,107.19 68.75,107.08 68.58,107.08 67.13,108.53 66.96,108.53 66.59,108.16 66.59,108 67.23,107.36 67.23,107.2 67.11,107.08 66.95,107.08 66.31,107.72 66.15,107.72 66.03,107.6 66.03,107.44 66.67,106.8 66.67,106.64 66.55,106.52 66.39,106.52 65.75,107.16 65.59,107.16 65.47,107.04 65.47,106.88 66.11,106.24 66.11,106.08 65.99,105.96 65.83,105.96 65.19,106.6 65.03,106.6 64.56,106.13 60.63,106.13 60.1,106.66 59.33,106.66 58.67,106 57.57,106 57.46,106.11 57.46,106.37 57.36,106.48 57.14,106.48 57.03,106.37 57.03,106.11 56.92,106 56.7,106 56.59,106.11 56.59,106.37 56.48,106.48 56.26,106.48 56.15,106.37 56.15,106.11 56.04,106 55.83,106 55.72,106.11 55.72,106.37 55.61,106.48 55.39,106.48 55.28,106.37 55.28,106.11 55.17,106 53.67,106 52.68,106.99 48.89,106.99 45.01,110.88 45.01,111.39 42.87,113.52 38.99,113.52 38.46,114.05 33.16,114.05 31.32,112.21 31.32,110.6 31.94,109.97 34.78,109.97 39.29,105.47 39.29,105.14 38.59,104.44 37.89,104.44 35.53,106.8 35.53,106.97 36.02,107.46 36.02,107.61 35.9,107.72 35.73,107.72 35.25,107.25 35.09,107.25 34.97,107.36 34.97,107.53 35.52,108.08 35.52,108.25 35.41,108.36 35.24,108.36 34.69,107.81 34.52,107.81 34.41,107.93 34.41,108.09 34.96,108.64 34.96,108.81 34.84,108.92 34.68,108.92 34.13,108.37 33.96,108.37 33.58,108.76 31.96,108.76 31.75,108.54 31.75,105.93 v7(31.93,105.75)
PRU1ETH1_TXD1: length 175.6
  TOP w0.173: U13.5 31.25,103.75 v2(31.25,103.75) ; v2(119.51,102.57) 119.51,103.21 R126.1
  L3_SIG1 w0.109: v2(31.25,103.75) 31.25,103.32 31.06,103.12 30.78,103.12 30.67,103.01 30.67,102.47 30.55,102.35 30.39,102.35 30.27,102.47 30.27,103.14 30.15,103.26 29.98,103.26 29.88,103.15 29.88,102.44 29.76,102.32 29.6,102.32 29.48,102.44 29.48,103.01 29.36,103.12 29.13,103.12 29.01,103.01 29.01,102.31 28.88,102.18 28.72,102.18 28.61,102.29 28.61,103.01 28.5,103.12 28.42,103.12 28.29,103.26 28.29,104.06 28.15,104.2 27.7,104.2 27.55,104.05 27.55,103.07 27.38,102.91 27.11,102.91 26.99,103.03 26.99,104.78 26.88,104.89 26.71,104.89 26.6,104.78 26.6,103.03 26.48,102.91 26.33,102.91 26.21,103.03 26.21,103.53 26.09,103.65 25.93,103.65 25.81,103.53 25.81,103.03 25.7,102.91 25.53,102.91 25.42,103.03 25.42,103.5 25.3,103.62 25.14,103.62 25.02,103.5 25.02,103.03 24.91,102.91 24.73,102.91 24.53,103.11 24.53,104.45 24.65,104.57 26.13,104.57 26.24,104.68 26.24,104.85 26.13,104.96 25.52,104.96 25.4,105.08 25.4,106 25.29,106.12 25.12,106.12 25.01,106 25.01,105.08 24.89,104.96 24.65,104.96 24.53,105.08 24.53,105.38 24.42,105.5 22.93,105.5 22.81,105.61 22.81,105.78 22.93,105.89 24.42,105.89 24.53,106.01 24.53,106.17 24.42,106.29 22.93,106.29 22.81,106.4 22.81,106.57 22.93,106.68 24.42,106.68 24.53,106.8 24.53,106.99 24.65,107.1 25.46,107.1 25.57,107.22 25.57,107.38 25.46,107.5 24.65,107.5 24.53,107.61 24.53,107.98 24.42,108.1 23.45,108.1 23.33,108.21 23.33,108.38 23.45,108.49 24.42,108.49 24.53,108.61 24.53,108.77 24.42,108.89 23.45,108.89 23.33,109 23.33,109.17 23.45,109.28 24.42,109.28 24.53,109.4 24.53,109.56 24.42,109.68 23.45,109.68 23.33,109.8 23.33,109.96 23.45,110.08 24.42,110.08 24.53,110.19 24.53,110.36 24.42,110.47 23.45,110.47 23.33,110.59 23.33,110.75 23.45,110.87 24.42,110.87 24.53,110.99 24.53,111.15 24.42,111.27 23.45,111.27 23.33,111.38 23.33,111.55 23.45,111.66 24.42,111.66 24.53,111.78 24.53,111.94 24.42,112.06 23.45,112.06 23.33,112.17 23.33,112.34 23.45,112.45 24.58,112.45 24.69,112.56 24.69,112.73 24.57,112.85 23.45,112.85 23.33,112.97 23.33,113.13 23.45,113.25 24.42,113.25 24.53,113.36 24.53,113.77 24.75,113.99 24.75,114.15 24.44,114.46 24.44,114.6 24.56,114.72 24.75,114.72 25.16,114.31 25.32,114.31 25.44,114.42 25.44,114.59 24.95,115.07 24.95,115.23 25.08,115.36 25.23,115.36 25.59,114.99 25.76,114.99 25.87,115.11 25.87,115.27 25.51,115.64 25.51,115.79 25.64,115.92 25.79,115.92 26.16,115.55 26.32,115.55 26.8,116.03 30.81,116.03 31.04,116.26 31.04,116.8 31.84,117.61 40.44,117.61 41.47,116.58 44.13,116.58 47.96,112.76 47.96,110.88 50.01,108.82 51.28,108.82 51.61,109.14 60.33,109.14 60.58,108.89 64.69,108.89 65.7,109.9 65.7,110.75 66.23,111.29 67.09,111.29 69.93,114.13 84,114.13 84.38,114.51 90.2,114.51 91.47,113.24 96.29,113.24 98.45,111.08 106.93,111.08 109.51,108.5 113.08,108.5 113.52,108.06 114.97,108.06 119.51,103.52 v2(119.51,102.57)
  BOTTOM w0.173: R749.2 v2(119.51,102.57)
PRU1ETH1_TXD2: length 179.7
  TOP w0.173: U13.6 v2(30.75,104.73) ; v7(115.82,101.05) 116.08,100.79 R127.1
  L3_SIG1 w0.109: v5(109.98,104.98) 111.11,104.98 113.95,102.14 113.95,101.12 114.35,100.72 115.49,100.72 v7(115.82,101.05)
  L10_SIG4 w0.109: v2(30.75,104.73) 30.3,104.29 29.55,104.29 29.29,104.55 25.59,104.55 25.31,104.83 21.08,104.83 20.14,105.77 19.05,105.77 18.14,104.86 12.95,104.86 5.13,112.68 5.13,115.19 9.46,119.52 14.1,119.52 15.34,120.76 18.78,120.76 26.01,128 28.14,128 28.68,127.46 39.07,127.46 39.57,127.97 52.83,127.97 53.49,127.31 56.03,127.31 56.39,127.67 61.19,127.67 61.49,127.97 72.4,127.97 73.73,126.64 73.73,125.43 73.85,125.31 74.01,125.31 74.13,125.43 74.13,126.51 74.25,126.62 74.41,126.62 74.53,126.51 74.53,125.25 74.64,125.13 74.81,125.13 74.92,125.25 74.92,126.51 75.04,126.62 75.2,126.62 75.32,126.51 75.32,125.25 75.43,125.13 75.6,125.13 75.71,125.25 75.71,126.51 75.83,126.62 75.99,126.62 76.11,126.51 76.11,125.35 76.23,125.24 76.39,125.24 76.51,125.35 76.51,126.51 76.62,126.62 80.39,126.62 82.09,124.92 83.44,124.92 84.43,123.93 84.43,120.93 86.49,118.87 100.74,118.87 106.43,113.18 107.42,113.18 108.33,112.27 108.33,109.58 108.89,109.02 108.89,107.47 109.98,106.38 v5(109.98,104.98)
PRU1ETH1_TXD3: length 176.5
  TOP w0.173: R128.1 v7(117.47,101.1) ; U13.7 30.25,103.75 v2(30.25,103.75)
  L3_SIG1 w0.109: v5(110.82,104.32) 112.46,102.68 112.46,102.06 114.24,100.28 116.66,100.28 v7(117.47,101.1)
  L10_SIG4 w0.109: v5(110.82,104.32) 110.82,106.16 109.89,107.08 109.89,111.24 109.37,111.76 109.37,112.52 107.92,113.97 107.72,113.97 107.26,114.43 107.26,114.81 106.16,115.91 104.64,115.91 101.04,119.51 86.84,119.51 85.09,121.26 85.09,125.25 83.19,127.15 80.73,127.15 80.62,127.26 80.62,127.45 80.51,127.56 80.29,127.56 80.18,127.45 80.18,127.26 80.07,127.15 79.85,127.15 79.74,127.26 79.74,127.45 79.63,127.56 79.41,127.56 79.31,127.45 79.31,127.26 79.2,127.15 78.98,127.15 78.87,127.26 78.87,127.45 78.76,127.56 78.54,127.56 78.43,127.45 78.43,127.26 78.32,127.15 77.31,127.15 77.19,127.26 77.19,127.57 77.08,127.68 76.91,127.68 76.8,127.57 76.8,127.26 76.68,127.15 76.52,127.15 76.4,127.26 76.4,127.57 76.28,127.68 76.12,127.68 76,127.57 76,127.26 75.89,127.15 75.72,127.15 75.61,127.26 75.61,127.57 75.49,127.68 75.33,127.68 75.21,127.57 75.21,127.26 75.09,127.15 74.93,127.15 73.61,128.47 64.65,128.47 64.01,129.11 63.25,129.11 62.46,128.33 57.41,128.33 57.2,128.54 39.58,128.54 39.21,128.17 35.71,128.17 35.43,128.45 25.99,128.45 20.12,122.58 17.6,122.58 16.89,121.87 15.8,121.87 14.3,120.38 9.8,120.38 4.78,115.35 4.78,112.04 12.32,104.5 18.03,104.5 18.77,103.76 21.26,103.76 21.36,103.87 24.31,103.87 24.71,103.46 25.86,103.46 26.59,104.2 29.16,104.2 29.6,103.75 v2(30.25,103.75)
PRU1ETH1_TXEN: length 178.8
  TOP w0.173: R124.1 119.38,101.3 v7(119.38,101.78) ; v2(32.23,104.03) 32.25,104.03 U13.3
  L3_SIG1 w0.109: v7(119.38,101.78) 119.05,102.11 115.73,102.11 112.04,105.8 v5(111.96,105.8)
  L10_SIG4 w0.109: v2(32.23,104.03) 31.27,103.07 28.53,103.07 28.3,103.31 26.19,103.31 25.6,102.72 21.39,102.72 20.75,103.36 18.8,103.36 17.73,102.29 13.82,102.29 4.37,111.74 4.37,115.47 9.81,120.91 14.25,120.91 16.23,122.89 16.89,122.89 17.32,123.32 20.32,123.32 25.81,128.81 35.74,128.81 35.86,128.68 38.18,128.68 38.51,129.01 57.38,129.01 57.71,128.68 62.08,128.68 62.94,129.54 64.06,129.54 64.69,128.91 73.86,128.91 74.68,128.09 80.78,128.09 81.03,127.84 83.38,127.84 85.6,125.63 86.16,125.63 87.22,124.56 87.22,121.46 88.47,120.22 102.92,120.22 104.58,118.55 106.67,118.55 110.34,114.88 110.34,111.8 110.94,111.2 110.94,110.39 110.92,110.38 110.92,106.84 v5(111.96,105.8)
PRU1ETHER0_RDN: length 23.1
  BOTTOM w0.108: J3.2 18.97,134.7 18.97,135.82 18.09,136.71 16.18,136.71 15.62,136.15 15.62,127.26 18.73,124.15 18.73,123.91 R99.2 18.73,123.14 18.73,122.85 19.71,121.88 19.71,121.3 U9.9
PRU1ETHER0_RDP: length 23.2
  BOTTOM w0.108: U9.10 19.96,121.3 19.96,121.98 18.98,122.96 18.98,123.14 R100.2 18.98,123.91 18.98,124.26 15.88,127.36 15.88,136.05 16.28,136.45 17.98,136.45 18.72,135.72 18.72,134.8 18.39,134.47 17.93,134.47 J3.1
PRU1ETHER0_TDN: length 21.1
  BOTTOM w0.108: 22.61,127.79 22.89,128.07 23.72,128.07 23.93,127.87 23.93,126.4 22.45,124.92 22.27,124.92 21.44,125.75 21.05,125.75 20.77,125.48 20.77,125.09 21.61,124.25 21.61,124.07 21.28,123.75 21.28,123.2 20.71,122.62 20.71,121.3 U9.11 ; 22.61,127.79 R101.2 ; 22.61,127.79 22.33,128.07 21.54,128.07 20.93,128.68 20.93,129.64 20.58,129.99 19.04,129.99 18.06,129.01 18.06,128.61 18.21,128.45 19.24,128.45 19.69,128.91
PRU1ETHER0_TDP: length 21.3
  BOTTOM w0.108: 22.61,128.63 22.91,128.33 23.83,128.33 24.18,127.97 24.18,126.29 22.55,124.66 22.17,124.66 21.33,125.5 21.15,125.5 21.03,125.37 21.03,125.19 21.86,124.36 21.86,123.97 21.54,123.64 21.54,123.08 20.96,122.51 20.96,121.3 U9.12 ; 22.61,128.63 R102.2 ; 22.61,128.63 22.3,128.33 21.64,128.33 21.18,128.78 21.18,129.75 20.69,130.24 18.94,130.24 17.7,129.01 17.32,129.01 17.15,129.18 J3.5
PRU1ETHER1_RDN: length 24.3
  TOP w0.108: J5.6 19.69,104.93 19.08,105.54 18.75,105.54 18.55,105.35 18.55,104.06 18.9,103.71 20.89,103.71 21.02,103.84 21.02,106.67 21.35,107 21.78,107 22.1,106.69 22.1,103.82 22.2,103.71 22.45,103.71 22.66,103.92 22.66,105.55 23.13,106.02 24.03,106.02 R143.2 24.79,105.97 25.26,105.97 26.29,104.94 26.29,103.59 27.81,102.06 28.6,102.06 28.7,102.16 U13.9
PRU1ETHER1_RDP: length 24.3
  TOP w0.108: J5.5 18.3,104.9 18.3,103.96 18.8,103.46 20.99,103.46 21.27,103.74 21.27,106.57 21.45,106.75 21.68,106.75 21.84,106.58 21.84,103.71 22.1,103.46 22.56,103.46 22.91,103.81 22.91,105.45 23.24,105.77 23.98,105.77 R144.2 24.74,105.72 25.15,105.72 26.03,104.83 26.03,103.48 27.71,101.81 28.58,101.81 28.72,101.66 U13.10
PRU1ETHER1_TDN: length 26
  TOP w0.108: U13.11 28.69,101.16 28.58,101.05 26.6,101.05 25.78,101.86 24.84,101.86 R145.2 23.95,101.88 22.58,101.88 21.69,101 17.96,101 15.85,103.1 15.85,109.02 16.61,109.78 18.08,109.78 18.46,110.16 18.46,110.41 18.55,110.49 19.1,110.49 19.68,109.92 19.68,109.87 J5.2
PRU1ETHER1_TDP: length 26.3
  TOP w0.108: U13.12 28.71,100.66 28.58,100.79 26.49,100.79 25.68,101.6 24.82,101.6 R146.2 23.93,101.63 22.68,101.63 21.79,100.74 17.85,100.74 15.6,103 15.6,109.13 16.51,110.04 17.98,110.04 18.21,110.27 18.21,110.52 18.08,110.65 17.63,110.65 J5.1
PRU2ETH0_25MHZCLK: length 38.1
  TOP w0.173: U15.23 32.75,79.22 33.66,78.31 v7(33.66,76.79)
  L3_SIG1 w0.109: v7(33.66,76.79) v5(34.42,76.79)
  L9_SIG3 w0.114: v5(34.42,76.79) 35.31,77.68 35.31,86.82 39.24,90.76 v5(39.24,94.82)
  L10_SIG4 w0.109: v9(52.07,94.82) v5(39.24,94.82)
  BOTTOM w0.173: R354.2 v9(52.07,94.82)
PRU2ETH0_COL: length 372.1
  TOP w0.173: U15.29 36.45,82.88 R187.2 36.83,82.38 37.54,81.66 39.98,81.66 v2(40,81.64) ; R188.1 v7(121.54,78.06)
  L3_SIG1 w0.109: v2(7.37,82.12) 15.39,82.12 16.23,82.96 17.81,82.96 18.8,81.97 20.57,81.97 22.77,84.17 33.69,84.17 36.22,81.64 v2(40,81.64) ; v7(121.54,78.06) v5(123.99,78.06)
  L4_SIG2 w0.114: v2(40,81.64) 33.48,81.64 32.59,80.75 31.83,80.75 27.71,76.63 27.1,76.63 24.28,73.81 24.28,64.06 27.18,61.16 27.18,59.26 28.84,57.6 28.84,52.48 25.41,49.05 25.41,39.39 25.14,39.12 25.14,34.68 24.56,34.1 24.56,26.59 22.85,24.89 22.85,11.65 29.12,5.38 33.53,5.38 34.3,6.15 50.8,6.15 55.56,10.92 56.18,10.92 56.74,11.48 68.46,11.48 69.25,10.69 92.52,10.69 93.26,9.95 97.9,9.95 98.5,9.35 104.96,9.35 105.6,9.99 113.49,9.99 114.73,8.74 121.24,8.74 122.08,9.58 132.94,9.58 138.89,15.53 144.61,15.53 155.45,26.37 158.28,26.37 167.64,35.74 167.64,45.61 168.91,46.88 168.91,60.02 161.56,67.37 160.28,67.37 149.46,78.19 130.37,78.19 129.7,77.52 124.53,77.52 v5(123.99,78.06)
  BOTTOM w0.173: R189.2 v2(7.37,82.12)
PRU2ETH0_CRS: length 3.7
  TOP w0.173: U15.27 34.91,81.88 R177.1
PRU2ETH0_INTN: length 181.1
  TOP w0.173: U15.8 29.75,86.44 29.63,86.56 29.63,89.96 v2(29.08,90.51)
  L3_SIG1 w0.109: v2(29.08,90.51) 29.91,91.33 30.8,91.33 31.67,92.21 31.67,94.52 31.15,95.04 24.26,95.04 18.5,100.81 18.5,101.73 18.49,101.74 18.49,107.81 18.52,107.84 18.52,113.24 19.56,114.28 19.56,117.21 19.55,117.22 19.55,117.64 19.56,117.65 19.56,121.66 24.42,126.52 29.87,126.52 30.63,125.76 37.56,125.76 38.45,126.64 38.46,126.64 39.79,127.97 47.15,127.97 47.45,128.27 59.62,128.27 62.94,131.6 62.94,132.14 63.76,132.96 86.45,132.96 87.56,131.86 90.53,131.86 91.01,132.34 95.99,132.34 96.45,131.88 98.98,131.88 100.38,130.48 103.12,130.48 103.48,130.12 103.48,129.11 104.62,127.97 106.56,127.97 110.11,124.42 110.11,123.47 111.84,121.75 112.24,121.75 115.06,118.93 v5(115.06,118.29)
  L10_SIG4 w0.109: v9(115.06,117.68) v5(115.06,118.29)
  BOTTOM w0.173: R671.2 111.38,104.55 108.38,107.55 108.38,110.49 108.97,111.08 111.63,111.08 115.06,114.51 v9(115.06,117.68)
PRU2ETH0_LINKLED: length 26.9
  TOP w0.173: v2(27.27,78.65) 27.38,78.54 27.38,78.52 27.84,78.06 R159.1 28.52,78.38 28.52,79.17 28.86,79.52 29.34,79.52 29.75,79.93 U15.17
  L4_SIG2 w0.114: v2(27.27,78.65) 26.02,79.91 23.29,79.91 21.39,81.81 18.85,81.81 17.41,83.25 16.65,83.25 16.64,83.27 v2(7.37,83.27)
  BOTTOM w0.173: R176.2 v2(7.37,83.27)
PRU2ETH0_MDC: length 2.4
  TOP w0.173: U15.20 31.25,78.7 R179.1
PRU2ETH0_MDIO: length 2.6
  TOP w0.173: U15.19 30.75,79.21 R181.1
PRU2ETH0_RESETN: length 17.7
  TOP w0.173: v2(29.13,78.94) 29.66,78.94 30.25,79.52 U15.18
  L4_SIG2 w0.114: v1(17.51,71.95) 19.07,71.95 22.53,75.41 24.74,75.41 27.1,77.77 27.97,77.77 v2(29.13,78.94)
  BOTTOM w0.173: U70.4 v1(17.51,71.95)
PRU2ETH0_RXCLK: length 4.6
  TOP w0.173: U15.25 34.26,80.88 35.56,79.58 35.56,78.95 R165.1
PRU2ETH0_RXD0: length 3.7
  TOP w0.173: R194.2 36.13,83.52 v2(36.1,83.49) 36,83.38 U15.30
  BOTTOM w0.173: v2(36.1,83.49) 36.13,83.52 R194.2
PRU2ETH0_RXD1: length 4.1
  TOP w0.173: U15.31 35.22,83.88 v2(35.97,84.63) 36.8,84.63 R193.2
  BOTTOM w0.173: R193.2 36.8,84.63 v2(35.97,84.63)
PRU2ETH0_RXD2: length 4.3
  TOP w0.173: U15.32 34.52,84.38 v2(35.94,85.81) R192.2
  BOTTOM w0.173: R192.2 v2(35.94,85.81)
PRU2ETH0_RXD3: length 5.6
  TOP w0.173: U15.1 33.25,85.97 34.23,86.95 v2(36.07,86.95) R191.2
  BOTTOM w0.173: R191.2 v2(36.07,86.95)
PRU2ETH0_RXDV: length 4.1
  TOP w0.173: R166.1 36.2,79.46 36.2,79.84 34.65,81.38 U15.26
PRU2ETH0_RXERR: length 3.4
  TOP w0.173: U15.28 35.56,82.38 R170.1
PRU2ETH0_TXCLK: length 301.4
  TOP w0.173: U15.2 v2(32.75,87.05) ; 124.59,82.76 v7(125.98,82.76)
  L3_SIG1 w0.109: v7(125.98,82.76) 126.34,82.76 126.67,83.09 128.47,83.09 129.06,82.5 130.63,82.5 v5(130.86,82.73)
  L10_SIG4 w0.109: v5(130.86,82.73) 130.86,81.54 130.3,80.98 130.3,77.55 133.35,74.5 135.74,74.5 136.09,74.85 152.96,74.85 160.76,67.06 160.76,61.7 162.36,60.1 162.36,47.22 161.64,46.5 161.28,46.5 160.84,46.94 160.68,46.94 160.53,46.79 160.53,46.63 160.96,46.2 160.96,46.05 160.8,45.89 160.65,45.89 160.22,46.32 160.06,46.32 159.91,46.17 159.91,46.01 160.22,45.7 160.22,45.55 158.27,43.59 158.27,34.12 148.41,24.26 138.81,24.26 131.82,17.27 126.15,17.27 125.88,17 125.87,17 125.6,16.73 125.6,16.47 119.75,10.62 108.43,10.62 107.96,11.1 104.21,11.1 103.14,10.03 73.2,10.03 72.09,11.15 63.68,11.15 63.68,11.15 63.32,11.15 63.32,11.15 59.61,11.15 59,11.77 57.76,11.77 51.49,18.03 47.09,18.03 34.34,30.78 34.34,33.86 31.84,36.36 31.84,37.71 30.96,38.59 28.96,38.59 24.99,42.55 24.99,48.23 22.13,51.1 22.13,61.83 21.44,62.51 21.44,62.76 21.44,63.04 21.44,63.04 21.44,63.81 21.44,68.37 22.76,69.68 22.76,74.12 23.27,74.63 28.17,74.63 28.68,74.63 30.03,75.97 30.03,77.12 33.22,80.31 33.22,86.57 v2(32.75,87.05)
PRU2ETH0_TXD0: length 301.7
  TOP w0.173: v2(31.78,87.53) 31.75,87.5 U15.4 ; 124.59,81.62 v7(125.35,81.62)
  L3_SIG1 w0.109: v7(125.35,81.62) 126.31,81.62 127.05,82.35 128.17,82.35 128.83,81.69 v5(130.16,81.69)
  L10_SIG4 w0.109: v5(130.16,81.69) 129.92,81.46 129.92,76 131.93,74 133.35,74 133.86,73.49 153.8,73.49 160.4,66.88 160.4,61.4 162.02,59.78 162.02,49.12 157.91,45.01 157.91,34.39 157.61,34.09 157.43,34.09 157.2,34.32 157.05,34.32 156.89,34.16 156.89,34.01 157.12,33.78 157.12,33.63 156.96,33.47 156.81,33.47 156.58,33.7 156.43,33.7 156.27,33.55 156.27,33.39 156.5,33.17 156.5,33.01 156.35,32.86 156.19,32.86 155.97,33.08 155.81,33.08 155.66,32.93 155.66,32.77 155.88,32.55 155.88,32.39 155.73,32.24 155.57,32.24 155.35,32.46 155.19,32.46 155.04,32.31 155.04,32.16 155.26,31.93 155.26,31.77 148.39,24.9 138.61,24.9 132.16,18.45 126.86,18.45 125.74,17.33 125.73,17.33 125.26,16.87 125.26,16.86 119.38,10.98 108.81,10.98 107.98,11.81 105.44,11.81 104.95,12.3 103.73,12.3 101.85,10.41 73.58,10.41 72.49,11.51 62.03,11.51 60.55,12.98 58.8,12.98 58.24,13.54 58.24,14.53 54.91,17.86 52.91,17.86 52.23,18.54 47.07,18.54 34.68,30.93 34.68,34.03 32.33,36.37 32.33,37.85 31.17,39.01 30.06,39.01 25.33,43.74 25.33,48.37 22.46,51.24 22.46,61.97 21.78,62.65 21.78,63.95 21.78,68.23 23.29,69.74 23.29,72.36 25.2,74.27 28.93,74.27 30.15,75.49 30.56,75.49 31.06,76 31.06,77.47 33.66,80.06 33.66,87.05 33.17,87.53 v2(31.78,87.53)
PRU2ETH0_TXD1: length 306.8
  TOP w0.173: v2(31.25,85.97) 31.25,85.97 U15.5 ; 124.59,83.9 v7(125.98,83.9)
  L3_SIG1 w0.109: v7(125.98,83.9) 126.19,83.7 129.39,83.7 129.67,83.42 131.39,83.42 v5(131.95,82.86)
  L10_SIG4 w0.109: v5(131.95,82.86) 132.59,82.22 132.59,77.29 134.11,75.77 153.04,75.77 163.22,65.59 163.22,44.05 162.97,43.8 162.72,43.8 162.25,44.26 162.1,44.26 161.94,44.11 161.94,43.96 162.41,43.49 162.41,43.34 162.25,43.18 162.1,43.18 161.63,43.65 161.48,43.65 161.32,43.49 161.32,43.34 161.79,42.87 161.79,42.72 161.63,42.56 161.48,42.56 161.01,43.03 160.86,43.03 160.7,42.87 160.7,42.72 161.17,42.25 161.17,42.1 161.01,41.94 160.86,41.94 160.4,42.41 160.24,42.41 160.09,42.26 160.09,42.1 160.55,41.64 160.55,41.48 160.4,41.33 160.24,41.33 159.78,41.79 159.62,41.79 159.47,41.64 159.47,41.48 159.93,41.02 159.93,40.86 159.05,39.98 159.05,33.84 148.11,22.89 139.07,22.89 132.59,16.41 127.3,16.41 119.76,8.87 114.12,8.87 113.39,9.6 105.23,9.6 104.59,8.97 89.92,8.97 89.23,8.28 72.52,8.28 71.22,9.58 59.8,9.58 58.57,10.8 55.67,10.8 49.76,16.71 47.45,16.71 33.52,30.64 33.52,32.95 32.05,34.42 29.46,34.42 28.93,34.95 28.93,36.66 28.58,37.01 28.04,37.01 27.3,37.75 27.3,38.97 23.6,42.68 23.6,46.8 21.45,48.94 21.45,61.55 20.77,62.23 20.77,62.48 20.77,62.48 20.77,63.37 20.77,63.37 20.77,63.53 20.77,63.53 20.77,64.98 20.77,64.98 20.77,68.68 22.06,69.98 22.06,74.64 22.73,75.31 27.89,75.31 28.7,76.12 28.7,77.01 31.01,79.32 31.01,84.66 31.25,84.89 v2(31.25,85.97)
PRU2ETH0_TXD2: length 309.3
  TOP w0.173: U15.6 v2(30.75,86.95) ; v7(121.79,82.84) 121.37,82.84 R168.1
  L3_SIG1 w0.109: v5(132.14,81.92) 130.89,81.92 130.66,82.15 128.88,82.15 128.32,82.71 126.88,82.71 126.42,82.25 125.68,82.25 125.46,82.47 122.64,82.47 122.27,82.84 v7(121.79,82.84)
  L10_SIG4 w0.109: v2(30.75,86.95) 32.16,86.95 32.77,86.34 32.77,84.66 32.03,83.93 32.03,79.73 29.08,76.78 29.08,76.02 28.03,74.97 23,74.97 22.4,74.37 22.4,69.84 21.1,68.54 21.1,64.84 21.1,63.18 21.1,63.18 21.1,62.62 21.1,62.37 21.79,61.69 21.79,49.08 24.03,46.84 24.03,42.85 28.95,37.93 28.95,37.55 29.46,37.04 29.89,37.04 30.35,36.58 30.35,36.07 30.61,35.81 31.88,35.81 33.86,33.83 33.86,30.78 47.22,17.42 51.59,17.42 53.86,15.16 53.86,14.6 57.17,11.28 58.85,11.28 59.99,10.14 71.42,10.14 72.9,8.66 88.62,8.66 89.38,9.42 104.48,9.42 105.13,10.07 114.09,10.07 114.48,9.68 120.05,9.68 127.3,16.94 132.2,16.94 138.84,23.58 148.23,23.58 158.67,34.02 158.67,41.79 159.84,42.95 159.84,43.11 159.53,43.42 159.53,43.58 159.68,43.73 159.83,43.73 160.15,43.42 160.3,43.42 160.46,43.57 160.46,43.73 160.14,44.04 160.14,44.2 160.3,44.35 160.45,44.35 160.77,44.04 160.92,44.04 161.08,44.19 161.08,44.35 160.76,44.66 160.76,44.81 160.92,44.97 161.07,44.97 161.39,44.65 161.62,44.65 162.86,45.9 162.86,65.44 152.99,75.31 135.66,75.31 135.23,74.88 133.48,74.88 131.62,76.74 131.62,80.62 132.14,81.14 v5(132.14,81.92)
PRU2ETH0_TXD3: length 306.1
  TOP w0.173: 124.59,85.17 v7(127.86,85.17) ; U15.7 30.25,86.22 v2(30.23,86.24)
  L3_SIG1 w0.109: v5(132.94,84.05) 131.65,85.35 128.04,85.35 v7(127.86,85.17)
  L10_SIG4 w0.109: v5(132.94,84.05) 133.81,83.19 133.81,80.12 135.97,77.96 154.53,77.96 156.46,76.03 156.46,73.44 165.18,64.73 165.18,57.26 163.93,56.01 163.93,41.17 161.76,39 161.76,38.64 162.29,38.11 162.29,37.96 162.14,37.8 161.98,37.8 161.46,38.32 161.28,38.32 160.15,37.19 160.15,31.37 143.82,15.04 129.77,15.04 122.44,7.72 119.5,7.72 118.87,7.09 100.84,7.09 100.43,7.5 96.19,7.5 95.73,7.04 72.55,7.04 70.94,8.64 55.6,8.64 48.67,15.57 47.62,15.57 37.11,26.09 36.58,26.09 29.49,33.18 28.83,33.18 26.95,35.06 26.95,35.72 20.77,41.89 20.77,61.27 20.09,61.95 20.09,62.2 20.09,62.2 20.09,62.76 20.09,62.76 20.09,70.33 21.39,71.62 21.39,74.92 21.58,75.12 22.45,75.98 25.69,75.98 26.72,77.01 26.72,77.32 28.68,79.27 28.68,84.69 v2(30.23,86.24)
PRU2ETH0_TXEN: length 308.9
  TOP w0.173: v2(32.23,86.25) 32.25,86.25 U15.3 ; R167.1 v7(121.54,84.54)
  L3_SIG1 w0.109: v5(132.23,83.7) 130.94,84.99 128.55,84.99 128.25,84.69 127.3,84.69 126.64,85.35 123.72,85.35 122.91,84.54 v7(121.54,84.54)
  L10_SIG4 w0.109: v5(132.23,83.7) 132.99,82.94 132.99,77.88 134.18,76.69 152.61,76.69 152.84,76.46 152.84,76.45 164.47,64.83 164.47,57.43 163.56,56.53 163.56,43.09 162.21,41.74 161.68,41.74 159.44,39.5 159.44,32.99 148.79,22.35 139.39,22.35 132.89,15.85 129.11,15.85 121.56,8.31 109.04,8.31 108.79,8.06 106.65,8.06 106.27,8.44 90.4,8.44 89.71,7.75 72.5,7.75 71.16,9.08 55.64,9.08 48.51,16.21 47.47,16.21 33.19,30.49 33.19,32.73 32.02,33.89 28.88,33.89 27.53,35.23 27.53,36.02 22.05,41.51 22.05,47.87 21.11,48.8 21.11,61.41 20.43,62.09 20.43,62.34 20.43,62.34 20.43,62.62 20.43,70.19 21.72,71.48 21.72,74.78 22.59,75.64 23.48,75.64 23.48,75.64 24.36,75.64 25.89,75.64 27.03,76.78 27.79,76.78 29.62,78.61 29.62,80.47 29.39,80.7 29.39,84.74 31.14,86.49 31.98,86.49 v2(32.23,86.25)
PRU2ETH1_25MHZCLK: length 61.3
  TOP w0.173: U17.23 32.75,54.71 33.91,53.55 v7(33.91,52.99)
  L3_SIG1 w0.109: v7(33.91,52.99) v5(33.91,52.41)
  L9_SIG3 w0.114: v5(38.48,94.32) 38.48,90.63 34.86,87.01 34.86,80.99 33.4,79.53 33.4,63.63 33.91,63.12 v5(33.91,52.41)
  L10_SIG4 w0.109: v9(50.8,94.32) v5(38.48,94.32)
  BOTTOM w0.173: R357.2 v9(50.8,94.32)
PRU2ETH1_COL: length 518.2
  TOP w0.173: v2(7.37,57.1) 4.57,59.9 4.57,65.95 7.56,68.94 22.3,68.94 25.2,66.04 25.2,64.63 26.07,63.75 40.36,63.75 40.68,63.43 40.68,56.99 40.28,56.59 39.6,56.59 39.17,57.02 37.55,57.02 36.83,57.74 v2(36.07,57.74) 35.56,57.74 35.18,58.12 U17.29 ; 124.59,74.76 v7(125.35,74.76)
  TOP w0.381: R950.2 v1(116.35,145.52)
  L3_SIG1 w0.109: v5(124.59,74.63) 124.71,74.76 v7(125.35,74.76) ; v1(116.35,145.52) 116.35,148.02 J21.18
  L4_SIG2 w0.114: v2(36.07,57.74) 36.07,52.66 30.9,47.49 30.9,43.77 28.95,41.82 28.95,27.81 24.97,23.83 24.97,12.39 30.29,7.07 49.67,7.07 55.55,12.95 56.85,12.95 57.06,13.16 60.12,13.16 61.08,14.12 69.41,14.12 70,13.54 99.04,13.54 100.21,12.36 102.33,12.36 102.73,12.76 105.12,12.76 106.28,11.6 116.54,11.6 117.17,12.23 128.82,12.23 128.86,12.26 128.89,12.26 129.14,12.52 129.14,12.55 140.33,23.74 146.5,23.74 151.51,28.75 156.78,28.75 164.78,36.74 164.78,38.66 163.42,40.01 163.42,48.29 164.03,48.89 164.03,54.23 166.17,56.36 166.17,60.23 160.78,65.62 159.55,65.62 149.32,75.85 146.44,75.85 145.02,77.27 131.41,77.27 130.64,76.49 123.97,76.49 123.6,76.12 123.6,75.61 124.59,74.63 v5(124.59,74.63)
  BOTTOM w0.173: R232.1 v2(36.07,57.74) 36.07,57.84 35.18,58.72 35.18,62.76 36.02,63.6 41.89,63.6 42.72,64.44 42.72,66.68 41.09,68.31 41.09,71.95 42.37,73.23 42.98,73.23 46,76.25 46,82.65 46.99,83.64 46.99,92.18 50.04,95.22 50.04,97.05 52.55,99.57 52.55,109.86 53.43,110.73 53.43,114.46 53.94,114.98 60.01,114.98 61.09,113.89 62.17,113.89 64.08,115.8 64.9,115.8 70.69,121.59 70.69,131.99 83.76,145.06 86.31,145.06 89.59,141.78 91.57,141.78 95,138.35 95,137.59 96.06,136.53 97.89,136.53 100.2,138.83 100.2,141.88 103.84,145.52 v1(116.35,145.52) ; R231.1 v2(7.37,57.1)
PRU2ETH1_CRS: length 154.7
  TOP w0.173: v2(75.26,104.75) 73.66,104.75 73.23,104.32 66.92,104.32 65.38,102.79 65.38,92.44 61.01,88.06 57.05,88.06 55.07,86.08 43.64,86.08 40.89,83.34 40.89,64.36 41.66,63.6 41.66,57.2 40.21,55.76 37.39,55.76 36.83,55.2 R219.1 34.91,57.12 U17.27
  TOP w0.381: R951.2 v1(118.35,145.52)
  L3_SIG1 w0.109: v1(118.35,145.52) 118.35,148.02 J21.20
  L9_SIG3 w0.114: v1(118.35,145.52) 116.52,143.69 112.9,143.69 107.87,138.66 101.17,138.66 90.5,127.99 90.5,119.76 76.33,105.59 76.1,105.59 v2(75.26,104.75)
PRU2ETH1_INTN: length 145.9
  TOP w0.173: U17.8 v2(29.75,61.87) ; v2(108.58,121.72) 112.39,117.91 112.39,112.05 114.77,109.67 114.77,108.22 113.54,106.99 112.93,106.99 111.63,105.7 R672.2
  BOTTOM w0.173: v2(108.58,121.72) 103.21,121.72 95.58,114.09 95.58,111.96 80.06,96.44 68.17,96.44 67.72,96.9 66.5,96.9 60.4,90.8 60.4,86.92 48.44,74.96 46.15,74.96 42.88,71.68 42.88,70.23 45.01,68.1 45.01,62.31 42.07,59.36 42.07,58.07 39.75,55.75 36.63,55.75 32.82,59.56 32.82,61.18 32.13,61.87 v2(29.75,61.87)
PRU2ETH1_LINKLED: length 26.6
  TOP w0.173: v2(27.3,53.68) 27.69,53.29 R200.1 28.67,53.77 28.67,54.24 29.75,55.31 U17.17
  L4_SIG2 w0.114: v2(27.3,53.68) 24.76,53.68 21.34,57.1 18.89,57.1 17.5,58.49 v2(7.86,58.49)
  BOTTOM w0.173: R218.2 v2(7.86,58.49)
PRU2ETH1_MDC: length 2.4
  TOP w0.173: R221.1 30.86,53.55 30.86,54.09 31.25,54.48 U17.20
PRU2ETH1_MDIO: length 5.2
  TOP w0.173: R201.1 29.03,51.69 29.03,52.73 29.59,53.29 R223.1 29.59,53.45 30.75,54.61 U17.19
PRU2ETH1_RESETN: length 11.9
  TOP w0.173: U17.18 30.25,54.82 v2(29.73,54.3)
  BOTTOM w0.173: U71.4 25.51,50.53 26.28,51.3 27.55,51.3 27.56,51.31 27.58,51.31 28.2,50.69 28.8,50.69 29.73,51.62 v2(29.73,54.3)
PRU2ETH1_RXCLK: length 4.6
  TOP w0.173: R209.1 35.43,54.31 35.43,54.95 34.26,56.12 U17.25
PRU2ETH1_RXD0: length 3.7
  TOP w0.173: R238.2 36.13,58.76 v2(36.1,58.72) 36,58.62 U17.30
  BOTTOM w0.173: v2(36.1,58.72) 36.13,58.76 R238.2
PRU2ETH1_RXD1: length 4.1
  TOP w0.173: R237.2 36.01,59.9 v2(35.97,59.87) 35.22,59.12 U17.31
  BOTTOM w0.173: v2(35.97,59.87) 36.01,59.9 R237.2
PRU2ETH1_RXD2: length 4.3
  TOP w0.173: U17.32 34.52,59.62 v2(35.94,61.04) R236.2
  BOTTOM w0.173: v2(35.94,61.04) R236.2
PRU2ETH1_RXD3: length 5.6
  TOP w0.173: R235.2 v2(36.07,62.18) 34.23,62.18 33.25,61.2 U17.1
  BOTTOM w0.173: R235.2 v2(36.07,62.18)
PRU2ETH1_RXDV: length 41.3
  TOP w0.173: v2(38.84,54.61) 37.39,54.61 R211.1 35.94,54.95 35.94,55.33 34.65,56.62 U17.26 ; R117.2 v2(30.09,74.36)
  L4_SIG2 w0.114: v2(30.09,74.36) 28.06,74.36 25.93,72.23 25.93,68.43 26.99,67.37 36.39,67.37 38.76,65 38.76,63.07 38.17,62.48 38.17,57.43 39.14,56.46 39.14,54.91 38.84,54.61 v2(38.84,54.61)
PRU2ETH1_RXERR: length 3.4
  TOP w0.173: R212.1 36.07,57.1 35.47,57.1 34.96,57.62 U17.28
PRU2ETH1_TXCLK: length 102.1
  TOP w0.173: R204.1 v7(77.09,95.97) ; U17.2 32.75,61.66 33.02,61.93 v2(33.02,62.92)
  L3_SIG1 w0.109: v7(77.09,95.97) v5(76.45,95.97)
  L10_SIG4 w0.109: v5(76.45,95.97) 75.82,95.33 74.3,95.33 73.66,94.7 73.66,91.98 73.25,91.57 73.25,91.37 73.68,90.95 73.68,90.75 73.54,90.61 73.34,90.61 72.91,91.03 72.71,91.03 72.57,90.89 72.57,90.69 73.13,90.14 73.13,89.94 72.58,89.4 72.43,89.4 71.82,90.01 71.66,90.01 71.51,89.85 71.51,89.7 72.12,89.09 72.12,88.93 71.96,88.78 71.81,88.78 71.2,89.39 71.04,89.39 70.89,89.23 70.89,89.08 71.5,88.47 71.5,88.32 71.34,88.16 71.19,88.16 70.58,88.77 70.43,88.77 70.27,88.61 70.27,88.46 70.88,87.85 70.88,87.7 70.72,87.54 70.57,87.54 69.96,88.15 69.81,88.15 69.65,88 69.65,87.84 70.26,87.23 70.26,87.08 70.11,86.92 69.95,86.92 69.34,87.53 69.19,87.53 69.03,87.38 69.03,87.22 69.64,86.62 69.64,86.46 69.49,86.31 69.33,86.31 68.73,86.91 68.57,86.91 68.42,86.76 68.42,86.61 69.02,86 69.02,85.84 68.04,84.85 67.6,84.85 66.42,83.66 66.42,83.2 66.27,83.06 64.77,83.06 64.16,82.45 64.16,80.08 64.3,79.94 66.96,79.94 67.1,79.8 67.1,79.6 66.96,79.46 64.3,79.46 64.16,79.32 64.16,79.12 64.3,78.98 66.96,78.98 67.1,78.84 67.1,78.64 66.96,78.5 64.3,78.5 64.16,78.36 64.16,78.16 64.4,77.93 65.84,77.93 65.98,77.79 65.98,77.59 65.76,77.37 63.6,77.37 63.32,77.09 63.32,75.82 62.87,75.36 61.21,75.36 59.08,77.5 58.29,77.5 57.76,78.03 57.76,78.89 57.35,79.3 46.23,79.3 42.88,75.95 42.49,75.95 41.12,74.57 41.12,70.84 35.86,65.58 35.86,64.29 34.49,62.92 v2(33.02,62.92)
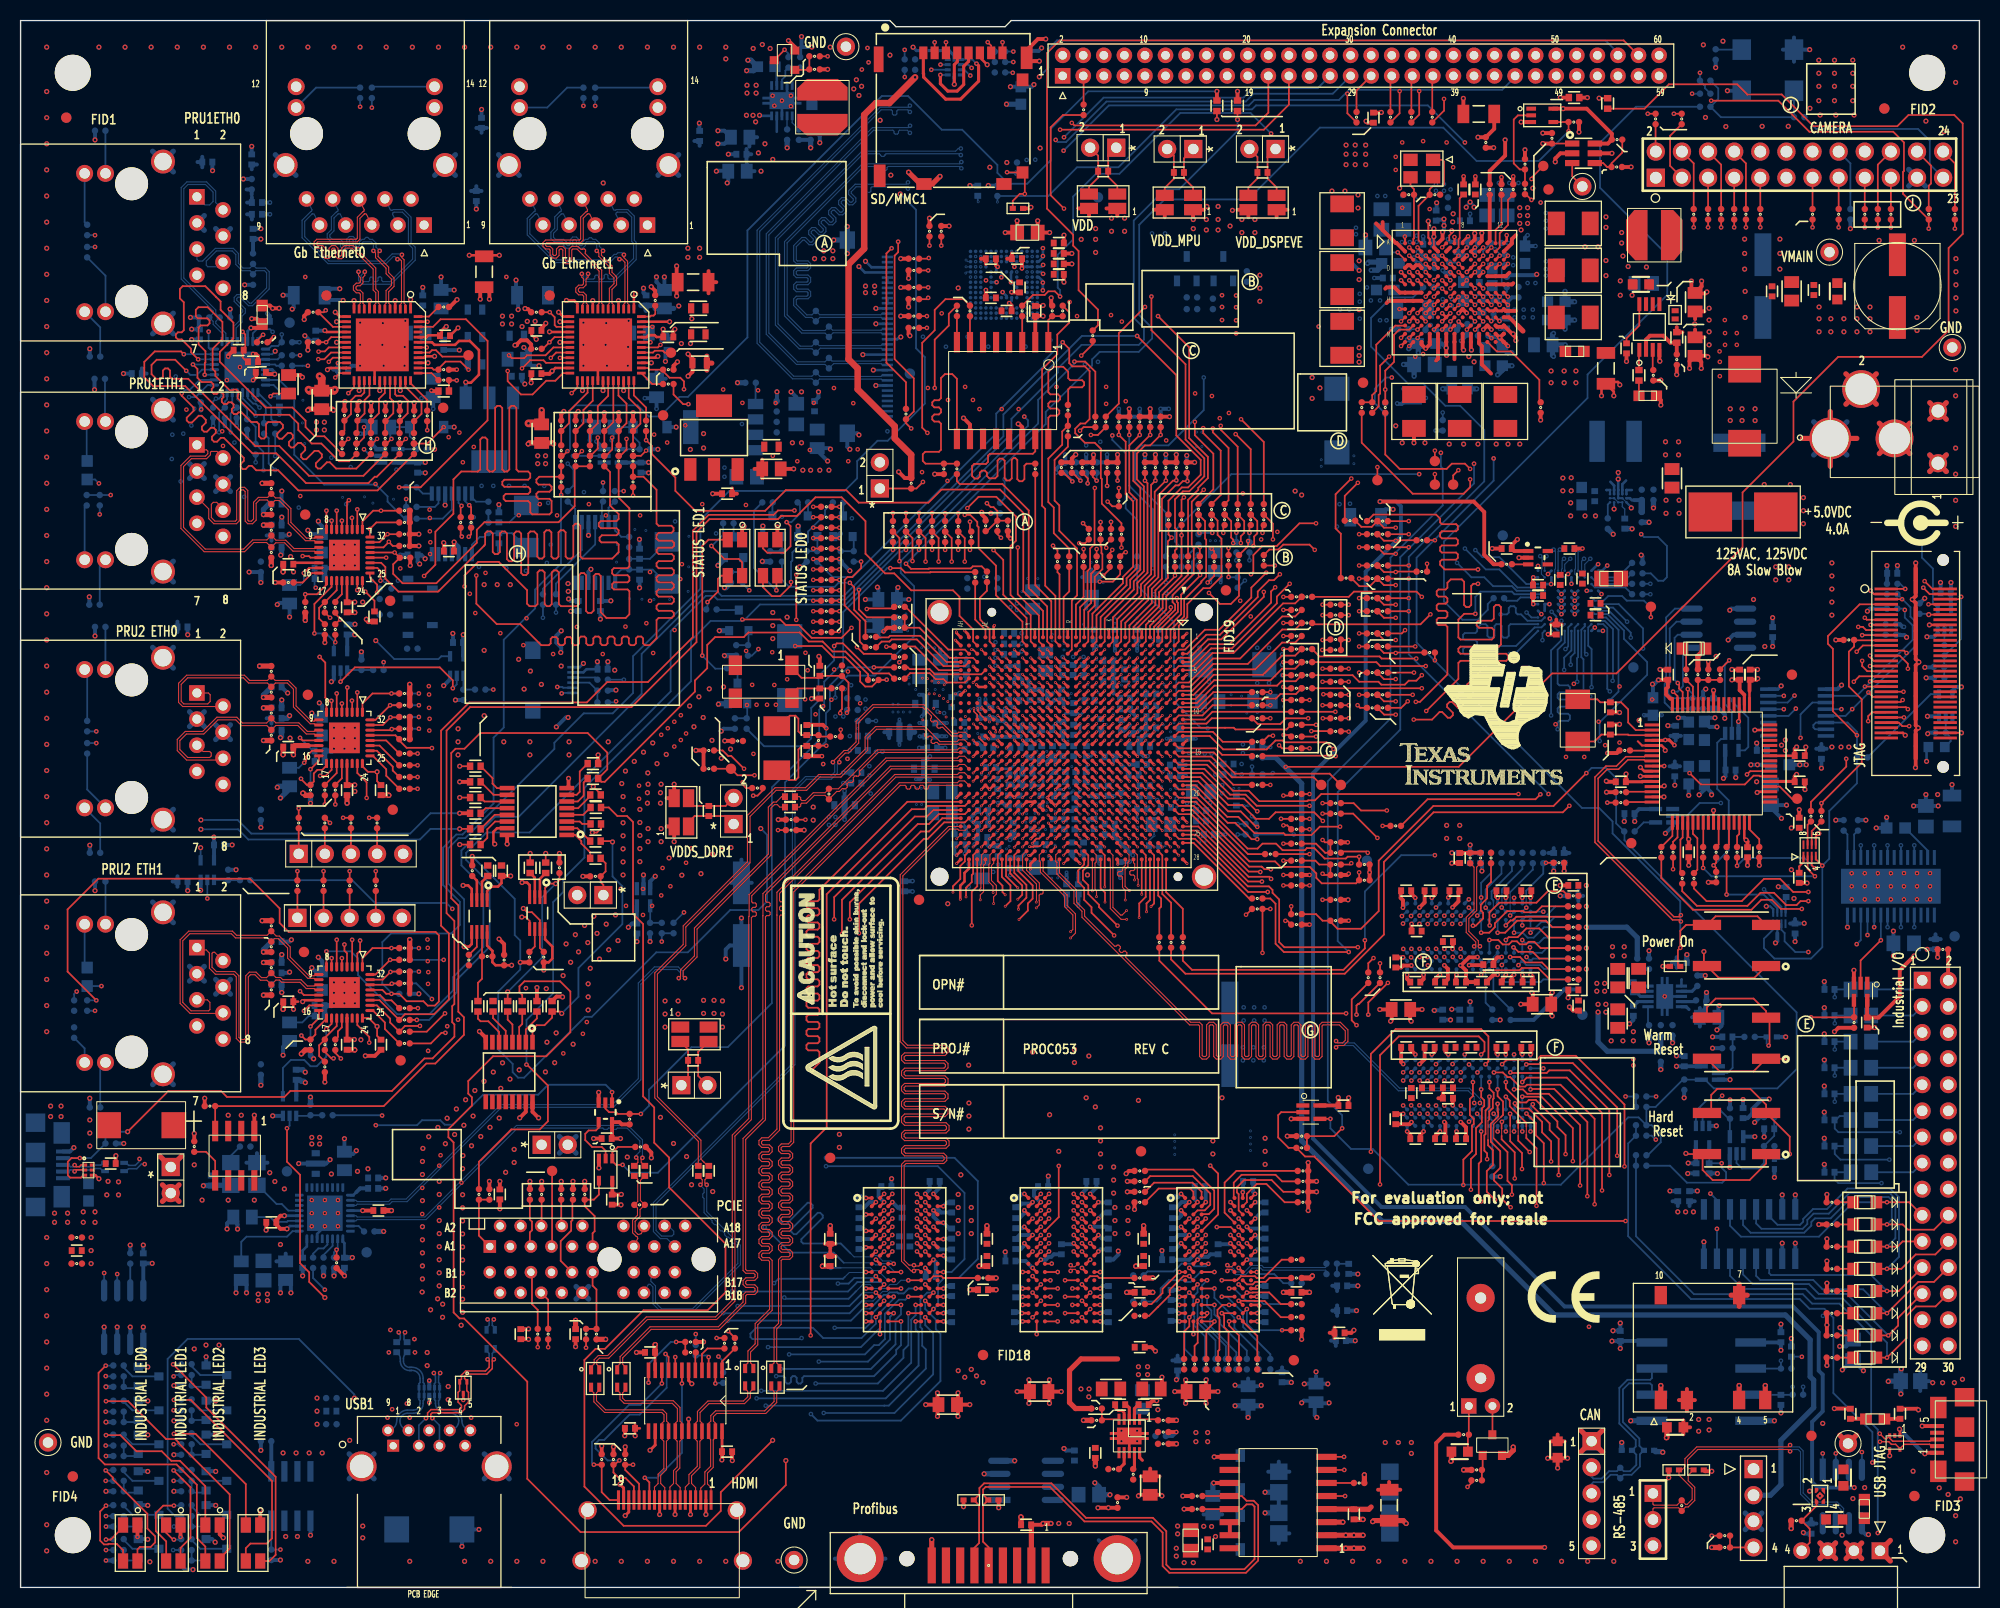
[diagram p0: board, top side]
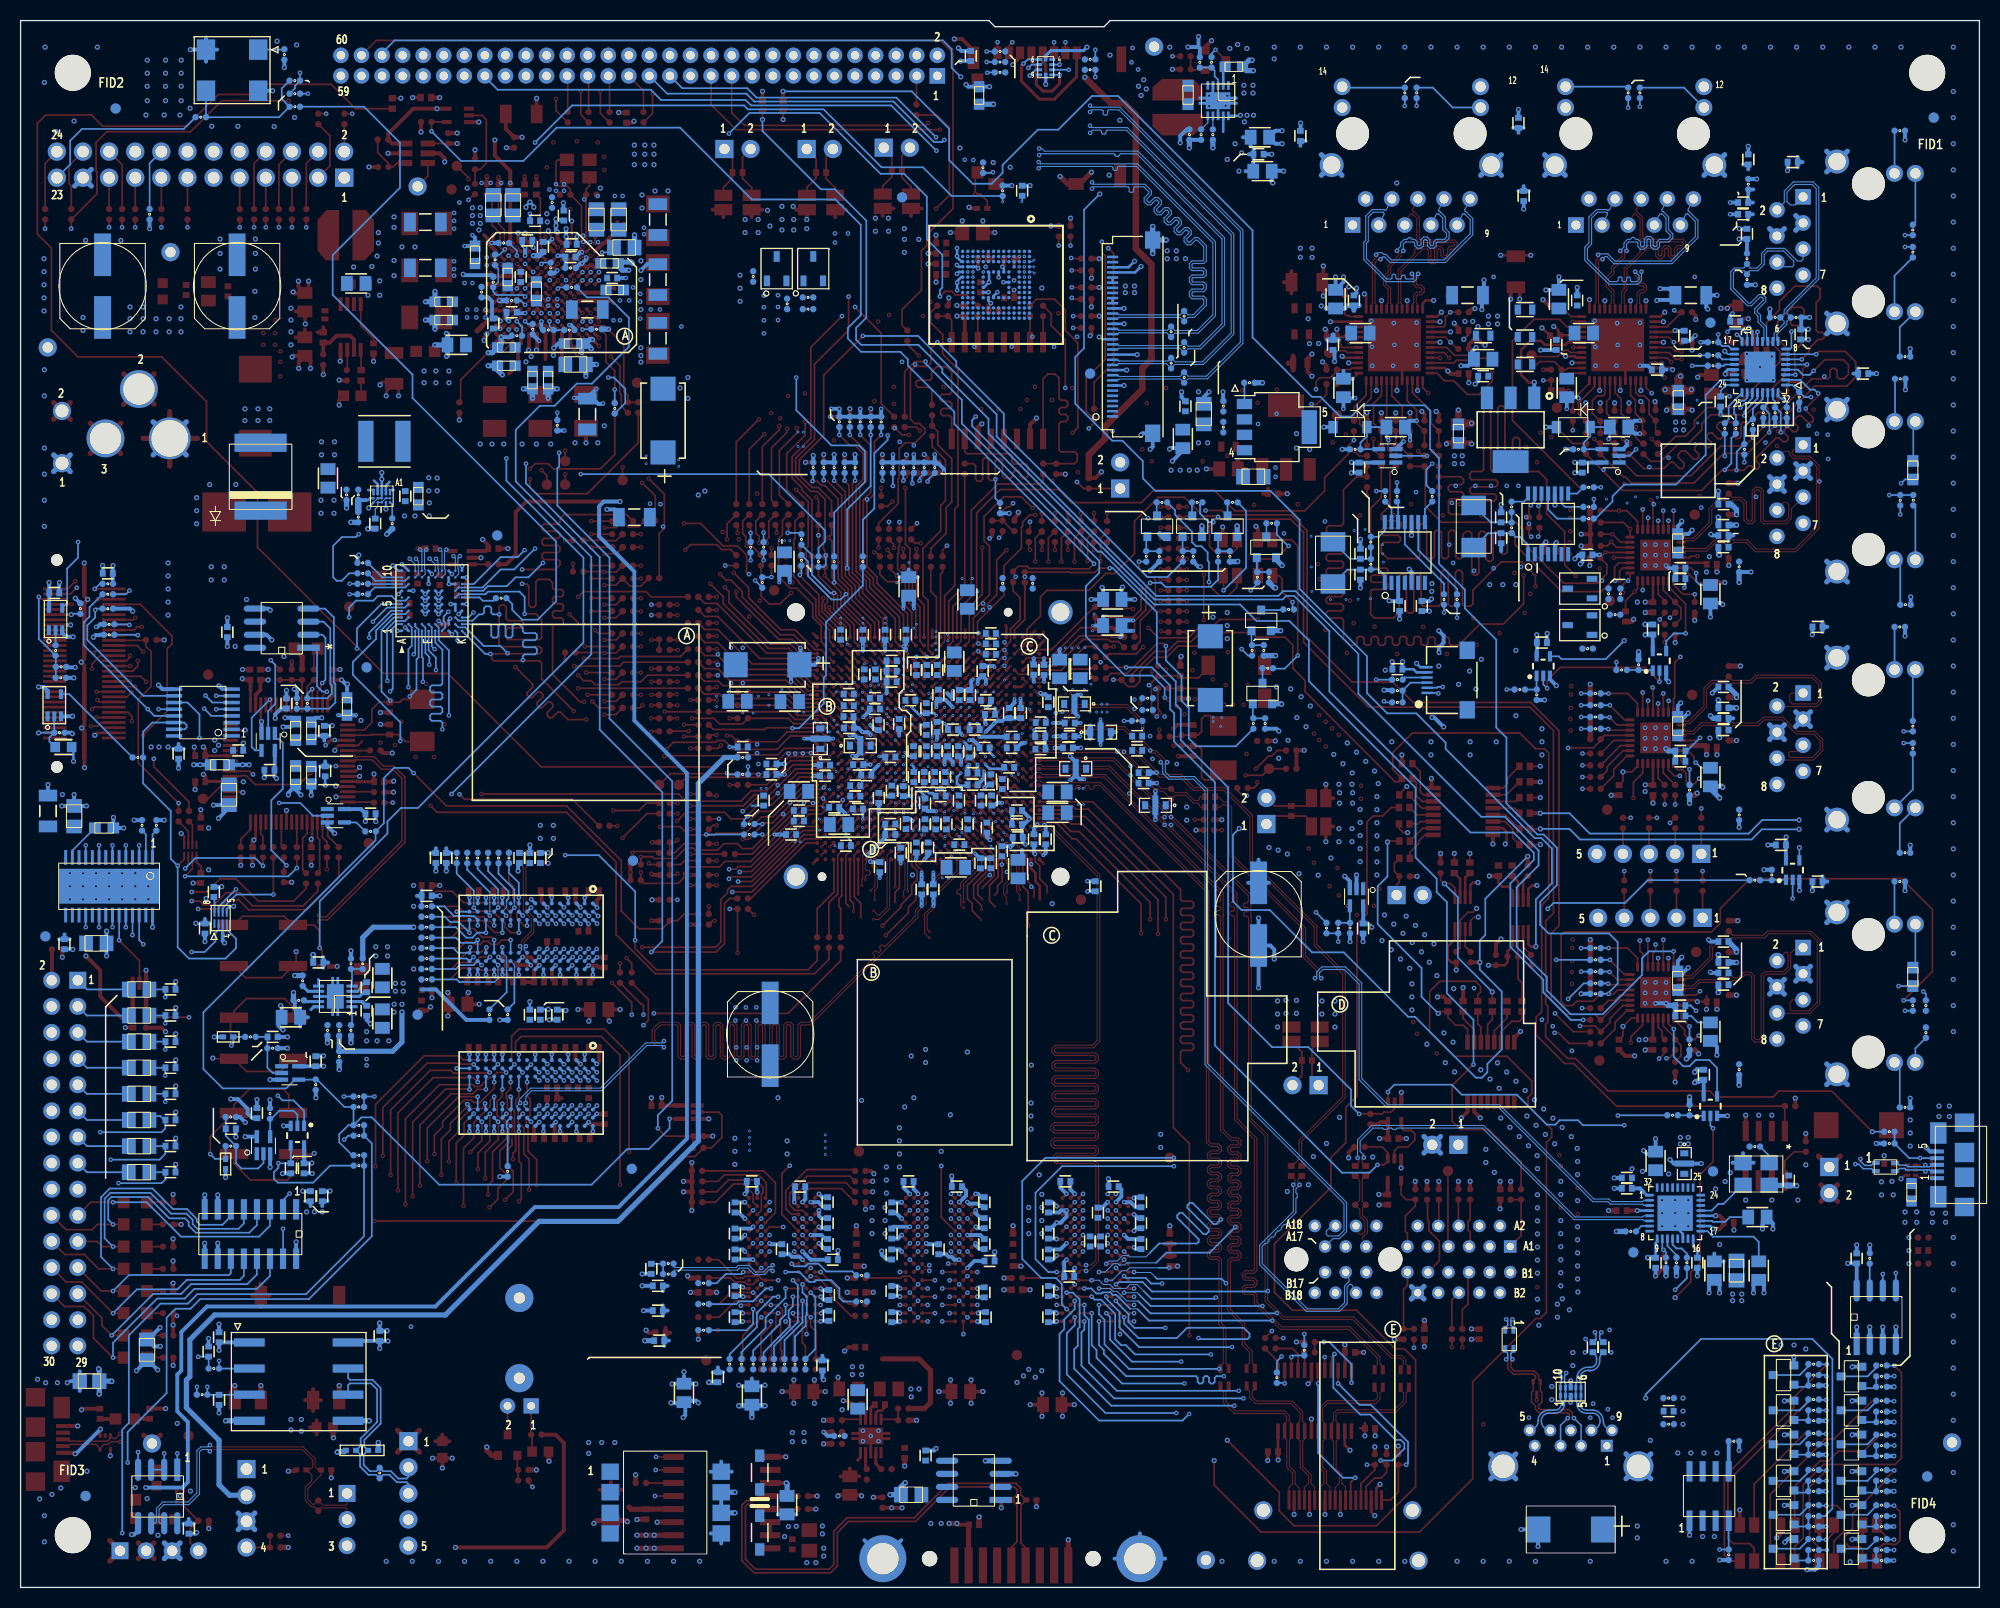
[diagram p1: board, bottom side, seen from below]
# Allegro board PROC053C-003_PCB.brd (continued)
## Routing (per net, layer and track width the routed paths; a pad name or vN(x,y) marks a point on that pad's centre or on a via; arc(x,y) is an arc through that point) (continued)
PRU2ETH1_TXD0: length 100.5
  TOP w0.173: U17.4 31.75,61.68 31.5,61.93 v2(31.5,62.53) ; R206.1 v7(77.09,94.95)
  L3_SIG1 w0.109: v7(77.09,94.95) v5(76.45,94.95)
  L10_SIG4 w0.109: v2(31.5,62.53) 32.05,62.53 32.28,62.31 34.8,62.31 36.47,63.98 40.89,63.98 43.24,66.33 43.24,67.42 42.24,68.42 42.24,72.57 43.23,73.56 43.23,75.08 46,77.85 54.38,77.85 57.36,74.87 64.38,74.87 64.54,75.03 64.54,76.24 64.7,76.4 64.93,76.4 65.09,76.24 65.09,75.03 65.25,74.87 65.47,74.87 65.63,75.03 65.63,76.24 65.79,76.4 66.02,76.4 66.18,76.24 66.18,75.03 66.34,74.87 66.57,74.87 66.73,75.03 66.73,76.24 66.89,76.4 67.11,76.4 67.27,76.24 67.27,75.03 67.43,74.87 68.27,74.87 68.83,75.43 70.09,75.43 70.69,76.02 70.69,77.77 70.43,78.02 67.84,78.02 67.7,78.16 67.7,78.36 67.84,78.5 70.67,78.5 70.81,78.64 70.81,78.84 70.67,78.98 67.84,78.98 67.7,79.12 67.7,79.32 67.84,79.46 70.67,79.46 71.07,79.86 71.07,87.28 74.04,90.25 74.04,92.27 74.15,92.38 74.69,92.38 74.8,92.49 74.8,92.71 74.69,92.82 74.15,92.82 74.04,92.93 74.04,94.54 74.45,94.95 v5(76.45,94.95)
PRU2ETH1_TXD1: length 105.9
  TOP w0.173: U17.5 31.25,61.21 v2(31.25,61.21) ; R208.1 v7(77.09,92.92)
  L3_SIG1 w0.109: v7(77.09,92.92) v5(76.45,92.92)
  L10_SIG4 w0.109: v5(76.45,92.92) 76.45,91.42 74.16,89.13 74.16,76.41 73.2,75.45 73.2,73.05 72.84,72.68 72.36,72.68 71.57,73.48 71.34,73.48 71.18,73.32 71.18,73.09 71.98,72.3 71.98,72.07 71.82,71.91 71.59,71.91 70.8,72.7 70.57,72.7 70.41,72.54 70.41,72.32 71.2,71.53 71.2,71.3 71.04,71.14 70.82,71.14 70.02,71.93 69.8,71.93 69.64,71.77 69.64,71.55 70.43,70.75 70.43,70.28 69.96,69.81 66.6,69.81 66.29,70.13 66.29,72.43 66.13,72.59 65.9,72.59 65.74,72.43 65.74,70.13 65.58,69.97 65.36,69.97 65.2,70.13 65.2,72.36 65.04,72.52 64.81,72.52 64.65,72.36 64.65,70.13 64.49,69.97 64.26,69.97 64.1,70.13 64.1,71.75 63.94,71.91 63.72,71.91 63.56,71.75 63.56,70.13 63.4,69.97 62.67,69.97 62.38,70.26 62.38,71.77 62.22,71.93 61.99,71.93 61.83,71.77 61.83,70.33 61.7,70.2 61.32,70.2 60.3,71.22 57.73,71.22 56.3,72.65 56.3,73.5 54.53,75.27 54.53,75.79 53.31,77.01 46.61,77.01 44.44,74.84 44.44,70.65 43.92,70.13 43.92,66.61 43.92,66.61 43.92,66.05 41.16,63.3 39.04,63.3 37.36,61.62 35.64,61.62 35.22,61.21 v2(31.25,61.21)
PRU2ETH1_TXD2: length 102.7
  TOP w0.173: U17.6 v2(30.75,62.99) ; R210.1 v7(77.09,96.98)
  L3_SIG1 w0.109: v7(77.09,96.98) v5(76.45,96.98)
  L10_SIG4 w0.109: v5(76.45,96.98) 76.45,97.31 76.3,97.46 75.37,97.46 74.07,96.17 68.23,96.17 65.24,93.18 65.24,93.02 66.34,91.92 66.34,91.77 66.19,91.61 66.03,91.61 64.93,92.71 64.77,92.71 64.62,92.56 64.62,92.4 65.72,91.3 65.72,91.15 65.57,90.99 65.41,90.99 64.31,92.1 64.16,92.1 64,91.94 64,91.79 65.1,90.68 65.1,90.53 64.95,90.37 64.79,90.37 63.69,91.48 63.54,91.48 63.38,91.32 63.38,91.17 64.49,90.07 64.49,89.91 64.33,89.76 64.18,89.76 63.07,90.86 62.92,90.86 62.76,90.7 62.76,90.55 63.87,89.45 63.87,89.29 63.71,89.14 63.56,89.14 62.46,90.24 62.3,90.24 62.15,90.09 62.15,89.93 63.25,88.83 63.25,88.67 63.09,88.52 62.94,88.52 61.84,89.62 61.68,89.62 61.53,89.47 61.53,89.31 62.63,88.21 62.63,88.06 62.48,87.9 62.32,87.9 61.22,89 61.06,89 60.91,88.85 60.91,88.7 62.01,87.59 62.01,87.44 61.86,87.28 61.7,87.28 60.6,88.39 60.45,88.39 60.29,88.23 60.29,88.08 61.39,86.97 61.39,86.82 61.24,86.67 61.08,86.67 59.98,87.77 59.83,87.77 59.61,87.55 59.61,85.98 59,85.37 43.26,85.37 41.43,83.54 41.43,77.47 40.18,76.22 40.18,71.82 36.23,67.87 33.05,67.87 30.75,65.57 v2(30.75,62.99)
PRU2ETH1_TXD3: length 107
  TOP w0.173: v2(30.25,61.21) 30.25,61.21 U17.7 ; R207.1 v7(77.09,93.93)
  L3_SIG1 w0.109: v7(77.09,93.93) v5(76.45,93.93)
  L10_SIG4 w0.109: v2(30.25,61.21) 30.89,61.85 34.95,61.85 36.75,63.64 41.03,63.64 43.58,66.19 43.58,69.6 43.33,69.85 43.33,72.75 43.87,73.28 43.87,74.96 46.3,77.39 54.08,77.39 55.45,76.02 55.45,75.26 57.39,73.32 57.8,73.32 58.22,73.74 60.32,73.74 60.86,73.2 68.25,73.2 68.48,72.97 69.93,72.97 71.83,74.88 71.83,75.41 73.05,76.63 73.05,77.69 72.8,77.94 72.07,77.94 71.96,78.05 71.96,78.27 72.07,78.38 73.22,78.38 73.33,78.49 73.33,78.71 73.22,78.82 72.07,78.82 71.96,78.93 71.96,79.15 72.07,79.25 73.22,79.25 73.33,79.36 73.33,79.58 73.22,79.69 72.07,79.69 71.96,79.8 71.96,80.02 72.07,80.13 73.22,80.13 73.33,80.24 73.33,80.46 73.22,80.57 72.07,80.57 71.96,80.67 71.96,80.89 72.07,81 73.22,81 73.33,81.11 73.33,81.33 73.22,81.44 72.07,81.44 71.96,81.55 71.96,81.77 72.07,81.88 73.22,81.88 73.33,81.99 73.33,82.2 73.22,82.31 72.07,82.31 71.96,82.42 71.96,82.64 72.07,82.75 73.22,82.75 73.33,82.86 73.33,83.08 73.22,83.19 72.07,83.19 71.96,83.3 71.96,83.51 72.07,83.62 73.22,83.62 73.33,83.73 73.33,83.95 73.22,84.06 72.07,84.06 71.96,84.17 71.96,84.39 72.07,84.5 73.22,84.5 73.33,84.61 73.33,84.83 73.22,84.93 72.07,84.93 71.96,85.04 71.96,85.26 72.07,85.37 73.22,85.37 73.33,85.48 73.33,85.7 73.22,85.81 72.07,85.81 71.96,85.92 71.96,86.14 72.07,86.24 73.22,86.24 73.33,86.35 73.33,86.57 73.22,86.68 72.07,86.68 71.96,86.79 71.96,87.01 72.07,87.12 73.22,87.12 73.33,87.23 73.33,88.86 75.9,91.43 75.9,93.38 v5(76.45,93.93)
PRU2ETH1_TXEN: length 121.9
  TOP w0.173: R205.1 v7(77.09,98) ; v2(27.05,75.77) R115.2 ; U17.3 v2(32.25,62.99)
  L3_SIG1 w0.109: v7(77.09,98) v5(76.45,98)
  L4_SIG2 w0.114: v2(27.05,75.77) 24.66,73.38 24.66,65.43 26.49,63.6 31.64,63.6 v2(32.25,62.99)
  L10_SIG4 w0.109: v2(32.25,62.99) 33.27,64.02 33.27,65.51 34.75,66.98 35.82,66.98 40.51,71.68 40.51,75.64 42.65,77.77 43.1,77.77 45.09,79.76 57.81,79.76 61.17,83.11 61.89,83.11 63.11,81.9 63.3,81.9 63.45,82.04 63.45,82.23 62.05,83.63 62.05,83.83 62.19,83.97 62.39,83.97 63.53,82.83 63.73,82.83 63.87,82.97 63.87,83.17 62.83,84.21 62.83,84.4 62.97,84.55 63.17,84.55 63.7,84.02 63.9,84.02 64.04,84.16 64.04,84.36 62.57,85.83 62.57,86.02 62.71,86.16 62.91,86.16 64.76,84.31 64.96,84.31 65.1,84.45 65.1,84.65 63.25,86.5 63.25,86.7 64.63,88.08 64.79,88.08 65.46,87.41 65.61,87.41 65.77,87.56 65.77,87.72 65.09,88.39 65.09,88.55 65.25,88.7 65.4,88.7 66.08,88.03 66.23,88.03 66.39,88.18 66.39,88.34 65.71,89.01 65.71,89.16 65.87,89.32 66.02,89.32 66.7,88.64 66.85,88.64 67.01,88.8 67.01,88.95 66.33,89.63 66.33,89.78 66.49,89.94 66.64,89.94 67.32,89.26 67.47,89.26 67.62,89.42 67.62,89.57 66.95,90.25 66.95,90.4 67.1,90.56 67.26,90.56 67.93,89.88 68.09,89.88 68.24,90.04 68.24,90.19 67.57,90.86 67.57,91.02 68.83,92.28 69.24,92.28 69.35,92.17 69.35,90.79 69.46,90.68 69.68,90.68 69.79,90.79 69.79,92.17 69.9,92.28 70.12,92.28 70.22,92.17 70.22,90.79 70.33,90.68 70.55,90.68 70.66,90.79 70.66,92.17 70.77,92.28 70.99,92.28 71.87,93.16 71.87,94.65 72.9,95.69 75.27,95.69 76.02,96.44 76.71,96.44 77.09,96.82 77.09,97.36 v5(76.45,98)
PRU2ETHER0_RDN: length 23.6
  TOP w0.108: U15.9 28.67,84.38 28.55,84.26 28.27,84.26 26.79,85.74 26.79,87.47 26.05,88.22 24.77,88.22 R182.2 24,88.22 22.28,88.22 21.77,88.73 16.15,88.73 15.37,87.94 15.37,86.08 15.77,85.68 19.64,85.68 J6.2
PRU2ETHER0_RDP: length 23.6
  TOP w0.108: U15.10 28.67,83.88 28.55,84 28.17,84 26.54,85.63 26.54,87.37 25.94,87.97 24.78,87.97 24.4,87.58 R183.2 24,87.97 22.17,87.97 21.67,88.47 16.26,88.47 15.62,87.84 15.62,86.19 15.88,85.93 18.2,85.93 18.44,86.17 18.44,86.82 18.27,87 J6.1
PRU2ETHER0_TDN: length 21.7
  TOP w0.108: J6.6 19.52,80.47 16.15,80.47 15.24,81.38 15.24,82.48 16.02,83.26 17.71,83.26 18.39,83.94 18.39,83.94 19.09,84.64 21.03,84.64 21.59,84.08 23.93,84.08 R184.2 24.83,84.09 27.06,84.09 27.89,83.27 28.55,83.27 28.66,83.38 U15.11
PRU2ETHER0_TDP: length 21.7
  TOP w0.108: U15.12 28.68,82.88 28.55,83.01 27.78,83.01 26.96,83.84 24.83,83.84 R185.2 23.95,83.82 21.48,83.82 20.93,84.38 19.19,84.38 18.49,83.68 17.81,83 16.12,83 15.49,82.38 15.49,81.49 16.26,80.73 18.39,80.73 18.54,80.88 18.54,81.16 18.39,81.31 17.76,81.31 J6.5
PRU2ETHER1_RDN: length 27.4
  TOP w0.108: U17.9 28.67,59.62 28.55,59.49 28.04,59.49 26.22,61.31 26.22,62.3 25.17,63.36 24.86,63.36 R224.2 23.98,63.43 21.01,63.43 20.6,63.84 16.35,63.84 15.52,63 15.52,56.8 16.48,55.83 19.64,55.83 J8.6
PRU2ETHER1_RDP: length 27.3
  TOP w0.108: J8.5 18.16,57.15 18.41,56.9 18.41,56.22 18.29,56.09 16.59,56.09 15.77,56.9 15.77,62.9 16.46,63.58 20.5,63.58 20.9,63.17 24.03,63.17 R225.2 24.4,62.82 24.68,63.1 25.06,63.1 25.97,62.2 25.97,61.21 27.94,59.24 28.55,59.24 28.67,59.12 U17.10
PRU2ETHER1_TDN: length 26.9
  TOP w0.108: U17.11 28.66,58.62 28.55,58.5 27.89,58.5 27.28,59.11 25.5,59.11 25.29,59.33 24.83,59.33 R226.2 23.93,59.31 23.43,59.31 22.9,59.85 22.25,59.85 21.89,59.49 21.89,53.45 21.74,53.29 21.44,53.29 21.23,53.5 21.23,59.49 20.83,59.9 19.05,59.9 18.62,60.33 18.62,61.68 18.72,61.78 18.87,61.78 J8.2
PRU2ETHER1_TDP: length 27.3
  TOP w0.108: J8.1 17.38,62.01 18.06,62.01 18.36,61.7 18.36,60.22 18.94,59.64 20.72,59.64 20.98,59.39 20.98,53.39 21.33,53.04 21.85,53.04 22.15,53.34 22.15,59.39 22.36,59.59 22.79,59.59 23.33,59.06 23.95,59.06 R227.2 24.83,59.07 25.18,59.07 25.4,58.86 27.17,58.86 27.78,58.25 28.55,58.25 28.68,58.12 U17.12
PTP_PPS_OE: length 4.1
  TOP w0.173: R973.1 56.9,70.44 56.9,69.65 R948.1 56.41,68.6 56.68,68.34 J51.1
QSPI_CLK: length 15.3
  TOP w0.173: R24.1 101.98,101.05 100.48,102.54 100.48,105.03 99.95,105.57 99.95,109.8 101.3,111.15 101.3,112.43 R23.1 R31.2
RS485_A: length 33.1
  TOP w0.108: v2(172.09,13.85) 171.91,13.67 163,13.67 161.86,12.53 161.86,11.75 161.54,11.43 U82.1 161.28,10.92 162.56,9.64 162.56,8.56 162.08,8.08 161.93,8.08 R729.2 161.08,8 158.86,8 158.75,8.11 J39.1
  BOTTOM w0.108: v2(172.09,13.85) 172.26,13.67 172.97,13.67 173.36,13.29 173.36,9.19 174.23,8.31 176.67,8.31 177.29,7.68 177.29,6.35 177.4,6.24 U77.6
RS485_B: length 32.7
  TOP w0.108: J39.2 158.75,7.64 158.86,7.75 161.24,7.75 R729.1 161.93,7.83 162.18,7.83 162.81,8.46 162.81,9.75 162.18,10.38 162.18,10.91 U83.1 162.57,11.56 162.22,11.56 162.12,11.66 162.12,12.42 163.11,13.42 171.91,13.42 v2(172.09,13.24)
  BOTTOM w0.108: v2(172.09,13.24) 172.26,13.42 172.87,13.42 173.1,13.18 173.1,9.08 174.13,8.05 176.56,8.05 177.04,7.58 177.04,6.35 176.93,6.24 U77.7
RSTOUTTOPMIC: length 95.2
  TOP w0.173: v2(128.52,44.66) 127.76,43.9 R793.2 R36.1 ; U3.E6 v2(139.04,127.14)
  L4_SIG2 w0.114: v2(139.04,127.14) 138,127.14 137.5,126.65 137.5,124.23 137.82,123.91 137.82,119.47 137.27,118.92 137.27,112.35 137.56,112.06 137.56,110.93 v2(138.13,110.36)
  BOTTOM w0.173: v2(138.13,110.36) 138.13,109.02 138.3,108.84 138.3,105.24 133.22,100.16 133.22,84.51 127.13,78.41 127.13,47.33 128.52,45.93 v2(128.52,44.66)
RTCK: length 92.3
  TOP w0.173: 124.59,73.74 v7(125.35,73.74) ; v7(178.59,82.89) 176.25,85.22 176.25,91.29 175.77,91.78 175.77,92.54 178.85,95.62 J18.7
  L3_SIG1 w0.109: v7(178.59,82.89) 174.62,82.89 173.61,83.9 170.69,83.9 169.57,85.02 167.11,85.02 165.25,83.16 161.87,83.16 160.68,84.36 158.88,84.36 155.14,80.62 153.14,80.62 152.4,81.36 149.99,81.36 148.46,79.83 133.12,79.83 132.15,78.86 132.15,78.71 132.87,77.99 132.87,77.83 132.72,77.68 132.56,77.68 131.84,78.4 131.69,78.4 131.53,78.25 131.53,78.09 132.25,77.37 132.25,77.22 132.1,77.06 131.94,77.06 131.22,77.78 131.07,77.78 130.91,77.63 130.91,77.47 131.63,76.75 131.63,76.6 131.48,76.44 131.32,76.44 130.6,77.16 130.45,77.16 130.29,77.01 130.29,76.86 131.02,76.13 131.02,75.98 130.86,75.82 130.71,75.82 129.98,76.55 129.83,76.55 129.68,76.39 129.68,76.24 130.4,75.51 130.4,75.36 130.24,75.21 130.09,75.21 129.37,75.93 129.21,75.93 129.06,75.77 129.06,75.62 129.78,74.9 129.78,74.74 129.62,74.59 129.47,74.59 128.75,75.31 128.59,75.31 127.03,73.74 v7(125.35,73.74)
SERDES_REF_CLKN: length 70
  TOP w0.108: C438.1 73.83,75.9 73.6,76.13 73.31,76.13 72.97,75.79 72.97,71.22 65.79,64.03 65.79,61.32 64.44,59.97 64.44,59.44 v2(64.62,59.26)
  BOTTOM w0.108: U45.2 32.62,37.65 32.74,37.53 35.79,37.53 36.03,37.77 37.49,37.77 46.67,46.96 57.54,46.96 60.07,49.48 60.07,58.78 61.64,60.36 63.96,60.36 64.44,59.88 64.44,59.44 v2(64.62,59.26)
SERDES_REF_CLKP: length 70.1
  TOP w0.108: C439.1 74.02,76.92 73.49,76.39 73.21,76.39 72.72,75.9 72.72,71.33 65.53,64.14 65.53,61.42 64.18,60.07 64.18,59.44 v2(64.01,59.26)
  BOTTOM w0.108: U45.3 32.62,37.15 32.74,37.28 35.89,37.28 36.14,37.52 37.6,37.52 46.78,46.7 57.65,46.7 60.32,49.38 60.32,58.68 61.75,60.1 63.86,60.1 64.19,59.77 64.19,59.44 v2(64.01,59.26)
SPI2_CS0N: length 129.4
  TOP w0.173: v2(120.72,68.66) 120.72,68.66 119.38,68.66 114.43,73.62 112.63,73.62 U1.B24
  L4_SIG2 w0.114: v5(149.23,143.21) 148.76,142.75 148.76,140.21 145.06,136.5 145.06,133.63 v5(143.92,132.49)
  L9_SIG3 w0.114: v2(120.72,68.66) 120.02,69.36 120.02,70.64 122.85,73.47 124.05,73.47 126.24,75.66 126.24,82.81 133.38,89.95 133.38,92.69 141.48,100.79 141.48,104.37 150.7,113.59 150.7,118.69 150.24,119.15 150.24,121.67 148.41,123.49 148.41,129.97 146.89,131.5 144.98,131.5 143.99,132.49 v5(143.92,132.49)
  L10_SIG4 w0.109: J21.30 130.32,149.99 131.78,149.99 132.33,149.43 132.33,148.6 132.92,148.01 133.83,148.01 134.32,147.53 134.32,146.31 136.4,144.23 148.21,144.23 v5(149.23,143.21)
SPI2_DIN: length 143.1
  TOP w0.173: U1.G17 v4(108.63,79.22)
  L3_SIG1 w0.109: v4(108.63,79.22) v5(109.03,78.97)
  L4_SIG2 w0.114: v5(109.03,78.97) 109.42,79.35 114.76,79.35 114.99,79.58 116.01,79.58 117.37,80.94 117.37,82.2 118.43,83.26 122.96,83.26 123.26,82.95 125.39,82.95 129.11,86.67 129.11,87.45 131.31,89.65 138.95,89.65 143.84,94.54 143.84,96.84 148.37,101.37 148.37,107.55 154.31,113.49 161.16,113.49 v5(163.7,116.03)
  L10_SIG4 w0.109: v5(163.7,116.03) 164.08,116.41 164.08,118.7 163.48,119.31 163.48,126.33 163.99,126.85 163.99,131.79 160.4,135.38 160.4,139.87 157.95,142.32 149.36,142.32 147.73,143.94 136.28,143.94 134.24,145.98 127.01,145.98 126.36,146.63 126.36,148 J21.26
SPI2_DOUT: length 130.2
  TOP w0.173: v2(120.57,69.59) 120.53,69.63 119.43,69.63 113.84,75.22 112.63,75.22 112.23,75.61 U1.B22
  L4_SIG2 w0.114: v2(147.83,134.7) 147.92,134.79 147.92,138.62 149.31,140.01 149.31,142.15 v5(150.77,143.61)
  L9_SIG3 w0.114: v2(120.57,69.59) 120.57,70.58 122.97,72.98 124.11,72.98 126.67,75.54 126.67,76.37 128.6,78.31 128.6,79.45 129.21,80.06 129.21,84.33 133.78,88.9 133.78,92.41 141.86,100.48 141.86,104.29 152.53,114.96 152.53,117.93 150.72,119.74 150.72,125.45 150.16,126.01 150.16,132.36 v2(147.83,134.7)
  L10_SIG4 w0.109: J21.28 128.72,150.4 133.43,150.4 134.34,149.48 134.34,148.59 134.92,148.01 135.76,148.01 136.35,147.43 136.35,146.31 137.22,145.44 141.63,145.44 142.01,145.06 148.56,145.06 149.25,144.37 150.47,144.37 150.77,144.07 v5(150.77,143.61)
SPI2_SCLK: length 144.1
  TOP w0.173: R684.2 121.54,67.01 122.05,66.5 122.05,62.61 122.85,61.8 v2(129.16,61.8)
  L3_SIG1 w0.109: v2(141.35,109.3) 141.73,108.92 145.42,108.92 150.75,114.25 150.75,134.09 146.15,138.69 145.57,138.69 143.59,140.66 142.64,140.66 142.04,140.06 138.79,140.06 135.55,136.82 122.98,136.82 120.83,138.97 120.83,143.26 122.35,144.78 122.35,148.03 J21.24
  BOTTOM w0.173: v2(129.16,61.8) 128.09,62.87 128.09,77.35 134.18,83.43 134.18,100.21 141.35,107.38 v2(141.35,109.3)
SPIMEM_CLK: length 18.2
  TOP w0.173: U4.16 99.95,113.77 100.15,113.97 100.81,113.97 101.02,114.18 101.02,114.46 100.81,114.66 100.15,114.66 99.95,114.87 99.95,115.15 100.15,115.35 100.89,115.35 101.09,115.56 101.09,115.84 100.89,116.05 100.15,116.05 99.95,116.25 99.95,118.22 100.46,118.72 101.4,118.72 101.88,118.24 101.88,117.62 102.08,117.42 103.23,117.42 103.43,117.22 103.43,116.93 103.23,116.73 102.08,116.73 101.88,116.53 101.88,115.04 R31.1
SPIMEM_CSN: length 2.5
  TOP w0.173: R30.1 92.33,121.11
SPIMEM_D0: length 25.6
  TOP w0.173: R25.1 97.83,109.3 97.62,109.1 97.62,107.79 97.42,107.59 97.14,107.59 96.93,107.8 96.93,109.66 96.74,109.85 96.56,109.85 96.39,109.69 96.39,107.87 96.19,107.67 95.9,107.67 95.7,107.87 95.7,109.59 95.49,109.79 95.21,109.79 95.01,109.6 95.01,108.11 94.78,107.88 94.2,107.88 93.98,108.11 93.98,108.42 93.77,108.63 93.49,108.63 93.29,108.42 93.29,108.06 93.08,107.85 92.78,107.85 92.53,108.1 92.53,109.07 92.74,109.27 93.89,109.27 94.09,109.47 94.09,110.09 94.26,110.26 98.44,110.26 98.68,110.5 U4.15
SPIMEM_D1: length 2.5
  TOP w0.173: R26.1 U4.8
SPIMEM_D2: length 23.2
  TOP w0.173: U4.9 91.06,117.56 90.6,118.01 89.89,118.01 89.51,117.63 89.51,115.67 89.31,115.47 88.86,115.47 88.66,115.27 88.66,114.98 88.86,114.78 89.31,114.78 89.51,114.58 89.51,114.29 89.31,114.09 88.86,114.09 88.66,113.89 88.66,113.6 88.86,113.4 89.31,113.4 89.51,113.2 89.51,110.65 89.31,110.45 87.97,110.45 87.74,110.22 87.74,109.57 88.01,109.3 R22.1 R27.1
SPIMEM_D3: length 3.7
  TOP w0.173: U4.1 99.95,123.27 R799.1 R28.1
SRCCLK: length 74.3
  BOTTOM w0.173: R276.1 157.1,144.02 153.6,140.52 153.6,136.14 160.14,129.6 160.14,125.73 152.39,117.97 152.39,115.69 138.42,101.73 138.42,95.91 140.21,94.12 141.72,94.12 142.68,95.09 142.68,95.65 R586.2
SYS_RESETN: length 300.7
  TOP w0.173: R29.2 98.45,125.71 99.59,125.71 99.95,126.07 100.58,126.07 v2(101.09,125.56)
  L3_SIG1 w0.109: J21.25 121.62,143.29 v2(121.62,141.41)
  L9_SIG3 w0.114: v2(121.62,141.41) 122.75,142.54 126.24,142.54 126.7,142.09 139.19,142.09 141.61,144.51 148.39,144.51 149.33,145.44 150.01,145.44 152.15,143.31 152.15,138.81 150.62,137.29 150.62,126.77 151.38,126.01 151.38,119.61 152.98,118.01 152.98,113 157.61,108.38 v2(157.61,102.44) 158.37,101.68 181.36,101.68 186.18,96.86 186.18,82.38 182.63,78.82 182.63,64.07 182.65,64.05 182.65,52.45 182.22,52.02 182.22,42.24 182.65,41.81 182.65,22.07 180.88,20.31 180.88,12.94 v2(180.09,12.15)
  BOTTOM w0.173: R566.2 158.54,98.63 159.26,97.91 159.76,97.91 160.11,98.26 160.11,101.3 159.24,102.16 157.89,102.16 v2(157.61,102.44) ; v2(121.62,141.41) 119.61,143.41 112.78,143.41 106.86,137.5 104.58,137.5 102.36,135.28 102.36,131.12 100.86,129.62 100.86,126.42 101.09,126.19 v2(101.09,125.56) ; v2(180.09,12.15) 180.09,15.11 176.3,18.9 176.3,26.23 175.43,27.1 173.97,27.1 173.03,28.05 162.45,28.05 156.34,34.16 156.34,43.18 157.1,43.94 157.1,44.96
SYS_WARMRESETN: length 198.4
  TOP w0.173: v2(152.27,79.2) 149.08,76.01 137.39,76.01 132.08,70.69 132.08,65.79 130.36,64.07 128.07,64.07 127.38,64.76 R2.1 126.62,64.85 125.98,65.49 124.59,65.49 ; U47.4 v2(127.38,45.58)
  L3_SIG1 w0.109: v5(158.62,100.92) 159.39,101.68 v2(184.91,101.68)
  L10_SIG4 w0.109: v5(158.62,100.92) 158.62,99.7 160.3,98.02 160.3,88.56 159.13,87.39 159.13,87.36 159.12,87.35 159.12,86.18 158.26,85.31 158.26,82.77 154.69,79.2 v2(152.27,79.2)
  BOTTOM w0.173: U78.4 185.98,95.73 185.98,99.09 184.91,100.16 v2(184.91,101.68) ; R918.2 157.35,45.72 156.34,45.72 149.79,39.17 134.97,39.17 131.49,42.65 129.39,42.65 127.38,44.66 v2(127.38,45.58) ; R918.2 158.62,44.96 159.51,44.07 159.51,43.31 158.24,42.04 R915.2 ; R918.2 R919.2 159,46.74 161.67,49.4 C570.1 161.81,49.39 U97.4 163.82,49.39 164.67,48.54 170.84,48.54 172.72,50.42 172.72,55.93 155.98,72.67 155.98,73.51 R473.1 155.17,74.32 155.17,78.72 154.18,79.71 152.78,79.71 v2(152.27,79.2)
TCK: length 3.4
  TOP w0.173: J18.3 180.24,96.62 v2(179.91,96.95)
  BOTTOM w0.173: R3.1 180.26,96.6 v2(179.91,96.95)
TIMER15: length 116.8
  TOP w0.173: R935.1 56.42,77.17 v1(55.69,77.9)
  L4_SIG2 w0.114: J21.7 107.35,147.43 108.37,148.46 108.37,149.66 107.42,150.62 100.79,150.62 99.85,149.68 99.85,145.61 102.55,142.91 102.55,137.76 95.91,131.11 88.21,131.11 84.94,127.84 84.94,124.36 84.63,124.05 84.63,112.41 81.28,109.06 81.28,100.48 78.92,98.12 78.92,93.7 77.26,92.04 74.34,92.04 72.09,89.79 65.64,89.79 58.96,83.11 57.28,83.11 55.69,81.53 v1(55.69,77.9)
TIMER16: length 2.6
  TOP w0.254: R967.1 50.51,68.92 U102.2
TIMER16_2: length 18.2
  TOP w0.173: U102.5 49.51,64.82 49.12,65.2 v1(48.74,65.2) ; R977.1 v1(42.7,76.83)
  L4_SIG2 w0.114: v1(42.7,76.83) 43.82,76.83 48.21,72.44 48.21,70.08 49.58,68.71 49.58,66.04 v1(48.74,65.2)
TOUCH_INT: length 36.6
  TOP w0.173: R802.2 84.81,95.22 82.35,95.22 v7(82.3,95.17)
  L3_SIG1 w0.109: v7(82.3,95.17) 80.46,95.17 79.74,94.44 78.59,94.44 77.6,95.43 76.03,95.43 75.85,95.62 72.35,95.62 70.44,93.71 68.61,93.71 67.99,94.33 59.02,94.33 57.53,92.84 v5(57.53,92.54)
  L10_SIG4 w0.109: v9(58.67,88.29) 58.44,88.53 58.44,89.72 57.53,90.63 v5(57.53,92.54)
  BOTTOM w0.173: R418.2 v9(58.67,88.29)
TSC_INT: length 2.5
  BOTTOM w0.173: J17.4 55.88,88.51 R418.1
TSC_RESETN: length 3.8
  BOTTOM w0.173: J17.3 55.32,88.01 R420.2 R792.1
UARTX_RXD: length 73.7
  TOP w0.173: R487.2 111.89,61.09 113.28,59.69 128.78,59.69 132.59,63.5 132.59,70.57 137.41,75.39 149.99,75.39 v7(150.62,76.03) ; U37.38 169.15,78.89 169.08,78.96 168.54,78.96 167.68,78.1 163.41,78.1 v7(162.31,79.2)
  L3_SIG1 w0.109: v7(162.31,79.2) 161.72,78.61 159.37,78.61 157.84,77.09 155.67,77.09 154.49,75.9 154.12,75.9 153.23,76.79 151.38,76.79 v7(150.62,76.03)
UARTX_TXD: length 69.9
  TOP w0.173: U37.39 168.21,79.39 v2(167.89,79.08) ; R486.2 113.03,60.96 113.92,60.07 128.65,60.07 130.73,62.15 v2(130.73,62.95)
  L3_SIG1 w0.109: v2(137.54,71.22) 138.46,72.14 140.17,72.14 141.61,73.58 154.31,73.58 155.81,75.08 163.02,75.08 164.26,76.33 165.15,76.33 v2(167.89,79.08)
  BOTTOM w0.173: v2(130.73,62.95) 130.73,67.69 134.27,71.22 v2(137.54,71.22)
USB1_3_0_STDA_SSRX+: length 110.1
  TOP w0.15: U1.AE12 93.44,84.01 93.37,84.01 v4(93.32,84.06)
  L3_SIG1 w0.109: v2(40.19,20.85) arc(40.32,21.04) 40.36,21.25 40.36,23.01 arc(40.55,23.97) 41.1,24.8 41.24,24.94 arc(41.7,25.63) 41.87,26.44 41.87,41.79 arc(42.01,42.49) 42.4,43.09 53.63,54.32 arc(53.96,54.81) 54.08,55.39 54.08,59.72 arc(54.22,60.42) 54.61,61.01 62.71,69.11 arc(64.05,71.11) 64.52,73.48 64.52,80.4 arc(64.71,81.38) 65.26,82.2 67.01,83.95 arc(67.76,84.46) 68.65,84.63 74.86,84.63 arc(75.78,84.82) 76.56,85.34 78.07,86.85 arc(78.51,87.14) 79.02,87.25 80.93,87.25 arc(81.33,87.17) 81.66,86.94 arc(81.97,86.74) 82.34,86.66 86.7,86.66 arc(86.91,86.66) 87.12,86.65 arc(89.41,86.08) 91.35,84.74 91.37,84.71 arc(91.83,84.4) 92.38,84.29 92.53,84.29 arc(92.94,84.23) v4(93.32,84.06)
  BOTTOM w0.15: v2(40.19,20.85) arc(40.31,20.68) 40.35,20.48 40.35,19.93 40.25,19.83 U95.2 40.25,18.27 40.35,18.17 40.35,17.9 arc(40.63,17.22) 41.3,16.94 41.9,16.94 arc(42.4,16.72) 42.61,16.21 arc(42.36,15.57) J23.6
USB1_3_0_STDA_SSRX-: length 110
  TOP w0.15: v4(92.66,83.99) U1.AF12
  L3_SIG1 w0.109: v4(92.66,83.99) 92.38,83.99 arc(91.72,84.12) 91.16,84.5 91.13,84.52 arc(89.28,85.8) 87.1,86.35 arc(86.9,86.36) 86.69,86.36 86.29,86.36 arc(86.17,86.31) 86.13,86.2 86.13,86.04 arc(85.96,85.87) 85.8,86.04 85.8,86.2 arc(85.63,86.36) 85.47,86.2 85.47,86.04 arc(85.31,85.87) 85.14,86.04 85.14,86.2 arc(85.09,86.31) 84.98,86.36 82.34,86.36 arc(81.85,86.46) 81.45,86.73 arc(81.21,86.89) 80.93,86.94 79.02,86.94 arc(78.62,86.86) 78.29,86.64 76.77,85.12 arc(75.89,84.53) 74.86,84.33 68.65,84.33 arc(67.88,84.17) 67.23,83.74 65.48,81.99 arc(64.99,81.26) 64.82,80.4 64.82,73.48 arc(64.33,70.99) 62.92,68.89 54.83,60.8 arc(54.5,60.3) 54.38,59.72 54.38,55.39 arc(54.24,54.69) 53.85,54.1 42.62,42.87 arc(42.29,42.38) 42.17,41.79 42.17,26.44 arc(41.99,25.51) 41.46,24.72 41.32,24.58 arc(40.83,23.86) 40.67,23.01 40.67,21.19 arc(40.7,21.01) v2(40.8,20.85)
  BOTTOM w0.15: J23.5 arc(43.15,15.59) 42.92,16.21 arc(42.62,16.93) 41.9,17.25 41.3,17.25 arc(40.84,17.44) 40.65,17.9 40.65,18.17 40.75,18.27 U95.1 40.75,19.83 40.65,19.93 40.65,20.48 arc(40.69,20.68) v2(40.8,20.85)
USB1_3_0_STDA_SSTX+: length 11
  BOTTOM w0.15: C555.2 36.74,22.71 arc(36.88,22.5) 36.93,22.25 36.93,21.99 arc(37.21,21.36) 37.84,21.1 37.85,21.1 arc(37.86,21.1) 37.87,21.1 38,21.11 38,21.11 arc(38.6,20.91) 38.85,20.33 38.85,19.93 38.75,19.83 U95.5 38.75,18.27 38.85,18.17 38.85,17.9 arc(38.66,17.44) 38.2,17.25 37.6,17.25 arc(36.88,16.93) 36.58,16.21 arc(36.34,15.58) J23.9
USB1_3_0_STDA_SSTX-: length 11
  BOTTOM w0.15: C554.2 37.41,22.7 arc(37.28,22.5) 37.24,22.28 37.24,22 arc(37.42,21.57) 37.85,21.4 37.85,21.4 37.97,21.41 arc(38.8,21.13) 39.15,20.33 39.15,19.93 39.25,19.83 U95.4 39.25,18.27 39.15,18.17 39.15,17.9 arc(38.87,17.22) 38.2,16.94 37.61,16.94 arc(37.1,16.72) 36.89,16.21 arc(37.13,15.58) J23.8
USB1_CONN_DM: length 15.5
  TOP w0.15: v2(39.43,16.47) 39.58,16.62 39.58,16.97 39.91,17.3 42.7,17.3 42.88,17.48 42.88,17.7 42.55,18.03 42.55,18.97 42.7,19.13 U64.2 42.7,20.1 42.88,20.27 42.88,20.65 43.28,21.06 45.21,21.06 45.57,21.41 45.57,22.03 v2(45.42,22.19)
  BOTTOM w0.15: L11.4 45.32,23.01 45.57,22.76 45.57,22.34 v2(45.42,22.19) ; J23.2 38.74,15.77 v2(39.43,16.47)
USB1_CONN_DP: length 15.6
  TOP w0.15: v2(40.04,16.47) 39.89,16.62 39.89,16.84 40.04,16.99 42.82,16.99 43.18,17.35 43.18,17.65 43.56,18.03 43.56,18.97 43.4,19.13 U64.1 43.4,20.1 43.18,20.32 43.18,20.52 43.41,20.75 45.34,20.75 45.87,21.29 45.87,22.03 v2(46.02,22.19)
  BOTTOM w0.15: J23.3 40.74,15.77 v2(40.04,16.47) ; L11.3 46.12,23.01 45.87,22.76 45.87,22.34 v2(46.02,22.19)
USB1_OVRCURN: length 2.9
  BOTTOM w0.381: U66.5 R551.1
USB1_VBUS_EN: length 201.4
  TOP w0.173: v7(81.34,91.46) 82,90.8 84.66,90.8 R557.1
  TOP w0.381: R978.1 v1(42.7,78.35)
  L3_SIG1 w0.109: v1(42.7,78.35) 41.73,79.32 41.73,81.2 42.19,81.66 44.25,81.66 46,83.41 50.82,83.41 55.77,88.37 57.81,88.37 v5(59.03,89.59) 61.54,89.59 63.1,91.14 69.81,91.14 70.37,91.7 73.79,91.7 74.27,92.18 75.49,92.18 75.97,91.7 78.25,91.7 78.84,91.11 80.98,91.11 v7(81.34,91.46)
  L4_SIG2 w0.114: v5(59.03,89.59) 57.92,88.47 56.26,88.47 54.27,86.49 51.14,86.49 47.75,89.87 37.58,89.87 32.69,84.98 30.29,84.98 28.92,83.61 28.92,79.51 27.57,78.16 26.42,78.16 25.56,77.3 21.98,77.3 13.54,68.86 7.44,68.86 4.39,65.81 4.39,50.04 5.92,48.51 5.92,42.65 6.91,41.66 6.91,38.23 8.81,36.32 8.81,23.29 10.41,21.69 10.41,11.33 16.13,5.61 20.47,5.61 21.84,4.24 24.71,4.24 v2(25.27,3.68)
  BOTTOM w0.173: U66.4 R553.1 v2(25.27,3.68)
USB2_CONN_DM: length 5.5
  TOP w0.15: U93.2 6.2,40.62 5.41,40.62 v2(5.26,40.47)
  BOTTOM w0.15: J45.2 4.68,40.45 4.85,40.62 5.11,40.62 v2(5.26,40.47) 5.39,40.6 7.1,40.6 7.25,40.75 7.76,40.75 8.02,40.49 L33.3
USB2_CONN_DP: length 5.6
  TOP w0.15: U93.1 5.88,41.09 5.71,40.92 5.41,40.92 v2(5.26,41.08)
  BOTTOM w0.15: L33.4 8.02,41.29 7.8,41.08 7.12,41.08 6.96,40.92 5.41,40.92 v2(5.26,41.08) 5.1,40.92 4.86,40.92 4.67,41.1 J45.3
USB2_ID: length 10.3
  TOP w0.173: U93.3 6.1,40.09 5.87,39.86 4.83,39.86 4.6,40.09 4.6,41.41 4.95,41.76 v2(5.77,41.76)
  BOTTOM w0.173: R788.1 R808.1 6.84,41.76 v2(5.77,41.76) 5.76,41.75 J45.4
USB2_OVRCURN: length 4.3
  TOP w0.173: U94.5 18.92,41.48 18.03,42.37 R790.1
USB2_VBUS_EN: length 113.7
  TOP w0.173: R787.1 82.42,88.82 80.21,91.03 78.97,91.03 78,92 76.65,92 75.78,92.88 70.78,92.88 70.34,92.43 67.54,92.43 66.78,91.67 66.78,89.41 65.58,88.21 65.58,87.13 56.81,78.36 56.49,78.36 R971.1 57.06,79.57 57.06,81.19 55.15,83.1 44.7,83.1 43.17,81.57 42.3,81.57 41.88,81.16 41.88,67.03 42.57,66.34 42.57,56 43.11,55.46 43.11,53.74 40.33,50.96 39.46,50.96 35.32,46.82 R791.1 U94.4
USBJTAG_ENN: length 39.1
  TOP w0.173: U65.4 174.59,70.83 v2(175.22,70.2)
  BOTTOM w0.173: U63.15 174.52,83.47 174.35,83.64 174.35,83.88 174.59,84.12 U63.14 177.68,84.12 178.59,83.22 R677.2 178.59,78.21 175.9,75.52 175.9,70.88 v2(175.22,70.2) 175.22,62.27 174.12,61.17 170.56,61.17 169.55,62.18 169.55,63.1 170.44,64 U75.4
VADD33_PRU1ETH0: length 3.9
  TOP w0.381: v1(22.48,123.4) 22.98,123.4 R97.2 23.48,122.88 23.11,122.51 v1(22.41,122.51)
  BOTTOM w0.254: U9.14 22.09,122.19 v1(22.41,122.51)
VADD33_PRU1ETH1: length 2.5
  TOP w0.254: 26.54,99.52 26.68,99.66 U13.14
  vias: v1(26.26,100.26) v1(26.54,98.77)
VADD33_PRU2ETH0: length 3.3
  TOP w0.254: U15.14 27.97,81.88
  TOP w0.508: 27.97,81.88 26.68,81.88 26.53,81.73 26.53,81.01 v1(26.54,80.99)
  vias: v1(26.21,82.61)
VADD33_PRU2ETH1: length 3.1
  TOP w0.254: U17.14 27.57,57.12 v1(27.43,56.98) ; C142.1 26.99,56.98 ; C142.1 26.52,56.47 ; C142.1 26.52,57.49
  vias: v1(26.54,56.23)
VAM574X_DDR1: length 43.9
  TOP w0.254: U1.AB22 v4(95.84,75.22) ; U1.AG20 v4(91.84,76.82) ; U1.AC22 v4(95.04,75.22) ; U1.AA22 v4(96.64,75.22) ; U1.AH27 v11(91.04,71.22) ; U1.AG28 92.24,69.93 91.8,69.49 91.8,68.66 91.39,68.25 v4(91.39,66.93) ; U1.AB25 v4(95.84,72.82) ; U1.AB21 v4(95.84,76.02) ; U1.AD26 v11(94.24,72.02) ; U1.W16 v11(98.24,80.02) ; U1.AA21 v4(96.64,76.02) ; v4(98.04,71.21) 98.23,71.21 U1.W27 ; U1.AB24 v4(95.84,73.62)
  TOP w0.381: 63.56,77.82 R639.2 62.83,76.77
  L3_SIG1 w0.254: v4(95.84,73.62) v5(95.44,73.37) ; v4(91.39,66.93) v5(91.06,66.6) ; v4(95.84,72.82) v5(95.59,72.42) ; v4(95.04,75.22) v5(94.64,74.97) ; v11(91.04,71.22) v5(90.64,70.97) ; v4(95.84,75.22) v5(95.44,74.97) ; v4(96.64,76.02) v5(96.24,75.77) ; v4(96.64,75.22) v5(96.24,74.97) ; v4(91.84,76.82) v5(91.44,76.57) ; v4(98.04,71.21) v5(97.64,70.83) ; v11(94.24,72.02) v5(93.84,71.77) ; v4(95.84,76.02) v5(95.44,75.77) ; v11(98.24,80.02) v5(97.84,79.77)
  L10_SIG4 w0.152: v9(93.12,71.68) 93.12,69.72 91.06,67.66 v5(91.06,66.6)
  L10_SIG4 w0.254: v5(95.44,74.97) 95.01,74.54 v11(95.01,74.53) ; v11(97.67,71.37) 97.66,71.37 97.64,71.28 97.7,71.18 97.62,70.83 v5(97.64,70.83) ; v5(95.44,73.37) 94.93,73.37 v11(94.88,73.41) ; v11(95,72.69) 95.27,72.42 v5(95.59,72.42) ; v11(95.85,75.31) 96.18,75.51 v5(96.24,75.77) ; v11(95.04,75.52) v5(95.44,75.77) ; v11(94.04,74.9) 94.11,74.97 v5(94.64,74.97) ; v11(94.24,72.02) v5(93.84,71.77) ; v5(96.24,74.97) 95.76,74.49 v11(95.67,74.49) ; v11(98.24,80.02) v5(97.84,79.77) ; v11(91.04,71.22) v5(90.64,70.97)
  BOTTOM w0.381: C11.1 94.09,74.95 v11(94.04,74.9) 94.09,74.86 C8.1 ; C9.1 94.32,72.1 v11(94.24,72.02) 94.01,72.24 C7.1 ; v11(97.67,71.37) 97.22,70.93 C10.1 C115.1 ; C114.1 98.41,79.84 v11(98.24,80.02) ; C441.1 71.11,68.54 ; C441.1 70.1,70.79 ; C441.1 69.1,68.54 ; C12.1 90.8,71.45 v11(91.04,71.22) ; v9(93.12,71.68) 93.12,71.14 C6.1
  vias: v1(61.02,78.12) v1(60.96,77.3) v1(60.96,76.28) v1(62.23,77.3) v1(62.23,76.28) v1(62.29,78.12) v1(63.56,78.12) v1(66.17,69.42) v1(67.31,71.33) v1(68.2,71.71) v1(69.09,71.96) v10(95.89,71.84) v10(96.14,72.09) v11(95.89,71.84) v11(96.14,72.09)
VAM574X_DDR2: length 28.8
  TOP w0.254: U1.G22 v4(108.63,75.22) ; U1.H21 v4(107.83,76.02) ; U1.H22 v4(107.83,75.22) ; U1.M21 v4(104.63,76.02) ; U1.T24 v4(100.64,73.62) ; U1.T25 v4(100.64,72.82) ; U1.J27 v4(107.03,71.22) ; U1.H20 v4(107.83,76.82) ; U1.L20 v4(105.43,76.82) ; U1.G23 v4(108.63,74.42) ; U1.M20 v4(104.63,76.82) ; U1.L21 v4(105.43,76.02) ; U1.E24 v4(110.23,73.62)
  L3_SIG1 w0.254: v4(105.43,76.02) v5(105.83,75.77) ; v4(107.03,71.22) v5(107.43,70.97) ; v5(101,72.46) 100.65,72.82 v4(100.64,72.82) ; v4(105.43,76.82) v5(105.83,76.57) ; v4(100.64,73.62) 100.65,73.62 v5(101,73.26) ; v4(108.63,74.42) v5(109.03,74.17) ; v4(104.63,76.82) v5(105.03,76.57) ; v4(107.83,75.22) v5(108.23,74.97) ; v4(104.63,76.02) v5(105.03,75.77) ; v4(107.83,76.02) v5(108.23,75.77) ; v4(110.23,73.62) v5(110.63,73.37) ; v4(107.83,76.82) v5(108.23,76.57) ; v4(108.63,75.22) v5(109.03,74.97)
  L10_SIG4 w0.254: v11(104.62,76.23) v5(105.03,76.57) ; v11(108.63,74.72) v5(109.03,74.97) ; v9(107.86,70.61) v5(107.43,70.97) 107.43,71.01 107.65,71.22 108.16,71.22 v9(108.17,71.21) ; v5(101,73.26) v11(100.58,73.03) ; v11(107.83,76.32) v5(108.23,76.57) ; v11(107.83,74.72) v5(108.23,74.97) ; v11(108.63,73.92) v5(109.03,74.17) ; v11(105.43,76.32) v5(105.83,76.57) ; v5(101,72.46) v11(100.61,72.19) ; v11(104.63,75.52) v5(105.03,75.77) ; v11(107.83,75.52) v5(108.23,75.77) ; v11(105.43,75.52) v5(105.83,75.77) ; v11(110.23,73.12) v5(110.63,73.37)
  BOTTOM w0.152: C15.1 109.75,72.63 v11(110.23,73.12) 110.23,73.96 C13.1
  BOTTOM w0.254: C16.1 108.58,74.77 v11(108.63,74.72)
  BOTTOM w0.381: C552.1 C553.1 106.41,72.97 v9(108.17,71.21) ; C551.1 107.8,70.55 v9(107.86,70.61)
  vias: v1(66.42,57.1) v1(66.42,55.83) v1(67.44,57.1) v1(67.44,55.83) v1(68.26,57.04) v1(68.26,55.77) v1(68.26,54.5) v5(113.92,56.22) v5(113.92,54.56) v5(115.32,54.56) v5(116.84,56.22) v5(117.86,55.07) v8(118.95,56.42) v8(118.95,55.15) v8(119.96,56.42) v8(119.96,55.15) v8(120.98,56.42) v8(120.98,55.15) v9(118.95,56.42) v9(118.95,55.15) v9(119.96,56.42) v9(119.96,55.15) v9(120.98,56.42) v9(120.98,55.15)
VANA_OUT: length 1.6
  TOP w0.381: U3.C8 v2(140.64,129.53)
  BOTTOM w0.508: C302.1 140.06,129.53 v2(140.64,129.53)
VCAN1: length 16.4
  TOP w0.381: 148.8,14.22 C250.1 ; C250.1 150.16,14.22 ; C250.1 149.48,14.87
  TOP w0.508: 151.71,13.16 J38.1 ; J38.1 153.85,15.29 ; J38.1 151.71,15.29 ; J38.1 153.85,13.16 ; 167.13,27.34 U40.7 ; U40.7 167.13,29.5 ; U40.7 167.91,28.42 ; U40.7 166.35,28.42
  BOTTOM w0.381: C252.1 155.56,23.96 v1(154.76,23.96) ; C252.1 158.5,23.98 U41.8 ; C252.1 v1(155.58,23.25)
VETH0_AVDDH: length 5.7
  TOP w0.254: U21.12 v1(32.43,125.16) ; U21.47 v7(39.57,123.11) ; U21.1 v1(37.93,125.26)
  L3_SIG1 w0.381: v7(39.57,123.11) v5(40.16,123.11)
  BOTTOM w0.381: v1(26.42,124.33) 26.57,124.48 C157.1 v1(25.53,125.68)
  vias: v1(46.86,123.65) v1(46.86,122.89) v1(47.75,123.65) v1(47.75,122.89)
VETH0_AVDDL: length 1.6
  TOP w0.254: U21.4 v1(36.43,125.16) ; U21.9 v1(33.93,125.16)
VETH0_AVDDL_PLL: length 3.4
  TOP w0.254: U21.44 39.49,121.61 39.66,121.79 40.74,121.79 C165.1 40.95,121.91 40.95,122.06 40.97,122.08 40.97,122.29 41.26,122.58 41.4,122.58 v1(41.4,122.64)
VETH0_AVDDL_PMOS: length 2.7
  TOP w0.381: v1(44.7,125.3) 44.7,126.09 C158.1 45.59,125.96 v1(45.59,125.3)
VETH0_DVDDH: length 20.4
  TOP w0.254: U21.16 29.74,122.11 v1(29.59,122.26) ; U21.34 v1(36.93,116.41) ; U21.40 39.23,119.61 39.36,119.74 v1(40.26,119.74)
  TOP w0.381: R306.1 32.77,115.17 v1(32.94,115.35) ; R299.1 v1(35.48,115.22) ; v7(39.95,116.41) 40,116.36 R279.2 ; v1(31.55,115.35) 31.5,115.3 R309.1 ; R301.1 v1(34.09,115.22) ; v5(41.66,118.45) v7(42.42,118.45)
  TOP w0.762: C156.1 29.29,117.61 v1(29.08,117.81) ; C156.1 30.47,116.4 v1(30.57,116.5) ; C156.1 28.11,116.4 v1(28.01,116.5)
  L3_SIG1 w0.381: v7(42.42,118.45) v5(41.66,118.45) ; v7(39.95,116.41) v5(39.37,116.41)
  BOTTOM w0.381: C155.1 29.57,122.24 v1(29.59,122.26) ; R280.2 v1(40.26,110.7) ; D3.1 v1(42.16,112.86) ; v1(39.36,109.43) 39.34,109.41 C171.1 36.7,109.41 U22.5
VETH0_DVDDL: length 8.3
  TOP w0.254: U21.23 30.19,118.61 30.18,118.6 30,118.6 v1(29.84,118.45) ; U21.39 v1(39.62,119.11) ; U21.26 v1(32.93,116.41) ; U21.18 v1(30.73,121.11) ; U21.14 v1(30.73,123.11) ; U21.30 v1(34.93,116.41)
  BOTTOM w0.381: 30.88,117.94 C160.1 ; C160.1 30.41,118.45 ; C160.1 30.88,118.95
VETH1_AVDDH: length 14.5
  TOP w0.254: U24.47 v1(63.12,123.11) ; v1(59.82,125.81) 59.65,125.64 U24.1 ; U24.12 54.15,124.88 53.85,125.18 v1(53.09,125.18)
  TOP w0.381: 72.13,107.89 C177.1 ; C177.1 72.13,109.7 ; C177.1 71.37,108.79 ; 69.67,106.38 C176.1 69.2,106.89
  L4_SIG2 w0.381: v1(63.12,123.11) 62.86,123.36 62.86,124.16 61.35,125.67 60.29,125.67 60.15,125.81 v1(59.82,125.81)
  vias: v1(64.9,130.26) v1(64.9,129.37) v1(66.04,130.26) v1(66.04,129.37)
VETH1_AVDDL: length 4.9
  TOP w0.254: U24.4 v1(58.15,125.16) ; U24.9 v1(55.65,125.16)
  BOTTOM w0.508: 60.83,124.22 C183.1 ; C183.1 61.34,124.69 ; C183.1 60.32,124.69 ; 63.51,124.4 C182.1 61.71,124.4
  vias: v1(64.01,124.64) v1(65.28,123.4)
VETH1_AVDDL_PLL: length 4.5
  TOP w0.254: C186.1 61.85,121.62 61.67,121.8 61.09,121.8 60.9,121.61 U24.44
  TOP w0.381: C186.1 62.5,122.36 v1(62.48,122.38)
  BOTTOM w0.508: C185.1 62.86,121.82 ; C185.1 63.37,121.35 ; C185.1 62.36,121.35
  vias: v1(64.26,120.99) v1(65.15,120.99)
VETH1_AVDDL_PMOS: length 4.7
  TOP w0.381: C179.1 67.66,126.95 ; C179.1 66.91,128.03 ; C179.1 66.91,125.88
  TOP w0.508: 66.74,118.41 FB7.1 ; FB7.1 66.74,119.75 ; FB7.1 67.22,119.08
VETH1_DVDDH: length 19.4
  TOP w0.254: v1(61.98,119.74) 61.87,119.74 61.74,119.61 U24.40 ; U24.16 51.46,122.11 v1(51.43,122.13) ; U24.34 v1(58.65,116.41)
  TOP w0.381: v1(51.08,122.96) 51.08,122.91 50.65,122.49 C174.1 ; v1(54.23,114.38) 53.98,114.13 R352.1 ; v1(63.88,119.21) 63.5,118.83 R342.2 ; R343.1 v1(56.77,114.25) ; R364.1 49.66,120.9 49.26,121.3 48.65,121.3 48.26,120.91 48.26,120.82 v1(48.08,120.82) ; R345.1 v1(55.37,114.25) ; v1(52.83,114.38) 52.58,114.13 R353.1
  TOP w0.635: C175.1 v1(50.67,114.5)
  TOP w0.762: C175.1 50.57,113.22 v1(49.39,113.22)
  BOTTOM w0.381: 62.86,112.86 v1(63.75,112.86) ; R324.2 v1(61.98,110.7) ; v1(61.07,109.43) 61.06,109.41 C192.1 58.42,109.41 U26.5
VETH1_DVDDL: length 12.9
  TOP w0.254: U24.26 v1(54.65,116.41) ; U24.39 v1(61.34,119.11) ; U24.14 v1(52.45,123.11) ; U24.30 v1(56.65,116.41) ; U24.23 52,118.61 v1(51.7,118.31) ; U24.18 v1(52.45,121.11)
  TOP w0.381: v1(64.91,119.97) 65.34,119.54 FB7.2 65.34,118.24 v1(64.91,117.81) ; C181.1 50.68,118.04 51.43,118.04 v1(51.7,118.31)
  BOTTOM w0.381: C180.1 62.75,117.57 ; C180.1 61.85,118.32 ; C180.1 60.95,117.57
VLDO1_OUT: length 2.4
  TOP w0.254: U3.C6 v2(138.25,129.53)
  BOTTOM w0.381: R657.2 137.5,128.36 C383.1 137.64,129.53 v2(138.25,129.53)
VLDO2_OUT: length 1.6
  TOP w0.173: v1(139.18,131.95) 139.18,131.73 138.94,131.49 138.94,131.02
  TOP w0.381: U3.B6 139.05,130.34
  vias: v1(139.32,133.6) v1(139.27,132.81)
VLED+: length 11.7
  BOTTOM w0.254: v1(81.53,128.48) 82.11,127.9 J16.29 ; v1(82.17,128.99) 82.75,128.4 J16.30 ; 73.54,141.58 U32.9
  BOTTOM w0.381: C216.1 70.59,139.91 ; C216.1 71.06,139.4 ; C216.1 70.59,138.89 ; 71.38,137.75 C215.1 70.62,138.65 ; 71.63,141.05 C218.1 70.88,140.15
  vias: v1(71.75,139.53) v1(72.01,137.75) v1(72.39,140.42) v1(73.15,138.89)
VLED-: length 1
  BOTTOM w0.254: J16.28 J16.27 ; J16.23 J16.24
  vias: v1(81.03,145.75) v1(81.28,146.64) v1(81.53,145.12) v1(81.79,146) v1(82.17,126.57) v1(82.17,125.94) v1(83.06,126.57) v1(83.06,125.94)
VMAIN: length 211.8
  TOP w0.203: U3.A6 v7(138.25,130.34)
  TOP w0.254: U3.F1 v2(134.25,127.13) ; U3.G12 v7(143.84,125.54) ; U3.H11 v7(143.04,124.74) ; U3.J2 v7(135.05,123.94) ; U3.F2 v2(135.05,127.13) ; U3.H13 v7(144.64,124.74) ; U3.J3 v7(135.85,123.94) ; U3.D11 v7(143.04,128.73) ; U3.D12 v7(143.84,128.73) ; U3.C7 v7(139.84,129.53) ; U3.E2 v2(135.05,127.93) ; U3.E1 v2(134.25,127.93) ; U3.D13 v7(144.64,128.73) ; U3.H12 v7(143.84,124.74) ; U3.G11 v7(143.04,125.54) ; U3.E3 v2(135.85,127.93) ; U3.F3 v2(135.85,127.13) ; U3.G13 v7(144.64,125.54) ; U3.J1 v7(134.09,124.34) ; U3.C4 v7(136.65,129.53) ; U3.C5 v7(137.45,129.53)
  TOP w0.381: v1(138.68,119.84) 138.65,119.88 v1(138.65,120.56) U3.N6 U3.M6 ; v1(141.73,141.05) R19.2 143.31,141.87 C579.1 ; U3.A9 141.42,131.11 v1(141.42,131.7) ; U96.5 v1(150.01,143.83) 152.31,143.83 154.75,141.39 R982.1 154.37,140.44 U104.6 ; R20.2 142.88,137.77 144.37,139.27 v1(144.37,140.79) ; U76.1 145.25,100.81 C407.1 145.02,101.38 v1(145.56,101.93) ; U3.N3 136.25,120.89 v7(136.65,120.49) 137.05,120.89 U3.N4 U3.M4 ; U3.M9 U3.N9 141.05,120.4 v1(141.1,120.35) ; v1(148.21,3.89) 139.32,3.89 137.67,5.54 137.67,14.05 138.48,14.86 R113.2 ; C152.1 131,142.47 v1(130.85,142.61) ; v1(145.42,121.28) 145.42,121.57 145.16,121.82 v1(145.16,121.92) 145.06,121.92 U3.L13 144.12,122.61 143.58,122.61 U3.L12 ; v1(142.1,131.73) 142.1,130.99 U3.A10 ; v1(140.34,120.35) 140.25,120.44 U3.N8 U3.M8
  L3_SIG1 w0.381: v1(176.05,123.4) 176.05,129.75 TP1.1
  L4_SIG2 w0.381: v1(168.53,96.09) 169.53,96.09 175.13,90.49 175.13,81.74 177.18,79.7 177.18,70.32 176.78,69.93 176.78,59.16 182.26,53.68 182.26,21.81 170.94,10.5 170.94,4.16 168.68,1.89 151.64,1.89 149.64,3.89 v1(148.21,3.89)
  L6_PWR1 w0.508: J9.1 159.84,137.92 ; J9.1 158.22,136.31 ; J9.1 158.22,137.92 ; J9.1 159.84,136.31
  BOTTOM w0.203: U62.A2 U62.A1
  BOTTOM w0.254: 154.24,106.74 154.24,106.74 U62.A1 ; U32.2 73.54,147.73 C217.1
  BOTTOM w0.381: v1(138.65,120.56) 138.22,120.99 C272.1
  BOTTOM w0.508: R411.2 v1(74.55,140.03)
  vias: v1(71.25,149.69) v1(72.14,150.07) v1(72.9,149.69) v1(76.07,108.67) v1(76.83,108.67) v1(77.22,129.24) v1(77.72,108.67) v1(78.11,130) v1(78.11,129.24) v1(78.61,108.67) v1(78.99,130) v1(78.99,129.24) v1(140.84,119.72) v1(141.35,119.21) v1(149.99,107.9) v1(149.99,106.66) v1(150.8,107.93) v1(150.8,106.66) v1(155.7,131.78) v1(155.7,130.76) v1(155.83,129.49) v1(156.34,128.48) v1(158.12,128.43) v1(166.27,114.64) v1(166.27,113.5) v1(167.41,114.64) v1(167.41,113.5) v1(168.68,114.64) v1(168.68,113.49) v1(174.9,124.54) v1(174.9,123.4) v1(174.9,122.13) v1(176.05,122.13) v1(177.32,123.4) v1(177.32,122.13) v1(178.59,124.54) v1(178.59,123.4) v1(178.59,122.13) v1(179.86,124.54) v1(179.86,123.4) v1(179.86,122.13) v1(184.43,123.53) v1(184.43,122.26) v5(132.72,124.67) v5(132.72,124.03) v5(133.35,124.67) v5(133.35,124.03) v5(133.99,132.42) v5(134.62,132.42) v5(135.26,132.42) v5(135.77,132.09) v5(136.14,119.33) v5(136.67,121.05) v5(136.94,119.83) v5(139.19,130.54) v5(139.86,130.7) v5(145.77,125.81) v5(145.92,129.37) v5(145.92,128.73) v5(145.9,125.13) v5(146.53,125.81) v5(146.69,129.37) v5(146.69,128.73) v5(146.66,125.13) v5(147.29,125.81) v5(147.42,125.13) v6(135.64,119.72) v6(136.4,119.97) v7(135.64,119.72) v7(136.4,119.97) v8(134.34,130.85) v8(135.1,130.85) v8(135.77,131.48) v8(135.77,130.87) v8(145.16,129.37) v8(145.16,128.61) v8(145.29,124.29) v8(145.29,123.53) v8(146.18,124.29) v8(146.18,123.53) v8(147.07,124.29) v8(147.07,123.53) v9(134.34,130.85) v9(135.1,130.85) v9(135.77,131.48) v9(135.77,130.87) v9(145.16,129.37) v9(145.16,128.61) v9(145.29,124.29) v9(145.29,123.53) v9(146.18,124.29) v9(146.18,123.53) v9(147.07,124.29) v9(147.07,123.53)
VPP_CONN: length 115.7
  BOTTOM w0.508: J46.2 170.18,8.97 171.2,9.99 171.2,14.31 174.38,17.49 174.38,20.17 174.04,20.51 174.04,24.09 171.63,26.5 149.18,26.5 140.08,35.6 132.42,35.6 124.59,43.44 124.59,78.19 122.05,80.73 R797.1
VPP_EN: length 6.1
  TOP w0.173: U1_1.3 174.66,7.94 R2_1.1 174,5.7 174,4.36 J1_1.4
VPROFI: length 12.8
  TOP w0.381: R577.2 v1(113.03,8.89) ; v1(99.44,6.22) 99.31,6.1 C430.1
  TOP w0.508: J14.6 98.3,6.08 C430.1 ; v1(99.44,6.22) v1(100.2,6.22)
  L9_SIG3 w0.381: v1(112.39,3.81) 111.63,4.57 111.63,7.49 v1(113.03,8.89)
  vias: v1(100.97,6.22) v1(101.98,6.22) v1(112.39,3.05) v1(113.16,2.41) v1(114.05,2.41)
VPROFI_SRC: length 1.8
  BOTTOM w0.381: 116.85,7.1 C433.1 115.05,7.1
VPROFI_TRANSA: length 3
  BOTTOM w0.381: L2.8 123.39,11.25 ; L2.8 122.36,12.23 ; L2.8 121.33,11.25
VPROFI_TRANSB: length 2
  BOTTOM w0.381: 123.39,5.26 L2.5 122.36,4.28
VPWRIN_JCK: length 30.5
  TOP w0.381: U104.5 v1(154.76,139.49)
  TOP w0.508: J1.1 173.29,111.76 ; J1.1 178.58,111.76 ; J1.1 175.99,109.05 ; J1.1 175.99,114.37 ; 185.67,108.54 J2.1 ; J2.1 187.28,108.54 ; J2.1 187.28,110.15 ; J2.1 185.67,110.15
  BOTTOM w0.508: J1.1 177.61,113.37 ; J1.1 174.38,113.37 ; J1.1 174.38,110.15 ; J1.1 177.61,110.15 ; 185.67,108.54 J2.1 ; J2.1 185.67,110.15 ; J2.1 187.28,108.54 ; J2.1 187.28,110.15
VPWRIN_PREFUSE:
  vias: v1(169.57,107.27) v1(172.11,107.27) v1(173.38,106) v1(173.38,104.73) v1(173.38,103.46)
VRTC_OUT: length 36.1
  TOP w0.254: U3.A8 140.25,130.89 v7(140.77,131.41)
  TOP w0.381: R981.2 v1(148.04,141.45) ; R645.2 93.85,103.99 93.47,104.37 v1(93.47,104.57)
  L3_SIG1 w0.152: v5(140.21,131.34) 140.29,131.41 v7(140.77,131.41)
  L10_SIG4 w0.152: v9(143.4,130.15) 142.8,130.75 140.8,130.75 v5(140.21,131.34)
  L10_SIG4 w0.381: v1(140.97,134.75) 140.97,134.96 141.42,135.41 142.93,135.41 143.89,134.44 143.89,134.41 144.83,133.48 144.83,132.16 144.17,131.5 144.17,129.89 141.88,127.6 141.14,127.6 140.93,127.39 139.89,127.39 139.6,127.69 138.73,127.69 136.87,125.82 136.87,123.05 v9(137.13,122.78) 138.68,121.24 v9(140.08,121.24)
  BOTTOM w0.152: R983.2 143.92,129.63 v9(143.4,130.15)
  BOTTOM w0.254: v1(140.59,134.24) 140.59,134.37 v1(140.97,134.75) 141.35,134.37 v1(141.35,134.24)
  BOTTOM w0.381: R17.2 136.63,122.44 136.97,122.78 v9(137.13,122.78) ; v9(140.08,121.24) 140.69,121.85 R794.2
VSDMMC: length 98.2
  TOP w0.254: U1.W8 v4(98.24,87.21) ; U1.Y8 v4(97.44,87.21)
  TOP w0.381: v1(85.39,108.5) 85.99,107.9 R644.2
  TOP w0.635: v1(87,146.88) 84.49,144.37 83.19,144.37 82.04,143.23 82.04,130.21 80.52,128.69 80.52,119.46 81.41,118.57 81.41,116.54 85.01,112.93 85.01,111.76 86.61,110.16 R644.2
  L3_SIG1 w0.254: v4(98.24,87.21) v5(97.84,87.46) ; v4(97.44,87.21) v5(97.04,87.46)
  L10_SIG4 w0.254: v11(96.65,87.08) v5(97.04,87.46) ; v11(97.45,87.08) v5(97.84,87.46)
  L10_SIG4 w0.635: v9(135.89,128.78) 135.89,128.96 v9(135.49,129.35) 134.58,129.35 134.36,129.13 133.11,129.13 131.82,130.42 116.76,130.42 116.04,131.13 113.85,131.13 113.28,131.7 v9(111.3,131.7) ; 97.82,138.87 96.19,138.87 v1(95.91,138.59) ; 97.82,138.87 v9(97.84,138.84) ; 97.82,138.87 v9(98.68,138.87) 100.18,138.87 102.38,136.66 107.43,136.66 110.03,134.06 v9(110.03,131.7)
  BOTTOM w0.381: v9(135.49,129.35) 135.49,129.17 v9(135.89,128.78) 136.07,128.78 R657.1 ; v1(85.33,97.26) 85.23,97.16 C483.1 v1(86.39,96.09)
  vias: v5(92.96,91.27) v5(93.47,90.63) v5(95.17,92.48) v8(94.81,91.94) v8(94.81,91.17) v8(94.81,90.41) v8(94.81,89.65) v8(111.3,130.81) v9(94.81,91.94) v9(94.81,91.17) v9(94.81,90.41) v9(94.81,89.65) v9(111.3,130.81)
VSMPS1_2: length 1.8
  TOP w0.381: 115.08,134 R641.1 114.02,133.27
  vias: v1(114.05,133.05) v1(114.05,132.16) v1(115.32,133.05) v1(115.32,132.03) v1(115.37,134.32) v1(116.46,134.32) v1(116.46,133.05) v1(116.46,132.03) v1(152.15,130.38) v1(153.42,130.38) v1(154.18,133.3) v1(154.18,132.29) v1(154.18,129.06) v1(154.18,127.59)
VSMPS1_SW: length 2.3
  TOP w0.381: 144.79,127.88 144.45,127.54 U3.E13 U3.E12 U3.E11
VSMPS2_SW: length 2.6
  TOP w0.381: 145.17,126.85 145.05,126.74 144.65,126.74 144.65,126.74 U3.F13 U3.F12 U3.F11
VSMPS3_SW: length 3.1
  TOP w0.305: U3.J13 144.07,124.16 143.62,124.16 U3.J12 143.27,124.16 142.82,124.16 U3.J11
  TOP w0.381: U3.J13 144.42,124.16 145.42,124.16
VSMPS4_5: length 3.7
  TOP w0.381: 123.21,134 R642.1 122.15,133.27
  BOTTOM w0.381: v1(130.18,128.1) 129.56,128.71 C279.1
  vias: v1(130.18,129.03) v1(130.18,127.21) v1(130.18,120.58) v1(130.18,119.82) v1(130.18,119.18)
VSMPS4_SW: length 3.8
  TOP w0.381: U3.G3 U3.G2 U3.G1 134.13,125.94 133.62,126.45 132.84,126.45 132.72,126.32
VSMPS5_SW: length 3.5
  TOP w0.381: U3.H3 U3.H2 U3.H1 133.06,125.14 132.84,124.92
VSMPS6_SW: length 2.7
  TOP w0.381: U3.M5 U3.N5 137.85,119.51 137.67,119.33
VSMPS7: length 1.8
  TOP w0.381: 105.6,134.13 R640.1 106.66,133.4
  vias: v1(106.1,133.18) v1(106.1,131.91) v1(107.37,133.18) v1(107.37,131.91) v1(127.53,135.82) v1(128.8,135.82) v1(130.07,135.44) v1(130.07,134.17)
VSMPS7_SW: length 2.1
  TOP w0.381: U3.D1 134.91,128.61 135.13,128.61 135.39,128.34 U3.D2 135.71,128.61 136.02,128.61 136.25,128.38 U3.D3
VSMPS8_SW: length 4.4
  TOP w0.381: U3.M10 U3.N10 141.85,121 142.11,120.73 142.11,118.95 143,118.06
VSMPS9: length 0.8
  L10_SIG4 w0.381: 139.95,125.43 v5(139.95,126.19)
  vias: v1(138.94,111.21) v1(140.34,111.21) v1(141.73,111.21) v5(138.05,125.81) v5(138.61,125.89) v5(140.72,126.19) v8(138.3,125.3) v8(138.3,124.67) v8(139.19,125.3) v8(139.19,124.67) v9(138.3,125.3) v9(138.3,124.67) v9(139.19,125.3) v9(139.19,124.67)
VSMPS9_SW: length 2.5
  TOP w0.381: U3.M7 U3.N7 139.45,119.46
VUSB_FTDI: length 88.6
  TOP w0.381: FB9.2 179.45,16.4 C226.1
  TOP w0.508: D13.2 163.12,90.57 R491.2
  L10_SIG4 w0.381: v1(175.26,15.96) 174.62,15.96 171.71,18.87 171.71,19.77 172.61,20.66 172.61,22.69 173.6,23.69 173.6,25.49 170.56,28.53 170.56,38.86 171.32,39.62 171.32,42.63 172.67,43.97 172.67,54.62 171.87,55.41 171.87,59.47 170.02,61.33 170.02,62.96 170.43,63.38 170.43,67.14 170.18,67.39 170.18,69.3 170.43,69.54 170.43,72.96 164.96,78.43 164.96,80.48 166.4,81.92 166.4,84.51 166.88,84.99 166.88,86.9 164.9,88.88 v1(164.9,90.56)
VUSB_JTAG: length 6.8
  TOP w0.254: U36.1 182.77,15.35 v1(182.73,15.39)
  TOP w0.381: 182.78,16.38 FB9.1 ; v1(185.19,13) 185.28,13.1 J19.1
  BOTTOM w0.381: v1(182.73,15.39) 185.11,13 v1(185.19,13)
VUSB_VBUS1: length 2.5
  L10_SIG4 w0.508: 35.65,13.19 J23.1 ; J23.1 36.83,14.37 ; J23.1 36.83,13.19
  vias: v1(25.53,13.08) v1(26.8,13.08) v1(28.07,13.08) v1(29.34,13.08) v1(33.27,5.97) v1(33.27,4.83) v1(37.85,2.54)
VUSB_VBUS2: length 241.9
  TOP w0.508: J50.2 15.41,39.16 ; J50.2 13.8,39.16 ; J50.2 13.8,37.55 ; J50.2 15.41,37.55
  L9_SIG3 w0.381: v1(25.65,38.76) 25.65,41.05 26.7,42.09 26.7,48.59 24.59,50.7 24.59,71.07 28.96,75.44 28.96,77.04 34.19,82.27 34.19,88.67 27.05,95.81 27.05,97.1 28.19,98.25 28.19,99.92 26.49,101.63 25.73,101.63 24.51,102.84 24.51,108.23 19.18,113.56 19.18,123.06 v5(18.19,124.05)
  L10_SIG4 w0.381: v5(18.19,124.05) 19.13,124.99 21.11,124.99 25.91,129.79 31.67,129.79 32.79,130.91 75.23,130.91 76.53,132.21 79.22,132.21 79.81,131.62 88.34,131.62 92.05,135.33 94.21,135.33 95.07,136.19 98.35,136.19 100.56,133.99 104.09,133.99 105.41,132.66 105.41,131.47 109.74,127.14 111.02,127.14 111.85,126.31 117.67,126.31 119.76,128.4 122.79,128.4 128.4,122.79 130.04,122.79 131.07,121.76 133.52,121.76 134.26,122.5 134.26,124.45 136.9,127.08 136.9,127.35 137.64,128.1 v9(138.3,128.1)
  BOTTOM w0.381: v9(138.3,128.1) 138.56,127.84 R21.2
  vias: v1(8.38,38.18) v1(8.51,39.5) v1(9.53,39.45) v1(9.53,38.18)
XTIN: length 9.2
  TOP w0.173: U37.2 157.07,83.39 156.34,84.13 156.34,85.4 155.65,86.09 C243.1 153.63,86.09 153.34,86.38 Y5.1
XTOUT: length 7.6
  TOP w0.173: U37.3 156.38,82.89 156.32,82.95 C244.1 153.74,82.95 153.07,82.28 Y5.2
N10692191: length 13.2
  TOP w0.173: SW2.4 164,56.43 164.85,57.28 168.53,57.28 169.75,56.05 SW2.3 170.09,55.09 170.09,52.79 v2(170,52.7)
  BOTTOM w0.173: v2(170,52.7) 169.81,52.9 U48.1 R11.2
N10692247: length 5.8
  BOTTOM w0.173: R11.1 C5.1 166.5,53.53 R914.1 166.5,50.55 165.99,50.04 U97.2
N11217419: length 2.2
  BOTTOM w0.173: R47.1 R46.1 128.03,31.48 C85.1
N11219802: length 1.8
  TOP w0.305: 106.81,11.51 107.32,12.03 U8.7
N11219922: length 1.6
  TOP w0.305: U8.9 108.32,11.63 R56.1
N11219986: length 2.9
  TOP w0.173: R69.1 C101.1 105.26,16.36 U8.5
N11220684: length 1.8
  TOP w0.173: C86.1 110.52,16.36 U8.1
N12123192: length 7
  BOTTOM w0.173: J10.11 28.74,145.88 R293.2
N12123204: length 6.1
  BOTTOM w0.173: R296.2 34.26,145.97 J10.14
N12138943: length 2.4
  TOP w0.173: R298.1 39.71,123.61 U21.48
N12139138: length 5.3
  TOP w0.173: TP16.1 43.43,119.72 41.02,119.72 40.4,120.34 40.01,120.34 39.78,120.11 U21.41
N12220066: length 23
  TOP w0.173: v2(21.59,122.13) 21.84,121.87 21.84,120.51 21.7,120.37 C111.1 21.59,120.24 21.59,119.63 22.02,119.21 C109.1 ; v2(24.31,115.85) 24.58,116.12 C110.1
  L9_SIG3 w0.114: v2(24.31,115.85) 24.31,117.25 21.59,119.97 v2(21.59,122.13)
  L10_SIG4 w0.109: v9(24.51,122.13) 24.28,122.36 23.09,122.36 22.61,121.87 21.84,121.87 v2(21.59,122.13)
  BOTTOM w0.173: v9(24.51,122.13) 24.26,122.38 22.99,122.38 22.59,121.98 U9.15 ; v2(24.31,115.85) 24.33,115.84 C108.1 25.17,116.39 24.61,116.95 U9.24 ; U9.13 v2(21.59,122.13)
N12225140: length 4.2
  BOTTOM w0.173: J5.11 8.21,113.46 R122.1
N12225158: length 11.1
  TOP w0.173: v7(27.43,100.31) 28.05,100.31 28.19,100.16 U13.13 ; U13.15 28.05,99.16 v2(27.55,98.66) ; U13.24 33.25,97.14 v7(33.53,96.86) 34.42,95.97 C123.1
  BOTTOM w0.173: v2(27.55,98.66) 27.55,97.86 27.19,97.5 C125.1 ; v2(28.7,97.24) 28.59,97.34 C126.1 C124.1
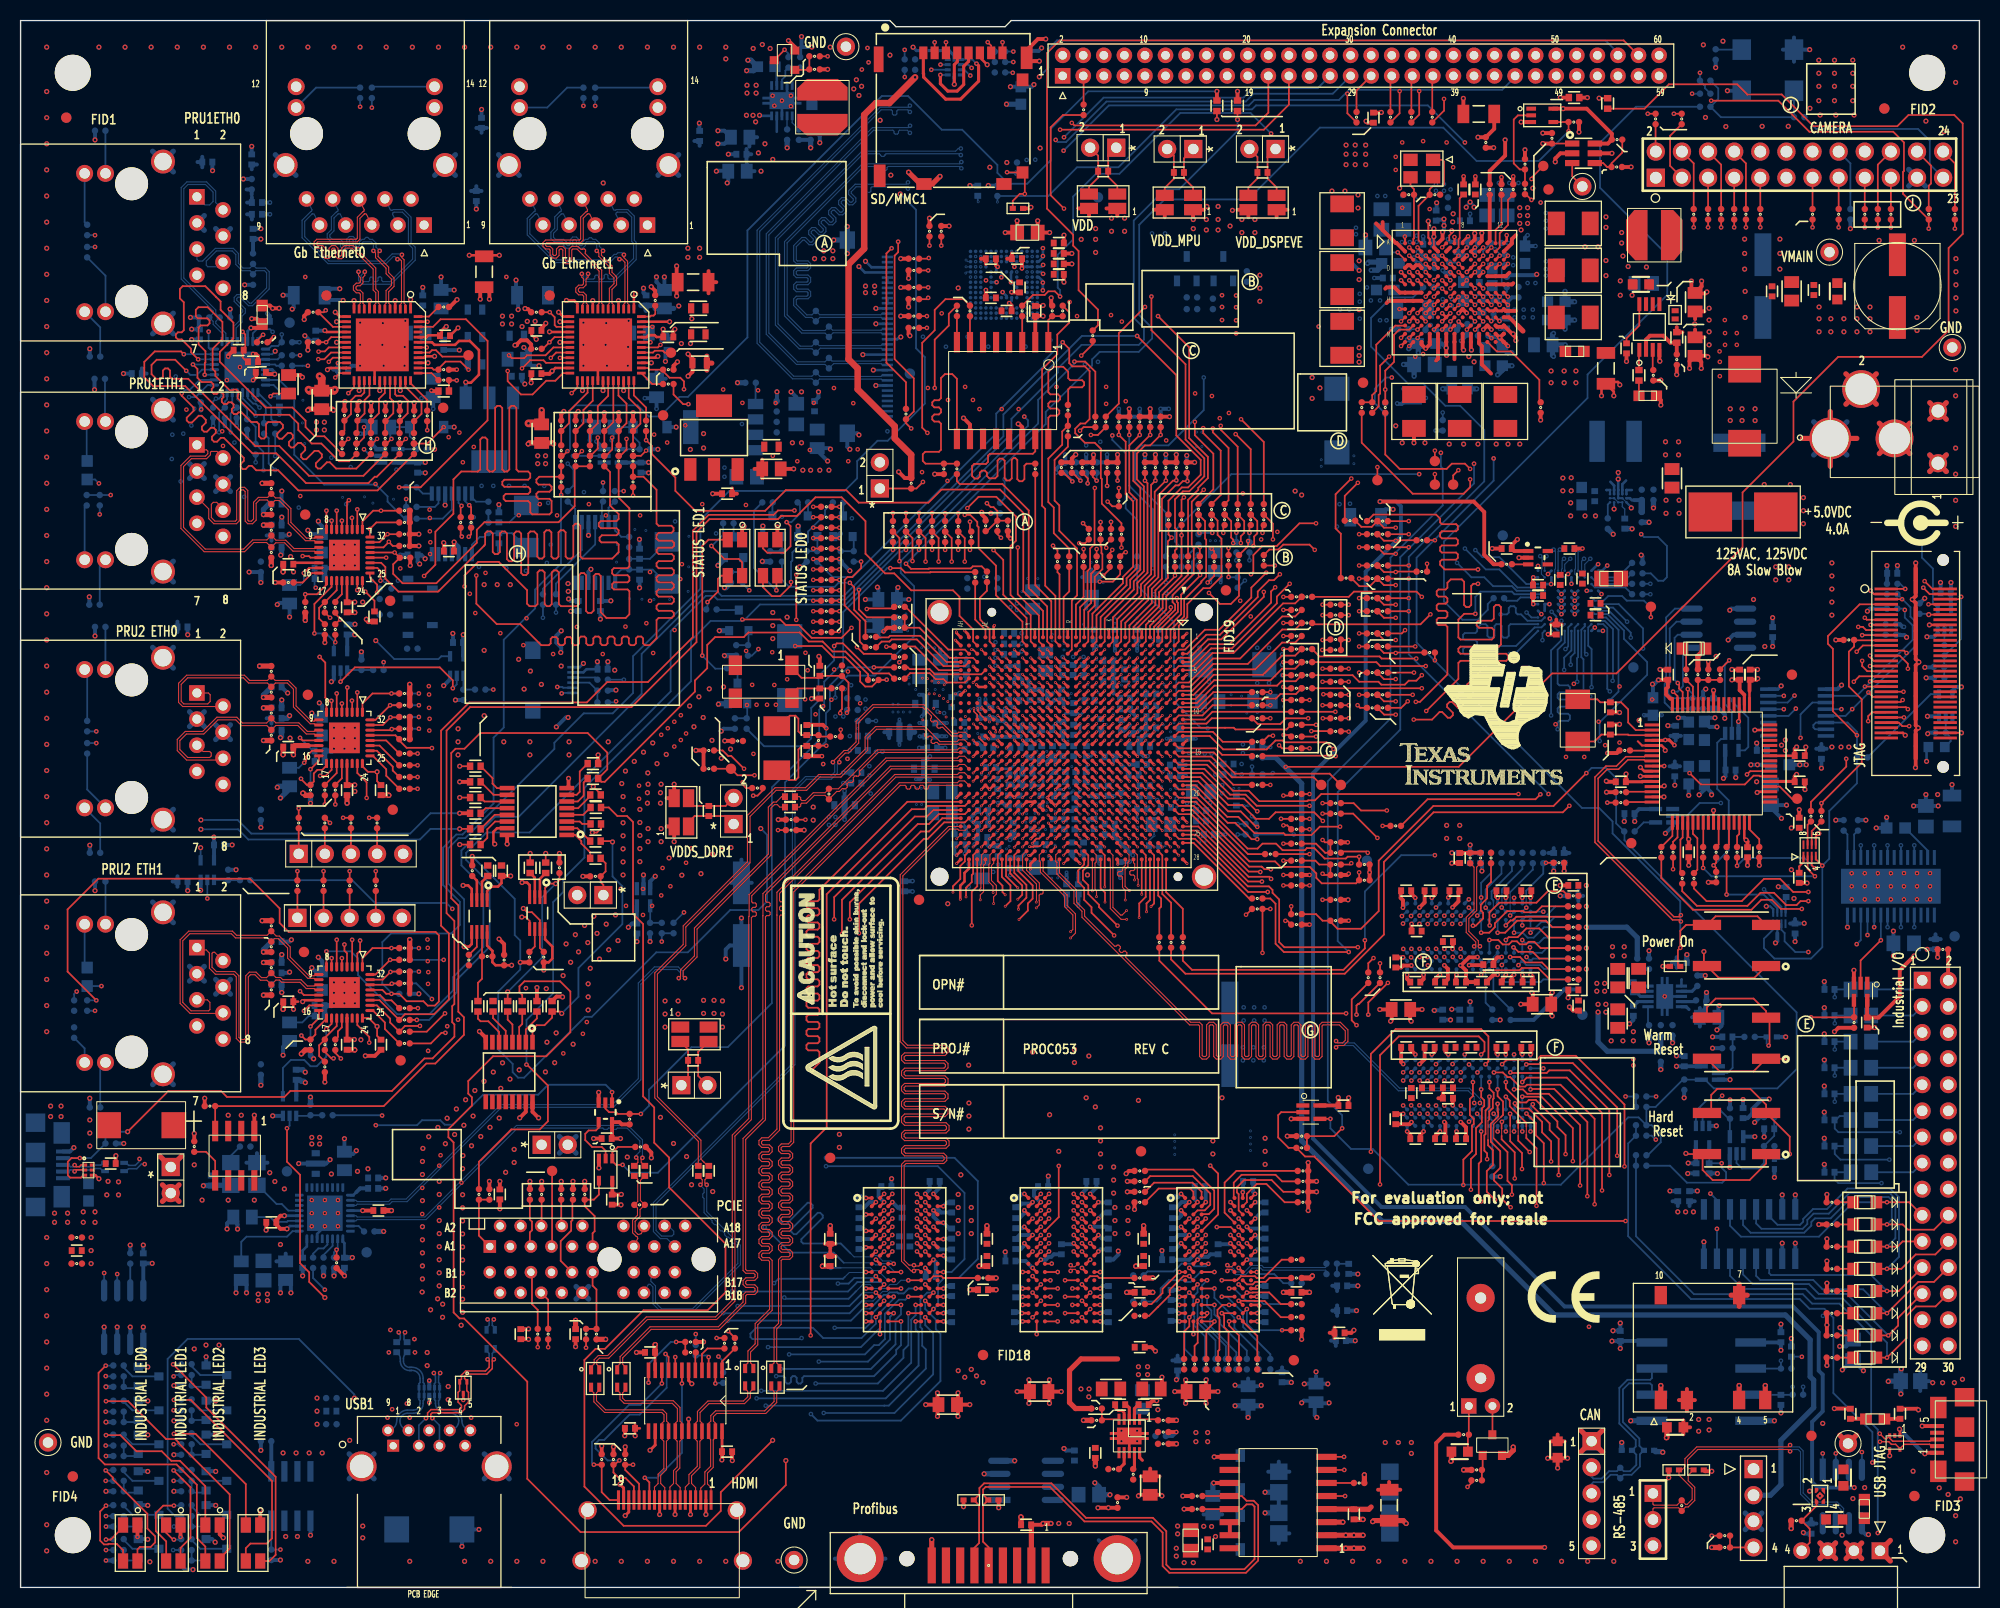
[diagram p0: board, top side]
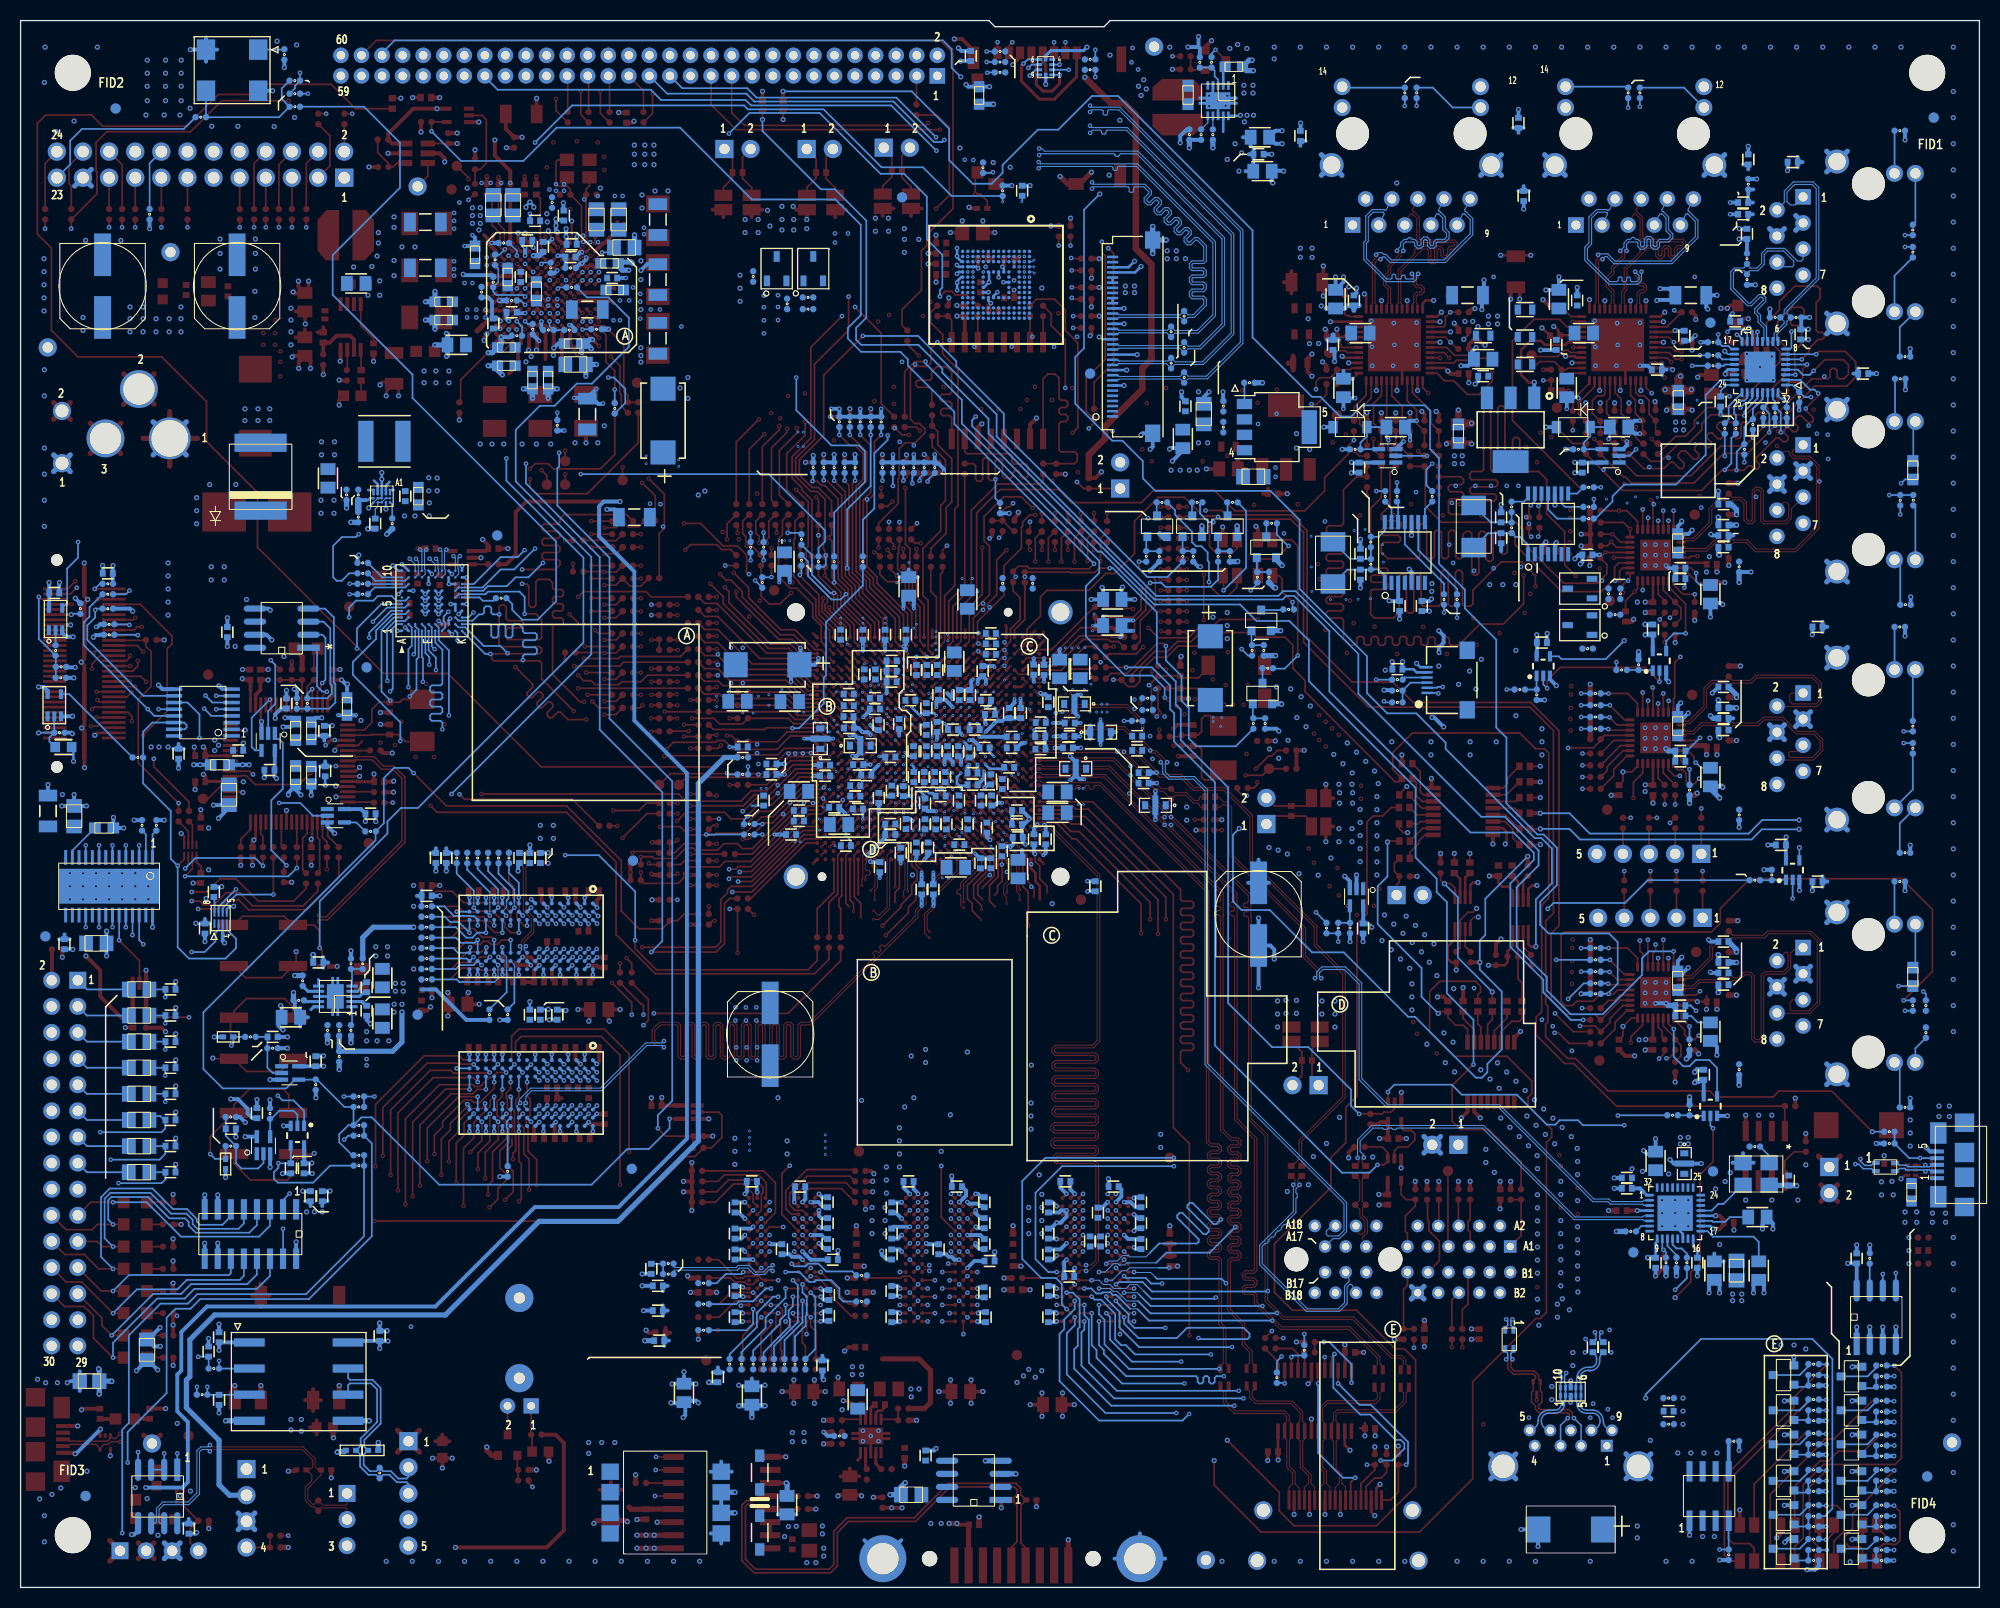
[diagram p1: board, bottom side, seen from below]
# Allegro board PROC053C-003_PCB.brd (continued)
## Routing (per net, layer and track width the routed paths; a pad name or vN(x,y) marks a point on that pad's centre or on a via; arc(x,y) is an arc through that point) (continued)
N12225278: length 5.4
  BOTTOM w0.173: J5.10 6.23,105.03 R151.1
N12226470: length 4.6
  BOTTOM w0.173: R134.1 7.7,99.4 J5.9
N12226568: length 2.6
  BOTTOM w0.173: R154.1 R153.1 31.83,89.24 U69.1
N12957779: length 2.5
  TOP w0.173: U37.28 166.14,72.24 R482.2
N12957783: length 9.5
  TOP w0.173: R482.1 v2(165.91,67.39)
  BOTTOM w0.173: v2(165.91,67.39) 169.52,67.39 170.84,66.07 U75.6
N12957791: length 2.8
  TOP w0.173: R489.2 169.09,72.78 168.14,73.72 U37.32
N12957851: length 4.6
  TOP w0.173: U37.59 163.14,88.25 R491.1 R494.2 R492.2
N12958009: length 2.6
  TOP w0.173: U37.14 156.18,77.39 R485.1
N12958129: length 2.2
  TOP w0.173: R493.2 161.98,90.95 D13.1
N12958219: length 15.1
  BOTTOM w0.173: U38.4 160.89,95.2 160.03,94.35 160.03,88.02 159.89,87.88 159.89,86.07 160.48,85.48 R495.2 R496.1
N12958339: length 3.2
  TOP w0.173: TP18.1 172.26,76.71 171.08,77.89 U37.36
N12958347: length 2.7
  TOP w0.173: U37.60 162.64,87.61 R493.1
N12958879: length 28.2
  TOP w0.173: R474.1 v2(154.31,76.33)
  L9_SIG3 w0.114: v2(172.64,85.48) 172.19,85.93 160.66,85.93 155.62,80.9 155.62,77.65 v2(154.31,76.33)
  BOTTOM w0.173: v2(172.64,85.48) 171.94,84.77 U63.4
N12958935: length 35.5
  TOP w0.173: R476.1 162.74,67.98 163.96,66.76 167.39,66.76 169.55,68.92 171.11,68.92 172.38,67.65 v2(173.86,67.65)
  L10_SIG4 w0.109: v2(171.47,86.72) 171.55,86.72 172.14,86.13 172.14,77.62 173.86,75.9 173.86,69.11 174.25,68.72 174.25,68.03 v2(173.86,67.65)
  BOTTOM w0.173: U63.7 v2(171.47,86.72)
N12958939: length 39.7
  TOP w0.173: v2(173.86,66.76) 173.1,66.76 172.72,66.38 171.7,66.38 170.52,67.56 169.2,67.56 167.94,66.29 163.02,66.29 161.59,67.72 R481.1
  L10_SIG4 w0.109: v2(172.52,86.75) 174.24,85.02 174.24,76.21 175.77,74.68 175.77,69.55 174.75,68.53 174.75,67.65 v2(173.86,66.76)
  BOTTOM w0.173: U63.6 171.84,86.07 v2(172.52,86.75)
N12958943: length 14.1
  TOP w0.173: R480.1 v7(160.71,69.85)
  L3_SIG1 w0.109: v7(160.71,69.85) 160.73,69.85 161.29,69.3 168.78,69.3 v5(169.55,68.53)
  L10_SIG4 w0.109: v9(169.55,67.9) v5(169.55,68.53)
  BOTTOM w0.173: v9(169.55,67.9) 171.24,66.21 U75.7
N12958955: length 40
  TOP w0.173: R475.1 159.56,68.99 162.64,65.91 168.32,65.91 169.29,66.88 170.31,66.88 171.2,65.99 v2(173.23,65.99)
  L10_SIG4 w0.109: v2(173.23,65.99) 173.23,67.51 172.85,67.89 172.85,74.38 172.34,74.88 172.34,76.41 170.73,78.01 170.73,84.68 v2(171.47,85.42)
  BOTTOM w0.173: U63.5 v2(171.47,85.42)
N15911835: length 2.9
  TOP w0.173: U13.16 28.35,98.66 27.43,97.74 26.54,97.74
N16251668: length 72.4
  TOP w0.173: R385.1 128.52,71.58 130.89,71.58 v7(131.01,71.46)
  L3_SIG1 w0.109: v7(131.01,71.46) v5(131.62,71.46)
  L9_SIG3 w0.114: v5(131.62,71.46) 131.97,71.81 133.73,71.81 135,73.08 138.18,73.08 138.47,73.37 151.37,73.37 166.76,57.98 166.76,37.55 164.97,35.76 v2(164.97,34.88)
  BOTTOM w0.173: v2(164.97,34.88) U73.15
N16251678: length 64.8
  TOP w0.173: v7(129.41,70.44) 129.29,70.31 R387.1
  L3_SIG1 w0.109: v5(133.48,71.2) 132.49,70.21 129.64,70.21 v7(129.41,70.44)
  L9_SIG3 w0.114: v5(133.48,71.2) 133.54,71.2 134.52,72.19 140.03,72.19 140.82,72.97 149.15,72.97 163.04,59.08 163.04,39.6 v2(164.34,38.31)
  BOTTOM w0.173: v2(164.34,38.31) 164.97,37.67 U73.2
N16700927: length 3.9
  BOTTOM w0.173: R138.1 6.43,109.61 6.43,113.2 J5.12
N16818719: length 2.5
  BOTTOM w0.173: R112.1 R107.1 43.07,87.35 U68.1
N16819128: length 1.9
  TOP w0.173: v2(23.59,121.84) 22.99,121.24 R103.2
  BOTTOM w0.173: U9.16 23.09,121.47 23.46,121.84 v2(23.59,121.84)
N16839202: length 3.8
  BOTTOM w0.173: R382.2 185.46,71.68 U72.13
N16839209: length 2.8
  BOTTOM w0.173: R381.2 178.31,73.24 U72.2
N16839216: length 2.8
  BOTTOM w0.173: R380.2 177.66,73.24 U72.1
N16844891: length 1.6
  TOP w0.173: R388.2 D6.2
N16844892: length 1.6
  TOP w0.173: R395.2 D11.2
N16844893: length 1.6
  TOP w0.173: R396.2 D12.2
N16844894: length 1.6
  TOP w0.173: R391.2 D9.2
N16844899: length 1.6
  TOP w0.173: R392.2 D10.2
N16844909: length 1.6
  TOP w0.173: R386.2 D5.2
N16844924: length 1.6
  TOP w0.173: R390.2 D8.2
N16844930: length 1.6
  TOP w0.173: R389.2 D7.2
N17007255: length 68.2
  TOP w0.173: R377.1 v7(125.35,71.33) ; U28.4 178.31,57.09 R366.1 v2(174.12,55.45)
  L3_SIG1 w0.109: v7(125.35,71.33) 126.45,70.22 v5(128.54,70.22)
  L9_SIG3 w0.114: v2(174.12,55.45) 171.02,55.45 151.83,74.64 136.14,74.64 133.67,72.16 131.7,72.16 130.59,71.05 129.37,71.05 v5(128.54,70.22)
N17074741: length 6
  BOTTOM w0.173: J3.9 8.26,127.58 R106.1
N17120040: length 2.8
  TOP w0.173: R743.1 103.38,146.99 J21.3
N17120055: length 62
  TOP w0.173: R744.1 121.44,100.95 122.32,100.95 122.8,101.43 125.35,101.43 v7(125.86,100.92)
  L3_SIG1 w0.109: v7(125.86,100.92) 126.29,100.92 127.71,102.34 127.71,104.83 124.46,108.08 124.46,112.07 113.64,122.89 113.64,124.87 108.03,130.48 108.03,135.18 105.35,137.86 J21.5
N17120061: length 60.4
  L3_SIG1 w0.109: v5(111.38,128.27) 108.89,130.76 108.89,136.68 109.35,137.14 J21.9
  L4_SIG2 w0.114: v5(110.27,97.43) 110.62,97.77 110.62,103.46 111.3,104.15 111.3,105.1 110.54,105.87 110.54,107.01 110.85,107.32 110.85,110.68 111.67,111.5 111.67,112.99 111.01,113.65 111.01,122.87 111.38,123.24 v5(111.38,128.27)
  L10_SIG4 w0.109: v9(110.24,96.6) 110.27,96.64 v5(110.27,97.43)
  BOTTOM w0.173: R746.1 113.92,99.78 113.92,98.38 111.63,96.09 110.74,96.09 v9(110.24,96.6)
N17120072: length 67.1
  L3_SIG1 w0.109: v5(129,106.45) 127.61,106.45 125.15,108.92 125.15,112.34 114.81,122.68 114.81,125.53 109.47,130.87 109.47,136.07 110.16,136.75 110.16,141.58 111.35,142.77 J21.11
  L10_SIG4 w0.109: v9(119.06,97.93) 119.7,97.93 120.45,98.68 121.92,98.68 122.86,99.62 122.86,103.66 124.59,105.39 126.59,105.39 127.66,106.45 v5(129,106.45)
  BOTTOM w0.173: R747.1 v9(119.06,97.93)
N17120087: length 95.7
  TOP w0.173: v7(102.23,142.45) 102.48,142.2 120.11,142.2 121.35,143.44 J21.21 ; R752.1 v7(59.56,106.2)
  L3_SIG1 w0.109: v5(60.12,105.95) 59.87,106.2 v7(59.56,106.2) ; v5(74.02,137.42) 76.51,137.42 78.28,139.19 101.55,139.19 102.23,139.88 v7(102.23,142.45)
  L4_SIG2 w0.114: v5(74.02,137.42) 74.02,137.41 67.48,130.88 67.48,110.05 63.38,105.95 v5(60.12,105.95)
N17120090: length 104.3
  TOP w0.173: J21.23 123.35,144.22 120.91,141.79 v7(101.09,141.79) ; R753.1 v7(52.58,106.28)
  L3_SIG1 w0.109: v5(51.82,106.3) 51.84,106.28 v7(52.58,106.28) ; v7(101.09,141.79) 100.11,141.79 97.89,139.57 77.7,139.57 76.1,137.97 73.48,137.97 v5(72.97,137.47)
  L4_SIG2 w0.114: v5(51.82,106.3) 53.49,107.98 58.88,107.98 59.18,107.68 64.47,107.68 67.19,110.39 67.19,131 72.97,136.79 v5(72.97,137.47)
N17144335: length 2.5
  TOP w0.173: R29.1 97.41,121.11
N17156111: length 7.3
  BOTTOM w0.173: U23.1 43.89,101.41 44.66,102.18 45.12,102.18 R305.2 45.52,102.54 C172.2 47.78,102.54 Y3.2
N17156113: length 5.4
  BOTTOM w0.173: R308.2 R305.1 45.52,103.59 C173.2 47.53,103.59 Y3.1
N17156222: length 2.2
  BOTTOM w0.173: U23.14 43.89,106.02 44.3,105.6 R308.1
N17156522: length 5.4
  BOTTOM w0.173: U23.11 41.94,104.84 41.05,103.95 R310.1
N17156525: length 3.2
  BOTTOM w0.173: R313.1 40.29,105.1 40.64,105.45 U23.9
N17156528: length 1.7
  BOTTOM w0.173: R315.1 39.12,106.4 U23.8
N17156983: length 2.5
  TOP w0.173: v2(42.88,105.19) 42.8,105.11 R314.1
  BOTTOM w0.173: v2(42.88,105.19) 42.59,105.49 U23.12
N17156986: length 2.5
  TOP w0.173: R312.1 43.81,105.07 v2(43.63,105.26)
  BOTTOM w0.173: v2(43.63,105.26) 43.24,105.65 U23.13
N17569906: length 7
  BOTTOM w0.173: J12.11 51.22,143.94 53.16,145.88 R337.2
N17569909: length 6.1
  BOTTOM w0.173: R340.2 61.88,145.88 J12.14
N17569918: length 2.3
  TOP w0.173: R341.1 61.72,123.86 61.56,123.7 61.31,123.7 61.22,123.61 U24.48
N17569921: length 3
  TOP w0.173: TP17.1 62.65,120.1 62.46,120.29 61.68,120.29 61.5,120.11 U24.41
N17570093: length 6.6
  BOTTOM w0.173: U25.1 57.83,98.42 58.42,99.01 R349.2 59.2,99 C193.2 61.47,99 Y4.2
N17570094: length 5.5
  BOTTOM w0.173: Y4.1 61.21,100.05 C194.2 59.2,100.05 R349.1 R351.2
N17570107: length 2.4
  BOTTOM w0.173: R351.1 58.42,102.19 57.83,102.78 U25.14
N17570112: length 8.6
  BOTTOM w0.173: R354.1 52.07,97.64 55.88,101.45 U25.11
N17570113: length 8.6
  BOTTOM w0.173: U25.9 54.58,100.91 50.8,97.13 R357.1
N17570114: length 2.3
  BOTTOM w0.173: U25.8 53.93,104.9 R359.1
N17570122: length 2
  BOTTOM w0.173: R358.1 56.53,105.51 U25.12
N17570123: length 2.3
  BOTTOM w0.173: U25.13 57.18,105.01 R356.1
N17594977: length 12.1
  TOP w0.173: U15.13 27.43,82.38 v2(27.18,82.63) ; U15.24 33.25,79.86 33.78,79.33 34.67,79.33 v1(34.67,79.33) 34.67,78.42 C135.1 ; v2(27.58,80.22) 27.76,80.4 27.76,80.8 28.34,81.38 U15.15
  BOTTOM w0.173: C136.1 27.06,79.72 27.56,80.22 v2(27.58,80.22) ; v2(27.18,82.63) 28.45,81.36 C138.1 C134.1
N17595032: length 2.5
  BOTTOM w0.173: R195.1 R190.1 20.16,68.82 U70.1
N17595048: length 3.2
  TOP w0.173: U15.16 29.02,80.41 v2(28.19,79.58)
  BOTTOM w0.173: v2(28.19,79.58) R186.2
N17595072: length 6
  BOTTOM w0.173: R189.1 6.48,77.61 J6.9
N17595076: length 4.2
  BOTTOM w0.173: R161.1 8.25,89.28 J6.11
N17595078: length 5.1
  BOTTOM w0.173: R176.1 6.48,89.03 J6.12
N17596821: length 4.2
  BOTTOM w0.173: J8.11 8.26,68.66 R203.1
N17596823: length 11.8
  TOP w0.173: U17.15 28.09,56.62 v2(27.56,56.09) ; C147.1 34.67,53.66 v1(34.67,54.56) 33.84,55.39 U17.24 ; v2(27.18,57.99) 27.55,57.62 U17.13
  BOTTOM w0.173: v2(27.56,56.09) 28.07,56.6 C148.1 C150.1 28.02,55.58 27.4,54.96 C149.1
N17596838: length 2.8
  BOTTOM w0.173: J8.10 6.23,52.43 5.21,53.46
N17596847: length 13.4
  TOP w0.173: R230.2 123.42,77.02 v7(122.81,77.02) ; U1.C17 v4(111.83,79.22)
  L3_SIG1 w0.109: v7(122.81,77.02) 122.22,77.6 121.28,77.6 120.05,78.84 115.88,78.84 115.73,78.69 115.29,78.69 114.77,79.22 v4(111.83,79.22)
N17596886: length 4.6
  BOTTOM w0.173: R214.1 7.75,50.55 J8.9
N17596899: length 2.6
  BOTTOM w0.173: R234.1 R233.1 28.13,45.87 U71.1
N17596976: length 3.2
  TOP w0.173: v2(28.19,54.56) 29.02,55.39 U17.16
  BOTTOM w0.173: R228.2 v2(28.19,54.56)
N17596979: length 4.3
  BOTTOM w0.173: J8.12 6.23,60.54 R218.1
N17597002: length 297.9
  TOP w0.173: 124.59,77.17 v7(125.35,77.17)
  L3_SIG1 w0.109: v5(125.2,78.16) 125.35,78.01 v7(125.35,77.17)
  L4_SIG2 w0.114: v2(7.24,56.09) 10.46,56.09 16.05,50.5 16.05,46.91 18.49,44.48 18.49,28.36 21.9,24.95 21.9,11.58 27.64,5.84 28.24,5.84 29.98,4.1 41.51,4.1 42.4,4.99 50.3,4.99 55.93,10.62 56.3,10.62 56.83,11.16 68.37,11.16 69.19,10.34 92.46,10.34 93.14,9.66 97.78,9.66 98.42,9.02 105.04,9.02 105.72,9.7 113.36,9.7 114.61,8.45 132.22,8.45 138.78,15.01 145.1,15.01 153.04,22.94 154.5,22.94 155.53,23.97 156.29,23.97 168.85,36.53 168.85,41.85 170.13,43.13 170.13,45.39 169.21,46.3 169.21,60.17 161.72,67.66 160.4,67.66 149.58,78.48 130.25,78.48 129.58,77.81 125.55,77.81 v5(125.2,78.16)
  BOTTOM w0.173: R231.2 v2(7.24,56.09) ; 5.23,56.09 5.21,56.09
N17731118: length 2.5
  BOTTOM w0.173: R241.1 R245.2 11.24,2.62 Q1.G
N17731139: length 2.5
  BOTTOM w0.173: Q5.G 11.24,5.92 R255.2 R253.2
N17732522: length 1.6
  BOTTOM w0.127: U32.6 75.04,142.46 R410.1
N17732526: length 3.2
  BOTTOM w0.173: U32.3 74.04,146.65 74.38,146.98 74.38,147.53 R413.2 R414.2
N17732536: length 2.3
  TOP w0.173: Q9.D 74.3,149.55 v2(74.3,149.56)
  BOTTOM w0.173: R413.1 74.68,149.18 v2(74.3,149.56)
N17732560: length 1.3
  BOTTOM w0.127: U32.7 74.54,141.82 R411.1
N17745676: length 6.2
  TOP w0.173: J9.22 185.79,138.29 185.79,136.55 185.57,136.33 R275.2
N17745678: length 6.1
  TOP w0.173: J9.24 188.11,138.51 R277.2
N17745710: length 17.3
  BOTTOM w0.173: R903.1 174.62,141.86 184.53,141.86 185.67,140.72 185.67,138.41 J9.23
N17863265: length 4.2
  BOTTOM w0.173: R78.1 8.25,137.54 J3.11
N17863276: length 5.1
  BOTTOM w0.173: R93.1 6.23,132.79 J3.12
N18733248: length 19.6
  TOP w0.173: R497.1 79.88,85.43 79.73,85.28 79.73,85.05 v7(79.71,85.04) ; U1.AD14 v4(95.03,81.75)
  L3_SIG1 w0.109: v7(79.71,85.04) 79.82,84.93 79.88,84.93 81.37,83.44 87.58,83.44 87.74,83.28 89.07,83.28 89.22,83.13 90.84,83.13 91.21,82.76 92.71,82.76 92.76,82.71 92.93,82.54 92.93,82.54 93.05,82.41 93.84,82.41 94.04,82.22 94.57,82.22 v4(95.03,81.75)
N18733249: length 4.5
  TOP w0.173: R497.2 78.85,87.44 C247.1 75.55,87.44 75.01,86.9 Y6.4
N18733252: length 24.3
  TOP w0.173: v4(93.23,82.71) 93.23,82.62 U1.AE14 ; v7(80.36,85.07) 80.36,85.14 80.52,85.3 80.52,85.55 80.52,85.55 80.52,88.01 R927.2 79.86,88.66 C246.1 77.53,88.47 75.95,88.47 75.01,89.41 Y6.1
  L3_SIG1 w0.109: v4(93.23,82.71) 93.23,82.7 92.93,83 91.27,83 90.92,83.35 89.31,83.35 89.04,83.62 87.91,83.62 87.8,83.72 81.7,83.72 v7(80.36,85.07)
N18733262: length 31.2
  TOP w0.173: v2(71.25,77.01) 71.67,77.01 72.17,77.51 R499.2 ; U1.AF14 v4(92.64,82.41)
  L3_SIG1 w0.109: v5(90.74,82.51) 90.77,82.51 90.86,82.41 v4(92.64,82.41)
  L9_SIG3 w0.114: v5(90.74,82.51) 91.81,82.51 92.25,82.07 92.25,80.85 91.47,80.06 84.67,80.06 82.79,81.95 79.18,81.95 74.09,76.86 71.53,76.86 71.3,77.09 71.3,77.01 v2(71.25,77.01)
N18733263: length 2.8
  BOTTOM w0.173: R500.1 R498.1 61.23,64.66 U39.4
N18733273: length 47.9
  TOP w0.173: U1.AB17 v4(95.84,79.22)
  L3_SIG1 w0.109: v5(72.52,75.03) 72.52,71.91 67.11,66.5 64.52,66.5 63.45,65.43 63.45,63.91 v2(62.36,62.82) ; v4(95.84,79.22) v5(95.44,78.97)
  L9_SIG3 w0.114: v5(72.52,75.03) 72.52,74.5 73.99,73.02 77.44,73.02 78.99,74.57 87.63,74.57 90.25,77.19 92.1,77.19 92.31,76.98 94,76.98 94.25,77.23 94.25,77.6 94.69,78.03 94.69,78.16 95.44,78.91 v5(95.44,78.97)
  BOTTOM w0.173: v2(62.36,62.82) R500.2 R926.2
N18733274: length 21.2
  TOP w0.173: U1.Y11 v4(97.44,84.81) ; R929.2 95,102.44 v2(95.34,102.1)
  L3_SIG1 w0.109: v4(97.44,84.81) v5(97.04,85.06)
  L4_SIG2 w0.114: v2(95.34,102.1) 96.39,101.05 96.39,91.02 94.89,89.52 94.89,87.46 95.28,87.08 95.6,87.08 95.85,86.83 95.85,86.5 96.08,86.28 96.37,86.28 96.63,86.03 96.63,85.45 97.01,85.06 v5(97.04,85.06)
N18733276: length 28.4
  TOP w0.173: R923.1 TP19.1 69.72,78.99 v7(71.37,78.99) ; U1.AD17 v4(94.24,79.22)
  L3_SIG1 w0.099: v4(94.24,79.22) 93.85,79.22 93.56,79.51 93.31,79.51 93.2,79.39 92.88,79.39 92.33,79.94 92.05,79.94
  L3_SIG1 w0.109: v7(71.37,78.99) 72.26,78.99 72.39,79.12 80.27,79.12 81.09,79.94 92.05,79.94
N18868530: length 10.4
  TOP w0.173: R14.1 R572.2 131.44,115.97 131.84,116.36 131.84,120.87 133.7,122.73 134.64,122.73 U3.L1
N18868533: length 10.5
  TOP w0.173: R15.1 v2(132.72,116.51) 132.72,118.34 133.57,119.2 133.57,121.84 134.07,122.34 135.05,122.34 U3.L2
  BOTTOM w0.173: R588.2 v2(132.72,116.51)
N18913166: length 21.8
  TOP w0.173: TP7.1 v7(131.95,108.97) ; U3.J5 v7(137.45,123.94)
  L3_SIG1 w0.109: v7(137.45,123.94) 137.07,123.56 136.51,123.56 136.26,123.3 136.26,123 136,122.74 134.09,122.74 131.95,120.6 131.95,120.24 130.43,118.71 130.43,111.33 131.95,109.81 v7(131.95,108.97)
N18913202: length 2.6
  TOP w0.173: U3.K7 v2(139.05,123.14)
  BOTTOM w0.173: v2(139.05,123.14) 139.05,122.69 R934.1 R17.1
N18913205: length 1.4
  TOP w0.173: U3.L3 v2(135.85,122.34)
  BOTTOM w0.173: 135,122.38 135.81,122.38 v2(135.85,122.34)
N18913322: length 6.8
  TOP w0.173: U3.G9 v2(141.44,125.54)
  BOTTOM w0.152: R983.1 144.04,128.3 144.04,126.95 R18.1
  BOTTOM w0.173: v2(141.44,125.54) 141.6,125.7 144.22,125.7 144.54,126.02 R18.1
N18913403: length 10.8
  TOP w0.173: U3.A3 135.95,131.03 135.95,134.38 C26.2 137.03,135.99 137.33,136.29 138.24,136.29 138.43,136.48 138.43,138.68 138.26,138.85 Y2.1
N18913412: length 6.6
  TOP w0.173: Y2.3 135.17,136.34 135.51,136 C25.2 135.51,131.23 135.45,131.16 U3.A2
N18913758: length 5.9
  TOP w0.173: U3.B7 139.85,130.34 139.85,131.14 139.95,131.25 139.95,135.1 C27.2
N18914093: length 2.3
  TOP w0.173: U3.C1 v2(133.93,129.85)
  BOTTOM w0.173: v2(133.93,129.85) 133.27,129.85 C578.1
N18914190: length 17.8
  TOP w0.173: v7(143.05,121.5) 142.65,121.9 U3.M11 ; TP2.1 v7(137.54,110.57)
  L3_SIG1 w0.109: v7(137.54,110.57) 137.54,111.1 135.96,112.68 135.96,113.82 139.57,117.43 142.37,117.43 143.05,118.11 v7(143.05,121.5)
N18914214: length 28
  TOP w0.173: TP3.1 v7(137.54,108.29) ; U3.J7 v7(139.84,124.73)
  L3_SIG1 w0.109: v7(137.54,108.29) 136.4,109.43 135.89,109.43 134.9,110.42 134.9,111.59 134.49,111.99 133.9,111.99 130.72,115.18 130.72,118.59 134.05,121.93 136.07,121.93 136.35,122.2 136.35,122.48 136.63,122.76 139.21,122.76 139.45,122.99 U3.J7 v7(139.84,124.73)
N18914339: length 94.1
  TOP w0.173: U50.1 161.35,60.41 161.18,60.58 161.18,61.98 v2(161.41,62.21) 161.41,63.87 161.97,64.44 SW3.4 164.84,65.28 168.91,65.28 SW3.3 ; U3.G8 v7(140.64,125.54)
  L3_SIG1 w0.109: v7(140.64,125.54) 141.05,125.14 141.05,124.58 141.3,124.33 141.6,124.33 141.82,124.1 141.82,123.8 142.06,123.56 143.22,123.56 143.44,123.34 143.44,113.82 144.02,113.23 144.02,110.57 v2(143.26,109.81)
  BOTTOM w0.173: v2(143.26,109.81) 143.26,107.65 135.76,100.16 135.76,91.9 151.85,75.81 153.51,75.81 154.82,74.5 154.82,73.34 161.41,66.75 v2(161.41,62.21)
N18914524: length 37.7
  TOP w0.173: v7(139.83,108.67) 139.32,108.16 TP6.1 ; U3.C11 v2(143.04,129.53)
  L3_SIG1 w0.109: v2(143.04,129.53) 142.64,129.93 142.09,129.93 141.84,129.68 141.84,127.74 142.19,127.38 145.16,127.38 145.67,126.87 147.91,126.87 148.72,126.07 148.72,123.02 149.36,122.38 149.36,113.87 144.78,109.3 142.62,109.3 142.11,109.81 140.97,109.81 v7(139.83,108.67)
N18915671: length 19.9
  TOP w0.254: U3.B3 v7(135.85,130.33)
  TOP w0.381: R19.1 v1(143.26,140.04)
  L3_SIG1 w0.381: v7(135.85,130.33) 135.33,130.85 134.15,130.85 132.87,132.14 132.87,134.09 133.74,134.96 134.58,134.96 139.05,139.43 142.65,139.43 v1(143.26,140.04)
N18915723: length 4.8
  TOP w0.381: U3.A11 142.88,130.97 R20.1
N18915943: length 1.5
  TOP w0.173: U3.D8 v2(139.85,128.73)
  BOTTOM w0.173: v2(139.85,128.73) 139.73,128.86 R21.1
N19120663: length 5
  TOP w0.173: R41.2 89.73,30.1 89.56,30.28 88.78,30.28 U5.L8
N19139994: length 11.9
  TOP w0.173: R32.1 118.24,40.51 117.09,39.37 117.09,36.45 118.06,35.48 U6.D7
N19139997: length 10.9
  TOP w0.173: R33.1 109.47,40.64 114.05,40.64 116.08,38.61 116.08,36.83 115.56,36.31 114.9,36.31 U6.C3
N19140025: length 9.6
  TOP w0.173: R34.1 122.81,38.48 121.67,39.62 119,39.62 118.29,38.92 118.29,38.42 118.46,38.25 118.46,36.68 U6.C8
N19140027: length 10.4
  TOP w0.173: R35.1 109.86,40 114,40 115.7,38.31 115.7,37.21 115.16,36.68 114.46,36.68 U6.C2
N19140065: length 8.3
  TOP w0.173: R37.1 122.68,39.5 122.05,40.13 118.75,40.13 117.98,39.37 117.98,37.95 U6.A7
N19140067: length 6
  TOP w0.173: R38.1 110.68,38.79 113.75,38.79 114.06,38.48 U6.A2
N19140105: length 7.5
  TOP w0.173: R39.1 122.94,37.46 121.16,39.24 120.22,39.24 119.26,38.29 119.26,37.48 U6.B8
N19140107: length 6.9
  TOP w0.173: U6.A3 114.86,38.48 113.97,39.37 110.24,39.37 R40.1
N19258097: length 1.6
  BOTTOM w0.173: U45.7 32.87,35.15 R546.1
N19258128: length 5.1
  BOTTOM w0.173: Y7.3 23.07,39.11 24.89,37.29 25.4,37.29 26.04,36.65 U45.21
N19258198: length 1.9
  BOTTOM w0.173: R547.1 20.45,41.99 Y7.1
N19258383: length 2.2
  BOTTOM w0.173: U45.11 30.34,33.22 29.46,32.34 R548.1
N19258403: length 2.8
  TOP w0.173: R550.1 v2(30.73,32.85)
  BOTTOM w0.173: R549.1 30.48,32.59 v2(30.73,32.85) 30.84,32.95 U45.10
N19258622: length 8
  BOTTOM w0.173: U45.17 26.45,34.65 25.91,34.12 21.97,34.12 21.46,33.61 C305.1
N19258627: length 4.9
  BOTTOM w0.173: C306.1 24.27,36.02 24.73,35.56 25.9,35.56 25.99,35.65 U45.19
N19290398: length 2.6
  BOTTOM w0.173: R421.1 U33.7
N19388440: length 4.4
  BOTTOM w0.173: U89.B9 153.08,97.93 156.01,97.93 R566.1
N19415733: length 2.7
  BOTTOM w0.173: R568.1 28.45,32.47 28.96,32.97 29.46,32.97 29.84,33.35 U45.12
N19425975: length 19.2
  TOP w0.173: U1.E23 v4(110.23,74.42) ; R7.1 v7(123.57,66.25)
  L3_SIG1 w0.099: v4(110.23,74.42) 110.6,74.42 111.11,73.91 112.36,73.91
  L3_SIG1 w0.109: 112.36,73.91 112.78,73.49 115.34,73.49 118.31,70.51 118.31,68.58 120.27,66.62 121.67,66.62 122.05,66.25 v7(123.57,66.25)
N19426030: length 16.3
  TOP w0.173: U1.D21 v4(111.03,76.02) ; R8.1 v7(122.81,69.3)
  L3_SIG1 w0.109: v7(122.81,69.3) 122.81,69.95 121.38,71.38 120.02,71.38 115.85,75.54 111.89,75.54 111.42,76.02 v4(111.03,76.02)
N19426454: length 17.4
  TOP w0.173: U1.AC15 v4(95.07,80.85)
  L3_SIG1 w0.099: 95.48,80.5 95.42,80.5 v4(95.07,80.85)
  L3_SIG1 w0.109: v5(95.5,80.48) 95.48,80.5
  L10_SIG4 w0.109: v5(95.5,80.48) 95.5,80.52 95.06,80.97 92.19,80.97 91.05,79.83 88.7,79.83 87.8,80.73 87.25,80.73 86.7,81.28 84.96,81.28 83.19,83.06 v9(83.19,84.28)
  BOTTOM w0.173: 82.42,84.28 v9(83.19,84.28)
N19438966: length 267.1
  TOP w0.173: v7(120.78,61.72) R582.1 v2(121.54,65.99) ; v2(131.06,55.71) 131.06,56.9 v7(132.97,58.8) ; U1.AB9 v4(95.84,86.41)
  L3_SIG1 w0.109: v7(120.78,61.72) 122.11,60.39 131.38,60.39 v7(132.97,58.8) ; v5(134.05,110.63) 135.86,108.82 136.12,108.82 140.11,104.83 153.92,104.83 154.41,104.35 156.46,104.35 157.86,102.96 158.88,102.96 v5(159.13,103.21) ; v2(121.54,65.99) 121.72,65.81 131.42,65.81 135.54,69.93 140.13,69.93 143.28,73.08 157.07,73.08 v5(158.5,74.5) ; v4(95.84,86.41) v5(95.44,86.66)
  L4_SIG2 w0.114: v5(94.61,102.9) 94.61,101.47 95,101.09 95,96.63 95.99,95.64 95.99,91.13 94.64,89.79 94.64,87.25 95.23,86.66 v5(95.44,86.66)
  L9_SIG3 w0.114: v2(179.07,13.16) 179.07,16.46 173.74,21.8 171.7,21.8 158.52,34.98 158.52,51.11 157.56,52.08 152.09,52.08 149.99,54.18 132.59,54.18 v2(131.06,55.71)
  L10_SIG4 w0.109: v5(159.13,103.21) 159.13,102.16 159.89,101.4 159.89,99.41 160.72,98.58 160.72,88.55 159.5,87.32 159.5,86.15 158.55,85.2 158.55,82 156.89,80.35 156.89,78.52 157.73,77.68 157.73,75.27 v5(158.5,74.5) ; v5(94.61,102.9) 94.89,102.62 112.55,102.62 113.87,103.94 113.87,106.49 120.74,113.36 131.33,113.36 v5(134.05,110.63)
  BOTTOM w0.173: U77.4 v2(179.07,13.16)
N19438972: length 97.8
  TOP w0.173: R583.1 110.74,60.96 115.87,55.83 v2(128.91,55.83)
  L9_SIG3 w0.114: v2(175.26,13.04) 172.09,16.21 172.09,20.4 157.73,34.75 157.73,47.2 155.19,49.74 151.26,49.74 148.37,52.62 130.72,52.62 128.91,54.44 v2(128.91,55.83)
  BOTTOM w0.173: v2(175.26,13.04) U77.1
N19438984: length 197.6
  TOP w0.173: v2(92.33,103.66) 92.33,102.82 R584.1
  L3_SIG1 w0.109: v5(176.66,102.19) 166.5,102.19 161.51,107.18 147.84,107.18 146.53,105.87 141.28,105.87 136.04,111.1 136.04,111.72 135.54,112.22 v5(135.13,112.22)
  L10_SIG4 w0.109: v5(176.66,102.19) 178.65,100.2 178.65,94.27 179.71,93.22 179.71,76.81 176.56,73.66 176.56,67.16 175.51,66.12 175.51,64.6 173.23,62.31 173.23,59.52 173.74,59.01 173.74,55.69 173.68,55.63 173.68,26.93 175.15,25.46 175.15,17.08 176.04,16.2 176.04,13.53 v2(176.53,13.04) ; v5(135.13,112.22) 135.13,112.83 133.86,114.1 120.59,114.1 113.04,106.54 113.04,103.92 112.39,103.28 108.76,103.28 105.94,106.1 100.74,106.1 98.29,103.66 v2(92.33,103.66)
  BOTTOM w0.173: v2(176.53,13.04) U77.2 U77.3
N19634423: length 2.7
  TOP w0.173: U74.6 R579.2
N19634430: length 183.4
  TOP w0.173: U74.8 v2(128.71,12.7)
  L3_SIG1 w0.109: v2(136.02,108.29) 140.49,103.81 149.02,103.81 149.25,103.59 155.32,103.59 156.96,101.95 158.13,101.95 158.5,102.32 v5(160.4,102.32)
  L10_SIG4 w0.109: v5(160.4,102.32) 160.4,101.55 161.71,100.23 161.71,89.13 159.9,87.32 159.9,85.95 158.87,84.92 158.87,79.27 158.12,78.51 158.12,75.95 161.21,72.85 161.21,69.47 165.79,64.9 166.17,64.9 166.17,50.34 164.95,49.12 164.95,46.08 165.48,45.54 165.48,44.58 164.85,43.94 164.85,43.44 167.08,41.2 167.08,37.14 165.84,35.9 165.84,31.1 145.33,10.6 134.65,10.6 132.54,12.7 v2(128.71,12.7)
  BOTTOM w0.173: v2(136.02,108.29) 117.75,108.29 112.27,102.81 112.27,101.73 112.9,101.09 R574.1
N19634431: length 199.1
  TOP w0.173: v7(113.13,106.02) 112.9,105.8 R575.1 ; U74.5 v2(128.81,8.89)
  L3_SIG1 w0.109: v7(113.13,106.02) 113.13,106.06 112.49,106.7 v5(112.43,106.7) ; v5(162.81,106.89) 161.09,108.62 156.51,108.62 156.08,109.05 149.23,109.05 146.69,106.51 141.05,106.51 139.12,108.44 139.12,110.06 138.15,111.03 138.15,111.36 v5(136.4,113.11)
  L10_SIG4 w0.109: v5(136.4,113.11) 135.43,113.11 134.09,114.45 115.51,114.45 112.9,111.84 112.9,107.17 v5(112.43,106.7) ; v5(162.81,106.89) 162.81,101.3 162.64,101.12 162.64,86.92 162.05,86.34 162.05,83.57 161.54,83.06 161.54,76.81 162.59,75.77 163.2,75.77 168.53,70.44 168.53,47.71 166.5,45.67 166.5,43.39 168.4,41.48 168.4,30.29 154.85,16.74 154.85,14.42 153.33,12.9 151.91,12.9 147.9,8.89 v2(128.81,8.89)
N19634433: length 203.9
  TOP w0.173: U74.7 v2(128.73,11.43) ; R576.1 106.17,105.16 v7(105.71,105.61)
  L3_SIG1 w0.109: v5(135.39,110.6) 136.09,110.6 138.18,108.51 138.18,107.93 140.72,105.39 147.12,105.39 147.88,106.15 156.62,106.15 158.55,104.22 159,104.22 160.02,103.21 160.66,103.21 v5(161.42,102.44) ; v5(104.24,105.62) 105.71,105.62 v7(105.71,105.61)
  L10_SIG4 w0.109: v5(161.42,102.44) 162,101.86 162,88.04 161.26,87.3 161.26,85.68 159.16,83.57 159.16,79.15 158.57,78.56 158.57,76.26 160.1,74.73 163.09,74.73 167.39,70.44 167.39,65.61 168.15,64.85 168.15,49.53 166.98,48.37 166.98,47.05 165.92,45.98 165.92,43.1 167.64,41.38 167.64,36.53 166.37,35.26 166.37,29.7 146.01,9.34 140.54,9.34 140.15,9.73 130.43,9.73 v2(128.73,11.43) ; v5(135.39,110.6) 134.98,111.01 134.98,111.54 134.49,112.02 133.91,112.02 132.2,113.73 120.68,113.73 113.41,106.46 113.41,103.89 112.5,102.98 108.53,102.98 105.89,105.62 v5(104.24,105.62)
N19700674: length 2.8
  TOP w0.173: J18.1 v2(183.29,97.12)
  BOTTOM w0.173: v2(183.29,97.12) 182.79,97.62 R730.1
N19700725: length 2.5
  TOP w0.173: v1(185.57,94.62) J18.12
  BOTTOM w0.173: v1(185.57,94.62) 185.5,94.7 R731.1
N19707292: length 3
  TOP w0.173: J18.15 v2(179.92,93.62)
  BOTTOM w0.173: R587.1 179.98,93.68 v2(179.92,93.62)
N19708748: length 1.5
  BOTTOM w0.173: U78.2 R429.1
N19795587: length 6.2
  TOP w0.173: R425.1 144.65,134.96 144.65,132.52 143.85,131.71 143.85,130.34 U3.B12
N19795594: length 8.4
  TOP w0.173: U3.C13 v7(144.64,129.53) ; v2(146.94,134.96) 146.39,135.51 R428.1
  L3_SIG1 w0.109: v7(144.64,129.53) 144.64,130.62 145.16,131.15 145.16,134.21 145.91,134.96 v2(146.94,134.96)
N19795604: length 5
  TOP w0.173: R430.1 144.02,132.62 143.45,132.05 U3.A12
N19795606: length 1.5
  TOP w0.173: U3.H9 v2(141.44,124.74)
  BOTTOM w0.173: v2(141.44,124.74) 141.87,125.18 R431.1
N19795618: length 2.1
  TOP w0.173: U3.C10 v2(142.24,129.53)
  BOTTOM w0.173: v2(142.24,129.53) 142.24,130 R570.1
N19795620: length 8.8
  TOP w0.173: R571.1 147.7,115.4 147.7,117.45 144.93,120.22 143.56,120.22 U3.N11
N19795629: length 2.2
  TOP w0.173: U3.K10 v2(142.24,123.14)
  BOTTOM w0.173: R432.1 141.73,122.64 v2(142.24,123.14)
N19796448: length 10.6
  TOP w0.173: v7(135.86,121.52) 135.86,121.56 U3.M3 ; v7(133.1,119.72) 132.21,118.83 132.21,116.12 132.08,115.99 132.08,114.89 R572.1
  L3_SIG1 w0.109: v7(135.86,121.52) 135.47,121.13 133.87,121.13 133.1,120.35 v7(133.1,119.72)
N19796451: length 17.1
  TOP w0.173: U3.H8 v7(140.64,124.74)
  L3_SIG1 w0.109: v7(140.64,124.74) 140.24,124.34 140.24,122.66 139.45,121.87 136.76,121.87 136.65,121.76 133.35,118.46 v2(133.35,117.68)
  BOTTOM w0.173: v2(133.35,117.68) 132.8,117.68 131.7,116.59 131.7,115.19 R588.1
N19923823: length 1
  TOP w0.254: U1.J10 v4(107.03,85.61)
  L3_SIG1 w0.254: v5(107.43,85.86) v4(107.03,85.61)
  vias: v5(110.62,93.05) v5(110.62,92.41) v10(110.11,92.2) v10(110.11,91.75) v11(110.11,92.2) v11(110.11,91.75)
N19923824: length 2.1
  TOP w0.254: U1.J9 v4(107.03,86.41)
  L3_SIG1 w0.254: v5(107.43,86.66) v4(107.03,86.41)
  BOTTOM w0.381: C287.1 v11(108.58,91.55) v11(108.58,91.09)
  vias: v5(108.97,92.66) v5(108.96,92)
N19923825: length 2.2
  TOP w0.254: U1.J16 v4(107.03,80.02)
  L3_SIG1 w0.254: v4(107.03,80.02) v5(107.43,79.77)
  L10_SIG4 w0.254: v11(107.83,80.02) v5(107.43,79.77)
  BOTTOM w0.381: C288.1 107.86,80.04 v11(107.83,80.02)
N19923831: length 1
  TOP w0.254: U1.K19 v4(106.23,77.62)
  L3_SIG1 w0.254: v4(106.23,77.62) v5(106.63,77.37)
  vias: v5(119.1,77.2) v10(117.98,77.72) v10(118.49,77.72) v11(117.98,77.72) v11(118.49,77.72)
N19923832: length 2.8
  TOP w0.254: U1.K16 v4(106.23,80.02)
  L3_SIG1 w0.254: v4(106.23,80.02) v5(106.63,79.77)
  L10_SIG4 w0.254: v11(107.03,80.02) v5(106.63,79.77)
  BOTTOM w0.381: v11(107.03,80.02) 107.76,79.28 C291.1
N19923833: length 2.1
  TOP w0.254: U1.K9 v4(106.23,86.41)
  L3_SIG1 w0.254: v5(106.63,86.66) v4(106.23,86.41)
  BOTTOM w0.381: C290.1 v11(106.43,91.55) v11(106.43,91.09)
  vias: v5(106.65,92.79) v5(106.65,92.16)
N19923834: length 1
  TOP w0.254: U1.J19 v4(107.03,77.62)
  L3_SIG1 w0.254: v4(107.03,77.62) v5(107.43,77.37)
  vias: v5(114.25,74.63) v5(114.63,74.15) v10(114.68,72.52) v10(115.19,72.52) v11(114.68,72.52) v11(115.19,72.52)
N19923844: length 2.8
  TOP w0.254: U1.L9 v4(105.43,86.41)
  L3_SIG1 w0.254: v5(105.83,86.66) v4(105.43,86.41)
  L4_SIG2 w0.381: 105.46,87 105.8,86.66 v5(105.83,86.66)
  BOTTOM w0.381: v11(104.39,91.14) 104.39,91.27 v11(104.65,91.52) 104.39,91.78 C293.1
  vias: v5(104.27,92.66) v5(104.27,92.03)
N19923845: length 2.6
  TOP w0.254: U1.P19 v11(103.03,77.62)
  L3_SIG1 w0.254: v11(103.03,77.62) v5(103.43,77.37)
  L10_SIG4 w0.254: v11(103.03,77.62) 103.05,77.62 103.05,77.61 v5(103.43,77.37)
  BOTTOM w0.254: C294.1 102.54,76.97 103.02,77.45 103.02,77.58 103.05,77.61 103.05,77.62 v11(103.03,77.62)
N19923846: length 2.8
  TOP w0.254: U1.R20 v4(101.44,76.82)
  L10_SIG4 w0.381: v11(102.87,69.04) v11(102.87,69.55) v5(103.25,69.93)
  BOTTOM w0.381: C295.1 v11(102.87,69.04) v11(102.87,69.55)
N19923850: length 11
  TOP w0.254: U1.Y15 v4(97.44,80.82)
  L3_SIG1 w0.254: v4(97.44,80.82) v5(96.9,81.36)
  L9_SIG3 w0.635: v5(88.9,84.08) v5(88.21,84.08)
  L10_SIG4 w0.381: v5(88.9,84.08) v5(88.21,84.08)
  L10_SIG4 w0.635: v5(96.9,81.36) 96.06,81.36 95.83,81.59 92.88,81.59 92.88,81.59 92.57,81.59 92.13,82.02 92.13,82.04 90.65,83.52
  BOTTOM w0.381: v11(90.09,84.08) v11(89.59,84.08) C299.1
N19923851: length 7.8
  TOP w0.254: U1.Y14 v4(97.44,82.41)
  L3_SIG1 w0.254: v5(97.19,82.02) v4(97.44,82.41)
  L10_SIG4 w0.381: v11(91.9,83.39) 92.71,82.58 93.33,82.58 93.6,82.31 96.35,82.31 96.54,82.5 96.9,82.5 97.19,82.21 v5(97.19,82.02)
  BOTTOM w0.381: C298.1 91.9,82.83 91.9,83.39 v11(91.9,83.39)
N19923852: length 4.5
  TOP w0.254: U1.Y13 v4(97.44,83.21)
  L3_SIG1 w0.254: v5(97.04,83.46) v4(97.44,83.21)
  L10_SIG4 w0.254: v5(97.04,83.46) 97.28,83.31 v11(97.28,82.8)
  BOTTOM w0.381: v11(97.28,82.8) 97.21,82.73 C297.1
N19923853: length 2.2
  TOP w0.254: U1.T20 v4(100.64,76.82)
  L3_SIG1 w0.254: v5(101.03,76.56) 100.89,76.56 v4(100.64,76.82)
  BOTTOM w0.381: C296.1 v11(101.73,69.04) v11(101.73,69.55)
N19923865: length 3.6
  TOP w0.254: U1.Y16 v4(97.44,80.02)
  L3_SIG1 w0.254: v4(97.44,80.02) v5(97.04,79.77)
  L10_SIG4 w0.254: v11(96.69,80.1) 97.02,79.77 v5(97.04,79.77)
  BOTTOM w0.254: v11(96.69,80.1) 96.69,80.05 96.27,79.63 94.98,79.63 C300.1
N20127658: length 9.1
  TOP w0.254: U1.AB15 v4(95.84,80.82)
  L3_SIG1 w0.254: 95.53,81.12 v4(95.84,80.82)
  L3_SIG1 w0.381: 95.53,81.12 95.34,81.31 94.46,81.31 93.79,81.97 90.26,81.97 v5(89.97,82.26)
  L10_SIG4 w0.381: v11(90.04,82.78) v11(89.61,82.78) v5(89.03,82.78)
  BOTTOM w0.381: C403.1 v11(89.61,82.78) v11(90.04,82.78)
  vias: v5(82.68,85.85) v5(88.37,82.78) v8(82.17,85.47) v9(82.17,85.47)
N20128389: length 1.6
  TOP w0.254: U1.AB13 v4(95.84,83.21)
  L3_SIG1 w0.254: v4(95.84,83.21) 96.15,82.9 v5(96.2,82.9)
  L10_SIG4 w0.254: v5(96.2,82.9) 96.16,82.9 v11(95.84,83.22)
N20144297: length 3.9
  BOTTOM w0.173: R637.2 156.72,99.64 155.32,98.24 U89.A9
N20190363: length 5.3
  TOP w0.173: R639.4 64.96,76.34 65.3,76.01 C454.2 68.56,76.01 J40.2
N20190375: length 5.4
  TOP w0.173: R639.3 64.96,74.44 65.55,75.03 C454.1 68.56,75.03 J40.1
N20190748: length 5.2
  TOP w0.173: R640.3 106.66,136.31 105.77,137.19 C455.2 105.77,139.25 J41.1
N20190772: length 5.2
  TOP w0.173: J41.2 104.79,139.25 C455.1 104.79,137.12 103.91,136.24 R640.4
N20190931: length 5.2
  TOP w0.173: R641.3 114.02,136.18 113.14,137.06 C456.2 113.14,139 J42.1
N20190955: length 5.1
  TOP w0.173: J42.2 112.16,139.25 C456.1 112.16,137.01 111.27,136.13 R641.4
N20191205: length 5.2
  TOP w0.173: J43.1 121.27,139.13 C457.2 121.27,137.05 122.15,136.17 R642.3
N20191229: length 5.2
  TOP w0.173: R642.4 119.4,136.17 120.29,137.05 C457.1 120.29,139.13 119.51,139.91
N20202943: length 15.7
  TOP w0.173: TP21.1 146.94,137.11 v7(146.94,136.99) ; U3.F8 v7(140.64,127.13)
  L3_SIG1 w0.109: v7(140.64,127.13) 140.26,127.51 140.26,128.54 141.04,129.32 141.04,129.7 141.28,129.94 141.61,129.94 141.85,130.18 141.85,130.5 142.82,131.48 142.82,133.63 146.18,136.99 v7(146.94,136.99)
N20204523: length 27.3
  TOP w0.173: v5(74.42,73.66) v7(73.66,73.66) ; U1.AC17 v4(95.04,79.22)
  L3_SIG1 w0.109: v4(95.04,79.22) v5(94.64,78.97) ; v7(73.66,73.66) v5(74.42,73.66)
  L9_SIG3 w0.114: v5(94.64,78.97) 94.09,78.97 93.13,78 89.05,78 86.72,75.67 78.77,75.67 77.48,76.96 75.56,76.96 74.42,75.82 v5(74.42,73.66)
N20275163: length 4.3
  TOP w0.173: C460.1 156.18,121.5 157.43,122.75 U79.8
N20287248: length 5.6
  TOP w0.381: U79.2 158.08,121.37 158.46,121.75 159.77,121.75 160.44,121.07 161.07,121.07 R647.1 R648.2
N20287275: length 2
  TOP w0.173: R646.2 157.39,120.33 U79.1
N20287568: length 1.5
  TOP w0.173: R646.1 157.39,115.91 C463.1
N20301491: length 6
  TOP w0.173: J22.A1 44.58,34.22 44.58,37.72 45.59,37.72
N20338433: length 6.7
  TOP w0.173: R655.2 R654.1 56.01,28.98 55.63,29.36 J22.B11
N20537306: length 5.9
  TOP w0.173: U44.2 56.9,42.47 56.53,42.84 55.59,42.84 54.91,43.51 54.91,44.12 55.24,44.45 55.96,44.45 56.22,44.71 U85.4
N20594970: length 2.1
  BOTTOM w0.173: U86.1 71.48,117.15 R678.1
N20595300: length 2
  TOP w0.173: R679.1 158.73,118.46 U79.3
N20631200: length 2.5
  TOP w0.173: Q16.G 142.19,11.51 142.11,11.43 142.11,10.41
N20664562: length 1.3
  BOTTOM w0.254: 154.61,107.54 154.97,107.18 U62.B1 U62.B2
N20664572: length 3
  BOTTOM w0.102: U62.B3 154.98,105.94 155.37,105.54 U62.C4
  BOTTOM w0.13: U62.A3 U62.B3 ; C417.1 156.01,104.89 155.77,105.12 U62.D4 U62.C4
N20665027: length 1.5
  BOTTOM w0.254: U62.D2 U62.D1 155.77,107.3 156.13,107.66
N20706534: length 2.4
  TOP w0.173: U65.7 173.79,74.18 R554.2
N20706536: length 2.7
  TOP w0.173: R555.2 174.19,73.56 U65.6
N20706626: length 14.5
  TOP w0.173: U65.2 173.79,69.88 v2(174.5,69.17) ; R477.1 v2(163.63,69.98)
  BOTTOM w0.173: v2(163.63,69.98) 164.44,69.17 v2(174.5,69.17)
N20706635: length 10.4
  TOP w0.173: v2(166.93,70.19) R483.1 ; v2(174.5,69.93) 174.19,70.24 U65.3
  BOTTOM w0.173: v2(166.93,70.19) 167.69,70.95 173.48,70.95 v2(174.5,69.93)
N20721609: length 2.6
  BOTTOM w0.173: R247.2 R251.2 10.03,9.23 11.24,9.23 Q3.G
N20721766: length 4
  BOTTOM w0.173: R242.1 10.03,11.22 10.88,10.37 Q3.D
N20721850: length 3.9
  BOTTOM w0.173: 10.03,4.7 10.03,4.61 10.88,3.76 Q1.D
N20722196: length 12.9
  TOP w0.173: v2(8.28,11.38) 8.97,10.7 8.97,10.53 12.34,7.16 12.34,5.73 13.09,4.97 13.09,4.38 12.65,3.94 11.61,3.94 11.37,3.7 D16.3
  BOTTOM w0.173: v2(8.28,11.38) 8.97,11.38 9.02,11.43
N20722199: length 3.9
  BOTTOM w0.173: Q5.D 10.88,7.07 10.03,7.92 R249.1
N20722204: length 8.1
  TOP w0.173: D16.4 9.97,3.62 9.36,4.23 8.55,4.23 8.5,4.19 8.11,4.19 7.74,4.56 7.74,7.39 v2(8.31,7.96)
  BOTTOM w0.173: 9.02,8 8.97,7.96 v2(8.31,7.96)
N20722213: length 3.1
  TOP w0.173: D16.2 9.97,5.85 8.77,4.65 v2(8.31,4.65)
  BOTTOM w0.173: 9.02,4.7 8.97,4.65 v2(8.31,4.65)
N20722605: length 2.5
  BOTTOM w0.173: R243.1 R246.2 17.84,2.62 Q2.G
N20722618: length 2.5
  BOTTOM w0.173: Q6.G 17.84,5.92 R256.2 R254.2
N20722739: length 2.6
  BOTTOM w0.173: Q4.G 17.84,9.23 16.64,9.23 R252.2 R248.2
N20722773: length 4
  BOTTOM w0.173: Q4.D 17.48,10.37 16.64,11.21 R244.1
N20722790: length 3.9
  BOTTOM w0.173: Q2.D 17.48,3.76 16.64,4.6 16.64,4.7
N20722809: length 10.7
  TOP w0.173: D17.3 15.56,3.85 16.53,4.82 16.53,9.74 v2(14.88,11.38)
  BOTTOM w0.173: v2(14.88,11.38) 15.58,11.38 R244.2
N20722811: length 3.9
  BOTTOM w0.173: R250.1 16.64,7.87 17.44,7.07 Q6.D
N20722815: length 7.9
  TOP w0.173: D17.4 14.16,4.48 13.16,5.48 13.16,7.24 13.87,7.96 v2(14.91,7.96)
  BOTTOM w0.173: R250.2 15.58,7.96 v2(14.91,7.96)
N20722821: length 2.5
  TOP w0.173: D17.2 14.16,5.32 14.83,4.65 v2(14.91,4.65)
  BOTTOM w0.173: v2(14.91,4.65) 15.58,4.65 R240.2
N20723137: length 2.5
  BOTTOM w0.173: R600.1 R599.2 11.24,12.78 Q11.G
N20723150: length 2.6
  BOTTOM w0.173: Q10.G 11.24,19.39 10.03,19.39 R595.2 R594.2
N20723271: length 2.5
  BOTTOM w0.173: R590.2 R591.2 11.24,16.08 Q15.G
N20723305: length 3.9
  BOTTOM w0.173: R589.1 10.03,18.08 10.88,17.23 Q15.D
N20723322: length 3.9
  BOTTOM w0.173: R596.1 10.03,14.77 10.88,13.92 Q11.D
N20723341: length 23.4
  TOP w0.173: D18.3 19.37,2.81 20.34,3.78 20.34,9.05 15.35,14.04 15.35,14.12 15.03,14.44 14.14,14.44 10.46,18.12 v2(8.31,18.12)
  BOTTOM w0.173: v2(8.31,18.12) 8.97,18.12 9.02,18.16
N20723343: length 4
  BOTTOM w0.173: R601.1 10.03,21.38 10.88,20.53 Q10.D
N20723347: length 28.4
  TOP w0.173: v2(8.28,21.57) 7.58,20.87 7.58,12.58 8.2,11.96 15.17,11.96 17.14,9.99 17.14,4.8 17.97,3.98 D18.4
  BOTTOM w0.173: v2(8.28,21.57) 9,21.57 9.02,21.59
N20723353: length 16.2
  TOP w0.173: v2(8.31,14.81) 9.7,14.81 11.26,13.25 13.73,13.25 14.66,12.31 15.5,12.31 17.97,9.84 D18.2
  BOTTOM w0.173: v2(8.31,14.81) 8.97,14.81 9.02,14.86
N20723697: length 2.5
  BOTTOM w0.173: R514.1 R597.2 17.97,12.91 Q13.G
N20723710: length 2.5
  BOTTOM w0.173: R598.2 R515.2 16.71,16.29 Q12.G
N20723831: length 2.6
  BOTTOM w0.173: R593.2 R592.2 16.64,19.51 17.84,19.51 Q14.G
N20723865: length 4
  BOTTOM w0.173: R603.1 16.64,21.51 17.49,20.66 Q14.D
N20723882: length 4
  BOTTOM w0.173: R604.1 16.64,14.77 17.49,13.92 Q13.D
N20723901: length 25.2
  TOP w0.173: D19.3 24.21,2.57 24.81,3.16 24.81,10.75 18.06,17.5 18.06,18.47 v2(14.83,21.7)
  BOTTOM w0.173: v2(14.83,21.7) 15.6,21.7 R603.2
N20723903: length 4
  BOTTOM w0.173: R602.1 16.64,18.08 17.49,17.23 Q12.D
N20723907: length 23.3
  TOP w0.173: v2(14.91,18.24) 16.56,18.24 24.46,10.34 24.46,4.77 23.95,4.27 22.35,4.27 21.91,3.82 D19.4
  BOTTOM w0.173: v2(14.91,18.24) 15.58,18.24 R602.2
N20723913: length 13.7
  TOP w0.173: D19.2 21.91,10.05 17.01,14.94 v2(14.91,14.94)
  BOTTOM w0.173: R604.2 15.58,14.94 v2(14.91,14.94)
N20729664: length 1.3
  BOTTOM w0.173: Q20.D 80.01,104.25 R699.1
N20729666: length 14.7
  TOP w0.173: D22.4 72.2,97.29 73.07,96.42 73.86,96.42 74.93,97.48 v2(74.93,97.79)
  BOTTOM w0.173: v2(74.93,97.79) 74.93,99.75 75.06,99.88 75.06,100.67 75.67,101.27 76.17,101.27 76.58,101.68 76.58,102.7 78.23,104.35 78.23,104.77 R699.2
N20729672: length 9.3
  TOP w0.173: v2(74.5,103.61) 74.88,103.23 74.88,101.27 74.24,100.63 72.62,100.63 72.2,101.06 D22.2
  BOTTOM w0.173: R696.2 75.79,105.31 75.79,104.44 74.96,103.61 v2(74.5,103.61)
N20729903: length 2.4
  BOTTOM w0.173: R697.2 R698.1 77.49,100.81 Q21.G
N20729915: length 2.7
  BOTTOM w0.173: R695.2 R694.2 81.03,102.11 Q20.G
N20730029: length 2.6
  BOTTOM w0.173: Q22.G 74.04,102.19 R701.2 R700.2
N20730054: length 1.3
  BOTTOM w0.173: R693.1 73.12,105.51 Q22.D
N20730079: length 1.3
  BOTTOM w0.173: R696.1 76.58,104.25 Q21.D
N20730095: length 11.3
  TOP w0.173: D22.3 73.51,98.32 v2(73.51,96.98)
  BOTTOM w0.173: R693.2 71.32,104.72 71.32,99.17 v2(73.51,96.98)
N20730773: length 2.2
  BOTTOM w0.173: Q23.D 67.75,95.06 R708.1
N20730775: length 4.5
  TOP w0.173: D23.4 68.13,98.41 67.82,98.09 67.82,96.86 v2(66.8,95.84)
  BOTTOM w0.173: R708.2 66.8,95.25 v2(66.8,95.84)
N20730781: length 16.4
  TOP w0.173: v2(66.29,90.63) 66.29,101.3 66.9,101.91 D23.2
  BOTTOM w0.173: R705.2 68.66,89.36 67.56,89.36 v2(66.29,90.63)
N20730789: length 2.6
  BOTTOM w0.173: R706.2 R707.1 70.66,84.59 Q24.G
N20730805: length 2.6
  BOTTOM w0.173: R704.2 R703.2 70.79,91.7 Q23.G
N20730910: length 2.6
  BOTTOM w0.173: R709.2 R710.2 70.28,98.81 Q25.G
N20730936: length 1.3
  BOTTOM w0.173: R702.1 Q25.D
N20730961: length 1.5
  BOTTOM w0.173: Q24.D R705.1
N20730985: length 7.7
  TOP w0.173: v2(67.18,101.3) 68.45,100.03 69.85,100.03 70.17,99.71 D23.3
  BOTTOM w0.173: v2(67.18,101.3) 67.23,101.3 68.33,102.4 R702.2
N20825141: length 7.4
  TOP w0.173: R690.2 104.65,99.14 104.11,98.6 104.11,95.76 103.43,95.09 U1.N1
N20825143: length 14.7
  TOP w0.173: v7(105.28,98.4) 105.92,99.04 R691.2 ; U1.M5 v4(104.63,89.61)
  L3_SIG1 w0.099: v4(104.63,89.61) 104.63,89.51 104.13,89 104.13,88.69 103.96,88.52 103.71,88.52 103.33,88.91 103.33,91.34 103.2,91.46 103.2,94.08 103.05,94.23 103.05,94.75 103.56,95.26 103.56,96.93 104.37,97.74
  L3_SIG1 w0.109: 104.37,97.74 104.37,98.02 104.75,98.4 v7(105.28,98.4)
N20825145: length 16.9
  TOP w0.173: R692.2 103.52,101.57 v7(102.96,101.57) ; U1.M3 v4(104.63,91.21)
  L3_SIG1 w0.099: 106.05,97.92 104.27,96.14 104.27,94.22 103.87,93.82 103.87,91.85 104.26,91.46 104.39,91.46 v4(104.63,91.21)
  L3_SIG1 w0.109: 106.05,97.92 106.05,99.5 106.62,100.07 106.62,101.11 106.16,101.57 v7(102.96,101.57)
N20825147: length 13.5
  TOP w0.173: U1.N6 v4(103.83,88.81) ; v7(104.95,97.83) 106.23,97.83 106.93,98.53 R732.2
  L3_SIG1 w0.099: v4(103.83,88.81) 103.53,89.12 103.53,91.42 103.4,91.54 103.4,94.16 103.25,94.31 103.25,94.65 103.76,95.15 103.76,96.64 v7(104.95,97.83)
N20825149: length 13.7
  TOP w0.173: U1.M4 v4(104.63,90.41) ; R733.2 105.58,101.47 v7(105.58,101.12)
  L3_SIG1 w0.099: 105.74,98.01 104.01,96.28 104.01,94.25 103.6,93.84 103.6,91.83 104.63,90.8 v4(104.63,90.41)
  L3_SIG1 w0.109: 105.74,98.01 105.74,98.79 105.58,98.94 v7(105.58,101.12)
N20825151: length 11.1
  TOP w0.173: R734.2 105.03,101.28 105.12,101.2 105.12,100.6 105.2,100.51 105.2,99.04 104.46,98.29 104.46,95.5 103.83,94.87 103.83,92.01 U1.N2
N20962931: length 6.5
  TOP w0.173: J18.58 v1(188.75,83.12)
  BOTTOM w0.173: R149.1 188.73,83.14 v1(188.75,83.12) ; R149.1 187.7,82.66 187.7,82.31 C421.1 ; R149.1 U19.2
N21013400: length 8
  TOP w0.173: U1.B14 112.64,81.62 116.22,81.62 116.85,80.98 119.63,80.98 R662.2
N21013403: length 45.4
  TOP w0.173: U1.J14 v4(107.03,82.41) ; v7(104.09,112.1) 104.77,112.1 R663.2
  L3_SIG1 w0.109: v4(107.03,82.41) 107.03,82.42 107.43,82.66 v5(107.43,82.66) ; v5(99.29,112.7) 99.54,112.96 103.23,112.96 v7(104.09,112.1)
  L4_SIG2 w0.114: v5(99.29,112.7) 97.83,111.24 97.83,104.79 100.9,101.72 100.9,100.49 100.36,99.95 100.36,92.75 102.13,90.97 102.13,84.06 103.13,83.05 107.04,83.05 v5(107.43,82.66)
N21013406: length 27.9
  TOP w0.173: U1.G13 v4(108.63,83.21)
  L3_SIG1 w0.109: v5(109.03,83.46) v4(108.63,83.21)
  L4_SIG2 w0.114: v5(115.44,82.65) 114.94,83.16 113.16,83.16 112.8,82.8 109.69,82.8 v5(109.03,83.46)
  L10_SIG4 w0.109: v5(115.44,82.65) v9(115.44,83.57)
  BOTTOM w0.173: v9(115.44,83.57) 114.81,83.57 112.39,85.98 112.39,88.47 112.17,88.7 112.17,93.88 108.58,97.46 R664.2
N21013409: length 40.1
  TOP w0.173: v4(107.09,84.71) 106.93,84.71 U1.J11 ; R665.2 103.38,112.86 v7(103.03,112.51)
  L3_SIG1 w0.109: v7(103.03,112.51) 102.62,112.1 v5(99.92,112.1) ; v4(107.09,84.71) 107.09,84.72 v5(107.43,85.06)
  L4_SIG2 w0.114: v5(107.43,85.06) 107.04,85.45 103.29,85.45 102.54,86.21 102.54,91.28 100.81,93 100.81,99.98 101.19,100.36 101.19,102.01 98.12,105.08 98.12,110.29 v5(99.92,112.1)
N21036279: length 58.9
  TOP w0.173: v5(104.65,100.28) v7(104.65,101)
  L3_SIG1 w0.109: v7(104.65,101) v5(104.65,100.28)
  L4_SIG2 w0.114: v5(104.65,100.28) 104.65,100.68 102.79,102.54 101.6,102.54 98.71,105.43 98.71,109.79 100.69,111.76 100.69,119.29 99.74,120.24 99.74,122.37 98.92,123.19 98.92,127.99 98.31,128.6 98.31,129.31 98.91,129.9 98.91,131.37 105.44,137.9 105.44,145.21 106.37,146.15 106.37,148.05 J21.8
N21036281: length 59.4
  TOP w0.173: v7(106.17,100.92) 106.17,100.84 105.92,100.59 R691.1
  L3_SIG1 w0.109: v5(106.17,100.28) v7(106.17,100.92)
  L4_SIG2 w0.114: v5(106.17,100.28) 105.46,100.28 102.86,102.88 101.94,102.88 99.01,105.82 99.01,109.65 100.99,111.64 100.99,119.79 100.71,120.07 100.71,121.39 101.6,122.28 101.6,125.83 100.62,126.81 100.62,132.32 108.1,139.8 108.1,141.86 108.32,142.08 108.32,147.99 J21.10
N21036293: length 54.9
  TOP w0.173: v2(103.33,103.51) R692.1
  L4_SIG2 w0.114: v2(103.33,103.51) 102.9,103.94 101.4,103.94 99.3,106.03 99.3,109.52 101.3,111.51 101.3,120.02 101.9,120.62 101.9,126.43 102.17,126.69 102.17,127.5 100.92,128.75 100.92,132.08 108.43,139.6 108.43,141.56 110.32,143.45 110.32,147.99 J21.12
N21036295: length 61.2
  TOP w0.173: R732.1 107.34,100.69 v7(107.47,100.69)
  L3_SIG1 w0.109: v7(107.47,100.69) 107.35,100.56 v5(107.35,100.02)
  L4_SIG2 w0.114: v5(107.35,100.02) 107.35,100.56 105.36,102.54 104.92,102.54 103.17,104.29 101.57,104.29 99.6,106.27 99.6,109.38 101.63,111.41 101.63,119.79 102.26,120.42 102.26,126.24 102.49,126.47 102.49,127.69 101.63,128.55 101.63,130.17 101.99,130.53 101.99,132.7 108.79,139.5 108.79,141.5 112.32,145.03 112.32,147.99 J21.14
N21036304: length 58.1
  TOP w0.173: v2(106.05,103.64) R733.1
  L4_SIG2 w0.114: J21.16 114.32,147.99 114.32,146.55 109.14,141.38 109.14,139.44 102.28,132.58 102.28,130.76 102.92,130.12 102.92,126.39 102.59,126.06 102.59,120.19 101.99,119.59 101.99,111.34 99.89,109.24 99.89,106.46 101.7,104.65 103.23,104.65 104.98,102.9 105.3,102.9 v2(106.05,103.64)
N21036390: length 6.9
  TOP w0.173: U1.T1 101.04,98.55 100.84,98.75 R686.2
N21036392: length 7.2
  TOP w0.173: R688.2 103.38,96.34 102.64,95.59 U1.P1
N21036394: length 44.7
  TOP w0.173: v7(103.15,119.81) 104.27,120.92 R689.2 ; U1.P7 v4(103.03,88.01)
  L3_SIG1 w0.109: v5(103.43,88.26) 103.43,88.26 v4(103.03,88.01) ; v5(103.79,120.1) 103.5,119.81 v7(103.15,119.81)
  L4_SIG2 w0.114: v5(103.43,88.26) 103,88.7 103,91.49 102.77,91.72 102.77,94.97 103.07,95.28 103.07,97.2 104.96,99.09 107.49,99.09 108.1,99.69 108.1,100.97 106.78,102.29 106.78,104.22 106.35,104.65 104.52,104.65 103.53,105.64 102.71,105.64 101.52,106.83 101.52,108.37 103.13,109.98 103.13,118.05 103.79,118.71 v5(103.79,120.1)
N21036619: length 93.6
  TOP w0.173: v2(105.03,103.62) R734.1
  L4_SIG2 w0.114: v2(105.03,103.62) 104.71,103.62 103.35,104.98 101.88,104.98 100.46,106.4 100.46,109.4 102.43,111.37 102.43,118.18 103.05,118.8 103.05,119.91 102.92,120.04 102.92,125.73 103.25,126.06 103.25,130.28 102.58,130.95 102.58,132.45 109.45,139.33 109.45,141.15 112.22,143.92 113.69,143.92 116.34,146.58 116.34,149.72 116.94,150.32 150.05,150.32 J21.52
N21099488: length 6
  L10_SIG4 w0.109: v11(93.13,134.77) 93.13,129.7 v11(93.38,129.45)
  BOTTOM w0.173: v11(93.13,134.77) 93.09,134.81 C265.1
N21180149: length 15.6
  TOP w0.173: TP22.1 125.76,78.8 117.82,78.8 115.8,80.81 112.64,80.81 U1.B15
N21180152: length 16.7
  TOP w0.173: U1.A15 116.04,81.21 118.1,79.15 127.3,79.15 TP23.1
N21306186: length 8.5
  TOP w0.173: TP24.1 v2(158.55,94.37)
  BOTTOM w0.173: U89.B6 153.08,95.98 153.95,95.98 154.39,96.42 155.75,96.42 156.2,95.98 157.87,95.98 158.55,95.31 v2(158.55,94.37)
N21306311: length 3.3
  BOTTOM w0.173: R567.1 156.69,97.59 U89.A8
N21306314: length 4.4
  BOTTOM w0.173: U89.B8 153.1,97.26 156.06,97.26 R585.1
N21306347: length 0.9
  BOTTOM w0.254: U89.H10 v2(148.54,98.57) ; U89.E10 v2(150.5,98.57)
N21307911: length 3.5
  BOTTOM w0.173: R586.1 144.53,95.97 145.54,95.97 145.87,96.29 U89.K6
N21519094: length 4.9
  BOTTOM w0.173: U90.L8 143.23,45.3 143.23,45.05 143.23,45.05 143.23,44.73 143.13,44.62 R754.2
N21519152: length 5.1
  BOTTOM w0.102: U91.L8 142.48,60.56 142.48,59.77
  BOTTOM w0.173: 142.48,59.77 142.48,56.86 R755.2
N21552786: length 1.8
  BOTTOM w0.173: U92.1 158.27,54.79 C544.1
N21553219: length 2
  TOP w0.173: R780.1 140.84,71.46
  TOP w0.381: C529.1 140.82,71.44 140.84,71.46 ; R781.1 R780.1
N21553307: length 1.8
  BOTTOM w0.305: R783.1 162.55,57.99 U92.7
N21553371: length 1.5
  BOTTOM w0.305: R782.1 162.82,56.98 U92.9
N21553379: length 2.9
  BOTTOM w0.173: U92.5 158.27,60.05 C533.1 R784.1
N21605448: length 3
  TOP w0.508: 13.54,41.96 J50.1 15.67,41.96
N21620210: length 19.3
  L10_SIG4 w0.109: v9(178.96,72.18) 177.13,70.35 177.13,65.81 176.43,65.11 v9(176.43,57.4)
  BOTTOM w0.173: R368.1 C197.1 176.43,58.15 v9(176.43,57.4) ; U72.3 v9(178.96,72.18)
N21620213: length 22.4
  L10_SIG4 w0.109: v9(176.43,54.86) 177.17,55.6 177.17,63.99 177.15,64 177.15,64.84 178.69,66.38 178.69,70.61 v9(180.26,72.18)
  BOTTOM w0.173: R370.1 C198.1 176.43,55.61 v9(176.43,54.86) ; U72.5 v9(180.26,72.18)
N21620216: length 26
  L10_SIG4 w0.109: v9(181.56,72.18) 180.11,70.73 180.11,66.5 178.31,64.7 178.31,63.84 177.67,63.2 177.67,58.88 178.31,58.25 178.31,54.2 v9(176.43,52.32)
  BOTTOM w0.173: R372.1 C199.1 176.43,53.07 v9(176.43,52.32) ; U72.7 v9(181.56,72.18)
N21620219: length 28.6
  L10_SIG4 w0.109: v9(176.43,49.78) 179.18,52.53 179.18,64.32 181.25,66.4 181.25,70.57 v9(182.86,72.18)
  BOTTOM w0.173: v9(176.43,49.78) 176.43,50.53 C200.1 R374.1 ; U72.9 v9(182.86,72.18)
N21620222: length 31.7
  L10_SIG4 w0.109: v9(176.43,47.24) 179.71,50.52 179.71,54.59 180.34,55.22 180.34,63.33 180.98,63.96 180.98,64.6 182.5,66.12 182.5,70.52 v9(184.16,72.18)
  BOTTOM w0.173: v9(176.43,47.24) 176.43,47.99 C201.1 R373.1 ; U72.11 v9(184.16,72.18)
N21620225: length 30.9
  L10_SIG4 w0.109: v9(184.16,64.22) 183.39,63.44 183.39,51.66 182.75,51.03 v9(182.75,44.28)
  BOTTOM w0.173: U72.18 v9(184.16,64.22) ; R375.1 177.59,45.85 176.91,45.85 176.53,45.47 C202.1 176.43,45.45 176.43,44.63 176.78,44.28 v9(182.75,44.28)
N21620228: length 32.1
  L10_SIG4 w0.109: v9(182.86,64.22) 182.86,51.76 181.74,50.63 v9(181.74,41.61)
  BOTTOM w0.173: v9(181.74,41.61) 176.98,41.61 176.43,42.16 176.43,42.91 C203.1 R376.1 ; U72.20 v9(182.86,64.22)
N21620231: length 33.3
  L10_SIG4 w0.109: v9(181.56,64.22) 181.56,51.47 180.98,50.88 v9(180.98,39.32)
  BOTTOM w0.173: R378.1 C204.1 176.41,39.7 176.78,39.32 v9(180.98,39.32) ; U72.22 v9(181.56,64.22)
N21685968: length 1
  TOP w0.173: U1.K14 v4(106.23,82.41)
  L3_SIG1 w0.254: v4(106.23,82.41) v5(106.63,82.66)
  vias: v5(116.84,82) v5(117.86,82) v8(118.87,82) v8(118.87,81.15) v9(118.87,82) v9(118.87,81.15)
N21685998: length 3.4
  TOP w0.173: R638.1 R798.2 J46.4
N21823186: length 5
  TOP w0.173: R801.4 65.89,52.09 C549.2 65.89,49.76 J47.2
N21823194: length 4.8
  TOP w0.173: R801.3 64.92,52.34 C549.1 64.92,49.5 J47.1
N21877717: length 8.3
  TOP w0.173: U1.AE5 93.83,89.21 93.43,88.82 88.92,88.82 88.41,89.32 86.46,89.32 86.29,89.49 R659.2
N21877759: length 5.7
  TOP w0.173: R660.2 92.84,94.13 93.83,93.14 U1.AE1
N21905162: length 8.1
  TOP w0.173: U1.AG3 91.84,91.21 90.22,91.21 86.06,95.38 R802.1
N21905296: length 6.4
  TOP w0.173: U1.AH5 89.3,89.21 87,91.52 R803.1
N22373548: length 7
  TOP w0.173: R809.2 93.98,96.94 93.29,96.25 93.29,94.36 93.34,94.11 94.24,93.22 94.24,92.01 U1.AD2
N22373612: length 8.9
  TOP w0.173: U96.2 145.62,143.18 145.21,142.77 145.21,138.51 145.8,137.92 R810.1 146.3,136.53
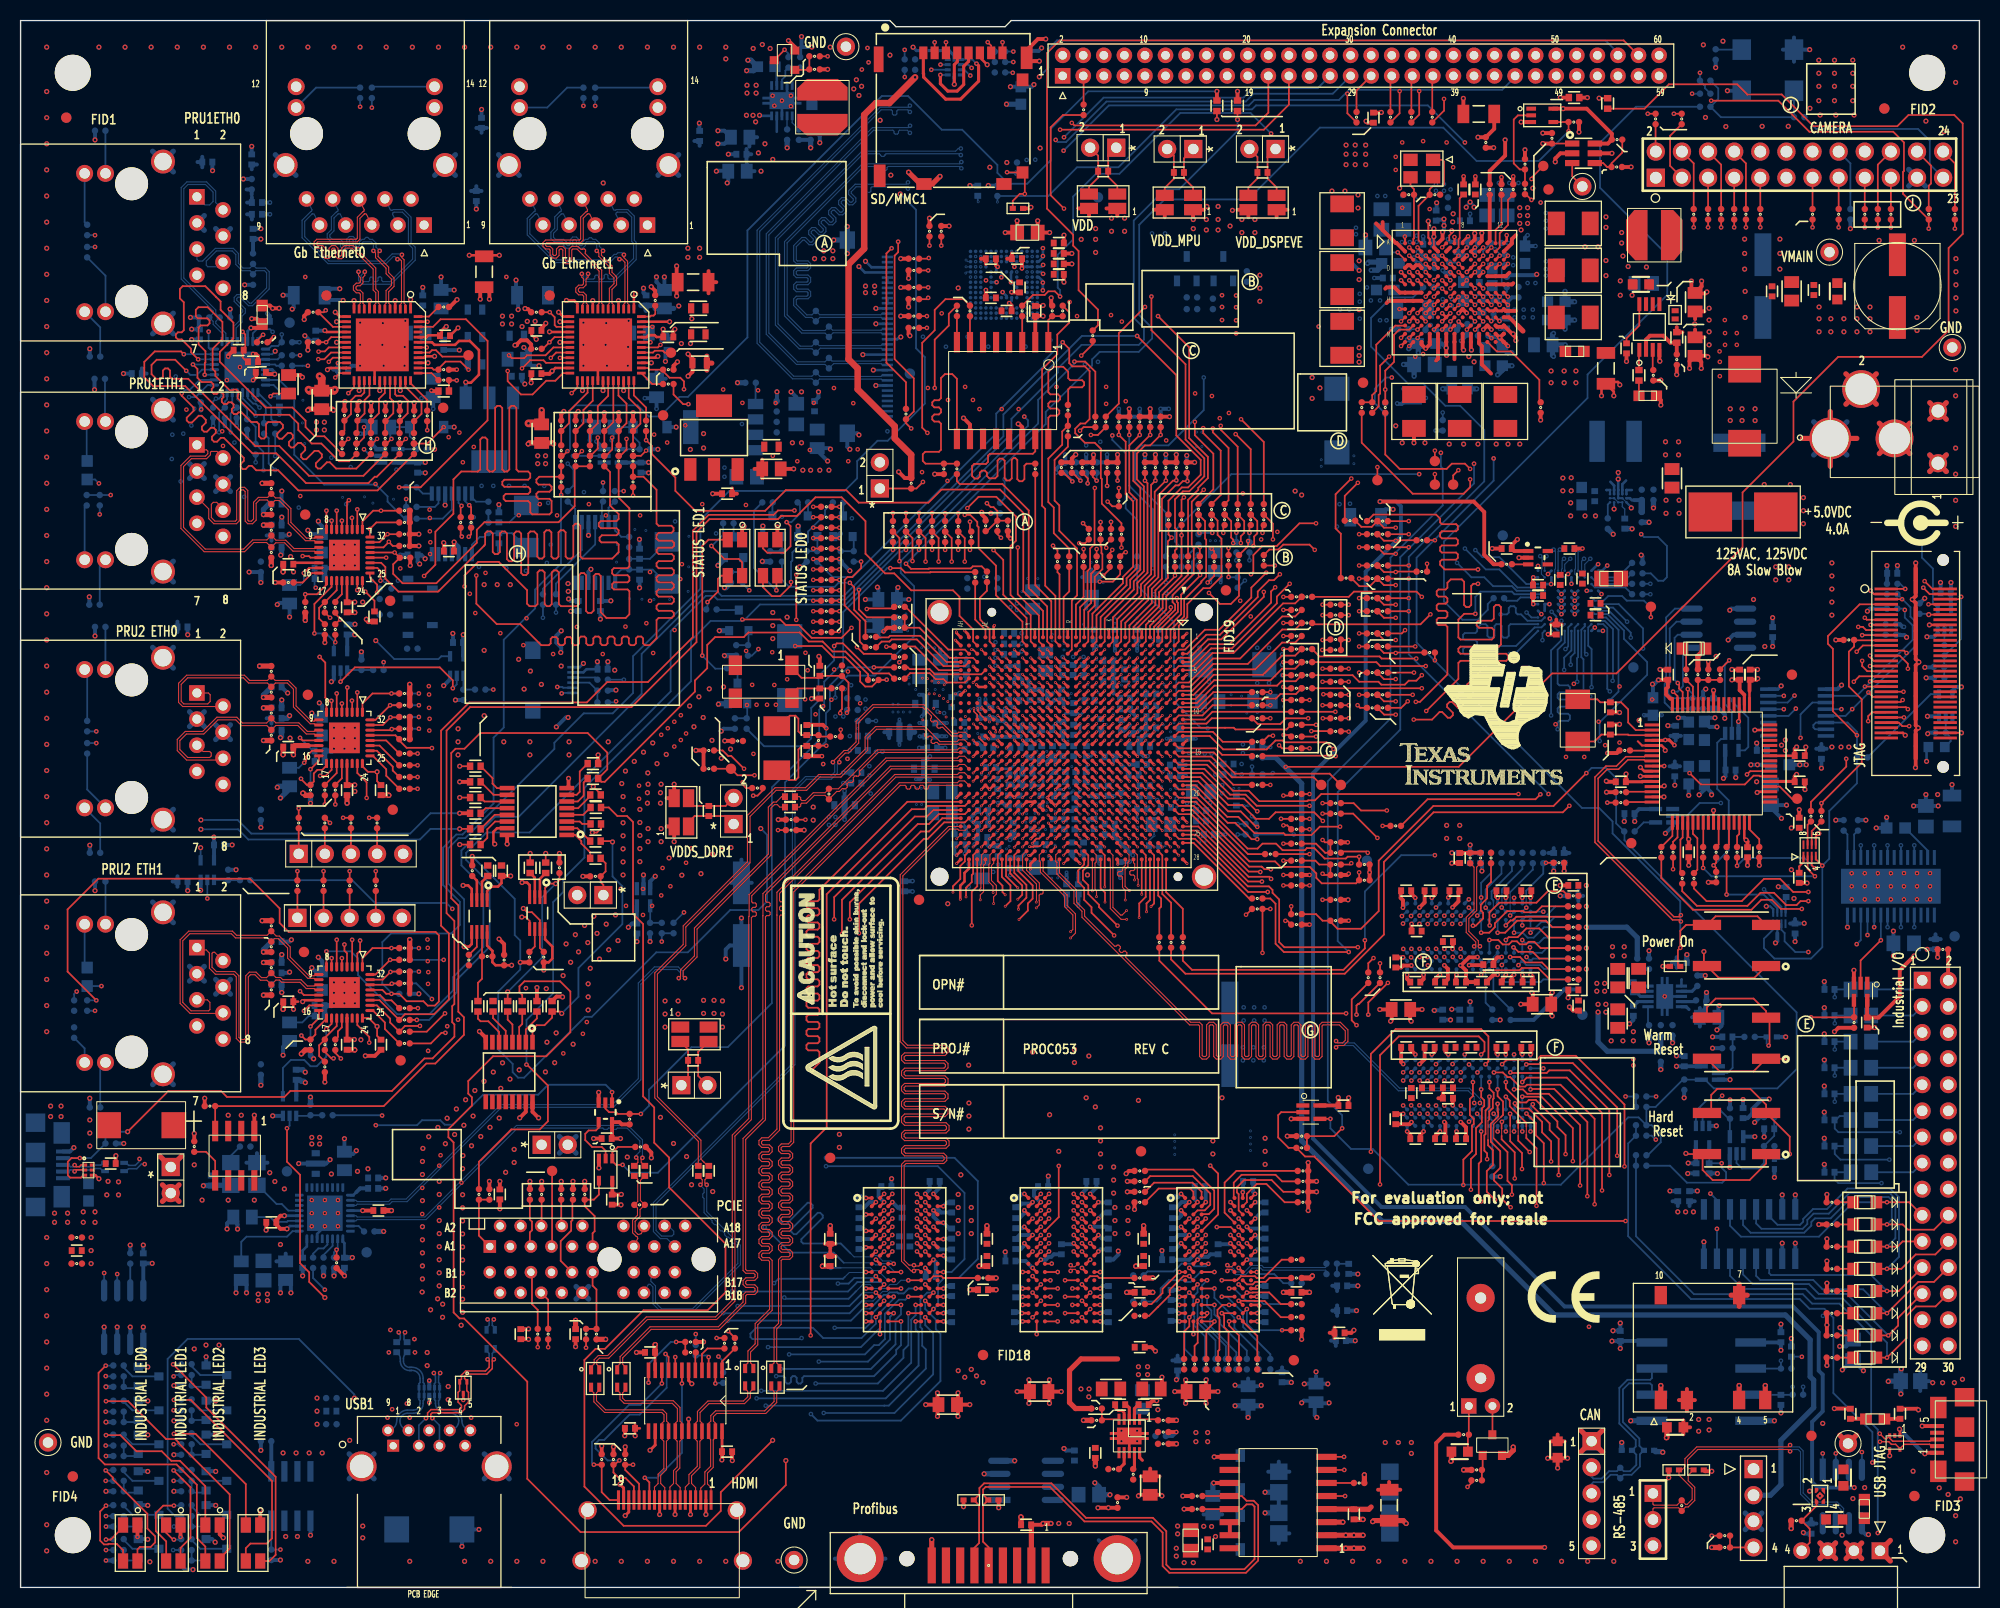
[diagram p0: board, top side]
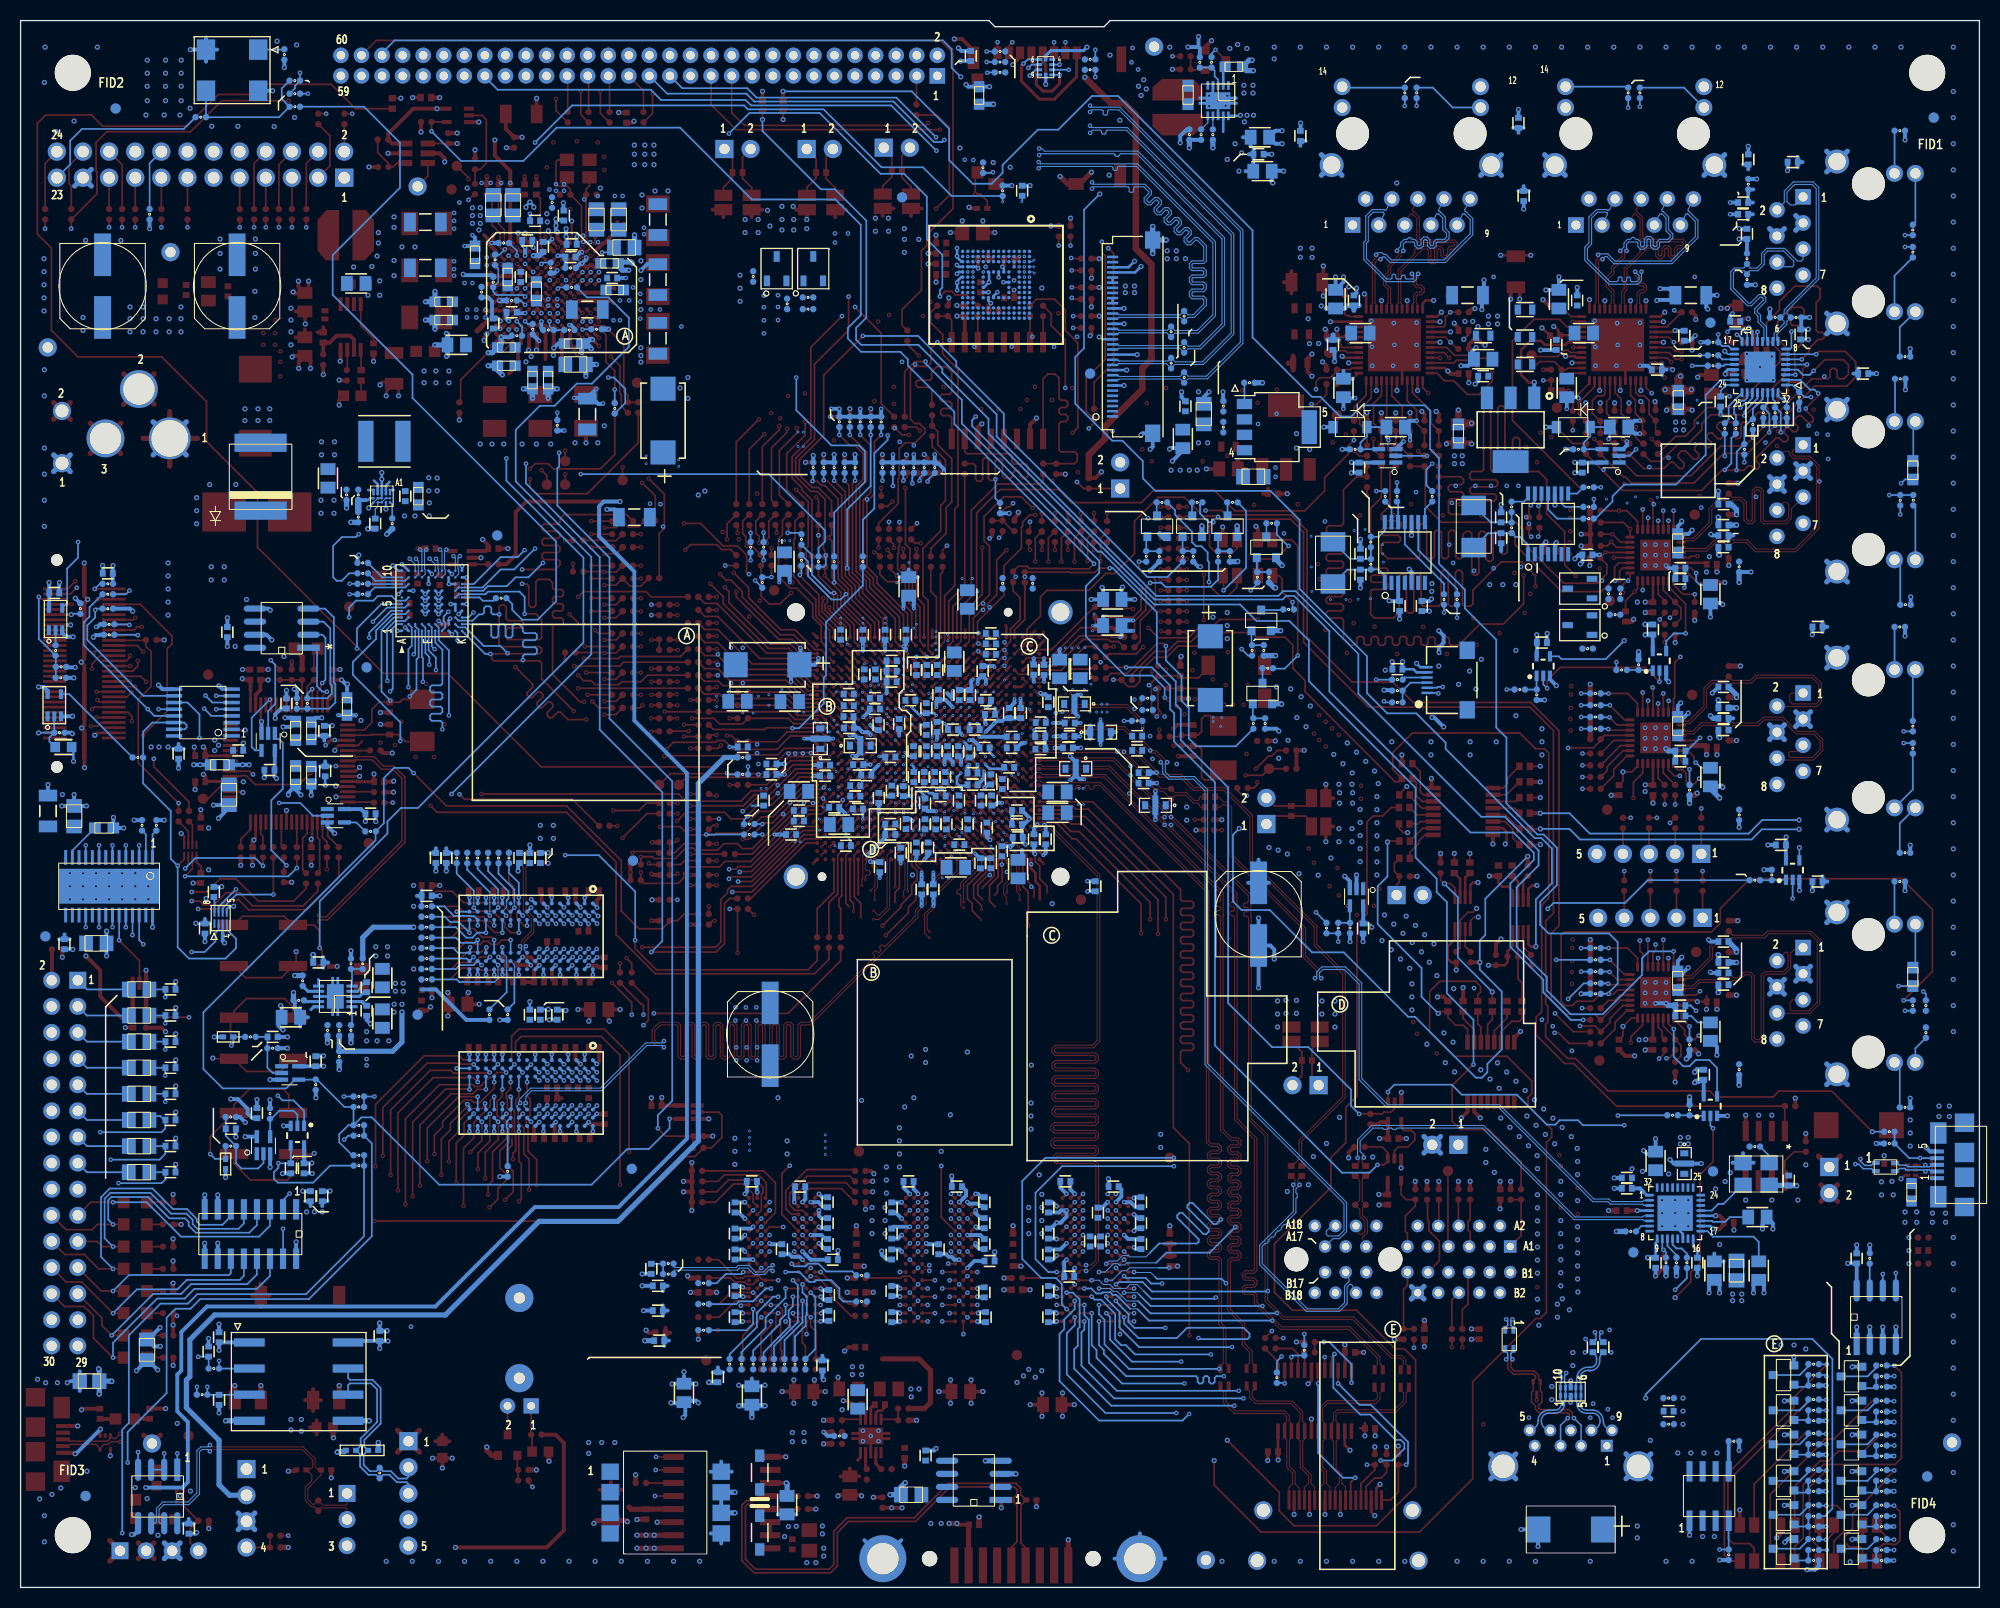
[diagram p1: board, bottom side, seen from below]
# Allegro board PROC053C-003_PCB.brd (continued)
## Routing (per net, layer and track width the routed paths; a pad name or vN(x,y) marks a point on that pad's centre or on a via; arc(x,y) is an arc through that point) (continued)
N22427447: length 28
  TOP w0.173: R739.1 131.06,60.71 v7(131.57,61.21) ; U1.C26 v4(111.83,72.02)
  L3_SIG1 w0.099: 113.16,72.31 112.13,72.31 v4(111.83,72.02)
  L3_SIG1 w0.109: v7(131.57,61.21) 123.53,61.21 119.63,65.11 119.63,65.64 117.27,68 117.27,69.78 114.74,72.31 113.16,72.31
N22427459: length 27.5
  TOP w0.173: U1.B27 v4(112.63,71.22) ; R740.1 v7(132.21,60.71)
  L3_SIG1 w0.099: 114.48,70.72 114.25,70.48 113.78,70.48 113.47,70.79 113.06,70.79 v4(112.63,71.22)
  L3_SIG1 w0.109: v7(132.21,60.71) 122.46,60.71 116.79,66.38 116.79,69.65 115.72,70.72 114.48,70.72
N22642197: length 14.3
  BOTTOM w0.173: X1.3 R903.2 165.35,143 R276.2 165.1,144.78 165.1,145.8 R905.1
N22644059: length 4.2
  TOP w0.254: v2(143.83,123.17) 143.81,123.17 U3.K12
  BOTTOM w0.381: R854.2 145.03,125.48 144.65,125.09 144.65,123.55 C562.1 144.08,123.43 v2(143.83,123.17)
N22691021: length 21.9
  TOP w0.173: R576.2 v7(106.81,106.93) ; U1.F4 v4(109.43,90.41)
  L3_SIG1 w0.099: 109.73,94.09 109.73,91.06 109.43,90.76 v4(109.43,90.41)
  L3_SIG1 w0.109: v7(106.81,106.93) 107.29,106.93 108.86,105.36 108.86,104.82 111.48,102.2 111.48,101.83 112.73,100.58 112.73,99.51 111.77,98.56 111.77,96.64 111.54,96.4 111.54,95.9 109.73,94.09
N22729003: length 4.1
  TOP w0.173: J21.31 129.92,145.6 R861.1
N22729012: length 3.6
  TOP w0.173: R862.1 133.22,146.9 J21.33
N22729021: length 3.5
  TOP w0.173: R863.1 135.26,146.93 J21.35
N22729030: length 3.5
  TOP w0.173: J21.37 137.29,146.96 R864.1
N22729576: length 7
  TOP w0.173: U1.AG6 91.83,88.01 90.08,88.01 89.75,88.34 89,88.34 88.42,88.93 86.51,88.93 R738.1
N22730116: length 10.6
  TOP w0.173: U1.AG4 91.84,89.62 89.75,89.62 87.16,92.2 84.71,92.2 84.5,92 83.74,92 R737.1
N22730128: length 9.4
  TOP w0.173: R736.1 83.24,92.41 84.4,92.41 84.55,92.55 87.5,92.55 90.04,90.02 U1.AH4
N22734288: length 6
  BOTTOM w0.173: U2.4 166.23,45.58 R917.1 166.12,45.59 165.35,46.35 163.96,46.35 163.58,45.97 U98.2
N22734327: length 8.9
  BOTTOM w0.173: 170.56,45.76 170.54,45.74 C4.1 170.54,43.92 R916.1 169.55,41.27 169.02,40.75 167.41,40.75 166.88,41.27 U2.2
N22734777: length 16.8
  TOP w0.173: v2(172.05,42.15) 172.05,43.85 SW1.3 169.75,46.96 168.22,48.49 165,48.49 164.41,47.9 164.41,46.56 SW1.4
  BOTTOM w0.173: 170.56,42.93 U49.1 171.59,41.68 v2(172.05,42.15)
N22735118: length 111.8
  L4_SIG2 w0.114: v2(165.48,47.83) 165.86,47.83 167.92,49.89 167.92,59.72 161.14,66.49 159.91,66.49 149.24,77.17 v2(148.59,77.17)
  BOTTOM w0.173: v2(148.59,77.17) 135,90.76 135,100.24 142.34,107.58 142.34,112.59 140,114.93 138.56,114.93 136.4,117.09 134.93,117.09 131.34,120.68 131.34,123.49 133.32,125.48 135.43,125.48 R9.2 ; v2(165.48,47.83) 165.02,47.37 163.96,47.37 162.93,46.34 U98.1
N22762383: length 29.5
  TOP w0.173: v7(70.36,79.63) 69.11,80.87 68.81,80.87 68.28,81.41 R925.1 ; U1.AC16 v4(95.04,80.02)
  L3_SIG1 w0.099: v4(95.04,80.02) 94.65,80.02 94.43,80.24 94.41,80.27 94.4,80.27 94.36,80.31 93.14,80.31 92.98,80.15
  L3_SIG1 w0.109: v7(70.36,79.63) 70.99,79.63 71.12,79.5 80.14,79.5 80.9,80.26 87.12,80.26 87.24,80.15 92.98,80.15
N22762388: length 26.7
  TOP w0.173: v7(76.33,74.68) R924.1 ; U1.AB16 v4(95.84,80.02)
  L3_SIG1 w0.109: v7(76.33,74.68) 76.2,74.68 76.17,74.65 75.95,74.65 75.34,75.26 v5(75.34,76.07) ; v4(95.84,80.02) v5(95.44,79.77)
  L9_SIG3 w0.114: v5(75.34,76.07) 76.23,75.18 87.22,75.18 89.64,77.6 92.51,77.6 92.66,77.75 93.98,77.75 94.47,78.24 94.47,78.25 95.05,78.83 95.05,79.38 v5(95.44,79.77)
N24440306: length 2.6
  BOTTOM w0.173: X1.1 164.88,149.57 R902.1
N24733277: length 4
  TOP w0.173: U99.14 46.15,74.49 45.39,73.74 45.39,72.91 R974.2
N24733350: length 3.1
  TOP w0.173: R975.2 46.11,75.14 U99.13
N24733388: length 2.8
  TOP w0.173: U99.12 45.23,75.79 R976.2
N24733458: length 2.7
  TOP w0.173: R977.2 45.12,76.44 U99.11
N24733465: length 3.1
  TOP w0.173: R978.2 46,77.09 U99.10
N24733472: length 3.8
  TOP w0.173: U99.9 46.33,77.74 45.9,78.18 45.9,78.72 R979.2
N24733813: length 2.9
  TOP w0.173: U99.5 54.23,75.79 55.4,76.97 R935.2
N24736796: length 2.5
  TOP w0.254: R940.2 50.01,69.03 U102.3
N24737086: length 2.4
  TOP w0.173: U102.6 50.01,62.34 R942.2
N24737397: length 12.5
  TOP w0.254: U103.1 45.37,67.74 45.8,68.17 46.44,68.17 46.77,68.5 R980.1
  TOP w0.381: R943.1 47.03,62.58 v1(46.53,63.07) ; R980.1 v1(47.66,69.2)
  L3_SIG1 w0.254: v1(47.66,69.2) 46.53,68.07 v1(46.53,63.07)
N24737443: length 2.5
  TOP w0.254: R947.1 44.37,68.75 U103.3
N24737493: length 2.5
  TOP w0.173: U103.6 44.37,62.31 R946.2
N24756266: length 5
  BOTTOM w0.173: R89.1 7.75,122.56 J3.10
N24757165: length 5
  BOTTOM w0.173: J6.10 7.75,74.31 R172.1
N24911250: length 5
  TOP w0.173: U7.L8 104.02,30.28 104.72,30.28 104.9,30.1 R44.2
N24924145: length 5.1
  TOP w0.173: U6.L8 119.26,29.48 119.82,29.48 120.07,29.72 121.08,29.72 121.46,30.1 R42.2
N25402841: length 3.2
  TOP w0.173: U101.4 47.84,54.75 47.37,55.22 R959.1
N25402875: length 3.5
  TOP w0.173: U101.5 47.19,54.14 45.95,55.37 R960.1
N25402909: length 4.3
  TOP w0.173: U101.6 46.54,54.02 45.49,55.07 44.73,55.07 44.48,55.31 R961.1
N25403534: length 2.6
  TOP w0.254: R964.1 44.87,68.64 U103.2
N25403747: length 2.6
  TOP w0.173: U99.4 54.71,75.14 R968.2
N25403773: length 2.4
  TOP w0.173: U99.3 54.39,74.49 54.62,74.26 R969.2
N25403799: length 2.8
  TOP w0.173: R970.2 54.14,73.84 U99.2
N25403922: length 3.7
  TOP w0.173: U99.6 54.19,76.44 54.76,77.01 54.76,78.29 R971.2
N25403942: length 4.4
  TOP w0.173: U99.7 54.08,77.09 54.38,77.39 54.38,79.36 R972.2
N25404009: length 3.7
  TOP w0.173: R973.2 55.4,71.5 54.53,72.36 54.53,72.59 53.93,73.19 U99.1
N25485278: length 4.9
  TOP w0.173: R982.2 155.76,139.56 154.72,138.51 C580.1 154.29,138.16 153.91,138.54 U104.4
N25485584: length 2.7
  TOP w0.173: U104.3 150.9,137.25 TP25.1

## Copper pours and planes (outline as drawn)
AGND_GBETH0 on BOTTOM: 23.51,136.72 38.57,136.72 39.82,135.46 44.92,135.46 45.15,135.69 45.15,136.72 43.89,137.97 43.89,140.47 43.31,141.05 25.02,141.05 22.73,138.77 22.35,138.77 22.1,138.51 22.1,138.13
AGND_GBETH1 on BOTTOM: 45.72,136.72 64.9,136.72 66.55,138.37 66.55,140.78 66.29,141.03 47,141.03 45.73,142.3 44,142.3 43.65,141.96 43.65,141.44 44.32,140.76 44.32,138.11
AGND_PROFI on BOTTOM: 77.72,4.95 79.76,6.99 88.43,6.99 90.08,5.33 103.12,5.33 103.76,5.97 103.76,7.49 104.37,8.1 108.17,8.1 110.3,5.97 110.3,1.52 110.14,1.36 78.72,1.36 77.72,2.35
AGNDFRAME_PRU1ETH0 on BOTTOM: 12.07,120.86 14.61,120.86 15.11,121.37 15.11,121.4 15.54,121.83 15.54,124.29 15.11,124.72 15.11,136.65 16.2,137.73 17.75,137.73 18.03,138.01 18.03,140.8 16.64,142.19 12.32,142.19 11.68,141.56 11.68,121.24
AGNDFRAME_PRU1ETH1 on BOTTOM: 12.76,97.11 15.05,97.11 15.56,97.62 15.49,115.02 15.49,118.13 15.18,118.45 14.61,119.01 11.75,119.01 11.38,118.64 11.38,116.65 12.13,115.9 12.13,97.74
AGNDFRAME_PRU2ETH0 on BOTTOM: 12.45,72.85 14.8,72.85 15.3,73.36 15.3,87.72 15.56,87.97 15.56,93.98 15.35,94.19 12.19,94.19 11.87,93.87 11.87,73.42
AGNDFRAME_PRU2ETH1 on BOTTOM: 15.37,51.47 15.37,63.57 15.62,63.83 15.62,69.17 14.99,69.8 12.57,69.8 11.94,69.17 11.94,49.06 12.63,48.37 15.49,48.37 16.08,48.96 16.08,50.76
DGND on TOP: 138.68,46.18 138.05,45.55 135.13,45.55 134.75,45.93 134.75,47.58 135,47.83 136.65,47.83 136.91,48.09 136.91,48.72 137.45,49.27 137.45,51.17 137.54,51.26 138.16,51.26 138.68,50.73
DGND on TOP: 58.93,109.43 58.93,108.23 60.93,106.23 60.93,94.39 60.35,93.81 50.42,93.81 49.66,94.57 48.51,94.57 45.85,97.24 45.85,99.01 45.47,99.4 44.2,99.4 43.43,98.63 43.43,94.7 46.1,92.03 47.75,92.03 49.53,90.25 49.55,90.25 49.69,90.11 54.29,90.11 54.5,90.32 62.3,90.32 64.77,92.79 64.77,103.71 62.48,106 62.48,107.4 60.32,109.56 59.05,109.56 ; 2 cut-outs
DGND on TOP: 147.96,97.87 152.15,97.87 152.53,97.49 152.53,96.47 152.91,96.09 152.91,94.32 152.65,94.06 150.37,94.06 149.61,93.3 149.1,93.3 149.09,93.31 148.93,93.31 148.51,93.73 148.51,95.28 147.7,96.09 147.7,97.62
DGND on TOP: 155.45,127.46 157.1,127.46 157.35,127.21 157.35,125.94 156.72,125.3 155.45,125.3 155.19,125.56 155.19,127.21
DGND on TOP: 149.53,88.14 157.91,88.14 159.82,86.24 159.82,83.95 159.44,83.57 159.18,83.57 157.45,81.84 156.31,81.84 154.86,80.4 149.91,80.4 148.89,81.41 148.89,87.51
DGND on TOP: 84.33,150.09 82.12,150.09 81.51,149.48 81.51,147.27 82.04,146.74 84.33,146.74 84.94,147.35 84.94,149.48
DGND on TOP: 85.24,143.23 83.26,143.23 82.8,142.77 82.8,135.99 83.49,135.31 96.06,135.31 96.52,135.76 96.52,136.98 96.37,137.13 95.07,137.13 94.69,137.52 94.69,138.2 94.31,138.58 89.89,138.58 89.59,138.28 86.08,138.28 85.7,138.66 85.7,142.77
DGND on TOP: 5.97,38.82 7.41,38.82 7.62,38.61 7.62,35.39 7.37,35.13 5.97,35.13 5.71,35.39 5.71,38.56
DGND on TOP: 139.45,53.04 140.59,53.04 140.84,52.79 140.84,51.39 141.1,51.14 141.1,50.75 140.94,50.6 139.22,50.6 138.94,50.88 138.94,51.39 139.19,51.64 139.19,52.79
DGND on TOP: 96.91,150.05 97.82,150.95 99.83,150.95 100.08,150.71 100.08,150.13 99.35,149.41 99.35,144.7 98.51,143.85 95.78,143.85 95.36,144.26 95.36,146.47 96.91,148.02
DGND on TOP: 154.56,62.57 158.24,62.57 158.62,62.18 158.62,59.9 158.24,59.52 154.56,59.52 154.31,59.77 154.31,62.31
DGND on TOP: 106.55,17.4 106.05,17.4 105.28,18.16 103.5,18.16 102.87,18.8 102.87,19.94 103.12,20.19 105.54,20.19 105.79,19.94 105.79,18.67 106.55,17.91
DGND on TOP: 25.78,105.87 23.88,107.78 21.54,107.78 17.27,112.04 16.13,112.04 15.49,112.68 15.49,114.97 14.97,115.49 14.97,116.33 15.17,116.53 15.98,116.53 16.38,116.14 16.38,116.03 22.38,110.04 24.89,110.04 27.66,107.27 34.04,107.27 37.46,110.7 38.48,110.7 38.73,110.44 38.73,109.68 34.92,105.87 ; 2 cut-outs
DGND on TOP: 37.77,105.31 40.08,105.31 40.69,104.7 40.69,99.67 40.31,99.29 38,99.29 37.92,99.22 37.44,99.7 37.44,104.98
DGND on TOP: 5.76,42.93 5.76,46.78 6.35,47.37 9.4,47.37 9.82,46.94 9.82,42.93 9.32,42.42 6.27,42.42
DGND on TOP: 137.16,63.2 138.43,63.2 138.68,62.95 138.68,61.42 138.18,60.91 136.65,60.91 136.4,61.17 136.4,62.44
DGND on TOP: 37.69,88.14 40,88.14 40.61,87.53 40.61,82.5 40.23,82.12 37.77,82.12 37.46,82.43 37.46,87.91
DGND on TOP: 172.97,14.9 174.45,13.59 175.16,15.43 178.33,15.43 180.69,13.08 182.07,13.08 182.73,12.42 182.73,9.92 182.4,8.89 182.73,7.86 182.73,1.79 182.26,1.31 171.78,1.31 171.3,1.79 171.3,11.47 172.61,12.78 172.61,14.54 ; 2 cut-outs
DGND on TOP: 94.31,128.53 94.61,128.22 95.5,128.22 95.62,128.34 95.62,129.6 95.86,129.84 96.54,129.84 96.88,129.5 96.88,127.99 97.66,127.21 97.66,126.83 97.41,126.57 96.9,126.57 95.76,125.43 95.76,123.91 95.5,123.65 94.74,123.65 94.49,123.91 94.49,126.95 93.16,128.28 93.16,129.54 93.4,129.77 94.04,129.77 94.31,129.51
DGND on TOP: 95.58,82.47 101.07,82.47 101.37,82.78 101.37,82.88 100.51,83.74 100.51,85.67 100.69,85.85 101.07,85.85 101.3,85.62 101.3,84.48 101.68,84.1 102.13,84.1 102.36,83.87 102.36,81.94 102.57,81.74 102.67,81.74 103.5,82.58 104.5,82.58 104.5,82.63 105.26,83.39 105.61,83.39 105.7,83.3 105.7,83.07 105.51,82.88 105.51,82.58 105.71,82.37 105.71,81.89 105.79,81.81 106.96,81.81 107.31,81.46 107.31,80.67 107.29,80.64 102.49,80.64 102.13,81 101.57,81 101.22,80.64 94.82,80.64 94.06,81.41 94.06,82.09 93.52,82.63 93.52,83.06 94.03,83.57 94.49,83.57
DGND on TOP: 67.44,91.52 78.99,91.52 81.55,88.97 81.55,86.75 81.9,86.4 81.9,85.71 80.61,84.42 79,84.42 78.38,85.04 67.69,85.04 67.31,85.43 67.31,91.39 ; 1 cut-out
DGND on TOP: 154.56,55.07 156.72,55.07 157.23,54.56 157.23,53.17 156.84,52.79 154.69,52.79 154.43,53.04 154.43,54.95
DGND on TOP: 181,109.43 179.86,110.57 179.86,112.41 176.43,115.84 176.43,118.7 177.06,119.33 188.75,119.33 189.13,118.95 189.13,114.51 187.73,113.11 185.32,113.11 184.64,112.44 184.64,110.66 183.41,109.43 ; 2 cut-outs
DGND on TOP: 176.64,5.23 176.64,7.14 176.81,7.31 177.74,7.31 177.91,7.15 177.91,5.4 177.34,4.83 177.04,4.83
DGND on TOP: 5.84,34.54 6.99,34.54 7.24,34.29 7.24,31.24 6.99,30.99 5.84,30.99 5.59,31.24 5.59,34.29
DGND on TOP: 37.57,63.5 39.88,63.5 40.49,62.9 40.49,57.87 40.11,57.49 37.8,57.49 37.72,57.41 37.24,57.89 37.24,63.17
DGND on TOP: 169.32,117.18 169.06,116.92 165.1,116.92 164.72,117.3 164.72,120.35 165.32,120.95 165.32,130.71 166.39,131.78 184.18,131.78 185.06,130.89 185.06,127.97 184.05,126.95 177.85,126.95 177.22,126.32 169.7,126.32 169.32,125.94
DGND on TOP: 134.14,141.3 138.98,141.3 139.55,140.73 139.55,136.09 137.54,134.08 137.54,131.11 136.94,130.51 136.78,130.51 136.21,131.08 134.43,131.08 134.04,131.46 134.04,135.53 133.55,136.02 133.55,137.02 132.89,137.68 132.89,140.06
DGND on TOP, BOTTOM: 161.62,111.68 161.62,108.38 161.37,108.13 159.84,108.13 159.59,108.38 159.59,111.68 159.84,111.94 161.37,111.94
DGND on BOTTOM: 117.78,80.42 118.81,80.42 119.05,80.18 119.05,78.98 118.68,78.61 117.87,78.61 117.68,78.8 117.68,80.31
DGND on BOTTOM: 116.33,87.5 117.73,87.5 117.98,87.25 117.98,85.47 117.73,85.22 116.33,85.22 115.95,85.6 115.95,87.12
DGND on BOTTOM: 115.27,102.16 116.81,102.16 117.14,101.83 117.14,100.21 116.99,100.06 115.37,100.06 115.14,100.28 115.14,102.04
DGND on BOTTOM: 89.15,74.42 87.12,74.42 86.87,74.68 86.87,78.08 87.02,78.23 89.2,78.23 89.36,78.08 89.36,74.63
DGND on BOTTOM: 104.52,90.51 105.41,90.51 105.66,90.25 105.66,87.99 105.44,87.77 105.14,87.77 104.98,87.92 104.98,88.18 104.27,88.9 104.27,90.25
DGND on BOTTOM: 127.38,122.51 127.38,126.32 127.51,126.45 130.05,126.45 130.48,126.02 130.48,122.56 130.3,122.38 127.51,122.38
DGND on BOTTOM: 72.82,145.45 75.51,145.45 75.99,144.97 77.3,144.97 77.49,144.78 77.49,143.64 77.46,143.61 76.38,143.61 75.96,144.03 75.26,144.03 75.26,143.79 75.23,143.77 72.85,143.77 72.8,143.82 72.8,144.03 72.31,144.03 72.12,144.22 72.12,145 72.16,145.04 72.72,145.04 72.77,145.09 72.77,145.39
DGND on BOTTOM: 131.32,135.59 131.32,133.56 131.57,133.3 135.76,133.3 136.14,133.69 136.14,135.97 135.55,136.56 132.29,136.56
DGND on BOTTOM: 127.89,105.62 129.54,105.62 129.92,105.24 129.92,103.08 129.79,102.95 127.89,102.95 127.64,103.21 127.64,105.36
DGND on BOTTOM: 166.62,127.91 166.62,131.57 166.94,131.89 181.4,131.89 181.51,131.78 184.05,131.78 184.56,131.27 184.56,127.46 184.3,127.21 167.33,127.21
DGND on BOTTOM: 90.58,84.71 90.88,84.71 91.26,84.33 91.26,81.28 91.16,81.18 90.47,81.18 90.3,81.36 90.3,84.43
DGND on BOTTOM: 155.7,127.72 157.48,127.72 157.61,127.59 157.61,125.94 156.97,125.3 155.45,125.3 155.19,125.56 155.19,127.21
DGND on BOTTOM: 98.51,74.12 104.65,74.12 104.83,74.3 104.83,74.55 105.05,74.78 105.51,74.78 105.77,74.53 105.77,73.08 105.59,72.9 105.21,72.9 104.88,73.23 103.77,73.23 103.5,72.97 101.51,72.97 101.04,73.43 100.36,73.43 100.08,73.15 100.08,71.96 101.36,70.68 101.36,69.08 101.07,68.79 100.13,68.79 99.65,69.26 99.65,70.7 99.68,70.72 99.68,70.89 99.4,71.17 99.4,72.57 98.72,73.25 98.42,73.25 98.32,73.35 98.32,73.93
DGND on BOTTOM: 101.14,89.38 103.5,89.38 103.76,89.64 103.76,90.58 103.58,90.75 101.22,90.75 100.86,90.4 100.86,89.66
DGND on BOTTOM: 112.55,80.42 113.54,80.42 113.82,80.14 113.82,78.94 113.39,78.51 112.7,78.51 112.45,78.77 112.45,80.31
DGND on BOTTOM: 64.24,115.09 64.61,115.47 66.79,115.47 67.4,114.85 67.4,110.66 66.65,109.9 64.71,109.9 64.24,110.38
DGND on BOTTOM: 87.45,81.15 88.19,81.15 88.44,81.41 88.44,82.42 88.34,82.52 88.34,84.25 88.16,84.43 87.81,84.43 87.68,84.3 87.68,82.68 87.17,82.17 87.17,81.43
DGND on BOTTOM: 110.26,85.03 111.28,85.03 111.58,84.73 111.58,83.39 111.15,82.96 110.54,82.96 110.11,83.39 110.11,84.89
DGND on BOTTOM: 94.84,71.42 95.38,71.42 95.58,71.22 95.58,70.31 95.63,70.26 97.28,70.26 97.51,70.03 97.51,68.99 96.19,67.67 92.3,67.67 91.92,68.05 91.92,68.78 92.74,69.6 94.23,69.6 94.61,69.98 94.61,71.2
DGND on BOTTOM: 110.85,71.48 110.44,71.88 110.44,72.72 111.18,73.46 111.18,74.98 111.56,75.36 111.56,76.07 111.43,76.2 110.77,76.2 109.91,75.34 109.45,75.34 109.25,75.54 109.25,76.48 109.52,76.76 109.52,78.31 109.12,78.71 108.58,78.71 108.43,78.87 108.43,79.17 109.14,79.88 109.14,80.26 109.27,80.39 110.19,80.39 110.34,80.24 110.34,78.87 111.43,77.77 111.43,76.89 112.17,76.15 112.5,76.15 112.65,76 112.65,75.31 113.06,74.9 113.06,72.77 111.76,71.48
DGND on BOTTOM: 101.93,71.78 103.66,71.78 104.14,71.3 105.05,71.3 105.41,70.94 105.41,70.33 105.87,69.88 107.31,69.88 107.47,69.72 107.47,68.81 107.09,68.43 105.71,68.43 103.58,70.56 101.96,70.56 101.73,70.79 101.73,71.58
DGND on BOTTOM: 79.93,79.76 80.82,79.76 81.08,79.5 81.08,77.88 80.47,77.27 80.47,74.63 80.26,74.42 80.06,74.42 79.73,74.75 79.73,79.55
DGND on BOTTOM: 120.14,91.78 122.81,91.78 123.19,91.39 123.19,88.09 122.83,87.73 119.99,87.73 119.51,88.22 119.51,91.14
DGND on BOTTOM: 75.58,83.41 73.77,83.41 73.2,83.98 73.2,87.12 73.61,87.53 76,87.53 76.33,87.2 76.33,84.16
DGND on BOTTOM: 156.46,55.71 156.46,55.48 156.09,55.11 154.55,55.11 154.23,54.79 154.23,53.12 154.56,52.79 156.97,52.79 157.25,53.07 157.25,55.81 157.18,55.88 156.64,55.88
DGND on BOTTOM: 86.36,89.74 86.36,91.22 86.78,91.64 91.7,91.64 92.46,90.89 92.46,89.74 92.33,89.62 86.49,89.62
DGND on BOTTOM: 103.45,94.54 110.85,94.54 111.4,93.98 111.4,93.27 111,92.86 103.66,92.86 103.1,93.42 103.1,94.18
DGND on BOTTOM: 131.01,129.39 132.21,129.39 132.64,128.96 132.64,128.17 132.33,127.87 131.17,127.87 130.71,128.33 130.71,129.09
DGND on BOTTOM: 74.42,114.64 74.42,116.41 74.68,116.67 76.2,116.67 76.45,116.41 76.45,114.64 76.2,114.38 74.68,114.38
DGND on BOTTOM: 6.1,38.18 7.11,38.18 7.62,37.67 7.62,35.39 7.37,35.13 5.97,35.13 5.71,35.39 5.71,37.8
DGND on BOTTOM: 127.51,132.57 130.06,132.57 130.24,132.4 130.24,131.41 129.72,130.89 127.38,130.89 127.25,131.02 127.25,132.31
DGND on BOTTOM: 67.95,107.27 67.95,109.3 68.2,109.56 69.72,109.56 69.98,109.3 69.98,107.27 69.72,107.02 68.2,107.02
DGND on BOTTOM: 183.67,135.48 183.13,136.02 183.13,139.95 182.25,140.84 164.29,140.84 162.05,143.08 162.05,148.84 164.34,151.13 173.36,151.13 174.44,150.04 174.44,144.61 176.05,143 179.61,143 181.25,142 182.9,143 186.66,143 188.93,140.74 188.93,136.35 188.06,135.48 ; 1 cut-out
DGND on BOTTOM: 92.96,83.24 93.75,83.24 93.98,83.01 93.98,81.61 93.73,81.36 93.32,81.36 92.58,82.09 92.58,82.85
DGND on BOTTOM: 30.73,108.29 27.94,111.08 27.94,114 28.19,114.25 28.19,114.76 27.94,115.02 27.94,115.65 26.16,117.43 23.88,117.43 23.88,116.16 24.38,115.65 25.27,115.65 25.65,115.27 25.65,109.68 29.53,105.81 33.72,105.81 36.2,103.33 37.72,103.33 37.85,103.46 37.85,105.49 35.05,108.29
DGND on BOTTOM: 148.34,134.07 150.24,134.07 150.5,133.81 150.5,127.46 150.24,127.21 148.34,127.21 148.08,127.46 148.08,133.81
DGND on BOTTOM: 121.39,87.48 122.83,87.48 123.06,87.25 123.06,85.6 122.68,85.22 121.28,85.22 121.03,85.47 121.03,87.12
DGND on BOTTOM: 117.22,75.44 117.22,78.05 116.92,78.36 115.19,78.36 115.06,78.23 115.06,76.33 114.94,76.2 114.94,74.3 115.19,74.04 115.82,74.04
DGND on BOTTOM: 93.5,86.84 96.09,86.84 96.55,86.39 96.55,86 96.85,85.7 96.85,85.39 96.29,85.39 96.06,85.17 96.06,84.66 95.96,84.56 95.55,84.56 95.1,85.01 93.17,85.01 92.81,85.37 92.81,86.16
DGND on BOTTOM: 88.27,34.62 88.11,34.47 87.25,34.47 86.59,33.81 85.29,33.81 85.12,33.99 85.12,34.67 85.62,35.18 86.13,35.18 87.17,36.22 88.09,36.22 88.27,36.04
DGND on BOTTOM: 28.7,18.92 29.84,18.92 30.1,18.67 30.1,15.62 29.84,15.37 28.7,15.37 28.45,15.62 28.45,18.67
DGND on BOTTOM: 102.69,83.03 102.69,81.74 102.46,81.51 99.03,81.51 98.88,81.66 98.88,82.04 99.49,82.65 100.63,82.65 101.17,82.12 101.55,82.12 101.7,82.27 101.7,83.03 101.85,83.19 102.54,83.19
DGND on BOTTOM: 96.52,79.38 96.52,78.87 96.39,78.74 95.76,78.74 95.35,78.33 93.62,78.33 93.09,78.87 93.09,79.83 93.37,80.11 94.16,80.11 94.23,80.04 94.23,79.5 94.49,79.25 95.38,79.25 95.63,79.5 96.39,79.5
DGND on BOTTOM: 98.93,93.22 101.47,93.22 101.73,92.96 101.73,91.17 101.54,90.99 101.1,90.99 100.41,90.3 98.93,90.3 98.81,90.42 98.81,93.09
DGND on BOTTOM: 81.1,84.63 81.58,84.63 81.71,84.51 81.71,80.95 81.56,80.8 80.72,80.8 80.24,81.28 80.24,83.77
DGND on BOTTOM: 133.22,125.3 135,125.3 135.26,125.05 135.26,123.02 135.13,122.89 132.08,122.89 131.93,123.04 131.93,123.37 132.23,123.68 132.23,124.31
DGND on BOTTOM: 141.35,127.21 143.64,127.21 143.76,127.08 143.76,126.07 143.64,125.94 141.35,125.94 141.1,126.19 141.1,126.95
DGND on BOTTOM: 109.4,88.37 111.38,88.37 111.89,87.86 111.89,85.6 111.71,85.42 110.29,85.42 110.19,85.53 110.19,87.48 109.8,87.86 109.37,87.86 109.27,87.96 109.27,88.24
DGND on BOTTOM: 114.43,53.17 120.65,53.17 121.67,52.15 121.67,49.61 120.65,48.6 114.3,48.6 113.54,49.36 113.54,52.28
DGND on BOTTOM: 107.61,86.81 108.08,86.81 108.18,86.71 108.18,85.28 108.76,84.7 108.76,84.53 107.21,82.98 106.81,82.98 106.73,83.06 106.73,83.64 106.86,83.77 107.26,83.77 107.54,84.05 107.54,84.69 107.39,84.84 107.39,86.59
DGND on BOTTOM: 102.87,97.94 102.87,99.28 103.52,99.94 104.71,99.94 105.56,99.09 105.56,97.76 105.36,97.56 103.24,97.56
DGND on BOTTOM: 50.55,108.16 52.07,106.63 52.07,100.03 50.41,98.37 44.48,98.37 43.21,99.64 43.21,107.51 38.82,107.51 38.59,107.73 38.59,108.67 38.77,108.85 41.18,108.85 41.88,108.16
DGND on BOTTOM: 97.18,96.75 97.18,98.04 97.51,98.37 99.29,98.37 99.54,98.12 99.54,96.72 99.16,96.34 97.59,96.34
DGND on BOTTOM: 96.65,93.3 97.41,93.3 97.66,93.05 97.66,90.93 97.03,90.3 96.6,90.3 96.39,90.51 96.39,93.05
DGND on BOTTOM: 101.09,87.68 102.59,87.68 103.78,86.49 103.78,86.14 103.6,85.96 102.83,85.96 102.59,85.72 102.08,85.72 101.75,86.06 101.75,86.72 101.47,87 101.04,87 100.89,87.15 100.89,87.48
DGND on BOTTOM: 157.23,58.76 157.23,59.26 156.34,60.15 156.34,62.44 156.08,62.69 154.69,62.69 154.43,62.44 154.43,59.64 154.56,59.52 155.96,59.52 156.72,58.76
DGND on BOTTOM: 56.87,123.42 58.01,123.42 58.83,122.61 59.79,122.61 59.8,122.6 59.8,120.86 59.42,120.48 56.63,120.48 56.38,120.73 56.38,122.93
DGND on BOTTOM: 50.8,92.48 48.74,92.48 47.98,91.72 47.98,84.56 48.67,83.87 50.72,83.87 51.56,84.71 51.56,91.72
DGND on BOTTOM: 100.28,78.64 103.94,78.64 104.06,78.52 104.06,77.78 104.11,77.73 104.11,77.55 103.96,77.4 103.63,77.4 103.48,77.55 102.7,77.55 101.78,76.63 101.17,76.63 100.25,77.55 100.41,77.55 100.18,77.78 100.18,78.54
DGND on BOTTOM: 34.95,123.5 37.67,123.5 38.2,122.97 38.2,121.01 37.49,120.3 35,120.3 34.54,120.76 34.54,123.09
DGND on BOTTOM: 153.45,105.9 150.16,105.9 149.91,105.65 149.91,104.63 150.8,103.74 153.47,103.74 153.72,104 153.72,105.63
DGND on BOTTOM: 142.37,134.83 146.43,134.83 146.56,134.96 146.56,136.61 146.3,136.86 142.37,136.86 142.11,136.61 142.11,135.08
DGND on BOTTOM: 109.98,18.03 110.36,18.41 110.74,18.41 111.12,18.03 111.12,16.13 110.74,15.75 110.74,14.22 110.36,13.84 106.93,13.84 106.55,14.22 106.55,17.65 106.93,18.03
DGND on BOTTOM: 95.66,76.43 101.57,76.43 101.83,76.18 101.83,75.54 101.63,75.34 99.8,75.34 99.43,75.71 95.82,75.71 95.55,75.98 95.55,76.33
DGND on BOTTOM: 101.32,67.77 103.15,67.77 103.5,67.41 103.5,66.19 103.12,65.81 101.47,65.81 101.02,66.27 101.02,67.46
DGND on BOTTOM: 24.77,40.91 24.97,39.67 26.16,39.27 26.16,37.67 26.54,37.29 27.47,37.29 27.56,37.2 27.56,36.66 27.43,36.53 24.51,36.53 23.88,37.17 16.76,37.17 16.51,37.42 16.51,43.12 17.67,44.28 24.26,44.28 24.77,43.77
DGND on BOTTOM: 107.09,88.93 108.69,88.93 108.99,89.24 108.99,90.45 108.66,90.78 107.34,90.78 106.96,90.4 106.96,89.06
DGND on BOTTOM: 125.55,115.17 125.3,115.42 125.3,117.86 125.73,118.29 129.01,118.29 129.29,118.01 129.29,115.47 128.98,115.17
DGND on BOTTOM: 63.5,104.6 65.41,102.7 65.41,96.86 64.39,95.84 58.8,95.84 57.4,97.24 57.4,104.22 57.78,104.6
DGND on BOTTOM: 130.89,126.78 132.38,126.78 132.46,126.7 132.46,125.05 132.21,124.8 131.32,124.8 130.71,125.41 130.71,126.6
DGND on BOTTOM: 93.07,75.92 93.24,75.92 93.42,75.74 93.42,72.8 93.22,72.59 92.51,72.59 92.15,72.95 90.55,72.95 90.35,73.15 90.35,73.79 90.5,73.94 91.08,73.94
DGND on BOTTOM: 106.5,114.89 112.65,114.89 113.03,114.51 113.03,113.87 112.78,113.62 106.55,113.62 106.43,113.75 106.43,114.81
DGND on L2_GND1, L5_GND2: 2.2,151.13 84.01,151.13 84.61,150.53 96.26,150.53 96.86,151.13 188.3,151.13 189.2,150.22 189.2,2.21 188.29,1.3 2.21,1.3 1.27,2.24 1.27,150.2 ; 24 cut-outs
DGND on L3_SIG1: 1.27,150.2 1.91,150.83 83.82,150.83 84.45,150.2 96.52,150.2 97.16,150.83 99.06,150.83 100.33,149.56 100.33,143.85 99.06,142.58 74.93,142.58 69.22,136.86 48.89,136.86 43.18,131.15 21.59,131.15 14.61,124.16 14.61,102.57 22.86,94.32 22.86,91.78 22.23,91.14 16.51,91.14 12.07,86.7 3.17,86.7 1.27,88.6 ; 1 cut-out
DGND on L3_SIG1: 22.23,118.11 22.23,123.19 24.77,125.73 29.84,125.73 31.12,124.46 39.37,124.46 41.27,126.36 46.35,126.36 48.26,124.46 48.26,121.28 45.09,118.11 29.84,118.11 29.21,117.47 22.86,117.47
DGND on L3_SIG1: 147.32,141.61 151.13,141.61 153.67,144.15 165.1,144.15 169.55,148.59 177.8,148.59 180.34,146.05 180.34,142.24 171.45,133.35 171.45,121.92 159.39,109.86 153.67,109.86 151.13,112.39 151.13,133.99 147.32,137.8
DGND on L3_SIG1: 97.64,80.44 101.37,80.44 101.37,81.1 100.58,81.89 100.58,82.68 100.25,83.01 99.47,83.01 99.47,82.19 98.37,81.1 97.87,81.1 97.56,80.8 97.56,80.52
DGND on L3_SIG1: 108.61,86.21 109.07,86.21 109.35,86.49 109.35,87.2 110.16,88.01 110.16,88.47 110.01,88.62 108.79,88.62 108.48,88.32 108.48,86.33
DGND on L3_SIG1: 173.36,1.61 171.45,3.51 171.45,20.02 164.47,27.01 164.47,34.63 171.45,41.61 171.45,54.31 166.37,59.39 166.37,60.66 167.64,61.93 173.36,61.93 177.17,58.12 177.17,15.58 179.71,13.04 180.34,13.04 181.61,14.31 181.61,14.94 179.07,17.48 179.07,60.03 173.99,65.11 172.09,65.11 170.18,67.01 170.18,75.27 170.82,75.9 187.96,75.9 189.23,74.63 189.23,3.51 187.33,1.61
DGND on L3_SIG1: 6.99,80.35 20.32,80.35 24.77,75.9 24.77,72.09 21.59,68.92 21.59,53.68 15.24,47.33 8.25,47.33 5.71,49.87 5.71,79.08
DGND on L3_SIG1: 151.13,69.85 154.31,69.85 169.55,54.61 169.55,41.91 166.37,38.73 160.02,38.73 154.94,43.81 149.86,43.81 148.59,45.09 148.59,50.16 150.5,52.07 150.5,64.14 149.23,65.41 149.23,67.95
DGND on L3_SIG1: 116.84,137.8 121.28,137.8 123.19,135.89 130.18,135.89 132.08,133.99 132.08,131.44 133.99,129.54 133.99,127.64 128.91,122.55 128.91,114.94 128.27,114.3 125.73,114.3 119.38,120.65 119.38,125.73 114.3,130.81 114.3,135.26
DGND on L3_SIG1: 85.85,125.94 90.04,125.94 90.68,125.3 106.68,125.3 119,112.98 119,112.22 118.36,111.59 117.98,111.59 117.86,111.71 117.6,111.71 106.4,122.92 100.46,122.92 100.03,122.48 97.84,122.48 96.93,123.4 89.41,123.4 88.52,124.29 87.68,124.29 86.97,123.58 85.62,123.58 84.79,124.41 65.13,124.41 64.77,124.06 60.6,124.06 59.31,122.76 54.05,122.76 52.65,121.37 51.28,121.37 49.91,119.99 49.91,116.79 49.28,116.16 47.37,116.16 46.86,116.67 46.86,118.95 48.64,120.73 48.64,122.38 51.05,124.8 58.29,124.8 58.67,125.18 60.2,125.18 60.99,125.96 63.88,125.96 64.49,126.57 68.48,126.57 69.09,125.96 85.83,125.96 ; 2 cut-outs
DGND on L3_SIG1: 111.63,89.24 111.51,89.36 111.51,89.87 112.01,90.38 112.65,90.38 113.28,91.01 115.82,91.01 118.24,93.43 118.24,99.14 120.14,101.05 120.14,104.2 115.54,108.79 111.63,108.79 110.85,109.58 109.55,109.58 105.21,113.92 93.17,113.92 91.95,115.14 84.58,115.14 84.33,114.89 69.27,114.89 64.44,110.06 60.07,110.06 59.94,110.19 59.94,111.38 61.29,112.73 62.71,112.73 67.41,117.43 75.31,117.43 75.51,117.63 101.27,117.63 101.5,117.4 105.82,117.4 112.65,110.57 112.65,110.19 113.16,109.68 115.95,109.68 122.58,103.05 122.58,102.32 121.92,101.66 121.49,101.66 119.28,99.45 119.28,98.84 120.02,98.1 120.02,92.92 116.71,89.62 112.52,89.62 112.14,89.24 ; 2 cut-outs
DGND on L3_SIG1: 43.18,86.7 53.34,86.7 55.24,88.6 62.88,88.6 54.41,80.13 54.41,72.36 52.43,70.38 47.45,70.38 45.02,67.96 45.02,61.36 37.31,53.64 37.31,16.13 36.32,15.14 31.42,15.14 30.45,16.11 20.47,16.11 13.97,22.61 13.97,42.04 22.99,51.05 22.99,65.87 33.02,75.9 35.56,75.9 41.91,82.25 41.91,85.43
DGND on L3_SIG1: 94.89,85.65 95.61,85.65 95.96,86 95.96,87.3 96.09,87.43 96.72,87.43 96.82,87.33 96.82,84.68 96.62,84.48 95.25,84.48 95,84.73 94.46,84.73 93.73,85.47 93.73,86.23 93.85,86.36 94.18,86.36
DGND on L4_SIG2: 95.38,81.91 93.98,81.91 91.48,79.41 91.48,77.77 93.16,76.09 97.9,76.09 98.55,75.44 98.55,57.78 106.43,49.91 106.43,47.5 115.32,38.61 121.92,38.61 125.73,34.8 135.26,34.8 135.26,34.42 124.21,23.37 82.55,23.37 81.28,22.1 72.9,22.1 68.96,26.03 61.21,26.03 56.52,21.34 51.69,21.34 45.54,27.48 45.54,41.02 50.18,45.66 50.18,46.93 56.87,53.62 56.87,60.05 67.97,71.15 67.97,78.64 71.25,81.91 75.95,81.91 79.5,85.47 80.9,85.47 81.41,84.96 84.33,84.96 84.58,84.71 88.77,84.71 89.92,83.57 90.93,83.57 91.31,83.19 93.85,83.19 94.11,83.44 94.36,83.44 95.38,82.42
DGND on L4_SIG2: 166.37,116.54 176.19,116.54 178.85,119.2 188.04,119.2 188.59,118.64 188.59,105.11 186.06,102.57 171.45,102.57 167.64,98.76 167.64,96.22 173.99,89.87 173.99,73.36 172.72,72.09 170.18,72.09 157.48,84.79 140.34,84.79 138.43,86.7 138.43,89.28 149.23,100.08 149.23,107.02 154.94,112.73 162.56,112.73
DGND on L4_SIG2: 2.54,150.83 83.82,150.83 84.45,150.2 84.45,147.66 80.64,143.85 80.64,140.67 78.11,138.13 72.39,138.13 66.67,132.42 64.14,132.42 59.69,127.97 23.49,127.97 17.78,122.26 17.78,110.19 24.13,103.84 31.12,103.84 33.02,101.94 33.02,100.03 31.12,98.13 20.95,98.13 10.79,108.29 5.08,108.29 1.91,111.46 1.91,150.2
DGND on L6_PWR1: 2.2,151.13 69.14,151.13 70,150.27 70,129.34 73.53,125.81 82.68,125.81 83.19,126.32 83.19,128.22 85.22,130.26 105.41,130.26 106.6,129.06 106.6,119.08 95.35,107.83 95.35,96.3 94.39,95.33 82.55,95.33 81.28,94.06 81.28,85.2 80.08,84 60.68,84 58.67,82 58.67,76.54 58.04,75.9 50.55,75.9 49.02,74.38 49.02,47.45 48.51,46.94 1.27,46.94 1.27,150.2
DGND on L8_GND3: 1.27,150.2 2.2,151.13 84.01,151.13 84.61,150.53 96.26,150.53 96.29,150.55 96.29,147.76 96.39,147.66 60.83,112.1 60.83,81.62 74.3,68.15 93.98,68.15 100.33,74.5 103.38,74.5 105.41,76.54 113.87,76.54 114.3,76.96 114.3,84.2 114.64,84.54 121.28,84.54 124.59,87.84 124.59,105.62 124.84,105.87 151.26,105.87 153.8,108.41 153.8,139.65 149.73,143.72 136.78,143.72 136.65,143.85 136.65,145.62 134.49,147.78 97.28,147.78 96.65,148.42 96.65,150.91 96.86,151.13 188.3,151.13 189.2,150.22 189.2,2.21 188.29,1.3 2.21,1.3 1.27,2.24 ; 24 cut-outs
DGND on L9_SIG3: 80.01,72.73 97.16,72.73 98.42,71.46 98.42,57.49 111.12,44.79 119.38,44.79 121.28,42.88 121.28,38.44 126.24,33.48 141.1,33.48 146.69,39.07 152.4,39.07 173.21,18.26 176.49,18.26 178.62,16.12 178.62,12.59 170.18,4.15 157.48,4.15 154.94,6.69 134.62,6.69 132.72,8.59 116.84,8.59 111.76,13.67 97.16,13.67 94.61,11.13 81.91,11.13 71.12,21.93 71.12,35.26 68.71,37.67 68.71,42.75 62.86,48.6 62.86,55.58
DGND on L9_SIG3: 160.39,70.85 171.68,70.85 178.27,64.27 178.27,63.47 177.81,63.01 177.81,62.31 180.98,59.14 180.98,40 179.07,38.1 179.07,19.69 178.44,19.05 177.17,19.05 173.99,22.23 171.45,22.23 167.17,26.51 167.17,52.36 169.47,54.66 174.24,54.66 174.63,55.05 174.63,55.78 174.05,56.36 170.86,56.36 159.63,67.59 159.63,70.1
DGND on L9_SIG3: outline of 92 points within 1.27,1.61 116.2,150.83 ; 4 cut-outs
DGND on L9_SIG3: 38.1,108.92 53.98,108.92 55.88,107.02 55.88,100.03 58.42,97.49 58.42,85.85 55.24,82.68 55.24,68.28 52.07,65.11 52.07,48.51 54.36,46.23 61.09,46.23 67.06,40.26 67.06,27.05 65.41,25.4 62.86,25.4 62.86,16.85 63.5,16.21 64.14,16.21 66.67,18.75 68.63,18.75 71.12,16.26 74.25,16.26 74.68,15.83 74.68,14.61 73.02,12.95 56.77,12.95 50.04,19.69 50.04,24 50.67,24.64 48.89,26.42 42.67,26.42 38.61,30.48 38.61,43.69 34.29,48.01 34.29,75.9 35.56,77.17 35.56,82.25 37.46,84.16 40.64,84.16 42.55,86.06 42.55,89.87 40.64,91.78 40.64,102.57 37.46,105.75 37.46,108.29
DGND on L9_SIG3: 135.26,76.83 135.26,81.28 145.42,91.44 145.42,105.41 146.69,106.68 151.77,106.68 155.58,102.87 155.58,98.42 157.48,96.52 158.75,96.52 163.2,100.97 180.34,100.97 183.52,97.79 183.52,91.44 178.44,86.36 161.29,86.36 151.13,76.2 135.89,76.2
DGND on L9_SIG3: 158.12,73.02 179.71,73.02 181.61,74.93 181.61,81.91 179.71,83.82 160.66,83.82 156.21,79.38 156.21,74.93
DGND on L10_SIG4: 23.49,1.61 2.54,1.61 1.27,2.87 1.27,149.56 2.54,150.83 76.83,150.83 78.11,149.56 78.11,141.94 85.09,134.96 98.83,134.96 100.28,133.5 102.13,133.5 110.16,125.48 119.33,125.48 121.28,123.53 121.28,121.62 115.57,115.91 110.49,115.91 102.23,124.16 91.44,124.16 86.36,129.24 24.77,129.24 20.95,125.43 18.41,125.43 14.61,121.62 10.16,121.62 3.81,115.27 3.81,111.46 13.97,101.3 31.12,101.3 33.02,103.21 37.46,103.21 40.64,100.03 59.69,100.03 60.32,99.4 71.12,99.4 71.75,100.03 74.3,100.03 74.93,99.4 74.93,97.49 74.3,96.86 67.31,96.86 57.15,86.7 40,86.7 38.1,88.6 31.12,88.6 27.94,85.43 27.94,81.97 19.69,73.71 19.69,41.61 38.1,23.2 38.1,22.56 36.83,21.29 28.58,21.29 24.13,16.85 24.13,2.24 ; 3 cut-outs
DGND on L10_SIG4: 46.35,1.61 45.72,2.24 45.72,7.96 47.62,9.86 53.34,9.86 55.24,7.96 71.12,7.96 72.39,6.69 123.19,6.69 125.09,8.59 133.35,8.59 133.44,8.5 150.11,8.5 154.64,13.04 175.26,13.04 176.53,14.31 176.53,15.58 175.26,16.85 175.26,33.99 183.52,42.25 183.52,60.03 184.79,61.3 184.79,72.09 180.98,75.9 180.98,100.03 177.17,103.84 176.53,103.84 175.9,103.21 175.9,101.94 177.8,100.03 177.8,88.6 176.53,87.33 172.72,87.33 169.55,90.51 169.55,108.29 166.37,111.46 166.37,133.69 168.28,135.59 183.52,135.59 189.23,129.88 189.23,3.51 187.33,1.61
DGND on L10_SIG4: 114.68,53.42 120.52,53.42 121.54,52.41 121.54,51.01 121.03,50.5 114.3,50.5 113.66,51.14 113.66,52.41
DGND on L10_SIG4: 30.52,118.14 40.93,118.14 42.71,116.36 60.83,116.36 62.59,114.61 82.58,114.61 86.79,110.39 86.79,106.06 85.62,104.89 85.62,104.63 85.22,104.22 84.2,104.22 82.14,106.28 82.14,108.77 78.38,112.53 62.1,112.53 59.69,114.94 40.95,114.94 40.39,114.38 39.75,114.38 37.41,116.72 29.93,116.72 29.47,117.18 29.47,118.19 30.47,118.19 ; 3 cut-outs
DGND on L10_SIG4: 41.27,51.14 61.06,51.14 66.17,56.24 66.17,61.34 77.85,73.02 77.85,71.12 69.47,62.74 69.47,51.82 66.27,48.62 66.27,39.95 66.29,39.95 67.31,38.93 67.31,25.1 66.61,24.4 66.61,22.98 72.39,17.2 81.56,17.2 85.31,20.95 86.96,20.95 87.81,21.8 107.17,21.8 107.33,21.63 114.66,21.63 121,27.98 121,33.03 118.07,35.96 109.61,35.96 107.82,37.75 107.82,45.88 109.77,47.83 133.7,47.83 135.97,45.56 135.97,34.82 128.25,27.09 125.64,27.09 117.42,18.87 101.8,18.87 100.03,17.1 92.55,17.1 91.23,15.78 71.12,15.78 70.88,16.02 63.71,23.2 54.61,23.2 50.8,27.01 47.62,27.01 43.81,30.82 43.81,33.36 39.37,37.8 39.37,44.15 32.38,51.14 32.38,60.03 33.02,60.66 36.83,60.66 37.46,60.03 37.46,54.95
DGND on L10_SIG4: outline of 108 points within 14.1,101.05 110.11,127.82 ; 5 cut-outs
DGND on L10_SIG4: 85.85,79.63 85.85,78.49 84.71,78.49 81.91,75.69 80.52,75.69 84.45,79.63
DGND on L11_GND4: 2.2,151.13 84.01,151.13 84.61,150.53 96.26,150.53 96.86,151.13 188.3,151.13 189.2,150.22 189.2,2.21 188.26,1.27 2.24,1.27 1.27,2.24 1.27,150.2 ; 24 cut-outs
GND_CAN1 on L3_SIG1: 170.05,19.64 170.05,13.31 165.9,9.16 165.9,7.49 161.84,3.42 150.77,3.42 148.08,6.11 148.08,19.89 155.07,26.88 162.81,26.88
GND_OSC0 on TOP: 70.74,84.66 79.8,84.66 81.08,83.39 81.08,82.55 78.66,80.14 70.65,80.14 69.85,80.94 69.85,83.77 ; 1 cut-out
GND_OSC0 on L3_SIG1: 78.98,84.58 79.25,84.58 81.41,82.42 87.63,82.42 88.16,81.9 94.19,81.9 94.56,81.53 94.56,80.92 94.11,80.47 80.01,80.47 79.93,80.54 79.27,80.54 78.84,80.11 71.4,80.11 70.92,80.59 70.92,81.23 71.45,81.76 76.16,81.76
GNDPROFI on TOP: 112.39,6.35 116.2,6.35 116.59,6.73 118.62,6.73 118.75,6.6 118.75,4.83 118.49,4.57 115.95,4.57 115.7,4.32 115.19,4.32 114.68,4.83 112.27,4.83 112.27,6.22
GNDPROFI on L3_SIG1: 92.46,13.89 118.52,13.89 121.95,10.46 121.95,6.91 119.38,4.34 116.31,4.34 115.85,4.8 112.57,4.8 109.14,8.23 103.33,8.23 103.2,8.36 98.6,8.36 97.84,7.59 97.84,6.07 97.87,6.05 97.87,2.67 96.57,1.37 89.31,1.37 87.73,2.95 87.73,9.17
GNDUSB1 on BOTTOM: 46.61,15.05 46.61,16.46 47.12,16.97 49.45,16.97 49.96,16.46 49.96,9.78 47.32,7.14 44.91,7.14 43.31,8.74 35.15,8.74 34.11,7.7 31.29,7.7 30.4,8.59 30.4,18.72 30.61,18.92 31.62,18.92 31.88,18.67 31.88,16.64 36.88,11.63 43.2,11.63
GNDUSB2 on TOP: 1.4,35.69 1.4,46.94 1.65,47.2 4.06,47.2 4.32,46.94 4.32,45.67 3.84,45.19 3.84,39.04 4.06,38.82 5.08,38.82 5.28,38.61 5.28,31.19 5.08,30.99 4.45,30.99 4.19,31.24 4.19,32.89
GNDUSB2 on BOTTOM: 4.75,39.12 4.95,38.92 4.95,35.41 4.55,35.01 2.03,35.01 1.3,35.74 1.3,38.08 2.16,38.08 3.2,39.12
GNDUSB2 on BOTTOM: 4.32,47.2 5.03,46.49 5.03,43.34 4.8,43.11 3.2,43.11 2.54,43.77 1.43,43.77 1.43,46.97 1.65,47.2
GNDUSBJ on TOP: 189.2,8.31 186.87,8.31 185.82,9.35 185.73,9.6 185.6,9.84 185.6,11.35 186.08,11.84 186.77,11.84 187.43,11.18 189.2,11.18
GNDUSBJ on TOP: 185.78,16.46 185.55,16.69 185.55,16.84 185.6,16.89 185.6,20.22 186.44,21.06 189.2,21.06 189.2,17.48 188.14,17.48 188.11,17.5 187.2,16.59 187.2,16.46
GNDUSBJ on BOTTOM: 184.02,21.16 188.49,21.16 189.18,20.47 189.18,8.31 188.57,7.7 187.2,7.7 186.13,8.77 186.13,10.33 186.66,10.87 186.66,18.14 185.98,18.82 184.28,18.82 183.74,19.35 183.74,20.88
V1_2D on TOP: 150.24,101.43 150.5,101.17 150.5,100.79 150.75,100.54 151.89,100.54 152.78,101.43 155.45,101.43 157.35,99.52 157.35,96.6 156.34,95.59 156.34,93.3 153.04,90 146.43,90 145.54,90.89 145.54,94.44 146.18,95.08 147.85,95.08 148.13,94.79 148.13,94.3 147.93,94.1 147.93,92.34 148.23,92.04 149.88,92.04 151.52,93.68 152.91,93.68 153.29,94.06 153.29,96.6 153.54,96.86 154.56,96.86 154.94,97.24 154.94,99.01 154.43,99.52 149.61,99.52 149.1,100.03 148.21,100.03 147.96,100.28 147.96,101.17 148.21,101.43
V1_8D on TOP: 175.18,9.32 175.18,10.24 175.37,10.43 179.69,10.43 180.07,10.05 180.07,8.14 179.81,7.89 178.16,7.89 177.02,9.03 175.47,9.03
V1_8D on BOTTOM: 96.55,75.39 98.7,75.39 99.04,75.05 102.63,75.05 102.87,75.29 102.87,76.92 103.05,77.09 103.4,77.09 103.89,76.61 103.89,76.4 104.01,76.28 104.01,75.24 103.17,74.4 98.2,74.4 97.94,74.14 97.94,73.37 98.38,72.93 98.55,72.93 99.11,72.37 99.11,71 99.36,70.75 99.36,69.33 99.12,69.09 97.92,69.09 97.78,69.23 97.78,70.81 98.04,71.07 98.04,71.71 97,72.75 97,73.82 96.76,74.06 96.25,74.06 96.24,74.07 96.24,75.09
V1_8D on BOTTOM: 39.5,92.84 39.5,98.17 39.75,98.42 41.02,98.42 42.29,97.16 43.69,97.16 44.45,97.92 48.39,97.92 49.28,97.03 49.28,95.63 48.26,94.61 43.05,94.61 41.4,92.96 41.4,91.76 40.44,90.8 38.48,90.8 38.29,90.99 38.29,91.63
V1_8D on BOTTOM: 104.95,87.41 104.95,87.02 104.8,86.87 103.93,86.87 102.72,88.09 101.12,88.09 100.97,88.24 100.97,88.9 101.17,89.11 103.52,89.11 104.68,87.95 104.68,87.69
V1_8D on BOTTOM: 139.32,134.96 138.05,134.96 137.16,135.84 137.16,136.73 137.41,136.99 139.07,136.99 139.45,136.61 139.45,135.08
V1_8D on BOTTOM: 117.73,128.91 113.03,128.91 112.78,129.16 112.78,130.3 113.03,130.56 119.38,130.56 121.16,128.78 121.16,124.97 120.9,124.71 120.27,124.71 120.02,124.97 120.02,127.13 119.51,127.64 119,127.64
V1_8D on BOTTOM: 91.82,98.68 93.73,98.68 93.98,98.42 93.98,98.04 93.79,97.85 91.76,97.85 91.57,98.04 91.57,98.42
V1_8D on BOTTOM: 179.82,10.18 177.57,10.18 177.25,9.86 177.25,8.36 177.77,7.85 179.78,7.85 180.15,8.22 180.15,9.85
V1_8D on L4_SIG2: 96.17,89.68 99.54,89.68 101.3,87.92 101.3,86.65 101.05,86.4 96.5,86.4 95.76,87.15 95.76,89.27
V1_8D on L7_PWR2: 105.55,87.57 105.55,86.68 105.54,86.7 105.54,81.69 107.64,79.58 108.29,79.58 109.42,78.46 109.42,76.3 108.64,75.52 102.49,75.52 100.46,77.55 100.46,77.8 100.05,78.21 98.86,78.21 98.53,78.54 98.53,78.54 98.25,78.82 96.39,78.82 96.01,78.44 96.01,74.76 68.45,74.76 66.67,76.54 66.67,85.43 55.42,96.72 53.34,98.81 52.07,98.81 50.16,96.9 43.94,96.9 40.89,99.95 40.89,102.95 41.66,103.71 64.26,103.71 66.67,101.3 73.18,101.3 75.97,104.09 92.33,104.09 93.47,102.95 95.38,102.95 96.52,104.09 113.03,104.09 115.32,106.38 115.32,128.99 116.33,130 127.89,130 131.44,133.56 131.44,137.11 131.95,137.62 139.83,137.62 141.75,135.7 141.75,131.29 139.32,128.86 139.32,126.07 133.1,119.84 133.1,102.44 125.6,94.95 87.63,94.95 86.61,95.97 84.96,95.97 83.57,94.57 83.57,91.52 91.95,83.14 100.08,83.14 100.46,83.52 100.46,86.44 99.95,86.95 96.9,86.95 96.59,87.26 96.59,88.8 96.9,89.11 105.16,89.11 105.54,88.73 105.54,87.58
V1_8D on L10_SIG4: 138.89,136.78 139.95,135.72 139.95,135.08 139.7,134.83 138.1,134.83 137.72,135.21 136.4,135.21 136.02,135.59 136.02,136.48 136.32,136.78
V1_8D on L10_SIG4: 95.99,79.45 97.89,79.45 98.2,79.07 98.2,77.17 98.12,77.09 95.83,77.09 95.68,77.24 95.68,79.15
V1_8D on L10_SIG4: 92.71,98.68 93.73,98.68 94.23,98.17 94.23,97.54 93.73,97.03 92.71,97.03 92.33,97.41 92.33,98.3
V1_8D_OUT on TOP: 178.77,7.35 179.84,7.35 180.07,7.12 180.07,5.22 179.56,4.71 179.56,2.55 179.05,2.04 177.53,2.04 177.22,2.35 177.22,4.43 177.43,4.64 177.81,4.64 178.54,5.37 178.54,7.12
V1_8FTDI on L8_GND3: 156.97,89.24 169.42,89.24 173.1,85.55 173.1,75.77 170.05,72.73 159.51,72.73 155.32,76.92 155.32,87.58
V1_8PHY_HDMI on BOTTOM: 82.3,75.82 81.91,75.44 81.03,75.44 80.83,75.63 80.83,77.15 81.46,77.77 81.46,79.81 81.79,80.14 82.68,80.14 82.93,79.88 82.93,78.11 82.3,77.47
V1_8PHY_HDMI on L9_SIG3: 97.66,78.99 97.66,81.28 97.28,81.66 93.6,81.66 91.69,79.76 84.58,79.76 83.82,80.52 80.9,80.52 80.64,80.26 80.64,76.07 86.87,76.07 89.64,78.84 96.52,78.84 96.67,78.69 97.36,78.69
V1_8PHY_HDMI on L10_SIG4: 81.28,80.14 82.68,80.14 82.93,79.88 82.93,78.23 82.42,77.72 81.15,77.72 80.9,77.98 80.9,79.76
V1_8PHY_LDO3 on BOTTOM: 85.04,86.57 87.12,86.57 87.38,86.31 87.38,84.84 87.07,84.53 87.07,82.63 87,82.55 86.36,82.55 86.11,82.8 86.11,84.33 85.85,84.58 85.09,84.58 84.58,85.09 84.58,86.11
V1_8PHY_LDO3 on L8_GND3: 112.39,106.51 111.38,105.49 111.38,93.81 107.57,90 99.19,90 97.79,88.6 97.79,86.44 98.3,85.93 98.3,83.9 97.16,82.76 89.41,82.76 88.69,82.04 81.28,82.04 80.9,82.42 80.9,84.45 81.28,84.84 89.03,84.84 90.93,86.74 90.93,98.17 103.5,110.74 130.18,110.74 144.48,125.05 152.15,125.05 153.16,124.03 153.16,108.67 151,106.51
V1_8PHY_LDO3 on L10_SIG4: 84.2,82.93 84.2,85.6 84.71,86.11 85.78,86.11 87.25,84.64 87.25,82.93 86.49,82.17 84.96,82.17
V1_8PHY_LDO4 on BOTTOM: 86.23,75.06 84.1,72.92 79.1,72.92 78.36,73.66 78.36,76.58 78.49,76.71 79.32,76.71 79.5,76.53 79.5,74.37 79.88,73.99 81.74,73.99 83.44,75.69 83.44,79.38 84.33,80.26 87.12,80.26 87.25,80.14 87.25,79.18 87.13,79.06 86.3,79.06 86.23,78.99
V1_8PHY_LDO4 on BOTTOM: 145.54,127.13 147.45,127.13 147.7,126.87 147.7,126.36 147.45,126.11 145.29,126.11 145.16,126.24 145.16,126.75
V1_8PHY_LDO4 on L6_PWR1: 82.07,80.64 82.07,86.26 82.55,86.74 88.01,86.74 88.52,86.23 88.52,85.6 87.76,84.84 87.76,80.64 84.33,77.22 78.49,77.22 78.23,77.47 78.23,78.99 78.87,79.63 81.05,79.63
V1_8PHY_LDO4 on L8_GND3: 88.6,85.34 90.35,87.1 90.35,98.48 103.28,111.4 129.95,111.4 144.02,125.48 145.8,125.48 146.18,125.86 146.18,127.89 145.29,128.78 144.02,128.78 129.67,114.43 101.57,114.43 86.61,99.47 86.61,85.85 87.12,85.34
V1_8PHY_LDO4 on L10_SIG4: 78.61,73.79 79.38,73.79 79.63,74.04 79.63,78.99 79.5,79.12 78.49,79.12 78.36,78.99 78.36,74.04
V1_8PHY_LDO4 on L10_SIG4: 88.52,85.09 88.52,86.33 87.5,86.33 87.07,85.9 87.07,85.5 87.48,85.09
V1_8PHY_LDO4 on L10_SIG4: 147.52,126.7 147.7,126.87 147.7,127.38 147.32,127.76 144.78,127.76 144.53,127.51 144.53,126.87 144.7,126.7
V1_8PHY_PCIE on BOTTOM: 95.76,79.88 95.15,80.49 93.19,80.49 92.27,79.57 91.13,79.57 90.42,78.87 88.65,78.87 88.52,78.99 88.52,80.01 89.53,81.03 91.19,81.03 91.44,81.28 91.44,81.79 91.69,82.04 92.08,82.04 92.96,81.15 93.98,81.15 94.28,81.46 94.28,81.97 94.49,82.17 97.41,82.17 97.79,82.55 97.79,81.41 96.27,79.88
V1_8PHY_SATA on BOTTOM: 84.45,80.9 82.19,80.9 82.09,81 82.09,83.33 82.45,83.69 84.71,83.69 84.84,83.57 84.84,81.28
V1_8PHY_SATA on L4_SIG2: 95.12,81.53 97.16,81.53 97.79,82.17 97.79,83.82 98.04,84.07 99.31,84.07 99.69,83.69 99.69,81.91 98.17,80.39 98.17,79.76 97.92,79.5 95,79.5 94.49,80.01 94.49,80.9
V1_8PHY_USB on BOTTOM: 88.9,86.61 89.41,86.61 90.04,85.98 90.8,85.98 91.06,85.72 91.06,85.34 90.42,84.71 89.03,84.71 88.65,85.09 88.65,86.36
V1_8PHY_USB on L10_SIG4: 95.12,84.84 97.89,84.84 98.17,84.56 98.17,83.9 97.74,83.46 97.18,83.46 96.39,82.68 92.71,82.68 90.68,84.71 89.15,84.71 88.9,84.96 88.9,85.72 89.15,85.98 91.69,85.98 92.33,86.61 93.34,86.61
V1_8PLL on BOTTOM: 111,82.15 114.91,82.15 117.22,84.45 122.35,84.45 123.44,85.55 123.44,107.27 123.95,107.78 126.62,107.78 127.13,107.27 127.13,102.82 128.02,101.94 128.02,84.66 126.11,82.76 118.62,82.76 116.66,80.8 110.16,80.8 109.47,81.49 109.47,82.25 109.6,82.38 110.77,82.38
V1_8PLL on L4_SIG2: 100.58,82.33 110.95,82.33 110.97,82.35 115.7,82.35 115.9,82.15 115.9,81.13 114.71,79.94 112.39,79.94 111.99,80.35 110.24,80.35 108.28,78.39 104.06,78.39 102.41,76.74 102.41,76.69 93.83,76.69 91.87,78.64 91.87,79.25 92.96,80.34 93.68,80.34 94.72,79.3 98.04,79.3 98.4,79.65 98.4,80.14
V1_8PLL on L6_PWR1: 137.92,132.54 137.92,131.4 136.27,129.75 134.62,129.75 131.7,126.83 131.7,115.02 125.6,108.92 125.6,105.75 124.84,104.98 123.19,104.98 122.3,105.87 122.3,109.81 128.4,115.91 128.4,127.59 133.6,132.8 137.67,132.8
V1_8PLL on L10_SIG4: 112.57,82.2 115.62,82.2 116.08,81.74 116.08,80.85 115.85,80.62 112.7,80.62 112.42,80.9 112.42,82.05
V1_8PLLA on BOTTOM: 112.07,84.51 113.39,84.51 113.61,84.28 113.61,83.47 113.31,83.16 112.24,83.16 111.96,83.44 111.96,84.4
V1_8PLLA on L3_SIG1: 100.82,82.98 101.4,82.98 102.01,82.37 104.21,82.37 104.43,82.6 104.9,82.6 105.28,82.22 110.11,82.22 110.4,81.93 110.4,81.3 110.24,81.13 104.48,81.13 104.48,79.64 104.36,79.52 103.73,79.52 103.23,80.02 103.09,80.02 101.81,78.74 101.06,78.74 100.84,78.96 100.84,79.12 101.09,79.38 101.5,79.38 101.83,79.71 101.83,80.79 100.68,81.95 100.68,82.84
V1_8PLLA on L10_SIG4: 106.43,82.25 107.44,82.25 108.33,83.14 111.68,83.14 111.81,83.27 111.81,84.18 111.99,84.36 113.45,84.36 113.65,84.16 113.65,82.87 113.18,82.4 112.5,82.4 112.17,82.07 112.17,81.39 111.98,81.2 106.33,81.2 106.17,81.36 106.17,82
V1_8PLLB on BOTTOM: 101.17,81.03 102.59,81.03 102.84,81.28 102.84,82.45 103.43,83.03 103.43,84.71 103.73,85.01 103.94,85.01 104.11,84.84 104.11,83.16 104.9,82.38 108.08,82.38 108.2,82.25 108.2,81.49 108.08,81.36 104.39,81.36 104.22,81.18 103.81,81.18 103.33,80.7 103.33,80.07 103.12,79.86 102.95,79.86 102.49,80.32 101.32,80.32 101.04,80.59 101.04,80.9
V3_3ACDCM on BOTTOM: 27.81,39.71 32.64,39.71 33.02,39.32 33.02,38.44 33.27,38.18 34.04,38.18 34.16,38.31 34.16,40.85 33.91,41.1 30.48,41.1 29.97,40.59 27.81,40.59 27.69,40.47 27.69,39.83
V3_3ACDCM on L9_SIG3: 29.46,41.48 33.53,41.48 34.16,40.85 34.16,36.66 33.4,35.9 28.83,35.9 28.07,36.66 28.07,40.09
V3_3APCIE on BOTTOM: 22.68,31.14 26.57,31.14 27.13,31.7 27.85,31.7 27.98,31.83 27.98,33.74 22.73,33.74 22.48,33.48 22.48,31.34
V3_3APCIE on L9_SIG3: 17.27,39.96 23.37,39.96 27.94,35.39 35.43,35.39 36.32,34.5 36.32,30.56 35.18,29.42 23.62,29.42 16.64,36.4 16.64,39.32
V3_3AUX_PCIE on BOTTOM: 54.84,22.66 50.25,27.25 50.25,42.67 51.81,44.23 54.66,44.23 56.26,42.62 56.26,33.62 54.85,33.16 56.26,32.7 56.26,31.12 54.87,30.51 56.39,30.48 58.17,28.7 58.17,23.95 56.87,22.66
V3_3D on TOP: 172.97,72.47 171.83,73.61 171.83,74 172.09,74.25 173.23,74.25 173.48,74 173.48,71.96 173.1,71.96 172.97,72.09
V3_3D on TOP: 31.94,79.58 32.13,79.39 32.13,78.76 32.26,78.63 32.7,78.63 32.89,78.44 32.89,77.3 32.77,77.17 32.38,77.17 32.13,77.42 32.13,77.68 31.5,77.68 31.37,77.81 31.37,78.5 31.5,78.63 31.5,79.46 31.62,79.58
V3_3D on TOP: 131.27,8.84 131.27,13.11 132.59,14.43 136.02,14.43 136.65,13.8 136.65,10.03 135.26,8.64 132.97,8.64 131.7,7.37 129.03,7.37 128.91,7.49 128.91,8 129.16,8.25 130.68,8.25
V3_3D on TOP: 161.29,19.51 162.69,19.51 163.07,19.13 163.07,17.35 163.58,16.85 164.47,16.85 164.72,16.59 164.72,15.19 164.34,14.81 161.29,14.81 161.03,15.07 161.03,19.25
V3_3D on TOP: 31.88,54.75 32.13,54.5 32.13,53.87 32.26,53.74 33.21,53.74 33.4,53.55 33.4,53.04 33.21,52.85 31.5,52.85 31.37,52.98 31.37,53.61 31.5,53.74 31.5,54.63 31.62,54.75
V3_3D on TOP: 99.06,130.51 99.57,130.51 100.2,131.15 100.58,131.15 100.84,130.89 100.84,127.46 100.58,127.21 99.06,127.21 98.81,127.46 98.81,130.26
V3_3D on TOP: 108.84,12.19 109.6,12.95 111.68,12.95 114.17,15.45 115.54,15.45 116.03,14.97 116.03,13.47 112.8,10.24 106.05,10.24 105.28,11 105.28,11.77 105.54,12.02 105.92,12.02 106.17,11.77 106.17,11.26 106.55,10.88 108.46,10.88 108.84,11.26
V3_3D on TOP: 73.28,112.35 73.53,112.6 76.07,112.6 76.33,112.35 76.33,110.57 76.07,110.32 73.53,110.32 73.28,110.57
V3_3D on TOP: 175.14,8.39 175.37,8.62 175.9,8.62 176.13,8.39 176.13,5.2 176.84,4.49 176.84,2.38 176.51,2.04 174.99,2.04 174.53,2.5 174.53,7.3 175.14,7.91
V3_3D on TOP: 25.35,125.56 25.68,125.23 25.68,124.34 25.48,124.13 22.66,124.13 22.56,124.03 20.14,124.03 19.89,124.29 19.89,124.82 20.62,125.56
V3_3D on TOP: 31.88,97.36 32.13,97.11 32.13,96.47 32.26,96.35 33.53,96.35 33.66,96.22 33.66,95.46 31.5,95.46 31.37,95.59 31.37,96.22 31.5,96.35 31.5,97.24 31.62,97.36
V3_3D on BOTTOM: 167.13,43.39 167.13,45.8 167.39,46.06 168.02,46.06 168.34,45.74 168.34,44.98 168.53,44.79 168.53,43.52 168.28,43.26 167.26,43.26
V3_3D on BOTTOM: 160.99,56.6 160.99,56.27 161.67,55.58 161.67,53.75 162.13,53.29 163.7,53.29 164.02,53.61 164.02,56.6
V3_3D on BOTTOM: 34.04,96.9 37.34,96.9 38.23,97.79 38.23,98.42 37.97,98.68 34.04,98.68 33.91,98.55 33.91,97.03
V3_3D on BOTTOM: 22.61,27.89 22.61,30.43 22.86,30.69 24.38,30.69 24.51,30.56 24.51,27.89 24.13,27.51 22.99,27.51
V3_3D on BOTTOM: 171.55,64.09 173.46,64.09 173.84,64.47 173.84,64.94 173.46,65.32 171.9,65.32 171.55,64.98
V3_3D on BOTTOM: 38.51,101.43 40.51,101.43 40.82,101.12 40.82,99.27 40.69,99.14 37.41,99.14 37.31,99.24 37.31,99.67 37.54,99.9 38.07,99.9 38.3,100.13 38.3,101.12 38.25,101.17
V3_3D on BOTTOM: 54.92,98.38 54.92,95.84 54.67,95.59 53.4,95.59 52.76,96.23 52.76,97.77 53.49,98.51 54.8,98.51
V3_3D on BOTTOM: 28.83,115.27 29.72,115.27 29.97,115.02 29.97,112.5 29.67,112.2 28.78,112.2 28.4,112.58 28.4,113.7 28.7,114 28.7,115.14
V3_3D on BOTTOM: 93.73,125.94 93.6,126.07 93.6,126.88 93.22,127.26 93.22,127.54 94.41,128.73 95,128.73 95.01,128.72 97.2,128.72 97.21,128.73 98.4,128.73 99.11,129.44 99.11,130.41 99.24,130.54 99.62,130.54 99.75,130.41 99.75,129.39 98.45,128.09 95.28,128.09 95.15,127.97 95.15,127.69 94.16,126.7 94.16,126.07 94.03,125.94
V3_3D on BOTTOM: 118.87,87.12 120.4,87.12 120.52,87 120.52,84.96 120.4,84.84 118.87,84.84 118.49,85.22 118.49,86.74
V3_3D on BOTTOM: 160.15,37.8 164.04,37.8 164.08,37.76 164.08,35.77 163.96,35.64 160.15,35.64 159.77,36.02 159.77,37.42
V3_3D on BOTTOM: 84.71,94.95 86.23,94.95 86.61,94.57 86.61,92.92 86.36,92.66 84.71,92.66 84.45,92.92 84.45,94.7
V3_3D on BOTTOM: 28.02,43.9 28.02,42.17 28.27,41.91 29.13,41.91 29.39,42.17 29.39,43.9 29.21,44.07 28.19,44.07
V3_3D on BOTTOM: 110.93,80.47 111.85,80.47 112.09,80.24 112.09,78.69 111.91,78.52 111.25,78.52 110.72,79.04 110.72,80.26
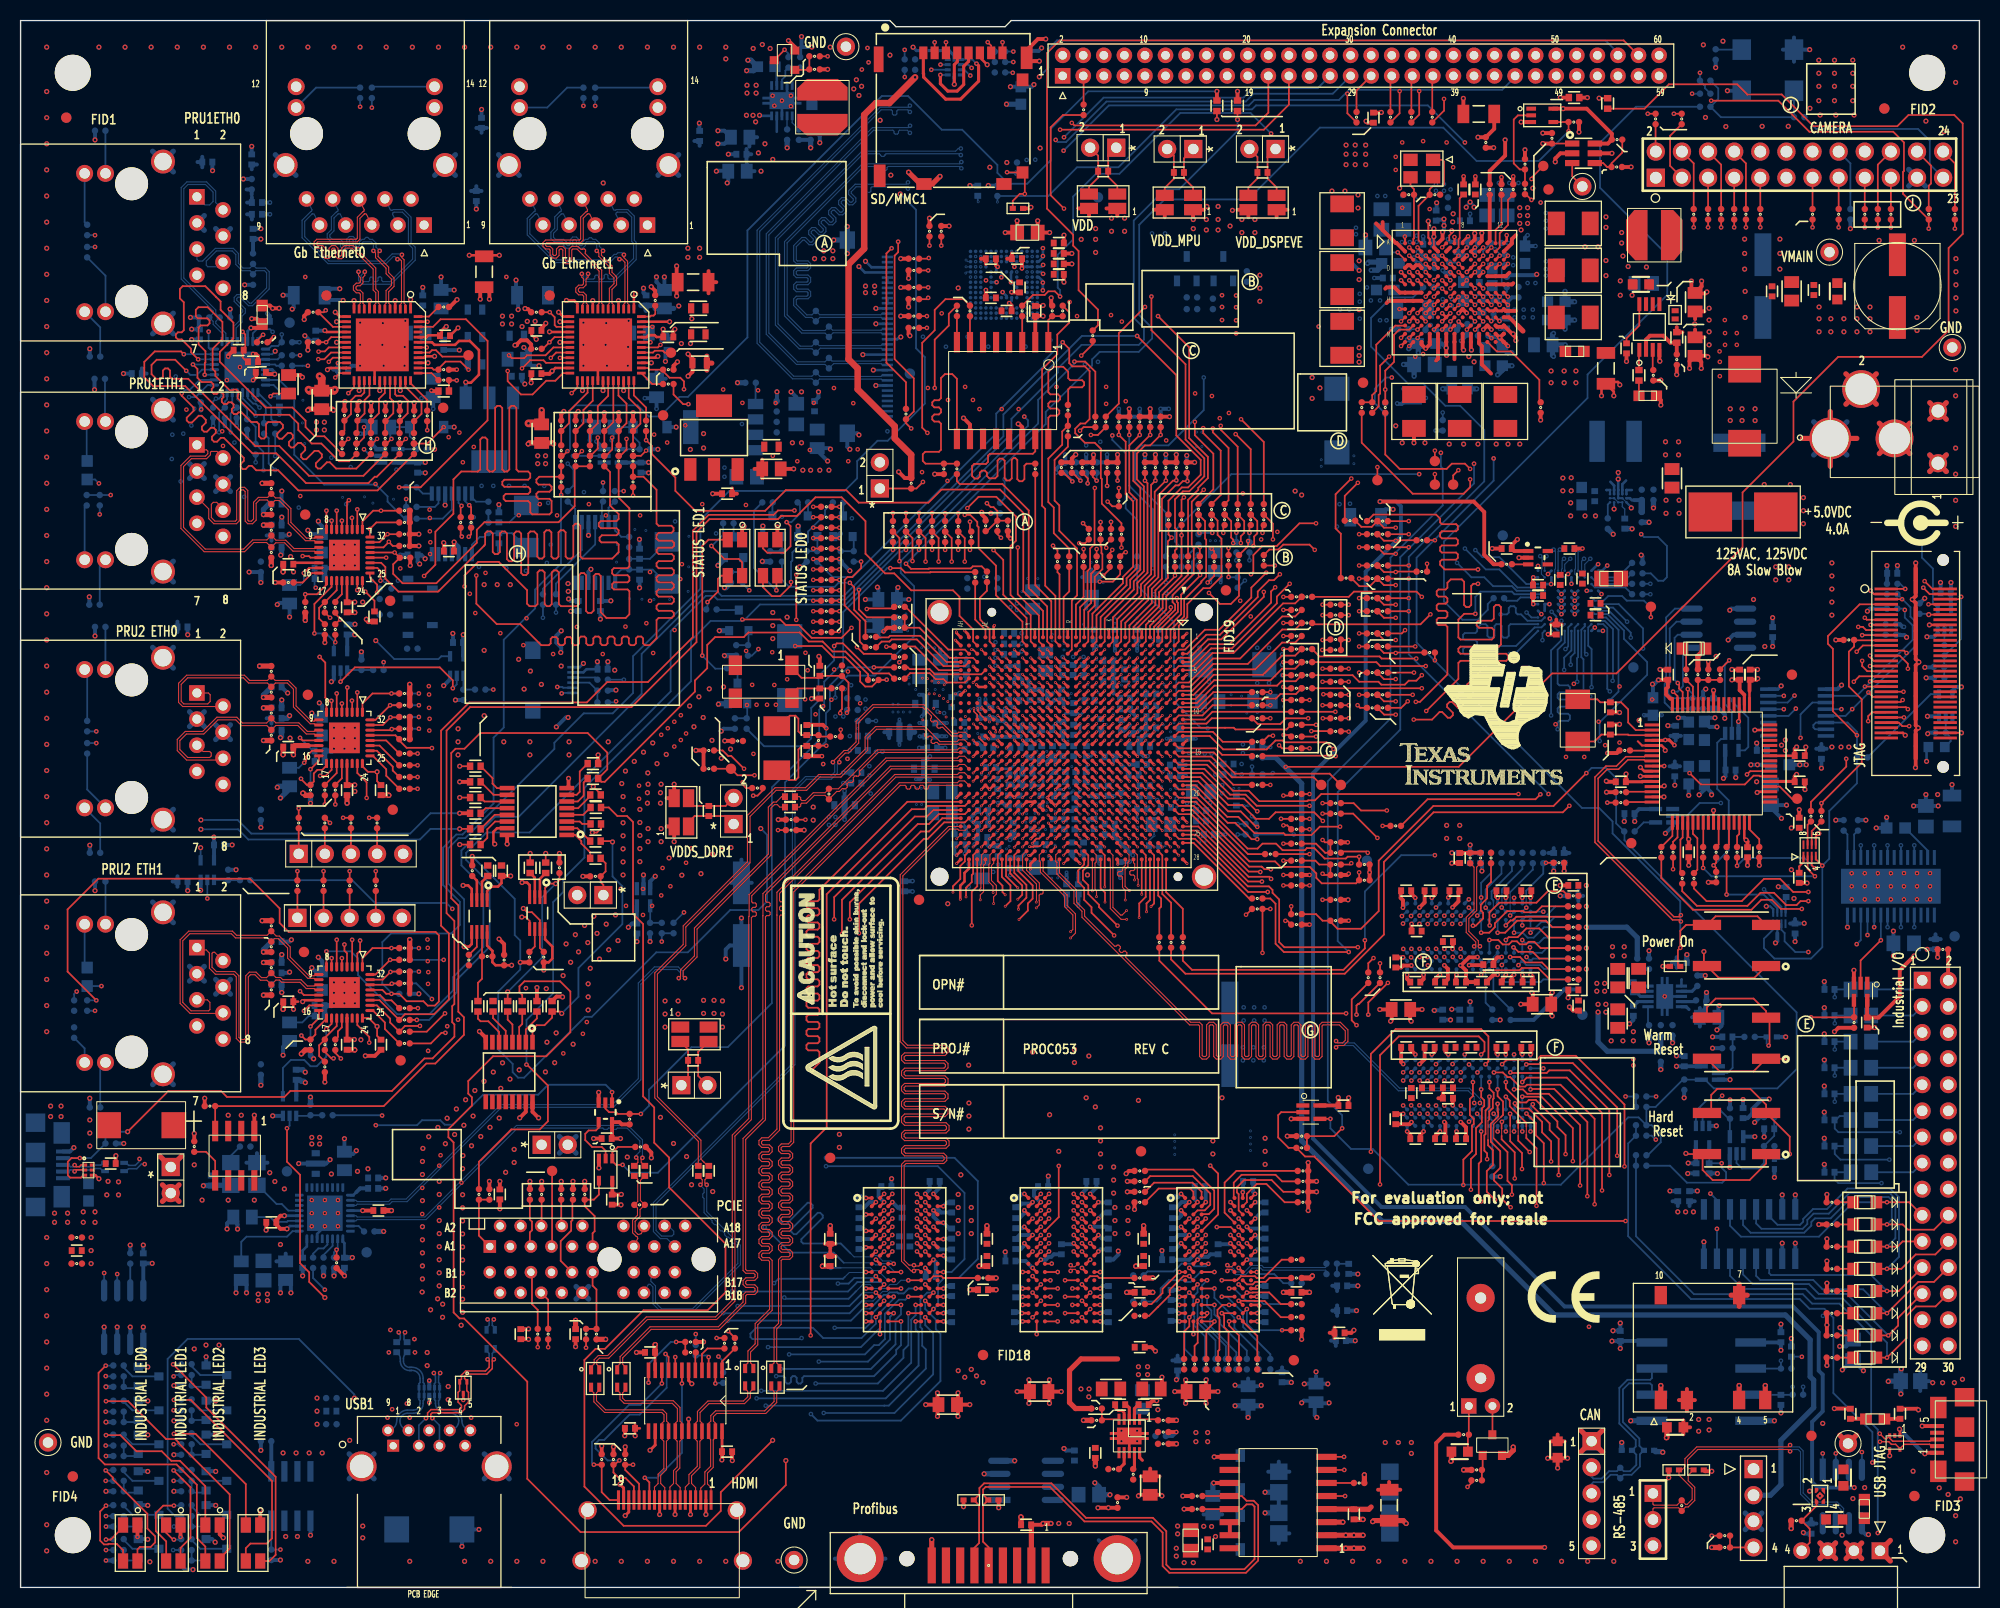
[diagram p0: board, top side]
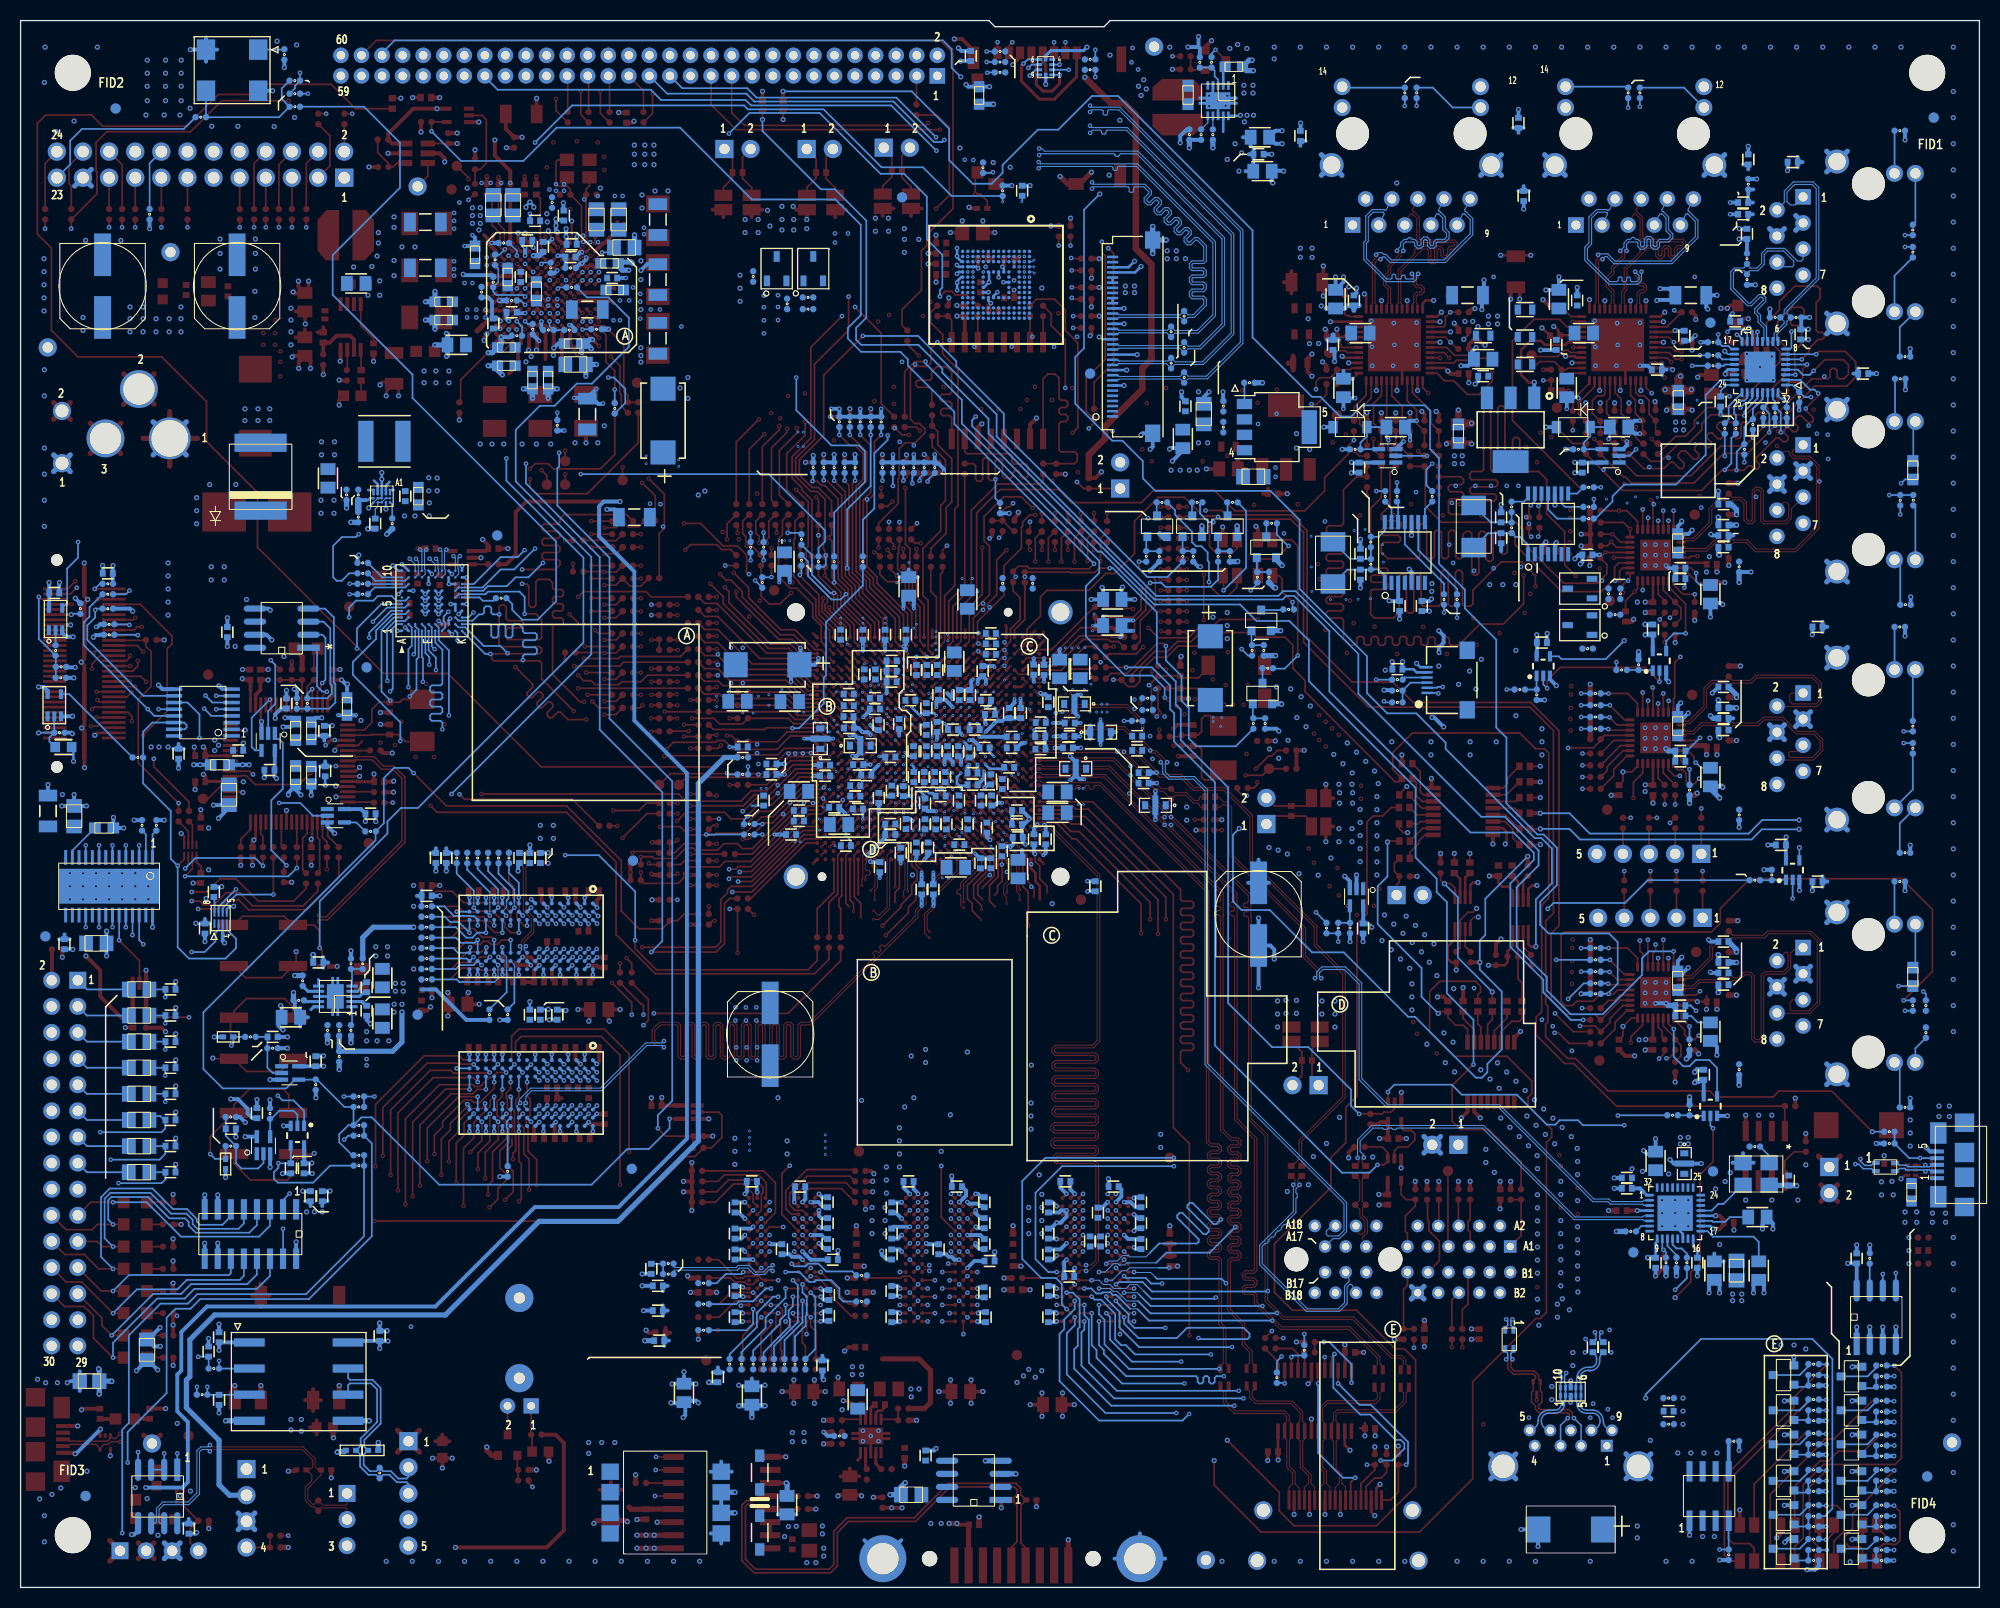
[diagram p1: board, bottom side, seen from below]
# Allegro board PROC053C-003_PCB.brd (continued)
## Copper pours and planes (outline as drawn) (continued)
V3_3D on BOTTOM: 141.1,129.11 143.74,129.11 144.91,127.94 144.91,127.53 144.7,127.32 144.03,127.32 143.64,127.72 141.35,127.72 140.97,127.34 140.97,126.45 140.87,126.35 139.8,126.35 139.7,126.45 139.7,127.72
V3_3D on BOTTOM: 48.51,121.49 48.51,123.4 48.77,123.65 50.16,123.65 50.42,123.4 50.42,121.37 50.04,120.99 49.02,120.99
V3_3D on BOTTOM: 106.98,88.54 108.81,88.54 108.89,88.47 108.89,87.81 109.22,87.48 109.66,87.48 109.78,87.36 109.78,85.45 109.63,85.3 108.56,85.3 108.33,85.53 108.33,86.84 107.04,86.84 106.81,87.07 106.81,88.37
V3_3D on BOTTOM: 174.68,83.06 177.88,83.06 178.1,82.83 178.1,81.41 177.93,81.23 174.88,81.23 174.55,81.56 174.55,82.94
V3_3D on BOTTOM: 50.16,111.84 51.18,111.84 51.56,111.46 51.56,109.43 51.05,108.92 50.16,108.92 49.78,109.3 49.78,111.46
V3_3D on BOTTOM: 162.79,17.07 164.47,17.07 165.96,15.58 165.96,8.89 166.94,7.92 173.63,7.92 174.01,7.54 175.49,7.54 175.87,7.16 175.87,5.48 177.04,4.31 177.04,2.53 175.84,1.33 163.02,1.33 161.95,2.39 161.95,16.24
V3_3D on BOTTOM: 132.23,10.16 134.24,10.16 134.62,10.54 134.62,12.32 133.99,12.95 132.72,12.95 132.33,13.34 132.33,14.18 132.59,14.43 135.26,14.43 135.89,13.8 135.89,6.73 135.64,6.48 132.08,6.48 131.43,7.12 131.43,9.37
V3_3D on L4_SIG2: 176.53,101.17 187.45,101.17 189.21,99.42 189.21,80.58 187.07,78.44 180.09,78.44 178.94,79.58 178.94,88.73 175.51,92.16 175.51,100.16
V3_3D on L5_GND2: 103.76,87.71 103.76,85.81 103.5,85.55 101.09,85.55 100.71,85.93 100.71,88.85 100.2,89.36 97.66,89.36 97.41,89.62 97.41,90.76 97.66,91.01 100.46,91.01
V3_3D on L7_PWR2: 2.11,1.91 1.91,2.11 1.91,150.32 2.08,150.5 83.75,150.5 84.35,149.9 96.53,149.9 97.13,150.5 187.96,150.5 188.59,149.86 188.59,139.99 188.39,139.78 181.23,139.78 180.21,138.77 180.21,138.26 180.28,138.19 180.28,129.05 176.53,125.3 176.53,100.86 177.24,100.16 177.24,91.35 176.53,90.65 176.53,83.65 178.18,82 178.18,81.11 176.53,79.46 176.53,56.09 177.31,55.32 177.31,52.82 176.53,52.05 176.53,25.41 176.51,25.27 176.53,25.14 176.53,17.1 172.59,13.16 160.66,13.16 160.02,13.8 71.12,13.8 69.09,11.77 67.44,11.77 65.41,13.8 58.67,13.8 50.29,22.18 50.29,35.64 47.62,38.31 40.39,38.31 36.8,34.73 36.8,1.91 ; 29 cut-outs
V3_3D on L10_SIG4: 118.62,86.82 118.62,84.92 118.87,84.66 120.78,84.66 121.16,85.04 121.16,86.31 120.52,86.95 118.75,86.95
V3_3D on L10_SIG4: 109.25,80.82 107.87,80.82 107.57,80.52 107.57,77.47 107.95,77.09 109.02,77.09 109.55,77.62 109.55,80.52
V3_3D on L10_SIG4: 36.96,98.3 37.59,97.66 37.59,97.03 37.08,96.52 34.29,96.52 33.66,97.16 33.66,97.79 34.16,98.3
V3_3D on L10_SIG4: 87.8,94.31 87.8,94.93 87.42,95.31 86.15,95.31 84.45,93.61 84.45,91.87 84.78,91.53 87.08,91.53 88.16,92.61 88.16,93.97 87.81,94.31
V3_3D_PROFIA on BOTTOM: 134.69,6.15 135.51,5.33 135.51,3.56 134.62,2.67 128.27,2.67 128.14,2.79 128.14,3.94 128.52,4.32 131.83,4.32 132.07,4.56 132.07,5.91 132.31,6.15
V3_3D_PROFIB on BOTTOM: 134.11,10.54 133.99,10.41 132.12,10.41 130.91,9.2 130.91,4.92 130.68,4.7 128.91,4.7 127.99,5.62 127.99,10.09 130.47,12.57 133.86,12.57 134.11,12.32
V3_3D_PRU1ETH0JCK on BOTTOM: 16.92,133.99 17.98,133.99 19.08,132.9 20.55,132.9 21.64,133.99 21.64,136.12 21.89,136.38 22.71,136.38 22.86,136.23 22.86,133.17 22.39,132.7 22.18,132.7 21.81,132.33 21.81,131.74 20.88,130.81 18.16,130.81 16.46,132.52 16.46,133.53
V3_3D_PRU1ETH1JCK on BOTTOM: 16.59,111.41 21.94,111.41 22.83,110.52 22.83,103.39 23.38,102.84 24.62,102.84 24.82,102.64 24.82,100.24 24.06,99.47 17.1,99.47 15.96,100.62 15.96,110.78
V3_3D_PRU2ETH0JCK on BOTTOM: 23.68,86.16 24.72,85.12 24.72,76.23 23.83,75.35 17.1,75.35 15.96,76.49 15.96,85.35 16.41,85.81 18.06,85.81 18.41,86.16
V3_3D_PRU2ETH1JCK on BOTTOM: 23.94,61.14 24.72,60.36 24.72,51.47 23.83,50.58 17.1,50.58 15.96,51.72 15.96,60.86 16.05,60.86 16.33,61.14
V3_3FTDI on TOP: 173.48,71.56 173.08,71.56 172.97,71.46 172.97,71.07 171.83,69.93 171.83,69.42 172.09,69.17 173.25,69.17 173.48,69.4
V3_3FTDI on BOTTOM: 169.25,94.19 166.58,94.19 166.32,93.93 166.32,91.14 166.71,90.76 170.64,90.76 171.02,91.14 171.02,92.54 170.9,92.66 170.01,92.66 169.5,93.17 169.5,93.93
V3_3FTDI on BOTTOM: 171.83,65.99 171.83,65.23 171.53,65.23 171.53,66.43 171.2,66.76 171.2,67.39 171.32,67.52 172.57,67.52 172.85,67.24 172.85,67.01
V3_3FTDI on BOTTOM: 167.44,80.52 170.74,80.52 170.99,80.27 170.99,77.47 167.69,77.47 167.31,77.86 167.31,80.4
V3_3FTDI on BOTTOM: 169.11,84.3 171.66,84.3 172.01,83.95 172.01,81.41 171.7,81.11 169.67,81.11 169.55,81.23 169.55,82.1 168.96,82.68 168.96,84.15
V3_3FTDI on L6_PWR1: 162.81,88.09 166.62,91.9 170.69,91.9 173.36,89.24 173.36,66.88 172.85,66.38 169.29,66.38 164.21,71.46 156.46,71.46 153.29,74.63 153.29,77.42 153.23,77.49 153.23,87.39 153.92,88.09
V3_3USB on L6_PWR1: 82.6,94.99 81.41,93.8 81.41,85.3 82.03,84.68 82.03,86.87 82.23,87.08 87.64,87.08 88.08,86.64 88.08,84.28 94.23,84.28 94.72,83.8 100.74,83.8 100.97,84.03 100.97,87.58 100.67,87.88 100.67,88.52 94.19,94.99
V3_3USB on L8_GND3: 143.38,129.03 143.38,129.88 142.18,131.08 138.49,131.08 130.44,123.02 97.8,123.02 77.6,102.82 77.6,85.47 85.09,85.47 85.98,86.36 85.98,99.65 101.39,115.06 129.41,115.06
V3_7LCD on BOTTOM: 70.61,112.6 70.74,112.73 74.3,112.73 74.3,113.49 74.68,113.87 76.64,113.87 76.64,114.32 77.09,114.76 77.72,114.76 79.12,116.16 84.84,116.16 84.96,116.03 84.96,114.76 84.84,114.64 80.9,114.64 78.11,111.84 74.81,111.84 74.17,111.21 72.9,111.21 72.52,111.59 70.74,111.59 70.61,111.71
V5_0D on TOP: 159.59,104.06 159.59,107.37 159.84,107.62 161.37,107.62 161.62,107.37 161.62,104.06 161.37,103.81 159.84,103.81
V5_0D on TOP: 20.19,46.31 21.46,46.31 21.84,45.93 21.84,43.39 21.59,43.13 20.07,43.13 19.81,43.39 19.81,45.93
V5_0D on BOTTOM: 156.51,106.66 156.51,107.3 156.87,107.65 161.29,107.65 163.2,105.75 163.2,102.73 165.6,100.32 171.54,100.32 172.47,99.4 172.47,96.35 172.09,95.97 164.3,95.97 160.66,99.61 160.66,101.41 159.64,102.43 159.64,105.87 159.1,106.41 156.77,106.41
V5_0D on BOTTOM: 25.27,7.49 25.27,4.83 25.53,4.57 27.05,4.57 27.3,4.83 27.3,7.49 27.18,7.62 25.4,7.62
V5_0D on L6_PWR1: 188.59,2.11 188.39,1.91 2.55,1.91 1.91,2.55 1.91,45.93 2.29,46.31 47.75,46.31 48.89,45.17 48.89,25.99 50.8,24.08 65.02,24.08 71.25,17.86 75.18,17.86 75.25,17.92 81.98,17.92 84.2,15.7 98.17,15.7 100.58,18.12 111.63,18.12 112.78,16.97 113.92,16.97 115.06,18.12 164.85,18.12 169.04,22.31 169.04,65.74 173.1,65.74 173.99,66.62 173.99,89.48 170.94,92.53 169.74,92.53 169.74,150.5 188.31,150.5 188.59,150.21
V5_0D on L9_SIG3: 101.47,144.23 99.95,145.74 99.95,150.68 100.38,151.11 188.16,151.11 189.2,150.07 189.2,135.08 188.7,134.57 171.07,134.57 169.85,135.79 169.85,137.7 163.32,144.23 ; 28 cut-outs
V5_0HDMICONN on TOP: 59.57,16.4 61.01,16.4 61.25,16.16 61.25,14.43 61.17,14.35 59.68,14.35 59.44,14.6 59.44,16.28
V5_0HDMICONN on BOTTOM: 57.99,9.49 59.53,9.49 60.02,9.98 60.02,10.67 60.73,11.38 61.42,11.38 61.81,11.77 61.81,15.33 61.11,16.03 60.02,16.03 59.41,15.42 59.41,14.95 59.41,14.94 59.41,12.86 57.76,11.2 57.76,9.72
V5_0VOP on BOTTOM: 185.97,66.5 186.35,66.5 186.48,66.38 186.48,64.93 186.98,64.43 186.98,62.79 186.88,62.69 185.29,62.69 184.91,62.31 184.91,61.42 184.53,61.04 183.77,61.04 183.39,61.42 183.39,63.45 183.64,63.71 185.04,63.71 185.85,64.52 185.85,66.38
V12_0D on TOP: 160.81,121.71 161.58,121.71 161.96,121.32 161.96,120.95 162.15,120.76 163.54,120.76 163.82,120.48 164.21,120.48 164.75,121.02 164.75,124.51 164.47,124.8 162.13,124.8 161.93,124.59 161.93,123.91 161.67,123.65 160.56,123.65 160.56,121.96
V12_0D on L7_PWR2: 37.46,34.5 40.64,37.67 47.37,37.67 49.66,35.39 49.66,22.05 58.68,13.04 173.74,13.04 177.17,16.46 177.17,51.83 177.94,52.6 177.94,55.55 177.17,56.32 177.17,90.33 177.89,91.06 177.89,100.29 177.17,101.02 177.17,123.4 177.04,123.53 177.04,124.41 180.85,128.22 180.85,135.84 180.91,135.91 180.91,138.45 181.61,139.15 188.34,139.15 188.59,138.89 188.59,2.37 188.13,1.91 37.93,1.91 37.46,2.37
V12_0D on L9_SIG3: 162.43,126.07 162.43,122 164.08,120.35 186.69,120.35 189.23,122.89 189.23,129.49 187.71,131.02 167.39,131.02
VDD_CORE on TOP: 133.62,135.38 133.18,135.83 133.18,136.85 132.46,137.57 132.46,140.42 131.95,140.92 128.65,140.92 128.4,140.67 128.4,136.99 128.78,136.61 130.05,136.61 131.32,135.34 131.32,132.03 133.48,129.87 134.11,129.88 134.49,130.26 134.49,130.36 134.03,130.83 133.62,131.38
VDD_CORE on TOP: 101.73,80.6 101.98,80.6 102.33,80.25 102.33,78.16 101.6,77.42 101.35,77.42 101.22,77.55 101.22,77.68 101.47,77.93 101.47,79.71 101.22,79.96 101.22,80.09
VDD_CORE on TOP: 103.02,134.73 104.75,134.73 104.9,134.57 104.9,129.7 104.67,129.47 104.04,129.47 102.74,130.76 102.74,134.45
VDD_CORE on BOTTOM: 98.91,80.98 100.68,80.98 100.86,80.8 100.86,79.93 100.66,79.73 98.98,79.73 98.78,79.93 98.78,80.86
VDD_CORE on BOTTOM: 109.19,85.06 109.78,85.06 109.8,85.03 109.8,83.31 109.76,83.26 109.01,83.26 108.72,82.98 108.27,82.98 107.92,82.63 107.54,82.63 107.54,82.98 107.99,83.43 108.54,83.43 109.15,84.04 109.15,85.02
VDD_CORE on BOTTOM: 72.52,94.7 73.02,95.2 76.07,95.2 77.04,94.24 77.04,91.6 76.45,91.01 73.28,91.01 72.51,91.78
VDD_CORE on BOTTOM: 112.39,78.36 114.43,78.36 114.55,78.23 114.55,74.3 114.3,74.04 113.66,74.04 113.44,74.27 113.44,75.06 113.03,75.46 113.03,76.28 112.83,76.48 112.3,76.48 112.01,76.76 112.01,77.98
VDD_CORE on BOTTOM: 101.6,85.39 102.77,85.39 103.17,85.8 103.89,85.8 103.99,85.7 103.99,85.5 103.17,84.68 103.17,83.36 102.97,83.36 102.74,83.59 102.13,83.59 101.88,83.85 101.88,84.45 101.7,84.63 101.4,84.63 101.27,84.76 101.27,85.06
VDD_CORE on BOTTOM: 79.76,85.72 80.52,85.72 80.77,85.47 80.77,84.84 80.19,84.25 79.17,84.25 78.99,84.43 78.99,84.96
VDD_CORE on BOTTOM: 99.44,86.74 100.46,86.74 100.58,86.87 100.58,89.79 100.46,89.92 98.81,89.92 98.68,89.79 98.68,87.5
VDD_CORE on L3_SIG1: 100.97,85.47 103.17,85.47 103.56,85.85 104.11,85.85 104.11,85.27 103.66,84.81 103.66,83.95 103.81,83.79 104.22,83.79 104.22,83.01 104.14,82.93 102.13,82.93 101.85,83.21 101.85,84.35 101.68,84.53 100.99,84.53 100.74,84.79 100.74,85.24
VDD_CORE on L3_SIG1: 98.45,87.78 99.62,87.78 100.08,87.33 100.08,86.41 99.82,86.16 99.26,86.16 98.37,87.05 98.37,87.71
VDD_CORE on L3_SIG1: 105.33,88.54 105.99,88.54 106.17,88.37 106.17,87.22 105.87,86.92 105.41,86.92 105.21,87.12 105.21,88.42
VDD_CORE on L3_SIG1: 98.6,80.16 101.51,80.16 101.59,80.08 101.59,79.94 101.12,79.48 98.5,79.48 98.35,79.63 98.35,79.91
VDD_CORE on L8_GND3: 97.92,123.27 76.96,102.32 76.96,86.49 78.49,84.96 79.88,84.96 80.39,84.45 80.39,82.17 80.89,81.67 88.82,81.67 88.82,81.71 89.48,82.38 97.16,82.38 98.55,83.77 98.55,85.93 98.17,86.31 98.17,88.35 99.44,89.62 106.43,89.62 106.81,89.24 106.81,87.97 105.79,86.95 105.16,86.95 104.39,86.19 104.39,83.27 104.9,82.76 107.57,82.76 108.08,83.27 108.08,83.65 109.22,84.79 113.33,84.79 113.92,84.2 113.92,77.09 113.74,76.91 105.28,76.91 103.25,74.88 100.2,74.88 93.73,68.41 74.68,68.41 61.47,81.62 61.47,112.1 96.39,147.02 134.62,147.02 136.27,145.37 136.27,142.7 129.03,135.46 112.39,135.46 110.87,133.94 110.87,124.16 109.98,123.27
VDD_CORE on L10_SIG4: 79.12,85.09 80.01,85.09 80.26,84.84 80.26,83.82 80.01,83.57 79.12,83.57 78.99,83.69 78.99,84.96
VDD_CORE on L10_SIG4: 111.89,78.06 113.54,78.06 114.55,77.04 114.55,76.1 114.15,75.69 112.98,75.69 111.63,77.04 111.63,77.81
VDD_DSPEVE on TOP: 118.03,134.7 120.17,134.7 120.42,134.45 120.42,131.7 120.14,131.42 118.08,131.42 117.3,132.21 117.3,133.96
VDD_DSPEVE on TOP: 104.29,85.83 106.32,85.83 106.53,85.62 106.53,84.15 107.24,83.44 107.14,83.44 107.34,83.24 107.34,82.98 106.88,82.52 106.17,82.52 106.17,83.72 105.97,83.92 104.9,83.92 104.37,83.39 104.01,83.39 104.01,85.55
VDD_DSPEVE on BOTTOM: 106.17,82.96 105.38,83.75 105.38,83.98 105.26,84.1 104.95,84.1 104.72,83.88 104.72,83.82 104.44,83.82 104.24,84.03 104.24,86.19 104.25,86.2 104.25,86.43 104.39,86.57 105.03,86.57 105.92,87.46 105.92,90.45 105.97,90.51 106.55,90.51 106.65,90.4 106.65,88.42 106.6,88.37 106.6,86.89 106.68,86.82 107.07,86.82 107.24,86.64 107.24,84.71 107.39,84.56 107.39,84.16 107.26,84.03 106.65,84.03 106.58,83.95 106.58,83.16 106.38,82.96
VDD_DSPEVE on BOTTOM: 126.19,108.69 125.93,108.95 125.93,111.38 126.36,111.82 129.64,111.82 129.92,111.54 129.92,109 129.62,108.69
VDD_DSPEVE on BOTTOM: 113.41,87.25 115.32,87.25 115.44,87.12 115.44,85.22 115.19,84.96 113.79,84.96 113.16,85.6 113.16,87
VDD_DSPEVE on L3_SIG1: 104.72,86.18 106.73,86.18 107.01,85.9 107.01,83.79 107.06,83.74 107.67,83.74 107.77,83.64 107.77,83.29 107.34,82.85 104.8,82.85 104.5,83.16 104.5,85.95
VDD_DSPEVE on L4_SIG2: 115.06,104.09 116.59,102.57 123.95,102.57 134.87,113.49 134.87,120.86 136.4,122.38 136.4,123.78 125.17,135.01 117.86,135.01 117.42,134.57 117.35,134.57 116.84,134.07 116.84,107.27 115.06,105.49
VDD_DSPEVE on L8_GND3: 112.39,106 111.63,105.24 111.63,93.43 107.19,88.98 107.19,87.84 105.92,86.57 105.28,86.57 104.77,86.06 104.77,83.39 105.03,83.14 107.44,83.14 107.7,83.39 107.7,83.77 109.09,85.17 121.03,85.17 123.95,88.09 123.95,105.49 123.44,106
VDD_DSPEVE on L10_SIG4: 104.65,86.14 106.86,86.14 106.98,86.01 106.98,83.49 106.5,83.01 105.03,83.01 104.42,83.62 104.42,85.91
VDD_DSPEVE on L10_SIG4: 115.69,103.69 115.37,104.01 115.37,105.29 115.95,105.87 117.98,105.87 118.69,105.16 118.69,104.44 117.95,103.69
VDD_DSPEVE on L10_SIG4: 113.54,87.08 114.43,87.08 115.19,86.31 115.19,84.92 115.06,84.79 113.54,84.79 113.03,85.3 113.03,86.57
VDD_DSPEVE on L10_SIG4: 115.19,97.89 115.19,98.89 115.57,99.27 117.37,99.27 117.47,99.17 117.47,98 116.96,97.48 115.6,97.48
VDD_GPU on TOP: 133.86,113.62 136.53,113.62 136.91,113.24 136.91,110.83 136.65,110.57 133.86,110.57 133.48,110.95 133.48,113.24
VDD_GPU on BOTTOM: 133.48,113.37 136.78,113.37 137.03,113.11 137.03,110.83 136.78,110.57 133.99,110.57 133.35,111.21 133.35,113.24
VDD_GPU on BOTTOM: 86.49,89.11 92.2,89.11 92.33,88.98 92.33,87.97 91.82,87.46 90.42,87.46 90.3,87.33 90.3,87.2 90.17,87.08 86.49,87.08 86.23,87.33 86.23,88.85
VDD_GPU on BOTTOM: 96.93,86.62 99.34,86.62 99.56,86.4 99.56,85.56 100.05,85.07 100.05,83.92 99.95,83.82 98.96,83.82 98.27,84.51 97.23,84.51 97.16,84.58 97.16,85.78 96.82,86.11 96.82,86.52
VDD_GPU on L3_SIG1: 97.69,86.21 98.73,86.21 100.03,84.91 100.03,83.97 99.9,83.85 98.65,83.85 98.4,83.59 98.4,83.36 99.21,82.55 99.21,82.17 99.11,82.07 97.94,82.07 97.54,82.47 97.54,86.06
VDD_GPU on L9_SIG3: 109.6,125.48 138.51,125.48 140.02,123.97 140.02,120.92 138.81,119.72 138.81,112.86 131.44,105.49 126.49,105.49 120.78,99.78 107.95,99.78 104.01,95.84 104.01,87.08 98.93,82 96.91,82 96.55,82.36 96.55,86.69 95.52,87.72 93.53,87.72 92.26,86.44 90.43,86.44 88.13,88.74 88.13,89.81 86.68,91.26 86.68,102.57 86.99,102.87
VDD_GPU on L10_SIG4: 97.69,86.21 98.73,86.21 99.77,85.17 99.77,84.58 98.78,84.58 98.17,85.19 97.54,85.19 97.54,86.06
VDD_GPU on L10_SIG4: 86.1,88.57 86.48,88.95 92.23,88.95 92.46,88.73 92.46,87.84 91.69,87.08 86.36,87.08 86.1,87.33
VDD_IVA on TOP: 143.26,113.62 146.05,113.62 146.43,113.24 146.43,110.95 146.18,110.7 143.38,110.7 143,111.08 143,113.37
VDD_IVA on BOTTOM: 89.89,78.08 90.17,78.36 92.84,78.36 93.22,77.98 98.34,77.98 99.11,78.74 99.82,78.74 100.03,78.54 100.03,77.07 99.69,76.74 93.35,76.74 91.16,74.55 90.04,74.55 89.89,74.7
VDD_IVA on L3_SIG1: 98.58,78.59 99.85,78.59 100.1,78.33 100.1,77.29 99.52,77.29 99.31,77.5 98.6,77.5 98.4,77.7 98.4,78.41
VDD_IVA on L9_SIG3: 98.78,76.33 98.3,76.81 98.3,80.77 98.71,81.18 99.11,81.18 104.77,86.84 104.77,95.2 108.97,99.4 120.9,99.4 126.53,105.02 131.87,105.02 139.52,112.68 139.52,119.79 140.21,120.48 140.21,122.45 140.41,122.66 147.32,122.66 147.57,122.41 147.57,111.51 140.42,104.35 140.42,103.8 117.42,80.8 108.46,80.8 103.99,76.33
VDD_IVA on L10_SIG4: 98.58,78.59 99.85,78.59 100.1,78.33 100.1,76.96 99.14,76.96 98.4,77.7 98.4,78.41
VDD_MPU on TOP: 102.6,79.83 104.06,79.83 104.4,80.17 105.76,80.17 106.5,79.43 106.5,77.42 105.18,77.42 104.39,78.21 102.6,78.21
VDD_MPU on TOP: 144.78,130.89 144.78,131.78 145.03,132.03 145.03,134.45 145.29,134.7 146.69,134.7 146.94,134.45 146.94,132.67 145.03,130.76 144.91,130.76
VDD_MPU on TOP: 108.84,133.81 109.35,134.32 112.27,134.32 112.27,131.02 114.81,128.48 118.75,128.48 119.76,127.46 119.76,122.51 118.87,121.62 114.55,121.62 108.84,127.34
VDD_MPU on BOTTOM: 115.64,80.42 117.15,80.42 117.3,80.27 117.3,78.94 117.09,78.74 115.91,78.74 115.44,79.2 115.44,80.22
VDD_MPU on BOTTOM: 95.63,95.97 99.31,95.97 99.57,95.71 99.57,94.49 99.31,94.23 95.59,94.23 95.38,94.44 95.38,95.71
VDD_MPU on BOTTOM: 105.97,80.17 106.46,80.17 107.09,79.54 107.09,78.47 108.89,78.47 109.14,78.21 109.14,76.74 108.99,76.59 108.37,76.59 107.99,76.97 106.86,76.97 106.81,76.92 106.76,76.92 106.07,77.6 104.42,77.6 104.29,77.73 104.29,80.7 104.7,81.11 105.74,81.11 105.79,81.05 105.79,80.35
VDD_MPU on BOTTOM: 101.17,79.71 101.42,79.96 102.49,79.96 102.97,79.48 102.97,79.05 102.77,78.85 101.5,78.85 101.17,79.18
VDD_MPU on L3_SIG1: 102.84,77.88 104.85,77.88 105.54,77.19 106.2,77.19 106.98,77.98 106.98,79.27 106.78,79.48 106.55,79.48 106.1,79.93 106.1,80.19 104.72,80.19 104.72,79.45 104.39,79.12 103.58,79.12 103.3,79.4 102.87,79.4 102.69,79.22 102.69,78.03
VDD_MPU on L6_PWR1: 95.63,118.19 106.81,129.37 106.81,129.24 107.7,130.13 116.97,130.13 126.87,140.04 144.91,140.04 147.19,137.75 147.19,131.91 146.56,131.27 144.65,131.27 143.13,132.8 141.22,132.8 140.59,132.16 138.68,132.16 137.67,133.18 133.48,133.18 128.02,127.72 128.02,116.03 121.67,109.68 121.67,105.36 119.63,103.33 119.63,77.68 119.04,77.09 100.79,77.09 100.61,77.27 100.61,81.76 101.42,82.58 101.42,88.4 95.63,94.19
VDD_MPU on L10_SIG4: 95.89,94.06 95.89,95.59 96.52,96.22 97.41,96.22 97.79,95.84 97.79,93.43 97.54,93.17 96.77,93.17
VDD_MPU on L10_SIG4: 102.49,80.09 103.35,79.23 104.32,79.23 104.57,79.48 104.57,80.6 104.55,80.62 104.55,80.75 104.83,81.03 105.77,81.03 106.07,80.73 106.07,79.84 106.88,79.02 106.88,78.08 106.73,77.93 100.86,77.93 100.84,77.91 100.71,78.03 100.71,78.41 100.79,78.49 101.27,78.49 101.47,78.69 101.47,79.96 101.6,80.09
VDD_RTC on TOP: 138.59,131.73 138.48,131.62 138.48,131.37 138.21,131.1 138.05,131.1 138.05,131.25 137.94,131.36 137.94,133.32 138.18,133.56 138.43,133.56 138.59,133.4
VDD_RTC on BOTTOM: 79.88,86.11 80.52,86.11 80.77,86.36 80.77,86.74 81.03,87 81.03,88.01 80.9,88.14 80.26,88.14 79.76,87.63 79.76,86.23
VDD_RTC on L9_SIG3: 105.11,134.19 138.3,134.19 138.81,133.69 138.81,126.7 138.35,126.24 109.09,126.24 85.85,103 85.85,92.84 81.79,88.78 81.79,85.09 81.53,84.84 80.26,84.84 78.11,87 78.11,107.19
VDD_RTC on L10_SIG4: 80.26,88.01 81.03,88.01 81.28,87.76 81.28,87.38 81.03,87.12 81.03,86.23 80.64,85.85 79.88,85.85 79.5,86.23 79.5,87.25
VDDR2_VREF on BOTTOM: 162.08,59.87 162.08,58.32 160.96,58.32 160.96,59.21 159,61.17 159,63.07 155.19,66.88 155.19,70.19 151.38,74 141.86,74 140.34,72.47 138.56,72.47 138.18,72.85 138.18,74.63 139.57,76.03 152.65,76.03 157.35,71.33 157.35,67.67 161.42,63.61 161.42,60.53
VDDR2_VREF on BOTTOM: 139.7,55.58 141.22,55.58 141.48,55.33 141.48,51.9 140.59,51.01 140.21,51.01 139.45,51.77 139.45,55.33
VDDR2_VREF on BOTTOM: 139.7,70.82 141.22,70.82 141.48,70.57 141.48,67.14 140.59,66.25 140.21,66.25 139.45,67.01 139.45,70.57
VDDR2_VREF on L7_PWR2: 141.35,45.42 138.68,48.09 138.68,56.98 137.67,57.99 117.98,57.99 108.84,67.14 108.84,70.19 107.06,71.96 104.77,71.96 103.63,73.11 103.63,74.76 104.01,75.14 109.35,75.14 111.63,72.85 111.63,68.33 117.73,62.23 129.71,62.23 133.73,66.25 133.73,71.58 136.95,74.8 140.04,74.8 143.89,70.95 143.89,62.86 144.4,62.36 144.4,60.83 143.89,60.32 143.89,46.06 143.26,45.42
VDDR2_VTT on TOP: 142.75,71.07 150.41,71.07 151.13,70.36 151.13,56.98 151.38,56.72 152.15,56.72 152.91,57.49 158.12,57.49 158.24,57.61 158.24,58.88 158.12,59.01 153.54,59.01 152.91,59.64 152.91,70.99 151.05,72.85 142.75,72.85 142.49,72.6 142.49,71.33
VDDR2_VTT on BOTTOM: 151.13,70.41 150.47,71.07 141.86,71.07 141.61,71.33 141.61,72.6 141.86,72.85 151,72.85 152.91,70.95 152.91,60.66 154.46,59.11 156.01,59.11 156.21,58.91 156.21,58.42 156.44,58.2 157,58.2 157.15,58.04 157.15,57.84 157.05,57.74 157.05,57.66 156.97,57.59 156.97,57.49 151.38,57.49 151.13,57.74
VDDR_VREF on TOP: 109.09,33.78 111.51,33.78 112.52,32.77 113.41,32.77 113.54,32.89 113.79,32.89 113.92,32.77 113.92,32.51 113.28,31.88 108.97,31.88 108.58,32.26 108.58,33.27
VDDR_VREF on TOP: 105.44,12.55 106.98,12.55 106.98,13.67 106.1,13.67 104.14,15.62 98.76,15.62 92.79,21.59 91.19,21.59 90.68,21.08 90.68,20.19 97.94,12.93 105.05,12.93
VDDR_VREF on TOP: 78.3,33.71 81.09,33.71 82.06,32.74 82.91,32.74 83.12,32.96 83.28,32.96 83.44,32.79 83.44,32.59 82.77,31.92 78.4,31.92 78.11,32.22 78.11,33.52
VDDR_VREF on TOP: 93.85,33.78 96.27,33.78 97.28,32.77 98.17,32.77 98.3,32.89 98.55,32.89 98.68,32.77 98.68,32.51 98.04,31.88 93.73,31.88 93.34,32.26 93.34,33.27
VDDR_VREF on L7_PWR2: 92.46,18.83 90.55,20.74 90.55,26.88 88.65,28.78 83.44,28.78 82.55,29.67 82.55,33.61 83.19,34.24 86.23,34.24 95.76,43.77 95.76,65.16 96.52,65.92 96.52,78.19 96.77,78.44 99.82,78.44 100.03,78.24 100.03,77.42 102.74,74.71 102.74,38.94 103.25,38.44 120.27,38.44 123.19,35.51 123.19,27.72 122.3,26.83 97.54,26.83 96.01,25.31 96.01,19.85 95,18.83
VDDR_VTT on TOP: 107.31,17.27 107.06,17.53 107.06,17.78 106.3,18.54 106.3,27.81 106.55,28.07 108.46,28.07 108.71,27.81 108.71,25.4 109.6,24.51 110.62,24.51 111.89,23.24 111.89,22.61 112.91,21.58 120.78,21.58 121.5,20.87 124.5,20.87 125.13,21.5 125.13,24.98 124.21,25.91 124.21,27.81 124.46,28.07 125.86,28.07 126.36,28.58 126.36,30.48 125.86,30.99 124.84,30.99 124.21,31.62 124.21,32.13 124.46,32.38 127.38,32.38 129.03,30.73 129.03,26.16 128.14,25.27 128.14,20.07 126.11,18.03 118.39,18.03 115.8,20.62 111.46,20.62 109.98,22.1 108.33,22.1 107.82,21.59 107.82,17.53 107.57,17.27
VDDR_VTT on BOTTOM: 107.31,23.62 108.46,22.48 110.62,22.48 111.38,21.72 111.38,19.3 111.76,18.92 127.13,18.92 128.35,20.14 128.35,29.69 128.07,29.97 124.41,29.97 124.21,29.77 124.21,22.48 123.32,21.59 114.05,21.59 113.54,22.1 113.54,22.18 108.71,27.01 108.71,28.19 108.58,28.32 108.58,30.61 108.46,30.73 107.57,30.73 107.31,30.48
VDDS_DDR on TOP: 141.48,53.04 141.86,53.04 142.11,52.79 142.11,51.52 142.37,51.26 142.37,50.02 142.13,49.78 141.56,49.78 141.35,49.99 141.35,51.14 141.22,51.26 141.22,52.79
VDDS_DDR on TOP: 135,48.21 136.4,48.21 136.65,48.47 136.65,48.95 137.16,49.46 137.16,50.34 136.88,50.63 135,50.63 134.75,50.37 134.75,48.47
VDDS_DDR on TOP: 156.08,57.1 156.21,56.98 156.21,55.71 156.08,55.58 153.16,55.58 152.91,55.83 152.91,56.85 153.16,57.1
VDDS_DDR on TOP: 108.71,17.06 109.09,17.44 109.09,17.95 109.73,18.59 109.73,20.11 109.98,20.37 109.98,21.46 109.73,21.72 108.46,21.72 108.2,21.46 108.2,17.06
VDDS_DDR on TOP: 151.64,116.67 148.46,116.67 148.21,116.92 148.21,118.32 145.77,120.75 145.77,122.02 144.91,122.89 144.91,123.02 145.16,123.27 145.54,123.27 145.8,123.02 146.94,123.02 148.72,121.24 150.5,121.24 150.88,120.86 150.88,119.46 151.89,118.45 151.89,116.92
VDDS_DDR on TOP: 139.19,50.37 140.21,50.37 140.56,50.02 140.56,48.57 140.08,48.09 139.19,48.09 138.94,48.34 138.94,50.12
VDDS_DDR on TOP: 65.15,56.98 65.15,54.06 65.02,53.93 62.74,53.93 62.23,54.44 62.23,57.1 62.61,57.49 64.64,57.49
VDDS_DDR on TOP: 136.14,63.33 136.65,63.33 137.41,64.09 137.41,65.49 137.16,65.74 136.65,65.74 135.89,64.98 135.89,63.58
VDDS_DDR on TOP: 61.09,75.01 64.01,75.01 64.14,74.88 64.14,72.6 63.63,72.09 60.96,72.09 60.58,72.47 60.58,74.5
VDDS_DDR on BOTTOM: 86.74,33.43 87.1,33.78 87.38,33.78 87.63,33.53 87.63,32.26 87.25,31.88 84.33,31.88 83.69,32.51 83.69,33.3 83.82,33.43
VDDS_DDR on BOTTOM: 83.95,36.32 85.85,36.32 86.11,36.07 86.11,35.69 85.85,35.43 83.95,35.43 83.69,35.69 83.69,36.07
VDDS_DDR on BOTTOM: 109.86,18.54 110.11,18.8 110.11,21.46 109.73,21.84 108.58,21.84 108.2,21.46 108.2,18.67 108.33,18.54
VDDS_DDR on BOTTOM: 157.56,56.6 157.18,56.22 156.67,56.22 156.04,55.58 153.33,55.58 153.1,55.81 153.1,56.91 153.29,57.1 157.56,57.1
VDDS_DDR on L6_PWR1: 151.26,119.21 144.4,119.21 141.99,116.79 133.22,116.79 132.33,115.91 132.33,114.76 126.24,108.67 126.24,105.49 125.09,104.35 121.41,104.35 120.27,103.21 120.27,77.35 119.93,77 119.93,48.63 113.66,42.37 67.18,42.37 65.15,44.4 65.15,73.84 63.91,75.09 51,75.09 49.78,73.87 49.78,26.37 51.64,24.52 65.46,24.52 71.58,18.39 82.55,18.39 84.86,16.08 97.66,16.08 99.95,18.37 111.76,18.37 112.78,17.35 113.41,17.35 114.43,18.37 164.21,18.37 168.4,22.56 168.4,66.25 163.96,70.69 156.34,70.69 152.65,74.38 152.65,87.39 152.02,88.03 143.07,88.03 140.59,90.51 140.59,101.94 152.02,113.37 152.02,118.45
AM574X_USB1_DRVVBUS on L9_SIG3: 93.44,87.07 95.48,87.07 96.01,86.53 96.01,83.51 95.5,83 91.54,83 85.1,89.44 85.1,90.28 85.7,90.89 86.49,90.89 87.28,90.09 87.28,89.02 90.27,86.03 92.41,86.03 92.41,86.04
BKLT_L on TOP: 70.86,144.25 70.36,144.75 70.36,146.41 70.74,146.79 80.13,146.79 80.64,146.28 80.64,144.63 80.26,144.25
BKLT_L on BOTTOM: 73.13,146.61 73.13,145.6 72.24,145.6 71.48,144.84 70.59,144.84 70.36,145.07 70.36,146.38 70.59,146.61
BKLT_SW on TOP: 70.74,140.94 70.36,141.33 70.36,143.48 70.74,143.87 80.26,143.87 80.64,143.48 80.64,141.58 80.01,140.94
BKLT_SW on BOTTOM: 73.15,143.57 73.15,142.7 72.27,142.7 71.82,142.25 70.38,142.25 70.09,142.55 70.09,143.31 70.34,143.57
ETH1_LDO_O on TOP: 64.64,111.08 65.53,111.08 65.79,110.83 65.79,107.78 65.66,107.65 64.52,107.65 64.39,107.78 64.39,110.83
FTDI_VPHY on BOTTOM: 158.8,83.13 164.01,83.13 164.39,82.75 164.39,81.48 164.13,81.22 159.18,81.22 158.55,81.86 158.55,82.87
FTDI_VPLL on BOTTOM: 158.93,81.16 164.13,81.16 164.52,80.78 164.52,79.51 164.21,79.2 159.36,79.2 158.67,79.89 158.67,80.9
VADD33_PRU1ETH0 on BOTTOM: 21.97,121.87 21.97,123.14 22.48,123.65 23.37,123.65 23.62,123.4 23.62,123.02 23.37,122.76 23.11,122.76 22.23,121.87
VADD33_PRU1ETH1 on TOP: 26.11,100.54 26.54,100.54 27.03,100.06 27.03,98.63 26.8,98.4 26.39,98.4 26.16,98.63 26.16,99.78 25.88,100.06 25.88,100.31
VADD33_PRU1ETH1 on BOTTOM: 26.37,101.43 29.79,101.43 29.92,101.3 29.92,100.16 29.67,99.9 27.53,99.9 27.03,99.4 27.03,98.63 26.77,98.38 26.37,98.38 25.98,98.76 25.98,101.05
VADD33_PRU2ETH0 on TOP: 26.06,82.78 26.54,82.78 26.97,82.35 26.97,80.9 26.8,80.73 26.31,80.73 25.98,81.06 25.98,82.4 26.06,82.48
VADD33_PRU2ETH0 on BOTTOM: 29.67,81.87 28.63,81.87 27.44,80.68 26.37,80.68 25.98,81.06 25.98,83.35 26.53,83.89 29.82,83.89 30.12,83.58 30.12,82.32
VADD33_PRU2ETH1 on TOP: 26.22,57.63 27.29,57.63 27.74,57.18 27.74,56.8 27.53,56.6 27.46,56.6 26.72,55.86 26.31,55.86 26.07,56.11 26.07,57.48
VADD33_PRU2ETH1 on BOTTOM: 26.27,58.87 29.77,58.87 29.92,58.72 29.92,57.52 29.82,57.41 28.4,57.41 27.56,56.57 27.3,56.57 27.08,56.35 27.08,56.1 26.89,55.91 26.37,55.91 26.06,56.22 26.06,58.65
VAM574X_DDR1 on TOP: 95.94,76.71 97.18,76.71 97.33,76.56 97.33,75.26 97.08,75.01 95,75.01 94.82,75.18 94.82,75.59
VAM574X_DDR1 on TOP: 61.09,78.69 63.63,78.69 64.14,78.19 64.14,75.9 64.01,75.77 61.09,75.77 60.71,76.15 60.71,78.31
VAM574X_DDR1 on TOP: 67.06,72.47 69.22,72.47 69.72,71.96 69.72,71.2 69.22,70.69 67.06,70.69 66.55,71.2 66.55,71.96
VAM574X_DDR1 on BOTTOM: 93.88,75.98 95.17,75.98 95.76,75.39 95.97,75.39 95.97,73.28 97.73,71.52 97.73,71.29 97.49,71.05 97.49,70.79 97.33,70.64 95.96,70.64 95.76,70.84 95.76,71.37 95.35,71.78 94.51,71.78 94.39,71.65 94.39,70.28 94.26,70.15 92.71,70.15 92.64,70.22 92.64,71.7 93.7,72.76 93.7,75.8
VAM574X_DDR1 on BOTTOM: 66.29,72.47 71.37,72.47 72.01,71.84 72.01,66.88 71.5,66.38 67.18,66.38 65.79,67.77 65.79,71.96
VAM574X_DDR1 on L3_SIG1: 95.38,76.28 96.65,76.28 96.85,76.07 96.85,75.23 96.6,74.98 94.54,74.98 94.54,75.44
VAM574X_DDR1 on L6_PWR1: 98.04,68.15 95.63,65.74 65.91,65.74 65.79,65.87 65.79,74.12 64.14,75.77 60.2,75.77 59.44,76.54 59.44,82.17 60.91,83.65 94.23,83.65 94.46,83.42 100.78,83.42 100.78,83.42 100.78,79.4 100.18,78.8 100.18,76.66 98.04,74.53
VAM574X_DDR1 on L10_SIG4: 96.52,71.46 96.14,71.07 95.76,71.07 95.63,71.2 95.63,71.46 95.18,71.91 94.82,71.91 94.13,71.22 93.75,71.22 93.55,71.42 93.55,72.26 93.57,72.26 94.61,73.3 94.61,73.89 93.8,74.7 93.8,75.18 94.01,75.39 94.56,75.39 95.3,76.12 96.19,76.12 96.19,74.4 96.52,74.07
VAM574X_DDR2 on TOP: 103.86,77.44 103.86,75.82 105.54,75.82 105.61,75.9 105.61,76.99 105.54,77.06 105.33,77.06 105.18,76.91 104.9,76.91 104.37,77.44
VAM574X_DDR2 on TOP: 68.83,56.98 68.83,54.44 68.33,53.93 66.04,53.93 65.91,54.06 65.91,56.98 66.29,57.36 68.45,57.36
VAM574X_DDR2 on BOTTOM: 114.3,54.69 121.03,54.69 121.92,55.58 121.92,58.12 120.9,59.14 114.68,59.14 113.66,58.12 113.66,55.33
VAM574X_DDR2 on BOTTOM: 110.06,71.05 110.06,72.75 110.67,73.36 110.67,74.93 110.54,75.06 109.25,75.06 108.89,75.41 108.89,75.8 108.69,76 108.41,76 107.95,76.46 104.39,76.46 104.39,75.39 104.52,75.27 105.16,75.27 105.28,75.14 105.28,75.11 105.66,75.11 106.1,74.68 106.1,72.85 105.77,72.52 105.11,72.52 104.8,72.83 103.88,72.83 103.7,72.65 101.32,72.65 100.81,73.16 100.49,73.16 100.43,73.11 100.43,72.16 100.58,72.01 100.91,72.01 101,72.09 104.17,72.09 104.68,71.58 105.31,71.58 106.68,70.21 109.22,70.21
VAM574X_DDR2 on L3_SIG1: 107.67,76.91 108.41,76.91 108.71,76.61 108.71,75.69 109.47,74.93 109.47,73.79 108.2,73.79 107.59,74.4 107.59,76.83
VAM574X_DDR2 on L3_SIG1: 100.41,73.84 101.09,73.84 101.45,73.48 101.45,72.47 101.12,72.14 100.46,72.14 100.18,72.42 100.18,73.61
VAM574X_DDR2 on L3_SIG1, L10_SIG4: 104.42,77.01 105.49,77.01 105.64,76.86 105.89,76.86 106.22,76.53 106.22,75.49 105.89,75.16 104.57,75.16 104.37,75.36 104.37,76.96
VAM574X_DDR2 on L6_PWR1: 119.3,76.21 119.3,48.92 113.39,43 67.44,43 65.79,44.66 65.79,64.85 66.04,65.11 96.01,65.11 98.55,67.65 98.55,74.5 100.85,76.8 118.72,76.8
VAM574X_DDR2 on L10_SIG4: 113.66,56.85 120.9,56.85 121.54,56.22 121.54,54.82 121.03,54.31 113.66,54.31 113.03,54.95 113.03,56.22
VAM574X_DDR2 on L10_SIG4: 107.8,76.71 108.48,76.71 108.71,76.48 108.71,75.69 110.92,73.48 110.92,72.97 110.64,72.69 109.3,72.69 107.59,74.4 107.59,76.5
VCAN1 on TOP: 165.76,29.85 167.96,29.85 168.33,29.48 168.33,26.04 165.56,23.27 157.53,23.27 155.23,20.97 155.23,13.53 154.45,12.75 151.52,12.75 150.9,13.37 148.54,13.37 148.08,13.82 148.08,19.89 155.07,26.88 164.54,26.88 165.35,27.69 165.35,29.44
VETH0_AVDDH on BOTTOM: 48.13,116.92 48.89,116.16 48.89,113.75 48.51,113.37 47.5,113.37 46.86,114 46.86,117.94 46.48,118.32 46.48,123.91 46.74,124.16 47.88,124.16 48.13,123.91
VETH0_AVDDH on L4_SIG2: 30.48,127.34 44.96,127.34 48.15,124.14 48.15,122.81 46.71,121.37 40.26,121.37 37.08,124.54 33.78,124.54 32.81,123.57 25.4,123.57 24.38,124.59 24.38,126.11 25.25,126.98 30.12,126.98
VETH0_AVDDL on BOTTOM: 43.69,123.65 43.69,124.8 43.43,125.05 38.84,125.05 38.33,125.56 33.66,125.56 33.15,125.05 33.15,124.41 33.66,123.91 37.87,123.91 38.25,123.53 43.56,123.53
VETH0_AVDDL_PLL on BOTTOM: 38.94,123.02 43.05,123.02 43.81,122.26 43.81,121.24 43.56,120.99 38.99,120.99 38.73,121.24 38.73,122.81
VETH0_AVDDL_PMOS on BOTTOM: 43.31,109.17 43.31,110.32 44.7,111.71 44.7,117.56 44.2,118.06 44.2,125.05 43.81,125.43 43.81,126.95 44.32,127.46 46.1,127.46 46.48,127.08 46.48,125.56 45.97,125.05 45.97,118.06 46.61,117.43 46.61,112.22 47.62,111.21 47.62,109.05 47.24,108.67 43.81,108.67
VETH0_DVDDH on BOTTOM: 28.45,118.19 29.08,118.19 30.23,117.05 30.43,117.05 30.86,116.62 30.86,116.16 30.35,115.65 28.45,115.65 27.69,116.41 27.69,117.43
VETH0_DVDDH on L4_SIG2: 29.34,122.89 29.97,122.89 32.38,120.48 42.42,120.48 43.18,119.72 43.18,111.33 43.14,111.29 43.14,108.6 42.07,107.52 38.32,107.52 38.14,107.7 38.14,109.66 39.88,111.4 39.88,112.86 39.24,113.49 30.86,113.49 28.45,115.91 27.43,115.91 27.05,116.29 27.05,120.6
VETH0_DVDDL on BOTTOM: 43.56,119.59 43.81,119.33 43.81,118.45 43.56,118.19 42.55,118.19 41.27,116.92 38.61,116.92 37.41,115.73 32.21,115.73 30.51,117.42 30.32,117.42 29.48,118.27 29.48,122.72 30.16,123.4 31.62,123.4 32.77,122.26 32.77,121.49 34.67,119.59
VETH1_AVDDH on TOP: 72.9,106.25 72.39,105.75 69.34,105.75 68.96,106.13 68.96,110.19 70.61,111.84 70.61,116.67 69.47,117.81 69.47,127.59 68.58,128.48 64.64,128.48 64.01,129.11 64.01,130.51 64.26,130.76 70.48,130.76 72.9,128.35
VETH1_AVDDH on BOTTOM: 50.67,127.08 52.45,127.08 52.82,126.71 58.33,126.71 62.38,130.76 66.67,130.76 67.06,130.38 67.06,128.86 66.67,128.48 62.03,128.48 60.2,126.65 60.2,125.53 60.1,125.43 59.21,125.43 58.72,125.92 55.18,125.92 53.8,124.54 50.67,124.54 50.29,124.92 50.29,126.7
VETH1_AVDDL on TOP: 65.53,123.27 65.28,123.02 64.14,123.02 63.63,123.53 63.63,124.8 63.88,125.05 65.41,125.05 65.53,124.92
VETH1_AVDDL on BOTTOM: 65.66,124.54 65.15,125.05 59.05,125.05 58.55,125.56 55.37,125.56 54.86,125.05 54.86,124.41 55.68,123.6 64.31,123.6 64.9,123.02 65.41,123.02 65.66,123.27
VETH1_AVDDL_PLL on TOP: 64.39,122.64 65.28,122.64 65.53,122.38 65.53,120.86 65.28,120.6 64.14,120.6 63.88,120.86 63.88,121.24 64.14,121.49 64.14,122.38
VETH1_AVDDL_PLL on BOTTOM: 60.71,123.27 64.52,123.27 65.53,122.26 65.53,120.99 65.28,120.73 64.01,120.73 63.75,120.99 60.58,120.99 60.32,121.24 60.32,122.89
VETH1_AVDDL_PMOS on TOP: 65.91,111.46 65.91,128.22 66.42,128.73 67.69,128.73 68.77,127.65 68.77,116.98 69.47,116.29 69.47,112.6 68.2,111.33 68.2,107.78 67.82,107.4 66.8,107.4 66.55,107.65 66.55,110.83
VETH1_DVDDH on BOTTOM: 50.04,115.02 51.31,115.02 51.43,114.89 51.43,112.6 51.31,112.48 49.4,112.48 49.15,112.73 49.15,114.51 49.53,114.89 49.91,114.89
VETH1_DVDDH on L4_SIG2: 52.07,122.89 61.59,122.89 64.26,120.22 64.26,111.08 61.93,108.74 49.76,108.74 48.64,109.86 48.64,119.59 47.88,120.35 47.88,121.62 49.78,123.53 51.43,123.53
VETH1_DVDDL on BOTTOM: 58.55,118.19 59.44,118.19 60.83,119.59 64.01,119.59 64.01,119.84 64.52,120.35 65.28,120.35 65.53,120.1 65.53,117.81 64.64,116.92 60.32,116.92 58.93,115.52 53.11,115.52 51.31,117.32 51.31,122.51 52.2,123.4 53.34,123.4 54.48,122.26 54.48,119.97 55.5,118.95 57.78,118.95
VLDO2_OUT on TOP: 138.83,133.32 138.94,133.43 138.94,133.81 139.07,133.94 139.32,133.94 139.47,133.78 139.47,131.27 139.32,131.12 139.32,130.31 139.24,130.23 139.04,130.23 138.83,130.44
VLDO2_OUT on BOTTOM: 138.94,133.18 138.94,131.65 139.07,131.53 139.95,131.53 140.21,131.78 140.21,133.86 139.49,134.57 138.56,134.57 138.3,134.32 138.3,133.81
VLED+ on BOTTOM: 73.41,136.86 70.36,136.86 69.98,137.24 69.98,138.64 70.23,138.89 70.23,141.74 70.39,141.9 72.86,141.9 73.41,142.45 73.66,142.45 73.79,142.32 73.79,137.24
VLED+ on L9_SIG3: 71.25,141.81 72.39,141.81 82.55,131.65 82.55,128.48 81.91,127.84 80.01,127.84 70.61,137.24 70.61,141.18
VLED- on BOTTOM: 82.42,124.8 81.79,125.43 81.79,127.08 82.04,127.34 82.68,127.34 82.8,127.46 84.96,127.46 85.09,127.34 85.09,125.05 84.84,124.8
VLED- on BOTTOM: 76.07,146.64 76.58,147.15 81.41,147.15 82.04,146.51 82.04,145.12 81.61,144.68 78.18,144.68 77.5,145.37 75.79,145.37 75.54,145.62 75.06,145.62 74.93,145.75 74.93,146.51 75.06,146.64
VLED- on L9_SIG3: 77.85,146.51 78.87,147.53 81.03,147.53 88.77,139.78 88.77,126.45 86.36,124.03 81.91,124.03 81.28,124.67 81.28,126.7 81.66,127.08 81.91,127.08 84.96,130.13 84.96,131.02 84.9,131.08 84.9,136.54 77.85,143.59
VMAIN on TOP: 137.29,121.24 137.29,120.1 136.65,119.46 135.26,119.46 135.13,119.59 135.13,119.97 136.02,120.86 136.02,121.11 136.27,121.37 137.16,121.37
VMAIN on TOP: 184.73,120.15 176.48,120.15 172.36,116.04 172.36,112.35 166.65,106.63 166.65,102.72 166.12,102.19 162.59,102.19 162.08,102.7 162.08,111.08 166.01,115.02 168.68,115.02 169.95,116.29 169.95,125.68 170.21,125.94 177.7,125.94 178.21,126.45 185.8,126.45 186.94,125.3 186.94,122.37
VMAIN on TOP: 140.21,120.73 141.22,120.73 141.54,120.41 141.54,118.89 141.48,118.83 140.59,118.83 140.02,119.4 140.02,120.54
VMAIN on TOP: 158.12,123.91 158.47,123.91 158.78,124.21 158.78,125.7 159,125.93 159,128.48 158.37,129.11 158.37,133.94 158.24,134.07 156.08,134.07 155.32,133.3 155.32,128.86 156.08,128.1 157.48,128.1 157.86,127.72 157.86,124.16
VMAIN on TOP: 75.69,130.76 74.3,129.37 74.3,115.52 76.71,113.11 76.71,110.32 75.82,109.43 75.82,107.9 76.33,107.4 79.5,107.4 81.91,109.81 81.91,113.87 79.25,116.54 79.25,128.35 79.63,128.73 79.63,130.26 79.12,130.76
VMAIN on BOTTOM: 137.03,121.62 137.03,120.1 136.78,119.84 136.78,117.94 137.03,117.68 142.49,117.68 143,118.19 143,121.24 142.88,121.37 138.68,121.37 138.18,121.87 137.29,121.87
VMAIN on BOTTOM: 70.74,111.21 72.26,111.21 72.52,110.95 72.52,109.17 79.12,109.17 79.38,108.92 79.38,108.16 78.49,107.27 70.87,107.27 70.74,107.4
VMAIN on BOTTOM: 145.36,132.11 144.68,131.42 141.27,131.42 141.1,131.6 141.1,132.16 141.73,132.8 141.73,133.86 142.06,134.19 145.29,134.19 145.36,134.12
VMAIN on BOTTOM: 154.74,106.9 154.23,106.9 153.32,107.81 151.48,107.81 151,108.29 149.48,108.29 149.23,108.03 149.23,106.51 149.47,106.27 154.74,106.27
VMAIN on BOTTOM: 146.77,125.81 148.84,125.81 149.1,125.56 149.1,122.89 147.7,121.49 147.7,119.84 147.57,119.72 145.03,119.72 144.65,120.1 144.65,121.92 145.03,122.3 145.03,124.59 145.54,124.59
VMAIN on BOTTOM: 73.51,145.72 73.51,146.87 73.13,147.25 72.75,147.25 72.63,147.38 72.63,148.52 72.5,148.65 72.5,148.67 72.37,148.8 70.99,148.8 70.1,149.69 70.1,150.58 70.42,150.89 73.98,150.89 74.28,150.59 74.28,149.28 74.02,149.03 74.02,147.25 73.77,146.99 73.77,145.72
VMAIN on BOTTOM: 166.24,112.98 169.32,112.98 171.09,114.76 171.09,118.83 173.38,121.11 186.31,121.11 186.94,121.75 186.94,125.81 186.44,126.32 167.28,126.32 166.65,125.68 166.65,120.48 165.86,119.69 165.86,113.36
VMAIN on BOTTOM: 133.41,127.85 133.41,130.54 132.9,131.05 131.57,131.05 131.42,131.2 131.42,132.78 131.68,133.04 135.01,133.04 136.08,131.97 136.08,130.78 135.13,129.83 135.13,128.86 135.64,128.35 135.76,128.35 136.14,127.97 136.14,126.83 135.64,126.32 134.87,126.32 134.11,125.56 133.1,125.56 132.97,125.68 132.97,127.41
VMAIN on BOTTOM: 155.83,129.88 158.5,129.88 159.64,128.73 159.64,126.07 159.39,125.81 158.37,125.81 158.12,126.07 158.12,127.59 157.73,127.97 156.21,127.97 155.58,128.61 155.58,129.62
VMAIN on BOTTOM: 145.01,129.65 146.63,129.65 147.07,129.21 147.07,128.27 146.79,128 145.39,128 144.88,128.5 144.88,129.52
VMAIN on L3_SIG1: 142.68,125.74 142.68,124.83 142.96,124.54 145.03,124.54 145.31,124.82 147.47,124.82 147.7,125.05 147.7,126.07 147.45,126.32 145.16,126.32 144.78,125.94 142.88,125.94
VMAIN on L3_SIG1: 142.88,128.99 145.16,128.99 145.8,129.62 146.81,129.62 147.07,129.37 147.07,128.35 146.94,128.22 143,128.22 142.75,128.48 142.75,128.86
VMAIN on L3_SIG1: 132.72,124.92 135.64,124.92 136.14,124.41 136.14,123.78 132.59,123.78 132.46,123.91 132.46,124.67
VMAIN on L3_SIG1: 135,119.08 135,119.97 136.4,121.37 141.1,121.37 141.86,120.6 141.86,118.7 141.73,118.57 135.51,118.57
VMAIN on L3_SIG1: 144.53,122.76 147.7,122.76 148.08,122.38 148.08,122 147.32,121.24 145.03,121.24 144.27,122 144.27,122.51
VMAIN on L3_SIG1: 136.27,129.15 136.49,128.94 137.68,128.94 137.8,129.06 137.8,129.53 137.99,129.72 138.58,129.72 138.73,129.57 138.73,129.26 138.84,129.14 140.05,129.14 140.26,129.36 140.26,130.48 140.79,131 142.14,131 142.39,131.26 142.39,132.13 142.09,132.43 140.18,132.43 139.65,131.9 139.65,130.96 139.46,130.76 139.18,130.76 138.86,131.09 137.09,131.09 136.53,131.65 136.53,132.03 135.64,132.92 133.73,132.92 133.6,132.8 133.6,131.91 134.37,131.15 135.76,131.15 136.27,130.64
VMAIN on L6_PWR1: 169.16,92.56 166.32,92.56 166.32,92.51 162.66,88.85 143.12,88.85 141.22,90.75 141.22,101.67 152.53,112.97 152.53,118.83 151.51,119.84 144.15,119.84 141.73,117.43 133.48,117.43 132.33,118.57 132.33,126.57 134.87,129.11 136.53,129.11 138.43,131.02 138.81,131.02 139.45,131.65 140.59,131.65 141.22,132.29 142.88,132.29 144.4,130.76 146.43,130.76 147.57,131.91 147.57,137.88 145.03,140.42 126.36,140.42 116.71,130.76 84.71,130.76 84.71,130.51 82.68,128.48 82.68,126.57 82.42,126.32 73.79,126.32 70.48,129.62 70.48,134.7 70.61,134.83 70.61,149.8 71.31,150.5 83.75,150.5 84.35,149.9 96.53,149.9 97.13,150.5 169.16,150.5 ; 29 cut-outs
VMAIN on L10_SIG4: 145.11,126.06 147.75,126.06 148.08,125.73 148.08,121.49 147.7,121.11 145.16,121.11 144.65,121.62 144.65,122.26 144.91,122.51 144.91,125.86
VMAIN on L10_SIG4: 133.73,128.48 135.89,128.48 136.27,128.1 136.27,127.08 134.11,124.92 134.11,124.03 133.86,123.78 132.59,123.78 132.33,124.03 132.33,127.08
VMAIN on L10_SIG4: 138.68,130.76 138.81,130.76 139.95,131.91 139.95,132.67 140.46,133.18 143.38,133.18 143.64,132.92 143.64,131.65 143,131.02 140.72,131.02 139.57,129.88 138.81,129.88 138.56,130.13 138.56,130.64
VMAIN on L10_SIG4: 132.74,132.57 133.1,132.92 135.71,132.92 136.14,132.49 136.14,130.66 135.83,130.35 133.09,130.35 132.74,130.7
VMAIN on L10_SIG4: 144.65,129.62 144.78,129.75 147.19,129.75 147.32,129.62 147.32,128.61 147.07,128.35 144.91,128.35 144.65,128.61
VMAIN on L10_SIG4: 136.27,121.49 140.72,121.49 141.61,120.6 141.61,118.83 141.48,118.7 136.02,118.7 135.64,119.08 135.64,120.86
VPROFI on TOP: 114.55,4.32 114.94,3.94 115.95,3.94 116.2,4.19 118.75,4.19 119,3.94 119,2.41 118.75,2.16 112.14,2.16 111.89,2.41 111.89,3.94 112.27,4.32
VPROFI on BOTTOM: 99.44,10.24 103.17,10.24 103.63,9.78 103.63,8.13 103.25,7.75 103.25,6.22 102.87,5.84 99.27,5.84 98.81,6.3 98.81,9.61
VPROFI on L3_SIG1: 98.68,6.83 99.52,7.67 108.92,7.67 112.37,4.22 114,4.22 114.45,3.76 114.45,1.88 113.84,1.27 110.34,1.27 109.52,2.08 109.52,2.97 107.49,5 105.23,5 104.8,4.57 99.06,4.57 98.68,4.95
VPROFI_SRC on BOTTOM: 99.44,12.7 109.36,12.7 114.32,7.75 117.22,7.75 117.47,8 117.47,9.53 117.98,10.03 119.13,10.03 119.38,9.78 119.38,6.48 119.13,6.22 117.74,6.22 117.33,5.81 117.33,4.81 116.81,4.29 112.46,4.29 111.77,4.97 111.77,6.5 107.48,10.79 99.31,10.79 99.19,10.92 99.19,12.45
VPROFI_TRANSA on BOTTOM: 117.35,13.46 123.08,13.46 123.99,12.55 123.99,10.94 123.46,10.41 121.54,10.41 119.76,12.19 117.22,12.19 117.09,12.32 117.09,13.21
VPROFI_TRANSB on BOTTOM: 117.86,4.06 120.14,4.06 121.28,5.21 121.28,5.84 121.54,6.1 123.71,6.1 123.96,5.85 123.96,4.32 121.92,2.29 117.86,2.29 117.47,2.67 117.47,3.68
VPWRIN_JCK on TOP: 179.79,102.76 172.84,109.72 172.84,113.8 174.16,115.13 176.55,115.13 178.97,112.71 178.97,110.19 180.62,108.54 183.16,108.54 184.96,110.34 184.96,111.49 185.57,112.1 187.99,112.1 188.75,111.33 188.75,104.48 187.03,102.76 ; 1 cut-out
VPWRIN_JCK on BOTTOM: 171.48,109.68 164.28,109.68 160.15,113.82 159.08,113.82 157.78,115.11 157.78,121.21 160.66,124.09 160.66,129.91 153.9,136.68 153.9,140.03 155.5,141.63 162.05,141.63 165.79,137.9 165.79,120.45 165.33,119.99 165.33,113.28 166.14,112.48 170.59,112.48 173.51,115.4 177.19,115.4 178.97,113.62 178.97,110.19 180.62,108.54 183.16,108.54 184.81,110.19 184.81,111.71 185.57,112.48 188.11,112.48 188.95,111.64 188.95,104.68 187.03,102.76 178.4,102.76
VPWRIN_PREFUSE on TOP: 169.32,107.65 173.76,107.65 174.27,107.14 174.27,102.57 173.51,101.81 168.94,101.81 168.3,102.44 168.3,106.63
VPWRIN_PREFUSE on BOTTOM: 165.38,107.65 172.49,107.65 173.89,106.25 173.89,102.21 173.48,101.81 165.38,101.81 164.49,102.7 164.49,106.76
VRTC_OUT on TOP: 141.35,135.84 141.99,135.84 142.11,135.72 142.11,133.18 141.61,132.67 140.84,132.67 140.21,133.3 140.21,134.7
VRTC_OUT on BOTTOM: 91.69,101.47 91.69,104.77 106.25,119.33 109.81,119.33 113.03,122.55 119.89,122.55 122.05,124.71 122.05,137.37 126.36,141.69 137.99,141.69 141.73,137.95 141.73,134.19 141.48,133.94 140.76,133.94 139.83,134.87 139.83,136.48 138.94,137.37 132.21,137.37 131.58,136.73 126.24,136.73 125.48,135.97 125.48,121.92 122.05,118.49 115.32,118.49 112.6,115.78 106.43,115.78 99.95,109.3 99.95,101.55 96.24,97.85 94.56,97.85 94.36,98.04 94.36,98.81
VRTC_OUT on L9_SIG3: 144.22,142.47 147.8,142.47 148.41,141.86 148.41,141.17 148.11,140.87 146.89,140.87 142.62,136.6 142.62,132.41 140.94,130.73 139.88,130.73 139.5,131.11 139.5,137.74
VSDMMC on BOTTOM: 86.89,149.18 87.86,149.18 88.06,148.98 88.06,146.44 88.8,145.7 92.76,145.7 93.32,146.26 93.32,149.48 93.62,149.79 94.97,149.79 95.38,149.38 95.38,146.74 95,146.35 95,143.92 95.49,143.42 98.01,143.42 100.15,141.27 100.15,139.58 98.83,138.26 95.8,138.26 90.98,143.08 88.7,143.08 86.61,145.17 86.61,148.9
VSDMMC on BOTTOM: 113.66,123.7 113.66,126.75 112.14,128.27 112.14,131.7 111.76,132.08 109.98,132.08 109.73,131.83 109.73,128.14 111.89,125.98 111.89,123.7 112.27,123.32 113.28,123.32
VSDMMC on BOTTOM: 96.65,87.58 97.33,87.58 97.66,87.25 97.66,87.06 97.47,86.87 96.38,86.87 94.49,88.76 94.49,92.92 94.74,93.17 95.76,93.17 96.01,92.92 96.01,88.22
VSDMMC on L4_SIG2: 84.58,109.56 85.72,109.56 86.61,108.67 86.61,103.84 95.76,94.7 95.76,91.65 94.36,90.25 92.96,90.25 90.8,92.41 90.8,94.95 90.02,95.74 85.83,95.74 82.01,99.55 82.01,106.99
VSDMMC on L10_SIG4: 109.73,132.72 111.25,132.72 111.89,132.08 111.89,130.81 111.51,130.43 110.49,130.43 109.47,131.44 109.47,132.46
VSDMMC on L10_SIG4: 92.94,92.77 95.38,92.77 95.66,92.49 95.66,89.67 95.35,89.36 92.96,89.36 92.71,89.62 92.71,92.54
VSMPS1_2 on TOP: 151.77,126.95 151.77,134.07 152.27,134.57 153.54,134.57 154.56,133.56 154.56,127.46 153.92,126.83 151.89,126.83
VSMPS1_2 on TOP: 113.16,134.6 116.31,134.6 116.71,134.19 116.71,130.76 116.15,130.21 114.83,130.21 113.03,132.01 113.03,134.47
VSMPS1_2 on BOTTOM: 151.64,133.81 152.4,134.57 154.18,134.57 154.69,134.07 154.69,126.95 154.31,126.57 152.02,126.57 151.64,126.95
VSMPS1_2 on L8_GND3: 153.04,125.56 152.78,125.3 147.49,125.3 146.69,126.11 146.69,128.27 145.67,129.29 144.35,129.29 142.24,131.4 138.43,131.4 130.18,123.14 111.38,123.14 111.12,123.4 111.12,133.94 112.39,135.21 129.54,135.21 137.41,143.08 149.48,143.08 153.04,139.53
VSMPS1_SW on TOP: 145.03,128.61 145.03,130.13 147.7,132.8 147.7,134.19 147.83,134.32 150.88,134.32 151.13,134.07 151.13,132.03 149.61,130.51 149.1,130.51 147.96,129.37 147.96,129.11 146.49,127.65 144.71,127.65 144.65,127.72 144.65,128.25 144.65,128.26 144.65,128.31 144.76,128.41 144.84,128.41
VSMPS2_SW on TOP: 145.03,127.21 146.69,127.21 148.34,128.86 148.34,129.11 148.59,129.37 150.88,129.37 151.26,128.99 151.26,126.07 151,125.81 145.16,125.81 144.7,126.28 144.7,126.87
VSMPS3 on TOP: 151.89,124.92 154.94,124.92 155.45,124.41 155.45,119.72 155.19,119.46 151.77,119.46 151.38,119.84 151.38,124.41
VSMPS3_SW on TOP: 150.88,124.92 150.37,125.43 145.92,125.43 145.29,124.8 145.29,124.03 145.92,123.4 147.57,123.4 149.1,121.87 150.5,121.87 150.88,122.26
VSMPS4_5 on TOP: 120.4,130.92 121.13,131.65 121.13,134.47 121.36,134.7 124,134.7 124.31,134.4 124.31,132.16 126.59,129.88 130.3,129.88 130.43,129.75 130.43,129.62 130.56,129.49 130.56,127.43 130.31,127.19 126.09,127.19 125.09,126.19 125.09,122.38 126.36,121.11 130.3,121.11 130.81,120.6 130.81,119.21 130.43,118.83 129.54,118.83 128.02,117.3 121.79,117.3 120.4,118.7
VSMPS4_5 on BOTTOM: 127.25,121.09 130.3,121.09 130.56,120.83 130.56,119.06 130.3,118.8 127.51,118.8 127.13,119.18 127.13,120.96
VSMPS4_5 on BOTTOM: 127.25,130 130.3,130 130.56,129.75 130.56,127.31 130.26,127.01 127.74,127.01 127.13,127.63 127.13,129.88
VSMPS4_SW on TOP: 127.43,126.8 130.47,126.8 131.63,127.97 133.22,127.97 133.6,127.59 133.6,126.18 133.22,125.8 132.06,125.8 130.79,124.53 127.4,124.53 127.19,124.74 127.19,126.57
VSMPS5_SW on TOP: 133.22,125.4 132.06,125.4 130.73,124.08 127.32,124.08 127.32,124.07 127.27,124.07 127.08,123.89 127.08,121.66 127.38,121.37 131.67,121.37 133.27,122.96 133.27,125.36
VSMPS6_SW on TOP: 133.6,116.42 133.57,116.4 133.57,115.43 133.99,115.02 136.91,115.02 138.03,116.14 138.03,120.37 138.03,120.62 137.82,120.83 137.67,120.68 137.67,119.94 136.81,119.08 134.11,119.08 133.6,118.56
VSMPS7 on TOP: 105.79,134.7 107.52,134.7 107.65,134.57 107.65,131.7 107.34,131.4 105.92,131.4 105.54,131.78 105.54,134.45
VSMPS7 on TOP: 127.06,136.13 129.96,136.13 130.51,135.58 130.51,133.91 130.35,133.74 126.88,133.74 126.67,133.96 126.67,135.74
VSMPS7 on BOTTOM: 127.13,134.07 127.13,135.84 127.51,136.23 130.18,136.23 130.68,135.72 130.68,134.19 130.35,133.86 127.33,133.86
VSMPS7 on L7_PWR2: 130.81,138.51 130.81,133.81 127.64,130.64 116.08,130.64 114.68,129.24 114.68,126.7 114.17,126.19 105.79,126.19 103.38,128.61 103.38,138.26 105.16,140.04 129.29,140.04
VSMPS7_SW on TOP: 127.47,132.59 130.3,132.59 130.3,132.54 133.99,128.86 134.9,128.86 134.87,128.84 136.22,128.84 136.33,128.73 136.33,128.22 136.23,128.13 136.11,128.13 135.98,128.26 135.72,128.26 135.67,128.21 135.59,128.13 134.24,128.13 134.04,128.34 132.22,128.34 130.18,130.38 127.25,130.38 127.12,130.51 127.12,132.24
VSMPS8_SW on TOP: 142.49,120.1 143,119.59 144.78,119.59 146.69,117.68 146.69,115.65 146.3,115.27 143.13,115.27 142.75,115.65 142.75,118.06 141.99,118.83 141.99,119.97 142.11,120.1
VSMPS9 on TOP: 138.81,113.62 141.1,113.62 142.09,112.63 142.09,111.05 141.61,110.57 138.56,110.57 138.18,110.95 138.18,112.98
VSMPS9 on BOTTOM: 139.34,125.7 139.57,125.93 140.72,125.93 140.97,125.68 140.97,124.41 140.84,124.29 138.18,124.29 137.92,124.03 137.92,123.14 136.27,123.14 136.14,123.27 136.14,125.3 136.54,125.7
VSMPS9 on L4_SIG2: 143.09,125.17 143.09,112.22 141.2,110.34 139.01,110.34 138.32,111.02 138.32,114.14 138.35,114.17 138.35,118.04 137.34,119.05 137.34,126.01 138.43,127.11 141.15,127.11
VSMPS9 on L10_SIG4: 137.67,126.32 141.22,126.32 141.61,125.94 141.61,124.41 141.35,124.16 137.67,124.16 137.54,124.29 137.54,126.19
VSMPS9_SW on TOP: 139.32,119.97 139.45,119.97 139.53,119.88 139.53,119.34 140.55,118.32 141.86,118.32 142.11,118.06 142.11,115.52 141.73,115.14 138.68,115.14 138.43,115.4 138.43,118.83 139.19,119.59 139.19,119.84
VUSB_FTDI on TOP: 163.12,92.08 165.66,92.08 166.04,91.7 166.04,90.81 165.4,90.17 163.25,90.17 162.86,90.56 162.86,91.83
VUSB_FTDI on TOP: 178.62,16.85 178.97,17.2 179.78,17.2 180.14,16.84 180.14,15.88 179.91,15.65 175.01,15.65 174.75,15.9 174.75,16.59 175.01,16.85
VUSB_FTDI on L8_GND3: 178.05,57.97 178.05,89.03 174.29,92.79 164.97,92.79 164.06,91.88 164.06,90.61 164.74,89.92 169.49,89.92 173.66,85.75 173.66,61.86 170.94,59.14 170.97,59.14 168.66,56.82 168.66,19.51 172.54,15.63 176.12,15.63 179.2,18.7 179.2,56.82
VUSB_JTAG on TOP: 182.12,16.9 182.3,16.72 183.15,16.72 183.36,16.51 183.36,15.49 183.01,15.14 181.27,15.14 180.64,15.77 180.64,17.93 180.88,18.17 181.89,18.17 182.12,17.94
VUSB_VBUS1 on BOTTOM: 25.27,13.34 25.27,10.29 25.53,10.03 29.21,10.03 29.59,10.41 29.59,13.08 28.83,13.84 25.78,13.84
VUSB_VBUS1 on BOTTOM: 33.02,6.35 33.99,6.35 35.13,7.49 37.82,7.49 38.28,7.04 38.28,2.21 37.46,1.4 33.15,1.4 32.51,2.03 32.51,5.84
VUSB_VBUS1 on L10_SIG4: 29.66,20.24 43.42,20.24 44.49,19.17 44.49,4.28 42.32,2.11 31.35,2.11 25.35,8.11 25.35,15.93
